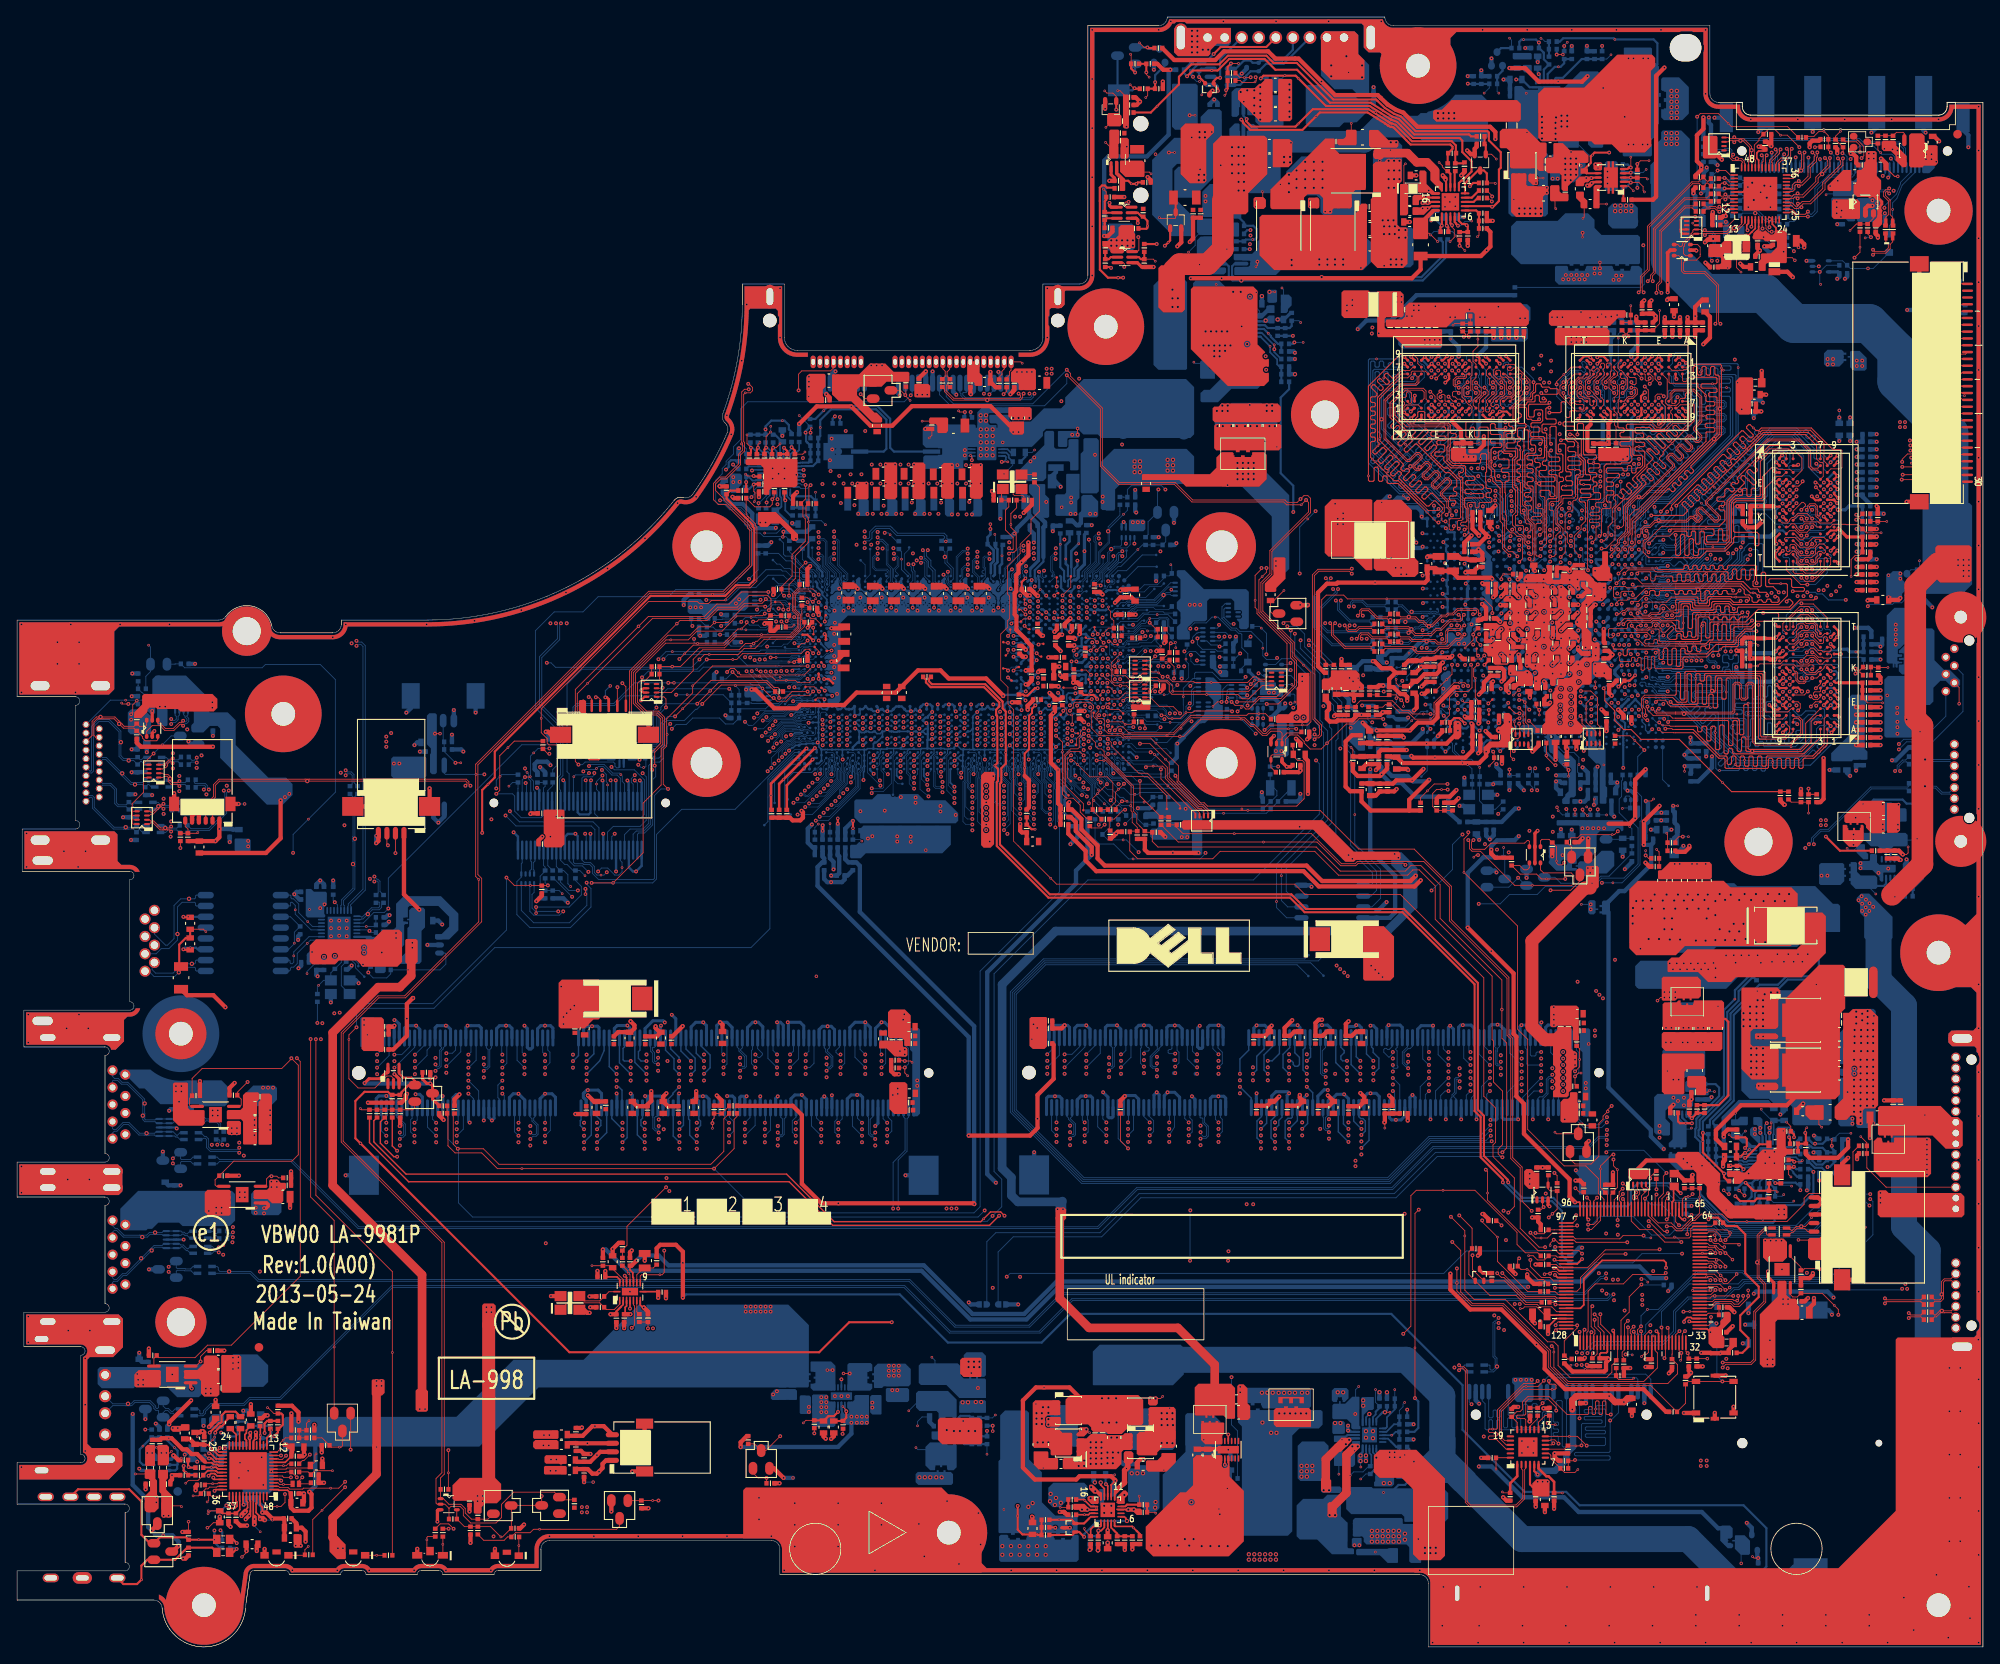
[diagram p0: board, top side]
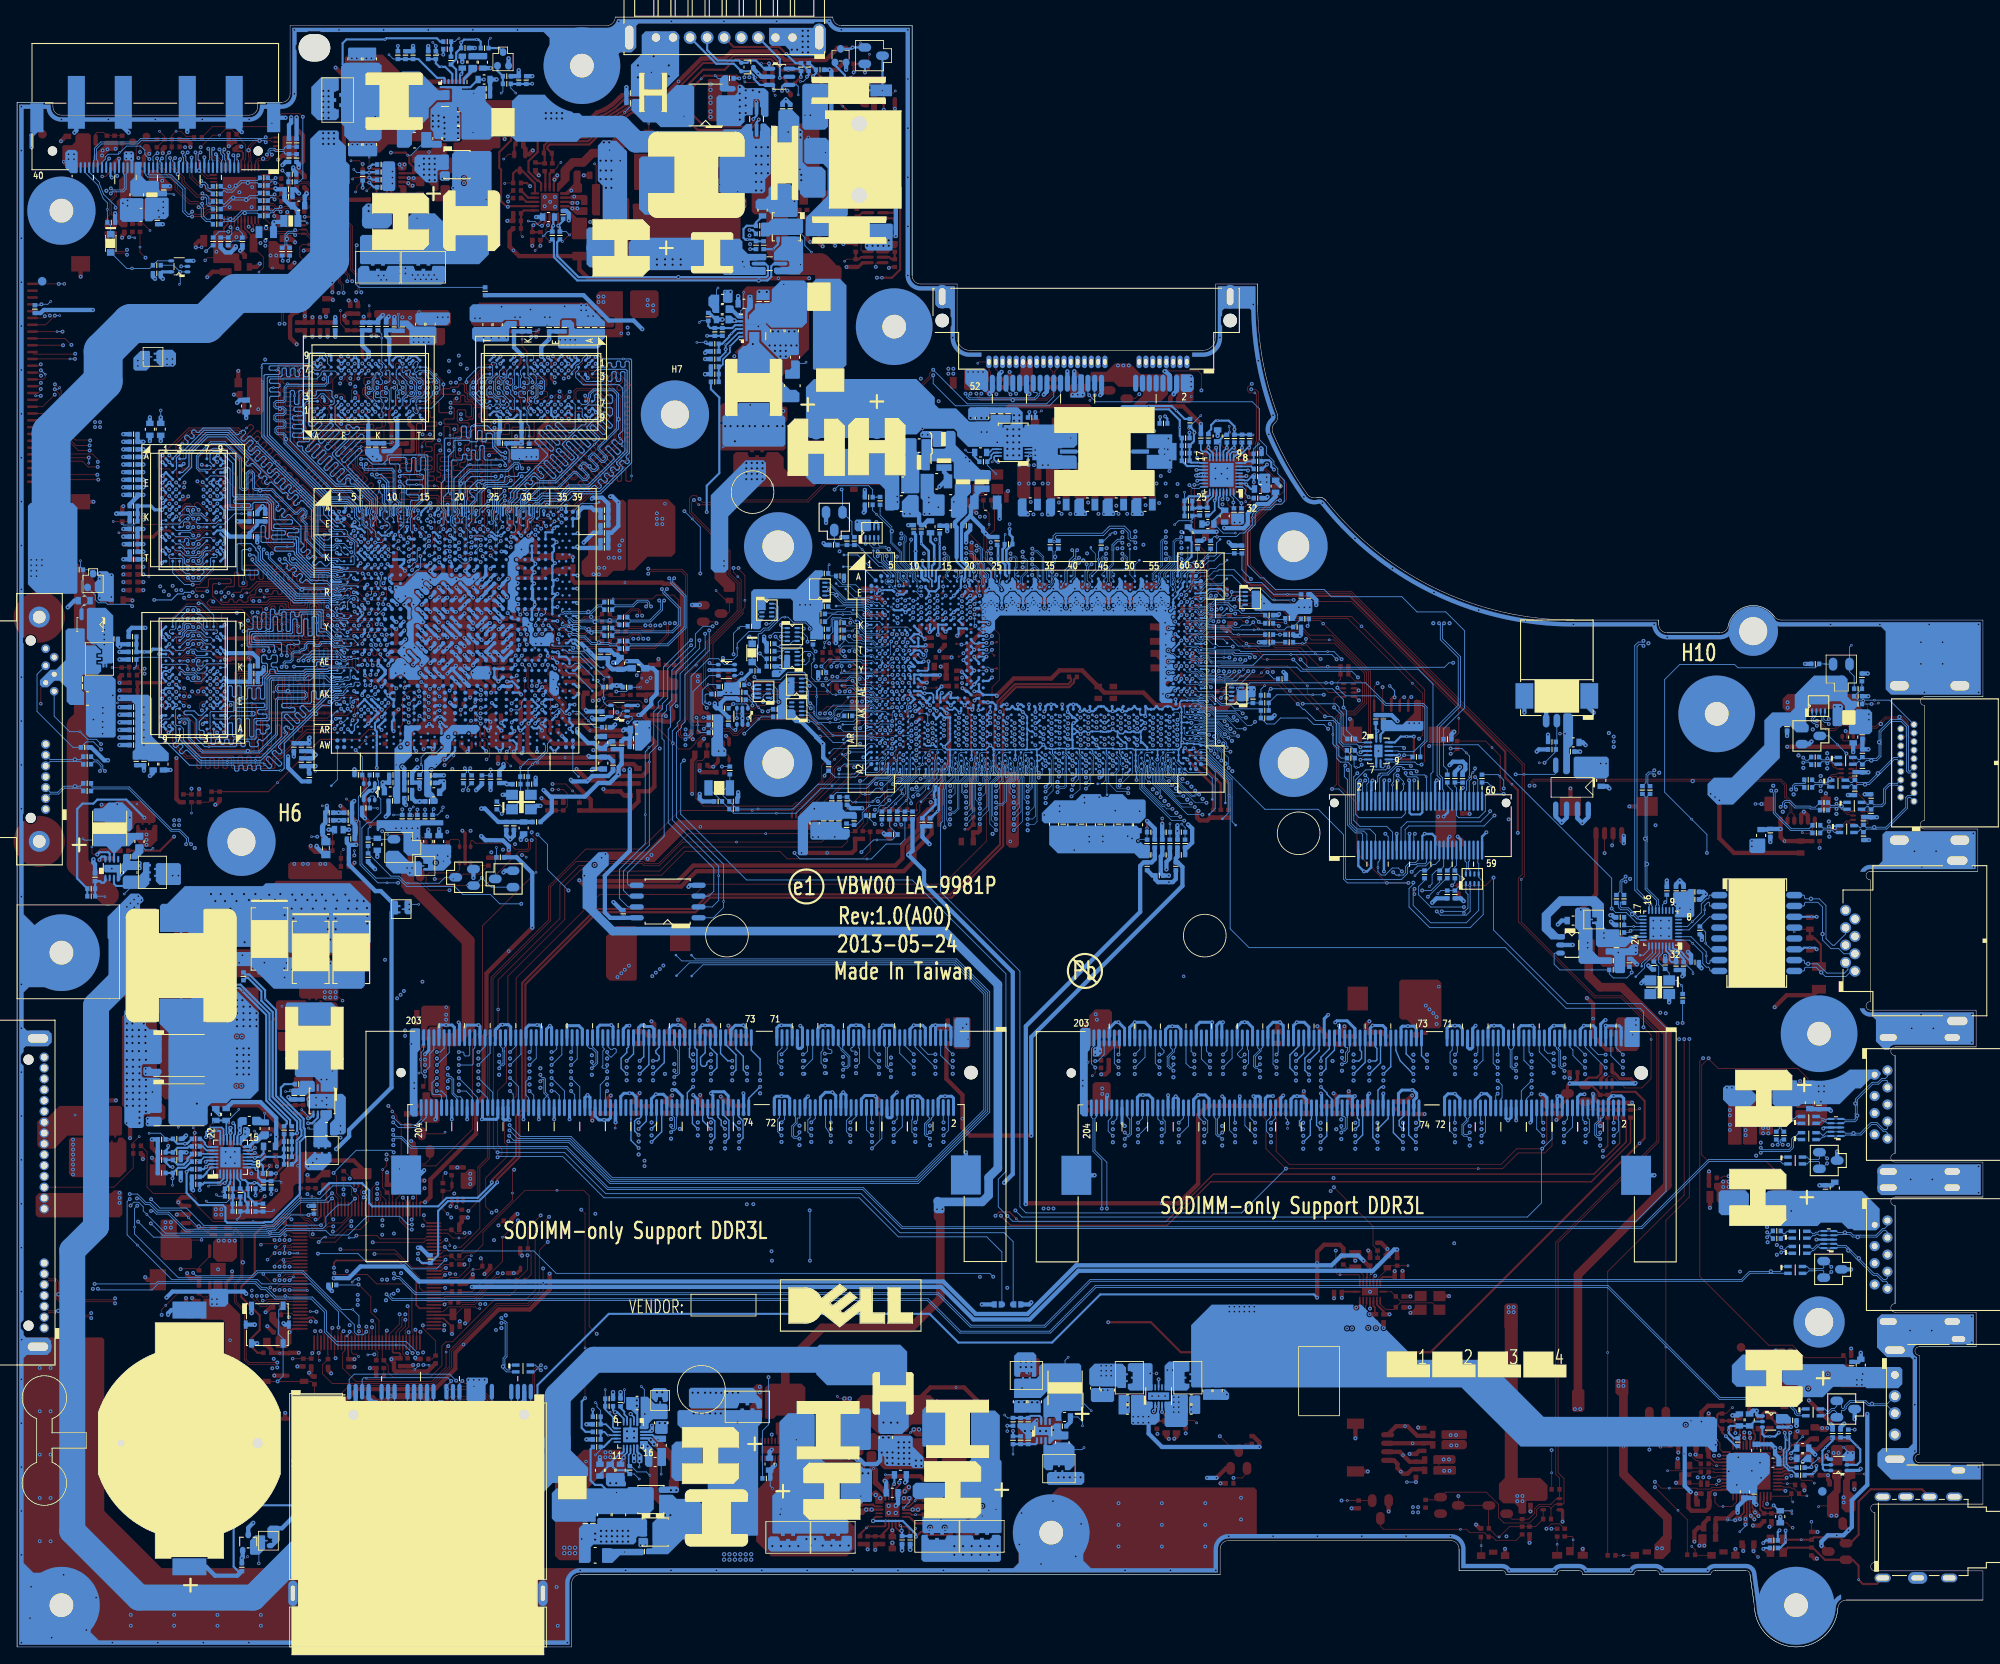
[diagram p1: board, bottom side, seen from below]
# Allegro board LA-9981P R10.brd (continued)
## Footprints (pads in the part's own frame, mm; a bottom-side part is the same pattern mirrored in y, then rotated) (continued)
LED_12-21C-T3D-CM2P1B18X-2C_3P
  rect 0.991x0.787 smd: 1(0,0) 2(-2.8,0)
  rect 0.991x0.61 smd: 3(-1.4,0.4)
LED_HT-210UD5-BP5_3P
  rect 1.194x0.787 smd: 1(0,0) 2(3,0)
  rect 0.889x0.991 smd: 3(1.5,0.5)
LOTES_AAA-BAT-054-K01_2P
  round 0.787 hole 0.787 unplated: (-14.5,-8)
  round 1.194 hole 1.194 unplated: (-14.5,8)
  rect 2.007x3.988 smd: 1(0,0) 2(-30.1,0)
LOTES_ABA-HDM-022-K01_19P
  round 0.813 hole 0.559: 1(0,0) 2(-0.5,-1.55) 3(-1,0) 4(-1.5,-1.55) 5(-2,0) 6(-2.5,-1.55) 7(-3,0) 8(-3.5,-1.55) 9(-4,0) 10(-4.5,-1.55) 11(-5,0) 12(-5.5,-1.55) 13(-6,0) 14(-6.5,-1.55) 15(-7,0) 16(-7.5,-1.55) 17(-8,0) 18(-8.5,-1.55) 19(-9,0)
  oval 1.702x2.794 hole 1.092x2.21: 20(4.55,5.38) 21(4.55,-1.72) 22(-13.55,-1.72) 23(-13.55,5.38)
MAG_MMD-12CE-R36M-M1L_2P
  rect 2.946x4.953 smd: 1(0,0) 2(10.815,0)
MC74VHC1G08DFT2G_SC70-5
  oval 0.381x0.711 smd: 1(0,0) 2(0.65,0) 3(1.3,0) 4(1.3,1.9) 5(0,1.9)
MDU1511RH_POWERDFN56-8-5
  oval 0.61x1.27 smd: 1(0,0) 2(1.27,0) 3(2.54,0) 4(3.81,0)
  custom 1.105x1.105 smd: 5(1.905,3.715)
MDU1516URH_POWERDFN56-8-5
  oval 0.61x1.27 smd: 1(0,0) 2(1.27,0) 3(2.54,0) 4(3.81,0)
  custom 1.105x1.105 smd: 5(1.905,3.715)
MMBT3904_NL_SOT23-3
  oval 1.016x1.524 smd: 1(0,0) 2(0.965,2.083) 3(-0.965,2.083)
MURAT_BLM15BB221SN1D_2P
  rect 0.508x0.762 smd: 1(0,0) 2(0.75,0)
MURAT_DLW21SN670HQ2L_4P
  rect 0.889x0.406 smd: 1(0,0) 2(1.7,0) 3(1.7,0.8) 4(0,0.8)
MURAT_LQM2MPN2R2NG0L_2P
  rect 0.787x1.803 smd: 1(0,0) 2(1.6,0)
PANAS_ETQP3W2R2WFN_2P
  rect 2.159x3.505 smd: 1(0,0) 2(-5.85,0)
PS_HPF10052-06M000R_6P
  oval 0.305x1.499 smd: 1(0,0) 2(1,0) 3(2,0) 4(3,0) 5(4,0) 6(5,0)
  rect 2.489x1.905 smd: 7(7.65,-3.4) 8(-2.65,-3.4)
R0402_0OHM
  rect 0.508x0.559 smd: 1(0,0) 2(0.914,0)
R0603_0OHM
  rect 0.635x0.889 smd: 1(0,0) 2(1.397,0)
R0805_0OHM
  rect 0.813x1.397 smd: 1(0,0) 2(1.702,0)
R_0402
  rect 0.508x0.559 smd: 1(0,0) 2(0.914,0)
R_0603
  rect 0.635x0.889 smd: 1(0,0) 2(1.397,0)
R_0805
  rect 0.813x1.397 smd: 1(0,0) 2(1.702,0)
R_1206
  rect 1.016x1.651 smd: 1(0,0) 2(2.667,0)
R_1206_4P-D
  custom 0.445x0.445 smd: 1(0,0) 4(5.004,0)
  custom 0.114x0.114 smd: 2(1.194,0) 3(3.81,0)
RB751V-40_SOD323-2
  rect 0.787x0.889 smd: 1(0,0) 2(2.14,0)
RHU002N06_SOT323-3
  oval 0.813x0.914 smd: 1(0,0) 2(0.65,1.6) 3(-0.65,1.6)
RP_0804_8P4R
  oval 0.66x0.254 smd: 1(0,0) 2(0,-0.5) 3(0,-1) 4(0,-1.5) 5(1.15,-1.5) 6(1.15,-1) 7(1.15,-0.5) 8(1.15,0)
RT8207MZQW_WQFN20_3X3
  oval 0.203x0.889 smd: 1(0,0) 2(0.4,0) 3(0.8,0) 4(1.2,0) 5(1.6,0) 11(1.6,3.1) 12(1.2,3.1) 13(0.8,3.1) 14(0.4,3.1) 15(0,3.1)
  oval 0.889x0.203 smd: 6(2.35,0.75) 7(2.35,1.15) 8(2.35,1.55) 9(2.35,1.95) 10(2.35,2.35) 16(-0.75,2.35) 17(-0.75,1.95) 18(-0.75,1.55) 19(-0.75,1.15) 20(-0.75,0.75)
  rect 1.702x1.702 smd: 21(0.8,1.55)
RTD2136R-CG_QFN48_6X6
  oval 0.203x0.889 smd: 1(0,0) 2(0.4,0) 3(0.8,0) 4(1.2,0) 5(1.6,0) 6(2,0) 7(2.4,0) 8(2.8,0) 9(3.2,0) 10(3.6,0) 11(4,0) 12(4.4,0) 25(4.4,6.1) 26(4,6.1) 27(3.6,6.1) 28(3.2,6.1) 29(2.8,6.1) 30(2.4,6.1) 31(2,6.1) 32(1.6,6.1) 33(1.2,6.1) 34(0.8,6.1) 35(0.4,6.1) 36(0,6.1)
  oval 0.889x0.203 smd: 13(5.25,0.85) 14(5.25,1.25) 15(5.25,1.65) 16(5.25,2.05) 17(5.25,2.45) 18(5.25,2.85) 19(5.25,3.25) 20(5.25,3.65) 21(5.25,4.05) 22(5.25,4.45) 23(5.25,4.85) 24(5.25,5.25) 37(-0.85,5.25) 38(-0.85,4.85) 39(-0.85,4.45) 40(-0.85,4.05) 41(-0.85,3.65) 42(-0.85,3.25) 43(-0.85,2.85) 44(-0.85,2.45) 45(-0.85,2.05) 46(-0.85,1.65) 47(-0.85,1.25) 48(-0.85,0.85)
  rect 3.962x3.962 smd: 49(2.2,3.05)
RTL8106E-CG_QFN32_4X4
  oval 0.203x0.838 smd: 1(0,0) 2(0.4,0) 3(0.8,0) 4(1.2,0) 5(1.6,0) 6(2,0) 7(2.4,0) 8(2.8,0) 17(2.8,4.15) 18(2.4,4.15) 19(2,4.15) 20(1.6,4.15) 21(1.2,4.15) 22(0.8,4.15) 23(0.4,4.15) 24(0,4.15)
  oval 0.838x0.203 smd: 9(3.475,0.675) 10(3.475,1.075) 11(3.475,1.475) 12(3.475,1.875) 13(3.475,2.275) 14(3.475,2.675) 15(3.475,3.075) 16(3.475,3.475) 25(-0.675,3.475) 26(-0.675,3.075) 27(-0.675,2.675) 28(-0.675,2.275) 29(-0.675,1.875) 30(-0.675,1.475) 31(-0.675,1.075) 32(-0.675,0.675)
  rect 2.692x2.692 smd: 33(1.4,2.075)
RTS5179-GR_QFN24_4X4
  oval 0.254x0.889 smd: 1(0,0) 2(0.5,0) 3(1,0) 4(1.5,0) 5(2,0) 6(2.5,0) 13(2.5,4.1) 14(2,4.1) 15(1.5,4.1) 16(1,4.1) 17(0.5,4.1) 18(0,4.1)
  oval 0.889x0.254 smd: 7(3.3,0.8) 8(3.3,1.3) 9(3.3,1.8) 10(3.3,2.3) 11(3.3,2.8) 12(3.3,3.3) 19(-0.8,3.3) 20(-0.8,2.8) 21(-0.8,2.3) 22(-0.8,1.8) 23(-0.8,1.3) 24(-0.8,0.8)
  rect 2.261x2.261 smd: 25(1.25,2.05)
SAMTE_BSH-030-01-L-D-A_60P
  round 1.016 hole 1.016 unplated: (-2.81,5.53) (17.316,5.53)
  oval 0.279x2.261 smd: 1(0,0) 2(0,5.728) 3(0.5,0) 4(0.5,5.728) 5(1,0) 6(1,5.728) 7(1.5,0) 8(1.5,5.728) 9(2,0) 10(2,5.728) 11(2.5,0) 12(2.5,5.728) 13(3,0) 14(3,5.728) 15(3.5,0) 16(3.5,5.728) 17(4,0) 18(4,5.728) 19(4.5,0) 20(4.5,5.728) 21(5,0) 22(5,5.728) 23(5.5,0) 24(5.5,5.728) 25(6,0) 26(6,5.728) 27(6.5,0) 28(6.5,5.728) 29(7,0) 30(7,5.728) 31(7.5,0) 32(7.5,5.728) 33(8,0) 34(8,5.728) 35(8.5,0) 36(8.5,5.728) 37(9,0) 38(9,5.728) 39(9.5,0) 40(9.5,5.728) 41(10,0) 42(10,5.728) 43(10.5,0) 44(10.5,5.728) 45(11,0) 46(11,5.728) 47(11.5,0) 48(11.5,5.728) 49(12,0) 50(12,5.728) 51(12.5,0) 52(12.5,5.728) 53(13,0) 54(13,5.728) 55(13.5,0) 56(13.5,5.728) 57(14,0) 58(14,5.728) 59(14.5,0) 60(14.5,5.728)
SANTA_130456-311_8P
  round 1.295 hole 0.889: 1(0,0) 2(1.02,1.1) 3(2.04,0) 4(3.06,1.1) 5(4.08,0) 6(5.1,1.1) 7(6.12,0) 8(7.14,1.1)
  oval 1.753x3.15 hole 0.991x2.388: 9(-5.83,-12) 10(12.97,-12)
SANTA_193202-1_22P
  round 1.194 hole 1.194 unplated: (-31.47,-1.84) (-0.28,-1.84)
  round 1.092 hole 0.787: 1(0,0) 2(-1.27,0) 3(-2.54,0) 4(-3.81,0) 5(-5.08,0) 6(-6.35,0) 7(-7.62,0) 8(-13.97,0) 9(-15.24,0) 10(-16.51,0) 11(-17.78,0) 12(-19.05,0) 13(-20.32,0) 14(-21.59,0) 15(-22.86,0) 16(-24.13,0) 17(-25.4,0) 18(-26.67,0) 19(-27.94,0) 20(-29.21,0) 21(-30.48,0) 22(-31.75,0)
  oval 1.803x3.2 hole 0.991x2.388: 23(2.2,-0.73) 24(-33.95,-0.73)
SANTA_202801-1_13P
  round 1.194 hole 1.194 unplated: (-19.78,-1.75) (1.02,-1.75)
  round 1.067 hole 0.711: 1(0,0) 2(-1.27,0) 3(-2.54,0) 4(-3.81,0) 5(-5.08,0) 6(-6.35,0) 7(-7.62,0)
  round 1.016 hole 0.61: 8(-13.83,1) 9(-14.83,0) 10(-15.83,1) 11(-16.83,0) 12(-17.83,1) 13(-18.83,0)
  custom 1.499x1.499 hole 2.311: 14(3.77,-0.75) 15(-22.53,-0.75)
SHORTPADS
  custom 0.19x0.19 smd: 1(-0.483,0) 2(0.483,0)
SI3456BDV-T1-E3_TSOP6
  oval 0.508x1.448 smd: 1(0,0) 2(1,0) 3(2,0) 4(2,2.425) 5(1,2.425) 6(0,2.425)
SI3457CDV-T1-GE3_TSOP6
  oval 0.508x1.422 smd: 1(0,0) 2(0.95,0) 3(1.9,0) 4(1.9,2.44) 5(0.95,2.44) 6(0,2.44)
SINGA_2SJ3080-000111F_6P-T
  oval 1.016x1.905 hole 0.61x1.499: 1(0,0) 2(-9.51,5.49) 3(0,7.8) 4(-9.51,8.39) 5(-9.51,0) 6(-9.51,2.74)
  oval 1.372x2.261 hole 0.61x1.499: 7(0,4.1)
SIR472DP-T1-GE3_POWERPAK8-5
  oval 0.61x1.27 smd: 1(0,0) 2(1.27,0) 3(2.54,0) 4(3.81,0)
  custom 1.105x1.105 smd: 5(1.905,3.36)
SIR818DP-T1_POWERPAK-SO8-5
  oval 0.61x1.27 smd: 1(0,0) 2(1.27,0) 3(2.54,0) 4(3.81,0)
  custom 1.105x1.105 smd: 5(1.905,3.715)
SIS412DN-T1-GE3_POWERPAK8-5
  oval 0.406x0.991 smd: 1(0,0) 2(0.66,0) 3(1.32,0) 4(1.98,0)
  custom 0.559x0.559 smd: 5(0.99,2.247)
SLG3NB274VTR_TQFN16_2X3
  oval 0.203x0.914 smd: 1(0,-0.013) 2(0.4,-0.013) 3(0.8,-0.013) 4(1.2,-0.013) 5(1.6,-0.013) 6(2,-0.013) 7(2.4,-0.013) 9(2.4,2.063) 10(2,2.063) 11(1.6,2.063) 12(1.2,2.063) 13(0.8,2.063) 14(0.4,2.063) 15(0,2.063)
  oval 0.914x0.203 smd: 8(2.738,1.025) 16(-0.338,1.025)
  rect 1.905x0.889 smd: 17(1.2,1.025)
SN74LVC1G06DCKR_SC70-5
  oval 0.381x0.864 smd: 1(0,0) 2(0.65,0) 3(1.3,0) 4(1.3,1.74) 5(0,1.74)
SSM3K7002FU_SC70-3
  oval 0.508x0.991 smd: 1(0,0) 2(0.65,1.9) 3(-0.65,1.9)
STARC_107K40-000001-G2_40P
  round 1.092 hole 1.092 unplated: (-2.3,-1.95) (21.8,-1.95)
  oval 0.254x1.295 smd: 1(0,0) 2(0.5,0) 3(1,0) 4(1.5,0) 5(2,0) 6(2.5,0) 7(3,0) 8(3.5,0) 9(4,0) 10(4.5,0) 11(5,0) 12(5.5,0) 13(6,0) 14(6.5,0) 15(7,0) 16(7.5,0) 17(8,0) 18(8.5,0) 19(9,0) 20(9.5,0) 21(10,0) 22(10.5,0) 23(11,0) 24(11.5,0) 25(12,0) 26(12.5,0) 27(13,0) 28(13.5,0) 29(14,0) 30(14.5,0) 31(15,0) 32(15.5,0) 33(16,0) 34(16.5,0) 35(17,0) 36(17.5,0) 37(18,0) 38(18.5,0) 39(19,0) 40(19.5,0)
  rect 1.549x3.404 smd: 41(-4.125,-5.85) 42(23.625,-5.85)
  rect 2.007x6.198 smd: 43(0.5,-7.65) 44(6,-7.65) 45(13.5,-7.65) 46(19,-7.65)
SUYIN_200028MR009G502ZL_9P
  round 1.499 hole 0.991: 1(0,0) 2(2,0) 3(4,0) 4(6,0) 5(8,0) 6(10,0) 7(12,0) 8(14,0) 9(16,0)
  oval 1.499x3.302 hole 0.991x2.794: 10(19.125,0) 11(-3.125,0)
SW_SMT1-05-A_4P
  rect 0.61x0.991 smd: 1(0,0) 2(0,-4.4) 3(3.7,0) 4(3.7,-4.4)
  rect 0.457x0.991 smd: 5(-0.675,-2.2) 6(4.375,-2.2)
SY8003DFC_DFN8_2X2
  oval 0.254x0.787 smd: 1(0,0) 2(0.5,0) 3(1,0) 4(1.5,0) 5(1.5,2.2) 6(1,2.2) 7(0.5,2.2) 8(0,2.2)
  rect 1.549x0.838 smd: 9(0.75,1.1)
SY8036DBC_DFN10_3X3
  oval 0.254x0.889 smd: 1(0,0) 2(0.5,0) 3(1,0) 4(1.5,0) 5(2,0) 6(2,3.1) 7(1.5,3.1) 8(1,3.1) 9(0.5,3.1) 10(0,3.1)
  rect 2.388x1.575 smd: 11(1,1.55)
SY8206DQNC_QFN10_3X3
  oval 0.254x0.61 smd: 1(0,0) 2(0.45,0) 3(0.9,0) 4(1.35,0) 5(1.8,0) 6(2.25,0)
  rect 1.168x0.254 smd: 7(2.19,-0.675)
  rect 0.914x2.007 smd: 8(2.065,-2)
  custom 0.482x0.482 smd: 9(1.077,-1.775)
  rect 0.813x1.168 smd: 10(0.137,-1.587)
T-SOL_143-2300302602_22P_RV
  round 1.194 hole 1.194 unplated: (0.5,-2.69) (20.5,-2.69)
  oval 0.508x1.854 smd: 1(0,0) 2(0.76,0) 3(1.52,0) 4(2.28,0) 5(3.8,0) 6(4.56,0) 7(5.32,0) 8(6.84,0) 9(7.6,0) 10(8.36,0) 11(9.12,0) 12(9.88,0) 13(11.4,0) 14(12.16,0) 15(12.92,0) 16(14.44,0) 17(15.2,0) 18(16.72,0) 19(19,0) 20(19.76,0) 21(20.52,0) 22(21.28,0)
  oval 1.092x2.997 hole 0.508x1.803: 23(-6.6,-23.63) 24(22.7,-23.63)
TAI-T_HCB2012KF-121T50_2P
  rect 0.991x0.991 smd: 1(0,0) 2(2,0)
TAI-T_VMPI0703AR-1R0M-Z01_2P
  rect 2.362x3.505 smd: 1(0,0) 2(6.05,0)
TAIYO_NRS4018T1R0NDGJ_2P
  rect 1.194x3.708 smd: 1(0,0) 2(2.8,0)
TOKO_FDUE1040J-H-R36M-P3_4P
  custom 0.876x0.876 smd: 1(0,0) 4(13.411,0)
  rect 2.032x0.508 smd: 2(2.489,0) 3(10.922,0)
TOKO_FDVE1040-H-2R2M-P3_2P
  rect 3.81x3.988 smd: 1(0,0) 2(9.2,0)
TPC12
  round 0.305 smd: 1(0,0)
TPS22966DPUR_SON14_2X3
  oval 0.203x0.762 smd: 1(0,0) 2(0.4,0) 3(0.8,0) 4(1.2,0) 5(1.6,0) 6(2,0) 7(2.4,0) 8(2.4,2.05) 9(2,2.05) 10(1.6,2.05) 11(1.2,2.05) 12(0.8,2.05) 13(0.4,2.05) 14(0,2.05)
  rect 2.489x0.889 smd: 15(1.2,1.025)
TPS51212DSCR_SON10_3X3
  oval 0.279x0.838 smd: 1(0,0) 2(0.5,0) 3(1,0) 4(1.5,0) 5(2,0) 6(2,2.95) 7(1.5,2.95) 8(1,2.95) 9(0.5,2.95) 10(0,2.95)
  custom 0.412x0.412 smd: 11(1,1.475)
TPS51225CRUKR_QFN20_3X3
  oval 0.203x0.889 smd: 1(0,0) 2(0.4,0) 3(0.8,0) 4(1.2,0) 5(1.6,0) 11(1.6,3.1) 12(1.2,3.1) 13(0.8,3.1) 14(0.4,3.1) 15(0,3.1)
  oval 0.889x0.203 smd: 6(2.35,0.75) 7(2.35,1.15) 8(2.35,1.55) 9(2.35,1.95) 10(2.35,2.35) 16(-0.75,2.35) 17(-0.75,1.95) 18(-0.75,1.55) 19(-0.75,1.15) 20(-0.75,0.75)
  rect 1.702x1.702 smd: 21(0.8,1.55)
TPS51622RSM_QFN32_4X4
  oval 0.203x0.914 smd: 1(0,0) 2(0.4,0) 3(0.8,0) 4(1.2,0) 5(1.6,0) 6(2,0) 7(2.4,0) 8(2.8,0) 17(2.8,4.077) 18(2.4,4.077) 19(2,4.077) 20(1.6,4.077) 21(1.2,4.077) 22(0.8,4.077) 23(0.4,4.077) 24(0,4.077)
  oval 0.914x0.203 smd: 9(3.438,0.639) 10(3.438,1.039) 11(3.438,1.438) 12(3.438,1.838) 13(3.438,2.239) 14(3.438,2.639) 15(3.438,3.039) 16(3.438,3.438) 25(-0.639,3.438) 26(-0.639,3.039) 27(-0.639,2.639) 28(-0.639,2.239) 29(-0.639,1.838) 30(-0.639,1.438) 31(-0.639,1.039) 32(-0.639,0.639)
  rect 2.794x2.794 smd: 33(1.4,2.039)
TVNST52302AB0_SOT523-3
  oval 0.508x0.559 smd: 1(0,0) 2(-0.5,-1.4) 3(0.5,-1.4)
VISHAY_IHLP-2525CZ-01_2P
  rect 2.54x3.556 smd: 1(-2.857,0) 2(2.857,0)
W25Q64FVSSIG_SO8
  oval 0.635x1.676 smd: 1(0,0) 2(1.27,0) 3(2.54,0) 4(3.81,0) 5(3.81,7.25) 6(2.54,7.25) 7(1.27,7.25) 8(0,7.25)
Y_7V27000011_4P
  rect 1.397x1.194 smd: 1(0,0) 2(2.2,0) 3(2.2,1.7) 4(0,1.7)
Y_FSX3M-25PM20FDO_4P
  rect 1.397x1.194 smd: 1(0,0) 2(2.2,0) 3(2.2,1.6) 4(0,1.6)
Y_Q13FC1350000_2P
  rect 0.991x1.803 smd: 1(0,0) 2(2.5,0)
Y_X3G024000DC1H_4P
  rect 1.397x1.194 smd: 1(0,0) 2(2.2,0) 3(2.2,1.7) 4(0,1.7)

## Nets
0.675V_DDR_VTT_ON: PR202.1 QD2.2 R2347.2 R2351.2 U2303.4
1.35V_B+: PC201.1 PC206.1 PC208.1 PC212.1 PL201.2 PQ200.5 PR208.1
3/5V_B+: PC105.1 PC112.1 PC113.1 PC114.1 PC115.1 PL102.2 PQ101.5 PQ103.5 PU100.12
3V_EN: PD101.2 PR100.1 PU100.6
3VALW_PCH: J513.2 U2304.13 U2304.14
3VS: J511.2 U2301.8 U2301.9
3VS_GATE: C2322.1 R2318.2 U2301.5
5V_EN: PD101.3 PR101.1 PU100.20
5VS: J510.2 U2301.13 U2301.14
5VS_GATE: C2309.1 R2313.2 U2301.3
+0.675VS: CD24.1 CD25.1 CD26.1 CD27.1 CD28.1 CD29.1 CD54.1 CD55.1 CD56.1 CD57.1 CD58.1 CD59.1 JDIMM1.203 JDIMM1.204 JDIMM2.203 JDIMM2.204 PJP203.1 R2314.1
+0.675VSP: PC205.1 PC211.1 PJP203.2 PU200.2 PU200.20
+1.2VSP_B+: PC1100.1 PC1101.1 PC1102.1 PL1100.1 PQ1100.5
+1.05V_PGOOD: PR308.2 PU300.2 UE1.122
+1.05VS: C43.1 C44.1 C50.1 C53.1 C57.1 C60.1 C61.1 C62.1 C66.1 C67.1 C76.1 C87.1 C88.1 CC14.1 CC15.1 CC28.1 CG2.1 JXDP1.43 JXDP1.44 L1.1 L2.1 L3.1 L4.1 L5.1 PC512.1 PJP300.2 PR526.1 PR528.1 PR530.1 PR533.2 R252.1 R253.2 R256.1 R267.1 R286.1 R2315.1 R2346.1 RC58.1 RC60.1 RC130.2 RP44.5 RP44.6 RP44.7 RP44.8 RP45.8 RP48.1 RP48.2 RP48.3 UC1.AC22 UC1.AE8 UC1.AE9 UC1.AE22 UC1.AE23 UC1.AF9 UC1.AF22 UC1.AG8 UC1.AG13 UC1.AG14 UC1.AG16 UC1.AG17 UC1.H11 UC1.H15 UC1.J11 UC1.J17 UC1.K9 UC1.L10 UC1.M9 UC1.N8 UC1.P9 UC1.R21 UC1.T21 UG1.3
+1.5VS: JMINI.6 JMINI.28 JMINI.48 PJP401.2 RA8.1 RC129.1 UC1.J15
+1.05VS_APLLOPI: C69.1 C70.1 L3.2 R267.2 UC1.AA21 UC1.W21
+1.05VS_ASATA3PLL: C63.1 C65.1 L2.2 RC126.2 RC131.2 UC1.B11
+1.05VS_AUSB3PLL: C58.1 C59.1 L1.2 RC91.1 UC1.B18 UC1.B27
+1.05VS_AXCK_DCB: C83.1 C84.1 L4.2 UC1.J18 UC1.K19
+1.05VS_AXCK_LCPLL: C85.1 C86.1 L5.2 RC13.2 UC1.A20
+1.05VSP: PC307.1 PC308.1 PC309.1 PC310.1 PC311.1 PJP300.1 PL301.2 PR305.1
+1.5VSP: PC400.1 PC402.1 PC404.1 PJP401.1 PL400.2 PR403.1
+1.5VSP_ON: PC403.1 PR401.1 PR404.1 PU400.7
+1.8VGS: CG1.1 J9.1 LV12.2 LV13.2 LV14.2 LV16.1 LV17.1 LV18.1 LV19.1 LV20.1 LV21.1 LV22.1 RV93.2 RV118.2 RV119.1 RV124.1 RV237.1 RV239.1 RV241.1 RV243.1 UG1.11
+1.8VS: J9.2 PJP601.2
+1.8VSP: PC600.1 PC602.1 PC604.1 PJP601.1 PL600.2 PR603.1
+1.8VSP_ON: PC603.1 PR601.1 PR604.1 PU600.7
+1.35V: C35.1 C36.1 C37.1 C38.1 C39.1 C40.2 C41.1 C42.1 C43.2 C45.1 C72.1 C74.1 CD4.1 CD5.1 CD6.1 CD7.1 CD8.1 CD9.1 CD10.1 CD11.1 CD12.1 CD13.1 CD14.1 CD15.1 CD16.1 CD17.1 CD18.1 CD19.1 CD20.1 CD23.1 CD35.1 CD36.1 CD37.1 CD38.1 CD39.1 CD40.1 CD41.1 CD42.1 CD43.1 CD44.1 CD45.1 CD46.1 CD47.1 CD48.1 CD49.1 CD50.1 CD51.1 CD62.2 JDIMM1.75 JDIMM1.76 JDIMM1.81 JDIMM1.82 JDIMM1.87 JDIMM1.88 JDIMM1.93 JDIMM1.94 JDIMM1.99 JDIMM1.100 JDIMM1.105 JDIMM1.106 JDIMM1.111 JDIMM1.112 JDIMM1.117 JDIMM1.118 JDIMM1.123 JDIMM1.124 JDIMM2.75 JDIMM2.76 JDIMM2.81 JDIMM2.82 JDIMM2.87 JDIMM2.88 JDIMM2.93 JDIMM2.94 JDIMM2.99 JDIMM2.100 JDIMM2.105 JDIMM2.106 JDIMM2.111 JDIMM2.112 JDIMM2.117 JDIMM2.118 JDIMM2.123 JDIMM2.124 PJP200.2 PJP201.2 QD2.1 RC14.1 RC15.1 RC16.1 RD3.1 U2303.5 UC1.AH26 UC1.AJ31 UC1.AJ33 UC1.AJ37 UC1.AN33 UC1.AP43 UC1.AR48 UC1.AY35 UC1.AY40 UC1.AY44 UC1.AY50
+1.35V_MEM_GFX: CV135.1 CV136.1 CV137.1 CV138.1 CV139.1 CV140.1 CV141.1 CV142.1 CV143.1 CV144.1 CV145.1 CV152.1 CV153.1 CV154.1 CV155.1 CV156.1 CV235.1 CV236.1 CV237.1 CV238.1 CV239.1 CV240.1 CV241.1 CV242.1 CV243.1 CV244.1 CV245.1 CV246.1 CV247.1 CV248.1 CV249.1 CV250.1 CV251.1 CV252.1 CV253.1 CV254.1 CV255.1 CV256.1 CV257.1 CV258.1 CV259.1 CV260.1 CV261.1 CV262.1 CV263.1 CV264.1 CV265.1 CV266.1 CV267.1 CV268.1 CV269.1 CV270.1 CV271.1 CV282.1 CV283.1 CV284.1 CV285.1 CV286.1 CV287.1 CV288.1 CV289.1 CV290.1 CV291.1 CV292.1 CV293.1 CV294.1 CV295.1 CV296.1 CV297.1 CV298.1 CV299.1 CV300.1 CV301.1 CV302.1 CV303.1 CV304.1 CV305.1 CV306.1 CV307.1 CV308.1 CV310.1 CV311.1 CV312.1 CV313.1 CV314.1 CV315.1 CV316.1 CV317.1 CV318.1 JP9.1 RV138.1 RV139.1 RV140.1 RV141.1 RV142.1 RV156.1 RV157.1 RV158.1 RV159.1 RV160.1 RV161.1 RV162.1 RV163.1 RV182.1 RV183.1 RV184.1 RV185.1 RV186.1 RV187.1 RV188.1 RV189.1 UV1.AC7 UV1.AD11 UV1.AF7 UV1.AG10 UV1.AJ7 UV1.AK8 UV1.AL9 UV1.G11 UV1.G14 UV1.G17 UV1.G20 UV1.G23 UV1.G26 UV1.G29 UV1.H10 UV1.J7 UV1.J9 UV1.K8 UV1.K11 UV1.K13 UV1.L7 UV1.L12 UV1.L16 UV1.L21 UV1.L23 UV1.L26 UV1.M11 UV1.N11 UV1.P7 UV1.R11 UV1.U7 UV1.U11 UV1.Y7 UV1.Y11 UV18.A1 UV18.A8 UV18.B2 UV18.C1 UV18.C9 UV18.D2 UV18.D9 UV18.E9 UV18.F1 UV18.G7 UV18.H2 UV18.H9 UV18.K2 UV18.K8 UV18.N1 UV18.N9 UV18.R1 UV18.R9 UV19.A1 UV19.A8 UV19.B2 UV19.C1 UV19.C9 UV19.D2 UV19.D9 UV19.E9 UV19.F1 UV19.G7 UV19.H2 UV19.H9 UV19.K2 UV19.K8 UV19.N1 UV19.N9 UV19.R1 UV19.R9 UV20.A1 UV20.A8 UV20.B2 UV20.C1 UV20.C9 UV20.D2 UV20.D9 UV20.E9 UV20.F1 UV20.G7 UV20.H2 UV20.H9 UV20.K2 UV20.K8 UV20.N1 UV20.N9 UV20.R1 UV20.R9 UV21.A1 UV21.A8 UV21.B2 UV21.C1 UV21.C9 UV21.D2 UV21.D9 UV21.E9 UV21.F1 UV21.G7 UV21.H2 UV21.H9 UV21.K2 UV21.K8 UV21.N1 UV21.N9 UV21.R1 UV21.R9 UV22.A1 UV22.A8 UV22.B2 UV22.C1 UV22.C9 UV22.D2 UV22.D9 UV22.E9 UV22.F1 UV22.G7 UV22.H2 UV22.H9 UV22.K2 UV22.K8 UV22.N1 UV22.N9 UV22.R1 UV22.R9 UV23.A1 UV23.A8 UV23.B2 UV23.C1 UV23.C9 UV23.D2 UV23.D9 UV23.E9 UV23.F1 UV23.G7 UV23.H2 UV23.H9 UV23.K2 UV23.K8 UV23.N1 UV23.N9 UV23.R1 UV23.R9 UV24.A1 UV24.A8 UV24.B2 UV24.C1 UV24.C9 UV24.D2 UV24.D9 UV24.E9 UV24.F1 UV24.G7 UV24.H2 UV24.H9 UV24.K2 UV24.K8 UV24.N1 UV24.N9 UV24.R1 UV24.R9 UV25.A1 UV25.A8 UV25.B2 UV25.C1 UV25.C9 UV25.D2 UV25.D9 UV25.E9 UV25.F1 UV25.G7 UV25.H2 UV25.H9 UV25.K2 UV25.K8 UV25.N1 UV25.N9 UV25.R1 UV25.R9
+1.35VGPUP: PC1108.1 PJP1100.1 PJP1101.1 PL1101.2 PR1107.2
+1.35VP: PC213.1 PJP200.1 PJP201.1 PL200.1 PR207.2 PU200.5 PU200.19
+1.35VS_VGA: JP9.2 PJP1100.2 PJP1101.2
+3V_WLAN: CM40.1 CM43.1 CM46.2 CM47.1 CM48.2 JMINI.2 JMINI.24 JMINI.39 JMINI.41 JMINI.52 RM25.2 RM26.2
+3VALW: C2311.1 C2313.1 C2316.1 C2318.1 CE1.1 CE2.1 CE5.2 CE6.2 CG10.1 CL38.1 CL39.1 JP3.2 JPWR.1 LE1.1 PC313.1 PC1205.1 PJP100.2 PJP102.2 PJP400.1 PJP600.1 PJP1301.2 PR3.2 PR16.2 PR28.1 PU300.7 PU1200.7 RE3.2 RE8.2 RE11.2 RE71.1 RP36.5 RP36.6 RP36.7 RP36.8 RV109.1 U2301.6 U2301.7 U2304.1 U2304.2 U2304.4 UE1.9 UE1.22 UE1.33 UE1.96 UE1.125 UG1.2 UL2.4 UL2.5
+3VALW_PCH: C75.2 C78.1 C81.1 C2310.1 C2312.1 J513.1 QH1.2 QH1.5 R264.1 R2329.1 R2330.1 RC27.1 RC28.1 RC29.1 RC31.1 RC32.1 RC34.1 RC64.2 RC103.2 RC104.2 RC110.2 RC120.1 RC124.1 RC125.1 RC127.1 RP40.5 RP40.6 RP40.7 RP40.8 RP49.7 RP49.8 RP55.5 RP55.6 RP55.7 RP55.8 UC1.AA9 UC1.AC9 UC1.AE20 UC1.AE21 UC1.AH10
+3VALW_PCH_GATE: C2314.1 R416.2 U2304.3
+3VALWP: PC101.1 PC102.1 PJP100.1 PJP102.1 PL100.2 PR109.1
+3VGS: CV101.1 CV102.1 CV187.1 CV188.1 CV189.1 CV190.1 CV326.2 JP8.1 PR826.1 PR828.1 PR835.1 PR837.1 PR839.1 PR1213.1 QV15.2 QV15.5 QV22.1 QV28.2 RP47.1 RP47.2 RP47.3 RP60.1 RP60.3 RP60.4 RV73.1 RV74.1 RV75.1 RV76.1 RV81.1 RV82.1 RV83.1 RV85.1 RV90.1 RV91.1 RV105.1 RV199.1 RV235.1 UV1.AF23 UV1.AF24 UV1.AG23 UV1.AG24 UV13.5
+3VLP: CG4.1 JP12.1 PC109.1 PU100.3 RE49.2 UE1.111 UG1.15
+3VS: C44.2 C68.1 C71.1 C73.1 C82.1 C2323.1 C2324.1 C2327.1 CA57.1 CA58.1 CA59.1 CA60.1 CC11.1 CC13.1 CD30.1 CD31.1 CD60.1 CD61.1 CD62.1 CD63.1 CE15.1 CM45.1 CR1.1 CR2.1 CX1.1 CX7.1 CX9.1 J511.1 JDIMM1.199 JDIMM2.199 JHDD.8 JHDD.9 JLVDS.26 JP8.2 JTP.1 PR308.1 PR516.1 PR524.1 PR808.1 PR842.2 PR1110.1 PU501.20 PU501.21 QC1.2 QC1.5 QD18.2 QD19.2 QM30.2 QV22.3 QX3.2 QX4.2 QX4.5 QX5.1 R2331.1 R2332.1 R2334.1 R2335.1 RA1.1 RA2.1 RA7.1 RA9.1 RC3.1 RC9.2 RC11.2 RC36.1 RC73.1 RC74.1 RC75.1 RC76.1 RC77.1 RC98.2 RC100.1 RC102.1 RC106.1 RC107.2 RC108.1 RC111.1 RC112.1 RC118.1 RC119.1 RC121.1 RC128.1 RC362.1 RD12.2 RD45.1 RD47.1 RE9.1 RE10.1 RE50.1 RL33.1 RM25.1 RM26.1 RM110.1 RP37.6 RP37.7 RP37.8 RP42.1 RP42.2 RP42.3 RP42.4 RP43.1 RP43.2 RP51.7 RP51.8 RP52.5 RP52.6 RP52.7 RP52.8 RP53.5 RP53.6 RP53.7 RP53.8 RP54.5 RP54.6 RP54.7 RP54.8 RS7.1 RX4.1 RX12.1 RX13.1 RX27.1 RX29.1 U2302.8 UA1.1 UA1.9 UA1.36 UC1.K14 UC1.K16 UC1.T9 UC1.U8 UC1.V8 UC1.W9 UC1.Y8 UC3.5 UC4.14 UD1.5 UE2.5 UR1.4 UX1.4 UX1.5
+3VS_CAM: JLVDS.29 RX27.2
+3VS_RT: CX10.1 LX7.2 LX8.2 QX6.2 QX6.5 RX4.2 RX30.1 RX168.1 RX169.1 UX2.5
+5V_HDD: CS5.1 CS6.1 CS7.1 JHDD.14 JHDD.15 JHDD.16 JP13.1
+5V_PVDD: CA53.1 CA54.1 CA55.1 CA56.1 RV54.2 UA1.41 UA1.46
+5V_USB_PWR1: CI1.1 CI2.1 CI40.1 JUSB1.1 UI3.6 UI3.7 UI3.8
+5V_USB_PWR2: CI8.1 CI9.1 CI43.1 JUSB2.1 UI2.6 UI2.7 UI2.8
+5V_USB_PWR3: CI19.1 CI20.1 CI44.1 JUSB3.1 UI4.6 UI4.7 UI4.8
+5V_USB_PWR4: JDB.1 JDB.2 JDB.3 UI5.6 UI5.7 UI5.8
+5VA: CA51.1 CA71.1 RV59.2 UA1.26
+5VALW: C2305.1 C2306.1 CI6.1 CI7.1 CI12.1 CI14.1 CI18.1 CI21.1 CI22.1 CI23.1 CI27.1 CI30.1 CI31.1 LED1.2 LED3.1 LED4.2 PC204.2 PC1105.1 PJP101.2 PJP103.2 PR8.1 PR206.1 PR814.2 PR822.2 PR824.1 PU200.12 PU1100.7 R10.1 R2347.1 RD46.1 RV107.1 U2301.1 U2301.2 U2301.4 UI2.2 UI2.3 UI3.2 UI3.3 UI4.2 UI4.3 UI5.2 UI5.3
+5VALWP: PC107.1 PC108.2 PJP101.1 PJP103.1 PL101.2 PR104.2 PU100.14
+5VS: C2307.1 C2308.1 CE25.1 CS13.1 FX1.2 J510.1 JP7.1 JP13.2 LED2.2 PC503.1 PR519.1 PU502.2 QS2.1 QS2.2 QS2.5 QS2.6 RE60.1 RV54.1 RV59.1 RX16.2 RX17.2 RX28.1 UE3.1 UE3.2
+5VS_ODD: CS10.1 CS11.1 CS12.1 JODD.9 JODD.10 JP7.2 QS2.4
+5VS_TOUCH: CX6.1 JTOUCH.1 RX24.1 RX28.2 RX29.2
+AVCC33: CX31.1 CX33.1 CX35.1 LX8.1 UX4.5
+AVDD: CV75.1 CV76.1 CV77.1 LV12.1 UV1.AD34
+DVCC33: CX34.1 CX36.1 CX40.1 CX41.1 CX45.1 LX7.1 RP56.5 RP56.6 RP56.7 RP56.8 RP57.7 RP57.8 UX4.18 UX4.22
+V18R: CE16.1 UE1.124
+VCC_3IN1: CR7.1 CR8.1 JREAD.4 JREAD.11 UR1.5
+VCC_PWR_SRC: PC502.2 PC515.1 PC516.1 PC517.1 PC518.1 PC519.1 PC521.1 PL501.1 PR508.1 PU502.5
+VCCHDA: C77.1 RC127.2 RC128.2 RC129.2 UC1.AH14
+VCCIO_OUT: R245.2
+VCCIO_OUT_R: R245.1 UC1.A59
+VCCIOA_OUT: RC71.1 RC78.1 UC1.E20
+VCCRTCEXT: C52.1 UC1.AE7
+VDD1DI: CV78.1 CV79.1 CV80.1 LV13.1 UV1.AC33
+VDD_MEM15_REFDA: CV220.1 RV139.2 RV146.1 UV1.L18
+VDD_MEM15_REFDB: CV223.1 RV141.2 RV148.1 UV1.Y12
+VDD_MEM15_REFSA: CV221.1 RV140.2 RV147.1 UV1.L20
+VDD_MEM15_REFSB: CV224.1 RV142.2 RV149.1 UV1.AA12
+VDDC_CT: CV170.1 CV171.1 CV172.1 CV173.1 CV174.1 LV19.2 UV1.AF26 UV1.AF27 UV1.AG26 UV1.AG27
+VDDCI: CV203.1 CV204.1 CV205.1 CV206.1 CV207.1 CV208.1 CV209.1 CV210.1 CV211.1 CV212.1 CV213.1 CV214.1 CV322.1 CV323.1 CV324.1 CV325.1 LV25.1 LV26.1 PJP1200.2 RV215.1 UV1.AA13 UV1.AB13 UV1.AC12 UV1.AC15 UV1.AD13 UV1.AD16 UV1.M15 UV1.M16 UV1.M18 UV1.M23 UV1.N13 UV1.N15 UV1.N17 UV1.N20 UV1.N22 UV1.R12 UV1.R13 UV1.R16 UV1.T12 UV1.T15 UV1.V15 UV1.Y13
+VDDCIP: PC1201.1 PC1206.1 PC1207.1 PC1211.1 PJP1200.1 PL1200.2 PR1208.1
+VDDR4: CV193.1 CV194.1 LV20.2 UV1.AD12 UV1.AF11 UV1.AF12 UV1.AF13 UV1.AF15 UV1.AG11 UV1.AG13 UV1.AG15
GND: C35.2 C36.2 C37.2 C38.2 C39.2 C41.2 C42.2 C45.2 C50.2 C51.2 C52.2 C53.2 C54.2 C55.2 C56.2 C57.2 C58.2 C59.2 C60.2 C61.2 C62.2 C63.2 C64.2 C65.2 C66.2 C67.2 C68.2 C69.2 C70.2 C71.2 C72.2 C73.2 C74.2 C75.1 C76.2 C77.2 C78.2 C79.2 C80.2 C81.2 C82.2 C83.2 C84.2 C85.2 C86.2 C87.2 C88.2 C2305.2 C2306.2 C2307.2 C2308.2 C2309.2 C2310.2 C2311.2 C2312.2 C2313.2 C2314.2 C2316.2 C2318.2 C2322.2 C2323.2 C2324.2 C2326.2 C2327.2 C5212.2 CA21.2 CA22.2 CA25.1 CA29.2 CA30.2 CA31.2 CA32.2 CA53.2 CA54.2 CA55.2 CA56.2 CA57.2 CA58.2 CA59.2 CA60.2 CA64.1 CA69.2 CA74.2 CC1.1 CC2.1 CC3.1 CC4.1 CC5.2 CC6.1 CC7.1 CC11.2 CC13.2 CC14.2 CC15.2 CC16.2 CC17.2 CC26.2 CC27.2 CC28.2 CC29.2 CC30.2 CC31.2 CC33.2 CC34.2 CC35.2 CD1.2 CD2.2 CD3.2 CD4.2 CD5.2 CD6.2 CD7.2 CD8.2 CD9.2 CD10.2 CD11.2 CD12.2 CD13.2 CD14.2 CD15.2 CD16.2 CD17.2 CD18.2 CD19.2 CD20.2 CD21.2 CD22.2 CD23.2 CD24.2 CD25.2 CD26.2 CD27.2 CD28.2 CD29.2 CD30.2 CD31.2 CD32.2 CD33.2 CD34.2 CD35.2 CD36.2 CD37.2 CD38.2 CD39.2 CD40.2 CD41.2 CD42.2 CD43.2 CD44.2 CD45.2 CD46.2 CD47.2 CD48.2 CD49.2 CD50.2 CD51.2 CD52.2 CD53.2 CD54.2 CD55.2 CD56.2 CD57.2 CD58.2 CD59.2 CD60.2 CD61.2 CD63.2 CD64.2 CE1.2 CE2.2 CE5.1 CE6.1 CE8.2 CE11.2 CE12.2 CE15.2 CE16.2 CE18.1 CE19.2 CE20.2 CE22.2 CE23.2 CE24.2 CE25.2 CE26.2 CE27.2 CE28.2 CE29.2 CE30.2 CE31.2 CE32.2 CE33.2 CE34.2 CE35.2 CE36.2 CG1.2 CG2.2 CG3.2 CG4.2 CG5.2 CG6.2 CG7.2 CG8.2 CG9.2 CG10.2 CG11.2 CI1.2 CI2.2 CI6.2 CI7.2 CI8.2 CI9.2 CI12.2 CI13.2 CI14.2 CI15.2 CI16.2 CI17.2 CI18.2 CI19.2 CI20.2 CI21.2 CI22.2 CI23.2 CI24.2 CI25.2 CI26.2 CI27.2 CI30.2 CI31.2 CI32.2 CI40.2 CI43.2 CI44.2 CL15.2 CL19.2 CL20.2 CL22.2 CL26.2 CL33.2 CL34.2 CL35.2 CL36.1 CL37.1 CL38.2 CL39.2 CL41.1 CM40.2 CM43.2 CM46.1 CM47.2 CM48.1 CMOS1.1 CR1.2 CR2.2 CR3.1 CR4.1 CR5.2 CR6.2 CR7.2 CR8.2 CR9.2 CR10.2 CR11.2 CS5.2 CS6.2 CS7.2 CS10.2 CS11.2 CS12.2 CS13.2 CS16.2 CS17.2 CV75.2 CV76.2 CV77.2 CV78.2 CV79.2 CV80.2 CV81.2 CV82.2 CV83.2 CV84.2 CV86.2 CV87.2 CV88.2 CV91.2 CV92.2 CV93.2 CV94.2 CV95.2 CV97.2 CV101.2 CV102.2 CV103.2 CV108.2 CV109.2 CV110.2 CV111.2 CV112.2 CV113.2 CV114.2 CV115.2 CV116.2 CV117.2 CV118.2 CV119.2 CV120.2 CV121.2 CV122.2 CV123.2 CV124.2 CV125.2 CV126.2 CV127.2 CV128.2 CV129.2 CV130.2 CV131.2 CV132.2 CV133.2 CV134.2 CV135.2 CV136.2 CV137.2 CV138.2 CV139.2 CV140.2 CV141.2 CV142.2 CV143.2 CV144.2 CV145.2 CV146.2 CV147.2 CV148.2 CV149.2 CV150.2 CV151.2 CV152.2 CV153.2 CV154.2 CV155.2 CV156.2 CV170.2 CV171.2 CV172.2 CV173.2 CV174.2 CV187.2 CV188.2 CV189.2 CV190.2 CV193.2 CV194.2 CV195.2 CV196.2 CV197.2 CV198.2 CV199.2 CV200.2 CV201.2 CV202.2 CV203.2 CV204.2 CV205.2 CV206.2 CV207.2 CV208.2 CV209.2 CV210.2 CV211.2 CV212.2 CV213.2 CV214.2 CV215.2 CV216.2 CV217.2 CV220.2 CV221.2 CV222.2 CV223.2 CV224.2 CV225.2 CV226.2 CV227.2 CV228.2 CV229.2 CV230.2 CV231.2 CV232.2 CV233.2 CV234.2 CV235.2 CV236.2 CV237.2 CV238.2 CV239.2 CV240.2 CV241.2 CV242.2 CV243.2 CV244.2 CV245.2 CV246.2 CV247.2 CV248.2 CV249.2 CV250.2 CV251.2 CV252.2 CV253.2 CV254.2 CV255.2 CV256.2 CV257.2 CV258.2 CV259.2 CV260.2 CV261.2 CV262.2 CV263.2 CV264.2 CV265.2 CV266.2 CV267.2 CV268.2 CV269.2 CV270.2 CV271.2 CV272.2 CV273.2 CV274.2 CV275.2 CV276.2 CV277.2 CV278.2 CV279.2 CV280.2 CV281.2 CV282.2 CV283.2 CV284.2 CV285.2 CV286.2 CV287.2 CV288.2 CV289.2 CV290.2 CV291.2 CV292.2 CV293.2 CV294.2 CV295.2 CV296.2 CV297.2 CV298.2 CV299.2 CV300.2 CV301.2 CV302.2 CV303.2 CV304.2 CV305.2 CV306.2 CV307.2 CV308.2 CV310.2 CV311.2 CV312.2 CV313.2 CV314.2 CV315.2 CV316.2 CV317.2 CV318.2 CV322.2 CV323.2 CV324.2 CV325.2 CV326.1 CV327.2 CV329.2 CV331.2 CV333.2 CV335.2 CX1.2 CX2.2 CX3.2 CX5.2 CX6.2 CX7.2 CX8.2 CX9.2 CX10.2 CX11.2 CX20.2 CX21.2 CX22.2 CX23.2 CX24.2 CX25.2 CX26.2 CX27.2 CX28.2 CX29.2 CX30.2 CX31.2 CX32.2 CX33.2 CX34.2 CX35.2 CX36.2 CX37.2 CX40.2 CX41.2 CX45.2 CX47.2 CX48.2 DA10.1 DA12.1 DE1.1 DI1.3 DI1.8 DI2.1 DI4.3 DI4.8 DI5.1 DI7.1 H2.1(TP-1) H4.1(TP-1) H5.1(TP-1) H6.1(TP-1) H7.1(TP-1) H8.1(TP-1) H9.1(TP-1) H10.1(TP-1) H11.1(TP-1) H12.1(TP-1) H16.1(TP-1) H17.1(TP-1) H18.1(TP-1) H31.1(TP-1) H32.1(TP-1) H33.1(TP-1) H34.1(TP-1) JDB.6 JDB.7 JDB.8 JDB.9 JDB.10 JDIMM1.2 JDIMM1.3 JDIMM1.8 JDIMM1.9 JDIMM1.11 JDIMM1.13 JDIMM1.14 JDIMM1.19 JDIMM1.20 JDIMM1.25 JDIMM1.26 JDIMM1.28 JDIMM1.31 JDIMM1.32 JDIMM1.37 JDIMM1.38 JDIMM1.43 JDIMM1.44 JDIMM1.46 JDIMM1.48 JDIMM1.49 JDIMM1.54 JDIMM1.55 JDIMM1.60 JDIMM1.61 JDIMM1.63 JDIMM1.65 JDIMM1.66 JDIMM1.71 JDIMM1.72 JDIMM1.127 JDIMM1.128 JDIMM1.133 JDIMM1.134 JDIMM1.136 JDIMM1.138 JDIMM1.139 JDIMM1.144 JDIMM1.145 JDIMM1.150 JDIMM1.151 JDIMM1.153 JDIMM1.155 JDIMM1.156 JDIMM1.161 JDIMM1.162 JDIMM1.167 JDIMM1.168 JDIMM1.170 JDIMM1.172 JDIMM1.173 JDIMM1.178 JDIMM1.179 JDIMM1.184 JDIMM1.185 JDIMM1.187 JDIMM1.189 JDIMM1.190 JDIMM1.195 JDIMM1.196 JDIMM1.205 JDIMM1.206 JDIMM2.2 JDIMM2.3 JDIMM2.8 JDIMM2.9 JDIMM2.11 JDIMM2.13 JDIMM2.14 JDIMM2.19 JDIMM2.20 JDIMM2.25 JDIMM2.26 JDIMM2.28 JDIMM2.31 JDIMM2.32 JDIMM2.37 JDIMM2.38 JDIMM2.43 JDIMM2.44 JDIMM2.46 JDIMM2.48 JDIMM2.49 JDIMM2.54 JDIMM2.55 JDIMM2.60 JDIMM2.61 JDIMM2.63 JDIMM2.65 JDIMM2.66 JDIMM2.71 JDIMM2.72 JDIMM2.127 JDIMM2.128 JDIMM2.133 JDIMM2.134 JDIMM2.136 JDIMM2.138 JDIMM2.139 JDIMM2.144 JDIMM2.145 JDIMM2.150 JDIMM2.151 JDIMM2.153 JDIMM2.155 JDIMM2.156 JDIMM2.161 JDIMM2.162 JDIMM2.167 JDIMM2.168 JDIMM2.170 JDIMM2.172 JDIMM2.173 JDIMM2.178 JDIMM2.179 JDIMM2.184 JDIMM2.185 JDIMM2.187 JDIMM2.189 JDIMM2.190 JDIMM2.195 JDIMM2.196 JDIMM2.205 JDIMM2.206 JFAN.3 JFAN.4 JFAN.5 JHDD.1 JHDD.4 JHDD.7 JHDD.11 JHDD.13 JHDD.17 JHDD.19 JHDD.23 JHDD.24 JHDMI.2 JHDMI.5 JHDMI.8 JHDMI.11 JHDMI.17 JHDMI.20 JHDMI.21 JHDMI.22 JHDMI.23 JKB.31 JKB.32 JLAN.9 JLAN.10 JLVDS.3 JLVDS.6 JLVDS.9 JLVDS.12 JLVDS.15 JLVDS.31 JLVDS.41 JLVDS.42 JLVDS.43 JLVDS.44 JLVDS.45 JLVDS.46 JMINI.4 JMINI.9 JMINI.15 JMINI.18 JMINI.21 JMINI.26 JMINI.27 JMINI.29 JMINI.34 JMINI.35 JMINI.40 JMINI.43 JMINI.50 JMINI.53 JMINI.54 JODD.1 JODD.4 JODD.7 JODD.12 JODD.13 JODD.14 JODD.15 JPWR.4 JPWR.5 JPWR.6 JREAD.2 JREAD.9 JREAD.16 JREAD.17 JREAD.21 JREAD.23 JREAD.24 JRTC.2 JSPK.5 JSPK.6 JTOUCH.4 JTOUCH.5 JTOUCH.7 JTOUCH.8 JTP.4 JTP.7 JTP.8 JUSB1.4 JUSB1.7 JUSB1.10 JUSB1.11 JUSB1.12 JUSB1.13 JUSB2.4 JUSB2.7 JUSB2.10 JUSB2.11 JUSB2.12 JUSB2.13 JUSB3.4 JUSB3.5 JUSB3.6 JUSB3.7 JUSB3.8 JXDP1.1 JXDP1.2 JXDP1.7 JXDP1.8 JXDP1.13 JXDP1.14 JXDP1.19 JXDP1.20 JXDP1.25 JXDP1.26 JXDP1.31 JXDP1.32 JXDP1.37 JXDP1.38 JXDP1.49 JXDP1.50 JXDP1.59 LE2.1 ME1.1 PBATT.1 PBATT.2 PBATT.4 PBATT.10 PBATT.11 PC1.2 PC2.2 PC3.2 PC4.2 PC5.2 PC7.2 PC8.2 PC13.1 PC15.2 PC100.2 PC101.2 PC103.2 PC105.2 PC106.2 PC107.2 PC109.2 PC111.2 PC112.2 PC113.2 PC114.2 PC115.2 PC201.2 PC202.2 PC203.2 PC204.1 PC205.2 PC206.2 PC208.2 PC209.2 PC210.2 PC211.2 PC212.2 PC213.2 PC300.2 PC301.2 PC303.2 PC304.2 PC305.2 PC306.2 PC308.2 PC309.2 PC310.2 PC311.2 PC312.2 PC313.2 PC400.2 PC401.2 PC402.2 PC403.2 PC405.2 PC502.1 PC503.2 PC504.2 PC505.2 PC506.1 PC507.2 PC508.1 PC509.2 PC512.2 PC515.2 PC516.2 PC517.2 PC518.2 PC519.2 PC521.2 PC522.2 PC523.2 PC600.2 PC601.2 PC602.2 PC603.2 PC605.2 PC703.2 PC704.2 PC705.2 PC706.2 PC707.2 PC708.2 PC709.2 PC710.2 PC711.1 PC712.2 PC713.2 PC714.2 PC716.2 PC718.2 PC719.2 PC720.1 PC724.2 PC803.2 PC804.2 PC805.2 PC808.2 PC810.2 PC811.2 PC813.1 PC816.1 PC821.1 PC831.2 PC832.2 PC835.2 PC836.2 PC837.2 PC838.2 PC839.2 PC840.2 PC841.2 PC842.2 PC843.2 PC844.2 PC845.2 PC846.2 PC847.2 PC848.2 PC849.2 PC850.2 PC851.2 PC852.2 PC853.2 PC854.2 PC855.2 PC856.2 PC857.2 PC858.2 PC859.2 PC860.2 PC861.2 PC862.2 PC863.2 PC864.2 PC865.2 PC866.2 PC867.2 PC868.2 PC869.2 PC870.2 PC871.2 PC872.2 PC873.2 PC901.2 PC902.2 PC903.2 PC904.2 PC905.2 PC906.2 PC907.2 PC908.2 PC909.2 PC910.2 PC911.2 PC912.2 PC913.2 PC914.2 PC915.2 PC916.2 PC917.2 PC918.2 PC919.2 PC920.2 PC921.2 PC922.2 PC923.2 PC1100.2 PC1101.2 PC1102.2 PC1104.2 PC1105.2 PC1106.2 PC1108.2 PC1200.2 PC1201.2 PC1202.2 PC1203.2 PC1204.2 PC1205.2 PC1206.2 PC1207.2 PC1209.2 PC1211.2 PC1212.2 PC1213.2 PC1214.2 PC1300.2 PC1301.2 PC1302.2 PC1303.2 PC1304.2 PC1305.2 PC1307.2 PC1308.2 PD1.2 PD2.1 PD3.1 PD101.1 PL4.2 PQ1.1 PQ1.4 PQ2.1 PQ2.4 PQ3.1 PQ3.4 PQ4.3 PQ5.3 PQ102.1 PQ102.2 PQ102.3 PQ104.1 PQ104.2 PQ104.3 PQ201.1 PQ201.2 PQ201.3 PQ705.1 PQ705.2 PQ705.3 PQ706.3 PQ708.3 PQ801.1 PQ801.2 PQ801.3 PQ802.1 PQ802.2 PQ802.3 PQ1101.1 PQ1101.2 PQ1101.3 PQ1201.3 PR2.2 PR9.1 PR10.1 PR26.1 PR29.2 PR32.2 PR33.1 PR105.2 PR106.2 PR107.1 PR108.2 PR114.2 PR203.2 PR204.2 PR301.2 PR306.2 PR307.2 PR402.2 PR404.2 PR503.1 PR505.1 PR506.1 PR509.1 PR510.2 PR512.1 PR513.1 PR534.2 PR602.2 PR604.2 PR711.1 PR712.2 PR722.2 PR724.1 PR804.1 PR805.2 PR811.1 PR815.2 PR819.1 PR833.2 PR834.1 PR836.1 PR838.1 PR840.1 PR1102.1 PR1105.2 PR1108.2 PR1201.2 PR1202.2 PR1204.2 PR1214.2 PR1301.2 PR1304.2 PU100.21 PU200.1 PU200.3 PU200.14 PU200.21 PU300.9 PU400.4 PU400.8 PU400.9 PU501.19 PU501.22 PU501.29 PU501.33 PU502.3 PU502.9 PU600.4 PU600.8 PU600.9 PU701.14 PU701.21 PU800.17 PU800.29 PU1100.11 PU1200.9 PU1300.11 Q8.3 Q2307.3 Q2308.3 QC3.3 QD20.3 QS3.3 QV14.1 QV14.4 QV24.3 QV25.3 QX1.3 QX3.3 R2.2 R16.2 R159.2 R255.1 R2338.2 R2351.1 RA19.2 RA29.2 RA30.2 RA31.2 RA32.2 RA81.1 RC2.2 RC20.2 RC21.2 RC22.2 RC23.2 RC24.2 RC25.2 RC66.2 RC68.2 RC69.2 RC70.2 RC84.1 RC87.1 RC88.2 RC89.2 RC90.2 RC99.2 RC101.2 RC113.2 RC116.2 RC122.2 RC123.2 RC132.2 RC133.1 RC134.2 RC135.2 RC138.2 RC163.2 RD6.1 RD7.1 RD13.2 RD50.2 RD52.2 RE1.1 RE2.1 RE5.1 RE18.2 RE47.1 RE326.2 RL27.1 RL31.1 RL35.1 RM11.1 RP41.5 RP41.6 RP41.7 RP41.8 RP45.6 RP45.7 RP47.4 RP51.5 RP51.6 RR1.2 RV64.1 RV66.2 RV84.2 RV89.1 RV95.2 RV122.2 RV123.2 RV125.2 RV127.2 RV133.1 RV136.2 RV137.2 RV145.1 RV146.2 RV147.2 RV148.2 RV149.2 RV150.2 RV151.2 RV152.2 RV153.2 RV166.2 RV167.2 RV168.2 RV169.2 RV170.2 RV171.2 RV172.2 RV173.2 RV176.2 RV177.2 RV178.2 RV179.2 RV190.2 RV191.2 RV192.2 RV193.2 RV194.2 RV195.2 RV196.2 RV197.2 RV201.2 RV204.2 RV206.1 RV207.2 RV236.2 RV238.2 RV240.2 RV242.2 RV248.1 RX5.1 RX9.2 RX13.2 RX14.2 RX20.2 RX23.2 RX25.2 RX26.2 RX33.2 RX34.2 RX35.2 RX36.2 RX170.2 RX171.2 SW1.1 SW1.2 SW1.5 SW1.6 SW2.1 SW2.2 SW2.5 SW2.6 U2301.11 U2301.15 U2302.4 U2303.3 U2304.11 U2304.15 UA1.4 UA1.49 UC1.A11 UC1.A14 UC1.A18 UC1.A24 UC1.A28 UC1.A32 UC1.A36 UC1.A40 UC1.A44 UC1.A48 UC1.A52 UC1.A56 UC1.AA1 UC1.AA58 UC1.AB7 UC1.AB10 UC1.AB20 UC1.AB22 UC1.AC61 UC1.AD3 UC1.AD21 UC1.AD63 UC1.AE5 UC1.AE10 UC1.AE58 UC1.AF11 UC1.AF12 UC1.AF14 UC1.AF15 UC1.AF17 UC1.AF18 UC1.AG1 UC1.AG11 UC1.AG21 UC1.AG23 UC1.AG60 UC1.AG61 UC1.AG62 UC1.AG63 UC1.AH16 UC1.AH17 UC1.AH19 UC1.AH20 UC1.AH22 UC1.AH24 UC1.AH28 UC1.AH30 UC1.AH32 UC1.AH34 UC1.AH36 UC1.AH38 UC1.AH40 UC1.AH42 UC1.AH44 UC1.AH46 UC1.AH49 UC1.AH51 UC1.AH53 UC1.AH55 UC1.AH57 UC1.AJ13 UC1.AJ14 UC1.AJ23 UC1.AJ25 UC1.AJ27 UC1.AJ29 UC1.AJ35 UC1.AJ39 UC1.AJ41 UC1.AJ43 UC1.AJ45 UC1.AJ47 UC1.AJ50 UC1.AJ52 UC1.AJ54 UC1.AJ56 UC1.AJ58 UC1.AJ60 UC1.AJ63 UC1.AK3 UC1.AK23 UC1.AK52 UC1.AL10 UC1.AL13 UC1.AL17 UC1.AL20 UC1.AL22 UC1.AL23 UC1.AL26 UC1.AL29 UC1.AL31 UC1.AL33 UC1.AL36 UC1.AL39 UC1.AL40 UC1.AL45 UC1.AL46 UC1.AL51 UC1.AL52 UC1.AL54 UC1.AL57 UC1.AL60 UC1.AL61 UC1.AM1 UC1.AM17 UC1.AM23 UC1.AM31 UC1.AM52 UC1.AN7 UC1.AN17 UC1.AN23 UC1.AN31 UC1.AN32 UC1.AN35 UC1.AN36 UC1.AN39 UC1.AN40 UC1.AN42 UC1.AN43 UC1.AN45 UC1.AN46 UC1.AN48 UC1.AN49 UC1.AN51 UC1.AN52 UC1.AN60 UC1.AN63 UC1.AP3 UC1.AP10 UC1.AP17 UC1.AP20 UC1.AP22 UC1.AP23 UC1.AP26 UC1.AP29 UC1.AP31 UC1.AP38 UC1.AP39 UC1.AP48 UC1.AP52 UC1.AP54 UC1.AP57 UC1.AR5 UC1.AR11 UC1.AR15 UC1.AR17 UC1.AR23 UC1.AR31 UC1.AR33 UC1.AR39 UC1.AR43 UC1.AR49 UC1.AR52 UC1.AT13 UC1.AT35 UC1.AT37 UC1.AT40 UC1.AT42 UC1.AT43 UC1.AT46 UC1.AT49 UC1.AT61 UC1.AT62 UC1.AT63 UC1.AU1 UC1.AU16 UC1.AU18 UC1.AU20 UC1.AU22 UC1.AU24 UC1.AU26 UC1.AU28 UC1.AU30 UC1.AU33 UC1.AU51 UC1.AU53 UC1.AU55 UC1.AU57 UC1.AU59 UC1.AV8 UC1.AV14 UC1.AV16 UC1.AV20 UC1.AV24 UC1.AV28 UC1.AV33 UC1.AV34 UC1.AV36 UC1.AV39 UC1.AV41 UC1.AV43 UC1.AV46 UC1.AV49 UC1.AV51 UC1.AV55 UC1.AV59 UC1.AW4 UC1.AW16 UC1.AW24 UC1.AW33 UC1.AW35 UC1.AW37 UC1.AW40 UC1.AW42 UC1.AW44 UC1.AW47 UC1.AW50 UC1.AW51 UC1.AW59 UC1.AW60 UC1.AY4 UC1.AY6 UC1.AY11 UC1.AY16 UC1.AY18 UC1.AY22 UC1.AY24 UC1.AY26 UC1.AY30 UC1.AY33 UC1.AY51 UC1.AY53 UC1.AY57 UC1.AY59 UC1.B4 UC1.B20 UC1.B24 UC1.B26 UC1.B28 UC1.B32 UC1.B36 UC1.B40 UC1.B44 UC1.B48 UC1.B52 UC1.B56 UC1.B60 UC1.C11 UC1.C14 UC1.C18 UC1.C20 UC1.C25 UC1.C27 UC1.C38 UC1.C39 UC1.C57 UC1.D2 UC1.D5 UC1.D8 UC1.D12 UC1.D14 UC1.D18 UC1.D21 UC1.D23 UC1.D25 UC1.D26 UC1.D27 UC1.D29 UC1.D30 UC1.D31 UC1.D33 UC1.D34 UC1.D35 UC1.D37 UC1.D38 UC1.D39 UC1.D41 UC1.D42 UC1.D43 UC1.D45 UC1.D46 UC1.D47 UC1.D49 UC1.D50 UC1.D51 UC1.D53 UC1.D54 UC1.D55 UC1.D57 UC1.D59 UC1.D62 UC1.D63 UC1.E11 UC1.E17 UC1.F20 UC1.F26 UC1.F30 UC1.F34 UC1.F38 UC1.F42 UC1.F46 UC1.F50 UC1.F54 UC1.F58 UC1.F61 UC1.G3 UC1.G5 UC1.G6 UC1.G8 UC1.G18 UC1.G22 UC1.H13 UC1.H17 UC1.H57 UC1.J10 UC1.J22 UC1.J59 UC1.J63 UC1.K1 UC1.K12 UC1.L7 UC1.L13 UC1.L15 UC1.L17 UC1.L18 UC1.L20 UC1.L58 UC1.L61 UC1.M22 UC1.N3 UC1.N10 UC1.N21 UC1.P22 UC1.P59 UC1.P62 UC1.P63 UC1.R8 UC1.R10 UC1.R22 UC1.T1 UC1.T58 UC1.U9 UC1.U20 UC1.U22 UC1.U61 UC1.V3 UC1.V7 UC1.V10 UC1.V23 UC1.V58 UC1.W20 UC1.W22 UC1.Y10 UC1.Y59 UC1.Y63 UC3.3 UC4.7 UC4.15 UD1.3 UE1.11 UE1.24 UE1.35 UE1.94 UE1.113 UE2.3 UE3.5 UE3.6 UE3.7 UE3.8 UG1.4 UG1.7 UG1.13 UG1.17 UI2.1 UI2.9 UI3.1 UI3.9 UI4.1 UI4.9 UI5.1 UI5.9 UL1.33 UL2.2 UR1.25 UV1.A3 UV1.A37 UV1.AA2 UV1.AA6 UV1.AA16 UV1.AA18 UV1.AA21 UV1.AA23 UV1.AA26 UV1.AA28 UV1.AB12 UV1.AB15 UV1.AB17 UV1.AB20 UV1.AB22 UV1.AB24 UV1.AB27 UV1.AB39 UV1.AC2 UV1.AC6 UV1.AC11 UV1.AC13 UV1.AC16 UV1.AC18 UV1.AC21 UV1.AC23 UV1.AC26 UV1.AC28 UV1.AC34 UV1.AD9 UV1.AD15 UV1.AD17 UV1.AD20 UV1.AD22 UV1.AD24 UV1.AD27 UV1.AD35 UV1.AD37 UV1.AE2 UV1.AE6 UV1.AE34 UV1.AE38 UV1.AF10 UV1.AF16 UV1.AF18 UV1.AF21 UV1.AF39 UV1.AG2 UV1.AG6 UV1.AG9 UV1.AG17 UV1.AG20 UV1.AG22 UV1.AH21 UV1.AH39 UV1.AJ2 UV1.AJ6 UV1.AJ10 UV1.AJ11 UV1.AJ28 UV1.AJ33 UV1.AK7 UV1.AK11 UV1.AK31 UV1.AK39 UV1.AL2 UV1.AL6 UV1.AL8 UV1.AL11 UV1.AL14 UV1.AL17 UV1.AL20 UV1.AL23 UV1.AL26 UV1.AL32 UV1.AL34 UV1.AM9 UV1.AM11 UV1.AM31 UV1.AM35 UV1.AN2 UV1.AN6 UV1.AN8 UV1.AN10 UV1.AN11 UV1.AN17 UV1.AN19 UV1.AN27 UV1.AN29 UV1.AN30 UV1.AN34 UV1.AN38 UV1.AP7 UV1.AP9 UV1.AP11 UV1.AP16 UV1.AP17 UV1.AP18 UV1.AP19 UV1.AP27 UV1.AP28 UV1.AP29 UV1.AP30 UV1.AP39 UV1.AR5 UV1.AR18 UV1.AR28 UV1.AR39 UV1.AU37 UV1.AV17 UV1.AV27 UV1.AW14 UV1.AW16 UV1.AW20 UV1.AW22 UV1.AW24 UV1.AW26 UV1.AW30 UV1.AW32 UV1.AW34 UV1.AW35 UV1.B7 UV1.B9 UV1.B11 UV1.B13 UV1.B15 UV1.B17 UV1.B19 UV1.B21 UV1.B23 UV1.B25 UV1.B27 UV1.B29 UV1.B31 UV1.B33 UV1.C1 UV1.C39 UV1.E5 UV1.E35 UV1.E39 UV1.F7 UV1.F9 UV1.F11 UV1.F13 UV1.F15 UV1.F17 UV1.F19 UV1.F21 UV1.F23 UV1.F25 UV1.F27 UV1.F29 UV1.F31 UV1.F33 UV1.F34 UV1.F39 UV1.G2 UV1.G6 UV1.G33 UV1.G34 UV1.H9 UV1.H31 UV1.H34 UV1.H39 UV1.J2 UV1.J6 UV1.J8 UV1.J27 UV1.J31 UV1.J34 UV1.K7 UV1.K14 UV1.K31 UV1.K34 UV1.K39 UV1.L2 UV1.L6 UV1.L11 UV1.L17 UV1.L22 UV1.L24 UV1.L31 UV1.L34 UV1.M17 UV1.M22 UV1.M24 UV1.M34 UV1.M39 UV1.N2 UV1.N6 UV1.N16 UV1.N18 UV1.N21 UV1.N23 UV1.N26 UV1.N31 UV1.N34 UV1.P31 UV1.P34 UV1.P39 UV1.R2 UV1.R6 UV1.R15 UV1.R17 UV1.R20 UV1.R22 UV1.R24 UV1.R27 UV1.R34 UV1.T11 UV1.T13 UV1.T16 UV1.T18 UV1.T21 UV1.T23 UV1.T26 UV1.T31 UV1.T34 UV1.T39 UV1.U2 UV1.U6 UV1.U13 UV1.U15 UV1.U17 UV1.U20 UV1.U22 UV1.U24 UV1.U27 UV1.U31 UV1.U34 UV1.V11 UV1.V13 UV1.V16 UV1.V18 UV1.V21 UV1.V23 UV1.V26 UV1.V34 UV1.V39 UV1.W2 UV1.W6 UV1.W31 UV1.W34 UV1.Y15 UV1.Y17 UV1.Y20 UV1.Y22 UV1.Y24 UV1.Y27 UV1.Y34 UV1.Y39 UV13.3 UV18.A9 UV18.B1 UV18.B3 UV18.B9 UV18.D1 UV18.D8 UV18.E1 UV18.E2 UV18.E8 UV18.F9 UV18.G1 UV18.G8 UV18.G9 UV18.J2 UV18.J8 UV18.M1 UV18.M9 UV18.P1 UV18.P9 UV18.T1 UV18.T9 UV19.A9 UV19.B1 UV19.B3 UV19.B9 UV19.D1 UV19.D8 UV19.E1 UV19.E2 UV19.E8 UV19.F9 UV19.G1 UV19.G8 UV19.G9 UV19.J2 UV19.J8 UV19.M1 UV19.M9 UV19.P1 UV19.P9 UV19.T1 UV19.T9 UV20.A9 UV20.B1 UV20.B3 UV20.B9 UV20.D1 UV20.D8 UV20.E1 UV20.E2 UV20.E8 UV20.F9 UV20.G1 UV20.G8 UV20.G9 UV20.J2 UV20.J8 UV20.M1 UV20.M9 UV20.P1 UV20.P9 UV20.T1 UV20.T9 UV21.A9 UV21.B1 UV21.B3 UV21.B9 UV21.D1 UV21.D8 UV21.E1 UV21.E2 UV21.E8 UV21.F9 UV21.G1 UV21.G8 UV21.G9 UV21.J2 UV21.J8 UV21.M1 UV21.M9 UV21.P1 UV21.P9 UV21.T1 UV21.T9 UV22.A9 UV22.B1 UV22.B3 UV22.B9 UV22.D1 UV22.D8 UV22.E1 UV22.E2 UV22.E8 UV22.F9 UV22.G1 UV22.G8 UV22.G9 UV22.J2 UV22.J8 UV22.M1 UV22.M9 UV22.P1 UV22.P9 UV22.T1 UV22.T9 UV23.A9 UV23.B1 UV23.B3 UV23.B9 UV23.D1 UV23.D8 UV23.E1 UV23.E2 UV23.E8 UV23.F9 UV23.G1 UV23.G8 UV23.G9 UV23.J2 UV23.J8 UV23.M1 UV23.M9 UV23.P1 UV23.P9 UV23.T1 UV23.T9 UV24.A9 UV24.B1 UV24.B3 UV24.B9 UV24.D1 UV24.D8 UV24.E1 UV24.E2 UV24.E8 UV24.F9 UV24.G1 UV24.G8 UV24.G9 UV24.J2 UV24.J8 UV24.M1 UV24.M9 UV24.P1 UV24.P9 UV24.T1 UV24.T9 UV25.A9 UV25.B1 UV25.B3 UV25.B9 UV25.D1 UV25.D8 UV25.E1 UV25.E2 UV25.E8 UV25.F9 UV25.G1 UV25.G8 UV25.G9 UV25.J2 UV25.J8 UV25.M1 UV25.M9 UV25.P1 UV25.P9 UV25.T1 UV25.T9 UX1.2 UX2.3 UX4.6 UX4.16 UX4.49 YG1.2 YG1.4 YL2.2 YL2.4 YV1.2 YV1.4
GNDA: CA1.2 CA2.2 CA23.1 CA33.2 CA38.2 CA39.2 CA40.2 CA51.2 CA61.2 CA62.1 CA63.1 CA71.2 JHP.6 JHP.7 QA5.1 QA5.4 QA6.1 QA6.4 RA29.1 RA30.1 RA31.1 RA32.1 RA83.2 RA84.2 RA153.1 UA1.25 UA1.38
V5A_CPU: PC505.1 PR519.2 PU501.28
V18: CR4.2 UR1.24
VBAT_CPU: PR508.2 PU501.16
VCC: PC710.1 PR705.2 PU701.20
VCCSENSE: PU501.24 R1.2 UC1.E63
VCCSENSE_VGA: PR846.2 RV202.2 UV1.AF28
VCCST_PG_EC: C79.1 CE35.1 DE1.2 R286.2 UC1.B59 UE1.123
VDD_1.35V: PC209.1 PR205.1 PR206.2 PU200.11
VDDCI_SEN: PR1210.2 RV215.2 UV1.AG28
VIN: PC3.1 PC4.1 PC701.1 PL1.2 PQ701.1 PR5.1 PR7.2 PR31.2 PR705.1 PR720.1 PR723.2
VSSSENSE: PU501.23 R2.1 RC163.1 UC1.E62
VSSSENSE_VGA: PR845.2 RV204.1 UV1.AH29
65W#/90W: PQ4.2 UE1.117
62881_COMP: PC806.2 PC814.2 PC818.2 PR817.2 PU800.5
62881_FB: PC814.1 PR813.1 PR818.1 PR821.1 PU800.6
62881_RBIAS: PR815.1 PU800.3
62881_VCCP: PC803.1 PR814.1 PU800.19
62881_VDD: PC811.1 PR822.1 PU800.11
62881_VID0: PR811.2 PU800.20
62881_VID1: PR810.2 PU800.21
62881_VID2: PR812.2 PU800.22
62881_VID3: PR807.2 PU800.23
62881_VID4: PR809.2 PU800.24
62881_VID5: PR806.2 PU800.25
62881_VID6: PR804.2 PU800.26
62881_VIN: PC810.1 PR823.1 PU800.12
62881_VR_ON: PC869.1 PR803.2 PU800.27
62881_VW: PC818.1 PR817.1 PU800.4
+BIF_VDDC: CV97.1 CV195.1 CV196.1 RV103.2 RV234.1 RV245.2 UV1.N27 UV1.T27
+CHGRTC: DC1.3 JP12.2
+CODEC_AVDD2: CA61.1 RA8.2 RA9.2 UA1.40
+CPU_CORE: C40.1 CM45.2 PC901.1 PC902.1 PC903.1 PC904.1 PC905.1 PC906.1 PC907.1 PC908.1 PC909.1 PC910.1 PC911.1 PC912.1 PC913.1 PC914.1 PC915.1 PC916.1 PC917.1 PC918.1 PC919.1 PC920.1 PC921.1 PC922.1 PC923.1 PL502.4 R1.1 UC1.AB57 UC1.AD57 UC1.AG57 UC1.C24 UC1.C28 UC1.C32 UC1.C36 UC1.C40 UC1.C44 UC1.C48 UC1.C52 UC1.C56 UC1.E23 UC1.E25 UC1.E27 UC1.E29 UC1.E31 UC1.E33 UC1.E35 UC1.E37 UC1.E39 UC1.E41 UC1.E43 UC1.E45 UC1.E47 UC1.E49 UC1.E51 UC1.E53 UC1.E55 UC1.E57 UC1.F24 UC1.F28 UC1.F32 UC1.F36 UC1.F40 UC1.F44 UC1.F48 UC1.F52 UC1.F56 UC1.F59 UC1.G23 UC1.G25 UC1.G27 UC1.G29 UC1.G31 UC1.G33 UC1.G35 UC1.G37 UC1.G39 UC1.G41 UC1.G43 UC1.G45 UC1.G47 UC1.G49 UC1.G51 UC1.G53 UC1.G55 UC1.G57 UC1.H23 UC1.J23 UC1.K23 UC1.K57 UC1.L22 UC1.M23 UC1.M57 UC1.P57 UC1.U57 UC1.W57
+DIMM1_VREF_DQ: CD1.1 CD2.1 JDIMM1.1 RD1.2
+DIMM2_VREF_DQ: CD32.1 CD33.1 JDIMM2.1 RD8.2
+DPAB_VDD10: CV114.1 CV115.1 CV116.1 RV120.1 UV1.AN33 UV1.AP31 UV1.AP32 UV1.AP33
+DPAB_VDD18: CV108.1 CV109.1 CV110.1 RV118.1 UV1.AN24 UV1.AP24 UV1.AP25 UV1.AP26 UV1.AU28 UV1.AV29
+DPCD_VDD10: CV117.1 CV118.1 CV119.1 RV121.2 UV1.AP13 UV1.AP14 UV1.AP15 UV1.AT13
+DPCD_VDD18: CV111.1 CV112.1 CV113.1 RV119.2 UV1.AP20 UV1.AP21 UV1.AP22 UV1.AP23 UV1.AU18 UV1.AV19
+DPEF_VDD10: CV123.1 CV124.1 CV125.1 RV126.2 UV1.AK33 UV1.AK34 UV1.AL33 UV1.AM33
+DPEF_VDD18: CV120.1 CV121.1 CV122.1 RV124.2 UV1.AF34 UV1.AG34 UV1.AH34 UV1.AJ34 UV1.AL38 UV1.AM37
+DPLL_PVDD: CV82.1 CV83.1 CV84.1 LV14.1 RV246.2 UV1.AM32
+DPLL_VDDC: CV86.1 CV87.1 CV88.1 LV15.1 UV1.AN31
+EC_VCCA: CE7.1 LE1.2 PR24.2 UE1.67
+FAN_POWER: CE22.1 CE23.1 JFAN.1 UE3.3
+INV_PWR_SRC: CX5.1 JLVDS.39 JLVDS.40 QX2.1 QX2.2 QX2.5 QX2.6
+LAN_IO: CG3.1 CL15.1 CL19.1 JP3.1 RL34.1 RL37.2 RL38.2 UG1.8 UL1.23 UL1.32 UL2.1
+LAN_VDD: CL20.1 CL22.1 CL26.1 CL34.1 CL35.1 UL1.8 UL1.30
+LCDVDD: CX2.1 CX3.1 LX1.1 UX1.1
+LCDVDD_CONN: CX8.1 CX11.1 JLVDS.24 JLVDS.25 LX1.2
+MIC2-VREFO: RA53.2 RA1109.2 UA1.29
+MPV18: CV197.1 CV198.1 CV199.1 LV21.2 UV1.H7 UV1.H8
+PCH_VCCDSW: R265.1 UC1.AG19 UC1.AG20
+PCH_VCCDSW_R: C64.1 R265.2
+PCIE_PVDD: CV132.1 CV133.1 CV134.1 LV18.2 UV1.AB37
+PCIE_VDDR: CV126.1 CV127.1 CV128.1 CV129.1 CV130.1 CV131.1 LV17.2 RV244.2 UV1.AA31 UV1.AA32 UV1.AA33 UV1.AA34 UV1.W30 UV1.Y31
+RTCBATT: JRTC.1 RC10.2 RG1.1
+RTCVCC: C54.1 C55.1 C56.1 CC26.1 DC1.1 R2337.2 RA5.1 RC1.1 RC5.1 RC6.1 RC7.1 RG2.1 UC1.AG10
+SM_VREF_CA: CC8.1 RC17.2 UC1.AP49
+SM_VREF_CA_DIMM: RC14.2 RC17.1 RC20.1 RD4.2 RD10.2
+SM_VREF_DQ0: CC10.1 RC19.2 UC1.AR51
+SM_VREF_DQ0_DIMM1: RC16.2 RC19.1 RC22.1 RD1.1
+SM_VREF_DQ1: CC9.1 RC18.2 UC1.AP51
+SM_VREF_DQ1_DIMM2: RC15.2 RC18.1 RC21.1 RD8.1
+SPV10: CV215.1 CV216.1 CV217.1 LV23.2 UV1.AN9
+SPV18: CV200.1 CV201.1 CV202.1 LV22.2 UV1.AM10
+SW_LX: LX9.2 UX4.17
+SWR_V12: CX32.1 CX37.1 CX47.1 CX48.1 LX9.1 UX4.11 UX4.15 UX4.43
+TSVDD: CV91.1 CV92.1 CV93.1 LV16.2 UV1.AJ32
+VCHGR: PC712.1 PC713.1 PC716.1 PQ702.1 PQ702.2 PQ702.3 PR716.4
+VDISPLAY_VCC: CX21.1 CX22.1 FX1.1 JHDMI.18
+VGA_CORE: CV327.1 LV25.2 LV26.2 PC835.1 PC836.1 PC837.1 PC838.1 PC839.1 PC840.1 PC841.1 PC842.1 PC843.1 PC844.1 PC845.1 PC846.1 PC847.1 PC848.1 PC849.1 PC850.1 PC851.1 PC852.1 PC853.1 PC854.1 PC855.1 PC856.1 PC857.1 PC858.1 PC859.1 PC860.1 PC861.1 PC862.1 PC863.1 PC864.1 PC865.1 PC866.1 PC867.1 PC868.1 PC870.1 PC871.1 PC872.1 PC873.1 PL802.2 PR820.2 PR830.1 RV202.1 RV234.2 UV1.AA15 UV1.AA17 UV1.AA20 UV1.AA22 UV1.AA24 UV1.AA27 UV1.AB16 UV1.AB18 UV1.AB21 UV1.AB23 UV1.AB26 UV1.AB28 UV1.AC17 UV1.AC20 UV1.AC22 UV1.AC24 UV1.AC27 UV1.AD18 UV1.AD21 UV1.AD23 UV1.AD26 UV1.AF17 UV1.AF20 UV1.AF22 UV1.AG16 UV1.AG18 UV1.AG21 UV1.AH22 UV1.AH27 UV1.AH28 UV1.M26 UV1.N24 UV1.R18 UV1.R21 UV1.R23 UV1.R26 UV1.T17 UV1.T20 UV1.T22 UV1.T24 UV1.U16 UV1.U18 UV1.U21 UV1.U23 UV1.U26 UV1.V17 UV1.V20 UV1.V22 UV1.V24 UV1.V27 UV1.Y16 UV1.Y18 UV1.Y21 UV1.Y23 UV1.Y26 UV1.Y28
+VGA_PCIE: CV146.1 CV147.1 CV148.1 CV149.1 CV150.1 CV151.1 LV15.2 LV23.1 PJP1300.1 RV103.1 RV120.2 RV121.1 RV126.1 RV198.2 RV203.2 UV1.G30 UV1.G31 UV1.H29 UV1.H30 UV1.J29 UV1.J30 UV1.L28 UV1.M28 UV1.N28 UV1.R28 UV1.T28 UV1.U28
+VGA_PCIEP: PC1300.1 PC1303.1 PC1305.1 PC1306.1 PC1308.1 PJP1300.2 PL1300.2 PR1302.1
+VREFG_GPU: CV81.1 RV93.1 RV95.1 UV1.AH13
/BATDRV: PR706.2 PU701.11
A_BA0: UV1.J17 UV18.M2 UV19.M2 UV20.M2 UV21.M2
A_BA1: UV1.H17 UV18.N8 UV19.N8 UV20.N8 UV21.N8
A_BA2: UV1.H16 UV18.M3 UV19.M3 UV20.M3 UV21.M3
AC_BATT: QV14.3 RV73.2 RV85.2 UV1.AH17
AC_PRESENT: DH1.2 RC32.2 UC1.AJ8
ACDET: PC711.2 PR711.2 PR723.1 PU701.6
ACDRV: PR703.2 PU701.4
ACIN: CE18.2 DH1.1 PR1.1 PR707.2 PR712.1 PU701.5 RV250.1 UE1.110
ACIN_65W: QV14.2 RV250.2 UE1.108
ACOFF: PQ706.2 UE1.27
AD_BID0: CE8.1 RE3.1 RE5.2 UE1.75
ADP_I: PC720.2 PR23.2 PU701.7 UE1.65
ADPIN: PC1.1 PC2.1 PJPDC.4 PJPDC.5 PL1.1
AUD_HP_OUT_L_CN: CA39.1 DA10.3 JHP.1 LA8.1
AUD_HP_OUT_R_CN: CA33.1 DA10.2 JHP.2 LA9.1
B+: CX4.1 PC714.1 PC718.1 PL102.1 PL201.1 PL302.1 PL501.2 PL701.2 PL800.1 PL1100.2 PL1201.1 PR716.1 QX2.4 RS6.2 RX2.1
B+_1.05V: PC303.1 PC304.1 PC305.1 PC306.1 PL302.2 PU300.8
B+_VDDCI: PC1202.1 PC1203.1 PC1204.1 PC1209.1 PL1201.2 PU1200.8
B-RAMP: PR507.1 PR509.2 PU501.11
B_BA0: UV1.Y8 UV22.M2 UV23.M2 UV24.M2 UV25.M2
B_BA1: UV1.AA9 UV22.N8 UV23.N8 UV24.N8 UV25.N8
B_BA2: UV1.AA8 UV22.M3 UV23.M3 UV24.M3 UV25.M3
BAT_ALERT: PBATT.3 PD1.4 PD2.2
BATT+: PC7.1 PL3.1 PQ702.5 PQ702.6 PQ702.7 PQ702.8
BATT++: PBATT.8 PBATT.9 PC8.1 PL3.2
BATT_CHG_LED#: RD16.1 UE1.90
BATT_LOW_LED#: RD17.1 UE1.93
BATT_PRS: PBATT.5 PC14.1 PR15.1 PR17.2
BATT_TEMP: CE9.2 PC723.2 PR15.2 PR16.1 UE1.63
BBS_BIT: RC119.2 RC123.1 UC1.L8
BEEP#: DA8.2 UE1.23
BKOFF#: RX50.1 UE1.105 UX2.1
BOOT_1.35V: PR200.2 PU200.18
BST: PR709.1 PU701.17
BST_1.05V: PR303.1 PU300.6
BST_1.35V: PC200.1 PR200.1
BST_3V: PR103.2 PU100.9
BST_5V: PR111.1 PU100.17
BST_+1.2VSP: PR1101.1 PU1100.10
BST_CHGA: PC721.1 PD701.1 PR709.2
BST_VDDCI: PR1200.1 PU1200.6
BST_VGA_CORE: PR802.1 PU800.14
BT_LED#: JMINI.46 QD19.3 RD47.2 RD49.1 UD1.2
BT_ON#: RM13.2 RP54.2 UC1.AD5
CAPS_LED: JKB.1 UE1.91
CASA0#: UV1.K20 UV18.K3 UV19.K3
CASA1#: UV1.K17 UV20.K3 UV21.K3
CASB0#: UV1.W10 UV22.K3 UV23.K3
CASB1#: UV1.AA10 UV24.K3 UV25.K3
CE_EN: RX18.1 UE1.17
CE_EN_R: JLVDS.18 RX18.2 RX20.1 RX53.2
CFD_PWRBTN#_XDP: JXDP1.41 RC49.2
CFG0: JXDP1.9 UC1.AC60
CFG1: JXDP1.11 UC1.AC62
CFG2: JXDP1.15 UC1.AC63
CFG3: JXDP1.17 RC56.2 UC1.AA63
CFG3_R: JXDP1.60 RC56.1
CFG4: JXDP1.27 RC138.1 UC1.AA60
CFG5: JXDP1.29 UC1.Y62
CFG6: JXDP1.33 UC1.Y61
CFG7: JXDP1.35 UC1.Y60
CFG8: JXDP1.10 UC1.V62
CFG9: JXDP1.12 UC1.V61
CFG10: JXDP1.16 UC1.V60
CFG11: JXDP1.18 UC1.U60
CFG12: JXDP1.28 UC1.T63
CFG13: JXDP1.30 UC1.T62
CFG14: JXDP1.34 UC1.T61
CFG15: JXDP1.36 UC1.T60
CFG16: JXDP1.6 UC1.AA62
CFG17: JXDP1.4 UC1.AA61
CFG18: JXDP1.24 UC1.U63
CFG19: JXDP1.22 UC1.U62
CFG_RCOMP: RC132.1 UC1.V63
CHG_B+: PC703.1 PC704.1 PC705.1 PC706.1 PC724.1 PL702.2 PQ703.5 PQ704.5
CKEA0: UV1.K21 UV18.K9 UV19.K9
CKEA1: UV1.J20 UV20.K9 UV21.K9
CKEB0: UV1.U10 UV22.K9 UV23.K9
CKEB1: UV1.AA11 UV24.K9 UV25.K9
CLK_BIASREF: RC13.1 UC1.C26
CLK_CPU_ITP: RC139.2 UC1.A35
CLK_CPU_ITP#: RC140.2 UC1.B35
CLK_PCI_LPC: R2336.1 R2354.2 UE1.12
CLK_PCIE_LAN: UC1.B42 UL1.15
CLK_PCIE_LAN#: UC1.C41 UL1.16
CLK_PCIE_WLAN: JMINI.13 UC1.C37
CLK_PCIE_WLAN#: JMINI.11 UC1.B38
CLK_PEG_VGA: UC1.B39 UV1.AB35
CLK_PEG_VGA#: UC1.A39 UV1.AA36
CLK_SMB: PBATT.7 PD1.3 PD3.3 PR18.1
CLK_X1: CG8.1 UG1.1 YG1.1
CLK_X2: CG9.1 UG1.16 YG1.3
CLK_XDP: JXDP1.40 RC139.1
CLK_XDP#: JXDP1.42 RC140.1
CLKA0: RV154.1 UV1.H27 UV18.J7 UV19.J7
CLKA0#: RV155.1 UV1.G27 UV18.K7 UV19.K7
CLKA1: RV164.1 UV1.J14 UV20.J7 UV21.J7
CLKA1#: RV165.1 UV1.H14 UV20.K7 UV21.K7
CLKB0: RV174.1 UV1.L9 UV22.J7 UV23.J7
CLKB0#: RV175.1 UV1.L8 UV22.K7 UV23.K7
CLKB1: RV180.1 UV1.AD8 UV24.J7 UV25.J7
CLKB1#: RV181.1 UV1.AD7 UV24.K7 UV25.K7
CLKOUT_LPC0: R2336.2 UC1.AN15
CLKRUN#: RC36.2 UC1.V5
CMSRC: PR721.1 PU701.3
CODEC_IRQ: RC88.1 UC1.L4
COMP_CPU: PC513.1 PC514.2 PR531.2 PR532.2 PU501.26
CPPE#: RC108.2 UC1.J1
CPU_DETECT#: CE33.1 RE11.1 UC1.D61 UE1.127
CPU_DPB_AUX: RP51.3 UC1.B5
CPU_DPB_AUX#: RP51.1 UC1.C5
CPU_DPB_CTRLCLK: QX4.1 RP52.1 UC1.B9
CPU_DPB_CTRLCLK_R: JHDMI.15 QX4.6 RX16.1
CPU_DPB_CTRLDAT: QX4.4 RP52.2 UC1.C9
CPU_DPB_CTRLDAT_R: JHDMI.16 QX4.3 RX17.1
CPU_DPC_AUX: RP51.4 UC1.A6
CPU_DPC_AUX#: RP51.2 UC1.B6
CPU_DPC_CTRLCLK: RP52.3 UC1.D9
CPU_DPC_CTRLDAT: RP52.4 UC1.D11
CPU_EDP_AUX#_C: CX44.2 RX37.1 UX4.3
CPU_EDP_AUX_C: CX43.2 RX39.1 UX4.4
CPU_EDP_HPD#: QC3.1 RC78.2 RC89.1 RC105.2 UC1.D6
CPU_EDP_N0_C: CX46.2 RX43.1 UX4.8
CPU_EDP_N1_C: CX39.2 RX47.1 UX4.10
CPU_EDP_P0_C: CX42.2 RX41.1 UX4.7
CPU_EDP_P1_C: CX38.2 RX45.1 UX4.9
CPU_PWR_DEBUG#: R253.1 R255.2 RC50.1 UC1.H59
CPU_PWR_DEBUG#_R: JXDP1.45 RC50.2
CPUSB#: RC111.2 UC1.K3
CS1: PR105.1 PU100.1
CS2: PR108.1 PU100.5
CS_1.35V: PR205.2 PU200.13
CSA0#_0: UV1.K24 UV18.L2 UV19.L2
CSA1#_0: UV1.M13 UV20.L2 UV21.L2
CSB0#_0: UV1.P10 UV22.L2 UV23.L2
CSB1#_0: UV1.AD10 UV24.L2 UV25.L2
CSCL: QX6.4 RP57.2 RX6.2 UX4.13
CSDA: QX6.1 RP57.1 RX31.2 UX4.14
CSIN: PR702.3 PR704.2
CSIP: PR702.2 PR717.2
CSN1_CPU: PC510.1 PC511.1 PL502.3 PR515.2 PR517.2 PU501.18
CSP1_CPU: PC510.2 PC511.2 PH501.1 PR517.1 PR518.1 PU501.17
DAT_SMB: PBATT.6 PD1.1 PD3.2 PR20.1
DBC_EN: RX19.1 UE1.25
DBC_EN_R: JLVDS.21 RX19.2 RX23.1
DC_TEST_A3_B3: UC1.A3 UC1.B3
DC_TEST_A4: T168.1(TP-1) UC1.A4
DC_TEST_A60: T169.1(TP-1) UC1.A60
DC_TEST_A61_B61: UC1.A61 UC1.B61
DC_TEST_A62: T170.1(TP-1) UC1.A62
DC_TEST_AV1: T171.1(TP-1) UC1.AV1
DC_TEST_AW1: T172.1(TP-1) UC1.AW1
DC_TEST_AW63: T173.1(TP-1) UC1.AW63
DC_TEST_AY2_AW2: UC1.AW2 UC1.AY2
DC_TEST_AY3_AW3: UC1.AW3 UC1.AY3
DC_TEST_AY60: T166.1(TP-1) UC1.AY60
DC_TEST_AY61_AW61: UC1.AW61 UC1.AY61
DC_TEST_AY62_AW62: UC1.AW62 UC1.AY62
DC_TEST_B62_B63: UC1.B62 UC1.B63
DC_TEST_C1_C2: UC1.C1 UC1.C2
DDI1_LANE_N0: CX18.2 UC1.C54
DDI1_LANE_N1: CX16.2 UC1.B58
DDI1_LANE_N2: CX14.2 UC1.B55
DDI1_LANE_N3: CX12.2 UC1.A57
DDI1_LANE_P0: CX19.2 UC1.C55
DDI1_LANE_P1: CX17.2 UC1.C58
DDI1_LANE_P2: CX15.2 UC1.A55
DDI1_LANE_P3: CX13.2 UC1.B57
DDR3_DRAMRST#: CD3.1 CD34.1 JDIMM1.30 JDIMM2.30 RD5.1
DDR3_DRAMRST#_CPU: CC35.1 RD3.2 RD5.2 UC1.AV15
DDR_A_BS0: JDIMM1.109 UC1.AU35
DDR_A_BS1: JDIMM1.108 UC1.AV35
DDR_A_BS2: JDIMM1.79 UC1.AY41
DDR_A_CAS#: JDIMM1.115 UC1.AU34
DDR_A_D0: JDIMM1.129 UC1.AH63
DDR_A_D1: JDIMM1.131 UC1.AH62
DDR_A_D2: JDIMM1.141 UC1.AK63
DDR_A_D3: JDIMM1.140 UC1.AK62
DDR_A_D4: JDIMM1.132 UC1.AH61
DDR_A_D5: JDIMM1.130 UC1.AH60
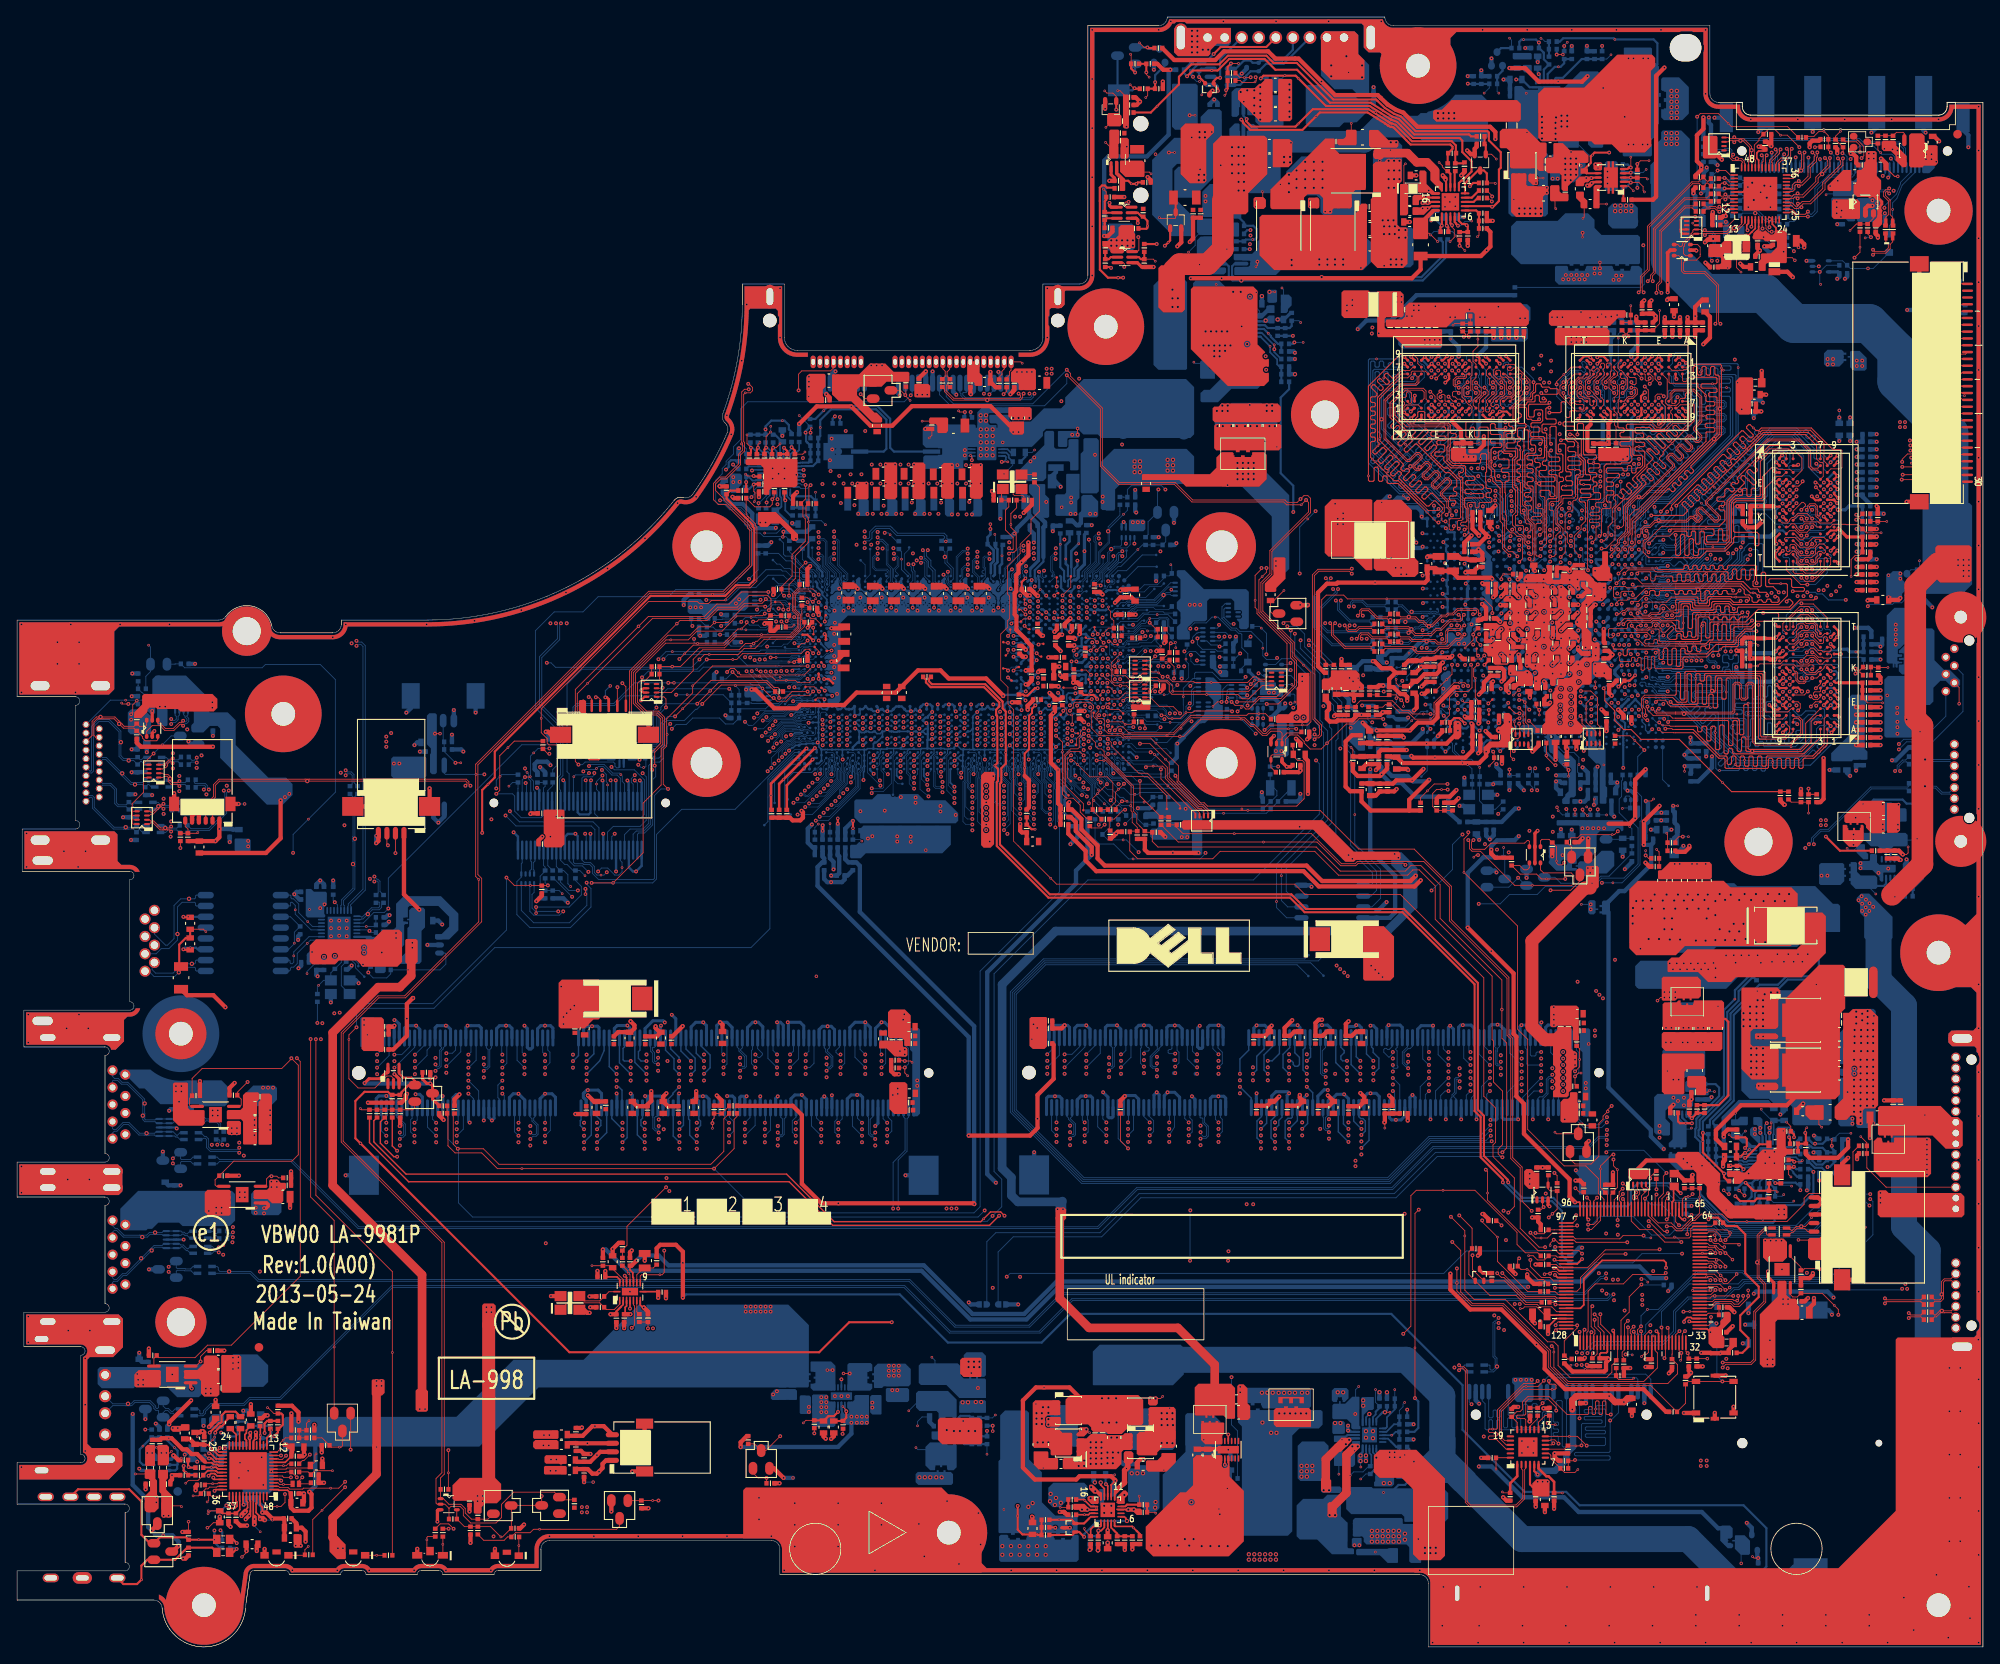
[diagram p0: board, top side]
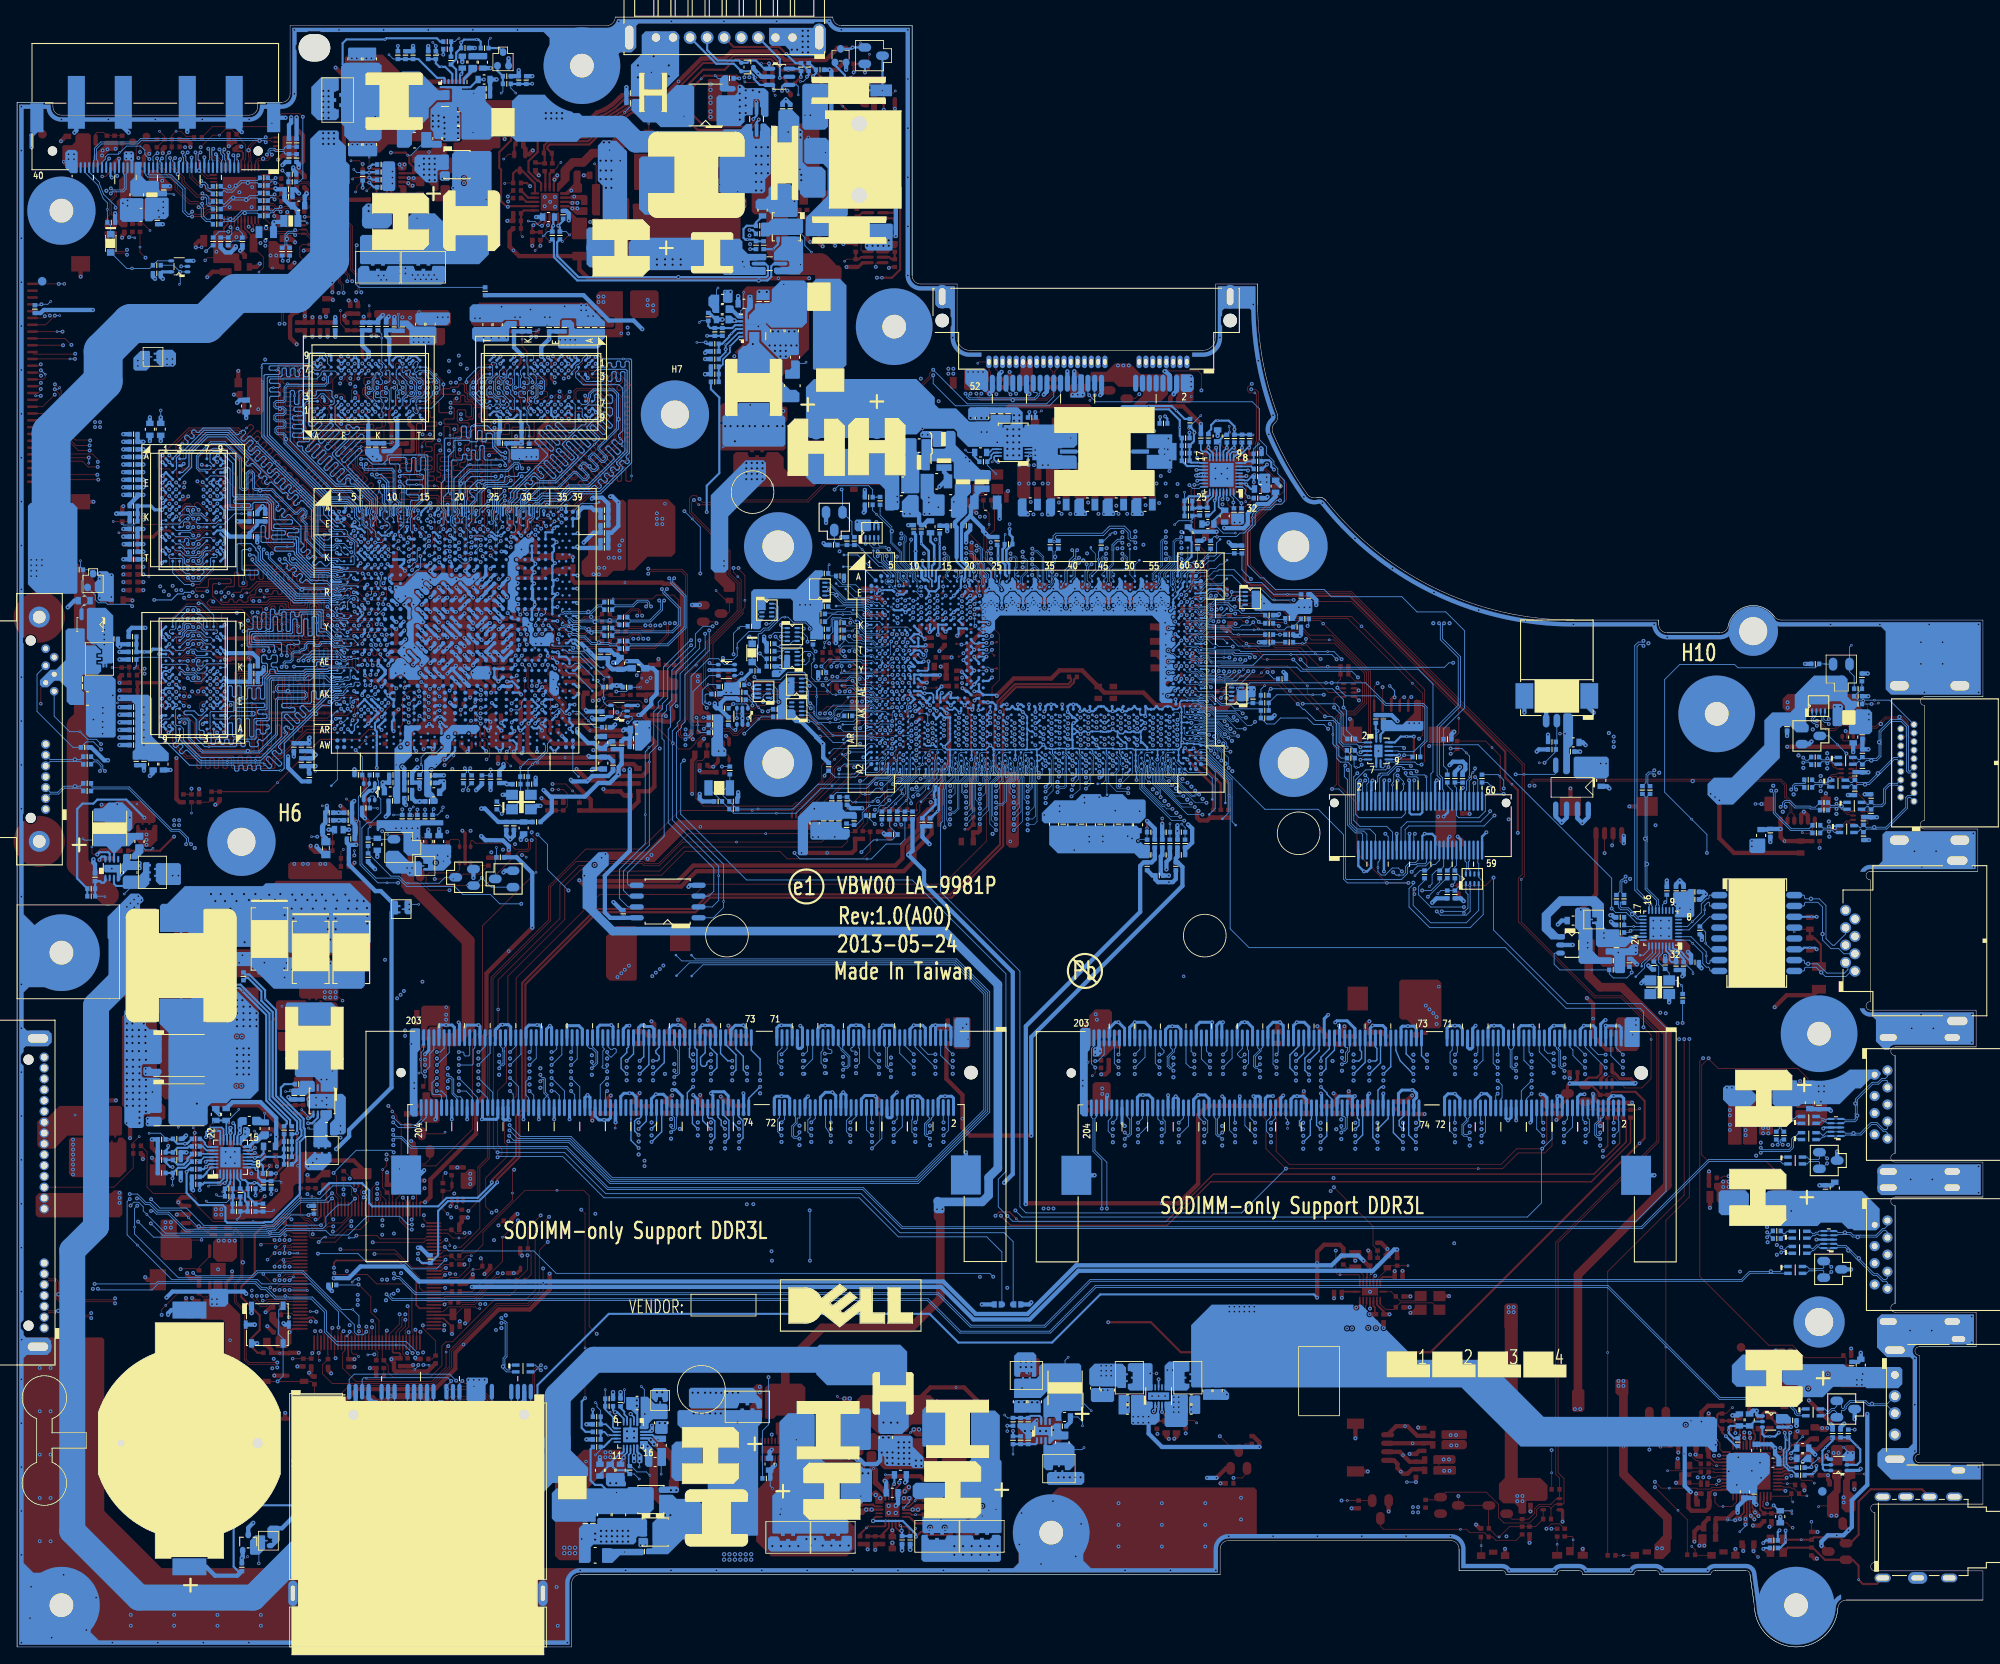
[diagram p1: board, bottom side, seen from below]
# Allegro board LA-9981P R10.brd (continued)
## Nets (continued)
DDR_A_D6: JDIMM1.143 UC1.AK61
DDR_A_D7: JDIMM1.142 UC1.AK60
DDR_A_D8: JDIMM1.7 UC1.AM63
DDR_A_D9: JDIMM1.4 UC1.AM62
DDR_A_D10: JDIMM1.17 UC1.AP63
DDR_A_D11: JDIMM1.18 UC1.AP62
DDR_A_D12: JDIMM1.6 UC1.AM61
DDR_A_D13: JDIMM1.5 UC1.AM60
DDR_A_D14: JDIMM1.15 UC1.AP61
DDR_A_D15: JDIMM1.16 UC1.AP60
DDR_A_D16: JDIMM1.159 UC1.AP58
DDR_A_D17: JDIMM1.157 UC1.AR58
DDR_A_D18: JDIMM1.146 UC1.AM57
DDR_A_D19: JDIMM1.148 UC1.AK57
DDR_A_D20: JDIMM1.149 UC1.AL58
DDR_A_D21: JDIMM1.147 UC1.AK58
DDR_A_D22: JDIMM1.158 UC1.AR57
DDR_A_D23: JDIMM1.160 UC1.AN57
DDR_A_D24: JDIMM1.24 UC1.AP55
DDR_A_D25: JDIMM1.22 UC1.AR55
DDR_A_D26: JDIMM1.36 UC1.AM54
DDR_A_D27: JDIMM1.34 UC1.AK54
DDR_A_D28: JDIMM1.23 UC1.AL55
DDR_A_D29: JDIMM1.21 UC1.AK55
DDR_A_D30: JDIMM1.33 UC1.AR54
DDR_A_D31: JDIMM1.35 UC1.AN54
DDR_A_D32: JDIMM1.166 UC1.AY58
DDR_A_D33: JDIMM1.165 UC1.AW58
DDR_A_D34: JDIMM1.175 UC1.AY56
DDR_A_D35: JDIMM1.174 UC1.AW56
DDR_A_D36: JDIMM1.163 UC1.AV58
DDR_A_D37: JDIMM1.164 UC1.AU58
DDR_A_D38: JDIMM1.177 UC1.AV56
DDR_A_D39: JDIMM1.176 UC1.AU56
DDR_A_D40: JDIMM1.42 UC1.AY54
DDR_A_D41: JDIMM1.41 UC1.AW54
DDR_A_D42: JDIMM1.50 UC1.AY52
DDR_A_D43: JDIMM1.51 UC1.AW52
DDR_A_D44: JDIMM1.39 UC1.AV54
DDR_A_D45: JDIMM1.40 UC1.AU54
DDR_A_D46: JDIMM1.52 UC1.AV52
DDR_A_D47: JDIMM1.53 UC1.AU52
DDR_A_D48: JDIMM1.69 UC1.AK40
DDR_A_D49: JDIMM1.67 UC1.AK42
DDR_A_D50: JDIMM1.59 UC1.AM43
DDR_A_D51: JDIMM1.57 UC1.AM45
DDR_A_D52: JDIMM1.56 UC1.AK45
DDR_A_D53: JDIMM1.58 UC1.AK43
DDR_A_D54: JDIMM1.68 UC1.AM40
DDR_A_D55: JDIMM1.70 UC1.AM42
DDR_A_D56: JDIMM1.192 UC1.AM46
DDR_A_D57: JDIMM1.194 UC1.AK46
DDR_A_D58: JDIMM1.183 UC1.AM49
DDR_A_D59: JDIMM1.182 UC1.AK49
DDR_A_D60: JDIMM1.191 UC1.AM48
DDR_A_D61: JDIMM1.193 UC1.AK48
DDR_A_D62: JDIMM1.181 UC1.AM51
DDR_A_D63: JDIMM1.180 UC1.AK51
DDR_A_DQS0: JDIMM1.137 UC1.AJ62
DDR_A_DQS1: JDIMM1.12 UC1.AN61
DDR_A_DQS2: JDIMM1.154 UC1.AN58
DDR_A_DQS3: JDIMM1.29 UC1.AN55
DDR_A_DQS4: JDIMM1.171 UC1.AW57
DDR_A_DQS5: JDIMM1.47 UC1.AW53
DDR_A_DQS6: JDIMM1.64 UC1.AL42
DDR_A_DQS7: JDIMM1.188 UC1.AL49
DDR_A_DQS#0: JDIMM1.135 UC1.AJ61
DDR_A_DQS#1: JDIMM1.10 UC1.AN62
DDR_A_DQS#2: JDIMM1.152 UC1.AM58
DDR_A_DQS#3: JDIMM1.27 UC1.AM55
DDR_A_DQS#4: JDIMM1.169 UC1.AV57
DDR_A_DQS#5: JDIMM1.45 UC1.AV53
DDR_A_DQS#6: JDIMM1.62 UC1.AL43
DDR_A_DQS#7: JDIMM1.186 UC1.AL48
DDR_A_MA0: JDIMM1.98 UC1.AU36
DDR_A_MA1: JDIMM1.97 UC1.AY37
DDR_A_MA2: JDIMM1.96 UC1.AR38
DDR_A_MA3: JDIMM1.95 UC1.AP36
DDR_A_MA4: JDIMM1.92 UC1.AU39
DDR_A_MA5: JDIMM1.91 UC1.AR36
DDR_A_MA6: JDIMM1.90 UC1.AV40
DDR_A_MA7: JDIMM1.86 UC1.AW39
DDR_A_MA8: JDIMM1.89 UC1.AY39
DDR_A_MA9: JDIMM1.85 UC1.AU40
DDR_A_MA10: JDIMM1.107 UC1.AP35
DDR_A_MA11: JDIMM1.84 UC1.AW41
DDR_A_MA12: JDIMM1.83 UC1.AU41
DDR_A_MA13: JDIMM1.119 UC1.AR35
DDR_A_MA14: JDIMM1.80 UC1.AV42
DDR_A_MA15: JDIMM1.78 UC1.AU42
DDR_A_RAS#: JDIMM1.110 UC1.AY34
DDR_A_WE#: JDIMM1.113 UC1.AW34
DDR_B_BS0: JDIMM2.109 UC1.AL35
DDR_B_BS1: JDIMM2.108 UC1.AM36
DDR_B_BS2: JDIMM2.79 UC1.AU49
DDR_B_CAS#: JDIMM2.115 UC1.AM33
DDR_B_D0: JDIMM2.132 UC1.AY31
DDR_B_D1: JDIMM2.131 UC1.AW31
DDR_B_D2: JDIMM2.140 UC1.AY29
DDR_B_D3: JDIMM2.141 UC1.AW29
DDR_B_D4: JDIMM2.129 UC1.AV31
DDR_B_D5: JDIMM2.130 UC1.AU31
DDR_B_D6: JDIMM2.142 UC1.AV29
DDR_B_D7: JDIMM2.143 UC1.AU29
DDR_B_D8: JDIMM2.5 UC1.AY27
DDR_B_D9: JDIMM2.6 UC1.AW27
DDR_B_D10: JDIMM2.15 UC1.AY25
DDR_B_D11: JDIMM2.17 UC1.AW25
DDR_B_D12: JDIMM2.4 UC1.AV27
DDR_B_D13: JDIMM2.16 UC1.AU27
DDR_B_D14: JDIMM2.7 UC1.AV25
DDR_B_D15: JDIMM2.18 UC1.AU25
DDR_B_D16: JDIMM2.146 UC1.AM29
DDR_B_D17: JDIMM2.148 UC1.AK29
DDR_B_D18: JDIMM2.160 UC1.AL28
DDR_B_D19: JDIMM2.158 UC1.AK28
DDR_B_D20: JDIMM2.149 UC1.AR29
DDR_B_D21: JDIMM2.147 UC1.AN29
DDR_B_D22: JDIMM2.157 UC1.AR28
DDR_B_D23: JDIMM2.159 UC1.AP28
DDR_B_D24: JDIMM2.24 UC1.AN26
DDR_B_D25: JDIMM2.22 UC1.AR26
DDR_B_D26: JDIMM2.33 UC1.AR25
DDR_B_D27: JDIMM2.35 UC1.AP25
DDR_B_D28: JDIMM2.21 UC1.AK26
DDR_B_D29: JDIMM2.23 UC1.AM26
DDR_B_D30: JDIMM2.34 UC1.AK25
DDR_B_D31: JDIMM2.36 UC1.AL25
DDR_B_D32: JDIMM2.166 UC1.AY23
DDR_B_D33: JDIMM2.165 UC1.AW23
DDR_B_D34: JDIMM2.174 UC1.AY21
DDR_B_D35: JDIMM2.175 UC1.AW21
DDR_B_D36: JDIMM2.163 UC1.AV23
DDR_B_D37: JDIMM2.164 UC1.AU23
DDR_B_D38: JDIMM2.176 UC1.AV21
DDR_B_D39: JDIMM2.177 UC1.AU21
DDR_B_D40: JDIMM2.39 UC1.AY19
DDR_B_D41: JDIMM2.41 UC1.AW19
DDR_B_D42: JDIMM2.53 UC1.AY17
DDR_B_D43: JDIMM2.52 UC1.AW17
DDR_B_D44: JDIMM2.42 UC1.AV19
DDR_B_D45: JDIMM2.40 UC1.AU19
DDR_B_D46: JDIMM2.51 UC1.AV17
DDR_B_D47: JDIMM2.50 UC1.AU17
DDR_B_D48: JDIMM2.191 UC1.AR21
DDR_B_D49: JDIMM2.183 UC1.AR22
DDR_B_D50: JDIMM2.194 UC1.AL21
DDR_B_D51: JDIMM2.180 UC1.AM22
DDR_B_D52: JDIMM2.181 UC1.AN22
DDR_B_D53: JDIMM2.193 UC1.AP21
DDR_B_D54: JDIMM2.192 UC1.AK21
DDR_B_D55: JDIMM2.182 UC1.AK22
DDR_B_D56: JDIMM2.57 UC1.AN20
DDR_B_D57: JDIMM2.59 UC1.AR20
DDR_B_D58: JDIMM2.69 UC1.AK18
DDR_B_D59: JDIMM2.67 UC1.AL18
DDR_B_D60: JDIMM2.58 UC1.AK20
DDR_B_D61: JDIMM2.56 UC1.AM20
DDR_B_D62: JDIMM2.70 UC1.AR18
DDR_B_D63: JDIMM2.68 UC1.AP18
DDR_B_DQS0: JDIMM2.137 UC1.AV30
DDR_B_DQS1: JDIMM2.12 UC1.AW26
DDR_B_DQS2: JDIMM2.154 UC1.AM28
DDR_B_DQS3: JDIMM2.29 UC1.AM25
DDR_B_DQS4: JDIMM2.171 UC1.AV22
DDR_B_DQS5: JDIMM2.47 UC1.AW18
DDR_B_DQS6: JDIMM2.188 UC1.AM21
DDR_B_DQS7: JDIMM2.64 UC1.AM18
DDR_B_DQS#0: JDIMM2.135 UC1.AW30
DDR_B_DQS#1: JDIMM2.10 UC1.AV26
DDR_B_DQS#2: JDIMM2.152 UC1.AN28
DDR_B_DQS#3: JDIMM2.27 UC1.AN25
DDR_B_DQS#4: JDIMM2.169 UC1.AW22
DDR_B_DQS#5: JDIMM2.45 UC1.AV18
DDR_B_DQS#6: JDIMM2.186 UC1.AN21
DDR_B_DQS#7: JDIMM2.62 UC1.AN18
DDR_B_MA0: JDIMM2.98 UC1.AP40
DDR_B_MA1: JDIMM2.97 UC1.AR40
DDR_B_MA2: JDIMM2.96 UC1.AP42
DDR_B_MA3: JDIMM2.95 UC1.AR42
DDR_B_MA4: JDIMM2.92 UC1.AR45
DDR_B_MA5: JDIMM2.91 UC1.AP45
DDR_B_MA6: JDIMM2.90 UC1.AW46
DDR_B_MA7: JDIMM2.86 UC1.AY46
DDR_B_MA8: JDIMM2.89 UC1.AY47
DDR_B_MA9: JDIMM2.85 UC1.AU46
DDR_B_MA10: JDIMM2.107 UC1.AK36
DDR_B_MA11: JDIMM2.84 UC1.AV47
DDR_B_MA12: JDIMM2.83 UC1.AU47
DDR_B_MA13: JDIMM2.119 UC1.AK33
DDR_B_MA14: JDIMM2.80 UC1.AR46
DDR_B_MA15: JDIMM2.78 UC1.AP46
DDR_B_RAS#: JDIMM2.110 UC1.AM35
DDR_B_WE#: JDIMM2.113 UC1.AK35
DDR_CKE0_DIMMA: JDIMM1.73 UC1.AU43
DDR_CKE1_DIMMA: JDIMM1.74 UC1.AW43
DDR_CKE2_DIMMB: JDIMM2.73 UC1.AY49
DDR_CKE3_DIMMB: JDIMM2.74 UC1.AU50
DDR_CS0_DIMMA#: JDIMM1.114 UC1.AP33
DDR_CS1_DIMMA#: JDIMM1.121 UC1.AR32
DDR_CS2_DIMMB#: JDIMM2.114 UC1.AM32
DDR_CS3_DIMMB#: JDIMM2.121 UC1.AK32
DDR_PG_CTRL: U2303.2 UC1.AV61
DDR_XDP_SMBCLK_R1: JXDP1.53 RP46.7
DDR_XDP_SMBDAT_R1: JXDP1.51 RP46.8
DDR_XDP_WLAN_TP_SMBCLK: JDIMM1.202 JDIMM2.202 JMINI.30 JTP.5 QC1.1 R2332.2 RP46.2 RX6.1
DDR_XDP_WLAN_TP_SMBDAT: JDIMM1.200 JDIMM2.200 JMINI.32 JTP.6 QC1.4 R2331.2 RP46.1 RX31.1
DEVSLP0: RC11.1 RS8.1 UC1.P2
DGPU_HOLD_RST#: RC77.2 UC1.N4 UV13.1
DGPU_PRSNT#: RC99.1 RC100.2 UC1.R7
DGPU_PWROK: PR808.2 PU800.2 RC73.2 UC1.U6 UE1.18
DH_1.35V: PQ200.4 PU200.17
DH_CHG: PQ703.4 PQ704.4 PU701.18
DISPOFF#: DX1.1 JLVDS.37 RX9.1
DL_1.35V: PQ201.4 PU200.15
DL_CHG: PQ705.4 PU701.15
DPB_HPD: QX5.3 RX14.1 UC1.C8
DPC_HPD: RC84.2 UC1.A8
DPLL_PVSS: RV247.2 RV248.2 UV1.AN32
DQMA#0: UV1.A32 UV18.D3
DQMA#1: UV1.C32 UV19.D3
DQMA#2: UV1.D23 UV19.E7
DQMA#3: UV1.E22 UV18.E7
DQMA#4: UV1.C14 UV21.E7
DQMA#5: UV1.A14 UV20.E7
DQMA#6: UV1.E10 UV20.D3
DQMA#7: UV1.D9 UV21.D3
DQMB#0: UV1.H3 UV22.D3
DQMB#1: UV1.H1 UV23.D3
DQMB#2: UV1.T3 UV22.E7
DQMB#3: UV1.T5 UV23.E7
DQMB#4: UV1.AE4 UV25.E7
DQMB#5: UV1.AF5 UV24.D3
DQMB#6: UV1.AK6 UV24.E7
DQMB#7: UV1.AK5 UV25.D3
DRAM_RST#: RV138.2 RV143.1 UV18.T2 UV19.T2 UV20.T2 UV21.T2 UV22.T2 UV23.T2 UV24.T2 UV25.T2
DRAM_RST#_R: RV144.2 RV145.2 UV1.AH11
DROOP_CPU: PC513.2 PR529.2 PR532.1 PU501.25
DSWODVREN: R2337.1 R2338.1 UC1.AW7
EC_ENVDD: RX8.2 UE1.71
EC_LID_OUT#: UC1.AD6 UE1.101
EC_MUTE#: UA1.47 UE1.83
EC_ON: PR102.1 UE1.112
EC_RSMRST#: RC41.1 RE2.2 UE1.100
EC_RST#: CE11.1 RE8.1 UE1.37
EC_RX: JMINI.51 RM13.1 UE1.31
EC_SCI#: UC1.AM2 UE1.20
EC_SMB_CK1: PR18.2 PR714.1 RP36.4 UE1.77
EC_SMB_CK2: QH1.6 QV15.6 QX6.3 RP36.2 UE1.79
EC_SMB_DA1: PR20.2 PR715.1 RP36.3 UE1.78
EC_SMB_DA2: QH1.3 QV15.3 QX6.6 RP36.1 UE1.80
EC_SMI#: RC107.1 UC1.V1 UE1.15
EC_SPI_CLK_R: T185.1(TP-1) UE1.126
EC_SPI_CS0#: T186.1(TP-1) UE1.128
EC_SPI_MISO_1: T184.1(TP-1) UE1.120
EC_SPI_MOSI_1: T183.1(TP-1) UE1.119
EC_TX: JMINI.49 RM11.2 UE1.30
ECAGND: CE7.2 CE9.1 LE2.2 PH1.2 UE1.69
EDID_CLK: JLVDS.34 RP56.3 UX4.46
EDID_DATA: JLVDS.35 RP56.4 UX4.45
EDP_AUX: RX39.2 RX40.1
EDP_AUX#: RX37.2 RX38.1
EDP_BIA_PWM: RC72.2 RC75.2 RC81.2 RX36.1 RX49.1 UX4.21
EDP_BKLCTL: RC81.1 UC1.B8
EDP_COMP: RC71.2 UC1.D20
EDP_CPU_AUX: CX43.1 RX25.1 UC1.B45
EDP_CPU_AUX#: CX44.1 RX30.2 UC1.A45
EDP_CPU_HPD: QC3.2 RC105.1 RX35.1 RX52.1 UX4.1
EDP_CPU_LANE_N0: CX46.1 UC1.C45
EDP_CPU_LANE_N1: CX39.1 UC1.A47
EDP_CPU_LANE_P0: CX42.1 UC1.B46
EDP_CPU_LANE_P1: CX38.1 UC1.B47
EDP_DISP_UTIL: RC72.1 UC1.A43
EDP_HPD_PANEL: RX52.2 RX53.1
EDP_N0: RX43.2 RX44.1
EDP_N1: RX47.2 RX48.1
EDP_P0: RX41.2 RX42.1
EDP_P1: RX45.2 RX46.1
EN_0.675VSP: PC203.1 PR202.2 PU200.7
EN_1.35V: PC202.1 PR201.2 PU200.8
EN_+1.2VSP: PC1104.1 PR1103.2 PU1100.3
EN_DFAN1: UE1.70 UE3.4
EN_INVPWR: QX1.2 UE1.68
EN_PCIE: PC1307.1 PR1300.2 PR1304.1 PU1300.5
ENVDD_PCH: RC87.2 RX51.1 UC1.C6 UE1.19
ENVDD_R: RX7.1 RX8.1 UX1.3
ERP_LOT6: PC5.1 PQ1.2 PR1.2 PR2.1 UE1.73
F-IMAX: PR504.1 PR505.2 PU501.10
FAN_SPEED1: CE24.1 CE29.1 JFAN.2 RE50.2 UE1.28
FB_1.5VSP: PC404.2 PR402.1 PR403.2 PU400.1
FB_1.8VSP: PC604.2 PR602.1 PR603.2 PU600.1
FB_1.35V: PR204.1 PR207.1 PU200.6
FB_3V: PC102.2 PR107.2 PR109.2 PU100.4
FB_5V: PC108.1 PR104.1 PR106.1 PU100.2
FB_+1.2VSP: PR1107.1 PR1108.1 PU1100.4
FB_PCIE: PC1306.2 PR1301.1 PR1302.2 PU1300.6
GCLK_VRTC: CG5.1 RG1.2 UG1.10
GENLK_CLK: T80.1(TP-1) UV1.AD29
GENLK_VSYNC: T81.1(TP-1) UV1.AC29
GFX_FB-1: PC806.1 PR821.2
GFX_FB-2: PC817.1 PR818.2
GPIO21_BBEN: T78.1(TP-1) UV1.AJ14
GPIO24_TRSTB: RP47.8 UV1.AM23
GPIO25_TDI: RP47.7 UV1.AN23
GPIO26_TCK: RP47.5 UV1.AK23
GPIO27_TMS: RP47.6 UV1.AL24
GPIO28_TDO: T79.1(TP-1) UV1.AM24
GPU_B+: PC804.1 PC805.1 PC808.1 PC831.1 PC832.1 PL800.2 PQ800.5 PQ803.5 PR823.2
GPU_GPIO0: RV75.2 UV1.AH20
GPU_GPIO1: RV76.2 UV1.AH18
GPU_GPIO2: RP60.8 UV1.AN16
GPU_GPIO6: PR1212.1 PR1213.2 PR1214.1 UV1.AG32
GPU_GPIO8: RP60.6 UV1.AJ13
GPU_GPIO9: RP60.5 UV1.AH15
GPU_GPIO11: RV81.2 UV1.AK16
GPU_GPIO12: RV82.2 UV1.AL16
GPU_GPIO13: RV83.2 UV1.AM16
GPU_RST#: RV66.1 UV1.AA30 UV13.4
GPU_THERMAL_D+: UV1.AF29
GPU_THERMAL_D-: UV1.AG29
GPU_VGA_B: T87.1(TP-1) UV1.AF37
GPU_VGA_DDCCLK: T90.1(TP-1) UV1.AK30
GPU_VGA_DDCDAT: T91.1(TP-1) UV1.AK29
GPU_VGA_G: T86.1(TP-1) UV1.AE36
GPU_VGA_HSYNC: T88.1(TP-1) UV1.AC36
GPU_VGA_R: T85.1(TP-1) UV1.AD39
GPU_VGA_VSYNC: T89.1(TP-1) UV1.AC38
GPU_VID1: PR810.1 PR819.2 PR828.2 UV1.AL13
GPU_VID2: PR812.1 PR826.2 PR834.2 UV1.AK14
GPU_VID3: PR807.1 PR835.2 PR836.2 UV1.AM13
GPU_VID4: PR809.1 PR837.2 PR838.2 UV1.AJ17
GPU_VID5: PR806.1 PR839.2 PR840.2 UV1.AJ16
H_CATERR#: RC58.2 UC1.K61
H_CPU_SVIDALRT#: R254.1 UC1.L62
H_CPU_SVIDCLK: C5212.1 R248.2 UC1.N63
H_CPU_SVIDDATA: R256.2 R257.1 UC1.L63
H_CPUPWRGD: CC27.1 RC48.1 RC66.1 UC1.C61
H_PROCHOT#: CE19.1 PQ2.6 PQ3.3 PQ3.6 RC60.2 RC67.1 RE44.2 UE2.4
H_PROCHOT#_R: RC67.2 UC1.K63
H_THERMTRIP#: R2346.2 UC1.D60
H_VCCST_PWRGD_XDP: JXDP1.39 RC48.2
H_VR_READY: PR524.2 PR540.2 PU501.3 R251.1
HDA_SPKR: DA8.3 RC121.2 UC1.V2
HDD_DET#: JHDD.12 RC9.1 UC1.AG6
HDMI_HPLUG: CX20.1 JHDMI.19 RX15.2 RX34.1
HOST_ALERT1_R_N: RC120.2 UC1.AD7
HPOUT-L: RA55.1 UA1.32
HPOUT-R: RA56.1 UA1.33
I2C0_SCL: RP53.4 UC1.F3
I2C0_SDA: RP53.3 UC1.F2
I2C1_SCL_TCH_PAD: RP53.2 UC1.F1
I2C1_SDA_TCH_PAD: RP53.1 UC1.G4
ILMT_1.05V: PR304.2 PR306.1 PU300.3
ILMT_VDDCI: PR1202.1 PR1203.2 PU1200.3
IMON_CPU: PC508.2 PR501.2 PU501.13
IMVP_PWRGD: PC523.1 PR540.1 UE1.85
INT-SPK-L+: LA6.1 UA1.42
INT-SPK-L-: LA5.1 UA1.43
INT-SPK-R+: LA4.1 UA1.45
INT-SPK-R-: LA3.1 UA1.44
INTRUDER#: RC7.2 UC1.AU6
ISOLATEB: RL33.2 RL35.2 UL1.20
ISUM+: PC819.1 PC820.1 PR816.1 PR827.1 PR829.2 PU800.10
ISUM-: PR825.1 PU800.9
ISUM-1: PC819.2 PC820.2 PC821.2 PH800.2 PR825.2 PR827.2 PR830.2
ISUM-2: PH800.1 PR816.2
JACK_PLUG#: JHP.5 RA1.2 RA3.1 RA4.1
JACK_SENSE#: QA5.3 RA4.2 RA51.2
JHDD_P10: JHDD.10 RS7.2 RS8.2
KB_CAPS_PWR: JKB.4 RE60.2
KB_DET#: RC103.1 UC1.AN5
KB_LED_PWM: UE1.21
KB_RST#: RP43.8 UC1.V4 UE1.2
KSI0: JKB.22 UE1.55
KSI1: JKB.24 UE1.56
KSI2: JKB.26 UE1.57
KSI3: JKB.23 UE1.58
KSI4: JKB.27 UE1.59
KSI5: JKB.25 UE1.60
KSI6: JKB.28 UE1.61
KSI7: JKB.29 UE1.62
KSO0: JKB.13 UE1.39
KSO1: JKB.15 UE1.40
KSO2: JKB.14 UE1.41
KSO3: JKB.16 UE1.42
KSO4: JKB.20 UE1.43
KSO5: JKB.21 UE1.44
KSO6: JKB.18 UE1.45
KSO7: JKB.19 UE1.46
KSO8: JKB.17 UE1.47
KSO9: JKB.7 UE1.48
KSO10: JKB.5 UE1.49
KSO11: JKB.6 UE1.50
KSO12: JKB.12 UE1.51
KSO13: JKB.9 UE1.52
KSO14: JKB.8 UE1.53
KSO15: JKB.10 UE1.54
KSO16: JKB.11 UE1.81
LAN_CLKREQ#: RL37.1 RP42.8 UC1.AD1 UL1.12
LAN_X1_R: RG5.1 UG1.6
LCD_CBL_DET#: RC106.2 UC1.J3
LCD_TEST: JLVDS.33 UE1.72
LDO_3V: PC312.1 PR304.1 PU300.5
LDO_3V_VDDCI: PC1213.1 PR1203.1 PU1200.5
LG_3V: PQ102.4 PU100.11
LG_5V: PQ104.4 PU100.15
LG_+1.2VSP: PQ1101.4 PU1100.6
LID_SW#: CE30.1 JPWR.2 RE71.2 UE1.115
LINE1-L: CA67.1 UA1.22
LINE1-R: CA68.1 UA1.21
LINE1-VREFO-L: RA165.1 UA1.31
LINE1-VREFO-R: RA166.1 UA1.30
LINE-IN-L: LA8.2 RA55.2 RA80.2 RA83.1 RA165.2
LINE-IN-R: LA9.2 RA56.2 RA82.2 RA84.1 RA166.2
LPC_LAD0: UC1.AU14 UE1.10
LPC_LAD1: UC1.AW12 UE1.8
LPC_LAD2: UC1.AY12 UE1.7
LPC_LAD3: UC1.AW11 UE1.5
LPC_LFRAME#: UC1.AV12 UE1.4
LVDS_A0+: JLVDS.2 UX4.41
LVDS_A0-: JLVDS.1 UX4.42
LVDS_A1+: JLVDS.5 UX4.39
LVDS_A1-: JLVDS.4 UX4.40
LVDS_A2+: JLVDS.8 UX4.37
LVDS_A2-: JLVDS.7 UX4.38
LVDS_ACLK+: JLVDS.11 UX4.35
LVDS_ACLK-: JLVDS.10 UX4.36
LVDS_B0+: JLVDS.14 RX40.2 UX4.31
LVDS_B0-: JLVDS.13 RX38.2 UX4.32
LVDS_B1+: JLVDS.17 RX44.2 UX4.29
LVDS_B1-: JLVDS.16 RX42.2 UX4.30
LVDS_B2+: JLVDS.20 RX48.2 UX4.27
LVDS_B2-: JLVDS.19 RX46.2 UX4.28
LVDS_BCLK+: JLVDS.23 UX4.25
LVDS_BCLK-: JLVDS.22 UX4.26
LX_1.05V: PC302.2 PL301.1 PR302.1 PU300.10
LX_1.5VSP: PL400.1 PR405.1 PU400.6
LX_1.8VSP: PL600.1 PR605.1 PU600.6
LX_3V: PC104.1 PL100.1 PQ101.1 PQ101.2 PQ101.3 PQ102.5 PR113.1 PU100.8
LX_5V: PC110.2 PL101.1 PQ103.1 PQ103.2 PQ103.3 PQ104.5 PR112.1 PU100.18
LX_CHG: PC715.1 PC721.2 PL701.1 PQ703.1 PQ703.2 PQ703.3 PQ704.1 PQ704.2 PQ704.3 PQ705.5 PU701.19
LX_PCIE: PL1300.1 PR1303.1 PU1300.1 PU1300.2 PU1300.3
LX_VDDCI: PC1210.2 PL1200.1 PR1207.1 PU1200.10
M_CLK_DDR0: JDIMM1.101 UC1.AV37
M_CLK_DDR1: JDIMM1.102 UC1.AY36
M_CLK_DDR2: JDIMM2.101 UC1.AN38
M_CLK_DDR3: JDIMM2.102 UC1.AL38
M_CLK_DDR#0: JDIMM1.103 UC1.AU37
M_CLK_DDR#1: JDIMM1.104 UC1.AW36
M_CLK_DDR#2: JDIMM2.103 UC1.AM38
M_CLK_DDR#3: JDIMM2.104 UC1.AK38
M_ODT: CD64.1 QD2.3 R2348.1 R2349.1 R2350.1 R2352.1
M_ODT0: JDIMM1.116 R2348.2
M_ODT1: JDIMM1.120 R2349.2
M_ODT2: JDIMM2.116 R2350.2
M_ODT3: JDIMM2.120 R2352.2
MAA0: UV1.G24 UV18.N3 UV19.N3 UV20.N3 UV21.N3
MAA1: UV1.J23 UV18.P7 UV19.P7 UV20.P7 UV21.P7
MAA2: UV1.H24 UV18.P3 UV19.P3 UV20.P3 UV21.P3
MAA3: UV1.J24 UV18.N2 UV19.N2 UV20.N2 UV21.N2
MAA4: UV1.H26 UV18.P8 UV19.P8 UV20.P8 UV21.P8
MAA5: UV1.J26 UV18.P2 UV19.P2 UV20.P2 UV21.P2
MAA6: UV1.H21 UV18.R8 UV19.R8 UV20.R8 UV21.R8
MAA7: UV1.G21 UV18.R2 UV19.R2 UV20.R2 UV21.R2
MAA8: UV1.H19 UV18.T8 UV19.T8 UV20.T8 UV21.T8
MAA9: UV1.H20 UV18.R3 UV19.R3 UV20.R3 UV21.R3
MAA10: UV1.L13 UV18.L7 UV19.L7 UV20.L7 UV21.L7
MAA11: UV1.G16 UV18.R7 UV19.R7 UV20.R7 UV21.R7
MAA12: UV1.J16 UV18.N7 UV19.N7 UV20.N7 UV21.N7
MAA13: UV1.H23 UV18.T3 UV19.T3 UV20.T3 UV21.T3
MAA14: UV1.J19 UV18.T7 UV19.T7 UV20.T7 UV21.T7
MAB0: UV1.P8 UV22.N3 UV23.N3 UV24.N3 UV25.N3
MAB1: UV1.T9 UV22.P7 UV23.P7 UV24.P7 UV25.P7
MAB2: UV1.P9 UV22.P3 UV23.P3 UV24.P3 UV25.P3
MAB3: UV1.N7 UV22.N2 UV23.N2 UV24.N2 UV25.N2
MAB4: UV1.N8 UV22.P8 UV23.P8 UV24.P8 UV25.P8
MAB5: UV1.N9 UV22.P2 UV23.P2 UV24.P2 UV25.P2
MAB6: UV1.U9 UV22.R8 UV23.R8 UV24.R8 UV25.R8
MAB7: UV1.U8 UV22.R2 UV23.R2 UV24.R2 UV25.R2
MAB8: UV1.Y9 UV22.T8 UV23.T8 UV24.T8 UV25.T8
MAB9: UV1.W9 UV22.R3 UV23.R3 UV24.R3 UV25.R3
MAB10: UV1.AC8 UV22.L7 UV23.L7 UV24.L7 UV25.L7
MAB11: UV1.AC9 UV22.R7 UV23.R7 UV24.R7 UV25.R7
MAB12: UV1.AA7 UV22.N7 UV23.N7 UV24.N7 UV25.N7
MAB13: UV1.T8 UV22.T3 UV23.T3 UV24.T3 UV25.T3
MAB14: UV1.W8 UV22.T7 UV23.T7 UV24.T7 UV25.T7
MCT0: RL19.1 TL1.14
MCT1: RL20.1 TL1.11
MDA0: UV1.C37 UV18.A7
MDA1: UV1.C35 UV18.C8
MDA2: UV1.A35 UV18.B8
MDA3: UV1.E34 UV18.D7
MDA4: UV1.G32 UV18.A2
MDA5: UV1.D33 UV18.C3
MDA6: UV1.F32 UV18.C2
MDA7: UV1.E32 UV18.A3
MDA8: UV1.D31 UV19.A2
MDA9: UV1.F30 UV19.A3
MDA10: UV1.C30 UV19.C3
MDA11: UV1.A30 UV19.C2
MDA12: UV1.F28 UV19.A7
MDA13: UV1.C28 UV19.C8
MDA14: UV1.A28 UV19.B8
MDA15: UV1.E28 UV19.D7
MDA16: UV1.D27 UV19.G2
MDA17: UV1.F26 UV19.H3
MDA18: UV1.C26 UV19.E3
MDA19: UV1.A26 UV19.F2
MDA20: UV1.F24 UV19.H8
MDA21: UV1.C24 UV19.H7
MDA22: UV1.A24 UV19.F7
MDA23: UV1.E24 UV19.F8
MDA24: UV1.C22 UV18.H8
MDA25: UV1.A22 UV18.H7
MDA26: UV1.F22 UV18.F8
MDA27: UV1.D21 UV18.F7
MDA28: UV1.A20 UV18.H3
MDA29: UV1.F20 UV18.E3
MDA30: UV1.D19 UV18.F2
MDA31: UV1.E18 UV18.G2
MDA32: UV1.C18 UV21.H3
MDA33: UV1.A18 UV21.G2
MDA34: UV1.F18 UV21.H7
MDA35: UV1.D17 UV21.E3
MDA36: UV1.A16 UV21.F2
MDA37: UV1.F16 UV21.F8
MDA38: UV1.D15 UV21.F7
MDA39: UV1.E14 UV21.H8
MDA40: UV1.F14 UV20.H7
MDA41: UV1.D13 UV20.H8
MDA42: UV1.F12 UV20.F7
MDA43: UV1.A12 UV20.F8
MDA44: UV1.D11 UV20.H3
MDA45: UV1.F10 UV20.G2
MDA46: UV1.A10 UV20.F2
MDA47: UV1.C10 UV20.E3
MDA48: UV1.G13 UV20.C8
MDA49: UV1.H13 UV20.D7
MDA50: UV1.J13 UV20.A7
MDA51: UV1.H11 UV20.B8
MDA52: UV1.G10 UV20.C3
MDA53: UV1.G8 UV20.C2
MDA54: UV1.K9 UV20.A2
MDA55: UV1.K10 UV20.A3
MDA56: UV1.G9 UV21.C2
MDA57: UV1.A8 UV21.A3
MDA58: UV1.C8 UV21.C3
MDA59: UV1.E8 UV21.A2
MDA60: UV1.A6 UV21.D7
MDA61: UV1.C6 UV21.A7
MDA62: UV1.E6 UV21.B8
MDA63: UV1.A5 UV21.C8
MDB0: UV1.C5 UV22.D7
MDB1: UV1.C3 UV22.C8
MDB2: UV1.E3 UV22.B8
MDB3: UV1.E1 UV22.A7
MDB4: UV1.F1 UV22.C3
MDB5: UV1.F3 UV22.A3
MDB6: UV1.F5 UV22.C2
MDB7: UV1.G4 UV22.A2
MDB8: UV1.H5 UV23.A3
MDB9: UV1.H6 UV23.A2
MDB10: UV1.J4 UV23.C3
MDB11: UV1.K6 UV23.C2
MDB12: UV1.K5 UV23.A7
MDB13: UV1.L4 UV23.B8
MDB14: UV1.M6 UV23.C8
MDB15: UV1.M1 UV23.D7
MDB16: UV1.M3 UV22.H8
MDB17: UV1.M5 UV22.F8
MDB18: UV1.N4 UV22.H7
MDB19: UV1.P6 UV22.F7
MDB20: UV1.P5 UV22.E3
MDB21: UV1.R4 UV22.F2
MDB22: UV1.T6 UV22.G2
MDB23: UV1.T1 UV22.H3
MDB24: UV1.U4 UV23.G2
MDB25: UV1.V6 UV23.H3
MDB26: UV1.V1 UV23.F2
MDB27: UV1.V3 UV23.E3
MDB28: UV1.Y6 UV23.H8
MDB29: UV1.Y1 UV23.F8
MDB30: UV1.Y3 UV23.F7
MDB31: UV1.Y5 UV23.H7
MDB32: UV1.AA4 UV25.H7
MDB33: UV1.AB6 UV25.H8
MDB34: UV1.AB1 UV25.F8
MDB35: UV1.AB3 UV25.F7
MDB36: UV1.AD6 UV25.F2
MDB37: UV1.AD1 UV25.G2
MDB38: UV1.AD3 UV25.E3
MDB39: UV1.AD5 UV25.H3
MDB40: UV1.AF1 UV24.C2
MDB41: UV1.AF3 UV24.A2
MDB42: UV1.AF6 UV24.A3
MDB43: UV1.AG4 UV24.C3
MDB44: UV1.AH5 UV24.D7
MDB45: UV1.AH6 UV24.A7
MDB46: UV1.AJ4 UV24.B8
MDB47: UV1.AK3 UV24.C8
MDB48: UV1.AF8 UV24.G2
MDB49: UV1.AF9 UV24.H3
MDB50: UV1.AG8 UV24.F2
MDB51: UV1.AG7 UV24.E3
MDB52: UV1.AK9 UV24.F7
MDB53: UV1.AL7 UV24.F8
MDB54: UV1.AM8 UV24.H8
MDB55: UV1.AM7 UV24.H7
MDB56: UV1.AK1 UV25.B8
MDB57: UV1.AL4 UV25.A7
MDB58: UV1.AM6 UV25.C8
MDB59: UV1.AM1 UV25.C3
MDB60: UV1.AN4 UV25.A3
MDB61: UV1.AP3 UV25.A2
MDB62: UV1.AP1 UV25.C2
MDB63: UV1.AP5 UV25.D7
MDI0+: TL1.8 UL1.1
MDI0-: TL1.7 UL1.2
MDI1+: TL1.2 UL1.4
MDI1-: TL1.1 UL1.5
MDO0+: JLAN.1 TL1.9
MDO0-: JLAN.2 TL1.10
MDO1+: JLAN.3 TL1.15
MDO1-: JLAN.6 TL1.16
ME_EN: RC8.1 RE326.1 UE1.99
ME_SUS_PWR_ACK: RC27.2 RC42.1 UE1.34
ME_SUS_PWR_ACK_R: RC35.1 RC42.2 UC1.AV4
MECH#1: T82.1(TP-1) UV1.A39
MECH#2: T83.1(TP-1) UV1.AW1
MECH#3: T84.1(TP-1) UV1.AW39
MEM_SMBCLK: QC1.6 RP40.1 UC1.AP2
MEM_SMBDATA: QC1.3 RP40.2 UC1.AH1
MIC1-L: CA74.1 UA1.19
MIC_CLK: CA22.1 JLVDS.30 LA1.2
MIC_CLK_C: LA1.1 UA1.3
MIC_DATA: JLVDS.32 UA1.2
MIC_IN: LA7.2 QA6.3 RA53.1 UA1.18
MIC_IN_R: CA38.1 DA12.3 JHP.4 LA7.1
MIIC_SCL: RX169.2 RX171.1 UX4.48
MIIC_SDA: RX168.2 RX170.1 UX4.47
MS_BS: JREAD.15 UR1.22
MS_CLK_SD_WP: CR5.1 JREAD.5 JREAD.22 RR3.2
MS_CLK_SD_WP_R: RR3.1 UR1.8
MS_D0: JREAD.12 UR1.16
MS_D1_SD_D3: JREAD.3 JREAD.13 UR1.20
MS_D2_SD_CLK: CR6.1 JREAD.10 JREAD.14 RR2.2
MS_D2_SD_CLK_R: RR2.1 UR1.15
MS_D3: JREAD.7 UR1.12
MS_INS#: CR10.1 JREAD.8 UR1.9
O-USR: PR502.1 PR506.2 PU501.9
OCP_CPU: PR501.1 PR503.2 PU501.12
ODD_DA#: CS17.1 JODD.11 RP54.1 UC1.T3
ODD_DETECT#: JODD.8 RP37.1 UC1.V6
ODD_EN: CS16.1 QS2.3 QS3.1 RS6.1
ODD_EN#: QS3.2 UC1.Y1
ODTA0: UV1.J21 UV18.K1 UV19.K1
ODTA1: UV1.G19 UV20.K1 UV21.K1
ODTB0: UV1.T7 UV22.K1 UV23.K1
ODTB1: UV1.W7 UV24.K1 UV25.K1
ON/OFFBTN#: CE20.1 JPWR.3 RE49.1 SW1.3 SW1.4 SW2.3 SW2.4 UE1.114
PACIN#: QV14.5 QV14.6 RV74.2
PANEL_BKLEN: UC1.A9 UE1.76
PBTN_OUT#: RC49.1 UC1.AL7 UE1.106
PC_BEEP: DA8.1 RA19.1 RA79.2
PCH_AUDIO_EN: RC116.1 UC1.P1
PCH_AZ_BITCLK: R2359.2 UC1.AW8
PCH_AZ_CODEC_BITCLK: CC5.1 R2355.1 R2359.1 UA1.6
PCH_AZ_CODEC_RST#: R2358.1 RA6.1 UA1.11
PCH_AZ_CODEC_SDIN0: RA130.1 UC1.AY10
PCH_AZ_CODEC_SDOUT: R2356.1 UA1.5
PCH_AZ_CODEC_SYNC: R2357.1 UA1.10
PCH_AZ_RST#: R2358.2 UC1.AU8
PCH_AZ_SDOUT: R2356.2 RC3.2 RC8.2 UC1.AU11
PCH_AZ_SYNC: R2357.2 UC1.AV11
PCH_BATLOW#: RC31.2 UC1.AN4
PCH_DPWROK: RC33.1 RE37.1 UC1.AV5
PCH_GPIO9: RC125.2 UC1.AM3
PCH_GPIO12: T182.1(TP-1) UC1.AM7
PCH_GPIO14: T126.1(TP-1) UC1.AH4
PCH_GPIO25: T127.1(TP-1) UC1.AM4
PCH_GPIO35: RP37.2 UC1.U1
PCH_GPIO37: RP37.3 UC1.AC1
PCH_GPIO44: RC104.1 UC1.AK4
PCH_GPIO46: RC124.2 UC1.AG3
PCH_GPIO47: T174.1(TP-1) UC1.AB6
PCH_GPIO48: T124.1(TP-1) UC1.U4
PCH_GPIO49: T125.1(TP-1) UC1.Y3
PCH_GPIO66: RC118.2 RC122.1 UC1.D3
PCH_GPIO83: T177.1(TP-1) UC1.R6
PCH_GPIO84: T176.1(TP-1) UC1.L6
PCH_GPIO85: T175.1(TP-1) UC1.N6
PCH_GPIO89: T178.1(TP-1) UC1.N7
PCH_GPIO90: T179.1(TP-1) UC1.K2
PCH_GPIO93: T180.1(TP-1) UC1.J2
PCH_GPIO94: T181.1(TP-1) UC1.G1
PCH_HOT#: R2330.2 RE7.1 UC1.AU4
PCH_INTVRMEN: RC1.2 RC2.1 UC1.AV7
PCH_JTAG_JTAGX: RC59.1 RC62.2 RC130.1 UC1.AE63
PCH_JTAG_RST#: R2341.2 RC57.2 UC1.AU62
PCH_JTAG_TCK: RC65.2 RC135.1 RP46.4 UC1.AE62
PCH_JTAG_TDI: RC44.1 RP48.8 UC1.AD61
PCH_JTAG_TDO: RC43.1 RC63.2 RP48.7 UC1.AE61
PCH_JTAG_TMS: RC46.1 RP48.6 UC1.AD62
PCH_OPI_COMP: RC101.1 UC1.AW15
PCH_PCIE_RCOMP: RC91.2 UC1.A27
PCH_PLTRST#: CC33.1 UC1.AG7 UC3.1 UC3.2
PCH_PWR_EN: R416.1 RE36.1
PCH_PWROK: CC34.1 CE31.1 RE18.1 RP50.2 RP50.3 UE1.32
PCH_PWROK_R: RP50.7 UC1.AY7
PCH_RSMRST#_R: RC33.2 RC41.2 UC1.AW6
PCH_RTCRST#: CC4.2 CMOS1.2 RC6.2 UC1.AU7
PCH_RTCX1: CC1.2 RC4.1 RG3.2 UC1.AW5 YC1.1
PCH_RTCX1_R: RG3.1 UG1.9
PCH_RTCX2: CC2.2 RC4.2 UC1.AY5 YC1.2
PCH_SMB_ALERT#: R2329.2 UC1.AN2
PCH_SPI_CLK: R2333.2 UC1.AA3
PCH_SPI_CLK_R: C2326.1 R2333.1 U2302.6
PCH_SPI_CS0#: U2302.1 UC1.Y7
PCH_SPI_HOLD1#: RP39.4 U2302.7
PCH_SPI_HOLD#: R2335.2 RP39.5 UC1.AF1
PCH_SPI_MISO: RP39.7 UC1.AA4
PCH_SPI_MISO_1: RP39.2 U2302.2
PCH_SPI_MOSI: RP39.8 UC1.AA2
PCH_SPI_MOSI_1: RP39.1 U2302.5
PCH_SPI_WP1#: RP39.3 U2302.3
PCH_SPI_WP#: R2334.2 RP39.6 UC1.Y6
PCH_X1_R: RG6.1 UG1.5
PCIE_B+: PC1301.1 PJP1301.1 PU1300.8 PU1300.9 PU1300.10
PCIE_CRX_C_GTX_N0: CV44.2 UV1.Y32
PCIE_CRX_C_GTX_N1: CV46.2 UV1.W32
PCIE_CRX_C_GTX_N2: CV48.2 UV1.U32
PCIE_CRX_C_GTX_N3: CV50.2 UV1.U29
PCIE_CRX_C_GTX_P0: CV43.2 UV1.Y33
PCIE_CRX_C_GTX_P1: CV45.2 UV1.W33
PCIE_CRX_C_GTX_P2: CV47.2 UV1.U33
PCIE_CRX_C_GTX_P3: CV49.2 UV1.U30
PCIE_PRX_LANTX_N3: CL31.1 UC1.G11
PCIE_PRX_LANTX_N3_C: CL31.2 UL1.18
PCIE_PRX_LANTX_P3: CL30.1 UC1.F11
PCIE_PRX_LANTX_P3_C: CL30.2 UL1.17
PCIE_PRX_WLANTX_N4: JMINI.23 UC1.F13
PCIE_PRX_WLANTX_P4: JMINI.25 UC1.G13
PCIE_PTX_LANRX_N3: CC32.1 UL1.14
PCIE_PTX_LANRX_N3_C: CC32.2 UC1.C29
PCIE_PTX_LANRX_P3: CC40.1 UL1.13
PCIE_PTX_LANRX_P3_C: CC40.2 UC1.B30
PCIE_PTX_WLANRX_N4: CM49.1 UC1.B29
PCIE_PTX_WLANRX_N4_C: CM49.2 JMINI.31
PCIE_PTX_WLANRX_P4: CM44.1 UC1.A29
PCIE_PTX_WLANRX_P4_C: CM44.2 JMINI.33
PCIE_WAKE#: RC97.2 RL34.2 UE1.29 UL1.21
PCIE_WAKE#_R: RC34.2 RC97.1 UC1.AJ5
PECI_EC: RE43.2 UC1.N62
PECI_KB9012: RE43.1 UE1.118
PEG_CLKREQ#: QV28.1 RP42.6 UC1.U5
PEG_CRX_GTX_N0: CV44.1 UC1.F10
PEG_CRX_GTX_N1: CV46.1 UC1.F8
PEG_CRX_GTX_N2: CV48.1 UC1.H10
PEG_CRX_GTX_N3: CV50.1 UC1.E6
PEG_CRX_GTX_P0: CV43.1 UC1.E10
PEG_CRX_GTX_P1: CV45.1 UC1.E8
PEG_CRX_GTX_P2: CV47.1 UC1.G10
PEG_CRX_GTX_P3: CV49.1 UC1.F6
PEG_CTX_GRX_C_N0: CC18.1 UC1.C23
PEG_CTX_GRX_C_N1: CC20.1 UC1.B23
PEG_CTX_GRX_C_N2: CC22.1 UC1.B21
PEG_CTX_GRX_C_N3: CC24.1 UC1.B22
PEG_CTX_GRX_C_P0: CC19.1 UC1.C22
PEG_CTX_GRX_C_P1: CC21.1 UC1.A23
PEG_CTX_GRX_C_P2: CC23.1 UC1.C21
PEG_CTX_GRX_C_P3: CC25.1 UC1.A21
PEG_CTX_GRX_N0: CC18.2 UV1.Y37
PEG_CTX_GRX_N1: CC20.2 UV1.W36
PEG_CTX_GRX_N2: CC22.2 UV1.V37
PEG_CTX_GRX_N3: CC24.2 UV1.U36
PEG_CTX_GRX_P0: CC19.2 UV1.AA38
PEG_CTX_GRX_P1: CC21.2 UV1.Y35
PEG_CTX_GRX_P2: CC23.2 UV1.W38
PEG_CTX_GRX_P3: CC25.2 UV1.V35
PLT_RST#: CC30.1 CE36.1 JMINI.22 R159.1 RC51.1 UC3.4 UE1.13 UL1.19 UV13.2
PM_APWROK_R: RP50.6 UC1.AB5
PROC_OPI_RCOMP: RC134.1 UC1.AY15
PROJECT_ID: RC112.2 RC113.1 UC1.L5
PS_0: CV335.1 RV201.1 RV243.2 UV1.AM34
PS_1: CV329.1 RV237.2 RV238.1 UV1.AD31
PS_2: CV331.1 RV239.2 RV240.1 UV1.AG31
PS_3: CV333.1 RV241.2 RV242.1 UV1.AD33
PS_ID: PR3.1 PR4.2 UE1.16
PSID: PJPDC.1 PL2.1
PSID-1: PQ5.2 PR6.1 PR9.2
PSID-2: PQ5.1 PQ6.2 PR8.2
PSID-3: PQ6.3 PR4.1
PWM1: PU501.6 PU502.8
PWR_PWM_LED#: RD14.1 UE1.92
PWR_SRC_ON: CX4.2 QX2.3 RX2.2 RX3.1
PXS_PWREN: PR601.2 PR803.1 PR1103.1 PR1206.2 PR1300.1 QV24.2 QV25.2 RP54.4 RV105.2 UC1.P4
PXS_PWREN#: QV25.1 RV109.2
QSA0: UV1.C34 UV18.C7
QSA1: UV1.D29 UV19.C7
QSA2: UV1.D25 UV19.F3
QSA3: UV1.E20 UV18.F3
QSA4: UV1.E16 UV21.F3
QSA5: UV1.E12 UV20.F3
QSA6: UV1.J10 UV20.C7
QSA7: UV1.D7 UV21.C7
QSA#0: UV1.A34 UV18.B7
QSA#1: UV1.E30 UV19.B7
QSA#2: UV1.E26 UV19.G3
QSA#3: UV1.C20 UV18.G3
QSA#4: UV1.C16 UV21.G3
QSA#5: UV1.C12 UV20.G3
QSA#6: UV1.J11 UV20.B7
QSA#7: UV1.F8 UV21.B7
QSB0: UV1.F6 UV22.C7
QSB1: UV1.K3 UV23.C7
QSB2: UV1.P3 UV22.F3
QSB3: UV1.V5 UV23.F3
QSB4: UV1.AB5 UV25.F3
QSB5: UV1.AH1 UV24.C7
QSB6: UV1.AJ9 UV24.F3
QSB7: UV1.AM5 UV25.C7
QSB#0: UV1.G7 UV22.B7
QSB#1: UV1.K1 UV23.B7
QSB#2: UV1.P1 UV22.G3
QSB#3: UV1.W4 UV23.G3
QSB#4: UV1.AC4 UV25.G3
QSB#5: UV1.AH3 UV24.B7
QSB#6: UV1.AJ8 UV24.G3
QSB#7: UV1.AM3 UV25.B7
RASA0#: UV1.K23 UV18.J3 UV19.J3
RASA1#: UV1.K19 UV20.J3 UV21.J3
RASB0#: UV1.T10 UV22.J3 UV23.J3
RASB1#: UV1.Y10 UV24.J3 UV25.J3
REGN: PC709.1 PD701.2 PR707.1 PR713.1 PU701.16
RF_+1.2VSP: PR1105.1 PU1100.5
RING2: LA10.2 RA1109.1 UA1.17
RING2_R: CA40.1 DA12.2 JHP.3 LA10.1
RREF: RR1.1 UR1.1
RSVD_AL1: T136.1(TP-1) UC1.AL1
RSVD_AM11: T137.1(TP-1) UC1.AM11
RSVD_AP7: T139.1(TP-1) UC1.AP7
RSVD_AT2: T128.1(TP-1) UC1.AT2
RSVD_AU10: T141.1(TP-1) UC1.AU10
RSVD_AU15: T142.1(TP-1) UC1.AU15
RSVD_AU44: T132.1(TP-1) UC1.AU44
RSVD_AV44: T134.1(TP-1) UC1.AV44
RSVD_AW14: T144.1(TP-1) UC1.AW14
RSVD_AY14: T145.1(TP-1) UC1.AY14
RSVD_D15: T135.1(TP-1) UC1.D15
RSVD_F22: T138.1(TP-1) UC1.F22
RSVD_H22: T140.1(TP-1) UC1.H22
RSVD_J21: T143.1(TP-1) UC1.J21
RSVD_N23: T129.1(TP-1) UC1.N23
RSVD_R23: T130.1(TP-1) UC1.R23
RSVD_T23: T131.1(TP-1) UC1.T23
RSVD_U10: T133.1(TP-1) UC1.U10
RTC_VOUT: CG6.1 RG2.2 UG1.14
RUNPWROK: CC29.1 UC4.1 UC4.4 UC4.10 UC4.13 UE1.36
SATA_ACT#: RD15.1 UC1.U3
SATA_IREF: RC126.1 UC1.A12
SATA_PRX_DTX_N0: CS109.1 JHDD.5
SATA_PRX_DTX_N0_C: CS109.2 UC1.J5
SATA_PRX_DTX_N1: CS14.1 JODD.5
SATA_PRX_DTX_N1_C: CS14.2 UC1.J8
SATA_PRX_DTX_P0: CS108.1 JHDD.6
SATA_PRX_DTX_P0_C: CS108.2 UC1.H5
SATA_PRX_DTX_P1: CS15.1 JODD.6
SATA_PRX_DTX_P1_C: CS15.2 UC1.H8
SATA_PTX_DRX_N0: CS106.1 JHDD.3
SATA_PTX_DRX_N0_C: CS106.2 UC1.B15
SATA_PTX_DRX_N1: CS9.1 JODD.3
SATA_PTX_DRX_N1_C: CS9.2 UC1.A17
SATA_PTX_DRX_P0: CS105.1 JHDD.2
SATA_PTX_DRX_P0_C: CS105.2 UC1.A15
SATA_PTX_DRX_P1: CS8.1 JODD.2
SATA_PTX_DRX_P1_C: CS8.2 UC1.B17
SATA_RCOMP: RC131.1 UC1.C12
SD_CD#: CR9.1 JREAD.20 UR1.13
SD_CMD: CR11.1 JREAD.6 UR1.18
SD_D0: JREAD.18 UR1.11
SD_D1: JREAD.19 UR1.10
SD_D2: JREAD.1 UR1.21
SERIRQ: RC102.2 UC1.T4 UE1.3
SIO_EXT_SCI#: RC98.1 UC1.N5
SIO_SLP_S0#: UC1.AF3 UE1.89
SIO_SLP_S3#: CE27.1 UC1.AT4 UE1.6
SIO_SLP_S4#: T104.1(TP-1) UC1.AJ6 UE1.84
SIO_SLP_S5#: CE28.1 T103.1(TP-1) UC1.AP5 UE1.14
SKIP#: PR535.1 PU501.7
SKIP#1: PR535.2 PU502.1
SLATE_MODE_R: RC110.1 UC1.AL4
SLEWA_CPU: PR513.2 PR514.1 PU501.15
SM_RCOMP0: RC68.1 UC1.AU60
SM_RCOMP1: RC69.1 UC1.AV60
SM_RCOMP2: RC70.1 UC1.AU61
SML0CLK: RP49.1 UC1.AN1
SML0DATA: RP49.2 UC1.AK1
SML1_SMBCLK: QH1.1 RP40.3 UC1.AU3
SML1_SMBDATA: QH1.4 RP40.4 UC1.AH3
SNB_1.05V: PC301.1 PR302.2
SNB_VDDCI: PC1212.1 PR1207.2
SNUB_PCIE: PC1304.1 PR1303.2
SPK_L1-_CONN: CA30.1 JSPK.3 LA5.2
SPK_L2+_CONN: CA29.1 JSPK.4 LA6.2
SPK_R1-_CONN: CA32.1 JSPK.1 LA3.2
SPK_R2+_CONN: CA31.1 JSPK.2 LA4.2
SRTCRST#: CC3.2 ME1.2 RC5.2 UC1.AV6
SUS_STAT#/LPCPD#: RC29.2 UC1.AG4
SUSACK#: RC28.2 RC35.2 RC37.1 UE1.97
SUSACK#_R: RC37.2 UC1.AK2
SUSCLK: T102.1(TP-1) UC1.AE6
SUSP: Q8.1 Q2307.2 Q2308.2 R10.2
SUSP#: PR300.2 PR401.2 Q8.2 R16.1 R2313.1 R2318.1 UE1.116
SW_1.35V: PC200.2 PC207.1 PL200.2 PQ200.1 PQ200.2 PQ200.3 PQ201.5 PU200.16
SW_+1.2VSP: PC1103.2 PL1101.1 PQ1100.1 PQ1100.2 PQ1100.3 PQ1101.5 PR1104.1 PU1100.8
SW_CPU2: PC520.1 PL502.1 PU502.4
SW_VGA_CORE: PC807.2 PC815.1 PL802.1 PQ800.1 PQ800.2 PQ800.3 PQ801.5 PQ802.5 PQ803.1 PQ803.2 PQ803.3 PR829.1 PU800.16
SYS_PWROK: CC31.1 CE32.1 RC52.1 RP50.1 UE1.86
SYS_PWROK_R: RP50.8 UC1.AG2
SYS_PWROK_XDP: CC16.1 JXDP1.47 RC52.2 RC64.1
SYS_RESET#: RC26.2 UC1.AC3
SYSON: CE26.1 PR201.1 UE1.95
TDI_IREF: RC133.2 UC1.B12
TDI_XDP: JXDP1.56 RC44.2 RC45.1
TDI_XDP_R: RC45.2 RC63.1 UC4.5
TDO_XDP: JXDP1.52 RC43.2 RC62.1 RP44.4 UC4.2
TESTEN: RV133.2 UV1.AD28
THERM_CPU: PC509.1 PH502.2 PR512.2 PU501.14
THM_ALERT#: UV1.AG30
TL_BKOFF#: DX1.2 RX50.2 UX2.4
TL_BKOFF#_R: RX33.1 UX2.2 UX4.44
TL_ENVDD: RX7.2 RX51.2 UX4.20
TL_INVT_PWM: JLVDS.36 RX26.1 RX49.2 UX4.19
TMDS_L_TX0N: CX25.1 JHDMI.9 LX3.2
TMDS_L_TX0P: CX26.1 JHDMI.7 LX3.3
TMDS_L_TX1N: CX27.1 JHDMI.6 LX4.2
TMDS_L_TX1P: CX28.1 JHDMI.4 LX4.3
TMDS_L_TX2N: CX29.1 JHDMI.3 LX5.2
TMDS_L_TX2P: CX30.1 JHDMI.1 LX5.3
TMDS_L_TXCN: CX23.1 JHDMI.12 LX2.2
TMDS_L_TXCP: CX24.1 JHDMI.10 LX2.3
TMDS_TX0N: CX14.1 LX3.1 RP59.4
TMDS_TX0P: CX15.1 LX3.4 RP59.3
TMDS_TX1N: CX16.1 LX4.1 RP58.4
TMDS_TX1P: CX17.1 LX4.4 RP58.3
TMDS_TX2N: CX18.1 LX5.1 RP58.2
TMDS_TX2P: CX19.1 LX5.4 RP58.1
TMDS_TXCN: CX12.1 LX2.1 RP59.2
TMDS_TXCP: CX13.1 LX2.4 RP59.1
TMS_XDP: JXDP1.58 RC46.2 UC4.9
TON_1.35V: PR208.2 PU200.9
TOUCH_PANEL_INTR#: RP43.7 UC1.P3
TOUCH_RST: RX1.1 UE1.38
TOUCH_RST_N_GYRO_INT1: RC76.2 UC1.L1
TOUCH_RST_R: JTOUCH.6 RX1.2 RX24.2
TOUCHPAD_INTR#: RC74.2 UC1.U7
TP_CLK: JTP.2 RE9.2 UE1.87
TP_DATA: JTP.3 RE10.2 UE1.88
TP_DC_TEST_B2: T167.1(TP-1) UC1.B2
TRIP_+1.2VSP: PR1102.2 PU1100.2
TRST#_XDP: JXDP1.54 UC4.12
TS_FDO: RV235.2 RV236.1 UV1.AK32
UG_3V: PQ101.4 PU100.10
UG_5V: PQ103.4 PU100.16
UG_+1.2VSP: PQ1100.4 PU1100.9
UG_VGA_CORE: PQ800.4 PQ803.4 PU800.15
USB3RN1_JUSB2: LI4.1 UC1.G20
USB3RN1_JUSB2_R: DI4.1 DI4.10 JUSB2.5 LI4.2
USB3RN2_JUSB1: LI1.1 UC1.E18
USB3RN2_JUSB1_R: DI1.1 DI1.10 JUSB1.5 LI1.2
USB3RP1_JUSB2: LI4.4 UC1.H20
USB3RP1_JUSB2_R: DI4.2 DI4.9 JUSB2.6 LI4.3
USB3RP2_JUSB1: LI1.4 UC1.F18
USB3RP2_JUSB1_R: DI1.2 DI1.9 JUSB1.6 LI1.3
USB3TN1_JUSB2: CI10.2 UC1.C33
USB3TN1_JUSB2_C: CI10.1 LI6.1
USB3TN1_JUSB2_R: DI4.4 DI4.7 JUSB2.8 LI6.2
USB3TN2_JUSB1: CI3.2 UC1.B33
USB3TN2_JUSB1_C: CI3.1 LI3.1
USB3TN2_JUSB1_R: DI1.4 DI1.7 JUSB1.8 LI3.2
USB3TP1_JUSB2: CI11.2 UC1.B34
USB3TP1_JUSB2_C: CI11.1 LI6.4
USB3TP1_JUSB2_R: DI4.5 DI4.6 JUSB2.9 LI6.3
USB3TP2_JUSB1: CI4.2 UC1.A33
USB3TP2_JUSB1_C: CI4.1 LI3.4
USB3TP2_JUSB1_R: DI1.5 DI1.6 JUSB1.9 LI3.3
USB20_CAM_N7: LX6.1 RX21.1 UC1.AR13
USB20_CAM_N7_R: JLVDS.28 LX6.2 RX21.2
USB20_CAM_P7: LX6.4 RX22.1 UC1.AP13
USB20_CAM_P7_R: JLVDS.27 LX6.3 RX22.2
USB20_CR_N6: LR2.1 UC1.AP11
USB20_CR_N6_R: LR2.2 UR1.2
USB20_CR_P6: LR2.4 UC1.AN11
USB20_CR_P6_R: LR2.3 UR1.3
USB20_JUSB1_N1: LI2.1 UC1.AR7
USB20_JUSB1_N1_R: DI2.2 JUSB1.2 LI2.2
USB20_JUSB1_P1: LI2.4 UC1.AT7
USB20_JUSB1_P1_R: DI2.3 JUSB1.3 LI2.3
USB20_JUSB2_N0: LI5.1 UC1.AN8
USB20_JUSB2_N0_R: DI5.2 JUSB2.2 LI5.2
USB20_JUSB2_P0: LI5.4 UC1.AM8
USB20_JUSB2_P0_R: DI5.3 JUSB2.3 LI5.3
USB20_JUSB3_N2: LI7.1 UC1.AR8
USB20_JUSB3_N2_R: DI7.2 JUSB3.2 LI7.2
USB20_JUSB3_P2: LI7.4 UC1.AP8
USB20_JUSB3_P2_R: DI7.3 JUSB3.3 LI7.3
USB20_MINI1_N4: JMINI.36 UC1.AM15
USB20_MINI1_P4: JMINI.38 UC1.AL15
USB20_TOUCH_N5: JTOUCH.2 UC1.AM13
USB20_TOUCH_P5: JTOUCH.3 UC1.AN13
USB20_USBDB_N3: LI10.1 UC1.AR10
USB20_USBDB_N3_R: JDB.5 LI10.2
USB20_USBDB_P3: LI10.4 UC1.AT10
USB20_USBDB_P3_R: JDB.4 LI10.3
USB_EN#: CI13.1 CI16.1 CI25.1 CI26.1 UE1.26 UI2.4 UI3.4 UI4.4 UI5.4
USB_OC0#: CI15.1 CI17.1 RP55.1 UC1.AL3 UI2.5 UI3.5
USB_OC1#: CI24.1 CI32.1 RP55.2 UC1.AT1 UI4.5 UI5.5
USB_OC2#: RP55.3 UC1.AH2
USB_OC3#: RP55.4 UC1.AV3
USBRBIAS: RC90.1 UC1.AJ10 UC1.AJ11
VCIN0_PH: PH1.1 PR24.1 UE1.109
VCIN1_PH: PC13.2 PR23.1 PR26.2 PR27.2 UE1.102
VCOUT0_PH#: PC100.1 PR100.2 PR101.2 PR102.2 UE1.104
VCOUT1_PH: PR30.1 RE47.2 UE1.103 UE2.2
VGA_CLKREQ#_R: QV28.3 RV199.2 UV1.AN13
VGA_SMB_CK2: QV15.1 RV90.2 RV252.1
VGA_SMB_CK2_R: RV252.2 UV1.AJ23
VGA_SMB_DA2: QV15.4 RV91.2 RV251.1
VGA_SMB_DA2_R: RV251.2 UV1.AH23
VGA_X1_R: RG4.1 UG1.12
VL: PC106.1 PU100.13
VR12.5_VR_ON_R: R250.2 UC1.F60
VR_ENABLE: PC522.1 PR522.1 PU501.8
VR_HOT#: PC506.2 PR533.1 PU501.30 RE44.1
VR_ON: C80.1 CE34.1 DE1.3 PR522.2 R250.1 RE1.2 RE12.2
VR_ON_EC: RE12.1 UE1.121
VR_READY_R: R251.2 UC1.C59
VR_SVID_ALRT#: PR528.2 PU501.32 R252.2 R254.2
VR_SVID_CLK: PR526.2 PU501.31 R248.1
VR_SVID_DAT: PR530.2 PU501.1 R257.2
VREF_CPU: PC507.1 PH502.1 PR502.2 PR504.2 PR507.2 PR514.2 PR531.1 PU501.27
VREFC_A1: CV227.1 RV157.2 RV167.1 UV18.M8
VREFC_A1_B: CV275.1 RV183.2 RV191.1 UV22.M8
VREFC_A2: CV228.1 RV158.2 RV168.1 UV19.M8
VREFC_A2_B: CV276.1 RV184.2 RV192.1 UV23.M8
VREFC_A3: CV230.1 RV160.2 RV170.1 UV20.M8
VREFC_A3_B: CV278.1 RV186.2 RV194.1 UV24.M8
VREFC_A4: CV232.1 RV162.2 RV172.1 UV21.M8
VREFC_A4_B: CV280.1 RV188.2 RV196.1 UV25.M8
VREFD_Q1: CV226.1 RV156.2 RV166.1 UV18.H1
VREFD_Q1_B: CV274.1 RV182.2 RV190.1 UV22.H1
VREFD_Q2: CV229.1 RV159.2 RV169.1 UV19.H1
VREFD_Q2_B: CV277.1 RV185.2 RV193.1 UV23.H1
VREFD_Q3: CV231.1 RV161.2 RV171.1 UV20.H1
VREFD_Q3_B: CV279.1 RV187.2 RV195.1 UV24.H1
VREFD_Q4: CV233.1 RV163.2 RV173.1 UV21.H1
VREFD_Q4_B: CV281.1 RV189.2 RV197.1 UV25.H1
VTTREF_1.35V: PC210.1 PU200.4
WEA0#: UV1.K26 UV18.L3 UV19.L3
WEA1#: UV1.L15 UV20.L3 UV21.L3
WEB0#: UV1.N10 UV22.L3 UV23.L3
WEB1#: UV1.AB11 UV24.L3 UV25.L3
WL_BT_LED: QD20.2 RD50.1 UE1.1
WL_BT_LED#: QD20.1 RD18.1 RD51.2
WL_BT_LED#_EC: QD18.1 QD19.1 RD46.2 RD49.2 RD51.1 RD52.1 UD1.4 UE1.64
WL_BT_LED#_EC2: RD48.2 UE1.74
WL_LED#: JMINI.44 QD18.3 RD45.2 RD48.1 UD1.1
WL_OFF#: QM30.3 RP54.3 UC1.AT5
WLAN_CLKREQ#: JMINI.7 RP42.7 UC1.N1
WLAN_RADIO_DIS#_R: JMINI.20 QM30.1 RM110.2
WOL_EN: RL27.2 RL38.1 UE1.98 UL2.3
XDP_DBRESET#: CC17.1 JXDP1.48 RC26.1 RC362.2
XDP_OBS0_R: JXDP1.21 RC141.1 UC1.J60
XDP_OBS1_R: JXDP1.23 RC141.2 UC1.H60
XDP_PRDY#: JXDP1.5 UC1.J62
XDP_PREQ#: JXDP1.3 RP44.3 UC1.K62
XDP_RST#_R: JXDP1.46 RC51.2
XDP_TCK: RP45.2 UC1.E60
XDP_TCLK: JXDP1.57 RC59.2 RC65.1 RP46.5
XDP_TDI: RP44.2 UC1.F63 UC4.6
XDP_TDO: RP45.1 UC1.F62 UC4.3
XDP_TMS: RP44.1 UC1.E61 UC4.8
XDP_TRST#: R2341.1 RC57.1 RP45.3 UC1.E59 UC4.11
XTAL24_IN: CC6.2 RC12.2 RG6.2 UC1.A25 YC2.3
XTAL24_OUT: CC7.2 RC12.1 UC1.B25 YC2.1
XTALIN: CV95.1 RG7.2 RV97.1 UV1.AV33 YV1.1
XTALIN_R: CG11.1 RG4.2 RG7.1
XTALOUT: CV94.1 RV97.2 UV1.AU34 YV1.3
XTLI: CL36.2 RG8.2 UL1.29 YL2.1
XTLI_R: CG7.1 RG5.2 RG8.1
XTLO: CL37.2 UL1.28 YL2.3
N60378: RV151.1 UV19.L8
N60382: RV152.1 UV20.L8
N60386: RV153.1 UV21.L8
N60390: RV150.1 UV18.L8
N60394: CV234.1 RV164.2 RV165.2
N60402: CV225.1 RV154.2 RV155.2
N65637: RV177.1 UV23.L8
N65641: RV178.1 UV24.L8
N65645: RV179.1 UV25.L8
N65649: RV176.1 UV22.L8
N65653: CV273.1 RV180.2 RV181.2
N65661: CV272.1 RV174.2 RV175.2
N14128350: PR1110.2 PU1100.1
N16988653: PC605.1 PJP600.2 PU600.3
N16988706: PC601.1 PR605.2
N17002462: PC1200.1 PR1201.1 PR1206.1 PU1200.1
N17002482: PR1204.1 PR1209.1 PR1211.1 PU1200.4
N17002518: PR1208.2 PR1209.2 PR1210.1
N17002625: PC1210.1 PR1200.2
N17045846: PC807.1 PR802.2
N17045965: PR842.1 PU800.28
N17045986: PC809.2 PC813.2 PC817.2 PR813.2 PR820.1 PR846.1 PU800.7
N17046050: PR824.2 PU800.13
N17046121: PQ801.4 PQ802.4 PU800.18
N17046167: PC809.1 PC816.2 PR833.1 PR845.1 PU800.8
N17159315: RV84.1 UV1.AB34
N17216117: RV89.2 UV1.AM17
N17407779: CE12.1 R2354.1
N17434554: RE36.2 UE1.107
N17434577: RE7.2 UE1.66
N17438484: CA21.1 R2355.2
N17494823: CA1.1 CA2.1 QA5.2 RA3.2
N17607640: PC300.1 PR300.1 PR301.1 PU300.1
N17607660: PC307.2 PR305.2 PR307.1 PU300.4
N17608587: PC302.1 PR303.2
N17777752: RV244.1 RV245.1 UV1.V28 UV1.W29
N17839157: RV246.1 UV1.AF30
N17841799: RV247.1 UV1.AF31
N18009245: PC708.1 PC717.2 PR704.1 PU701.1
N18009258: PC719.1 PC722.2 PR710.2 PR716.3
N18009264: PL702.1 PR702.4
N18009271: PC707.1 PC717.1 PR717.1 PU701.2
N18009295: PC722.1 PR708.2 PR716.2
N18009369: PR714.2 PU701.9
N18009411: PQ702.4 PR706.1
N18009417: PC715.2 PR722.1
N18009452: PC723.1 PQ708.2 PR724.2
N18009461: PR715.2 PU701.8
N18107051: RV127.1 UV1.AM39
N18262754: RV207.1 UV1.AF33
N18284053: PJPDC.2 PJPDC.3 PL4.1
N18923200: DC1.2 RC10.1
N19505504: T117.1(TP-1) UC1.AD4
N19607621: QX5.2 RX15.1
N19636367: QA6.2 RA6.2 RA7.2
N19792312: QA5.5 QA5.6 RA2.2
N19794620: QA6.5 QA6.6 RA5.2
N21178712: PQ1.3 PR5.2
N21178859: PC1302.1 PU1300.7
N21219517: RV64.2 UV1.AH16
N21220354: RV203.1 UV1.Y29
N21246320: PQ1201.1 PR1211.2
N21246524: PC1214.1 PQ1201.2 PR1212.2
N21747034: PD1.6 PD2.3 PR17.1
N22321388: RE37.2 UE1.82
N22702729: LED2.1 RD15.2
N22702890: LED3.2 RD16.2
N22702897: LED3.3 RD17.2
N22703004: LED1.1 RD14.2
N22795339: LED4.1 RD18.2
N26889205: RV198.1 UV1.Y30
N32320781: PQ701.3 PR702.1
N32936693: PQ706.1 PR720.2
N39186606: RV125.1 UV1.AL21
N39195318: RV123.1 UV1.AW28
N39348342: RV122.1 UV1.AW18
N39890903: CV218.1 UV1.AK10
N39890907: CV219.2 RV137.1
N39890909: CV218.2 RV136.1
N39890911: CV222.1 RV143.2 RV144.1
N39890927: CV219.1 UV1.AL10
N39986171: QV24.1 RV107.2 RV108.1
N39986181: CV103.1 QV22.2 RV108.2
N40812716: CR3.2 UR1.6
N45520480: RV206.2 UV1.M27
N46608735: PQ701.2 PR701.1
N46608740: PC702.2 PQ701.4 PR721.2
N46608753: PC701.2 PC702.1 PR701.2 PR703.1
N46612327: PR708.1 PU701.13
N46612330: PR710.1 PU701.12
N46660696: PC520.2 PR534.1
N46662317: PR510.1 PU501.4
N46663656: PC504.1 PR516.2 PU501.2
N46665785: PC514.1 PR529.1
N46673636: PH501.2 PR515.1
N46674251: PL502.2 PR518.2
N46860163: PQ708.1 PR713.2 PU701.10
N46975913: PC501.1 PR536.2
N46975982: PR536.1 PU502.6
N46976065: PC501.2 PU502.7
N47007806: PC16.1 PQ2.3 PR28.2
N47007810: PC16.2 PQ2.2 PR29.1
N47007850: PQ2.5 PR31.1 PR33.2
N47007898: PC14.2 PQ3.5 PR32.1
N47008006: PQ1.5 PQ1.6 PR7.1 PR10.2
N47008110: PC15.1 PQ3.2 PR30.2
N47008134: PL2.2 PQ6.1 PR6.2
N47008301: PQ4.1 PR27.1
N47305899: PC815.2 PR805.1
N47415217: PC104.2 PR103.1
N47415258: PC103.1 PR113.2
N47415272: PC111.1 PR112.2
N47415370: PC110.1 PR111.2
N47417471: PC405.1 PJP400.2 PU400.3
N47417524: PC401.1 PR405.2
N47420895: PC207.2 PR203.1
N47445410: PR114.1 PU100.19
N47894294: CC8.2 RC23.1
N47894380: CC9.2 RC24.1
N47894401: CC10.2 RC25.1
N47938591: T118.1(TP-1) UC1.AN10
N47938593: T119.1(TP-1) UC1.AM10
N47938689: T120.1(TP-1) UC1.E15
N47938710: T121.1(TP-1) UC1.E13
N47964855: T153.1(TP-1) UC1.L60
N47964866: T154.1(TP-1) UC1.N60
N47964871: T155.1(TP-1) UC1.W23
N47964873: T156.1(TP-1) UC1.Y22
N47964879: T157.1(TP-1) UC1.AV62
N47964884: T158.1(TP-1) UC1.D58
N47965485: T146.1(TP-1) UC1.AV63
N47965487: T147.1(TP-1) UC1.AU63
N47965489: T160.1(TP-1) UC1.P20
N47965491: T162.1(TP-1) UC1.R20
N47965493: T159.1(TP-1) UC1.A5
N47965495: T148.1(TP-1) UC1.C63
N47965502: T161.1(TP-1) UC1.E1
N47965509: T149.1(TP-1) UC1.C62
N47965511: T163.1(TP-1) UC1.D1
N47965522: T150.1(TP-1) UC1.B43
N47965524: T164.1(TP-1) UC1.J20
N47965529: T151.1(TP-1) UC1.A51
N47965534: T152.1(TP-1) UC1.B51
N47965536: T165.1(TP-1) UC1.H18
N48037563: JDIMM1.197 RD6.2
N48037565: JDIMM1.201 RD7.2
N48039107: CD21.1 CD22.1 JDIMM1.126 RD4.1
N48051997: CD52.1 CD53.1 JDIMM2.126 RD10.1
N48052813: JDIMM2.197 RD13.1
N48052822: JDIMM2.201 RD12.1
N48120577: RX5.2 UX4.12
N55155843: QX1.1 RX3.2
N55200533: QX3.1 RP58.5 RP58.6 RP58.7 RP58.8 RP59.5 RP59.6 RP59.7 RP59.8
N55201771: JHDMI.13 RX12.2
N56393123: RL31.2 UL1.31
N56393790: T94.1(TP-1) UL1.27
N56393809: T95.1(TP-1) UL1.25
N56393828: T96.1(TP-1) UL1.26
N56394014: CL33.1 RL19.2 RL20.2
N56394031: CL41.2 TL1.3 TL1.6
N60531222: RP41.1 UC1.C35
N60531228: RP41.2 UC1.C34
N60531230: RP41.3 UC1.AK8
N60531232: RP41.4 UC1.AL8
N60754677: T111.1(TP-1) UC1.H61
N60754679: T112.1(TP-1) UC1.H62
N60754681: T113.1(TP-1) UC1.K59
N60754683: T114.1(TP-1) UC1.H63
N60754685: T115.1(TP-1) UC1.K60
N60754687: T116.1(TP-1) UC1.J61
N60931942: T97.1(TP-1) UC1.AF2
N60931944: T99.1(TP-1) UC1.AF4
N60931946: T98.1(TP-1) UC1.AD2
N61580896: Q2307.1 R2314.2
N61580898: Q2308.1 R2315.2
N63469417: CA65.2 CA69.1 RA79.1 RA81.2
N63469524: CA68.2 RA82.1
N63469526: CA67.2 RA80.1
N63469613: CA65.1 UA1.12
N63469617: RA51.1 UA1.13
N63469687: CA23.2 UA1.28
N63469697: RA153.2 UA1.15
N63469703: CA24.1 UA1.37
N63469709: CA24.2 UA1.35
N63469711: CA25.2 UA1.34
N63469717: CA62.2 UA1.27
N63469723: CA63.2 UA1.39
N63469729: CA64.2 UA1.7
N63469750: RA130.2 UA1.8
N63642793: C51.1 R264.2 UC1.AH11
N63643467: T53.1(TP-1) UC1.J13
N63643476: T55.1(TP-1) UC1.AH13
N63643505: T56.1(TP-1) UC1.AB8
N63643514: T58.1(TP-1) UC1.AD10
N63643523: T59.1(TP-1) UC1.AD8
N63656577: T38.1(TP-1) UC1.AB23
N63657072: T39.1(TP-1) UC1.P60
N63657081: T40.1(TP-1) UC1.P61
N63657090: T41.1(TP-1) UC1.N59
N63657099: T42.1(TP-1) UC1.N61
N63657120: T43.1(TP-1) UC1.T59
N63657126: T44.1(TP-1) UC1.AD60
N63657135: T45.1(TP-1) UC1.AD59
N63657146: T46.1(TP-1) UC1.AA59
N63657155: T47.1(TP-1) UC1.AE60
N63657164: T48.1(TP-1) UC1.AC59
N63657173: T49.1(TP-1) UC1.AG58
N63657182: T50.1(TP-1) UC1.U59
N63657191: T51.1(TP-1) UC1.V59
N64564173: PC1103.1 PR1101.2
N64564191: PC1106.1 PR1104.2
N64734520: T107.1(TP-1) UC1.AJ7
N64734538: T105.1(TP-1) UC1.AL5
N64734540: T106.1(TP-1) UC1.AP4

Pads without a net: FD1 1; FD2 1; FD3 1; FD4 1; JDIMM1 77 122 125 198; JDIMM2 77 122 125 198; JHDD 18 20 21 22; JHDMI 14; JKB 2 3 30; JLAN 4 5 7 8; JLVDS 38; JMINI 1 3 5 8 10 12 14 16 17 19 37 42 45 47; JXDP1 55; LED1 3; LED2 3; LED4 3; PD1 5; PU100 7; PU200 10; PU400 2 5; PU501 5; PU600 2 5; PU800 1; PU1200 2; PU1300 4; RP37 4 5; RP42 5; RP43 3 4 5 6; RP45 4 5; RP46 3 6; RP48 4 5; RP49 3 4 5 6; RP50 4 5; RP56 1 2; RP57 3 4 5 6; RP60 2 7; TL1 4 5 12 13; U2301 10 12; U2303 1; U2304 5 6 7 8 9 10 12; UA1 14 16 20 23 24 48; UC1 A31 A37 A41 A49 A53 AA23 AB21 AC2 AC4 AC20 AC58 AD23 AE59 AF20 AG5 AL2 AL11 AL32 AM5 AN3 AP1 AP15 AP32 AT3 AU2 AU12 AV2 AV10 AV50 AW10 AW49 AY8 AY42 AY43 B14 B31 B37 B41 B49 B50 B53 B54 C3 C4 C15 C17 C30 C31 C42 C43 C46 C47 C49 C50 C51 C53 D17 E2 E3 E4 E5 F4 F5 F15 F17 G2 G15 G17 H6 J4 J6 J58 K4 K10 K18 K21 L2 L3 L11 L59 M20 M21 N2 N58 R5 T2 U2 V21 Y2 Y4 Y5 Y20; UE2 1; UL1 3 6 7 9 10 11 22 24; UR1 7 14 17 19 23; UV1 AA29 AC10 AC30 AC31 AC32 AD30 AD32 AF32 AF35 AG12 AG33 AG36 AG38 AH12 AH24 AH26 AH35 AH37 AJ19 AJ20 AJ21 AJ24 AJ26 AJ27 AJ30 AJ31 AJ36 AJ38 AK13 AK17 AK19 AK20 AK21 AK24 AK26 AK27 AK35 AK37 AL19 AL27 AL29 AL30 AL31 AL36 AM14 AM19 AM20 AM21 AM26 AM27 AM29 AM30 AN7 AN14 AN20 AN21 AN26 AN36 AP6 AP8 AP10 AP12 AP34 AP35 AP37 AR1 AR3 AR6 AR8 AR10 AR12 AR14 AR16 AR20 AR22 AR24 AR26 AR30 AR32 AR34 AR35 AR37 AT7 AT9 AT11 AT15 AT17 AT19 AT21 AT23 AT25 AT27 AT29 AT31 AT33 AU1 AU3 AU5 AU6 AU8 AU10 AU12 AU14 AU16 AU20 AU22 AU24 AU26 AU30 AU32 AU35 AU39 AV7 AV9 AV11 AV13 AV15 AV21 AV23 AV25 AV31 AW3 AW5 AW6 AW8 AW10 AW12 AW37 E37 F35 F37 G36 G38 H32 H33 H35 H37 J32 J33 J36 J38 K16 K27 K29 K30 K32 K33 K35 K37 L10 L27 L29 L30 L32 L33 L36 L38 M12 M20 M21 M35 M37 N12 N29 N30 N32 N33 N36 N38 P29 P30 P32 P33 P35 P37 R36 R38 T29 T30 T32 T33 T35 T37 U12 U38 V12; UV18 J1 J9 L1 L9 M7; UV19 J1 J9 L1 L9 M7; UV20 J1 J9 L1 L9 M7; UV21 J1 J9 L1 L9 M7; UV22 J1 J9 L1 L9 M7; UV23 J1 J9 L1 L9 M7; UV24 J1 J9 L1 L9 M7; UV25 J1 J9 L1 L9 M7; UX4 2 23 24 33 34; YC2 2 4

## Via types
v1: diameter 0.457, hole 0.203, TOP to BOTTOM, 4930 vias
v2: diameter 0.305, hole 0.152, TOP to BOTTOM, 758 vias
v3: diameter 0.508, hole 0.254, TOP to BOTTOM, 797 vias
v4: diameter 0.406, hole 0.203, TOP to BOTTOM, 155 vias

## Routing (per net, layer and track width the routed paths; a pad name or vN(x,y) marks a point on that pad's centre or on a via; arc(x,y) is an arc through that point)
0.675V_DDR_VTT_ON: length 159.7
  TOP w0.254: v1(102.52,38.07) 97.53,38.07 94.01,34.55 64.74,34.55 v4(40.25,59.04) 39.65,59.64 39.65,64.02 40.72,65.09 43.47,65.09 43.83,64.73 R2347.2 R2351.2 44.87,64.73 45.05,64.91 45.05,65.03 45.89,65.87 QD2.2 46.61,66.37 46.23,66.75 45.26,66.75 44.77,67.24 U2303.4
  IN3 w0.254: v1(162.92,27.82) 162.92,33.84 158.41,38.35 102.8,38.35 v1(102.52,38.07)
  BOTTOM w0.254: PR202.1 v1(162.92,27.82)
1.35V_B+: length 6.5
  BOTTOM w0.254: PR208.1 163.18,23.18 163.18,19.53 162.65,19 161.91,19 161.45,18.54 161.45,18.25
  vias: v2(160.15,18.11)
3/5V_B+: length 31
  TOP w0.203: v1(128.71,19.47) 128.23,18.99 PU100.12
  TOP w0.508: 124.55,29.22 123.35,30.43 v2(120.36,30.43) 119.41,30.43 117.88,28.9 117.88,21.03 119.28,19.63 124.13,19.63 124.51,20.01 128.24,20.01 128.71,19.54 v1(128.71,19.47)
  BOTTOM w0.508: PC105.1 128.54,19.31 v1(128.71,19.47)
  vias: v3(127.16,29.16) v3(127.22,26.3) v3(127.92,29.16) v3(127.98,26.3) v3(128.81,29.16) v3(128.86,26.32)
3V_EN: length 11.5
  TOP w0.203: v3(130.08,14.77) 129.95,14.9 129.95,15.09 129.77,15.27 PU100.6
  TOP w0.254: v1(125.06,12.91) 124.49,13.48 PD101.2 123.68,13.13 PR100.1
  BOTTOM w0.254: v1(125.06,12.91) 125.06,13.23 125.35,13.51 125.35,13.52 126.59,14.77 v2(128.59,14.77) v3(130.08,14.77)
3VALW_PCH:
  vias: v2(139.08,24.3)
3VS: length 0.6
  TOP w0.102: v1(95.58,32.46) v4(94.96,32.46)
3VS_GATE: length 5.5
  TOP w0.102: R2318.2 92.45,26.57 v2(92.15,26.27)
  TOP w0.254: v1(96.21,27.55) 95.72,27.06 95.09,27.06 C2322.1 94.44,26.57 R2318.2
  BOTTOM w0.203: U2301.5 v1(96.21,27.55)
5V_EN: length 5.8
  TOP w0.203: PU100.20 125.84,15.27 125.64,15.07
  TOP w0.254: PR101.1 v2(122.13,14.91) 123.61,14.91 PD101.3 125.05,14.48 125.64,15.07
5VS: length 0.7
  TOP w0.102: v1(97.59,32.07) v4(96.85,32.07)
5VS_GATE: length 3.9
  TOP w0.102: v2(96.78,28.18) 97.18,27.77 v1(97.18,27.63)
  TOP w0.254: C2309.1 96.79,26.49 R2313.2 97.18,26.88 v1(97.18,27.63)
  BOTTOM w0.203: v1(97.18,27.63) 97.01,27.8 U2301.3
+0.675VS: length 106.6
  IN2 w1.016: 156.4,54.57 155.22,53.39 155.22,31.89
  IN3 w1.016: 155.71,56.56 155.39,56.25 154.75,56.25 154.75,56.25 119.74,56.25 111.08,64.91 105.5,64.91 ; 183.37,64.29 181.75,64.29 180.39,62.93 180.39,61.58 179.07,60.26 175.01,60.26 171.43,56.68 157.85,56.68
  vias: v1(105.5,66.42) v1(105.5,65.78) v1(156.86,57.01) v1(156.86,56.37) v1(183.86,66.13) v1(183.86,65.49) v3(154.78,29.86) v3(155.41,29.86) v4(184.19,70.7)
+0.675VSP: length 4.8
  IN2 w0.254: v1(156.83,27.31) v3(158.48,27.31)
  BOTTOM w0.102: PC211.1 156.88,30.18 v2(157.24,30.53)
  BOTTOM w0.203: PU200.2 158.11,26.94 v3(158.48,27.31)
+1.2VSP_B+:
  vias: v2(176.96,177.56)
+1.05V_PGOOD: length 153.8
  TOP w0.102: v1(147.35,152.16) v2(147.35,152.68)
  TOP w0.203: UE1.122 183.22,39.71 183.62,40.11 183.62,43.17 185.76,45.31 193,45.31 193.26,45.06 v1(193.26,44.46)
  IN2 w0.508: v1(193.26,44.46) 193.26,47.89 192.73,48.42 192.73,51.48 192.75,51.49 192.75,53.48 193.92,54.65 193.92,55.83 190.78,58.96 190.78,75.35 185,81.13 185,82.55 178.59,88.96 178.59,91.38 172.77,97.2 168.85,97.2 166.36,99.69 166.36,102.89 163.22,106.02 162,106.02 161.57,106.45 161.57,109.34 158.75,112.16 155.77,112.16 154.44,113.5 154.44,118.05 152.45,120.03 152.45,127.48 148.54,131.4 148.54,145.57 147.35,146.76 v1(147.35,152.16)
  BOTTOM w0.203: PR308.2 148.15,151.01 147.35,151.81 v1(147.35,152.16) 147.35,152.6 145.87,154.08 PU300.2
+1.5VS: length 489.5
  TOP w0.508: v1(164.51,89.89) 163.78,89.16 152.57,89.16 150.78,90.96 126.48,90.96 125.24,92.2 125.24,93.32 123.21,95.35 RC129.1 ; v1(26.95,14.23) 26.17,14.23 RA8.1
  IN1 w0.508: 110.71,34.24 98.61,34.24 95.56,31.19 94.99,31.19 78.03,14.23 60.23,14.23 58.96,12.96 v1(55.85,12.96) ; v1(124.12,128.2) 124.41,128.2 125.49,127.13 132.69,127.13 134,128.43 v1(134,128.46)
  IN2 w0.254: 121.79,120.63 122.06,120.9 122.06,123.63 122.71,124.28 122.71,124.92 122.27,125.36 121.63,125.36 121.11,124.84 121.11,120.79 121.26,120.63 v1(121.53,120.63) 121.79,120.63
  IN2 w0.508: 34.93,13.41 34.48,12.96 27.65,12.96 26.95,13.66 v1(26.95,14.23) ; 34.93,13.41 35.37,12.96 v1(55.85,12.96) ; 34.93,13.41 34.93,22.81 33.68,24.05 33.68,31.25 30.32,34.62 30.32,51.13 28.92,52.53 28.92,57.14 27.14,58.91 27.14,63.99 28.03,64.88 28.03,68.65 33.6,74.22 33.6,89.51 31.33,91.77 27.91,91.77 25.84,93.83 25.84,97.64 25.17,98.31 25.17,99.45 27.4,101.67 27.4,113.93 29.75,116.28 63.21,116.28 82.27,135.34 82.51,135.34 83.28,136.1 83.28,137.36 83.85,137.93 84.48,137.93 85.4,138.85 85.4,145.07 86.35,146.02 122.36,146.02 v1(122.39,146.06) 123.03,145.43 123.03,137.74 121.69,136.41 121.69,132.79 123.52,130.96 123.52,128.8 v1(124.12,128.2) 123.52,127.61 123.52,126.87 122.27,125.61 122.27,125.36 ; v1(164.51,89.89) 164.87,90.25 164.87,95.43 160.31,99.99 157.74,99.99 152.69,105.04 151.7,105.04 150.57,106.17 150.57,107.33 151.83,108.58 151.83,109.28 151.48,109.64 151.48,110.46 146.42,115.52 143.67,115.52 141.55,113.4 139.63,113.4 137.05,115.97 135.21,115.97 133.59,117.59 133.59,123.32 134.26,123.98 134.26,128.2 v1(134,128.46)
  IN3 w0.508: v1(115.01,149.5) 115.78,148.73 119.72,148.73 v1(122.39,146.06)
  BOTTOM w0.254: v1(121.53,120.63) 121.82,120.34 UC1.J15
  BOTTOM w0.508: v1(115.01,149.5) 115.3,149.21 JMINI.48 ; JMINI.6 95.3,149.07 95.79,149.55 v1(95.91,149.55) ; JMINI.28 v1(107.3,149.55)
  vias: v3(111.52,33.44) v3(111.52,32.81) v3(112.15,33.44) v3(112.15,32.81) v3(112.79,33.44) v3(112.79,32.81) v4(111.84,32.12)
+1.05VS: length 193.7
  TOP w0.203: UG1.3 71.43,39.98 71.26,39.81 71.26,39.13 CG2.1
  TOP w0.254: RP45.8 73.55,111.4 v1(73.13,110.98)
  TOP w0.508: PR533.2 84,134.69 v1(83.85,134.85) ; v1(124.02,118.16) 123.86,118.32 C50.1 ; PC512.1 v1(86.95,134.82) ; v1(118.22,116.92) 117.76,117.37 C88.1 ; v1(87.6,119.96) 87.66,120.03 RC60.1 88.3,119.14 88.31,119.14 88.73,119.14 RC58.1 ; C53.1 124.55,118.79 v1(124.51,118.75) ; v1(115.57,111.5) 115.57,111.56 113.58,113.55 109.19,113.55 108.23,114.5 105.58,114.5 C43.1 102.97,111.9 98.39,111.9 96.93,110.44 91.79,110.44 91.41,110.06 88.74,110.06 86.54,112.25 v1(86.08,112.25) ; v1(123.44,120.6) 123.41,120.57 123.41,120.57 122.79,119.94 C61.1 ; C60.1 130.6,123.06 C62.1 129.3,123.06 v1(128.68,122.44) ; v1(71.89,39.01) CG2.1 ; C57.1 v1(131.09,121.04)
  IN1 w0.508: v1(71.89,39.01) 71.29,39.01 65.62,44.68 65.62,51.33 63.51,53.44 44.12,53.44 37.18,60.39 v1(37.18,74.29)
  IN2 w0.508: v1(120.97,110.39) 121.8,111.22 124.59,111.22 125.45,112.08 v1(125.87,112.08) ; v1(38.37,96.34) 44.62,96.34 46.94,94.02 61.62,94.02 62.5,94.9 v1(62.5,95.01)
  IN3 w0.508: v1(37.18,74.29) 35.03,74.29 33.95,75.37 33.95,79.59 35.3,80.94 35.3,84.75 36.9,86.36 37.18,86.36 38.37,87.55 v1(38.37,96.34)
  BOTTOM w0.203: UC1.AG14 122.19,111.68 v1(122.01,111.86) ; UC1.AG13 123,111.61 123.22,111.83 124,111.83 v1(124.03,111.81)
  BOTTOM w0.254: UC1.J17 120.94,120.34 v1(120.61,120.67) ; v1(125.87,112.08) 125.69,111.9 UC1.AE8 125.25,111.16 UC1.AF9 125.25,111.1 UC1.AG8 ; v1(124.51,118.75) 124.51,118.93 UC1.L10 125.25,119.67 UC1.K9 ; v1(124.51,118.75) 124.51,118.66 v1(124.02,118.16) ; v1(124.51,118.75) UC1.M9 125.69,118.3 UC1.N8 125.69,118.24 UC1.P9 ; v1(62.5,95.01) 62.7,94.81 JXDP1.43 ; UC1.T21 118.59,116.54 v1(118.22,116.92) 118.59,117.29 UC1.R21 ; v1(123.44,120.6) 123.49,120.6 123.74,120.34 UC1.J11 ; v1(118.22,112.04) UC1.AE22 ; UC1.AE22 UC1.AC22 ; UC1.AE22 117.57,112.04 UC1.AE23 115.7,111.63 v1(115.57,111.5) ; v1(123.44,121.29) 123.57,121.29 UC1.H11 ; UC1.AG16 121.35,110.77 120.98,110.41 120.98,110.41 v1(120.97,110.39) 120.59,110.77 UC1.AG17 ; v1(118.19,110.98) 117.94,111.23 UC1.AF22 ; UC1.AE9 124.5,112.08 124.22,111.81 v1(124.03,111.81) ; v1(121.6,121.31) 121.64,121.31 UC1.H15
  BOTTOM w0.279: JXDP1.44 62.7,97.87 v1(63.21,97.36)
  BOTTOM w0.508: v1(91.28,129.93) 91.52,129.69 R286.1 ; PR533.2 84,134.69 v1(83.85,134.85) ; R256.1 79.92,118.69 v1(80.05,118.57) 80.72,118.57 R252.1
  vias: v1(63.85,97.36) v1(78.9,121.89) v1(79.53,121.89) v1(80.17,121.89) v1(84.26,122.35) v1(84.63,122.84) v1(85.44,112.25) v1(87.09,131.84) v1(87.72,131.84) v1(118.77,139.01) v1(119.21,139.46) v1(119.65,113.65) v1(119.65,113.01) v1(147.54,127.33) v1(147.54,126.74) v3(143.03,138.82) v3(143.03,138.19) v3(143.03,137.55) v3(143.03,136.92) v3(143.67,138.82) v3(143.67,138.19) v3(143.67,137.55) v3(143.67,136.92) v3(144.3,138.82) v3(144.3,138.19) v3(144.3,137.55) v3(144.3,136.92) v3(144.94,138.82) v3(144.94,138.19) v3(144.94,137.55) v3(144.94,136.92) v4(141.87,136.22)
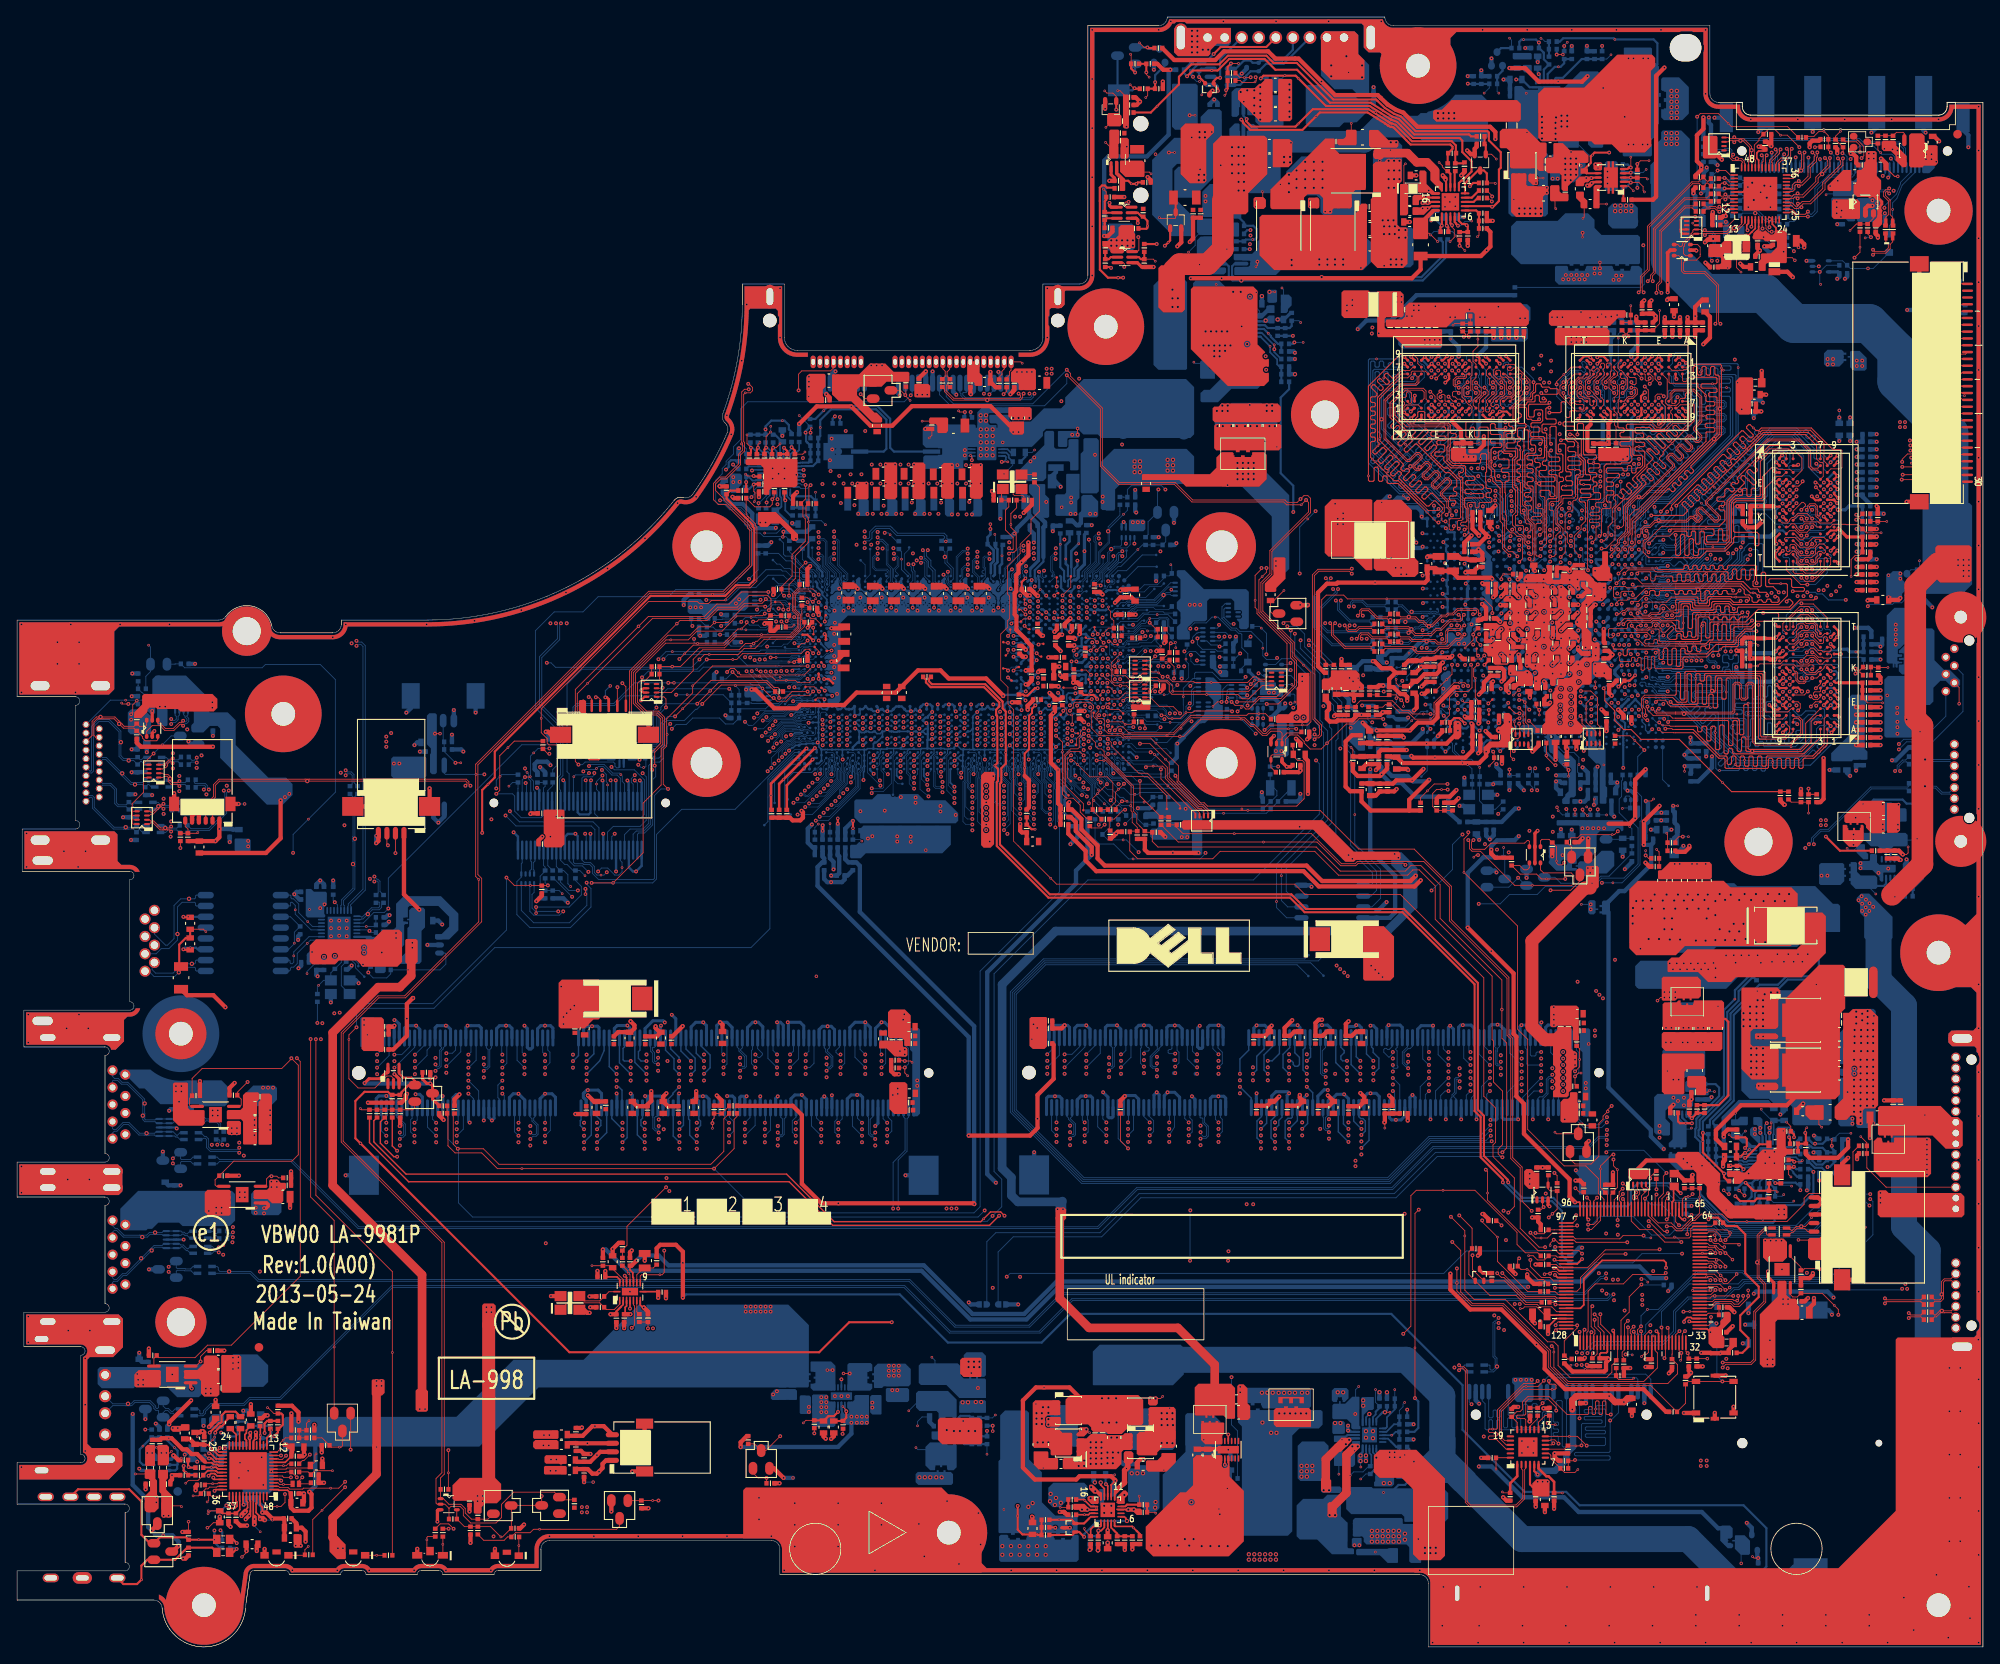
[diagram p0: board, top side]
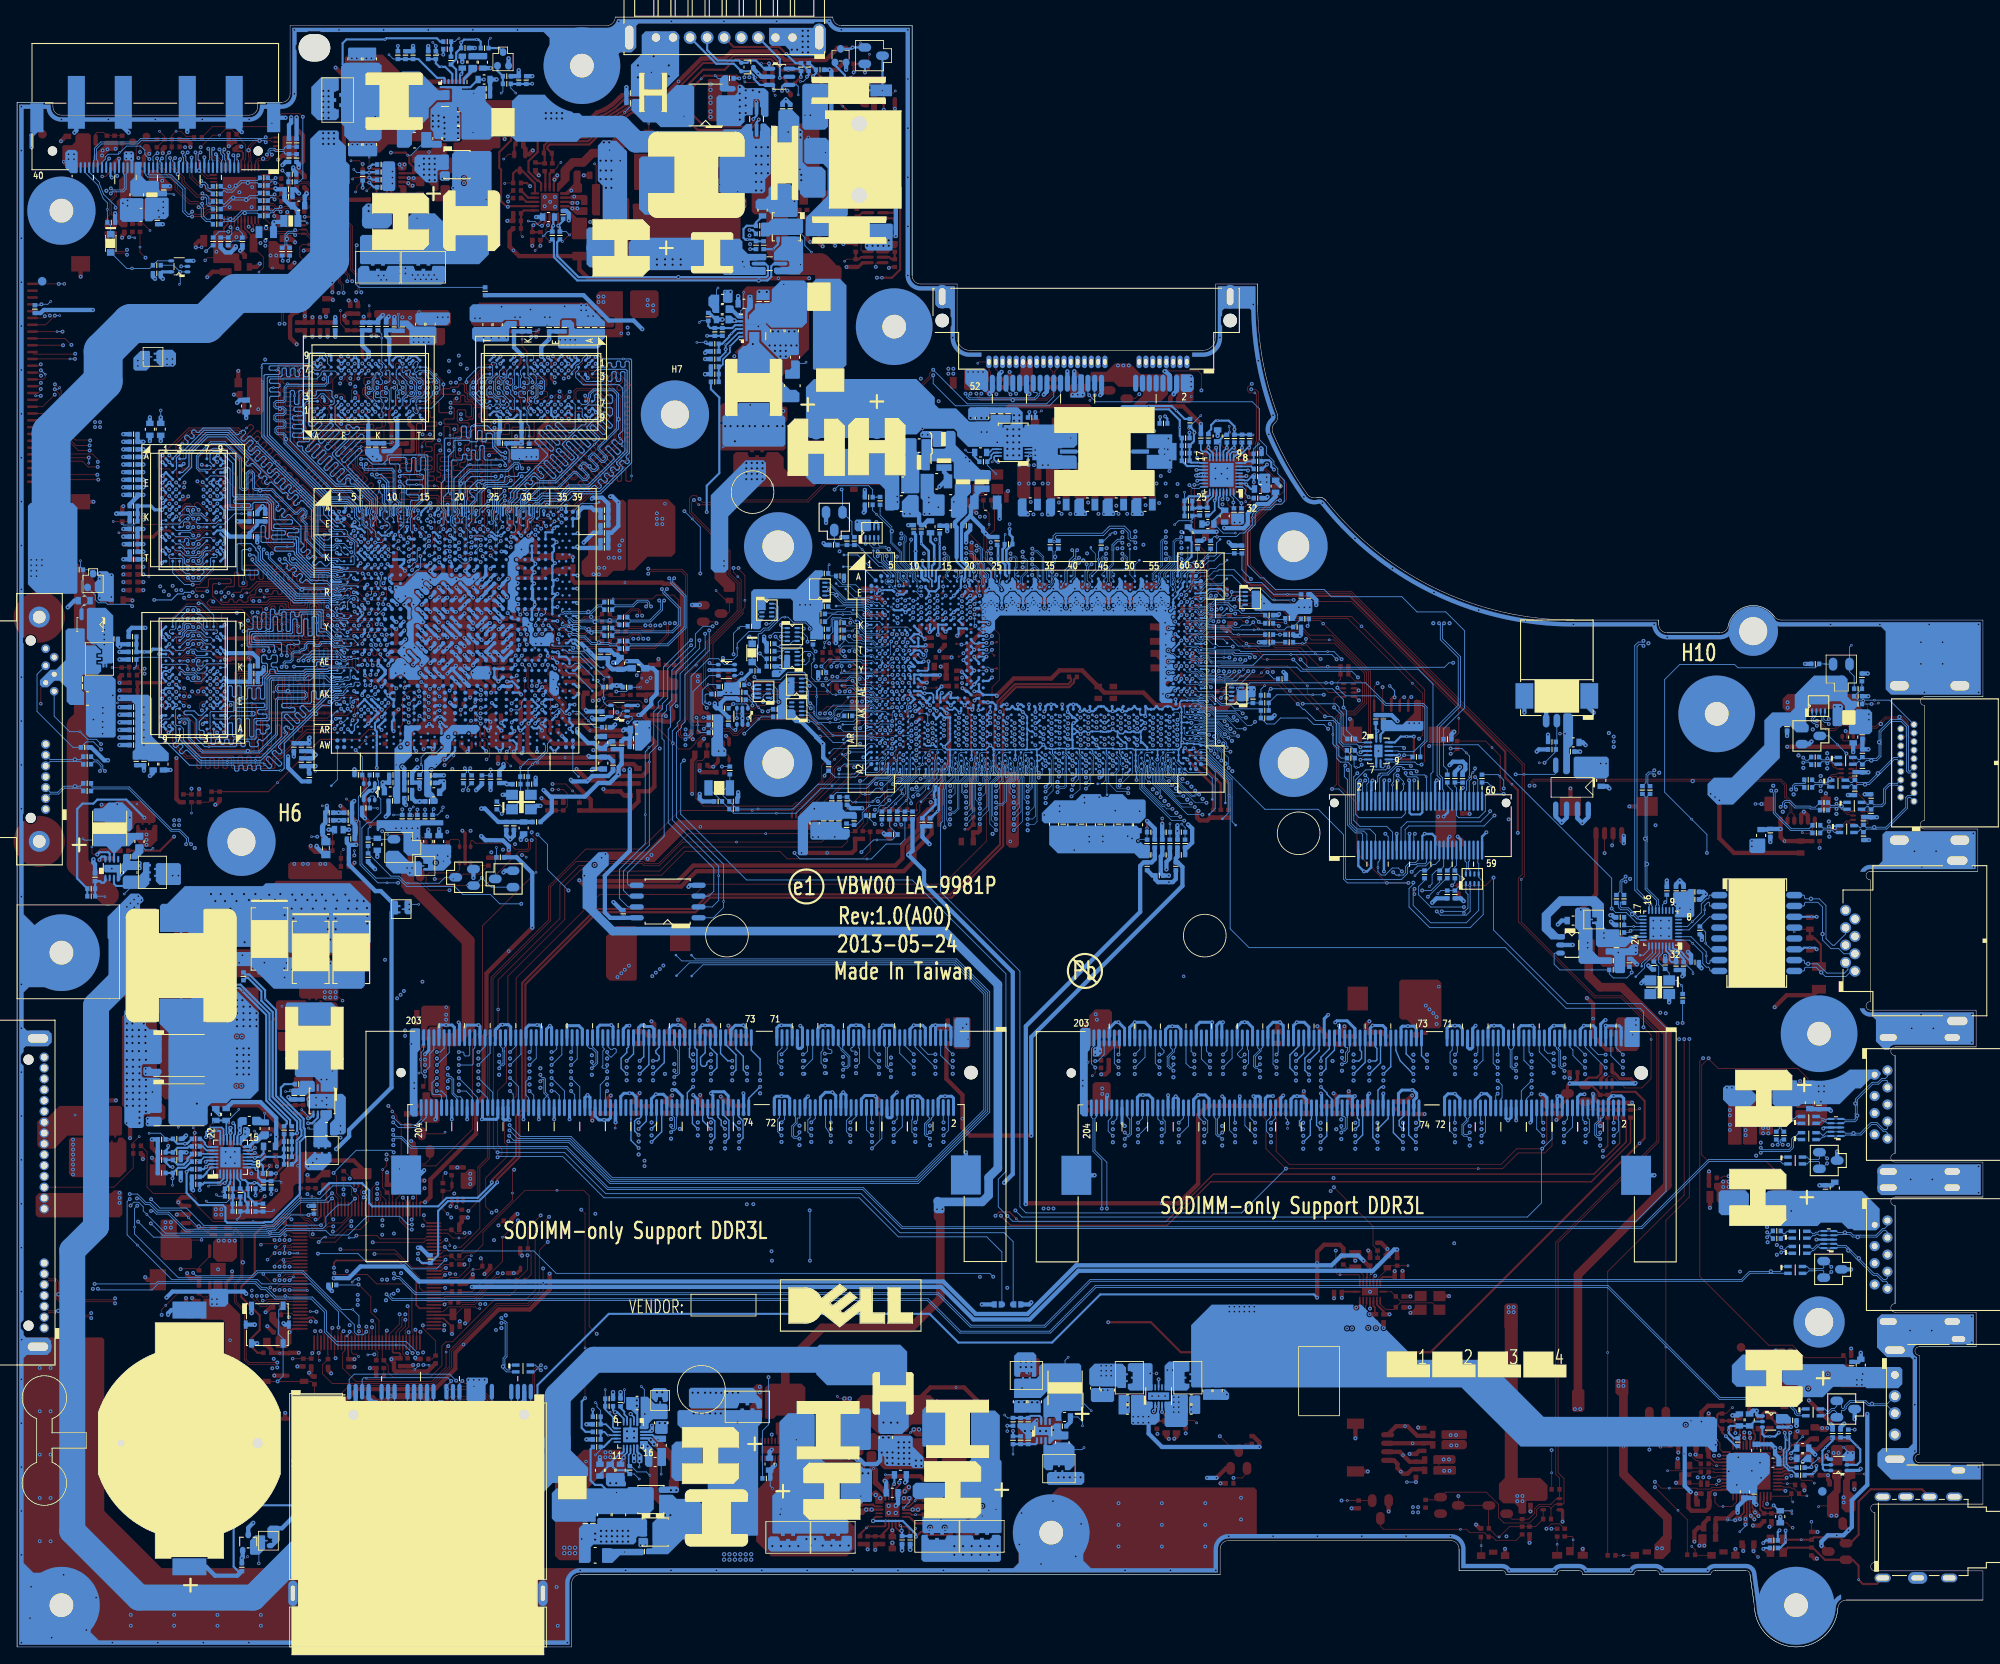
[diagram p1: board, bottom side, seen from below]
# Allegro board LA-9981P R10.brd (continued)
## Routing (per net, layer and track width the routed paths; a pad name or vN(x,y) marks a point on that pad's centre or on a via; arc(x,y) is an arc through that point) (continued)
+1.05VS_APLLOPI: length 31.8
  TOP w0.508: v1(118.52,129.49) 118.53,129.47 118.53,127.97 v4(117.73,127.17) 117.36,126.8 117.36,125.94 117.11,125.68 117.11,123.76 116.92,123.57 116.92,121.05 117.12,120.85 117.12,119.24 118.33,118.03 118.33,117.93 118.9,117.36 C69.1 118.25,114.51 v1(118.22,114.48)
  IN3 w0.508: v1(126.33,139.77) 126.33,138.76 120.04,132.47 120.04,131.33 118.52,129.8 v1(118.52,129.49)
  BOTTOM w0.254: UC1.AA21 118.59,114.11 v1(118.22,114.48) 118.59,114.85 UC1.W21
+1.05VS_ASATA3PLL: length 22.6
  TOP w0.102: v1(124.3,142.12) v4(124.3,142.86)
  IN3 w1.016: 126.01,133.93 126.01,136.35 128.04,138.38 128.04,140.92 127.16,141.81 125.19,141.81
  BOTTOM w0.203: UC1.B11 123.76,125.1 123.88,125.1
  BOTTOM w0.381: 123.88,125.1 124.09,125.1 124.37,125.38 124.37,126.21 125.1,126.93 v1(125.1,128.47) 125.1,130.4 C63.1
  BOTTOM w0.508: RC126.2 123.69,132.03 124.18,131.53 RC131.2 124.68,131.79 124.68,132.79 125.44,133.55 C65.1
  vias: v1(123.66,142.12) v1(125.76,132.85) v1(126.39,132.85)
+1.05VS_AUSB3PLL: length 24.4
  TOP w0.102: v4(114.07,131.65) v1(114.07,131.07)
  IN2 w0.508: v1(120.62,134.25) 120.62,133.36 118.79,131.53 114.53,131.53 v1(114.07,131.07)
  BOTTOM w0.102: 114.12,125.9 114.12,125.22 UC1.B27
  BOTTOM w0.254: 120.29,127.78 120.29,127.25 119.28,126.24 119.28,125.42 119.37,125.32 119.37,124.95 UC1.B18
  BOTTOM w0.305: v1(114.07,131.07) 114.07,130.44 113.74,130.11 RC91.1 114.45,128.59 114.45,127.31 114.12,126.98 114.12,125.9
  BOTTOM w0.508: 120.29,127.78 120.29,131.26 C58.1 120.48,131.86 119.66,132.67
+1.05VS_AXCK_DCB: length 4.3
  BOTTOM w0.254: v1(119.6,120.66) 119.74,120.66 UC1.J18 120.06,120.34 UC1.K19
  BOTTOM w0.508: L4.2 121.76,137.75 121.3,137.3 C84.1 121.67,136.66 v1(122.3,136.03)
  vias: v4(122.43,133.63)
+1.05VS_AXCK_LCPLL: length 16
  BOTTOM w0.254: 118.75,126.42 UC1.A20
  BOTTOM w0.381: 118.75,126.42 119.71,127.38 119.71,131.36 C85.1
  BOTTOM w0.508: L5.2 118.2,134.91 C86.1 118.61,133.78 118.61,132.7 118.71,132.6 ; 118.71,132.6 119.61,131.7 C85.1 ; 118.71,132.6 118.65,132.6 117.18,131.14 117.18,130.85 v4(116.87,130.53) 116.87,130.54 116.46,130.13 RC13.2
+1.05VSP: length 18.1
  IN1 w0.254: v3(146.27,141.36) 148.49,141.36 149.89,142.76 149.89,146.82 150.65,147.58 150.65,153.3 150.23,153.72 v1(149.53,153.72)
  BOTTOM w0.254: PC307.1 PR305.1 v1(149.53,153.72)
  vias: v2(147.65,140.71) v3(140.68,143.14) v3(141.32,143.14) v3(142.33,143.14) v3(142.97,143.14) v3(143.92,143.14) v3(144.55,143.14) v3(145.32,143.14) v3(145.95,143.14) v3(146.78,143.14) v3(147.41,143.14)
+1.5VSP: length 9
  IN1 w0.254: v1(113.68,25.33) 113.68,29.3 v1(112.61,30.36)
  BOTTOM w0.102: v2(107.21,33.96) 107.58,33.6 107.58,32.07
  BOTTOM w0.254: v1(113.68,25.33) PC404.1 PR403.1
+1.5VSP_ON: length 5.1
  BOTTOM w0.102: PR401.1 114.31,26.85 v2(114.66,27.19)
  BOTTOM w0.254: PR401.1 PR404.1 PC403.1 111.59,27.09 110.56,27.09 110.37,26.9 PU400.7
+1.8VGS: length 382.3
  TOP w0.203: UG1.11 72.23,43.29 72.16,43.36 72.16,43.88 71.83,44.21 CG1.1
  TOP w0.508: RV118.2 160.56,102.94 v1(159.92,102.31) 159.73,102.12 157.13,102.12 156.56,102.69 RV124.1 ; CG1.1 72.01,44.7 v1(72.61,45.3) ; 161.56,114.23 160.81,113.48 RV241.1 161.3,112.54 162.12,111.73 LV12.2 162.92,111.39 v1(162.92,110.94) ; 161.56,114.23 LV13.2 ; 161.56,114.23 161.03,114.76 159.92,114.76 159.1,115.58 v1(158.91,115.58) ; v1(192.5,98.62) v4(190.65,96.78) v1(190.65,94.05) ; LV21.1 v1(204.47,149.62) ; LV17.1 153.38,111.01 153.76,110.63 153.76,109.93 153.51,109.68 153.51,108.85 153.86,108.5 154.62,108.5 154.76,108.64 156.48,108.64 156.87,109.03 RV243.1 v1(157.57,109.27) RV239.1 ; v1(168.68,100.47) 167.92,99.7 166.61,99.7 166.38,99.47 RV237.1
  IN1 w0.508: v1(168.68,100.47) 169.19,100.97 171.41,100.97 172.25,101.81 173.3,101.81 173.89,101.21 173.89,100.46 175.24,99.11 182.82,99.11 182.83,99.13 v1(183.22,99.13) 183.86,99.13 184.22,99.49 185.97,99.49 186.63,98.82 189.1,98.82 189.94,97.98 191.92,97.98 192.5,98.56 v1(192.5,98.62)
  IN2 w0.508: v1(192.99,58.38) 192.99,57.65 194.55,56.09 194.55,54.25 194.15,53.85 194.15,43.92 193.48,43.24 v1(193.27,43.24) ; v1(168.68,100.47) 168.68,101.93 162.33,108.28 162.33,109.55 162.92,110.14 v1(162.92,110.94)
  IN3 w0.508: v1(158.91,115.58) 160.57,117.24 160.57,124.9 157.9,127.57 157.9,139.18 159.73,141 159.73,151.78 163.34,155.4 164.87,155.4 166.27,156.79 200.43,156.79 204.47,152.76 v1(204.47,149.62)
  BOTTOM w0.508: LV22.1 191.75,94.28 191.52,94.05 ; v1(190.65,94.05) 191.52,94.05 ; 191.52,94.05 191.52,91.74 188.4,88.62 187.77,88.62 186.46,87.32 ; 167.92,99.7 163.86,99.7 162.25,101.3 160.93,101.3 v1(159.92,102.31) 159.89,102.34 159.89,103.17 159.54,103.52 LV16.1 LV14.2 ; 167.92,99.7 167.73,99.51 167.73,97.92 LV19.1 ; 167.92,99.7 v1(168.68,100.47) ; RV119.1 183.22,99.13 v1(183.22,99.13) 183.72,99.13 LV20.1 RV93.2 ; v1(72.61,45.3) 73.21,45.9 75.19,45.9 76.34,44.74 106.27,44.74 111.98,39.04 118.04,39.04 121.85,42.85 183.3,42.85 185.06,44.6 190.16,44.6 191.52,43.24 193.27,43.24 v1(193.27,43.24) ; v1(157.57,109.27) 157.31,109.27 156.07,110.51 156.07,111.11 155.44,111.75 155.44,114.31 155.88,114.75 LV18.1 156.88,114.75 157.71,115.58 v1(158.91,115.58) ; 186.52,86.15 186.52,65.59 191.48,60.63 191.48,59.87 192.97,58.38 v1(192.99,58.38)
+1.8VS: length 32.9
  IN1 w1.016: 185.45,86.82 187.54,86.82 189.96,89.23 209.01,89.23 211.93,92.15 212.44,92.15 214.31,94.02
  BOTTOM w0.102: v1(184.43,87.07) v2(183.33,87.07)
  vias: v1(184.43,86.48) v1(215.23,95.26) v1(215.23,94.63) v1(215.23,94.04)
+1.8VSP: length 19.9
  BOTTOM w0.254: v1(215.48,97.23) 217.6,99.35 220.99,99.35 221.45,98.88 222.72,98.88 223.36,98.25 223.36,90.1 PR603.1 PC604.1
  vias: v1(217.19,97.24) v1(218.66,98.82) v1(218.67,96.44) v1(218.67,95.86) v2(216.35,98.84)
+1.8VSP_ON: length 6.6
  TOP w0.102: v2(221.63,93.81) 221.63,93.1 221.44,92.91 v1(221.01,92.91)
  TOP w0.508: PR601.1 219.15,93.36 PR604.1 PC603.1 220.55,93.37 v1(221.01,92.91)
  BOTTOM w0.254: PU600.7 219.54,93 219.72,93.18 220.74,93.18 v1(221.01,92.91)
+1.35V: length 141.2
  TOP w0.356: CD23.1 47.51,66.57 48.02,66.06 v1(48.43,66.06) 48.7,65.8 QD2.1 48.7,64.23 RD3.1 ; v1(40.73,66.11) 41.24,66.62 42.52,66.62 43.19,67.3 43.34,67.3 43.47,67.43 U2303.5
  IN2 w0.508: v1(66.89,65.29) 65.69,65.29 64.23,63.83 49.11,63.83 46.83,66.11 v1(40.73,66.11)
  BOTTOM w0.203: v1(109.86,100.85) 109.38,101.33 109.38,102.88 UC1.AY35 ; UC1.AR48 101.36,106.04 v1(101.03,105.72) ; UC1.AY44 103.09,102.89 103.09,102.16 103.32,101.93 v1(103.56,101.93) ; UC1.AY40 106.27,102.92 106.27,102.11 v1(106.69,101.69)
  BOTTOM w0.229: UC1.AY50 99.98,102.79 v1(100.39,102.38)
  BOTTOM w0.254: v1(114.41,110.51) 114.82,110.51 UC1.AH26 ; UC1.AJ37 v1(107.9,110.51) ; v1(103.89,106.37) 104.06,106.37 UC1.AP43 ; UC1.AN33 110.22,107.01 v1(110.1,107.01) ; UC1.AJ33 v1(110.51,110.51) ; UC1.AJ31 v1(111.81,110.51)
  BOTTOM w0.356: JDIMM1.124 81.1,64.23 80.76,64.57 v1(80.38,64.57) 79.64,64.57 79.3,64.23 JDIMM1.118 ; JDIMM1.93 71.8,72.59 v1(71.53,72.86) 70.34,72.86 70,72.52 JDIMM1.87 ; v1(70.27,64.89) 70.3,64.85 JDIMM1.88 ; JDIMM2.81 146.75,72.36 146.23,72.88 145.28,72.88 v1(145.27,72.88) 144.95,72.56 JDIMM2.75 ; JDIMM2.87 148.55,72.56 148.89,72.9 v1(150.08,72.9) 150.35,72.63 JDIMM2.93 ; JDIMM1.76 66.7,64.11 66.45,64.36 66.37,64.44 66.37,64.88 66.45,64.96 66.45,64.97 66.77,65.29 v1(66.89,65.29) 68.1,65.29 68.5,64.89 JDIMM1.82 ; JDIMM1.105 75.4,72.78 v1(75.47,72.85) ; JDIMM2.118 157.85,64.49 158.28,64.91 v1(158.62,64.91) 159.28,64.91 159.65,64.54 JDIMM2.124 ; JDIMM2.94 150.65,64.21 v1(151.16,64.72) ; v1(75.91,73.23) 75.72,73.42 74.51,73.42 73.6,72.5 JDIMM1.99 ; JDIMM2.100 152.45,64.59 153.19,65.33 153.59,65.33 v1(153.62,65.29) ; JDIMM2.99 152.15,72.41 152.64,72.91 v1(152.94,72.91) 153.59,72.91 153.95,72.55 JDIMM2.105 ; JDIMM1.106 75.7,64.29 75.41,64.58 v1(73.61,64.58) 73.9,64.29 JDIMM1.100 ; JDIMM2.117 157.55,72.61 157.26,72.91 v1(156.94,72.91) 156.93,72.91 156.78,72.75 156.15,72.75 156.14,72.74 156.03,72.74 155.75,72.46 JDIMM2.111 ; JDIMM2.123 159.35,72.46 158.97,72.85 v1(158.62,72.85) ; JDIMM2.112 156.05,64.27 v1(155.53,64.8) 154.67,64.8 154.25,64.38 JDIMM2.106 ; JDIMM2.76 145.25,64.28 145.24,64.29 145.24,64.88 v1(145.27,64.91) ; JDIMM1.112 77.5,64.8 v1(77.59,64.89) ; v1(76.74,74.12) 77.2,73.65 JDIMM1.111 ; JDIMM1.81 68.2,72.62 68.04,72.78 v1(67.39,72.78) 66.66,72.78 66.4,72.52 JDIMM1.75 ; JDIMM2.82 147.05,64.61 147.54,65.1 148.9,65.1 v1(149.08,64.91) 148.85,64.68 JDIMM2.88 ; JDIMM1.117 79,72.7 79.54,73.24 v1(80.42,73.24) 80.8,72.86 JDIMM1.123 ; v1(71.92,64.89) 72.1,64.71 JDIMM1.94
  BOTTOM w0.508: v1(48.43,66.06) 40.78,66.06 v1(40.73,66.11) ; RC15.1 94.59,90.04 94.96,89.67 v1(95.41,89.67) 96.67,89.67 96.99,89.99 RC16.1 97.33,90.44 RC14.1
  vias: v1(65.15,69.44) v1(65.15,67.92) v1(66.45,61.46) v1(66.45,59.94) v1(66.45,58.41) v1(66.75,69.44) v1(66.75,67.92) v1(66.75,66.4) v1(67.97,61.46) v1(67.97,59.94) v1(67.97,58.41) v1(70.27,67.94) v1(70.27,66.41) v1(70.95,61.46) v1(70.95,59.94) v1(70.95,58.41) v1(71.92,67.94) v1(71.92,66.41) v1(73.56,61.46) v1(73.56,59.94) v1(73.56,58.41) v1(73.77,69.46) v1(73.77,67.94) v1(73.77,66.41) v1(75.12,69.84) v1(75.12,67.56) v1(75.2,61.84) v1(75.2,59.56) v1(75.78,60.7) v1(76.23,68.7) v1(77.59,67.94) v1(77.59,66.41) v1(77.63,61.46) v1(77.63,59.94) v1(77.63,58.41) v1(78.98,67.94) v1(78.98,66.41) v1(79.66,61.46) v1(79.66,59.94) v1(79.66,58.41) v1(80.51,69.46) v1(80.51,67.94) v1(80.51,66.41) v1(98.83,97.99) v1(101.69,98.05) v1(103.58,99.64) v1(105.31,99.6) v1(105.3,98.98) v1(108.22,98.6) v1(108.22,97.96) v1(110.01,97.55) v1(143.32,66.44) v1(143.32,64.91) v1(144.84,67.96) v1(144.84,66.44) v1(145.78,61.5) v1(145.78,59.98) v1(145.78,58.45) v1(146.58,67.96) v1(146.58,66.44) v1(147.43,61.5) v1(147.43,59.98) v1(147.43,58.45) v1(149.08,69.48) v1(149.08,67.96) v1(149.08,66.44) v1(149.08,61.5) v1(149.08,59.98) v1(149.08,58.45) v1(150.62,61.5) v1(150.62,59.98) v1(151.16,69.48) v1(151.16,67.96) v1(151.16,66.44) v1(152.72,60.74) v1(153.37,68.34) v1(153.37,66.05) v1(153.75,61.88) v1(153.75,59.59) v1(154.48,67.19) v1(155.87,67.96) v1(155.87,66.44) v1(156.04,61.5) v1(156.04,59.98) v1(157.43,67.96) v1(157.43,66.44) v1(157.56,61.5) v1(157.55,59.26) v1(157.55,57.74) v1(158.96,67.96) v1(158.96,66.44) v3(145.89,29.8) v3(146.53,29.8) v3(147.16,29.8) v3(147.86,29.79) v3(148.49,29.79) v3(149.13,29.8) v3(149.77,29.8) v3(150.59,29.8) v3(151.23,29.8) v4(93.68,78.63)
+1.35V_MEM_GFX: length 226
  TOP w0.254: UV20.K2 187.98,150.06 v1(188.38,150.46) ; v1(205.37,110.44) 205.92,109.9 206.43,109.9 UV25.D9 ; UV20.N9 186.01,144.02 v1(186.05,144.02) ; v1(162.57,144.76) 162.88,144.45 UV18.A1 ; UV25.R9 206.55,118.75 v1(206.17,118.37) ; UV18.H2 v1(168.19,145.65) ; UV18.D9 165.39,150.85 v1(164.99,151.25) UV18.C9 ; v1(184.43,144.07) 184.05,144.45 UV20.R9 ; UV25.A8 v1(206.95,107.22) ; v1(213.39,130.18) 213.39,130.14 UV22.N9 ; v1(164.42,143.87) 164.59,144.04 UV18.C1 ; UV25.H2 v1(211.75,112.82) ; UV20.N1 185.58,150.82 v1(185.2,150.45) ; v1(213.35,135.74) 213.37,135.74 213.01,136.1 UV22.E9 ; UV18.N1 172.59,144.48 v1(172.96,144.86) ; UV18.K8 170.17,150.05 v1(169.75,149.64) ; v1(187.69,112.59) 187.69,112.59 CV155.1 189,113.29 189.62,113.91 v1(189.62,113.92) ; UV20.G7 190.32,146.11 190.32,146.64 v3(190.77,147.08) ; v1(212.55,114.42) 212.16,114.82 UV25.K2 ; UV25.B2 212.15,108.38 v1(212.56,107.97) ; UV18.B2 163.75,145.25 v1(163.34,144.85) ; UV18.E9 166.19,150.98 v1(166.57,151.36) ; v1(191.62,151.31) 191.18,150.87 UV20.F1 ; UV18.H9 168.59,150.81 v1(168.99,150.41) ; v1(206.95,132.5) 207.35,132.1 UV22.K2 ; v1(173.74,151.3) 174.18,150.85 UV18.R9 ; UV20.A8 v1(195.58,144.85) ; v1(206.05,111.21) 206.43,110.82 UV25.E9 ; v1(162.59,150.45) 162.99,150.05 UV18.A8 ; v1(206.12,116.74) 206.12,116.79 UV25.N9 ; v1(210.34,134.9) 210.34,134.89 210.78,134.45 211.16,134.45 211.22,134.5 UV22.G7 ; UV18.K2 170.19,145.25 v1(169.79,144.85) ; UV22.H9 212.91,133.7 v1(212.51,133.3) ; v1(205.97,137.87) 206.14,137.7 UV22.C1 ; v1(195.59,150.55) 195.29,150.85 UV20.A1 ; UV22.F1 206.53,135.3 v1(206.1,135.74) ; UV22.C9 212.95,137.7 v1(213.35,137.3) UV22.D9 ; UV22.A1 206.55,139.41 v1(206.86,139.72) ; UV25.F1 212.97,111.62 v1(213.41,111.18) ; UV20.D9 192.86,144.37 192.86,143.65 192.61,143.4 v1(192.42,143.4) ; UV20.H2 v1(189.98,149.66) ; v1(172.11,151.29) 172.15,151.29 UV18.N9 ; UV20.H9 189.58,144.5 v1(189.18,144.9) ; v1(207.75,134.1) UV22.H2 ; UV18.D2 v1(165.79,144.85) ; UV20.R1 184,150.85 v1(184.39,150.46) ; UV25.D2 v1(212.55,110.42) ; v1(206.96,129.33) 206.58,129.7 UV22.N1 ; v1(188.42,145.67) 188,145.25 UV20.K8 ; UV22.A8 v1(212.55,139.7) ; UV22.B2 207.35,138.54 v1(206.95,138.95) ; v1(212.56,118.41) 212.95,118.8 UV25.R1 ; v1(191.59,143.95) 191.98,144.33 UV20.E9 ; UV20.D2 v1(192.38,150.46) ; UV18.G7 167.79,149.12 167.84,149.06 167.84,148.68 167.4,148.24 v1(167.39,148.24) ; UV20.B2 194.42,150.05 v1(194.83,150.46) ; v3(209.18,112.03) 208.74,112.48 208.21,112.48 UV25.G7 ; UV25.N1 212.92,117.22 v1(212.55,117.59) ; v1(213.54,109.05) 213.37,109.22 UV25.C1 ; UV22.D2 v1(206.95,136.5) ; v1(207.77,114.38) 207.35,114.8 UV25.K8 ; v1(207,113.62) 206.6,113.22 UV25.H9 ; v1(213.33,128.55) 212.95,128.17 UV22.R9 ; UV22.K8 212.15,132.12 v1(211.73,132.54) ; v1(193.75,151.44) 193.58,151.27 UV20.C1 ; v1(212.65,107.21) 212.95,107.51 UV25.A1 ; UV22.R1 206.55,128.12 v1(206.95,128.51) ; v1(173.81,144.08) 174.18,144.45 UV18.R1 ; UV20.C9 v1(193.58,143.91) ; v1(166.55,144) 166.99,144.43 UV18.F1 ; UV25.C9 v1(206.01,109.22)
  TOP w0.381: 184.43,143.35 v1(184.43,144.07) ; v1(206.17,118.37) 206.06,118.25 204.85,118.25
  TOP w0.508: CV259.1 v1(193.12,153.62) ; CV310.1 v1(215.6,125.75) ; v1(211.72,104.22) 211.72,99.42 211.35,99.05 RV138.1 ; CV311.1 v1(215.6,126.64) ; RV161.1 192.04,155.6 v1(192.04,156.04) 191.75,156.33 CV141.1 190.48,156.33 CV145.1 ; v1(185.7,109.92) 186.19,109.43 CV144.1 ; RV189.1 v1(218.39,111.27) ; CV246.1 v1(175.72,153.5) ; 184.43,143.35 184.04,142.96 184.04,140.34 184.16,140.21 RV160.1 ; CV305.1 v1(215.53,109.3) ; v1(216.88,122.69) 216.95,122.76 CV139.1 ; v1(204.55,131.97) 203.85,131.27 202.64,131.27 202.25,131.67 RV182.1 ; v1(187.65,109.88) 187.68,109.88 188.28,109.28 CV154.1 ; v1(172.86,131.05) 172.61,131.3 CV138.1 ; CV317.1 v1(215.53,106.63) ; v1(197.63,152.73) 198.4,153.51 198.4,155.96 CV136.1 ; CV308.1 v1(215.6,123.91) ; CV299.1 v1(215.6,124.86) ; CV245.1 v1(176.61,153.62) ; CV307.1 v1(215.53,107.52) ; CV268.1 CV238.1 v1(173.05,153.5) ; v1(171.91,141.94) 171.91,140.92 171.2,140.21 RV156.1 ; CV156.1 185.96,117.83 v1(185.96,119.35) ; CV306.1 v1(215.53,108.41) ; CV235.1 v1(173.94,153.5) ; CV258.1 v1(194.01,153.62) ; v1(215.6,127.52) 216.93,127.52 217.2,127.79 RV183.1 ; CV318.1 v1(215.53,110.19) ; RV188.1 202.18,118.05 202.48,118.34 203.51,118.34 203.6,118.25 204.85,118.25 ; CV289.1 v1(215.53,105.74) ; v1(196.67,153.62) CV256.1 CV244.1 ; CV267.1 v1(174.83,153.5) ; CV270.1 v1(195.78,153.62) ; CV143.1 171.31,129.29 172.17,130.15 v1(172.47,130.15) 172.14,130.48 172.12,130.48 171.5,131.11 171.5,132.14 CV142.1 CV153.1 ; CV271.1 v1(194.89,153.62) ; CV140.1 v1(194.2,155.97)
  BOTTOM w0.229: UV23.H9 206.13,133.28 v1(206.13,132.48) ; UV24.H9 213.37,113.64 213.37,114.19 213.14,114.42 v1(212.55,114.42)
  BOTTOM w0.254: v1(168.99,144.05) 168.59,144.45 UV19.H9 ; UV23.D2 UV22.C9 212.95,137.7 v1(213.35,137.3) ; v1(212.51,133.3) 212.15,133.66 UV23.H2 ; v1(162.57,144.76) 162.57,144.84 UV19.A8 163.34,144.9 v1(163.34,144.85) ; v1(194.83,150.46) 194.83,150.4 UV21.A8 195.59,150.47 v1(195.59,150.55) ; UV23.E9 v1(206.95,136.5) 206.55,136.9 UV23.D9 ; UV22.N1 206.58,129.7 v1(206.96,129.33) ; UV21.B2 v1(194.78,144.85) UV21.A1 ; UV24.B2 v1(206.95,108.02) UV24.A1 ; UV19.E9 v1(165.79,144.85) UV19.D9 ; UV21.H2 189.53,145.25 v1(189.18,144.9) ; UV18.R1 174.18,144.45 v1(173.81,144.08) ; UV1.G17 181.07,129.49 v1(180.86,129.49) ; v1(184.94,126.19) 185.45,126.69 UV1.L12 ; UV22.K2 207.35,132.1 v1(206.95,132.5) ; v1(211.73,132.54) 212.15,132.12 UV22.K8 ; v1(212.56,118.41) 212.95,118.8 UV25.R1 ; v1(189.18,151.26) 189.58,150.86 UV21.H9 ; UV25.R9 206.55,118.75 v1(206.17,118.37) ; v1(212.55,117.59) 212.92,117.22 UV25.N1 ; v1(213.35,135.74) 213.33,135.74 212.95,135.36 UV23.F1 ; v1(166.57,151.36) 166.99,150.95 UV19.F1 ; UV22.N9 212.95,129.75 v1(213.39,130.18) ; v1(212.65,107.21) 212.57,107.21 UV24.A8 212.5,107.97 v1(212.56,107.97) ; UV24.H2 207.35,113.26 v1(207,113.62) ; UV22.R1 206.55,128.12 v1(206.95,128.51) ; UV1.G23 176.14,129.89 v1(176.05,129.8) ; v1(206.95,138.95) 207,138.95 UV23.A8 206.94,139.72 v1(206.86,139.72) ; v1(173.74,151.3) 174.18,150.85 UV18.R9 ; UV24.F1 206.46,111.62 v1(206.05,111.21) ; UV20.K2 187.98,150.06 v1(188.38,150.46) ; UV24.D9 212.95,110.02 v1(212.55,110.42) UV24.E9 ; v1(211.75,112.82) UV24.G7 ; UV20.K8 188,145.25 v1(188.42,145.67) ; UV25.N9 206.55,117.18 v1(206.12,116.74) ; v1(186.05,144.02) 185.62,144.45 UV20.N9 ; v1(212.55,114.42) 212.16,114.82 UV25.K2 ; v1(186.08,130.39) 186.26,130.21 UV1.G11 ; v1(206.01,109.22) UV25.C9 ; UV19.B2 163.79,150.05 v1(163.39,150.45) UV19.A1 ; v1(172.96,144.86) 172.59,144.48 UV18.N1 ; v1(213.54,109.05) 213.37,109.22 UV25.C1 ; UV21.E9 v1(192.38,150.46) 192.78,150.85 UV21.D9 ; v1(205.97,137.87) 206.14,137.7 206.14,137.7 UV22.C1 ; v1(168.99,150.41) 168.63,150.05 UV19.H2 ; UV18.K2 170.19,145.25 v1(169.79,144.85) ; UV20.C1 193.58,151.27 v1(193.75,151.44) ; UV20.N1 185.58,150.82 v1(185.2,150.45) ; UV18.K8 170.17,150.05 v1(169.75,149.64) ; v1(184.39,150.46) 184,150.85 UV20.R1 ; v1(207.75,134.1) UV23.G7 ; UV19.D2 165.39,150.18 164.71,150.85 UV18.C9 v1(164.99,151.25) ; UV18.N9 172.54,150.85 v1(172.11,151.29) ; UV21.F1 191.18,144.36 v1(191.59,143.95) ; UV23.A1 v1(212.55,138.9) 212.55,138.9 UV23.B2 ; UV22.R9 212.95,128.17 v1(213.33,128.55) ; v1(164.42,143.87) 164.59,144.04 164.59,144.04 UV18.C1 ; UV21.D2 v1(192.38,145.65) ; v1(184.43,144.07) 184.05,144.45 UV20.R9 ; UV21.G7 v1(189.98,149.66) ; v1(207.75,110.42) UV24.D2 ; UV25.K8 207.35,114.8 v1(207.77,114.38) ; UV19.G7 v1(168.19,145.65) ; v1(193.58,143.91) UV20.C9
  BOTTOM w0.305: UV1.U7 189.66,121.87 v1(189.97,122.18) ; UV1.R11 186.71,123.94 v1(186.71,124.18) ; UV1.AJ7 189.96,111.8 v1(189.96,111.59) ; UV1.G26 174.41,129.89 174.77,130.25 175.03,130.25 v1(175.04,130.24) ; UV1.H10 187.26,129.09 v1(187.66,128.69) 188.06,128.29 UV1.J9 ; v1(172.47,130.15) 172.12,130.15 UV1.G29 ; v1(178.98,126.24) 178.53,126.69 UV1.L21 ; v1(189.95,116.38) 189.66,116.67 UV1.AC7 ; UV1.J7 189.66,128.29 189.27,127.91 ; UV1.M11 186.72,125.44 v1(186.72,125.19) 186.72,124.94 UV1.N11 ; UV1.L12 185.06,127.09 UV1.K13 UV1.K11 ; v1(186.88,122.21) 186.46,121.79 UV1.U11 ; v1(186.89,115.09) 186.89,115.26 UV1.AD11 ; v1(185.96,119.35) 186.12,119.35 UV1.Y11 ; UV1.AG10 187.26,113.02 v1(187.69,112.59) ; v1(190,118.55) 189.66,118.89 UV1.Y7 ; v1(184.48,130.08) 184.29,129.89 UV1.G14 ; UV1.AK8 UV1.AL9 188.05,110.29 v1(187.65,109.88) ; v1(181.96,127.1) 182.37,126.69 UV1.L16 ; v1(179.63,130.33) 179.19,129.89 UV1.G20 ; v1(174.93,126.4) 174.64,126.69 UV1.L26 ; v1(176.85,126.19) 176.46,126.58 UV1.L23 ; UV1.K8 188.86,127.5 189.27,127.91 ; UV1.L7 189.26,126.89 v1(189.26,126.92) ; v1(189.35,124.56) 189.66,124.25 UV1.P7 ; 189.27,127.91 v1(189.27,127.92) ; v1(189.62,113.92) 189.66,113.96 UV1.AF7
  BOTTOM w0.508: RV185.1 217.2,133.97 216.28,134.89 CV302.1 v1(215.6,135.08) ; v1(215.6,141.3) CV291.1 CV292.1 ; v1(215.6,131.08) CV304.1 CV316.1 ; RV158.1 173.95,142.37 173.81,142.52 v1(173.81,144.08) ; CV259.1 v1(193.12,153.62) ; v1(163.99,129.49) 162.84,130.63 RV139.1 162.02,130.64 RV140.1 ; v1(198.64,104.41) 198.64,103.1 197.03,101.49 RV141.1 ; RV184.1 v1(204.55,131.97) ; v1(215.37,119.49) 216.96,119.49 217.32,119.13 RV186.1 ; v1(186.05,144.02) 185.84,143.81 185.84,140.9 186.53,140.21 RV163.1 ; CV301.1 v1(215.6,127.52) ; CV312.1 v1(215.6,135.97) ; RV142.1 v1(197.96,104.41) ; CV313.1 v1(215.6,128.41) ; CV295.1 v1(213.56,141.39) ; CV290.1 v1(215.61,136.85) ; CV300.1 v1(215.6,139.53) ; CV296.1 v1(214.83,141.39) ; v1(206.12,116.74) 205.9,116.52 202.81,116.52 202.18,115.89 RV187.1 ; CV240.1 CV241.1 189.94,152.61 189.18,151.84 v1(189.18,151.26) ; CV288.1 v1(215.61,137.74) ; CV314.1 v1(215.6,138.64) ; CV137.1 v1(203.55,144.08) ; CV282.1 v1(215.6,140.42) ; CV315.1 v1(215.6,129.3)
  vias: v1(161.67,158.32) v1(161.67,157.69) v1(162.26,158.32) v1(162.26,157.69) v1(164.99,153.26) v1(164.99,152.67) v1(165.57,153.26) v1(165.57,152.67) v1(166.15,153.26) v1(166.15,152.67) v1(166.74,153.26) v1(166.74,152.67) v1(182.16,153.57) v1(182.16,152.99) v1(182.74,153.57) v1(182.74,152.99) v1(183.33,153.57) v1(183.33,152.99) v1(183.91,153.57) v1(183.91,152.99) v1(212.19,151.01) v1(212.19,150.37) v1(212.83,151.01) v1(212.83,150.37) v4(159.59,154.02)
+1.35VGPUP: length 12.9
  TOP w0.102: v1(183.48,165.81) v2(183.48,165.29)
  IN3 w0.254: v1(189.89,171.08) 189.89,166.19 189.51,165.81 v1(183.48,165.81)
  BOTTOM w0.254: PR1107.2 v1(189.89,171.08)
+1.35VP: length 25.3
  TOP w0.102: v3(160.31,27.52) v2(160.9,27.52)
  IN2 w0.203: v3(145.96,26.31) 146.4,26.76 159.1,26.76 159.86,27.52 v3(160.31,27.52)
  IN2 w0.762: 154.71,25.35 148.36,25.35
  BOTTOM w0.203: v1(155.99,25.36) 156.13,25.23 PU200.19 ; PU200.5 159.31,26.77 159.8,27.26
  BOTTOM w0.254: PR207.2 160.55,27.76 v3(160.31,27.52) 160.06,27.52 159.8,27.26
  vias: v1(155.99,25.94) v3(146.97,25.11) v3(147.61,25.11) v3(147.92,27.38) v3(148.56,27.38) v3(149.19,27.38) v3(149.83,27.38) v3(150.46,27.38) v3(151.1,27.38)
+1.35VS_VGA: length 0.7
  TOP w0.102: v1(185.51,161.64) v4(185.51,162.33)
  vias: v1(181.19,160.35) v1(181.51,160.86) v1(181.83,160.35) v1(182.15,160.86) v1(182.46,160.35) v1(182.78,160.86) v1(183.1,160.35) v1(183.42,160.86) v1(183.73,160.35) v1(184.05,160.86) v1(184.88,161.64) v1(184.88,161.03) v1(185.51,161.03) v1(187.1,160.28) v1(187.42,160.79) v1(187.73,160.28) v1(188.05,160.79) v1(215.61,150.82) v1(215.61,150.19) v1(216.25,150.82) v1(216.25,150.19)
+3V_WLAN:
  vias: v1(92.8,148.93) v1(92.8,148.35) v1(92.8,147.76) v1(105.5,146.82) v1(106.09,146.82) v1(106.67,146.82) v1(117.19,149.49) v1(117.77,149.49) v1(118.35,149.49) v1(118.94,149.49) v2(92.79,146.6)
+3VALW: length 575.2
  TOP w0.203: UE1.22 191.59,33.78 CE2.1 ; UG1.2 71.03,40.14 70.78,39.89 ; v1(198.47,36.9) 198.06,37.31 UE1.33 ; UE1.125 180.4,38.51 CE5.2 ; v1(182.59,52.14) 183.1,52.14 183.19,52.06 UE1.96 ; UE1.9 186.39,34.6 186.27,34.49 185.64,34.49 185.49,34.34 CE6.2
  TOP w0.254: CG10.1 70.23,39.34 70.78,39.89
  TOP w0.508: v1(182.59,52.14) 181.96,52.78 181.96,54.82 176.61,60.16 176.61,63.68 175.72,64.56 175.72,71.55 175.39,71.88 175.39,78.97 v4(172.77,81.58) v1(170.02,84.34) ; v1(176.99,43.69) 176.99,43.34 177.77,42.57 RE71.1 ; CE2.1 v1(190.86,33.74) ; JPWR.1 45.34,88.24 v1(47.13,86.45) ; RE11.2 182.3,32.29 186.03,32.29 186.22,32.49 186.22,33.36 186.53,33.67 v1(186.53,33.74) 186.43,33.84 CE6.2 ; v1(127.41,165.43) 127.85,165.43 128.38,165.95 PR28.1 ; CE5.2 v1(179.43,36.7) ; v1(135.16,184.92) 134.33,184.92 133.63,185.62 PR3.2 ; v1(69.55,39) CG10.1 ; 189.92,56.01 190.95,57.03 194.47,57.03
  TOP w1.016: 47.46,29.03 47.46,43.64 36.99,54.11 36.99,72.02 42.32,77.35 44.86,77.35 46.19,78.69 46.19,80.53
  TOP w1.524: 204.75,51 200.89,51 198.78,53.11 198.78,54.62
  IN2 w0.508: v1(171.9,24.67) 172.34,25.12 172.34,27.42 174.27,29.35 v1(174.27,37.16) 174.27,41.11 176.85,43.69 176.91,43.69 ; 176.91,43.69 176.69,43.92 176.69,45.67 182.59,51.58 v1(182.59,52.14) ; 176.91,43.69 v1(176.99,43.69) ; v1(201.32,150.94) 201.32,151.46 197.89,154.89 197.89,155.78 196.75,156.92 176.43,156.92 171.8,161.55 171.8,179.88 v1(175.7,183.78)
  IN2 w1.016: 211.86,89.42 217.52,89.42 219.8,87.13 219.8,60.08 213.1,53.38 210.88,53.38 208.56,51.06
  IN2 w2.032: 204.5,50.37 203.23,49.1 203.23,43.7 204.94,41.99 204.94,41.98 205.13,41.79 205.13,36.21 202.53,33.6 202.53,31.03 201.26,29.76 199.14,29.76 197.45,28.08 197.45,23.19
  IN3 w0.254: v1(175.7,183.78) 174.3,182.38 154.59,182.38 151.86,185.11 135.35,185.11 v1(135.16,184.92)
  IN3 w0.508: v1(69.55,39) 67.77,37.22 59.73,37.22 50.39,27.89 v1(47.82,27.89) ; v1(195.29,57.22) 194.53,57.22 193.51,56.21 190.66,56.21 189.07,54.62 189.07,52.4 188.46,51.79 182.95,51.79 v1(182.59,52.14) ; v1(127.41,165.43) 127.41,163.45 128.98,161.88 128.98,160.29 129.5,159.78 144.11,159.78 144.49,159.4 v1(144.49,158.32) ; v1(174.27,37.16) 174.27,36.99 174.58,36.69 179.42,36.69 v1(179.43,36.7) 179.65,36.49 182.44,36.49 183.15,35.77 184.5,35.77 v1(186.53,33.74) 186.92,33.74 188.18,35 189.6,35 v1(190.86,33.74) 191.61,34.49 193.51,34.49 194.24,33.77 195.98,33.77 196.41,34.2 196.41,34.85 v1(198.47,36.9) ; v1(201.32,150.94) 201.32,150.45 202.85,148.93 211.48,148.93 216.82,143.59 216.82,124.97 216.25,124.4 216.25,105.42 211.99,101.17 211.99,99.58 210.72,98.31 210.72,95.07 211.55,94.24 211.55,92.21 212.17,91.59 v1(212.17,90.43)
  BOTTOM w0.254: v1(175.7,183.78) PC1205.1 177.28,182.87 PU1200.7
  BOTTOM w0.508: PR16.2 v1(135.16,184.92) 134.97,184.73 134.97,177.3 132.43,174.76 127.92,174.76 127.41,174.25 v1(127.41,165.43) ; v1(170.02,84.34) 170.02,90.75 171.85,92.59 RV109.1
  vias: v1(46.32,82.56) v1(46.32,81.98) v1(47.2,27.89) v1(94.25,29.28) v1(94.25,28.7) v1(94.25,28.12) v1(94.25,27.53) v1(94.83,29.28) v1(94.83,28.7) v1(94.83,28.12) v1(94.83,27.53) v1(195.74,56.78) v1(196.24,56.34) v1(197.33,21.85) v1(197.33,21.22) v1(198.02,21.85) v1(198.02,21.22) v1(206.47,51.32) v1(206.47,50.68) v1(207.1,51.32) v1(207.1,50.68) v1(211.48,90.43) v3(105.76,19.89) v3(106.39,19.89) v3(107.03,19.89) v3(107.72,19.89) v3(108.36,19.89) v3(132.93,11.89) v3(133.95,11.89) v3(134.97,11.89) v3(135.98,11.89) v3(136.87,12.65) v3(137.38,11.89) v3(137.89,12.65) v3(138.84,11.82) v3(139.86,11.82) v3(140.87,11.82) v3(141.89,11.82) v4(140.96,15.56) v4(197.48,56.42)
+3VALW_PCH: length 286.2
  TOP w0.254: v1(119.61,112.41) 119.29,112.41 118.42,111.54 118.05,111.54 117.92,111.67 C75.2
  TOP w0.508: v1(123.32,99.05) 123.21,98.93 RC127.1 123.63,98.19 124.74,97.08 124.74,95.85 126.64,93.96 126.64,92.45 127.47,91.62 151.13,91.62 152.95,89.8 163.3,89.8 163.91,90.41 v1(163.91,90.42) ; R264.1 150.97,104.23 151.29,103.91 v1(151.29,100.02) ; C78.1 122.45,113.74 v1(122.24,113.95) ; v1(125.11,109.71) 125.07,109.75 C81.1
  TOP w1.016: 122.2,50.24 122.2,40.84 125.63,37.41 136.05,37.41 140.36,33.09 140.36,29.54
  IN1 w0.381: v1(119.61,112.41) 120.7,112.41 v1(122.24,113.95)
  IN2 w0.508: v1(119.61,112.41) 119.93,112.41 120.35,112 120.35,110.02 120.74,109.62 120.74,104.16 122.27,102.64 123.32,102.64 ; 123.32,102.64 124.26,103.58 124.26,108.86 v1(125.11,109.71) ; 123.32,102.64 v1(123.32,99.05) 123.33,99.03 123.33,96.9 112.42,85.99 65.81,85.99 v1(64.54,87.26)
  BOTTOM w0.254: UC1.AC9 UC1.AA9 125.23,114 124.51,114 ; v1(125.11,109.71) 124.95,109.87 124.85,109.87 UC1.AH10 ; UC1.AE21 119,112.04 UC1.AE20 119.2,112.04 119.57,112.41 v1(119.61,112.41)
  BOTTOM w0.381: RC120.1 146.11,112.87 145.52,113.46 145.29,113.46 144.38,114.37 RC32.1 ; v1(122.24,113.95) 124.46,113.95 124.51,114
  BOTTOM w0.406: QH1.5 QH1.2 v1(149.27,114.53)
  BOTTOM w0.508: R2330.1 135.92,104.29 135.92,105.85 v1(135.98,105.91) 136.74,106.67 136.74,106.75 138.52,108.53 138.78,108.53 ; v1(64.54,87.26) 64.03,87.77 RC64.2
  BOTTOM w1.016: 122.52,52.27 122.43,52.18 117.3,52.18 116.53,52.95 116.53,55.04 115.45,56.13 115.45,77.67 121.71,83.93 160.59,83.93 163.35,86.69 163.35,87.07
  vias: v1(121.95,51.32) v1(122.58,51.32) v1(131.95,110.84) v1(132.54,110.84) v1(146.71,111.9) v1(147.3,111.9) v1(147.54,105.04) v1(148.17,105.04) v1(150.61,113.8) v1(150.61,113.22) v1(156.05,92.85) v1(156.49,92.4) v1(161.45,92.97) v1(161.89,92.53) v4(150.32,96.16)
+3VALW_PCH_GATE: length 4
  TOP w0.203: U2304.3 v1(141.55,21.35)
  BOTTOM w0.102: v2(141.85,18.58) 142.13,18.87 R416.2
  BOTTOM w0.508: v1(141.55,21.35) 142.16,20.74 C2314.1 142.13,20.66 R416.2
+3VALWP: length 12
  TOP w0.508: v1(129.82,11.38) PC102.1 PR109.1
  IN3 w0.254: v3(137.63,16.97) 137.44,16.97 133.51,13.03 131.03,13.03 129.82,11.82 v1(129.82,11.38)
  vias: v2(140.86,16.17)
+3VGS: length 256.6
  TOP w0.381: QV15.5 QV15.2 177.89,95.38 v1(178.21,95.7)
  TOP w0.508: v1(214.6,59.51) 214.6,58.56 213.39,57.35 210.09,57.35 209.64,57.8 PR828.1 ; v1(190.86,102.9) 189.64,101.68 v1(189.64,97.16) 189,96.52 186.53,96.52 ; v1(183.48,94.81) 183.03,94.36 RV199.1 ; v1(184.15,94.78) 184.13,94.76 QV28.2 ; RV91.1 173.25,92.54 172.77,93.02 v1(172.77,93.46) ; v1(179.92,92.71) RV90.1
  IN1 w0.508: v1(163.03,108.96) 163.03,109.98 163.53,110.49 163.53,112.78 165.57,114.82 165.57,116.22 166.72,117.36 167.29,117.36 167.67,117.74 167.67,118.81 166.39,120.09 162.9,120.09 158.46,124.53 156.08,124.53 155.29,125.32 155.29,127.2 156.68,128.6 156.68,133.23 160.09,136.64 160.09,150.91 157.13,153.87 v1(157.13,154.51)
  IN2 w0.508: v1(157.13,154.51) 157.13,155.47 161.56,159.9 168.3,159.9 170.91,162.51 170.91,181.24 169.35,182.8 169.35,183.5 v1(170.02,184.17)
  IN3 w0.508: v1(177,114.24) 177,113.41 178.81,111.61 178.81,110.45 179.29,109.96 179.29,107.83 179.03,107.57 179.03,104.53 179.39,104.18 v1(179.39,102.94) ; v1(190.86,102.9) 190.86,102.1 191.78,101.18 194.77,101.18 196.31,99.64 196.31,95.77 201.39,90.69 208.33,90.69 209.41,89.61 211.61,89.61 216.25,84.97 216.25,77.69 218.17,75.77 218.17,61.54 216.96,60.34 215.42,60.34 v1(214.6,59.51) ; v1(175.03,114.18) 174.66,114.18 174.34,114.49 170.71,114.49 169.83,113.61 169.06,113.61 168.43,112.97 166.78,112.97 166.08,112.27 166.08,111.73 165.44,111.1 164.75,111.1 164.34,110.69 164.34,109.33 163.97,108.96 v1(163.03,108.96)
  BOTTOM w0.381: CV326.2 161.59,108.77 161.27,109.09 UV13.5
  BOTTOM w0.508: v1(163.03,108.96) 162.84,108.77 CV326.2 ; v1(157.13,154.51) 158.14,155.52 161.04,155.52 164.01,158.49 RV105.1 ; v1(214.6,59.51) PR826.1 PR835.1 PR837.1 PR839.1 ; v1(172.77,93.46) 172.77,93.89 173.45,94.57 175.36,94.59 175.53,94.59 v1(176,95.07) ; CV102.1 180.94,93.03 v1(181.13,92.84) ; v1(176.6,100.45) 175.92,101.12 RV235.1 ; RV74.1 189.97,97.49 v1(189.64,97.16) ; PR1213.1 v1(170.02,184.17) ; v1(184.15,94.78) QV22.1 ; v1(190.86,102.9) RV73.1
  vias: v1(183.45,95.99) v1(184.09,95.99) v1(184.72,95.99) v1(185.36,95.99) v1(185.99,95.99) v4(180.48,98.44)
+3VLP: length 262.4
  TOP w0.203: CG4.1 70.32,43.38 70.63,43.07 UG1.15 ; UE1.111 180.72,44.11 180.39,44.44 v1(180.14,44.44) ; PU100.3 127.83,13.69 v1(127.82,13.68)
  TOP w0.508: v1(167.99,43.77) 167.99,41.9 170.32,39.57 173.97,39.57 v4(178.08,35.46) 179.04,34.5 179.04,32.63 181.43,30.23 190.59,30.23 193.26,27.57 RE49.2 ; v1(68.94,44.07) CG4.1 ; PC109.1 v1(127.82,13.68)
  IN1 w0.508: v1(171.32,21.16) 171.32,14.08 167.35,10.11 150.46,10.11 148.43,12.14 143.67,12.14 142.52,13.28 128.21,13.28 v1(127.82,13.68)
  IN2 w0.508: v1(167.99,43.77) 167.99,41.92 169.64,40.27 169.64,22.84 v1(171.32,21.16)
  IN3 w0.508: v1(68.94,44.07) 69.04,44.17 118.1,44.17 118.5,43.77 v1(167.99,43.77) 168.04,43.71 171.19,43.71 172.1,44.63 177.17,44.63 177.59,44.21 179.23,44.21 179.45,44.44 v1(180.14,44.44)
  BOTTOM w0.508: v1(171.32,21.16) 172.81,21.16 176.42,17.55 181.3,17.55 183.02,15.82 197.45,15.82 199.36,13.92 200.31,13.92
+3VS: length 322.3
  TOP w0.203: UA1.1 30.61,18.45 30.69,18.37 31.69,18.37 CA58.1 ; UA1.9 31.43,21.65 CA60.1 ; v1(23.14,18.3) 23.29,18.45 UA1.36
  TOP w0.254: UR1.4 177.32,19.06 177.63,18.76 177.96,18.76
  TOP w0.381: v1(16.09,107.39) 15.84,107.14 QX4.2 ; v1(15.84,109.74) QX4.5
  TOP w0.406: UC3.5 148.25,103.75 v1(148.81,103.2) 149.3,103.2 CC11.1
  TOP w0.508: CA58.1 32.1,17.97 CA57.1 32.1,16.33 32.46,15.97 34.15,15.97 34.51,16.33 34.51,17.92 34.26,18.17 v1(34.26,18.18) ; RS7.1 215.65,57.63 v1(215.65,57.2) ; v1(25.02,14.08) 24.78,14.32 RA9.1 ; PR1110.1 191.74,169.68 192.09,170.04 192.09,184.2 v1(193.07,185.18) ; v1(122.48,118.68) 122.19,118.68 121.9,118.39 C71.1 ; RC128.1 123.5,97.31 124.08,96.72 124.08,95.67 125.95,93.8 v1(125.95,92.87) ; v1(187.04,55.64) RE9.1 RE10.1 ; v1(31.33,23.7) 31.59,23.7 31.84,23.44 CA59.1 32.22,22.87 32.15,22.79 CA60.1 ; v1(30.89,99.26) 30.89,94.82 29.16,93.09 RX29.1 ; v1(32.99,26.43) 32.99,27.51 32.21,28.28 RA1.1
  TOP w1.524: 55.27,19.51 55.27,37.79 ; 184.37,88.97 183.73,88.97 177.54,82.78 177.54,72.73 179.07,71.19 180.5,71.19
  IN1 w0.508: v1(122.48,118.68) 122.75,118.68 123.06,118.37 123.06,116.52 123.39,116.19 124.03,116.19 v1(124.16,116.31) ; v1(25.02,14.08) 25.02,15.03 23.14,16.91 v1(23.14,18.3) 24.35,18.3 25.11,19.06 26.25,19.06 27.08,19.89 29.68,19.89 30.83,18.74 33.7,18.74 33.85,18.59 33.87,18.59 34.23,18.23 34.23,18.21 v1(34.26,18.18)
  IN1 w1.016: 65.24,16.33 56.16,16.33 55.46,17.03
  IN2 w0.508: v1(32.99,26.43) 32.99,27.51 31.42,29.07 24.76,29.07 21.86,26.17 v1(21.86,25.92) 21.66,25.92 20.73,26.86 16.93,26.86 v1(16.26,26.19)
  IN2 w1.524: 109.57,53.1 109.57,68.27 107.79,70.05 105.25,70.05 105.25,70.05
  IN2 w2.032: 212.69,99.83 214.75,99.83 216.9,101.98 216.9,119.56 219.08,121.74
  IN3 w0.508: v1(92.1,139.39) 91.79,139.39 91.34,138.95 91.34,137.62 91.62,137.34 v1(92.23,137.34) ; v1(15.84,109.74) 15.84,107.64 v1(16.09,107.39)
  BOTTOM w0.203: PU501.21 92.11,137.22 v1(92.23,137.34) 92.03,137.54 91.86,137.54 91.79,137.62 PU501.20
  BOTTOM w0.254: v1(124.16,116.31) 124.16,116.38 124.62,116.84 UC1.T9 125.25,116.73 125.61,116.37 UC1.U8 ; UC4.14 70.6,106.98 70.27,107.32 CC13.1 ; v1(122.48,118.68) 122.44,118.73 UC1.K14 UC1.K16 ; UC1.Y8 125.87,114.64 v1(125.87,114.94) UC1.W9 125.25,115 125.66,115.41 UC1.V8
  BOTTOM w0.356: v1(182.59,69.5) 182.15,69.94 JDIMM2.199
  BOTTOM w0.432: QC1.2 v1(145.39,108.89) QC1.5
  BOTTOM w0.508: v1(158.59,102.9) 158.59,93.36 161.51,90.43 161.51,86.12 160.88,85.48 C2327.1 159.35,85.5 U2302.8 ; PR842.2 PR808.1 209.91,53.68 v1(209.77,53.54) ; RA7.1 16.69,25.75 v1(16.26,26.19) ; v1(62.51,103.39) 62.1,103.8 60.95,103.8 60.66,103.51 60.66,102.9 60.99,102.57 RC362.1 ; 34.95,23.89 34.95,18.88 v1(34.26,18.18) ; R2332.1 147.93,109.9 R2331.1 ; R2332.1 148.43,110.06 148.62,110.25 v1(148.62,110.63) ; R2332.1 147.93,110.65 147.37,111.21 146.06,111.21 RC107.2 ; RE50.1 52.05,105.23 v1(52.3,104.99) ; v1(136.49,113.55) 136.5,113.56 RC121.1 ; v1(21.86,25.92) 21.84,25.94 RA2.1 ; v1(114.72,54.43) 113.71,55.44 113.71,79.1 124.11,89.5 124.11,91.03 v1(125.95,92.87) 125.45,93.37 RC3.1 ; RC75.1 v1(131.04,135.66) ; v1(142.84,118.46) 142.84,117.93 142.55,117.63 R2335.1 R2334.1 ; v1(43.65,85.8) 43.46,85.8 43.21,85.55 RL33.1 ; PR308.1 v1(149.77,151.01)
  vias: v1(31.4,99.64) v1(31.91,100.02) v1(53.97,17.7) v1(53.97,17.09) v1(54.58,17.7) v1(54.58,17.09) v1(55.01,39.84) v1(55.01,39.25) v1(55.59,39.84) v1(55.59,39.25) v1(66.07,108.31) v1(66.2,16.39) v1(66.2,15.78) v1(66.66,108.31) v1(66.81,16.39) v1(66.81,15.78) v1(67.24,108.31) v1(83.94,137.16) v1(83.94,136.57) v1(84.67,136.6) v1(85.4,39.9) v1(85.4,39.32) v1(85.98,39.9) v1(85.98,39.32) v1(86.57,39.9) v1(86.57,39.32) v1(87.15,39.9) v1(87.15,39.32) v1(87.74,39.9) v1(87.74,39.32) v1(88.32,39.9) v1(88.32,39.32) v1(100.1,150.25) v1(100.74,150.25) v1(101.37,150.25) v1(103.47,69.85) v1(104.04,70.05) v1(104.04,69.46) v1(108.93,51.41) v1(109.52,51.41) v1(110.1,51.41) v1(120.67,149.87) v1(120.67,149.29) v1(121.25,149.87) v1(121.25,149.29) v1(130.78,131.87) v1(131.36,131.87) v1(131.94,131.87) v1(137.44,122.18) v1(138.01,122.18) v1(138.65,122.18) v1(141,114.31) v1(177.28,55.48) v1(177.28,54.9) v1(177.28,54.28) v1(178.21,19.38) v1(178.79,19.38) v1(179.38,19.38) v1(182.59,68.87) v1(182.59,68.23) v1(184.1,91.32) v1(184.37,90.75) v1(184.69,91.32) v1(201.3,164.87) v1(201.3,164.29) v1(201.87,164.6) v1(211.41,96.94) v1(211.41,96.35) v1(211.99,96.94) v1(211.99,96.35) v1(217.02,175.09) v1(217.02,174.51) v1(217.61,175.09) v1(217.61,174.51) v1(218.39,53.24) v1(218.39,52.65) v1(218.39,52.07) v1(220.68,143.61) v1(220.68,143.03) v1(221.26,143.61) v1(221.26,143.03) v4(135.27,123.96)
+3VS_CAM: length 4.2
  TOP w0.127: v4(220.42,172.42) 220.04,172.42 219.04,173.42 RX27.2
  TOP w0.508: RX27.2 219.04,173.94 218.49,174.49 v1(218.45,174.49)
  BOTTOM w0.254: v1(218.45,174.49) JLVDS.29
+3VS_RT: length 24.2
  TOP w0.432: v1(193.45,158.82) v4(193.45,159.97) 193.45,163.46 193.77,163.78 QX6.5 ; QX6.2 196.75,163.78 v1(196.82,163.71)
  TOP w0.508: v1(208.12,160.6) 207.48,161.24 LX7.2 ; RX30.1 196.71,172.53 197.39,173.2 v1(197.39,173.47) 197.39,173.71 196.88,174.22 196.88,177.24 197.64,178 v1(197.64,179.33)
  BOTTOM w0.381: UX2.5 213.39,161.22 CX10.1
  BOTTOM w0.508: CX10.1 213.57,160.67 v1(213.31,160.41) ; RX4.2 200.35,167 v1(200.27,167.08) 199.25,167.08 LX8.2 ; RX168.1 v1(197.64,179.33) ; RX169.1 197.39,173.86 v1(197.39,173.47)
+5V_HDD:
  vias: v2(223.6,62.36)
+5V_PVDD: length 12.2
  TOP w0.203: v1(26.56,16.68) 26.48,16.76 UA1.41 ; v1(28.75,15.76) 28.75,16.38 28.48,16.64 UA1.46
  TOP w0.508: v1(28.75,15.76) 29.2,15.76 v2(29.9,15.06) CA56.1 31.33,14.98 CA55.1 RV54.2
  BOTTOM w0.508: v1(28.75,15.76) 28.75,16.19 28.73,16.2 28.73,16.46 27.91,17.29 CA53.1 26.84,17.47 CA54.1 26.83,16.94 v1(26.56,16.68)
+5V_USB_PWR1:
  vias: v1(18.62,65.76) v1(18.62,65.12) v1(19.26,65.76) v1(19.26,65.12) v4(18.99,63.93)
+5V_USB_PWR2:
  vias: v1(23.33,51.51) v1(23.33,50.87) v1(23.97,51.51) v1(23.97,50.87) v4(22.47,51.12)
+5V_USB_PWR3:
  vias: v1(14.19,31.32) v1(14.19,30.73) v1(14.77,31.32) v1(14.77,30.73) v4(14.09,32)
+5V_USB_PWR4: length 4.8
  TOP w0.102: v4(208.78,47.72) 208.8,47.7 JDB.3
  IN2 w2.032: 208.25,47.38 209.83,47.38 210.79,48.33
  vias: v1(204.88,47.64) v1(205.51,47.64) v1(206.15,47.64) v1(206.78,47.64) v1(212.37,49.79) v1(212.37,49.16) v1(213.01,49.79) v1(213.01,49.16)
+5VA: length 6.1
  TOP w0.102: 22.33,23.68 v2(22.94,24.29)
  TOP w0.203: UA1.26 23.61,22.45 22.39,23.66 22.39,23.68 CA51.1
  TOP w0.508: CA51.1 21.86,23.76 CA71.1 20.22,24.39 RV59.2
+5VALW: length 353.5
  TOP w0.254: v1(186.59,175.21) 184.88,175.21 184.43,174.76 184.43,174 183.67,173.24 PC1105.1 183.93,172.79 PU1100.7
  TOP w0.508: v1(29.01,11.49) LED1.2 ; PR8.1 135.61,186.07 140.43,186.07 141.44,187.08 146.63,187.08 147.48,186.23 149.77,186.23 150.19,186.23 v4(152.87,183.55) 154.47,181.95 159.47,181.95 159.81,181.62 159.81,181.62 160.63,180.84 161.59,180.23 162.46,179.89 164.12,178.23 172.64,178.23 173.26,177.62 v1(173.26,176.79) ; v1(200.03,59.83) 200.03,60.21 200.49,60.67 PR824.1 ; v1(84.8,23.44) 84.8,23.99 85.53,24.72 R10.1 ; R2347.1 v1(41.13,63.82) ; LED4.2 v1(56.01,11.5) ; v1(59.41,14.35) 58.97,13.9 RD46.1 ; LED3.1 v1(46.9,11.5)
  IN1 w0.508: v1(186.59,175.21) 185.68,176.12 173.93,176.12 v1(173.26,176.79)
  IN2 w0.508: v1(41.13,63.82) 40.63,64.31 29.43,64.31 27.83,62.71 v1(27.83,61.8) ; v1(212.88,40.97) 212.88,43.51 215.61,46.24 215.61,53.39 221.45,59.23 221.45,82.24 224.36,85.14 224.36,96.53 224.9,97.07 224.9,109.13 223.49,110.55 223.49,123.56 223.75,123.82 224.38,124.46 224.38,145.64 215.33,154.69 215.33,162.04 211.05,166.32 207.01,166.32 206.07,167.26 202.51,167.26 201.67,166.42 199.08,166.42 190.29,175.21 v1(186.59,175.21) ; v1(203.55,41.41) 201.01,43.95 201.01,48.91 198.66,51.26 198.66,58.77 199.71,59.83 v1(200.03,59.83)
  IN3 w0.508: v1(200.03,59.83) 200.03,64.04 198.72,65.35 193.56,65.35 192.02,66.89 192.02,79.34 188.43,82.93 v1(188.43,91.2)
  BOTTOM w0.203: PC204.2 159.67,21.74 159.31,22.11 v3(159.31,22.2) 159.31,22.4 158.91,22.8 PU200.12
  BOTTOM w0.508: v1(84.8,23.44) 84.81,23.45 96.22,23.45 97.78,25.01 v1(97.78,26.29) ; PR814.2 205.14,63.89 201.88,63.89 200.03,62.03 v1(200.03,59.83) 200.03,58.77 PR822.2 ; v1(212.88,40.97) 212.18,41.67 207.42,41.67 ; RV107.1 189.26,92.02 v1(188.43,91.2) ; PR206.1 v1(162.09,22.24) ; 206.02,41.67 203.8,41.67 v1(203.55,41.41)
  vias: v1(22.13,30.3) v1(22.13,29.72) v1(22.71,30.3) v1(22.71,29.72) v1(27.83,61.19) v1(27.82,60.59) v1(27.82,60.01) v1(29.81,54.56) v1(29.81,53.92) v1(30.45,54.56) v1(30.45,53.92) v1(97.78,27) v1(98.43,27) v1(98.43,26.29) v1(99.01,27) v1(99.01,26.29) v1(99.6,27) v1(99.6,26.29) v1(160.87,22.83) v1(160.87,22.24) v1(161.45,22.83) v1(161.45,22.24) v1(205.13,33.73) v1(205.13,33.09) v1(205.77,33.73) v1(205.77,33.09) v1(206.98,40.78) v1(206.98,40.19) v1(207.56,40.78) v1(207.56,40.19) v3(115.47,11.82) v3(115.47,10.81) v3(116.49,11.82) v3(116.49,10.81) v3(117.5,11.82) v3(117.5,10.81) v3(118.52,11.82) v3(118.52,10.81) v3(119.54,11.82) v3(119.54,10.81) v3(120.55,11.82) v3(120.55,10.81) v3(144.36,10.87) v3(144.36,10.23) v3(145,10.87) v3(145,10.23) v3(145.63,10.87) v3(145.63,10.23) v3(146.27,10.87) v3(146.27,10.23) v3(146.9,10.87) v3(146.9,10.23) v3(147.54,10.87) v3(147.54,10.23) v3(165,11.63) v3(165,11) v3(165.64,11.63) v3(165.64,11) v3(166.27,11.63) v3(166.27,11) v4(163.72,21.73) v4(205.44,35.96)
+5VALWP: length 26.6
  TOP w0.203: PU100.14 127.43,18.56 127,18.99 v3(127,19.28)
  TOP w0.508: v3(126.67,11.33) 126.71,11.37 PR104.2
  IN2 w0.254: v3(118.52,16.42) 118.53,16.42 120.48,14.48 124.98,14.48 126.65,12.8 126.65,11.36 v3(126.67,11.33)
  IN2 w0.508: v3(127,19.28) 127,18.84 127.09,18.75 127.09,17.18 126.77,16.86 126.77,16.45 125.3,14.97 120.92,14.97 v3(119.03,16.87)
  BOTTOM w0.508: v3(126.67,11.33) PC108.2
  vias: v2(115.66,16.12)
+5VS: length 216
  TOP w0.508: v1(22.95,105.55) 14.51,105.55 14.02,106.03 RX17.2
  TOP w1.016: 37.37,12.46 36.99,12.84 36.99,15.12 42.13,20.27 v2(42.13,23.44) 42.13,29.73
  IN1 w1.016: 36.86,11 33.24,11 ; 41.11,30.94 39.02,30.94 38.76,31.19 24.35,31.19 23.71,31.82 20.41,31.82 19.03,30.44 19.03,26.57
  IN2 w0.508: v1(88.92,131.21) 89.04,131.09 89.04,126.71 91.79,123.96 91.79,103.39 84.8,96.4 54.96,96.4 47.78,103.58 v1(44.8,103.58)
  IN2 w1.016: 27.14,95.9 27.14,97.23 33.68,103.77 43.21,103.77
  IN3 w0.508: v1(111.08,139.71) 110.84,139.71 110.44,140.1 110.44,144.1 109.29,145.26 94.43,145.26 91.66,142.49 91.66,140.41 90.71,139.46 90.71,133 v1(88.92,131.21)
  BOTTOM w0.203: v1(111.08,139.71) 111.15,139.71 111.48,140.03 PU502.2
  BOTTOM w0.508: v1(221.52,156.76) 227.27,156.76 227.63,156.4 RE60.1 ; PC503.1 82.9,134.89 83.79,134 85.06,134 86.16,132.89 86.16,131.65 86.63,131.18 88.88,131.18 v1(88.92,131.21)
  vias: v1(16.73,110.25) v1(17.36,110.25) v1(18.25,25.66) v1(18.84,25.66) v1(22.89,110.75) v1(22.89,110.12) v1(27.08,94.5) v1(27.08,93.86) v1(32.66,11.89) v1(33.24,11.89) v1(37.61,11.57) v1(38.19,11.57) v1(42.13,31.19) v1(42.13,30.6) v1(42.71,31.19) v1(42.71,30.6) v1(44.16,103.58) v1(102.18,32.97) v1(102.18,32.38) v1(102.18,31.8) v1(102.76,32.97) v1(102.76,32.38) v1(102.76,31.8) v1(103.34,32.97) v1(103.34,32.38) v1(103.34,31.8) v1(220.18,119.86) v1(220.18,119.28) v1(220.18,118.69) v1(220.18,118.11) v1(220.18,117.52) v1(223.84,59.48) v1(223.84,58.9) v1(223.84,58.32) v1(223.84,57.73) v1(223.84,57.15) v1(223.84,56.56) v1(223.84,55.98) v1(223.84,55.4)
+5VS_ODD: length 2.7
  TOP w0.102: v4(227.61,110.59) 227.61,112.49 JODD.9
+5VS_TOUCH: length 8.1
  TOP w0.508: JTOUCH.1 v1(23.71,95.91) 23.71,94.94 v4(23.26,94.49) RX29.2 RX24.1
  BOTTOM w0.508: v1(23.71,95.91) CX6.1 25.23,95.91 25.3,95.83 RX28.2
+AVCC33: length 8
  TOP w0.203: UX4.5 200.15,170.98 v1(200.12,171.02)
  BOTTOM w0.102: v2(196.4,166.94) 196.65,167.19 LX8.1
  BOTTOM w0.508: LX8.1 197.49,168.39 CX35.1 198.35,168.98 199.04,169.67 CX33.1 CX31.1 200,170.9 v1(200.12,171.02)
+AVDD: length 8.4
  TOP w0.102: v2(161.62,113.46) 161.62,113 161.99,112.64 LV12.1
  TOP w0.508: v1(167.09,115.41) 167.06,115.41 166.73,115.08 166.73,114.44 166.35,114.06 CV75.1 CV76.1 164.95,114.06 164.11,113.22 CV77.1 163.15,112.64 LV12.1
  BOTTOM w0.203: v1(167.09,115.41) 167.58,115.89 UV1.AD34
+DVCC33: length 11.5
  TOP w0.102: LX7.1 208.05,162.89 v4(208.36,162.58)
  TOP w0.203: 206.15,165.87 206.15,166.38 205.72,166.81 UX4.22 ; 203.8,165.87 204.11,166.18 204.11,166.5 204.12,166.5 UX4.18
  TOP w0.254: 194.97,166.19 194.98,166.19 RP57.7 ; 194.97,166.19 194.97,165.94 195.22,165.69 RP57.8 ; 194.97,166.19 194.97,167.33 195.32,167.68 v1(196.69,167.68)
  TOP w0.508: v1(199.8,174.38) 199.29,174.89 198.97,174.89
  vias: v1(204.69,165.3) v1(207.04,163.59)
+V18R: length 5.9
  TOP w0.102: v2(176.18,39.67) 176.47,39.67 176.67,39.88 178.1,39.88 178.97,39 CE16.1
  TOP w0.203: CE16.1 179.41,38.91 UE1.124
+VCC_3IN1: length 24.4
  TOP w0.254: UR1.5 177.82,20.61 v1(178.21,20.22)
  TOP w0.762: v1(182.27,27.84) 182.27,28.57 CR7.1 182.26,28.92 182.71,29.37 182.81,29.37 182.85,29.41 v4(186.59,29.41) 187.29,28.71 v1(188.32,28.71) 188.76,29.16 CR8.1
  BOTTOM w0.508: JREAD.4 189.2,29.16 188.75,28.71 v1(188.32,28.71) ; v1(182.27,27.84) 182.35,27.92 JREAD.11
  BOTTOM w0.762: v1(178.21,20.22) 178.64,20.65 180.24,20.65 181.58,21.98 181.58,22.68 182.35,23.46 182.35,27.76 v1(182.27,27.84)
+VCC_PWR_SRC: length 30.1
  TOP w0.508: v1(91.66,143.39) 93.72,145.45 v2(97.77,145.45) 100.03,143.19 102.58,143.19 104.87,145.48 114.09,145.48 116.32,143.24 116.93,143.24
  BOTTOM w0.508: v1(91.66,143.39) PR508.1
  vias: v1(116.74,142.44) v1(117.38,142.44)
+VCCHDA: length 15.4
  TOP w0.508: RC129.2 RC128.2 RC127.2 122.29,98.63 122.01,98.91 v2(122.01,102.82) 121.16,103.67 121.16,109.2 v1(121.44,109.48) 121.63,109.68 C77.1
  BOTTOM w0.254: UC1.AH14 122.04,110.09 v1(121.44,109.48)
+VCCIO_OUT: length 4.2
  TOP w0.102: v1(89.82,130.76) 89.82,130.21 v4(89.75,130.15)
  BOTTOM w0.508: R245.2 92.55,130.76 v1(89.82,130.76)
+VCCIO_OUT_R: length 5.2
  BOTTOM w0.254: R245.1 92.75,129.56 92.75,127.84 93.93,126.65 93.93,126.46 94.38,126.01 UC1.A59
+VCCIOA_OUT: length 31.6
  TOP w0.254: RC71.1 117.75,124.86 v4(118.19,125.3)
  TOP w0.508: v1(118.67,123.29) 118.36,123.29 118.05,123.6 118.05,123.61 117.75,123.91 RC71.1
  IN1 w0.508: v1(135.87,129.41) 131.83,129.41 131.22,130.02 129.18,130.02 127.7,128.55 126.33,128.55 125.71,129.17 123.42,129.17 v1(122.75,129.84)
  IN2 w0.508: v1(122.75,129.84) 122.42,130.17 117.72,130.17 117.19,129.64 117.19,127.48 117.63,127.04 117.63,124.28 118.62,123.29 v1(118.67,123.29)
  BOTTOM w0.254: v1(118.67,123.29) 118.76,123.29 UC1.E20
  BOTTOM w0.508: v1(135.87,129.41) 135.66,129.21 RC78.1
+VCCRTCEXT: length 2.8
  TOP w0.254: C52.1 125.01,111.62 v2(125.62,111.62) 126.15,111.62 126.58,111.19 v1(126.58,111.14)
  BOTTOM w0.254: v1(126.58,111.14) 126.58,111.36 UC1.AE7
+VDD1DI: length 6.8
  TOP w0.508: LV13.1 163.08,115.64 CV80.1 164.62,115.64 164.82,115.84 CV78.1 CV79.1 166.32,116.02 v2(167.64,116.02) 168.02,116.02 v1(168.2,116.2)
  BOTTOM w0.254: v1(168.2,116.2) 168.2,116.63 UV1.AC33
+VDD_MEM15_REFDA: length 24.7
  IN3 w0.508: 173.32,126.43 171.24,126.43 169.95,127.71 167.26,127.71 164.98,130 164.37,130 163.92,130.44 163.92,130.93 162.4,132.46 162.4,133.36 v1(160.87,134.88)
  BOTTOM w0.254: v1(180.92,127.18) 180.46,126.72 UV1.L18
  BOTTOM w0.508: CV220.1 RV146.1 RV139.2 160.74,130.63 159.93,131.43 v2(159.93,134.19) 160.63,134.88 v1(160.87,134.88)
+VDD_MEM15_REFDB: length 3.9
  TOP w0.102: v2(195.43,102.66) v1(195.43,103.27)
  BOTTOM w0.381: v1(185.08,120.23) 185.46,119.85 UV1.Y12
  BOTTOM w0.508: CV223.1 196.2,102.46 RV141.2 ; CV223.1 v1(195.43,103.27) ; CV223.1 RV148.1
+VDD_MEM15_REFSA: length 27.5
  TOP w0.102: v1(163.03,134.63) 162.82,134.63 v2(162.46,134.99)
  IN3 w0.508: v1(179.67,127.26) 179.11,127.26 178.65,126.79 176.53,126.79 176.3,126.57 175.61,126.57 175.01,127.16 171.71,127.16 168.56,130.31 166.46,130.31 165.32,131.45 164.3,131.45 163.03,132.72 v1(163.03,134.63)
  BOTTOM w0.254: UV1.L20 179.46,127.05 v1(179.67,127.26)
  BOTTOM w0.508: RV140.2 RV147.1 CV221.1 161.11,134.04 161.81,134.75 162.92,134.75 v1(163.03,134.63)
+VDD_MEM15_REFSB: length 23.6
  TOP w0.102: v2(196.12,106.06) v1(196.12,106.63)
  IN3 w0.508: v1(185.01,119.19) 186.08,118.11 186.08,116.12 186.45,115.76 187.05,115.76 187.48,115.33 187.48,114.03 188.08,113.42 188.71,113.42 188.77,113.36 189.35,113.36 189.38,113.33 189.92,113.33 190.27,112.98 191.23,112.98 192.18,112.02 192.18,111.83 192.56,111.46 193.96,111.46 194.46,110.95 194.46,108.28 v1(196.12,106.63)
  BOTTOM w0.381: v1(185.01,119.19) 185.46,118.73 UV1.AA12
  BOTTOM w0.508: RV142.2 RV149.1 CV224.1 196.18,106.56 v1(196.12,106.63)
+VDDC_CT: length 30.1
  TOP w0.508: CV174.1 CV173.1 173.99,114.78 174.27,114.49 174.27,113.47 v1(173.99,113.2)
  IN3 w0.508: v1(176,98.3) 175.96,98.34 175.96,101.67 176.48,102.19 176.48,105.4 175.05,106.84 174.91,106.84 174.3,107.45 174.3,110.31 173.3,111.31 173.3,112.6 173.89,113.2 v1(173.99,113.2)
  BOTTOM w0.254: UV1.AF27 UV1.AF26 UV1.AG26 174.46,113.67 v1(173.99,113.2)
  BOTTOM w0.279: v1(173.99,113.2) 173.5,113.69 UV1.AG27
  BOTTOM w0.508: LV19.2 CV170.1 CV172.1 CV171.1 174,96.73 175.57,98.3 v1(176,98.3)
+VDDCI: length 27.3
  TOP w0.508: CV208.1 183.51,121.8 v1(183.92,122.21) 184.25,122.53 CV204.1 ; CV322.1 183.89,117.78 183.89,117.24 v1(183.83,117.18) ; v1(181.96,125.12) 181.53,125.55 CV212.1 ; CV206.1 CV211.1 182.6,125.44 v1(182.88,125.16) ; v1(184.88,123.21) 184.88,124.18 CV209.1 ; v1(176.88,125.19) 177.12,125.43 CV324.1
  BOTTOM w0.381: UV1.N13 UV1.R12 185.47,123.69 v1(185.98,124.21) ; UV1.N13 UV1.N15 183.4,124.69 v1(182.9,124.19) 182.46,123.75 UV1.R16 ; UV1.N13 UV1.M15 ; v1(181.96,125.12) 181.53,124.69 UV1.N17 UV1.M18 ; UV1.AD16 UV1.AC15 183.46,116.81 v1(183.83,117.18) 184.34,117.69 UV1.AB13 ; v1(183.92,122.21) 183.92,122.23 183.47,122.69 UV1.T15 ; UV1.AB13 184.98,117.17 185.05,117.17 v1(185.06,117.17) ; UV1.AB13 184.3,117.85 184.3,118.53 UV1.AA13 UV1.Y13 ; UV1.M23 176.46,125.61 v1(176.88,125.19) 177.04,125.19 177.46,124.77 UV1.N22 ; v1(182.85,120.16) 183.38,120.69 UV1.V15 ; UV1.M16 182.46,125.58 v1(182.88,125.16) ; UV1.N20 179.42,124.69 v1(178.91,125.19) ; v1(185.01,116.23) 184.47,115.69 UV1.AD13
  BOTTOM w0.508: v1(185.01,116.23) 185.46,116.68 UV1.AC12
  vias: v1(182.97,115.19) v3(193.89,182.45) v3(193.89,181.81) v3(193.89,181.18) v3(193.89,180.54) v3(193.89,179.91) v3(193.89,179.27) v3(194.53,182.45) v3(194.53,181.81) v3(194.53,181.18) v3(194.53,180.54) v3(194.53,179.91) v3(194.53,179.27) v4(185.72,122.88)
+VDDCIP: length 14.9
  BOTTOM w0.254: PR1208.1 180.81,188.22 181.2,188.61 187.13,188.61 v2(187.26,188.48) 191.8,188.48 192.24,188.03 192.24,185.56 192.05,185.37
+VDDR4: length 18.6
  TOP w0.102: v2(184.86,99.43) 184.81,99.38 v1(184.81,98.72)
  IN1 w0.508: v1(183.54,104.02) 184.3,104.78 184.3,106.3 183.86,106.75 183.86,111.76 184.14,112.04 184.14,113.31 v1(185,114.18)
  IN3 w0.508: v1(184.81,98.72) 184.11,99.42 184.11,103.45 v1(183.54,104.02)
  BOTTOM w0.508: v1(184.81,98.72) 185.01,98.92 LV20.2
  vias: v1(184.94,115.19) v1(186.02,114.18)
GND: length 3284.1
  TOP w0.203: v1(180.24,43.61) 180.24,43.61 180.55,43.31 UE1.113 ; UG1.4 v1(71.83,39.67) ; v1(184.16,50.1) 183.99,50.28 UE1.94 ; UA1.4 30.8,19.65 v1(30.95,19.5) ; UE1.11 187.19,36.82 187.06,36.95 v1(187.06,37.09) ; v1(73.45,39.8) 73.33,39.8 73.03,40.1 UG1.7 ; v1(71.22,43.52) 71.43,43.31 UG1.13 ; UX4.6 202.26,170.58 v1(202.85,171.17) ; UE1.24 192.39,36.77 v1(192.14,37.02) ; UX4.16 203.32,166.58 v1(203.26,166.52) ; UE1.35 196.05,38.11 v1(195.98,38.17) ; U2304.11 v1(141.95,24.9)
  TOP w0.229: UV20.G9 190.38,144.66 190.37,144.66 190.37,145.03 190.38,145.04 UV20.G8 ; UV25.G8 207.14,112.42 207.13,112.43 206.76,112.43 206.76,112.42 UV25.G9 ; UV18.G9 167.79,150.65 167.79,150.64 167.79,150.28 167.79,150.27 UV18.G8 ; UV18.T1 174.6,144.85 v1(173.78,144.85) ; UV22.G9 212.75,134.5 212.74,134.5 212.38,134.5 212.37,134.5 UV22.G8
  TOP w0.254: v1(213.3,134.12) 212.95,134.46 UV22.G9 ; UV18.M1 172.27,143.97 172.84,143.97 v1(172.96,144.1) ; UV25.G9 206.55,112.46 v1(206.21,112.81) ; UV18.E8 v1(165.79,150.45) UV18.D8 ; UV22.M1 206.07,130.02 206.07,129.45 v1(206.2,129.33) ; v1(210.76,108.31) 210.87,108.42 UV25.B3 ; v1(190.78,151.26) 190.38,150.86 UV20.G1 ; v1(206.07,112.03) 206.48,111.62 UV25.F9 ; v1(168.17,151.2) 167.83,150.85 UV18.G9 ; UV18.M9 172.16,150.48 v1(172.16,150.46) ; UV20.T1 183.66,151.34 184.25,151.34 v1(184.39,151.2) 184.73,150.85 UV20.P1 ; v1(194.78,151.26) 194.38,150.86 UV20.B1 ; UV25.M9 206.93,116.79 v1(206.95,116.79) ; v1(213.75,116.41) 213.75,116.42 UV25.M1 ; v1(206.08,119.84) 206.3,119.62 UV25.T9 ; v1(188.42,144.81) 188.78,145.17 UV20.J8 ; v1(212.56,113.62) 212.16,114.02 UV25.J2 ; v1(173.78,144.85) 173.39,144.46 UV18.P1 ; UV22.J8 212.23,132.9 v1(212.6,132.54) ; UV22.D8 212.15,136.9 v1(212.55,136.5) UV22.E8 ; UV25.J8 207.27,114.02 v1(206.91,114.38) ; UV22.B9 v1(213.35,138.9) ; v1(194.49,148.66) 194.38,148.77 UV20.B3 ; v1(184.4,144.85) 184.78,144.47 UV20.P9 ; UV22.J2 207.35,132.9 v1(206.95,133.3) ; v1(168.99,144.85) 169.39,145.25 UV18.J2 ; UV18.E2 v1(165.79,145.65) ; v1(212.56,130.13) 212.58,130.13 UV22.M9 ; UV18.P9 173.39,150.84 v1(173.76,150.46) ; v1(169.75,150.5) 169.39,150.13 UV18.J8 ; v1(186,144.85) 186,144.83 UV20.M9 ; UV22.T1 206.07,127.79 206.07,128.38 v1(206.21,128.51) 206.55,128.86 UV22.P1 ; UV20.E2 v1(192.38,149.66) ; UV22.E1 206.53,136.1 v1(206.1,136.54) 206.46,136.9 UV22.D1 ; UV20.G9 190.33,144.45 v1(189.99,144.11) ; v1(167.39,144.05) 167.79,144.45 UV18.G1 ; UV22.B3 208.64,138.5 v1(208.75,138.61) ; UV20.D1 192.78,150.95 v1(192.42,151.31) 191.98,150.88 UV20.E1 ; UV20.E8 v1(192.38,144.85) UV20.D8 ; v1(189.18,150.46) 188.78,150.06 UV20.J2 ; UV18.B9 v1(163.39,151.25) ; RP45.6 73.42,112.4 v1(73.17,112.15) 73.42,111.9 RP45.7 ; UV20.B9 v1(194.78,144.05) ; UV18.B1 v1(163.39,144.05) ; UV20.T9 183.18,144.2 v1(182.96,143.98) ; UV25.E2 v1(211.75,110.42) ; v1(206.15,134.9) 206.55,134.5 UV22.G1 ; UV25.P9 206.57,118.02 v1(206.95,118.39) ; UV20.M1 185.9,151.34 185.33,151.34 v1(185.2,151.21) ; UV22.E2 v1(207.75,136.5) ; UV25.B1 v1(213.35,108.02) ; UV20.F9 191.18,144.38 v1(190.77,143.97) ; UV25.D1 213.05,110.02 v1(213.41,110.38) 212.98,110.82 UV25.E1 ; UV25.D8 v1(206.95,110.42) UV25.E8 ; v1(206.15,107.22) UV25.A9 ; v1(195.58,144.05) UV20.A9 ; v1(177.61,104.98) 177.12,105.47 RP47.4 ; v1(212.56,128.53) 212.94,128.9 UV22.P9 ; UV18.D1 165.39,144.36 v1(165.75,144) 166.19,144.43 UV18.E1 ; v1(174.51,151.34) 174.51,151.33 UV18.T9 ; UV18.F9 167.12,150.85 v1(167.59,151.33) ; UV25.P1 212.95,118.06 v1(213.3,118.41) 213.44,118.55 213.44,119.14 UV25.T1 ; v1(213.43,127.08) 213.21,127.3 UV22.T9 ; UV22.B1 v1(206.15,138.9) ; UV22.F9 212.95,135.17 v1(213.43,134.7) ; UV25.G1 212.96,112.42 v1(213.35,112.02) ; UV18.B3 163.79,146.68 v1(163.81,146.71) ; UV25.B9 v1(206.15,108.02) ; v1(162.59,151.25) UV18.A9 ; v1(213.35,139.7) UV22.A9
  TOP w0.305: JTP.4 69.35,111.11 69.12,111.34 v1(68.95,111.34)
  TOP w0.381: v1(205.2,44.03) 205.2,43.38 205.87,42.71 UI5.1 ; v1(181.96,126.13) 182.02,126.2 182.02,126.3 182.56,126.84 CV211.2 ; U2303.3 44.77,66.61 v1(44.22,67.16) ; PQ2.4 131.17,167.51 131.35,167.33 v1(131.35,166.95) ; DE1.1 171.4,44.21 171.77,43.84 v1(172.19,43.84) ; v1(128.03,169.31) 128.03,169 128.22,168.81 PQ2.1 ; UE2.3 179.43,51.83 v1(179.61,51.66) ; PQ1.1 128.22,172.62 128.61,172.23 128.61,171.99 128.63,171.98 PC5.2 ; v1(92.65,119.5) 92.8,119.66 92.8,119.77 C80.2 ; UI4.1 20.34,30.44 v1(20.48,30.3) ; PR32.2 131.8,161.8 131.3,162.3 PQ3.4 ; UI2.1 29.26,52.06 29.43,51.89 29.43,51.67 29.2,51.45 v1(28.95,51.45) ; UD1.3 49.37,16.09 49.27,15.99 v1(49.27,14.69)
  TOP w0.406: v1(147.32,106.82) 146.95,106.46 UC3.3 ; PD101.1 v1(123.38,13.98)
  TOP w0.457: PC856.2 180.2,122.8 v1(179.96,123.04)
  TOP w0.508: CG10.2 v1(70.23,37.39) ; CD29.2 v1(103.85,73.54) ; CE16.2 177.61,38.22 v1(177.89,37.95) ; v1(190.7,157.88) 190.45,157.62 CV145.2 ; CV127.2 156.62,111.68 CV126.2 154.67,111.68 CV131.2 ; CV127.2 CV130.2 ; CV127.2 v1(156.68,110.94) ; CA56.2 32.73,14.5 CA55.2 33.37,13.98 33.81,13.54 v1(33.81,12.35) ; QX1.3 214.91,175.5 v1(214.91,175.08) 215.17,175.08 215.55,174.7 215.55,173.99 CX1.2 ; v1(220.75,92.28) 220.63,92.28 220.45,92.45 PC603.2 PR604.2 ; PC13.1 131.22,180.8 v1(131.6,181.18) 131.09,181.68 PR26.1 ; v1(157.43,64.95) 157.89,64.49 CD50.2 157.33,63.4 CD38.2 ; CD3.2 51.27,64.21 v1(51.84,64.78) ; v1(177.26,26.44) 177.32,26.5 CR6.2 ; v1(35.78,22.08) CA64.1 ; v1(218.81,64.08) CS6.2 CS5.2 ; v1(92.65,116.51) 92.63,116.49 RC132.2 ; v1(178.51,38.17) CE5.1 ; v1(172.11,107.38) 172.81,106.68 CV108.2 ; v1(177.61,104.98) 178.32,105.69 RV64.1 ; SW1.6 200.23,31.81 v1(200.24,31.82) ; v1(193.59,32.08) 193.96,32.45 CE29.2 ; v1(155.22,115.83) CV128.2 CV129.2 ; v1(182.75,105.26) CV213.2 ; v1(177.96,123.19) 177.84,123.19 PC865.2 ; v1(169.75,125.99) 169.82,126.06 CV151.2 171.21,126.62 CV149.2 ; CG7.2 73.94,39.32 73.46,39.8 v1(73.45,39.8) ; CV308.2 v1(217.95,123.91) ; v1(217.89,129.3) 217.84,129.25 RV191.2 ; v1(163.03,102.82) 162.91,102.94 CV110.2 ; v1(174.91,121.26) 174.52,120.87 PC853.2 ; v1(177.9,126.16) 177.77,126.29 CV324.2 ; v1(103.92,124.08) 103.63,124.37 PC903.2 ; CV194.2 186.54,115.9 v1(186.98,116.34) 186.53,116.79 CV156.2 ; CA58.2 v1(33.62,17.98) 33.62,17.03 CA57.2 ; CI24.2 v1(15.45,34.99) ; v1(177.96,118.3) 178.21,118.55 PC850.2 ; RC163.2 88.69,124 88.69,123.43 v1(88.61,123.35) ; RC87.1 126.91,123.7 v1(127.22,123.39) ; C87.2 119.8,114.45 v1(119.66,114.31) ; v1(201.27,39.24) 200.69,39.83 CE11.2 ; CV234.2 v1(187.53,156.16) ; PC848.2 182.29,115.66 v1(181.96,115.34) ; v1(207.17,98.75) 207.1,98.75 206.66,99.2 RV145.1 ; v1(175.98,116.35) 176.04,116.28 PC861.2 176.19,115.56 CV190.2 ; v1(118.44,109.89) 118.44,110.36 119.08,111 C67.2 ; PC866.2 175.37,118.54 175.84,118.06 v1(175.96,118.06) ; v1(61.97,107.3) 62.24,107.3 62.59,106.95 JTP.8 ; v1(133.99,112.01) 134.37,112.39 CC34.2 ; CV173.2 CV174.2 172.68,113.86 171.91,113.08 RV204.2 171.91,112.25 v1(171.33,111.67) ; JDB.8 211.09,52.7 211.5,52.29 v1(211.5,52.13) 211.07,51.7 JDB.7 ; CD36.2 150.16,63.46 CD43.2 150.65,64.08 150.33,64.4 v1(150.33,64.72) ; v1(35.97,19.25) CA22.2 CA21.2 ; v1(28.1,11.25) 28.1,11.91 RA32.2 ; CV269.2 v1(185.24,155.91) ; v1(204.42,144.86) CV199.2 203.8,144.92 CV198.2 ; CD6.2 v1(65.43,62.48) ; v1(210.47,43.83) 210.47,43.64 210.07,43.24 CI32.2 CI25.2 ; PC852.2 177.82,116.17 v1(177.96,116.32) ; v1(23.27,28.97) RA31.2 ; CV207.2 180.45,126.48 CV210.2 181.27,126.51 CV212.2 181.63,126.46 v1(181.96,126.13) ; CD64.2 44.9,61.12 v1(44.86,61.08) ; JKB.31 v1(221.45,134.27) ; CV205.2 184.41,120.65 CV203.2 184.42,120.72 CV208.2 184.42,121.73 184.89,122.2 v1(185.01,122.2) ; C52.2 124.49,112.86 124.28,113.08 v1(123.78,113.08) 123.85,113.15 C68.2 ; PC851.2 180,118.4 v1(179.96,118.36) ; v1(117.97,132.97) 118.92,133.92 CC6.1 ; v1(152.93,73.54) 152.55,73.54 152.17,73.16 CD40.2 153.01,71.65 153.51,72.15 CD48.2 ; PC845.2 176.42,118.8 v1(175.96,119.26) ; CE30.2 174.96,44.39 v1(175.62,43.72) ; C75.1 v1(116.62,110.75) ; v1(151.29,122.18) 151.24,122.13 Q2308.3 ; CE12.2 188.32,32.69 CE28.2 v1(189.06,32.7) ; v1(154.36,109.13) 154.5,109.27 RV201.2 CV335.2 ; v1(170.46,130.3) 169.62,129.47 CV143.2 CV150.2 ; v1(32.11,55.75) CI26.2 CI7.2 ; CD10.2 76.83,71.6 v1(78.01,72.78) ; v1(135.98,164.22) 136.44,164.68 PQ706.3 ; v1(190.86,32.83) CE2.2 ; v1(194.89,155.91) CV271.2 CV258.2 CV259.2 v1(193.12,155.91) ; v1(120.23,118.57) 120.09,118.57 C83.2 ; PR2.2 132.86,171.98 v1(132.5,172.34) ; v1(198.73,168.25) 198.73,167.98 198.68,167.93 CX32.2 198.68,166.75 RX5.1 ; CM46.1 116.87,147.39 116.74,147.27 116.74,147.2 v1(116.42,146.89) ; CD32.2 CD33.2 122.42,72.53 v1(122.77,72.88) ; v1(123.9,117.46) 123.86,117.41 C50.2 ; v1(122.15,114.95) C82.2 C78.2 ; CV136.2 197.49,157.93 196.67,157.12 v1(196.67,156.04) CV256.2 ; v1(197.88,162.3) 198.4,161.78 CX47.2 ; PC862.2 179.11,113.04 v1(178.96,113.19) ; CG5.2 v1(73.56,45.29) ; v1(218.09,165.24) 218.09,165.43 217.83,165.68 CX9.2 ; RV206.1 176.25,125.54 v1(175.89,125.17) ; CV237.2 CV236.2 v1(184.35,155.85) ; v1(196.47,170.44) 196.47,170.86 RX25.2 ; CD35.2 153.78,63.46 CD45.2 154.27,64.02 v1(153.62,64.67) ; CM40.2 95.23,146.49 v1(94.83,146.89) ; CV154.2 189.19,108.31 v1(189.25,108.26) ; R16.2 v1(89.36,19.19) ; RD52.2 v1(53.14,12.2) ; RE326.2 178.58,49.55 178.27,49.86 RE47.1 v1(177.56,50.35) ; v1(140.11,182.47) 139.74,182.1 PD2.1 ; v1(113.95,124.08) 113.66,124.37 PC907.2 ; v1(74.32,65.16) 74.32,64.02 73.88,63.57 CD4.2 72.66,63.4 CD17.2 ; v1(67.2,22.63) CA31.2 66.09,22.98 CA30.2 ; v1(179.96,124.28) 180.26,123.98 PC857.2 ; CV306.2 v1(218.39,108.41) ; CA29.2 66.15,25.68 v1(66.2,25.73) ; v1(171.75,50.76) 171.86,50.76 172.44,50.18 CE32.2 ; v1(180.94,121.31) 180.37,120.74 PC859.2 ; PC906.2 111.15,124.37 v1(111.44,124.08) ; RX33.2 v1(205.59,175.97) 205.07,176.49 CX37.2 ; CV97.2 165.34,127.86 v1(165.25,127.77) ; v1(164.61,112.61) 165.15,113.15 CV76.2 CV75.2 ; v1(210.09,175.84) 210.09,176.29 210.4,176.6 211.19,176.6 RX20.2 ; v1(95.41,24.39) 95.72,24.71 C2309.2 ; v1(137.44,164.73) 137.82,165.11 PC4.2 PC3.2 ; C2322.2 94.52,24.67 v1(94.77,24.42) ; v1(211.67,50.7) 211.67,50.7 JDB.6 ; v1(173.66,108.33) 173.69,108.36 CV109.2 ; CC3.1 129,95.58 v1(128.81,95.39) 128.74,95.32 128.74,95.32 128.54,95.11 128.53,95.11 128.22,94.8 RE2.1 ; R159.2 150.22,102.56 v1(150.41,102.75) CC11.2 ; RV171.2 CV231.2 189.78,155.45 v1(189.78,155.97) ; C51.2 150.41,105.97 v1(149.89,106.49) ; RR1.2 174.56,17.16 v1(174.17,17.55) ; CD49.2 156.94,72.15 156.44,71.65 CD39.2 155.73,73.04 v1(156.05,73.35) ; SW1.2 v1(201.17,28.16) ; v1(49.99,61.8) 49.48,62.3 CC35.2 ; CV318.2 v1(218.39,110.19) ; v1(201.52,116.84) 201.56,116.79 RV196.2 CV280.2 RV179.2 ; RC113.2 134.6,117.85 v1(134.45,117.7) ; CG1.2 71.83,46.28 v1(72.04,46.48) ; PC100.2 119,15.23 v1(118.95,15.28) ; v1(141.95,23.12) 141.89,23.19 C2313.2 C2311.2 ; v1(161.68,100.59) 161.4,100.31 CV124.2 CV125.2 159.25,99.83 CV123.2 ; PC902.2 101.12,124.37 v1(101.41,124.08) ; C76.2 122,112.66 v1(122.05,112.61) ; PC910.2 96.87,116.41 95.99,115.53 v1(95.45,115.53) ; v1(175.97,123.08) 175.43,123.62 CV196.2 CV195.2 ; v1(171.29,108.27) 171.36,108.35 CV83.2 CV84.2 ; CC7.1 114.45,135 114.45,135.01 114.45,135.34 v1(114.27,135.52) ; v1(114.08,149.49) CM43.2 114.7,147.7 RM11.1 ; v1(163.22,167.08) PC710.2 ; v1(174.91,118.08) 175.37,117.63 PC854.2 PC844.2 ; Q8.3 88.71,20.94 v1(89.83,19.82) ; CV139.2 220.49,122.76 v1(220.72,122.98) ; PC1302.2 193.75,63.21 v1(194.12,63.57) ; v1(182.96,122.19) 182.96,122.2 PC840.2 ; JSPK.5 v1(73.54,24.46) ; v1(60.16,97.67) 60.23,97.74 CC14.2 ; LE2.1 194.62,55.5 RE5.1 CE8.2 196.31,55.28 v1(196.37,55.34) ; PC864.2 177.27,122.71 v1(176.95,123.03) ; C57.2 128.74,121.04 v1(128.68,120.98) ; CD63.2 v1(53.03,15.89) ; v1(66.9,64.66) 67.61,63.96 CD16.2 68.98,63.96 CD5.2 ; v1(171.25,104.78) 171.49,105.02 CV87.2 CV88.2 ; C71.2 121.69,117.38 v1(122.3,116.77) ; CE15.2 v1(178.79,56.22) CE19.2 ; v1(82.34,136.1) 82.38,136.07 PC523.2 ; R2.2 90.95,134.94 v1(91.41,135.39) ; v1(173.25,133.83) 172.66,133.24 CV138.2 ; CR3.1 v1(180.14,16.2) ; CV311.2 v1(217.95,126.64) ; v1(173,123.07) 173.29,123.36 CV147.2 CV148.2 ; Q2307.3 183.94,59.05 v1(184.21,59.32) ; DA12.1 16.44,14.34 v1(15.76,13.66) ; v1(182.65,54.68) 183.18,54.68 CE26.2 ; CA59.2 33.62,22.62 v1(33.68,22.55) 33.49,22.36 CA60.2 ; CE31.2 v1(197.55,32.89) ; v1(82.01,64.65) 82.58,64.08 CD22.2 CD21.2 ; v1(197.82,164.69) 198.16,165.03 198.81,165.03 CX48.2 ; CV209.2 183.54,124.46 CV204.2 183.97,123.75 183.41,123.19 v1(182.96,123.19) ; RC99.2 133.58,116.8 v1(133.53,116.75) ; CR5.2 180.64,21.83 180.2,22.26 v1(180.2,22.69) CR10.2 ; C88.2 117.86,116.1 v1(118.22,116.1) ; CV140.2 193.52,158.07 v1(193.38,157.93) ; v1(213.33,175.14) 213.33,175.63 RX23.2 ; RV197.2 v1(218.39,112.16) ; CG6.2 v1(69.8,46.66) 70.53,47.38 CG11.2 ; CX41.2 205.65,164.29 205.64,164.29 205.58,164.22 v1(204.78,164.22) ; v1(106.43,124.08) 106.14,124.37 PC904.2 ; v1(122.2,15.83) 122.69,15.83 122.79,15.73 122.8,15.73 123.03,15.5 PR114.2 ; v1(106.5,149.55) 105.69,148.75 CM47.2 ; JSPK.6 v1(72.1,20.58) ; CE35.2 171.44,46.11 v1(171.21,45.88) ; v1(128.02,171.91) PC5.2 ; v1(173.95,116.34) 174.26,116.03 PC863.2 ; CV307.2 v1(218.39,107.52) ; v1(93.95,121) 93.95,121.23 93.77,121.41 RE1.1 ; v1(217.95,133.75) 218.07,133.62 CV272.2 ; CI31.2 210.05,39.72 210.59,40.27 v1(210.59,40.9) ; C79.2 92.62,126.4 v1(92.94,126.72) ; v1(79.59,65.16) 79.59,64.21 CD18.2 ; CD52.2 CD53.2 161.19,64.27 v1(160.81,64.65) ; CD34.2 129.31,64.07 v1(129.82,64.57) ; v1(74.83,72.77) 74.83,72.57 75.31,72.08 CD13.2 74.97,71.59 CD11.2 ; v1(179.67,110.72) 179.51,110.56 RV125.2 178.98,111.14 CV325.2 ; CX45.2 202.34,161.81 v1(201.96,162.19) ; v1(125.05,108.44) 124.65,108.84 C81.2 ; CV222.2 v1(209.07,100.6) ; CI15.2 v1(21.43,66.34) ; CV331.2 160.08,109.59 v1(160.07,109.6) 159.74,109.27 RV240.2 ; v1(217.45,168.97) 216.93,168.97 216.63,168.67 UX1.2 ; v1(98.52,124.08) 98.16,124.43 PC901.2 ; v1(35.7,22.81) RA19.2 ; PC873.2 172.18,118.81 PC872.2 172.68,117.94 v1(172.94,118.2) ; CV79.2 CV78.2 164.59,114.93 v1(164.54,114.87) 163.91,114.24 CV80.2 ; PC841.2 182.42,117.51 v1(181.96,117.05) ; v1(25.96,98.84) JTOUCH.7 ; CC33.2 151.44,106.67 v1(151.2,106.42) ; CX34.2 203.99,163.97 v1(204.24,163.71) 203.72,163.19 CX40.2 ; v1(163.99,172.54) PC709.2 ; v1(180.32,104.02) CV323.2 ; v1(178.9,27.98) 179.52,27.98 CR9.2 ; PC908.2 96.76,119.43 v1(95.45,119.43) ; v1(162.51,106.64) 162.32,106.82 CV114.2 CV115.2 ; CC31.2 61.5,88.07 v1(60.87,87.44) ; v1(123.45,119) 123.64,119.19 C53.2 ; CL33.2 19.92,76.41 23,76.41 v1(24.41,75) ; v1(177.3,111.32) 177.3,111.91 CV187.2 ; v1(209.45,164.09) 209.45,164.48 209.07,164.86 CX36.2 ; v1(195.78,155.91) CV270.2 CV256.2 ; C73.2 v1(120.87,116.03) ; v1(103.34,67.15) 102.82,67.15 102.44,67.52 RD7.1 RD6.1 ; CV299.2 v1(217.95,124.86) ; v3(125.72,11.39) 125.82,11.5 PR105.2 ; v1(18.41,100.09) JTOUCH.8 ; QD20.3 v1(69.65,15.89) ; v1(166.52,106.8) 167.02,107.3 RV248.1 ; R2351.1 45.04,63.82 45.56,64.34 45.56,64.7 v1(45.7,64.84) ; CR1.2 v1(177.98,16.44) ; v1(134.57,94.98) 134.03,95.51 CC4.1 ; CV275.2 217.89,130.14 v1(217.95,130.19) ; v1(173.96,119.32) 173.58,118.93 PC871.2 ; v1(186.27,107.38) 186.27,107.38 CV144.2 ; v1(225.26,176.54) 224.69,177.11 CX5.2 ; C61.2 121.87,119.32 v1(121.58,119.02) ; v1(74.19,108.81) 74,108.62 JTP.7 ; RV136.2 194.47,93.23 195.48,93.23 195.99,93.74 v1(195.99,93.93) ; v1(117.57,96.49) 117.57,95.71 117.77,95.5 C64.2 C66.2 ; JPWR.5 v1(48.34,100.66) ; CS7.2 v1(217.16,59.66) ; CG2.2 v1(71.15,37.37) ; CR2.2 v1(179.06,15.81) ; YG1.4 v1(62.58,41.13) ; CA25.1 20.92,18.82 v1(20.92,18.36) ; v1(134.28,183.54) PR9.1 ; PC855.2 173.9,122.13 v1(173.83,122.2) ; v1(67.1,39.18) 66.79,39.18 66.44,39.53 YG1.2 ; CD42.2 146.28,71.65 CD46.2 146.78,72.59 v1(147.03,72.85) ; JDB.9 213.9,56.66 v1(214.6,57.35) ; v1(108.93,124.08) 108.64,124.37 PC905.2 ; v1(172.19,43.84) CE34.2 ; v1(147.92,64.53) 147.35,63.96 CD44.2 146.54,63.46 CD37.2 ; CV116.2 158.52,107.56 v1(157.71,108.37) ; CA32.2 v1(66.45,19.33) ; CV211.2 CV206.2 ; RE18.2 195.93,32.4 v1(196.18,32.14) 195.75,31.71 CE20.2 ; SW1.1 v1(195.35,27.43) ; RC70.2 RC68.2 RC69.2 90.58,97.23 90.9,96.91 91.79,96.91 92.1,97.23 92.1,97.87 v1(91.94,98.03) ; v1(179.95,115.17) 180.51,115.73 PC847.2 ; v1(71.91,73.35) 71.91,73.34 72.36,72.9 72.36,72.53 71.91,72.08 CD20.2 70.44,72.08 CD8.2 ; RD50.2 v1(73.99,16.25) ; PC846.2 177.44,120.67 v1(177.96,121.19) ; v1(34.84,26.05) RA81.1 ; v1(168.94,99.52) 168.41,98.99 RV238.2 CV329.2 ; v1(182.89,121.27) 182.35,120.74 PC860.2 ; CR11.2 175.4,28.14 v1(175.92,28.14) ; CV244.2 CV256.2 ; v1(170.02,164.29) PR712.2 ; CM48.1 111.73,146.95 v1(111.79,146.89) ; CV141.2 191.35,157.68 v1(191.54,157.87) ; CE1.2 200.37,36.9 v1(201.07,37.6) ; PC842.2 181.62,119.85 v1(180.96,119.19) ; RV190.2 CV274.2 v1(201.63,133.75) ; CE6.1 CE27.2 184.09,32.93 183.99,33.03 v1(183.99,33.06) ; v1(183.73,33.89) 183.61,33.77 CE33.2 ; CD14.2 82.68,72.95 v1(82.39,73.24) ; v1(182.96,117.19) 182.96,116.92 183.41,116.48 CV322.2 ; CV197.2 v1(204.99,146.83) ; v1(215.39,43.35) 215.09,43.05 JDB.10 ; v1(222.95,160.67) JKB.32 ; CR4.1 v1(171.59,22.17) ; CV146.2 173.42,120.6 v1(173.81,120.21) ; PR724.1 171.07,175.9 170.83,175.65 PQ708.3 170.4,175.01 v1(169.95,175.46) ; CG3.2 v1(76.05,40.88) ; PC810.2 200.12,57.03 199.95,56.86 v1(199.95,56.34) ; v1(42.09,94.24) 42.34,94.5 JPWR.4 ; JPWR.6 v1(41.43,98.55) ; CV77.2 164.03,111.52 164.03,110.13 v1(163.73,109.82) ; v1(159.26,102.81) 159.61,103.16 CV121.2 CV122.2 158.15,103.51 CV120.2 ; CA69.2 v1(32.15,27.38) ; PC711.1 PR711.1 v1(172.94,167.21) ; CV155.2 186.95,112.77 CV193.2 186.59,111.82 v1(186.88,111.53) ; RV242.2 CV333.2 159.6,112.73 160.1,112.73 v1(160.11,112.72) ; C60.2 130,124.03 C62.2 129.39,123.98 v1(129.3,123.89) ; CV305.2 v1(218.39,109.3) ; v1(181.96,124.25) 182.35,123.86 PC858.2 ; CA74.2 v1(27.4,28.46) ; CV188.2 175.22,113.48 174.51,112.77 CV189.2 174.51,112.22 v1(174.84,111.89) ; v1(169.26,172.54) 169.64,172.92 PC719.2 ; SW1.5 v1(198.97,27.44) ; v1(174.03,103.56) RV123.2 ; CV281.2 v1(218.39,113.05) 218.39,113.69 218.16,113.92 CV273.2 ; RV89.1 181.64,105.22 v1(181.68,105.26) 181.54,105.4 CV214.2 ; JTOUCH.5 20.51,97.45 v1(20.98,97.93) 21.31,97.6 JTOUCH.4 ; v1(183.88,28.59) CR7.2 ; PC103.2 131.28,21.64 131.65,22.01 v3(132.01,22.01) ; CI6.2 v1(31.99,51.48) ; CE18.1 v1(177.97,44.84) ; v1(169.06,116.23) 169.47,115.83 RV133.1 ; v1(76.1,64.91) 75.72,64.53 CD12.2 76.28,63.4 CD9.2 ; PC109.2 v3(127.82,12.22) ; CI17.2 v1(26,55.26) ; PR108.2 PR107.1 v1(130.71,11.44) ; CG9.2 v1(67.1,41.1) ; CV153.2 CV142.2 170.58,132.14 170.58,131.1 171.32,130.36 v1(171.32,130.29) ; CV310.2 v1(217.95,125.75) ; CD47.2 149.7,72.15 149.2,71.65 CD41.2 148.56,72.59 v1(149.44,73.48) ; CI16.2 v1(24.29,34.75) ; CV289.2 v1(218.39,105.74) ; v1(209.9,40.9) 209.52,40.52 CI30.2 ; CD1.2 CD2.2 44.1,72.72 v1(44.22,72.84) ; v1(180.01,117.08) 180.45,117.52 PC843.2 ; CI13.2 24.9,65.53 v1(25.49,66.13) ; v1(18.93,11.86) 18.25,11.19 DA10.1 ; v1(133.19,161.8) PR32.2 ; RC90.2 122.27,111.08 C77.2 121.63,111.25 v1(121.02,111.86) ; v1(190.85,91.96) 191.3,91.51 RV137.2 ; RV207.2 164.99,111.77 v1(164.62,111.77) ; RV176.2 v1(217.95,131.08) ; CV317.2 v1(218.39,106.63) ; PC1304.2 v1(196.23,64.22) 195.99,63.98 PR1301.2 ; CG4.2 v1(68.02,44.09) ; C69.2 118.9,113.29 118.46,112.85 v1(118.22,112.85) ; CG8.2 v1(67.17,39.83) ; v1(189.26,27.09) CR8.2 ; CD23.2 v1(48.43,66.67) ; v1(61.56,95.01) 61.11,94.56 CC15.2 ; PQ4.3 v1(127.52,180.35) ; PR29.2 v1(129.76,170)
  GND1 w0.203: JUSB3.5 11.91,21.12 ; JUSB3.5 10.32,22.88 ; JUSB3.5 11.91,22.88 ; JUSB3.5 11.91,22 ; JUSB3.5 10.32,21.12 ; JUSB3.5 8.73,21.12 ; JUSB3.5 8.73,22 ; JUSB3.5 8.73,22.88 ; 17.68,36.58 H18.1 ; H18.1 19.2,36.02 ; H18.1 19.2,40.18 ; H18.1 17.12,38.1 ; H18.1 21.28,38.1 ; H18.1 20.72,36.58 ; H18.1 20.72,39.62 ; H18.1 17.68,39.62 ; 158.64,186.87 PBATT.10 ; PBATT.10 159.57,190.53 ; PBATT.10 158.64,190.53 ; PBATT.10 159.57,188.7 ; PBATT.10 157.72,186.87 ; PBATT.10 159.57,186.87 ; PBATT.10 157.72,190.53 ; PBATT.10 157.72,188.7 ; JHDD.24 229.7,70.29 ; JHDD.24 226.2,71.34 ; JHDD.24 227.95,70.29 ; JHDD.24 229.7,72.4 ; JHDD.24 226.2,70.29 ; JHDD.24 227.95,72.4 ; JHDD.24 226.2,72.4 ; JHDD.24 229.7,71.34 ; 87.27,156.76 JMINI.54 ; JMINI.54 87.27,158.32 ; JMINI.54 89.18,158.32 ; JMINI.54 88.23,156.76 ; JMINI.54 89.18,156.76 ; 226.54,122.01 JODD.15 ; JODD.15 229.06,122.01 ; JODD.15 226.08,120.75 ; JODD.15 229.51,120.75 ; JODD.15 226.54,119.49 ; JODD.15 227.8,122.46 ; JODD.15 229.06,119.49 ; JODD.15 227.8,119.03 ; 1.25,93.25 JLAN.10 ; JLAN.10 4.75,93.25 ; JLAN.10 4.75,92.2 ; JLAN.10 3,93.25 ; JLAN.10 1.25,92.2 ; JUSB2.10 12.57,37.27 ; JUSB2.10 9.63,37.27 ; JUSB2.10 11.1,37.27 ; JUSB2.10 11.1,39.03 ; JUSB2.10 9.63,38.15 ; JUSB2.10 12.57,38.15 ; JUSB2.10 12.57,39.03 ; 29.86,110.74 H12.1 ; H12.1 33.03,109.4 ; H12.1 29.86,108.06 ; H12.1 31.2,107.57 ; H12.1 31.2,111.23 ; H12.1 32.54,110.74 ; H12.1 29.37,109.4 ; H12.1 32.54,108.06 ; JUSB3.4 11,25.58 ; JUSB3.4 9.64,25.58 ; JUSB3.4 11,24.22 ; JUSB3.4 11.21,24.9 ; JUSB3.4 9.64,24.22 ; JUSB3.4 10.32,25.79 ; JUSB3.4 10.32,24.01 ; JUSB3.4 9.43,24.9 ; JHDD.1 227.78,37.96 ; JHDD.1 226.66,37.96 ; JHDD.1 226.5,37.39 ; JHDD.1 227.94,37.39 ; JHDD.1 227.78,36.83 ; JHDD.1 226.66,36.83 ; JHDD.1 227.22,36.67 ; JODD.14 227.8,96.16 ; JODD.14 226.54,93.19 ; JODD.14 227.8,92.73 ; JODD.14 226.08,94.45 ; JODD.14 229.51,94.45 ; JODD.14 226.54,95.71 ; JODD.14 229.06,93.19 ; JODD.14 229.06,95.71 ; 226.5,105.29 JODD.7 ; JODD.7 227.6,106.39 ; JODD.7 226.34,105.84 ; JODD.7 226.5,106.39 ; JODD.7 227.6,105.29 ; JODD.7 227.76,105.84 ; JODD.7 227.05,106.55 ; PBATT.11 137.32,186.87 ; PBATT.11 135.47,186.87 ; PBATT.11 137.32,190.53 ; PBATT.11 135.47,190.53 ; PBATT.11 137.32,188.7 ; PBATT.11 136.39,186.87 ; PBATT.11 135.47,188.7 ; PBATT.11 136.39,190.53 ; JHDMI.23 2.7,113.73 ; JHDMI.23 1.12,113.73 ; JHDMI.23 4.28,113.73 ; JHDMI.23 1.12,112.7 ; JHDMI.23 4.28,112.7 ; JHDMI.22 11.38,113.73 ; JHDMI.22 8.22,111.67 ; JHDMI.22 9.8,111.67 ; JHDMI.22 11.38,111.67 ; JHDMI.22 11.38,112.7 ; JHDMI.22 8.22,113.73 ; JHDMI.22 9.8,113.73 ; JHDMI.22 8.22,112.7 ; JUSB1.7 11.19,64.37 ; JUSB1.7 11.97,63.6 ; JUSB1.7 11.19,62.82 ; JUSB1.7 11.79,64.2 ; JUSB1.7 11.79,63 ; JREAD.23 198.8,4.83 ; JREAD.23 198.8,7.76 ; JREAD.23 198.8,6.29 ; JREAD.23 197.35,7.76 ; JREAD.23 198.08,4.83 ; JREAD.23 198.08,7.76 ; JREAD.23 197.35,6.29 ; JREAD.23 197.35,4.83 ; 80.8,101.37 H34.1 ; H34.1 78.51,103.66 ; H34.1 82.47,105.33 ; H34.1 79.13,105.33 ; H34.1 83.09,103.66 ; H34.1 82.47,101.99 ; H34.1 80.8,105.95 ; H34.1 79.13,101.99 ; 202.02,94.4 H6.1 ; H6.1 202.58,95.92 ; H6.1 204.1,92.32 ; H6.1 202.58,92.88 ; H6.1 206.18,94.4 ; H6.1 205.62,95.92 ; H6.1 204.1,96.48 ; H6.1 205.62,92.88 ; H4.1 20.54,70.56 ; H4.1 17.86,73.24 ; H4.1 17.86,70.56 ; H4.1 20.54,73.24 ; H4.1 17.37,71.9 ; H4.1 19.2,70.07 ; H4.1 19.2,73.73 ; H4.1 21.03,71.9 ; JHDD.7 227.94,45.01 ; JHDD.7 226.66,44.45 ; JHDD.7 227.78,44.45 ; JHDD.7 226.5,45.01 ; JHDD.7 227.22,45.74 ; JHDD.7 226.66,45.58 ; JHDD.7 227.78,45.58 ; JHDMI.2 10.21,99.65 ; JHDMI.2 9.17,100.12 ; JHDMI.2 10.09,99.19 ; JHDMI.2 9.05,99.65 ; JHDMI.2 9.63,99.07 ; JHDMI.2 9.17,99.19 ; JHDMI.2 10.09,100.12 ; H32.1 142.87,101.99 ; H32.1 139.53,105.33 ; H32.1 138.91,103.66 ; H32.1 141.2,101.37 ; H32.1 142.87,105.33 ; H32.1 139.53,101.99 ; H32.1 143.49,103.66 ; H32.1 141.2,105.95 ; H17.1 225.2,6.73 ; H17.1 223.86,3.56 ; H17.1 226.54,6.24 ; H17.1 223.86,6.24 ; H17.1 226.54,3.56 ; H17.1 227.03,4.9 ; H17.1 225.2,3.07 ; H17.1 223.37,4.9 ; JODD.1 227.6,97.67 ; JODD.1 226.5,97.67 ; JODD.1 226.34,98.22 ; JODD.1 227.05,97.51 ; JODD.1 227.76,98.22 ; JODD.1 227.6,98.77 ; JODD.1 226.5,98.77 ; 9.17,102.19 JHDMI.8 ; JHDMI.8 9.17,103.12 ; JHDMI.8 10.09,102.19 ; JHDMI.8 9.05,102.65 ; JHDMI.8 10.09,103.12 ; JHDMI.8 10.21,102.65 ; 79.13,130.73 H31.1 ; H31.1 78.51,129.06 ; H31.1 80.8,126.77 ; H31.1 83.09,129.06 ; H31.1 82.47,130.73 ; H31.1 82.47,127.39 ; H31.1 79.13,127.39 ; H31.1 80.8,131.35 ; JHDD.4 227.78,40.64 ; JHDD.4 226.5,41.2 ; JHDD.4 227.94,41.2 ; JHDD.4 226.66,41.77 ; JHDD.4 227.78,41.77 ; JHDD.4 226.66,40.64 ; 1.64,36.1 JUSB3.8 ; JUSB3.8 4.1,36.1 ; JUSB3.8 4.1,36.89 ; JUSB3.8 2.87,36.89 ; JUSB3.8 1.64,36.89 ; 226.66,64.77 JHDD.19 ; JHDD.19 227.94,65.33 ; JHDD.19 226.5,65.33 ; JHDD.19 227.78,65.9 ; JHDD.19 226.66,65.9 ; JHDD.19 227.78,64.77 ; 8.22,95.63 JHDMI.21 ; JHDMI.21 11.38,95.63 ; JHDMI.21 11.38,94.6 ; JHDMI.21 8.22,94.6 ; JHDMI.21 9.8,93.57 ; JHDMI.21 11.38,93.57 ; JHDMI.21 9.8,95.63 ; JHDMI.21 8.22,93.57 ; 144.81,189.41 PBATT.4 ; PBATT.4 144.81,187.99 ; PBATT.4 144.59,188.7 ; PBATT.4 146.45,188.7 ; PBATT.4 145.52,187.77 ; PBATT.4 146.23,189.41 ; PBATT.4 145.52,189.63 ; PBATT.4 146.23,187.99 ; JUSB1.10 12.57,54.87 ; JUSB1.10 12.57,55.75 ; JUSB1.10 9.63,54.87 ; JUSB1.10 9.63,55.75 ; JUSB1.10 11.1,54.87 ; JUSB1.10 12.57,56.63 ; JUSB1.10 11.1,56.63 ; 162.86,186.74 H11.1 ; H11.1 164.2,187.23 ; H11.1 166.03,185.4 ; H11.1 162.86,184.06 ; H11.1 162.37,185.4 ; H11.1 165.54,186.74 ; H11.1 165.54,184.06 ; H11.1 164.2,183.57 ; 113.3,149.75 JMINI.43 113.3,151.58 ; 138.91,129.06 H33.1 ; H33.1 142.87,130.73 ; H33.1 139.53,127.39 ; H33.1 141.2,131.35 ; H33.1 141.2,126.77 ; H33.1 142.87,127.39 ; H33.1 139.53,130.73 ; H33.1 143.49,129.06 ; H10.1 26.92,121.19 ; H10.1 28.44,120.63 ; H10.1 25.39,120.63 ; H10.1 29,119.1 ; H10.1 25.39,117.58 ; H10.1 28.44,117.58 ; H10.1 24.84,119.1 ; H10.1 26.92,117.02 ; JUSB1.13 12.57,72.33 ; JUSB1.13 11.1,70.57 ; JUSB1.13 12.57,71.45 ; JUSB1.13 9.63,71.45 ; JUSB1.13 9.63,72.33 ; JUSB1.13 12.57,70.57 ; JUSB1.13 11.1,72.33 ; 226.5,101.48 JODD.4 ; JODD.4 227.76,102.03 ; JODD.4 227.6,102.58 ; JODD.4 226.34,102.03 ; JODD.4 227.6,101.48 ; JODD.4 226.5,102.58 ; 153.3,142.42 H7.1 ; H7.1 154.82,142.98 ; H7.1 155.38,144.5 ; H7.1 153.3,146.58 ; H7.1 154.82,146.02 ; H7.1 151.78,146.02 ; H7.1 151.22,144.5 ; H7.1 151.78,142.98 ; 1.64,19.91 JUSB3.7 ; JUSB3.7 4.1,19.91 ; JUSB3.7 2.87,19.91 ; JUSB3.7 1.64,20.7 ; JUSB3.7 4.1,20.7 ; H8.1 226.54,82.74 ; H8.1 225.2,83.23 ; H8.1 226.54,80.06 ; H8.1 223.86,80.06 ; H8.1 223.86,82.74 ; H8.1 227.03,81.4 ; H8.1 223.37,81.4 ; H8.1 225.2,79.57 ; JUSB2.13 12.57,53.85 ; JUSB2.13 9.63,53.85 ; JUSB2.13 11.1,52.97 ; JUSB2.13 12.57,52.97 ; JUSB2.13 12.57,54.73 ; JUSB2.13 11.1,54.73 ; JUSB2.13 9.63,54.73 ; 226.5,57.71 JHDD.13 ; JHDD.13 226.66,57.15 ; JHDD.13 227.78,57.15 ; JHDD.13 227.94,57.71 ; JHDD.13 227.78,58.28 ; JHDD.13 226.66,58.28 ; PBATT.2 142.23,189.41 ; PBATT.2 141.52,187.77 ; PBATT.2 140.81,189.41 ; PBATT.2 142.45,188.7 ; PBATT.2 141.52,189.63 ; PBATT.2 142.23,187.99 ; PBATT.2 140.81,187.99 ; PBATT.2 140.59,188.7 ; 98.9,149.75 JMINI.15 ; JMINI.15 99.38,149.75 ; JMINI.15 98.9,151.58 ; JMINI.15 99.38,150.67 ; JMINI.15 99.38,151.58 ; JODD.13 227.59,116.51 ; JODD.13 227.74,117.05 ; JODD.13 226.36,117.05 ; JODD.13 226.51,117.59 ; JODD.13 227.05,116.36 ; JODD.13 227.05,117.74 ; JODD.13 227.59,117.59 ; JMINI.53 122.93,156.76 ; JMINI.53 121.02,156.76 ; JMINI.53 121.98,156.76 ; JMINI.53 122.93,158.32 ; JMINI.53 121.02,158.32 ; 226.2,36.25 JHDD.23 ; JHDD.23 227.95,36.25 ; JHDD.23 227.95,34.14 ; JHDD.23 229.7,36.25 ; JHDD.23 226.2,35.19 ; JHDD.23 229.7,34.14 ; JHDD.23 229.7,35.19 ; JHDD.23 226.2,34.14 ; JHDD.11 227.78,55.74 ; JHDD.11 226.66,54.61 ; JHDD.11 227.78,54.61 ; JHDD.11 226.66,55.74 ; JHDD.11 227.94,55.17 ; JHDD.11 226.5,55.17 ; JUSB1.12 4.97,71.45 ; JUSB1.12 4.97,72.33 ; JUSB1.12 2.23,71.45 ; JUSB1.12 3.6,72.33 ; JUSB1.12 2.23,72.33 ; JREAD.24 169.5,6.29 ; JREAD.24 168.05,4.83 ; JREAD.24 169.5,7.76 ; JREAD.24 168.78,4.83 ; JREAD.24 168.05,7.76 ; JREAD.24 169.5,4.83 ; JREAD.24 168.05,6.29 ; JREAD.24 168.78,7.76 ; JUSB2.4 13.47,42.5 ; JUSB2.4 12.09,41.9 ; JUSB2.4 13.29,41.9 ; JUSB2.4 13.29,43.1 ; JUSB2.4 12.69,41.72 ; JUSB2.4 12.69,43.28 ; JUSB2.4 11.91,42.5 ; JUSB2.4 12.09,43.1 ; 2.23,55.75 JUSB1.11 ; JUSB1.11 4.97,54.87 ; JUSB1.11 4.97,55.75 ; JUSB1.11 3.6,54.87 ; JUSB1.11 2.23,54.87 ; H2.1 111.03,13.4 ; H2.1 107.37,13.4 ; H2.1 110.54,12.06 ; H2.1 109.2,15.23 ; H2.1 110.54,14.74 ; H2.1 107.86,12.06 ; H2.1 109.2,11.57 ; H2.1 107.86,14.74 ; JUSB2.12 4.97,54.73 ; JUSB2.12 2.23,54.73 ; JUSB2.12 4.97,53.85 ; JUSB2.12 3.6,54.73 ; JUSB2.12 2.23,53.85 ; 1.25,73.4 JLAN.9 ; JLAN.9 3,72.35 ; JLAN.9 4.75,73.4 ; JLAN.9 4.75,72.35 ; JLAN.9 1.25,72.35 ; JHDMI.5 8.66,101.15 ; JHDMI.5 7.62,101.62 ; JHDMI.5 7.62,100.69 ; JHDMI.5 7.5,101.15 ; JHDMI.5 8.54,101.62 ; JHDMI.5 8.54,100.69 ; H16.1 128.94,156.14 ; H16.1 128.94,153.46 ; H16.1 125.77,154.8 ; H16.1 126.26,153.46 ; H16.1 127.6,156.63 ; H16.1 126.26,156.14 ; H16.1 127.6,152.97 ; H16.1 129.43,154.8 ; 12.69,59.32 JUSB1.4 ; JUSB1.4 12.09,60.7 ; JUSB1.4 13.47,60.1 ; JUSB1.4 13.29,59.5 ; JUSB1.4 12.09,59.5 ; JUSB1.4 12.69,60.88 ; JUSB1.4 11.91,60.1 ; JUSB1.4 13.29,60.7 ; JUSB2.7 11.79,46.6 ; JUSB2.7 11.19,45.22 ; JUSB2.7 11.19,46.77 ; JUSB2.7 11.79,45.4 ; JUSB2.7 11.97,46 ; 2.7,93.57 JHDMI.20 ; JHDMI.20 1.12,93.57 ; JHDMI.20 1.12,94.6 ; JHDMI.20 4.28,94.6 ; JHDMI.20 4.28,93.57 ; 96.5,149.75 JMINI.9 96.5,151.58 ; 8.73,34.8 JUSB3.6 ; JUSB3.6 10.32,35.68 ; JUSB3.6 8.73,35.68 ; JUSB3.6 11.91,35.68 ; JUSB3.6 10.32,33.92 ; JUSB3.6 11.91,33.92 ; JUSB3.6 8.73,33.92 ; JUSB3.6 11.91,34.8 ; JHDD.17 227.78,63.36 ; JHDD.17 227.78,62.23 ; JHDD.17 226.66,63.36 ; JHDD.17 226.66,62.23 ; JHDD.17 227.94,62.79 ; JHDD.17 226.5,62.79 ; 107.7,151.58 JMINI.29 107.22,151.58 ; 3.6,37.27 JUSB2.11 ; JUSB2.11 4.97,37.27 ; JUSB2.11 4.97,38.15 ; JUSB2.11 2.23,37.27 ; JUSB2.11 2.23,38.15 ; 223.86,167.06 H9.1 ; H9.1 225.2,170.23 ; H9.1 226.54,169.74 ; H9.1 226.54,167.06 ; H9.1 227.03,168.4 ; H9.1 225.2,166.57 ; H9.1 223.86,169.74 ; H9.1 223.37,168.4 ; PBATT.1 140.45,188.7 ; PBATT.1 138.81,189.41 ; PBATT.1 140.23,187.99 ; PBATT.1 139.52,187.77 ; PBATT.1 138.59,188.7 ; PBATT.1 138.81,187.99 ; PBATT.1 139.52,189.63 ; PBATT.1 140.23,189.41 ; 225.51,116.59 JODD.12 ; JODD.12 225.51,115.51 ; JODD.12 226.05,116.74 ; JODD.12 226.59,116.59 ; JODD.12 226.05,115.36 ; JODD.12 225.36,116.05 ; JODD.12 226.74,116.05 ; JHDMI.11 8.66,104.15 ; JHDMI.11 8.54,104.62 ; JHDMI.11 7.62,103.69 ; JHDMI.11 8.54,103.69 ; JHDMI.11 7.62,104.62 ; JHDMI.11 7.5,104.15 ; 107.38,151.58 JMINI.27 106.9,151.58 ; 110.1,149.75 JMINI.35 110.1,151.58 ; 7.62,107.62 JHDMI.17 ; JHDMI.17 7.5,107.15 ; JHDMI.17 8.54,107.62 ; JHDMI.17 8.66,107.15 ; JHDMI.17 7.62,106.69 ; JHDMI.17 8.54,106.69 ; 104.5,149.75 JMINI.21 104.5,151.58
  VCC w0.203: JUSB1.4 13.47,60.1 ; JUSB1.4 13.29,60.7 ; JUSB1.4 13.29,59.5 ; JUSB1.4 12.09,59.5 ; JUSB1.4 11.91,60.1 ; JUSB1.4 12.09,60.7 ; JUSB1.4 12.69,60.88 ; JUSB1.4 12.69,59.32 ; JUSB2.11 4.97,37.27 ; JUSB2.11 3.6,37.27 ; JUSB2.11 2.23,37.27 ; JHDMI.2 10.09,100.12 ; JHDMI.2 9.05,99.65 ; JHDMI.2 9.63,99.07 ; JHDMI.2 9.17,99.19 ; JHDMI.2 9.17,100.12 ; JHDMI.2 10.21,99.65 ; JHDMI.2 10.09,99.19 ; JHDMI.11 8.54,103.69 ; JHDMI.11 8.54,104.62 ; JHDMI.11 8.66,104.15 ; JUSB3.6 11.91,35.68 ; JUSB3.6 10.32,35.68 ; JUSB3.6 11.91,33.92 ; JUSB3.6 10.32,33.92 ; JUSB3.6 11.91,34.8 ; JUSB2.13 12.57,52.97 ; JUSB2.13 9.63,54.73 ; JUSB2.13 11.1,54.73 ; JUSB2.13 12.57,54.73 ; JUSB2.13 12.57,53.85 ; JUSB3.5 11.91,22.88 ; JUSB3.5 10.32,22.88 ; JUSB3.5 11.91,21.12 ; JUSB3.5 10.32,21.12 ; JUSB3.5 11.91,22 ; JUSB2.10 12.57,39.03 ; JUSB2.10 9.63,37.27 ; JUSB2.10 12.57,37.27 ; JUSB2.10 11.1,37.27 ; JUSB2.10 12.57,38.15 ; 9.64,24.22 JUSB3.4 ; JUSB3.4 9.64,25.58 ; JUSB3.4 11.21,24.9 ; JUSB3.4 11,25.58 ; JUSB3.4 10.32,24.01 ; JUSB3.4 11,24.22 ; JUSB3.4 10.32,25.79 ; JUSB3.4 9.43,24.9 ; JUSB1.7 11.79,63 ; JUSB1.7 11.79,64.2 ; JUSB1.7 11.97,63.6 ; JUSB1.13 12.57,71.45 ; JUSB1.13 12.57,70.57 ; JUSB1.13 11.1,72.33 ; JUSB1.13 9.63,72.33 ; JUSB1.13 12.57,72.33 ; JHDMI.8 10.09,103.12 ; JHDMI.8 10.09,102.19 ; JHDMI.8 10.21,102.65 ; JHDMI.8 9.05,102.65 ; JHDMI.8 9.17,103.12 ; JHDMI.8 9.17,102.19 ; 8.22,112.7 JHDMI.22 ; JHDMI.22 9.8,113.73 ; JHDMI.22 8.22,113.73 ; JHDMI.22 9.8,111.67 ; JHDMI.22 11.38,113.73 ; JHDMI.22 11.38,112.7 ; JHDMI.22 11.38,111.67 ; 2.7,93.57 JHDMI.20 ; JHDMI.20 4.28,93.57 ; JHDMI.20 4.28,94.6 ; 8.22,94.6 JHDMI.21 ; JHDMI.21 9.8,95.63 ; JHDMI.21 9.8,93.57 ; JHDMI.21 11.38,93.57 ; JHDMI.21 11.38,95.63 ; JHDMI.21 8.22,93.57 ; JHDMI.21 11.38,94.6 ; JUSB1.12 4.97,72.33 ; JUSB1.12 2.23,72.33 ; JUSB1.12 3.6,72.33 ; JHDMI.5 8.66,101.15 ; JHDMI.5 8.54,100.69 ; JHDMI.5 8.54,101.62 ; 11.1,54.87 JUSB1.10 ; JUSB1.10 9.63,54.87 ; JUSB1.10 12.57,56.63 ; JUSB1.10 12.57,55.75 ; JUSB1.10 12.57,54.87 ; 2.87,19.91 JUSB3.7 ; JUSB3.7 4.1,19.91 ; JUSB3.7 1.64,19.91 ; JUSB2.4 13.29,43.1 ; JUSB2.4 12.69,41.72 ; JUSB2.4 12.09,41.9 ; JUSB2.4 11.91,42.5 ; JUSB2.4 12.09,43.1 ; JUSB2.4 13.47,42.5 ; JUSB2.4 13.29,41.9 ; JUSB2.4 12.69,43.28 ; 2.23,54.87 JUSB1.11 ; JUSB1.11 3.6,54.87 ; JUSB1.11 4.97,54.87 ; JHDMI.17 8.54,107.62 ; JHDMI.17 8.66,107.15 ; JHDMI.17 8.54,106.69 ; JUSB2.7 11.97,46 ; JUSB2.7 11.79,45.4 ; JUSB2.7 11.79,46.6 ; JUSB2.12 3.6,54.73 ; JUSB2.12 2.23,54.73 ; JUSB2.12 4.97,54.73 ; JHDMI.23 4.28,112.7 ; JHDMI.23 4.28,113.73 ; JHDMI.23 2.7,113.73
  GND2 w0.203: JODD.15 229.06,122.01 ; JODD.15 227.8,122.46 ; JODD.15 226.08,120.75 ; JODD.15 226.54,122.01 ; JODD.15 229.06,119.49 ; JODD.15 226.54,119.49 ; JODD.15 227.8,119.03 ; JODD.15 229.51,120.75 ; 226.5,97.67 JODD.1 ; JODD.1 227.05,97.51 ; JODD.1 226.5,98.77 ; JODD.1 227.76,98.22 ; JODD.1 226.34,98.22 ; JODD.1 227.6,97.67 ; JODD.1 227.6,98.77 ; JHDD.19 227.78,65.9 ; JHDD.19 227.78,64.77 ; JHDD.19 226.66,64.77 ; JHDD.19 227.94,65.33 ; JHDD.19 226.5,65.33 ; JHDD.19 226.66,65.9 ; JUSB3.8 4.1,36.1 ; JUSB3.8 1.64,36.1 ; JUSB3.8 2.87,36.89 ; JUSB3.8 4.1,36.89 ; JUSB3.8 1.64,36.89 ; 144.81,187.99 PBATT.4 ; PBATT.4 146.23,189.41 ; PBATT.4 145.52,187.77 ; PBATT.4 146.23,187.99 ; PBATT.4 145.52,189.63 ; PBATT.4 146.45,188.7 ; PBATT.4 144.81,189.41 ; PBATT.4 144.59,188.7 ; 226.2,72.4 JHDD.24 ; JHDD.24 227.95,70.29 ; JHDD.24 229.7,70.29 ; JHDD.24 226.2,71.34 ; JHDD.24 227.95,72.4 ; JHDD.24 226.2,70.29 ; JHDD.24 229.7,72.4 ; JHDD.24 229.7,71.34 ; PBATT.11 137.32,188.7 ; PBATT.11 137.32,186.87 ; PBATT.11 135.47,188.7 ; PBATT.11 135.47,186.87 ; PBATT.11 135.47,190.53 ; PBATT.11 136.39,186.87 ; PBATT.11 137.32,190.53 ; PBATT.11 136.39,190.53 ; 226.5,37.39 JHDD.1 ; JHDD.1 227.94,37.39 ; JHDD.1 226.66,37.96 ; JHDD.1 227.22,36.67 ; JHDD.1 227.78,36.83 ; JHDD.1 227.78,37.96 ; JHDD.1 226.66,36.83 ; H6.1 205.62,92.88 ; H6.1 206.18,94.4 ; H6.1 204.1,96.48 ; H6.1 202.58,95.92 ; H6.1 204.1,92.32 ; H6.1 202.58,92.88 ; H6.1 205.62,95.92 ; H6.1 202.02,94.4 ; JODD.4 227.6,101.48 ; JODD.4 227.76,102.03 ; JODD.4 226.5,102.58 ; JODD.4 226.5,101.48 ; JODD.4 227.6,102.58 ; JODD.4 226.34,102.03 ; 121.98,156.76 JMINI.53 ; JMINI.53 122.93,158.32 ; JMINI.53 122.93,156.76 ; JMINI.53 121.02,158.32 ; JMINI.53 121.02,156.76 ; 11.1,54.87 JUSB1.10 ; JUSB1.10 12.57,54.87 ; JUSB1.10 11.1,56.63 ; JUSB1.10 12.57,56.63 ; JUSB1.10 9.63,54.87 ; JUSB1.10 12.57,55.75 ; JUSB1.10 9.63,55.75 ; JHDD.11 227.94,55.17 ; JHDD.11 227.78,55.74 ; JHDD.11 226.66,55.74 ; JHDD.11 227.78,54.61 ; JHDD.11 226.5,55.17 ; JHDD.11 226.66,54.61 ; 223.86,169.74 H9.1 ; H9.1 226.54,167.06 ; H9.1 223.86,167.06 ; H9.1 225.2,170.23 ; H9.1 225.2,166.57 ; H9.1 223.37,168.4 ; H9.1 227.03,168.4 ; H9.1 226.54,169.74 ; JUSB3.4 10.32,25.79 ; JUSB3.4 9.64,25.58 ; JUSB3.4 11.21,24.9 ; JUSB3.4 11,25.58 ; JUSB3.4 9.64,24.22 ; JUSB3.4 11,24.22 ; JUSB3.4 9.43,24.9 ; JUSB3.4 10.32,24.01 ; JUSB3.6 11.91,34.8 ; JUSB3.6 8.73,35.68 ; JUSB3.6 11.91,35.68 ; JUSB3.6 8.73,33.92 ; JUSB3.6 10.32,33.92 ; JUSB3.6 10.32,35.68 ; JUSB3.6 11.91,33.92 ; JUSB3.6 8.73,34.8 ; 8.22,94.6 JHDMI.21 ; JHDMI.21 8.22,95.63 ; JHDMI.21 11.38,94.6 ; JHDMI.21 9.8,93.57 ; JHDMI.21 9.8,95.63 ; JHDMI.21 8.22,93.57 ; JHDMI.21 11.38,93.57 ; JHDMI.21 11.38,95.63 ; JHDD.17 227.78,63.36 ; JHDD.17 227.94,62.79 ; JHDD.17 226.5,62.79 ; JHDD.17 226.66,63.36 ; JHDD.17 227.78,62.23 ; JHDD.17 226.66,62.23 ; H10.1 28.44,117.58 ; H10.1 25.39,117.58 ; H10.1 25.39,120.63 ; H10.1 29,119.1 ; H10.1 24.84,119.1 ; H10.1 26.92,121.19 ; H10.1 26.92,117.02 ; H10.1 28.44,120.63 ; JODD.12 226.74,116.05 ; JODD.12 225.51,116.59 ; JODD.12 226.59,116.59 ; JODD.12 226.05,116.74 ; JODD.12 226.05,115.36 ; JODD.12 225.51,115.51 ; JODD.12 225.36,116.05 ; PBATT.10 159.57,186.87 ; PBATT.10 157.72,188.7 ; PBATT.10 157.72,186.87 ; PBATT.10 158.64,190.53 ; PBATT.10 159.57,188.7 ; PBATT.10 159.57,190.53 ; PBATT.10 157.72,190.53 ; PBATT.10 158.64,186.87 ; H34.1 83.09,103.66 ; H34.1 80.8,105.95 ; H34.1 80.8,101.37 ; H34.1 79.13,101.99 ; H34.1 79.13,105.33 ; H34.1 78.51,103.66 ; H34.1 82.47,101.99 ; H34.1 82.47,105.33 ; H8.1 225.2,83.23 ; H8.1 223.37,81.4 ; H8.1 225.2,79.57 ; H8.1 226.54,80.06 ; H8.1 223.86,82.74 ; H8.1 226.54,82.74 ; H8.1 223.86,80.06 ; H8.1 227.03,81.4 ; 107.86,14.74 H2.1 ; H2.1 107.86,12.06 ; H2.1 109.2,15.23 ; H2.1 111.03,13.4 ; H2.1 110.54,12.06 ; H2.1 110.54,14.74 ; H2.1 107.37,13.4 ; H2.1 109.2,11.57 ; JMINI.15 98.9,151.58 ; JMINI.15 99.38,150.67 ; JMINI.15 99.38,151.58 ; JMINI.15 98.9,149.75 ; JMINI.15 99.38,149.75 ; JHDD.4 227.78,40.64 ; JHDD.4 226.66,41.77 ; JHDD.4 226.5,41.2 ; JHDD.4 227.94,41.2 ; JHDD.4 226.66,40.64 ; JHDD.4 227.78,41.77 ; JMINI.54 89.18,156.76 ; JMINI.54 88.23,156.76 ; JMINI.54 89.18,158.32 ; JMINI.54 87.27,158.32 ; JMINI.54 87.27,156.76 ; JHDMI.2 10.09,99.19 ; JHDMI.2 9.63,99.07 ; JHDMI.2 9.17,100.12 ; JHDMI.2 9.17,99.19 ; JHDMI.2 10.09,100.12 ; JHDMI.2 10.21,99.65 ; JHDMI.2 9.05,99.65 ; JHDMI.11 8.54,103.69 ; JHDMI.11 8.54,104.62 ; JHDMI.11 8.66,104.15 ; JHDMI.11 7.5,104.15 ; JHDMI.11 7.62,104.62 ; JHDMI.11 7.62,103.69 ; 162.86,186.74 H11.1 ; H11.1 162.37,185.4 ; H11.1 165.54,184.06 ; H11.1 162.86,184.06 ; H11.1 164.2,187.23 ; H11.1 165.54,186.74 ; H11.1 166.03,185.4 ; H11.1 164.2,183.57 ; PBATT.2 142.45,188.7 ; PBATT.2 140.81,187.99 ; PBATT.2 140.81,189.41 ; PBATT.2 140.59,188.7 ; PBATT.2 141.52,189.63 ; PBATT.2 142.23,187.99 ; PBATT.2 142.23,189.41 ; PBATT.2 141.52,187.77 ; JUSB2.4 13.29,41.9 ; JUSB2.4 13.29,43.1 ; JUSB2.4 12.69,41.72 ; JUSB2.4 11.91,42.5 ; JUSB2.4 13.47,42.5 ; JUSB2.4 12.69,43.28 ; JUSB2.4 12.09,43.1 ; JUSB2.4 12.09,41.9 ; 9.17,102.19 JHDMI.8 ; JHDMI.8 10.09,102.19 ; JHDMI.8 10.21,102.65 ; JHDMI.8 9.17,103.12 ; JHDMI.8 10.09,103.12 ; JHDMI.8 9.05,102.65 ; 151.78,142.98 H7.1 ; H7.1 154.82,142.98 ; H7.1 151.22,144.5 ; H7.1 154.82,146.02 ; H7.1 155.38,144.5 ; H7.1 153.3,142.42 ; H7.1 153.3,146.58 ; H7.1 151.78,146.02 ; 19.2,70.07 H4.1 ; H4.1 21.03,71.9 ; H4.1 19.2,73.73 ; H4.1 17.37,71.9 ; H4.1 20.54,73.24 ; H4.1 20.54,70.56 ; H4.1 17.86,70.56 ; H4.1 17.86,73.24 ; JODD.13 227.05,117.74 ; JODD.13 226.51,117.59 ; JODD.13 227.05,116.36 ; JODD.13 227.59,116.51 ; JODD.13 227.59,117.59 ; JODD.13 226.36,117.05 ; JODD.13 227.74,117.05 ; H18.1 19.2,40.18 ; H18.1 19.2,36.02 ; H18.1 20.72,39.62 ; H18.1 17.68,39.62 ; H18.1 20.72,36.58 ; H18.1 21.28,38.1 ; H18.1 17.68,36.58 ; H18.1 17.12,38.1 ; 226.54,95.71 JODD.14 ; JODD.14 229.06,93.19 ; JODD.14 227.8,92.73 ; JODD.14 229.06,95.71 ; JODD.14 227.8,96.16 ; JODD.14 226.08,94.45 ; JODD.14 229.51,94.45 ; JODD.14 226.54,93.19 ; PBATT.1 139.52,189.63 ; PBATT.1 138.81,189.41 ; PBATT.1 138.59,188.7 ; PBATT.1 138.81,187.99 ; PBATT.1 140.23,189.41 ; PBATT.1 140.45,188.7 ; PBATT.1 140.23,187.99 ; PBATT.1 139.52,187.77 ; 2.23,53.85 JUSB2.12 ; JUSB2.12 4.97,53.85 ; JUSB2.12 4.97,54.73 ; JUSB2.12 3.6,54.73 ; JUSB2.12 2.23,54.73 ; H17.1 225.2,6.73 ; H17.1 223.86,6.24 ; H17.1 223.86,3.56 ; H17.1 226.54,3.56 ; H17.1 227.03,4.9 ; H17.1 223.37,4.9 ; H17.1 226.54,6.24 ; H17.1 225.2,3.07 ; JUSB1.13 12.57,71.45 ; JUSB1.13 9.63,71.45 ; JUSB1.13 12.57,72.33 ; JUSB1.13 11.1,72.33 ; JUSB1.13 9.63,72.33 ; JUSB1.13 12.57,70.57 ; JUSB1.13 11.1,70.57 ; JREAD.24 169.5,7.76 ; JREAD.24 168.78,7.76 ; JREAD.24 169.5,6.29 ; JREAD.24 169.5,4.83 ; JREAD.24 168.05,7.76 ; JREAD.24 168.78,4.83 ; JREAD.24 168.05,6.29 ; JREAD.24 168.05,4.83 ; JUSB2.10 12.57,37.27 ; JUSB2.10 12.57,38.15 ; JUSB2.10 11.1,39.03 ; JUSB2.10 9.63,38.15 ; JUSB2.10 12.57,39.03 ; JUSB2.10 11.1,37.27 ; JUSB2.10 9.63,37.27 ; 96.5,151.58 JMINI.9 96.5,149.75 ; 139.53,130.73 H33.1 ; H33.1 138.91,129.06 ; H33.1 143.49,129.06 ; H33.1 141.2,126.77 ; H33.1 142.87,130.73 ; H33.1 139.53,127.39 ; H33.1 142.87,127.39 ; H33.1 141.2,131.35 ; JODD.7 227.6,106.39 ; JODD.7 226.5,105.29 ; JODD.7 226.5,106.39 ; JODD.7 227.05,106.55 ; JODD.7 227.6,105.29 ; JODD.7 226.34,105.84 ; JODD.7 227.76,105.84 ; 1.12,113.73 JHDMI.23 ; JHDMI.23 4.28,112.7 ; JHDMI.23 1.12,112.7 ; JHDMI.23 4.28,113.73 ; JHDMI.23 2.7,113.73 ; 8.22,111.67 JHDMI.22 ; JHDMI.22 8.22,113.73 ; JHDMI.22 11.38,111.67 ; JHDMI.22 11.38,113.73 ; JHDMI.22 9.8,113.73 ; JHDMI.22 9.8,111.67 ; JHDMI.22 8.22,112.7 ; JHDMI.22 11.38,112.7 ; JHDD.7 227.94,45.01 ; JHDD.7 226.66,44.45 ; JHDD.7 226.66,45.58 ; JHDD.7 226.5,45.01 ; JHDD.7 227.78,45.58 ; JHDD.7 227.78,44.45 ; JHDD.7 227.22,45.74 ; 79.13,130.73 H31.1 ; H31.1 80.8,126.77 ; H31.1 83.09,129.06 ; H31.1 82.47,127.39 ; H31.1 78.51,129.06 ; H31.1 80.8,131.35 ; H31.1 79.13,127.39 ; H31.1 82.47,130.73 ; 139.53,105.33 H32.1 ; H32.1 143.49,103.66 ; H32.1 138.91,103.66 ; H32.1 142.87,105.33 ; H32.1 139.53,101.99 ; H32.1 142.87,101.99 ; H32.1 141.2,101.37 ; H32.1 141.2,105.95 ; H16.1 129.43,154.8 ; H16.1 128.94,156.14 ; H16.1 126.26,153.46 ; H16.1 127.6,156.63 ; H16.1 126.26,156.14 ; H16.1 125.77,154.8 ; H16.1 127.6,152.97 ; H16.1 128.94,153.46 ; JHDMI.5 8.54,101.62 ; JHDMI.5 7.62,100.69 ; JHDMI.5 7.5,101.15 ; JHDMI.5 7.62,101.62 ; JHDMI.5 8.54,100.69 ; JHDMI.5 8.66,101.15 ; JUSB1.4 13.47,60.1 ; JUSB1.4 12.09,59.5 ; JUSB1.4 11.91,60.1 ; JUSB1.4 12.69,60.88 ; JUSB1.4 13.29,60.7 ; JUSB1.4 13.29,59.5 ; JUSB1.4 12.69,59.32 ; JUSB1.4 12.09,60.7 ; 11.19,62.82 JUSB1.7 ; JUSB1.7 11.97,63.6 ; JUSB1.7 11.19,64.37 ; JUSB1.7 11.79,64.2 ; JUSB1.7 11.79,63 ; 110.1,151.58 JMINI.35 110.1,149.75 ; 3.6,37.27 JUSB2.11 ; JUSB2.11 2.23,38.15 ; JUSB2.11 4.97,38.15 ; JUSB2.11 2.23,37.27 ; JUSB2.11 4.97,37.27 ; JUSB1.11 4.97,54.87 ; JUSB1.11 2.23,54.87 ; JUSB1.11 2.23,55.75 ; JUSB1.11 4.97,55.75 ; JUSB1.11 3.6,54.87 ; 3,72.35 JLAN.9 ; JLAN.9 1.25,73.4 ; JLAN.9 1.25,72.35 ; JLAN.9 4.75,72.35 ; JLAN.9 4.75,73.4 ; 226.2,34.14 JHDD.23 ; JHDD.23 227.95,36.25 ; JHDD.23 227.95,34.14 ; JHDD.23 226.2,35.19 ; JHDD.23 229.7,35.19 ; JHDD.23 226.2,36.25 ; JHDD.23 229.7,34.14 ; JHDD.23 229.7,36.25 ; JUSB3.7 4.1,19.91 ; JUSB3.7 1.64,19.91 ; JUSB3.7 2.87,19.91 ; JUSB3.7 1.64,20.7 ; JUSB3.7 4.1,20.7 ; H12.1 31.2,111.23 ; H12.1 31.2,107.57 ; H12.1 29.86,108.06 ; H12.1 29.86,110.74 ; H12.1 32.54,108.06 ; H12.1 33.03,109.4 ; H12.1 32.54,110.74 ; H12.1 29.37,109.4 ; 2.23,72.33 JUSB1.12 ; JUSB1.12 4.97,72.33 ; JUSB1.12 4.97,71.45 ; JUSB1.12 2.23,71.45 ; JUSB1.12 3.6,72.33 ; 1.25,93.25 JLAN.10 ; JLAN.10 4.75,93.25 ; JLAN.10 3,93.25 ; JLAN.10 1.25,92.2 ; JLAN.10 4.75,92.2 ; JREAD.23 198.8,6.29 ; JREAD.23 197.35,7.76 ; JREAD.23 198.8,7.76 ; JREAD.23 198.8,4.83 ; JREAD.23 197.35,6.29 ; JREAD.23 198.08,7.76 ; JREAD.23 197.35,4.83 ; JREAD.23 198.08,4.83 ; JHDMI.20 4.28,93.57 ; JHDMI.20 1.12,94.6 ; JHDMI.20 4.28,94.6 ; JHDMI.20 2.7,93.57 ; JHDMI.20 1.12,93.57 ; 7.62,107.62 JHDMI.17 ; JHDMI.17 7.5,107.15 ; JHDMI.17 8.66,107.15 ; JHDMI.17 8.54,106.69 ; JHDMI.17 7.62,106.69 ; JHDMI.17 8.54,107.62 ; 226.66,58.28 JHDD.13 ; JHDD.13 227.78,58.28 ; JHDD.13 226.66,57.15 ; JHDD.13 227.78,57.15 ; JHDD.13 226.5,57.71 ; JHDD.13 227.94,57.71 ; 8.73,22 JUSB3.5 ; JUSB3.5 8.73,21.12 ; JUSB3.5 10.32,21.12 ; JUSB3.5 11.91,21.12 ; JUSB3.5 11.91,22.88 ; JUSB3.5 8.73,22.88 ; JUSB3.5 11.91,22 ; JUSB3.5 10.32,22.88 ; 107.7,151.58 JMINI.29 107.22,151.58 ; JUSB2.7 11.79,46.6 ; JUSB2.7 11.79,45.4 ; JUSB2.7 11.19,45.22 ; JUSB2.7 11.97,46 ; JUSB2.7 11.19,46.77 ; 106.9,151.58 JMINI.27 107.38,151.58 ; 9.63,53.85 JUSB2.13 ; JUSB2.13 11.1,52.97 ; JUSB2.13 12.57,52.97 ; JUSB2.13 11.1,54.73 ; JUSB2.13 12.57,53.85 ; JUSB2.13 12.57,54.73 ; JUSB2.13 9.63,54.73 ; 104.5,149.75 JMINI.21 104.5,151.58 ; 113.3,149.75 JMINI.43 113.3,151.58
  BOTTOM w0.102: v1(25.96,98.84) v4(26.67,98.84) ; v1(209.45,164.09) v4(208.78,164.09) ; v1(66.45,19.33) v4(67.52,19.33) ; v4(213.56,144.98) v1(213.56,144.16)
  BOTTOM w0.127: v4(69.52,112.68) 68.95,112.11 v1(68.95,111.34) ; 109.16,105.27 109.05,105.16 109.05,104.75 108.68,104.38 UC1.AV36 ; 102.73,105.34 102.73,105.03 102.75,105.02 102.75,104.75 102.38,104.38 UC1.AV46 ; 107.47,105.31 107.47,104.75 107.1,104.38 UC1.AV39 ; UC1.AV41 105.53,104.38 105.9,104.75 105.9,105.23 105.94,105.27 ; 101.33,105.27 101.17,105.12 101.17,104.75 100.99,104.57 100.99,104.42 UC1.AV49 ; 104.57,105.27 104.32,105.03 104.32,104.75 103.95,104.38 UC1.AV43
  BOTTOM w0.152: UV1.AN6 190.46,108.47 190.86,108.08 190.86,107.5 UV1.AR5
  BOTTOM w0.178: UC1.AN49 100.78,107.08 101.16,107.08 UC1.AN48 101.43,107.34 101.65,107.34 v1(101.98,107.62) ; UC1.AW37 107.93,103.58 108.27,103.92 v1(108.27,103.93) 108.28,103.93 108.58,104.23 UC1.AV36 ; UC1.AY53 97.94,103.26 97.94,102.63 97.88,102.57 97.88,102.18 v1(97.72,102.03) ; v1(91.1,112.52) 91.23,112.39 UC1.AD63 ; v1(93.84,106.05) 93.98,105.91 93.98,105.53 94.28,105.23 UC1.AU59 ; v1(93.84,106.05) 93.94,106.16 93.94,106.64 93.93,106.66 UC1.AN60 93.93,107.59 93.94,107.6 93.94,107.89 93.93,107.91 UC1.AL60 ; v1(93.84,106.05) 93.71,105.93 UC1.AT61 92.52,105.93 UC1.AT62 92.45,105.86 91.96,105.86 91.93,105.83 91.76,105.83 UC1.AT63 91.24,105.71 90.96,105.43 90.81,105.43 v1(90.48,105.09) ; UC1.AU55 UC1.AV55 96.73,104.09 v1(96.77,104.05) ; UC1.AU55 97.22,105.21 97.24,105.23 97.52,105.23 97.54,105.21 UC1.AU53 98.46,105.21 98.48,105.23 98.76,105.23 98.78,105.21 UC1.AU51 ; UC1.AU55 96.24,105.21 96.23,105.23 95.94,105.23 95.92,105.21 UC1.AU57 95,105.21 94.98,105.23 94.7,105.23 94.68,105.21 UC1.AU59 ; UC1.P63 91.16,117.63 v1(91.11,117.68) ; UC1.AU24 115.44,105.21 115.43,105.23 115.14,105.23 115.12,105.21 UC1.AU26 114.2,105.21 114.18,105.23 113.9,105.23 113.88,105.21 UC1.AU28 ; UC1.AU24 115.96,105.33 v1(116.34,105.72) ; UC1.AU24 UC1.AV24 UC1.AW24 UC1.AY24 115.96,102.4 v1(115.88,102.32) ; UC1.AV41 105.43,104.23 105.13,103.93 v1(105.12,103.93) 105.12,103.92 104.78,103.58 UC1.AW42 ; UC1.AL36 108.38,108.64 v1(108.21,108.47) ; UC1.AU59 UC1.AV59 UC1.AW59 ; UC1.AV34 110.58,103.91 UC1.AW33 ; UC1.AV34 110.19,104.23 v1(109.88,103.93) 109.54,103.58 UC1.AW35 ; UC1.AV34 110.58,104.56 UC1.AV33 ; UC1.AY30 112.18,102.4 v1(112.11,102.33) ; UC1.AU20 118.04,105.21 118.02,105.23 117.74,105.23 117.72,105.21 UC1.AU22 116.86,105.21 116.84,105.23 116.58,105.49 v1(116.34,105.72) ; UC1.AU20 119.01,105.21 119.03,105.23 119.32,105.23 119.33,105.21 UC1.AU18 120.26,105.21 120.28,105.23 120.56,105.23 120.58,105.21 UC1.AU16 UC1.AV16 UC1.AW16 121.06,103.3 UC1.AY16 ; UC1.AU20 UC1.AV20 118.53,104.09 v1(118.56,104.05) ; UC1.AN31 UC1.AM31 UC1.AL31 112.02,109.11 v1(112.53,109.62) ; UC1.AN31 111.69,107.34 UC1.AN32 111.39,107.34 111.03,106.98 v1(111.03,106.94) ; UC1.AN31 UC1.AP31 UC1.AR31 112.02,105.37 UC1.AU30 ; UC1.AR17 UC1.AP17 UC1.AN17 UC1.AM17 UC1.AL17 ; v1(90.95,110.88) 91.03,110.96 UC1.AG63 UC1.AG62 UC1.AG61 UC1.AG60 94.12,110.77 94.12,110.23 ; UC1.AL52 98.69,108.65 98.51,108.65 v1(98.18,108.32) ; UC1.AN63 91.16,107.18 90.93,106.94 v1(90.7,106.94) ; UC1.AM23 116.66,107.99 v1(116.34,108.32) 116.42,108.32 UC1.AL23 116.42,108.97 v1(116.33,108.97) 116.66,109.3 UC1.AK23 116.42,109.62 v1(116.34,109.62) 116.34,110.25 UC1.AH24 ; UC1.AU33 111.64,105.23 111.66,105.21 UC1.AU30 ; UC1.AU33 110.88,105.2 UC1.AV33 ; UC1.AU33 110.66,105.23 v1(110.11,105.78) ; UC1.AJ23 117.33,109.84 v1(117.73,109.84) 117.73,110.35 UC1.AH22 ; v1(116.34,105.72) 116.66,106.04 UC1.AR23 ; 94.12,110.23 93.93,110.04 UC1.AJ60 93.93,109.2 93.94,109.18 93.94,108.9 93.93,108.88 UC1.AL60 ; 94.12,110.23 94.4,109.95 UC1.AJ58 94.9,109.97 95.2,110.27 95.55,110.27 UC1.AH57 95.88,110.27 96.2,109.95 UC1.AJ56 ; UC1.AU30 112.59,105.21 112.6,105.23 112.89,105.23 112.91,105.21 UC1.AU28 ; UC1.AY22 117.31,102.37 v1(117.37,102.31) ; UC1.AJ63 91.28,109.61 90.95,109.27 v1(90.73,109.27) ; v1(93.95,115.01) 94.25,114.71 UC1.Y59 ; UC1.AU28 UC1.AV28 113.39,104.09 v1(113.43,104.05) ; UC1.AY26 114.61,102.31 114.42,102.12 v1(114.42,102.1) ; UC1.AL60 UC1.AL61 92.8,108.39 v1(92.77,108.36) ; UC1.AB7 126.34,113.81 v1(126.52,113.98) ; UC1.AP48 101.36,106.69 101.03,106.37 ; v1(95.45,102.33) 95.52,102.39 UC1.AY57 ; v1(110.11,105.78) 109.84,105.51 UC1.AT35 109.41,105.34 109.34,105.27 108.7,105.27 108.63,105.34 UC1.AT37 107.5,105.34 107.44,105.27 107.07,105.27 107,105.34 UC1.AT40 106.01,105.34 105.94,105.27 105.18,105.27 UC1.AT42 105.04,105.34 104.97,105.27 103.61,105.27 UC1.AT43 UC1.AT46 101.9,105.27 100.85,105.27 100.81,105.31 UC1.AT49 100.35,105.33 99.66,105.33 99.54,105.21 UC1.AU51 ; v1(110.11,105.78) 110.37,106.04 UC1.AR33 ; UC1.AV33 110.83,104.51 UC1.AW33 ; UC1.AV39 107.01,104.23 106.71,103.93 v1(106.69,103.93) 106.69,103.92 106.36,103.58 UC1.AW40 ; v1(93.95,118.01) 94.25,117.71 UC1.P59 ; UC1.AV46 102.28,104.23 101.98,103.93 v1(101.97,103.93) 101.97,103.92 101.63,103.58 UC1.AW47 ; UC1.AV43 103.86,104.23 103.56,103.93 v1(103.54,103.93) 103.54,103.92 103.21,103.58 UC1.AW44 ; UC1.AN45 UC1.AN43 104.57,107.34 v1(104.84,107.07) 105.12,107.34 UC1.AN42 105.43,107.34 v1(105.76,107.02) ; UC1.AN52 UC1.AP52 98.69,106.57 98.68,106.55 98.68,106.18 98.69,106.17 UC1.AR52 ; UC1.Y63 91.03,114.63 v1(90.86,114.47) ; v1(119.67,102.34) 119.74,102.4 UC1.AY18 ; v1(108.21,107.17) 108.38,107.34 UC1.AN36 ; UC1.AU51 UC1.AV51 UC1.AW51 UC1.AY51 99.3,102.65 99.2,102.55 v1(99.2,101.65) ; UC1.AW33 UC1.AY33 110.83,102.68 v1(110.65,102.5) ; UC1.AP23 116.66,106.69 v1(116.34,107.02) 116.66,107.34 UC1.AN23 ; UC1.AJ52 98.8,109.4 UC1.AK52 98.34,109.3 v1(98.17,109.13) ; UC1.AW50 100.13,103.74 100.21,103.74 100.39,103.92 v1(100.39,103.93) 100.41,103.93 100.67,104.2 100.77,104.2 UC1.AV49
  BOTTOM w0.203: UC1.AN49 100.37,107.34 100.27,107.24 99.89,107.24 99.78,107.34 UC1.AN51 99.45,107.34 99.32,107.21 98.94,107.21 98.8,107.34 UC1.AN52 98.69,107.36 98.36,107.69 v1(98.22,107.69) ; UC1.D59 94.38,123.35 94.9,122.82 UC1.F58 ; UC1.AL51 99.45,108.64 v1(99.13,108.32) ; UC1.AN39 106.47,107.67 UC1.AN40 ; v1(127.88,112.02) 127.64,111.79 UC1.AE5 ; v1(128.49,102.43) 128.35,102.57 UC1.AY4 128.3,102.98 UC1.AW4 ; v1(130.79,119.84) UC1.K1 ; UC1.AP39 106.47,107.02 UC1.AN40 ; U2301.11 v1(96.61,31.38) ; v1(91.07,120.75) 91.19,120.63 UC1.J63 ; v1(97.28,108.32) 97.6,108.64 UC1.AL54 ; v1(92.65,116.51) 92.95,116.21 UC1.U61 ; UC1.AG21 118.32,110.01 v1(118.44,109.89) 118.63,110.09 UC1.AH20 ; UC1.T58 94.9,116.94 UC1.P59 ; v1(105.76,107.02) 106.08,107.34 UC1.AN40 ; v1(121.15,102.27) 121.13,102.28 121.13,103.22 UC1.AY16 ; v1(92.65,113.51) 92.95,113.21 UC1.AC61 ; UC1.AY59 94.19,102.46 v1(94.1,102.38) ; UC1.F61 92.95,122.2 v1(92.65,122.5) ; v1(129.27,114.94) 129.27,114.99 128.98,115.28 UC1.V3 ; v1(130.81,116.84) UC1.T1 ; v1(126.99,102.39) 126.9,102.48 UC1.AY6 ; UC1.U22 v1(116.79,116.1) ; v1(121.76,105.53) 121.44,105.21 UC1.AU16 ; v1(121.76,105.53) 121.06,106.24 UC1.AR17 ; v1(121.76,105.53) 122.09,105.86 UC1.AR15 ; UC1.AN48 UC1.AP48 ; UC1.E17 120.94,122.94 v1(120.61,123.27) ; UC1.AY11 123.91,102.3 v1(124.04,102.16) ; UC1.A24 116.25,126.01 116.59,126.35 v1(116.6,126.35) ; UC1.W20 119.1,115.3 v1(119.49,115.7) 119.1,116.09 UC1.U20 ; PU501.29 89.02,134.67 v1(89.12,134.57) ; v1(119.94,109.54) 120.48,110.09 UC1.AH17 120.77,109.87 121.16,109.87 UC1.AH16 ; v1(111.08,140.33) 111.18,140.43 PU502.3 ; UC1.AT43 103.54,105.37 v1(103.89,105.72) 104.21,106.04 UC1.AR43 ; UC1.N3 128.98,118.27 129.28,117.97 v1(129.28,117.94) ; v1(98.18,108.32) 98.37,108.32 UC1.AM52 ; v1(131.22,104.3) 131.13,104.3 130.53,104.9 UC1.AU1 ; v1(129.28,111.97) 128.98,112.27 UC1.AD3 ; v1(101.98,107.62) 102.26,107.34 UC1.AN46 102.67,107.34 102.75,107.27 103.13,107.27 103.2,107.34 UC1.AN45 ; v1(129.28,108.97) 129.28,109.1 128.99,109.39 UC1.AK3 ; v1(97.28,106.37) 97.6,106.69 UC1.AP54 ; UC1.AL46 102.74,108.38 v1(102.94,108.38) 103.14,108.38 UC1.AL45 ; PU501.22 92,136.82 v1(92.09,136.73) ; UC1.A48 UC1.B48 ; UC1.N21 118.59,118.04 118.45,117.91 118.45,117.9 118.19,117.63 117.81,117.63 117.71,117.73 UC1.P22 v1(116.79,117.73) ; UC1.L61 92.95,119.2 v1(92.65,119.5) ; UC1.AV8 125.14,103.93 v1(125.03,103.93) ; 101.03,106.37 100.71,106.04 UC1.AR49 100.37,105.89 UC1.AT49 ; UC1.R8 UC1.R10 ; v1(122.03,103.89) 122.37,104.23 UC1.AV14 ; UC1.D62 91.71,123.53 UC1.D63 91.13,123.59 90.65,124.06 89.32,124.06 v1(88.61,123.35) ; UV1.F25 174.7,130.69 174.31,130.3 174.09,130.3 174.09,130.29 v1(173.69,130.29) ; v1(123.59,115.55) 123.59,114.6 123.72,114.46 UC1.Y10 ; UC1.AW59 93.95,103.58 UC1.AW60 ; v1(92.18,138) 92.18,138.02 92.16,138.02 92.16,138.02 PU501.19 ; UC1.AG1 v1(130.79,110.85) ; UC1.P63 UC1.P62 ; v1(113.11,110.51) UC1.AJ29 ; UC1.AP57 95.7,106.69 v1(95.37,106.37) ; v1(205.07,61.42) 204.84,61.19 204.84,60.15 204.99,60 PU800.17 ; UC1.A56 UC1.B56 ; v1(123.12,105.86) 123.33,105.65 123.84,105.65 UC1.AR11 ; 128.45,123.93 128.8,123.93 128.85,123.88 129.29,123.88 v1(129.3,123.89) 129.63,123.56 UC1.D2 ; UC1.AM1 v1(130.82,107.85) ; UC1.R22 v1(116.79,116.92)
  BOTTOM w0.229: v1(116.54,120) 116.71,120.17 UC1.J22 ; UV20.G1 190.38,150.66 190.38,150.66 190.38,150.3 190.38,150.29 UV21.G8 ; UV22.G1 206.75,134.5 206.75,134.51 207.11,134.51 207.11,134.5 UV23.G8 ; UV1.F9 187.68,130.31 186.91,130.31 v1(186.85,130.38) ; v1(173.78,144.85) 174.6,144.85 UV18.T1 ; UC1.M22 v1(116.79,118.54) ; v1(190.08,129.56) 190.13,129.56 UV1.G6 ; UV18.G1 167.79,144.65 167.78,144.65 167.78,145.01 167.79,145.01 UV19.G8 ; UV24.G8 212.16,112.41 212.76,112.41 212.76,112.42 UV25.G1
  BOTTOM w0.254: UV18.P9 173.39,150.84 v1(173.76,150.46) ; v1(116.79,116.1) 117.16,115.73 UC1.V23 ; v1(164.61,112.61) 164.82,112.61 165.11,112.89 UV1.AH39 ; UC1.B20 118.57,125.06 118.89,125.06 v1(118.91,125.09) 118.91,124.77 118.77,124.63 UC1.C20 ; UV1.B33 v1(168.66,133.17) ; UV1.B21 178.26,133.75 v1(178.4,133.88) ; UV1.N2 193.39,124.89 v1(193.52,125.02) ; v1(169.75,150.5) 169.39,150.13 UV18.J8 ; UV1.U2 192.36,121.69 v1(192.06,121.99) ; v1(126.08,118.69) 126.08,118.96 UC1.L7 ; UV1.F31 170.07,130.69 v1(170.46,130.3) ; v1(104.97,121.85) 104.97,121.86 UC1.F42 UC1.D42 ; UV25.T9 206.3,119.62 v1(206.08,119.84) ; UV1.AW16 181.91,105.49 v1(181.68,105.26) 181.46,105.47 UV1.AV17 ; UV21.D1 192.35,144.03 v1(192.35,143.97) ; v1(107.47,121.85) 107.48,121.86 UC1.F38 UC1.D38 ; v1(183.08,130.24) 183.08,130.25 183.08,130.51 UV1.F15 ; UV1.Y34 167.66,119.34 v1(168.11,119.79) ; v1(220.75,92.28) 220.75,92.4 220.48,92.68 220.12,92.68 220.04,92.6 PU600.8 ; UV20.E2 v1(192.38,149.66) UV21.D8 ; v1(163.5,148.76) 163.53,148.73 163.53,148.86 163.79,149.12 UV19.B3 ; UV20.T1 183.66,151.34 184.25,151.34 v1(184.39,151.2) 184.73,150.85 UV20.P1 ; UV20.P9 184.78,144.47 v1(184.4,144.85) ; v1(164.77,122.39) 164.87,122.49 UV1.T39 ; UV25.P9 206.57,118.02 v1(206.95,118.39) ; UC1.AP22 117.56,106.69 117.23,106.37 v1(117.18,106.37) ; UV1.F23 176.49,130.69 176.88,131.07 v1(176.92,131.07) ; UV1.AP19 180.18,107.89 180.68,108.39 v1(180.82,108.39) 180.86,108.35 UV1.AP18 180.66,107.69 UV1.AR18 ; UC1.D26 UC1.F26 115,121.86 v1(115,121.85) ; v1(190.84,131.9) 191.16,131.57 UV1.E5 191.14,131.37 190.74,131.37 190.48,131.11 190.08,131.11 UV1.F7 ; UV1.B27 173.46,133.62 v1(173.25,133.83) ; UC1.AE58 95.42,111.63 v1(95.53,111.52) ; UV1.H9 v1(188.46,128.69) 188.86,128.29 UV1.J8 ; UC1.A32 UC1.B32 ; v1(172.43,108.4) 172.14,108.69 UV1.AN29 ; UC1.AF14 122.59,112.06 v1(122.05,112.61) ; UC1.AJ27 114.08,109.95 UC1.AH28 113.43,109.95 UC1.AJ29 112.85,109.95 v1(112.53,109.62) ; v1(213.3,134.12) 212.95,134.46 UV22.G9 ; UV1.AW26 174.26,105.47 v1(173.83,105.03) 173.46,105.4 UV1.AV27 ; UV1.A3 191.91,133.25 v1(191.91,133.67) ; UV1.AM11 UV1.AN11 186.46,108.49 UV1.AP11 186.46,107.57 v1(186.27,107.38) ; UC1.D12 123.54,123.35 v1(123.46,123.27) 123.54,123.27 UC1.E11 ; UC1.D12 123.92,124.16 UC1.C11 ; UC1.D12 UC1.D14 122.35,124.18 UC1.C14 122.36,124.38 122.36,125.44 UC1.A14 ; UV1.Y39 164.84,119.29 164.75,119.21 v1(164.73,119.21) ; v1(212.56,113.62) 212.16,114.02 UV25.J2 ; UV1.F29 171.66,130.63 v1(171.32,130.29) ; UV1.AP27 173.26,107.94 v1(173.66,108.33) 173.31,108.69 UV1.AN27 ; UC1.AG11 123.81,110.87 UC1.AF11 124.54,111.6 124.71,111.6 124.72,111.6 UC1.AE10 ; UC1.AG11 123.76,110.77 v1(123.39,110.41) ; UC1.AG11 123.41,111.18 UC1.AF12 ; v1(181.05,133.43) 181.05,133.38 181.46,132.97 UV1.B17 ; UC1.L17 121.19,119.42 v1(121.58,119.02) 121.96,119.4 UC1.L15 ; v1(112.49,121.85) 112.49,121.86 UC1.F30 UC1.D30 ; UV1.U34 UV1.V34 ; UV1.U34 167.13,121.89 v1(167.07,121.95) ; UV1.U34 UV1.T34 167.66,122.89 v1(167.08,123.48) 167.65,123.48 UV1.R34 UV1.P34 167.54,124.41 167.54,124.97 UV1.N34 ; UV21.B3 194.38,146.32 v1(194.6,146.54) ; v1(172.96,144.1) 172.84,143.97 172.27,143.97 UV18.M1 ; RP41.6 144,112.29 v1(144.17,112.47) 143.85,112.79 RP41.5 ; UV1.N31 170.06,125.67 v1(169.75,125.99) 170.06,126.3 UV1.L31 169.65,126.91 v1(169.65,127) 169.65,127.08 UV1.K31 UV1.J31 UV1.H31 ; UC1.AP3 129.28,106.09 129.28,105.98 v1(129.28,105.98) ; UV1.AE6 190.02,115.09 v1(189.95,115.15) ; v1(206.2,129.33) 206.07,129.45 206.07,130.02 UV22.M1 ; UV1.B25 175.06,133.09 v1(175.16,133.19) ; v1(109.21,110.51) 108.79,110.51 UC1.AH36 ; v1(109.21,110.51) UC1.AJ35 ; v1(109.21,110.51) 109.62,110.51 UC1.AH34 109.86,109.84 v1(110.01,109.69) ; v1(179.95,133.93) 179.86,133.84 UV1.B19 ; v1(164.73,120.77) 164.74,120.77 164.87,120.89 UV1.V39 ; UV20.M1 185.9,151.34 185.33,151.34 v1(185.2,151.21) ; UV23.D8 207.75,136.5 v1(207.75,136.5) UV22.E2 ; RP41.7 143.96,111.79 v1(144.17,111.58) 143.88,111.29 RP41.8 ; UV23.D1 212.95,136.9 v1(213.35,136.5) ; v1(104.77,109.71) 105.07,109.71 UC1.AJ41 105.53,109.72 v1(105.82,109.72) 105.82,110.14 UC1.AH40 106.19,110.51 v1(106.6,110.51) ; v1(104.77,109.71) 104.24,109.71 UC1.AJ43 103.68,110.27 UC1.AH44 103.03,110.27 UC1.AJ45 102.47,109.71 v1(101.98,109.71) ; v1(104.77,109.71) 104.65,109.83 UC1.AH42 ; UV24.B3 208.42,108.42 v1(208.64,108.2) ; UV1.B7 189.48,132.7 189.48,133.7 v1(189.47,133.71) ; v1(68.61,101.59) 68.7,101.5 JXDP1.20 ; UC1.AL22 117.55,108.64 117.23,108.32 v1(117.18,108.32) ; UV1.A37 v1(166.06,133.81) ; v1(212.56,128.53) 212.94,128.9 UV22.P9 ; UV20.G1 190.38,150.86 v1(190.78,151.26) UV21.F9 ; UV1.AP28 172.46,107.73 v1(172.11,107.38) 172.4,107.09 UV1.AR28 ; v1(180.32,104.02) 180.11,104.02 179.06,105.07 UV1.AW20 ; v1(190.07,128.67) 190.45,128.29 ; 190.45,128.29 UV1.J6 ; 190.45,128.29 190.44,128.29 189.66,127.51 UV1.K7 ; UC1.B4 128.34,124.92 127.91,124.92 v1(127.87,124.96) ; UC1.AU53 97.95,105.48 98.51,106.04 UC1.AR52 ; UV1.N6 190.72,125.09 v1(190.93,125.3) ; JXDP1.26 67.2,97.8 67.01,97.61 65.94,97.61 65.7,97.85 JXDP1.32 ; UC1.N10 124.77,118.24 124.77,117.35 UC1.R10 124.04,117.32 v1(123.9,117.46) ; v1(119.09,108.32) 119.13,108.32 119.46,108.64 UC1.AL20 ; v1(171.29,108.27) 170.87,108.69 UV1.AN30 ; UV1.AJ11 186.52,111.89 v1(186.88,111.53) ; v1(164.62,132.53) 164.62,132.37 164.7,132.29 UV1.C39 UV1.E39 ; UV1.AP29 171.66,107.7 v1(171.41,107.45) 171.31,107.45 UV1.AP30 ; v1(190.15,127.07) 190.46,126.76 UV1.L6 ; UV19.D8 165.79,145.65 v1(165.79,145.65) UV18.E2 ; v1(206.07,110.44) 206.13,110.44 UV24.D1 ; UC1.AL29 112.9,108.64 112.58,108.32 v1(112.53,108.32) ; v1(192.94,118.59) 192.84,118.49 UV1.AA2 ; v1(100.86,109.71) 100.86,110.16 UC1.AH49 ; v1(100.86,109.71) 100.34,109.71 100.11,109.95 UC1.AJ50 99.78,109.95 UC1.AH51 99.13,109.95 UC1.AJ52 ; v1(100.86,109.71) 100.98,109.71 101.22,109.95 UC1.AJ47 101.63,109.71 v1(101.98,109.71) ; v1(106.6,110.51) 107.02,110.51 UC1.AH38 107.25,109.62 v1(107.25,109.62) 106.74,109.1 UC1.AL39 106.47,108.97 UC1.AL40 106.47,108.32 v1(106.58,108.32) 106.74,108.16 UC1.AN39 UC1.AP39 UC1.AR39 ; v1(106.6,110.51) UC1.AJ39 ; v1(175.41,105.03) 175.41,105.04 UV1.AW24 ; v1(173.78,144.85) 173.39,144.46 UV18.P1 ; UV1.AJ33 168.46,111.87 v1(168.73,111.6) ; UV25.G1 212.96,112.42 v1(213.35,112.02) UV24.F9 ; UC1.AJ56 96.53,109.95 UC1.AH55 97.18,109.95 UC1.AJ54 97.83,109.95 UC1.AH53 98.15,109.15 v1(98.17,109.13) ; v1(93.95,121) 94.25,120.7 UC1.J59 ; UC1.G18 120.25,121.64 120.41,121.48 120.44,121.48 v1(120.61,121.32) 120.68,121.32 UC1.H17 ; UV1.AJ6 190.71,111.89 v1(190.91,112.09) ; v1(165.25,127.77) 165.26,127.77 UV1.K39 ; UV23.A9 v1(206.15,138.9) UV22.B1 ; UV1.AW22 177.46,105.13 v1(177.61,104.98) ; v1(111.04,109.62) 111.04,110.16 UC1.AH32 ; v1(186,144.85) 186.38,144.47 UV20.M9 ; v1(189.18,150.46) 188.78,150.06 UV20.J2 ; v1(192.04,116.57) 192.07,116.57 192.39,116.89 UV1.AC2 ; UV1.AC34 167.6,116.63 v1(167.03,116.63) 166.86,116.46 UV1.AD35 UV1.AD37 165.66,115.69 UV1.AE38 ; UV19.A9 v1(163.39,144.05) UV18.B1 ; UV1.AJ10 187.26,111.92 v1(186.88,111.53) ; v1(182.96,143.98) 183.18,144.2 UV20.T9 ; UC1.H13 122.59,121.32 v1(122.52,121.32) ; v1(95.32,108.46) 95.51,108.64 UC1.AL57 ; UV18.G9 167.83,150.85 v1(168.17,151.2) ; UV25.M9 206.57,116.42 v1(206.95,116.79) ; v1(193.46,112.04) 193.41,112.09 UV1.AJ2 ; UV1.AW14 183.86,105.3 v1(183.62,105.05) ; UV22.J2 207.35,132.9 v1(206.95,133.3) ; 128.45,123.93 128.43,123.91 127.82,123.91 127.73,123.82 127.7,123.82 UC1.D5 ; v1(164.54,114.87) 164.64,114.87 165.02,114.49 UV1.AF39 ; v1(167.08,120.29) UV1.W34 ; v1(213.75,116.41) 212.96,116.41 UV25.M1 ; v1(192.93,128.29) 192.73,128.09 UV1.J2 ; v1(190.94,123.66) 190.63,123.66 UV1.R6 ; v1(167.32,114.72) 167.66,115.06 UV1.AE34 ; v1(165.79,151.25) UV19.D1 ; UV1.AK39 165.1,111.29 v1(164.62,111.77) ; UV1.AL11 UV1.AK11 186.44,111.09 v1(186.88,111.53) ; v1(118.22,116.1) 118.22,115.97 117.67,115.43 UC1.W22 ; UC1.AB22 117.67,113.45 118.09,113.03 118.09,112.98 v1(118.22,112.85) 118.59,112.48 UC1.AD21 ; UV1.AC6 190.84,116.69 v1(190.94,116.6) ; v1(186.09,133.86) 186.28,133.67 186.28,132.7 UV1.B11 ; UC1.D54 UC1.F54 97.45,121.86 v1(97.44,121.85) ; v1(190.89,118.55) 190.72,118.55 UV1.AA6 ; UV24.E1 v1(206.95,110.42) UV25.E8 ; v1(209.95,174.63) JLVDS.12 ; v1(102.46,121.85) 102.46,121.86 UC1.F46 UC1.D46 ; JLVDS.3 205.45,174.32 205.64,174.51 v1(205.64,175.21) ; UC1.F58 94.9,122.01 v1(94.77,121.88) 95.19,121.46 UC1.H57 ; JLVDS.15 211.45,174.1 211.29,174.25 v1(211.29,174.45) ; UV1.K14 184.27,127.49 v1(184.5,127.26) ; UV1.AG2 193.42,113.69 v1(193.47,113.74) ; v1(70.85,105.06) 71.1,104.81 UC4.7 ; v1(187.76,133.42) 187.86,133.32 UV1.B9 ; UV22.T1 206.07,127.79 206.07,128.38 v1(206.21,128.51) 206.55,128.86 UV22.P1 ; v1(192.94,129.8) 192.83,129.69 UV1.G2 ; UC1.AP26 114.81,106.69 114.49,106.37 v1(114.43,106.37) ; UC1.A24 UC1.B24 ; UC1.AF18 UC1.AF17 120.97,111.81 v1(121.02,111.86) 121.2,111.86 UC1.AF15 ; UV1.P39 v1(164.76,124.09) ; UV1.AR5 191.22,107.19 v1(191.63,107.6) ; v1(167.16,110.38) 167.32,110.23 167.6,110.23 UV1.AL34 ; UC1.A11 123.91,126.41 124.27,126.77 v1(124.27,127.36) ; v1(99.95,121.85) 99.96,121.86 UC1.F50 UC1.D50 ; v1(193.37,123.32) 193.35,123.29 UV1.R2 ; UV22.B9 v1(213.35,138.9) ; v1(193.04,108.81) 192.96,108.89 UV1.AN2 ; UV1.AK31 UV1.AL32 169.27,110.29 v1(169.66,109.89) 170.06,109.49 UV1.AM31 ; UV1.AP7 189.61,107.89 v1(189.25,108.26) 188.86,108.64 UV1.AN8 188.86,108.69 UV1.AM9 188.06,109.5 v1(188.48,109.92) 188.86,110.29 UV1.AL8 UV1.AK7 UV1.AL6 ; UV1.AW35 166.96,105.42 v1(167.41,104.97) 167.86,105.42 UV1.AW34 ; UV1.AP17 181.66,107.9 181.99,108.23 v1(182.09,108.23) 182.12,108.23 182.46,107.89 UV1.AP16 ; v1(127.81,105.91) 127.66,105.91 127.38,106.18 UC1.AR5 ; UC1.L58 v1(95.45,119.43) ; UC1.AN7 126.81,107.21 v1(126.97,107.21) ; UV22.T9 213.21,127.3 v1(213.43,127.08) ; v1(101.98,109.71) 102.05,109.78 UC1.AH46 ; v1(184.69,131.33) 184.69,130.87 UV1.F13 ; UV24.A9 v1(213.35,108.02) UV25.B1 ; UV1.AL23 176.83,110.29 v1(177.23,109.89) ; v1(174.51,151.34) 174.51,151.33 UV18.T9 ; UV1.B23 176.66,133.12 176.54,133.24 v1(176.57,133.24) ; UV22.J8 212.23,132.9 v1(212.6,132.54) ; v1(119.94,109.54) 119.75,109.73 UC1.AH19 ; v1(118.71,122.62) 118.77,122.62 UC1.F20 ; v1(212.56,130.13) 212.94,130.5 UV22.M9 ; UV25.P1 212.95,118.06 v1(213.3,118.41) 213.44,118.55 213.44,119.14 UV25.T1 ; UC1.B28 UC1.A28 ; v1(188.42,144.81) 188.78,145.17 UV20.J8 ; UC1.AL17 121.55,108.98 v1(121.74,108.78) 121.74,108.99 UC1.AJ14 122.19,109.3 UC1.AL13 122.7,108.97 123,109.27 UC1.AJ13 ; v1(123.12,105.86) 123.03,105.86 UC1.AT13 ; v1(171.33,111.67) 171.54,111.89 UV1.AJ28 ; UC1.V7 125.95,115.8 v1(125.95,115.9) ; UC1.AN35 109.22,107.02 v1(109.16,107.02) ; v1(193.46,126.75) 193.32,126.61 192.58,126.61 UV1.L2 ; v1(180.88,130.14) 181.44,130.69 UV1.F17 ; UV1.AE2 192.82,115.29 v1(192.93,115.4) ; UC1.A52 UC1.B52 ; UC1.D34 UC1.F34 109.99,121.86 v1(109.98,121.85) ; UV20.E8 v1(192.38,144.85) UV21.E1 ; RP51.6 129.95,131.64 v1(129.7,131.9) 129.45,131.66 RP51.5 ; v1(206.91,114.38) 207.27,114.02 UV25.J8 ; v1(219.29,172.29) 219.45,172.44 JLVDS.31 ; UV1.N34 167.15,125.09 v1(167.1,125.14) ; UV1.N34 UV1.M34 UV1.L34 167.66,126.77 v1(167.35,127.08) 167.66,127.39 UV1.K34 UV1.J34 167.48,128.48 167.48,128.9 UV1.H34 167.61,129.09 v1(167.16,129.54) 167.51,129.89 UV1.G34 ; UC1.V10 125.25,115.86 UC1.U9 ; UV1.AW30 171.06,104.98 v1(171.25,104.78) ; v1(65.43,95.34) 65.7,95.08 JXDP1.31 ; v1(189.99,144.11) 190.33,144.45 UV20.G9 ; v1(127.22,123.39) 126.52,123.39 126.14,123.78 UC1.D8 ; v1(172.16,150.46) 171.79,150.84 UV18.M9 ; v1(192.94,110.56) 192.87,110.49 UV1.AL2 ; v1(207.1,175.02) 206.95,174.86 JLVDS.6 ; v1(128.68,120.98) 128.98,121.28 UC1.G3 ; DI4.3 DI4.8 v1(19.52,47.76) ; UV25.B9 v1(206.15,108.02) ; UV23.E1 v1(212.55,136.5) UV22.E8 ; v1(171.79,133.74) 171.86,133.67 UV1.B29 ; UV1.W6 190.46,120.44 189.93,120.97 v1(189.93,121.21) 190.19,121.47 190.19,121.62 UV1.U6 ; v1(113.11,110.51) 112.69,110.51 UC1.AH30 ; UC1.AA1 130.61,113.84 v1(130.78,113.68) ; v1(18.71,60.79) 18.6,60.91 DI1.8 DI1.3 ; UV23.F9 v1(206.15,134.9) 206.55,134.5 UV22.G1 ; UC1.AA58 v1(95.45,114.23) ; v1(184.66,133.55) UV1.B13 ; v1(114.4,108.29) 114.76,108.64 UC1.AL26 ; v1(192.05,119.77) 192.15,119.77 UV1.W2 ; v1(206.21,112.81) 206.55,112.46 UV25.G9 ; v1(164.71,130.58) 164.8,130.49 UV1.F39 ; UV1.F19 179.78,130.97 v1(179.66,130.97) ; UC1.K12 123.39,119.05 v1(123.45,119) 123.32,119 122.91,119.4 UC1.L13 ; UV1.B31 170.37,132.8 v1(170.37,133.81) ; UC1.V58 v1(95.45,115.53) ; v1(112.54,106.37) 112.59,106.37 UC1.AP29 ; UV19.E1 v1(165.79,150.45) UV18.E8 ; UV1.AB39 165.22,117.64 165,117.64 164.63,117.27 v1(164.63,117.14) ; UV20.B1 194.38,150.86 v1(194.78,151.26) 195.18,150.86 UV21.A9 ; v1(124.42,120.65) 124.73,120.34 UC1.J10 ; UC1.AR39 106.69,106.32 UC1.AT40 ; UC1.AR39 107.14,106.37 v1(107.22,106.45) 107.4,106.45 UC1.AP38 ; UC1.AG23 117.1,110.75 v1(116.61,110.75) 116.26,110.75 116.24,110.74 116.03,110.74 115.71,110.42 UC1.AJ25 ; UV1.G33 UV1.F33 UV1.F34 167.66,130.96 v1(167.45,131.17) 167.23,131.39 UV1.E35 ; v1(190.94,113.71) 190.88,113.71 190.66,113.49 UV1.AG6 ; v1(168.99,144.85) 169.39,145.25 UV18.J2 ; v1(208.45,174.65) JLVDS.9 ; v1(181.96,134.12) 182.95,133.13 182.95,133.07 183.06,132.96 UV1.B15 ; UC1.A40 UC1.B40 ; v1(187.68,107.51) 188.05,107.89 UV1.AP9 UV1.AN10 ; UV1.AM35 166.86,109.52 v1(167.21,109.18) 167.66,108.72 UV1.AN34 ; UC1.AL10 124.97,108.44 v1(125.05,108.44) ; UC1.B36 108.63,124.69 108.63,125.13 UC1.A36 ; UV1.AR39 165.26,107.26 v1(165.65,107.65) 165.26,108.03 UV1.AP39 165.66,108.49 UV1.AN38 ; UC1.AB20 119.1,113.68 119.19,113.77 119.19,113.84 119.66,114.31 v1(119.66,114.31) ; UC1.L20 119.16,119.42 UC1.L18 120.06,118.74 v1(120.23,118.57) ; UV1.F11 186.53,130.69 v1(186.85,130.38) ; UV1.AL14 183.68,110.29 v1(183.22,110.75) ; UC1.A18 119.71,125.52 119.71,125.15 119.79,125.08 119.79,124.38 UC1.C18 119.77,124.18 UC1.D18 120.18,123.7 v1(120.61,123.27) ; UC1.AP20 119.44,106.69 119.29,106.54 119.28,106.54 119.11,106.37 v1(119.09,106.37) ; v1(125.03,106.45) 125.01,106.45 UC1.AP10 ; UV18.G1 167.79,144.45 v1(167.39,144.05) UV19.F9 ; UV25.E2 v1(211.75,110.42) 212.15,110.02 UV24.D8 ; UV1.AN17 181.46,108.73 181.12,109.07 v1(180.85,109.07) 180.64,109.07 180.41,108.84 180.41,108.83 UV1.AN19 ; UV1.F21 178.08,130.69 v1(178.46,131.07) ; UV18.B9 v1(163.39,151.25) ; UV23.B3 211.09,138.5 v1(210.87,138.73) ; v1(169.46,104.97) UV1.AW32 ; UC1.AB10 124.37,113.08 v1(123.78,113.08) ; UV1.H39 164.85,128.89 v1(164.74,129) ; UC1.G5 127.58,121.55 126.82,121.55 UC1.G6 126.61,121.64 v1(126.27,121.3) 125.92,121.64 UC1.G8 ; v1(173.69,130.29) 173.29,130.69 UV1.F27 ; UV20.B9 v1(194.78,144.05) ; v1(111.06,108.32) 110.88,108.32 UC1.AL33 ; UV1.M39 164.8,125.69 v1(164.73,125.62) ; UC1.B60 93.65,124.86 93.65,124.85 93.78,124.72 93.78,124.28 94.38,123.69 UC1.D59
  BOTTOM w0.279: JXDP1.2 73.2,101.38 v1(72.99,101.59) ; JXDP1.7 71.7,91.41 72.18,90.93 v1(72.55,90.93) 73.2,91.58 JXDP1.1 ; JXDP1.25 v1(67.2,95.34) ; JXDP1.49 61.2,94.65 v1(61.56,95.01) ; JXDP1.38 64.2,101.38 64.01,101.57 v1(64.01,101.62) ; v1(65.43,95.34) 65.41,95.32 64.54,95.32 64.2,94.98 JXDP1.37 ; JXDP1.13 v1(70.2,90.93) ; v1(71.53,101.59) 71.67,101.45 71.67,100.45 71.7,100.42 JXDP1.8 ; v1(60.94,100.73) 61.2,100.47 JXDP1.50 ; v1(67.27,101.61) 67.2,101.55 JXDP1.26 ; JXDP1.19 v1(68.7,95.34) ; JXDP1.59 58.7,95.01 v1(58.19,95.51) ; v1(70.16,101.61) 70.2,101.57 JXDP1.14
  BOTTOM w0.305: UV1.L11 186.71,126.69 v1(186.98,126.96) ; UV1.N31 170.06,124.96 v1(169.79,124.68) 170.06,124.41 UV1.P31 ; PU600.4 218.54,90.36 v1(218.15,90.75) ; v1(174.76,110.69) 174.34,110.27 174.28,110.27 UV1.AL26 ; v1(118.19,121.65) 118.04,121.79 UC1.G22 ; UV1.C1 192.86,132.58 v1(193.39,133.11) ; v1(118.71,122.62) 118.61,122.62 118.09,123.14 UC1.D21 ; UV1.AL17 181.36,110.39 v1(180.87,110.39) ; UV1.W31 UV1.U31 169.73,122.02 v1(169.73,122.23) 169.73,122.56 UV1.T31 ; v1(124.14,115.55) 124.22,115.55 124.36,115.41 UC1.V10
  BOTTOM w0.356: v1(89.15,64.56) 88.9,64.31 JDIMM1.150 ; JDIMM2.3 120.95,72.65 121.19,72.88 v1(122.77,72.88) ; v1(127.28,65.03) 127.85,64.47 JDIMM2.26 127.85,62.18 127.98,62.05 128.32,62.05 128.45,62.18 JDIMM2.28 ; JDIMM1.25 49,72.6 49.24,72.85 v1(50.26,72.85) 50.38,72.85 50.8,72.43 JDIMM1.31 ; JDIMM1.179 97.6,72.63 98.21,73.24 v1(99.41,73.24) ; JDIMM2.172 174.05,62.06 174.25,61.86 v1(175.92,61.86) 175.85,61.93 JDIMM2.178 ; JDIMM2.167 172.55,72.7 172.81,72.96 v1(173.51,72.96) 173.73,72.96 173.94,72.75 173.95,72.75 174.23,72.46 174.23,72.46 174.35,72.34 JDIMM2.173 ; JDIMM2.55 136.55,72.47 136.15,72.87 v1(135.69,72.87) 134.99,72.87 134.75,72.63 JDIMM2.49 ; v1(179.45,61.86) JDIMM2.190 ; JDIMM1.11 44.8,73.03 44.33,73.5 v1(44.22,73.5) ; v1(99.41,73.24) 100,72.65 JDIMM1.187 ; v1(99.41,73.24) 99.4,73.23 JDIMM1.185 ; JDIMM2.32 129.65,64.38 129.82,64.55 v1(129.82,64.57) 129.9,64.65 131.03,64.65 131.45,64.23 JDIMM2.38 ; JDIMM1.155 90.4,73.17 v1(90.33,73.24) 91.77,73.24 92.2,72.81 JDIMM1.161 ; JDIMM2.46 133.85,64.75 133.57,65.03 ; JDIMM1.189 100.6,72.53 v1(101.31,73.24) 101.68,73.24 102.4,72.52 JDIMM1.195 ; JDIMM2.2 120.65,64.35 120.87,64.56 v1(121.64,64.56) 122.15,64.56 122.45,64.27 JDIMM2.8 ; JDIMM2.150 v1(167.45,61.86) ; v1(177.65,61.86) JDIMM2.184 ; JDIMM2.196 181.25,61.99 v1(181.38,61.86) ; JDIMM1.32 51.1,64.42 51.46,64.78 v1(51.84,64.78) ; JDIMM1.37 52.6,72.65 v1(52.8,72.84) 53.18,72.84 53.18,72.85 54.13,72.85 54.4,72.58 JDIMM1.43 ; JDIMM2.144 v1(165.65,61.86) ; 125.25,64.59 124.68,64.59 124.25,64.16 JDIMM2.14 ; 125.25,64.59 v1(125.25,64.58) ; 125.25,64.59 125.82,64.59 126.05,64.36 JDIMM2.20 ; JDIMM1.139 85.6,72.63 86.21,73.24 v1(86.53,73.24) 86.88,73.24 87.4,72.72 JDIMM1.145 ; 133.57,65.03 v1(133.57,65.03) ; 133.57,65.03 133.57,65.03 133.25,64.71 JDIMM2.44 ; JDIMM1.170 94.9,64.26 v1(94.6,64.56) 94.3,64.25 JDIMM1.168 ; JDIMM2.179 176.15,72.74 v1(176.32,72.91) 177.7,72.91 177.95,72.66 JDIMM2.185 ; JDIMM2.134 162.65,62.24 162.21,61.8 v1(161.6,61.8) 161.09,61.8 160.85,62.04 JDIMM2.128 ; JDIMM1.151 89.2,73.11 v1(89.07,73.24) 89.47,73.24 89.8,72.91 JDIMM1.153 ; JDIMM2.43 132.95,72.61 132.68,72.88 131.73,72.88 131.73,72.88 ; v1(178.65,73.23) 178.55,73.12 JDIMM2.187 ; JDIMM2.31 129.35,72.44 v1(128.91,72.88) 128.91,72.88 127.79,72.88 127.55,72.64 JDIMM2.25 ; JDIMM2.66 139.85,64.32 140.1,64.56 v1(140.8,64.56) 141.43,64.56 141.65,64.35 JDIMM2.72 ; JDIMM2.161 170.75,72.56 170.4,72.91 v1(169.45,72.91) 169.19,72.91 168.95,72.67 JDIMM2.155 ; v1(122.77,72.88) 122.75,72.86 JDIMM2.9 ; v1(122.77,72.88) 123.12,72.88 123.35,72.65 JDIMM2.11 ; JDIMM2.133 162.35,72.64 162.08,72.91 v1(160.75,72.91) 160.55,72.71 JDIMM2.127 ; JDIMM2.65 139.55,72.67 139.77,72.88 v1(140.81,72.88) 141.06,72.88 141.35,72.59 JDIMM2.71 ; JDIMM1.184 99.1,64.45 98.83,64.72 v1(98.45,64.72) 97.76,64.72 97.3,64.26 JDIMM1.178 ; JDIMM2.136 163.25,64.43 v1(163.54,64.72) 163.85,64.41 JDIMM2.138 ; JDIMM1.134 84.1,64.34 83.85,64.59 v1(83.21,64.59) ; v1(53.05,61.48) 52.9,61.63 JDIMM1.38 ; JDIMM1.65 61,72.48 61.37,72.85 v1(61.88,72.85) 62.51,72.85 62.8,72.56 JDIMM1.71 ; JDIMM1.72 63.1,64.45 62.69,64.86 v1(61.88,64.86) 61.3,64.28 JDIMM1.66 ; JDIMM2.145 v1(165.95,72.85) 164.56,72.85 164.15,72.44 JDIMM2.139 ; JDIMM1.167 94,72.39 94.38,72.77 v1(95,72.77) 95.42,72.77 95.8,72.39 JDIMM1.173 ; v1(82.01,64.65) 82.3,64.36 JDIMM1.128 ; JDIMM1.136 84.7,64.43 84.84,64.57 v1(85.5,64.57) 85.3,64.37 JDIMM1.138 ; v1(138.61,72.83) 138.35,72.57 JDIMM2.61 138.35,70.37 138.54,70.18 138.82,70.18 138.95,70.31 JDIMM2.63 ; JDIMM2.153 168.35,72.44 v1(167.95,72.83) 167.75,72.63 JDIMM2.151 ; 131.73,72.88 131.47,72.88 131.15,72.56 JDIMM2.37 ; 131.73,72.88 v1(132.07,72.88) ; JDIMM1.3 42.4,72.61 42.62,72.82 44.2,72.82 ; JDIMM1.48 55.9,61.98 v1(55.65,61.73) 55.3,62.09 JDIMM1.46 ; JDIMM1.8 43.9,64.22 43.51,64.6 v1(43.27,64.6) 42.4,64.6 42.1,64.31 JDIMM1.2 ; v1(100.58,61.08) 100.9,61.4 JDIMM1.190 ; JDIMM2.48 134.45,64.64 v1(134.84,65.03) 135.67,65.03 136.25,64.45 JDIMM2.54 ; JDIMM2.13 123.95,72.56 124.27,72.88 v1(125.31,72.88) 125.75,72.44 JDIMM2.19 ; JDIMM1.127 82,72.85 v1(82.39,73.24) 83.2,73.24 83.8,72.64 JDIMM1.133 ; JDIMM1.162 92.5,64.19 v1(91.98,64.72) 91.15,64.72 90.7,64.27 JDIMM1.156 ; JDIMM1.14 v1(45.7,64.84) ; JDIMM1.144 v1(87.1,64.56) ; JDIMM1.55 58,72.53 57.69,72.84 v1(57.31,72.84) 56.54,72.84 56.2,72.5 JDIMM1.49 ; 44.2,72.82 JDIMM1.9 ; 44.2,72.82 v1(44.22,72.84) ; JDIMM1.54 57.7,64.41 58.15,64.86 v1(58.77,64.86) 59.5,64.12 JDIMM1.60 ; JDIMM2.189 179.15,72.64 179.43,72.92 v1(180.11,72.92) 180.78,72.92 180.95,72.75 JDIMM2.195 ; v1(102.64,64.71) 102.64,64.53 102.7,64.47 JDIMM1.196 ; v1(59.46,72.85) 59.8,72.51 JDIMM1.61 59.8,70.31 59.99,70.11 60.23,70.11 60.42,70.31 60.42,71.38 JDIMM1.63 ; JDIMM1.19 47.2,72.41 v1(46.76,72.84) 46.76,72.85 45.69,72.85 45.4,72.56 JDIMM1.13 ; JDIMM1.172 v1(95.5,64.69) ; JDIMM2.168 172.85,61.96 v1(172.69,61.8) 173.32,61.8 173.45,61.93 JDIMM2.170 ; JDIMM1.26 49.3,64.36 49.53,64.59 v1(49.88,64.59) 49.9,64.57 JDIMM1.28 ; JDIMM2.60 138.05,64.21 v1(137.7,64.56) ; v1(46.7,64.81) 46.7,64.79 47.2,64.79 47.5,64.49 JDIMM1.20 ; JDIMM2.156 v1(169.25,61.86) ; JDIMM2.162 v1(171.05,61.86) ; JDIMM1.44 v1(54.7,61.73)
  BOTTOM w0.381: v1(166.52,106.8) 166.06,106.34 UV1.AU37 ; v1(173.63,128.44) 173.22,128.44 UV1.J27 ; v1(176.95,123.03) 177.46,123.54 UV1.R22 UV1.N21 ; UV1.AA16 v1(182.96,119.19) UV1.Y15 ; UV1.AA23 176.46,118.56 v1(175.96,118.06) ; UV1.M22 177.46,125.72 v1(177.9,126.16) 177.46,126.59 UV1.L22 ; UV1.V16 182.46,120.85 v1(182.89,121.27) 183.31,121.69 UV1.U15 ; UV1.AF16 182.46,114.57 v1(181.94,114.05) 181.58,113.69 UV1.AG17 ; v1(173.96,119.32) 173.83,119.32 173.46,119.68 UV1.Y27 ; UV1.AG22 177.46,113.76 v1(177.9,114.19) 178.39,114.69 UV1.AF21 ; v1(157.64,110.39) UV13.3 ; v1(181.96,124.25) 182.4,124.69 UV1.N16 ; UV1.V23 176.96,121.19 v1(176.96,121.25) 177.4,121.69 UV1.U22 ; UV1.V18 180.46,120.82 v1(180.94,121.31) 181.33,121.69 UV1.U17 ; v1(181.96,123.06) 181.46,123.56 UV1.R17 ; v1(173.81,120.21) 174.3,120.69 UV1.V26 ; UV1.AF18 180.44,114.69 v1(179.95,115.17) 179.46,115.66 UV1.AD20 ; v1(177.96,118.3) 177.46,117.8 UV1.AB22 ; UV1.AD22 177.46,115.77 177.96,116.27 v1(177.96,116.32) ; v1(179.96,123.04) 180.12,123.04 UV1.T18 ; v1(184.91,118.14) 185.36,117.69 UV1.AB12 ; UV1.R27 173.46,123.67 173,123.21 v1(173,123.07) ; UV1.T31 170.05,122.89 169.98,122.95 169.98,124.03 170.05,124.09 UV1.P31 ; UV1.T21 v1(177.96,123.19) ; UV1.V11 186.46,120.58 186.07,120.18 v1(185.93,120.18) ; UV1.AD9 v1(188.06,115.07) 187.84,115.07 UV1.AF10 187.26,114.09 188.06,113.29 UV1.AG9 ; UV1.Y17 v1(180.96,119.19) ; UV1.V13 UV1.U13 184.5,121.69 v1(185.01,122.2) 184.51,122.69 UV1.T13 ; v1(176.96,119.32) 177.11,119.32 177.46,119.67 UV1.Y22 ; UV1.R15 183.46,123.67 182.98,123.19 v1(182.96,123.19) ; UV1.AB17 181.46,117.55 v1(181.96,117.05) ; PR307.2 149.27,156.42 148.5,155.64 PC312.2 ; v1(185.87,122.21) 186.35,122.69 UV1.T11 ; v1(174.91,121.26) 175.34,121.69 UV1.U24 ; v1(178.94,117.28) 178.85,117.28 178.46,116.89 UV1.AC21 ; UV1.AL20 179.24,110.29 v1(179.67,110.72) ; v1(186.98,116.34) 186.63,116.69 UV1.AC11 ; v1(181.96,115.34) 181.61,115.69 UV1.AD17 ; UV1.T16 182.46,122.69 v1(182.96,122.19) ; UV1.L17 181.46,126.63 v1(181.96,126.13) 181.52,125.69 UV1.M17 ; UV1.AB24 175.3,117.69 v1(174.91,118.08) 174.46,118.53 UV1.AA26 ; UV1.AD24 175.46,115.82 175.98,116.34 v1(175.98,116.35) 176.12,116.35 UV1.AC23 ; UV1.V21 v1(177.96,121.19) ; UV1.N23 176.46,124.74 176.03,125.17 v1(175.89,125.17) 175.46,125.59 UV1.M24 UV1.L24 ; UV1.AC13 UV1.AD15 183.96,115.19 v1(183.99,115.19) ; UV1.T26 174.33,122.69 v1(173.83,122.2) 173.46,121.83 UV1.U27 ; UV1.T23 176.36,122.69 v1(175.97,123.08) 175.46,123.59 UV1.R24 175.45,123.69 174.84,124.3 174.84,124.31 UV1.N26 ; v1(174.98,120.05) 175.1,120.05 UV1.Y24 175.53,119.69 v1(175.96,119.26) ; UV1.AB27 173.45,117.69 v1(172.94,118.2) 172.46,118.68 UV1.AA28 ; UV1.AB15 v1(182.96,117.19) UV1.AC16 ; v1(178.96,121.36) 179.14,121.36 UV1.U20 ; UV1.AB20 179.46,117.62 v1(180.01,117.08) 180.39,116.69 UV1.AC18 ; UV1.AH21 v1(178.96,113.19) UV1.AG20 ; UV1.AC26 174.31,116.69 v1(173.95,116.34) 173.46,115.85 UV1.AD27 UV1.AC28 ; UV1.AA18 180.29,118.69 v1(179.96,118.36) ; UV1.N18 180.05,124.28 v1(179.96,124.28) 179.96,124.19 UV1.R20 ; v1(179.93,120.11) 179.93,120.14 179.48,119.69 UV1.Y20 UV1.AA21
  BOTTOM w0.432: QV14.1 188.48,100.67 v1(188.75,100.4) 189.13,100.4 189.78,99.75 QV14.4
  BOTTOM w0.457: v1(209.72,162.52) UX2.3
  BOTTOM w0.508: CV313.2 CV301.2 v1(217.95,127.52) ; v3(126.32,19.29) 126.18,19.43 PC106.2 ; RV66.2 160.61,112.73 160.13,112.73 v1(160.11,112.72) 159.61,112.72 RV84.2 ; CL38.2 49.37,85.16 v1(49.82,84.71) ; v1(131.16,133.02) 131.16,133.04 131.04,133.16 RC84.1 ; v1(183.99,187.72) PC1200.2 PR1201.2 ; v1(171.35,94.63) 171.35,94.82 171.03,95.14 CV170.2 ; CX20.2 v1(13.44,111.47) ; v1(116.42,146.89) 116.42,146.97 116.1,147.3 JMINI.50 ; CV82.2 162.4,106.75 v1(162.51,106.64) ; v1(133.24,184.92) PQ5.3 ; CX35.2 196.69,170.11 196.47,170.33 v1(196.47,170.44) ; RC89.2 v1(133.8,130.12) ; v1(13.86,99.97) CX27.2 ; v3(127.41,16.55) 127.14,16.82 PC105.2 ; v1(160.5,87.33) 159.57,86.4 C2327.2 ; C5212.2 v1(84.86,117.8) ; v1(174.21,183.78) PC1205.2 174.97,183.78 PC1203.2 PC1209.2 ; CV172.2 172.18,95.11 v1(172.6,94.69) 173.06,95.15 CV171.2 ; v1(110.07,146.82) 109.7,147.2 JMINI.34 ; v1(164.74,129) 164.59,128.85 CV220.2 RV146.2 ; PC1.2 139.79,180.92 v1(140.3,181.43) 140.68,181.05 PC2.2 ; v1(131.36,98.34) 132.72,98.34 R2338.2 ; CI40.2 20.21,63.05 CI2.2 18.01,63.05 v1(17.82,62.86) ; CC29.2 70.27,109.26 CC13.2 69.31,109.26 v1(68.61,108.56) ; v1(210.54,57.99) PR836.1 PR838.1 ; PR306.2 149.6,151.89 v1(149.76,151.74) ; v1(121.39,130.82) C58.2 122.25,131.46 RC133.1 ; RV190.2 202.25,133.13 v1(201.63,133.75) 201.31,133.43 RV192.2 ; CV259.2 v1(193.12,155.91) ; v1(221.45,92.34) 221.45,91.96 221.26,91.77 PR602.2 ; CV290.2 v1(217.96,136.85) ; CV282.2 v1(217.95,140.42) ; CS17.2 221.69,105.47 220.18,103.96 v1(219.74,103.96) ; PR1202.2 v1(182.21,187.7) ; UE3.7 47.53,97.17 v1(46.96,96.59) 46.26,97.29 UE3.8 ; CL36.1 v1(37.24,81.02) ; RV176.2 v1(217.95,131.08) ; JLVDS.44 v1(210.45,177.64) ; CE25.2 44.03,100.91 v1(43.78,100.66) ; CV133.2 CV132.2 160.88,116.86 160.35,116.33 160.04,116.33 CV134.2 159.73,115.79 160.1,115.42 v1(160.53,115.42) ; JLVDS.42 228.07,177.86 228.69,177.24 v1(228.69,175.84) ; v1(214.83,144.16) CV296.2 ; CV137.2 204.3,146.19 v1(204.61,145.88) ; CC1.1 146,99.53 145.89,99.64 v1(145.89,100.21) ; JREAD.21 170.96,28.92 v1(171.35,28.52) ; v1(32.93,82.9) 32.93,83.32 CL41.1 ; CV217.2 v1(192.71,97.81) CV201.2 ; CI43.2 17.73,54.13 CI9.2 v1(19.16,54.13) ; CC28.2 78.79,123.42 78.13,122.76 v1(78.13,122.16) ; CV278.2 v1(218.39,116.67) ; RC122.2 v1(133.49,124.97) ; CV202.2 v1(192.69,96.92) CV216.2 ; v1(84.61,140.54) 84.55,140.48 PC522.2 ; CC2.1 150.08,99.13 150.4,99.45 v1(150.4,100.02) ; v1(186.18,155.94) CV232.2 ; CL34.2 35.97,89.42 v1(35.53,89.86) 35.08,89.42 CL35.2 ; v1(95.69,91.16) 95.69,92.05 95.28,92.47 RC22.2 95.29,92.88 RC25.2 ; v1(164.62,132.53) 164.62,133.1 164.11,133.61 163.09,133.61 162.78,133.3 CV221.2 RV147.2 ; CE36.2 193.91,42.14 v1(193.5,41.73) ; JDIMM1.205 v1(38.51,55.3) ; JRTC.2 212.32,39.5 212.7,39.12 v1(212.7,38.96) ; CC27.2 RC66.2 88,129.13 v1(88.4,129.53) ; SW2.1 202.92,39.15 v1(202.92,39.14) ; v1(89.83,19.82) v4(90.94,19.82) ; CV314.2 v1(217.95,138.64) ; CC16.2 61.19,87.77 v1(60.87,87.44) ; QV24.3 v1(176.91,90.17) ; CV298.2 v1(212.42,102.82) ; JLVDS.41 v1(198.94,179.3) ; CV312.2 v1(217.95,135.97) ; CV300.2 v1(217.95,139.53) ; PC505.2 90.95,131.66 v1(90.83,131.77) ; v1(214.23,160.41) 214.48,160.67 CX10.2 ; CX6.2 v1(24.92,94.37) ; CV288.2 v1(217.96,137.74) ; CX33.2 CX31.2 197.84,170.9 v1(197.35,170.42) ; CV326.1 163.59,109.68 v1(163.73,109.82) ; CV110.2 162.91,102.94 v1(163.03,102.82) ; v1(111.53,40.4) 111.77,40.16 CMOS1.1 ; v1(151.7,89.13) 151.53,89.31 U2302.4 ; CX11.2 v1(212.49,171.28) ; v1(93.15,96.42) 92.68,95.95 92.68,94.31 93.24,93.74 RC24.2 93.5,93.73 RC21.2 ; ME1.1 v1(117.33,40.16) ; JFAN.5 v1(53.74,109.56) ; v1(61.97,107.3) 62.3,106.97 CC30.2 ; UL2.2 48.1,82.31 v1(48.09,82.31) ; RC138.2 81.69,114.02 v1(81.98,114.31) ; RX171.2 198.92,174.11 v1(199.29,173.75) ; RC135.2 83.34,108.91 v1(83.02,109.23) ; DI7.1 v1(15.04,26.71) ; CX29.2 13.14,97.31 CX28.2 v1(12.42,97.28) ; PC708.2 166.04,168.37 165.74,168.07 v1(165.74,167.27) ; RA29.2 v1(26.13,21.6) 26.57,22.05 RA30.2 ; RV172.2 187.15,155.68 v1(186.84,155.99) ; CV277.2 RV193.2 218.75,132.88 v1(218.77,132.86) ; v1(14.32,34.49) CI44.2 14.62,33.42 CI19.2 ; UE3.6 48.8,97.23 v1(49.37,96.66) 50.07,97.36 UE3.5 ; v1(183.88,28.59) JREAD.9 ; v1(214.83,102.12) 214.45,102.51 CV297.2 ; PD3.1 144.11,185.05 v1(143.54,184.48) 143.16,184.1 PD1.2 ; JDIMM2.205 v1(119.2,58) ; PR840.1 v1(211.22,54.7) ; v1(123.46,94.13) 124.28,94.95 RC101.2 RC134.2 ; RV178.2 v1(218.39,115.78) ; v1(199.16,37.95) 199.01,37.79 SW2.6 ; CC5.2 128.68,95.26 v1(128.81,95.39) ; CC17.2 61.89,102.57 v1(61.3,103.16) ; v1(13.35,94.61) CX30.2 ; v1(202.54,37.78) 202.55,37.79 SW2.5 ; PC300.2 PR301.2 v3(149.77,149.23) ; v1(182.21,95.83) CV101.2 ; RV127.2 160.63,107.83 v1(160.3,108.15) ; v1(13.55,27.32) 13.55,19 15.37,17.19 15.37,14.06 v1(15.76,13.66) 16.34,13.09 v4(17.12,13.09) 18.19,13.09 18.93,12.36 v1(18.93,11.86) ; v1(204.07,177.62) 204.95,178.5 JLVDS.43 ; v1(169.57,167.65) PC707.2 ; v1(140.97,114.95) 140.99,114.97 C2326.2 ; v1(169.06,98.62) 169.51,98.62 169.92,98.21 YV1.2 ; CL20.2 RL31.1 35.08,78.78 v1(35.22,78.64) ; DI2.1 v1(17.09,58.07) ; v1(15.21,104.91) CX22.2 ; CV316.2 v1(217.95,130.19) ; v1(223.68,177.56) 223.45,177.78 JLVDS.46 ; CX2.2 v1(213.33,166.81) ; RL35.1 43.21,84.66 v1(43.59,85.04) ; CV112.2 181,101.3 180.82,101.48 v1(180.37,101.48) 180.37,100.71 CV111.2 ; CV306.2 v1(218.39,108.41) ; CE22.2 46.89,106.06 v1(46.57,105.74) ; JDIMM2.206 183.24,55.34 v1(182.69,55.89) ; JMINI.26 v1(106.5,149.55) ; JLVDS.45 217.95,178.18 v1(217.33,177.56) ; v1(196.24,51.71) PC720.1 ; YL2.2 39.7,78.15 v1(40.03,77.82) ; CV118.2 CV119.2 v1(187.54,101.35) 187.54,100.91 187.35,100.71 CV117.2 ; CV215.2 v1(193.89,95.83) ; v3(132.01,22.01) 131.94,21.95 131.59,21.95 131.08,21.44 129.67,21.44 129.25,21.85 129.25,22.6 v3(129.06,22.79) ; C2314.2 142.21,22.87 v1(141.95,23.12) ; PC202.2 v1(163.67,24.33) ; v1(51.19,109.85) JFAN.3 ; PC803.2 207.1,62.88 v1(206.66,62.43) ; v1(13.43,105.24) CX25.2 CX21.2 ; CV95.2 v1(173,101.16) 173.13,101.29 PC849.2 ; v1(103.47,146.77) 103.3,146.94 JMINI.18 ; v1(224.46,121.89) 223.67,122.68 CS16.2 ; v1(210.59,59.95) 210.98,59.57 PR834.1 ; v1(134.45,117.7) 134.41,117.75 RC116.2 RC88.2 RC123.2 ; RX34.2 v1(13.5,114.13) ; CV291.2 v1(217.95,141.3) ; PC210.2 v3(159.67,29.87) ; v1(45.62,109.55) 46.14,110.07 JFAN.4 ; QV25.3 173.19,91.01 v1(173.38,90.82) ; v1(173.48,99.91) YV1.4 ; CV307.2 v1(218.39,107.52) ; v1(215.53,102.76) CV293.2 CV294.2 ; RV148.2 CV223.2 195.83,104.19 v1(195.42,104.6) 195.86,105.04 CV224.2 RV149.2 ; CS13.2 218.58,117.49 v1(218.39,117.3) 218.39,117.33 218.16,117.56 RV194.2 ; CV305.2 v1(218.39,109.3) ; v1(119.17,129.5) 119.17,130.5 118.7,130.97 C85.2 ; RX26.2 203.99,163.97 v1(204.24,163.71) ; v1(15.83,99.88) CX24.2 ; CE23.2 v1(47.21,104.98) ; PC508.1 v1(89.69,142) ; R255.1 82.62,120.98 v1(82.5,121.1) ; v1(180.94,95.89) CV102.2 ; v1(198.28,179.33) 198.28,178.7 198.53,178.45 RX170.2 ; CL37.1 38.75,79.44 v1(39.21,79.89) ; PC1214.2 172.53,184.17 PR1214.2 v1(171.61,184.86) ; CX23.2 14.15,102.58 CX26.2 v1(13.43,102.55) ; v1(20.09,106.16) 20.4,105.85 QX3.3 ; v1(202.26,35.59) SW2.2 ; v1(190.72,28.59) JREAD.2 ; PC313.2 v3(145.89,158.38) ; PR1204.2 v1(176.76,187.47) ; C86.2 115.24,133.89 v1(115.24,132.28) ; JDIMM1.206 v1(104.12,55.3) ; PC7.2 PC8.2 v1(158.98,182.88) ; PR204.2 v3(160.55,29.86) ; CV317.2 v1(218.39,106.63) ; C63.2 v1(125.95,131.53) ; PC1307.2 PR1304.2 198.33,64.2 v1(198.59,64.46) ; v1(183.22,100.59) RV122.2 183.24,101.35 RV95.2 CV81.2 184.1,102.51 v1(183.48,103.13) ; YL2.4 v1(36.77,75.58) ; v1(198.02,173.45) 198.02,173.2 197.69,172.87 RX35.2 ; CV279.2 RV195.2 201.82,114.13 201.5,114.44 v1(201.5,114.89) ; CV292.2 v1(217.95,142.19) ; PC1213.2 v1(178.22,185.82) ; v1(94.83,146.89) 94.83,146.97 94.5,147.3 JMINI.4 ; v1(20.86,115.26) RX14.2 ; CV276.2 v1(202.25,129.51) ; v1(204.78,164.22) 204.78,164.08 205.35,163.51 205.97,163.51 206.53,164.07 RX36.2 ; PR106.2 v3(125.72,11.39) ; CV315.2 v1(217.89,129.3) ; v1(174.91,100.46) RV236.2 ; CA53.2 28.73,18.87 v1(28.86,19) ; v1(213.56,144.16) CV295.2 ; DI5.1 v1(15.46,44.27) ; v1(22.95,106.82) RX13.2 ; CV113.2 v1(180.37,102.19) ; v1(169.62,101.92) CV94.2 ; v1(82.34,136.1) 82.9,136.66 PC503.2 ; v1(151.29,122.18) v4(150.38,122.18) ; CL22.2 33.11,87.64 v1(32.49,88.26) 32.76,88.53 CL26.2 ; v1(218.9,168.1) RX9.2 ; PC203.2 v1(163.67,26.11) ; v1(187.53,156.16) 188.1,155.59 RV153.2 CV240.2 CV231.2 ; CV200.2 v1(191.48,95.83) ; CV302.2 v1(217.95,135.08) ; v1(188.18,92.65) CV103.2 ; JMINI.40 112.1,147.2 v1(111.79,146.89) ; v1(32.99,79.58) 33.29,79.88 CL15.2 ; PQ1201.3 v1(172.8,186.26) ; CV318.2 v1(218.39,110.19) ; CV289.2 v1(218.39,105.74) ; v1(50.97,106.96) CE24.2 ; PC312.2 v3(147.74,155.64) ; v1(42.09,94.24) v4(42.09,95.1) ; QC3.3 v1(135.59,131.8)
  vias: v1(0.51,119.89) v1(0.51,111.91) v1(0.51,56.34) v1(0.51,53.26) v1(0.51,21.09) v1(1.11,95.39) v1(1.11,91.45) v1(1.31,74.15) v1(1.31,70.86) v1(1.31,38.74) v1(1.31,35.71) v1(4.73,117.8) v1(4.73,115.26) v1(5.49,93.29) v1(5.81,72.53) v1(5.93,54.81) v1(6,37.09) v1(6.3,119.89) v1(6.85,111.91) v1(7.16,91.45) v1(7.27,117.8) v1(7.27,115.26) v1(7.26,74.15) v1(8.03,93.29) v1(7.98,33.83) v1(7.98,28.4) v1(7.98,22.97) v1(8.35,72.53) v1(8.47,54.81) v1(8.54,37.09) v1(12.08,119.89) v1(17.17,99.45) v1(17.17,97.67) v1(17.86,119.89) v1(18,95.01) v1(18.06,96.78) v1(18.19,31.95) v1(18.25,104.79) v1(18.25,103.01) v1(19.02,102.12) v1(19.02,100.34) v1(19.94,107.58) v1(21.05,103.07) v1(21.62,104.53) v1(22.19,99.96) v1(22.83,58.88) v1(22.91,62.91) v1(22.91,62.3) v1(23.46,97.93) v1(23.52,62.91) v1(23.52,62.3) v1(24.16,47.13) v1(24.16,45.98) v1(24.58,100.98) v1(24.65,58.84) v1(25.16,60.83) v1(25.16,60.22) v1(25.24,47.45) v1(25.3,49.22) v1(25.3,33.92) v1(25.3,33.28) v1(25.3,32.59) v1(25.77,60.83) v1(25.77,60.22) v1(25.94,33.98) v1(25.94,33.35) v1(25.94,32.71) v1(26.04,59.13) v1(26,19.82) v1(26.09,53.33) v1(26.09,52.72) v1(26.57,57.61) v1(26.7,53.33) v1(26.7,52.72) v1(27.08,20.65) v1(27.97,51.51) v1(27.97,50.9) v1(28.67,22.24) v1(28.83,65.57) v1(28.95,50.84) v1(29.42,65.57) v1(29.66,62.94) v1(29.66,62.33) v1(29.66,61.22) v1(29.66,60.61) v1(30,65.57) v1(32.27,8.98) v1(35.78,73.14) v1(36.8,85.16) v1(36.8,84.28) v1(36.8,83.32) v1(37,118.39) v1(37.53,8.98) v1(37.75,85.16) v1(37.75,84.28) v1(37.75,83.39) v1(37.94,102.5) v1(38.53,119.89) v1(38.64,85.16) v1(38.64,84.28) v1(38.64,83.32) v1(39.21,117.68) v1(40.68,82) v1(40.68,81.42) v1(41.27,8.98) v1(41.35,90.05) v1(42.19,68.68) v1(42.19,67.16) v1(43.27,105.54) v1(43.27,60.7) v1(43.27,59.17) v1(43.84,107.15) v1(44.22,68.68) v1(44.86,58.79) v1(46.53,8.98) v1(46.63,68.68) v1(46.63,67.16) v1(46.57,60.7) v1(46.57,59.17) v1(48,119.89) v1(49.04,69.06) v1(49.04,66.78) v1(49.11,60.7) v1(49.11,59.17) v1(50.31,68.85) v1(50.31,67.32) v1(50.27,8.98) v1(51.53,60.7) v1(51.53,59.17) v1(52.9,68.65) v1(52.9,67.13) v1(52.9,65.6) v1(53.61,120.31) v1(54.7,69.06) v1(54.7,66.78) v1(55.53,8.98) v1(56.87,68.68) v1(56.87,67.16) v1(56.86,65.54) v1(58.77,60.7) v1(58.77,59.17) v1(59.1,121.57) v1(59.46,68.68) v1(59.46,67.16) v1(60.15,61.08) v1(60.15,58.79) v1(61.88,68.68) v1(61.88,67.16) v1(61.88,60.7) v1(61.88,59.17) v1(62.4,12.98) v1(62.51,120.03) v1(64.04,73.86) v1(64.04,73.04) v1(64.33,123.63) v1(64.42,120.03) v1(64.42,74.31) v1(64.86,74.75) v1(65.31,75.19) v1(67.6,12.98) v1(69.2,126.45) v1(71.83,41.65) v1(72.8,12.98) v1(73.59,129.97) v1(74.53,37.35) v1(76.44,53.45) v1(77.41,134.11) v1(78,12.98) v1(79.59,134.85) v1(82.79,68.7) v1(82.79,67.18) v1(83.19,144.42) v1(83.2,12.98) v1(83.44,60.7) v1(83.44,59.17) v1(83.7,142.17) v1(84.74,69.08) v1(84.74,66.79) v1(84.93,150.81) v1(85.3,60.7) v1(85.3,59.17) v1(85.51,157.4) v1(86.53,68.7) v1(86.53,67.18) v1(87.03,115.78) v1(86.96,17.49) v1(86.96,14.95) v1(87.64,60.7) v1(87.64,59.17) v1(88.02,106.24) v1(87.97,102.68) v1(88.19,107.66) v1(88.4,12.98) v1(88.55,138.19) v1(88.55,136.98) v1(88.61,29.6) v1(88.76,103.57) v1(88.96,120.23) v1(88.97,114.37) v1(89.03,105.92) v1(89.07,68.7) v1(89.07,67.18) v1(89.06,29.98) v1(89.25,137.55) v1(89.15,61.08) v1(89.15,58.79) v1(89.26,121.75) v1(89.42,159.3) v1(89.42,153.52) v1(89.94,138.19) v1(89.94,136.98) v1(89.9,8.98) v1(90.59,68.7) v1(90.59,67.18) v1(91.15,16.86) v1(91.15,14.32) v1(91.15,11.78) v1(91.26,60.7) v1(91.26,59.17) v1(91.46,99.44) v1(92.42,68.7) v1(92.42,67.18) v1(92.76,100.87) v1(92.8,28.14) v1(92.8,27.56) v1(93.25,99.35) v1(93.93,130.73) v1(93.93,128.84) v1(94.25,60.7) v1(94.25,59.17) v1(94.53,97.8) v1(94.57,100.64) v1(94.87,69.08) v1(94.87,66.79) v1(95.22,8.98) v1(95.76,130.79) v1(95.76,128.84) v1(95.91,99.18) v1(95.85,29.41) v1(96.25,60.7) v1(96.25,59.17) v1(96.23,16.86) v1(96.23,14.32) v1(96.23,11.78) v1(96.36,124.08) v1(96.51,68.7) v1(96.51,67.18) v1(96.61,29.41) v1(97.29,100.56) v1(97.37,29.41) v1(98.52,136.41) v1(98.58,132.85) v1(99.03,60.7) v1(99.03,59.17) v1(99.34,130.79) v1(99.34,128.84) v1(99.41,68.7) v1(99.41,67.18) v1(99.53,136.41) v1(99.66,132.85) v1(99.72,94.79) v1(100.23,95.06) v1(100.23,28.65) v1(100.23,28.06) v1(100.55,8.98) v1(100.58,58.79) v1(100.86,130.73) v1(100.86,128.82) v1(101.31,68.7) v1(101.31,67.18) v1(101.31,16.86) v1(101.31,14.32) v1(101.31,11.78) v1(101.82,138.63) v1(101.82,136.41) v1(101.95,132.85) v1(101.98,60.7) v1(101.98,59.17) v1(102.57,30.11) v1(102.71,128.83) v1(102.9,138.63) v1(102.9,136.41) v1(103.03,132.85) v1(103.15,95.04) v1(103.15,94.44) v1(103.22,65.48) v1(103.22,64.84) v1(103.15,30.11) v1(103.55,102.61) v1(103.98,74.18) v1(104.74,95.01) v1(104.74,94.4) v1(105.12,138.63) v1(105.12,136.41) v1(105.11,102.6) v1(105.25,132.85) v1(105.44,127.39) v1(105.69,14.43) v1(106.2,136.41) v1(106.33,132.85) v1(106.33,10.62) v1(106.79,100.49) v1(108.49,136.41) v1(108.46,101.42) v1(108.99,17.09) v1(109.57,138.57) v1(109.57,136.41) v1(109.57,132.79) v1(109.86,98.94) v1(110.39,9.73) v1(111.41,127.59) v1(111.43,125.69) v1(111.85,138.57) v1(111.85,136.41) v1(111.92,132.79) v1(111.96,99.67) v1(111.96,98.37) v1(111.96,95.75) v1(112.55,128.41) v1(112.55,126.59) v1(112.68,15.7) v1(112.93,138.57) v1(112.93,136.41) v1(112.93,12.01) v1(113.58,99.02) v1(113.58,96.42) v1(115.67,99.67) v1(115.67,97.72) v1(116.07,95.33) v1(116.28,129.52) v1(116.26,127.54) v1(116.46,124.08) v1(116.51,8.98) v1(117.57,99.99) v1(117.57,98.31) v1(119.17,127.59) v1(119.17,99.02) v1(120.74,159.29) v1(120.74,153.52) v1(120.74,68.72) v1(120.74,67.2) v1(121.05,99.09) v1(121.05,97.03) v1(121.75,128.82) v1(121.82,60.74) v1(121.82,59.21) v1(121.83,8.98) v1(122.77,68.72) v1(122.77,67.2) v1(123.41,61.12) v1(123.41,58.83) v1(123.54,134.77) v1(123.54,134.19) v1(123.47,132.85) v1(124.04,132.85) v1(124.99,100.79) v1(125.12,60.74) v1(125.12,59.21) v1(125.31,68.72) v1(125.31,67.2) v1(126,189.6) v1(126,183.84) v1(126,178.08) v1(126,172.32) v1(126,166.56) v1(126,160.8) v1(126.95,129.35) v1(127.24,134.88) v1(127.22,134.25) v1(127.15,8.98) v1(127.66,60.74) v1(127.66,59.21) v1(127.98,69.1) v1(127.98,66.82) v1(129.1,101.18) v1(129.38,68.72) v1(129.38,67.2) v1(130.06,175.91) v1(130.2,60.74) v1(130.2,59.21) v1(132.07,68.8) v1(132.07,67.28) v1(132.47,8.98) v1(132.74,60.74) v1(132.74,59.21) v1(133.6,69.18) v1(133.6,66.9) v1(133.8,189.6) v1(135.03,60.74) v1(135.03,59.21) v1(135.1,109.46) v1(135.22,190.6) v1(135.73,68.8) v1(135.73,67.28) v1(136.5,94.95) v1(136.79,114.97) v1(137.14,94.95) v1(137.32,60.74) v1(137.32,59.21) v1(137.79,8.98) v1(138.3,68.72) v1(138.3,67.2) v1(138.7,61.12) v1(138.7,58.83) v1(140.81,68.72) v1(140.81,67.2) v1(140.81,60.74) v1(140.81,59.21) v1(141.38,190.6) v1(143.12,8.98) v1(143.35,30.49) v1(143.35,29.86) v1(144.49,164.48) v1(144.55,165.49) v1(146.33,151.33) v1(146.4,149.74) v1(147.55,190.6) v1(148.44,8.98) v1(153.31,120.03) v1(153.72,190.6) v1(153.76,8.98) v1(154.65,79.89) v1(154.78,132.28) v1(154.78,131.65) v1(155.01,119.77) v1(155.06,79.48) v1(155.41,132.92) v1(155.41,132.28) v1(155.41,131.65) v1(155.54,79.07) v1(155.86,157.3) v1(155.86,156.67) v1(155.95,78.65) v1(156.3,107.76) v1(156.42,118.21) v1(156.49,157.94) v1(156.49,157.3) v1(156.76,119.77) v1(158.18,118.21) v1(158.7,79.88) v1(159.08,8.98) v1(159.17,79.4) v1(159.59,78.99) v1(159.88,190.6) v1(160.03,78.54) v1(161.24,68.99) v1(161.24,67.47) v1(161.24,65.94) v1(162.89,156.04) v1(163.03,69.37) v1(163.03,67.09) v1(163.47,156.04) v1(163.7,157.3) v1(163.7,156.72) v1(164.29,157.3) v1(164.29,156.72) v1(164.4,8.98) v1(165.47,68.99) v1(165.47,67.47) v1(165.47,65.94) v1(165.9,0.5) v1(167.03,2.49) v1(167.1,172.54) v1(167.17,7.03) v1(167.41,172.03) v1(167.35,170) v1(167.35,168.86) v1(167.76,68.99) v1(167.76,67.47) v1(167.76,65.94) v1(167.92,169.43) v1(167.96,155.91) v1(168.54,155.91) v1(168.46,32.76) v1(168.56,170) v1(168.56,168.92) v1(169.07,67.85) v1(169.07,65.56) v1(169.53,139.53) v1(170.12,139.53) v1(170.34,68.99) v1(170.34,67.47) v1(170.34,65.94) v1(170.7,139.53) v1(171.24,0.5) v1(171.35,2.49) v1(171.45,155.91) v1(171.49,7.03) v1(171.76,189.6) v1(172.03,155.91) v1(172.63,68.99) v1(172.63,67.47) v1(172.63,65.94) v1(173.13,38.87) v1(173.64,37.39) v1(173.89,69.38) v1(173.9,67.09) v1(174.22,51.14) v1(175.61,31.32) v1(176.15,155.78) v1(176.11,40.21) v1(176.24,31.32) v1(176.34,68.99) v1(176.34,67.47) v1(176.34,65.94) v1(176.37,24.14) v1(176.37,22.74) v1(176.43,2.49) v1(176.57,7.03) v1(176.57,0.5) v1(176.73,155.78) v1(176.88,31.32) v1(176.98,189.6) v1(177.07,23.44) v1(177.25,95.69) v1(177.51,31.32) v1(177.7,22.74) v1(177.77,24.14) v1(178.62,68.99) v1(178.62,67.47) v1(178.62,65.94) v1(179.9,155.91) v1(179.93,67.85) v1(179.93,65.56) v1(179.99,95.57) v1(180.11,74.13) v1(180.11,73.54) v1(180.51,155.91) v1(181.12,155.91) v1(181.2,68.99) v1(181.2,67.47) v1(181.2,65.94) v1(181.51,2.49) v1(181.65,7.03) v1(181.9,0.5) v1(182.21,189.6) v1(185.07,76.91) v1(185.39,43.83) v1(185.77,41.79) v1(186.34,60.63) v1(186.3,58.84) v1(186.4,172.98) v1(186.4,172.29) v1(186.4,171.59) v1(186.59,2.49) v1(186.73,7.03) v1(187.04,43.06) v1(187.16,40.65) v1(187.23,0.5) v1(187.44,189.6) v1(188.22,139.27) v1(188.72,139.58) v1(188.87,186.26) v1(188.87,176.16) v1(189.45,186.26) v1(189.45,176.16) v1(190.52,176.16) v1(190.58,186.26) v1(191.1,176.16) v1(191.16,186.26) v1(191.67,2.49) v1(191.81,7.03) v1(192.5,61.1) v1(192.5,60.4) v1(192.57,0.5) v1(192.67,189.6) v1(193.25,70.88) v1(193.69,80.15) v1(193.83,70.88) v1(194.07,79.45) v1(194.12,64.4) v1(194.28,91.81) v1(194.52,80.15) v1(194.66,64.02) v1(194.86,91.81) v1(194.9,79.45) v1(195.22,70.88) v1(195.34,80.15) v1(195.35,64.4) v1(195.35,63.51) v1(195.72,79.45) v1(195.8,70.88) v1(196.17,80.15) v1(196.31,91.81) v1(196.55,79.45) v1(196.75,3.76) v1(196.75,2.49) v1(196.89,91.81) v1(196.89,7.03) v1(196.99,80.15) v1(196.99,70.88) v1(197.37,79.45) v1(197.58,70.88) v1(197.82,80.15) v1(197.9,189.6) v1(197.9,182.1) v1(197.91,91.81) v1(197.9,0.5) v1(198.2,79.45) v1(198.59,70.88) v1(198.82,80.2) v1(199.06,79.58) v1(199.05,78.5) v1(200.3,81.07) v1(200.32,33.78) v1(200.49,32.68) v1(201.2,81.1) v1(201.83,3.76) v1(201.83,2.49) v1(202.09,81.1) v1(202.9,168.81) v1(202.94,55.51) v1(202.97,81.1) v1(203.2,179.1) v1(203.23,0.5) v1(203.99,81.1) v1(204.35,170.56) v1(204.37,80.21) v1(204.88,58.05) v1(204.88,56.72) v1(205.39,57.41) v1(205.5,171.24) v1(205.49,168.81) v1(205.68,80.34) v1(205.96,58.05) v1(205.96,56.72) v1(206.31,81.23) v1(206.85,44.27) v1(206.91,3.76) v1(206.91,2.49) v1(207.08,80.34) v1(207.58,81.23) v1(208.22,80.34) v1(208.57,0.5) v1(208.7,179.1) v1(208.73,81.23) v1(209.24,80.34) v1(209.58,93.67) v1(209.87,81.23) v1(211.99,3.76) v1(211.99,2.49) v1(213.39,171.91) v1(213.9,0.5) v1(214.2,179.1) v1(216.06,91.9) v1(216.06,91.31) v1(217.07,3.76) v1(217.07,2.49) v1(217.45,169.6) v1(218,169.27) v1(219.23,0.5) v1(219.29,91.26) v1(219.7,179.1) v1(219.93,170.74) v1(220.35,110.12) v1(220.35,109.48) v1(220.37,108.47) v1(220.37,107.83) v1(220.37,107.07) v1(220.44,96.42) v1(220.44,95.83) v1(220.5,98.75) v1(220.72,125.86) v1(220.72,125.25) v1(221.14,5.79) v1(221.52,41.98) v1(222.28,1.98) v1(224.95,8.46) v1(225.2,179.1) v1(226.34,1.09) v1(226.47,32.71) v1(226.47,27.63) v1(226.47,22.55) v1(226.47,17.47) v1(226.47,12.39) v1(227.74,32.71) v1(227.74,27.63) v1(227.74,22.55) v1(227.74,17.47) v1(227.74,12.39) v1(228.76,7.06) v1(228.88,3.38) v1(229.9,180.6) v1(229.9,175.45) v1(229.9,165.16) v1(229.9,160.02) v1(229.9,154.87) v1(229.9,149.72) v1(229.9,144.58) v1(229.9,139.43) v1(229.9,134.29) v1(229.9,129.14) v1(229.9,124) v1(229.9,113.7) v1(229.9,108.56) v1(229.9,103.41) v1(229.9,98.27) v1(229.9,87.98) v1(229.9,77.69) v1(229.9,72.54) v1(229.9,67.4) v1(229.9,62.25) v1(229.9,57.1) v1(229.9,51.96) v1(229.9,46.81) v1(229.9,41.67) v1(229.86,36.03) v1(229.9,31.38) v1(229.9,26.23) v1(229.9,21.09) v1(229.9,15.94) v1(229.9,10.79) v1(229.9,0.5) v3(108.96,25.43) v3(109.8,25.32) v3(110.5,25.32) v3(110.82,28.68) v3(111.45,28.68) v3(111.52,25.32) v3(112.28,25.32) v3(112.36,28.71) v3(112.93,144.41) v3(112.93,143.77) v3(112.94,142.76) v3(112.94,142) v3(112.94,141.23) v3(112.94,140.47) v3(112.94,139.71) v3(113,28.71) v3(113.57,144.41) v3(113.57,143.77) v3(113.64,142.76) v3(113.64,142) v3(113.64,141.23) v3(113.64,140.47) v3(113.64,139.71) v3(114.34,142.76) v3(114.34,142) v3(114.34,141.23) v3(114.34,140.47) v3(114.34,139.71) v3(116.74,144.09) v3(117.38,144.09) v3(118.01,144.09) v3(118.65,144.09) v3(121.14,17.95) v3(121.06,17.09) v3(121.63,16.65) v3(121.76,17.47) v3(122.33,16.9) v3(124.43,21.85) v3(124.43,21.22) v3(125.06,21.85) v3(125.06,21.22) v3(125.82,24) v3(125.82,23.37) v3(125.82,22.73) v3(125.82,22.1) v3(125.82,21.46) v3(126.46,24) v3(126.46,23.37) v3(126.46,22.73) v3(126.46,22.1) v3(126.46,21.46) v3(127.09,24) v3(127.09,23.37) v3(127.09,22.73) v3(127.09,22.1) v3(127.09,21.46) v3(127.41,15.71) v3(127.79,22.81) v3(127.79,22.17) v3(127.79,21.54) v3(128.24,164.92) v3(128.24,164.29) v3(128.25,24.55) v3(128.25,16.55) v3(128.25,15.71) v3(128.43,22.81) v3(128.43,22.17) v3(128.43,21.54) v3(128.87,164.92) v3(128.87,164.29) v3(128.91,24.55) v3(129.51,164.92) v3(129.51,164.29) v3(130.14,164.92) v3(130.14,164.29) v3(130.64,20.36) v3(130.78,164.92) v3(130.78,164.29) v3(130.97,139.01) v3(130.97,138.38) v3(130.97,137.74) v3(131.3,20.36) v3(131.6,139.01) v3(131.6,138.38) v3(131.6,137.74) v3(131.96,20.36) v3(133.43,16.99) v3(133.38,16.33) v3(134.84,139.19) v3(134.84,138.55) v3(134.84,137.92) v3(135.47,139.19) v3(135.47,138.55) v3(135.47,137.92) v3(137.7,189.49) v3(137.7,188.86) v3(137.7,188.22) v3(137.7,187.59) v3(137.7,186.95) v3(138.33,189.49) v3(138.33,188.86) v3(138.33,188.22) v3(138.33,187.59) v3(138.33,186.95) v3(138.97,187.27) v3(139.04,152.59) v3(139.29,154.24) v3(139.6,187.27) v3(139.67,152.59) v3(139.93,154.24) v3(140.31,152.59) v3(140.31,151.96) v3(140.31,151.32) v3(140.56,154.24) v3(140.62,144.92) v3(140.94,152.59) v3(140.94,151.96) v3(140.94,151.32) v3(141.2,154.24) v3(141.25,145.55) v3(141.25,144.92) v3(141.58,152.59) v3(141.58,151.96) v3(141.83,154.24) v3(141.89,145.55) v3(141.89,144.92) v3(142.21,152.59) v3(142.53,158.88) v3(143.42,158.88) v3(146.46,145.55) v3(146.46,144.92) v3(147.09,145.55) v3(147.09,144.92) v3(148.49,174.7) v3(148.49,174.06) v3(149.13,183.21) v3(149.13,182.57) v3(149.13,181.68) v3(149.13,181.05) v3(149.13,180.03) v3(149.13,179.4) v3(149.19,174.7) v3(149.19,174.06) v3(150.53,21.23) v3(150.53,20.6) v3(150.53,19.96) v3(151.17,21.23) v3(151.17,20.6) v3(151.17,19.96) v3(151.8,21.23) v3(151.8,20.6) v3(154.47,26.25) v3(155.1,26.25) v3(157.77,28.92) v3(157.77,28.28) v3(158.09,25.3) v3(158.09,24.53) v3(158.09,22.44) v3(158.09,21.8) v3(158.79,13.61) v3(158.79,12.98) v3(158.79,12.34) v3(158.91,25.3) v3(158.91,24.47) v3(159.42,13.61) v3(159.42,12.98) v3(159.42,12.34) v3(160.05,167.27) v3(160.06,13.61) v3(160.06,12.98) v3(160.06,12.34) v3(160.21,166.56) v3(160.2,165.66) v3(160.18,19.2) v3(160.75,174.25) v3(160.75,173.11) v3(160.75,172.1) v3(160.75,171.08) v3(160.68,167.27) v3(160.69,13.61) v3(160.69,12.98) v3(160.69,12.34) v3(160.85,166.56) v3(160.84,165.66) v3(160.88,19.2) v3(161,176.41) v3(161,162.7) v3(161,162.06) v3(161.32,167.27) v3(161.33,13.61) v3(161.33,12.98) v3(161.33,12.34) v3(161.38,174.25) v3(161.38,173.11) v3(161.38,172.1) v3(161.38,171.08) v3(161.48,166.56) v3(161.47,165.66) v3(161.64,176.41) v3(161.64,162.7) v3(161.64,162.06) v3(162.02,174.25) v3(162.02,173.11) v3(162.02,172.1) v3(161.95,166.13) v3(161.95,165.24) v3(161.96,13.61) v3(161.96,12.98) v3(161.96,12.34) v3(162.27,162.7) v3(162.27,162.06) v3(162.72,166.13) v3(162.72,165.24) v3(162.65,13.28) v3(162.65,12.58) v3(178.72,179.4) v3(178.72,178.76) v3(178.72,178.13) v3(178.72,177.49) v3(178.72,176.86) v3(180.31,178.7) v3(180.31,178.06) v3(180.31,177.43) v3(180.31,176.79) v3(180.37,179.33) v3(181,179.54) v3(181,178.9) v3(181,178.27) v3(181.45,174.51) v3(181.45,173.87) v3(181.45,173.24) v3(181.45,172.6) v3(181.45,171.97) v3(181.68,179.54) v3(181.68,178.9) v3(181.68,178.27) v3(182.08,174.51) v3(182.08,173.87) v3(182.08,173.24) v3(182.08,172.6) v3(182.08,171.97) v3(182.72,174.51) v3(182.72,173.87) v3(182.72,173.24) v3(182.72,172.6) v3(187.29,168.98) v3(187.29,168.35) v3(187.93,168.98) v3(187.93,168.35) v3(188.56,168.98) v3(188.56,168.35) v3(189.2,168.98) v3(189.2,168.35) v3(215.29,69.86) v3(215.29,68.84) v3(215.29,66.5) v3(215.29,65.73) v3(215.29,64.97) v3(215.29,64.21) v3(215.29,63.45) v3(215.29,62.75) v3(215.36,72.34) v3(215.36,71.58) v3(215.36,70.81) v3(215.55,74.5) v3(215.55,73.86) v3(215.55,73.1) v3(216.12,72.34) v3(216.12,71.58) v3(216.12,70.81) v3(216.12,69.86) v3(216.06,68.84) v3(216.06,68.02) v3(216.06,67.26) v3(216.06,66.5) v3(216.06,65.73) v3(216.06,64.97) v3(216.06,64.21) v3(216.06,63.45) v3(216.06,62.75) v3(216.06,62.05) v3(216.06,61.42) v3(216.25,74.24) v3(216.25,73.48) v3(216.82,68.84) v3(216.82,68.02) v3(216.82,67.26) v3(216.82,66.5) v3(216.82,65.73) v3(216.82,64.97) v3(216.82,64.21) v3(216.82,63.45) v3(216.88,74.56) v3(216.88,73.86) v3(216.88,73.1) v3(216.88,72.34) v3(216.88,71.58) v3(216.88,70.81) v3(216.88,69.86) v3(217.53,73.1) v3(217.53,72.34) v3(217.53,71.58) v3(217.53,70.81) v3(217.53,69.86) v3(217.53,68.84) v3(217.53,68.02) v3(217.53,67.26) v3(217.53,66.5) v3(217.53,65.73) v3(217.53,64.97) v3(217.53,64.21) v3(217.53,63.45) v4(29.79,20.59) v4(63.77,77.42) v4(91.33,137.43) v4(106.5,93.43) v4(110.88,26.5) v4(114,94.44) v4(115.52,141.23) v4(143.52,154.83) v4(144.48,145.62) v4(149.3,176.36) v4(154.47,134.03) v4(159.72,174.26) v4(160.22,161.94) v4(164.22,12.65) v4(166.22,157.19) v4(170.22,156.8) v4(173.61,157.14) v4(180.1,75.01) v4(182.13,175.28) v4(183.28,173.66) v4(183.29,156.51) v4(185.89,182.78) v4(188.42,179.4) v4(201.41,80.22) v4(214.53,65.06) v4(217.63,73.99) v4(217.56,61.42) v4(219.18,111.57) v4(219.33,125.65) v4(219.35,123.1) v4(221.45,108.74)
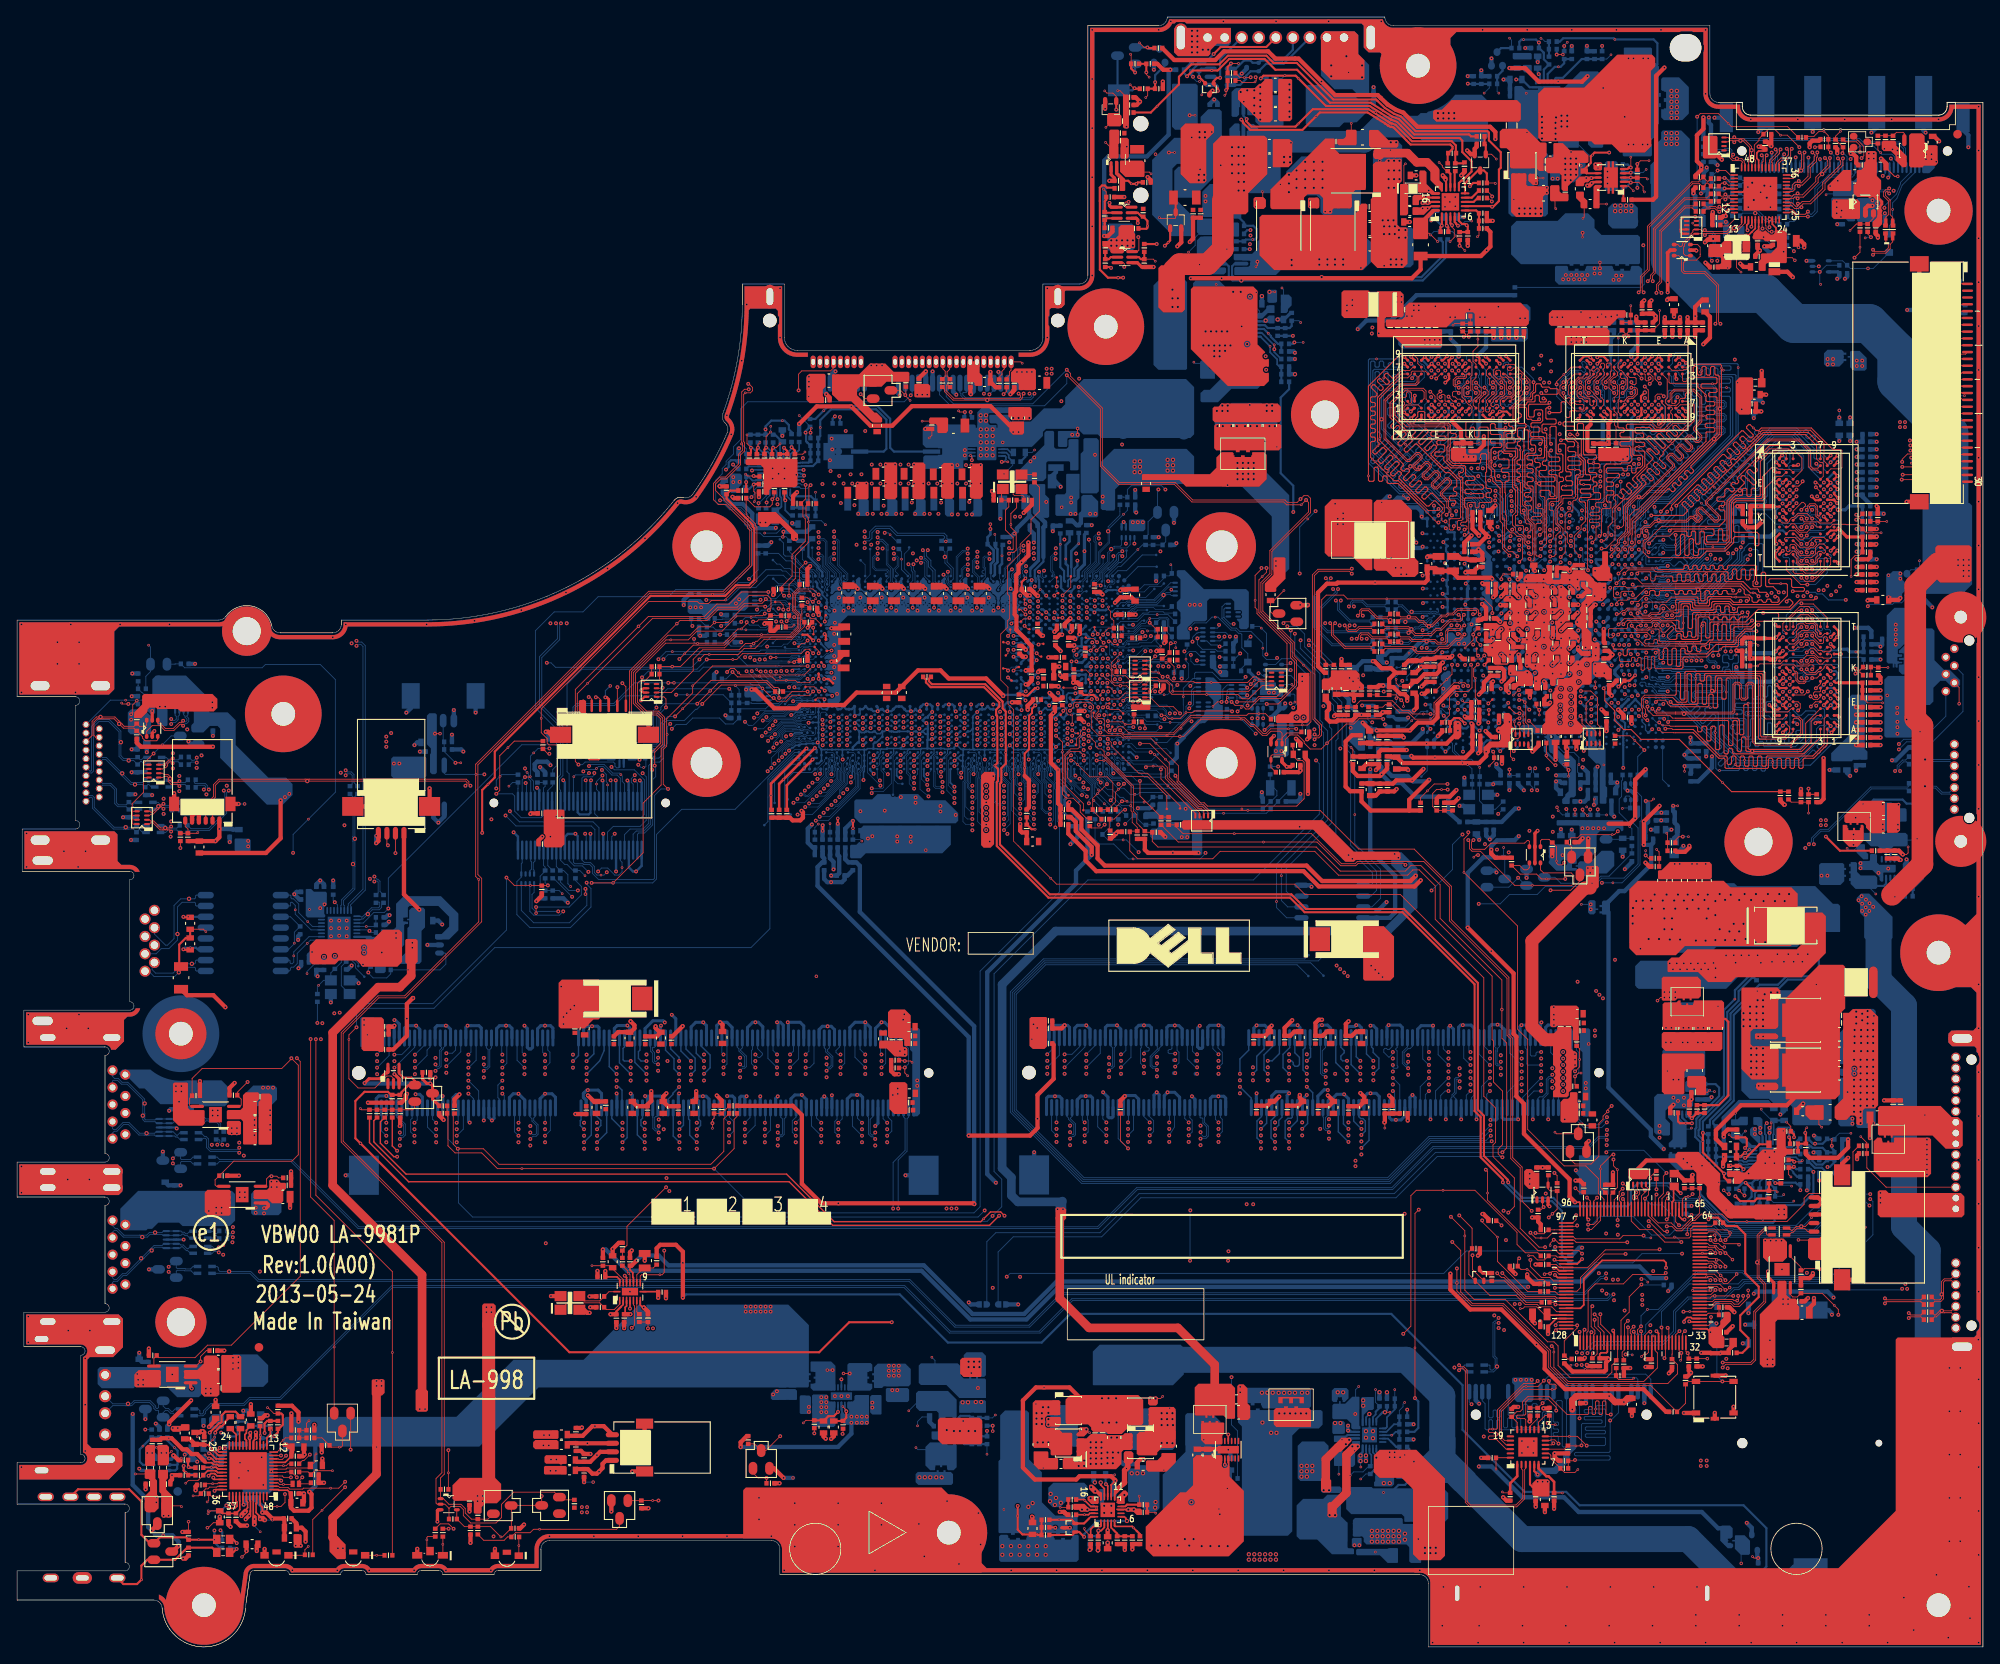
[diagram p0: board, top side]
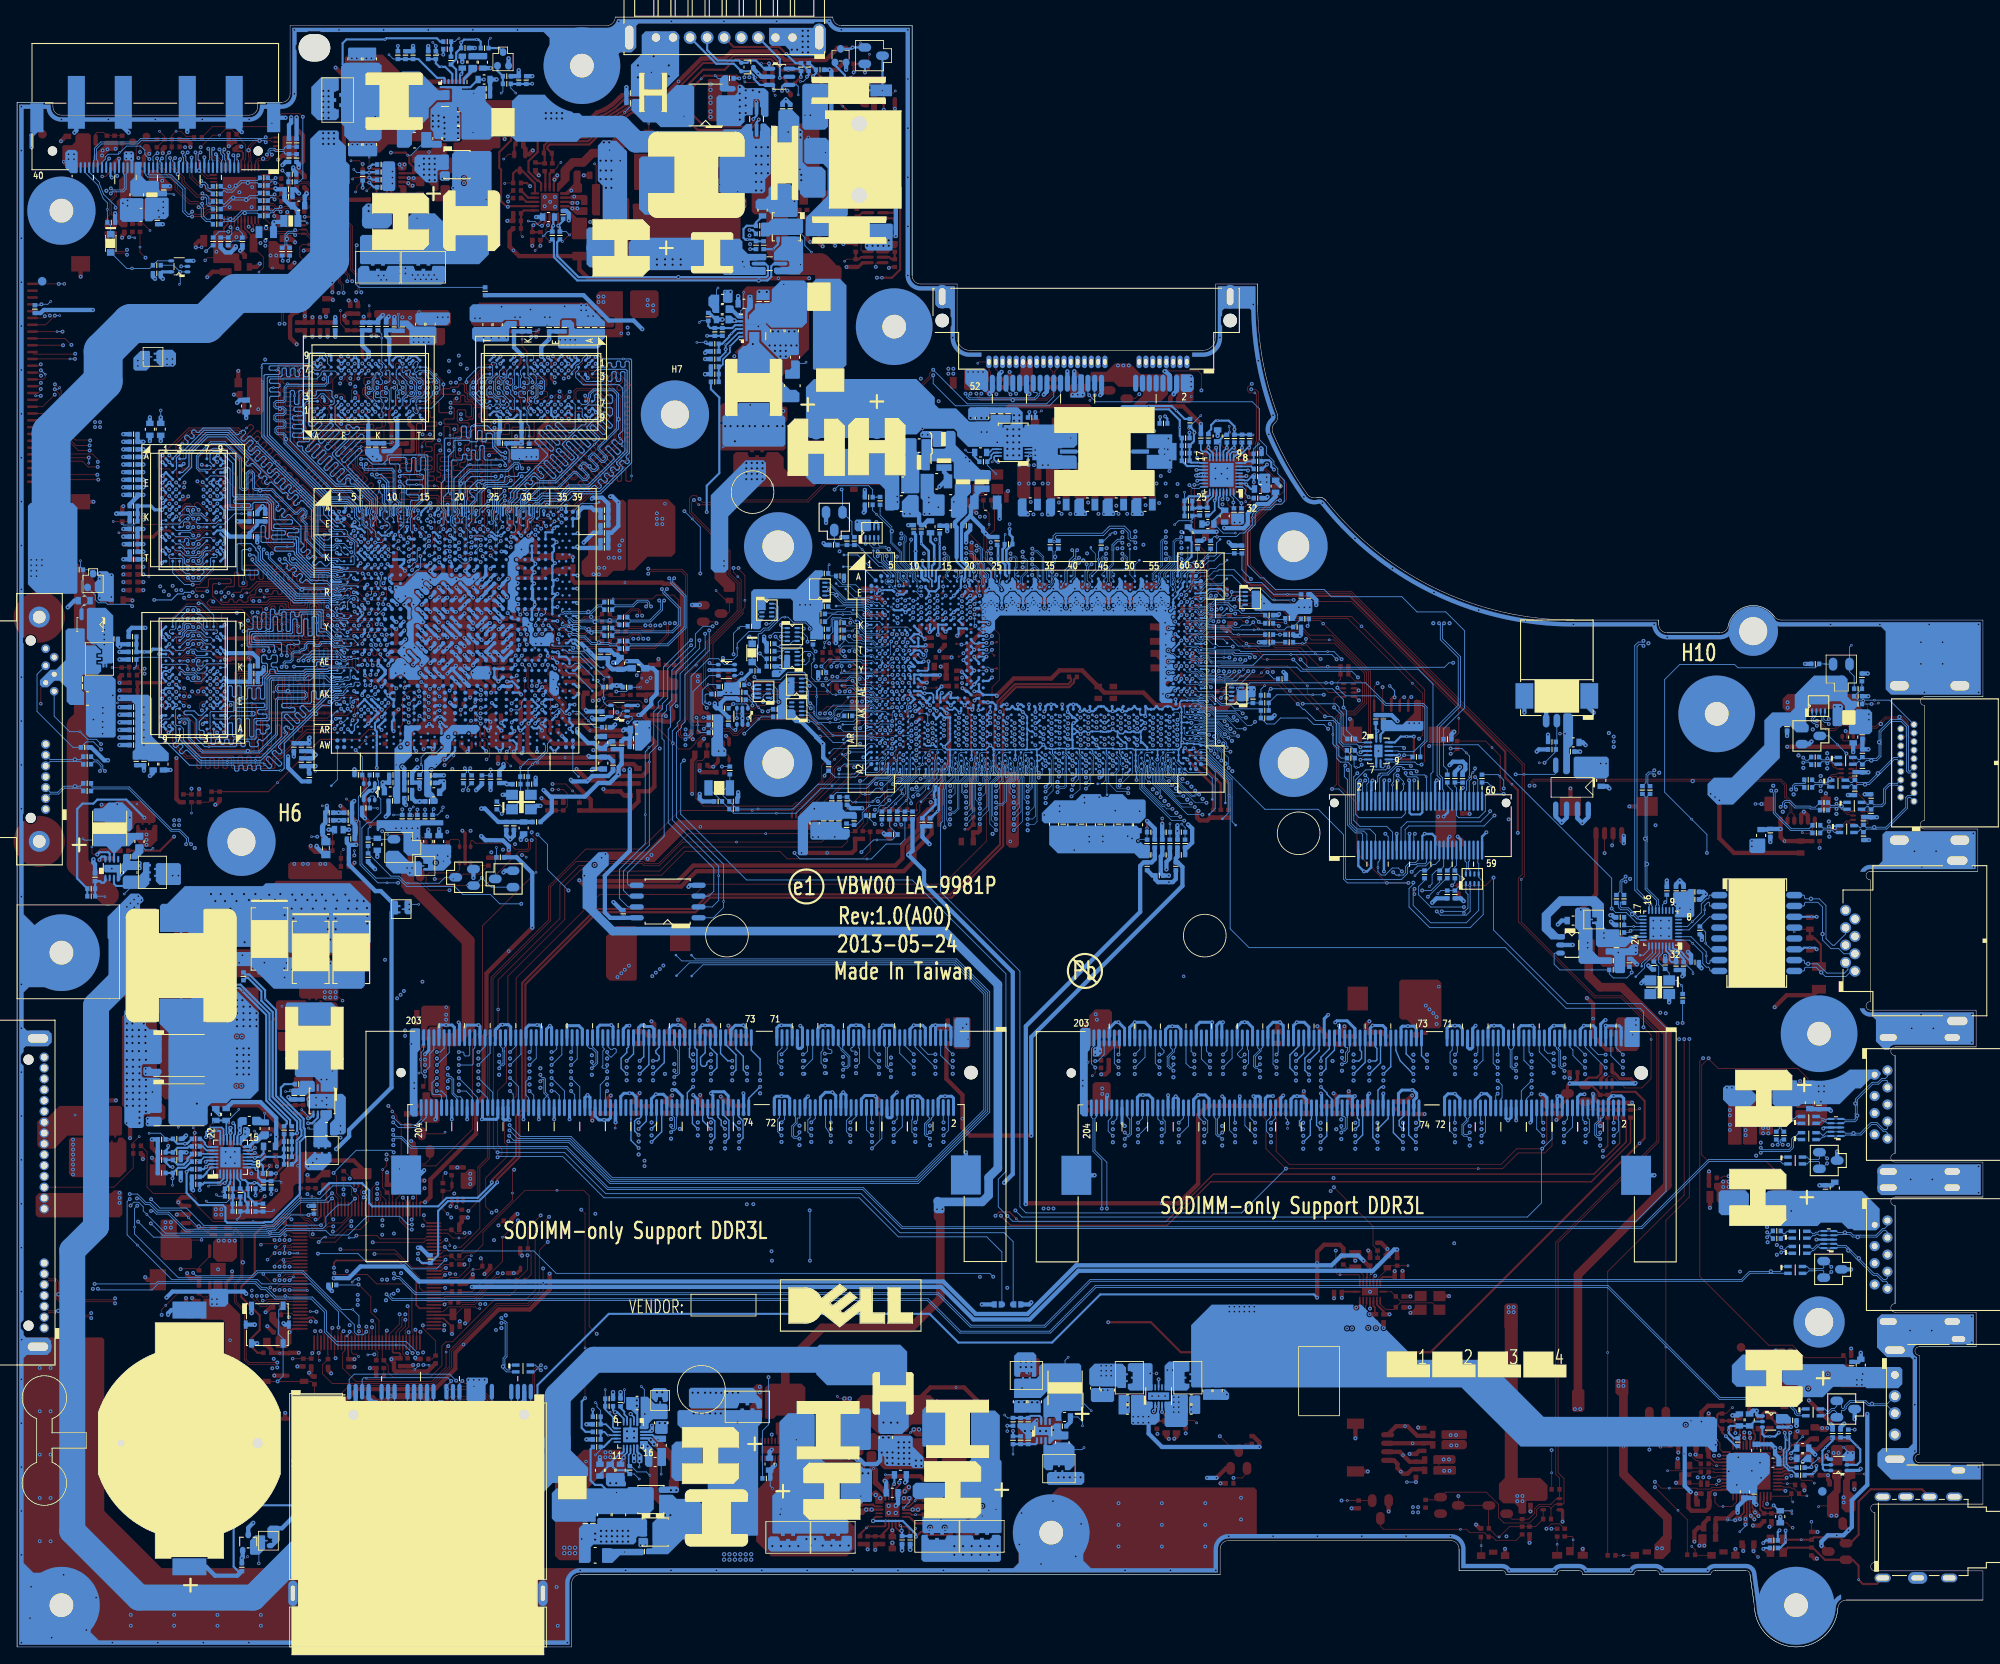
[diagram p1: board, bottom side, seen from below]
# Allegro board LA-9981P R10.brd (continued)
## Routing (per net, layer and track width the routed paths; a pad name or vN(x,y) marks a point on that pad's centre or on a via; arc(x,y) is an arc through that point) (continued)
GNDA: length 62.4
  TOP w0.102: v4(20.09,14.68) CA33.2 ; v1(26.89,11.24) 26.89,11.09 v4(26.36,10.55) ; v4(22.3,13.98) 22.42,13.98 23,14.56 CA61.2
  TOP w0.203: v1(25.3,16.77) 25.28,16.8 UA1.38 ; UA1.25 23.67,22.85 23.52,23 23.52,23.1 v1(23.75,23.33)
  TOP w0.508: v1(26.89,11.24) 26.89,12 RA32.1 ; v1(22.49,25.8) 23.27,26.58 RA31.1 ; CA39.2 19.73,10.36 v1(19.46,10.36) ; RA83.2 v1(18.16,20.14) 18.16,19.63 17.96,19.44 CA40.2 ; CA71.2 21.43,25.16 21.56,25.29 v1(21.73,25.29) 21.79,25.29 21.94,25.15 CA51.2 ; v1(15.07,18.49) CA38.2 ; CA33.2 v1(19.38,13.49) ; v1(29.35,27.15) 29.06,27.15 28.73,26.82 RA153.1 ; RA84.2 18.89,21.92 18.35,22.45 v1(18.32,22.45) ; CA61.2 v1(23.75,15.26)
  GND1 w0.203: JHP.7 8.96,8.09 ; JHP.7 6.34,7.23 ; JHP.7 8.96,7.23 ; JHP.7 6.34,8.09 ; JHP.7 7.65,7.23 ; JHP.6 10.14,18.29 ; JHP.6 10.14,17.6 ; JHP.6 7.88,17.6 ; JHP.6 7.88,18.29 ; JHP.6 9.01,18.29
  VCC w0.203: 7.65,7.23 JHP.7 ; JHP.7 6.34,7.23 ; JHP.7 8.96,7.23 ; JHP.6 9.01,18.29 ; JHP.6 10.14,18.29 ; JHP.6 7.88,18.29
  GND2 w0.203: 7.88,17.6 JHP.6 ; JHP.6 9.01,18.29 ; JHP.6 7.88,18.29 ; JHP.6 10.14,18.29 ; JHP.6 10.14,17.6 ; 6.34,7.23 JHP.7 ; JHP.7 8.96,7.23 ; JHP.7 8.96,8.09 ; JHP.7 7.65,7.23 ; JHP.7 6.34,8.09
  BOTTOM w0.381: v1(18.32,22.45) 18.32,22.24 18.08,22 QA6.4 ; QA5.1 26.38,27.08 26.51,27.2 v1(26.51,27.7) ; v1(22.49,25.8) 22.51,25.78 QA5.4 ; v1(14.32,20.9) 14.52,20.7 QA6.1
  BOTTOM w0.508: CA61.2 v1(23.75,15.26) ; CA23.1 20.73,22.11 v1(21.11,21.73) ; CA2.2 26.95,27.7 v1(26.51,27.7) ; RA29.1 23.9,22.17 24.36,22.63 v1(24.36,23.31) 24.82,23.76 RA30.1 ; v1(19.65,22.55) CA62.1 ; v1(29.35,27.15) 28.71,27.15 CA1.2
V5A_CPU: length 7.8
  BOTTOM w0.102: v2(87.62,130.6) 89.04,130.6 90.1,131.66 PC505.1
  BOTTOM w0.203: PR519.2 89.07,133.49 89.37,133.49 89.58,133.69 89.58,134.76 89.42,134.92 PU501.28
  BOTTOM w0.254: PR519.2 90.14,132.09 PC505.1
V18: length 3
  TOP w0.102: UR1.24 173.35,22.19 CR4.2 v2(173.33,20.85)
VBAT_CPU: length 2.5
  BOTTOM w0.203: PU501.16 90.62,139.81 90.96,140.16 91.47,140.16 91.66,140.35 PR508.2
VCC: length 2.4
  TOP w0.102: PR705.2 165.51,165.75 v2(166.48,164.77)
VCCSENSE: length 17.5
  TOP w0.102: v1(93,136.22) 92.8,136.02 92.8,134.14 R1.2 92.46,133.79 92.46,132.68 92.74,132.4 v2(92.74,131.88) 92.74,129.49 91.21,127.96 91.21,125.3 90.48,124.56 v1(90.48,123.26)
  BOTTOM w0.102: v1(93,136.22) 92.62,135.84 91.84,135.84 91.67,136.02 PU501.24 ; UC1.E63 91.49,123.08 90.65,123.08 v1(90.48,123.26)
VCCSENSE_VGA: length 80.8
  TOP w0.102: v1(202.45,52.93) 202.4,52.93 v4(201.82,53.52)
  TOP w0.254: v1(171.98,115.15) 172.49,115.66 RV202.2
  IN3 w0.102: 178.76,103.92 178.49,104.19 178.49,106.61 177.83,107.26 177.83,111.61 176.09,113.36 176.09,113.7 174.88,114.9 172.23,114.9 v1(171.98,115.15)
  IN3 w0.127: 178.76,103.92 178.92,103.76 178.92,102.17 181.13,99.96 181.13,96.91 181.7,96.34 181.7,93.93 183.68,91.95 183.68,83.16 189.11,77.73 189.11,65.95 197.33,57.72 197.33,55.81 199.52,53.63 201.43,53.63 202.12,52.93 v1(202.45,52.93)
  BOTTOM w0.254: v1(202.45,52.93) 202.45,53.73 PR846.2 ; UV1.AF28 172.44,114.69 v1(171.98,115.15)
VCCST_PG_EC: length 229.5
  TOP w0.089: 86.76,118.68 90.57,118.68 91.45,119.56 91.45,120.91 90.87,121.49 90.87,123.49 91.71,124.33 C79.1 91.71,126.43 v1(92.42,127.14)
  TOP w0.102: UE1.123 180.44,39.31 179.87,39.88 178.42,39.88 178.16,40.14 176.76,40.14 175.7,41.21 172.61,41.21 DE1.2 170.16,43.67 170.16,46.34 CE35.1 170.53,49.1 v1(169.03,50.6) ; 86.76,118.68 84.13,118.68 82.91,117.46 79.25,117.46 v2(78.24,116.45) v1(77.63,115.83)
  IN3 w0.127: v1(169.03,50.6) 168.78,50.85 163.76,50.85 163.38,51.23 139.99,51.23 139.49,51.74 117.19,51.74 116.56,52.37 109.3,52.37 107.64,50.71 73.72,50.71 68.56,55.87 68.56,72.82 63.96,77.42 63.96,85.05 62.75,86.25 62.75,91.83 63.37,92.46 63.37,96.08 64.35,97.05 64.35,97.99 62.94,99.4 62.94,110.06 69.43,116.55 76.91,116.55 v1(77.63,115.83)
  BOTTOM w0.076: 93.79,126.19 94.05,125.94 94.05,125.42 94.38,125.09 UC1.B59
  BOTTOM w0.089: R286.2 92.04,127.52 v1(92.42,127.14) 93.08,127.14 93.67,126.54 93.67,126.31 93.79,126.19
VDD_1.35V: length 8.7
  BOTTOM w0.102: PR205.1 158.07,20.28 v2(157.48,19.69)
  BOTTOM w0.203: PC209.1 160.88,21.55 159.74,22.69 159.48,22.69 159.31,22.87 PU200.11
  BOTTOM w0.254: PR206.2 162.09,20.22 PC209.1 160.18,20.72 159.04,20.72 PR205.1
VDDCI_SEN: length 114.6
  TOP w0.102: RV215.2 178.19,107.59 v1(177.19,108.6) ; v1(180.45,186.7) v4(181.17,186.7)
  IN1 w0.102: 164.34,121.61 166.78,121.61 168.05,120.34 169.76,120.34 170.07,120.04 170.07,116.8 170.79,116.08 170.79,114.93 v1(171.83,113.89)
  IN1 w0.127: 164.34,121.61 162.37,121.61 158.69,125.3 156.3,125.3 155.98,125.61 155.98,126.88 157.42,128.32 157.42,132.98 160.79,136.35 160.79,152.75 v1(158.84,154.7)
  IN3 w0.102: v1(177.19,108.6) 177.19,109.04 176.81,109.42 176.81,112.34 175.68,113.48 174.72,113.48 174.31,113.89 v1(171.83,113.89)
  IN3 w0.254: v1(180.45,186.7) 180.45,186.69 180.45,183.9 174.97,178.42 174.97,174.15 171.82,171 171.82,162.63 171.32,162.13 167.99,162.13 166.02,160.16 160.87,160.16 158.37,157.65 158.37,156.44 158.84,155.97 v1(158.84,154.7)
  BOTTOM w0.102: UV1.AG28 172.04,113.69 v1(171.83,113.89)
  BOTTOM w0.254: PR1210.2 v1(180.45,186.7)
VIN: length 49.6
  TOP w0.508: v1(137.57,160.48) v4(141.17,160.48) 163.46,160.48 164.49,161.5 PR705.1 171.56,163.08 v4(172.23,163.75) 172.67,164.19 172.67,165.9 PR723.2
  IN1 w0.508: v1(139.28,169.49) 139.28,162.19 v1(137.57,160.48)
  vias: v1(139.28,170.13) v4(133.43,175.02)
VSSSENSE: length 18.8
  TOP w0.089: RC163.1 89.58,123.57 v1(89.89,123.26)
  TOP w0.102: RC163.1 89.58,124.29 90.83,125.55 v2(90.83,127.72) 90.83,128.09 92.38,129.64 92.38,132.26 92.1,132.54 92.1,133.82 R2.1 92.42,134.61 v1(92.42,136.25)
  BOTTOM w0.102: v1(89.89,123.26) 90.27,122.87 90.61,122.87 90.62,122.89 91.19,122.89 91.56,122.52 91.81,122.52 92.17,122.88 UC1.E62 ; PU501.23 91.77,136.42 91.94,136.25 v1(92.42,136.25)
VSSSENSE_VGA: length 78
  TOP w0.102: v1(200.63,53.1) 200.46,53.1 v4(200.02,53.54)
  TOP w0.508: v1(172.98,113.2) 172.82,113.04 RV204.1
  IN3 w0.102: v1(172.98,113.2) 173.47,113.69 174.22,113.69 174.64,113.27 175.5,113.27 176.56,112.22 176.56,109.27 176.66,109.16 176.66,108.14 178.28,106.52 178.28,103.95 178.49,103.74
  IN3 w0.127: v1(200.63,53.1) 199.68,53.1 197.07,55.7 197.07,57.61 188.84,65.84 188.84,77.62 183.42,83.05 183.42,91.84 181.44,93.82 181.44,96.23 180.87,96.8 180.87,99.85 178.66,102.06 178.66,103.58 178.49,103.74
  BOTTOM w0.254: v1(172.98,113.2) 172.36,113.2 171.66,112.5 UV1.AH29 ; PR845.2 v1(200.63,53.1)
65W#/90W: length 174.1
  TOP w0.102: v2(127.47,182.44) 127.72,182.19 128.44,182.19 128.82,181.8 PQ4.2 ; v1(188.51,46.08) 185.99,46.08 183.23,43.31 183.23,42.11 182.82,41.71 UE1.117
  TOP w0.254: v1(128.82,180.24) PQ4.2
  IN2 w0.254: v1(128.82,180.24) 128.82,168.65 131.94,165.53 131.94,146.32 139.09,139.17 139.09,137.97 148.36,128.7 148.36,121.24 150.41,119.2 150.41,118.77 149.84,118.19 149.84,117.45 152.4,114.89 152.4,112.65 154.48,110.57 154.48,109.98 153.86,109.36 153.86,108.95 154.48,108.33 154.48,107.68 158.77,103.4 159.72,103.4 161.31,101.8 161.87,101.8 162.67,100.99 162.67,100.14 182.6,80.21 183.05,80.21 187.6,75.66 187.6,66.3 188.75,65.15 188.75,49.54 188.23,49.02 188.23,46.36 v1(188.51,46.08)
62881_COMP: length 7.9
  BOTTOM w0.102: v2(208.23,52.28) 208.06,52.11 205.85,52.11 205.12,52.83
  BOTTOM w0.203: PC818.2 204.99,53.86 PU800.5
  BOTTOM w0.254: PC814.2 PC806.2 205.12,51.98 PR817.2 PC818.2
62881_FB: length 6.9
  BOTTOM w0.102: v2(204.61,50.14) 204.23,50.52 PC814.1
  BOTTOM w0.203: PU800.6 204.59,54.9 204.52,54.83 204.52,54.81 204.24,54.53 PR821.1 203.67,53.17 203.67,53.16
  BOTTOM w0.254: PC814.1 PR818.1 PR813.1 203.67,52.26 203.67,53.16
62881_RBIAS: length 3.9
  TOP w0.254: PR815.1 206.1,54.35 v1(206.06,54.39)
  BOTTOM w0.102: v2(207.98,54.03) 207.87,54.13 206.54,54.13 206.36,54.31 206.36,54.35 206.31,54.39 v1(206.06,54.39)
  BOTTOM w0.203: v1(206.06,54.39) 205.79,54.67 PU800.3
62881_VCCP: length 5.7
  BOTTOM w0.102: PR814.1 205.64,61.73 204.42,62.95 v2(204.42,63.05)
  BOTTOM w0.203: PR814.1 205.87,61.71 205.87,60.11 205.85,60.09 205.85,60.08 205.79,60.03 PU800.19
  BOTTOM w0.254: PC803.1 PR814.1
62881_VDD: length 6.5
  TOP w0.254: v1(202.53,57.34) 202.62,57.34 204.22,58.94 PC811.1
  BOTTOM w0.203: v1(202.53,57.34) 202.53,57.35 202.53,57.35 202.59,57.41 PU800.11
  BOTTOM w0.254: v1(202.53,57.34) 202.42,57.34 202.31,57.45 v2(201.93,57.45) 201.51,57.87 PR822.1
62881_VID0: length 6.4
  TOP w0.102: PR811.2 207.88,61.04 v2(207.38,61.54)
  TOP w0.254: PR811.2 208.26,60.08 v1(208.26,59.76)
  BOTTOM w0.203: v1(208.26,59.76) 208.25,59.78 208.25,60.38 207.72,60.91 206.4,60.91 206.2,60.7 206.2,59.98 206.19,59.96 PU800.20
62881_VID1: length 3.6
  TOP w0.254: PR810.2 207.79,59.65 v1(207.67,59.76)
  BOTTOM w0.203: PU800.21 206.59,60.44 206.65,60.51
  BOTTOM w0.254: v1(207.67,59.76) 207.67,60.22 207.39,60.51 v2(207.01,60.51) 206.65,60.51
62881_VID2: length 2.2
  BOTTOM w0.203: PU800.22 208.05,58.61 208.37,58.93 208.37,59.13 208.82,59.57 PR812.2
62881_VID3: length 1.9
  BOTTOM w0.203: PU800.23 208.18,58.21 208.65,58.68 PR807.2
62881_VID4: length 1.7
  BOTTOM w0.203: PU800.24 208.98,57.81 PR809.2
62881_VID5: length 1.9
  BOTTOM w0.203: PR806.2 208.49,57.41 PU800.25
62881_VID6: length 2.8
  TOP w0.102: v2(209.23,57.03) 209.09,56.88 v1(208.28,56.88)
  TOP w0.254: v1(208.28,56.88) 208.07,57.1 PR804.2
  BOTTOM w0.203: v1(208.28,56.88) 208.28,56.91 208.18,57.01 PU800.26
62881_VIN: length 4.1
  TOP w0.102: v2(203.04,58.35) 202.61,57.92 v1(202.52,57.92)
  TOP w0.254: PR823.1 PC810.1 201.99,57.48 202.43,57.92 v1(202.52,57.92)
  BOTTOM w0.203: v1(202.52,57.92) 202.52,57.94 202.64,57.81 PU800.12
62881_VR_ON: length 3.8
  TOP w0.102: v2(207.9,55.1) 207.62,55.38 PC869.1
  TOP w0.254: v1(208.24,56.3) 208.15,56.21 PC869.1
  BOTTOM w0.203: PU800.27 207.9,56.61 208.22,56.3 v1(208.24,56.3)
  BOTTOM w0.254: v1(208.24,56.3) 208.52,56.02 PR803.2
62881_VW: length 4
  BOTTOM w0.102: PR817.1 206.85,52.84 v2(207.05,53.04)
  BOTTOM w0.203: 205.45,54.49 205.39,54.56 PU800.4
  BOTTOM w0.254: PR817.1 PC818.1 205.45,54.32 205.45,54.49
+BIF_VDDC: length 37.6
  TOP w0.508: v1(173.9,124.16) 174.25,124.52 CV195.1 CV196.1 174.42,123.63 v1(173.94,123.15) ; v1(172.88,125.24) 172.75,125.36 168.88,125.36 168.3,125.93 RV103.2 CV97.1 166.25,126.5 RV234.1 165.26,125.88 165.32,125.82 165.32,125.1 165,124.79 v2(159.16,124.79) 154.78,124.79 154.65,124.66 153.51,124.66 152.47,123.62 152.47,114.98 153.22,114.23 RV245.2
  BOTTOM w0.381: v1(173.94,123.15) 173.48,122.69 UV1.T27 ; v1(172.88,125.24) 172.88,125.23 172.92,125.23 UV1.N27 173.46,124.6 v1(173.9,124.16)
+CHGRTC: length 1.3
  BOTTOM w0.102: 202.06,11.06 202.06,9.81 v4(202.07,9.8)
+CODEC_AVDD2: length 5.8
  TOP w0.102: v2(22.38,15.63) 22.71,15.96 CA61.1
  TOP w0.203: UA1.40 26.08,17.14 26.11,17.11 26.11,16.11 RA8.2 RA9.2 24.06,15.66 CA61.1
+CPU_CORE: length 52
  BOTTOM w0.089: 117.16,119.43 UC1.K23 ; UC1.K23 116.87,119.76 116.73,119.62 ; UC1.K23 117.26,119.76 UC1.L22 117.26,118.95 UC1.M23 ; 109.55,121.84 109.55,121.98 UC1.G35 109.62,122.3 109.62,122.41 ; 112.16,122.34 UC1.G31 112.09,121.95 112.09,121.84 ; 107.9,121.84 107.9,121.97 UC1.G37 107.84,122.31 107.84,122.41 ; 105.36,122.41 105.36,122.28 UC1.G41 105.36,121.94 105.36,121.84 ; UC1.J23 117.16,120.58 116.92,120.82 ; UC1.J23 117.03,120.44 116.79,120.44 ; UC1.J23 117.3,120.71 117.3,120.89 ; 112.85,122.41 112.85,122.31 UC1.G29 112.92,121.97 112.92,121.84 ; 97.04,122.41 97.04,122.27 UC1.G55 97.04,121.95 97.04,121.84 ; 114.63,122.47 114.63,122.31 UC1.G27 114.57,121.98 114.57,121.84 ; 107.14,122.33 UC1.G39 107.08,121.95 107.08,121.84 ; 115.39,122.47 115.39,122.28 UC1.G25 115.39,121.94 115.39,121.84 ; 100.34,122.47 100.34,122.28 UC1.G49 100.34,121.94 100.34,121.84 ; 99.58,122.41 99.58,122.3 UC1.G51 99.52,121.98 99.52,121.84 ; 104.54,121.84 104.54,121.98 UC1.G43 104.6,122.3 104.6,122.41 ; 97.87,121.84 97.87,121.97 UC1.G53 97.8,122.32 97.8,122.41 ; 102.88,122.41 102.88,122.25 UC1.G45 102.88,121.97 102.88,121.84 ; UC1.M23 116.82,118.95 116.79,118.98 ; UC1.M23 117.16,119.29 ; 110.38,121.84 110.38,121.94 UC1.G33 110.38,122.28 110.38,122.41 ; 95.33,122.41 95.33,122.29 UC1.G57 ; 117.3,121.08 117.3,121.25 UC1.H23 117.3,121.52 117.3,121.71
  BOTTOM w0.203: UC1.G23 117.24,121.82 ; UC1.G23 116.65,121.82 ; UC1.G23 116.65,122.4 ; UC1.F48 101.5,122.73 ; UC1.F48 100.92,122.73 ; UC1.F48 101.5,122.14 ; UC1.F48 100.92,122.14 ; 115.86,122.4 UC1.G25 115.86,121.82 ; 98.31,121.82 UC1.G53 98.31,122.4 ; 108.44,122.73 UC1.F36 ; UC1.F36 109.03,122.14 ; UC1.F36 109.03,122.73 ; UC1.F36 108.44,122.14 ; UC1.F40 106.52,122.14 ; UC1.F40 105.93,122.73 ; UC1.F40 106.52,122.73 ; UC1.F40 105.93,122.14 ; 95.8,122.4 UC1.G57 95.8,121.82 ; 106.62,122.4 UC1.G39 106.62,121.82 ; 99.1,121.82 UC1.G51 99.1,122.4 ; 109.13,121.82 UC1.G35 109.13,122.4 ; 111.64,121.82 UC1.G31 111.64,122.4 ; 114.14,121.82 UC1.G27 114.14,122.4 ; 116.87,121.09 UC1.H23 116.87,121.68 ; 100.81,121.82 UC1.G49 100.81,122.4 ; 110.95,122.73 UC1.F32 ; UC1.F32 111.53,122.14 ; UC1.F32 110.95,122.14 ; UC1.F32 111.53,122.73 ; UC1.F44 104.01,122.14 ; UC1.F44 103.42,122.73 ; UC1.F44 103.42,122.14 ; UC1.F44 104.01,122.73 ; UC1.F24 116.55,122.73 ; UC1.F24 115.96,122.14 ; UC1.F24 116.55,122.14 ; UC1.F24 115.96,122.73 ; 110.84,122.4 UC1.G33 110.84,121.82 ; 113.35,122.4 UC1.G29 113.35,121.82 ; 113.45,122.14 UC1.F28 ; UC1.F28 114.04,122.73 ; UC1.F28 113.45,122.73 ; UC1.F28 114.04,122.14 ; UC1.F52 99,122.14 ; UC1.F52 98.41,122.14 ; UC1.F52 99,122.73 ; UC1.F52 98.41,122.73 ; 105.83,122.4 UC1.G41 105.83,121.82 ; 96.49,122.14 UC1.F56 ; UC1.F56 95.9,122.73 ; UC1.F56 95.9,122.14 ; UC1.F56 96.49,122.73 ; 103.32,121.82 UC1.G45 103.32,122.4 ; 96.59,122.4 UC1.G55 96.59,121.82 ; 104.11,121.82 UC1.G43 104.11,122.4 ; 101.61,121.82 UC1.G47 101.61,122.4 ; 108.34,121.82 UC1.G37 108.34,122.4
  BOTTOM w0.254: UC1.U57 v1(95.77,116.18) ; UC1.W57 v1(95.77,114.88) ; UC1.P57 v1(95.77,117.48) ; v1(96.1,111.74) 95.56,112.28 UC1.AD57 ; UC1.M57 v1(95.77,118.78) ; v1(93.95,122.5) 94.25,122.2 UC1.F59 ; UC1.K57 v1(95.85,120.08) ; UC1.AB57 v1(95.77,113.58)
  vias: v1(94.39,136.35) v1(94.45,134.95) v1(95.28,139.14) v1(95.34,137.87) v1(95.47,141.68) v1(95.53,140.41) v1(95.72,134.95) v1(95.79,136.41) v1(95.81,121.5) v1(96.33,123.04) v1(96.36,137.3) v1(96.55,134.12) v1(96.87,136.41) v1(96.87,121.49) v1(97.12,142.57) v1(97.69,137.49) v1(97.88,136.41) v1(98.01,121.5) v1(98.14,133.87) v1(98.39,129.23) v1(98.84,123.04) v1(98.96,137.49) v1(99.41,142.57) v1(99.39,121.5) v1(100.1,129.23) v1(100.17,138.63) v1(100.17,136.41) v1(100.3,132.85) v1(100.52,121.5) v1(101.18,138.63) v1(101.18,136.41) v1(101.31,132.85) v1(101.34,123.04) v1(101.44,128.79) v1(101.57,133.81) v1(101.9,121.5) v1(103.03,121.5) v1(103.53,138.63) v1(103.53,136.41) v1(103.66,132.85) v1(103.85,123.04) v1(104.41,121.5) v1(104.49,138.63) v1(104.49,136.41) v1(104.87,134.19) v1(104.99,128.22) v1(105.53,121.5) v1(106.36,123.04) v1(106.84,136.41) v1(106.91,121.5) v1(106.96,132.85) v1(107.85,136.41) v1(107.98,132.85) v1(108.04,121.5) v1(108.3,134.19) v1(108.87,123.04) v1(109.42,121.5) v1(110.2,138.57) v1(110.2,136.41) v1(110.26,132.79) v1(110.55,121.5) v1(111.22,138.57) v1(111.22,136.41) v1(111.28,132.79) v1(111.37,123.04) v1(111.6,134.25) v1(111.93,121.5) v1(113.06,121.5) v1(113.88,123.04) v1(114.44,121.5) v1(115.56,121.5) v4(108.85,129.62)
+DIMM1_VREF_DQ:
  vias: v1(40.67,73.52) v1(40.67,72.92) v2(41.06,71.77)
+DIMM2_VREF_DQ:
  vias: v1(119.13,73.01) v1(119.56,72.58) v2(118.94,71.25)
+DPAB_VDD10: length 14.2
  TOP w0.508: 168.49,106.87 167.53,105.91 v2(165.19,105.91) CV114.1 CV115.1 158.6,105.91 CV116.1 157.45,105.99 RV120.1
  BOTTOM w0.254: UV1.AP33 168.49,107.89 v1(168.87,108.27) 168.46,108.68 UV1.AN33 ; v1(168.87,107.45) 168.87,107.5 UV1.AP32 169.45,107.7 169.87,107.7 UV1.AP31
+DPAB_VDD18: length 17.3
  TOP w0.508: v1(172.18,104.97) 172.18,104.46 171.35,103.64 v2(169.41,103.64) 162.4,103.64 CV110.1 161.13,104.33 161.05,104.42 RV118.1
  BOTTOM w0.254: UV1.AN24 175.13,108.69 v1(174.91,108.46) ; UV1.AP26 174.06,107.87 v1(173.64,107.45) ; UV1.AU28 172.26,106.29 UV1.AV29 171.86,105.28 v1(172.18,104.97) ; UV1.AP25 174.86,107.74 v1(175.16,107.45) 175.6,107.89 UV1.AP24
+DPCD_VDD10:
  vias: v2(185.97,103.41)
+DPCD_VDD18:
  vias: v2(181.27,103.48)
+DPEF_VDD10: length 19.1
  TOP w0.508: RV126.2 158.19,101.24 158.21,101.22 CV123.1 CV125.1 CV124.1 161.26,101.22 161.64,101.61 v2(163.5,101.61) v1(164.83,102.94)
  IN1 w0.508: v1(168.86,109.88) 168,109.02 168,106.76 164.83,103.59 v1(164.83,102.94)
  BOTTOM w0.254: UV1.AK33 UV1.AK34 ; v1(168.87,110.68) 168.48,110.29 UV1.AL33
  BOTTOM w0.305: v1(168.87,110.68) 168.47,111.09 UV1.AK33 ; UV1.AM33 168.47,109.49 v1(168.86,109.88)
+DPEF_VDD18: length 19.1
  TOP w0.102: RV124.2 156.56,105.26 v2(156.34,105.47)
  TOP w0.508: v1(162.86,105.16) 159.86,105.16 159.61,104.91 CV121.1 CV122.1 158.3,104.43 158.26,104.4 CV120.1 156.58,104.4 RV124.2
  IN1 w0.508: v1(162.86,105.16) 164.14,106.43 164.14,107.89 164.87,108.63 164.87,110.3 v1(165.06,110.49)
  IN3 w0.508: v1(167.16,112.34) 167.16,111.7 165.95,110.49 v1(165.06,110.49)
  BOTTOM w0.254: v1(165.06,110.49) UV1.AL38 165.66,110.09 UV1.AM37
+DPLL_PVDD: length 15.7
  TOP w0.102: v2(169.41,110.95) 169.61,110.75 RV246.2
  TOP w0.508: RV246.2 CV84.1 CV83.1 169.8,108.97 v1(169.67,109.09)
  IN3 w0.508: v1(169.67,109.09) 168.28,109.09 167.57,108.37 165.29,108.37 164.75,107.83 v1(164.75,107.64)
  BOTTOM w0.254: UV1.AM32 169.28,109.49 v1(169.67,109.09)
  BOTTOM w0.508: LV14.1 160.86,106.19 CV82.1 162.14,105.35 162.78,105.99 163.48,105.99 164.75,107.26 v1(164.75,107.64)
+DPLL_VDDC: length 14.5
  TOP w0.508: v1(163.41,104.47) 163.61,104.27 v2(166.17,104.27) 169.72,104.27 170.57,105.12 CV87.1 CV88.1 170.57,108.16 v1(170.46,108.27)
  BOTTOM w0.254: UV1.AN31 170.06,108.67 v1(170.46,108.27)
  BOTTOM w0.508: LV15.1 161.05,104.33 CV86.1 163.28,104.33 v1(163.41,104.47)
+EC_VCCA: length 39.1
  TOP w0.203: v1(195.42,50.11) 195.17,50.11 194.79,50.49 UE1.67
  TOP w0.508: LE1.2 201.12,35.37 200.61,34.86 CE7.1 199.67,34.49 v2(199.62,34.44) 198.52,34.44 198.47,34.49 v1(197.39,34.49)
  IN2 w0.508: v1(195.42,50.11) 195.84,50.11 197.39,48.56 v1(197.39,34.49)
  IN3 w0.508: v1(183.42,46.81) 187.1,46.81 188.34,48.05 189.6,48.05 190.04,47.62 193.93,47.62 195.42,49.11 v1(195.42,50.11)
  BOTTOM w0.508: v1(183.42,46.81) 183.1,46.81 182.22,45.93 PR24.2
+FAN_POWER: length 0.6
  TOP w0.102: v1(48.97,107.08) v4(49.57,107.08)
+INV_PWR_SRC:
  vias: v1(223.73,175.02) v1(223.73,174.43) v1(224.37,175.02) v1(224.37,174.43) v4(224.93,174.13)
+LAN_IO: length 89.7
  TOP w0.203: UG1.8 75.09,41.65 CG3.1
  TOP w0.508: v1(75.14,40.93) CG3.1
  IN1 w0.508: v1(37.81,74.37) 37.81,60.68 44.42,54.07 63.77,54.07 66.26,51.59 66.26,44.95 70.28,40.93 v1(75.14,40.93)
  IN2 w0.508: v1(37.05,89.86) 34.57,87.39 v1(34.57,81.48)
  IN3 w0.508: v1(40.54,80.02) 40.54,78.26 40.9,77.9 40.9,75.25 40.02,74.37 v1(37.81,74.37)
  BOTTOM w0.203: CL15.1 35.08,81.15 35.08,81.24 35.61,81.77 36.12,81.77 36.35,82 UL1.32
  BOTTOM w0.508: RL38.2 41.19,80.67 v1(40.54,80.02) ; v1(34.57,81.48) 34.2,81.11 CL15.1 ; RL37.2 v1(37.05,89.86)
  vias: v1(44.42,83.7) v1(44.42,83.12) v4(42.75,81.42)
+LAN_VDD: length 7.5
  IN2 w0.762: 35.78,81.8 35.72,81.86 35.72,85.99
  BOTTOM w0.203: CL20.1 36.49,80.29 36.73,80.53 36.73,81.23 37.15,81.64 UL1.30
  BOTTOM w0.508: CL20.1 v1(35.97,80.91)
  vias: v1(35.53,86.62) v1(36.03,87.07) v2(34.28,86.47)
+LCDVDD:
  vias: v1(213.26,169.43) v1(213.26,168.79) v1(213.26,168.1) v1(213.83,168.41) v4(213.75,167.66)
+LCDVDD_CONN: length 1.2
  BOTTOM w0.102: CX11.1 212.12,170.37 v2(212.01,170.26)
+MIC2-VREFO: length 9.7
  TOP w0.203: 22,21.73 22.13,21.6 22.82,21.6 23.03,21.39 23.48,21.39 23.62,21.25 UA1.29
  TOP w0.508: 22,21.73 21.11,22.62 20.45,22.62 19.9,23.16 19.41,23.16 18.1,24.47 v2(17.78,24.47) 16.92,24.47 RA1109.2 RA53.2
+MPV18: length 22.1
  IN1 w0.508: v1(202.13,145.11) 202.13,140.22 191.97,130.06 191.97,128.35
  BOTTOM w0.254: UV1.H8 188.86,129.09 v1(189.26,128.69) 189.66,129.08 UV1.H7
  vias: v2(201.65,148.23)
+PCH_VCCDSW: length 14.2
  TOP w0.241: v1(119.34,110.4) 118.95,110.01 118.95,109.51 118.61,109.17 118.61,105.26 118.08,104.73 v2(118.08,103.08) 118.08,102.14
  TOP w0.508: 118.08,102.14 118.59,101.64 118.59,98.45 R265.1
  BOTTOM w0.254: UC1.AG19 119.72,110.77 v1(119.34,110.4) 118.97,110.77 UC1.AG20
+PCH_VCCDSW_R: length 2.1
  TOP w0.254: v2(119.32,95.88) 118.9,95.88 118.36,96.42 C64.1 R265.2
+PCIE_PVDD: length 9.9
  BOTTOM w0.254: 164.25,117.63 164.45,117.63 164.94,118.11 165.46,118.11 165.89,117.69 UV1.AB37
  BOTTOM w0.508: LV18.2 159.03,114.75 159.16,114.62 CV134.1 160.63,114.62 161.17,115.16 161.17,115.9 CV132.1 CV133.1 162.56,115.94 v2(163.14,116.52) 164.25,117.63
+PCIE_VDDR:
  vias: v1(156.16,113.62) v1(156.58,113.21) v1(168.97,117.62) v1(169.61,117.64) v1(170.46,119.89) v2(157.18,113.59)
+RTCBATT: length 166.8
  TOP w0.508: RG1.1 74.96,46.73 75.38,47.15 77.22,47.15 78.03,46.34 v4(78.03,45.03) v1(78.03,40.96)
  BOTTOM w0.254: RC10.2 204.49,8.89 205.02,9.42 205.02,13.93 202.34,16.61 183.13,16.61 181.56,18.18 176.68,18.18 169.41,25.46 169.41,30.69 161.05,39.05 123.45,39.05 120.09,35.69 109.09,35.69 103.44,41.34 78.41,41.34 v1(78.03,40.96)
  BOTTOM w0.508: RC10.2 204.59,8.35 207.19,8.35 208.24,9.4 JRTC.1
+RTCVCC: length 349.1
  TOP w0.508: RC5.1 RC6.1 132.17,93.48 132.55,93.1 v4(135.46,93.1) v1(138.46,93.1) ; RG2.1 v1(68.66,46.59) ; v1(17.82,26.11) 17.82,26.33 v1(20.4,28.91)
  IN1 w0.381: v1(124.23,110.37) 124.23,108.53 124.48,108.29 124.48,103.71 124.8,103.38 124.82,103.38 126.33,101.87 129.2,101.87 129.51,102.18 132.55,102.18 133.43,101.31 133.77,101.31 136.81,98.27 v1(136.96,98.27)
  IN1 w0.508: v1(68.66,46.59) 70.7,44.55 75.63,44.55 76.91,43.27 76.91,32.87 75.24,31.19 51.11,31.19 49.9,29.98 23.9,29.98 22.95,30.94 21.87,30.94 21.09,30.15 21.09,29.6 v1(20.4,28.91) ; v1(177.09,42.21) 176.84,42.21 176.38,42.67 176.38,44.37 176.66,44.65 176.66,48.04 175.73,48.97 175.73,57.86 173.37,60.22 173.37,63.47 171.99,64.86 171.99,71.25 169.43,73.81 159.86,73.81 156.76,76.91 154.59,76.91 138.46,93.04 v1(138.46,93.1)
  IN2 w0.508: v1(177.09,42.21) 177.13,42.17 177.13,36.33 185.32,28.14 185.32,21.98 188.05,19.25 196.13,19.25 200.83,14.55 v1(202.72,14.55)
  BOTTOM w0.254: UC1.AG10 124.63,110.77 v1(124.23,110.37)
  BOTTOM w0.508: RA5.1 17.62,25.91 v1(17.82,26.11) ; DC1.1 203.31,13.97 v1(202.72,14.55) ; v1(68.66,46.59) 69,46.59 71.49,44.11 106.01,44.11 111.72,38.4 118.3,38.4 122.11,42.21 v1(177.09,42.21)
+SM_VREF_CA: length 16.1
  TOP w0.254: v1(97.97,96.85) v4(97.97,95.99)
  IN2 w0.508: v1(97.97,96.85) 98.52,96.85 101.77,100.1 101.77,101.79 100.99,102.56 100.99,104.8 100.08,105.71 v1(100.08,106.39)
  BOTTOM w0.254: UC1.AP49 100.22,106.39 v1(100.08,106.39)
  BOTTOM w0.508: v1(97.97,96.85) 97.05,95.93 CC8.1 97.07,95.52 RC17.2
+SM_VREF_CA_DIMM: length 148.9
  TOP w0.508: v1(112.18,51.93) 112.09,52.02 v4(96.24,52.02) 94.26,52.02 91.98,54.3 91.98,62.37 90.9,63.45 RD4.2 ; RD10.2 v1(162.98,61.72)
  IN1 w0.508: v1(162.98,61.72) 162.63,61.36 v1(162.63,50.79)
  IN3 w0.508: v1(112.18,51.93) 116.37,51.93 117.73,50.57 139.78,50.57 139.99,50.79 v1(162.63,50.79)
  BOTTOM w0.254: 97.07,93.66 RC17.1
  BOTTOM w0.508: v1(112.18,51.93) 112.17,51.94 112.17,72.78 98.77,86.18 98.77,91.58 98.36,91.99 RC14.2 97.44,91.99 97.05,92.37 RC20.1 97.07,92.88 97.07,93.66
+SM_VREF_DQ0: length 14
  TOP w0.254: v1(96.19,96.51) v4(96.19,97.15)
  IN2 w0.508: v1(99.13,105.72) 99.13,102.54 99.78,101.89 99.78,101.4 99.22,100.84 99.22,99.53 v1(96.19,96.51)
  BOTTOM w0.254: v1(99.13,105.72) 99.19,105.72 UC1.AR51
  BOTTOM w0.508: RC19.2 96.18,95.52 CC10.1 v1(96.19,96.51)
+SM_VREF_DQ0_DIMM1: length 68.8
  TOP w0.508: v1(46.42,76.08) 46.38,76.08 45.69,75.39 v4(45.69,73.68) 45.69,71.64 44.1,70.05 RD1.1
  IN2 w0.508: v1(95.41,90.43) 93.44,92.4 61.81,92.4 46.42,77.01 v1(46.42,76.08)
  BOTTOM w0.508: v1(95.41,90.43) 95.42,90.44 RC16.2 96.36,90.72 96.36,92.7 RC22.1 96.18,92.88 RC19.1
+SM_VREF_DQ1: length 15
  TOP w0.254: v1(94.41,96.34) v4(94.41,95.67)
  IN2 w0.508: v1(99.13,106.37) 98.93,106.37 98.31,105.74 98.31,102.27 98.31,102.27 98.31,100.76 94.41,96.86 v1(94.41,96.34)
  BOTTOM w0.254: v1(99.13,106.37) 99.45,106.69 UC1.AP51
  BOTTOM w0.508: RC18.2 94.4,95.52 CC9.1 v1(94.41,96.34)
+SM_VREF_DQ1_DIMM2: length 60.8
  TOP w0.508: RD8.1 121.48,70.59 121.48,66.6 119.6,64.72 v4(119.6,61.93) 119.6,60.84 118.71,59.95 v1(111.53,59.95)
  BOTTOM w0.508: RC18.1 94.4,93.28 94.41,93.27 RC21.1 94.41,92.64 94.59,92.47 RC15.2 94.35,91.99 93.82,91.45 93.82,89.23 111.53,71.51 v1(111.53,59.95)
+SPV10: length 19.2
  TOP w0.102: v2(194.63,98.62) v1(194.09,98.62)
  IN1 w0.508: v1(194.09,98.62) 194.09,99.57 192.62,101.03 190.97,101.03 188.93,103.07 v1(188.24,103.07)
  BOTTOM w0.254: UV1.AN9 188.09,108.69 188.46,108.32 188.46,107.54 188.24,107.33 188.24,106.85 188.24,106.05 v1(188.24,103.07)
  BOTTOM w0.508: v1(194.09,98.62) 194.09,98 CV217.1 CV216.1 194.28,96.63 194.59,96.31 CV215.1 194.59,95.22 194.21,94.83 LV23.2
+SPV18: length 17.5
  TOP w0.102: v2(191.8,99.42) 191.57,99.19 v1(190.89,99.19)
  IN3 w0.508: v1(190.89,99.19) 190.89,101.17 190.08,101.98 190.08,106.18 187.66,108.6 v1(187.66,109.05)
  BOTTOM w0.254: UV1.AM10 187.26,109.44 v1(187.66,109.05)
  BOTTOM w0.508: LV22.2 190.83,95.18 190.78,95.23 CV200.1 190.78,96.36 191.14,96.72 CV202.1 CV201.1 191.14,98.94 v1(190.89,99.19)
+SW_LX: length 7.3
  TOP w0.102: LX9.2 201.53,162.94 201.53,161.72 v2(202.05,161.2)
  TOP w0.203: UX4.17 203.71,167.34 203.71,166.31 203.29,165.88 202.68,165.27
  TOP w0.889: LX9.2 202.68,165.27
+SWR_V12: length 7.6
  TOP w0.203: CX37.1 204.7,175.4 204.12,175.4 203.9,175.18 203.9,174.54 204.12,174.32 UX4.43 ; v1(200.26,167.77) 200.26,168.27 200.56,168.58 UX4.11 ; UX4.15 202.92,166.91 202.72,166.71 202.72,166.19 v1(202.81,166.1)
  TOP w0.508: v1(204.12,175.91) 204.39,175.91 204.44,175.85 204.61,175.85 204.88,175.59 CX37.1 ; CX32.1 199.81,167.6 199.98,167.77 v1(200.26,167.77)
  vias: v1(200.02,163.14) v1(200.69,163.14) v2(200.47,161.68)
+TSVDD: length 17.1
  TOP w0.508: v1(159.36,107.46) v2(163.25,107.46) 164.16,108.37 165.87,108.37 166.47,108.98 166.47,110.53 168.48,112.54 v1(168.86,112.54)
  BOTTOM w0.254: v1(168.86,112.54) 169.26,112.14 UV1.AJ32
  BOTTOM w0.508: CV93.1 158.52,106.57 CV91.1 159.25,107.57 v1(159.36,107.46) ; CV93.1 CV92.1 ; CV93.1 159.23,106.49 LV16.2
+VCHGR:
  vias: v3(143.41,182.32) v3(144.17,182.51) v3(145,182.51) v3(145,181.62) v3(145,180.73) v3(145,179.84) v3(145.7,182.89) v3(145.7,182.13) v3(145.7,181.37) v3(145.7,180.6) v3(145.7,179.84) v3(145.7,179.08) v4(143.78,181.18)
+VDISPLAY_VCC: length 1.9
  TOP w0.102: v4(14.04,110.95) 13.56,110.46 13.56,109.55 v1(13.36,109.36)
  vias: v1(13.36,108.72)
+VGA_CORE: length 133.5
  TOP w0.254: v1(201.39,52.84) 201.96,52.27 203.61,52.27 203.91,52.58 PR820.2
  TOP w0.508: v1(176.96,118.1) 177.34,118.48 PC845.1 ; v1(175.94,120.11) 175.43,120.61 PC853.1 ; v1(178.91,124.23) 179.34,123.8 PC857.1 ; v1(180.96,120.13) 181.44,120.6 PC860.1 ; v1(180.96,124.25) 181.44,123.78 PC858.1 ; PC855.1 175.43,122.57 v1(174.97,123.03) ; v1(175.96,121.25) 176.36,121.65 PC864.1 ; v1(177.96,122.19) 177.97,122.2 PC856.1 ; v1(177.96,117.33) 177.88,117.24 PC844.1 ; v1(180.94,123.08) 181.44,122.59 PC840.1 ; PC841.1 181.5,117.71 v1(180.96,118.25) ; PC859.1 179.28,120.44 v1(178.96,120.12)
  IN1 w0.254: v1(201.39,52.84) 201.39,60.08 200.18,61.29 200.18,80.15 198.91,81.42 196.56,81.42 196.05,81.93 196.05,85.9 196.71,86.56 v3(197.07,86.56)
  BOTTOM w0.254: UV1.R26 174.46,123.54 v1(174.97,123.03) 175.31,122.69 UV1.T24 ; PR830.1 198.4,61.24 198.4,61.8 200.82,64.21 200.82,74.26 204.2,77.65 206.38,77.65 207.36,78.62 210.43,78.62 211.17,79.36 PL802.2
  BOTTOM w0.381: v1(183.11,114.19) 182.59,113.67 182.48,113.67 UV1.AG16 ; UV1.AB26 UV1.AC24 175.44,116.69 175.1,116.35 v1(174.97,116.35) 174.97,116.29 174.46,115.78 UV1.AD26 ; UV1.AC17 181.4,116.69 v1(180.96,117.13) 180.46,117.63 UV1.AB18 ; UV1.AB23 176.55,117.69 v1(176.96,118.1) 177.46,118.6 UV1.AA22 ; UV1.V20 178.96,120.19 v1(178.96,120.12) 178.53,119.69 UV1.Y21 ; v1(177.95,115.04) 177.6,114.69 UV1.AF22 ; UV1.Y16 UV1.AA17 181.4,118.69 v1(180.96,118.25) ; UV1.V27 v1(173.96,121.19) UV1.U26 ; v1(176.04,124.23) 175.89,124.23 175.46,124.65 UV1.N24 175.39,124.69 v1(174.91,125.17) 174.91,125.28 174.5,125.69 UV1.M26 ; v1(178.96,118.35) 179.08,118.35 179.42,118.69 UV1.AA20 UV1.Y18 ; UV1.AA27 173.46,118.76 v1(172.94,119.27) 172.53,119.69 UV1.Y28 ; 178.97,116.28 178.46,115.77 UV1.AD21 ; 178.97,116.28 v1(178.97,116.32) ; 178.97,116.28 179.38,116.69 UV1.AC20 ; UV1.T22 177.46,122.69 v1(177.96,122.19) UV1.U21 ; v1(176.95,115.09) 176.95,115.2 176.46,115.69 UV1.AD23 ; UV1.U16 182.29,121.69 v1(181.96,121.36) ; UV1.V24 175.94,120.22 v1(175.94,120.11) 176.04,120.11 UV1.Y23 ; UV1.AB28 172.46,117.6 v1(172.88,117.18) 173.37,116.69 UV1.AC27 ; UV1.U23 176.4,121.69 v1(175.96,121.25) ; UV1.R23 176.46,123.76 v1(176.94,124.23) ; UV1.U18 180.13,121.36 v1(179.96,121.36) ; v1(179.96,114.13) 179.46,114.63 UV1.AF20 ; UV1.V22 177.46,120.57 v1(176.94,120.05) ; v1(178.02,113.24) 178.46,113.68 UV1.AG21 UV1.AF20 ; UV1.AC22 177.32,116.69 v1(176.98,116.35) ; UV1.AA24 175.46,118.83 v1(174.96,119.33) 174.82,119.33 UV1.Y26 ; v1(180.94,115.34) 180.59,115.69 UV1.AD18 ; v1(178.98,115.05) 178.98,114.99 179.27,114.69 UV1.AF20 ; UV1.AA15 v1(182.96,118.19) UV1.AB16 182.46,117.8 v1(181.95,118.3) ; v1(180.96,124.25) 180.96,124.19 UV1.R18 ; v1(180.94,123.08) 181.34,122.69 UV1.T17 ; UV1.AF17 181.46,114.59 v1(180.94,114.07) 180.57,113.69 UV1.AG18 ; v1(180.96,120.13) 181.46,120.63 UV1.V17 ; UV1.R21 178.46,123.72 178.91,124.17 v1(178.91,124.23) ; v1(177.96,117.33) 178.32,117.69 UV1.AB21 ; v1(173.9,112.35) 173.56,112.69 UV1.AH27 173.35,112.69 173.27,112.6 172.55,112.6 UV1.AH28 ; UV1.T20 179.33,122.69 v1(178.96,123.06)
  BOTTOM w0.508: v1(178.02,113.24) 177.47,112.69 UV1.AH22 ; PC849.1 173.88,102.71 173.38,103.2 v1(173.38,103.52)
  vias: v1(159.48,129.73) v1(159.79,129.16) v1(159.79,128.53) v1(159.79,127.7) v1(160.43,127.7) v1(161.06,127.7) v1(161.57,126.53) v1(162.21,126.53) v1(162.21,125.76) v1(162.84,125.76) v3(189.35,85.71) v3(189.35,84.82) v3(189.39,86.64) v3(189.77,87.45) v3(190.53,87.51) v3(190.59,86.56) v3(191.23,83.01) v3(191.48,87.51) v3(191.61,86.56) v3(191.93,88.21) v3(192.43,83.01) v3(192.88,87.51) v3(193.01,86.56) v3(193.07,85.42) v3(193.07,84.15) v3(193.32,88.21) v3(193.7,82.94) v3(193.96,85.42) v3(193.96,84.15) v3(194.21,87.51) v3(194.34,86.56) v3(194.66,88.21) v3(194.91,82.94) v3(195.35,87.51) v3(195.74,86.56) v3(195.8,88.21) v3(196.37,87.58) v3(196.75,82.81) v3(197.01,88.21) v3(197.77,87.58) v3(197.89,82.81) v3(198.02,85.42) v3(198.15,88.21) v3(198.21,86.56) v3(199.04,87.45) v3(199.04,85.8) v3(199.04,82.88) v3(199.55,88.28) v3(199.55,84.15) v3(200.18,87.59) v3(200.18,82.88) v3(200.69,83.89) v3(200.84,88.19) v3(201.2,84.78) v3(201.32,82.88) v3(201.83,87.58) v3(201.83,83.89) v3(202.34,84.78) v3(202.47,88.28) v3(202.59,83.01) v3(203.23,87.58) v3(203.74,82.62) v3(203.8,88.28) v3(204.69,87.45) v3(204.88,82.62) v3(205.2,88.28) v3(205.39,86.56) v3(205.64,84.66) v3(205.64,83.51) v3(206.02,87.45) v3(206.21,86.12) v3(206.21,85.23) v3(206.4,84.15) v3(206.53,88.28) v3(207.1,86.12) v3(207.1,85.23) v3(207.17,87.45) v3(207.17,83.51) v3(207.67,88.28) v3(207.93,85.67) v3(207.93,84.4) v4(190.26,81.87)
+VGA_PCIE: length 87.6
  TOP w0.102: v4(192.26,75.78) 192.62,76.15 v1(193.07,76.15)
  TOP w0.508: v1(171.71,122.29) 172.16,121.83 CV146.1 171.81,120.6 171.66,120.45 171.32,120.45 RV198.2 ; 163.16,98.07 RV203.2 ; 163.16,98.07 163.16,99.33 v1(165.49,101.67) ; 163.16,98.07 158.63,98.07 157.57,99.13 RV126.1 156.25,100.33 155.71,100.87 155.71,106.16 156.44,106.89 RV120.2 ; CV147.1 CV148.1 171.84,124.61 v1(171.73,124.72) ; RV103.1 168.94,127.86 169.21,127.59 169.95,127.59 170.09,127.46 CV151.1 171.66,127.46 CV149.1 171.73,128.23 v1(171.29,128.68) 171.01,128.4 CV150.1
  IN1 w0.508: v1(195.29,93.93) 194.72,93.93 192.1,96.55 187.99,96.55 v1(187.19,97.36) v1(179.99,97.36) ; v1(157.76,113.93) 157.76,113.35 161.7,109.41 161.7,105.18 165.21,101.67 v1(165.49,101.67)
  IN3 w0.508: v1(157.76,113.93) 158.21,114.37 161.45,114.37 162.59,115.51 162.59,122.12
  BOTTOM w0.508: v1(195.29,93.93) 195.29,93.8 194.41,92.92 LV23.1 ; LV15.2 160.55,102.68 161.12,102.12 162.97,102.12 163.6,101.48 165.31,101.48 v1(165.49,101.67) ; v1(187.19,97.36) 186.86,97.68 RV121.1
  vias: v1(193.07,76.78) v1(193.7,76.78) v1(193.7,76.15) v1(194.34,76.78) v1(194.34,76.15)
+VGA_PCIEP: length 13.6
  TOP w0.254: 199.9,73.63 200.22,73.63 200.56,73.29 200.56,64.67 199.42,63.52 PC1306.1 PR1302.1
  vias: v1(193.26,72.59) v1(193.89,72.59) v1(195.29,72.59) v1(195.93,72.59) v1(197.01,72.59) v1(197.64,72.59) v1(198.66,72.59) v2(199.35,75.11)
+VREFG_GPU: length 13.7
  TOP w0.102: v2(184.97,113.15) v1(184.97,112.46)
  IN1 w0.508: v1(184.97,112.46) 185.39,112.04 185.39,110.88 185.08,110.57 185.08,109.12 185.23,108.97 v1(185.23,103.2)
  BOTTOM w0.254: UV1.AH13 184.74,112.69 v1(184.97,112.46)
  BOTTOM w0.508: RV93.1 RV95.1 CV81.1 185.01,102.99 v1(185.23,103.2)
/BATDRV: length 33.9
  TOP w0.254: v1(145.76,183.91) 146.08,184.22 149.85,184.22 v2(150.22,183.86) 153.4,180.68 158.51,180.68 159.86,179.82 161.02,179.09 161.1,179.04 161.12,179.05 161.16,179.03 161.76,178.8 162.19,178.36 163.64,176.92 169.07,176.92 169.38,176.6 169.38,175.27 170.46,174.19 170.46,172.98 169.42,171.94 169.29,171.94 168.99,171.64 PU701.11
  BOTTOM w0.254: PR706.2 v1(145.76,183.91)
A_BA0: length 59.3
  TOP w0.102: v1(186.19,148.29) 186.19,148.45 186.75,149.02 186.75,149.48 186.83,149.56 186.83,150.4 186.7,150.53 186.39,150.53 186.26,150.4 186.26,150.18 UV20.M2 ; UV18.M2 171.91,145.13 171.91,144.92 171.78,144.8 171.44,144.8 171.31,144.92 171.31,145.79 171.41,145.89 171.41,146.29 171.98,146.86 v1(171.98,147.02)
  IN1 w0.102: v1(171.98,147.02) 172.14,147.02 176.3,142.86 176.32,142.86 ; v1(186.19,148.29) 186.57,147.91 186.57,147.01 185.06,145.51 185.06,143.79
  IN1 w0.14: 176.32,142.86 176.86,142.32 179.91,142.32 180.04,142.19 v1(180.8,142.19) 180.8,142.55 180.92,142.68 183.76,142.68 183.89,142.8 183.89,143.55 184.02,143.67 184.94,143.67 185.06,143.79
  IN3 w0.102: v1(182.07,127.97) 182.07,127.74 181.67,127.34 181.45,127.34 181.28,127.51 181.28,127.69 181.61,128.02 181.61,130.5 181.19,130.92 181.19,131.15 180.6,131.74 180.6,133.52 181.61,134.53
  IN3 w0.157: v1(180.8,142.19) 180.8,142.34 180.92,142.47 181.25,142.47 181.38,142.34 181.38,141.62 181.5,141.49 182.42,141.49 182.55,141.36 182.55,141.01 182.39,140.85 182.2,140.85 182.07,140.72 182.07,140.34 182.2,140.22 182.42,140.22 182.55,140.09 182.55,139.71 182.42,139.59 182.2,139.59 182.07,139.46 182.07,139.08 182.2,138.96 182.42,138.96 182.55,138.83 182.55,138.45 182.42,138.33 182.2,138.33 182.07,138.2 182.07,137.83 182.2,137.7 182.42,137.7 182.55,137.57 182.55,137.2 182.42,137.07 182.2,137.07 182.07,136.94 182.07,136.57 182.2,136.44 182.39,136.44 182.55,136.28 182.55,135.93 182.39,135.77 182.26,135.77 182.13,135.65 182.13,135.27 182.26,135.14 182.51,135.14 182.64,135.02 182.64,134.66 182.51,134.53 181.61,134.53
  BOTTOM w0.102: v1(186.19,148.29) 185.81,147.91 185.81,147.5 186.06,147.25 186.06,145.58 UV21.M2 ; v1(182.07,127.97) 181.69,127.97 181.46,128.19 UV1.J17 ; v1(171.98,147.02) 172.36,147.4 172.36,147.81 172.11,148.06 172.11,149.73 UV19.M2
A_BA1: length 56.9
  TOP w0.102: UV18.N8 172.21,149.68 172.21,149.1 172.59,148.72 172.59,148.04 v1(172.97,147.65) ; v1(185.2,147.65) 185.58,147.27 185.58,146.58 185.95,146.21 185.95,145.63 UV20.N8
  IN1 w0.102: v1(172.97,147.65) 173.37,147.25 173.37,146.48 173.98,145.87 174.58,145.87 176.99,143.46 ; 181.18,143.46 181.26,143.46 181.37,143.56 181.37,143.92 181.49,144.03 181.65,144.03 181.77,143.92 181.77,143.46 181.89,143.34 182.06,143.34 182.18,143.46 182.18,143.91 182.3,144.03 182.47,144.03 182.59,143.91 182.59,143.46 182.71,143.34 183.34,143.34 183.46,143.46 183.46,144.75 185.58,146.86 185.58,147.27 v1(185.2,147.65)
  IN1 w0.14: 176.99,143.46 v1(180.8,143.46) 181.18,143.46
  IN3 w0.102: v1(180.92,128.73) 181.11,128.73 181.26,128.88 181.26,130.36 180.99,130.64 180.99,131.07 180.4,131.66 180.4,133.6 181.22,134.42 181.22,134.76 181.71,135.26 181.71,135.39
  IN3 w0.157: 181.71,135.39 181.71,140.61 181.59,140.73 180.49,140.73 180.36,140.86 180.36,142.7 180.49,142.83 181.56,142.83 181.69,142.96 181.69,145.88 181.56,146 181.05,146 180.92,145.88 180.92,143.59 v1(180.8,143.46)
  BOTTOM w0.102: v1(172.97,147.65) 172.87,147.65 172.55,147.33 172.55,146.88 172.11,146.44 172.11,145.11 172.16,145.06 172.4,145.06 UV19.N8 ; v1(185.2,147.65) 185.62,148.07 185.62,148.43 185.95,148.77 185.95,149.68 UV21.N8 ; UV1.H17 181.28,129.09 v1(180.92,128.73)
A_BA2: length 53.6
  TOP w0.102: UV20.M3 186.38,149.11 185.76,148.48 185.76,148.09 v1(186.19,147.65) ; UV18.M3 171.79,146.2 172.41,146.82 172.41,147.22 v1(171.98,147.65)
  IN1 w0.102: v1(186.19,147.65) 186,147.65 185.88,147.78 185.88,147.94 185.81,148.01 185.81,148.64 185.68,148.77 184.89,148.77 184.69,148.97 184.55,148.97 184.25,148.67 184.09,148.67 183.97,148.79 183.97,148.96 184.26,149.25 184.26,149.4 182.81,150.85 181.18,150.85 ; 176.99,150.85 174.85,150.85 174.64,150.64 174.57,150.64 171.97,148.04 171.97,147.66 v1(171.98,147.65)
  IN1 w0.14: 176.99,150.85 179.74,150.85 v1(179.78,150.81) 179.86,150.73 180.67,150.73 180.8,150.85 181.18,150.85
  IN3 w0.102: v1(182.11,129.69) 182.53,130.1 182.53,132.05 182.96,132.48 182.96,133.49 183.4,133.93 183.4,135.39
  IN3 w0.157: v1(179.78,150.81) 179.44,150.81 179.32,150.68 179.32,150.11 179.44,149.99 180.15,149.99 180.29,150.13 180.29,150.51 180.42,150.63 180.94,150.63 181.07,150.51 181.07,150.12 181.18,150 181.57,150 182.64,148.94 182.64,147.02 183.37,146.29 183.37,135.42 183.4,135.39
  BOTTOM w0.102: v1(186.19,147.65) 186.51,147.65 186.57,147.59 186.57,146.19 186.43,146.05 UV21.M3 ; v1(171.98,147.65) 171.66,147.65 171.6,147.72 171.6,149.06 UV19.M3 ; UV1.H16 182.66,129.14 v1(182.11,129.69)
AC_BATT: length 24.1
  TOP w0.102: v1(190.72,105.16) v2(189.6,106.27) 189.05,106.83 RV85.2
  IN3 w0.102: v1(182.01,112.33) 182.4,112.72 183.83,112.72 184.67,113.57 186.09,113.57 186.34,113.32 186.34,112.62 188.05,110.9 188.05,109.42 188.65,108.82 188.65,108.24 190.72,106.18 v1(190.72,105.16)
  BOTTOM w0.102: v1(182.01,112.33) 181.64,112.69 UV1.AH17 ; v1(190.72,105.16) 189.94,104.38 RV73.2 189.78,102.08 QV14.3
AC_PRESENT: length 34.5
  IN3 w0.084: v1(125.18,110.39) 125.18,110.95 124.62,111.52 124.62,117.42 125.5,118.31 129.12,118.31 129.12,118.31 129.43,118.31 129.43,118.31 130.46,118.31 131.66,119.52 135.41,119.52 135.6,119.33 136.17,119.33 136.24,119.39 v1(137.51,119.39)
  BOTTOM w0.089: v1(137.51,119.39) 137.51,119.58 137.92,120 ; v1(125.18,110.39) 125.18,110.17 125.65,109.7 UC1.AJ8
  BOTTOM w0.102: RC32.2 143.46,114.69 DH1.2 144.25,116.45 143.54,117.16 143.54,118.72 143.41,118.84 143.16,118.84 142.78,119.23 142.27,119.23 140.75,120.74 v2(140.42,120.74) 140.04,120.74 139.37,120.07 137.99,120.07 137.92,120
ACDET: length 4.6
  TOP w0.102: v2(171.16,165.35) 171.34,165.53 PR723.1
  TOP w0.254: PU701.6 171.01,168.43 PC711.2 PR711.2 PR723.1
ACDRV: length 29.4
  TOP w0.254: v1(168.88,166.63) 168.66,166.85 168.66,166.9 168.49,167.07 PU701.4
  IN3 w0.254: v1(144.48,163.89) 166.32,163.89 168.88,166.44 v1(168.88,166.63)
  BOTTOM w0.102: v2(170.49,167.19) 170.45,167.15 169.71,167.15 169.19,166.63 v1(168.88,166.63)
  BOTTOM w0.254: v1(144.48,163.89) PR703.2
ACIN: length 255.9
  TOP w0.102: v1(192.5,46.62) 192.43,46.55 186.14,46.55 184.1,44.51 UE1.110 180.72,44.51 180.39,44.84 CE18.2
  TOP w0.254: v1(129.63,160.54) v4(129.05,160.54) 127.85,160.54 126.9,161.49 126.9,169.54 126.9,169.54 126.9,171.1 127.15,171.35 127.49,171.35 127.74,171.1 128.55,171.1 PR1.1 ; PR707.2 PR712.1 170.02,166.57 v1(169.89,166.7) 169.75,166.83 169.36,166.83 168.99,167.21 PU701.5
  IN1 w0.127: 169.37,87.55 154.46,102.46 154.46,104.28 153.39,105.36 153.39,108.15 149.71,111.83 149.15,111.83 147.64,113.34 147.64,113.9 144.57,116.97 v1(144.57,118.46) ; 169.37,87.55 169.79,87.13 v1(171.31,87.13) ; 169.37,87.55 173.75,87.55 178.78,82.51 182.8,82.51 189.55,75.76 189.55,65.73 190.62,64.65 190.62,57.62 192.12,56.12 192.12,55.1 192.81,54.4 192.81,50.6 192.67,50.45 192.67,46.78 v1(192.5,46.62)
  IN2 w0.254: v1(129.63,160.54) 130.45,159.73 130.45,146.07 137.7,138.82 137.7,137.72 144.57,130.85 v1(144.57,118.46)
  IN3 w0.254: v1(169.89,166.7) 164.75,161.55 157.7,161.55 157.19,161.05 132.49,161.05 131.98,160.54 v1(129.63,160.54)
  BOTTOM w0.102: v1(144.57,118.46) 144.25,118.14 DH1.1 ; v1(171.31,87.13) 173.82,87.13 174.91,88.21 178.15,88.21 179.1,89.16 184.74,89.16 185.72,90.14 188.33,90.14 189.98,91.8 189.98,96.02 189.35,96.65 188.93,96.65 187.77,97.81 187.77,99.42 188.05,99.7 188.05,101.54 188.16,101.65 RV250.1
ACIN_65W: length 82.2
  TOP w0.102: v1(180.18,45.4) 180.27,45.31 UE1.108
  IN1 w0.127: v1(187.28,80.57) 187.28,80.54 190.91,76.91 190.91,66.16 191.98,65.1 191.98,58.06 194.56,55.47 194.56,54.28 195.41,53.43 195.41,52.4 194.97,51.97 194.97,49.92 195.24,49.66 195.24,48.11 195.52,47.83 195.52,46.49 v1(195.14,46.11)
  IN3 w0.127: v1(185.74,89.59) 185.58,89.42 185.58,83.35 187.28,81.65 v1(187.28,80.57)
  BOTTOM w0.102: RV250.2 189.13,102.19 QV14.2 189.13,100.97 190.4,99.7 190.4,96.97 190.21,96.78 190.21,91.7 188.1,89.59 v2(187.03,89.59) v1(185.74,89.59) ; v1(195.14,46.11) 190.44,46.11 189.36,45.03 184.88,45.03 184.18,44.33 181.24,44.33 v1(180.18,45.4)
ACOFF: length 162.6
  TOP w0.102: UE1.27 193.59,37.28 v1(193.45,37.41)
  TOP w0.254: PQ706.2 135.14,164.91 v2(134.91,164.67) v1(134.52,164.29)
  IN2 w0.254: v1(193.45,37.41) 193.45,37.73 192.81,38.36 191.35,38.36 189.67,40.05 189.67,47.95 190.74,49.03 190.74,51.72 191.27,52.26 191.27,53.75 189.89,55.13 189.89,74.98 183.92,80.95 183.92,82.3 177.63,88.6 177.63,90.61 176.47,91.77 175.35,91.77 173.93,93.19 173.93,94.31 172.19,96.05 168.38,96.05 163.82,100.61 163.82,102.71 163.13,103.4 161.44,103.4 155.63,109.21 155.63,111.05 153.55,113.13 153.55,117.68 149.61,121.62 149.61,129.07 140.24,138.44 140.24,139.65 133.09,146.8 133.09,161.01 133.67,161.6 133.67,163.43 v1(134.52,164.29)
AD_BID0: length 12.5
  TOP w0.102: UE1.75 191.59,50.47 192.34,49.72 193.87,49.72 194.55,49.03 195.02,49.03 196.22,50.23 196.55,50.23 197.2,50.87 v2(197.2,52.75) RE3.1 CE8.1 RE5.2
ADP_I: length 250.8
  TOP w0.102: UE1.65 195.59,50.53 195.8,50.32 195.91,50.32 v1(196.24,50.65)
  TOP w0.254: PR23.2 132.87,179.91 v2(133.62,180.65) 136.17,183.21 136.17,184.1 137.63,185.56 140.89,185.56 141.91,186.57 146.41,186.57 147.27,185.72 149.98,185.72 154.26,181.44 159.27,181.44 159.43,181.28 160.32,180.43 161.36,179.77 162.18,179.45 163.91,177.73 172.33,177.73 172.49,177.56 172.49,176.65 173.89,175.25 173.89,173.43 173.67,173.21 173.67,169.53 173,168.86 v1(172.88,168.86) 172.8,168.93 PU701.7
  IN2 w0.127: v1(214.7,51.12) 214.73,51.12 214.28,51.57 214.28,53.21 220.75,59.69 220.75,82.53 223.66,85.43 223.66,96.82 224.21,97.36 224.21,108.84 222.53,110.52 222.53,123.96 222.53,123.96 222.53,124.11 223.31,124.88 223.31,145.67 209.11,159.87 199.06,159.87 193.75,165.17 190.47,165.17 188.56,163.27 181.03,163.27 179.5,161.75 173.76,161.75 172.49,163.02 172.49,168.48 v1(172.88,168.86)
  BOTTOM w0.102: v1(214.7,51.12) 214.45,51.12 214.07,50.75 212.7,50.75 210.69,48.74 201.08,48.74 201.02,48.8 200.15,48.8 198.31,50.65 v1(196.24,50.65) 196.09,50.8 PC720.2
ADPIN:
  vias: v3(138.5,172.6) v3(138.5,171.97) v3(138.59,177.62) v3(138.59,176.99) v3(139.13,172.6) v3(139.13,171.97) v3(139.22,177.62) v3(139.22,176.99) v4(137.67,176.99) v4(138.65,173.24) v4(140.02,177.62)
AUD_HP_OUT_L_CN: length 14.9
  TOP w0.254: LA8.1 22.86,11.64 CA39.1 19.94,11.64 18.52,10.22 DA10.3 15.27,10.22 14.57,9.52 v2(14.57,7.88) 14.06,7.38 12.46,7.38 JHP.1
AUD_HP_OUT_R_CN: length 23.1
  TOP w0.254: JHP.2 7.15,18.49 13.14,18.49 14.57,17.06 14.57,13.16 15.81,11.91 16.04,12.14 DA10.2 16.74,12.85 19.82,12.85 CA33.1 v2(21.29,12.57) 23.36,12.57 LA9.1
B+: length 374
  TOP w2.54: 219.74,88.19 223.31,91.76 223.31,108.02 222.47,108.86 222.47,124.41 225.14,127.07 ; 135.54,161.43 136.24,162.13 139.54,162.13 141.32,163.9 141.32,169.62
  IN1 w2.54: 225.14,125.55 222.53,122.95 222.53,112.01 223.46,111.08 223.46,91.05 221.14,88.72 218.28,88.72
  IN3 w2.54: 163.99,179.08 160.24,179.08 157.64,176.48 153.19,176.48 152.49,177.18 146.21,177.18 145.57,176.54
  BOTTOM w2.54: 164.81,178.26 159.67,178.26 157.89,176.48 147.16,176.48
  BOTTOM w3.048: 167.03,23.51 167.03,29.44 162.8,33.67 133.25,33.67 ; 169.13,19.89 176.37,12.65 195.86,12.65 202.72,5.79 216.12,5.79 223.93,13.6 223.93,46.49 221.15,49.27 221.15,75.18 218.17,78.16 218.17,83.95
  BOTTOM w4.572: 193.77,172.1 193.77,162.63 197.7,158.7 204.75,158.7 208.28,155.17 217.04,155.17 220.31,151.9 220.31,148.41 226.41,142.31 226.41,133.81
  vias: v1(215.82,87.56) v1(216.18,88.02) v1(216.24,87.14) v1(216.24,86.29) v1(216.69,87.62) v1(216.66,86.71) v1(216.66,85.87) v1(217.11,87.2) v1(217.08,86.29) v1(217.53,86.78) v1(218.85,175.65) v1(219.8,175.59) v1(220.37,175.46) v1(220.44,174.86) v1(227.49,127.46) v1(227.49,126.82) v1(228.12,127.46) v1(228.12,126.82) v1(228.12,126.19) v1(228.12,125.55) v1(228.76,127.46) v1(228.76,126.82) v1(228.76,126.19) v1(228.76,125.55) v3(135.41,159.14) v3(135.41,158.13) v3(135.41,157.11) v3(136.05,158.13) v3(136.05,157.11) v3(142.4,175.84) v3(142.4,174.83) v3(142.4,173.81) v3(142.4,172.79) v3(143.16,175.84) v3(143.16,174.83) v3(143.16,173.81) v3(143.16,172.79) v3(143.16,171.78) v3(143.16,170.76) v3(143.79,175.84) v3(143.79,174.83) v3(143.79,173.81) v3(143.79,172.79) v3(143.79,171.78) v3(143.79,170.76) v3(166.53,179.84) v3(166.53,179.21) v3(167.16,179.84) v3(167.16,179.21) v3(167.8,179.84) v3(167.8,179.21) v3(168.43,179.84) v3(168.43,179.21) v3(193.26,177.49) v3(193.26,176.86) v3(193.26,176.22) v3(193.89,177.49) v3(193.89,176.86) v3(193.89,176.22) v3(194.53,177.49) v3(194.53,176.86) v3(194.53,176.22) v4(141.07,173.72)
B+_1.05V:
  vias: v2(140.54,159.76)
B+_VDDCI:
  vias: v2(176.88,182.17)
B-RAMP: length 5.1
  TOP w0.102: v2(88.3,142.45) 87.79,141.93 v1(87.79,140.6)
  TOP w0.254: PR509.2 87.6,140.41 v1(87.79,140.6)
  BOTTOM w0.203: PU501.11 88.62,139.95 87.96,140.6 v1(87.79,140.6)
  BOTTOM w0.254: PR507.1 87.72,140.66 v1(87.79,140.6)
B_BA0: length 58.8
  TOP w0.102: v1(210.39,116.61) 210.55,116.61 211.11,116.04 211.58,116.04 211.68,115.94 212.53,115.94 212.66,116.07 212.66,116.29 212.53,116.42 UV25.M2 ; 194.39,117.35 190.78,117.35 190.07,118.06 189.66,118.06 v1(189.2,118.52) ; UV22.M2 207.73,130.88 208.39,130.88 208.96,130.31 v1(209.12,130.31)
  TOP w0.127: v1(204.64,121.24) 206.32,121.24 206.45,121.11 206.45,120.39 206.32,120.26 203.84,120.26 203.19,119.61 201.34,119.61 201.22,119.48 v2(201.22,119.08) 201.22,117.93 201.09,117.8 198.48,117.8 198.35,117.67 198.35,117.13 198.23,117 198.01,117 197.88,117.13 197.88,117.23 197.75,117.35 197.46,117.35 197.34,117.23 197.34,116.82 197.21,116.69 196.96,116.69 196.83,116.82 196.83,117.23 196.7,117.35 196.42,117.35 196.29,117.23 196.29,116.82 196.16,116.69 195.91,116.69 195.78,116.82 195.78,117.23 195.66,117.35 194.39,117.35
  IN1 w0.102: v1(210.39,116.61) 210.01,116.23 209.11,116.23 207.61,117.73 205.74,117.73 204.96,118.51 ; 204.96,125.97 209.12,130.13 v1(209.12,130.31)
  IN1 w0.14: 204.96,118.51 204.64,118.83 v1(204.64,121.24) 204.64,125.65 204.96,125.97
  BOTTOM w0.102: UV23.M2 211.83,130.18 210.27,130.18 210.02,129.93 209.5,129.93 v1(209.12,130.31) ; UV1.Y8 189.2,118.95 v1(189.2,118.52) ; v1(210.39,116.61) 210.01,116.99 209.5,116.99 209.25,116.74 207.68,116.74 UV24.M2
B_BA1: length 56.4
  TOP w0.102: UV22.N8 211.78,130.08 210.51,130.08 v1(209.75,129.32) ; v1(209.75,117.6) 209.37,117.22 208.68,117.22 208.31,116.84 207.73,116.84 UV25.N8
  IN1 w0.102: 205.63,125.3 205.63,125.82 208.72,128.92 209.35,128.92 v1(209.75,129.32) ; 205.63,121.62 205.63,119.75 206.49,118.89 207.15,118.89 208.82,117.22 209.37,117.22 v1(209.75,117.6)
  IN1 w0.14: 205.63,125.3 205.63,123.59 v1(205.62,123.59) 205.62,121.63 205.63,121.62
  IN3 w0.102: 194.39,119.5 192.89,118 188.29,118 v1(187.78,117.49)
  IN3 w0.157: 194.39,119.5 194.62,119.74 200.35,119.74 200.5,119.89 200.5,121.09 200.65,121.24 200.98,121.24 201.13,121.09 201.13,119.89 201.28,119.74 201.61,119.74 201.76,119.89 201.76,121.58 201.92,121.74 203.31,121.74 203.47,121.58 203.47,121.3 203.62,121.14 203.89,121.14 204.04,121.3 204.04,121.52 204.19,121.67 205.46,121.67 205.61,121.83 205.61,122.1 205.46,122.25 204.87,122.25 204.71,122.41 204.71,122.67 204.87,122.83 205.46,122.83 205.61,122.98 205.61,123.58 v1(205.62,123.59)
  BOTTOM w0.102: UV24.N8 211.78,116.84 210.87,116.84 210.53,117.18 210.17,117.18 v1(209.75,117.6) ; v1(187.78,117.49) 187.78,117.81 UV1.AA9 ; v1(209.75,129.32) 209.33,129.74 208.98,129.74 208.64,130.08 207.73,130.08 UV23.N8
B_BA2: length 53.8
  TOP w0.102: UV22.M3 208.3,130.5 208.92,129.88 209.32,129.88 v1(209.75,130.31) ; UV25.M3 211.21,116.42 210.58,117.04 210.19,117.04 v1(209.75,116.61)
  IN1 w0.102: 213.19,125.3 213.19,126.06 212.74,126.51 212.74,126.94 212.74,127.72 210.13,130.32 209.76,130.32 v1(209.75,130.31) ; 213.19,121.62 213.19,120.23 210.77,117.81 210.77,117.76 210.77,117.3 210.52,117.05 210.2,117.05 209.76,116.61 v1(209.75,116.61)
  IN1 w0.14: 213.19,125.3 v1(213.19,123.78) 213.19,121.62
  IN3 w0.102: v1(188.34,117.48) 188.84,116.98 190.11,116.98 190.42,117.29 193.71,117.29 194.39,117.97
  IN3 w0.157: 194.39,117.97 195.07,118.66 205.27,118.66 205.82,119.21 206.64,119.21 208.55,121.11 211.09,121.11 213.19,123.22 v1(213.19,123.78)
  BOTTOM w0.102: UV1.AA8 188.86,118 v1(188.34,117.48) ; v1(209.75,130.31) 210.13,130.69 211.16,130.69 UV23.M3 ; UV24.M3 208.34,116.23 209.37,116.23 v1(209.75,116.61)
BAT_ALERT: length 11.6
  TOP w0.254: v1(141,183.97) 140.62,183.97 140.24,183.59 PD2.2 140.24,183.2 140.74,182.7 v1(140.74,182.45)
  BOTTOM w0.102: v2(138.85,181.98) 138.85,182.97 139.02,183.15 PD1.4
  BOTTOM w0.254: v1(140.74,182.45) 140.74,182.95 140.55,183.15 PD1.4 ; v1(141,183.97) 141,186.18 PBATT.3
BATT+: length 1.6
  BOTTOM w0.102: PC7.1 158.07,181.05 v2(159.2,179.93)
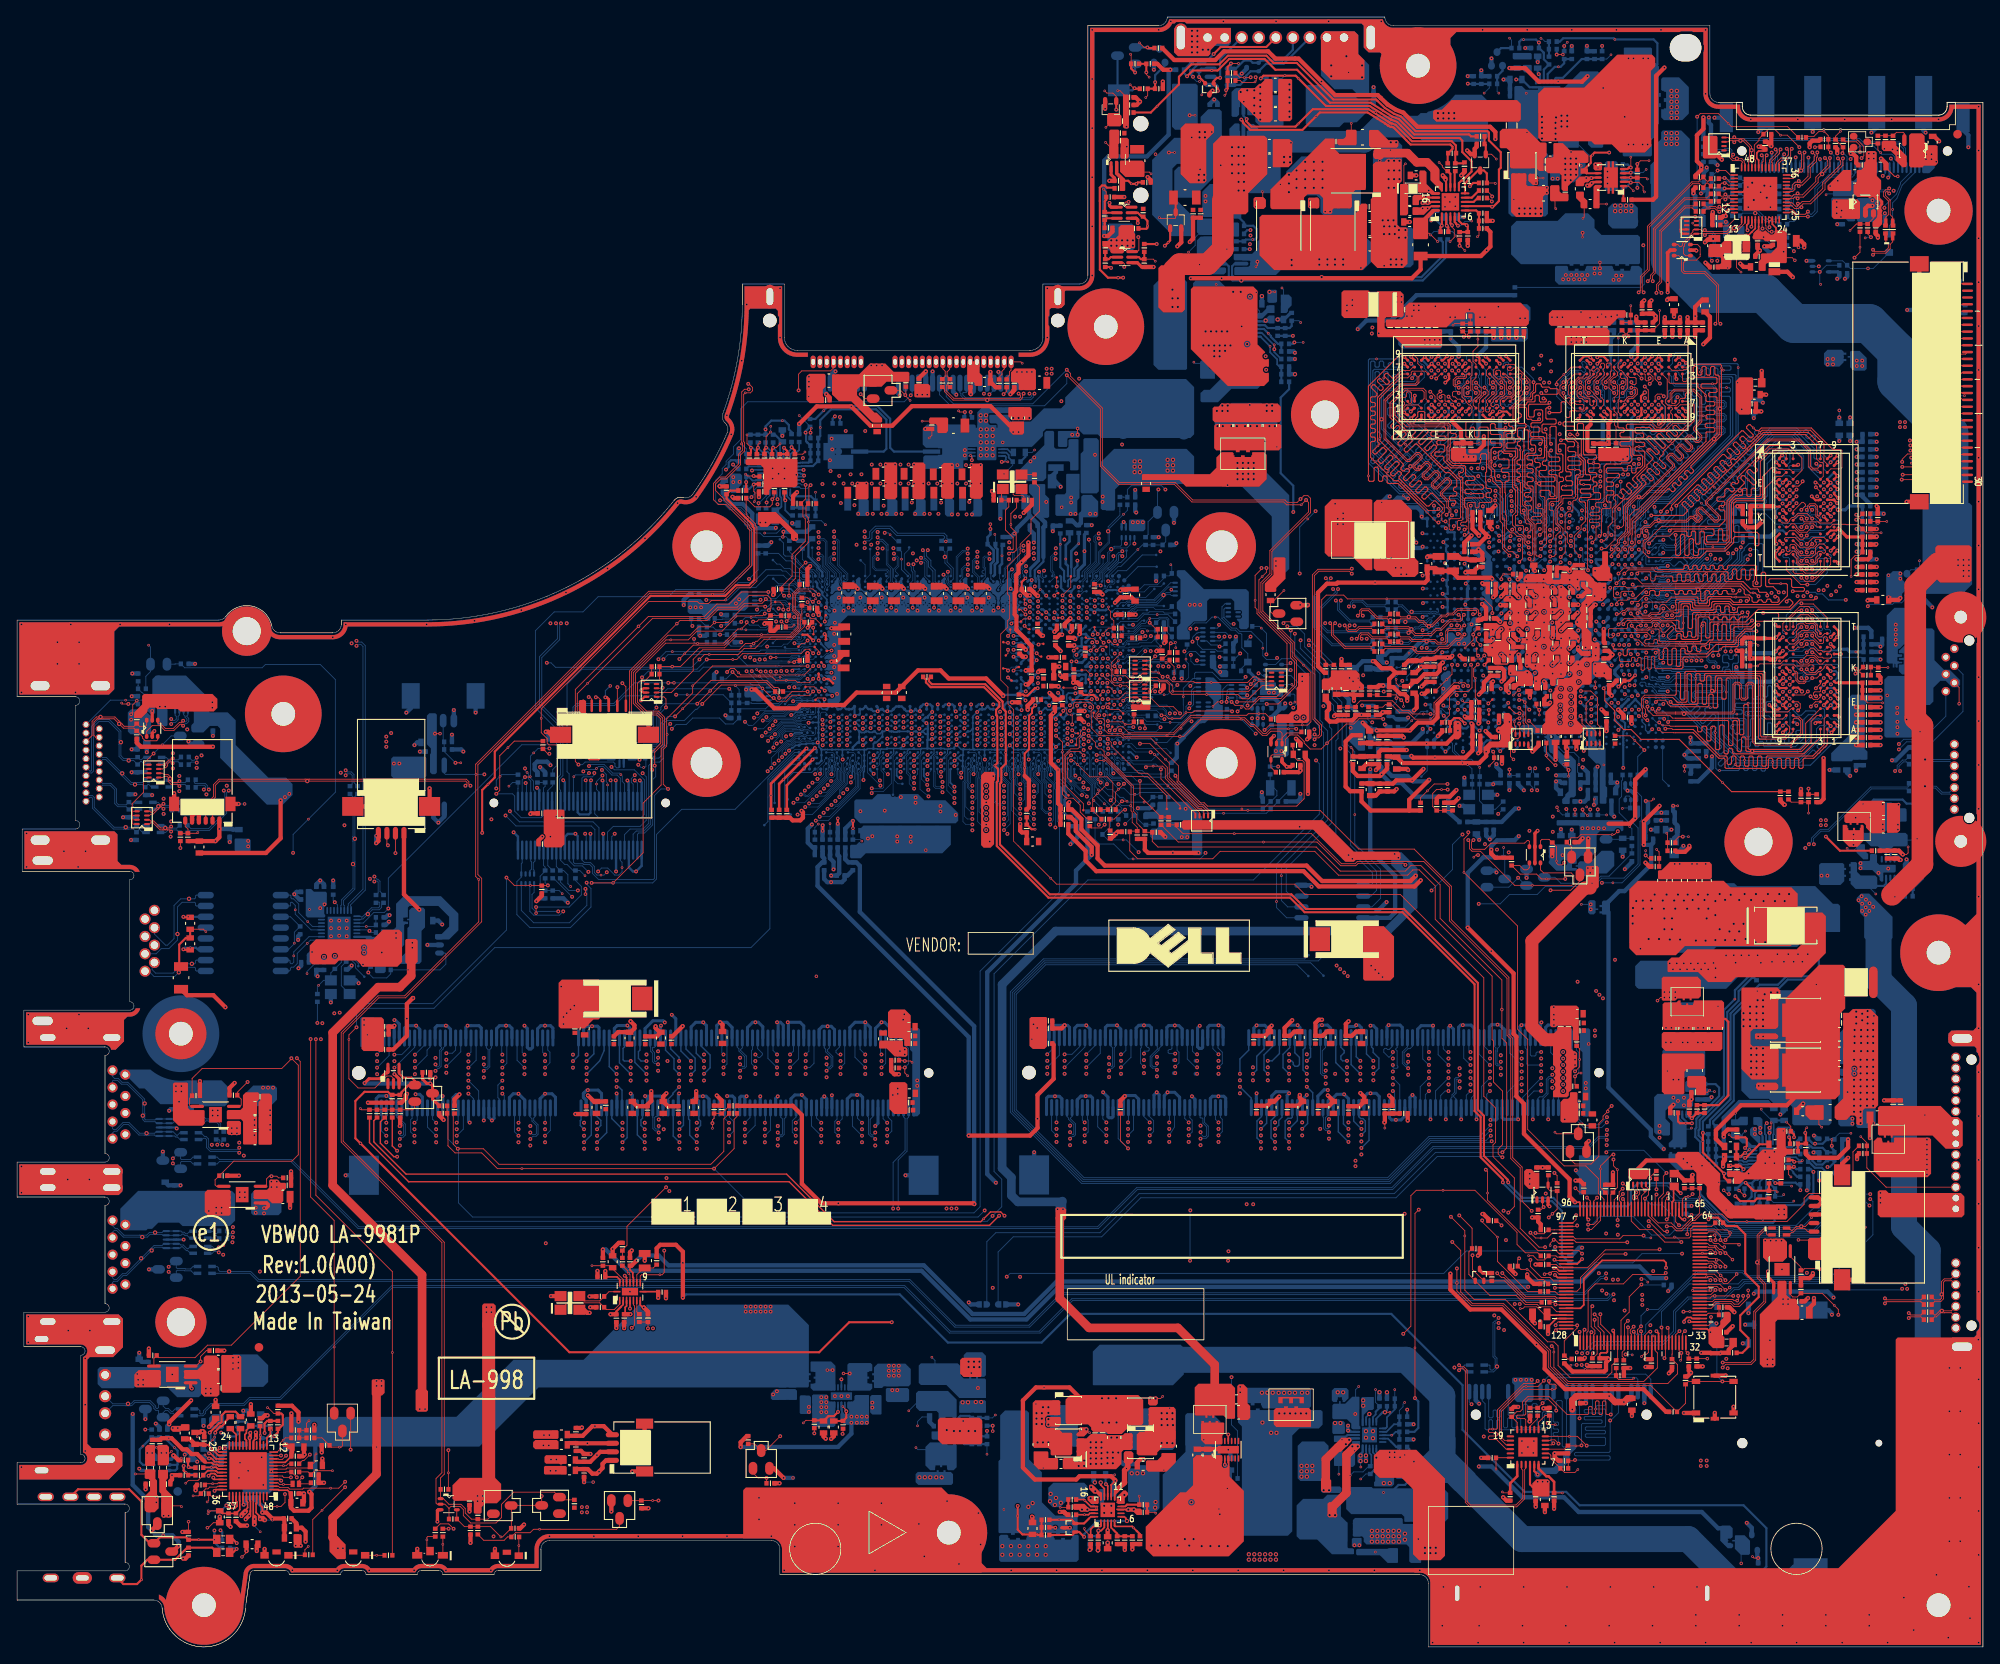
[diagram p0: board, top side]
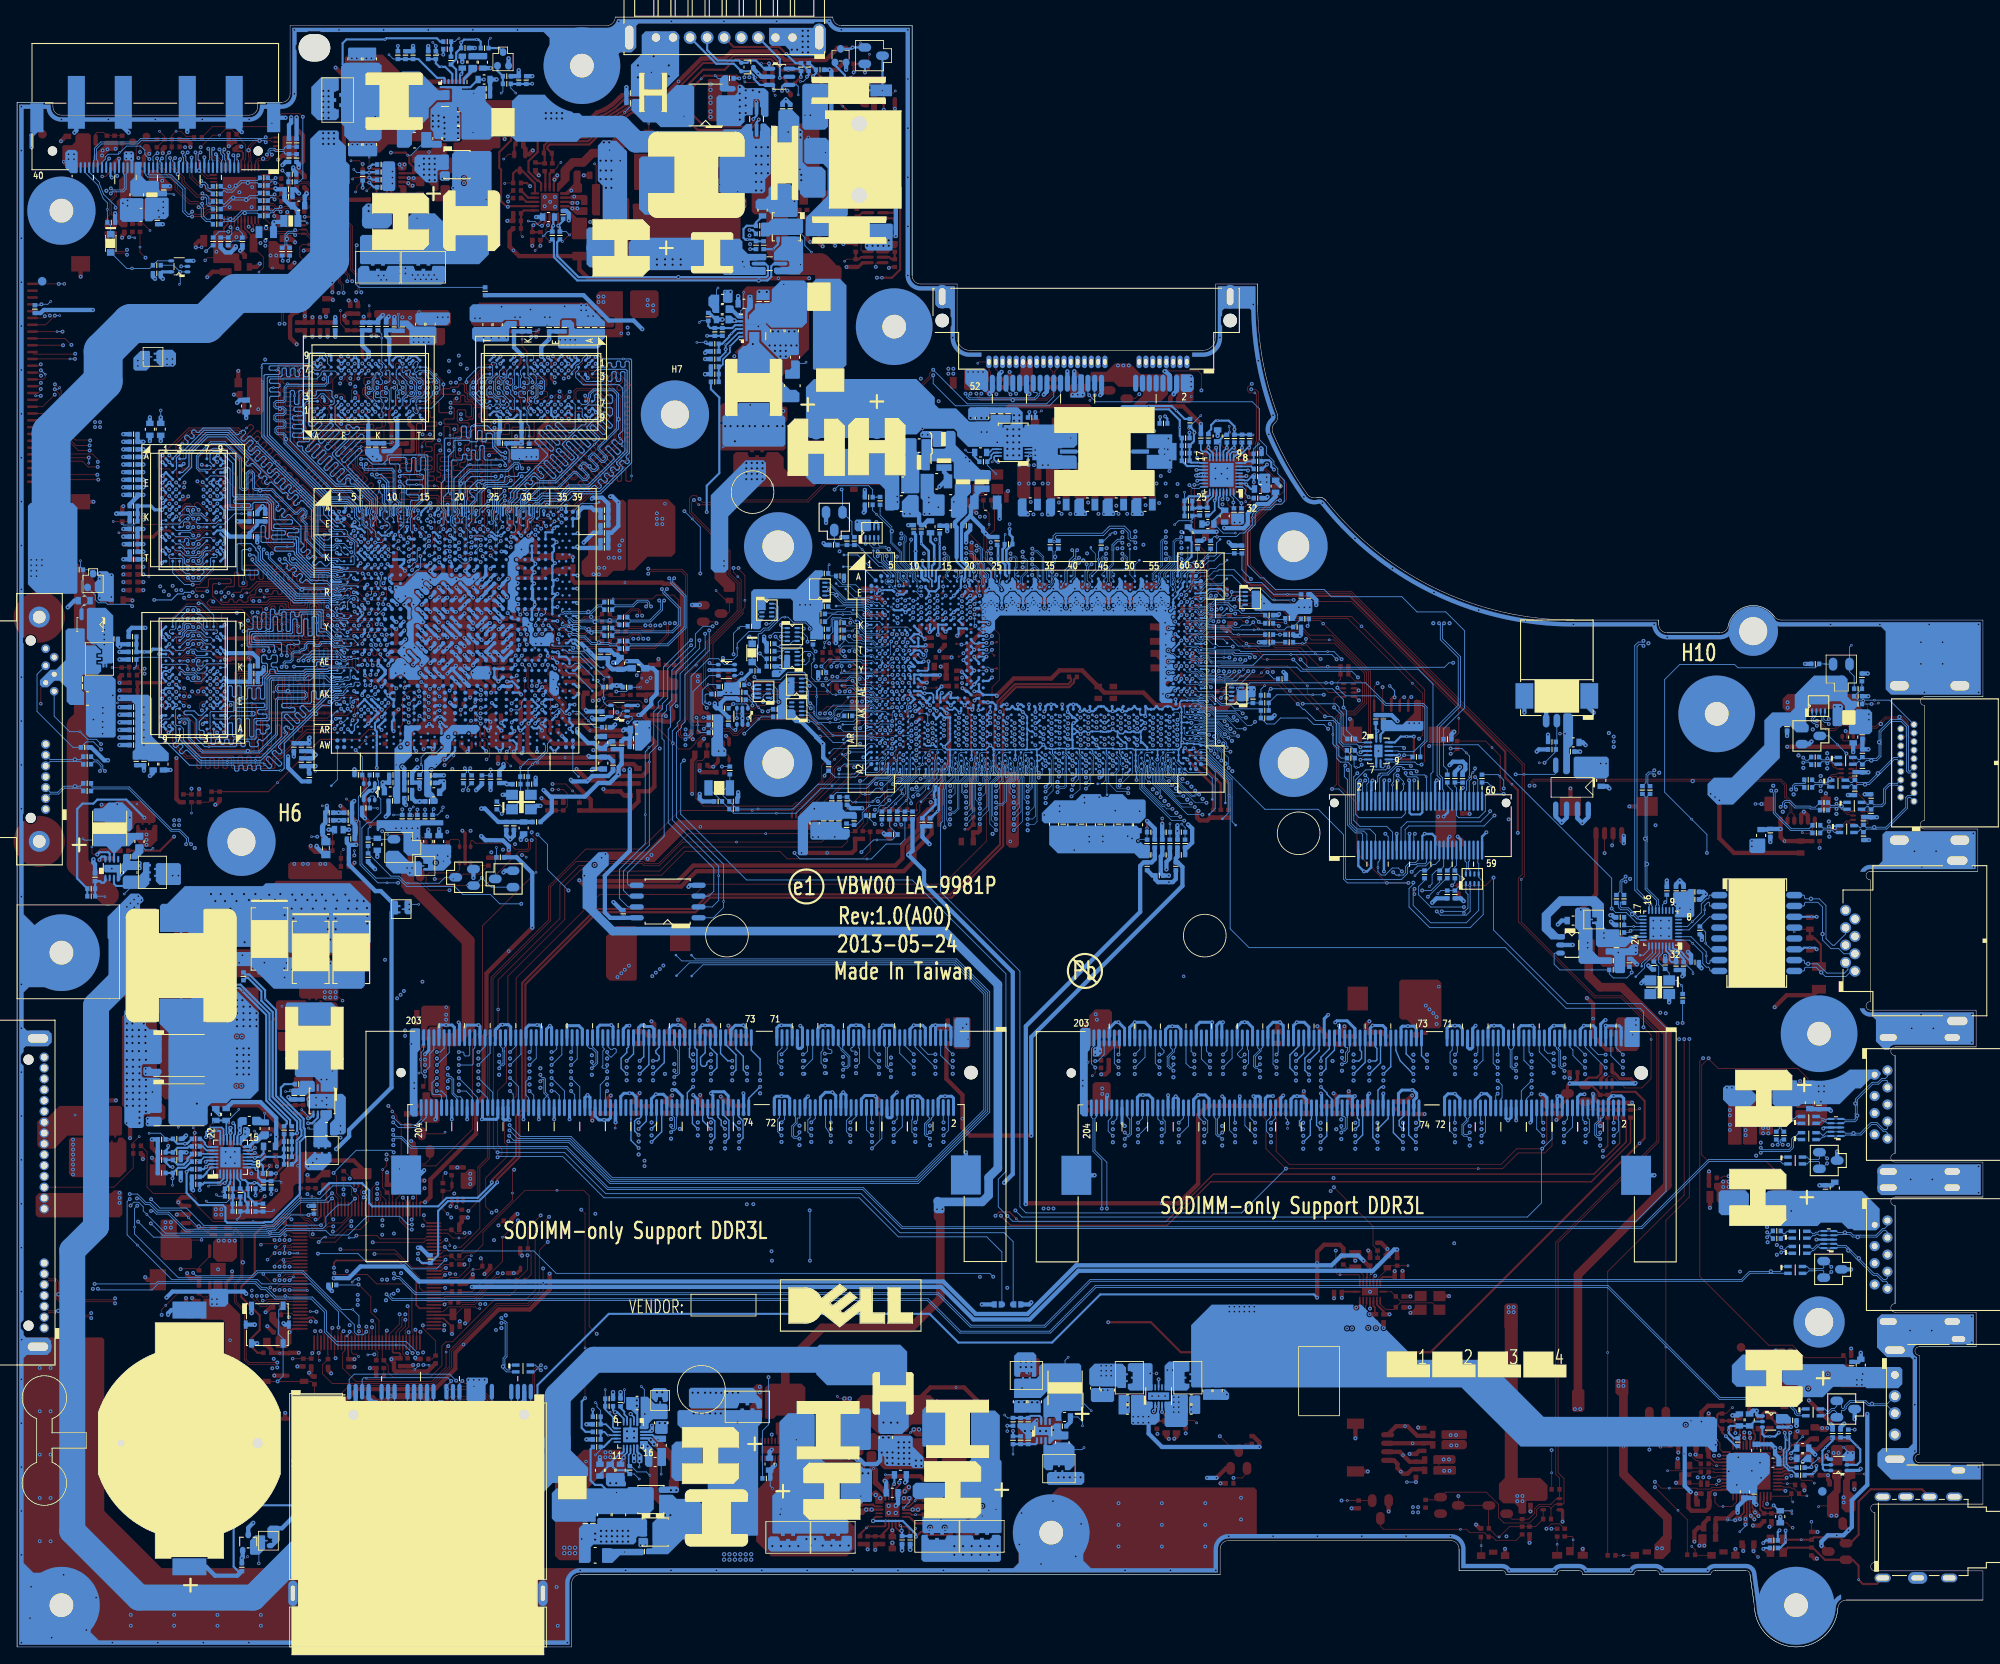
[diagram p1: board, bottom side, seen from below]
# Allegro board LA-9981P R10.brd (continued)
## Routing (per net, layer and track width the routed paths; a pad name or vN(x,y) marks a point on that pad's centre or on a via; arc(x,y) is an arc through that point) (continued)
BATT++:
  vias: v2(156.06,184.61) v3(154.02,185.43) v3(154.02,184.16) v3(155.79,186.51) v3(157.64,185.43) v3(157.64,184.03)
BATT_CHG_LED#: length 172
  TOP w0.102: v1(184.14,48.94) 184.51,48.94 185.59,50.01 UE1.90 ; RD16.1 v1(50.57,13.86)
  IN1 w0.127: v1(50.57,13.86) 50.57,13.92 51.02,14.36 58.19,14.36 58.87,15.04 77.09,15.04 106.26,44.21 132.94,44.21 136.62,40.52 160.41,40.52 167.12,33.82 182.62,33.82 v1(183.37,33.06)
  IN2 w0.127: v1(183.37,33.06) 181.89,34.54 181.89,46.69 v1(184.14,48.94)
  BOTTOM w0.102: v2(183.79,32.53) 183.37,32.95 v1(183.37,33.06)
BATT_LOW_LED#: length 174.5
  TOP w0.102: v1(183.99,52.68) 184.39,52.29 UE1.93 ; v1(51.16,13.86) 50.59,14.43 49.58,14.43 RD17.1
  IN1 w0.127: v1(182.78,33.06) 182.34,33.5 167.08,33.5 160.31,40.27 136.51,40.27 132.83,43.95 106.36,43.95 77.2,14.79 58.97,14.79 58.04,13.86 v1(51.16,13.86)
  IN2 w0.127: v1(183.99,52.68) 183.99,51.19 181.64,48.84 181.64,34.21 v1(182.78,33.06)
  BOTTOM w0.102: v2(182.11,33.02) 182.14,33.06 v1(182.78,33.06)
BATT_PRS: length 36.2
  TOP w0.254: PBATT.5 146.41,187.59 141.06,187.59 v1(140.24,186.76) ; PC14.1 v1(133.57,164.49)
  IN1 w0.254: v1(137.82,184.1) 137.82,181.05 133.57,176.79 v1(133.57,164.49)
  BOTTOM w0.102: v1(137.82,184.1) 137.82,183.97 138.24,183.55 v2(138.59,183.55)
  BOTTOM w0.254: v1(137.82,184.1) 137.63,184.29 PR15.1 137.63,184.8 138.52,185.68 PR17.2 139.17,185.7 v1(140.24,186.76)
BATT_TEMP: length 213.4
  TOP w0.102: CE9.2 198.6,49.31 UE1.63 196.44,49.31 196.16,49.02 196.16,48.15 195.96,47.95 193.2,47.95 191.23,49.92 v1(191.23,49.93)
  TOP w0.254: v1(137.13,184.16) 137.8,184.84 v2(140.02,184.84) 140.71,184.84 142.07,186.19 146.21,186.19 147.48,184.92 150.02,184.92 153.88,181.06 158.62,181.06 160.08,180.13 160.08,180.13 161.19,179.43 161.97,179.13 163.75,177.34 170.17,177.34 170.4,177.11 PC723.2
  IN2 w0.254: v1(191.23,49.93) 191.23,49.92 191.66,50.35 191.66,53.91 190.27,55.29 190.27,75.14 184.31,81.11 184.31,82.46 178.01,88.76 178.01,90.77 172.34,96.43 168.54,96.43 164.2,100.77 164.2,102.87 163.29,103.78 161.59,103.78 156.01,109.37 156.01,111.21 153.93,113.29 153.93,117.84 151.95,119.82 151.95,127.27 140.62,138.6 140.62,139.8 133.63,146.79 133.63,161.02 134.05,161.44 134.05,163.05 135.47,164.48 135.47,182.51 v1(137.13,184.16)
  BOTTOM w0.254: PR15.2 137.53,185.7 PR16.1 136.76,184.53 v1(137.13,184.16)
BBS_BIT: length 14.2
  BOTTOM w0.076: RC123.1 133.11,119.71 131.73,119.71 130.82,118.8 129.46,118.8 129.31,118.95 129.31,119.14 128.87,119.58 126.05,119.58 UC1.L8
  BOTTOM w0.089: RC123.1 133.94,120.53 134.71,120.53 134.81,120.44 134.81,118.97 RC119.2 135.33,118.15 135.8,117.68 v2(135.8,117.15)
BEEP#: length 178.5
  TOP w0.102: UE1.23 191.99,34.75 192.24,34.49 192.24,32.71 190.65,31.12 181.79,31.12 180.11,32.8 v2(180.11,34.57) 180.11,35.02 v1(179.86,35.27) ; v1(39.09,23.13) DA8.2
  IN1 w0.127: v1(39.09,23.13) 39.14,23.18 47.28,23.18 51.94,27.84 85.96,27.84 104.61,46.49 139.09,46.49 143.98,41.6 160.93,41.6 167.26,35.27 v1(179.86,35.27)
BKOFF#: length 164.1
  TOP w0.102: v1(183.42,46.11) 183.02,46.51 UE1.105
  IN3 w0.127: v1(183.42,46.11) 187.21,46.11 188.12,47.02 192.39,47.02 192.4,47.04 193.97,47.04 194.86,47.93 197.44,47.93 198.88,49.37 209.92,49.37 210.59,48.69 215.64,48.69 219.06,52.11 219.06,61.57 219.7,62.21 219.7,75.41 217.19,77.91 217.19,84.93 218.57,86.31 218.57,87.54 216.74,89.37 215.25,89.37 213.22,91.4 213.22,101.49 216.94,105.21 216.94,121.12 217.45,121.63 217.45,153.49 211.28,159.66 v1(211.28,161.22)
  BOTTOM w0.102: UX2.1 v1(211.28,161.22) ; v1(211.28,161.22) 211.28,159.86 v2(211.38,159.76) ; v1(211.28,161.22) 212.06,162 RX50.1
BST:
  vias: v1(165.1,170.05)
BST_1.05V: length 3.1
  BOTTOM w0.102: PU300.6 145.59,156.65 145.3,156.94 145.3,158.75 v2(145.24,158.82)
BST_1.35V: length 1.4
  BOTTOM w0.102: PC200.1 v2(154.91,20.26)
BST_3V: length 3.2
  TOP w0.102: PR103.2 v2(131.52,17.69)
  TOP w0.203: PU100.9 129.87,16.47 129.93,16.53
  TOP w0.254: 129.93,16.53 130.08,16.68 PR103.2
BST_5V: length 2.5
  TOP w0.203: PU100.17 125.84,16.47 v2(125.14,17.16) 125.03,17.28 PR111.1
BST_+1.2VSP: length 1.2
  TOP w0.102: PR1101.1 v2(186.29,169.17)
BST_CHGA: length 3
  TOP w0.102: PD701.1 162.53,173.71 v2(162.71,173.89)
BST_VGA_CORE: length 0.9
  BOTTOM w0.102: v2(202.57,60.49) 202.2,60.12 202.2,59.79
BT_LED#: length 220.1
  TOP w0.102: 50.62,16.25 50.13,16.74 UD1.2 49.24,16.74 49.1,16.88 49.1,19.74 49.79,20.43 49.79,47.4 37.99,59.21 37.99,72.03 42.3,76.34 45.43,76.34 54.11,85.01 v2(54.11,89.98) 53.75,90.34 53.75,103.49 74.03,123.77 82.77,123.77 85.87,126.87 85.87,130.94 85.63,131.18 85.63,131.4 83.08,133.94 82.19,133.94 81.63,134.5 81.63,136.43 82.36,137.17 83.03,137.17 84.55,138.69 84.55,139.84 85.02,140.31 85.02,141.15 84.93,141.23 84.93,147.14 85.25,147.46 v1(85.75,147.46) ; 50.62,16.25 50.85,16.47 51.93,16.47 52.3,16.1 52.3,15.39 53.15,14.54 56.14,14.54 56.79,15.19 56.79,16.73 58.2,18.15 62.98,18.15 QD19.3 63.88,17.24 RD47.2 ; 50.62,16.25 RD49.1
  IN3 w0.127: v1(113.96,146.86) 113.44,146.34 93.18,146.34 91.68,147.84 86.13,147.84 v1(85.75,147.46)
  BOTTOM w0.102: JMINI.46 114.5,147.4 v1(113.96,146.86)
BT_ON#: length 56.9
  TOP w0.089: v1(134.27,113.74) v2(133.81,114.2) 133.7,114.31 133,114.31 132.68,114.63 RP54.2
  TOP w0.102: RM13.2 115.98,147.24 v1(115.62,146.89)
  IN1 w0.084: v1(134.27,113.74) 133.35,112.82 127.99,112.82 v1(127.78,113.03)
  IN2 w0.089: 122.97,133.14 122.97,132.73 124.11,131.58 124.11,128.86 124.93,128.04 124.93,114.25 125.7,113.49 127.33,113.49 v1(127.78,113.03)
  IN2 w0.127: 122.97,133.14 122.97,135.01 125.12,137.17 125.12,144.22 121.97,147.37 116.11,147.37 v1(115.62,146.89)
  BOTTOM w0.089: UC1.AD5 127.64,112.89 v1(127.78,113.03)
CAPS_LED: length 161.8
  TOP w0.102: v1(184.13,49.52) 184.77,49.52 185.19,49.93 UE1.91 ; v1(225.52,159.82) JKB.1
  IN2 w0.127: v1(216.22,49.87) 216.78,49.87 223.17,56.25 223.17,71.19 229.07,77.09 229.07,86.06 226.07,89.05 226.07,95.82 229.07,98.81 229.07,107.4 225.2,111.26 225.2,120.59 226.69,122.08 226.69,152.19 225.52,153.36 v1(225.52,159.82)
  BOTTOM w0.102: v4(224.86,159.82) v1(225.52,159.82) ; v1(184.13,49.52) 184.57,49.52 185.55,50.49 189.39,50.49 191.58,48.3 193.69,48.3 194.21,48.81 198.83,48.81 199.53,48.11 200.69,48.11 200.76,48.04 214.4,48.04 v1(216.22,49.87)
CASA0#: length 41.6
  TOP w0.102: v1(170,147.65) 169.68,147.65 169.56,147.53 169.56,146.75 169.69,146.62 170.38,146.62 170.45,146.56 170.45,146.12 170.38,146.05 UV18.K3 ; v1(177.26,127.58) 177.26,127.46 177.38,127.33 177.68,127.33 177.8,127.46 177.8,131.68 177.16,132.32 177.16,133.24 177.22,133.3 177.36,133.3 177.48,133.43 177.48,133.68 177.36,133.81 176.86,133.81
  TOP w0.127: 176.86,133.81 176.71,133.97 176.71,134.22 176.84,134.35 177.34,134.35 177.47,134.47 177.47,134.73 177.34,134.85 v2(177.05,134.85) 176.79,134.85 176.67,134.98 176.67,135.23 176.79,135.36 177.3,135.36 177.43,135.49 177.43,135.74 177.3,135.87 176.84,135.87 176.71,136 176.71,139.69 176.99,139.96 177.85,139.96 177.98,140.09 177.98,140.8 177.85,140.92 177.53,140.92 177.4,141.05 177.4,141.52 177.53,141.65 178.63,141.65 178.76,141.52 178.76,141.18 178.63,141.05 v1(178.51,141.05)
  IN1 w0.102: v1(170,147.65) 170.4,147.25 170.4,146.91 171.78,145.52 171.78,144.25 173.18,142.86
  IN1 w0.14: 173.18,142.86 174.2,141.83 177.73,141.83 v1(178.51,141.05)
  BOTTOM w0.102: v1(177.26,127.58) 177.26,127.47 177.65,127.07 178.27,127.07 178.69,127.49 UV1.K20 ; UV19.K3 169.84,149.25 169.55,148.96 169.55,148.19 170,147.75 v1(170,147.65)
CASA1#: length 40.7
  TOP w0.102: UV20.K3 187.91,149.18 187.91,148.86 188.04,148.73 188.42,148.73 188.55,148.61 188.55,148.04 v1(188.17,147.65) ; 182.64,135.39 182.64,134.89 182.45,134.7 181.27,134.7 181.17,134.6 181.17,134.09 180.56,133.47 180.56,131.77 181.18,131.14 181.18,130.46 181.45,130.19 181.45,128.32 v1(180.91,127.79)
  TOP w0.127: v1(180.94,141.48) 181.04,141.58 181.51,141.58 181.63,141.45 181.63,141.44 181.76,141.31 182.4,141.31 182.53,141.19 182.53,140.85 182.4,140.72 181.89,140.72 181.76,140.59 181.76,140.28 181.89,140.15 182.56,140.15 182.68,140.02 182.68,139.69 182.56,139.57 181.89,139.57 181.76,139.44 181.76,139.19 181.89,139.06 183.16,139.06 183.29,138.93 183.29,138.68 183.16,138.55 181.89,138.55 181.76,138.42 181.76,138.17 181.89,138.04 v2(182.58,138.04) 183.08,138.04 183.21,137.92 183.21,137.56 183.08,137.43 182.77,137.43 182.64,137.3 182.64,135.39
  IN1 w0.102: v1(188.17,147.65) 187.76,147.25 187.76,146.78 186.64,145.65 186.64,143.27 186.23,142.86
  IN1 w0.14: v1(180.94,141.48) 181.03,141.4 184.77,141.4 186.23,142.86
  BOTTOM w0.102: v1(188.17,147.65) 188.17,147.56 188.61,147.11 188.61,146.35 188.32,146.05 UV21.K3 ; UV1.K17 181.21,127.49 v1(180.91,127.79)
CASB0#: length 42.6
  TOP w0.102: v1(209.75,132.29) 209.37,132.67 208.76,132.67 208.19,132.1 UV22.K3 ; v1(187.48,121.11) 187.75,121.11 188.15,121.51 188.4,121.51 188.69,121.8 190.26,121.8 190.45,121.99 190.45,122.38 190.57,122.5 193.31,122.5 193.9,123.1 194.39,123.1
  TOP w0.127: 194.39,123.1 196.89,123.1 197.02,122.97 197.02,122.45 197.15,122.32 197.97,122.32 198.1,122.45 198.1,123.02 198.22,123.15 200.88,123.15 200.94,123.09 v2(201.44,123.09) 202.9,123.09 203.03,122.96 203.03,122.76 202.9,122.64 v1(202.71,122.64)
  IN1 w0.102: 204.96,129.11 206.83,130.99 207.03,130.99 207.14,130.88 207.14,130.36 207.24,130.26 207.44,130.26 207.54,130.36 207.54,130.88 207.64,130.99 208.26,130.99 209.17,131.89 209.35,131.89 v1(209.75,132.29)
  IN1 w0.14: 204.96,129.11 204.58,128.74 204.58,127.05 202.86,125.32 202.86,123.18 203.21,122.83 203.21,121.87 203.09,121.75 201.72,121.75 201.59,121.87 201.59,122.08 201.72,122.21 202.58,122.21 202.71,122.34 v1(202.71,122.64)
  BOTTOM w0.102: UV23.K3 211.35,132.45 211.06,132.74 210.27,132.74 209.83,132.29 v1(209.75,132.29) ; v1(187.48,121.11) 187.48,120.71 UV1.W10
CASB1#: length 42.7
  TOP w0.102: UV25.K3 211.32,114.82 210.75,114.25 210.13,114.25 v1(209.75,114.63) ; v1(187.66,118.7) 187.89,118.93 191.05,118.93 191.4,118.58 191.4,118.25 191.28,118.13 190.89,118.13 190.77,118 190.77,117.74 190.89,117.61 191.74,117.61 191.84,117.71 191.84,118.03 191.95,118.13 192.15,118.13 192.25,118.03 192.25,117.71 192.35,117.61 194.39,117.61
  TOP w0.127: 194.39,117.61 197.92,117.61 198.37,118.06 198.67,118.06 198.8,118.19 198.8,119.79 198.93,119.91 199.18,119.91 199.31,119.79 v2(199.31,119.21) 199.31,118.19 199.43,118.06 199.69,118.06 199.81,118.19 199.81,119.79 199.94,119.91 200.2,119.91 200.32,119.79 200.32,118.19 200.45,118.06 200.7,118.06 200.83,118.19 200.83,119.79 200.96,119.91 202.9,119.91 v1(203.34,120.35)
  IN1 w0.102: v1(209.75,114.63) 209.35,115.03 208.88,115.03 207.75,116.16 205.37,116.16 204.96,116.57
  IN1 w0.14: v1(203.34,120.35) 203.34,118.19 204.96,116.57
  BOTTOM w0.102: UV24.K3 208.15,114.48 208.45,114.18 209.23,114.18 209.68,114.63 v1(209.75,114.63) ; UV1.AA10 187.26,118.3 v1(187.66,118.7)
CE_EN: length 177.8
  TOP w0.102: v1(210.71,175.84) 210.75,175.88 RX18.1 ; v1(189.47,36.97) 189.59,36.85 UE1.17
  IN2 w0.127: v1(210.71,175.84) 213.9,175.84 214.41,175.33 214.41,166.37 216.03,164.75 216.03,154.98 225.08,145.93 225.08,121.91 224.18,121.01 224.18,110.84 225.6,109.42 225.6,96.78 225.06,96.24 225.06,88.63 228.05,85.64 228.05,77.51 222.15,71.62 222.15,58.94 216.77,53.56 216.77,52.2 v1(216.31,51.74)
  BOTTOM w0.102: v1(216.31,51.74) 216.63,51.42 v2(216.63,49.22) 216.63,48.42 211.5,43.29 202.78,43.29 202.2,43.88 196.98,43.88 190.88,37.78 190.88,36.93 190.54,36.6 189.84,36.6 v1(189.47,36.97)
CE_EN_R: length 7.2
  TOP w0.102: v1(212.58,175.21) 212.27,175.51 RX18.2 RX20.1 212.27,177.2 v2(211.76,177.71) 211.19,177.71 210.59,177.11 209.78,177.11 RX53.2
  BOTTOM w0.102: JLVDS.18 212.95,174.83 v1(212.58,175.21)
CFD_PWRBTN#_XDP: length 5.2
  BOTTOM w0.102: JXDP1.41 63.2,91.5 RC49.2 64.06,91.03 64.55,90.54 64.55,89.49 v2(64.88,89.16)
CFG0: length 38.1
  IN3 w0.127: v1(76.55,108.23) 77.37,108.23 78.52,109.38 81.15,109.38 82.3,110.54 89.16,110.54 90.48,111.86 v1(90.48,112.52)
  BOTTOM w0.076: UC1.AC60 93.31,112.81 92.83,112.81 92.79,112.84 92,112.84 91.84,112.68 91.46,112.68 91.22,112.91 90.87,112.91 v1(90.48,112.52)
  BOTTOM w0.102: v1(76.55,108.23) 76.19,107.87 v2(76.19,106.99) 76.19,105.89 75.72,105.42 75.72,104.17 75.3,103.74 74.43,103.74 74.03,103.35 74.03,96.57 73.36,95.9 71.85,95.9 71.2,95.25 JXDP1.9
CFG1: length 48.4
  IN3 w0.127: v1(68.1,90.93) 68.17,91 68.17,96.85 71.11,99.78 71.11,102.14 71.86,102.9 71.86,106.87 73.15,108.16 73.15,108.96 75.41,111.22 77.78,111.22 79.12,112.56 82.7,112.56 84.41,114.27 85.37,114.27 v1(85.5,114.4)
  BOTTOM w0.076: 88.91,113.03 90.41,113.03 90.46,113.08 91.29,113.08 91.53,112.84 91.77,112.84 92.06,113.14 UC1.AC62
  BOTTOM w0.102: JXDP1.11 70.7,92.21 70.9,92 v2(70.9,91.38) 70.9,90.89 70.51,90.5 70.06,90.5 69.23,91.32 68.5,91.32 v1(68.1,90.93) ; 88.91,113.03 86.9,113.03 85.53,114.4 v1(85.5,114.4)
CFG2: length 38.3
  IN3 w0.127: v1(86.11,114.41) 85.66,113.97 84.48,113.97 82.82,112.3 79.23,112.3 77.88,110.95 75.75,110.95 75.37,110.56 75.37,109.89 74.71,109.23 74.01,109.23 73.41,108.63 73.41,108.05 72.13,106.76 72.13,102.79 71.97,102.63 71.97,100.28 70.05,98.35 v1(70.05,95.34)
  BOTTOM w0.076: UC1.AC63 91.54,113.25 90.05,113.25 90.04,113.24 89.11,113.24 89.1,113.25 88.93,113.25 88.91,113.26
  BOTTOM w0.102: v1(70.05,95.34) 69.7,95 JXDP1.15 ; 88.91,113.26 87.56,113.26 v2(86.99,113.83) 86.71,113.83 86.12,114.41 v1(86.11,114.41)
CFG3: length 61.6
  IN1 w0.127: v1(73.32,102.44) 72.94,102.82 72.21,102.82 71.32,103.71 66.83,103.71 65.37,102.25 63.9,102.25 63.43,101.78 60.78,101.78 59.85,100.85 56.35,100.85 v1(56.16,100.66)
  IN3 w0.127: v1(73.32,102.44) 73.49,102.62 73.49,103.6 74.11,104.22 74.11,107.19 77.09,110.17 78.21,110.17 79.39,111.35 83.9,111.35 85.44,112.89 86.94,112.89 88.32,114.27 v1(88.32,114.37)
  BOTTOM w0.076: 89.04,113.99 89.62,113.99 89.87,113.74 91.37,113.74 91.39,113.76 91.52,113.76 UC1.AA63
  BOTTOM w0.102: v1(88.32,114.37) 88.72,113.97 88.91,113.97 88.91,113.97 88.94,113.99 89.02,113.99 89.04,113.99 ; JXDP1.17 69.2,95.54 69.88,96.21 73.03,96.21 73.74,96.92 73.74,97.53 73.75,97.54 73.75,102.01 v1(73.32,102.44) ; RC56.2 56.8,102.27 v2(56.61,102.08) 56.16,101.64 v1(56.16,100.66)
CFG3_R: length 3.5
  BOTTOM w0.102: v2(57.65,100.93) 58.07,101.36 RC56.1 58.71,100.66 58.7,100.65 JXDP1.60
CFG4: length 44
  TOP w0.089: 88.91,113.33 v2(90.15,113.33) 91.22,113.33 91.5,113.06 92.85,113.06 v1(93.3,113.51)
  TOP w0.102: 88.91,113.33 88.51,113.73 84.45,113.73 83.87,114.31 v1(83.85,114.31)
  IN3 w0.127: v1(66.57,95.34) 66.57,95.99 70.58,100 70.58,102.35 71.34,103.11 71.34,107.09 71.49,107.24 71.49,108.17 73.24,109.92 73.39,109.92 75.26,111.78 76.41,111.78 77.45,112.83 82.36,112.83 v1(83.85,114.31)
  BOTTOM w0.089: v1(93.3,113.51) 93.6,113.81 UC1.AA60
  BOTTOM w0.102: v1(83.85,114.31) 83.85,114.25 83.1,113.5 RC138.1 ; JXDP1.27 66.7,95.22 v1(66.57,95.34)
CFG5: length 44.9
  IN3 w0.127: v1(90.21,114.43) 86.57,110.79 82.18,110.79 81.04,109.65 78.41,109.65 77.43,108.66 76.38,108.66 74.64,106.92 74.64,104.03 74.01,103.41 74.01,101.58 70.96,98.53 70.96,94.41 69.76,93.21 69.76,91.48 v1(69.12,90.84)
  BOTTOM w0.076: UC1.Y62 92.06,114.63 91.77,114.34 91.46,114.34 91.19,114.07 90.5,114.07 90.21,114.37 v1(90.21,114.43)
  BOTTOM w0.102: JXDP1.29 66.2,92.27 66.51,91.96 67.21,91.96 67.66,91.51 67.66,90.8 67.95,90.5 v2(68.44,90.5) 68.78,90.5 v1(69.12,90.84)
CFG6: length 52.6
  TOP w0.089: v1(92.65,115.01) 88.91,115.01
  TOP w0.102: v1(76.29,100.59) 75.73,101.15 75.73,105.23 76.13,105.63 76.13,108.82 79.18,111.86 v2(79.18,112.69) 81.5,115.01 88.91,115.01
  BOTTOM w0.076: UC1.Y61 92.95,114.71 v1(92.65,115.01)
  BOTTOM w0.102: JXDP1.33 65.2,92.01 65.38,91.83 66.32,91.83 66.42,91.73 67.12,91.73 67.43,91.42 67.43,90.7 68.14,89.99 74.58,89.99 74.72,90.13 74.72,99.85 75.47,100.59 v1(76.29,100.59)
CFG7: length 47.7
  IN3 w0.127: v1(89.56,114.43) 89.56,114.37 86.26,111.07 79.48,111.07 78.32,109.91 77.21,109.91 74.37,107.07 74.37,104.13 73.75,103.5 73.75,101.69 70.64,98.58 70.64,94.46 68.55,92.36 68.55,90.75 68.23,90.43 67.21,90.43 66.96,90.69 v1(66.96,90.88)
  BOTTOM w0.076: UC1.Y60 93.31,114.3 92.83,114.3 92.79,114.34 92,114.34 91.84,114.18 91.53,114.18 91.26,113.91 90.02,113.91 89.56,114.37 v1(89.56,114.43)
  BOTTOM w0.102: v1(66.96,90.88) 66.95,90.88 66.25,91.58 65.31,91.58 64.7,92.18 JXDP1.35
CFG8: length 40.4
  IN3 w0.127: v1(73.24,113.68) 73.04,113.68 68.19,108.82 68.19,106.9 67.41,106.13 67.41,103.67 v1(67.03,103.29)
  BOTTOM w0.076: 89.1,114.88 89.6,114.88 89.65,114.93 91.84,114.93 UC1.V62
  BOTTOM w0.102: JXDP1.10 71.2,101.21 70.93,101.48 70.93,102.11 v2(70.76,102.28) 70.58,102.46 69.81,102.46 68.81,103.46 67.2,103.46 v1(67.03,103.29) ; 89.1,114.88 80.42,114.88 79.94,114.4 73.97,114.4 v1(73.24,113.68)
CFG9: length 43.9
  IN3 w0.127: v1(66.37,102.65) 66.61,102.89 66.61,103.62 67.15,104.17 67.15,106.24 67.92,107.01 67.92,109.02 74.29,115.39 75.34,115.39 75.75,115.8 v1(75.75,115.8)
  BOTTOM w0.076: 89.3,115.11 89.31,115.09 91.77,115.09 91.94,115.26 91.94,115.44 92.18,115.68 92.7,115.68 UC1.V61
  BOTTOM w0.102: JXDP1.12 70.7,101.86 70.33,102.23 69.71,102.23 68.71,103.23 68.14,103.23 v2(67.9,102.99) 67.79,102.88 66.59,102.88 v1(66.37,102.65) ; v1(75.75,115.8) 76.29,116.34 84.31,116.34 85.55,115.11 89.3,115.11
CFG10: length 35.9
  TOP w0.089: v1(93.3,115.01) 92.25,113.96 88.91,113.96
  TOP w0.102: 88.91,113.96 84.82,113.96 v2(84.57,114.22) 84.06,114.72 83.62,114.72 v1(83.21,114.31)
  IN3 w0.127: v1(83.21,114.31) 81.99,113.09 77.34,113.09 76.3,112.04 75.16,112.04 73.29,110.17 73.13,110.17 70.16,107.2 70.16,103.08 69.57,102.48 v1(69.57,101.61)
  BOTTOM w0.076: v1(93.3,115.01) 93.6,115.31 UC1.V60
  BOTTOM w0.102: v1(69.57,101.61) 69.7,101.48 JXDP1.16
CFG11: length 38.1
  IN3 w0.127: v1(86.44,115.71) 86.09,115.36 84.95,115.36 84.87,115.29 81.92,115.29 81.19,114.55 76.19,114.55 73.35,111.71 72.18,111.71 70.18,109.7 70.18,108.68 69.38,107.88 69.38,103.86 68.55,103.03 v1(68.55,102.82)
  BOTTOM w0.076: UC1.U60 93.31,115.8 92.83,115.8 92.79,115.84 92,115.84 91.84,115.68 91.46,115.68 91.25,115.89 90.93,115.89 90.4,115.36 89.3,115.36
  BOTTOM w0.102: JXDP1.18 v2(69.2,101.07) 69.2,101.3 69.05,101.45 69.05,102.31 68.55,102.82 v1(68.55,102.82) ; v1(86.44,115.71) 86.79,115.36 89.3,115.36
CFG12: length 38.2
  IN3 w0.127: v1(66.64,101.61) 66.64,101.78 65.94,102.48 65.94,103.01 66.23,103.29 66.23,103.61 66.89,104.28 66.89,106.34 67.66,107.12 67.66,109.13 74.35,115.81 v1(75.17,115.81)
  BOTTOM w0.076: UC1.T63 90.09,116.88
  BOTTOM w0.089: 90.09,116.88 88.91,116.88
  BOTTOM w0.102: v1(66.64,101.61) 66.7,101.55 JXDP1.28 ; v1(75.17,115.81) 76.06,116.7 v2(76.8,116.7) 86.98,116.7 87.17,116.88 88.91,116.88
CFG13: length 38.1
  IN3 w0.127: v1(85.92,116.01) 85.53,115.62 84.84,115.62 84.76,115.55 81.81,115.55 81.08,114.81 75.34,114.81 73.41,112.88 72.99,112.88 69.75,109.65 69.75,108.62 69.11,107.99 69.11,103.99 67.65,102.53 v1(67.65,102.47)
  BOTTOM w0.076: 89.22,116.42 91.84,116.42 91.85,116.44 91.85,116.44 UC1.T62
  BOTTOM w0.089: 89.22,116.43 88.91,116.43
  BOTTOM w0.102: JXDP1.30 66.2,101.86 66.36,102.02 67.42,102.02 67.65,102.25 v1(67.65,102.47) ; 88.91,116.43 87.96,116.43 87.76,116.22 86.13,116.22 v1(85.92,116.01)
CFG14: length 40
  IN3 w0.127: v1(85.32,116.05) 84.89,116.05 84.65,115.81 81.71,115.81 80.97,115.07 75.24,115.07 73.31,113.14 72.88,113.14 69.49,109.76 69.49,108.73 68.85,108.09 68.85,104.35 67.03,102.53 v1(67.03,102.47)
  BOTTOM w0.076: 90.07,116.65 90.69,116.65 90.75,116.59 91.77,116.59 91.94,116.76 91.94,116.94 92.18,117.17 92.7,117.17 UC1.T61
  BOTTOM w0.089: 90.07,116.65 88.91,116.65
  BOTTOM w0.102: 65.25,102.04 65.46,102.25 66.81,102.25 v1(67.03,102.47) ; 65.25,102.04 v2(65.25,102.04) ; 65.25,102.04 65.2,101.99 JXDP1.34 ; v1(85.32,116.05) 85.74,116.46 87.62,116.46 87.81,116.65 88.91,116.65
CFG15: length 45.1
  TOP w0.089: 88.91,116.46 91.87,116.46 92.39,116.98 92.83,116.98 v1(93.3,116.51)
  TOP w0.102: v1(80.83,115.78) v2(83.88,115.78) 83.89,115.78 84.16,115.78 84.16,115.78 84.35,115.78 85.03,116.46 88.91,116.46
  BOTTOM w0.076: v1(93.3,116.51) 93.6,116.81 UC1.T60
  BOTTOM w0.102: v1(80.83,115.78) 79.68,114.63 66.2,114.63 64.46,112.89 64.46,102.62 64.7,102.37 JXDP1.36
CFG16: length 32.4
  TOP w0.102: v2(86.68,114.59) 86.9,114.37 v1(87.15,114.37)
  IN3 w0.127: v1(72.4,102.22) 72.4,102.52 72.39,102.53 72.39,106.29 75.63,109.53 75.63,110.47 75.85,110.69 77.99,110.69 79.21,111.91 83.7,111.91 85.2,113.41 86.25,113.41 87.15,114.31 v1(87.15,114.37)
  BOTTOM w0.076: 88.91,113.5 89.11,113.5 89.19,113.41 89.27,113.41 89.28,113.4 89.95,113.4 89.96,113.41 91.51,113.41 91.53,113.43 91.84,113.43 92.24,113.83 92.24,113.83 UC1.AA62
  BOTTOM w0.102: v1(72.4,102.22) 71.99,101.81 71.99,101.38 72.2,101.17 JXDP1.6 ; v1(87.15,114.37) 87.15,114.31 87.96,113.5 88.02,113.5 88.03,113.5 88.91,113.5
CFG17: length 31.7
  IN3 w0.127: v1(72.4,101.6) 72.82,102.02 72.82,102.66 73.23,103.07 73.23,103.7 73.69,104.16 73.69,107.16 76.96,110.43 78.1,110.43 79.28,111.61 83.77,111.61 85.31,113.15 86.56,113.15 87.74,114.32 v1(87.74,114.37)
  BOTTOM w0.076: 88.91,113.73 88.95,113.69 v2(89.42,113.69) 89.62,113.69 89.74,113.58 91.44,113.58 91.46,113.59 91.77,113.59 92.01,113.83 92.01,114.01 92.18,114.18 92.7,114.18 UC1.AA61
  BOTTOM w0.102: JXDP1.4 72.7,101.29 v1(72.4,101.6) ; v1(87.74,114.37) 87.74,114.37 87.74,114.36 88.36,113.73 88.91,113.73
CFG18: length 46.8
  TOP w0.089: v2(88.95,116.01) 88.91,116.01
  TOP w0.102: 88.91,116.01 v1(88.32,116.01)
  IN3 w0.127: v1(88.32,116.01) 88.32,115.85 87.56,115.09 86.76,115.09 86.51,114.84 85.16,114.84 85.09,114.76 83.03,114.76 81.78,113.51 75.89,113.51 74.73,112.35 74.73,111.98 73.18,110.42 73.03,110.42 69.9,107.3 69.9,103.41 v1(69.66,103.18)
  BOTTOM w0.076: UC1.U63 91.56,116.22 90.79,116.22 90.59,116.01 88.91,116.01
  BOTTOM w0.102: v1(69.66,103.18) 70,102.84 72.34,102.84 73.52,101.67 73.52,97.63 73.12,97.23 68.16,97.23 67.7,97.69 JXDP1.24 ; 88.91,116.01 v1(88.32,116.01)
CFG19: length 36.5
  IN3 w0.127: v1(87.65,115.78) 87.2,115.34 86.66,115.34 86.42,115.1 85.05,115.1 84.98,115.02 82.03,115.02 81.3,114.29 76.31,114.29 73.47,111.45 72.29,111.45 70.44,109.6 70.44,108.57 69.64,107.77 69.64,103.75 68.97,103.08 68.97,102.54 68.61,102.18 v1(68.61,102.18)
  BOTTOM w0.076: 89.62,115.59 90.4,115.59 90.86,116.05 91.32,116.05 91.53,115.84 91.77,115.84 92.06,116.13 UC1.U62
  BOTTOM w0.102: v1(87.65,115.78) 87.84,115.59 89.62,115.59 ; v1(68.61,102.18) 67.91,101.47 v2(67.91,101.17) 67.91,100.54 68.2,100.25 JXDP1.22
CFG_RCOMP: length 2
  TOP w0.089: v2(90.45,115.47) v1(91.07,115.47) 91.27,115.66 RC132.1
  BOTTOM w0.089: v1(91.07,115.47) 91.16,115.38 UC1.V63
CHG_B+:
  vias: v3(149.38,162.63) v3(149.38,162) v3(152.62,162.7) v3(152.62,162.06) v3(153.57,162.7) v3(153.57,162.06) v3(154.46,162.7) v3(154.46,162.06) v3(155.41,162.7) v3(155.41,162.06) v4(157.49,161.69)
CKEA0: length 42.7
  TOP w0.102: v1(170,147.02) 170.38,147.4 170.38,148.99 170.51,149.12 170.51,150.53 UV18.K9 ; 177.69,135.39 177.69,133.14 177.88,132.95 178.52,132.95 178.64,132.83 178.64,132.66 178.52,132.54 177.63,132.54 177.51,132.42 177.51,132.25 177.63,132.13 178.52,132.13 178.64,132.02 178.64,131.85 178.52,131.73 178.11,131.73 178.01,131.63 178.01,128.03 178.13,127.9 v1(178.53,127.9)
  TOP w0.127: 177.69,135.39 177.69,136 177.56,136.13 177.1,136.13 176.97,136.26 176.97,136.51 177.1,136.64 177.56,136.64 177.69,136.76 177.69,137.02 177.56,137.14 177.1,137.14 176.97,137.27 176.97,137.53 177.1,137.65 177.56,137.65 177.69,137.78 177.69,138.03 177.56,138.16 177.1,138.16 176.97,138.29 176.97,138.54 177.1,138.67 v2(177.31,138.67) 177.49,138.67 177.62,138.8 177.62,139.05 177.49,139.18 177.1,139.18 176.97,139.3 176.97,139.58 177.1,139.71 178.51,139.71 178.64,139.83 178.64,140.26 v1(178.51,140.38)
  IN1 w0.102: v1(170,147.02) 171.34,145.68 171.34,144.21 172.69,142.86
  IN1 w0.14: v1(178.51,140.38) 178.5,140.38 177.4,141.49 174.06,141.49 172.69,142.86
  BOTTOM w0.102: v1(178.53,127.9) 178.12,127.49 UV1.K21 ; v1(170,147.02) 170,147.17 170.12,147.29 170.45,147.29 170.58,147.17 170.58,145.99 170.35,145.76 170.35,145.6 170.58,145.36 170.58,145.19 170.41,145.02 170.41,144.58 170.29,144.45 UV19.K9
CKEA1: length 42
  TOP w0.102: UV20.K9 187.66,144.78 187.66,146.19 187.79,146.32 187.79,147.91 v1(188.17,148.29) ; v1(178.59,128.74) 179.25,129.4 179.25,134.43 179.46,134.64
  TOP w0.127: v1(179.78,140.29) 179.66,140.29 179.53,140.16 179.53,139.63 179.66,139.51 180.67,139.51 180.8,139.38 180.8,139.1 180.67,138.97 179.66,138.97 179.53,138.84 179.53,138.59 179.66,138.46 180.73,138.46 180.86,138.34 180.86,138.08 180.73,137.96 v2(179.97,137.96) 179.66,137.96 179.53,137.83 179.53,137.57 179.66,137.45 180.35,137.45 180.48,137.32 180.48,134.76 180.35,134.64 179.46,134.64
  IN1 w0.102: v1(188.17,148.29) 188.17,148.28 188.55,147.9 188.55,146.71 187.72,145.88 187.72,143.38 187.2,142.86
  IN1 w0.14: v1(179.78,140.29) 180.21,140.71 185.05,140.71 187.2,142.86
  BOTTOM w0.102: UV1.J20 179.05,128.29 v1(178.59,128.74) ; v1(188.17,148.29) 188.17,148.14 188.04,148.01 187.71,148.01 187.59,148.14 187.59,148.47 187.78,148.67 187.78,148.92 187.59,149.12 187.59,149.37 187.78,149.57 187.78,149.79 187.59,149.99 187.59,150.32 187.71,150.45 187.85,150.45 187.98,150.58 UV21.K9
CKEB0: length 43.3
  TOP w0.102: v1(188.31,121.12) 188.78,121.59 190.09,121.59 190.31,121.37 190.31,121.19 190.54,120.96 191.17,120.96 191.45,121.24 192.33,121.24 192.55,121.46 192.55,122.01 192.77,122.23 193.08,122.23 193.75,121.56 194.37,121.56 194.39,121.58 ; UV22.K9 212.63,131.78 211.22,131.78 211.09,131.91 209.5,131.91 v1(209.12,132.29)
  TOP w0.127: v1(202.01,122.64) 201.85,122.48 201.19,122.48 200.78,122.89 198.48,122.89 198.35,122.76 198.35,122.19 198.23,122.06 196.76,122.06 196.63,122.19 196.63,122.71 196.51,122.84 194.52,122.84 194.39,122.7 194.39,122.25 194.45,122.19 194.45,121.64 194.39,121.58
  IN1 w0.102: 204.96,129.6 206.7,131.34 208.16,131.34 v1(209.12,132.29)
  IN1 w0.14: 204.96,129.6 204.24,128.88 204.24,127.19 202.51,125.47 202.51,123.33 202.39,123.21 200.93,123.21 200.8,123.08 200.8,122.76 200.93,122.64 v1(202.01,122.64)
  BOTTOM w0.102: UV23.K9 206.76,132.1 207.16,131.71 209.27,131.71 209.39,131.84 209.39,132.17 209.27,132.29 v1(209.12,132.29) ; v1(188.31,121.12) 188.03,121.12 187.47,121.69 UV1.U10
CKEB1: length 45.9
  TOP w0.102: UV25.K9 206.88,115.14 208.29,115.14 208.42,115.01 209.97,115.01 210.1,115.14 210.45,115.14 210.58,115.02 210.58,114.76 210.45,114.63 v1(210.39,114.63) ; v1(187.08,118.69) 187.08,118.44 186.96,118.32 186.64,118.32 186.51,118.44 186.51,119.27 186.64,119.4 188.62,119.4 188.75,119.52 188.75,119.93 188.97,120.15 190.48,120.15 190.48,120.15 191.5,120.15 191.72,120.36 192.42,120.36 192.61,120.17 193.93,120.17 194.01,120.1
  TOP w0.127: 194.01,120.1 194.39,119.71 194.39,119.21 194.51,119.08 195.16,119.08 195.29,118.96 195.29,118.52 195.42,118.39 195.66,118.39 195.78,118.52 195.78,118.95 195.91,119.08 196.1,119.08 196.23,118.95 196.23,118.52 196.36,118.39 196.62,118.39 196.75,118.52 196.75,120.9 196.88,121.02 v2(199.53,121.02) 201.92,121.02 v1(202.2,121.3)
  IN1 w0.102: 204.96,115.6 205.48,115.08 207.98,115.08 208.81,114.25 210,114.25 210.38,114.63 v1(210.39,114.63)
  IN1 w0.14: v1(202.2,121.3) 202.49,121.01 202.49,118.07 204.96,115.6
  BOTTOM w0.102: v1(210.39,114.63) 210.39,115.03 210.57,115.21 213.32,115.21 213.44,115.1 213.44,114.93 213.32,114.82 UV24.K9 ; UV1.AA11 v1(187.08,118.69)
CLK_BIASREF: length 5.7
  BOTTOM w0.089: UC1.C26 115,124.18 115.11,124.29 115.12,124.29 115.3,124.46 115.3,124.47 115.33,124.51 115.33,124.68 115.27,124.74 115.27,125.13 115.16,125.24 115.16,125.89 115.18,125.9
  BOTTOM w0.305: RC13.1 115.43,129.12 v2(115.43,127.94) 115.43,127 115.18,126.74 115.18,125.9
CLK_CPU_ITP: length 3.7
  BOTTOM w0.089: RC139.2 108.74,128.39 v3(108.74,127.8) 108.74,127.1 109.47,126.37 109.47,125.61 UC1.A35
CLK_CPU_ITP#: length 4.4
  BOTTOM w0.089: UC1.B35 109.72,125.21 109.72,126.48 108.99,127.2 108.99,128.46 RC140.2
CLK_PCI_LPC: length 110.1
  TOP w0.089: R2336.1 125.94,96.02 127.07,96.02 v1(127.46,96.42)
  TOP w0.102: UE1.12 187.59,33.78 R2354.2 187.42,33.54 186.91,33.03 186.91,32.21 186.31,31.61 182,31.61 180.61,32.99 180.61,35.29 180.13,35.77 179.38,35.77 174.43,40.73 170.78,40.73 169.68,41.83 v2(169.68,48.19) 169.68,48.8 v1(168.05,50.43)
  IN1 w0.084: v1(127.46,96.42) 127.83,96.79 129.26,96.79 129.45,96.6 129.45,96.21 130.19,95.48 130.6,95.48 130.78,95.3
  IN1 w0.127: 130.78,95.3 151.97,74.1 153.71,74.1 157.51,70.31 167.91,70.31 168.42,69.8 168.42,51.37 168.05,51 v1(168.05,50.43)
CLK_PCIE_LAN: length 112.3
  IN1 w0.127: v1(39.78,117.38) 39.98,117.57 41.53,117.57 42.63,118.68 59.87,118.68 60.32,119.14 66.36,119.14 79.48,132.26 91.23,132.26 91.71,132.74 95.6,132.74 97.5,130.84 97.5,128.47 99.32,126.65 103.46,126.65 104.27,127.46 104.51,127.46 104.64,127.33 104.64,127.12 v1(104.47,126.95)
  BOTTOM w0.089: UC1.B42 104.99,124.56 104.99,124.3 104.93,124.23 104.86,124.23 104.58,124.51 104.58,124.62 104.98,125.03 104.98,126.02 104.8,126.19 104.8,126.61 v1(104.47,126.95)
  BOTTOM w0.102: UL1.15 38.75,86.82 38.81,86.88 38.81,87.12 40.54,88.84 40.54,117.3 40.29,117.55 39.95,117.55 v1(39.78,117.38)
CLK_PCIE_LAN#: length 112.4
  IN1 w0.127: v1(39.78,117.96) 39.84,117.9 41.39,117.9 42.5,119.01 59.73,119.01 60.19,119.47 66.22,119.47 79.34,132.59 91.09,132.59 91.57,133.07 95.74,133.07 97.83,130.97 97.83,128.61 99.45,126.99 103.33,126.99 104.14,127.79 104.65,127.79 104.99,127.45 104.99,127 v1(105.05,126.95)
  BOTTOM w0.089: UC1.C41 105.27,124.53 105.27,124.71 105.24,124.74 105.24,126.12 105.06,126.3 105.06,126.94 v1(105.05,126.95)
  BOTTOM w0.102: v1(39.78,117.96) 39.93,117.82 40.4,117.82 40.81,117.41 40.81,88.73 39.08,87.01 39.08,86.88 39.15,86.82 UL1.16
CLK_PCIE_WLAN: length 55.5
  IN3 w0.114: JMINI.13 98.1,149.64 97.81,149.35 97.81,148.63 98.36,148.08 113.77,148.08 114.68,147.17 114.68,146.36 116.22,144.82 119.13,144.82 119.88,144.07 119.88,139.15 113.98,133.24 113.98,131.73 111.46,129.21 106.79,129.21 106.51,128.93 106.51,128.84 106.74,128.61 v1(106.74,128.6)
  BOTTOM w0.102: v1(106.74,128.6) 106.58,128.44 106.58,127.98 106.59,127.97 106.59,127.89 107.1,127.39 107.1,126.75 107.6,126.25 107.6,124.92 107.85,124.66 107.85,124.45 UC1.C37
CLK_PCIE_WLAN#: length 55
  IN3 w0.114: v1(106.16,128.6) 106.25,128.7 106.25,129.03 106.68,129.46 111.35,129.46 113.73,131.84 113.73,133.35 119.63,139.25 119.63,143.97 119.03,144.57 116.11,144.57 114.43,146.25 114.43,147.06 113.67,147.82 98.25,147.82 97.56,148.52 97.56,149.52 97.3,149.78 JMINI.11
  BOTTOM w0.102: v1(106.16,128.6) 106.32,128.44 106.32,127.87 106.32,127.86 106.32,127.64 106.47,127.64 106.83,127.28 106.83,126.64 107.33,126.14 107.33,124.73 UC1.B38
CLK_PEG_VGA: length 74
  IN1 w0.127: v1(167.03,118.18) 166.99,118.14 161.49,118.14 156.46,123.17 153.97,123.17 144.36,132.78 138.94,132.78 136.98,130.82 129.17,130.82 127.93,132.05 118.54,132.05 118.1,131.61 115.74,131.61 114.28,130.15 110.64,130.15 109.34,128.84 108.18,128.84 106.5,127.16 105.99,127.16 v1(105.94,127.12)
  BOTTOM w0.089: UC1.B39 106.91,124.98 106.39,125.51 106.39,127.1 106.29,127.2 106.02,127.2 v1(105.94,127.12)
  BOTTOM w0.102: UV1.AB35 166.86,118.01 v1(167.03,118.18)
CLK_PEG_VGA#: length 73.9
  IN1 w0.127: v1(105.94,127.7) 106.15,127.49 106.37,127.49 108.04,129.17 109.2,129.17 110.51,130.48 114.14,130.48 115.6,131.94 117.96,131.94 118.41,132.38 128.07,132.38 129.3,131.15 136.85,131.15 138.8,133.11 144.5,133.11 154.11,123.5 156.6,123.5 161.63,118.47 166.63,118.47 v1(166.9,118.75)
  BOTTOM w0.089: UC1.A39 106.7,125.56 106.65,125.61 106.65,127.2 106.39,127.46 106.19,127.46 v1(105.94,127.7)
  BOTTOM w0.102: v1(166.9,118.75) 166.65,118.49 UV1.AA36
CLK_SMB: length 14.7
  TOP w0.102: v1(141.7,182.54) 141.7,182.07 v2(141.54,181.92)
  TOP w0.254: PR18.1 141.88,182.72 v1(141.7,182.54)
  BOTTOM w0.254: v1(141.7,182.54) 141.7,182.89 141.95,183.15 PD1.3 143.35,183.15 144.05,183.84 144.05,184.22 144.56,184.74 PD3.3 146.39,185.62 148.44,185.62 151.52,188.7 PBATT.7
CLK_X1: length 8.3
  TOP w0.102: UG1.1 70.63,40.2 70.01,39.57 69.07,39.57 CG8.1 68.29,40.35 64.51,40.35 YG1.1
CLK_X2: length 5.1
  TOP w0.102: UG1.16 69.37,41.65 CG9.1 68.29,40.57 66.46,40.57 YG1.3
CLK_XDP: length 78.6
  IN1 w0.127: v1(63.74,120.03) 63.59,120.18 63.59,120.44 63.82,120.66 66.51,120.66 78.96,133.11 90.89,133.11 91.47,133.68 95.85,133.68 98.38,131.15 98.38,130.01 98.68,129.7 99.13,129.7 v1(99.34,129.49)
  BOTTOM w0.102: v1(99.34,129.49) 99.52,129.68 99.89,129.68 100.19,129.98 100.19,130.64 100.7,131.14 102.26,131.14 103.09,130.31 108.55,130.31 108.71,130.16 108.71,130.04 RC139.1 ; JXDP1.40 63.7,100.43 63.58,100.55 63.58,101.78 63.97,102.16 63.97,107.94 61.5,110.41 61.5,116 63.59,118.1 63.59,119.87 v1(63.74,120.03)
CLK_XDP#: length 79.6
  IN1 w0.127: v1(99.34,130.14) 99.23,130.03 98.82,130.03 98.71,130.14 98.71,131.29 95.99,134.01 91.33,134.01 90.76,133.44 78.82,133.44 66.37,120.99 63.68,120.99 63.26,120.57 63.26,120.13 v1(63.16,120.03)
  BOTTOM w0.102: RC140.1 109.25,129.69 108.98,129.96 108.98,130.27 108.66,130.58 103.2,130.58 102.53,131.25 102.37,131.4 100.59,131.4 99.93,130.75 99.93,130.09 99.78,129.94 99.53,129.94 v1(99.34,130.14) ; JXDP1.42 63.2,100.43 63.32,100.55 63.32,101.89 63.7,102.27 63.7,107.83 61.23,110.3 61.23,116.11 63.33,118.21 63.33,119.86 v1(63.16,120.03)
CLKA0: length 49.8
  TOP w0.102: v1(168.97,147.65) 168.86,147.76 168.51,147.76 168.32,147.95 168.32,148.57 168.68,148.93 169.63,148.93 169.69,148.98 169.69,149.12 169.55,149.25 UV18.J7
  TOP w0.109: v1(169.56,153.61) 169.75,153.8 169.75,153.93 RV154.1
  IN1 w0.14: v1(169.56,153.61) 169.72,153.45 169.72,151.74 170.57,150.89 170.57,149.75 169.95,149.12 168.61,149.12 168.23,148.74 168.23,148.07 168.45,147.84 168.78,147.84 v1(168.97,147.65)
  IN3 w0.102: v1(168.97,147.65) 169.18,147.86 169.3,147.86 169.4,147.76 169.4,146.56 169.66,146.3
  IN3 w0.14: 169.66,146.3 169.77,146.19 170,146.19 170.19,146.01 170.19,144.88 170.46,144.61 171.31,144.61 171.59,144.88 171.59,146.24 171.71,146.37 174.73,146.37 174.85,146.24 174.85,145.64 174.73,145.51 172.56,145.51 172.29,145.24 172.29,143.31 172.57,143.02 172.95,143.02 174.32,141.64 174.32,139.17 174.83,138.66 174.83,136.21 174.26,135.64 174.26,133.54 171.8,131.08 171.8,129.45 172.07,129.17 172.3,129.17 172.54,128.94 v1(172.54,128.94)
  BOTTOM w0.102: UV1.H27 172.91,128.94 172.55,128.94 172.55,128.94 v1(172.54,128.94) ; UV19.J7 169.39,145.88 169.49,145.77 169.65,145.77 169.76,145.88 169.76,146.32 169.63,146.45 169.48,146.45 169.35,146.57 169.35,147.82 169.28,147.9 169.07,147.9 168.97,147.79 v1(168.97,147.65)
CLKA0#: length 49.1
  TOP w0.102: UV18.K7 169.96,149.25 169.89,149.18 169.89,148.9 169.71,148.72 168.76,148.72 168.52,148.48 168.52,148.04 168.59,147.96 168.74,147.96 168.97,148.2 v1(168.97,148.29)
  TOP w0.109: RV155.1 169.96,153.88 169.96,153.8 v1(170.15,153.61)
  IN1 w0.14: v1(168.97,148.29) 168.79,148.11 168.56,148.11 168.49,148.18 168.49,148.63 168.72,148.86 170.06,148.86 170.84,149.64 170.84,151 169.98,151.85 169.98,153.45 v1(170.15,153.61)
  IN3 w0.102: v1(168.97,148.29) 169.18,148.08 169.39,148.08 169.62,147.85 169.62,146.73 169.89,146.45
  IN3 w0.14: 169.89,146.45 169.91,146.44 170.11,146.44 170.44,146.11 170.44,144.99 170.57,144.86 171.21,144.86 171.33,144.99 171.33,146.34 171.61,146.62 174.83,146.62 175.11,146.34 175.11,145.54 174.83,145.26 172.67,145.26 172.54,145.13 172.54,143.41 172.68,143.27 173.05,143.27 174.57,141.75 174.57,139.27 175.08,138.76 175.08,136.11 174.51,135.54 174.51,133.43 172.05,130.97 172.05,129.55 172.18,129.42 172.42,129.42 v1(172.52,129.52)
  BOTTOM w0.102: v1(168.97,148.29) 169.16,148.1 169.36,148.1 169.58,147.88 169.58,146.7 169.63,146.65 169.72,146.65 169.84,146.52 169.84,146.52 169.97,146.39 170.07,146.39 170.15,146.47 170.28,146.47 170.38,146.38 170.38,146.25 UV19.K7 ; UV1.G27 172.69,129.52 v1(172.52,129.52)
CLKA1: length 49
  TOP w0.102: UV20.J7 188.78,146.26 188.91,146.38 189.39,146.38 189.89,146.88 189.89,147.48 189.72,147.65 v1(189.2,147.65)
  TOP w0.109: RV164.1 188.47,154 188.47,153.86 v1(188.28,153.68)
  IN1 w0.14: v1(189.2,147.65) 189.38,147.47 189.55,147.47 189.68,147.6 189.68,148.5 189.32,148.86 188.35,148.86 187.59,149.62 187.59,151.08 188.45,151.94 188.45,153.51 v1(188.28,153.68)
  IN3 w0.14: v1(184.5,127.9) 184.38,128.02 183.99,128.02 183.72,128.29 183.72,130.32 184.16,130.76 184.82,130.76 185.31,131.25 185.31,133.68 184.42,134.57 184.42,141.14 184.71,141.43 186.43,141.43 186.56,141.56 186.56,142 186.43,142.13 184.71,142.13 184.42,142.42 184.42,143.35 184.69,143.62 187.15,143.62 187.27,143.75 187.27,145.18 187.15,145.3 185.57,145.3 185.29,145.58 185.29,146.34 185.57,146.62 188.48,146.62 188.61,146.74 188.61,147.06 v1(189.2,147.65)
  BOTTOM w0.102: UV21.J7 188.63,149.25 188.56,149.18 188.56,148.86 188.79,148.63 188.79,147.51 188.89,147.41 189.1,147.41 189.2,147.51 v1(189.2,147.65) ; v1(184.5,127.9) 184.11,128.29 UV1.J14
CLKA1#: length 49.8
  TOP w0.102: v1(189.2,147.02) 189.2,147.12 189.53,147.45 189.64,147.45 189.69,147.4 189.69,146.97 189.3,146.59 188.82,146.59 188.48,146.25 188.48,146.18 188.35,146.05 UV20.K7
  TOP w0.109: v1(188.87,153.68) 188.68,153.86 188.68,154 RV165.1
  IN1 w0.14: v1(189.2,147.02) 189.39,147.21 189.66,147.21 189.94,147.5 189.94,148.61 189.43,149.12 188.46,149.12 187.85,149.73 187.85,150.97 188.71,151.83 188.71,153.51 v1(188.87,153.68)
  IN3 w0.14: v1(189.2,147.02) 189.13,147.09 188.99,147.09 188.86,146.96 188.86,146.64 188.59,146.37 185.67,146.37 185.55,146.24 185.55,145.69 185.67,145.56 187.25,145.56 187.53,145.28 187.53,143.64 187.25,143.37 184.8,143.37 184.67,143.24 184.67,142.52 184.81,142.38 186.53,142.38 186.81,142.11 186.81,141.45 186.53,141.17 184.81,141.17 184.67,141.03 184.67,134.68 185.56,133.79 185.56,131.14 184.93,130.51 184.27,130.51 183.97,130.21 183.97,128.4 184.1,128.27 184.35,128.27 184.48,128.4 v1(184.48,128.72)
  BOTTOM w0.102: v1(184.48,128.72) 184.23,128.72 UV1.H14 ; UV21.K7 188.16,149.43 188.29,149.43 188.35,149.37 188.35,148.78 188.59,148.54 188.59,147.43 188.81,147.21 189.01,147.21 v1(189.2,147.02)
CLKB0: length 49.2
  TOP w0.102: UV22.J7 211.35,132.74 211.22,132.6 211.08,132.6 211.03,132.66 211.03,133.74 210.73,134.04 210.12,134.04 209.86,133.78 209.86,133.43 v1(209.75,133.32)
  TOP w0.109: RV174.1 215.9,132.35 215.74,132.35 v1(215.55,132.16)
  IN1 w0.102: 214.55,132.3 214.53,132.3 214.51,132.32 213.91,132.32 213.34,131.75 211.5,131.75 210.36,132.89 210.19,132.89 v1(209.75,133.32)
  IN1 w0.14: v1(215.55,132.16) 215.42,132.3 214.55,132.3
  IN3 w0.102: 208.04,132.22 208.04,132.53 208.4,132.89 209.86,132.89 209.96,132.99 209.96,133.11 v1(209.75,133.32) ; v1(187.7,126.91) 187.87,126.91 188.04,127.08 188.04,127.3 188.23,127.49 188.8,127.49 188.83,127.52 189.51,127.52 189.66,127.67 193.4,127.67 194.22,126.84 194.34,126.84 194.36,126.86 194.39,126.86
  IN3 w0.14: 208.04,132.22 208.04,128.13 206.77,126.86 197.29,126.86 197.15,127 197.15,129.85 196.87,130.13 196.22,130.13 195.94,129.85 195.94,127 195.8,126.86 194.39,126.86
  BOTTOM w0.102: UV23.J7 208.15,132.7 208.29,132.56 208.39,132.56 208.78,132.94 209.83,132.94 209.97,133.08 209.97,133.25 209.89,133.32 v1(209.75,133.32) ; v1(187.7,126.91) 188.06,126.55 UV1.L9
CLKB0#: length 48.3
  TOP w0.102: UV22.K7 211.06,132.4 211,132.4 210.82,132.58 210.82,133.66 210.64,133.83 210.2,133.83 210.06,133.7 210.06,133.55 210.3,133.32 v1(210.39,133.32)
  TOP w0.109: v1(215.55,132.75) 215.74,132.56 215.98,132.56 RV175.1
  IN1 w0.102: v1(210.39,133.32) 210.39,133.18 211.6,131.97 213.25,131.97 213.82,132.54 214.5,132.54 214.52,132.56 214.55,132.56
  IN1 w0.14: v1(215.55,132.75) 215.36,132.56 214.55,132.56
  IN3 w0.102: v1(188.45,126.88) 188.25,127.08 188.25,127.21 188.32,127.27 188.89,127.27 188.92,127.31 189.6,127.31 189.74,127.46 193.31,127.46 194.14,126.63 194.34,126.63 194.36,126.61 194.39,126.61 ; v1(210.39,133.32) 210.18,133.11 210.18,132.9 209.95,132.67 208.49,132.67 208.29,132.48 208.29,132.12
  IN3 w0.14: 194.39,126.61 195.91,126.61 196.19,126.9 196.19,129.75 196.32,129.87 196.77,129.87 196.89,129.75 196.89,126.9 197.18,126.61 206.87,126.61 208.29,128.03 208.29,132.12
  BOTTOM w0.102: UV1.L8 188.84,126.49 v1(188.45,126.88) ; v1(210.39,133.32) 210.2,133.13 210.2,132.99 209.92,132.71 208.87,132.71 208.49,132.33 208.38,132.33 208.15,132.11 UV23.K7
CLKB1: length 51.5
  TOP w0.102: v1(209.75,113.6) 209.65,113.49 209.65,113.14 209.46,112.95 208.84,112.95 208.48,113.31 208.48,114.13 208.44,114.18 208.31,114.18 UV25.J7
  TOP w0.109: v1(215.46,114.7) 215.64,114.52 215.97,114.52 RV180.1
  IN1 w0.102: 212.33,115.22 212.31,115.22 212.29,115.21 211.53,115.21 210.96,114.63 210.96,113.43 210.38,112.84 209.65,112.84 209.55,112.95 209.55,113.39 v1(209.75,113.6)
  IN1 w0.14: 212.33,115.22 213.04,115.22 213.68,114.58 215.33,114.58 v1(215.46,114.7)
  IN3 w0.102: 194.39,115.91 194.37,115.89 193.54,115.89 193.31,115.66 193.31,114.84 193.19,114.71 192.61,114.71 192.48,114.84 192.48,115.59 192.27,115.8 189.2,115.8 188.92,115.51 188.92,115.32 188.71,115.12 v1(188.71,115.1) ; v1(209.75,113.6) 209.54,113.81 209.54,113.9 209.54,114.02 209.32,114.25 208.62,114.25 208.42,114.44 208.42,114.96 208.19,115.18 206.9,115.18 206.79,115.29 206.79,115.9 206.92,116.03 209.08,116.03 209.33,116.28 209.33,116.92 209.08,117.17 208.36,117.17 207.91,117.62 206.1,117.62 206.08,117.64 206.07,117.64
  IN3 w0.14: 194.39,115.91 196.12,117.64 204.27,117.64 204.55,117.36 204.55,115.9 204.67,115.78 205.18,115.78 205.31,115.9 205.31,117.36 205.58,117.64 206.07,117.64
  BOTTOM w0.102: UV1.AD8 188.86,115.25 v1(188.71,115.1) ; UV24.J7 211.35,114.22 211.21,114.36 211.11,114.36 210.73,113.98 209.68,113.98 209.54,113.84 209.54,113.68 209.61,113.6 v1(209.75,113.6)
CLKB1#: length 51.4
  TOP w0.102: v1(209.12,113.6) 209.21,113.6 209.44,113.37 209.44,113.22 209.37,113.15 208.93,113.15 208.69,113.39 208.69,114.22 208.51,114.39 208.34,114.39 208.15,114.58 UV25.K7
  TOP w0.109: v1(215.46,114.12) 215.64,114.31 215.97,114.31 RV181.1
  IN1 w0.102: v1(209.12,113.6) 209.32,113.39 209.32,112.85 209.56,112.62 210.47,112.62 211.18,113.34 211.18,114.54 211.62,114.98 212.29,114.98 212.31,114.96 212.33,114.96
  IN1 w0.14: v1(215.46,114.12) 215.26,114.32 213.57,114.32 212.93,114.96 212.33,114.96
  IN3 w0.102: v1(189.33,115.12) 189.13,115.32 189.13,115.42 189.29,115.58 192.18,115.58 192.27,115.5 192.27,114.75 192.52,114.49 193.28,114.49 193.53,114.75 193.53,115.57 193.63,115.67 194.48,115.67 194.54,115.72 194.54,115.72 194.56,115.72 194.57,115.73 ; v1(209.12,113.6) 209.33,113.81 209.33,113.93 209.23,114.03 208.53,114.03 208.2,114.35 208.2,114.87 208.1,114.97 206.81,114.97 206.58,115.2 206.58,115.99 206.83,116.25 208.99,116.25 209.12,116.37 209.12,116.83 208.99,116.96 208.27,116.96 207.82,117.4 206.1,117.4 206.08,117.38 206.07,117.38
  IN3 w0.14: 194.57,115.73 196.23,117.38 204.17,117.38 204.29,117.26 204.29,115.8 204.57,115.52 205.29,115.52 205.56,115.8 205.56,117.26 205.69,117.38 206.07,117.38
  BOTTOM w0.102: UV24.K7 211.35,114.81 211.13,114.59 211.02,114.59 210.64,114.21 209.58,114.21 209.31,113.94 209.31,113.79 v1(209.12,113.6) ; UV1.AD7 189.66,115.65 189.33,115.32 v1(189.33,115.12)
CLKOUT_LPC0: length 12.5
  TOP w0.102: v1(121.76,106.83) 122.52,106.08 v2(122.52,104.96) 122.52,99.97 122.98,99.52 123.79,99.52 124.6,98.7 124.6,97.89 125.34,97.15 R2336.2
  BOTTOM w0.076: v1(121.76,106.83) 122.09,107.16 UC1.AN15
CLKRUN#: length 2.7
  TOP w0.089: v2(129.07,115.64) 128.62,115.19 v1(128.62,114.99) 128.86,114.75 RC36.2
  BOTTOM w0.089: v1(128.62,114.99) 128.29,114.99 127.87,115.41 UC1.V5
CMSRC: length 29.5
  TOP w0.102: v1(168.18,166.7) 168.18,166.46 168.44,166.2 168.44,165.27 v2(167.95,164.77)
  TOP w0.254: PU701.3 167.99,166.89 v1(168.18,166.7)
  IN3 w0.254: v1(168.18,166.7) 168.18,166.47 166.3,164.6 146.27,164.6 144.75,166.13 v1(144.55,166.13)
  BOTTOM w0.254: v1(144.55,166.13) 144.19,166.13 143.81,165.75 PR721.1
CODEC_IRQ: length 5.8
  BOTTOM w0.076: RC88.1 133.42,119.12 v2(132.49,119.12) 132.22,119.39 131.68,119.39 130.92,118.63 129.18,118.63 129.06,118.76 128.62,118.76 UC1.L4
COMP_CPU: length 4.8
  BOTTOM w0.203: PU501.26 90.22,135.05 90.24,135.03 90.24,134.91 90.9,134.25 PR531.2
  BOTTOM w0.254: PR531.2 PC514.2 92.17,133.58 92.26,133.49 PR532.2 PC513.1
CPPE#: length 5.9
  BOTTOM w0.089: UC1.J1 131.33,120.59 131.96,121.22 132.57,121.22 132.72,121.37 134.32,121.37 134.47,121.22 135.63,121.22 RC108.2
CPU_DETECT#: length 241.1
  TOP w0.102: UE1.127 v1(182.85,37.71) 182.85,37.39 181.33,35.88 181.33,34.17 RE11.1 181.74,33.77 CE33.1
  IN1 w0.127: v1(174.5,47.7) 174.49,47.69 174.49,40.33 176.22,38.59 181.87,38.59 182.75,37.71 v1(182.85,37.71)
  IN3 w0.127: v1(174.5,47.7) 174.3,47.9 141.42,47.9 140.96,47.45 115.56,47.45 114.67,48.33 69.33,48.33 60.9,56.77 60.9,72.4 58.77,74.53 58.77,92.27 54.34,96.7 54.34,105.7 63.27,114.63 63.27,115.77 68.27,120.76 74.72,120.76 76.71,122.76 v1(80.78,122.76)
  BOTTOM w0.076: UC1.D61 92.73,123.98 92.73,124.22 92.44,124.51 91.85,124.51 91.79,124.58 91.49,124.58 90.86,125.2 90.24,125.2 89.92,125.53
  BOTTOM w0.102: 89.92,125.53 89.79,125.66 88.02,125.66 86.59,124.23 84.75,124.23 83.28,122.76 v2(83.03,122.76) v1(80.78,122.76)
CPU_DPB_AUX: length 7.3
  IN3 w0.127: v1(129.95,129.36) 130.33,128.98 130.33,128.64 130.02,128.33 129.68,128.33 v1(129.53,128.48)
  BOTTOM w0.076: UC1.B5 127.23,125.01 127.23,125.93 127.79,126.49 127.84,126.49 127.86,126.5 127.87,126.5
  BOTTOM w0.089: RP51.3 v1(129.95,129.36)
  BOTTOM w0.102: v1(129.53,128.48) 129.36,128.31 129.1,128.31 128.87,128.08 128.87,127.46 127.91,126.5 127.87,126.5
CPU_DPB_AUX#: length 8
  IN3 w0.127: v1(130.95,129.36) 130.58,128.99 130.58,128.53 130.13,128.08 129.72,128.08 v1(129.53,127.89)
  BOTTOM w0.076: UC1.C5 127.43,124.44 127.43,125.04 127.39,125.08 127.39,125.82 127.86,126.28 127.87,126.28
  BOTTOM w0.102: RP51.1 v1(130.95,129.36) ; 127.87,126.28 128,126.28 129.09,127.37 129.09,127.99 129.19,128.09 129.34,128.09 v1(129.53,127.89)
CPU_DPB_CTRLCLK: length 141.5
  TOP w0.102: QX4.1 15.19,107.37 15.84,108.02 16.74,108.02 17.3,107.46 18.39,107.46 19.12,108.19 19.28,108.19 v1(19.46,108)
  IN1 w0.127: v1(126.77,130.55) 126.97,130.36 127.41,130.36 127.57,130.52 127.57,130.74 127.27,131.04 126.41,131.04 126.09,130.73 125.11,130.73 124.62,131.21 120.06,131.21 119.65,130.8 116.13,130.8 114.61,129.28 111.1,129.28 109.64,127.82 108.09,127.82 106.11,125.84 97.53,125.84 96.66,126.71 96.66,130.57 95.27,131.96 92.04,131.96 90.06,129.98 86.64,129.98 82.25,125.59 74.68,125.59 67.4,118.31 60.68,118.31 60.26,117.89 43.06,117.89 40.22,115.05 30.05,115.05 23.15,108.15 19.61,108.15 v1(19.46,108)
  BOTTOM w0.076: v1(126.77,130.55) 126.6,130.38 126.39,130.38 126.2,130.19 126.2,129.61 126.35,129.46 126.35,127.26 125.66,126.56 125.49,126.39 125.48,126.39 125.12,126.03 125.12,125.35 124.68,124.92 UC1.B9
  BOTTOM w0.102: v1(19.46,108) 19.71,108.25 19.87,108.25 20.12,108.51 20.12,108.88 19.9,109.09 19.9,109.17 20.02,109.28 RP52.1
CPU_DPB_CTRLCLK_R: length 10.6
  TOP w0.102: JHDMI.15 8.79,106.86 8.79,108.53 9.3,109.04 v3(9.78,109.04) 11.46,109.04 11.91,108.59 11.94,108.59 12.33,108.2 12.33,108.17 12.56,107.94 13.7,107.94 RX16.1 14.35,107.94 15.01,107.94 15.19,108.12 QX4.6
CPU_DPB_CTRLDAT: length 140.3
  TOP w0.102: v1(19.46,108.59) 19.28,108.41 19.03,108.41 18.3,107.68 17.39,107.68 16.83,108.24 16.59,108.24 16.49,108.34 QX4.4
  IN1 w0.127: v1(126.77,129.97) 126.9,130.09 127.52,130.09 127.84,130.41 127.84,130.86 127.38,131.32 126.29,131.32 125.98,131 125.22,131 124.74,131.49 119.94,131.49 119.53,131.07 116.02,131.07 114.5,129.55 110.99,129.55 109.53,128.09 107.98,128.09 106,126.11 97.64,126.11 96.93,126.82 96.93,130.68 95.38,132.23 91.92,132.23 89.95,130.25 86.53,130.25 82.14,125.86 74.57,125.86 67.29,118.58 60.56,118.58 60.14,118.16 42.95,118.16 40.11,115.33 29.94,115.33 23.03,108.42 19.63,108.42 v1(19.46,108.59)
  BOTTOM w0.076: UC1.C9 124.93,124.89 125.28,125.25 125.28,125.92 125.56,126.2 125.56,126.2 125.79,126.43 126.54,127.18 126.54,129.54 126.39,129.69 126.39,130.11 126.46,130.17 126.58,130.17 v1(126.77,129.97)
  BOTTOM w0.102: v1(19.46,108.59) 19.58,108.47 19.78,108.47 19.9,108.6 19.9,108.79 19.69,109 19.69,109.13 19.52,109.3 RP52.2
CPU_DPB_CTRLDAT_R: length 11.5
  TOP w0.102: JHDMI.16 9.24,106.65 9.01,106.88 9.01,108.44 9.39,108.82 9.5,108.82 9.51,108.81 10.05,108.81 10.06,108.82 11.37,108.82 v3(11.97,108.23) 12.47,107.73 13.7,107.73 RX17.1 14.67,106.75 14.71,106.75 14.71,106.56 15.02,106.25 16.36,106.25 16.49,106.37 QX4.3
CPU_DPC_AUX: length 7.3
  BOTTOM w0.076: 128.62,129.04 128.55,129.04 v3(128.24,128.73) 127.79,128.28 127.79,127.25 126.67,126.12 126.67,126.09 126.54,125.96 126.38,125.96 126.2,125.78 126.2,125.31 126.29,125.21 126.43,125.21 126.53,125.31 UC1.A6
  BOTTOM w0.089: RP51.4 129.45,129.21 129.3,129.06 128.63,129.06 128.62,129.04
CPU_DPC_AUX#: length 7.9
  BOTTOM w0.076: UC1.B6 126.25,125.01 126.5,125.01 126.79,125.3 126.86,125.37 126.86,126.05 127.98,127.17 127.98,128.2 128.37,128.59 128.62,128.84
  BOTTOM w0.089: 128.62,128.84 128.63,128.85 129.38,128.85 130.08,128.85 130.45,129.23 RP51.2
CPU_DPC_CTRLCLK: length 120.6
  IN1 w0.084: 88.91,116.48 88.93,116.48 88.95,116.5 89.01,116.5 89.03,116.53 91.87,116.53 92.31,116.97 94.09,116.97 95.11,117.99 95.84,117.99 96.49,118.63 96.49,122.03 96.76,122.3 115.74,122.3 117.16,123.72 123.91,123.72 123.95,123.68 124.01,123.68 v1(124.42,123.27)
  IN1 w0.127: v1(43.27,106.15) 43.45,106.32 46.27,106.32 51.39,111.44 64.75,111.44 65.14,111.83 70.76,111.83 73.43,114.5 81.25,114.5 83.23,116.48 88.91,116.48
  IN3 w0.127: v1(43.27,106.15) 43.11,106.31 27.59,106.31 24.89,109.01 19.16,109.01 18.55,108.41 18.25,108.41 v1(18.06,108.21)
  BOTTOM w0.089: UC1.D9 125.05,123.78 124.54,123.27 v1(124.42,123.27)
  BOTTOM w0.102: RP52.3 19.02,109.26 18.88,109.11 18.88,108.71 18.56,108.4 18.25,108.4 v1(18.06,108.21)
CPU_DPC_CTRLDAT: length 120.1
  IN1 w0.084: v1(124.43,124.28) 124.05,123.91 124.01,123.95 117.07,123.95 115.65,122.53 96.66,122.53 96.26,122.13 96.26,118.72 95.75,118.21 95.01,118.21 94,117.2 92.22,117.2 91.77,116.75 88.91,116.75
  IN1 w0.127: v1(43.27,106.73) 43.41,106.59 46.16,106.59 51.28,111.71 64.64,111.71 65.03,112.1 70.65,112.1 73.32,114.77 81.14,114.77 83.12,116.75 88.91,116.75
  IN3 w0.127: v1(18.06,108.8) 18.2,108.66 18.44,108.66 19.05,109.27 24.99,109.27 27.69,106.56 43.1,106.56 v1(43.27,106.73)
  BOTTOM w0.089: v1(124.43,124.28) 124.59,124.28 124.82,124.05 124.82,123.84 124.76,123.78 UC1.D11
  BOTTOM w0.102: RP52.4 18.52,109.26 18.66,109.11 18.66,108.8 18.47,108.61 18.25,108.61 v1(18.06,108.8)
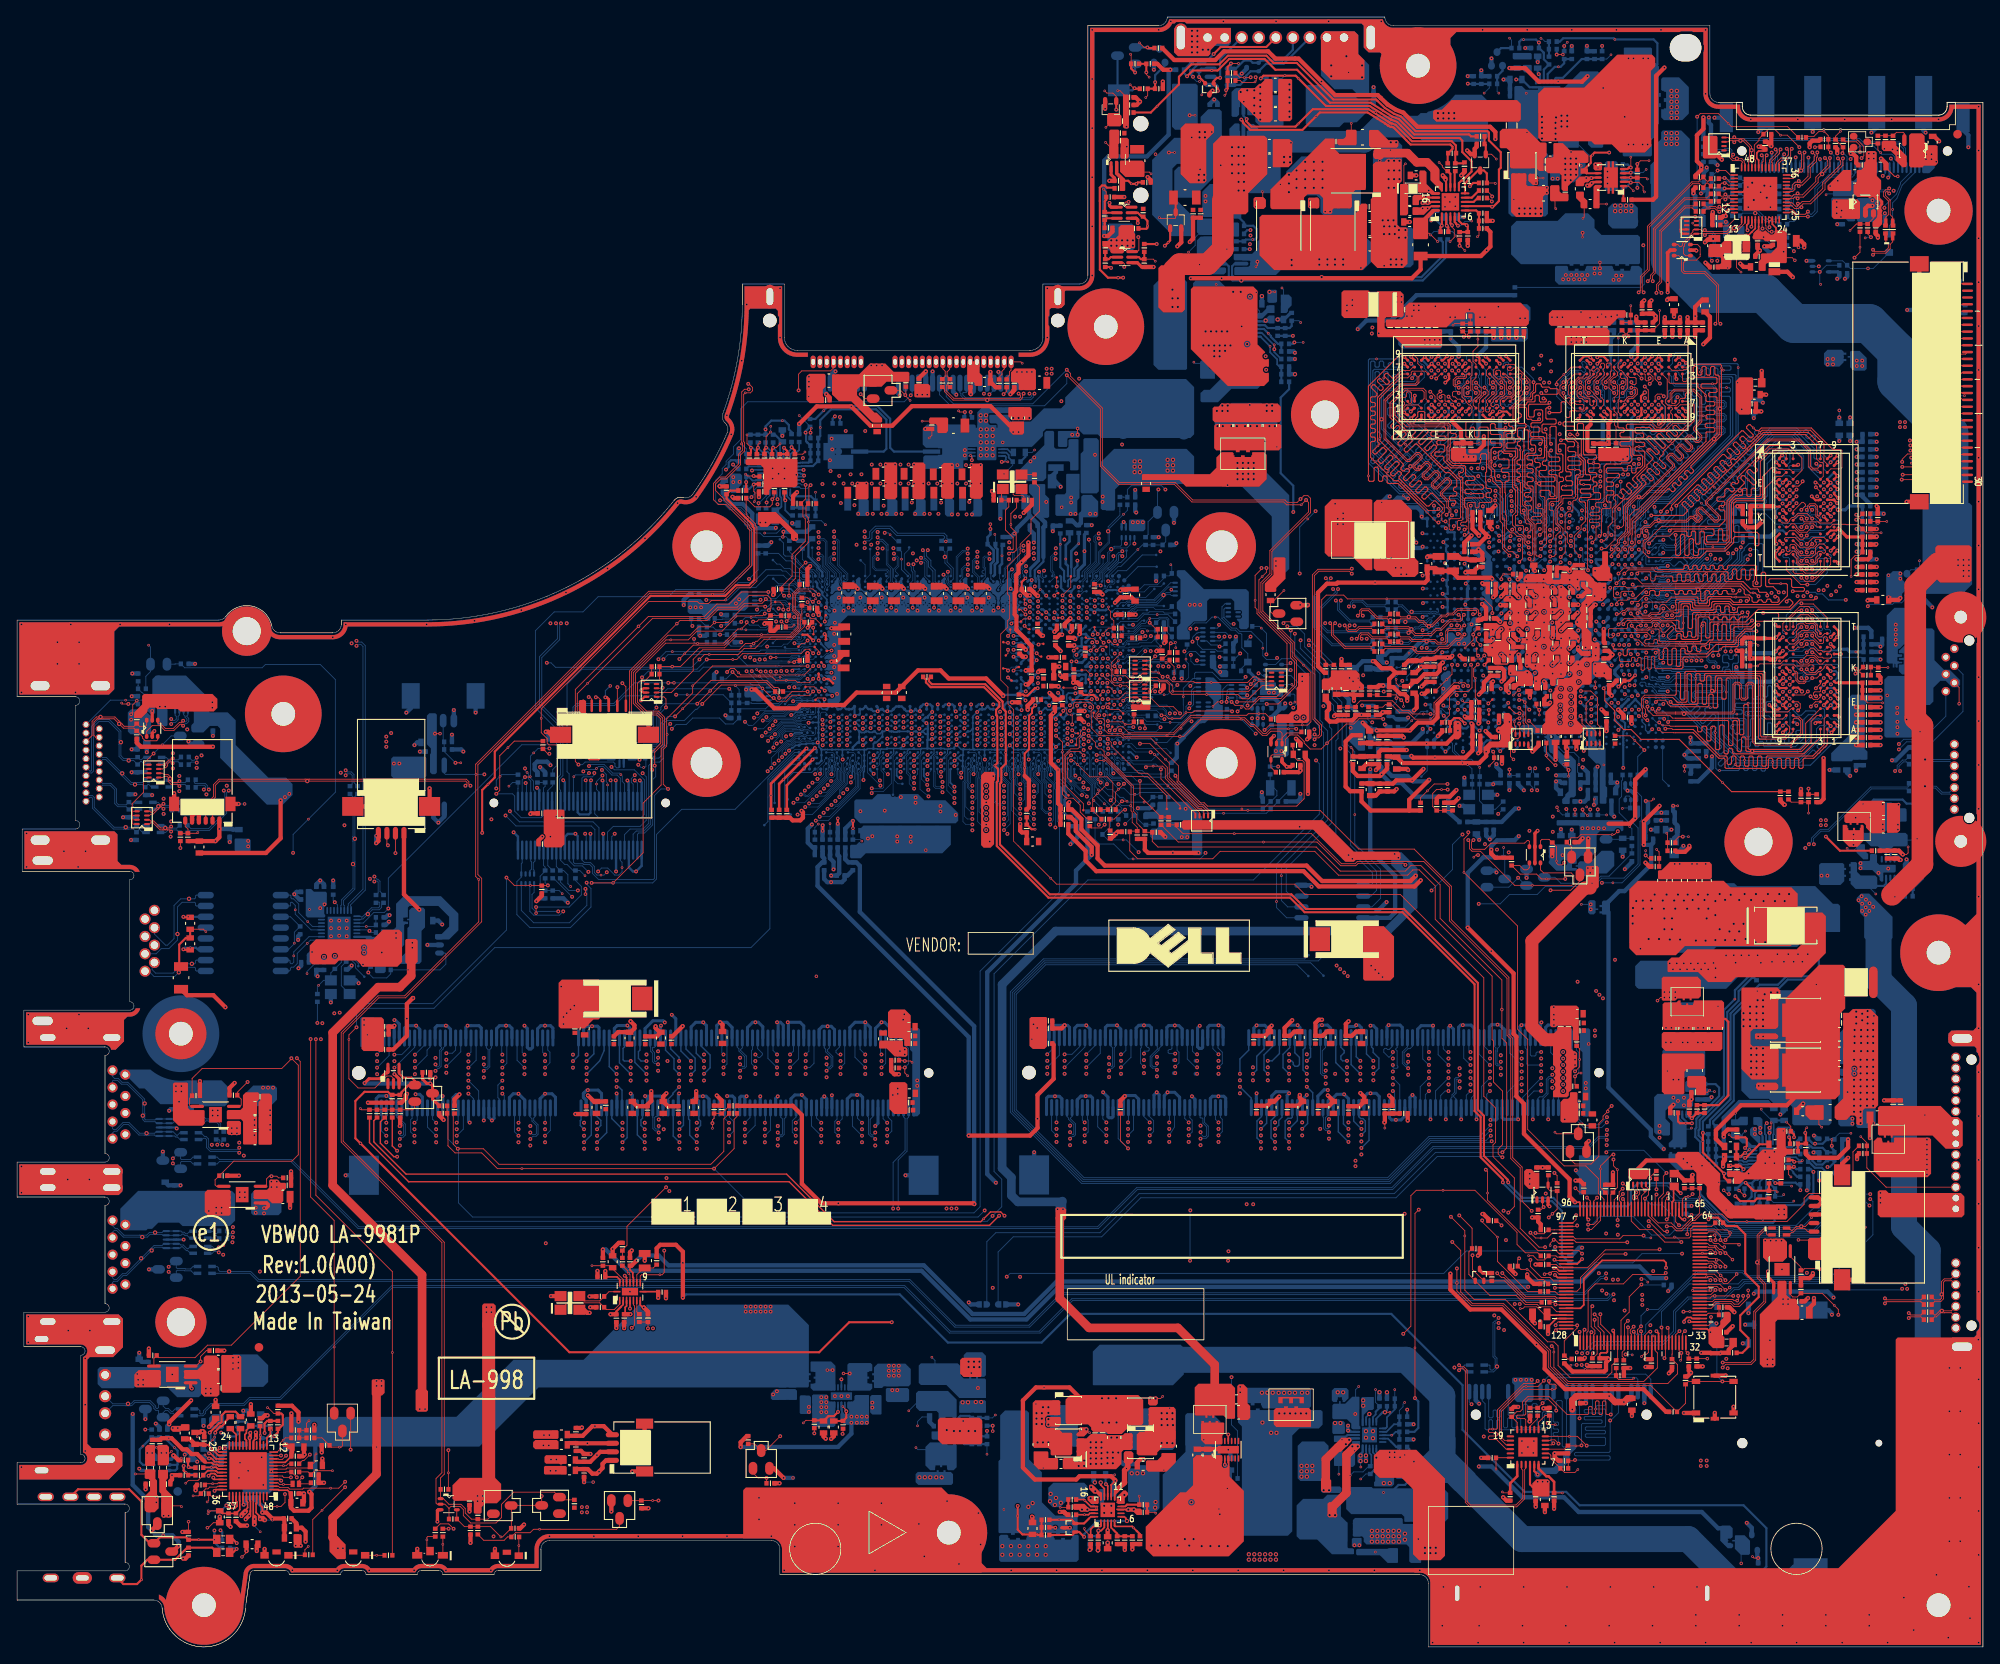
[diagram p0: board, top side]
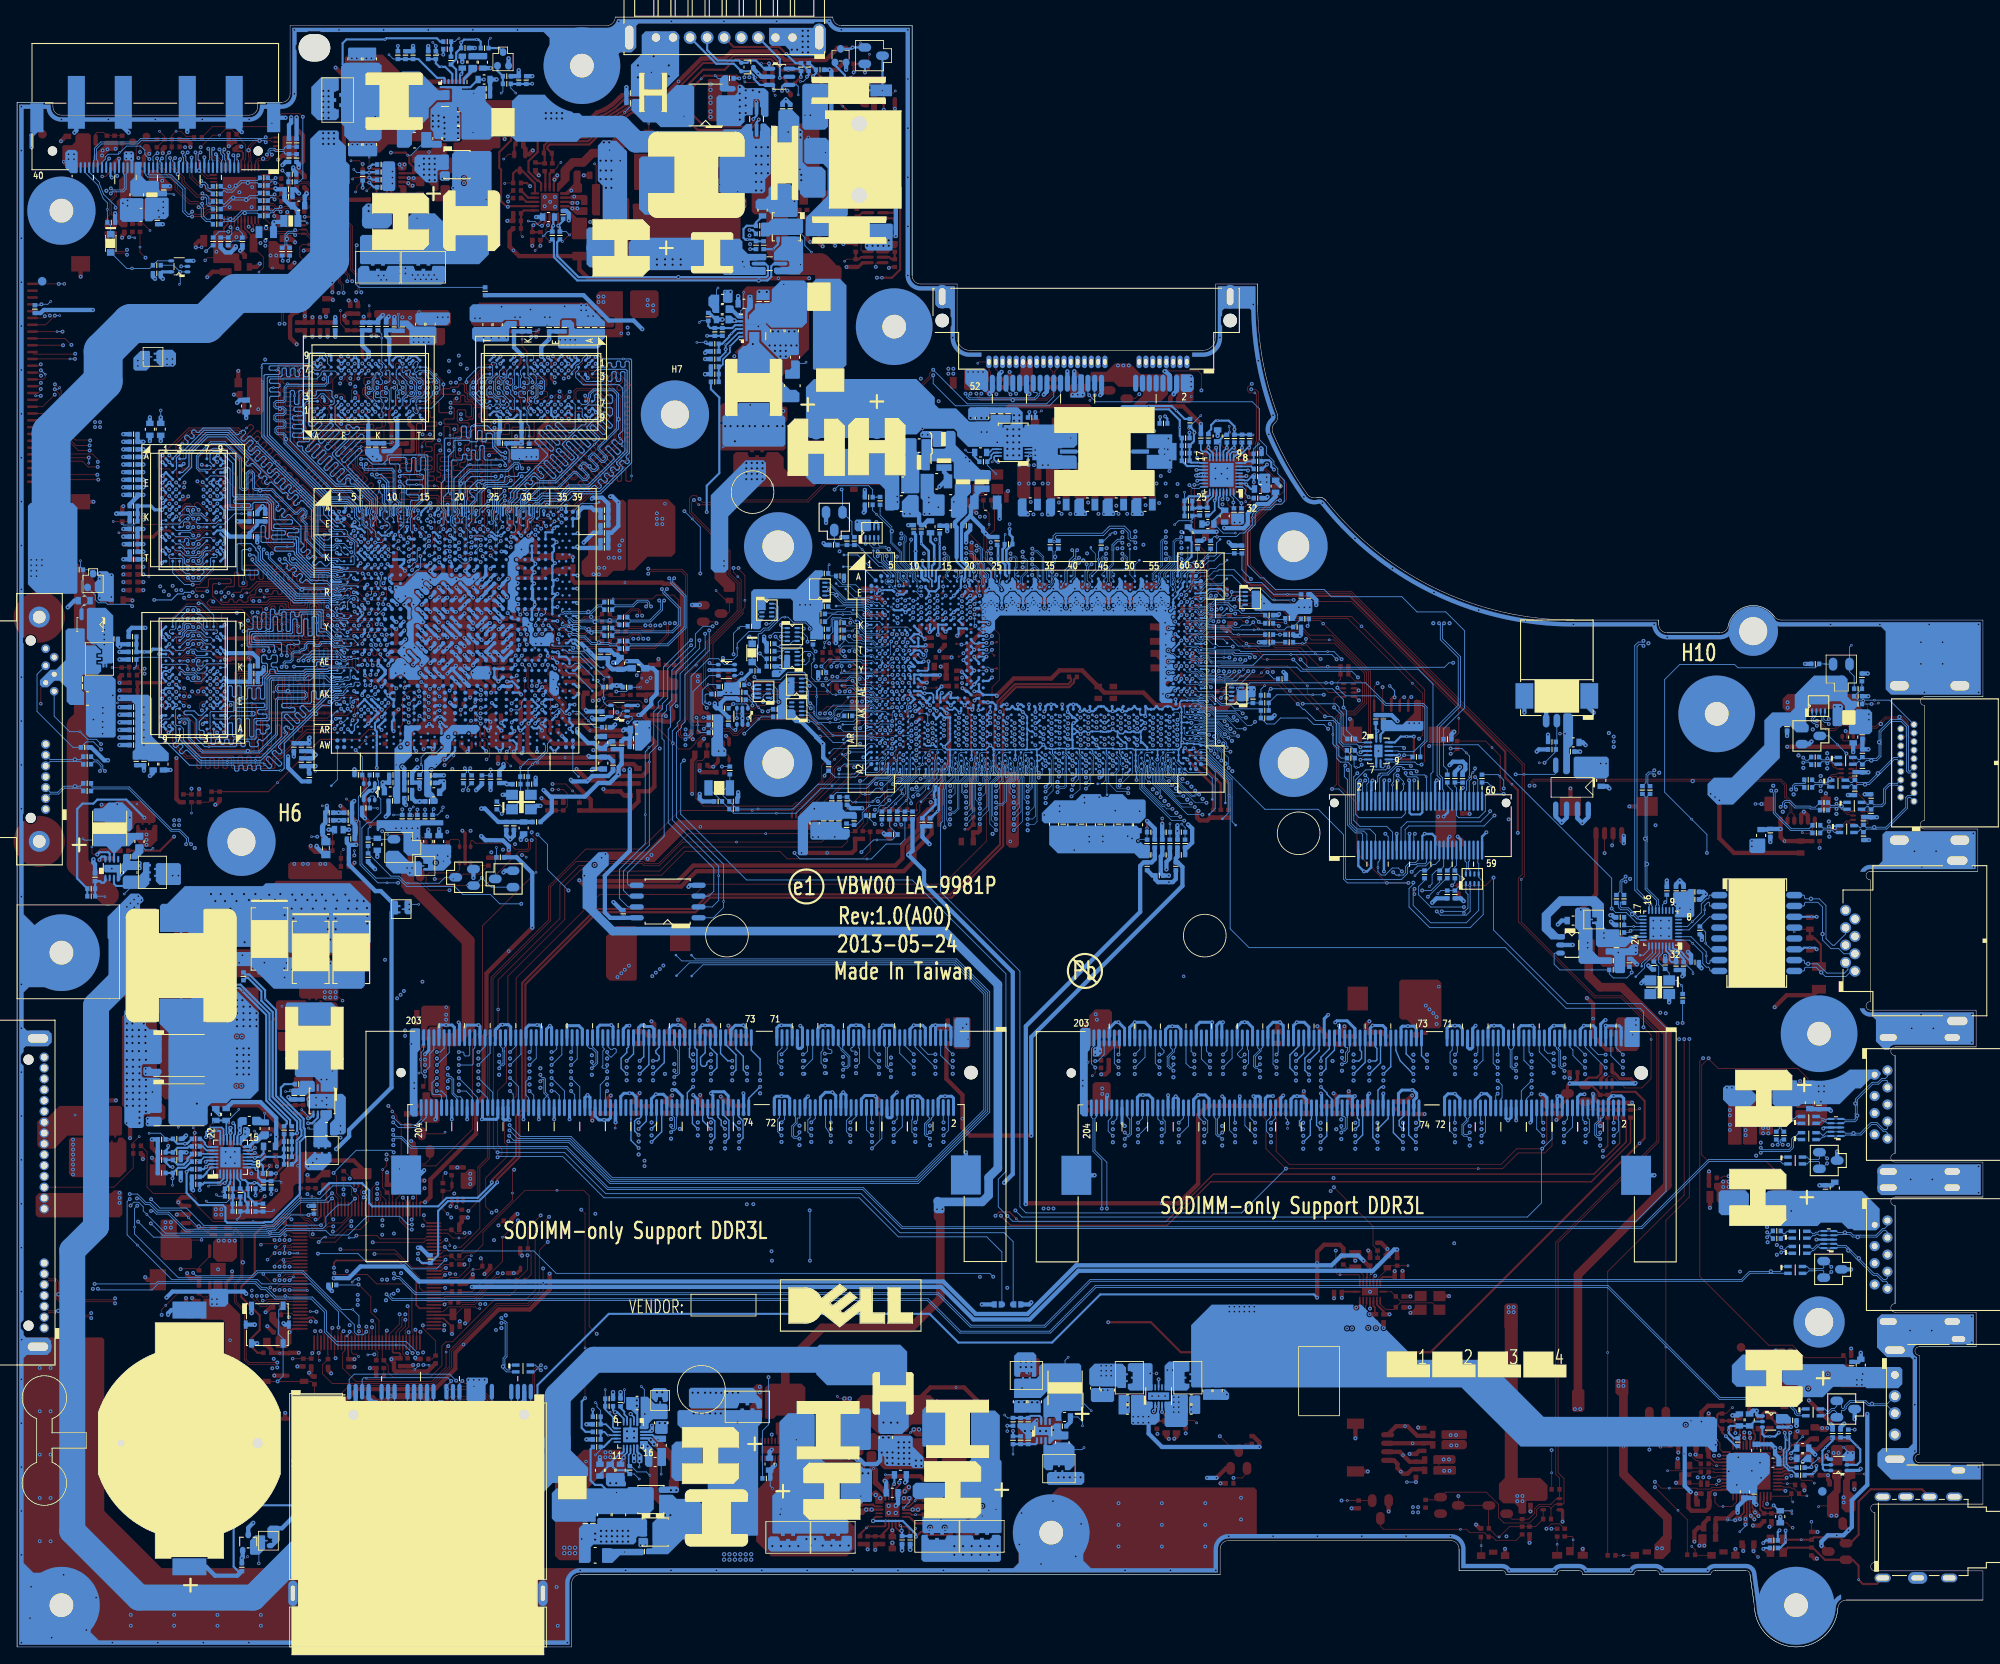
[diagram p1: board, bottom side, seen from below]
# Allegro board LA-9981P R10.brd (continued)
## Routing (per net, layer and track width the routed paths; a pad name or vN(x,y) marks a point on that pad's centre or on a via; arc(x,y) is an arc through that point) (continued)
CPU_EDP_AUX#_C: length 3.2
  TOP w0.102: UX4.3 200.75,171.78 200.3,172.24 v1(200.1,172.24) 199.51,172.24 CX44.2
  BOTTOM w0.102: RX37.1 200.78,172.01 200.33,172.01 v1(200.1,172.24)
CPU_EDP_AUX_C: length 3.2
  TOP w0.102: CX43.2 199.8,171.64 v1(200.13,171.64) 200.32,171.64 200.58,171.38 UX4.4
  BOTTOM w0.102: RX39.1 200.59,171.79 200.28,171.79 v1(200.13,171.64)
CPU_EDP_HPD#: length 13.1
  BOTTOM w0.076: 129.35,126.66 129.02,126.66 128.05,125.7 128.05,125.37 128.22,125.2 128.54,125.2 128.67,125.08 128.67,124.76 128.53,124.62 128.08,124.62 127.8,124.34 127.8,124.24 127.63,124.07 127.38,124.07 127.08,123.78 UC1.D6
  BOTTOM w0.102: QC3.1 134.62,129.58 RC78.2 RC89.1 RC105.2 131.89,129.21 v2(131.36,128.67) 129.35,126.66
CPU_EDP_N0_C: length 3.2
  TOP w0.102: CX46.2 199.83,169.89 200.05,169.89 v1(200.22,169.72) 200.38,169.89 200.71,169.89 200.82,169.78 UX4.8
  BOTTOM w0.102: v1(200.22,169.72) 200.47,169.97 200.63,169.97 RX43.1
CPU_EDP_N1_C: length 6.1
  TOP w0.102: CX39.2 197.95,168.6 198.4,168.6 198.48,168.68 198.96,168.68 199.16,168.48 199.3,168.48 v1(199.51,168.27) 199.76,168.53 199.98,168.53 200.49,169.03 200.7,169.03 200.76,168.98 UX4.10
  BOTTOM w0.102: v1(199.51,168.27) 199.67,168.44 200.09,168.44 200.37,168.16 200.66,168.16 RX47.1
CPU_EDP_P0_C: length 3.1
  TOP w0.102: CX42.2 199.71,170.1 200.02,170.1 200.21,170.3 v1(200.22,170.31) 200.42,170.1 200.7,170.1 200.78,170.18 UX4.7
  BOTTOM w0.102: v1(200.22,170.31) 200.33,170.19 200.74,170.19 RX41.1
CPU_EDP_P1_C: length 6.1
  TOP w0.102: UX4.9 200.81,169.38 200.68,169.25 200.4,169.25 199.89,168.74 199.62,168.74 v1(199.51,168.86) 199.34,168.69 199.25,168.69 199.05,168.9 198.39,168.9 198.31,168.82 198.03,168.82 CX38.2
  BOTTOM w0.102: RX45.1 200.7,168.37 200.46,168.37 200.18,168.65 199.71,168.65 v1(199.51,168.86)
CPU_PWR_DEBUG#: length 71.9
  TOP w0.102: v1(88.12,121.56) 88.36,121.8 88.36,122.86 87.91,123.3 85.8,123.3 84.41,121.91 82.11,121.91 80.8,120.6 74.48,120.6 v2(66.87,112.99) 65.66,111.78 65.66,106.91 v1(66.09,106.48)
  IN3 w0.127: v1(66.09,106.48) 66.09,106.16 64.51,104.58 64.51,102.84 65.22,102.12 65.22,100.45 65.9,99.77 65.9,96.41 65.01,95.52 65.01,91.35 64.68,91.02 64.68,88.32 v1(65.05,87.95)
  BOTTOM w0.076: 88.91,122.19 90.01,122.19 90.18,122.02 90.53,122.02 90.88,121.67 91.84,121.67 92,121.84 92.78,121.84 92.9,121.71 93.96,121.71 UC1.H59
  BOTTOM w0.102: RC50.1 62.88,90.12 v1(65.05,87.95) ; R253.1 81.91,120.46 82.63,120.46 82.69,120.52 83.66,120.52 R255.2 84.32,121.18 86.87,121.18 87.25,121.56 v1(88.12,121.56)
  BOTTOM w0.109: 88.91,122.19 88.57,122.19 88.17,121.79 88.17,121.61 v1(88.12,121.56)
CPU_PWR_DEBUG#_R: length 2.6
  BOTTOM w0.102: RC50.2 62.2,91.61 JXDP1.45
CPUSB#: length 7.6
  BOTTOM w0.089: RC111.2 134.89,121.04 v2(133.62,121.04) 132.09,121.04 131.26,120.22 129.32,120.22 UC1.K3
CS1: length 3.7
  TOP w0.102: v2(125.09,13.89) 125.09,13.71 PR105.1
  TOP w0.203: PU100.1 127.03,14.21 126.93,14.11 126.14,14.11 125.82,13.79 PR105.1
CS2: length 3.9
  TOP w0.203: 131.22,13.6 v2(130.86,13.96) 130.68,14.14 128.71,14.14 128.63,14.21 PU100.5
  TOP w0.254: PR108.1 131.6,13.22 131.22,13.6
CS_1.35V: length 5
  BOTTOM w0.102: v2(156.24,20.11) 156.66,20.53 157.75,20.53 158.41,21.19 PR205.2
  BOTTOM w0.203: PU200.13 158.51,22.72 158.72,22.51 158.72,21.32 PR205.2
CSA0#_0: length 41.3
  TOP w0.102: UV18.L2 170.66,145.58 170.66,146.19 170.92,146.45 170.96,146.45 171.37,146.86 171.37,147.27 v1(170.99,147.65) ; 174.07,135.39 174.07,132.36 v2(174.19,132.24) 174.34,132.09 174.34,128.9 174.83,128.41 175.29,128.41 v1(175.83,127.87)
  TOP w0.127: 174.07,135.39 174.07,136.47 173.81,136.73 173.4,136.73 173.27,136.86 173.27,137.06 173.18,137.16 173.18,137.96 172.76,138.37 172.76,138.74 172.86,138.85 172.86,139.12 172.76,139.23 172.76,140.41 172.99,140.64 173.88,140.64 174,140.76 174,141.02 173.88,141.15 172.8,141.15 172.67,141.27 172.67,141.53 172.8,141.65 173.88,141.65 174,141.78 174,142.03 173.88,142.16 172.8,142.16 172.67,142.29 172.67,143.31 172.8,143.44 173.11,143.44 173.24,143.31 173.24,142.96 173.37,142.83 174.32,142.83 v1(174.45,142.96)
  IN1 w0.102: 173.66,142.86 172.54,143.98 172.54,145.37 171.37,146.54 171.37,147.27 v1(170.99,147.65)
  IN1 w0.14: 173.66,142.86 174.35,142.17 175.53,142.17 175.65,142.3 175.65,143.08 175.53,143.21 174.57,143.21 174.45,143.08 v1(174.45,142.96)
  BOTTOM w0.102: v1(175.83,127.87) 175.46,127.5 UV1.K24 ; v1(170.99,147.65) 171.33,147.65 171.39,147.72 171.39,148.73 171.27,148.85 171.27,149.06 171.39,149.18 171.39,149.65 UV19.L2
CSA1#_0: length 42
  TOP w0.102: UV20.L2 187.18,149.84 187.56,149.46 187.56,149.12 187.3,148.86 187.17,148.86 186.8,148.49 186.8,148.45 186.8,148.45 186.8,148.04 v1(187.18,147.65) ; v1(183.13,127.9) 182.51,128.51 182.51,130.26 183.31,131.05 183.31,131.49 183.81,132 183.81,133.68
  TOP w0.127: 183.81,133.68 183.81,134.13 183.68,134.26 183.23,134.26 183.1,134.39 183.1,134.64 183.23,134.77 184.33,134.77 184.46,134.89 184.46,135.15 184.33,135.28 183.34,135.28 183.21,135.4 183.21,135.66 183.34,135.78 184.29,135.78 184.41,135.91 184.41,136.16 184.29,136.29 v2(183.59,136.29) 183.28,136.29 183.16,136.42 183.16,136.67 183.28,136.8 184.29,136.8 184.41,136.93 184.41,137.3 184.29,137.43 183.94,137.43 183.81,137.56 183.81,139.15 183.33,139.63 183.33,141.58 183.22,141.69 182.76,141.69 182.28,142.17 v1(182,142.17)
  IN1 w0.102: 185.5,142.86 186.43,143.8 186.43,145.74 187.56,146.86 187.56,147.27 v1(187.18,147.65)
  IN1 w0.14: 185.5,142.86 184.38,141.74 182.43,141.74 v1(182,142.17)
  BOTTOM w0.102: UV21.L2 187.18,145.24 187.05,145.11 186.9,145.11 186.77,145.24 186.77,147.25 v1(187.18,147.65) ; v1(183.13,127.9) 183.11,127.88 183.11,126.54 183.37,126.28 183.48,126.28 184.07,125.69 UV1.M13
CSB0#_0: length 43
  TOP w0.102: 194.39,126.32 192.35,126.32 v2(192.16,126.51) 188.62,126.51 188.61,126.5 188.34,126.5 v1(187.69,125.85) ; v1(209.75,131.3) 209.37,130.92 208.96,130.92 208.96,130.92 208.92,130.92 208.55,131.3 208.55,131.42 208.28,131.68 207.94,131.68 207.56,131.3 UV22.L2
  TOP w0.127: v1(203.87,124.73) 203.87,126.7 203.75,126.83 200.58,126.83 200.45,126.7 200.45,126.45 200.33,126.32 200.07,126.32 199.95,126.45 199.95,126.7 199.82,126.83 199.57,126.83 199.44,126.7 199.44,126.45 199.31,126.32 199.06,126.32 198.93,126.45 198.93,126.7 198.8,126.83 198.55,126.83 198.42,126.7 198.42,126.45 198.3,126.32 198.04,126.32 197.91,126.45 197.91,126.7 197.79,126.83 197.53,126.83 197.41,126.7 197.41,126.45 197.28,126.32 197.03,126.32 196.9,126.45 196.9,126.7 196.77,126.83 196.52,126.83 196.39,126.7 196.39,126.45 196.26,126.32 196.01,126.32 195.88,126.45 195.88,126.7 195.76,126.83 195.5,126.83 195.37,126.7 195.37,126.45 195.25,126.32 194.39,126.32
  IN1 w0.102: 204.96,128.63 206.08,129.75 207.47,129.75 208.64,130.92 209.37,130.92 v1(209.75,131.3)
  IN1 w0.14: v1(203.87,124.73) 203.87,124.16 203.75,124.03 203.33,124.03 203.2,124.16 203.2,125.18 204.93,126.91 204.93,128.6 204.96,128.63
  BOTTOM w0.102: UV23.L2 212.15,131.3 211.75,130.9 210.16,130.9 v1(209.75,131.3) ; v1(187.69,125.85) 187.71,125.87 187.71,125.14 187.86,124.99 187.86,124.47 187.48,124.09 UV1.P10
CSB1#_0: length 42.7
  TOP w0.102: 194.39,114.7 192.04,114.7 191.94,114.8 191.94,116.06 191.84,116.16 191.63,116.16 191.53,116.06 191.53,114.75 191.41,114.63 191.24,114.63 191.12,114.75 191.12,116.06 191.02,116.16 190.82,116.16 190.72,116.06 190.72,114.62 190.61,114.51 190.45,114.51 190.33,114.62 190.33,115.91 190.23,116.01 190.04,116.01 189.94,115.91 189.94,115.64 189.84,115.54 189.71,115.54 189.61,115.64 189.61,115.93 189.51,116.03 189.31,116.03 189.21,115.93 189.21,115.64 189.1,115.54 187.93,115.54 187.83,115.64 v1(187.83,116.41) ; UV25.L2 211.94,115.62 211.56,115.24 211.22,115.24 210.96,115.5 210.96,115.63 210.59,116 210.55,116 210.55,116 210.13,116 v1(209.75,115.62)
  TOP w0.127: 194.39,114.7 195.09,114.7 195.24,114.85 195.24,115.92 195.39,116.07 198.03,116.07 198.68,116.73 199.4,116.73 v2(199.66,116.98) 199.96,117.28 201.58,117.28 201.73,117.44 201.73,118.23 202.59,119.09 v1(203.85,119.09)
  IN1 w0.102: 204.96,117.3 205.9,116.36 207.84,116.36 208.96,115.24 209.37,115.24 v1(209.75,115.62)
  IN1 w0.14: 204.96,117.3 203.85,118.41 v1(203.85,119.09)
  BOTTOM w0.102: UV1.AD10 187.83,116.26 v1(187.83,116.41) ; v1(209.75,115.62) 209.35,116.03 207.76,116.03 UV24.L2
CSCL: length 13.3
  TOP w0.102: UX4.13 202.12,166.87 201.62,166.37 v3(201.22,166.37) 200.78,166.37 200.37,165.96 197.97,165.96 v1(197.81,166.12) 197.63,165.94 197.55,165.94 197.3,166.19 RP57.2 196.5,166.19 196.41,166.1 196.41,165.92 196.18,165.69 196.18,165.57 195.19,164.58 195.19,164.35 195.03,164.19 194.88,164.19 194.64,164.43 QX6.4
  BOTTOM w0.102: RX6.2 199.32,164.06 199.01,164.37 199.01,165.62 198.64,165.99 197.94,165.99 v1(197.81,166.12)
CSDA: length 13.6
  TOP w0.102: QX6.1 195.55,163.13 195.31,163.37 195.31,164.14 195.42,164.25 195.42,164.49 196.41,165.47 196.41,165.59 196.51,165.69 RP57.1 197.3,165.69 197.32,165.72 197.63,165.72 v1(197.81,165.54) 198,165.73 200.47,165.73 200.87,166.14 201.71,166.14 202.52,166.95 UX4.14
  BOTTOM w0.102: RX31.2 198.78,164.38 v3(198.78,165.09) 198.78,165.52 198.54,165.76 198.03,165.76 v1(197.81,165.54)
CSIN: length 30.2
  BOTTOM w0.254: 152.89,160.6 v3(152.9,160.61) ; 152.89,160.6 142.61,160.6 142.4,160.81 142.4,161.87 142.71,162.19 PR702.3 ; 152.89,160.6 164.59,160.6 167.1,163.11 167.1,164.72 PR704.2
CSIP: length 31.4
  BOTTOM w0.254: 143.49,160.22 164.75,160.22 167.48,162.95 167.48,164.84 PR717.2 ; 143.49,160.22 v3(143.49,160.21) ; 143.49,160.22 142.45,160.22 142.01,160.66 142.01,161.87 141.7,162.19 PR702.2
CSN1_CPU: length 23.2
  BOTTOM w0.203: PU501.18 91.92,138.42 91.95,138.46 92.4,138.46
  BOTTOM w0.254: PL502.3 101.57,140.16 101.88,140.47 101.88,143.9 100.68,145.11 95.41,145.11 94.13,143.83 v2(94.13,142.98) 94.13,141.98 PR515.2 PR517.2 PC511.1 PC510.1 93.28,138.46 92.4,138.46
CSP1_CPU: length 13.6
  IN1 w0.254: v1(92.41,142.38) 92.51,142.48 92.51,142.98 93.69,144.16 95.72,144.16 v1(95.85,144.28)
  BOTTOM w0.102: PR518.1 92.93,143.12 v2(91.67,144.38)
  BOTTOM w0.203: 92.06,138.86 91.81,138.86 91.76,138.82 PU501.17
  BOTTOM w0.254: PR518.1 92.41,142.55 v1(92.41,142.38) 92.47,142.31 92.47,141.36 92.62,141.21 92.62,141.21 PR517.1 PC511.2 PC510.2 92.77,138.86 92.06,138.86 ; v1(95.85,144.28) 95.58,144.02 PH501.1
DAT_SMB: length 12.7
  TOP w0.102: v1(142.27,185.66) v2(143.15,185.66)
  TOP w0.254: PR20.1 141.88,185.25 142.27,185.65 v1(142.27,185.66)
  BOTTOM w0.254: v1(142.27,185.66) 142.27,185.65 142.24,185.61 PD1.1 142.84,185.05 143.79,186 144.55,186 144.81,185.74 PD3.2 145.77,186 148.28,186 149.52,187.24 PBATT.6
DBC_EN: length 173.9
  TOP w0.102: v1(192.73,37.46) 192.79,37.4 UE1.25 ; RX19.1 214.28,176.48 215.57,176.48 215.99,176.05 v1(215.99,175.27)
  IN2 w0.127: v1(215.99,175.27) 215.99,174.98 215.36,174.34 215.36,167.58 216.54,166.4 216.54,155.2 225.59,146.14 225.59,121.7 224.69,120.8 224.69,111.05 226.11,109.63 226.11,96.57 225.56,96.03 225.56,88.84 228.56,85.85 228.56,77.3 222.66,71.4 222.66,58.49 217.61,53.44 217.61,52.92 217.2,52.51 v1(217.19,52.51)
  BOTTOM w0.102: v1(192.73,37.46) 192.73,39.3 195.99,42.56 201.71,42.56 202.21,43.06 212.25,43.06 v2(216.31,47.12) 217.5,48.32 217.5,52.22 217.21,52.51 v1(217.19,52.51)
DBC_EN_R: length 5.2
  TOP w0.102: v2(213.71,177.71) 213.12,177.13 RX23.1 213.12,176.72 RX19.2 214.01,175.22 v1(213.94,175.14)
  BOTTOM w0.102: v1(213.94,175.14) 214,175.14 214.13,175.01 214.19,175.01 214.48,174.73 214.48,174.33 214.45,174.31 JLVDS.21
DC_TEST_A3_B3: length 0.7
  BOTTOM w0.089: UC1.A3 129.14,125.03 UC1.B3
DC_TEST_A4: length 6.1
  BOTTOM w0.102: T168.1 131.87,128.03 130.02,126.19 129.01,126.19 UC1.A4
DC_TEST_A60: length 6.8
  BOTTOM w0.102: T169.1 89.82,129.44 89.82,128.12 90.04,127.9 90.71,127.9
  BOTTOM w0.109: UC1.A60 93.55,125.77 93.18,126.15 92.46,126.15 90.71,127.9
DC_TEST_A61_B61: length 0.7
  BOTTOM w0.076: UC1.A61 92.89,124.97 UC1.B61
DC_TEST_A62: length 4.4
  BOTTOM w0.089: UC1.A62 91.84,125.97 91.05,125.97 90.58,126.44 89.92,126.44 89.4,126.96 89.06,126.96
  BOTTOM w0.102: T170.1 89.06,126.96
DC_TEST_AV1: length 3.9
  BOTTOM w0.076: UC1.AV1 130.34,104.24 130.69,103.9 132.93,103.9 T171.1
DC_TEST_AW1: length 4.3
  BOTTOM w0.089: T172.1 132.27,102.35 131.85,102.77 131.02,102.77 UC1.AW1
DC_TEST_AW63: length 7.4
  BOTTOM w0.102: T173.1 89.97,98.31 89.97,102.6 90.87,103.5 UC1.AW63
DC_TEST_AY2_AW2: length 0.7
  BOTTOM w0.076: UC1.AY2 129.62,103.05 UC1.AW2
DC_TEST_AY3_AW3: length 0.7
  BOTTOM w0.076: UC1.AY3 129.01,103.54 UC1.AW3
DC_TEST_AY60: length 6.1
  BOTTOM w0.102: T166.1 90.33,101.86 90.99,102.53 93.12,102.53 UC1.AY60
DC_TEST_AY61_AW61: length 0.7
  BOTTOM w0.076: UC1.AY61 92.87,103.5 UC1.AW61
DC_TEST_AY62_AW62: length 0.7
  BOTTOM w0.076: UC1.AW62 92.22,103.5 UC1.AY62
DC_TEST_B62_B63: length 0.7
  BOTTOM w0.254: UC1.B62 91.78,124.84 UC1.B63
DC_TEST_C1_C2: length 0.7
  BOTTOM w0.076: UC1.C1 130.16,124.3 UC1.C2
DDI1_LANE_N0: length 96.9
  IN1 w0.127: v1(24.23,100.4) 24.38,100.25 24.38,99.86 24.67,99.57 27.84,99.57 40.2,111.94 41.52,111.94 44.28,114.7 62.88,114.7 63.3,115.12 68.91,115.12 74.83,121.04 80.32,121.04 81.7,122.41 83.61,122.41 85.25,124.05 85.6,124.05 87.57,126.02 93.57,126.02 95.26,127.71 95.58,127.71 v1(95.76,127.54)
  BOTTOM w0.076: v1(95.76,127.54) 95.59,127.71 95.41,127.71 95.34,127.64 95.34,127.18 95.47,127.04 96.23,126.29 96.59,125.92 96.59,125.49 96.65,125.37 96.65,125.15 96.63,125.07 96.62,125.05 96.59,125 96.59,124.86 96.62,124.76 96.83,124.55 97.01,124.55 97.18,124.38 UC1.C54
  BOTTOM w0.102: v1(24.23,100.4) 24.35,100.28 24.35,97.85 22.44,95.94 20.38,95.94 CX18.2
DDI1_LANE_N1: length 94.2
  IN1 w0.127: v1(23.71,98.5) 23.47,98.74 23.47,100.6 27.7,104.83 31.13,104.83 39.01,112.72 41.19,112.72 44.01,115.53 61.34,115.53 61.71,115.9 68.55,115.9 75.86,123.21 83.18,123.21 86.78,126.81 91.49,126.81 92.54,127.85 93.73,127.85 93.93,127.65 v1(93.93,127.54)
  BOTTOM w0.076: UC1.B58 94.88,124.64 94.88,124.73 95,124.85 95,124.97 94.97,125 94.87,125 94.83,125.04 94.83,125.19 94.87,125.23 94.96,125.23 95,125.27 95,126.03 94.36,126.66 94.36,127.79 94.28,127.87 94.16,127.87 94.11,127.82
  BOTTOM w0.089: v1(93.93,127.54) 93.93,127.64 94.11,127.82
  BOTTOM w0.102: CX16.2 19.64,98.46 20.13,98.46 20.26,98.59 21.96,98.59 22.61,99.24 23.23,99.24 23.49,98.98 23.49,98.72 v1(23.71,98.5)
DDI1_LANE_N2: length 96.9
  IN1 w0.127: v1(21.06,104.27) 21.23,104.1 22.84,104.1 24.22,105.48 24.22,108.5 30.26,114.55 40.43,114.55 43.26,117.38 60.56,117.38 60.94,117.76 67.67,117.76 74.97,125.05 82.44,125.05 86.36,128.98 91.03,128.98 91.67,129.63 92.07,129.63 92.58,130.15 92.58,130.7 93.3,131.42 94.4,131.42 94.88,130.95 94.88,130.19 95.1,129.97 95.58,129.97 v1(95.76,130.14)
  BOTTOM w0.076: UC1.B55 97.15,124.91 97.37,125.13 97.37,125.83 96.34,126.85 96.34,129.54 96.34,129.7 96.16,129.89 96.01,129.89 v1(95.76,130.14)
  BOTTOM w0.102: v1(21.06,104.27) 20.75,103.96 20.5,103.96 CX14.2
DDI1_LANE_N3: length 95.4
  IN1 w0.127: v1(22.48,100.53) 22.27,100.74 22.27,101.07 25.55,104.36 25.55,108.35 30.7,113.5 40.87,113.5 43.69,116.32 60.99,116.32 61.35,116.68 68.18,116.68 75.5,124 82.87,124 86.62,127.75 91.29,127.75 92.15,128.61 92.92,128.61 93.29,128.99 93.29,129.53 93.42,129.66 93.78,129.66 v1(93.96,129.49)
  BOTTOM w0.076: UC1.A57 95.5,125.56 95.62,125.44 95.72,125.44 95.81,125.53 95.81,125.81 94.73,126.89 94.73,129.53 94.48,129.78 94.05,129.78 93.96,129.69 v1(93.96,129.49)
  BOTTOM w0.102: v1(22.48,100.53) 22.29,100.72 22.29,101 22.05,101.24 20.87,101.24 20.79,101.32 20.79,101.53 CX12.2
DDI1_LANE_P0: length 96.7
  IN1 w0.127: v1(95.76,128.19) 95.55,127.99 95.15,127.99 93.46,126.29 87.46,126.29 85.49,124.32 85.13,124.32 83.49,122.69 81.58,122.69 80.21,121.31 74.72,121.31 68.8,115.39 63.19,115.39 62.76,114.97 44.16,114.97 41.4,112.21 40.09,112.21 27.72,99.85 24.78,99.85 24.65,99.97 24.65,100.25 v1(24.81,100.4)
  BOTTOM w0.076: v1(95.76,128.19) 95.47,127.9 95.33,127.9 95.15,127.72 95.15,127.1 95.24,127 95.34,126.91 96.43,125.82 96.43,125.45 96.49,125.29 96.49,125.18 96.44,125.06 96.43,125.03 96.43,124.84 96.47,124.69 96.57,124.54 UC1.C55
  BOTTOM w0.102: CX19.2 20.25,95.72 22.53,95.72 24.57,97.76 24.57,100.16 v1(24.81,100.4)
DDI1_LANE_P1: length 94.5
  IN1 w0.127: v1(23.12,98.5) 23.19,98.57 23.19,100.71 27.58,105.1 31.02,105.1 38.9,112.99 41.08,112.99 43.89,115.8 61.23,115.8 61.6,116.17 68.43,116.17 75.74,123.48 83.07,123.48 86.67,127.08 91.38,127.08 92.42,128.12 93.86,128.12 v1(93.93,128.19)
  BOTTOM w0.076: 94.06,128.06 94.36,128.06 94.55,127.87 94.55,126.74 95.19,126.11 95.19,124.77 95.24,124.72 95.24,124.47 94.94,124.17 UC1.C58
  BOTTOM w0.089: 94.06,128.06 v1(93.93,128.19)
  BOTTOM w0.102: v1(23.12,98.5) 23.27,98.65 23.27,98.89 23.14,99.02 22.7,99.02 22.05,98.37 20.35,98.37 20.22,98.25 19.22,98.25 CX17.2
DDI1_LANE_P2: length 96.4
  IN1 w0.127: v1(95.76,129.49) 95.55,129.7 94.98,129.7 94.6,130.08 94.6,130.84 94.29,131.15 93.41,131.15 92.85,130.59 92.85,130.03 92.18,129.36 91.79,129.36 91.14,128.71 86.48,128.71 82.55,124.78 75.08,124.78 67.78,117.49 61.05,117.49 60.67,117.1 43.38,117.1 40.55,114.27 30.37,114.27 24.49,108.39 24.49,105.37 22.95,103.83 21.21,103.83 v1(21.06,103.69)
  BOTTOM w0.076: v1(95.76,129.49) 95.96,129.7 96.08,129.7 96.15,129.62 96.15,126.78 97.18,125.75 97.18,125.2 97.1,125.13 97.08,125.13 96.88,125.32 UC1.A55
  BOTTOM w0.102: v1(21.06,103.69) 21,103.74 20.41,103.74 CX15.2
DDI1_LANE_P3: length 95.6
  IN1 w0.127: v1(21.89,100.53) 21.99,100.63 21.99,101.18 25.28,104.47 25.28,108.46 30.58,113.77 40.76,113.77 43.58,116.59 60.88,116.59 61.24,116.95 68.07,116.95 75.39,124.27 82.75,124.27 86.5,128.02 91.18,128.02 92.04,128.88 92.8,128.88 93.02,129.1 93.02,129.64 93.31,129.93 93.75,129.93 v1(93.96,130.13)
  BOTTOM w0.076: v1(93.96,130.13) 94.12,129.97 94.56,129.97 94.92,129.61 94.92,126.97 96,125.89 96,125.46 95.5,124.96 UC1.B57
  BOTTOM w0.102: v1(21.89,100.53) 22.08,100.72 22.08,100.91 21.96,101.03 21.17,101.03 CX13.2
DDR3_DRAMRST#: length 146.1
  TOP w0.102: RD5.1 83.46,62.55 82.83,61.92 82.83,58.11 81.31,56.59 56.47,56.59 54.65,58.41 v1(51.65,58.41) 51.12,58.95 51.12,62.39 CD3.1 ; CD34.1 129.31,59.34 v1(130.2,58.45)
  IN1 w0.127: v1(130.2,58.45) 130.2,57.52 124.84,52.16 114.38,52.16 v1(113.4,51.18)
  BOTTOM w0.102: v1(113.4,51.18) 112.63,50.41 53.39,50.41 51.74,52.06 51.74,58.41 v1(51.65,58.41) 50.5,59.57 JDIMM1.30 ; v1(130.2,58.45) 129.05,59.61 JDIMM2.30
DDR3_DRAMRST#_CPU: length 135.2
  TOP w0.102: RD5.2 84.37,62.19 84.04,61.86 84.04,58.43 v1(81.69,56.08) v2(59.16,56.08) 56.3,56.08 54.46,57.92 51.34,57.92 50.5,58.76 50.5,62.18 50.4,62.28 CC35.1 RD3.2
  BOTTOM w0.076: 121.96,96.77 121.9,96.83 121.9,100.54 121.77,100.67 121.77,101.25 121.55,101.47 121.55,102.62 121.37,102.81 121.37,103.05 121.44,103.13 121.44,103.39 121.36,103.46 121.36,103.98 UC1.AV15
  BOTTOM w0.102: 121.96,96.77 122.16,96.57 122.16,88.53 112.87,79.23 112.87,51.61 112.15,50.89 86.88,50.89 v1(81.69,56.08)
DDR_A_BS0: length 76.9
  IN1 w0.084: 108.03,95.7 108.04,95.7 108.87,96.53 109.12,96.53
  IN1 w0.089: v1(109.86,99.54) 109.48,99.16 109.48,97.99 109.38,97.89 109.38,96.79 109.12,96.53
  IN1 w0.183: 108.03,95.7 107.42,95.09 107.42,81.36 100.72,74.66 100.23,74.66 100.09,74.51 100.09,72.92 99.96,72.79 98.59,72.79 98.47,72.92 98.47,74.53 98.34,74.66 97.86,74.66 97.73,74.53 97.73,71.1 97.61,70.98 97.13,70.98 97,71.1 97,73.69 96.88,73.82 96.4,73.82 96.27,73.69 96.27,71.1 96.14,70.98 95.67,70.98 95.54,71.1 95.54,72.19 95.41,72.32 94.94,72.32 94.81,72.19 94.81,71.07 94.72,70.98 80.15,70.98 79.2,70.02 78.39,70.02 77.59,69.22 v1(77.59,68.7)
  BOTTOM w0.076: v1(109.86,99.54) 108.97,100.42 108.97,104.41 109.24,104.67 109.24,104.74 UC1.AU35
  BOTTOM w0.165: v1(77.59,68.7) 77.59,69.13 76.6,70.12 JDIMM1.109
DDR_A_BS1: length 76.3
  IN1 w0.084: v1(109.87,100.29) 110.26,100.29 110.41,100.13 110.41,97 108.75,95.34
  IN1 w0.183: v1(77.59,65.65) 78.51,66.58 78.51,68.87 78.79,69.15 79.56,69.15 80.4,69.99 93.27,69.99 93.45,69.81 93.45,66.91 93.58,66.78 94.06,66.78 94.18,66.91 94.18,69.97 94.31,70.1 96.88,70.1 97,69.97 97,68.73 97.13,68.6 98.83,68.6 98.96,68.73 98.96,69.93 102.28,73.25 102.28,74.7 108.34,80.77 108.34,95.07 108.61,95.34 108.75,95.34
  BOTTOM w0.076: v1(109.87,100.29) 109.14,101.02 109.14,103.94 UC1.AV35
  BOTTOM w0.165: v1(77.59,65.65) 76.86,64.93 76.86,64.78 76.3,64.22 JDIMM1.108
DDR_A_BS2: length 73
  IN1 w0.084: 98.84,93.66 98.84,94.44 100.3,95.9 101.29,95.9 101.89,96.5 101.89,96.5 104.64,99.25 104.64,101.44 v1(105.13,101.93)
  IN1 w0.183: v1(66.75,68.68) 66.7,68.65 66.4,68.65 66.28,68.78 66.28,69.96 66.4,70.08 67.25,70.08 67.37,70.21 67.37,70.69 67.25,70.82 66.4,70.82 66.28,70.94 66.28,71.42 66.4,71.55 67.65,71.55 67.78,71.67 67.78,72.15 67.65,72.28 66.4,72.28 66.28,72.41 66.28,73.14 66.4,73.26 67.57,73.26 67.78,73.48 67.78,74.4 71.12,77.74 71.12,77.99 70.58,78.53 70.58,78.71 70.92,79.05 71.1,79.05 71.64,78.51 71.9,78.51 72.15,78.77 72.15,79.03 71.61,79.57 71.61,79.75 71.95,80.09 72.13,80.09 72.67,79.55 72.93,79.55 73.56,80.17 89.86,80.17 98.84,89.15 98.84,93.66
  BOTTOM w0.076: v1(105.13,101.93) 105.53,102.33 105.53,102.41 105.53,102.76 105.53,102.76 UC1.AY41
  BOTTOM w0.165: v1(66.75,68.68) 67.6,69.53 JDIMM1.79
DDR_A_CAS#: length 75.4
  IN1 w0.084: v1(109.86,104.58) 110.26,104.18 110.26,101.8 111.19,100.87 111.19,95.8 110.65,95.25 110.65,94.57
  IN1 w0.183: v1(78.98,67.11) 79.35,66.73 79.35,66.67 79.42,66.6 79.42,65.92 79.15,65.64 79.15,64.47 80.13,63.48 98.93,63.48 102.24,66.79 102.24,69.87 104.98,72.61 104.98,74.21 110.65,79.89 110.65,94.57
  BOTTOM w0.076: v1(109.86,104.58) 110,104.58 UC1.AU34
  BOTTOM w0.165: v1(78.98,67.11) 79.47,67.6 79.47,69.04 78.4,70.1 JDIMM1.115
DDR_A_D0: length 73.5
  IN3 w0.127: v1(85.31,108.47) 84.86,108.02 79.09,108.02 76.52,105.45 76.52,101.42 74.45,99.35 74.45,93.85 73.72,93.11 73.72,79.15 78.43,74.44 78.43,73.82 78.56,73.69 79.18,73.69 79.31,73.56 79.31,73.27 79.18,73.15 78.56,73.15 78.43,73.02 78.43,72.73 78.56,72.61 79.73,72.61 79.86,72.48 79.86,72.19 79.73,72.07 78.06,72.07 77.93,71.94 77.93,71.65 78.06,71.52 80.82,71.52 80.94,71.4 80.94,71.11 80.82,70.98 78.06,70.98 77.93,70.86 77.93,70.57 78.06,70.44 81.9,70.44 82.02,70.32 82.02,69.59 82.15,69.46 v1(82.79,69.46)
  BOTTOM w0.076: 86.08,108.05 86.24,108.05 87.64,109.46 89.87,109.46 90.57,110.15 91.26,110.15 91.39,110.28 UC1.AH63
  BOTTOM w0.102: v1(82.79,69.46) 82.6,69.65 JDIMM1.129 ; 86.08,108.05 85.72,108.05 v1(85.31,108.47)
DDR_A_D1: length 73.8
  IN3 w0.127: v1(86.37,108.95) 86.35,108.98 84.19,108.98 83.59,108.38 78.94,108.38 76.16,105.6 76.16,101.57 74.09,99.5 74.09,94 73.35,93.26 73.35,79 77.57,74.79 77.57,70.21 77.7,70.08 79.66,70.08 79.91,69.82 79.91,65.73 80.17,65.48 81.25,65.48 81.38,65.61 81.38,66.68 81.51,66.81 82.24,66.81 82.37,66.94 82.37,67.22 82.24,67.35 81.51,67.35 81.38,67.48 81.38,67.81 81.51,67.94 v1(82.79,67.94)
  BOTTOM w0.076: v1(86.37,108.95) 86.9,108.95 87.6,109.65 89.83,109.65 90.5,110.32 91.19,110.32 91.45,110.58 91.72,110.58 91.9,110.48 92.1,110.48 UC1.AH62
  BOTTOM w0.102: JDIMM1.131 83.2,68.34 v1(82.79,67.94)
DDR_A_D2: length 71.9
  IN3 w0.084: v1(88.58,108.06) 89.2,107.44 89.2,106.86 87.34,104.99 87.34,104.93 87.12,104.72
  IN3 w0.127: v1(86.53,67.94) 86.22,67.94 86.11,68.05 86.11,69.95 83.17,72.88 83.17,73.57 77.05,79.69 77.05,95.03 77.99,95.97 77.99,96.21 77.44,96.77 77.44,96.95 77.69,97.2 77.87,97.2 78.89,96.17 79.07,96.17 79.27,96.38 79.27,96.56 78.25,97.58 78.25,97.76 78.45,97.96 78.63,97.96 80.18,96.41 80.36,96.41 80.56,96.62 80.56,96.8 79.4,97.96 79.02,98.34 79.02,98.52 80.04,99.55 81.95,99.55 84.91,102.51 84.91,102.7 84.51,103.09 84.51,103.27 84.72,103.47 84.9,103.47 85.29,103.08 85.48,103.08 85.68,103.27 85.68,103.46 84.93,104.2 84.93,104.38 85.14,104.59 85.32,104.59 86.06,103.84 86.25,103.84 86.44,104.04 86.44,104.23 85.7,104.97 85.7,105.14 85.91,105.35 86.08,105.35 86.82,104.61 87.01,104.61 87.12,104.72
  BOTTOM w0.076: UC1.AK63 91.52,108.8 91.25,108.8 91.01,108.56 89.56,108.56 89.07,108.06 v1(88.58,108.06)
  BOTTOM w0.102: JDIMM1.141 86.2,70.05 86.08,69.93 86.08,68.39 v1(86.53,67.94)
DDR_A_D3: length 72.6
  IN3 w0.127: v1(87.74,107.22) 87.74,106.64 87.53,106.44 87.53,106.27 86.97,105.71 85.75,105.71 85.29,105.26 85.1,105.26 84.64,105.72 84.46,105.72 84.26,105.52 84.26,105.34 84.72,104.87 84.72,104.68 84.15,104.12 84.15,102.26 81.8,99.91 79.89,99.91 76.69,96.71 76.69,79.54 82.81,73.42 82.81,72.73 85.74,69.8 85.74,66.75 85.88,66.62 86.64,66.62 86.77,66.49 86.77,66.2 86.64,66.08 85.16,66.08 85.04,65.95 85.04,65.66 85.16,65.54 86.64,65.54 86.77,65.41 86.77,65.12 86.64,64.99 85.16,64.99 85.04,64.87 85.04,64.02 85.16,63.89 86.31,63.89 86.43,63.76 86.43,61.59 86.31,61.46 v1(85.3,61.46)
  BOTTOM w0.076: v1(87.74,107.22) 88.28,107.22 88.71,107.65 88.89,107.65 89.63,108.39 91.08,108.39 91.32,108.64 91.77,108.64 92.06,108.93 UC1.AK62
  BOTTOM w0.102: v1(85.3,61.46) 85.9,62.06 JDIMM1.140
DDR_A_D4: length 74.4
  IN3 w0.127: v1(83.44,59.94) 83.44,60.1 78.36,65.18 78.36,68.81 77.21,69.96 77.21,74.64 72.99,78.85 72.99,93.41 73.73,94.15 73.73,99.66 75.79,101.72 75.79,105.75 78.79,108.74 83.44,108.74 84.05,109.35 86.64,109.35 v1(86.76,109.46)
  BOTTOM w0.076: UC1.AH61 92.57,110.67 91.9,110.67 91.76,110.74 91.38,110.74 91.13,110.49 90.44,110.49 89.76,109.81 87.11,109.81 v1(86.76,109.46)
  BOTTOM w0.102: JDIMM1.132 83.5,62.08 83.98,61.61 83.98,60.47 v1(83.44,59.94)
DDR_A_D5: length 74.8
  IN3 w0.127: v1(83.44,61.46) 83.45,61.46 83.45,63.1 83.58,63.24 83.9,63.24 84.03,63.36 84.03,63.65 83.9,63.78 83.58,63.78 83.45,63.91 83.45,64.18 83.58,64.32 84.02,64.32 84.15,64.45 84.15,64.72 84.02,64.86 83.58,64.86 83.45,64.99 83.45,65.26 83.58,65.4 84.02,65.4 84.15,65.53 84.15,65.81 84.02,65.94 83.58,65.94 83.45,66.07 83.45,66.35 83.58,66.48 84.02,66.48 84.15,66.62 84.15,66.89 84.02,67.02 83.58,67.02 83.4,67.2 83.4,69.49 79.95,72.94 79.95,73.43 74.08,79.31 74.08,92.96 74.82,93.7 74.82,99.06 75.54,99.79 76.35,99.79 76.88,100.32 76.88,105.3 79.24,107.65 v1(86.5,107.65)
  BOTTOM w0.076: UC1.AH60 93.6,109.52 93.4,109.32 93.15,109.32 93.14,109.33 92.76,109.33 92.75,109.32 92.56,109.32 92.54,109.32 92.4,109.39 92.2,109.39 92.04,109.32 91.91,109.32 91.8,109.36 91.75,109.39 91.46,109.39 91.21,109.14 91.12,109.14 90.89,108.91 88.72,108.91 87.47,107.65 87.12,107.65
  BOTTOM w0.102: v1(83.44,61.46) 82.9,62 JDIMM1.130 ; 87.12,107.65 v1(86.5,107.65)
DDR_A_D6: length 73.2
  IN3 w0.084: 87.12,104.2 87.71,104.79 87.71,105.12 89.93,107.34 89.93,108.82 89.8,108.95 89,108.95 88.88,108.82 v1(88.88,108.54)
  IN3 w0.127: v1(86.53,69.46) 86.53,70.04 83.54,73.03 83.54,73.72 77.42,79.84 77.42,94.87 78.35,95.81 80.27,95.81 81.17,96.71 81.17,96.9 80.11,97.95 80.11,98.13 80.32,98.33 80.5,98.33 81.55,97.28 81.74,97.28 81.93,97.47 81.93,97.66 80.79,98.8 80.79,98.98 81,99.19 81.18,99.19 82.32,98.05 82.51,98.05 82.7,98.24 82.7,98.43 82.12,99.01 82.12,99.2 82.31,99.39 82.5,99.39 83.09,98.81 83.27,98.81 83.47,99.01 83.47,99.19 82.88,99.78 82.88,99.97 83.08,100.16 83.27,100.16 83.85,99.57 84.03,99.57 84.24,99.78 84.24,99.95 83.65,100.54 83.65,100.73 83.84,100.92 84.03,100.92 84.62,100.34 84.8,100.34 85,100.54 85,100.72 84.42,101.31 84.42,101.5 84.61,101.69 84.8,101.69 85.38,101.11 85.57,101.11 85.84,101.38 85.84,101.63 85.36,102.11 85.36,102.44 87.12,104.2
  BOTTOM w0.076: v1(88.88,108.54) 89.06,108.72 90.94,108.72 91.19,108.97 91.27,108.97 91.53,109.22 91.71,109.22 91.82,109.17 91.87,109.15 92.08,109.15 92.13,109.17 92.22,109.22 92.23,109.22 92.37,109.22 92.42,109.2 92.47,109.17 92.61,109.04 UC1.AK61
  BOTTOM w0.102: JDIMM1.143 86.8,70.15 87.35,69.6 87.35,69.42 87.05,69.12 86.87,69.12 v1(86.53,69.46)
DDR_A_D7: length 74.2
  IN3 w0.084: 86.58,106.08 v1(87.3,106.8)
  IN3 w0.127: 86.58,106.08 83.95,106.08 83.79,105.92 83.79,102.41 81.65,100.28 79.74,100.28 76.33,96.86 76.33,79.2 81.82,73.71 81.82,73.21 85.38,69.65 85.38,66.84 84.67,66.13 84.67,63.64 84.8,63.51 85.97,63.51 86.07,63.41 86.07,63.1 85.94,62.97 84.83,62.97 84.74,62.87 84.74,62.56 84.86,62.43 85.97,62.43 86.07,62.33 86.07,62.02 85.94,61.89 85.01,61.89 84.88,61.76 84.88,60.06 85.01,59.94 v1(85.3,59.94)
  BOTTOM w0.076: v1(87.3,106.8) 88.1,106.8 88.72,107.42 88.91,107.42 89.71,108.23 91.15,108.23 91.39,108.47 91.84,108.47 92,108.64 92.42,108.64 92.55,108.77 92.81,108.77 92.83,108.75 93.07,108.75 93.36,109.04 UC1.AK60
  BOTTOM w0.102: v1(85.3,59.94) 86.5,61.13 JDIMM1.142
DDR_A_D8: length 89
  IN1 w0.084: 87.57,105.46 87.72,105.61 88.51,105.61 88.64,105.48 v1(88.64,105.46)
  IN1 w0.127: 87.57,105.46 83.86,105.46 82.47,106.84 79.48,106.84 75.96,103.32 75.96,102.33 76.09,102.21 76.41,102.21 76.53,102.08 76.53,101.76 76.41,101.64 75.67,101.64 74.22,100.19 61.95,100.19 61.4,99.63 61.04,99.63 46.77,85.36 46.59,85.36 46.13,85.83 45.95,85.83 45.77,85.65 45.77,85.47 46.23,85.01 46.23,84.83 46.05,84.65 45.87,84.65 45.41,85.11 45.23,85.11 45.05,84.93 45.05,84.75 45.51,84.29 45.51,84.11 45.33,83.93 45.15,83.93 44.69,84.39 44.51,84.39 42.7,82.58 42.7,78.18 42.57,78.06 42.01,78.06 41.89,77.93 41.89,77.67 42.01,77.55 42.34,77.55 42.47,77.42 42.47,77.17 42.34,77.04 42,77.04 41.88,76.91 41.88,76.66 42,76.53 42.34,76.53 42.47,76.4 42.47,76.15 42.34,76.02 41.94,76.02 41.81,75.9 41.81,75.64 41.94,75.52 42.34,75.52 42.47,75.39 42.47,75.13 42.34,75.01 41.9,75.01 41.78,74.88 41.78,68.34 v1(42.19,67.92)
  BOTTOM w0.076: UC1.AM63 91.47,107.85 91.34,107.72 90,107.72 89.37,107.08 89.37,106.77 88.64,106.05 v1(88.64,105.46)
  BOTTOM w0.102: v1(42.19,67.92) 43.6,69.33 JDIMM1.7
DDR_A_D9: length 90
  IN1 w0.084: 86.96,106.43 87.68,106.43 87.87,106.62 v1(88.43,106.62)
  IN1 w0.127: 86.96,106.43 84.14,106.43 83.05,107.52 79.19,107.52 75.28,103.6 75.28,103.07 73.1,100.9 61.69,100.9 61.11,100.32 60.75,100.32 48.17,87.73 46.88,87.73 42.02,82.87 42.02,79.03 41.09,78.1 41.09,67.94 41.34,67.69 41.34,67.22 41.34,64.78 42.68,63.45 42.68,60.53 v1(43.27,59.94)
  BOTTOM w0.076: UC1.AM62 92.06,107.85 91.77,108.14 91.53,108.14 91.27,107.89 89.93,107.89 89.2,107.15 89.2,106.84 88.98,106.62 v1(88.43,106.62)
  BOTTOM w0.102: JDIMM1.4 42.7,60.51 v1(43.27,59.94)
DDR_A_D10: length 88.2
  IN1 w0.084: 87.12,103.07 87.99,103.94 89.25,103.94 v1(89.26,103.94)
  IN1 w0.127: v1(44.22,67.92) 44.22,67.69 44.09,67.56 43.89,67.56 43.77,67.69 43.77,69.76 43.89,69.88 44.21,69.88 44.34,70.01 44.34,70.26 44.21,70.39 43.89,70.39 43.77,70.52 43.77,70.77 43.89,70.9 44.21,70.9 44.34,71.03 44.34,71.28 44.21,71.41 43.89,71.41 43.77,71.53 43.77,71.79 43.89,71.92 44.21,71.92 44.34,72.04 44.34,72.32 44.24,72.42 43.89,72.42 43.77,72.55 43.77,73.8 43.89,73.92 44.21,73.92 44.33,74.05 44.33,76.95 45.85,78.47 45.85,80.45 47.33,81.92 47.33,82.62 47.78,83.08 47.78,83.26 47.65,83.39 47.65,83.61 47.84,83.79 48.02,83.79 48.52,83.29 48.7,83.29 48.88,83.47 48.88,83.65 48.38,84.15 48.38,84.33 52.05,88 52.53,88 62.7,98.18 74.58,98.18 74.7,98.06 74.7,97.81 74.83,97.68 75.08,97.68 75.21,97.81 75.21,98.01 75.34,98.13 75.59,98.13 75.72,98.01 75.72,97.81 75.85,97.68 76.1,97.68 76.23,97.81 76.23,98.01 76.35,98.13 76.61,98.13 76.73,98.01 76.73,97.81 76.86,97.68 77.12,97.68 77.24,97.81 77.24,98.37 77.37,98.5 77.62,98.5 77.75,98.37 77.75,97.81 77.88,97.68 78.13,97.68 78.26,97.81 78.26,98.31 78.39,98.44 78.64,98.44 78.77,98.31 78.77,97.81 78.89,97.68 79.15,97.68 79.27,97.81 79.27,98.31 79.4,98.44 79.66,98.44 79.78,98.31 79.78,97.81 79.91,97.68 80.16,97.68 80.29,97.81 80.29,98.37 80.42,98.5 80.67,98.5 80.8,98.37 80.8,97.81 80.93,97.68 81.73,97.68 87.12,103.07
  BOTTOM w0.076: UC1.AP63 91.26,106.5 90.73,105.97 90.37,105.97 89.26,104.87 v1(89.26,103.94)
  BOTTOM w0.102: JDIMM1.17 46.6,70.3 v1(44.22,67.92)
DDR_A_D11: length 89.4
  IN1 w0.084: v1(89.66,104.33) 90.01,103.98 90.01,103.41 88.6,102 87.12,102
  IN1 w0.127: v1(46.57,61.46) 46.57,62.06 46.45,62.19 46.19,62.19 46.07,62.06 46.07,61.16 45.94,61.03 45.69,61.03 45.56,61.16 45.56,62.06 45.43,62.19 44.99,62.19 44.86,62.32 44.86,62.57 44.99,62.7 46.52,62.7 46.65,62.83 46.65,63.08 46.52,63.21 44.99,63.21 44.86,63.33 44.86,63.59 44.99,63.71 46.13,63.71 46.26,63.84 46.26,64.1 46.13,64.22 45.15,64.22 45.03,64.35 45.03,75.01 45.02,75.02 45.02,76.66 46.54,78.18 46.54,80.16 54.31,87.94 56.59,90.22 56.59,90.97 61.05,95.43 61.84,95.43 62.59,96.17 63.32,96.17 64.61,97.46 73.35,97.46 73.84,96.98 82.04,96.98 87.06,102 87.12,102
  BOTTOM w0.076: v1(89.66,104.33) 89.66,105.03 90.44,105.81 90.8,105.81 91.2,106.21 91.77,106.21 92.06,106.5 UC1.AP62
  BOTTOM w0.102: JDIMM1.18 46.9,61.79 v1(46.57,61.46)
DDR_A_D12: length 90.2
  IN1 w0.084: v1(88.83,107.02) 88.99,107.02 89.18,106.82 89.18,106.6 88.45,105.87 86.96,105.87
  IN1 w0.127: v1(43.27,61.46) 43.27,63.79 42.85,64.21 42.85,64.93 42.73,65.05 42.27,65.05 42.14,65.18 42.14,65.43 42.27,65.56 43.02,65.56 43.15,65.69 43.15,65.94 43.02,66.07 41.81,66.07 41.68,66.2 41.68,67.83 41.43,68.08 41.43,77.96 42.36,78.88 42.36,82.72 47.02,87.39 48.31,87.39 60.89,99.97 61.25,99.97 61.82,100.54 73.47,100.54 75.62,102.69 75.62,103.46 79.34,107.18 82.62,107.18 83.93,105.87 86.96,105.87
  BOTTOM w0.076: v1(88.83,107.02) 88.83,107.02 89.87,108.05 91.2,108.05 91.46,108.31 91.84,108.31 92,108.14 92.42,108.14 92.82,107.75 UC1.AM61
  BOTTOM w0.102: v1(43.27,61.46) 43.3,61.49 JDIMM1.6
DDR_A_D13: length 91.3
  IN1 w0.084: v1(88.2,104.97) 87.53,104.97
  IN1 w0.127: 87.53,104.97 86.86,104.97 84.33,102.43 81.98,100.09 77.43,100.09 76.5,101.01 75.58,101.01 74.4,99.83 62.21,99.83 61.66,99.29 61.18,99.29 60.8,98.9 60.8,98.72 60.86,98.66 60.86,98.48 60.68,98.3 60.5,98.3 60.44,98.36 60.26,98.36 59.42,97.53 59.42,97.35 59.48,97.29 59.48,97.11 59.3,96.93 59.12,96.93 59.06,96.99 58.88,96.99 58.7,96.81 58.7,96.63 58.76,96.57 58.76,96.39 58.58,96.21 58.4,96.21 58.34,96.27 58.16,96.27 57.4,95.5 57.4,95.32 57.46,95.26 57.46,95.08 57.28,94.9 57.1,94.9 57.04,94.96 56.86,94.96 56.68,94.78 56.68,94.6 56.74,94.54 56.74,94.36 56.56,94.18 56.38,94.18 56.32,94.25 56.14,94.25 55.96,94.07 55.96,93.89 56.02,93.82 56.02,93.64 55.84,93.47 55.66,93.47 55.6,93.53 55.42,93.53 55.24,93.35 55.24,93.17 55.3,93.11 55.3,92.93 55.12,92.75 54.94,92.75 54.88,92.81 54.7,92.81 54.52,92.63 54.52,92.45 54.58,92.39 54.58,92.21 54.4,92.03 54.22,92.03 54.16,92.09 53.98,92.09 53.8,91.91 53.8,91.73 53.86,91.67 53.86,91.49 53.68,91.31 53.5,91.31 53.44,91.37 53.26,91.37 53.08,91.19 53.08,91.01 53.14,90.95 53.14,90.77 52.96,90.59 52.78,90.59 52.72,90.65 52.54,90.65 52.36,90.47 52.36,90.29 52.43,90.23 52.43,90.05 52.25,89.87 52.07,89.87 52,89.93 51.82,89.93 44.59,82.7 43.31,82.7 43.19,82.57 43.19,82.32 43.31,82.19 44.75,82.19 44.88,82.07 44.88,81.81 44.75,81.68 43.21,81.68 43.08,81.56 43.08,81.3 43.21,81.18 44.2,81.18 44.33,81.05 44.33,80.8 44.2,80.67 43.21,80.67 43.08,80.54 43.08,80.29 43.21,80.16 44.2,80.16 44.33,80.03 44.33,79.78 44.2,79.65 43.17,79.65 43.04,79.53 43.04,79.27 43.17,79.14 43.87,79.14 44,79.02 44,78.76 43.87,78.64 43.22,78.64 43.04,78.46 43.04,77.81 42.81,77.58 42.81,74.99 42.25,74.43 42.25,69.5 v1(42.19,69.44)
  BOTTOM w0.076: UC1.AM60 93.6,107.09 93.4,106.88 92.56,106.88 92.54,106.89 92.45,106.93 92.4,106.96 92.2,106.96 92.04,106.88 91.91,106.88 91.75,106.96 91.25,106.96 90.59,106.3 90.23,106.3 88.89,104.97 v1(88.2,104.97)
  BOTTOM w0.102: v1(42.19,69.44) 43,70.26 JDIMM1.5
DDR_A_D14: length 89.5
  IN1 w0.084: 87.12,102.57 87.62,103.07 v1(88.4,103.07)
  IN1 w0.127: 87.12,102.57 81.89,97.34 73.97,97.34 73.48,97.82 62.83,97.82 62.47,97.46 62.47,97.28 62.88,96.88 62.88,96.7 62.7,96.52 62.52,96.52 62.11,96.92 61.93,96.92 61.75,96.74 61.75,96.56 62,96.32 62,96.14 61.82,95.96 61.64,95.96 61.39,96.2 61.21,96.2 55.97,90.96 55.97,90.76 56.24,90.5 56.24,90.35 56.01,90.12 55.83,90.12 55.57,90.38 55.39,90.38 55.21,90.2 55.21,90.02 55.47,89.76 55.47,89.58 55.29,89.4 55.11,89.4 54.85,89.66 54.67,89.66 54.49,89.48 54.49,89.3 54.75,89.04 54.75,88.86 54.57,88.68 54.39,88.68 54.13,88.94 53.95,88.94 53.77,88.76 53.77,88.58 54.03,88.32 54.03,88.14 53.85,87.96 53.67,87.96 53.41,88.22 53.23,88.22 53.05,88.04 53.05,87.86 53.31,87.6 53.31,87.42 53.13,87.24 52.95,87.24 52.53,87.66 52.35,87.66 52.17,87.48 52.17,87.3 52.59,86.88 52.59,86.7 52.41,86.52 52.23,86.52 51.73,87.02 51.55,87.02 51.37,86.84 51.37,86.66 51.87,86.16 51.87,85.98 51.69,85.8 51.51,85.8 51.01,86.3 50.83,86.3 50.65,86.12 50.65,85.94 51.15,85.44 51.15,85.26 50.94,85.05 50.81,85.05 50.29,85.58 50.11,85.58 49.94,85.41 49.94,85.19 50.42,84.71 50.42,84.53 50,84.11 49.82,84.11 49.32,84.62 49.14,84.62 48.95,84.42 48.95,84.24 49.45,83.74 49.45,83.56 48.77,82.88 48.07,82.88 47.67,82.48 47.67,81.78 46.2,80.31 46.2,78.32 44.68,76.8 44.68,74.88 44.68,74.87 44.68,69.35 44.56,69.23 44.35,69.23 44.22,69.35 v1(44.22,69.44)
  BOTTOM w0.076: UC1.AP61 92.71,106.5 92.47,106.74 92.37,106.79 92.23,106.79 92.21,106.78 92.13,106.74 92.08,106.72 91.87,106.72 91.71,106.79 91.31,106.79 90.66,106.14 90.3,106.14 88.4,104.24 v1(88.4,103.07)
  BOTTOM w0.102: JDIMM1.15 46,70.37 45.08,69.44 v1(44.22,69.44)
DDR_A_D15: length 89.9
  IN1 w0.084: v1(90.05,104.73) 90.29,104.5 90.29,103.45 88.5,101.66 87.22,101.66 87.12,101.57
  IN1 w0.127: v1(46.57,59.94) 46.99,60.36 46.99,63.84 46.19,64.64 46.19,65.17 46.07,65.3 45.49,65.3 45.37,65.43 45.37,65.68 45.49,65.81 46.51,65.81 46.64,65.94 46.64,66.19 46.51,66.32 45.49,66.32 45.37,66.44 45.37,66.7 45.49,66.83 46.08,66.83 46.21,66.95 46.21,67.21 46.08,67.33 45.49,67.33 45.37,67.46 45.37,67.71 45.49,67.84 45.81,67.84 45.94,67.97 45.94,68.22 45.81,68.35 45.49,68.35 45.37,68.48 45.37,75.75 45.36,75.76 45.36,76.52 46.88,78.04 46.88,80.01 56.94,90.07 56.94,90.83 60.65,94.54 61.68,94.54 61.98,94.83 61.98,95.08 62.74,95.83 63.46,95.83 64.74,97.11 73.23,97.11 73.71,96.63 82.18,96.63 87.12,101.57
  BOTTOM w0.076: v1(90.05,104.73) 90.05,105.19 90.5,105.64 90.87,105.64 91.27,106.04 91.84,106.04 92,106.21 92.42,106.21 92.43,106.22 92.82,106.22 92.83,106.21 93.07,106.21 93.14,106.28 93.38,106.28 UC1.AP60
  BOTTOM w0.102: JDIMM1.16 46.3,61.99 46.13,61.82 46.13,60.38 v1(46.57,59.94)
DDR_A_D16: length 63.5
  IN3 w0.084: 89.04,99.65 89.04,99.81 90.15,100.93 90.31,100.93 92.86,103.49 92.86,104.28 93.17,104.58 94.14,104.58 94.81,105.26 94.81,106.28 94.72,106.37 v1(94.42,106.37)
  IN3 w0.127: v1(90.59,67.94) 90.87,67.94 91.02,68.08 91.02,70.7 88.49,73.22 88.49,73.91 82.92,79.47 82.92,80.27 82.78,80.41 82.13,80.41 82,80.53 82,80.82 82.13,80.95 82.8,80.95 82.93,81.07 82.93,81.36 82.8,81.49 82.13,81.49 82,81.62 82,81.9 82.13,82.03 82.83,82.03 82.93,82.12 82.93,82.48 82.83,82.57 82.13,82.57 82.01,82.7 82.01,82.98 82.13,83.11 82.83,83.11 82.93,83.21 82.93,83.56 82.83,83.65 82.14,83.65 82.01,83.78 82.01,84.07 82.14,84.19 82.83,84.19 82.93,84.29 82.93,84.64 82.83,84.73 82.14,84.73 82.01,84.86 82.01,85.15 82.14,85.28 82.83,85.28 82.93,85.37 82.93,85.72 82.83,85.82 82.14,85.82 82.01,85.94 82.01,86.23 82.14,86.36 82.83,86.36 82.93,86.45 82.93,86.8 82.83,86.9 82.13,86.9 82.01,87.03 82.01,87.31 82.13,87.44 82.78,87.44 82.92,87.57 82.92,93.33 89.04,99.45 89.04,99.65
  BOTTOM w0.076: v1(94.42,106.37) 94.74,106.69 UC1.AP58
  BOTTOM w0.102: JDIMM1.159 91.6,68.94 v1(90.59,67.94)
DDR_A_D17: length 63.1
  IN3 w0.084: 88.67,99.65 88.67,99.72 89.02,100.07 89.02,100.16 88.67,100.52 88.67,100.69 88.84,100.86 89.02,100.86 89.26,100.62 89.44,100.62 89.59,100.78 89.59,100.96 88.99,101.56 88.99,101.74 90.24,102.98 90.42,102.98 91.08,102.32 91.26,102.32 91.43,102.49 91.43,102.67 90.75,103.34 90.75,103.52 90.92,103.69 91.1,103.69 91.8,102.99 91.98,102.99 92.15,103.15 92.15,103.33 91.46,104.02 91.46,104.2 91.63,104.36 91.81,104.36 92.35,103.83 92.52,103.83 92.69,104 92.69,104.18 92.42,104.45 92.42,104.66 92.71,104.95 93.09,104.95 93.25,104.79 93.58,104.79 94.06,105.26 94.44,105.26 94.57,105.39 94.57,105.59 94.44,105.72 v1(94.42,105.72)
  IN3 w0.127: v1(90.59,69.46) 90.59,70.57 88.12,73.04 88.12,73.75 82.56,79.32 82.56,79.89 82.45,80.01 81.87,80.01 81.65,80.23 81.65,87.68 81.78,87.8 82.43,87.8 82.56,87.93 82.56,88.22 82.43,88.34 81.78,88.34 81.65,88.47 81.65,88.76 81.78,88.88 82.43,88.88 82.56,89.01 82.56,89.3 82.43,89.43 81.78,89.43 81.65,89.55 81.65,89.84 81.78,89.97 82.43,89.97 82.56,90.09 82.56,90.38 82.43,90.51 81.78,90.51 81.65,90.63 81.65,90.92 81.78,91.05 82.43,91.05 82.56,91.18 82.56,91.46 82.43,91.59 81.78,91.59 81.65,91.72 81.65,92.12 81.78,92.24 82.43,92.24 82.56,92.37 82.56,93.48 88.67,99.6 88.67,99.65
  BOTTOM w0.076: UC1.AR58 94.74,106.04 v1(94.42,105.72)
  BOTTOM w0.102: v1(90.59,69.46) 91,69.87 JDIMM1.157
DDR_A_D18: length 65.4
  IN3 w0.084: v1(95.31,107.8) 94.94,108.16 94.94,108.73 94.58,109.09 94.25,109.09 93.66,108.5 93.66,108.48 91.3,106.12 90.56,106.12 87.12,102.69
  IN3 w0.127: v1(87.64,61.46) 88.07,61.88 88.07,66.1 88.2,66.24 88.74,66.24 88.87,66.37 88.87,66.65 88.74,66.78 88.2,66.78 88.07,66.91 88.07,69.93 84.54,73.45 84.54,74.13 78.42,80.25 78.42,94.46 78.77,94.8 80.69,94.8 82.98,97.1 86.94,101.06 86.94,102.5 87.12,102.69
  BOTTOM w0.076: v1(95.31,107.8) 95.51,107.99 UC1.AM57
  BOTTOM w0.102: JDIMM1.146 87.7,61.52 v1(87.64,61.46)
DDR_A_D19: length 67.4
  IN3 w0.084: 87.12,103.2 90.22,106.3 91.23,106.3 93.49,108.55 93.49,108.57 94.18,109.26 95.12,109.26 v1(95.31,109.07)
  IN3 w0.127: v1(87.64,59.94) 87.07,60.51 87.07,61.99 87.52,62.44 87.52,69.96 84.18,73.3 84.18,73.98 78.06,80.1 78.06,94.61 78.62,95.17 80.54,95.17 83.12,97.75 86.58,101.21 86.58,102.65 87.12,103.2
  BOTTOM w0.076: UC1.AK57 95.53,109.3 v1(95.31,109.07)
  BOTTOM w0.102: v1(87.64,59.94) 88.3,60.59 JDIMM1.148
DDR_A_D20: length 65.6
  IN3 w0.084: v1(94.41,108.15) 94.19,108.15 94.05,108 94.05,107.56 93.92,107.43 93.21,107.43 91.73,105.95 91.73,105.58 87.55,101.4 87.55,100.64
  IN3 w0.127: 87.55,100.64 80.14,93.23 80.14,89.64 80.01,89.51 79.72,89.51 79.59,89.38 79.59,89.1 79.72,88.97 80.01,88.97 80.14,88.84 80.14,88.5 80,88.36 79.28,88.36 79.15,88.23 79.15,87.96 79.28,87.82 80.01,87.82 80.14,87.69 80.14,87.41 80.01,87.28 79.28,87.28 79.15,87.14 79.15,86.87 79.28,86.74 80,86.74 80.14,86.6 80.14,86.33 80,86.2 79.28,86.2 79.15,86.06 79.15,85.79 79.28,85.66 80,85.66 80.14,85.52 80.14,85.25 80,85.12 79.28,85.12 79.15,84.98 79.15,84.71 79.28,84.57 80,84.57 80.14,84.44 80.14,84.17 80,84.03 79.28,84.03 79.15,83.9 79.15,83.63 79.28,83.49 80,83.49 80.14,83.36 80.14,83.09 80,82.95 79.28,82.95 79.15,82.82 79.15,82.55 79.28,82.41 80,82.41 80.14,82.28 80.14,82 80,81.87 79.28,81.87 79.15,81.73 79.15,81.46 79.28,81.33 80.01,81.33 80.14,81.2 80.14,80.91 80.01,80.79 79.34,80.79 79.21,80.66 79.21,80.48 79.45,80.25 80,80.25 80.14,80.11 80.14,79.57 86.11,73.6 86.11,72.92 89.07,69.95 v1(89.07,69.46)
  BOTTOM w0.089: UC1.AL58 94.87,108.6 v1(94.41,108.15)
  BOTTOM w0.102: JDIMM1.149 88.6,69.93 v1(89.07,69.46)
DDR_A_D21: length 66.7
  IN3 w0.084: 87.34,100.94 87.34,101.43 91.55,105.65 91.55,106.03 94.23,108.7 v1(94.39,108.7)
  IN3 w0.127: v1(89.07,67.94) 89.07,67.71 88.94,67.58 88.56,67.58 88.43,67.71 88.43,70.08 85.74,72.77 85.74,73.45 78.79,80.41 78.79,88.66 78.91,88.78 79.1,88.78 79.23,88.92 79.23,89.19 79.1,89.32 78.91,89.32 78.79,89.45 78.79,89.74 78.91,89.87 79.65,89.87 79.77,89.99 79.77,90.28 79.65,90.41 78.91,90.41 78.79,90.53 78.79,90.82 78.91,90.95 79.65,90.95 79.77,91.07 79.77,91.36 79.65,91.49 78.91,91.49 78.79,91.62 78.79,91.91 78.91,92.04 79.65,92.04 79.77,92.17 79.77,92.68 79.64,92.82 78.92,92.82 78.79,92.95 78.79,93.22 78.92,93.36 79.64,93.36 79.77,93.49 79.77,93.77 79.64,93.9 78.92,93.9 78.79,94.03 78.79,94.31 78.92,94.44 80.84,94.44 83.13,96.74 87.34,100.94
  BOTTOM w0.076: UC1.AK58 94.87,109.47 94.74,109.6 94.31,109.6 94.18,109.47 94.18,108.91 94.39,108.7 v1(94.39,108.7)
  BOTTOM w0.102: v1(89.07,67.94) 88,69.01 JDIMM1.147
DDR_A_D22: length 63.8
  IN3 w0.084: 89.91,99.65 91.23,100.97 95.37,105.11 v1(95.37,105.72)
  IN3 w0.127: v1(91.26,59.94) 92.99,59.94 93.61,60.55 93.61,63.53 92.58,64.57 92.58,65.43 92.45,65.56 92.29,65.56 92.17,65.69 92.17,65.97 92.29,66.1 92.45,66.1 92.58,66.23 92.58,66.52 92.45,66.64 91.91,66.64 91.78,66.78 91.78,70.96 89.85,72.88 89.85,73.57 83.65,79.78 83.65,90.52 83.78,90.65 84.13,90.65 84.26,90.78 84.26,91.07 84.13,91.19 83.78,91.19 83.65,91.33 83.65,91.6 83.78,91.74 84.14,91.74 84.26,91.86 84.26,92.15 84.14,92.28 83.78,92.28 83.65,92.41 83.65,92.75 83.77,92.87 84.1,92.87 84.23,93 84.23,93.62 89.76,99.15 89.76,99.5 89.91,99.65
  BOTTOM w0.076: UC1.AR57 95.7,106.04 v1(95.37,105.72)
  BOTTOM w0.102: JDIMM1.158 91.3,62.14 90.86,61.69 90.86,60.34 v1(91.26,59.94)
DDR_A_D23: length 65.5
  IN3 w0.084: v1(95.37,107.02) 94.99,106.63 94.99,105.14 93.44,103.6 93.42,103.6 90.46,100.65 89.97,100.15 89.9,100.15 89.4,99.66
  IN3 w0.127: 89.4,99.66 89.4,99.3 83.28,93.18 83.28,79.62 89.49,73.42 89.49,72.73 91.42,70.81 91.42,64.1 91.55,63.96 92.67,63.96 92.79,63.83 92.79,63.55 92.67,63.42 91.22,63.42 91.1,63.29 91.1,63.01 91.22,62.88 93.12,62.88 93.24,62.75 93.24,61.03 93.12,60.91 92.79,60.91 92.66,61.03 92.66,62.05 92.54,62.18 91.39,62.18 91.26,62.05 v1(91.26,61.46)
  BOTTOM w0.076: UC1.AN57 95.7,107.34 v1(95.37,107.02)
  BOTTOM w0.102: JDIMM1.160 91.9,62.1 v1(91.26,61.46)
DDR_A_D24: length 83.7
  IN1 w0.084: v1(96.32,106.37) 95.93,105.98 95.93,105.49 95.08,104.64 92.51,104.64 88.51,100.63 88.1,100.63 87.12,99.66
  IN1 w0.127: v1(49.11,61.46) 49.13,61.47 49.13,64.27 49,64.4 47.34,64.4 47.21,64.53 47.21,64.78 47.34,64.91 47.91,64.91 48.03,65.03 48.03,65.29 47.91,65.41 47.52,65.41 47.39,65.54 47.39,76.35 48.2,77.16 48.2,78.3 49.7,79.8 49.7,80.96 61.11,92.37 61.87,92.37 65.26,95.76 70.22,95.76 70.7,95.28 82.74,95.28 87.12,99.66
  BOTTOM w0.076: UC1.AP55 96.65,106.69 v1(96.32,106.37)
  BOTTOM w0.102: JDIMM1.24 48.7,61.87 v1(49.11,61.46)
DDR_A_D25: length 83.6
  IN1 w0.084: v1(96.32,105.72) 96.32,105.64 95.13,104.44 92.58,104.44 88.43,100.29 88.26,100.29 88.25,100.28 88.24,100.28 87.62,99.65
  IN1 w0.127: 87.62,99.65 82.89,94.92 65.4,94.92 62.5,92.03 61.25,92.03 50.04,80.82 50.04,79.66 48.55,78.16 48.55,77.02 47.73,76.21 47.73,66.15 49.53,64.35 49.53,60.36 v1(49.11,59.94)
  BOTTOM w0.076: v1(96.32,105.72) 96.65,106.04 UC1.AR55
  BOTTOM w0.102: JDIMM1.22 48.1,60.95 v1(49.11,59.94)
DDR_A_D26: length 86.7
  IN1 w0.084: 90.17,98.98 93.17,101.97 93.17,102.49 93.53,102.85 94.22,102.85 94.77,103.4 96.64,103.4 97.84,104.6 97.84,107.14 97.3,107.67 v1(97.28,107.67)
  IN1 w0.127: 90.17,98.98 83.89,92.69 66.29,92.69 61.8,88.21 60.55,88.21 60.06,87.72 60.06,86.47 52.25,78.65 52.25,74.31 51.07,73.14 51.07,65.44 50.94,65.31 50.42,65.31 50.3,65.18 50.3,64.93 50.42,64.8 50.94,64.8 51.07,64.67 51.07,64.42 50.94,64.29 50.42,64.29 50.3,64.17 50.3,63.91 50.42,63.78 50.94,63.78 51.07,63.66 51.07,60.39 v1(51.53,59.94)
  BOTTOM w0.076: v1(97.28,107.67) 97.6,107.99 UC1.AM54
  BOTTOM w0.102: JDIMM1.36 52.3,60.71 v1(51.53,59.94)
DDR_A_D27: length 87.4
  IN1 w0.084: 90.17,98.45 91.04,98.45 91.82,99.23 91.82,99.38 93.85,101.4 93.96,101.4 94.88,102.32 94.88,102.65 95.46,103.22 96.71,103.22 98.01,104.52 98.01,107.21 97.76,107.46 97.76,108.44 v1(97.23,108.97)
  IN1 w0.127: 90.17,98.45 90.15,98.45 84.03,92.34 66.42,92.34 61.95,87.86 60.69,87.86 60.41,87.58 60.41,86.33 52.59,78.51 52.59,74.17 51.41,72.99 51.41,66.17 51.54,66.04 52.29,66.04 52.42,65.92 52.42,65.66 52.29,65.53 51.54,65.53 51.41,65.41 51.41,64.29 51.54,64.17 52.35,64.17 52.48,64.04 52.48,63.79 52.35,63.66 51.54,63.66 51.41,63.53 51.41,63.28 51.54,63.15 52.35,63.15 52.48,63.02 52.48,62.77 52.35,62.64 51.54,62.64 51.41,62.52 51.41,61.57 v1(51.53,61.46)
  BOTTOM w0.076: UC1.AK54 97.55,109.3 v1(97.23,108.97)
  BOTTOM w0.102: JDIMM1.34 51.7,61.59 51.57,61.46 v1(51.53,61.46)
DDR_A_D28: length 86.6
  IN1 w0.084: 87.12,100.16 87.91,100.95 88.32,100.95 92.18,104.81 95.01,104.81 95.76,105.56 95.76,108.13 95.95,108.32 v1(96.32,108.32)
  IN1 w0.127: 87.12,100.16 82.59,95.64 70.83,95.64 70.35,96.12 65.13,96.12 61.72,92.71 60.96,92.71 49.05,80.8 49.05,80.47 49.35,80.16 49.35,79.98 49.19,79.82 49.01,79.82 48.8,80.03 48.62,80.03 48.44,79.85 48.44,79.67 48.63,79.48 48.63,79.22 47.86,78.45 47.86,77.31 47.05,76.49 47.05,75.42 46.92,75.29 46.47,75.29 46.35,75.17 46.35,74.91 46.47,74.79 46.92,74.79 47.05,74.66 47.05,74.4 46.92,74.28 46.47,74.28 46.35,74.15 46.35,73.9 46.47,73.77 46.92,73.77 47.05,73.64 47.05,73.39 46.92,73.26 46.47,73.26 46.35,73.13 46.35,72.55 46.47,72.42 46.92,72.42 47.05,72.3 47.05,72.04 46.92,71.92 46.47,71.92 46.35,71.79 46.35,71.53 46.47,71.41 46.92,71.41 47.05,71.28 47.05,71.03 46.92,70.9 46.47,70.9 46.35,70.77 46.35,70.52 46.47,70.39 46.92,70.39 47.05,70.26 47.05,67.69 46.92,67.56 46.75,67.56 46.63,67.69 v1(46.63,67.92)
  BOTTOM w0.076: v1(96.32,108.32) 96.65,108.64 UC1.AL55
  BOTTOM w0.102: JDIMM1.23 48.4,70.34 48.05,69.99 48.05,69.34 v1(46.63,67.92)
DDR_A_D29: length 86.8
  IN1 w0.084: 87.12,100.67 87.75,101.29 88.42,101.29 92.11,104.98 94.59,104.98 94.91,105.3 94.91,109.39 95.03,109.52 96.74,109.52 96.87,109.39 96.87,109.1 96.74,108.97 v1(96.27,108.97)
  IN1 w0.127: v1(46.63,69.44) 46.63,69.21 46.5,69.08 46.13,69.08 46,69.21 46,75.83 46,75.83 46,76.26 47.52,77.78 47.52,79.75 57.88,90.11 57.88,90.29 57.69,90.49 57.69,90.68 57.86,90.85 58.03,90.85 58.26,90.62 58.39,90.62 58.62,90.85 58.62,90.98 58.39,91.21 58.39,91.39 58.57,91.56 58.75,91.56 58.98,91.34 59.1,91.34 59.34,91.57 59.34,91.7 59.08,91.96 59.08,92.07 59.33,92.32 59.43,92.32 59.67,92.08 59.85,92.08 60.03,92.26 60.03,92.44 59.79,92.68 59.79,92.79 60.05,93.04 60.15,93.04 60.39,92.8 60.57,92.8 60.75,92.98 60.75,93.16 60.51,93.4 60.51,93.51 60.77,93.76 60.87,93.76 61.46,93.17 61.69,93.17 61.88,93.35 61.88,93.53 61.79,93.61 61.79,93.79 61.97,93.97 62.15,93.97 62.23,93.89 62.41,93.89 65,96.47 70.93,96.47 71.06,96.35 71.06,96.15 71.18,96.02 71.44,96.02 71.57,96.15 71.57,96.35 71.69,96.47 71.95,96.47 72.07,96.35 72.07,96.15 72.2,96.02 72.45,96.02 72.58,96.15 72.58,96.35 72.71,96.47 72.96,96.47 73.09,96.35 73.09,96.15 73.25,95.99 82.45,95.99 87.12,100.67
  BOTTOM w0.076: v1(96.27,108.97) 96.6,109.3 UC1.AK55
  BOTTOM w0.102: v1(46.63,69.44) 47.8,70.62 JDIMM1.21
DDR_A_D30: length 84.7
  IN1 w0.084: 89.95,99.77 91.72,101.55 91.72,102.12 92.42,102.82 92.42,103.07 92.6,103.25 93.94,103.25 94.47,103.77 95.54,103.77 97.28,105.51 v1(97.28,105.72)
  IN1 w0.127: 89.95,99.77 83.58,93.4 66.03,93.4 62.94,90.32 61.69,90.32 54.07,82.69 54.07,82.52 54.51,82.08 54.51,81.89 54.28,81.65 54.1,81.65 53.65,82.1 53.47,82.1 53.29,81.92 53.29,81.74 53.74,81.29 53.74,81.11 53.56,80.93 53.38,80.93 52.93,81.38 52.75,81.38 52.58,81.2 52.58,81.02 53.02,80.57 53.02,80.39 52.84,80.21 52.66,80.21 52.22,80.66 52.04,80.66 51.86,80.48 51.86,80.3 52.3,79.86 52.3,79.68 51.56,78.93 51.56,75.64 51.43,75.51 49.38,75.51 49.25,75.39 49.25,75.13 49.38,75.01 51.43,75.01 51.56,74.88 51.56,74.61 51.43,74.49 49.38,74.49 49.25,74.36 49.25,74.09 49.38,73.96 50.37,73.96 50.49,73.84 50.49,73.53 50.37,73.4 49.38,73.4 49.25,73.28 49.25,72.98 49.38,72.86 49.61,72.86 50.31,72.16 v1(50.31,69.61)
  BOTTOM w0.076: UC1.AR54 97.6,106.04 v1(97.28,105.72)
  BOTTOM w0.102: JDIMM1.33 51.4,69.99 51.02,69.61 v1(50.31,69.61)
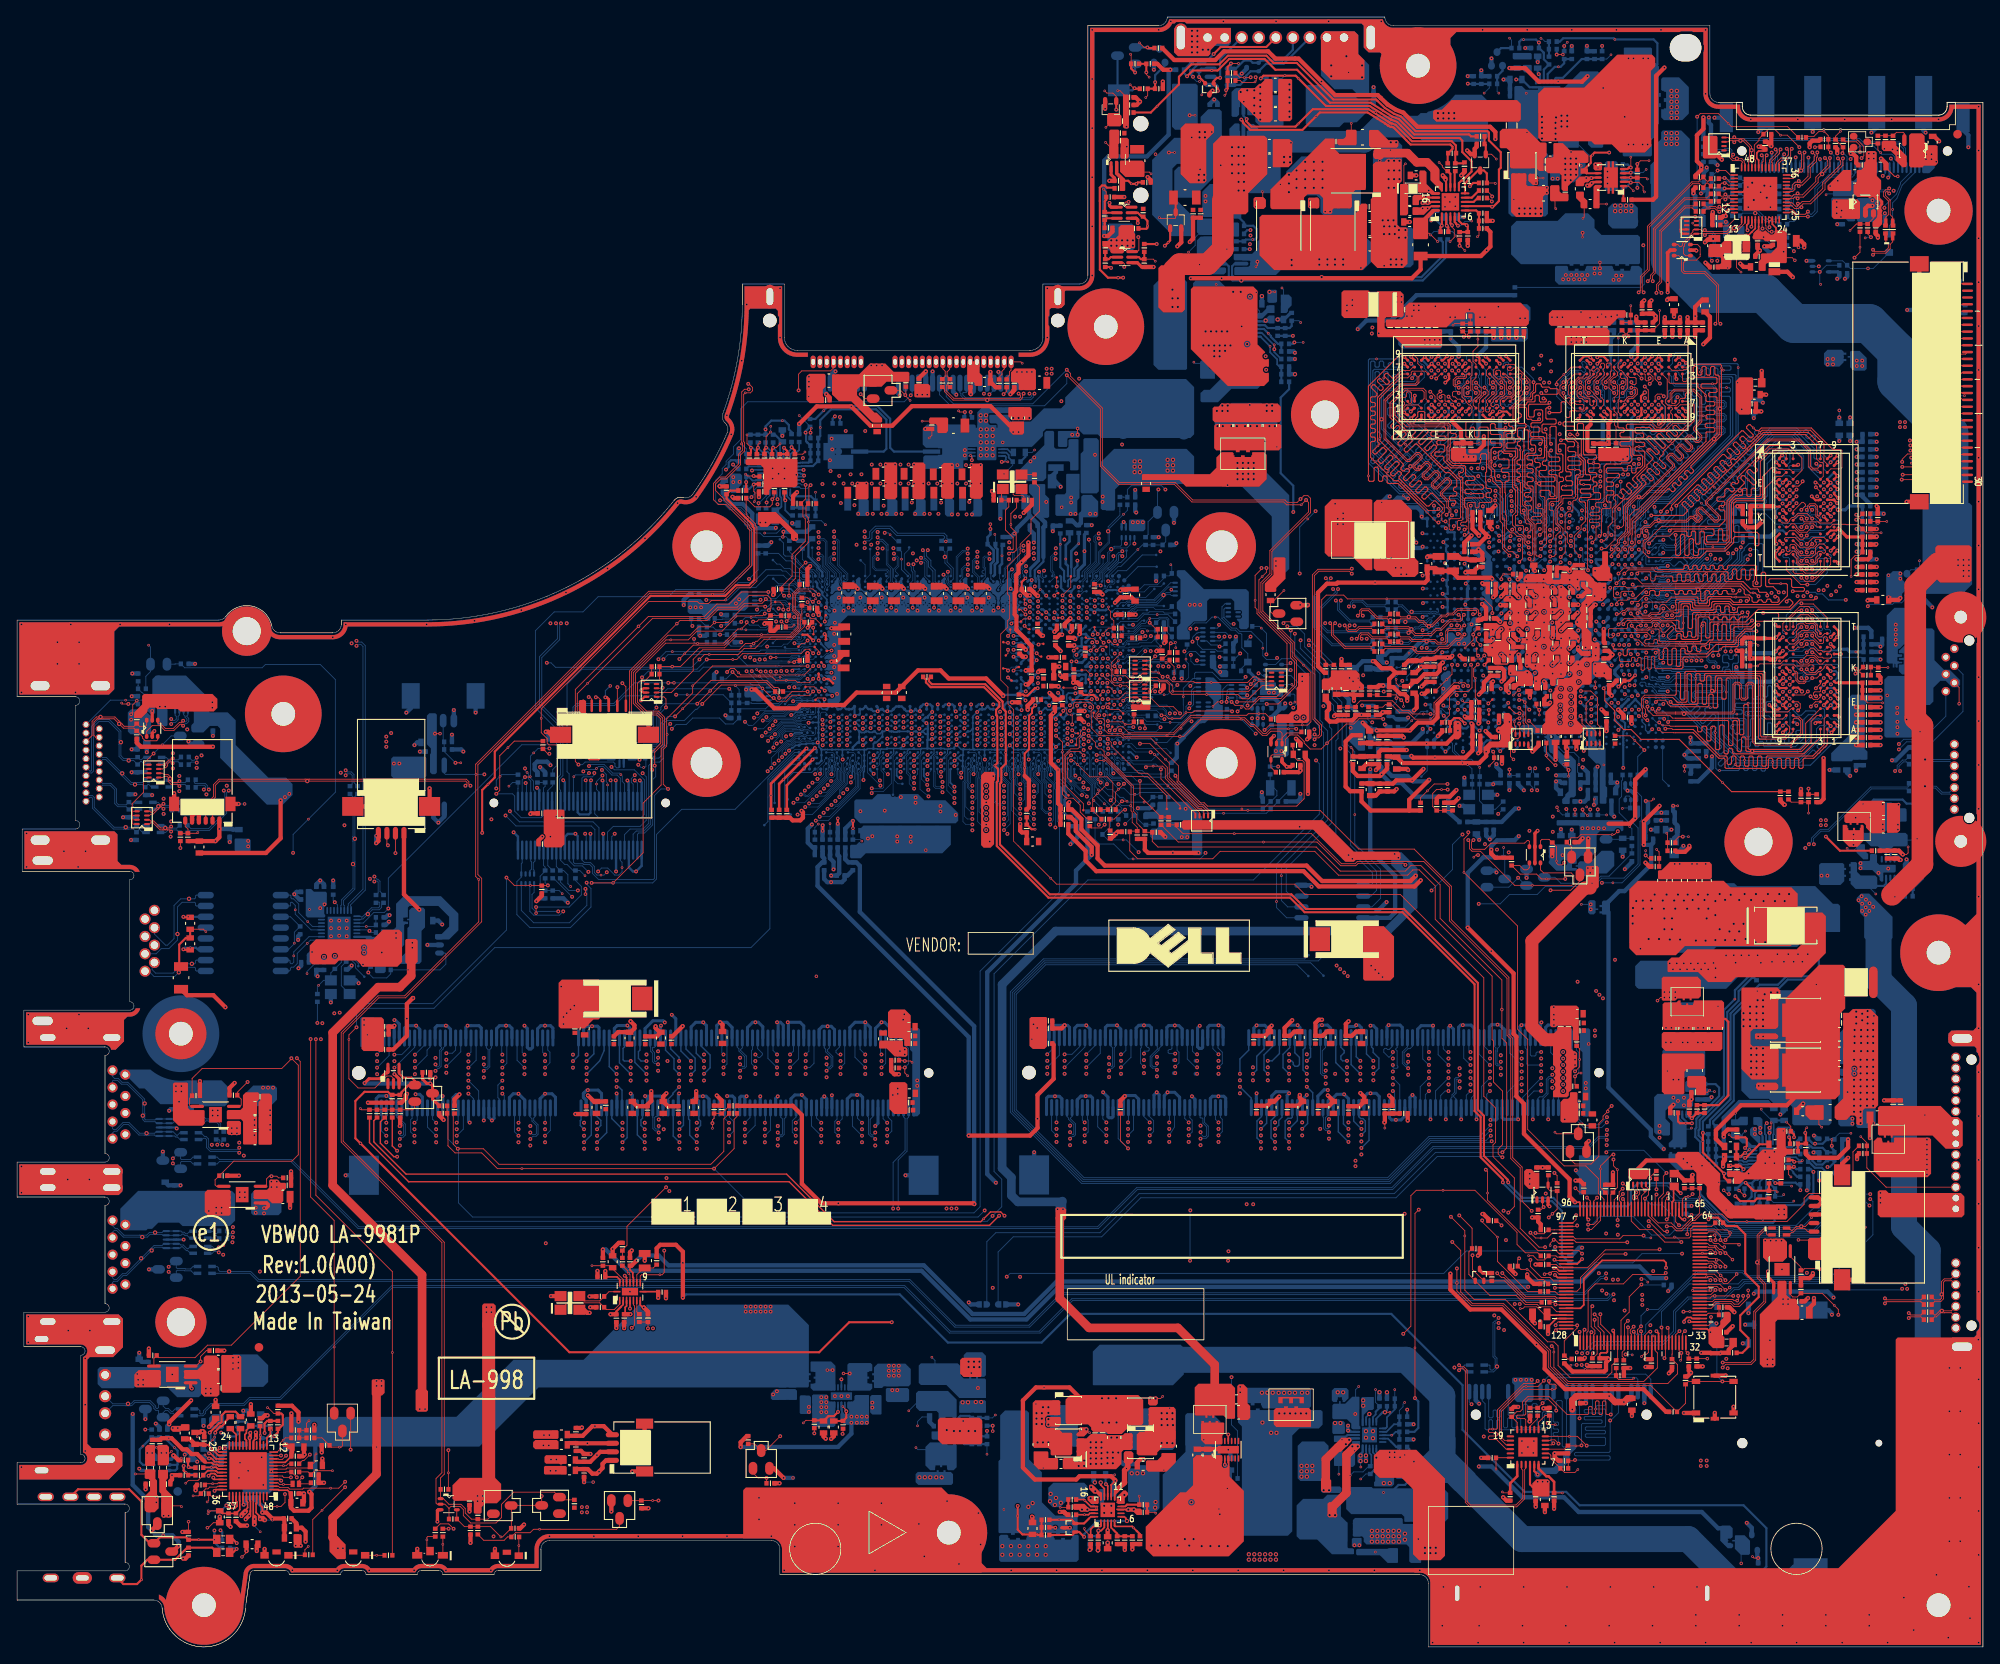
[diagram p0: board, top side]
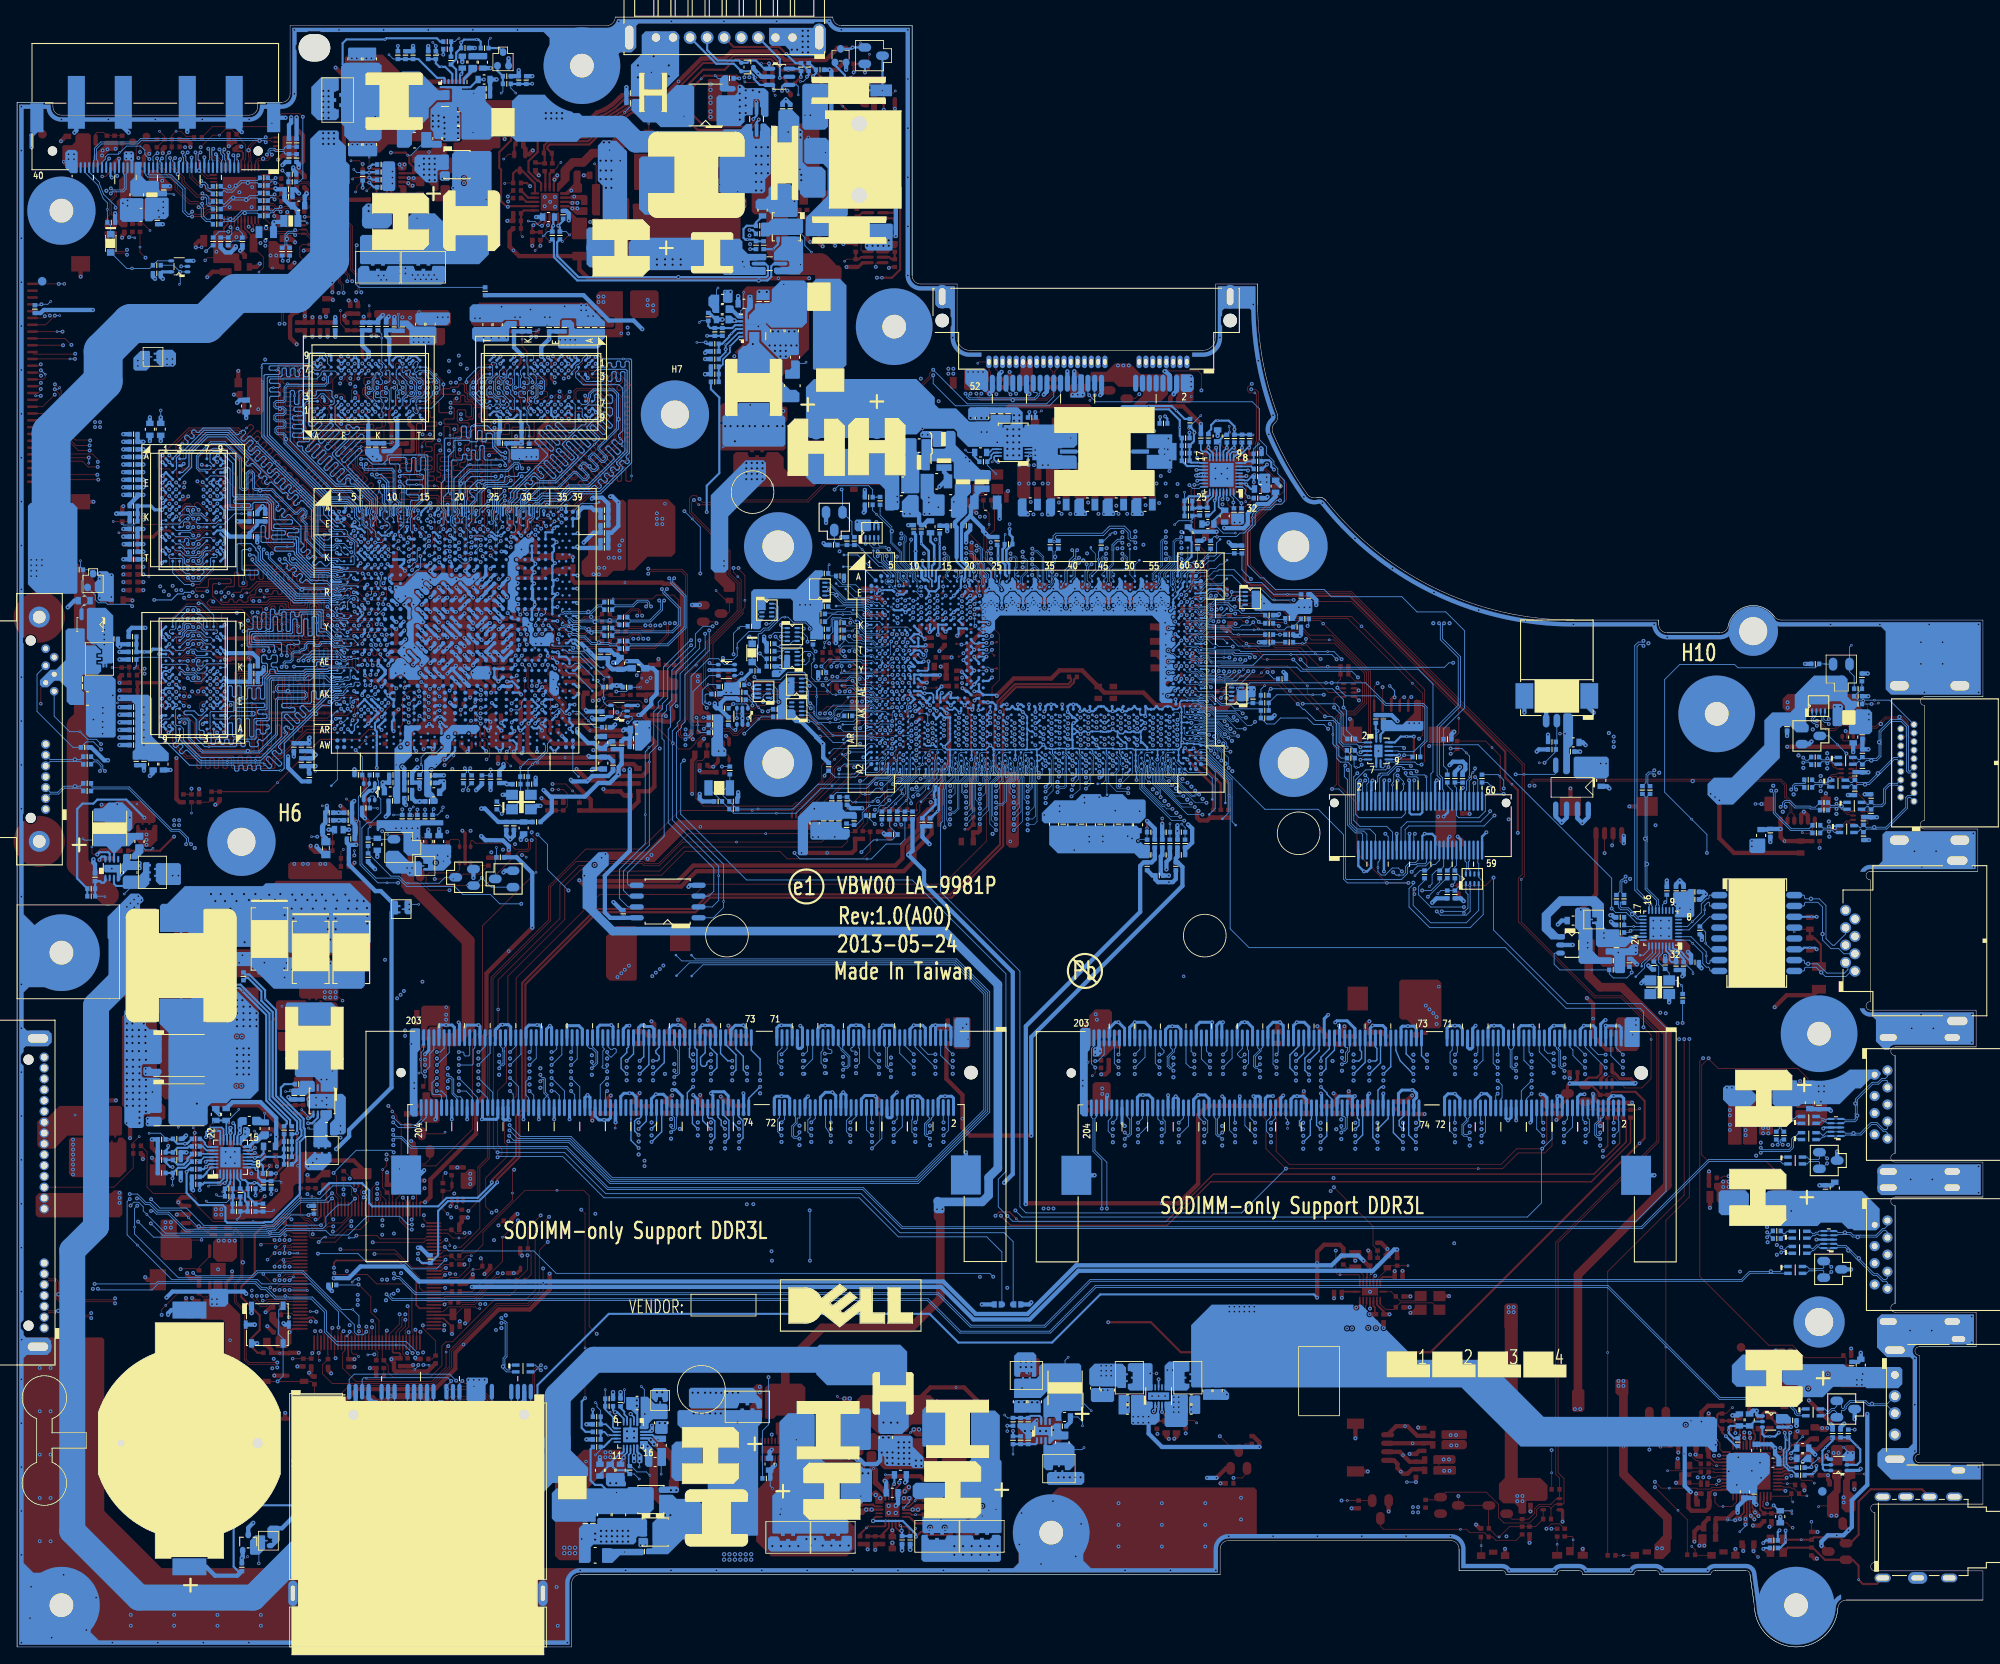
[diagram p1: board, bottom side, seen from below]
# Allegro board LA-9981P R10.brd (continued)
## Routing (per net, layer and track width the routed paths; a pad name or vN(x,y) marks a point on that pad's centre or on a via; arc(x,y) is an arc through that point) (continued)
DDR_A_MA8: length 75.2
  IN1 w0.084: 104.06,95.63 103.18,95.63 102.6,95.06 102.6,93.66
  IN1 w0.089: 104.06,95.63 106.77,98.35 106.77,98.96 107.2,99.38 107.2,101.83 v1(106.7,102.33)
  IN1 w0.183: v1(71.92,67.18) 71.92,67.26 71.45,67.73 71.45,70.25 71.91,70.71 71.91,70.95 71.43,71.43 71.43,71.98 71.55,72.1 71.79,72.1 72.46,71.44 72.64,71.44 72.98,71.78 72.98,71.96 72.15,72.78 72.15,72.96 72.49,73.3 72.67,73.3 72.99,72.98 73.17,72.98 73.5,73.32 73.5,73.5 72.86,74.14 72.86,74.32 73.2,74.66 73.38,74.66 74.02,74.02 74.2,74.02 74.54,74.36 74.54,74.53 73.9,75.17 73.9,75.35 74.23,75.69 74.41,75.69 74.85,75.26 75.08,75.26 75.21,75.39 75.21,76.37 75.34,76.5 75.91,76.5 76.04,76.37 76.04,75.63 76.17,75.5 76.7,75.5 76.83,75.63 76.83,76.35 76.96,76.47 92.27,76.47 102.6,86.81 102.6,93.66
  BOTTOM w0.076: UC1.AY39 107.1,102.73 v1(106.7,102.33)
  BOTTOM w0.165: JDIMM1.89 70.6,68.49 v1(71.92,67.18)
DDR_A_MA9: length 77.3
  IN1 w0.084: 102.14,93.66 102.14,94.84 103.11,95.81 103.35,95.81
  IN1 w0.089: 103.35,95.81 103.98,95.81 106.6,98.43 106.6,99.5 v1(106.82,99.73)
  IN1 w0.183: v1(70.27,67.18) 70.71,66.73 70.71,63.35 70.84,63.22 71.34,63.22 71.47,63.35 71.47,67.06 70.99,67.53 70.99,73.07 74.86,76.94 92.11,76.94 102.14,86.96 102.14,93.66
  BOTTOM w0.076: v1(106.82,99.73) 105.82,100.55 105.82,104.41 106.09,104.67 106.09,104.74 UC1.AU40
  BOTTOM w0.165: JDIMM1.85 69.4,68.04 v1(70.27,67.18)
DDR_A_MA10: length 76.4
  IN1 w0.084: 108.18,95.34 108.47,95.63
  IN1 w0.089: 108.47,95.63 109.56,96.71 109.56,97.76 109.72,97.92 110.13,97.92 110.24,98.03 110.24,99.72 110.05,99.91 109.61,99.91 109.48,100.04 109.48,101.43 109.25,101.66 109.25,102.81 108.93,103.13 108.93,105.41 108.78,105.56 108.78,106.06 109.09,106.37 v1(109.16,106.37)
  IN1 w0.183: v1(77.59,67.18) 78.05,67.64 78.05,69.03 78.61,69.58 79.38,69.58 80.33,70.54 97.31,70.54 97.44,70.41 97.44,69.16 97.57,69.04 98.04,69.04 98.17,69.16 98.17,72.23 98.3,72.36 98.83,72.36 98.96,72.23 98.96,71.31 99.09,71.18 99.6,71.18 99.72,71.31 99.72,72.23 99.85,72.36 100.4,72.36 100.52,72.48 100.52,73.85 107.88,81.2 107.88,95.04 108.18,95.34
  BOTTOM w0.076: UC1.AP35 109.48,106.69 v1(109.16,106.37)
  BOTTOM w0.165: v1(77.59,67.18) 76.99,67.77 76.99,68.97 76,69.96 JDIMM1.107
DDR_A_MA11: length 75.9
  IN1 w0.084: v1(105.12,103.28) 105.42,103.28 105.88,102.82 105.88,98.77 103.98,96.87 103.17,96.87 100.28,93.97 100.28,93.66
  IN1 w0.183: v1(67.97,59.17) 68.92,60.12 68.92,63.38 68.3,64 68.3,69.21 69.14,70.05 69.14,73.83 74.1,78.79 90.44,78.79 100.28,88.62 100.28,93.66
  BOTTOM w0.076: v1(105.12,103.28) 105.13,103.28 105.43,103.58 UC1.AW41
  BOTTOM w0.165: v1(67.97,59.17) 69.1,60.3 JDIMM1.84
DDR_A_MA12: length 74.6
  IN1 w0.084: v1(105.13,104.58) 104.32,104.58 104.21,104.47 104.21,99.21 101.13,96.13 100.02,96.13 98.38,94.49 98.38,93.66
  IN1 w0.183: 98.38,93.66 98.38,89.34 89.67,80.64 71.88,80.64 69.87,78.62 69.87,78.37 70.41,77.82 70.41,77.64 67.34,74.58 67.34,73.92 67.12,73.7 66.16,73.7 65.84,73.38 65.84,68.41 65.97,68.28 66.18,68.28 66.3,68.15 66.3,67.7 66.18,67.57 65.71,67.57 65.58,67.45 65.58,66.82 65.9,66.49 66.08,66.49 v1(66.75,67.16)
  BOTTOM w0.076: v1(105.13,104.58) 105.28,104.58 UC1.AU41
  BOTTOM w0.165: JDIMM1.83 68.8,69.92 68.29,68.72 v1(66.75,67.16)
DDR_A_MA13: length 75.1
  IN1 w0.084: v1(109.16,105.72) 109.16,103.16 109.44,102.88 109.44,101.85 110.65,100.65 110.65,96.66 109.89,95.9
  IN1 w0.183: v1(80.51,68.7) 82.2,68.7 82.32,68.57 82.32,66.62 82.6,66.35 90.8,66.35 91.14,66.69 91.14,69.43 91.27,69.55 91.74,69.55 91.87,69.43 91.87,66.54 92.06,66.35 99.22,66.35 100.17,67.3 100.17,70.53 102.71,73.07 102.71,74.52 108.8,80.61 108.8,94.82 109.89,95.9
  BOTTOM w0.089: v1(109.16,105.72) 109.48,106.04 UC1.AR35
  BOTTOM w0.165: v1(80.51,68.7) 79.6,69.61 JDIMM1.119
DDR_A_MA14: length 74.7
  IN1 w0.084: v1(105.13,101.28) 105.71,100.71 105.71,98.85 103.94,97.08 103.13,97.08 99.81,93.76 99.81,93.66
  IN1 w0.183: v1(67.97,60.7) 68.35,60.7 68.48,60.83 68.48,61.78 68.35,61.91 67.97,61.91 67.84,62.03 67.84,62.53 67.97,62.65 68.3,62.65 68.48,62.84 68.48,63.2 68.3,63.39 67.97,63.39 67.84,63.51 67.84,69.4 68.68,70.25 68.68,74.02 73.9,79.25 90.25,79.25 99.81,88.82 99.81,93.66
  BOTTOM w0.076: v1(105.13,101.28) 104.73,101.69 104.73,102.27 104.41,102.58 104.41,103.94 UC1.AV42
  BOTTOM w0.165: v1(67.97,60.7) 68.41,61.14 68.41,61.74 67.9,62.25 JDIMM1.80
DDR_A_MA15: length 76.9
  IN1 w0.084: v1(105.13,100.63) 104.85,100.35 104.85,99.15 99.89,94.18 99.53,94.18 99.35,94 99.35,93.66
  IN1 w0.183: v1(66.45,59.17) 67.29,59.17 67.38,59.26 67.38,69.6 68.22,70.44 68.22,74.22 73.71,79.71 90.06,79.71 99.35,89.01 99.35,93.66
  BOTTOM w0.076: v1(105.13,100.63) 104.56,101.2 104.56,102.13 104.25,102.44 104.25,104.41 104.51,104.67 104.51,104.74 UC1.AU42
  BOTTOM w0.165: JDIMM1.78 67.3,60.02 v1(66.45,59.17)
DDR_A_RAS#: length 75.3
  IN1 w0.084: 111.11,94.57 111.11,95.4 111.37,95.66 111.37,101.59 111.01,101.94
  IN1 w0.089: 111.01,101.94 v1(110.66,101.94)
  IN1 w0.183: 111.11,94.57 111.11,79.73 105.41,74.03 105.41,72.43 102.68,69.69 102.68,66.61 98.67,62.6 78.13,62.6 76.94,61.4 76.94,59.87 v1(77.63,59.17)
  BOTTOM w0.076: UC1.AY34 110.25,102.34 v1(110.66,101.94)
  BOTTOM w0.165: JDIMM1.110 76.9,59.9 v1(77.63,59.17)
DDR_A_WE#: length 75.1
  IN1 w0.084: v1(109.86,103.28) 109.79,103.21 109.79,102 111.02,100.77 111.02,95.94 110.19,95.11 110.19,94.57
  IN1 w0.183: v1(78.98,68.7) 79.59,68.08 79.59,67.13 79.86,66.86 79.86,66.37 80.93,65.31 80.93,64.15 81.13,63.94 83.76,63.94 83.94,64.12 83.94,64.72 84.12,64.91 84.49,64.91 84.67,64.72 84.67,64.12 84.86,63.94 87.49,63.94 87.67,64.12 87.67,64.72 87.85,64.91 88.22,64.91 88.4,64.72 88.4,64.12 88.58,63.94 98.77,63.94 101.8,66.97 101.8,70.06 104.54,72.79 104.54,74.39 110.19,80.04 110.19,94.57
  BOTTOM w0.089: UC1.AW34 110.25,103.38 110.15,103.28 v1(109.86,103.28)
  BOTTOM w0.165: v1(78.98,68.7) 77.8,69.88 JDIMM1.113
DDR_B_BS0: length 95.8
  IN3 w0.084: v1(109.16,108.32) 108.87,108.32 108.78,108.23 108.78,105.04 109.09,104.72 109.09,99.68 108.61,99.2 108.61,97.5 108.22,97.1 108.22,96.4
  IN3 w0.208: v1(155.87,68.72) 155.87,72.88 155.3,73.44 155.04,73.44 154.22,74.26 154.22,74.57 154.4,74.75 154.4,75.04 153.52,75.92 153.06,75.92 152.86,76.12 152.86,76.58 152.65,76.78 152.25,76.78 152.05,76.58 152.05,76.24 151.84,76.03 151.44,76.03 151.29,76.18 151.29,76.66 151.16,76.78 133.95,76.78 133.74,76.98 133.74,78.59 133.54,78.8 133.08,78.8 132.88,78.59 132.88,76.98 132.68,76.78 132.22,76.78 132.01,76.98 132.01,78.59 131.81,78.8 131.35,78.8 131.15,78.59 131.15,76.98 130.95,76.78 130.49,76.78 130.29,76.98 130.29,78.59 130.08,78.8 129.63,78.8 129.42,78.59 129.42,76.98 129.22,76.78 128.76,76.78 128.56,76.98 128.56,78.59 128.36,78.8 119.52,78.8 108.22,90.11 108.22,96.4
  BOTTOM w0.076: v1(109.16,108.32) 109.48,108.64 UC1.AL35
  BOTTOM w0.165: JDIMM2.109 155.15,70.31 155.54,69.92 155.54,69.67 155.15,69.28 155.15,68.92 155.35,68.72 v1(155.87,68.72)
DDR_B_BS1: length 97.9
  IN3 w0.084: v1(108.21,107.82) 107.83,107.45 107.83,99.52 107.28,98.97 107.28,96.59 107.28,96.59 107.28,94.57
  IN3 w0.208: 107.28,94.57 107.28,89.72 119.14,77.87 123.96,77.87 124.17,77.65 124.17,76.08 124.41,75.85 150.31,75.85 152.06,74.1 153.05,74.1 153.4,73.75 153.4,72.91 154.94,71.37 154.94,65.95 154.72,65.73 154.29,65.73 154.08,65.53 154.08,64.91 154.29,64.71 154.96,64.71 155.16,64.5 155.16,64.04 154.96,63.84 154.57,63.84 154.44,63.71 154.44,63.11 154.57,62.98 156.48,62.98 156.68,62.77 156.68,62.32 156.48,62.11 155.65,62.11 155.45,61.91 155.45,59.42 155.65,59.21 v1(156.04,59.21)
  BOTTOM w0.076: UC1.AM36 108.38,107.99 v1(108.21,107.82)
  BOTTOM w0.165: v1(156.04,59.21) 154.85,60.4 JDIMM2.108
DDR_B_BS2: length 92.6
  IN3 w0.084: 98.95,93.66 98.95,95.23 100.72,97 100.72,101.79 100.94,102.01 100.94,104.03 v1(100.41,104.56)
  IN3 w0.208: v1(144.84,67.2) 145.38,66.66 145.38,65.67 144.81,65.1 144.81,63.64 144.55,63.37 119.23,63.37 110.26,72.34 110.26,72.67 111.37,73.77 111.37,74.06 110.95,74.48 110.66,74.48 109.54,73.36 109.25,73.36 108.93,73.68 108.93,73.97 110.05,75.09 110.05,75.38 109.73,75.7 109.44,75.7 108.7,74.96 108.41,74.96 108.09,75.28 108.09,75.57 108.82,76.3 108.82,76.61 98.95,86.48 98.95,93.66
  BOTTOM w0.076: v1(100.41,104.56) 100.53,104.56 UC1.AU49
  BOTTOM w0.165: v1(144.84,67.2) 145.28,67.64 145.28,69.25 146.15,70.11 JDIMM2.79
DDR_B_CAS#: length 96.2
  IN3 w0.084: 109.63,96.34 109.63,98.43 109.76,98.56 110.39,98.56 110.52,98.69 110.52,101.29 110.39,101.42 110.01,101.42 109.88,101.55 109.88,101.86 110.25,102.23 110.25,103.73 110.48,103.96 110.48,107.15 110.01,107.62 v1(110.01,107.71)
  IN3 w0.208: v1(157.43,68.72) 158.01,68.15 158.27,68.15 158.49,68.36 158.49,68.92 158.62,69.05 158.62,72.2 158.15,72.66 158.15,73.28 153.24,78.19 142.26,78.19 142.06,78.39 142.06,80 141.86,80.21 141.4,80.21 141.2,80 141.2,78.39 140.99,78.19 140.54,78.19 140.33,78.39 140.33,80 140.13,80.21 139.67,80.21 139.47,80 139.47,78.39 139.27,78.19 138.81,78.19 138.61,78.39 138.61,80 138.4,80.21 137.95,80.21 137.74,80 137.74,78.39 137.54,78.19 137.08,78.19 136.88,78.39 136.88,80 136.68,80.21 120.11,80.21 109.63,90.69 109.63,96.34
  BOTTOM w0.076: UC1.AM33 110.37,107.99 110.08,107.71 v1(110.01,107.71)
  BOTTOM w0.165: v1(157.43,68.72) 156.95,69.2 JDIMM2.115
DDR_B_D0: length 80.9
  IN3 w0.084: 112.95,94.57 112.95,95.11 112.69,95.37 112.69,97.6 112.56,97.72 v1(111.96,97.72)
  IN3 w0.127: v1(161.24,66.71) 161.89,66.71 162.03,66.84 162.03,69.48 162.45,69.9 162.45,73.77 154.7,81.52 151.53,81.52 150.42,82.62 149.6,82.62 148.69,83.53 121.86,83.53 116.81,88.59 116.44,88.59 112.95,92.07 112.95,94.57
  BOTTOM w0.076: UC1.AY31 111.38,102.81 111.38,101.48 111.19,101.3 111.19,98.49 v1(111.96,97.72)
  BOTTOM w0.102: JDIMM2.132 162.05,65.9 v1(161.24,66.71)
DDR_B_D1: length 82
  IN3 w0.084: 112.59,94.57 112.59,95.07 112.52,95.14 112.52,97.25 112.39,97.37 112.08,97.37 111.96,97.25 v1(111.96,97.07)
  IN3 w0.127: v1(161.24,68.23) 161.56,68.23 161.66,68.34 161.66,69.63 162.09,70.05 162.09,72.15 161.96,72.28 161.73,72.28 161.61,72.4 161.61,72.66 161.73,72.79 161.96,72.79 162.09,72.92 162.09,73.23 161.96,73.35 161.73,73.35 161.61,73.48 161.61,74.11 154.56,81.16 151.38,81.16 150.27,82.26 149.45,82.26 148.54,83.17 121.71,83.17 116.66,88.22 116.28,88.22 112.59,91.92 112.59,94.57
  BOTTOM w0.076: UC1.AW31 111.5,103.38 111.3,103.18 111.21,103 111.21,101.55 111.02,101.37 111.02,97.42 111.37,97.07 v1(111.96,97.07)
  BOTTOM w0.102: v1(161.24,68.23) 161.24,67.98 161.37,67.85 161.73,67.85 161.83,67.96 161.83,68.08 161.74,68.17 161.74,69.88 161.57,70.05 161.57,70.11 161.75,70.29 JDIMM2.131
DDR_B_D2: length 81.4
  IN3 w0.084: v1(113.58,97.07) 114,96.66 114,95.37 115.19,94.17 115.19,93.94
  IN3 w0.127: v1(165.47,66.71) 164.39,66.71 164.26,66.83 164.26,67.34 164.69,67.77 164.69,75 155.93,83.76 152.45,83.76 151.35,84.86 150.53,84.86 149.62,85.77 122.79,85.77 117.74,90.83 117.4,90.83 115.19,93.03 115.19,93.94
  BOTTOM w0.076: UC1.AY29 112.85,101.92 112.74,101.81 112.74,97.92 v1(113.58,97.07)
  BOTTOM w0.102: JDIMM2.140 164.45,65.68 v1(165.47,66.71)
DDR_B_D3: length 82.1
  IN3 w0.084: 115.55,93.94 115.55,94.05 114.33,95.28 114.33,96.88 114.21,97 114.08,97 113.95,97.13 113.95,97.26 114.04,97.36 114.22,97.36 114.33,97.46 114.33,97.9 114.21,98.02 113.88,98.02 v1(113.58,97.72)
  IN3 w0.127: 115.55,93.94 115.55,93.18 117.55,91.19 117.89,91.19 122.94,86.14 149.77,86.14 150.68,85.22 151.5,85.22 152.6,84.12 156.08,84.12 165.05,75.15 165.05,74.21 165.19,74.08 165.31,74.08 165.43,73.95 165.43,73.69 165.31,73.56 165.19,73.56 165.05,73.43 165.05,71.85 165.19,71.72 165.31,71.72 165.43,71.59 165.43,71.33 165.31,71.2 165.19,71.2 165.05,71.07 165.05,70.82 165.19,70.69 165.31,70.69 165.43,70.56 165.43,70.3 165.31,70.17 165.19,70.17 165.05,70.04 165.05,68.36 165.18,68.23 v1(165.47,68.23)
  BOTTOM w0.076: v1(113.58,97.72) 112.91,98.4 112.91,101.72 113.02,101.83 113.02,102.68 113.15,102.81 113.15,103.05 112.85,103.35 UC1.AW29
  BOTTOM w0.102: v1(165.47,68.23) 165.45,68.23 164.75,68.93 JDIMM2.141
DDR_B_D4: length 83.1
  IN3 w0.084: 112.23,95.33 112.35,95.45 112.35,96.6 112.23,96.72 112.07,96.72 111.96,96.6 v1(111.96,96.42)
  IN3 w0.127: v1(161.24,69.75) 161.24,70.1 161.32,70.18 161.6,70.18 161.72,70.31 161.72,70.62 161.6,70.75 161.34,70.75 161.22,70.88 161.22,71.2 161.34,71.33 161.6,71.33 161.72,71.45 161.72,71.72 161.6,71.84 161.37,71.84 161.24,71.97 161.24,73.96 154.41,80.79 151.22,80.79 151.07,80.95 150.88,80.95 150.72,80.79 150.54,80.79 150.33,81 150.33,81.17 150.49,81.33 150.49,81.52 150.12,81.9 149.92,81.9 149.76,81.74 149.47,81.74 148.39,82.81 121.19,82.81 121.06,82.93 121.06,83.31 120.8,83.58 120.42,83.58 120.23,83.76 120.23,84.14 120.03,84.34 119.66,84.34 119.47,84.52 119.47,84.9 119.33,85.04 118.96,85.04 118.77,85.22 118.77,85.6 118.64,85.74 118.26,85.74 118.14,85.86 118.14,86.23 118,86.37 117.62,86.37 117.44,86.55 117.44,86.93 117.24,87.13 116.86,87.13 116.68,87.32 116.68,87.69 116.51,87.86 116.13,87.86 112.23,91.77 112.23,95.33
  BOTTOM w0.076: v1(111.96,96.42) 111.2,96.42 110.86,96.76 110.86,101.43 111.04,101.62 111.04,103.04 111.07,103.08 111.12,103.19 111.12,103.85 UC1.AV31
  BOTTOM w0.102: JDIMM2.129 161.15,70.39 160.81,70.05 160.62,70.05 160.49,70.18 160.3,70.18 160.18,70.05 160.18,69.73 160.74,69.17 160.84,69.17 161.24,69.57 v1(161.24,69.75)
DDR_B_D5: length 83.4
  IN3 w0.084: 113.32,94.21 113.32,95.02 112.86,95.47 112.86,98.12 v1(111.96,99.02)
  IN3 w0.127: v1(161.24,65.18) 162.09,65.18 162.39,65.48 162.39,69.33 162.81,69.75 162.81,73.91 154.84,81.88 151.68,81.88 150.57,82.99 149.75,82.99 148.84,83.9 122.02,83.9 116.96,88.95 116.59,88.95 113.32,92.22 113.32,94.21
  BOTTOM w0.076: UC1.AU31 112.27,104.88 112.47,104.68 112.47,104.44 112.45,104.42 112.45,104.04 112.47,104.03 112.47,103.84 112.46,103.83 112.42,103.74 112.42,103.74 112.4,103.69 112.4,103.48 112.47,103.32 112.47,103.19 112.42,103.09 112.4,103.03 112.4,102.6 112.5,102.49 112.5,102.09 112.38,101.97 112.38,99.45 v1(111.96,99.02)
  BOTTOM w0.102: JDIMM2.130 161.45,64.97 v1(161.24,65.18)
DDR_B_D6: length 82.9
  IN3 w0.084: v1(113.58,95.77) 113.58,95.54 114.84,94.28 114.84,93.94
  IN3 w0.127: 114.84,93.94 114.84,92.88 117.25,90.47 117.59,90.47 122.64,85.42 149.47,85.42 150.38,84.51 151.2,84.51 152.31,83.4 155.49,83.4 155.5,83.39 155.78,83.39 164.33,74.85 164.33,74.57 164.33,74.56 164.33,67.99 163.9,67.55 163.9,65.31 164.02,65.18 v1(165.47,65.18)
  BOTTOM w0.076: v1(113.58,95.77) 112.56,96.79 112.56,101.87 112.66,101.97 112.66,102.56 112.56,102.67 112.56,103 112.61,103.1 112.64,103.16 112.64,103.36 112.61,103.41 112.57,103.5 112.56,103.52 112.56,103.65 112.59,103.7 112.61,103.75 112.66,103.81 112.66,104.15 UC1.AV29
  BOTTOM w0.102: v1(165.47,65.18) 165.05,64.76 JDIMM2.142
DDR_B_D7: length 83.2
  IN3 w0.084: v1(113.58,98.37) 113.95,98.37 114.07,98.5 114.07,100.46 114.2,100.59 114.38,100.59 114.5,100.46 114.5,95.35 115.61,94.24 115.76,94.24 115.92,94.09 115.92,93.94
  IN3 w0.127: 115.92,93.94 115.92,93.33 117.7,91.55 118.04,91.55 123.09,86.5 149.92,86.5 150.83,85.59 151.65,85.59 152.76,84.48 156.23,84.48 165.42,75.3 165.42,74.62 165.54,74.5 165.67,74.5 165.8,74.37 165.8,73.35 165.67,73.23 165.54,73.23 165.42,73.1 165.42,72.12 165.54,71.99 165.67,71.99 165.8,71.87 165.8,69.88 165.67,69.75 v1(165.47,69.75)
  BOTTOM w0.076: UC1.AU29 112.75,104.65 113.04,104.35 113.04,104.11 113.02,104.09 113.02,103.83 113.15,103.7 113.15,103.29 113.31,103.12 113.31,102.74 113.18,102.62 113.18,101.74 113.07,101.63 113.07,98.88 v1(113.58,98.37)
  BOTTOM w0.102: JDIMM2.143 165.35,69.86 165.47,69.73 v1(165.47,69.75)
DDR_B_D8: length 55.4
  IN1 w0.084: v1(113.58,99.67) 113.19,99.28 113.19,95.61 113.43,95.37 113.43,94.1
  IN1 w0.127: v1(120.74,69.48) 120.31,69.06 120.13,69.06 119.74,69.45 119.74,69.63 120.88,70.78 120.88,70.96 120.7,71.15 120.52,71.15 119.37,70 119.19,70 119,70.19 119,70.37 119.88,71.24 119.88,71.42 119.69,71.61 119.51,71.61 118.63,70.74 118.45,70.74 118.26,70.93 118.26,71.11 118.91,71.75 118.91,71.93 118.72,72.12 118.54,72.12 117.89,71.47 117.71,71.47 117.53,71.66 117.53,71.84 118.16,72.48 118.16,72.66 117.97,72.85 117.79,72.85 117.16,72.21 116.98,72.21 116.79,72.4 116.79,72.58 117.98,73.77 117.98,73.95 117.79,74.14 117.61,74.14 116.42,72.95 116.24,72.95 116.05,73.14 116.05,73.31 116.56,73.82 116.56,74 116.37,74.19 116.19,74.19 115.94,73.94 115.75,73.94 113.43,76.26 113.43,94.1
  BOTTOM w0.076: v1(113.58,99.67) 114.14,100.23 114.14,101.35 113.69,101.8 113.69,102.42 113.81,102.54 113.81,102.81 UC1.AY27
  BOTTOM w0.102: v1(120.74,69.48) 121.55,70.3 JDIMM2.5
DDR_B_D9: length 56.3
  IN1 w0.084: v1(113.58,100.32) 112.99,99.73 112.99,95.18 113.07,95.1 113.07,94.46
  IN1 w0.127: 113.07,94.46 113.07,75.63 120.25,68.46 120.25,66.9 120.37,66.77 121.2,66.77 121.33,66.65 121.33,66.39 121.2,66.27 120.37,66.27 120.25,66.14 120.25,65.89 120.37,65.76 121.63,65.76 121.76,65.63 121.76,65.38 121.63,65.25 120.37,65.25 120.25,65.12 120.25,64.87 120.37,64.74 121.1,64.74 121.23,64.62 121.23,64.36 121.1,64.23 120.37,64.23 120.25,64.11 120.25,63.85 120.37,63.73 120.94,63.73 121.06,63.6 121.06,63.35 120.94,63.22 120.37,63.22 120.25,63.09 120.25,62.84 120.37,62.71 121.25,62.71 121.82,62.14 v1(121.82,61.5)
  BOTTOM w0.076: UC1.AW27 113.93,103.35 113.64,103.05 113.64,102.61 113.53,102.49 113.53,101.73 113.98,101.28 113.98,100.72 v1(113.58,100.32)
  BOTTOM w0.102: v1(121.82,61.5) 121.85,61.53 JDIMM2.6
DDR_B_D10: length 55.8
  IN1 w0.084: v1(115.67,97.07) 115.34,97.07 115.22,97.2 115.22,97.68 115.09,97.81 114.75,97.81 114.62,97.68 114.62,94.46 114.75,94.34 115.2,94.34 115.33,94.21 115.33,93.94
  IN1 w0.127: 115.33,93.94 115.33,79.35 118.38,76.29 118.61,76.29 119.36,77.04 119.52,77.04 119.73,76.83 119.73,76.67 118.9,75.84 118.9,75.66 119.09,75.48 119.27,75.48 120.1,76.3 120.26,76.3 120.46,76.1 120.46,75.94 119.64,75.11 119.64,74.93 119.82,74.74 120,74.74 120.83,75.57 120.99,75.57 121.2,75.36 121.2,75.2 120.37,74.37 120.37,74.19 120.56,74 120.74,74 121.57,74.83 121.73,74.83 121.94,74.62 121.94,74.46 121.11,73.63 121.11,73.45 121.3,73.27 121.48,73.27 122.31,74.09 122.47,74.09 122.67,73.89 122.67,73.73 121.84,72.89 121.84,72.73 122.77,71.8 v1(122.77,69.48)
  BOTTOM w0.076: UC1.AY25 115.16,102.81 115.16,102.03 115.58,101.6 115.6,101.6 116.06,101.14 116.06,97.47 v1(115.67,97.07)
  BOTTOM w0.102: JDIMM2.15 124.55,70.4 123.63,69.48 v1(122.77,69.48)
DDR_B_D11: length 56.4
  IN1 w0.084: v1(115.67,96.42) 115.67,96.6 115.54,96.72 114.96,96.72 114.84,96.6 114.84,96.23 114.92,96.15 115.2,96.15 115.28,96.06 115.28,95.89 115.2,95.81 114.92,95.81 114.84,95.73 114.84,95.56 114.92,95.47 115.2,95.47 115.28,95.39 115.28,95.22 115.2,95.14 114.92,95.14 114.84,95.06 114.84,94.69 114.96,94.56 115.55,94.56 115.68,94.44 115.68,93.94
  IN1 w0.127: 115.68,93.94 115.68,81.43 116.06,81.05 116.06,80.84 115.68,80.47 115.68,79.51 116.04,79.15 116.33,79.15 117.03,79.85 117.19,79.85 117.4,79.65 117.4,79.49 116.69,78.78 116.69,78.6 116.88,78.41 117.06,78.41 117.77,79.12 117.93,79.12 118.14,78.91 118.14,78.75 117.41,78.02 117.41,77.84 117.6,77.65 117.78,77.65 118.51,78.38 118.67,78.38 118.87,78.17 118.87,78.01 118.15,77.29 118.15,77.11 118.34,76.92 118.52,76.92 119.24,77.64 119.45,77.64 123.39,73.7 123.39,68.58 v1(122.77,67.96)
  BOTTOM w0.076: UC1.AW25 115.5,103.36 115.5,103.16 115.53,103.1 115.53,103.1 115.58,103 115.58,102.81 115.32,102.55 115.32,102.09 115.65,101.77 115.67,101.77 116.23,101.21 116.23,96.98 v1(115.67,96.42)
  BOTTOM w0.102: JDIMM2.17 125.15,70.34 v1(122.77,67.96)
DDR_B_D12: length 56.6
  IN1 w0.084: 112.72,94.57 112.72,95.87 112.67,95.92 112.67,100.06 v1(113.58,100.97)
  IN1 w0.127: v1(121.82,59.98) 121.53,60.26 120.74,60.26 120.62,60.39 120.62,60.64 120.74,60.77 121.12,60.77 121.25,60.9 121.25,61.15 121.12,61.28 120.02,61.28 119.89,61.41 119.89,61.66 120.02,61.79 121.12,61.79 121.25,61.91 121.25,62.17 121.12,62.3 120.02,62.3 119.89,62.42 119.89,68.31 112.72,75.48 112.72,94.57
  BOTTOM w0.076: UC1.AV27 114.04,104.1 113.64,103.7 113.64,103.3 113.48,103.13 113.48,102.67 113.35,102.55 113.35,101.64 113.58,101.4 v1(113.58,100.97)
  BOTTOM w0.102: JDIMM2.4 121.25,60.55 v1(121.82,59.98)
DDR_B_D13: length 57.2
  IN1 w0.084: 116.45,93.94 116.54,94.03 116.54,95.39 116.04,95.89 116.04,99.95 v1(115.67,100.32)
  IN1 w0.127: v1(125.12,61.5) 125.12,63.07 125,63.2 123.88,63.2 123.76,63.33 123.76,63.83 123.88,63.96 124.74,63.96 124.87,64.09 124.87,64.37 124.74,64.49 123.88,64.49 123.76,64.62 123.76,64.9 123.88,65.03 124.93,65.03 125.06,65.15 125.06,65.43 124.93,65.56 123.88,65.56 123.76,65.69 123.76,65.97 123.88,66.09 124.62,66.09 124.74,66.22 124.74,66.5 124.62,66.63 123.88,66.63 123.76,66.75 123.76,67.55 124.1,67.89 124.1,74 116.45,81.65 116.45,93.94
  BOTTOM w0.076: v1(115.67,100.32) 115.24,100.75 115.24,101.08 114.83,101.49 114.83,103.03 114.9,103.19 114.9,103.32 114.83,103.48 114.83,103.69 114.85,103.74 114.85,103.74 114.89,103.83 114.9,103.84 114.9,104.68 114.7,104.88 UC1.AU27
  BOTTOM w0.102: v1(125.12,61.5) 124.85,61.77 JDIMM2.16
DDR_B_D14: length 56.7
  IN1 w0.084: v1(115.67,100.97) 113.98,99.29 113.98,95.61 113.79,95.42 113.79,93.94
  IN1 w0.127: 113.79,93.94 113.79,78.62 114,78.41 114,78.23 113.79,78.02 113.79,77.72 114,77.51 114.18,77.51 114.4,77.73 114.58,77.73 114.76,77.54 114.76,77.36 113.9,76.5 113.9,76.32 114.09,76.13 114.27,76.13 115.15,77.01 115.33,77.01 115.51,76.82 115.51,76.64 114.62,75.74 114.62,75.56 114.8,75.37 114.98,75.37 115.9,76.29 116.08,76.29 116.27,76.1 116.27,75.92 115.35,75 115.35,74.82 115.54,74.63 115.72,74.63 116.66,75.57 116.84,75.57 117,75.41 117,75.23 116.54,74.77 116.54,74.59 116.74,74.4 116.92,74.4 117.38,74.85 117.56,74.85 118.6,73.81 118.6,73.61 118.43,73.44 118.43,72.91 119.38,71.96 119.66,71.96 119.96,72.26 120.15,72.26 121.23,71.18 121.23,68.08 121.1,67.96 v1(120.74,67.96)
  BOTTOM w0.076: v1(115.67,100.97) 114.99,101.65 114.99,103 115.04,103.1 115.07,103.16 115.07,103.36 115.04,103.41 115,103.5 114.99,103.52 114.99,103.65 115.04,103.75 115.28,104 UC1.AV25
  BOTTOM w0.102: v1(120.74,67.96) 122.15,69.37 JDIMM2.7
DDR_B_D15: length 58.2
  IN1 w0.084: 116.1,93.94 116.1,94.44 115.61,94.93 115.61,95.71 v1(115.67,95.77)
  IN1 w0.127: 116.1,93.94 116.1,81.5 116.54,81.06 116.54,80.84 116.07,80.37 116.07,80.19 116.26,80 116.44,80 116.91,80.47 117.13,80.47 123.74,73.85 123.74,68.04 123.4,67.7 123.4,62.98 123.53,62.86 124.58,62.86 124.71,62.73 124.71,62.35 124.58,62.22 123.92,62.22 123.79,62.09 123.79,61.81 123.92,61.69 124.58,61.69 124.71,61.56 124.71,61.16 124.58,61.03 124.23,61.03 124.11,60.91 124.11,60.53 124.23,60.4 124.7,60.4 v1(125.12,59.98)
  BOTTOM w0.076: UC1.AU25 115.67,104.5 115.67,103.19 115.72,103.09 115.74,103.03 115.74,102.74 115.6,102.6 115.49,102.49 115.49,102.16 115.72,101.93 115.73,101.93 116.39,101.27 116.39,96.5 v1(115.67,95.77)
  BOTTOM w0.102: JDIMM2.18 125.45,61.85 125.53,61.77 125.53,60.38 v1(125.12,59.98)
DDR_B_D16: length 89.4
  IN3 w0.084: v1(112.54,107.67) 111.99,107.12 111.99,105.44 112.15,105.29 112.15,103.31 114.89,100.57 114.89,95.49 115.53,94.84 115.78,94.59 116.33,94.59 116.92,94 116.92,93.94
  IN3 w0.127: v1(167.76,66.71) 167.46,66.71 167.34,66.58 167.34,66.18 167.21,66.05 166.93,66.05 166.8,66.18 166.8,75.44 156.75,85.49 153.17,85.49 152.07,86.59 151.25,86.59 150.34,87.5 123.51,87.5 118.46,92.56 118.11,92.56 117.55,93.12 116.92,93.75 116.92,93.94
  BOTTOM w0.076: UC1.AM29 112.86,107.99 v1(112.54,107.67)
  BOTTOM w0.102: v1(167.76,66.71) 166.25,65.2 JDIMM2.146
DDR_B_D17: length 90.9
  IN3 w0.084: v1(112.54,108.97) 111.82,108.25 111.82,105.35 111.97,105.2 111.97,103.24 114.7,100.52 114.7,95.4 115.41,94.69 115.68,94.42 116.12,94.42 116.3,94.24
  IN3 w0.127: 116.3,94.24 116.56,93.98 116.56,93.6 117.96,92.19 118.31,92.19 123.36,87.14 150.19,87.14 151.1,86.23 151.92,86.23 153.02,85.13 156.6,85.13 166.44,75.29 166.44,64.72 166.57,64.59 167.63,64.59 167.76,64.72 v1(167.76,65.18)
  BOTTOM w0.076: UC1.AK29 112.86,109.3 v1(112.54,108.97)
  BOTTOM w0.102: v1(167.76,65.18) 167.37,65.18 166.85,64.66 JDIMM2.148
DDR_B_D18: length 89.6
  IN3 w0.084: v1(113.48,108.32) 113.95,107.85 113.95,107.23 114.04,107.14 114.04,105.34 116.79,102.6 116.79,96.2 117.91,95.08 118.09,95.08 118.43,94.75 119.79,94.75 120.55,93.98 121.29,93.98 121.66,93.61
  IN3 w0.127: 121.66,93.61 124.29,90.98 125.93,90.98 126.45,90.47 154.57,90.47 155.48,89.56 157.17,89.56 170.78,75.95 170.78,67.14 v1(170.34,66.71)
  BOTTOM w0.076: v1(113.48,108.32) 113.8,108.64 UC1.AL28
  BOTTOM w0.102: v1(170.34,66.71) 170.78,66.26 170.78,64.72 170.45,64.39 JDIMM2.160
DDR_B_D19: length 90.3
  IN3 w0.084: 122.29,93.61 121.75,94.16 120.63,94.16 119.86,94.92 118.5,94.92 118.17,95.25 117.98,95.25 116.96,96.27 116.96,102.81 114.82,104.95 114.82,108.45 v1(114.31,108.96)
  IN3 w0.127: v1(170.34,65.18) 170.87,65.71 170.87,66.72 171.14,66.99 171.14,76.1 157.32,89.92 155.63,89.92 154.72,90.83 126.6,90.83 126.08,91.35 124.56,91.35 122.29,93.61
  BOTTOM w0.076: UC1.AK28 113.98,109.3 v1(114.31,108.96)
  BOTTOM w0.102: JDIMM2.158 169.85,64.69 v1(170.34,65.18)
DDR_B_D20: length 87.1
  IN3 w0.084: v1(112.54,105.72) 112.54,103.41 115.27,100.68 115.27,95.61 115.8,95.07 115.94,94.94 116.69,94.94 117.52,94.1 117.67,94.1 117.83,93.94
  IN3 w0.127: 117.83,93.94 118.49,93.28 118.75,93.28 123.81,88.22 150.64,88.22 151.55,87.31 154.99,87.31 155.11,87.19 155.11,86.34 155.24,86.22 155.5,86.22 155.63,86.34 155.63,87.12 155.75,87.25 156.01,87.25 156.14,87.12 156.14,86.34 156.28,86.21 157.05,86.21 167.52,75.74 167.52,72.46 167.65,72.33 168.19,72.33 168.32,72.21 168.32,71.94 168.19,71.82 167.65,71.82 167.52,71.69 167.52,71.43 167.65,71.3 168.27,71.3 168.4,71.17 168.4,70.91 168.27,70.79 167.65,70.79 167.52,70.66 167.52,70.4 167.65,70.27 168.27,70.27 168.4,70.14 168.4,69.61 168.27,69.48 168.03,69.48 167.76,69.75 v1(167.76,69.75)
  BOTTOM w0.089: v1(112.54,105.72) 112.79,105.72 112.92,105.85 UC1.AR29
  BOTTOM w0.102: JDIMM2.149 167.15,70.13 167.52,69.75 v1(167.76,69.75)
DDR_B_D21: length 88.8
  IN3 w0.084: 117,94.25 116.5,94.76 115.87,94.76 115.08,95.55 115.08,100.63 112.35,103.35 112.35,105.33 112.17,105.51 112.17,106.94 112.24,107.02 v1(112.54,107.02)
  IN3 w0.127: v1(167.76,68.23) 167.29,68.23 167.17,68.36 167.17,75.59 156.9,85.85 154.87,85.85 154.75,85.98 154.75,86.83 154.62,86.96 154.36,86.96 154.23,86.83 154.23,85.98 154.1,85.85 153.84,85.85 153.72,85.98 153.72,86.82 153.58,86.96 153.33,86.96 153.2,86.82 153.2,86.49 153.07,86.36 152.81,86.36 152.68,86.49 152.68,86.82 152.55,86.96 151.4,86.96 150.49,87.87 123.66,87.87 118.61,92.92 118.34,92.92 117,94.25
  BOTTOM w0.076: UC1.AN29 112.86,107.34 v1(112.54,107.02)
  BOTTOM w0.102: JDIMM2.147 166.55,69.44 v1(167.76,68.23)
DDR_B_D22: length 87.3
  IN3 w0.084: 120.64,93.61 120.44,93.61 119.65,94.4 118.28,94.4 117.95,94.73 117.77,94.73 116.39,96.11 116.39,102.34 113.48,105.26 v1(113.48,105.72)
  IN3 w0.127: 120.64,93.61 121.69,92.56 124.51,89.74 151.99,89.74 152.13,89.61 152.13,88.95 152.25,88.83 156.86,88.83 169.04,76.66 169.04,74.5 169.17,74.38 169.79,74.38 169.92,74.25 169.92,73.99 169.79,73.86 169.32,73.86 169.19,73.73 169.19,73.47 169.32,73.35 169.79,73.35 169.92,73.22 169.92,68.87 169.65,68.6 169.65,68.21 169.77,68.08 170.19,68.08 v1(170.34,68.23)
  BOTTOM w0.089: UC1.AR28 113.66,106.04 113.48,105.86 v1(113.48,105.72)
  BOTTOM w0.102: v1(170.34,68.23) 169.55,69.02 JDIMM2.157
DDR_B_D23: length 88
  IN3 w0.084: v1(113.48,106.37) 113.76,106.37 113.87,106.26 113.87,105.2 116.56,102.51 116.56,96.18 117.84,94.91 118.02,94.91 118.35,94.57 119.72,94.57 120.48,93.81 120.95,93.81 121.15,93.61
  IN3 w0.127: 121.15,93.61 124.14,90.62 125.21,90.62 125.34,90.49 125.34,90.23 125.47,90.11 152.36,90.11 152.49,89.98 152.49,89.32 152.61,89.19 152.87,89.19 153,89.32 153,89.98 153.13,90.11 153.39,90.11 153.52,89.98 153.52,89.32 153.64,89.19 153.9,89.19 154.03,89.32 154.03,89.98 154.16,90.11 154.42,90.11 154.55,89.98 154.55,89.32 154.67,89.19 157.01,89.19 169.4,76.81 169.4,75.9 169.53,75.77 170.29,75.77 170.41,75.64 170.41,75.38 170.29,75.26 169.53,75.26 169.4,75.13 169.4,74.86 169.52,74.74 170.21,74.74 170.34,74.61 v1(170.34,69.75)
  BOTTOM w0.076: v1(113.48,106.37) 113.48,106.52 113.65,106.69 UC1.AP28
  BOTTOM w0.102: v1(170.34,69.75) 170.15,69.94 JDIMM2.159
DDR_B_D24: length 56.6
  IN1 w0.084: v1(114.43,107.02) 114.15,107.02 114.04,106.92 114.04,103.88 115.34,102.58 115.34,102.06 115.66,101.74 115.92,101.74 116.56,101.1 116.56,96.1 117.8,94.86 117.8,93.94
  IN1 w0.127: v1(127.66,61.5) 126.29,61.5 126.17,61.63 126.17,62.03 126.29,62.16 127.03,62.16 127.16,62.28 127.16,62.56 127.03,62.69 126.29,62.69 126.17,62.82 126.17,73.83 118.5,81.5 118.5,83.78 117.8,84.48 117.8,93.94
  BOTTOM w0.076: v1(114.43,107.02) 114.76,107.34 UC1.AN26
  BOTTOM w0.102: JDIMM2.24 127.25,61.91 v1(127.66,61.5)
DDR_B_D25: length 56.2
  IN1 w0.084: v1(114.43,105.72) 114.27,105.55 114.27,104.02 115.47,102.82 115.92,102.82 116.26,102.48 116.26,101.64 116.73,101.17 116.73,96.19 118.15,94.76 118.15,93.94
  IN1 w0.127: v1(127.66,59.98) 128.16,60.47 128.16,63.46 126.52,65.1 126.52,73.98 118.85,81.65 118.85,83.91 118.15,84.61 118.15,93.94
  BOTTOM w0.089: UC1.AR26 114.76,106.04 v1(114.43,105.72)
  BOTTOM w0.102: JDIMM2.22 126.65,60.99 v1(127.66,59.98)
DDR_B_D26: length 55.1
  IN1 w0.084: v1(115.38,105.72) 115.38,105.66 117,104.04 117,103.92 116.69,103.61 116.69,103.44 116.81,103.32 116.98,103.32 117.28,103.62 117.4,103.62 117.62,103.39 117.62,103.28 117.36,103.01 117.36,102.9 117.94,102.31 117.94,96.04 119.68,94.3 119.68,93.61
  IN1 w0.127: v1(129.38,69.48) 129.38,69.25 129.25,69.12 128.68,69.12 128.55,69.25 128.55,69.48 128.43,69.61 128.17,69.61 128.04,69.73 128.04,70.04 128.17,70.17 129.37,70.17 129.51,70.31 129.51,70.58 129.39,70.7 128.17,70.7 128.04,70.82 128.04,71.1 128.17,71.23 129.37,71.23 129.51,71.37 129.51,71.65 129.39,71.76 128.17,71.76 128.04,71.89 128.04,72.17 128.17,72.3 129.37,72.3 129.51,72.44 129.51,73.17 129.38,73.3 128.23,73.3 128.1,73.43 128.1,74.58 120.38,82.31 120.38,90.27 119.68,90.97 119.68,93.61
  BOTTOM w0.076: UC1.AR25 115.71,106.04 v1(115.38,105.72)
  BOTTOM w0.102: JDIMM2.33 129.95,69.93 129.51,69.48 v1(129.38,69.48)
DDR_B_D27: length 55.8
  IN1 w0.084: 120.04,93.61 120.04,94.23 118.12,96.15 118.12,102.39 117.68,102.82 117.68,103.09 117.82,103.23 117.82,103.46 115.77,105.51 115.77,106.24 115.64,106.37 v1(115.38,106.37)
  IN1 w0.127: 120.04,93.61 120.04,91.1 120.74,90.4 120.74,83.39 120.95,83.18 120.95,83.09 120.72,82.86 120.72,82.68 121,82.4 121.18,82.4 121.46,82.68 121.64,82.68 121.84,82.48 121.84,82.3 121.45,81.92 121.45,81.77 121.68,81.54 121.83,81.54 122.21,81.92 122.39,81.92 122.59,81.73 122.59,81.55 122.21,81.16 122.21,81.01 122.44,80.79 122.58,80.79 122.99,81.19 123.17,81.19 123.37,81 123.37,80.82 122.96,80.41 122.96,80.23 123.16,80.03 123.34,80.03 123.68,80.37 123.86,80.37 124.06,80.18 124.06,80 123.72,79.65 123.72,79.47 128.67,74.52 128.67,74.34 128.45,74.11 128.45,73.94 128.64,73.74 128.82,73.74 129.05,73.96 129.23,73.96 129.86,73.33 129.86,67.89 129.73,67.77 129.51,67.77 129.38,67.89 v1(129.38,67.96)
  BOTTOM w0.076: v1(115.38,106.37) 115.71,106.69 UC1.AP25
  BOTTOM w0.102: JDIMM2.35 130.55,69.13 v1(129.38,67.96)
DDR_B_D28: length 58.1
  IN1 w0.084: 117.09,93.94 117.09,94.82 116.83,95.07 116.83,95.34 116.21,95.96 116.21,100.96 115.78,101.39 115.52,101.39 114.99,101.92 114.99,102.34 114.86,102.47 113.04,102.47 112.91,102.6 112.91,108.86 113.04,108.99 113.85,108.99 113.93,109.07 113.93,109.39 113.85,109.48 113.02,109.48 112.9,109.6 112.9,110.01 113.02,110.13 115.21,110.13 115.33,110.01 115.33,109.79 115.21,109.66 v1(115.2,109.66)
  IN1 w0.127: 117.09,93.94 117.09,81.91 124.73,74.26 124.73,74.06 124.86,73.93 125.04,73.93 125.16,73.8 125.16,73.53 125.04,73.4 124.87,73.4 124.74,73.27 124.74,72.59 124.87,72.46 125.34,72.46 125.47,72.34 125.47,72.06 125.34,71.93 124.87,71.93 124.74,71.8 124.74,71.56 124.87,71.44 125.34,71.44 125.47,71.31 125.47,71.03 125.34,70.9 124.87,70.9 124.74,70.77 124.74,69.35 124.87,69.23 125.18,69.23 125.31,69.35 v1(125.31,69.48)
  BOTTOM w0.076: v1(115.2,109.66) 114.84,109.3 UC1.AK26
  BOTTOM w0.102: JDIMM2.21 126.35,70.52 v1(125.31,69.48)
DDR_B_D29: length 58
  IN1 w0.084: 117.44,93.94 117.44,94.97 116.38,96.03 116.38,101.03 115.85,101.56 115.59,101.56 115.16,102 115.16,102.52 115.03,102.64 114.58,102.64 114.46,102.77 114.46,103.01 114.33,103.13 113.76,103.13 113.63,103.01 113.63,102.77 113.55,102.69 113.25,102.69 113.12,102.82 113.12,103.47 113.25,103.6 113.79,103.6 113.87,103.68 113.87,104.67 113.79,104.75 113.21,104.75 113.08,104.88 113.08,105.12 113.21,105.24 113.79,105.24 113.87,105.33 113.87,107.82 114,107.95 114.27,107.95 114.39,107.82 v1(114.39,107.63)
  IN1 w0.127: 117.44,93.94 117.44,83.99 117.57,83.86 117.93,83.86 118.06,83.73 118.06,83.47 117.93,83.34 117.63,83.34 117.5,83.21 117.5,82.98 117.63,82.86 117.92,82.86 118.05,82.73 118.05,82.46 117.92,82.34 117.71,82.34 117.58,82.21 117.58,81.92 117.76,81.74 118.03,81.74 118.15,81.61 118.15,81.36 125.81,73.7 125.81,70.72 125.65,70.56 125.25,70.56 125.12,70.43 125.12,70.05 125.25,69.92 125.6,69.92 125.75,69.77 125.75,67.78 125.6,67.64 125.43,67.64 125.31,67.76 v1(125.31,67.96)
  BOTTOM w0.076: v1(114.39,107.63) 114.76,107.99 UC1.AM26
  BOTTOM w0.102: v1(125.31,67.96) 126.95,69.6 JDIMM2.23
DDR_B_D30: length 58.2
  IN1 w0.084: 120.75,93.61 120.75,94.08 118.47,96.37 118.47,103.37 118.02,103.82 118.02,104.36 116.73,105.64 116.73,107.37 115.94,108.16 115.94,108.36 v1(115.33,108.97)
  IN1 w0.127: v1(130.2,61.5) 131.41,61.5 131.54,61.63 131.54,61.88 131.41,62.01 130.74,62.01 130.62,62.13 130.62,73.58 124.76,79.44 124.76,80.58 121.45,83.89 121.45,90.66 120.75,91.36 120.75,93.61
  BOTTOM w0.076: v1(115.33,108.97) 115.66,109.3 UC1.AK25
  BOTTOM w0.102: JDIMM2.34 130.25,61.54 v1(130.2,61.5)
DDR_B_D31: length 58.9
  IN1 w0.084: v1(115.42,108.32) 115.94,107.79 115.94,105.59 118.29,103.24 118.29,96.27 120.39,94.16 120.39,93.61
  IN1 w0.127: 120.39,93.61 120.39,91.23 121.09,90.53 121.09,83.76 124.4,80.45 124.4,79.29 130.24,73.45 130.24,63.94 129.79,63.49 129.79,60.39 v1(130.2,59.98)
  BOTTOM w0.076: UC1.AL25 115.74,108.64 v1(115.42,108.32)
  BOTTOM w0.102: JDIMM2.36 130.85,60.62 v1(130.2,59.98)
DDR_B_D32: length 85.6
  IN3 w0.084: 126.16,94.64 125.95,94.85 120.91,94.85 120.08,95.67 118.82,95.67 118.33,96.17 118.33,99.05 117.95,99.43 v1(117.57,99.43)
  IN3 w0.127: 126.16,94.64 128.23,92.56 131.96,92.56 132.09,92.69 132.09,92.86 132.22,92.98 137.67,92.98 137.79,92.86 137.79,92.69 137.92,92.56 155.44,92.56 156.35,91.65 158.32,91.65 173.29,76.68 173.29,73.42 173.16,73.29 173,73.29 172.87,73.16 172.87,72.65 173,72.53 173.13,72.53 173.25,72.4 173.25,65.81 v1(172.63,65.18)
  BOTTOM w0.076: v1(117.57,99.43) 116.89,100.12 116.89,101.71 116.65,101.95 116.65,102.66 116.64,102.68 UC1.AY23
  BOTTOM w0.102: JDIMM2.166 172.25,64.81 v1(172.63,65.18)
DDR_B_D33: length 86.5
  IN3 w0.084: 125.84,94.45 125.61,94.68 120.84,94.68 120.08,95.44 118.71,95.44 118.16,95.99 118.16,97.36 117.82,97.7 v1(117.57,97.7)
  IN3 w0.127: v1(172.63,69.75) 172.51,69.87 172.51,70.49 172.64,70.62 172.76,70.62 172.89,70.75 172.89,71.01 172.76,71.14 172.64,71.14 172.51,71.27 172.51,71.52 172.64,71.65 172.76,71.65 172.89,71.78 172.89,72.04 172.76,72.17 172.64,72.17 172.51,72.3 172.51,73.65 172.64,73.78 172.79,73.78 172.93,73.91 172.93,74.16 172.79,74.3 172.64,74.3 172.51,74.43 172.51,74.68 172.64,74.81 172.79,74.81 172.93,74.95 172.93,75.19 172.79,75.33 172.64,75.33 172.51,75.46 172.51,76.95 158.17,91.29 156.2,91.29 155.29,92.2 137.36,92.2 137.22,92.34 137.22,92.49 137.09,92.62 136.84,92.62 136.71,92.49 136.71,92.34 136.57,92.2 136.33,92.2 136.19,92.34 136.19,92.49 136.06,92.62 135.81,92.62 135.68,92.49 135.68,92.34 135.54,92.2 135.29,92.2 135.16,92.34 135.16,92.49 135.03,92.62 134.78,92.62 134.64,92.49 134.64,92.34 134.51,92.2 134.26,92.2 134.13,92.34 134.13,92.49 133.99,92.62 133.75,92.62 133.61,92.49 133.61,92.34 133.48,92.2 133.23,92.2 133.1,92.34 133.1,92.49 132.96,92.62 132.72,92.62 132.58,92.49 132.58,92.34 132.45,92.2 128.08,92.2 127.57,92.71 127.38,92.71 127.11,92.44 126.93,92.44 126.74,92.63 126.74,92.8 127.02,93.08 127.02,93.27 126.84,93.44 126.65,93.44 126.4,93.19 126.22,93.19 126.04,93.38 126.04,93.56 126.29,93.81 126.29,94 125.84,94.45
  BOTTOM w0.076: UC1.AW23 116.64,103.38 116.44,103.18 116.34,103 116.34,102.73 116.48,102.6 116.48,101.88 116.72,101.64 116.72,98.55 v1(117.57,97.7)
  BOTTOM w0.102: v1(172.63,69.75) 171.95,70.43 JDIMM2.165
DDR_B_D34: length 86.2
  IN3 w0.084: v1(119.17,97.07) 119.67,97.07 121.2,95.54 127.32,95.54 127.85,95.01 129.82,95.01 130.22,95.4 130.88,95.4
  IN3 w0.127: 130.88,95.4 139.39,95.4 140.26,94.52 157.13,94.52 158.12,93.53 159.1,93.53 175.17,77.46 175.17,70.48 175.55,70.1 175.55,67.49 v1(176.34,66.71)
  BOTTOM w0.076: UC1.AY21 118.11,102.81 118.11,101.62 118.4,101.33 118.4,97.84 v1(119.17,97.07)
  BOTTOM w0.102: v1(176.34,66.71) 174.65,65.02 JDIMM2.174
DDR_B_D35: length 86.7
  IN3 w0.084: v1(119.17,97.72) 120.38,97.72 120.49,97.61 120.49,96.5 121.27,95.71 122.08,95.71 122.12,95.76 126.96,95.76 127,95.81 130.41,95.81 130.46,95.76 131.24,95.76
  IN3 w0.127: v1(176.34,68.23) 176.04,68.23 175.91,68.36 175.91,70.25 175.53,70.63 175.53,73.57 175.66,73.7 175.77,73.7 175.89,73.83 175.89,74.09 175.77,74.22 175.66,74.22 175.53,74.35 175.53,74.6 175.66,74.73 175.77,74.73 175.89,74.86 175.89,75.12 175.77,75.25 175.66,75.25 175.53,75.38 175.53,75.63 175.66,75.76 175.77,75.76 175.89,75.89 175.89,76.15 175.77,76.28 175.66,76.28 175.53,76.41 175.53,77.68 158.32,94.89 140.41,94.89 139.54,95.76 131.24,95.76
  BOTTOM w0.076: UC1.AW21 117.99,103.35 118.28,103.05 118.28,101.69 118.57,101.39 118.57,98.32 v1(119.17,97.72)
  BOTTOM w0.102: v1(176.34,68.23) 174.95,69.62 JDIMM2.175
DDR_B_D36: length 87.5
  IN3 w0.084: v1(117.57,97.07) 117.98,96.66 117.98,95.92 118.64,95.27 120.01,95.27 120.77,94.5 124.22,94.5 124.3,94.42
  IN3 w0.127: 124.3,94.42 124.43,94.29 124.43,92.9 124.56,92.77 124.82,92.77 124.95,92.9 124.95,93.99 125.07,94.12 125.33,94.12 125.46,93.99 125.46,92.48 125.59,92.35 126.5,92.35 127.02,91.84 155.14,91.84 156.05,90.93 158.02,90.93 172.15,76.8 172.15,68.34 172.25,68.23 v1(172.63,68.23)
  BOTTOM w0.076: UC1.AV23 116.25,103.85 116.25,103.19 116.2,103.08 116.18,103.04 116.18,102.66 116.32,102.53 116.32,101.81 116.56,101.57 116.56,98.09 v1(117.57,97.07)
  BOTTOM w0.102: v1(172.63,68.23) 171.35,69.5 JDIMM2.163
DDR_B_D37: length 88.4
  IN3 w0.084: 122.88,93.94 122.48,94.33 120.7,94.33 119.93,95.09 118.57,95.09 118.21,95.45 118.03,95.45 117.14,96.34 117.14,98.44 v1(117.57,98.87)
  IN3 w0.127: v1(172.63,66.71) 172.63,66.56 172.37,66.31 171.91,66.31 171.78,66.43 171.78,76.65 157.87,90.56 155.9,90.56 154.99,91.47 126.87,91.47 126.35,91.99 124.82,91.99 123.96,92.85 123.96,93.37 123.79,93.55 123.27,93.55 122.88,93.94
  BOTTOM w0.076: UC1.AU23 117.4,104.88 117.6,104.68 117.6,104.44 117.59,104.42 117.59,104.04 117.6,104.03 117.6,103.84 117.6,103.83 117.55,103.74 117.55,103.74 117.53,103.69 117.53,103.48 117.6,103.32 117.6,103.19 117.55,103.09 117.53,103.03 117.53,102.74 117.76,102.51 117.76,101.5 118.07,101.2 118.07,99.37 v1(117.57,98.87)
  BOTTOM w0.102: v1(172.63,66.71) 171.65,65.73 JDIMM2.164
DDR_B_D38: length 87.4
  IN3 w0.084: v1(119.17,96.42) 120.07,96.42 121.13,95.37 127.1,95.37 127.97,94.5 129.99,94.5
  IN3 w0.127: 129.99,94.5 139.78,94.5 140.11,94.17 156.98,94.17 157.98,93.17 158.95,93.17 174.81,77.31 174.81,70.34 175.19,69.95 175.19,66.32 v1(176.34,65.18)
  BOTTOM w0.076: v1(119.17,96.42) 118.72,96.87 118.72,96.89 118.24,97.37 118.24,100.9 118.23,100.91 118.23,101.26 117.94,101.56 117.94,102.57 117.69,102.81 117.69,103 117.74,103.1 117.77,103.16 117.77,103.36 117.74,103.41 117.7,103.5 117.69,103.52 117.69,103.65 117.72,103.7 117.74,103.75 117.88,103.89 UC1.AV21
  BOTTOM w0.102: JDIMM2.176 175.25,64.36 176.07,65.18 v1(176.34,65.18)
DDR_B_D39: length 87.9
  IN3 w0.084: 131.57,96.13 130.95,96.13 130.1,96.98 121.88,96.98 121.69,97.17 121.69,98.29 121.31,98.67 119.47,98.67 v1(119.17,98.37)
  IN3 w0.127: 131.57,96.13 140.23,96.13 140.37,95.99 140.37,95.44 140.5,95.32 140.76,95.32 140.88,95.44 140.88,95.99 141.02,96.13 141.27,96.13 141.4,95.99 141.4,95.38 141.53,95.25 141.79,95.25 141.92,95.38 141.92,95.99 142.05,96.13 142.3,96.13 142.43,95.99 142.43,95.38 142.56,95.25 142.82,95.25 142.95,95.38 142.95,95.77 143.07,95.9 143.34,95.9 143.46,95.77 143.46,95.38 143.59,95.25 158.47,95.25 176.26,77.47 176.26,73.45 175.89,73.08 175.89,70.94 176.34,70.5 v1(176.34,69.75)
  BOTTOM w0.076: UC1.AU21 117.88,104.65 118.17,104.35 118.17,104.11 118.15,104.09 118.15,103.83 118.28,103.7 118.28,103.29 118.44,103.12 118.44,101.76 118.74,101.46 118.74,98.81 v1(119.17,98.37)
  BOTTOM w0.102: JDIMM2.177 175.55,70.41 176.21,69.75 v1(176.34,69.75)
DDR_B_D40: length 53.7
  IN1 w0.084: 121.41,93.61 121.41,94.02 119.54,95.88 119.54,99.58 119.45,99.67 v1(119.17,99.67)
  IN1 w0.127: 121.41,93.61 121.41,91.6 122.08,90.93 122.08,84.15 125.39,80.84 125.39,80.36 125.59,80.16 125.77,80.16 125.98,80.38 126.18,80.38 126.34,80.21 126.34,80.01 125.8,79.47 125.8,79.29 126,79.09 126.18,79.09 126.72,79.63 126.9,79.63 127.1,79.43 127.1,79.25 126.56,78.72 126.56,78.54 126.76,78.34 126.94,78.34 127.47,78.88 127.65,78.88 127.85,78.68 127.85,78.5 127.31,77.96 127.31,77.78 127.51,77.58 127.69,77.58 128.23,78.12 128.41,78.12 128.6,77.92 128.6,77.74 128.07,77.21 128.07,77.03 128.26,76.83 128.44,76.83 128.98,77.37 129.16,77.37 129.36,77.17 129.36,76.99 128.82,76.45 128.82,76.27 131.3,73.8 131.3,67.8 131.42,67.68 131.94,67.68 132.07,67.8 v1(132.07,68.04)
  BOTTOM w0.076: UC1.AY19 118.94,102.81 118.94,101.96 119.73,101.17 119.73,100.23 v1(119.17,99.67)
  BOTTOM w0.102: v1(132.07,68.04) 131.66,68.45 131.66,70.16 131.75,70.24 JDIMM2.39
DDR_B_D41: length 54.5
  IN1 w0.084: v1(119.17,100.32) 119.17,100.5 119.3,100.62 119.78,100.62 119.91,100.5 119.91,99.87 119.72,99.68 119.72,95.95 120.92,94.75 121.03,94.75 121.18,94.9 121.3,94.9 121.52,94.67 121.52,94.55 121.38,94.41 121.38,94.29 121.76,93.91 121.76,93.61
  IN1 w0.127: 121.76,93.61 121.76,91.75 122.44,91.07 122.44,84.28 122.74,83.98 123.09,83.98 123.28,83.79 123.28,83.44 123.49,83.23 123.84,83.23 124.03,83.04 124.03,82.69 124.24,82.47 124.6,82.47 124.79,82.29 124.79,81.93 125,81.72 125.33,81.72 125.54,81.51 125.54,81.18 125.77,80.94 126.11,80.94 129.91,77.15 129.91,76.97 129.35,76.41 129.35,76.23 129.55,76.03 129.73,76.03 130.3,76.6 130.47,76.6 130.67,76.4 130.67,76.22 130.11,75.65 130.11,75.47 130.3,75.28 130.48,75.28 131.05,75.84 131.23,75.84 131.43,75.65 131.43,75.47 130.86,74.9 130.86,74.72 131.06,74.52 131.24,74.52 131.8,75.08 131.97,75.08 132.12,74.94 132.12,74.48 131.99,74.36 131.79,74.36 131.66,74.23 131.66,73.92 131.79,73.8 132.02,73.8 132.15,73.67 132.15,73.42 132.02,73.3 131.77,73.3 131.64,73.17 131.64,72.55 131.77,72.43 132.03,72.43 132.16,72.3 132.16,72.05 132.03,71.92 131.78,71.92 131.65,71.79 131.65,71.54 131.78,71.41 132.03,71.41 132.16,71.28 132.16,71.03 132.03,70.9 131.78,70.9 131.65,70.78 131.65,69.33 131.77,69.2 131.95,69.2 132.07,69.33 v1(132.07,69.56)
  BOTTOM w0.076: v1(119.17,100.32) 119.17,100.3 119.3,100.17 119.44,100.17 119.57,100.3 119.57,101.1 118.77,101.89 118.77,103.05 119.07,103.35 UC1.AW19
  BOTTOM w0.102: JDIMM2.41 132.35,70.43 132.48,70.31 132.56,70.31 132.68,70.19 132.68,69.99 132.55,69.86 132.12,69.86 132,69.73 132,69.64 v1(132.07,69.56)
DDR_B_D42: length 53.2
  IN1 w0.084: 125.06,93.61 125.06,94.24 121.62,97.69 121.62,100.67 121.32,100.96 v1(121.04,100.96)
  IN1 w0.127: 125.06,93.61 125.06,93.12 125.74,92.44 125.74,91.22 125.89,91.07 126.56,91.07 126.99,90.64 126.99,84.74 136.49,75.24 136.49,68.01 136.69,67.8 136.69,65.17 136.57,65.05 136.28,65.05 136.15,65.17 136.15,66.03 136.03,66.16 135.74,66.16 135.61,66.28 135.61,66.56 135.74,66.69 136.03,66.69 136.15,66.82 136.15,67.62 v1(135.73,68.04)
  BOTTOM w0.076: v1(121.04,100.96) 121.04,101.13 120.4,101.76 120.4,102.6 120.42,102.61 UC1.AY17
  BOTTOM w0.102: v1(135.73,68.04) 136.17,68.48 136.17,69.73 135.95,69.96 JDIMM2.53
DDR_B_D43: length 54.4
  IN1 w0.084: v1(121.09,96.42) 121.12,96.46 121.9,96.46 124.35,94.01 124.35,93.61
  IN1 w0.127: 124.35,93.61 124.35,92.82 125.03,92.15 125.03,89.41 125.72,88.72 125.72,87.49 126.28,86.93 126.28,84.45 134.74,75.99 134.74,74.25 135.27,73.72 135.27,65.42 135.53,65.15 135.53,63.95 135.58,63.9 135.58,60.52 v1(135.03,59.98)
  BOTTOM w0.076: v1(121.09,96.42) 121.11,96.42 121.44,96.97 121.44,101.11 120.58,101.97 120.58,102.68 120.71,102.81 120.71,103 120.68,103.07 UC1.AW17
  BOTTOM w0.102: JDIMM2.52 135.65,60.96 135.04,59.98 v1(135.03,59.98)
DDR_B_D44: length 55.1
  IN1 w0.084: 122.12,93.61 122.12,94.33 121.34,95.11 120.81,95.11 119.89,96.03 119.89,99.6 120.08,99.8 120.08,100.68 119.79,100.97 v1(119.17,100.97)
  IN1 w0.127: 122.12,93.61 122.12,91.9 122.79,91.22 122.79,84.77 132.5,75.06 132.5,66.85 132.19,66.53 132.19,60.53 v1(132.74,59.98)
  BOTTOM w0.076: UC1.AV19 119.17,104.1 118.77,103.7 118.77,103.3 118.61,103.13 118.61,101.82 119.17,101.26 v1(119.17,100.97)
  BOTTOM w0.102: v1(132.74,59.98) 133.2,60.43 133.2,61.71 132.65,62.26 JDIMM2.42
DDR_B_D45: length 55.6
  IN1 w0.084: v1(121.05,99.72) 120.25,99.72 120.1,99.58 120.1,96.06 120.84,95.32 121.68,95.32 122.47,94.53 122.47,93.61
  IN1 w0.127: v1(132.74,61.5) 133.12,61.5 133.25,61.63 133.25,62.18 133.12,62.31 132.79,62.31 132.67,62.42 132.67,62.76 132.79,62.88 133.12,62.88 133.25,63.01 133.25,63.28 133.12,63.41 132.79,63.41 132.67,63.53 132.67,63.87 132.79,63.98 133.03,63.98 133.16,64.11 133.16,64.41 132.85,64.72 132.85,75.22 123.15,84.91 123.15,91.37 122.47,92.04 122.47,93.61
  BOTTOM w0.076: UC1.AU19 119.83,104.88 120.03,104.68 120.03,103.84 120.03,103.83 119.98,103.74 119.98,103.74 119.96,103.69 119.96,103.48 120.03,103.32 120.03,103.19 119.96,103.03 119.96,102.7 120.07,102.59 120.07,101.63 120.47,101.23 120.47,100.06 120.81,99.72 v1(121.05,99.72)
  BOTTOM w0.102: JDIMM2.40 132.05,62.21 132.74,61.52 v1(132.74,61.5)
DDR_B_D46: length 54.3
  IN1 w0.084: 124.7,93.61 124.7,94.22 122.78,96.14 122.66,96.14 122.62,96.1 122.5,96.1 122.28,96.33 122.28,96.45 122.3,96.48 122.3,96.66 122.14,96.83 121.96,96.83 121.83,96.7 121.65,96.7 121.48,96.86 121.48,97.04 121.62,97.18 121.62,97.3 121.43,97.5 121.43,100.4 121.3,100.53 121.16,100.53 121.03,100.4 v1(121.03,100.35)
  IN1 w0.127: 124.7,93.61 124.7,92.97 125.38,92.29 125.38,90.71 125.51,90.58 126.51,90.58 126.63,90.45 126.63,90.2 126.51,90.07 125.5,90.07 125.37,89.94 125.37,89.69 125.5,89.56 126.51,89.56 126.63,89.44 126.63,89.18 126.51,89.06 126.2,89.06 126.08,88.93 126.08,88.67 126.2,88.55 126.51,88.55 126.63,88.42 126.63,88.17 126.51,88.04 126.2,88.04 126.08,87.91 126.08,87.66 126.2,87.53 126.51,87.53 126.63,87.4 126.63,84.59 135.08,76.15 135.08,75.49 135.21,75.36 135.73,75.36 135.86,75.24 135.86,74.98 135.73,74.85 135.21,74.85 135.08,74.73 135.08,74.47 135.21,74.35 136.01,74.35 136.13,74.22 136.13,73.97 136.01,73.84 135.79,73.84 135.66,73.71 135.66,73.46 135.79,73.33 136.01,73.33 136.13,73.2 136.13,72.53 136.01,72.4 135.74,72.4 135.61,72.27 135.61,71.99 135.74,71.86 136.02,71.86 136.15,71.74 136.15,71.46 136.02,71.33 135.74,71.33 135.61,71.2 135.61,70.93 135.74,70.8 136.02,70.8 136.15,70.67 136.15,69.68 136.03,69.56 v1(135.73,69.56)
  BOTTOM w0.076: v1(121.03,100.35) 120.63,100.75 120.63,101.3 120.24,101.7 120.24,102.65 120.13,102.77 120.13,103 120.17,103.1 120.2,103.16 120.2,103.36 120.17,103.41 120.17,103.41 120.13,103.5 120.13,103.52 120.13,103.65 120.18,103.75 120.42,104 UC1.AV17
  BOTTOM w0.102: v1(135.73,69.56) 135.03,69.56 134.9,69.69 134.9,69.92 135.03,70.05 135.22,70.05 135.35,70.18 JDIMM2.51
DDR_B_D47: length 55.3
  IN1 w0.084: 123.99,93.61 123.99,94.12 122.03,96.09 v1(121.69,96.09)
  IN1 w0.127: v1(135.03,61.5) 135.19,61.66 135.19,64.48 135.06,64.61 134.14,64.61 134.01,64.74 134.01,65.32 134.14,65.44 134.78,65.44 134.9,65.57 134.9,65.61 134.9,65.61 134.9,65.82 134.77,65.95 134.2,65.95 134.08,66.08 134.08,66.33 134.2,66.46 134.77,66.46 134.9,66.59 134.9,66.84 134.77,66.97 134.51,66.97 134.38,67.09 134.38,67.35 134.51,67.48 134.77,67.48 134.9,67.6 134.9,73.6 134.39,74.11 134.39,75.83 125.92,84.3 125.92,86.8 125.38,87.35 125.38,88.58 124.67,89.28 124.67,92 123.99,92.68 123.99,93.61
  BOTTOM w0.076: v1(121.69,96.09) 121.69,100.52 121.61,100.61 121.61,101.18 120.78,102.01 120.78,102.65 120.87,102.74 120.87,103.03 120.8,103.19 120.8,103.75 120.71,103.84 120.71,104.59 UC1.AU17
  BOTTOM w0.102: JDIMM2.50 135.05,61.52 v1(135.03,61.5)
DDR_B_D48: length 92.9
  IN3 w0.084: 131.57,99.57 130.4,99.57 130.33,99.64 127.34,99.64 126.08,98.38 125.16,98.38 124.22,99.31 124.22,100.21 119.43,105 118.71,105 118.13,105.57 v1(118.13,105.72)
  IN3 w0.127: v1(181.2,68.23) 180.26,68.23 180.13,68.36 180.13,69.46 180.27,69.59 180.65,69.59 180.78,69.72 180.78,69.98 180.65,70.11 180.27,70.11 180.13,70.25 180.13,72.39 180.26,72.52 180.71,72.52 180.84,72.65 180.84,74.46 180.71,74.59 180.26,74.59 180.13,74.72 180.13,78.92 160.56,98.49 145.33,98.49 144.44,99.38 137.89,99.38 137.7,99.57 131.57,99.57
  BOTTOM w0.076: UC1.AR21 118.46,106.04 v1(118.13,105.72)
  BOTTOM w0.102: JDIMM2.191 179.75,69.68 v1(181.2,68.23)
DDR_B_D49: length 93.7
  IN3 w0.084: v1(117.18,105.72) 117.18,104.22 118.33,103.07 118.45,103.07 118.87,103.49 118.99,103.49 119.2,103.28 119.2,103.16 118.78,102.74 118.78,102.63 119.55,101.85 121.69,101.85 122.43,101.11 122.43,98.77 123.45,97.75 131.35,97.75 131.45,97.85 131.57,97.85
  IN3 w0.127: v1(178.62,69.75) 178.61,69.76 178.61,71.62 178.49,71.75 178.19,71.75 178.06,71.88 178.06,72.14 178.19,72.26 178.49,72.26 178.61,72.39 178.61,72.65 178.49,72.78 178.19,72.78 178.06,72.91 178.06,73.49 178.19,73.62 178.49,73.62 178.61,73.75 178.61,74.01 178.49,74.13 178.19,74.13 178.06,74.26 178.06,74.52 178.19,74.65 178.49,74.65 178.61,74.78 178.61,75.04 178.49,75.17 178.19,75.17 178.06,75.29 178.06,75.55 178.19,75.68 178.49,75.68 178.61,75.81 178.61,76.07 178.49,76.2 178.19,76.2 178.06,76.32 178.06,76.58 178.19,76.71 178.49,76.71 178.61,76.84 178.61,77.1 178.49,77.23 178.19,77.23 178.06,77.35 178.06,77.62 178.19,77.74 178.34,77.74 178.47,77.87 178.47,78.13 178.34,78.26 178.19,78.26 178.06,78.39 178.06,78.54 159.63,96.98 144.7,96.98 143.82,97.85 131.57,97.85
  BOTTOM w0.076: v1(117.18,105.72) 117.51,106.04 UC1.AR22
  BOTTOM w0.102: JDIMM2.183 177.35,69.42 177.48,69.29 177.89,69.29 178.02,69.42 178.02,69.63 178.15,69.75 v1(178.62,69.75)
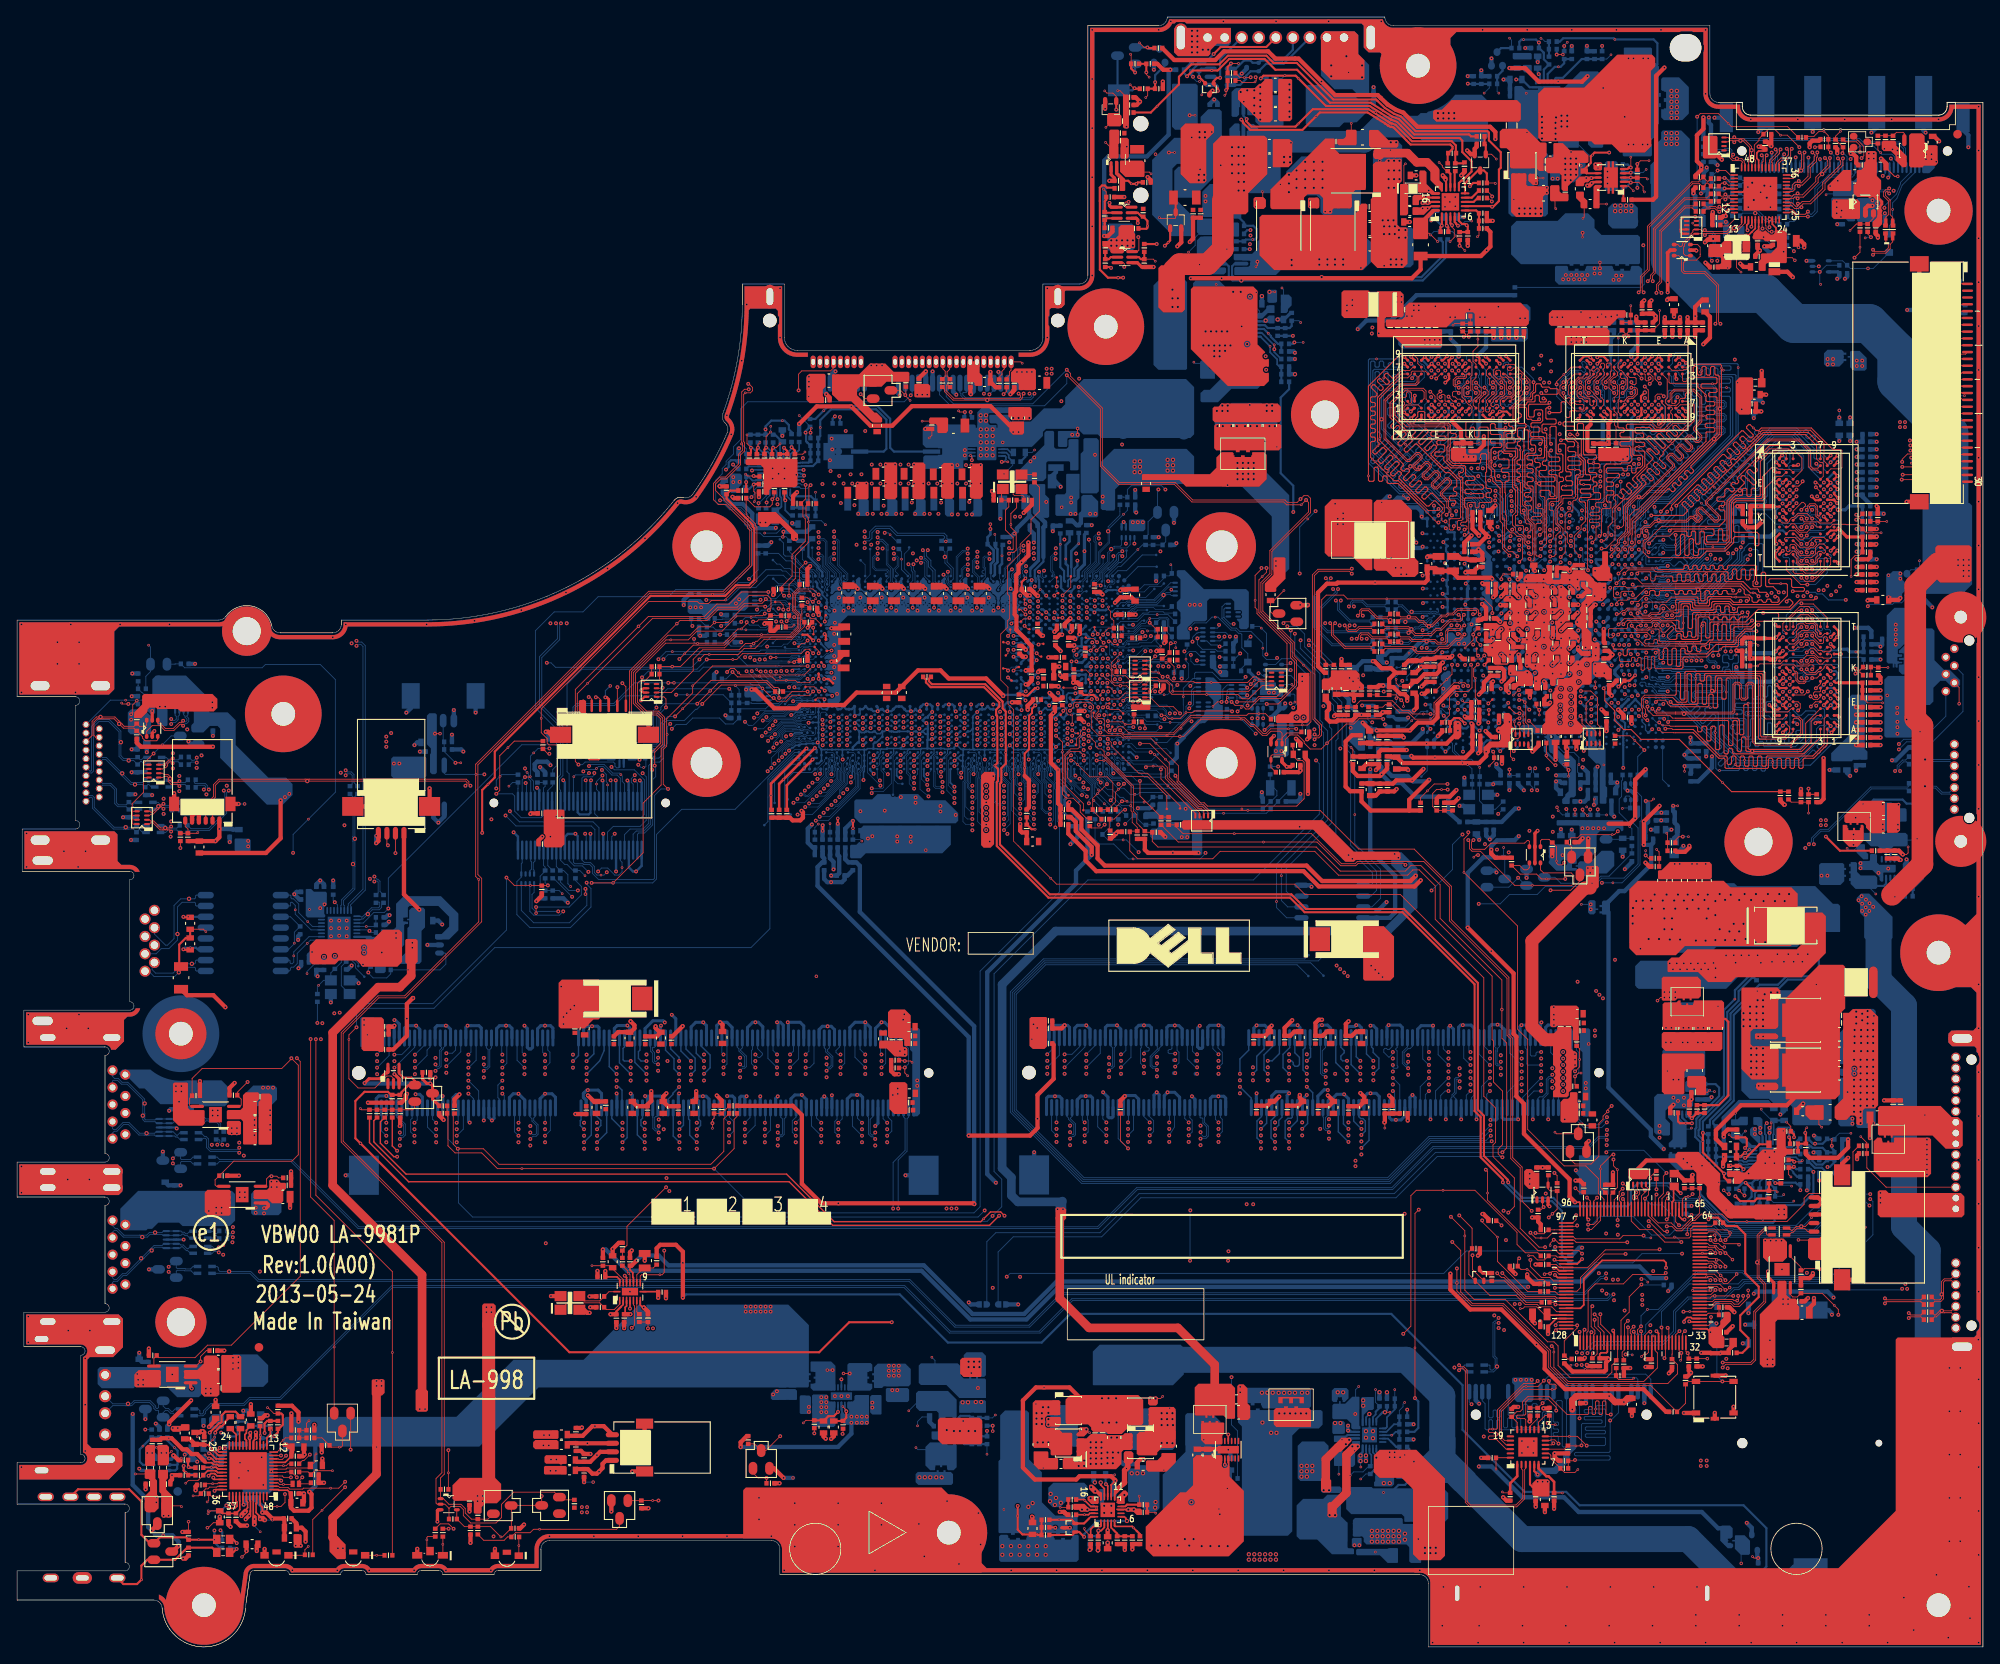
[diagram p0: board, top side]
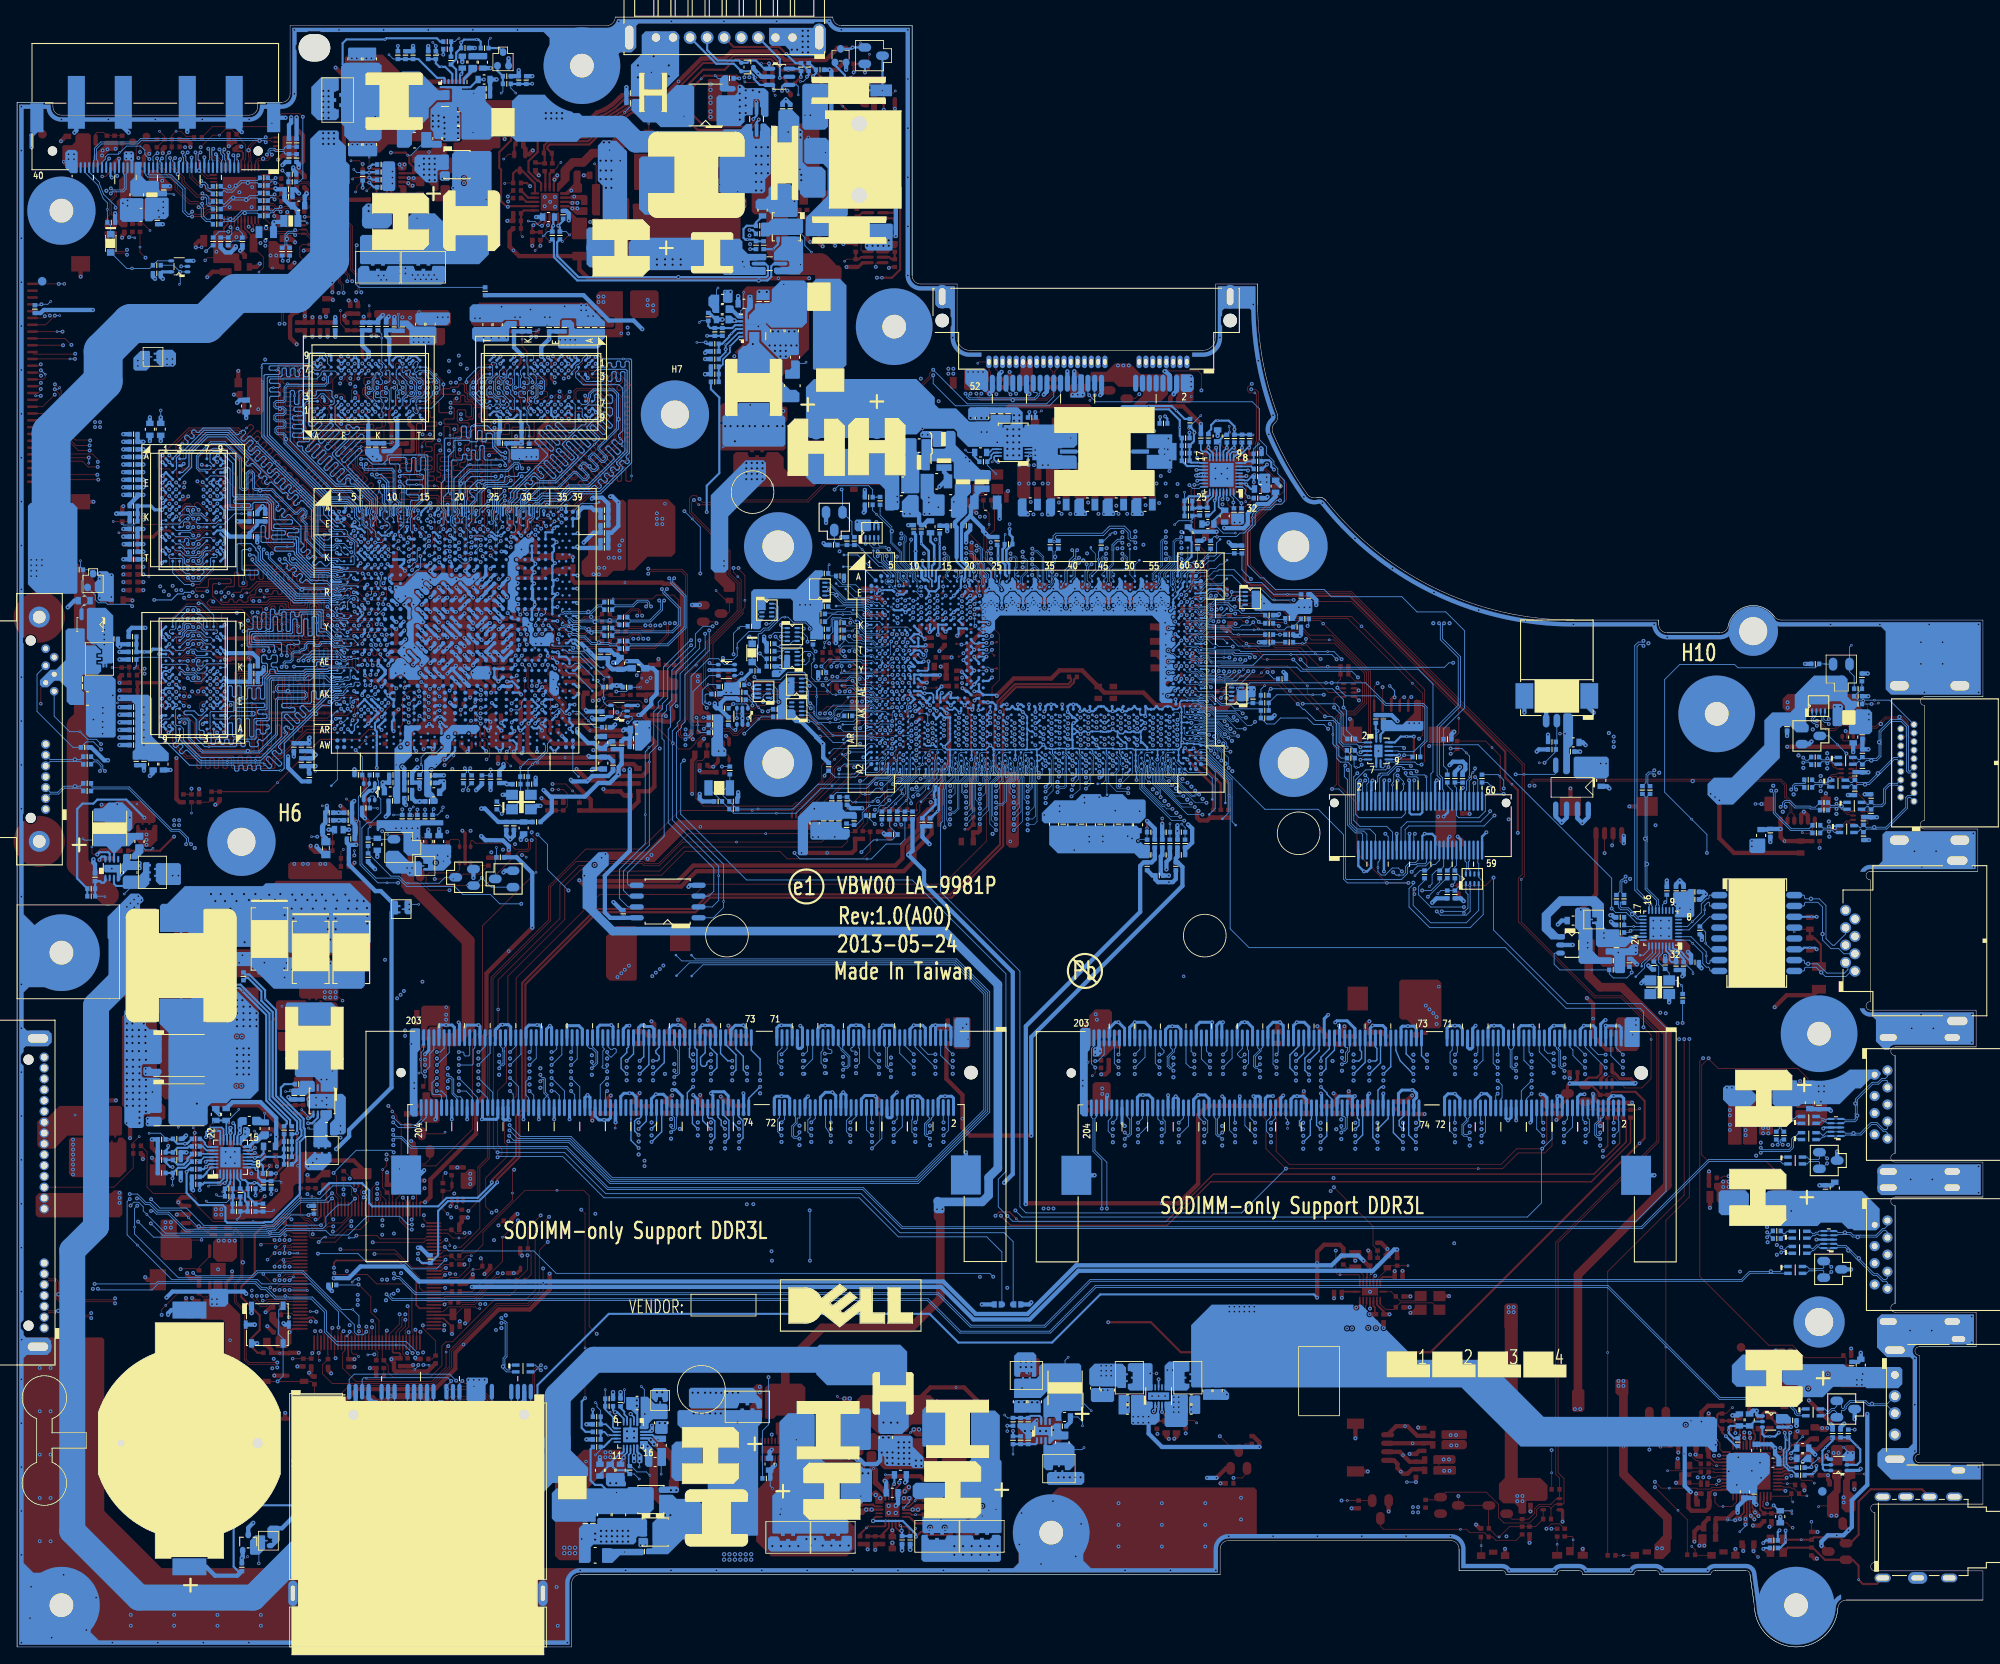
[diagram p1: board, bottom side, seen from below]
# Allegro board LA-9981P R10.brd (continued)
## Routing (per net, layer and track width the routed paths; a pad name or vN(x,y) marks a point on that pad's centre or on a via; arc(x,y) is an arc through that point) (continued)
DDR_B_D50: length 95.8
  IN3 w0.084: 131.57,100.3 126.56,100.3 124.31,102.55 123.9,102.55 123.28,101.93 122.99,101.93 119.58,105.35 118.85,105.35 118.69,105.5 118.69,108.42 118.58,108.53 118.35,108.53 v1(118.13,108.32)
  IN3 w0.127: 131.57,100.3 137.98,100.3 138.19,100.09 144.76,100.09 145.63,99.22 160.86,99.22 180.86,79.22 180.86,78.56 180.99,78.43 181.5,78.43 181.62,78.31 181.62,66.81 181.52,66.71 v1(181.2,66.71)
  BOTTOM w0.076: UC1.AL21 118.46,108.64 v1(118.13,108.32)
  BOTTOM w0.102: JDIMM2.194 180.65,64.61 180.81,64.78 181.63,64.78 181.77,64.91 181.77,66.14 v1(181.2,66.71)
DDR_B_D51: length 96.1
  IN3 w0.084: 131.57,97.13 130.43,97.13 130.24,97.32 123.39,97.32 122.08,98.63 122.08,100.97 121.54,101.51 119.41,101.51 115.95,104.97 115.95,107.16 116.46,107.67 v1(117.18,107.67)
  IN3 w0.127: v1(178.62,66.71) 178.15,66.71 178.02,66.58 178.02,66.27 177.88,66.13 177.48,66.13 177.34,66.27 177.34,78.24 159.33,96.26 144.4,96.26 143.52,97.13 131.57,97.13
  BOTTOM w0.076: v1(117.18,107.67) 117.51,107.99 UC1.AM22
  BOTTOM w0.102: v1(178.62,66.71) 177.07,65.15 177.07,65.05 176.45,64.43 JDIMM2.180
DDR_B_D52: length 95.3
  IN3 w0.084: 131.57,97.49 123.46,97.49 122.25,98.7 122.25,101.04 121.61,101.68 119.48,101.68 116.79,104.37 116.79,106.94 116.87,107.02 v1(117.18,107.02)
  IN3 w0.127: v1(178.62,68.23) 178.26,67.87 177.83,67.87 177.71,68 177.71,68.59 177.84,68.72 178.07,68.72 178.2,68.85 178.2,69.11 178.07,69.24 177.84,69.24 177.71,69.37 177.71,69.72 177.83,69.84 178.13,69.84 178.26,69.97 178.26,70.23 178.13,70.36 177.83,70.36 177.71,70.49 177.71,70.75 177.83,70.87 178.13,70.87 178.26,71 178.26,71.26 178.13,71.39 177.83,71.39 177.71,71.52 177.71,78.39 159.48,96.62 144.55,96.62 143.67,97.49 131.57,97.49
  BOTTOM w0.076: v1(117.18,107.02) 117.51,107.34 UC1.AN22
  BOTTOM w0.102: v1(178.62,68.23) 177.07,68.23 176.95,68.36 176.95,70.05 176.75,70.24 JDIMM2.181
DDR_B_D53: length 94
  IN3 w0.084: 131.57,99.94 127.27,99.94 125.89,98.55 125.23,98.55 124.4,99.38 124.4,100.28 119.51,105.17 118.78,105.17 118.51,105.44 118.51,106 v1(118.13,106.37)
  IN3 w0.127: v1(181.2,69.75) 181.2,70.48 181.07,70.61 180.62,70.61 180.5,70.74 180.5,71 180.62,71.12 181.07,71.12 181.2,71.25 181.2,71.51 181.07,71.64 180.62,71.64 180.5,71.77 180.5,72.03 180.62,72.16 181.13,72.16 181.26,72.28 181.26,74.83 181.13,74.95 180.62,74.95 180.5,75.08 180.5,75.34 180.62,75.47 181.13,75.47 181.26,75.6 181.26,75.86 181.13,75.98 180.62,75.98 180.5,76.11 180.5,76.37 180.62,76.5 181.13,76.5 181.26,76.63 181.26,76.89 181.13,77.02 180.62,77.02 180.5,77.14 180.5,77.4 180.62,77.53 180.94,77.53 181.07,77.66 181.07,77.92 180.94,78.05 180.62,78.05 180.5,78.17 180.5,79.07 160.71,98.86 145.48,98.86 144.6,99.73 138.04,99.73 137.84,99.94 131.57,99.94
  BOTTOM w0.076: UC1.AP21 118.46,106.69 v1(118.13,106.37)
  BOTTOM w0.102: v1(181.2,69.75) 180.79,69.75 180.35,70.2 JDIMM2.193
DDR_B_D54: length 96.6
  IN3 w0.084: v1(118.11,108.97) 118.11,109.29 118.23,109.42 119.41,109.42 119.53,109.29 119.53,105.63 122.45,102.72 124.39,102.72 126.45,100.66 131.57,100.66
  IN3 w0.127: v1(181.2,65.18) 181.79,65.18 181.99,65.38 181.99,78.61 161.01,99.58 145.78,99.58 144.92,100.44 138.34,100.44 138.12,100.66 131.57,100.66
  BOTTOM w0.076: v1(118.11,108.97) 118.43,109.3 UC1.AK21
  BOTTOM w0.102: v1(181.2,65.18) 180.64,65.18 180.05,64.59 JDIMM2.192
DDR_B_D55: length 96.8
  IN3 w0.084: v1(117.18,108.97) 116.91,108.97 116.79,108.85 116.79,108.24 115.78,107.23 115.78,104.9 118.92,101.75 119.34,101.34 121.47,101.34 121.91,100.9 121.91,98.55 123.31,97.15 130.17,97.15 130.55,96.77 131.57,96.77
  IN3 w0.127: 131.57,96.77 143.37,96.77 144.25,95.89 159.18,95.89 176.98,78.09 176.98,65.16 177.11,65.03 178.47,65.03 v1(178.62,65.18)
  BOTTOM w0.076: UC1.AK22 117.51,109.3 v1(117.18,108.97)
  BOTTOM w0.102: JDIMM2.182 177.05,64.45 177.79,65.18 v1(178.62,65.18)
DDR_B_D56: length 64.2
  IN1 w0.084: v1(119.09,107.02) 118.68,106.61 118.68,104.75 120.41,103.01 120.41,101.95 120.68,101.68 121.33,101.68 122.14,100.88 122.14,98.32 125.99,94.46 126.58,94.46 127.08,93.96 127.08,93.94
  IN1 w0.127: 127.08,93.94 127.11,93.92 127.11,92.39 128.36,91.13 128.36,85.27 131.07,82.56 131.25,82.56 131.65,82.96 131.83,82.96 132.03,82.77 132.03,82.59 131.63,82.19 131.63,82.01 131.83,81.81 132,81.81 132.41,82.21 132.59,82.21 132.78,82.01 132.78,81.83 132.38,81.43 132.38,81.25 132.58,81.05 132.76,81.05 133.16,81.46 133.34,81.46 133.54,81.26 133.54,81.08 133.14,80.68 133.14,80.5 133.33,80.3 133.51,80.3 133.92,80.7 134.09,80.7 134.29,80.5 134.29,80.32 133.89,79.92 133.89,79.74 134.09,79.55 134.27,79.55 134.67,79.95 134.85,79.95 135.05,79.75 135.05,79.57 134.65,79.17 134.65,78.99 134.84,78.79 135.02,78.79 135.42,79.19 135.6,79.19 135.8,78.99 135.8,78.81 135.4,78.41 135.4,78.23 135.6,78.04 135.78,78.04 136.18,78.44 136.36,78.44 136.56,78.24 136.56,78.06 136.15,77.66 136.15,77.48 136.35,77.28 136.53,77.28 136.93,77.68 137.11,77.68 137.31,77.49 137.31,77.31 136.91,76.9 136.91,76.73 137.11,76.53 137.29,76.53 137.47,76.71 137.64,76.71 137.84,76.51 137.84,76.33 137.66,76.15 137.66,75.97 137.84,75.8 137.84,68.57 138.3,68.1 v1(138.3,67.96)
  BOTTOM w0.076: UC1.AN20 119.41,107.34 v1(119.09,107.02)
  BOTTOM w0.102: v1(138.3,67.96) 138.12,67.96 137.15,68.93 JDIMM2.57
DDR_B_D57: length 62.8
  IN1 w0.084: v1(119.09,105.72) 119.09,104.58 120.59,103.08 120.59,102.18 120.92,101.85 121.41,101.85 122.31,100.95 122.31,98.63 126.26,94.68 126.91,94.68 127.45,94.13 127.45,93.94
  IN1 w0.127: 127.45,93.94 127.45,92.53 128.71,91.28 128.71,89.89 128.83,89.76 130.01,89.76 130.14,89.63 130.14,89.35 130.01,89.23 128.83,89.23 128.71,89.1 128.71,88.82 128.83,88.69 130.14,88.69 130.27,88.57 130.27,88.29 130.14,88.16 128.83,88.16 128.71,88.03 128.71,87.75 128.83,87.63 130.14,87.63 130.27,87.5 130.27,87.22 130.14,87.09 128.83,87.09 128.71,86.97 128.71,86.69 128.83,86.56 130.08,86.56 130.2,86.43 130.2,86.15 130.08,86.03 128.83,86.03 128.71,85.9 128.71,85.41 129.31,84.81 129.51,84.61 129.69,84.61 130.09,85.01 130.27,85.01 130.47,84.81 130.47,84.63 130.07,84.23 130.07,84.05 130.27,83.85 130.44,83.85 130.85,84.26 131.03,84.26 131.22,84.06 131.22,83.88 130.82,83.48 130.82,83.3 131.02,83.1 131.2,83.1 131.6,83.5 131.78,83.5 138.19,77.09 138.19,72.31 138.32,72.18 138.33,72.18 138.46,72.05 138.46,71.77 138.33,71.65 138.31,71.65 138.18,71.52 138.18,71.24 138.31,71.11 138.33,71.11 138.46,70.99 138.46,70.64 138.4,70.58 138.32,70.58 138.19,70.45 138.19,69.59 v1(138.3,69.48)
  BOTTOM w0.076: v1(119.09,105.72) 119.41,106.04 UC1.AR20
  BOTTOM w0.102: JDIMM2.59 137.75,69.85 138.12,69.48 v1(138.3,69.48)
DDR_B_D58: length 65.3
  IN1 w0.084: 129.95,94.47 129.4,95.02 128.63,95.02 127.85,95.8 126.82,95.8 124.43,98.19 124.43,100.75 120.76,104.42 120.76,108.18 v1(120,108.93)
  IN1 w0.127: 129.95,94.47 130.04,94.38 130.04,93.6 132.82,90.82 132.82,86.15 141.31,77.66 141.31,77.1 141.45,76.95 142.86,76.95 143.28,76.53 143.28,72.41 143.16,72.28 141.74,72.28 141.61,72.16 141.61,71.89 141.74,71.76 143.16,71.76 143.28,71.64 143.28,71.37 143.16,71.24 141.75,71.24 141.62,71.11 141.62,70.85 141.75,70.72 142.9,70.72 143.03,70.59 143.03,70.33 142.9,70.2 141.77,70.2 141.63,70.06 141.63,67.77 141.5,67.64 140.94,67.64 140.81,67.77 v1(140.81,67.96)
  BOTTOM w0.076: UC1.AK18 120.36,109.3 v1(120,108.93)
  BOTTOM w0.102: v1(140.81,67.96) 141.25,68.4 141.25,69.73 140.75,70.24 JDIMM2.69
DDR_B_D59: length 65
  IN1 w0.084: 129.68,94.2 129.68,94.36 129.24,94.8 128.6,94.8 127.78,95.62 126.74,95.62 124.11,98.26 124.11,100.82 120.58,104.35 120.58,107.75 v1(120.01,108.32)
  IN1 w0.127: 129.68,94.2 129.68,93.46 132.48,90.66 132.48,86 140.79,77.69 140.79,76.74 140.91,76.61 142.59,76.61 142.71,76.48 142.71,76.2 142.59,76.08 140.91,76.08 140.79,75.95 140.79,75.67 140.91,75.54 142.59,75.54 142.71,75.41 142.71,75.14 142.59,75.01 140.91,75.01 140.79,74.88 140.79,74.6 140.91,74.47 142.59,74.47 142.71,74.35 142.71,74.07 142.59,73.94 141.19,73.94 141.07,73.81 141.07,73.34 141.19,73.21 142.4,73.21 142.52,73.09 142.52,72.77 142.4,72.64 141.35,72.64 141.22,72.51 141.22,71.91 141.09,71.78 140.81,71.78 140.69,71.65 140.69,71.37 140.81,71.25 141.09,71.25 141.22,71.12 141.22,69.9 v1(140.81,69.48)
  BOTTOM w0.076: UC1.AL18 120.34,108.64 v1(120.01,108.32)
  BOTTOM w0.102: JDIMM2.67 140.15,70.14 v1(140.81,69.48)
DDR_B_D60: length 65.6
  IN1 w0.084: 125.68,93.94 125.52,94.11 125.52,94.13 121.79,97.86 121.79,100.74 121.19,101.34 120.54,101.34 120.07,101.8 120.07,102.82 119.69,103.19 118.89,103.19 118.19,103.9 118.19,105.14 117.68,105.65 117.68,109.07 117.95,109.34 118.9,109.34 119.09,109.16 v1(119.09,108.97)
  IN1 w0.127: 125.68,93.94 126.42,93.2 126.42,92.1 127.62,90.9 127.62,85 137.13,75.5 137.13,68.27 137.33,68.07 137.33,64.76 137.28,64.71 137.28,64.59 137.15,64.46 136.81,64.46 136.68,64.33 136.68,59.74 136.81,59.61 137.19,59.61 137.32,59.74 v1(137.32,59.98)
  BOTTOM w0.076: UC1.AK20 119.41,109.3 v1(119.09,108.97)
  BOTTOM w0.102: v1(137.32,59.98) 137.72,60.38 137.72,61.77 137.45,62.04 JDIMM2.58
DDR_B_D61: length 64.6
  IN1 w0.084: 126.17,93.94 121.96,98.15 121.96,100.81 121.26,101.51 120.61,101.51 120.24,101.87 120.24,102.94 119.58,103.6 119.46,103.6 119.23,103.37 119.05,103.37 118.88,103.53 118.88,103.71 119.12,103.95 119.12,104.06 118.51,104.67 118.51,107.54 118.63,107.67 v1(119.09,107.67)
  IN1 w0.127: 126.17,93.94 126.76,93.34 126.76,92.25 127.98,91.03 127.98,85.15 137.48,75.65 137.48,68.42 137.72,68.18 137.72,66.88 137.87,66.72 138.33,66.72 138.46,66.6 138.46,66.31 138.33,66.19 137.8,66.19 137.67,66.06 137.67,65.79 137.8,65.67 138.33,65.67 138.46,65.54 138.46,65.27 138.33,65.15 138.2,65.15 138.08,65.02 138.08,64.75 138.2,64.63 138.33,64.63 138.46,64.5 138.46,64.02 138.33,63.89 137.15,63.89 137.02,63.76 137.02,63.5 137.15,63.37 138.27,63.37 138.4,63.24 138.4,62.97 138.27,62.85 137.15,62.85 137.02,62.72 137.02,61.63 137.15,61.5 v1(137.32,61.5)
  BOTTOM w0.076: v1(119.09,107.67) 119.41,107.99 UC1.AM20
  BOTTOM w0.102: JDIMM2.56 136.85,61.97 v1(137.32,61.5)
DDR_B_D62: length 61.3
  IN1 w0.084: 128.97,93.94 128.97,94.24 128.76,94.46 128.46,94.46 127.63,95.28 126.6,95.28 123.73,98.15 123.73,100.71 120.04,104.4 v1(120.04,105.72)
  IN1 w0.127: v1(140.81,59.98) 140.43,59.98 140.43,59.97 139.67,59.97 139.54,60.1 139.54,60.38 139.67,60.51 139.9,60.51 140.03,60.63 140.03,60.91 139.9,61.04 139.54,61.04 139.41,61.17 139.41,61.45 139.54,61.57 139.86,61.57 139.99,61.7 139.99,77.52 131.79,85.72 131.79,90.34 128.97,93.16 128.97,93.94
  BOTTOM w0.076: v1(120.04,105.72) 120.36,106.04 UC1.AR18
  BOTTOM w0.102: v1(140.81,59.98) 141.25,60.42 141.25,61.86 141.05,62.06 JDIMM2.70
DDR_B_D63: length 62.7
  IN1 w0.084: v1(120.04,106.37) 120.41,106 120.41,104.27 123.9,100.79 123.9,98.22 126.67,95.45 127.71,95.45 128.53,94.63 128.93,94.63 129.33,94.23 129.33,93.94
  IN1 w0.127: v1(140.81,61.5) 140.74,61.56 140.74,61.86 140.87,61.99 141.1,61.99 141.23,62.11 141.23,62.42 141.1,62.55 140.46,62.55 140.33,62.67 140.33,62.95 140.46,63.08 141.1,63.08 141.23,63.21 141.23,63.56 141.17,63.61 140.46,63.61 140.33,63.74 140.33,64.02 140.46,64.15 141.1,64.15 141.23,64.27 141.23,65.33 141.08,65.48 140.56,65.48 140.43,65.61 140.43,66.04 140.55,66.15 141.21,66.15 141.32,66.26 141.32,66.52 141.19,66.65 140.6,66.65 140.39,66.86 140.39,70.06 140.55,70.22 140.72,70.22 140.85,70.35 140.85,70.61 140.72,70.74 140.46,70.74 140.34,70.86 140.34,77.65 132.13,85.86 132.13,90.5 129.33,93.31 129.33,93.94
  BOTTOM w0.076: UC1.AP18 120.36,106.69 v1(120.04,106.37)
  BOTTOM w0.102: JDIMM2.68 140.45,61.86 v1(140.81,61.5)
DDR_B_DQS0: length 81.9
  IN3 w0.084: v1(111.96,100.32) 112.11,100.48 112.22,100.48 113.04,99.67 113.04,95.55 113.96,94.63 113.96,94.37
  IN3 w0.127: v1(163.03,68.61) 163.03,68.46 163.16,68.34 163.35,68.34 163.46,68.44 163.46,74.17 155.1,82.52 151.94,82.52 150.84,83.63 150.02,83.63 149.11,84.54 122.28,84.54 117.23,89.59 116.88,89.59 113.96,92.52 113.96,94.37
  BOTTOM w0.076: UC1.AV30 112.18,104.4 112.1,104.32 111.95,104.32 111.86,104.23 111.79,104.16 111.79,104.15 111.72,104.01 111.72,103.81 111.75,103.75 111.79,103.65 111.79,103.52 111.72,103.36 111.72,103.16 111.75,103.1 111.75,103.1 111.79,103 111.79,102.81 111.55,102.57 111.55,101.43 111.37,101.24 111.37,100.76 111.66,100.47 111.81,100.47 v1(111.96,100.32)
  BOTTOM w0.102: v1(163.03,68.61) 163.03,68.37 162.89,68.23 162.82,68.23 162.55,68.5 162.55,69.67 163.03,70.15 163.26,70.15 163.55,70.44 JDIMM2.137
DDR_B_DQS1: length 56.2
  IN1 w0.084: v1(115.67,99.02) 115.52,98.88 115.28,98.88 114.23,97.82 114.23,94.32 114.36,94.18 114.36,94.02 114.42,93.96
  IN1 w0.127: v1(123.41,59.59) 123.3,59.7 122.9,59.7 122.51,60.09 122.51,62.72 122.29,62.94 121.97,62.94 121.7,63.22 121.7,63.81 121.97,64.08 122.33,64.08 122.46,64.21 122.46,66.39 121.86,66.99 121.86,71.45 114.44,78.87 114.44,93.94 114.42,93.96
  BOTTOM w0.076: UC1.AW26 114.43,103.91 114.39,103.87 114.39,103.48 114.37,103.43 114.33,103.34 114.32,103.32 114.32,103.19 114.34,103.14 114.39,103.03 114.39,102.63 114.1,102.34 114.02,102.26 114.02,101.93 114.64,101.32 114.64,99.18 114.95,98.86 115.51,98.86 v1(115.67,99.02)
  BOTTOM w0.102: v1(123.41,59.59) 123.67,59.86 123.86,59.86 124.05,60.05 124.05,61.33 123.45,61.93 123.45,62.01 123.65,62.2 JDIMM2.12
DDR_B_DQS2: length 89
  IN3 w0.084: 119.32,93.61 118.87,94.06 118.14,94.06 117.81,94.39 117.62,94.39 117.22,94.79 116.04,95.97 116.04,101.13 115.18,101.99 115.18,102.87 112.93,105.13 112.93,107.31 113.09,107.47 113.28,107.47 v1(113.48,107.67)
  IN3 w0.127: 119.32,93.61 124.07,88.86 150.9,88.86 151.81,87.95 156.21,87.95 168.16,76 168.16,73.26 169.03,72.39 169.03,69.28 168.39,68.64 168.39,66.83 168.65,66.57 168.82,66.57 v1(169.07,66.33)
  BOTTOM w0.076: v1(113.48,107.67) 113.8,107.99 UC1.AM28
  BOTTOM w0.102: v1(169.07,66.33) 168.83,66.57 168.72,66.57 168.66,66.5 168.66,64.94 168.38,64.65 168.38,64.52 168.65,64.24 JDIMM2.154
DDR_B_DQS3: length 57.1
  IN1 w0.084: v1(115.37,107.73) 115.21,107.57 115,107.57 114.81,107.37 114.81,105.41 115.07,105.14 115.07,105.02 114.52,104.47 114.52,104.11 114.92,103.71 115.22,103.71 115.89,104.38 116.07,104.38 116.24,104.21 116.24,104.03 115.77,103.56 115.77,103.21 116.16,102.82 116.49,102.82 116.56,102.89 116.69,102.89 116.79,102.79 116.79,102.59 116.43,102.23 116.43,101.72 116.91,101.23 116.91,96.32 118.8,94.44 118.8,93.94
  IN1 w0.127: 118.8,93.94 118.8,90.36 119.07,90.08 119.32,90.08 119.47,89.93 119.47,89.52 119.4,89.45 119.06,89.45 118.79,89.17 118.79,88.58 119.06,88.31 119.37,88.31 119.49,88.18 119.49,87.8 119.37,87.68 119.06,87.68 118.79,87.4 118.79,86.81 119.06,86.54 119.37,86.54 119.49,86.41 119.49,86.03 119.37,85.9 119.06,85.9 118.79,85.63 118.79,85.04 119.06,84.76 119.37,84.76 119.49,84.64 119.49,81.95 127.16,74.28 127.16,68.02 127.42,67.75 127.81,67.75 v1(127.98,67.58)
  BOTTOM w0.076: v1(115.37,107.73) 115.63,107.99 UC1.AM25
  BOTTOM w0.102: v1(127.98,67.58) 128.26,67.86 128.39,67.86 128.59,68.05 128.59,70.25 128.75,70.42 JDIMM2.29
DDR_B_DQS4: length 86.7
  IN3 w0.084: 127.77,93.94 127.64,94.07 127.64,94.1 127.61,94.14 126.72,95.02 120.98,95.02 120.13,95.88 118.94,95.88 118.59,96.23 118.59,100.21 117.99,100.81 117.68,100.81 117.57,100.7 v1(117.57,100.58)
  IN3 w0.127: v1(173.9,68.61) 173.9,68.44 174.03,68.3 174.22,68.3 174.32,68.39 174.32,69.59 173.93,69.97 173.93,76.95 158.59,92.3 157.61,92.3 156.62,93.29 139.73,93.29 139.39,93.63 128.08,93.63 127.77,93.94
  BOTTOM w0.076: v1(117.57,100.58) 117.05,101.1 117.05,101.84 116.81,102.08 116.81,102.7 116.93,102.81 116.93,103 116.88,103.1 116.88,103.1 116.85,103.16 116.85,103.36 116.93,103.52 116.93,103.65 116.88,103.75 116.85,103.81 116.85,104.01 116.92,104.15 116.92,104.16 116.99,104.23 117.08,104.32 117.23,104.32 117.31,104.4 UC1.AV22
  BOTTOM w0.102: v1(173.9,68.61) 173.9,68.47 173.76,68.34 173.53,68.34 173.45,68.42 173.45,69.79 173.52,69.86 173.52,70.19 173.75,70.42 JDIMM2.171
DDR_B_DQS5: length 54.4
  IN1 w0.084: v1(121.05,98.3) 121.05,98.13 120.91,97.99 120.53,97.99 120.31,97.77 120.31,96.14 120.95,95.5 122.01,95.5 122.8,94.7 122.8,93.92 123.11,93.62 123.11,93.61
  IN1 w0.127: 123.11,93.61 123.11,92.31 123.78,91.63 123.78,88.61 124.06,88.34 124.36,88.34 124.49,88.21 124.49,87.83 124.36,87.7 124.06,87.7 123.78,87.43 123.78,86.82 124.04,86.56 124.91,86.56 125.04,86.44 125.04,86.06 124.91,85.93 124.19,85.93 123.92,85.65 123.92,85.06 124.19,84.79 124.89,84.79 125.04,84.64 125.04,83.93 133.51,75.46 133.51,73.63 133.78,73.36 133.89,73.36 134.01,73.23 134.01,72.85 133.89,72.72 133.76,72.72 133.48,72.45 133.48,71.86 133.76,71.59 133.89,71.59 134.01,71.46 134.01,71.08 133.89,70.95 133.76,70.95 133.48,70.68 133.48,70.09 133.76,69.81 133.89,69.81 134.01,69.69 134.01,68.24 133.9,68.12 133.72,68.12 133.6,68.25 v1(133.6,68.42)
  BOTTOM w0.076: UC1.AW18 119.69,103.96 119.6,103.96 119.52,103.88 119.52,103.48 119.5,103.43 119.46,103.34 119.45,103.32 119.45,103.19 119.48,103.14 119.5,103.08 119.5,103.08 119.52,103.03 119.52,102.72 119.28,102.48 119.28,102.16 120.18,101.26 120.18,98.33 120.62,97.89 120.78,97.89 121.05,98.17 v1(121.05,98.3)
  BOTTOM w0.102: JDIMM2.47 134.15,70.5 133.83,70.18 133.83,69.99 133,69.16 133,68.21 133.15,68.06 133.52,68.06 133.63,68.17 133.63,68.38 v1(133.6,68.42)
DDR_B_DQS6: length 94.7
  IN3 w0.084: v1(118.13,107.67) 117.95,107.48 117.82,107.48 117.58,107.25 117.58,105.5 118.43,104.65 119.29,104.65 122.72,101.22 122.72,98.85 123.54,98.03 129.16,98.03 129.86,98.73 131.47,98.73 131.51,98.69 131.57,98.69
  IN3 w0.127: 131.57,98.69 137.34,98.69 137.54,98.49 144.08,98.49 144.96,97.61 159.89,97.61 179.25,78.25 179.25,66.77 179.54,66.48 179.78,66.48 v1(179.93,66.33)
  BOTTOM w0.076: v1(118.13,107.67) 118.42,107.67 118.52,107.77 UC1.AM21
  BOTTOM w0.102: v1(179.93,66.33) 179.93,66.55 179.82,66.66 179.6,66.66 179.42,66.49 179.42,64.85 178.85,64.28 JDIMM2.188
DDR_B_DQS7: length 63.4
  IN1 w0.084: 128.09,93.94 128.09,93.95 128.11,93.97 128.11,94.12 127.34,94.88 126.39,94.88 122.65,98.63 122.65,101.04 121.57,102.11 121.57,102.38 119.48,104.47 119.48,107.27 119.69,107.49 119.85,107.49 v1(120.04,107.67)
  IN1 w0.127: v1(138.7,59.59) 138.53,59.76 138.33,59.76 137.95,60.14 137.95,61.73 138.33,62.11 138.83,62.11 139.1,62.38 139.1,77.16 130.9,85.35 130.9,89.97 128.09,92.79 128.09,93.94
  BOTTOM w0.076: v1(120.04,107.67) 120.1,107.67 UC1.AM18
  BOTTOM w0.102: JDIMM2.64 139.25,62.19 139.18,62.12 139.18,61.5 139.61,61.07 139.61,59.9 139.35,59.64 138.74,59.64 v1(138.7,59.59)
DDR_B_DQS#0: length 82.1
  IN3 w0.084: 114.2,94.37 114.2,94.63 113.21,95.62 113.21,99.74 112.3,100.65 112.17,100.65 111.96,100.87 v1(111.96,100.97)
  IN3 w0.127: v1(163.03,67.85) 163.28,68.1 163.45,68.1 163.7,68.34 163.7,74.27 155.2,82.77 152.04,82.77 150.94,83.87 150.12,83.87 149.21,84.78 122.38,84.78 117.33,89.83 116.98,89.83 114.2,92.62 114.2,94.37
  BOTTOM w0.076: v1(111.96,100.97) 111.96,100.81 111.8,100.66 111.71,100.66 111.53,100.83 111.53,101.17 111.72,101.36 111.72,102.5 111.96,102.74 111.96,103.03 111.94,103.08 111.94,103.08 111.89,103.19 111.89,103.32 111.89,103.34 111.94,103.43 111.96,103.48 111.96,103.69 111.89,103.84 111.89,103.97 111.94,104.08 112.02,104.16 112.11,104.16 112.18,104.09 UC1.AW30
  BOTTOM w0.102: v1(163.03,67.85) 162.85,68.03 162.74,68.03 162.35,68.42 162.35,69.76 162.95,70.36 JDIMM2.135
DDR_B_DQS#1: length 56.5
  IN1 w0.084: v1(115.67,98.37) 115.67,98.56 115.56,98.67 115.36,98.67 114.43,97.74 114.43,94.41 114.57,94.27 114.57,94.16 114.59,94.14
  IN1 w0.127: 114.59,94.14 114.69,94.04 114.69,78.97 122.11,71.55 122.11,67.09 122.71,66.5 122.71,64.1 122.43,63.83 122.08,63.83 121.95,63.7 121.95,63.32 122.08,63.19 122.39,63.19 122.76,62.82 122.76,60.2 123.01,59.95 123.19,59.95 123.41,60.17 v1(123.41,60.36)
  BOTTOM w0.076: UC1.AV26 114.38,104.33 114.38,104.16 114.23,104 114.23,103.52 114.15,103.36 114.15,103.16 114.23,103 114.23,102.7 113.98,102.46 113.86,102.33 113.86,101.87 114.47,101.25 114.47,99.11 114.89,98.7 115.46,98.7 115.67,98.5 v1(115.67,98.37)
  BOTTOM w0.102: JDIMM2.10 123.05,62.19 123.26,61.99 123.26,61.85 123.85,61.25 123.85,60.14 123.78,60.06 123.71,60.06 v1(123.41,60.36)
DDR_B_DQS#2: length 89.1
  IN3 w0.084: v1(113.48,107.02) 113.48,107.18 113.36,107.3 113.16,107.3 113.1,107.24 113.1,105.2 115.36,102.94 115.36,102.06 116.21,101.2 116.21,96.04 117.69,94.56 117.88,94.56 118.21,94.23 118.98,94.23 119.41,93.8 119.47,93.8
  IN3 w0.127: 119.47,93.8 124.17,89.1 151,89.1 151.91,88.19 156.31,88.19 168.4,76.1 168.4,73.36 169.27,72.49 169.27,69.18 168.63,68.54 168.63,66.93 168.75,66.81 168.97,66.81 169.07,66.91 v1(169.07,67.09)
  BOTTOM w0.076: v1(113.48,107.02) 113.81,107.02 113.87,107.08 UC1.AN28
  BOTTOM w0.102: JDIMM2.152 168.05,64.34 168.18,64.46 168.18,64.74 168.46,65.02 168.46,66.59 168.64,66.76 168.9,66.76 169.07,66.93 v1(169.07,67.09)
DDR_B_DQS#3: length 57.2
  IN1 w0.084: 119.05,93.61 119.05,93.95 119.03,93.97 119.03,94.03 119,94.06 119,94.52 117.12,96.4 117.12,101.32 116.64,101.8 116.64,102.14 117,102.5 117,102.88 116.78,103.1 116.47,103.1 116.4,103.03 116.25,103.03 115.98,103.29 115.98,103.47 116.45,103.94 116.45,104.29 116.16,104.58 115.81,104.58 115.14,103.91 115.01,103.91 114.73,104.2 114.73,104.38 115.28,104.93 115.28,105.23 114.99,105.52 114.99,107.26 115.09,107.36 115.56,107.36 115.61,107.31 115.61,107.11 115.45,106.95 v1(115.37,106.95)
  IN1 w0.127: v1(127.98,68.34) 127.98,68.09 127.89,68.01 127.52,68.01 127.41,68.12 127.41,74.38 119.74,82.05 119.74,84.75 119.47,85.02 119.17,85.02 119.04,85.14 119.04,85.52 119.17,85.65 119.47,85.65 119.74,85.92 119.74,86.51 119.47,86.79 119.17,86.79 119.04,86.92 119.04,87.3 119.17,87.42 119.47,87.42 119.74,87.7 119.74,88.29 119.47,88.56 119.17,88.56 119.04,88.69 119.04,89.07 119.17,89.2 119.5,89.2 119.72,89.42 119.72,90.03 119.42,90.33 119.17,90.33 119.05,90.46 119.05,93.61
  BOTTOM w0.076: v1(115.37,106.95) 115.61,106.95 115.77,107.12 UC1.AN25
  BOTTOM w0.102: v1(127.98,68.34) 128.26,68.06 128.31,68.06 128.39,68.14 128.39,70.25 128.15,70.49 JDIMM2.27
DDR_B_DQS#4: length 86.8
  IN3 w0.084: 127.94,94.11 127.88,94.11 126.79,95.19 121.05,95.19 120.2,96.05 119.02,96.05 118.76,96.3 118.76,100.28 118.06,100.98 117.76,100.98 v1(117.57,101.16)
  IN3 w0.127: v1(173.9,67.85) 173.9,67.91 174.04,68.06 174.32,68.06 174.56,68.29 174.56,69.69 174.18,70.07 174.18,77.05 158.69,92.54 157.71,92.54 156.72,93.53 139.83,93.53 139.49,93.87 128.18,93.87 127.94,94.11
  BOTTOM w0.076: UC1.AW22 117.31,104.09 117.24,104.16 117.15,104.16 117.07,104.08 117.02,103.97 117.02,103.84 117.09,103.69 117.09,103.48 117.07,103.43 117.03,103.34 117.02,103.32 117.02,103.19 117.05,103.14 117.09,103.03 117.09,102.74 116.98,102.63 116.98,102.15 117.22,101.91 117.22,101.23 117.28,101.16 v1(117.57,101.16)
  BOTTOM w0.102: v1(173.9,67.85) 173.9,68.01 173.76,68.14 173.44,68.14 173.25,68.33 173.25,69.87 173.32,69.94 173.32,70.24 173.15,70.41 JDIMM2.169
DDR_B_DQS#5: length 54.8
  IN1 w0.084: v1(121.05,97.65) 120.92,97.78 120.61,97.78 120.51,97.68 120.51,96.23 121.03,95.71 122.09,95.71 123.01,94.79 123.01,94.01 123.18,93.84 123.2,93.84 123.34,93.71 123.34,93.65 123.36,93.62 123.36,93.61
  IN1 w0.127: v1(133.6,67.66) 133.6,67.66 133.81,67.87 134,67.87 134.27,68.13 134.27,69.79 133.99,70.07 133.86,70.07 133.73,70.19 133.73,70.57 133.86,70.7 133.99,70.7 134.27,70.97 134.27,71.56 133.99,71.84 133.86,71.84 133.73,71.97 133.73,72.35 133.86,72.47 133.99,72.47 134.27,72.75 134.27,73.34 133.99,73.61 133.88,73.61 133.76,73.74 133.76,75.57 125.29,84.04 125.29,84.75 124.99,85.04 124.3,85.04 124.17,85.17 124.17,85.55 124.3,85.68 125.01,85.68 125.29,85.95 125.29,86.54 125.01,86.82 124.15,86.82 124.04,86.93 124.04,87.32 124.16,87.45 124.47,87.45 124.74,87.72 124.74,88.31 124.47,88.59 124.16,88.59 124.04,88.71 124.04,91.74 123.36,92.41 123.36,93.61
  BOTTOM w0.076: v1(121.05,97.65) 120.97,97.73 120.55,97.73 120.02,98.26 120.02,101.19 119.12,102.09 119.12,102.56 119.36,102.8 119.36,103 119.28,103.16 119.28,103.36 119.35,103.5 119.36,103.52 119.36,104 119.52,104.16 119.52,104.33 UC1.AV18
  BOTTOM w0.102: v1(133.6,67.66) 133.39,67.86 133.07,67.86 132.8,68.13 132.8,69.24 133.63,70.08 133.63,70.43 133.55,70.51 JDIMM2.45
DDR_B_DQS#6: length 94.9
  IN3 w0.084: 131.55,98.93 131.53,98.9 129.79,98.9 129.09,98.2 123.61,98.2 122.89,98.92 122.89,101.29 119.36,104.83 118.5,104.83 117.76,105.57 117.76,107.18 117.89,107.31 118.02,107.31 118.13,107.2 v1(118.13,107.02)
  IN3 w0.127: 131.55,98.93 137.44,98.93 137.64,98.73 144.18,98.73 145.06,97.85 159.99,97.85 179.49,78.35 179.49,66.87 179.64,66.72 179.77,66.72 179.93,66.88 v1(179.93,67.09)
  BOTTOM w0.076: v1(118.13,107.02) 118.46,107.34 UC1.AN21
  BOTTOM w0.102: JDIMM2.186 178.25,64.31 178.43,64.5 178.79,64.5 179.22,64.93 179.22,66.57 179.51,66.86 179.7,66.86 v1(179.93,67.09)
DDR_B_DQS#7: length 63.6
  IN1 w0.084: 128.34,93.94 128.34,94.18 127.42,95.09 126.48,95.09 122.86,98.71 122.86,101.12 121.78,102.2 121.78,102.41 119.67,104.52 119.67,107.22 119.73,107.28 119.97,107.28 120.04,107.2 v1(120.04,107.02)
  IN1 w0.127: 128.34,93.94 128.34,92.9 131.16,90.08 131.16,85.46 139.35,77.26 139.35,62.28 138.93,61.86 138.44,61.86 138.2,61.63 138.2,60.25 138.44,60.02 138.6,60.02 138.7,60.11 v1(138.7,60.36)
  BOTTOM w0.089: v1(120.04,107.02) 120.49,107.02 120.55,107.08 120.55,107.26 120.47,107.34 UC1.AN18
  BOTTOM w0.102: JDIMM2.62 138.65,62.1 138.73,62.02 138.88,62.02 138.98,61.92 138.98,61.42 139.41,60.98 139.41,59.98 139.27,59.84 139.03,59.84 138.7,60.17 v1(138.7,60.36)
DDR_B_MA0: length 80.9
  IN3 w0.084: v1(105.76,106.37) 106.1,106.02 106.1,105.37 105.88,105.15 105.88,99.04 105.18,98.34 105.18,94.21 104.78,93.8 104.78,93.66
  IN3 w0.208: v1(151.16,65.67) 151.62,66.14 151.62,69.68 150.96,70.34 150.96,70.89 148.5,73.35 120.1,73.35 104.78,88.67 104.78,93.66
  BOTTOM w0.076: UC1.AP40 106.08,106.69 v1(105.76,106.37)
  BOTTOM w0.165: v1(151.16,65.67) 151.85,64.98 JDIMM2.98
DDR_B_MA1: length 81.2
  IN3 w0.084: 104.31,93.66 104.31,94.01 104.01,94.31 104.01,95.47 104.89,96.35 104.89,99.82 105.53,100.46 105.53,105.52 v1(105.73,105.72)
  IN3 w0.208: v1(151.16,68.72) 150.69,68.72 150.49,68.92 150.49,70.69 148.31,72.88 147.72,72.88 147.22,72.38 146.84,72.38 146.38,72.85 145.89,72.85 145.43,72.38 145.12,72.38 144.62,72.88 141.46,72.88 140.88,72.3 140.13,72.3 139.91,72.51 139.91,72.66 139.7,72.88 139.26,72.88 139.05,72.66 139.05,72.5 138.84,72.3 137.65,72.3 137.44,72.5 137.44,72.66 137.23,72.88 136.79,72.88 136.58,72.66 136.58,72.51 136.36,72.3 135.5,72.3 134.92,72.88 132.72,72.88 132.14,72.3 128.84,72.3 128.26,72.88 125.96,72.88 125.38,72.3 120.5,72.3 104.31,88.49 104.31,93.66
  BOTTOM w0.076: UC1.AR40 106.06,106.04 v1(105.73,105.72)
  BOTTOM w0.165: JDIMM2.97 151.55,70.22 151.6,70.17 151.6,69.16 v1(151.16,68.72)
DDR_B_MA2: length 85.9
  IN3 w0.084: 103.37,93.66 103.37,93.95 103.66,94.24 103.66,95.98 104.28,96.6 104.28,105.86 v1(104.84,106.42)
  IN3 w0.208: 103.37,93.66 103.37,88.1 118.08,73.39 118.08,72.74 119.46,71.36 147.86,71.36 149.55,69.67 149.55,61.8 v1(150.62,60.74)
  BOTTOM w0.076: v1(104.84,106.42) 105.12,106.69 UC1.AP42
  BOTTOM w0.165: JDIMM2.96 151.25,61.37 v1(150.62,60.74)
DDR_B_MA3: length 82.7
  IN3 w0.084: 103.84,93.66 103.84,95.81 104.65,96.62 104.65,105.58 v1(104.84,105.77)
  IN3 w0.208: v1(151.16,67.2) 150.22,67.2 150.02,67.4 150.02,70.5 148.61,71.91 144.33,71.91 143.84,72.41 141.65,72.41 141.07,71.83 135.3,71.83 134.72,72.41 132.92,72.41 132.34,71.83 128.64,71.83 128.06,72.41 126.15,72.41 125.58,71.83 119.65,71.83 118.55,72.93 118.55,73.58 103.84,88.29 103.84,93.66
  BOTTOM w0.076: v1(104.84,105.77) 105.12,106.04 UC1.AR42
  BOTTOM w0.165: v1(151.16,67.2) 150.72,67.64 150.72,70.02 150.95,70.25 JDIMM2.95
DDR_B_MA4: length 90.1
  IN3 w0.084: v1(102.94,105.79) 102.51,105.37 102.51,103.18 102.09,102.75 101.95,102.75 101.68,102.49 101.68,102.17 102.28,101.58 102.28,96.17 101.96,95.85 101.96,93.66
  IN3 w0.208: 101.96,93.66 101.96,87.51 116.67,72.8 116.67,72.15 118.87,69.95 125.5,69.95 125.88,69.57 128.17,69.57 128.81,68.93 128.81,67.07 129.16,66.71 132.61,66.71 132.89,66.43 134.86,66.43 135.14,66.71 138.68,66.71 140.15,68.19 140.15,69.49 140.62,69.95 146.69,69.95 147.68,68.96 147.68,66.11 148.43,65.36 148.43,61.39 v1(149.08,60.74)
  BOTTOM w0.076: v1(102.94,105.79) 103.18,106.04 UC1.AR45
  BOTTOM w0.165: JDIMM2.92 150.05,61.71 v1(149.08,60.74)
DDR_B_MA5: length 86.8
  IN3 w0.084: v1(102.94,106.45) 103.4,106.45 103.47,106.37 103.47,105.36 103.95,104.88 103.95,99.2 103.87,99.12 103.19,99.12 103.13,99.05 103.13,95.62 102.71,95.2 102.71,94.18 102.9,93.99 102.9,93.66
  IN3 w0.208: v1(149.08,68.72) 149.01,68.65 148.75,68.65 148.62,68.78 148.62,69.94 147.67,70.89 137.02,70.89 136.64,70.51 135.96,70.51 135.59,70.89 135.12,70.89 134.74,70.51 134.26,70.51 133.87,70.89 133.39,70.89 133.01,70.51 132.53,70.51 132.15,70.89 131.27,70.89 131.15,70.76 131.15,68.8 131.02,68.67 130.43,68.67 130.3,68.8 130.3,70.76 130.17,70.89 129.24,70.89 128.86,70.51 128.38,70.51 128,70.89 127.52,70.89 127.14,70.51 126.65,70.51 126.27,70.89 119.26,70.89 117.61,72.54 117.61,73.19 102.9,87.9 102.9,93.66
  BOTTOM w0.076: UC1.AP45 103.18,106.69 v1(102.94,106.45)
  BOTTOM w0.165: v1(149.08,68.72) 149.37,68.72 149.57,68.52 149.57,68.29 149.77,68.08 150.09,68.08 150.29,68.29 150.29,69.13 149.75,69.67 JDIMM2.91
DDR_B_MA6: length 93
  IN3 w0.084: v1(101.97,103.28) 101.51,102.82 101.51,102.1 102.06,101.55 102.06,96.53 101.49,95.96 101.49,93.66
  IN3 w0.208: v1(149.08,59.21) 147.96,60.34 147.96,62.52 147.21,63.27 147.21,68.76 146.49,69.48 141.63,69.48 141.32,69.16 141.32,67.05 141,66.73 139.71,66.73 139.22,66.24 135.33,66.24 135.06,65.96 132.69,65.96 132.41,66.24 124.74,66.24 124.53,66.46 124.53,67.07 124.4,67.19 123.58,67.19 123.45,67.07 123.45,66.46 123.23,66.24 121.04,66.24 120.27,67.01 120.27,69.27 120.07,69.48 118.68,69.48 116.2,71.96 116.2,72.61 101.49,87.32 101.49,93.66
  BOTTOM w0.076: UC1.AW46 102.28,103.58 101.98,103.28 v1(101.97,103.28)
  BOTTOM w0.165: v1(149.08,59.21) 148.62,59.68 148.62,61.66 148.95,61.99 149.32,61.99 149.45,62.12 JDIMM2.90
DDR_B_MA7: length 91.2
  IN3 w0.084: 98.01,93.66 98.01,95.33 100.16,97.48 v1(100.16,100.11)
  IN3 w0.208: v1(147.43,60.74) 147.17,60.74 146.97,60.94 146.97,62.23 146.76,62.43 144.57,62.43 144.37,62.23 144.37,60.72 144.24,60.59 143.63,60.59 143.51,60.72 143.51,62.23 143.3,62.43 142.85,62.43 142.64,62.23 142.64,60.72 142.52,60.59 141.91,60.59 141.78,60.72 141.78,62.23 141.58,62.43 118.84,62.43 107.15,74.13 107.15,76.95 98.01,86.09 98.01,93.66
  BOTTOM w0.076: UC1.AY46 102.45,102.86 102.45,101.23 101.5,100.28 100.33,100.28 v1(100.16,100.11)
  BOTTOM w0.165: v1(147.43,60.74) 147.87,61.18 147.87,61.73 148.25,62.11 JDIMM2.86
DDR_B_MA8: length 89.9
  IN3 w0.084: v1(102.05,102.33) 102.47,101.91 102.47,95.71 102.19,95.43 102.19,93.9 102.43,93.66
  IN3 w0.208: 102.43,93.66 102.43,87.71 117.14,73 117.14,72.35 119.07,70.42 125.7,70.42 126.08,70.04 129.71,70.04 129.84,69.91 129.84,68.34 129.97,68.21 131.48,68.21 131.61,68.34 131.61,69.83 131.81,70.04 133.93,70.04 134.06,69.91 134.06,68.4 134.19,68.27 134.93,68.27 135.05,68.4 135.05,69.92 135.18,70.05 136.07,70.05 136.19,69.92 136.19,68.4 136.32,68.27 136.9,68.27 137.03,68.4 137.03,70.24 137.15,70.37 138.63,70.37 138.76,70.24 138.76,69.16 138.89,69.04 139.49,69.04 139.62,69.16 139.62,70.29 139.74,70.42 146.88,70.42 148.15,69.15 148.15,67.47 148.42,67.2 v1(149.08,67.2)
  BOTTOM w0.076: UC1.AY47 101.55,102.75 101.97,102.33 v1(102.05,102.33)
  BOTTOM w0.165: JDIMM2.89 149.15,70.26 148.37,69.49 148.37,67.91 v1(149.08,67.2)
DDR_B_MA9: length 92.4
  IN3 w0.084: v1(101.98,104.58) 101.34,103.94 101.34,102.03 101.74,101.63 101.74,100.01 101.23,99.51 101.23,96.04 101.02,95.83 101.02,93.66
  IN3 w0.208: v1(146.58,68.72) 146.27,68.72 146.15,68.59 146.15,68.11 146.02,67.98 145.41,67.98 145.28,68.11 145.28,68.88 145.15,69.01 143.64,69.01 143.51,68.88 143.51,68.05 143.39,67.92 142.78,67.92 142.65,68.05 142.65,68.88 142.52,69.01 141.91,69.01 141.79,68.88 141.79,66.85 141.2,66.26 140.01,66.26 139.51,65.77 135.53,65.77 135.25,65.49 132.5,65.49 132.22,65.77 120.84,65.77 119.8,66.81 119.8,68.8 119.6,69.01 118.18,69.01 117.39,68.22 117.1,68.22 116.78,68.54 116.78,68.83 117.57,69.62 117.57,69.92 117.26,70.23 116.96,70.23 116.17,69.44 115.88,69.44 115.56,69.76 115.56,70.05 116.35,70.84 116.35,71.15 116.04,71.45 115.73,71.45 114.94,70.66 114.66,70.66 114.33,70.99 114.33,71.27 115.41,72.35 115.41,72.73 101.02,87.12 101.02,93.66
  BOTTOM w0.076: v1(101.98,104.58) 102.13,104.58 UC1.AU46
  BOTTOM w0.165: JDIMM2.85 147.95,69.57 147.1,68.72 v1(146.58,68.72)
DDR_B_MA10: length 96.7
  IN3 w0.084: v1(108.18,109.12) 108.49,109.12 108.59,109.02 108.59,104.96 108.85,104.69 108.85,99.88 107.53,98.56 107.53,97.1 107.75,96.89 107.75,96.47
  IN3 w0.208: v1(155.87,67.2) 155.52,67.2 155.4,67.32 155.4,71.57 155.17,71.8 155.17,72.1 155.4,72.32 155.4,72.69 155.11,72.97 154.82,72.97 154.57,72.72 154.25,72.72 153.95,73.02 153.95,73.35 154.08,73.48 154.08,73.74 153.44,74.37 153.44,74.56 153.66,74.78 153.66,75.11 153.32,75.45 152.99,75.45 152.32,74.78 152.04,74.78 150.51,76.31 128.29,76.31 128.09,76.52 128.09,78.12 127.89,78.33 127.43,78.33 127.23,78.12 127.23,76.52 127.02,76.31 126.57,76.31 126.36,76.52 126.36,78.12 126.16,78.33 125.7,78.33 125.5,78.12 125.5,76.52 125.3,76.31 124.84,76.31 124.64,76.52 124.64,78.12 124.43,78.33 119.33,78.33 107.75,89.91 107.75,96.47
  BOTTOM w0.076: v1(108.18,109.12) 108.35,109.3 UC1.AK36
  BOTTOM w0.165: JDIMM2.107 154.55,68.51 v1(155.87,67.2)
DDR_B_MA11: length 93.1
  IN3 w0.084: 97.54,93.66 97.54,95.22 99.79,97.47 99.79,100.29 v1(100.17,100.67)
  IN3 w0.208: v1(147.43,59.21) 146.7,59.21 146.5,59.42 146.5,61.76 146.29,61.96 145.04,61.96 144.84,61.76 144.84,60.16 144.64,59.95 141.51,59.95 141.31,60.16 141.31,61.76 141.11,61.96 118.65,61.96 106.68,73.93 106.68,76.76 97.54,85.9 97.54,93.66
  BOTTOM w0.076: UC1.AV47 101.26,103.94 101.26,102.74 101.58,102.43 101.58,100.8 101.4,100.62 100.22,100.62 v1(100.17,100.67)
  BOTTOM w0.165: v1(147.43,59.21) 146.97,59.68 146.97,61.73 147.65,62.41 JDIMM2.84
DDR_B_MA12: length 88.6
  IN3 w0.084: 98.48,93.66 98.48,95.15 100.54,97.21 100.54,101.86 100.77,102.08 100.77,102.85 v1(100.39,103.23)
  IN3 w0.208: 98.48,93.66 98.48,86.28 107.62,77.15 107.62,74.32 119.04,62.9 145.72,62.9 146.02,63.19 146.02,66.63 v1(146.58,67.2)
  BOTTOM w0.076: UC1.AU47 101.5,104.6 101.1,104.19 101.1,103.46 100.89,103.26 100.42,103.26 v1(100.39,103.23)
  BOTTOM w0.165: JDIMM2.83 147.35,70.62 146.14,69.42 146.14,67.64 v1(146.58,67.2)
DDR_B_MA13: length 96.5
  IN3 w0.084: 110.11,96.04 110.22,96.15 110.71,96.15 110.84,96.28 110.84,96.48 110.71,96.61 110.26,96.61 110.14,96.74 110.14,96.98 110.26,97.1 110.71,97.1 110.84,97.23 110.84,101.42 111.09,101.67 111.09,102.64 110.65,103.07 110.65,107.22 110.48,107.4 110.48,108.94 110.39,109.03 v1(110.09,109.03)
  IN3 w0.208: 110.11,96.04 110.1,96.02 110.1,90.88 120.3,80.68 142.33,80.68 142.53,80.47 142.53,78.86 142.73,78.66 143.19,78.66 143.39,78.86 143.39,80.47 143.6,80.68 144.05,80.68 144.26,80.47 144.26,78.86 144.46,78.66 144.92,78.66 145.12,78.86 145.12,80.47 145.32,80.68 145.78,80.68 145.98,80.47 145.98,78.86 146.19,78.66 146.65,78.66 146.85,78.86 146.85,80.47 147.05,80.68 147.51,80.68 147.71,80.47 147.71,78.86 147.92,78.66 153.49,78.66 159.09,73.06 159.09,68.85 v1(158.96,68.72)
  BOTTOM w0.076: v1(110.09,109.03) 110.35,109.3 UC1.AK33
  BOTTOM w0.165: v1(158.96,68.72) 158.15,69.53 JDIMM2.119
DDR_B_MA14: length 93.1
  IN3 w0.084: 97.07,93.66 97.07,95 99.58,97.5 99.58,100.8 100.15,101.36 100.15,102.1 99.85,102.4 99.85,104.52 100.46,105.13 101.42,105.13 101.98,105.7 v1(101.98,105.85)
  IN3 w0.208: v1(145.78,60.74) 145.31,60.27 145.31,59.96 144.77,59.42 144.77,58.68 144.64,58.56 140.37,58.56 140.24,58.68 140.24,60.01 140.04,60.21 139.37,60.21 139.16,60.01 139.16,58.19 138.96,57.99 121.96,57.99 106.21,73.74 106.21,76.56 97.07,85.7 97.07,93.66
  BOTTOM w0.076: UC1.AR46 102.28,105.85 v1(101.98,105.85)
  BOTTOM w0.165: v1(145.78,60.74) 146.45,61.41 JDIMM2.80
DDR_B_MA15: length 93.7
  IN3 w0.084: v1(101.98,106.5) 101.86,106.63 101.63,106.63 101.5,106.5 101.5,105.53 101.3,105.33 100.4,105.33 99.67,104.6 99.67,102.33 99.97,102.03 99.97,101.43 99.41,100.87 99.41,97.67 96.6,94.86 96.6,93.66
  IN3 w0.208: 96.6,93.66 96.6,85.51 105.74,76.37 105.74,73.54 121.87,57.41 145.1,57.41 145.23,57.54 145.23,59.23 145.36,59.36 145.65,59.36 145.78,59.23 v1(145.78,59.21)
  BOTTOM w0.076: UC1.AP46 102.28,106.5 v1(101.98,106.5)
  BOTTOM w0.165: JDIMM2.78 145.85,62.2 145.32,61.67 145.32,59.68 v1(145.78,59.21)
DDR_B_RAS#: length 97.3
  IN3 w0.084: 108.69,96.34 108.69,96.8 108.87,96.98 108.87,99.13 109.28,99.55 109.28,105.2 109.54,105.46 109.54,107.26 v1(109.16,107.64)
  IN3 w0.208: 108.69,96.34 108.69,90.3 119.72,79.27 134.01,79.27 134.21,79.06 134.21,77.45 134.42,77.25 152.85,77.25 155.09,75.01 155.09,74.7 154.91,74.52 154.91,74.24 155.23,73.91 155.52,73.91 155.7,74.09 156.01,74.09 156.56,73.54 156.56,73.16 156.33,72.94 156.33,65.48 156.46,65.35 156.81,65.35 156.94,65.23 156.94,64.53 156.81,64.4 155.86,64.4 155.73,64.27 155.73,63.71 155.86,63.58 158.36,63.58 158.56,63.38 158.56,62.83 158.36,62.63 157.36,62.63 157.15,62.42 157.15,61.95 156.84,61.63 156.84,60.6 156.63,60.39 156.24,60.39 156.04,60.6 v1(156.04,60.74)
  BOTTOM w0.089: v1(109.16,107.64) 109.51,107.99 UC1.AM35
  BOTTOM w0.165: JDIMM2.110 155.45,61.32 v1(156.04,60.74)
DDR_B_WE#: length 95.8
  IN3 w0.084: v1(109.13,108.97) 109.5,108.97 109.64,108.83 109.64,107.44 109.73,107.35 109.73,105.35 109.48,105.1 109.48,103.12 110.01,102.6 110.01,102.37 109.48,101.85 109.48,99.45 109.16,99.12 109.16,96.18
  IN3 w0.208: v1(157.43,67.2) 157.24,67.01 157,67.01 156.8,67.2 156.8,69.11 157.01,69.31 157.94,69.31 158.15,69.52 158.15,69.97 157.94,70.18 157.01,70.18 156.8,70.38 156.8,70.84 157.01,71.04 157.94,71.04 158.15,71.24 158.15,71.7 157.94,71.9 157.52,71.9 157.32,72.11 157.32,72.42 157.68,72.78 157.68,73.08 153.04,77.72 136.61,77.72 136.41,77.92 136.41,79.53 136.21,79.74 135.75,79.74 135.55,79.53 135.55,77.92 135.34,77.72 134.88,77.72 134.68,77.92 134.68,79.53 134.48,79.74 119.91,79.74 109.16,90.49 109.16,96.18
  BOTTOM w0.076: v1(109.13,108.97) 109.46,109.3 UC1.AK35
  BOTTOM w0.165: JDIMM2.113 156.35,68.28 v1(157.43,67.2)
DDR_CKE0_DIMMA: length 74.6
  IN1 w0.084: 97.69,93.66 97.69,94.04 99.95,96.3 100.9,96.3 103.98,99.38 103.98,104.16 v1(103.56,104.58)
  IN1 w0.183: 97.69,93.66 97.69,89.62 95.62,87.56 95.37,87.56 94.59,88.34 94.33,88.34 94.07,88.08 94.07,87.82 94.89,87.01 94.89,86.83 94.55,86.49 94.37,86.49 93.55,87.31 93.3,87.31 87.31,81.33 71.6,81.33 68.76,78.49 68.76,78.24 69.3,77.69 69.3,77.51 68.97,77.18 68.79,77.18 68.25,77.72 67.99,77.72 67.73,77.46 67.73,77.2 68.27,76.66 68.27,76.48 67.93,76.14 67.75,76.14 67.21,76.68 66.95,76.68 66.62,76.35 66.62,76.16 67.16,75.63 67.16,75.37 66.18,74.39 65.87,74.39 65.15,73.67 65.15,71.8 64.56,71.21 64.56,69.27 v1(65.15,68.68)
  BOTTOM w0.076: v1(103.56,104.58) 103.7,104.58 UC1.AU43
  BOTTOM w0.165: JDIMM1.73 65.8,69.33 v1(65.15,68.68)
DDR_CKE1_DIMMA: length 74.3
  IN1 w0.084: v1(103.54,103.28) 103.15,102.89 103.15,99.76 102.91,99.51 102.91,98.62 100.82,96.53 99.86,96.53 98.64,95.31 98.44,95.31 97.22,94.09 97.22,93.66
  IN1 w0.183: 97.22,93.66 97.22,89.81 96.38,88.97 94.21,88.97 87.02,81.79 71.4,81.79 65.84,76.22 65.84,75.01 64.61,73.78 64.61,72.2 64.1,71.69 64.1,67.79 64.89,67 64.89,63.99 66,62.88 66,61.15 v1(66.45,60.7)
  BOTTOM w0.076: UC1.AW43 103.86,103.58 103.56,103.28 v1(103.54,103.28)
  BOTTOM w0.165: v1(66.45,60.7) 66.01,61.14 66.01,61.71 66.1,61.8 JDIMM1.74
DDR_CKE2_DIMMB: length 83.2
  IN3 w0.084: v1(101.12,101.59) 101.57,101.15 101.57,100.09 101.06,99.58 101.06,96.47 100.8,96.21 100.8,94.37 100.3,93.86 100.3,93.66
  IN3 w0.208: 100.3,93.66 100.3,86.82 114.45,72.67 114.45,72.41 113.38,71.34 113.38,70.92 118.48,65.81 118.66,65.81 119.13,66.28 119.31,66.28 119.74,65.85 119.74,65.66 119.29,65.2 119.27,65.2 119.27,65.02 119.72,64.57 119.96,64.57 120.44,65.05 126.57,65.05 127.05,64.57 127.5,64.57 127.98,65.05 128.41,65.05 128.89,64.57 129.16,64.57 129.65,65.05 130.15,65.05 130.63,64.57 131.07,64.57 131.55,65.05 131.92,65.05 132.4,64.57 135.35,64.57 135.83,65.05 139.93,65.05 140.43,65.54 141.19,65.54 141.32,65.41 141.32,64.69 141.44,64.57 142.38,64.57 142.51,64.69 142.51,67.07 142.64,67.2 v1(143.32,67.2)
  BOTTOM w0.076: UC1.AY49 100.8,101.91 v1(101.12,101.59)
  BOTTOM w0.165: v1(143.32,67.2) 143.32,68.94 144.35,69.97 JDIMM2.73
DDR_CKE3_DIMMB: length 85.3
  IN3 w0.084: v1(101.18,100.99) 100.89,100.69 100.89,96.81 99.28,95.2 99.28,94.06 99.67,93.66
  IN3 w0.208: v1(143.32,65.67) 143.57,65.92 143.92,65.92 144.09,65.76 144.09,64.22 143.96,64.1 119.53,64.1 112.5,71.13 112.5,71.43 113.67,72.6 113.67,72.78 113.24,73.22 113.06,73.22 111.89,72.05 111.58,72.05 111.28,72.35 111.28,72.66 112.45,73.83 112.45,74.01 99.67,86.78 99.67,93.66
  BOTTOM w0.076: v1(101.18,100.99) 99.69,102.49 99.69,104.69 UC1.AU50
  BOTTOM w0.165: JDIMM2.74 144.65,64.34 v1(143.32,65.67)
DDR_CS0_DIMMA#: length 76.1
  IN1 w0.084: 111.8,94.57 111.8,95.38 111.79,95.39 ; 110.88,106.43 v1(110.1,106.43)
  IN1 w0.089: 111.79,95.39 111.58,95.6 111.58,105.73 110.88,106.43
  IN1 w0.183: v1(77.63,60.7) 78.84,61.91 98.95,61.91 104.74,67.69 104.74,70.78 106.1,72.14 106.1,73.75 111.8,79.44 111.8,94.57
  BOTTOM w0.089: v1(110.1,106.43) 110.11,106.43 110.37,106.69 UC1.AP33
  BOTTOM w0.165: v1(77.63,60.7) 78.1,61.17 JDIMM1.114
DDR_CS1_DIMMA#: length 77.1
  IN1 w0.084: 109.5,94.57 109.5,95.19 110.83,96.52 110.83,100.72 109.61,101.93 109.61,102.12
  IN1 w0.089: 109.61,102.12 109.61,102.95 109.33,103.24 109.33,104.85 109.74,105.25 110.6,105.25 v1(111.06,105.72)
  IN1 w0.183: v1(80.51,67.19) 81.51,67.19 81.63,67.07 81.63,66.34 82.31,65.66 90.24,65.66 90.42,65.47 90.42,64.76 90.55,64.63 91.03,64.63 91.15,64.76 91.15,65.47 91.34,65.66 93.16,65.66 93.35,65.47 93.35,64.76 93.47,64.63 93.95,64.63 94.08,64.76 94.08,65.47 94.26,65.66 96.27,65.66 96.46,65.47 96.46,64.84 96.64,64.65 97.01,64.65 97.19,64.84 97.19,65.47 97.37,65.66 99.51,65.66 100.86,67.01 100.86,70.24 103.4,72.78 103.4,74.24 109.5,80.33 109.5,94.57
  BOTTOM w0.076: UC1.AR32 111.39,106.04 v1(111.06,105.72)
  BOTTOM w0.165: v1(80.51,67.19) 81.22,67.91 81.22,69.41 80.2,70.43 JDIMM1.121
DDR_CS2_DIMMB#: length 90.5
  IN3 w0.084: 111.29,96.04 111.29,101.03 111.63,101.38 111.63,107.11 111.04,107.7 v1(111.03,107.7)
  IN3 w0.208: v1(157.56,60.74) 160.28,63.46 160.28,73.56 153.98,79.86 150.02,79.86 148,81.87 120.8,81.87 111.29,91.38 111.29,96.04
  BOTTOM w0.089: v1(111.03,107.7) 111.32,107.99 UC1.AM32
  BOTTOM w0.165: v1(157.56,60.74) 156.65,61.65 JDIMM2.114
DDR_CS3_DIMMB#: length 90.3
  IN3 w0.084: 110.4,95.19 110.4,95.65 110.52,95.77 110.77,95.77 111.03,96.02 111.03,101.04 111.44,101.46 111.44,102.75 110.84,103.36 110.84,104.79 111.44,105.39 111.44,107.05 111.17,107.33 110.8,107.33 110.65,107.47 110.65,109.05 110.77,109.16 110.85,109.16 v1(111.04,108.97)
  IN3 w0.208: 110.4,95.19 110.82,94.77 110.82,91.18 120.6,81.4 147.81,81.4 148.44,80.77 148.44,79.7 148.75,79.39 153.79,79.39 159.81,73.36 159.81,68.55 159.42,68.16 159.42,67.82 159.81,67.43 159.81,67.01 159.68,66.88 159.27,66.88 v1(158.96,67.2)
  BOTTOM w0.076: UC1.AK32 111.36,109.3 v1(111.04,108.97)
  BOTTOM w0.165: JDIMM2.121 158.75,70.33 158.94,70.15 158.94,69.7 159.6,69.03 159.6,67.85 v1(158.96,67.2)
DDR_PG_CTRL: length 91.1
  TOP w0.102: v1(39.78,72.65) 38.89,71.77 v2(38.89,71.23) 38.89,66.62 39.97,65.54 41.94,65.54 43.34,66.94 43.84,66.94 44.12,66.67 U2303.2
  BOTTOM w0.076: UC1.AV61 92.5,104.51 92.44,104.57 92.16,104.57 92.15,104.56 91.12,104.56
  BOTTOM w0.089: 88.55,101.99 88.23,101.67 88.23,99.65
  BOTTOM w0.102: 91.12,104.56 88.55,101.99 ; v1(39.78,72.65) 39.78,74.5 40.16,74.88 48.86,74.88 55.97,81.99 86.01,81.99 88.23,84.21 88.23,99.65
DDR_XDP_SMBCLK_R1: length 2.9
  BOTTOM w0.102: JXDP1.53 60.2,92.15 60.29,92.06 60.29,91.2 60.1,91 RP46.7
DDR_XDP_SMBDAT_R1: length 2.9
  BOTTOM w0.102: JXDP1.51 60.7,92.15 60.49,91.94 60.49,91.17 60.6,91.07 RP46.8
DDR_XDP_WLAN_TP_SMBCLK: length 442.5
  TOP w0.102: v1(123.03,149.11) 126.97,145.17 126.97,138.44 129.1,136.31 135.63,136.31 137.69,134.25 148.44,134.25 148.77,133.92 v2(150.51,133.92) v1(151.07,134.48) 151.36,134.19 151.36,133.07 146.83,128.55 146.83,125.86 145.77,124.8 145.77,121.36 149.45,117.68 149.45,116.12 149.95,115.62 149.95,112.71 147.8,110.56 v1(146.46,110.56) ; v1(70.36,112.53) 70.35,112.52 JTP.5
  IN2 w0.127: v1(144.87,51.9) 144.62,52.16 144.62,62.41 144.05,62.98 144.05,73.25 145.25,74.45 145.25,105.63 146.65,107.03 146.65,110.37 v1(146.46,110.56)
  IN3 w0.127: v1(70.36,112.53) 67.4,112.53 63.44,108.57 63.44,99.62 64.87,98.19 64.87,96.83 63.9,95.86 63.9,92.24 63.31,91.65 63.31,87.04 64.01,86.33 v1(64.01,86.24) 64.59,85.67 64.59,77.91 69.34,73.15 69.34,56.19 73.71,51.83 102.94,51.83 103.27,51.5 v1(103.27,51.4) 103.94,51.4 105.58,53.04 116.61,53.04 117.32,52.33 144.45,52.33 v1(144.87,51.9) 145.04,51.74 163,51.74 163.21,51.94 171.18,51.94 171.43,52.2 176.37,52.2 176.83,52.65 177.34,52.65 179.09,54.4 180.7,54.4 181.77,55.47 183.38,55.47 184.58,56.66 187.24,56.66 187.79,57.21 187.79,60.05 186.76,61.08 186.14,61.08 185.87,61.36 185.87,61.65 v1(186.33,62.12) ; v1(151.07,134.48) 151.69,134.48 158.63,141.41 158.63,152.17 160.39,153.94 160.39,158.02 161.61,159.24 188.8,159.24 190.92,161.36 198.66,161.36 199.14,161.85 199.14,162.39 v1(199.27,162.52)
  BOTTOM w0.102: RX6.1 199.33,162.58 v1(199.27,162.52) ; v1(64.01,86.24) 63.57,85.8 60.54,85.8 60.1,86.25 RP46.2 ; v1(186.33,62.12) 185.44,61.22 183.67,61.22 183.05,61.85 JDIMM2.202 ; v1(103.27,51.4) 103.27,57.08 104.3,58.12 104.3,61.93 104.5,62.13 JDIMM1.202 ; R2332.2 146.97,110.06 v1(146.46,110.56) 144.87,110.56 144.74,110.43 QC1.1 ; JMINI.30 108.1,146.83 109.4,145.53 120.42,145.53 123.03,148.13 v1(123.03,149.11)
DDR_XDP_WLAN_TP_SMBDAT: length 446.6
  TOP w0.102: JTP.6 71.35,112.59 v1(70.94,113) ; v1(123.03,149.74) 123.47,149.3 123.47,148.99 127.19,145.27 127.19,138.54 129.19,136.54 135.73,136.54 137.79,134.48 148.59,134.48 148.87,134.2 150.03,134.2 v1(150.42,134.59) 150.82,134.99 151.29,134.99 151.59,134.68 151.59,132.98 147.06,128.45 147.06,125.77 146,124.71 146,121.45 149.68,117.77 149.68,116.21 v2(150.79,115.11) 151.64,114.25 151.64,108.48 151.25,108.09 146.78,108.09 v1(146.21,107.52)
  IN2 w0.127: v1(144.11,51.91) 144.36,52.16 144.36,62.3 143.79,62.88 143.79,73.35 145,74.56 145,105.74 146.21,106.94 v1(146.21,107.52)
  IN3 w0.127: v1(70.94,113) 66.62,113 63.19,109.57 63.19,99.51 64.61,98.09 64.61,96.94 63.64,95.97 63.64,92.35 63.05,91.76 63.05,86.62 v1(63.43,86.24) 63.43,86.15 64.32,85.25 64.32,77.8 69.08,73.04 69.08,56.09 73.77,51.4 v1(102.67,51.4) 102.67,51.35 103.06,50.96 103.93,50.96 105.59,52.63 116.66,52.63 117.3,51.99 139.59,51.99 140.1,51.48 143.69,51.48 v1(144.11,51.91) 144.54,51.48 163.11,51.48 163.31,51.69 171.29,51.69 171.54,51.94 176.48,51.94 176.94,52.4 177.45,52.4 179.19,54.14 180.81,54.14 181.87,55.21 183.49,55.21 184.68,56.4 187.35,56.4 188.05,57.1 188.05,60.36 186.91,61.51 v1(186.32,61.51) ; v1(150.42,134.59) 150.8,134.97 151.83,134.97 158.37,141.52 158.37,152.28 160.14,154.04 160.14,158.13 161.51,159.5 188.7,159.5 190.82,161.62 198.55,161.62 198.89,161.95 198.89,162.25 198.63,162.51 v1(198.63,162.52)
  BOTTOM w0.102: RP46.1 60.6,88.47 60.35,88.22 60.35,86.63 60.74,86.24 v1(63.43,86.24) ; v1(102.67,51.4) 102.67,56.82 104.07,58.22 104.07,61.97 103.9,62.15 JDIMM1.200 ; v1(198.63,162.52) 198.45,162.7 RX31.1 ; JDIMM2.200 182.45,62.08 183.62,60.91 185.72,60.91 v1(186.32,61.51) ; R2331.2 146.47,107.52 v1(146.21,107.52) 146.04,107.68 QC1.4 ; JMINI.32 108.9,146.6 109.74,145.76 119.04,145.76 v1(123.03,149.74)
DEVSLP0: length 143.4
  TOP w0.089: RC11.1 132.02,118.31 v1(132.23,118.53)
  TOP w0.102: RS8.1 215.17,58.05 215.17,53.91 214.43,53.17 210,53.17 209.44,52.61 209.44,51.89 207.42,49.87 v2(202.73,49.87) 200.69,49.87 199.81,50.75 197.39,50.75 196.64,50 196.31,50 195.11,48.79 194.47,48.79 193.95,49.31 v1(193.35,49.31)
  IN1 w0.084: v1(132.23,118.53) 132.78,119.07 135.33,119.07 136.85,120.59 137.53,120.59
  IN1 w0.127: 137.53,120.59 143.27,120.59 145.52,118.34 145.52,116.56 147.89,114.18 147.89,113.45 149.25,112.09 149.81,112.09 153.64,108.26 153.64,105.46 154.71,104.39 154.71,102.56 169.48,87.8 173.85,87.8 178.89,82.77 182.91,82.77 189.81,75.87 189.81,65.83 190.88,64.76 190.88,57.72 192.37,56.23 192.37,55.2 193.07,54.51 193.07,50.49 192.92,50.35 192.92,49.74 v1(193.35,49.31)
  BOTTOM w0.076: UC1.P2 130.08,118.05 131.11,118.05 131.59,118.53 v1(132.23,118.53)
DGPU_HOLD_RST#: length 40.5
  TOP w0.089: RC77.2 128.68,118.43 v1(128.68,117.93)
  IN1 w0.084: 137.3,120.84 136.29,120.84 135.04,119.59 131.9,119.59 131.07,118.76 129.44,118.76 128.68,117.99 128.68,117.93 v1(128.68,117.93)
  IN1 w0.127: 137.3,120.84 143.49,120.84 148.69,115.64 148.69,113.72 149.57,112.85 150.13,112.85 152.67,110.31 v1(153.1,110.31)
  IN3 w0.127: v1(158.82,108.41) 158.38,108.85 156.75,108.85 155.29,110.31 v1(153.1,110.31)
  BOTTOM w0.089: UC1.N4 128.33,118.28 128.61,118 v1(128.68,117.93)
  BOTTOM w0.102: UV13.1 158.38,109.09 158.31,109.02 158.31,108.75 158.65,108.41 v1(158.82,108.41)
DGPU_PRSNT#: length 13.4
  TOP w0.089: v2(135.76,117.78) 135.66,117.68 v1(135.22,117.68) 135.08,117.54 RC100.2 134.37,115.89 RC99.1
  IN3 w0.084: v1(135.22,117.68) 134.74,118.16 130.56,118.16 129.95,117.55 128.11,117.55 127.92,117.36 126.44,117.36 v1(126.02,117.78)
  BOTTOM w0.089: v1(126.02,117.78) 126.34,117.45 UC1.R7
DGPU_PWROK: length 169.5
  TOP w0.102: v1(190.33,37.59) 189.92,37.19 189.92,36.78 189.99,36.71 UE1.18
  IN1 w0.127: v1(136.81,116.72) 138.47,116.72 140.66,118.91 143.27,118.91 143.59,118.59 143.59,117.59 147.39,113.79 147.39,113.24 149.04,111.58 149.6,111.58 153.14,108.05 153.14,105.25 154.21,104.18 154.21,102.35 165.32,91.24 165.32,88.56 167.53,86.35 174.23,86.35 178.57,82 182.59,82 189.04,75.55 189.04,65.52 190.12,64.44 190.12,57.4 190.99,56.53 190.99,54.74 191.72,54.01 191.72,50.74 192.16,50.3 192.16,47.65 191.83,47.32 191.83,44.6 192.17,44.27 192.17,39.43 v1(190.33,37.59) ; v1(209.77,43.86) 208.99,44.64 v1(208.99,53.55)
  IN3 w0.084: v1(136.81,116.72) 136.58,116.95 134.17,116.95 133.62,117.5 132,117.5 130.52,116.03 128.48,116.03 128.07,116.43 127.55,116.43 127.47,116.36 127.09,116.36 126.63,115.9 v1(126.52,115.9)
  BOTTOM w0.089: v1(126.52,115.9) 126.99,116.37 UC1.U6 ; RC73.2 137.13,117.04 v1(136.81,116.72)
  BOTTOM w0.102: v1(209.77,43.86) 209.43,43.52 202.88,43.52 202.29,44.1 196.88,44.1 192.35,39.57 v2(191.08,39.57) 190.33,38.82 v1(190.33,37.59)
  BOTTOM w0.203: 206.66,54.44 206.19,54.91 PU800.2
  BOTTOM w0.254: 206.66,54.44 208.44,54.44 208.64,54.24 PR808.2 v1(208.99,53.55)
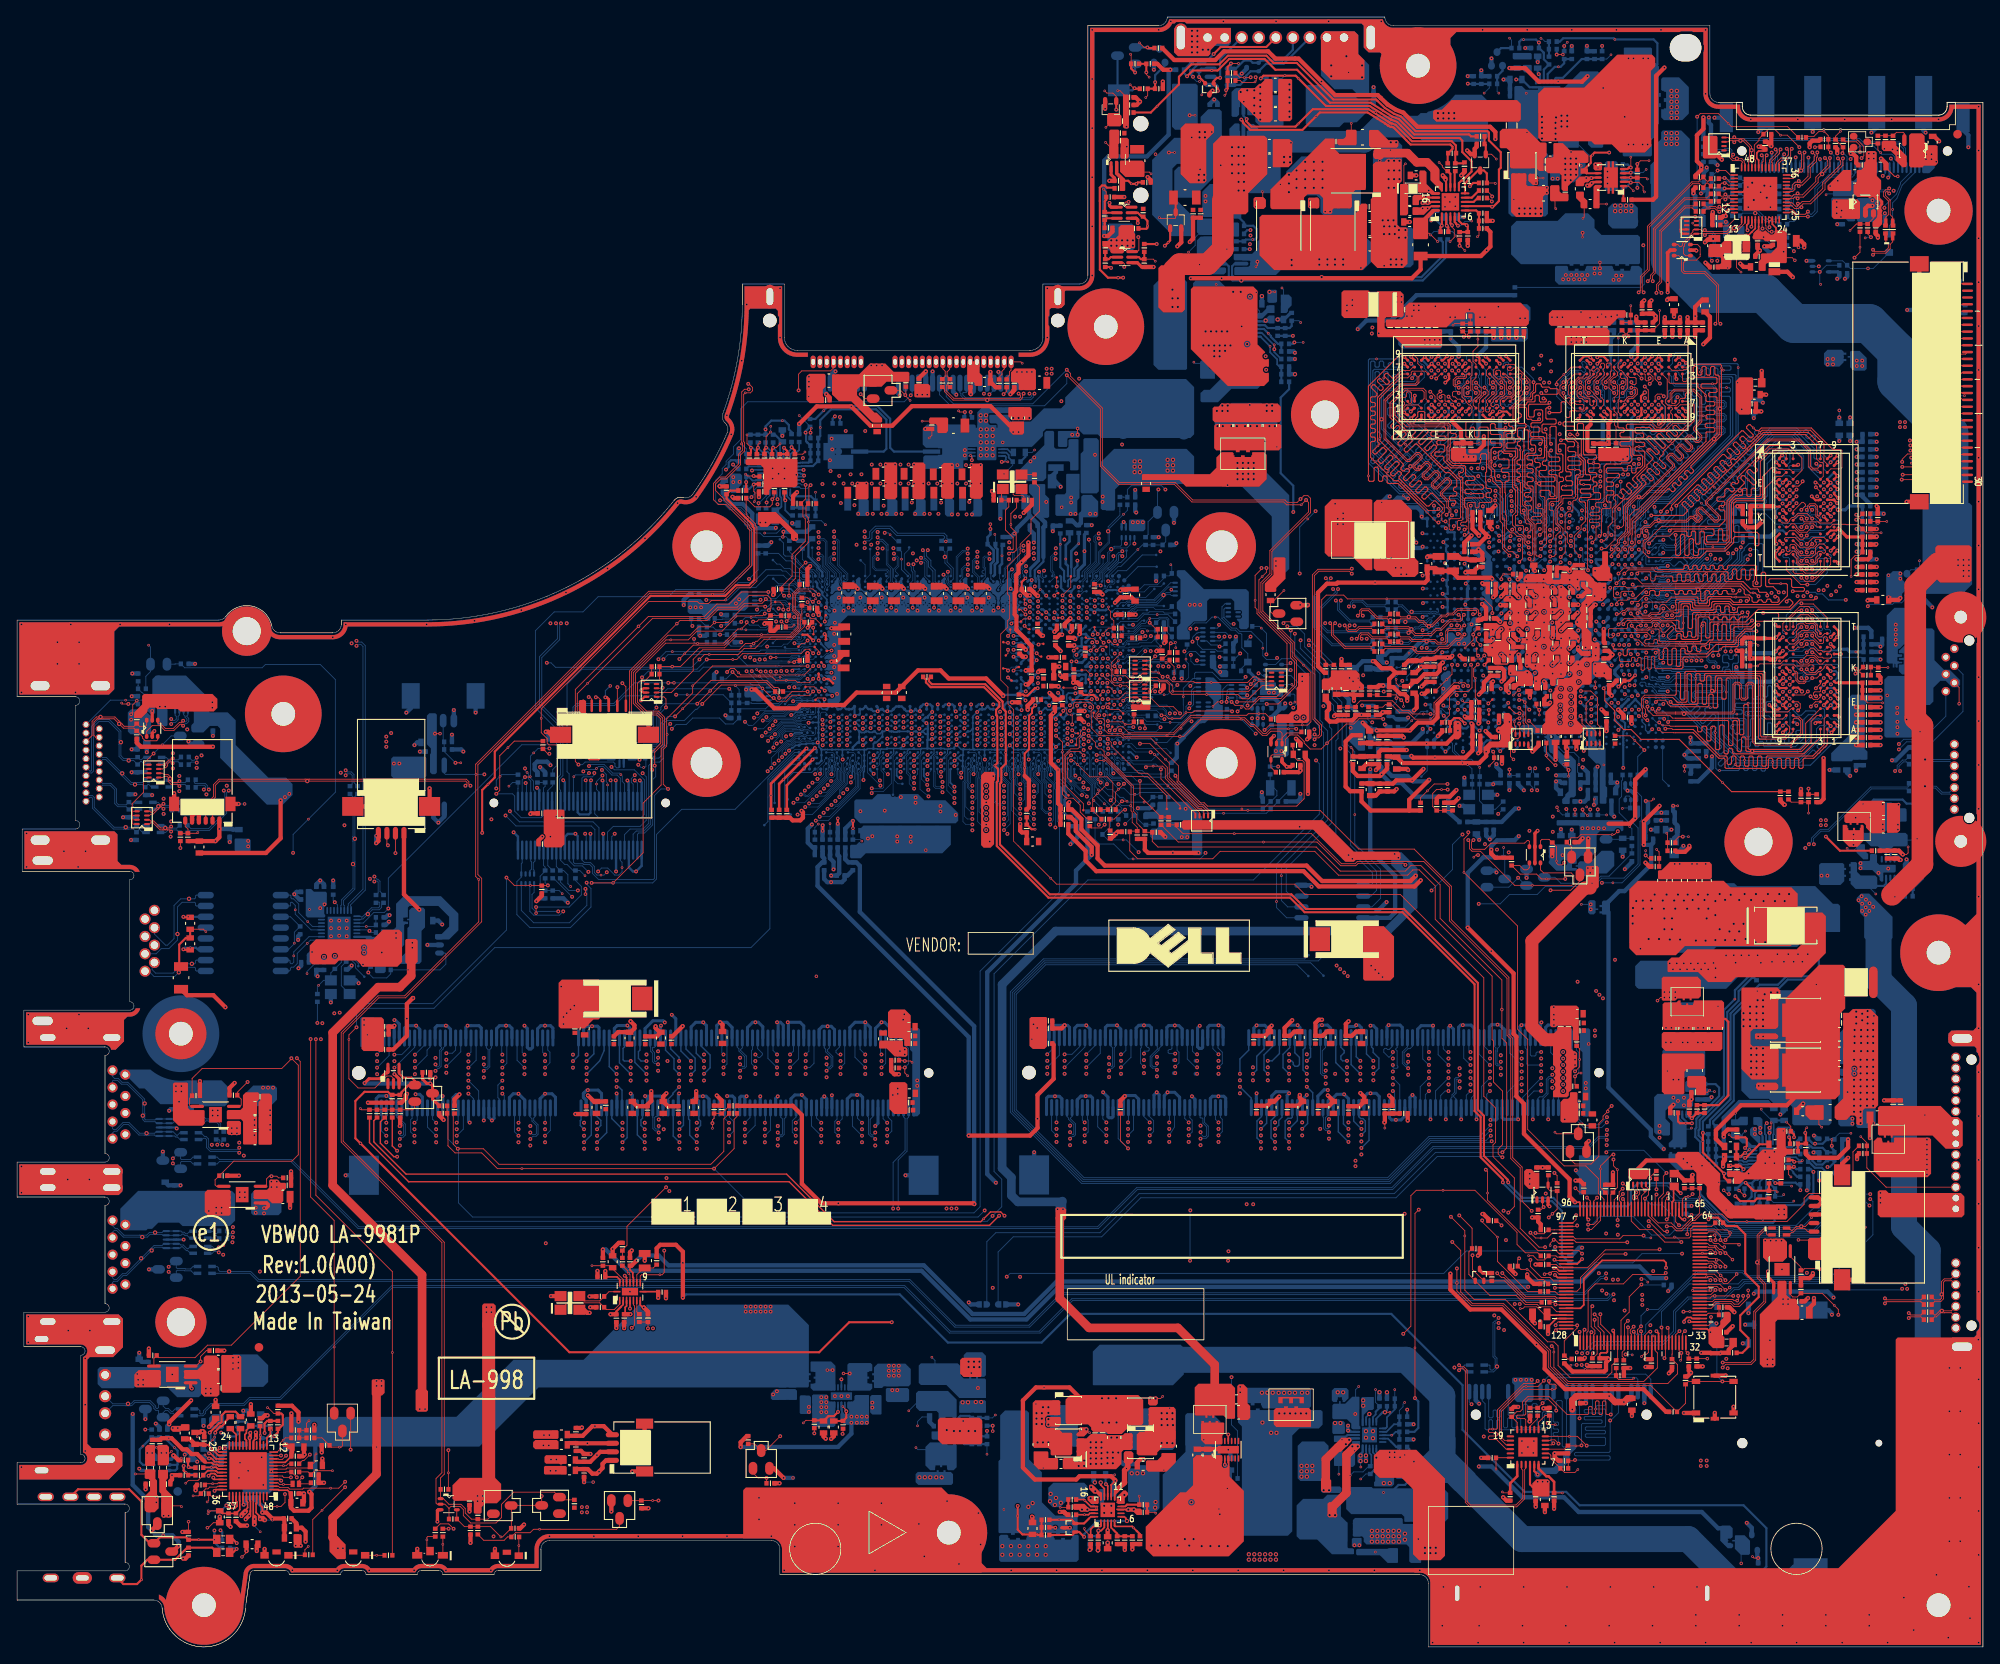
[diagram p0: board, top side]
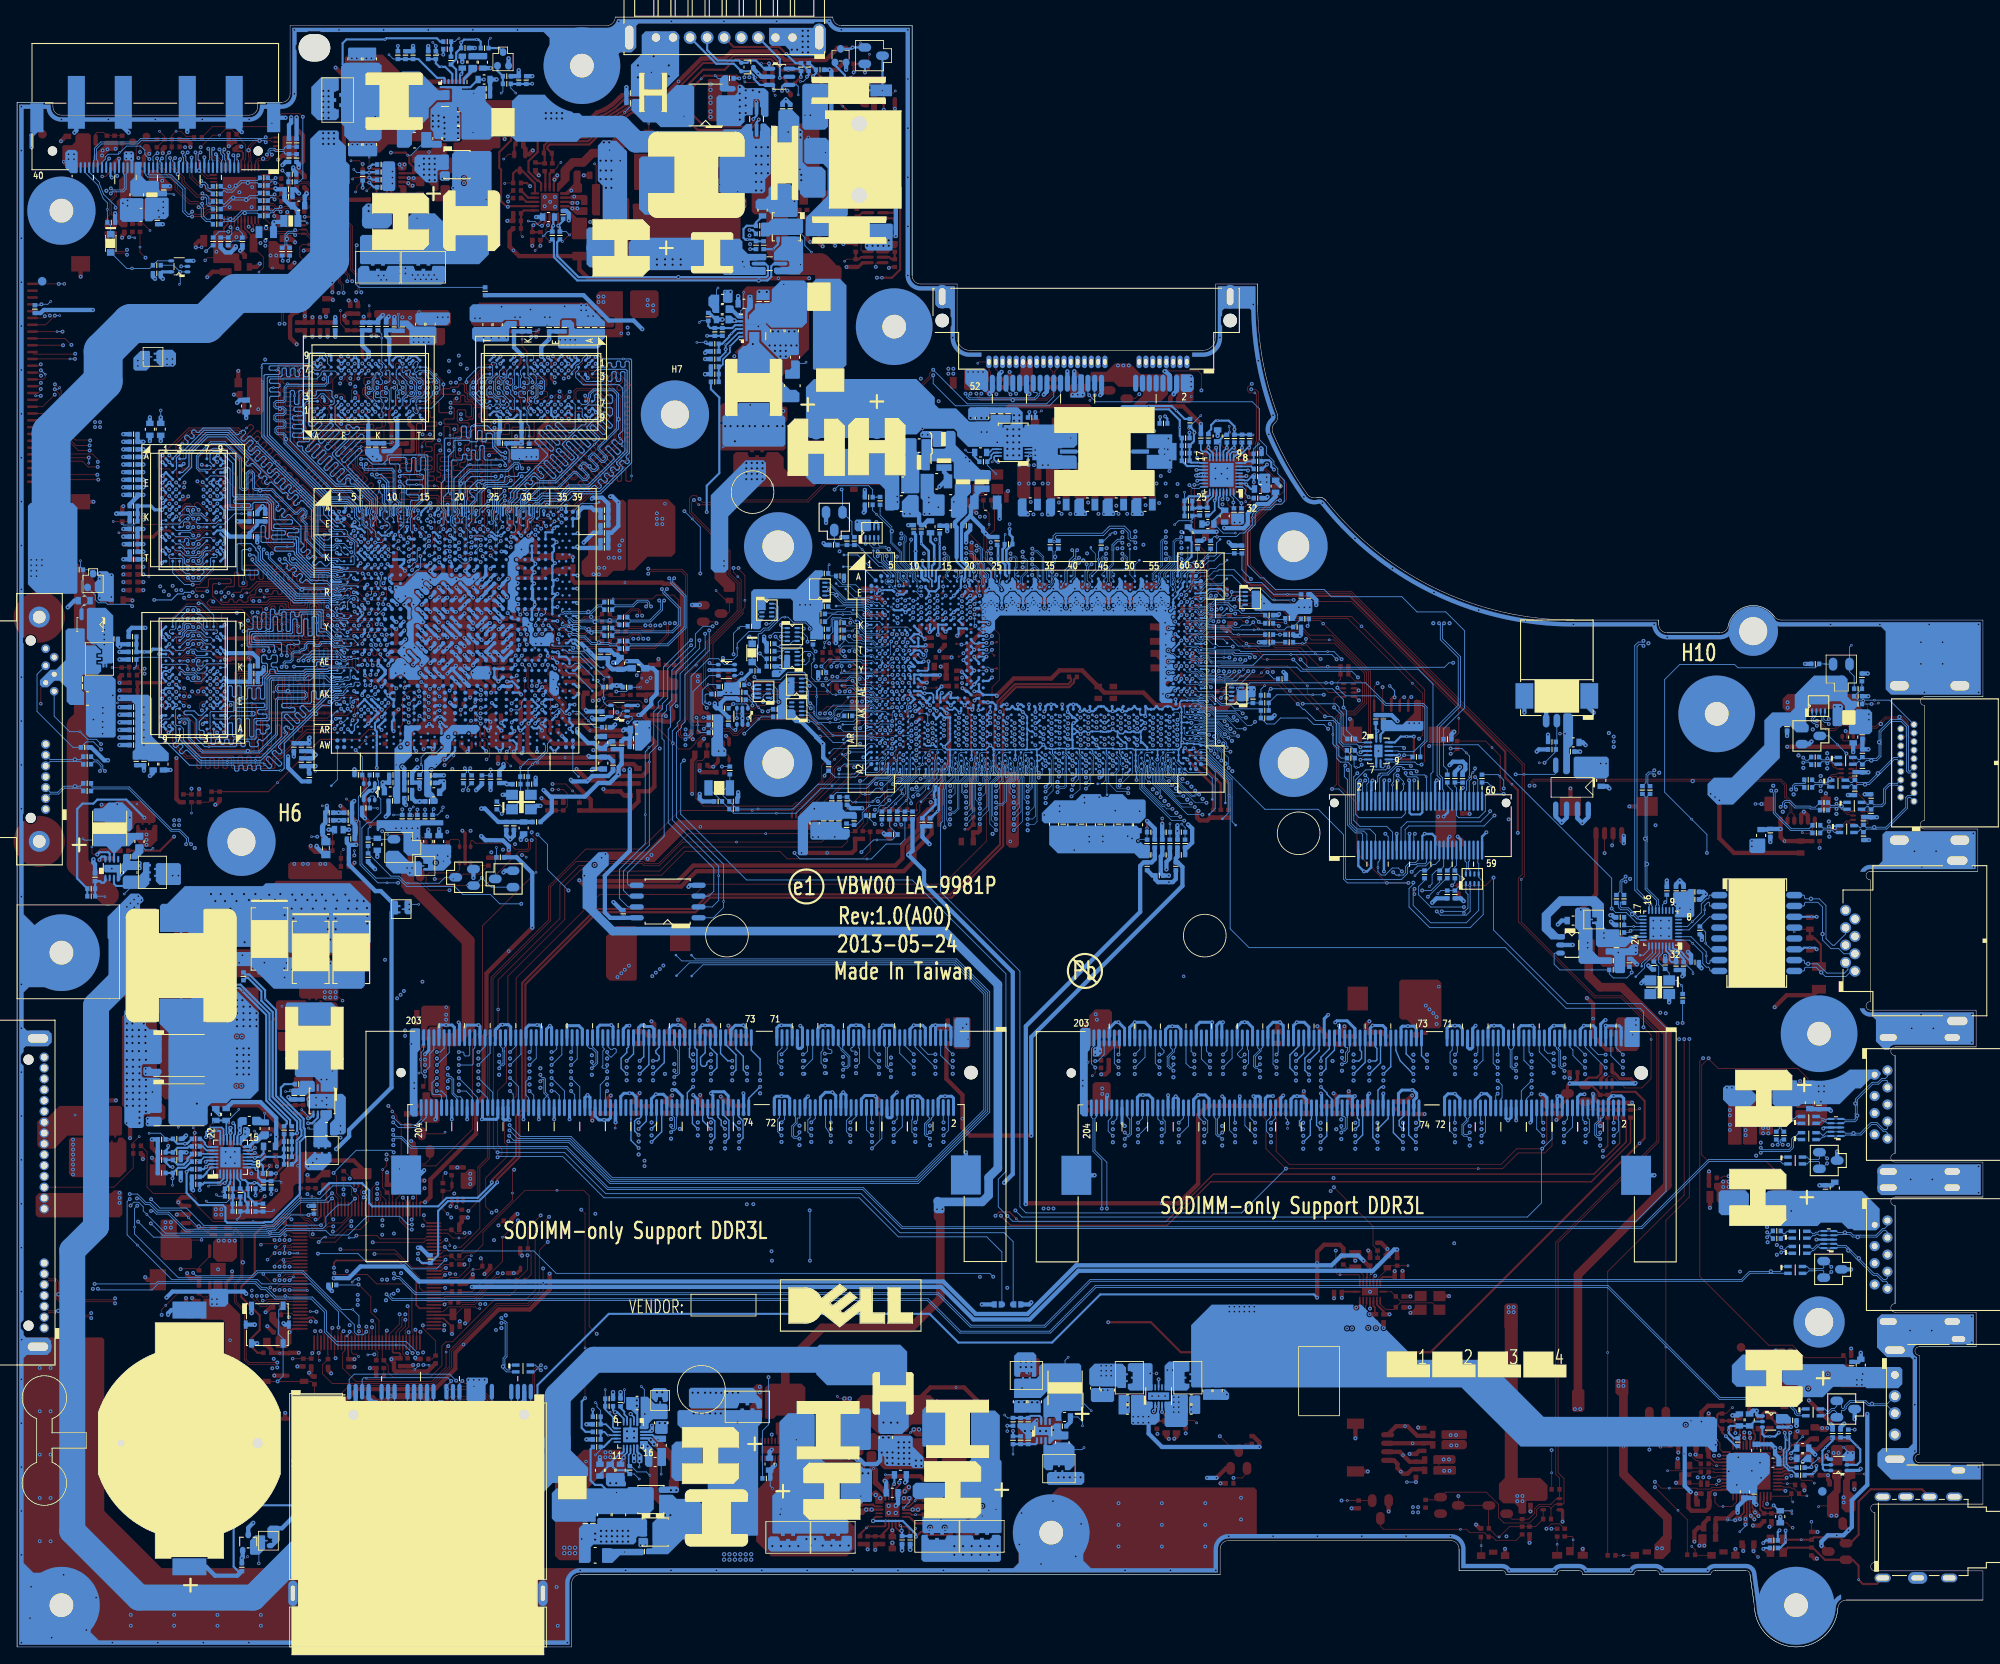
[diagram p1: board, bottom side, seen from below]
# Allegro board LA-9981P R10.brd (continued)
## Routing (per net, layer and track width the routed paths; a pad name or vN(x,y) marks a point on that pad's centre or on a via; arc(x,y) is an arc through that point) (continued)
DH_1.35V: length 4.7
  TOP w1.016: 153.38,19.31 153.38,21.99 154.78,23.39
  vias: v2(155.28,24.3) v3(153.13,18.37) v3(153.77,18.37) v3(155.74,23.77) v3(156.12,24.28)
DH_CHG: length 15.7
  TOP w0.102: v2(145.95,170.62) 145.99,170.58 145.99,169.95
  IN1 w1.016: 152.56,169.24 152.94,169.62 163.8,169.62 ; 146.84,169.24 150.46,169.24
  vias: v1(145.22,169.5) v1(145.22,168.87) v1(151.54,169.56) v1(151.54,168.92) v1(164.74,169.3) v1(165.32,169.3)
DISPOFF#: length 8.9
  BOTTOM w0.102: DX1.1 219.42,166.62 RX9.1 v2(219.82,168.54) 219.82,169.32 220.31,169.82 220.94,171.39 222.45,172.9 JLVDS.37
DL_1.35V: length 8
  IN3 w1.016: 157.52,20.03 157.52,13.35 157.06,12.9
  BOTTOM w0.102: v2(157.49,21.1) 157.45,21.14 v3(157.45,21.8)
  vias: v1(156.73,11.92) v1(157.32,11.92) v3(157.45,22.44)
DL_CHG: length 5.4
  TOP w1.016: 166.14,173.18 165.26,174.06 164.05,174.06 162.97,175.14 161.57,175.14
  vias: v2(160.96,175.49)
DPB_HPD: length 202.3
  IN2 w0.089: v1(127.28,127.84) 130.08,125.04 130.08,119.19 131.6,117.67 131.6,116.79 133.19,115.19 133.19,114.79 132.73,114.33 130.41,114.33 129.87,113.79 129.87,111.47 129.74,111.34 129.74,102.52 130.11,102.15 130.11,100.68 129.83,100.4 128.24,100.4 124.68,96.85 123.91,96.85 120.67,93.61
  IN2 w0.127: 120.67,93.61 112.6,85.55 58.15,85.55 47.67,75.07 43.65,75.07 42.57,76.15 42.57,87.2 38.26,91.51 33.94,91.51 v1(32.35,93.1)
  BOTTOM w0.076: UC1.C8 125.87,124.49 125.87,125.04 126.03,125.2 126.03,125.92 126.27,126.16 126.43,126.16 127.28,127.01 v1(127.28,127.84)
  BOTTOM w0.102: QX5.3 18.51,115.22 18.55,115.26 RX14.1 19.65,114.81 28.72,114.81 29.11,115.2 35.53,115.2 37.3,113.42 37.3,100.21 v2(34.15,97.06) 32.35,95.26 v1(32.35,93.1)
DPC_HPD: length 10.2
  BOTTOM w0.076: 128.06,131.2 128.06,130.55 128.04,130.53 128.04,129.44 126.91,128.31 126.91,127.04 125.74,125.86 UC1.A8
  BOTTOM w0.102: RC84.2 130.13,133.26 v2(129.68,132.81) 128.06,131.2
DPLL_PVSS: length 3.8
  TOP w0.254: RV248.2 167.94,108.39 RV247.2 168.44,108.91 169.05,108.91 v2(169.25,108.71) v1(169.68,108.28)
  BOTTOM w0.254: v1(169.68,108.28) 169.27,108.69 UV1.AN32
DQMA#0: length 35.3
  TOP w0.102: 162.27,147.24 162.61,147.57 164.81,147.57 165.13,147.26 165.13,146.31 UV18.D3
  TOP w0.127: 162.27,147.24 160.91,145.88 160.91,144.17 161.35,143.74 161.35,143.56 161.02,143.23 161.02,143.05 161.2,142.87 161.38,142.87 161.71,143.2 161.88,143.2 162.06,143.02 162.06,142.84 161.13,141.91 161.13,141.73 161.31,141.55 161.49,141.55 162.42,142.48 162.6,142.48 162.78,142.3 162.78,142.12 161.85,141.19 161.85,141.01 162.03,140.83 162.21,140.83 163.14,141.76 163.32,141.76 163.5,141.58 163.5,141.4 162.57,140.47 162.57,140.29 162.75,140.11 162.93,140.11 163.86,141.04 164.04,141.04 166.41,138.67 166.73,138.35 167.4,137.68 167.89,137.68 168.73,136.84 168.73,136.1 168.61,135.98 168.48,135.98 168.35,135.85 168.35,135.6 168.48,135.47 168.61,135.47 168.73,135.34 168.73,135.09 168.61,134.96 v2(168.29,134.96) 168,134.96 167.87,134.83 167.87,134.58 168,134.45 168.48,134.45 168.61,134.33 168.61,134.07 168.48,133.94 v1(168.29,133.94)
  BOTTOM w0.102: v1(168.29,133.94) 168.47,133.76 169.23,133.76 169.46,133.53 UV1.A32
DQMA#1: length 35
  BOTTOM w0.102: 161.62,151.01 161.81,151.01 162.43,151.64 163.54,151.64 164.16,151.02 164.16,150.82 164.6,150.38 164.73,150.38 164.92,150.19 164.92,149.94 165.39,149.48 UV19.D3 ; 165.81,134.4 166.15,134.4 167,133.56 168.99,133.56 169.16,133.39 169.16,132.6 UV1.C32
  BOTTOM w0.127: 165.81,134.4 165.01,135.21 162,135.21 158.38,138.83 158.38,150.89 158.51,151.01 v2(159.33,151.01) 161.62,151.01
DQMA#2: length 36.5
  IN1 w0.102: v1(165.72,146.55) 166.09,146.55 166.17,146.47 166.17,143.81 165.61,143.25
  IN1 w0.14: 165.61,143.25 165.61,143.08 165.74,142.95 166.48,142.95 166.61,142.83 166.61,142.52 166.48,142.39 165.74,142.39 165.61,142.27 165.61,141.96 165.74,141.84 166.48,141.84 166.61,141.71 166.61,141.4 166.48,141.28 165.74,141.28 165.61,141.15 165.61,140.38 165.48,140.25 164.33,140.25 164.21,140.13 164.21,138.04 165.38,136.86 168.32,136.86 168.45,136.99 168.45,137.62 168.59,137.76 168.87,137.76 169.01,137.62 169.01,136.99 169.14,136.86 169.44,136.86 169.57,136.99 169.57,137.62 169.71,137.76 169.99,137.76 170.13,137.62 170.13,136.99 170.25,136.86 170.56,136.86 170.68,136.99 170.68,137.62 170.82,137.76 172.24,137.76 173.14,136.86 173.87,136.86 174.46,136.28 174.71,136.28 175.14,136.7 175.33,136.7 175.53,136.5 175.53,136.3 175.39,136.16 175.39,135.97 175.72,135.64 175.72,134.91 v1(175.16,134.35)
  BOTTOM w0.102: UV1.D23 176.66,132.23 176.17,132.73 176.17,133.35 v1(175.16,134.35) ; UV19.E7 166.19,146.09 v1(165.72,146.55)
DQMA#3: length 37.5
  TOP w0.102: v1(165.76,148.86) 166.16,149.25 UV18.E7
  IN3 w0.102: v1(165.76,148.86) 165.18,148.86 163.28,146.97 163.28,146.29 163.38,146.19 163.55,146.19 163.65,146.09 163.65,145.89 163.55,145.78 163.38,145.78 163.28,145.68 163.28,145.37 163.41,145.24 163.7,145.24 163.83,145.11 163.83,143.25
  IN3 w0.157: v1(171.25,137.27) 171.25,137.53 171.15,137.63 170.4,137.63 170.21,137.83 164.77,137.83 163.92,138.67 163.92,139.53 163.8,139.65 162.94,139.65 162.81,139.78 162.81,140.16 162.94,140.28 163.8,140.28 163.92,140.41 163.92,140.92 163.8,141.05 162.85,141.05 162.73,141.18 162.73,141.74 162.85,141.87 163.8,141.87 163.92,141.99 163.92,142.37 163.8,142.5 162.85,142.5 162.73,142.62 162.73,143 162.85,143.13 163.7,143.13 163.83,143.25
  BOTTOM w0.102: 175.94,135.39 176.01,135.31 176.01,133.9 176.16,133.75 176.74,133.75 176.95,133.53 176.95,132.88 177.11,132.72 177.11,131.97 177.46,131.62 UV1.E22
  BOTTOM w0.127: v1(171.25,137.27) 172.5,136.02 175.31,136.02 175.94,135.39
DQMA#4: length 35.4
  IN1 w0.102: 186.94,135.39 186.32,134.76 184.85,134.76 183.41,133.32 v1(183.41,133.26) ; 194.84,142.86 195.2,143.22 195.2,148.15 195.07,148.28 193.7,148.28 193.22,148.76 v1(192.44,148.76)
  IN1 w0.14: 186.94,135.39 186.98,135.42 186.98,137.9 187.88,138.8 188.06,138.8 188.36,138.51 188.36,138.33 187.66,137.62 187.66,137.44 188.04,137.06 188.12,137.06 188.34,136.84 188.82,136.84 189.36,137.38 189.36,137.58 189.04,137.89 189.04,138.07 189.26,138.29 189.44,138.29 189.75,137.97 189.95,137.97 190.51,138.53 190.51,139.47 190.2,139.78 189.94,139.78 189.61,139.45 189.43,139.45 189.07,139.81 189.07,139.99 190.41,141.33 193.31,141.33 194.84,142.86
  BOTTOM w0.102: UV21.E7 191.98,149.22 v1(192.44,148.76)
  BOTTOM w0.109: v1(183.41,133.26) 183.41,132.8 183.86,132.35 UV1.C14
DQMA#5: length 36.1
  TOP w0.102: v1(192.99,146.64) 192.74,146.89 192.23,146.89 191.98,146.64 UV20.E7
  IN3 w0.157: v1(192.99,146.64) 192.99,145.23 193.12,145.1 193.72,145.1 193.85,144.98 193.85,144.6 193.72,144.47 193.15,144.47 192.99,144.32 192.99,142.93 193.12,142.8 195.34,142.8 195.47,142.67 195.47,142.28 195.34,142.16 193.82,142.16 193.69,142.03 193.69,141.62 193.82,141.5 194.45,141.5 194.64,141.31 194.64,139.68 193.74,138.79 190.76,138.79 190.25,139.29 v1(190.09,139.29)
  BOTTOM w0.102: UV1.A14 183.86,133.35 182.26,134.95 182.26,135.39
  BOTTOM w0.127: 182.26,135.39 182.26,139.64 182.39,139.76 v2(183.21,139.76) 186.89,139.76 187.02,139.64 187.02,139.21 187.55,138.68 188.77,138.68 189.38,139.29 v1(190.09,139.29)
DQMA#6: length 35.6
  TOP w0.102: 188.28,133.73 188.28,131.5 188.05,131.27 v1(187.66,131.27) ; UV20.D3 193.4,148.64 193.4,146.41 193.18,146.19 193.18,145.88 193.48,145.58 193.91,145.58 193.92,145.57 194.24,145.57 194.25,145.58 194.49,145.58 194.81,145.9 194.81,146.19 195,146.37
  TOP w0.127: 195,146.37 195.01,146.39 195.4,146.39 195.53,146.52 195.53,146.91 195.66,147.04 196.04,147.04 196.16,146.91 196.16,145.88 196.29,145.75 196.42,145.75 196.55,145.62 196.55,143.75 192.92,140.12 192.92,139.85 192.49,139.42 192.49,139.25 193.22,138.52 193.22,138.34 193.04,138.16 192.86,138.16 192.13,138.89 191.95,138.89 191.77,138.71 191.77,138.53 192.5,137.8 192.5,137.62 192.32,137.44 192.14,137.44 191.42,138.17 191.24,138.17 191.06,137.99 191.06,137.81 191.78,137.09 191.78,136.91 191.6,136.73 191.42,136.73 190.7,137.45 190.52,137.45 190.34,137.27 190.34,137.09 v2(190.57,136.85) 190.89,136.53 190.89,136.34 188.28,133.73
  BOTTOM w0.102: UV1.E10 187.44,131.49 v1(187.66,131.27)
DQMA#7: length 34.8
  BOTTOM w0.102: 188.66,135.39 188.15,134.88 188.15,132.88 188.26,132.78 188.26,132.6 188.15,132.5 188.15,132.29 187.86,132 UV1.D9 ; UV21.D3 192.78,145.83 193.12,145.5 193.12,143.4 192.58,142.86
  BOTTOM w0.127: 192.58,142.86 191.86,142.14 191.61,142.14 191.4,142.35 191.4,142.53 191.84,142.97 191.84,143.15 191.66,143.33 191.48,143.33 191.04,142.89 190.86,142.89 190.65,143.1 190.47,143.1 190.29,142.92 190.29,142.74 193.06,139.97 193.06,139.79 192.88,139.61 192.7,139.61 190.12,142.19 189.94,142.19 189.76,142.01 189.76,141.83 v2(191.29,140.31) 192.34,139.25 192.34,139.07 192.16,138.89 191.98,138.89 190.35,140.52 190.17,140.52 190,140.34 190,140.16 191.62,138.53 191.62,138.35 188.66,135.39
DQMB#0: length 35.7
  TOP w0.102: v1(191.21,128.35) 190.78,128.78 190.78,129.42 192.75,131.39 194.18,131.39 ; 207.91,140.67 209.18,139.39 209.18,137.93 UV22.D3
  TOP w0.127: 194.18,131.39 199.5,131.39 200.14,132.03 200.14,133.18 200.02,133.3 199.59,133.3 199.47,133.43 199.47,133.69 199.59,133.81 200.02,133.81 200.14,133.94 200.14,134.19 200.02,134.32 199.35,134.32 199.22,134.45 199.22,134.7 199.35,134.83 200.02,134.83 200.14,134.96 200.14,135.63 200.35,135.83 200.53,135.83 200.91,135.44 201.09,135.44 201.27,135.62 201.27,135.8 200.89,136.19 200.89,136.37 201.07,136.55 201.25,136.55 201.41,136.38 201.59,136.38 201.77,136.56 201.77,136.74 201.6,136.91 201.6,137.09 v2(203.09,138.57) 205.38,140.86 207.71,140.86 207.91,140.67
  BOTTOM w0.102: UV1.H3 191.88,128.89 191.34,128.35 191.22,128.35 v1(191.21,128.35)
DQMB#1: length 34.7
  BOTTOM w0.102: UV1.H1 193.15,128.6 194.39,128.6
  BOTTOM w0.127: UV23.D3 209.94,138.32 209.94,139.98 208.05,141.88 205.88,141.88 203.31,139.3 203.31,139.12 203.59,138.83 203.59,138.66 203.41,138.48 203.23,138.48 202.95,138.76 202.77,138.76 201.84,137.83 201.84,137.65 202.08,137.41 202.08,137.23 201.9,137.05 201.72,137.05 201.48,137.29 201.3,137.29 201.12,137.11 201.12,136.93 201.38,136.66 201.38,136.48 201.21,136.3 201.03,136.3 200.76,136.57 200.58,136.57 199.27,135.26 199.09,135.26 199,135.35 198.82,135.35 198.64,135.17 198.64,134.99 198.73,134.9 198.73,134.72 198.55,134.54 198.37,134.54 197.81,135.1 197.63,135.1 197.45,134.92 197.45,134.74 198.01,134.18 198.01,134 197.85,133.84 197.67,133.84 v2(197.41,134.1) 197.11,134.4 196.93,134.4 195.9,133.37 195.9,130.06 194.44,128.6 194.39,128.6
DQMB#2: length 37.6
  TOP w0.102: v1(210.77,136.53) 210.93,136.53 UV22.E7
  IN3 w0.102: 204.96,138.26 207.39,138.26 207.63,138.02 209.49,138.02 210.77,136.74 v1(210.77,136.53)
  IN3 w0.157: v1(202.83,127.52) 202.7,127.52 202.54,127.68 202.54,128.12 202.41,128.25 202.04,128.25 201.91,128.12 201.91,127.68 201.75,127.52 200.38,127.52 199.99,127.91 199.99,134.08 204.17,138.26 204.96,138.26
  BOTTOM w0.102: 194.39,122.43 193.93,122.43 193.68,122.19 192.61,122.19 192.31,122.49 UV1.T3
  BOTTOM w0.127: v1(202.83,127.52) 202.83,127.31 197.95,122.43 194.39,122.43
DQMB#3: length 40.4
  IN1 w0.102: v1(208.65,136.57) 208.2,136.12 205.94,136.12 204.96,135.14 ; v1(190.92,122.04) 192.44,120.52 194.39,120.52
  IN1 w0.14: 194.39,120.52 198.83,120.52 198.96,120.65 198.96,123.52 198.83,123.65 196.36,123.65 196.24,123.77 196.24,128.37 199.96,132.09 200.16,132.09 200.93,131.31 201.13,131.31 201.34,131.52 201.34,131.72 200.62,132.44 200.62,132.61 200.84,132.83 201.01,132.83 201.73,132.11 201.93,132.11 202.13,132.31 202.13,132.51 201.7,132.94 201.7,133.12 201.91,133.34 202.09,133.34 202.52,132.9 202.72,132.9 204.96,135.14
  BOTTOM w0.102: UV23.E7 208.19,136.1 v1(208.65,136.57) ; v1(190.92,122.04) 190.92,122.15 UV1.T5
DQMB#4: length 36.6
  TOP w0.102: UV25.E7 208.74,110.82 208.99,110.57 208.99,110.06 v1(208.74,109.81)
  IN3 w0.102: 205.1,110.11 205.4,109.81 v1(208.74,109.81)
  IN3 w0.157: v1(197.94,114.95) 197.85,115.04 197.85,115.84 197.98,115.97 198.41,115.97 198.92,115.46 199.58,115.46 200.15,114.89 200.37,114.89 200.45,114.96 200.62,114.96 200.89,114.7 200.89,114.52 200.55,114.18 200.55,114 200.82,113.73 201,113.73 201.99,114.72 202.17,114.72 202.43,114.46 202.43,114.28 201.44,113.29 201.44,113.11 201.71,112.84 201.89,112.84 202.88,113.83 203.06,113.83 203.33,113.57 203.33,113.39 202.33,112.39 202.33,112.21 202.6,111.95 202.78,111.95 203.77,112.94 203.95,112.94 204.22,112.68 204.22,112.5 203.22,111.5 203.22,111.32 203.49,111.06 203.67,111.06 204.68,112.07 204.86,112.07 205.13,111.8 205.13,111.62 204.17,110.66 204.17,110.38 204.45,110.1 204.64,110.1 204.77,110.22 204.99,110.22 205.1,110.11
  BOTTOM w0.102: UV1.AE4 191.94,115.01 192.31,115.01 192.34,114.99 192.59,114.99 192.61,115.01 194.39,115.01
  BOTTOM w0.127: v1(197.94,114.95) 195.44,114.95 195.31,115.07 195.31,115.38 195.19,115.51 194.93,115.51 194.8,115.38 194.8,115.07 194.68,114.95 194.45,114.95 194.39,115.01
DQMB#5: length 36.7
  BOTTOM w0.102: 194.39,113.6 194.3,113.6 193.82,113.12 193.11,113.12 193.03,113.2 192.7,113.2 192.67,113.17 192.21,113.17 192.04,113.34 191.48,113.34 191.36,113.47 191.36,114.4 UV1.AF5
  BOTTOM w0.127: 194.39,113.6 195.8,113.6 196.04,113.36 200.49,113.36 200.59,113.26 200.59,107.24 201.58,106.25 201.76,106.25 201.89,106.38 202.07,106.38 202.25,106.2 202.25,106.02 202.12,105.9 202.12,105.72 202.28,105.55 203.02,105.55 203.14,105.68 203.14,106.05 203.27,106.18 203.53,106.18 203.65,106.05 203.65,105.68 203.78,105.55 204.03,105.55 204.16,105.68 204.16,106.05 204.29,106.18 204.54,106.18 204.67,106.05 204.67,105.68 204.8,105.55 v2(207.91,105.55) 208.41,105.55 209.41,106.55 209.41,108.77 209.94,109.3 210.71,109.3 210.83,109.43 210.83,109.62 210.71,109.75 209.63,109.75 209.12,109.24 208.75,109.24 208.15,109.84 UV24.D3
DQMB#6: length 35.8
  IN1 w0.102: 205.75,107.6 208.88,107.6 210.86,109.58 v1(210.86,110.36) ; 193.43,111.4 191.53,111.4 190.99,110.86 v1(190.99,110.8)
  IN1 w0.14: 205.75,107.6 205.59,107.76 205.01,107.76 204.87,107.62 204.87,107.32 204.73,107.18 204.45,107.18 204.31,107.32 204.31,107.62 204.18,107.76 203.9,107.76 203.76,107.62 203.76,107.32 203.62,107.18 203.34,107.18 203.2,107.32 203.2,107.62 203.06,107.76 202.78,107.76 202.64,107.62 202.64,107.32 202.5,107.18 202.22,107.18 202.08,107.32 202.08,107.62 201.94,107.76 197.05,107.76 196.93,107.89 196.93,111.27 196.8,111.4 196.44,111.4 196.31,111.27 196.31,109.74 196.18,109.62 195.88,109.62 195.75,109.74 195.75,111.27 195.62,111.4 195.32,111.4 195.19,111.27 195.19,109.74 195.07,109.62 194.76,109.62 194.63,109.74 194.63,111.27 194.51,111.4 193.43,111.4
  BOTTOM w0.102: UV1.AK6 190.88,111.09 190.99,110.99 v1(190.99,110.8) ; v1(210.86,110.36) 211.32,110.82 UV24.E7
DQMB#7: length 36
  TOP w0.102: UV25.D3 209.63,108.29 209.63,106.26 ; v1(191.08,110.25) 191.08,110.25 191.08,109.87 191.76,109.2 193.73,109.2 194.03,108.9 194.39,108.9
  TOP w0.127: 209.63,106.26 209.63,105.86 209,105.23 203,105.23 202.88,105.36 v2(202.88,109.43) 202.88,110.39 202.75,110.52 202.5,110.52 202.37,110.39 202.37,107.08 202.24,106.95 201.99,106.95 201.86,107.08 201.86,108.67 201.63,108.9 194.39,108.9
  BOTTOM w0.102: UV1.AK5 191.37,111.18 191.37,110.64 191.08,110.35 v1(191.08,110.25)
DRAM_RST#: length 141.9
  TOP w0.102: UV20.T2 182.14,150.05 v2(181.29,149.2) 180.44,148.35 v1(180.44,148.04) ; UV25.T2 212.15,120.66 210.52,122.29 209.19,122.29 v1(209.12,122.36) ; UV22.T2 207.35,127.3 207.35,126.27 209.06,124.56 v1(209.82,124.56) ; UV18.T2 176.16,146.43 177.24,146.43 177.41,146.59 177.41,147.01 177.73,147.33 v1(177.73,148.29)
  TOP w0.127: v1(209.96,100.63) RV143.1 RV138.2
  IN1 w0.102: 209.42,122.56 209.23,122.36 v1(209.12,122.36) ; v1(180.44,148.04) 180.37,147.97 180.3,147.97 180.24,147.91 ; v1(177.73,148.29) 177.81,148.29 177.93,148.18 ; 209.82,124.36 v1(209.82,124.56)
  IN1 w0.14: 180.24,147.91 179.91,147.91 v1(179.57,148.24) 179.13,147.81 178.29,147.81 177.93,148.18 ; 209.42,122.56 209.82,122.95 v1(209.82,123.65) 209.82,124.36
  IN3 w0.157: v1(179.57,148.24) 179.57,148.82 178.96,149.43 178.96,150.58 178.7,150.83 178.38,150.83 178.13,151.08 178.13,152.04 180.35,154.26 198.91,154.26 200.54,152.62 200.54,149.19 201.7,148.03 211.73,148.03 216.36,143.4 216.36,130.76 214.58,128.99 214.58,123.02 v1(214.33,122.76) 214.33,105.62 209.96,101.25 v1(209.96,100.63)
  BOTTOM w0.102: v1(177.73,148.29) 177.73,148.67 176.35,150.05 UV19.T2 ; v1(209.82,124.56) 210.77,124.56 212.15,125.94 UV23.T2 ; v1(209.12,122.36) 208.74,122.36 207.35,120.98 UV24.T2 ; v1(180.44,148.04) 180.44,146.64 181.82,145.25 UV21.T2
  BOTTOM w0.127: v1(214.33,122.76) 212.29,122.76 211.6,123.46 210.96,123.46 210.77,123.65 v1(209.82,123.65)
DRAM_RST#_R: length 28.8
  TOP w0.127: v1(185.95,112.4) 186.08,112.28 186.08,110.94 187.24,109.79 187.24,108.62 188.29,107.56 189.16,107.56 190.31,106.41 194.81,106.41 v2(199.88,101.34) 200.94,100.28 RV145.2 RV144.2
  BOTTOM w0.102: UV1.AH11 186.24,112.69 v1(185.95,112.4)
DROOP_CPU: length 6.4
  BOTTOM w0.102: v2(93.58,135.39) PC513.2
  BOTTOM w0.203: 90.96,134.88 90.77,134.88 90.62,135.04 PU501.25
  BOTTOM w0.254: 90.96,134.88 91.09,134.88 91.11,134.91 93.04,134.91 PC513.2 PR532.1 PR529.2
DSWODVREN: length 11.1
  BOTTOM w0.076: 128.36,100.51 127.81,100.51 127.37,100.95 127.37,101.51 127.12,101.76 126.81,101.76 126.81,101.76 126.71,101.76 126.45,102.03 126.45,103.29 UC1.AW7
  BOTTOM w0.102: 128.36,100.51 129.26,99.61 129.63,99.61 130.18,99.05 v2(132.08,99.05) 132.52,99.05 R2338.1 R2337.1
EC_ENVDD: length 149.5
  TOP w0.102: UE1.71 193.19,52.36 193.41,52.59 v1(193.48,52.59) ; v1(215.34,162.89) 215.99,163.54 v2(215.99,164.13) RX8.2
  IN2 w0.127: v1(215.34,162.89) 215.78,162.46 215.78,154.88 224.83,145.83 224.83,123.6 223.93,122.71 223.93,110.74 225.35,109.32 225.35,96.89 224.8,96.34 224.8,84.96 221.9,82.05 221.9,59.04 216.35,53.5 v1(216.35,52.6)
  BOTTOM w0.102: v1(216.35,52.6) 216.1,52.6 215.37,51.86 214.87,51.86 213.98,50.97 212.6,50.97 210.59,48.97 201.17,48.97 201.11,49.03 200.25,49.03 197.13,52.14 193.93,52.14 v1(193.48,52.59)
EC_LID_OUT#: length 123.8
  TOP w0.102: UE1.101 182.38,48.11 182.64,47.85 187.85,47.85 188.23,48.23 v1(190.63,48.23)
  IN1 w0.084: 137.92,107.8 137.76,107.64 135.69,107.64 135.12,108.21 133.76,108.21 132.78,109.19 129.74,109.19 129.59,109.35 128.1,109.35 127.69,108.94 127.69,108.94 127.53,108.79 125.19,108.79 124.57,109.4 124.57,109.48 124.56,109.48 124.56,110.18 124.61,110.22 124.61,110.99 125.27,111.66 125.27,112.34 125.6,112.67 126.86,112.67 v1(127.22,113.03)
  IN1 w0.127: 137.92,107.8 138.72,108.6 144.07,108.6 144.47,108.19 146.67,108.19 147.9,106.96 147.9,106.45 152.68,101.66 152.68,101.51 160.21,93.98 160.21,91.51 166.91,84.81 171.57,84.81 172.21,84.16 174.26,84.16 177.94,80.48 179.76,80.48 187.15,73.09 187.15,64.86 188.31,63.7 188.31,55.05 187.76,54.5 187.76,52.38 190.26,49.87 190.26,48.59 v1(190.63,48.23)
  BOTTOM w0.089: UC1.AD6 126.99,112.8 v1(127.22,113.03)
  BOTTOM w0.102: v2(191.48,47.97) 190.89,47.97 v1(190.63,48.23)
EC_MUTE#: length 189.3
  TOP w0.102: UE1.83 188.39,52.34 v1(188.2,52.53) ; UA1.47 28.88,17.01 29.41,16.48 v2(30.47,16.48) 30.94,16.48 31.4,16.94 v1(31.4,17.92)
  IN1 w0.127: v1(190.47,41.29) 191.07,41.89 191.07,48.55 190.52,49.1 190.52,50.21 v1(188.2,52.53)
  IN3 w0.127: v1(31.4,17.92) 32.41,16.9 40.03,16.9 59.76,36.62 90.62,36.62 93.7,39.71 171.22,39.71 171.83,40.32 174.33,40.32 174.94,39.71 182.35,39.71 183.63,40.99 185.4,40.99 186.18,40.22 187.37,40.22 188.43,41.29 v1(190.47,41.29)
EC_ON: length 97.6
  TOP w0.102: UE1.112 180.72,43.71 180.4,44.03 179.92,44.03 v1(179.67,43.77) 179.09,43.77 v4(179.02,43.7)
  TOP w0.254: v1(121.68,13.98) 121.65,14.02 PR102.1
  IN1 w0.127: v1(121.68,13.98) 121.68,15.45 116.79,20.34 116.79,42.63 v1(117.55,43.39)
  IN3 w0.127: v1(117.55,43.39) 117.68,43.27 179.16,43.27 v1(179.67,43.77)
EC_RSMRST#: length 87.8
  TOP w0.089: v1(129.86,98.16) 129.68,98.16 128.57,97.05 RC41.1 128,95.82 RE2.2
  TOP w0.102: v1(177.37,48.57) 177.37,48.55 177.97,47.95 v2(178.61,47.95) 179.35,47.95 179.91,48.51 UE1.100
  IN1 w0.084: 130.5,97.49 130.5,97.52 v1(129.86,98.16)
  IN1 w0.127: v1(177.37,48.57) 176.76,49.18 176.76,58.15 174.44,60.48 174.44,63.39 173.42,64.41 173.42,71.36 169.38,75.4 159.75,75.4 157.37,77.79 155.35,77.79 139.27,93.86 135.92,93.86 135.56,94.22 134.73,94.22 134.14,94.81 134.14,95.4 133.46,96.09 133.23,96.09 132.02,97.29 130.69,97.29 130.5,97.49
EC_RST#: length 3.3
  TOP w0.102: UE1.37 197.98,38.91 198.2,39.13 199.28,39.13 RE8.1 CE11.1
EC_RX: length 169.3
  TOP w0.102: v2(117.81,150.51) 117.65,150.67 JMINI.51 116.5,149.71 116.3,149.52 116.3,149.11 115.98,148.79 RM13.1 ; UE1.31 195.19,36.74 v1(195.48,37.03)
  IN2 w0.089: 137.92,127.05 137.76,127.21
  IN2 w0.127: v1(195.48,37.03) 194.91,36.46 189.23,36.46 187.97,37.71 187.97,40.99 188.29,41.31 188.29,44.56 186.91,45.94 186.91,54.43 187.8,55.32 187.8,61.91 186.38,63.33 186.38,65.57 187.03,66.21 187.03,74.16 184.07,77.11 184.07,78.35 182.91,79.51 182.49,79.51 162.1,99.9 162.1,100.76 161.63,101.23 158.21,101.23 153.42,106.02 153.42,108.58 153.29,108.71 153.29,109.59 153.77,110.08 153.77,110.47 151.83,112.42 151.83,114.65 148.74,117.74 144.68,117.74 144.02,118.4 144.02,120.96 137.92,127.05 ; 137.76,127.21 137.38,127.6 137.38,138.69 126.66,149.41 124.06,149.41 123.31,148.66 116.87,148.66 116.5,149.03 JMINI.51
EC_SCI#: length 125.4
  TOP w0.102: v1(191.42,36.97) 191.23,36.97 190.79,36.53 UE1.20
  IN1 w0.127: v1(191.42,36.97) 191.96,37.51 191.96,37.93 194.36,40.33 194.36,50.2 194.57,50.4 194.57,53.91 194.31,54.17 194.31,55.37 191.65,58.03 191.65,65.07 190.66,66.06 190.66,76.15 183.27,83.53 179.2,83.53 174.17,88.56 169.79,88.56 155.48,102.88 155.48,104.94 v1(155.08,105.33)
  IN3 w0.084: 137.82,107.19 130.28,107.19 129.46,108.01 v1(127.86,108.01)
  IN3 w0.127: v1(155.08,105.33) 155.08,105.45 152.38,108.14 149.74,108.14 149.33,107.73 147.41,107.73 146.31,106.63 144.79,106.63 143.71,107.71 138.98,107.71 138.47,107.19 137.82,107.19
  BOTTOM w0.089: UC1.AM2 129.49,107.85 129.12,108.21 128.06,108.21 v1(127.86,108.01)
  BOTTOM w0.102: v2(191.75,36.47) 191.42,36.79 v1(191.42,36.97)
EC_SMB_CK1: length 241.5
  TOP w0.102: v1(145.16,184.05) 145.23,183.99 145.23,183.63 v2(145.09,183.5) 145.01,183.42 143.59,183.42 143.36,183.65 PR18.2 ; UE1.77 190.79,52.56 v1(190.79,52.57) 190.79,52.59 191.2,52.99 191.2,53.72 190.9,54.02 RP36.4 ; v1(172.88,170.06) 172.88,170.13 PR714.1
  IN1 w0.127: v1(172.88,170.06) 173.06,169.89 173.44,169.89 173.63,170.07 173.63,172.79 169.89,176.53 164.91,176.53 162.1,179.33 156.67,179.33 151.15,184.85 145.58,184.85 145.16,184.43 v1(145.16,184.05)
  IN2 w0.127: v1(172.88,170.06) 172.81,170.06 172.24,169.49 172.24,162.89 173.64,161.49 179.61,161.49 181.13,163.02 188.67,163.02 190.57,164.92 193.64,164.92 198.95,159.61 209.01,159.61 223.05,145.57 223.05,124.98 222.28,124.21 222.28,124.06 222.28,110.41 223.95,108.74 223.95,97.47 223.41,96.92 223.41,85.54 220.5,82.63 220.5,59.79 213.8,53.09 213.8,50.58 v1(214.72,49.66)
  BOTTOM w0.102: v1(190.79,52.57) 191.53,51.83 192.79,51.83 194.21,50.4 194.21,49.41 194.58,49.04 198.92,49.04 199.62,48.34 200.78,48.34 200.86,48.27 213.33,48.27 214.72,49.67 v1(214.72,49.66)
EC_SMB_CK2: length 226
  TOP w0.102: RP36.2 189.9,53.74 190.17,53.47 190.17,53.12 v1(189.77,52.72) 189.99,52.5 UE1.79 ; QX6.3 196.97,164.43 197.26,164.13 197.26,163.28 197.26,163.04 196.82,162.6 195.61,162.6 195.29,162.27 195.29,161.42 195.46,161.25 197.85,161.25 199.42,159.68 199.42,155.36 v1(199.63,155.14) ; v1(156.43,126.42) 156.36,126.35 152.46,126.35 151.81,125.7 151.81,114.7 151.87,114.64 151.87,108.79 152.64,108.01 152.64,106.98 152.48,106.82 152.25,106.82 v1(152.07,107) ; QV15.6 178.54,91.12 178.91,90.75 182.15,90.75 182.46,90.43 182.46,89.55 182.21,89.29 v2(177.59,89.29) 175.51,89.29 171.51,93.29 170.53,93.29 170.23,93.58 170.23,94.45 v1(170.08,94.6)
  IN1 w0.127: v1(189.77,52.72) 189.6,52.88 189.36,52.88 189.04,53.19 189.04,56.68 188.81,56.91 188.81,63.94 187.66,65.1 187.66,74.86 186.17,76.35 185.94,76.35 185.86,76.27 v1(185.86,76.05) ; v1(199.63,155.14) 199.52,155.25 199.52,155.67 199.16,156.03 197.77,156.03 197.09,155.36 166,155.36 165.34,154.7 162.55,154.7 161.7,153.85 161.7,151.06 161.06,150.42 161.06,136.07 157.75,132.75 157.75,127.18 156.81,126.24 156.61,126.24 v1(156.43,126.42)
  IN3 w0.127: v1(185.86,76.05) 185.86,76.31 186.21,76.65 186.21,77.4 174.12,89.49 174.12,94.12 172.79,95.45 170.63,95.45 170.26,95.08 170.26,94.78 v1(170.08,94.6) 170.27,94.42 170.27,94.23 170.16,94.12 169.71,94.12 164.03,99.8 164.03,100.62 159.91,104.74 155.08,104.74 153.05,106.77 152.3,106.77 v1(152.07,107)
  BOTTOM w0.102: v1(152.07,107) 151.89,106.82 151.73,106.82 151.41,107.14 151.41,113.78 149.32,115.87 148.19,115.87 147.5,115.18 QH1.6
EC_SMB_DA1: length 238.6
  TOP w0.102: v1(144.58,184.04) 144.54,184 v2(143.83,184) 143.33,184 PR20.2 ; RP36.3 190.4,53.94 v1(190.79,53.55) 190.79,53.3 190.39,52.89 UE1.78 ; PR715.1 172.45,169.87 v1(172.84,169.48)
  IN1 w0.127: v1(144.58,184.04) 144.58,184.21 145.47,185.1 151.26,185.1 156.77,179.59 162.21,179.59 165.01,176.78 169.99,176.78 173.88,172.89 173.88,169.96 173.55,169.63 173,169.63 v1(172.84,169.48)
  IN2 w0.127: v1(214.7,52.5) 214.7,53.27 221.01,59.58 221.01,82.42 223.91,85.33 223.91,96.71 224.46,97.26 224.46,108.95 222.79,110.62 222.79,123.85 223.69,124.75 223.69,145.65 209.22,160.12 199.16,160.12 193.85,165.43 190.36,165.43 188.46,163.52 180.92,163.52 179.4,162 173.89,162 172.75,163.14 172.75,166.32 173.38,166.95 173.38,169.11 173.02,169.48 v1(172.84,169.48)
  BOTTOM w0.102: v1(214.7,52.5) 213.65,51.46 210.55,51.46 208.52,49.43 201.36,49.43 201.3,49.49 200.44,49.49 197.32,52.6 194.86,52.6 193.4,54.06 191.3,54.06 v1(190.79,53.55)
EC_SMB_DA2: length 206.1
  TOP w0.102: QX6.6 194.75,163.13 195.06,162.81 195.06,161.32 195.36,161.02 197.76,161.02 199.19,159.59 199.19,155.28 v1(199.05,155.14) ; QV15.3 177.24,94.45 177.14,94.55 177,94.55 176.69,94.24 172.73,94.24 172.01,93.52 170.62,93.52 170.46,93.68 170.46,94.37 v1(170.69,94.6) ; v1(156.43,125.84) 156.14,126.12 152.56,126.12 152.04,125.61 152.04,114.8 152.1,114.74 152.1,108.88 152.87,108.11 152.87,106.89 152.57,106.59 152.25,106.59 v1(152.07,106.41) ; RP36.1 189.4,53.67 v1(189.77,53.3) 189.36,52.89 189.36,52.53 189.59,52.3 UE1.80
  IN1 w0.127: v1(156.43,125.84) 156.58,125.98 156.91,125.98 158,127.07 158,132.65 161.32,135.96 161.32,150.32 161.95,150.95 161.95,153.74 162.65,154.44 165.45,154.44 166.11,155.1 197.2,155.1 197.87,155.78 199.06,155.78 199.27,155.57 199.27,155.36 v1(199.05,155.14) ; v1(185.45,76.46) 185.7,76.46 185.84,76.6 186.28,76.6 187.91,74.97 187.91,65.2 189.07,64.05 189.07,57.01 189.3,56.79 189.3,53.3 189.46,53.13 189.6,53.13 v1(189.77,53.3)
  IN3 w0.127: v1(185.45,76.46) 185.66,76.46 185.95,76.76 185.95,77.3 173.87,89.38 173.87,94.02 172.69,95.2 170.73,95.2 170.51,94.98 170.51,94.82 170.69,94.63 v1(170.69,94.6) 170.52,94.43 170.52,94.12 170.26,93.86 169.61,93.86 163.78,99.69 163.78,100.51 159.81,104.48 154.97,104.48 152.95,106.51 152.17,106.51 v1(152.07,106.41)
  BOTTOM w0.102: v1(152.07,106.41) 151.89,106.59 151.64,106.59 151.18,107.04 151.18,112 149.3,113.88 QH1.3
EC_SMI#: length 122.6
  TOP w0.102: UE1.15 188.79,37.46 v1(188.8,37.48)
  IN1 w0.127: v1(188.8,37.48) 188.8,37.48 189.11,37.78 189.11,37.79 191.32,40.01 191.32,48.65 190.77,49.2 190.77,50.89 190.22,51.43 190.22,56.22 189.32,57.12 189.32,64.16 188.26,65.22 188.26,75.11 182.13,81.24 178.25,81.24 174.57,84.92 172.53,84.92 171.88,85.57 167.23,85.57 161.03,91.77 161.03,94.24 153.44,101.82 153.44,103.86 152.55,104.76 151.74,104.76 150.42,106.08 150.42,108 150.16,108.27 149.74,108.27 147.02,110.98 144.81,110.98 v1(144.21,110.38)
  IN2 w0.089: v1(134.97,114.95) 135.41,115.39 136.92,115.39 137.92,114.39
  IN2 w0.127: v1(144.21,110.38) 141.74,112.85 139.46,112.85 137.92,114.39
  BOTTOM w0.089: v1(134.97,114.95) 134.97,115.11 v2(134.66,115.42) 134.52,115.56 131.58,115.56 131.36,115.34 UC1.V1
  BOTTOM w0.102: RC107.1 144.57,111.06 144.21,110.69 v1(144.21,110.38)
EC_SPI_CLK_R: length 144
  TOP w0.102: v1(180.32,37.72) 180.32,37.83 180.59,38.11 UE1.126
  IN1 w0.127: v1(180.32,37.72) 179.98,37.37 177.08,37.37 173.04,41.42 173.04,56.58 172.05,57.57 172.05,59.93 v1(172.69,60.56)
  BOTTOM w0.102: v1(172.69,60.56) 171.75,59.62 165.56,59.62 160.73,54.79 124.97,54.79 116.87,62.89 116.87,76.62 120.46,80.21 151.6,80.21 T185.1
EC_SPI_CS0#: length 142.6
  TOP w0.102: UE1.128 180.52,37.31 v1(180.34,37.13)
  IN1 w0.127: v1(180.34,37.13) 180.33,37.12 176.98,37.12 172.79,41.31 172.79,56.48 171.68,57.58 171.68,60.2 v1(172.67,61.19)
  BOTTOM w0.102: T186.1 150.02,79.98 120.56,79.98 117.1,76.52 117.1,62.98 125.07,55.01 160.63,55.01 165.47,59.85 171.39,59.85 172.67,61.14 v1(172.67,61.19)
EC_SPI_MISO_1: length 140.2
  TOP w0.102: UE1.120 180.52,40.51 180.15,40.88 176.71,40.88 174.26,43.33 173.96,43.33 v1(173.47,43.81)
  IN1 w0.127: v1(172.72,59.93) 172.39,59.6 172.39,57.59 173.29,56.69 173.29,43.99 v1(173.47,43.81)
  BOTTOM w0.102: T184.1 152.5,80.44 120.37,80.44 116.64,76.71 116.64,62.79 124.88,54.56 160.82,54.56 165.66,59.4 172.19,59.4 v1(172.72,59.93)
EC_SPI_MOSI_1: length 137.6
  TOP w0.102: UE1.119 180.45,40.91 180.25,41.11 176.81,41.11 174.08,43.84 v1(174.07,43.84)
  IN1 w0.127: v1(172.82,59.29) 172.65,59.12 172.65,57.69 173.56,56.78 173.56,44.35 v1(174.07,43.84)
  BOTTOM w0.102: T183.1 150.92,80.67 120.27,80.67 116.41,76.81 116.41,62.7 124.78,54.33 160.92,54.33 165.75,59.17 172.7,59.17 v1(172.82,59.29)
EC_TX: length 168.4
  TOP w0.102: v2(194.96,33.61) 195.05,33.7 v1(195.05,34.47) 194.79,34.73 UE1.30 ; RM11.2 115.09,148.85 115.42,149.18 115.42,149.56 115.7,149.84 JMINI.49
  IN2 w0.089: 137.92,126.7 137.4,127.21
  IN2 w0.127: 137.4,127.21 137.13,127.49 137.13,138.59 126.55,149.16 124.16,149.16 123.41,148.41 116.76,148.41 116.25,148.93 116.25,149.6 115.7,150.15 JMINI.49 ; 137.92,126.7 143.77,120.85 143.77,118.29 144.58,117.49 148.64,117.49 151.58,114.54 151.58,112.31 152.68,111.21 152.68,110.14 153.04,109.78 153.04,108.6 153.16,108.48 153.16,105.91 158.13,100.95 160.7,100.95 182.52,79.13 182.78,79.13 183.81,78.1 183.81,77.01 186.77,74.05 186.77,66.32 186.12,65.67 186.12,63.23 187.54,61.81 187.54,55.42 186.66,54.54 186.66,45.84 188.04,44.45 188.04,41.42 187.72,41.1 187.72,37.61 190.14,35.19 194.33,35.19 v1(195.05,34.47)
ECAGND: length 169.7
  TOP w0.203: LE2.2 194.15,53.93 194.15,52.34 193.99,52.18 UE1.69
  TOP w0.254: LE2.2 194.21,53.91 194.78,53.34 194.86,53.34 v1(194.99,53.21) ; v1(174.77,54.48) 174.7,54.54 174.7,54.78 171.91,57.57 171.91,62.28 171.2,62.99 171.2,77.86 162.54,86.52 151.06,86.52 149.35,88.24 121.03,88.24 115.19,94.08 115.19,101.22 115.36,101.38 115.36,103.04 115.87,103.55 v2(115.87,104.86) 115.87,109.67 115.5,110.04 115.5,110.84 113.47,112.88 107.22,112.88 106.86,113.23 106.86,113.5 PH1.2 ; v1(198.24,50.14) 198.43,50.33 199.34,50.33 CE9.1 200.32,49.35 201.57,49.35 202.54,48.37 202.54,43.83 204.12,42.25 204.12,41.03 201.96,38.87 201.96,37.16 202.91,36.21 202.91,35.19 202.21,34.49 CE7.2
  IN3 w0.254: v1(198.24,50.14) 198.24,50.53 196.24,52.53 195.67,52.53 v1(194.99,53.21)
  BOTTOM w0.254: v1(194.99,53.21) 194.98,53.21 193.81,54.38 189.97,54.38 189.13,53.54 189.13,52.02 188.78,51.66 181.04,51.66 180.05,52.65 176.42,52.65 174.7,54.37 174.7,54.42 v1(174.77,54.48)
EDID_CLK: length 28.6
  TOP w0.102: UX4.46 202.92,174.05 202.99,174.13 202.99,174.79 203.05,174.85 203.05,175.83 202.28,176.6 v3(201.98,176.6) 201.42,176.6 201.25,176.43 v1(201.26,176.43) 201.07,176.61 200.67,176.61 200.54,176.47 RP56.3
  BOTTOM w0.102: v1(201.26,176.43) 201.46,176.63 215.84,176.63 216.25,176.22 220.5,176.22 221.09,175.64 221.09,174.38 220.95,174.25 JLVDS.34
EDID_DATA: length 29.3
  TOP w0.102: RP56.4 200.54,176.97 200.67,176.84 201.08,176.84 v1(201.26,177.01) 201.25,177.01 201.42,176.83 202.37,176.83 203.28,175.92 v3(203.28,175.49) 203.28,174.75 203.22,174.69 203.22,174.13 203.32,174.03 UX4.45
  BOTTOM w0.102: JLVDS.35 221.45,174.25 221.31,174.38 221.31,175.73 220.6,176.45 216.34,176.45 215.93,176.86 201.41,176.86 v1(201.26,177.01)
EDP_AUX: length 5.4
  BOTTOM w0.102: RX39.2 202.24,171.67 v3(203.36,171.67) 204.06,171.67 205.16,170.57 205.88,170.57 206.03,170.72 206.18,170.72 RX40.1
EDP_AUX#: length 5.4
  BOTTOM w0.102: RX37.2 202.24,171.94 204.17,171.94 v3(204.78,171.33) 205.27,170.84 205.77,170.84 205.92,170.99 206.26,170.99 RX38.1
EDP_BIA_PWM: length 143.2
  TOP w0.102: UX4.21 205.32,166.52 v1(205.38,166.46)
  IN1 w0.127: v1(134.59,135.7) 133.24,137.05 129.33,137.05 128.33,138.05 119.45,138.05 118.19,136.79 114.75,136.79 112.78,134.82 109.61,134.82 109.21,134.42 109.21,134.21 108.68,133.68 105.25,133.68 102.99,131.42 102.49,131.42 v1(101.69,130.63)
  IN3 w0.127: v1(134.59,135.7) 135.15,135.14 148.16,135.14 149.25,134.05 151.68,134.05 158.92,141.29 158.92,152.11 160.65,153.83 160.65,155.34 164.23,158.92 188.92,158.92 190.94,160.94 203.25,160.94 205.43,163.12 205.43,165.51 205.22,165.72 205.22,166.3 v1(205.38,166.46)
  BOTTOM w0.102: RC81.2 129.63,134.83 129.66,134.81 RC75.2 130.13,135.7 130.58,136.15 134.13,136.15 v1(134.59,135.7) ; v1(205.38,166.46) 205.24,166.31 205.24,165.66 RX49.1 RX36.1 ; RC72.2 103.08,129.64 v2(102.32,130.4) 102.09,130.63 v1(101.69,130.63)
EDP_BKLCTL: length 10.6
  BOTTOM w0.076: 127.87,131.34 v3(127.87,130.81) 127.87,129.51 126.75,128.38 126.75,127.11 125.45,125.8 125.45,124.98 UC1.B8
  BOTTOM w0.089: 129.25,133.14 129.25,132.71 127.87,131.34
  BOTTOM w0.102: RC81.1 129.25,133.14
EDP_COMP: length 2.9
  TOP w0.089: v2(119.91,123.99) 119.65,123.73 v1(119.65,123.24)
  TOP w0.508: RC71.2 118.77,124.03 119.04,123.76 119.04,123.76 119.57,123.24 v1(119.65,123.24)
  BOTTOM w0.254: UC1.D20 119.27,123.61 v1(119.65,123.24)
EDP_CPU_AUX: length 137.6
  TOP w0.102: CX43.1 198.15,171.64 198.01,171.64 197.83,171.46 197.83,171.31 RX25.1 197.17,171.56 196.37,171.56 191.29,166.48 191.29,161.43 190.47,160.6 190.47,159 v1(190.64,158.82)
  IN1 w0.127: v1(102.76,127.57) 102.77,127.57 102.77,127.57 102.92,127.72 103.48,127.72 105.58,129.82 108.8,129.82 110.14,131.16 113.52,131.16 116.65,134.28 119.68,134.28 120.73,135.33 127.39,135.33 129.3,133.42 131.96,133.42 132.2,133.18 136.81,133.18 138.03,134.41 148.66,134.41 149.52,135.27 153.36,135.27 158.34,140.25 158.34,149.25 154.93,152.66 154.93,154.66 157.19,156.92 162.59,156.92 163.46,157.79 190,157.79 190.47,158.25 190.47,158.65 v1(190.64,158.82)
  BOTTOM w0.076: v1(102.76,127.57) 102.91,127.71 103.07,127.71 103.15,127.63 103.15,126.79 102.73,126.37 102.73,125.44 103.03,125.15 UC1.B45
EDP_CPU_AUX#: length 137.5
  TOP w0.102: v1(190.05,158.82) 190.25,159.02 190.25,160.69 191.08,161.52 191.08,166.57 196.28,171.78 197.06,171.78 RX30.2 197.63,172.3 198.07,171.85 198.21,171.85 CX44.1
  IN1 w0.127: v1(102.77,128.19) 102.96,128 103.37,128 105.47,130.09 108.68,130.09 110.02,131.43 113.41,131.43 116.54,134.55 119.57,134.55 120.62,135.6 127.51,135.6 129.41,133.7 132.07,133.7 132.31,133.45 136.69,133.45 137.92,134.68 148.55,134.68 149.41,135.54 153.24,135.54 158.07,140.36 158.07,149.14 154.66,152.55 154.66,154.77 157.08,157.19 162.48,157.19 163.35,158.06 189.89,158.06 190.19,158.37 190.19,158.68 v1(190.05,158.82)
  BOTTOM w0.076: v1(102.77,128.19) 102.77,128.05 102.92,127.9 103.15,127.9 103.34,127.71 103.34,126.71 102.92,126.29 102.92,126.12 103.27,125.78 103.27,125.65 103.18,125.56 UC1.A45
EDP_CPU_HPD: length 102.1
  TOP w0.102: UX4.1 200.78,172.58 200.24,173.11 v1(199.3,173.11)
  IN3 w0.127: v1(199.3,173.11) 199.3,172.49 198.72,171.91 196.69,171.91 195.35,170.57 195.35,166.61 188.5,159.75 161.36,159.75 159.86,158.25 159.86,154.22 158.11,152.46 158.11,143.34 150.32,135.56 135.5,135.56 134.9,136.15 134.2,136.15 v1(133.76,135.71)
  BOTTOM w0.102: v1(133.76,135.71) 133.66,135.61 QC3.2 132.55,131.93 132.55,130.41 RC105.1 ; v1(199.3,173.11) 198.86,172.67 RX35.1 RX52.1
EDP_CPU_LANE_N0: length 141.3
  TOP w0.102: v1(191.7,160.13) 191.67,160.16 191.67,160.75 191.99,161.07 191.99,166.19 195.48,169.68 198.33,169.68 CX46.1
  IN1 w0.084: 101.49,129.92 101.03,129.92
  IN1 w0.127: 101.49,129.92 101.71,129.92 102.1,130.32 103.13,130.32 104.67,131.85 107.62,131.85 109.57,133.81 113.2,133.81 115.68,136.28 118.4,136.28 119.66,137.54 128.12,137.54 129.12,136.54 132.31,136.54 133.57,135.28 136.1,135.28 137.09,136.27 147.76,136.27 148.69,137.21 152.35,137.21 156.42,141.27 156.42,147.34 153,150.76 153,156.84 155.98,159.81 188.02,159.81 189.1,160.89 191.26,160.89 191.6,160.55 191.6,160.23 v1(191.7,160.13) ; 101.03,129.92 v1(100.86,130.09)
  BOTTOM w0.076: UC1.C45 102.76,124.53 102.76,124.77 102.57,124.95 102.57,126.47 102.06,126.98 102.06,128.59
  BOTTOM w0.102: v1(100.86,130.09) 101.09,129.87 101.44,129.87 102.07,129.23 102.07,128.61 102.06,128.59
EDP_CPU_LANE_N1: length 139.3
  TOP w0.102: v1(192.72,158.76) 192.35,159.13 192.35,159.64 192.75,160.04 192.75,165.96 195.52,168.73 196.32,168.73 CX39.1
  IN1 w0.127: v1(192.72,158.76) 192.58,158.9 192.58,159.29 192.27,159.6 189.08,159.6 188.51,159.03 156.41,159.03 153.88,156.5 153.88,152.17 157.24,148.81 157.24,140.93 152.68,136.37 149.12,136.37 148.22,135.47 137.48,135.47 136.31,134.31 132.93,134.31 132.73,134.51 129.82,134.51 127.58,136.74 120.41,136.74 119.09,135.42 115.96,135.42 112.78,132.24 109.43,132.24 108.08,130.88 104.88,130.88 103.53,129.54 102.44,129.54 101.93,129.03 101.93,128.58 101.37,128.02 101.03,128.02 v1(100.86,128.19)
  BOTTOM w0.076: v1(100.86,128.19) 100.68,128.01 100.52,128.01 100.23,127.72 100.23,126.57 100.61,126.19 101.89,126.19 102,126.07 102,125.96 101.93,125.89 101.8,125.89 101.74,125.83 101.74,125.72 UC1.A47
EDP_CPU_LANE_P0: length 141.2
  TOP w0.102: v1(191.12,160.13) 191.46,160.47 191.46,160.84 191.77,161.16 191.77,166.28 195.39,169.9 198.04,169.9 CX42.1
  IN1 w0.127: v1(100.86,129.46) 101.06,129.65 101.82,129.65 102.21,130.05 103.24,130.05 104.78,131.58 107.73,131.58 109.68,133.53 113.31,133.53 115.79,136.01 118.51,136.01 119.78,137.27 128,137.27 129.01,136.27 132.2,136.27 133.46,135.01 136.21,135.01 137.2,136 147.87,136 148.81,136.94 152.47,136.94 156.69,141.16 156.69,147.45 153.27,150.87 153.27,156.73 156.09,159.54 188.14,159.54 189.21,160.61 191.15,160.61 191.33,160.43 191.33,160.34 v1(191.12,160.13)
  BOTTOM w0.076: UC1.B46 102.34,124.46 102.19,124.46 102.12,124.52 102.12,124.72 102.38,124.98 102.38,126.39 101.87,126.9 101.87,128.5 101.86,128.51 101.86,128.68
  BOTTOM w0.102: 101.86,128.68 101.86,129.14 101.35,129.65 101.06,129.65 v1(100.86,129.46)
EDP_CPU_LANE_P1: length 139.4
  TOP w0.102: CX38.1 196.5,168.96 195.44,168.96 192.54,166.05 192.54,160.13 192.14,159.73 v1(192.14,158.76)
  IN1 w0.127: v1(192.14,158.76) 192.31,158.93 192.31,159.18 192.16,159.33 189.2,159.33 188.62,158.76 156.52,158.76 154.15,156.39 154.15,152.28 157.51,148.92 157.51,140.82 152.79,136.1 149.24,136.1 148.33,135.2 137.59,135.2 136.43,134.03 132.82,134.03 132.62,134.24 129.71,134.24 127.47,136.47 120.53,136.47 119.2,135.15 116.08,135.15 112.89,131.96 109.55,131.96 108.19,130.61 104.99,130.61 103.64,129.26 102.55,129.26 102.2,128.92 102.2,128.47 101.48,127.75 101.06,127.75 v1(100.86,127.55)
  BOTTOM w0.076: v1(100.86,127.55) 100.86,127.75 100.8,127.82 100.6,127.82 100.42,127.65 100.42,126.64 100.69,126.38 101.97,126.38 102.19,126.15 102.19,125.44 101.9,125.15 UC1.B47
EDP_DISP_UTIL: length 3.6
  BOTTOM w0.102: RC72.1 103.66,128.41 v2(103.66,127.54) 103.66,126.31 UC1.A43
EDP_HPD_PANEL: length 21.3
  TOP w0.102: v1(196.9,179.41) 197.27,179.78 199.41,179.78 v2(200.54,178.65) 200.93,178.26 207.5,178.26 208.74,177.01 RX53.1
  BOTTOM w0.102: RX52.2 197.32,171.78 196.9,172.2 v1(196.9,179.41)
EDP_N0: length 5.3
  BOTTOM w0.102: RX44.1 206.23,168.9 205.98,168.9 205.21,169.66 v3(203.55,169.66) 203.26,169.66 203.02,169.89 202.24,169.89 RX43.2
EDP_N1: length 5.3
  BOTTOM w0.102: RX47.2 202.24,168.11 v3(203.71,168.11) 203.98,168.11 204.95,167.14 206.2,167.14 RX48.1
EDP_P0: length 5.3
  BOTTOM w0.102: RX42.1 206.21,169.16 206.09,169.16 205.32,169.92 v3(205.07,169.92) 203.37,169.92 203.13,170.16 202.24,170.16 RX41.2
EDP_P1: length 5.2
  BOTTOM w0.102: RX45.2 202.24,168.38 204.09,168.38 205.06,167.41 v3(205.41,167.41) 206.24,167.41 RX46.1
EN_0.675VSP: length 5.1
  BOTTOM w0.102: PR202.2 162,27.73 162.43,28.16 162.43,28.48 v2(162.62,28.67)
  BOTTOM w0.203: PU200.7 160.49,25.23 161.38,26.11 PC203.1
  BOTTOM w0.254: PC203.1 PR202.2
EN_1.35V: length 3
  BOTTOM w0.203: PU200.8 v2(161.1,24.83) 161.18,24.83 161.57,25.22 PR201.2
  BOTTOM w0.254: PC202.1 PR201.2
EN_+1.2VSP: length 3.9
  TOP w0.102: PR1103.2 190.91,172.27 v2(191.07,172.11)
  TOP w0.254: PU1100.3 v1(189.13,172.29) 189.14,172.27 PR1103.2
  BOTTOM w0.254: v1(189.13,172.29) 189.03,172.18 188.93,172.18 188.78,172.03 PC1104.1
EN_DFAN1: length 192.9
  TOP w0.102: UE1.70 193.59,50.37 v1(193.34,50.13)
  IN3 w0.127: v1(54.77,102.31) 54.77,98.63 56.1,97.29 56.1,95.68 59.3,92.49 59.3,74.74 61.44,72.6 61.44,57.1 69.51,49.03 114.7,49.03 115.77,47.95 140.75,47.95 141.21,48.41 175.85,48.41 176.46,49.03 181.76,49.03 183.26,50.53 188.01,50.53 189.63,48.91 192.15,48.91 193.34,50.11 v1(193.34,50.13)
  BOTTOM w0.102: v1(54.77,102.31) v2(53.79,102.31) 50.19,102.31 50.07,102.44 UE3.4
EN_INVPWR: length 166.5
  TOP w0.102: v1(216.18,174.57) 216.44,174.83 216.44,175.93 QX1.2 ; UE1.68 194.39,49.85 v1(194.78,49.45)
  IN2 w0.127: v1(217.1,51.75) 217.86,52.52 217.86,53.34 222.91,58.39 222.91,71.3 228.81,77.2 228.81,85.95 225.82,88.95 225.82,95.92 228.81,98.91 228.81,107.29 224.95,111.16 224.95,120.7 225.85,121.6 225.85,146.25 216.79,155.3 216.79,166.51 215.61,167.69 215.61,174 v1(216.18,174.57)
  BOTTOM w0.102: v1(194.78,49.45) 198.84,49.45 199.72,48.57 200.92,48.57 200.98,48.51 213,48.51 v2(215.19,50.7) 215.61,51.13 215.61,51.61 216.14,52.14 216.71,52.14 v1(217.1,51.75)
EN_PCIE: length 1
  BOTTOM w0.102: PR1304.1 v2(198.93,65.11)
ENVDD_PCH: length 236
  TOP w0.089: v1(127.01,124.45) 126.85,124.61 RC87.2
  TOP w0.102: v1(190.33,37.01) 190.39,36.95 UE1.19
  IN1 w0.127: v1(165.78,88.69) 167.87,86.6 174.33,86.6 178.68,82.26 182.7,82.26 189.3,75.66 189.3,65.62 190.37,64.55 190.37,57.51 191.86,56.02 191.86,54.99 192.56,54.29 192.56,50.7 192.41,50.56 192.41,47.54 192.08,47.21 192.08,44.71 192.42,44.37 192.42,39.33 190.85,37.75 190.85,37.4 190.46,37.01 v1(190.33,37.01) ; v1(169.4,95.26) 164.18,100.49 164.18,101.05 161.15,104.07 161.15,109.33 157.2,113.28 157.2,115.03 152.61,119.63 152.61,123.57 v1(150.32,125.86) 143.91,132.27 139.59,132.27 136.24,128.92 129.18,128.92 128.49,128.23 v1(128.49,127.9)
  IN3 w0.127: v1(208.25,163.65) 208.19,163.65 205.23,160.68 191.04,160.68 189.03,158.66 164.33,158.66 160.9,155.23 160.9,153.59 159.28,151.97 159.28,141.19 152.19,134.09 v1(152.19,133.17)
  BOTTOM w0.089: v1(128.49,127.9) 128.49,127.43 127.03,125.97 127.03,125.3 126.91,125.18 126.5,124.77 UC1.C6 126.92,124.36 v1(127.01,124.45)
  BOTTOM w0.102: RX51.1 207.56,164.34 v1(208.25,163.65) ; v1(152.19,133.17) v2(151.27,132.26) 150.32,131.31 v1(150.32,125.86) ; v1(165.78,88.69) 168.24,91.16 168.24,94.1 v1(169.4,95.26)
ENVDD_R: length 3.9
  TOP w0.102: UX1.3 217.58,167.53 RX7.1 RX8.1 215.58,166.84 v2(214.82,166.08)
ERP_LOT6: length 164.7
  TOP w0.102: v1(193.31,55.57) 192.94,55.2 192.94,53.16 192.39,52.6 UE1.73
  TOP w0.254: PC5.1 130.23,171.91 v2(130.59,171.54) v1(131.18,171.54) 131.35,171.71 PR2.1
  IN2 w0.089: 137.92,126.34 137.05,127.21
  IN2 w0.127: 137.05,127.21 136.87,127.39 136.87,138.48 126.65,148.7 v1(124.48,148.7) ; v1(186.26,58) 185.75,58.51 185.75,65.66 186.52,66.43 186.52,73.94 183.31,77.15 183.31,78.17 182.66,78.82 182.46,78.82 160.59,100.69 158.03,100.69 152.91,105.81 152.91,108.37 152.78,108.5 152.78,109.68 152.43,110.03 152.43,111.1 151.32,112.2 151.32,114.44 148.53,117.23 144.47,117.23 143.51,118.19 143.51,120.75 137.92,126.34
  IN3 w0.127: v1(124.48,148.7) 124.48,156.04 126.9,158.47 126.9,169.71 128.74,171.54 v1(131.18,171.54)
  BOTTOM w0.102: v1(186.26,58) 186.49,58.23 190.66,58.23 v1(193.31,55.57)
F-IMAX: length 4.3
  TOP w0.102: v1(86.83,140.6) 86.83,141.01 v2(87.06,141.23)
  TOP w0.254: v1(86.83,140.6) 86.71,140.47 PR505.2
  BOTTOM w0.203: PU501.10 88.22,139.88 87.95,140.14 87.29,140.14 v1(86.83,140.6)
  BOTTOM w0.254: PR504.1 v1(86.83,140.6)
FAN_SPEED1: length 210.2
  TOP w0.102: v1(51.38,103.66) v2(52,103.66) ; v1(168.2,47.48) 169.19,46.49 169.19,41.63 170.58,40.24 174.23,40.24 179.29,35.19 179.32,35.16 179.7,34.78 179.7,32.9 181.7,30.9 193.47,30.9 194.59,32.01 194.59,33.11 CE29.1 193.96,34.34 193.99,34.36 UE1.28
  IN3 w0.127: v1(51.38,103.66) 51.38,99.29 58.51,92.16 58.51,74.42 60.64,72.29 60.64,56.66 69.47,47.83 114.82,47.83 115.45,47.19 141.07,47.19 141.36,47.48 v1(168.2,47.48)
  BOTTOM w0.102: JFAN.2 49.94,106.23 CE24.1 RE50.2 50.05,104.99 v1(51.38,103.66)
FB_1.5VSP: length 4.3
  BOTTOM w0.102: PC404.2 v2(113.68,22.6)
  BOTTOM w0.254: PC404.2 PR403.2 PR402.1 111.02,23.78 110.87,23.93 PU400.1
FB_1.8VSP: length 4.7
  BOTTOM w0.102: PC604.2 220.15,88.02 v2(220.08,87.95)
  BOTTOM w0.254: PC604.2 PR603.2 221.25,89.77 PR602.1 220.68,89.79 220.5,89.61 220.25,89.61 220.04,89.81 PU600.1
FB_1.35V: length 5.3
  BOTTOM w0.102: PR204.1 v2(161.47,30.17)
  BOTTOM w0.203: PU200.6 160.39,25.63 160.55,25.79 160.55,26.93 161.47,27.85 PR207.1
  BOTTOM w0.254: PR207.1 PR204.1
FB_3V: length 3.6
  TOP w0.203: 128.54,13.68 128.23,13.99 PU100.4
  TOP w0.254: PR107.2 PC102.2 PR109.2 128.93,13.28 128.54,13.68
FB_5V: length 4.3
  TOP w0.203: PU100.2 127.43,14.01 127.05,13.63 v3(126.74,13.63)
  TOP w0.254: PR104.1 126.71,13.6 v3(126.74,13.63)
  BOTTOM w0.102: v3(126.74,13.63) 126.74,14.1 v2(126.87,14.24)
  BOTTOM w0.254: v3(126.74,13.63) 126.74,13.62 126.67,13.55 PC108.1 PR106.1
FB_+1.2VSP: length 3.9
  TOP w0.254: PU1100.4 189.13,172.79 v1(189.13,172.87)
  BOTTOM w0.102: v2(190.93,173.23) 190.57,172.87 PR1107.1
  BOTTOM w0.254: PR1107.1 v1(189.13,172.87) 189.08,172.92 PR1108.1
FB_PCIE: length 4.7
  TOP w0.254: PC1306.2 PR1302.2 196.88,62.57 v1(196.29,61.99) 195.99,62.29 PR1301.1
  BOTTOM w0.102: v1(196.29,61.99) 196.29,62.25 v2(197.04,63)
  BOTTOM w0.254: v1(196.29,61.99) 196.07,61.99 195.66,62.4 PU1300.6
GCLK_VRTC: length 3.8
  TOP w0.102: RG1.2 74.57,44.44 CG5.1 73.43,44.44 72.63,43.64 UG1.10
GENLK_CLK: length 1.6
  TOP w0.102: T80.1 171.07,116.4 v1(171.24,116.23)
  BOTTOM w0.102: UV1.AD29 171.66,115.81 v1(171.24,116.23)
GENLK_VSYNC: length 1.7
  TOP w0.102: T81.1 171.03,117.96 v1(171.51,117.48)
  BOTTOM w0.102: UV1.AC29 171.66,116.89 171.66,117.33 v1(171.51,117.48)
GFX_FB-1: length 0.9
  BOTTOM w0.254: PC806.1 204.23,52.82 PR821.2
GFX_FB-2: length 2.2
  BOTTOM w0.102: v2(200.3,51.22) 200.48,51.05 PC817.1
  BOTTOM w0.254: PR818.2 202.44,51.05 PC817.1
GPIO21_BBEN: length 1.4
  TOP w0.102: v1(183.24,111.45) 183.36,111.33 T78.1
  BOTTOM w0.102: UV1.AJ14 183.42,111.45 v1(183.24,111.45)
GPIO24_TRSTB: length 3.2
  TOP w0.102: RP47.8 175.62,107.96 175.48,108.1 v2(175.48,108.47) 175.48,108.57 175.79,108.88 v1(176.08,108.88)
  BOTTOM w0.102: v1(176.08,108.88) 176.66,109.46 UV1.AM23
GPIO25_TDI: length 5.9
  TOP w0.102: v4(175.38,104.06) 175.02,104.42 175.02,105.27 175.21,105.46 175.21,106.31 175.39,106.49 175.9,106.49 176.12,106.71 RP47.7 176.12,108.18 v1(176.04,108.26)
  BOTTOM w0.102: v1(176.04,108.26) 176.47,108.69 UV1.AN23
GPIO26_TCK: length 5.4
  TOP w0.102: v1(176.04,111.03) 176.46,111.03 v4(176.71,110.78) 176.81,110.68 176.81,108.39 177.12,108.09 RP47.5
  BOTTOM w0.102: UV1.AK23 176.1,111.09 v1(176.04,111.03)
GPIO27_TMS: length 4
  TOP w0.102: RP47.6 176.62,108.23 176.51,108.34 v2(176.51,109.24) 176.51,109.64 v1(176.05,110.1)
  BOTTOM w0.102: v1(176.05,110.1) 175.65,110.1 UV1.AL24
GPIO28_TDO: length 2.1
  TOP w0.102: v1(176.08,109.46) 175.58,109.46 T79.1
  BOTTOM w0.102: v1(176.08,109.46) 176.05,109.49 UV1.AM24
GPU_B+: length 13.5
  TOP w0.508: PR823.2 199.99,58.68 199.1,59.57 199.1,60.58 202.03,63.51 207.42,63.51 208.56,64.65
  vias: v2(210.87,77.67)
GPU_GPIO0: length 17.5
  IN3 w0.102: v1(179.7,112.14) 179.74,112.14 180.11,111.76 180.11,110.27 179.93,110.09 179.93,105.02 180.46,104.5
  IN3 w0.127: v1(181.57,98.24) 181.57,100.61 180.81,101.37 180.81,104.14 180.46,104.5
  BOTTOM w0.102: UV1.AH20 179.46,112.37 v1(179.7,112.14) ; v2(180.62,98.05) 181.12,97.55 RV75.2 181.7,98.11 v1(181.57,98.24)
GPU_GPIO1: length 17.3
  TOP w0.102: v1(182.59,98.19) v2(182.59,97.6)
  IN3 w0.102: v1(180.96,112.36) 180.43,111.83 180.43,110.06 180.18,109.8 180.18,105.48 181.19,104.47 181.19,103.69
  IN3 w0.127: 181.19,103.69 181.19,101.67 182.15,100.72 182.15,98.63 v1(182.59,98.19)
  BOTTOM w0.102: v1(180.96,112.36) 180.63,112.69 UV1.AH18 ; v1(182.59,98.19) RV76.2
GPU_GPIO2: length 3.2
  TOP w0.102: v1(183.24,109.17) 183.41,108.99 v2(183.41,108.67) 183.41,108.28 184,107.69 RP60.8
  BOTTOM w0.102: UV1.AN16 182.76,108.69 v1(183.24,109.17)
GPU_GPIO6: length 97.8
  IN1 w0.102: 164.11,121.3 166.61,121.3 167.67,120.24 167.67,119.39 168.59,118.46 168.59,117.45 169.44,116.6 169.44,116.08 169.26,115.89 169.26,112.9 v1(169.49,112.67)
  IN1 w0.127: v1(158.78,154) 160.54,152.24 160.54,136.46 157.17,133.09 157.17,128.45 155.73,127.02 155.73,125.51 156.26,124.98 158.64,124.98 162.33,121.3 164.11,121.3
  IN2 w0.127: v1(170.03,183.29) 171.35,181.97 171.35,162.25 168.56,159.46 161.75,159.46 158.4,156.11 158.4,154.38 v1(158.78,154)
  BOTTOM w0.102: PR1212.1 172.55,182.79 v2(171.95,182.19) ; UV1.AG32 169.26,112.9 v1(169.49,112.67)
  BOTTOM w0.254: PR1212.1 172.53,183.26 PR1214.1 PR1213.2 170.06,183.26 v1(170.03,183.29)
GPU_GPIO8: length 5.8
  TOP w0.102: RP60.6 185,107.35 183.89,108.46 v2(183.89,109.98) 183.89,110.64 v1(184.57,111.32)
  BOTTOM w0.102: v1(184.57,111.32) 185.06,111.81 UV1.AJ13
GPU_GPIO9: length 7.3
  TOP w0.102: RP60.5 185.5,107.91 185.23,108.18 v2(185.23,110.45) 185.23,111.29 184.44,112.08 v1(183.29,112.08)
  BOTTOM w0.102: v1(183.29,112.08) 183.29,112.52 UV1.AH15
GPU_GPIO11: length 15.9
  TOP w0.102: v1(183.48,98.19) 183.48,98.03 v2(184.05,97.46)
  IN3 w0.102: 182.59,103.69 182.59,104.46 182.14,104.91 182.14,106.31 181.49,106.97 181.49,110.04 182.14,110.69 v1(182.15,110.69)
  IN3 w0.127: 182.59,103.69 182.59,99.08 v1(183.48,98.19)
  BOTTOM w0.102: UV1.AK16 182.55,111.09 v1(182.15,110.69) ; v1(183.48,98.19) RV81.2
GPU_GPIO12: length 15
  IN3 w0.102: v1(182.14,109.86) 181.69,109.4 181.69,107.05 183.16,105.58 183.16,104.59 182.91,104.33 182.91,103.69
  IN3 w0.127: 182.91,103.69 182.91,101.53 183.67,100.77 183.67,98.89 v1(184.37,98.19)
  BOTTOM w0.102: RV82.2 v1(184.37,98.19) 184.27,98.19 v2(183.96,98.49) ; v1(182.14,109.86) 182.58,110.29 UV1.AL16
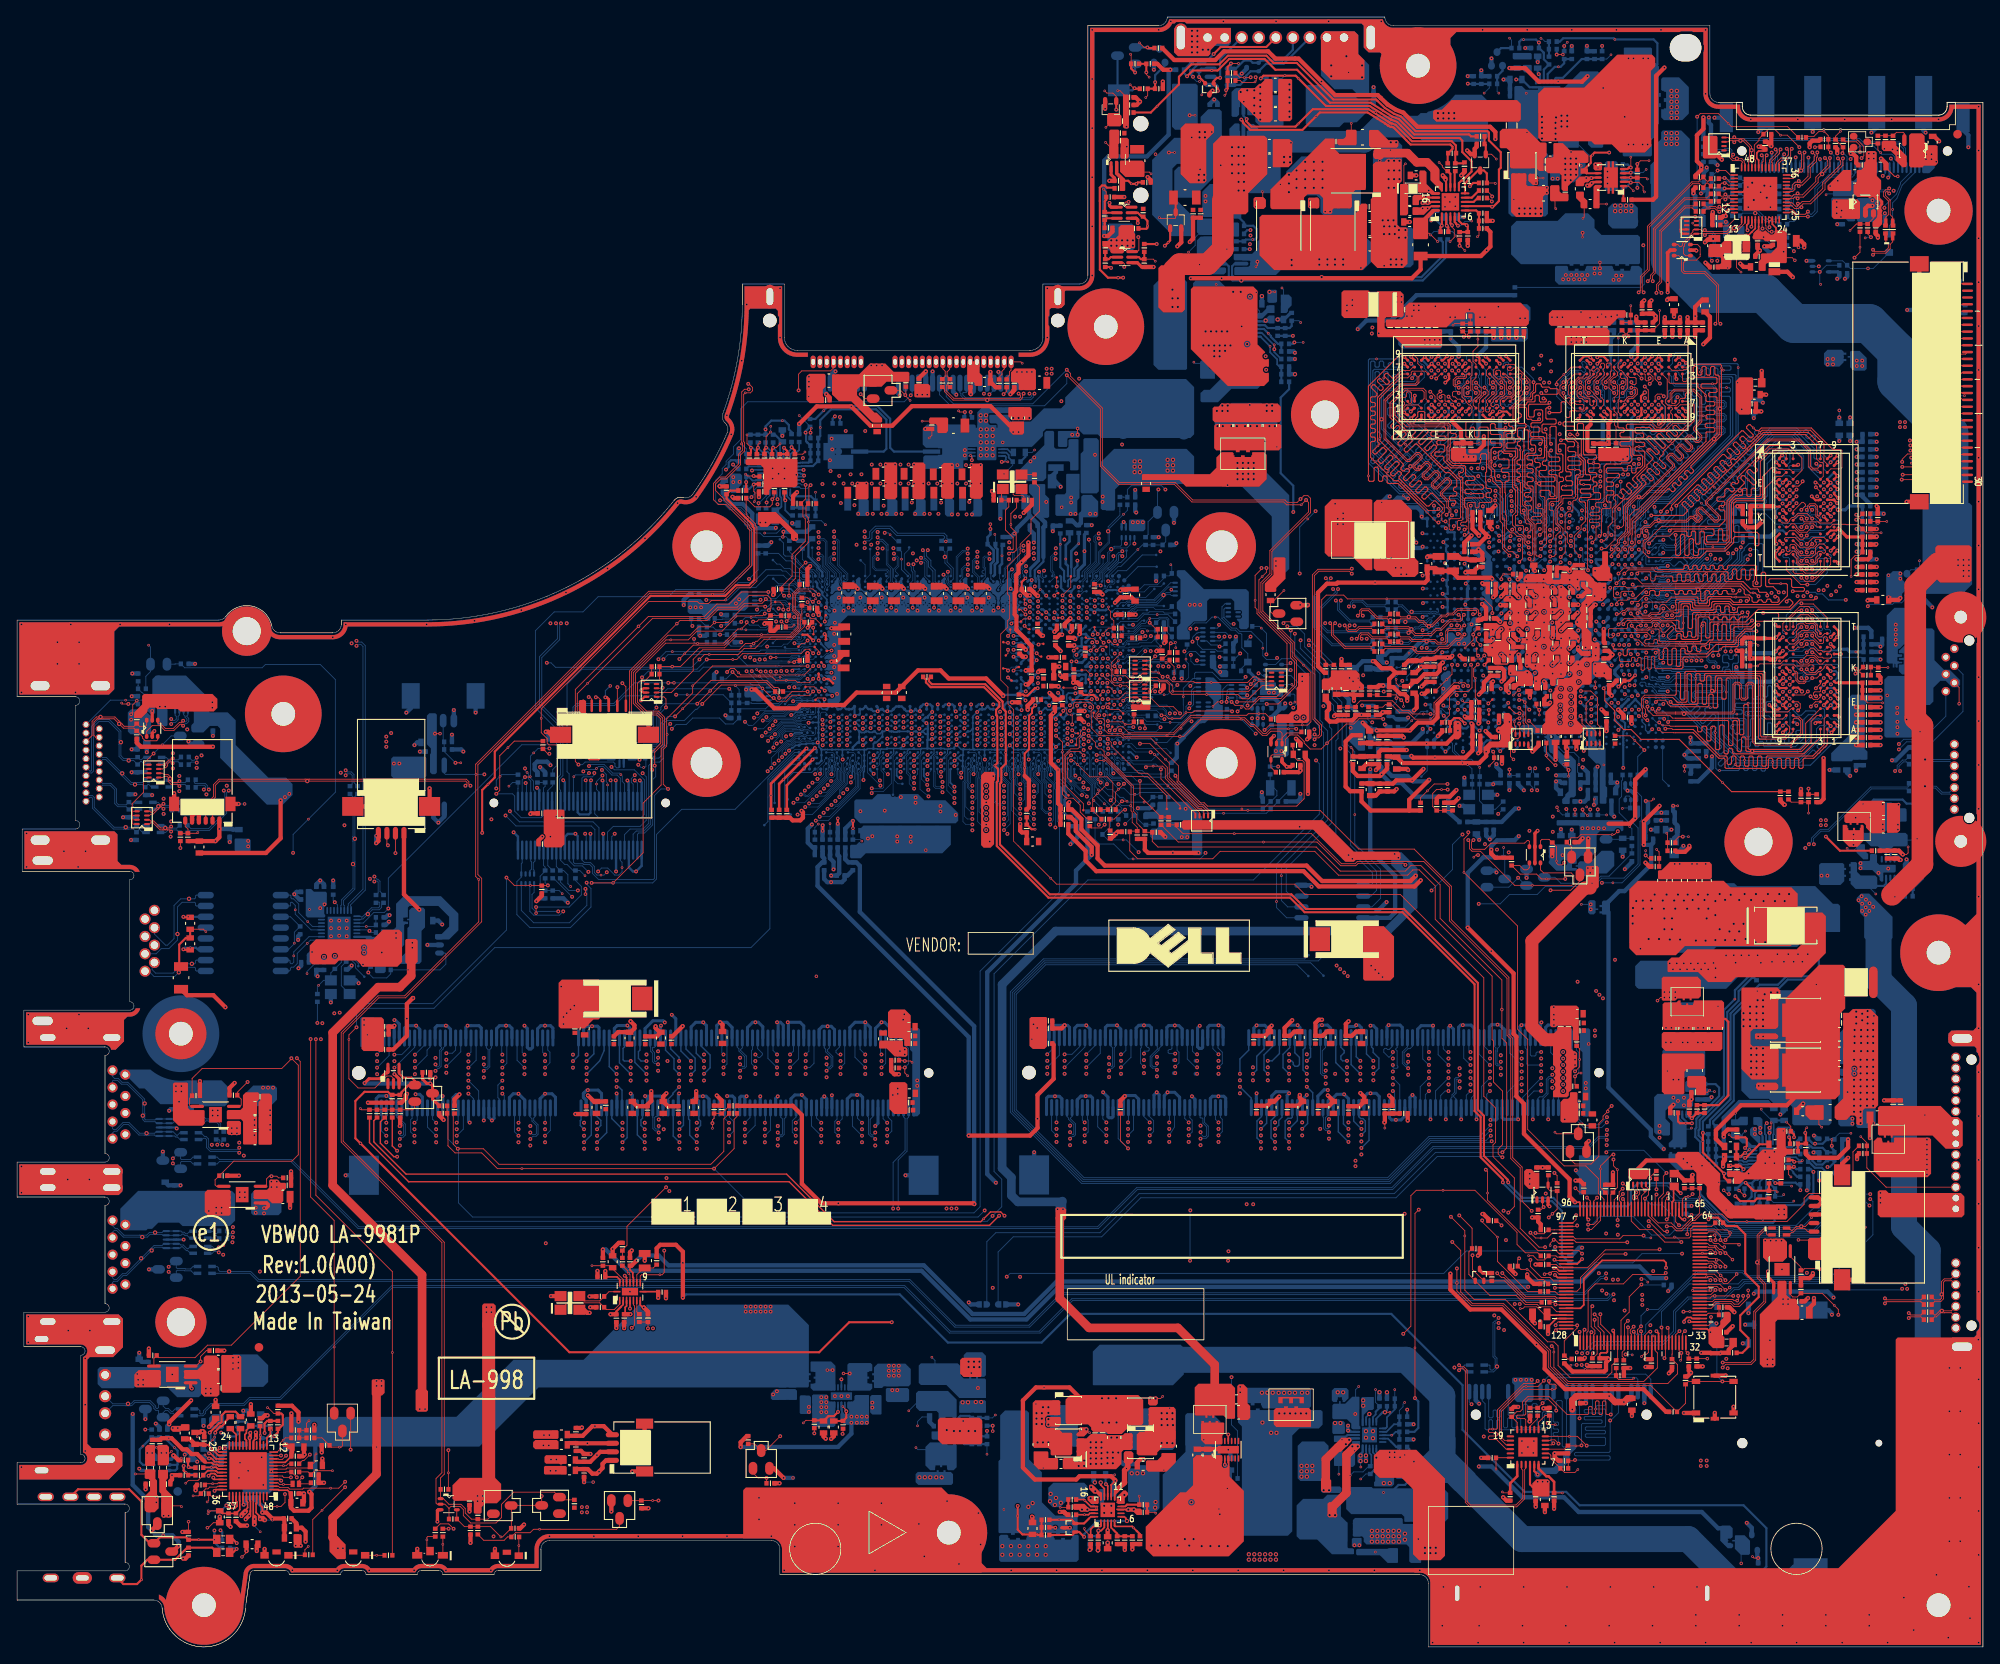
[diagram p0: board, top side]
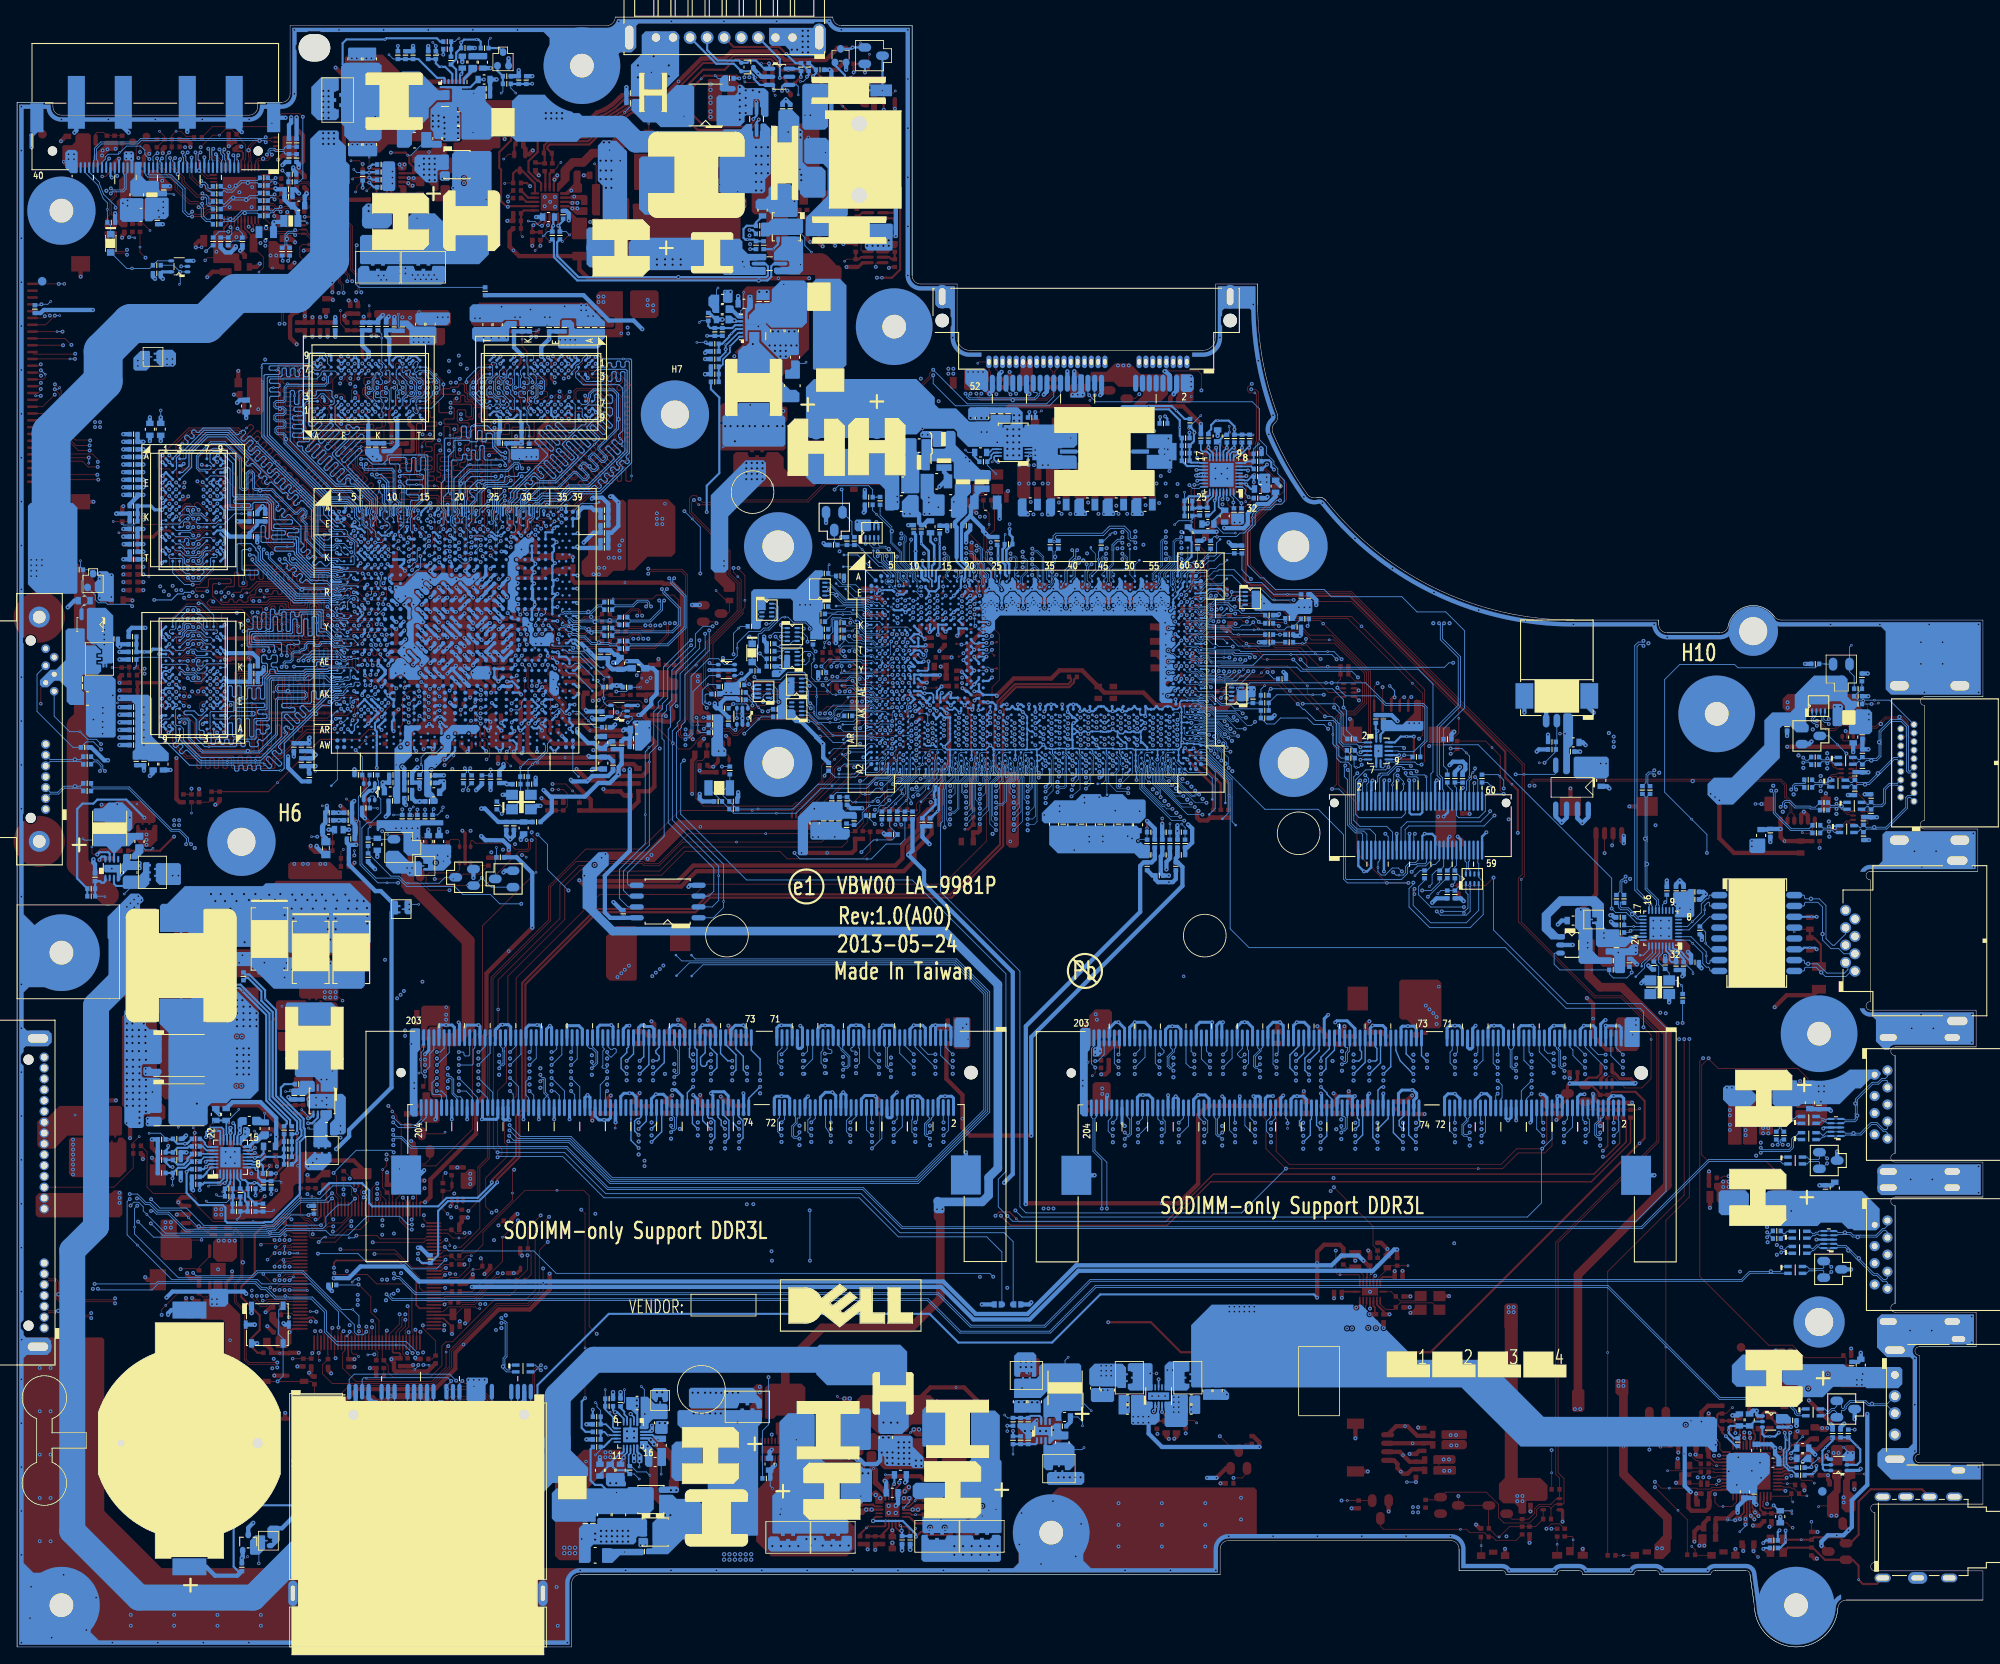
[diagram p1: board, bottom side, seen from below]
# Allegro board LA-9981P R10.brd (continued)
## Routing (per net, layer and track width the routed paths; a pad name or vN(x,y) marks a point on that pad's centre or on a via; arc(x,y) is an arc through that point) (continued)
GPU_GPIO13: length 14.5
  IN3 w0.102: v1(182.15,109.03) 182.48,108.7 182.48,106.75 184.56,104.67 184.56,103.69
  IN3 w0.127: 184.56,103.69 184.56,99.6 185.26,98.91 v1(185.26,98.2)
  BOTTOM w0.102: v1(185.26,98.2) RV83.2 v2(186.3,97.55) ; UV1.AM16 182.61,109.49 v1(182.15,109.03)
GPU_RST#: length 14.7
  IN3 w0.102: 164.11,115.27 165.68,115.27 166.63,116.22 167.26,116.22 168.08,117.03 170.16,117.03 v1(170.66,117.53)
  IN3 w0.127: 164.11,115.27 163.94,115.27 162.35,113.67 v1(162.35,113.27)
  BOTTOM w0.102: UV13.4 161.27,110.39 161.65,110.77 v4(161.65,111.24) 161.65,112.48 RV66.1 162.35,113.17 v1(162.35,113.27) ; UV1.AA30 170.86,117.74 v1(170.66,117.53)
GPU_VGA_B: length 4.1
  BOTTOM w0.102: T87.1 164.99,114.11 165.68,114.11 UV1.AF37
GPU_VGA_DDCCLK: length 3
  TOP w0.102: T90.1 v1(172.49,109.87)
  BOTTOM w0.102: UV1.AK30 170.95,111.09 171.31,110.73 171.31,110.16 171.61,109.87 v1(172.49,109.87)
GPU_VGA_DDCDAT: length 1.4
  TOP w0.102: v1(172.43,110.63) 172.44,110.63 T91.1
  BOTTOM w0.102: v1(172.43,110.63) 171.97,111.09 UV1.AK29
GPU_VGA_G: length 4.9
  BOTTOM w0.102: UV1.AE36 166.24,115.29 165.86,114.91 165.41,114.91 165,115.33 164.46,115.33 162.88,113.75 T86.1
GPU_VGA_HSYNC: length 6.7
  BOTTOM w0.102: T88.1 161.58,113.73 164.37,116.52 165.75,116.52 166.12,116.89 UV1.AC36
GPU_VGA_R: length 2.7
  BOTTOM w0.102: T85.1 164.41,116.09 UV1.AD39
GPU_VGA_VSYNC: length 4.8
  BOTTOM w0.102: T89.1 162.06,114.83 163.98,116.75 165.37,116.75 165.51,116.89 UV1.AC38
GPU_VID1: length 83.5
  TOP w0.102: v2(209.75,60.88) 209.58,60.7 v1(209.58,60.27)
  TOP w0.254: PR819.2 PR810.1 209.63,59 PR828.2 209.64,60.21 v1(209.58,60.27)
  IN3 w0.102: v1(184.49,109.92) 185.43,108.98 185.43,107.07 185.83,106.68 185.83,104.4 186.46,103.76 186.46,103.69
  IN3 w0.127: 186.46,103.69 186.46,100.46 186.97,99.95 187.86,99.95 188.28,99.53 188.28,94.33 187.35,93.4 187.35,83.02 191.33,79.05 191.33,65.25 198.78,57.79 198.78,55.8 199.75,54.84 208.31,54.84 211.23,57.76 211.23,59.26 211.04,59.45 210.4,59.45 v1(209.58,60.27)
  BOTTOM w0.102: v1(184.49,109.92) 184.86,110.29 UV1.AL13
GPU_VID2: length 83.2
  IN3 w0.102: v1(184.47,110.57) 185.64,109.4 185.64,107.15 186.08,106.71 186.08,104.46 186.72,103.83 186.72,103.69
  IN3 w0.127: v1(210.72,59) 210.13,58.41 210.13,57.02 208.2,55.09 199.85,55.09 199.04,55.91 199.04,57.9 191.58,65.36 191.58,79.15 187.6,83.13 187.6,93.29 188.53,94.22 188.53,99.69 188.01,100.21 187.1,100.21 186.72,100.59 186.72,103.69
  BOTTOM w0.102: UV1.AK14 183.95,111.09 v1(184.47,110.57) ; PR826.2 213,59.65 213.58,60.23 v2(214.92,60.23)
  BOTTOM w0.254: PR812.1 210.26,59.22 210.27,59.22 210.42,59.07 210.42,59.07 210.48,59 v1(210.72,59) 211.61,59 212.13,59.52 PR834.2 212.2,59.51 PR826.2
GPU_VID3: length 82.7
  TOP w0.102: v1(212.69,58.75) v2(212.69,59.5)
  IN3 w0.102: v1(184.49,109.16) 185.13,108.53 185.13,106.62 185.57,106.18 185.57,104.3 186.18,103.69
  IN3 w0.127: v1(212.69,58.75) 212.58,58.75 207.69,53.86 202.28,53.86 201.74,54.39 199.83,54.39 198.53,55.7 198.53,57.69 191.07,65.15 191.07,78.94 187.09,82.92 187.09,93.5 188.02,94.44 188.02,98.29 186.18,100.14 186.18,103.69
  BOTTOM w0.102: v1(184.49,109.16) 184.82,109.49 UV1.AM13
  BOTTOM w0.254: v1(212.69,58.75) 212.69,58.5 213,58.19 PR835.2 PR836.2 211.6,58.52 210.42,58.52 210.26,58.68 PR807.1
GPU_VID4: length 88
  IN3 w0.102: v1(180.87,111.45) 181.33,111.9 182.26,111.9 182.87,112.52 183.48,112.52 183.77,112.23 183.77,106.54 185.1,105.21 185.1,104.6
  IN3 w0.127: v1(212.18,56.27) 210.46,56.27 207.79,53.6 202.17,53.6 201.64,54.14 199.73,54.14 198.28,55.59 198.28,57.58 190.82,65.04 190.82,78.84 186.84,82.81 186.84,96.21 185.95,97.1 185.95,99.64 185.68,99.92 185.68,103.49 185.1,104.06 185.1,104.6
  BOTTOM w0.102: v1(180.87,111.45) 181.32,111.89 UV1.AJ17
  BOTTOM w0.254: PR809.1 210.26,57.44 210.27,57.44 210.42,57.29 210.42,57 210.86,56.56 211.6,56.56 PR838.2 PR837.2 213,56.83 212.44,56.27 v1(212.18,56.27)
GPU_VID5: length 84.3
  IN3 w0.127: v1(182.14,111.45) 182.64,110.95 182.64,108.92 183.4,108.16 183.4,106.26 184.81,104.85 184.81,99.71 185.7,98.82 185.7,96.99 186.59,96.11 186.59,82.71 190.56,78.73 190.56,64.94 198.02,57.48 198.02,55.49 199.62,53.88 201.53,53.88 202.07,53.35 207.9,53.35 209.74,55.19 211.93,55.19 v1(212.18,54.94)
  BOTTOM w0.102: v1(212.18,54.94) v2(212.18,54.12) ; UV1.AJ16 182.59,111.89 v1(182.14,111.45)
  BOTTOM w0.254: v1(212.18,54.94) 212.13,54.99 PR840.2 ; PR839.2 PR840.2 ; PR840.2 211.52,56.18 210.7,56.18 209.98,56.91 PR806.1
H_CATERR#: length 6
  TOP w0.089: v2(91.06,119.82) 90.82,119.58 RC58.2 90.08,119.74 v1(89.58,120.24)
  BOTTOM w0.076: UC1.K61 92.7,120.17 92.18,120.17 91.94,119.93 91.94,119.76 91.77,119.59 91.42,119.59 91.16,119.84 90.73,119.84 90.69,119.88 89.96,119.88 89.73,120.11 89.71,120.11 v1(89.58,120.24)
H_CPU_SVIDALRT#: length 8.8
  BOTTOM w0.076: v2(87.25,118.69) 87.85,118.69 88.5,119.34 90.96,119.34 91.46,118.84 91.77,118.84 92.06,119.13 UC1.L62
  BOTTOM w0.089: 86.76,118.69 v2(87.25,118.69)
  BOTTOM w0.102: R254.1 86.76,118.69
H_CPU_SVIDCLK: length 10.6
  BOTTOM w0.089: UC1.N63 91.54,118.49 88.41,118.49 87.27,117.35 86.76,117.35
  BOTTOM w0.102: R248.2 C5212.1 83.66,117.35 v2(86,117.35) 86.76,117.35
H_CPU_SVIDDATA: length 12.5
  BOTTOM w0.076: UC1.L63 91.41,119.13 91.03,119.51 88.1,119.51
  BOTTOM w0.089: 88.1,119.51 87.84,119.25 86.76,119.25
  BOTTOM w0.102: R257.1 79.92,120.5 R256.2 81.56,119.58 81.89,119.25 v2(85.42,119.25) 86.76,119.25
H_CPUPWRGD: length 80.1
  TOP w0.102: v1(60.83,86.75) v4(60.83,86.03)
  IN3 w0.127: v1(85.78,125.22) 84.56,125.22 79.84,120.5 69.52,120.5 56.73,107.72 56.73,95.71 59.56,92.88 59.56,88.02 v1(60.83,86.75)
  BOTTOM w0.076: 91.09,126.96 92.09,125.96 93.05,125.96 93.22,125.79 93.22,125.42 93.29,125.35 93.29,124.76 93.27,124.75 UC1.C61
  BOTTOM w0.102: RC48.1 65.44,89.86 66.13,89.17 66.13,88.18 64.71,86.75 60.83,86.75 v1(60.83,86.75) ; 91.09,126.96 90.71,127.33 90.13,127.33 89.25,128.22 RC66.1 CC27.1 86.85,126.28 v1(85.78,125.22)
H_PROCHOT#: length 313.7
  TOP w0.089: 87.93,120.57 87.79,120.43 86.91,120.43 86.76,120.28 ; RC67.1 88.37,120.93
  TOP w0.102: v1(129.76,161.81) 129.76,162.19 129.65,162.3 PQ3.3 ; 86.76,120.28 86.69,120.22 v1(86.26,120.22) ; v1(131.41,165.3) 131.47,165.24 131.47,163.78 131.3,163.6 PQ3.6 ; 88.37,120.93 88.32,120.93 RC60.2 87.93,120.57 ; v1(130.27,169.43) 129.95,169.43 129.82,169.3 129.82,168.92 129.93,168.81 PQ2.6 ; v1(179.52,50.35) v4(179.95,50.78) 180.5,51.33 RE44.2 180.48,53.48 179.67,53.48 179.43,53.72 UE2.4 179.43,55.26 CE19.1
  IN1 w0.114: v1(129.76,161.81) 131.41,163.46 v1(131.41,165.3) 131.41,166 130.27,167.14 v1(130.27,169.43)
  IN1 w0.127: v1(89.12,133.97) 90.58,133.97 91.13,134.53 96.32,134.53 96.49,134.69 108.76,134.69 109.4,135.33 112.53,135.33 114.52,137.32 117.87,137.32 119.19,138.64 128.24,138.64 130.33,140.73 130.33,160.51 129.76,161.08 v1(129.76,161.81)
  IN3 w0.127: v1(89.12,133.97) 89.12,132.54 87.72,131.14 87.72,129.3 89.37,127.65 89.37,122.83 88.93,122.39 87.5,122.39 87.38,122.27 86.38,122.27 86.02,121.91 86.02,120.48 86.26,120.24 v1(86.26,120.22) 86.26,119.95 83.31,116.99 78.94,116.99 78.2,117.73 68.94,117.73 60.79,109.58 60.79,101.5 61.45,100.83 61.45,97.69 60.07,96.31 60.07,88.97 61.35,87.69 61.35,74 64.4,70.95 64.4,55.07 69.93,49.54 114.9,49.54 115.98,48.46 140.54,48.46 141,48.92 175.62,48.92 176.24,49.54 178.71,49.54 v1(179.52,50.35)
H_PROCHOT#_R: length 2.4
  TOP w0.089: RC67.2 90.48,120.55 v1(90.2,120.27)
  BOTTOM w0.076: v1(90.2,120.27) 90.53,120.27 90.79,120.01 91.52,120.01 UC1.K63
H_THERMTRIP#: length 16.2
  BOTTOM w0.076: 89.69,126.15 90.11,126.15 90.69,125.56 91.62,125.56 92.01,125.17 92.44,125.17 92.63,124.97 92.63,124.77 92.97,124.43 92.97,124.22 93.43,123.76 UC1.D60
  BOTTOM w0.102: R2346.2 v2(81.51,123.42) 83.15,123.42 84.52,124.79 86.25,124.79 87.77,126.31 89.54,126.31 89.69,126.15
H_VCCST_PWRGD_XDP: length 4.8
  BOTTOM w0.102: v2(66.56,90.42) 65.95,91.03 RC48.2 65.17,91.03 64.47,91.74 64.2,91.74 63.7,92.23 JXDP1.39
H_VR_READY: length 18.8
  TOP w0.254: PR540.2 v1(85.45,136.57)
  IN3 w0.127: v1(85.45,136.57) 85.45,135.91 84.93,135.39 83.34,135.39 v1(82.39,134.44)
  BOTTOM w0.102: v1(82.39,134.44) 82.74,134.44 83.61,133.56 84.88,133.56 85.63,132.81 v2(85.63,132.43) 85.63,131.57 86.59,130.6 87.08,130.6 87.49,130.19 90.09,130.19 90.52,129.77 R251.1
  BOTTOM w0.203: PU501.3 86.62,136.82 86.56,136.76 86.18,136.76 85.71,137.23 PR524.2
  BOTTOM w0.254: PR524.2 v1(85.45,136.57)
HDA_SPKR: length 181.9
  TOP w0.102: DA8.3 v2(37.16,35.17) 37.16,50 34.41,52.76 v1(34.41,71.28)
  IN2 w0.089: 121.75,93.61 124.22,96.09 125.57,96.09 126.9,97.42 129.93,97.42 130.51,98 130.51,98.49 131.03,99.01 131.03,102.88 130.27,103.64 130.27,110.95 131.79,112.47 132.36,112.47 132.85,112.96 132.85,113.49 133.8,114.44 135.6,114.44 v1(136.14,114.97)
  IN2 w0.127: v1(34.41,71.28) 34.87,70.81 45.39,70.81 59.36,84.78 112.92,84.78 121.75,93.61
  BOTTOM w0.076: v1(136.14,114.97) 135.34,115.77 131.41,115.77 131.27,115.64 130.16,115.64 129.86,115.34 UC1.V2
  BOTTOM w0.089: v1(136.14,114.97) 135.59,114.43 RC121.2
HDD_DET#: length 187.9
  TOP w0.089: RC9.1 135.08,115.47 135.6,114.95 v2(135.6,114.16) 135.6,113.55 135.6,113.55 v1(135.6,113.55)
  IN2 w0.127: v1(141.93,45.29) 142.46,45.82 142.46,73.23 140.43,75.26 140.43,97.42 136.74,101.1 136.74,110.12 135.47,111.39 135.47,113.43 v1(135.6,113.55)
  IN3 w0.084: v1(135.6,113.55) 135.38,113.33 133.27,113.33 132.54,114.06 130.52,114.06 129.19,112.72 128.62,112.72 128.25,112.36 128.25,111.79 128.04,111.58 127.66,111.58 v1(127.22,111.14)
  IN3 w0.127: v1(141.93,45.29) 171.3,45.29 172,45.98 178.4,45.98 179.41,44.98 180.81,44.98 181.57,44.22 184.29,44.22 185.05,44.98 188.81,44.98 189.27,45.43 193.17,45.43 197.11,41.49 197.11,38.32 197.96,37.48 199.55,37.48 200.79,38.72 211.72,38.72 212.4,39.41 215.99,39.41 226.41,49.83 226.41,55.64 JHDD.12
  BOTTOM w0.089: v1(127.22,111.14) 126.99,110.91 UC1.AG6
HDMI_HPLUG: length 10.5
  BOTTOM w0.102: RX34.1 14.19,112.74 14.18,112.72 RX15.2 14.6,111.92 14.63,111.92 CX20.1 14.63,111.01 v2(12.73,111.01) 10.94,111.01 JHDMI.19
HOST_ALERT1_R_N: length 22.8
  TOP w0.102: v2(145.03,113.34) 144.59,112.89 v1(144.59,112.88)
  IN1 w0.084: v1(126.65,112.09) 127.03,112.47 129.57,112.47 130,112.04 130,112.02 130,110.87 130.74,110.12 134.51,110.12 134.74,110.35 136.23,110.35 137.15,111.26 137.68,111.26
  IN1 w0.127: v1(144.59,112.88) 144.53,112.94 143.65,112.94 141.98,111.26 137.68,111.26
  BOTTOM w0.089: UC1.AD7 126.34,112.4 v1(126.65,112.09)
  BOTTOM w0.102: v1(144.59,112.88) 144.67,112.8 RC120.2
HPOUT-L: length 15.8
  TOP w0.203: UA1.32 23.45,20.05 23.24,20.26 23.21,20.26 23.13,20.33 22.71,20.33 v1(22.44,20.07)
  IN1 w0.254: v1(22.44,20.07) 22.44,20.08 22.19,20.33 20.65,20.33 19.52,19.21 19.52,15.89 21.77,13.65 v1(23.13,13.65)
  BOTTOM w0.254: v1(23.13,13.65) v2(23.13,12.57) 23.13,12.25 23.78,11.61 RA55.1
HPOUT-R: length 13.8
  TOP w0.203: v1(23,19.85) 23.02,19.85 23.02,19.72 23.09,19.65 UA1.33
  IN1 w0.254: v1(23.84,13.68) 23.33,14.18 21.95,14.18 20.03,16.11 20.03,19 20.86,19.82 21.97,19.82 22.23,19.56 22.66,19.56 22.68,19.58 22.73,19.58 v1(23,19.85)
  BOTTOM w0.254: RA56.1 24.04,13.47 v1(23.84,13.68)
I2C0_SCL: length 7.9
  BOTTOM w0.089: RP53.4 135.2,124.78 133.25,122.82 130.6,122.82 130.4,122.63 130.07,122.63 129.88,122.44 129.37,122.44 UC1.F3
I2C0_SDA: length 7
  BOTTOM w0.076: 132.41,122.65 130.73,122.65 130.54,122.46 130.14,122.46 129.77,122.09 UC1.F2
  BOTTOM w0.089: RP53.3 134.95,124.28 133.32,122.65 132.41,122.65
I2C1_SCL_TCH_PAD: length 6.1
  BOTTOM w0.089: RP53.2 135.27,123.78 135.13,123.63 134.67,123.63 v3(134.37,123.33) 133.51,122.47 130.98,122.47 130.74,122.22 130.38,122.22 UC1.F1
I2C1_SDA_TCH_PAD: length 8.3
  BOTTOM w0.089: UC1.G4 128.7,121.75 130.38,121.75 130.64,122.01 130.83,122.01 131.07,122.25 133.6,122.25 134.52,123.18 134.76,123.42 135.13,123.42 135.27,123.28 RP53.1
ILMT_1.05V: length 4.2
  BOTTOM w0.254: PU300.3 146.13,154.53 v2(146.64,154.02) 146.95,153.7 146.95,153.6 147.77,152.78 PR304.2 PR306.1
ILMT_VDDCI: length 4.7
  BOTTOM w0.254: PR1202.1 PR1203.2 181.32,185.68 180.9,185.27 v2(180.65,185.27) 180.23,185.27 179.39,184.43 PU1200.3
IMON_CPU: length 4.5
  BOTTOM w0.102: PR501.2 88.33,142.42 v2(88.33,143.11)
  BOTTOM w0.203: PU501.13 89.42,141.02 PC508.2
  BOTTOM w0.254: PC508.2 89.67,141.3 88.83,142.14 PR501.2
IMVP_PWRGD: length 237.3
  TOP w0.102: UE1.85 v1(187.59,50.05)
  TOP w0.254: PR540.1 83.58,135.58 PC523.1 83.15,134.63 86.21,131.57 86.21,131.35 86.4,131.16 86.4,125.1 85.78,124.48 84.24,124.48 82.99,123.24 74.25,123.24 55.99,104.98 55.99,101.94 v2(55.2,101.15) 54.51,100.47 v1(54.51,95.45)
  IN3 w0.127: v1(54.51,95.45) 58.26,91.7 58.26,58.05 68.9,47.4 114.88,47.4 115.35,46.94 141.36,46.94 141.49,47.07 168.5,47.07 168.72,47.28 177.72,47.28 178.91,48.47 184.89,48.47 186.46,50.05 v1(187.59,50.05)
INT-SPK-L+: length 38.4
  TOP w0.203: 26.89,16.2 27.02,16.33 27.02,16.96 26.88,17.09 UA1.42
  IN1 w0.762: 27.52,16.97 28.35,17.79 30.25,17.79 31.02,17.03 40.54,17.03 42.38,18.87 48.73,18.87 54.51,24.65 60.54,24.65
  vias: v1(26.31,15.35) v1(26.72,15.77) v1(61.75,24.84) v1(62.39,24.84)
INT-SPK-L-: length 36.8
  TOP w0.203: 27.31,15.92 27.35,15.97 27.35,17.09 27.28,17.16 UA1.43
  IN1 w0.762: 29.18,16.65 29.78,16.65 30.54,15.89 41.02,15.89 42.86,17.73 49.21,17.73 54.99,23.51 60.67,23.51
  vias: v1(26.79,14.96) v1(27.21,15.38) v1(61.69,23.63) v1(62.32,23.63)
INT-SPK-R+: length 37
  TOP w0.203: UA1.45 28.08,16.88 28.01,16.81 28.01,15.75 28.32,15.44
  TOP w0.508: 63.75,21.63 LA4.1
  IN1 w0.762: 60.29,21.85 54.95,21.85 49.68,16.58 43.33,16.58 41.34,14.59 30.09,14.59
  IN1 w1.016: 30,14.68 30.09,14.59
  BOTTOM w0.102: v1(29.05,14.87) v2(29.93,14.87)
  vias: v1(28.48,15) v1(62.58,21.98) v1(63.21,21.98)
INT-SPK-R-: length 39.1
  TOP w0.203: UA1.44 27.68,15.15 v1(27.83,15)
  TOP w0.508: 63.75,21 LA3.1
  IN1 w0.762: 28.48,13.6 28.63,13.45 41.81,13.45 43.8,15.44 50.15,15.44 55.42,20.71 60.23,20.71
  BOTTOM w0.102: v2(28.5,13.5) 27.83,14.17 v1(27.83,14.36)
  vias: v1(62.51,20.65) v1(63.15,20.65)
INTRUDER#: length 11.7
  BOTTOM w0.076: 127.19,102.72 127.19,104.05 127.23,104.09 127.23,104.59 UC1.AU6
  BOTTOM w0.089: 127.19,102.72 127.47,102.45 127.47,102.22 127.47,102.07 128.13,101.41 128.31,101.41 129.04,100.68 129.72,100.68 130.44,99.97 v2(131.01,99.97) 131.36,99.97 131.57,100.18
  BOTTOM w0.102: 131.57,100.18 134.38,100.18 RC7.2
ISOLATEB: length 3.2
  BOTTOM w0.102: RL33.2 RL35.2 41.87,84.47 v2(40.93,84.47) UL1.20
ISUM+: length 8.2
  BOTTOM w0.203: PU800.10 202.85,57.01 202.72,56.88 202.34,56.88 202.27,56.96 202.26,56.96 202.19,57.03 201.76,57.03
  BOTTOM w0.254: PR829.2 199.1,59.27 PC819.1 PC820.1 PR827.1 ; PR827.1 199.13,57.47 v2(200.02,57.47) 201.32,57.47 201.76,57.03 ; PR827.1 PR816.1
ISUM-: length 4.2
  BOTTOM w0.102: v2(200.84,56.46) 200.84,56.21 201.54,55.51 PR825.1
  BOTTOM w0.203: 202.02,56.65 202.12,56.55 202.86,56.55 202.92,56.61 PU800.9
  BOTTOM w0.254: 202.02,56.65 201.84,56.65 201.59,56.4 PR825.1
ISUM-1: length 32.2
  TOP w0.254: v1(197.58,60.27) v2(197.58,59.28) 197.58,57.99 v1(200.05,55.51) 200.05,55.07 200.5,54.62 PC821.2
  BOTTOM w0.254: PR825.2 v1(200.05,55.51) ; PR827.2 PC820.2 PC819.2 198.21,59.27 PR830.2 197.72,60.13 v1(197.58,60.27) 197.58,61.61 200.43,64.46 200.43,74.43 201.77,75.77 201.77,76.89 203.34,78.46 203.57,78.46 PH800.2
ISUM-2: length 26.1
  BOTTOM w0.254: PR816.2 198.09,56.59 197.64,57.03 197.64,59.38 197.07,59.95 197.07,60.59 197.2,60.72 197.2,61.76 200.05,64.62 200.05,74.69 v2(201.33,75.96) 201.33,76.99 203.18,78.84 203.62,78.84 PH800.1
JACK_PLUG#: length 28.9
  TOP w0.102: v2(29.35,28.06) 29.41,28.06 30.1,27.37 RA1.2
  TOP w0.254: v1(30.13,24.71) 30.57,25.16 RA4.1 30.69,25.59 31.14,26.05 31.14,27.19 30.97,27.37 RA1.2
  IN1 w0.254: JHP.5 15.69,21.54 19.14,21.54 19.46,21.85 20.56,21.85 20.91,22.21 21.39,22.21 22.06,21.54 23.28,21.54 25.11,23.37 28.78,23.37 v1(30.13,24.71)
  BOTTOM w0.254: RA3.1 28.97,23.56 v1(30.13,24.71)
JACK_SENSE#: length 14
  TOP w0.254: v1(29.01,25.08) 29.01,26.2 29.32,26.5 RA51.2 RA4.2
  IN3 w0.254: v1(29.01,25.08) 29.24,25.31 29.24,26.37 28.49,27.13 25.49,27.13 23.92,25.55 v1(23.92,25.13)
  BOTTOM w0.254: v1(23.92,25.13) 24.37,24.68 v2(24.98,24.68) 25.58,24.68 25.85,24.95 QA5.3
JHDD_P10: length 15.3
  TOP w0.102: v2(216.08,59.83) 216.79,59.12 RS8.2 RS7.2 216.79,56.17 219.06,53.9 JHDD.10
KB_CAPS_PWR: length 3.1
  TOP w0.102: JKB.4 v1(227.55,157.42)
  BOTTOM w0.102: RE60.2 227.66,157.31 v1(227.55,157.42) 226.8,157.42 v2(226.45,157.76)
KB_DET#: length 31.3
  IN3 w0.084: v1(126.97,107.77) 127.41,108.21 127.41,108.66 128.95,110.2 128.95,110.63 129.23,110.9 129.51,110.9 131.35,112.74 134.58,112.74 135.49,111.83 137.82,111.83
  IN3 w0.127: 137.82,111.83 142.79,111.83 143.81,110.81 145.17,110.81 145.86,110.12 v1(149.57,110.12)
  BOTTOM w0.089: UC1.AN5 127.25,107.48 v1(126.97,107.77)
  BOTTOM w0.102: v1(149.57,110.12) 150.09,110.64 150.09,112.16 v2(149.41,112.85) 148.44,112.85 RC103.1
KB_LED_PWM: length 2.2
  TOP w0.102: v2(190.38,34.05) 190.66,34.33 190.99,34.33 191.19,34.53 UE1.21
KB_RST#: length 148.9
  TOP w0.102: v1(183.71,37.2) 183.59,37.07 UE1.2
  IN1 w0.127: v1(147.67,115.96) 148.43,115.2 148.43,113.63 149.46,112.6 150.02,112.6 154.15,108.47 154.15,105.67 155.22,104.6 155.22,102.78 169.69,88.31 174.06,88.31 179.1,83.27 183.12,83.27 190.31,76.08 190.31,66.04 191.39,64.96 191.39,57.93 192.88,56.44 192.88,55.41 194.05,54.24 194.05,54.07 194.31,53.81 194.31,50.51 194.11,50.31 194.11,40.44 191.42,37.75 v1(191.42,37.73)
  IN3 w0.084: 137.82,113.6 136.87,114.55 132.05,114.55 131.2,115.39 128.35,115.39 v1(127.85,115.89)
  IN3 w0.127: 137.82,113.6 138.09,113.33 141.16,113.33 142.97,115.14 143.94,115.14 144.23,115.42 146.87,115.42 147.41,115.96 v1(147.67,115.96) ; v1(191.42,37.73) 190.97,37.29 190.97,37 190.3,36.33 184.22,36.33 183.71,36.84 v1(183.71,37.2)
  BOTTOM w0.089: v1(127.85,115.89) 128.33,115.41 UC1.V4
  BOTTOM w0.102: v1(147.67,115.96) 147.48,115.77 146.45,115.77 146,116.22 v2(146,117.1) 146,117.69 144.61,119.07 143.28,119.07 142.9,119.45 142.36,119.45 141.22,120.59 141.22,120.62 141.21,120.63 141.21,121.96 141.57,122.32 RP43.8
KSI0: length 132.1
  TOP w0.102: v1(198.47,46.18) 198.4,46.11 UE1.55 ; JKB.22 225.07,143.02 223.56,141.51 221.89,141.51 v1(221.83,141.46)
  IN3 w0.127: v1(221.83,141.46) 221.31,140.93 221.31,139.13 221.63,138.81 221.63,137.02 220.53,135.91 220.53,131.2 219.77,130.44 219.77,121.73 219.65,121.61 219.65,104.82 214.79,99.96 214.79,91.99 215.88,90.89 217.38,90.89 220.1,88.17 220.1,85.61 218.76,84.27 218.76,78.56 221.23,76.1 221.23,61.57 220.59,60.93 220.59,51.41 216.3,47.13 199.4,47.13 198.47,46.19 v1(198.47,46.18)
  BOTTOM w0.102: v1(198.47,46.18) v2(197.5,46.18)
KSI1: length 130.3
  TOP w0.102: v1(199.05,46.18) 198.64,46.58 198.24,46.58 198.16,46.51 UE1.56 ; JKB.24 224.37,141.42 223.23,140.28 v1(221.9,140.28)
  IN3 w0.127: v1(221.9,140.28) 221.77,140.28 221.57,140.08 221.57,139.27 221.89,138.96 221.89,136.17 220.78,135.06 220.78,131.1 220.03,130.35 220.03,121.4 220.62,120.82 220.62,116.77 219.91,116.06 219.91,104.73 215.95,100.77 215.95,96.9 215.96,96.89 215.96,94.39 215.97,94.38 215.97,92.81 217.2,91.58 217.98,91.58 220.35,89.21 220.35,85.5 219.03,84.18 219.03,78.67 221.48,76.22 221.48,61.47 220.84,60.83 220.84,51.3 216.4,46.86 199.72,46.86 199.05,46.19 v1(199.05,46.18)
  BOTTOM w0.102: v1(199.05,46.18) v2(199.05,46.99)
KSI2: length 130.3
  TOP w0.102: JKB.26 227.47,139.82 227.07,139.43 222.02,139.43 v1(222,139.45) ; UE1.57 198.16,46.91 198.26,46.81 199,46.81 v1(199.63,46.18)
  IN3 w0.127: v1(199.63,46.18) 199.63,46.19 200.04,46.6 216.51,46.6 221.09,51.18 221.09,60.72 221.73,61.36 221.73,76.33 219.29,78.78 219.29,84.08 220.61,85.4 220.61,89.31 218.09,91.83 217.31,91.83 216.22,92.91 216.22,94.49 216.21,94.5 216.21,99.74 221.58,105.1 221.58,109.16 220.9,109.84 220.9,110.24 220.17,110.96 220.17,115.95 220.88,116.66 220.88,120.92 220.29,121.51 220.29,130.25 221.03,130.99 221.03,134.94 222.17,136.08 222.17,139.27 v1(222,139.45)
  BOTTOM w0.102: v2(222,138.79) v1(222,139.45)
KSI3: length 134.9
  TOP w0.102: v4(201.04,45.41) 200.28,46.18 v1(200.22,46.18) 199.81,46.59 199.55,46.59 199.09,47.04 198.4,47.04 198.13,47.31 UE1.58 ; v1(221.9,140.88) 223.5,140.88 224.85,142.22 JKB.23
  IN3 w0.127: v1(200.22,46.18) 216.46,46.18 221.35,51.06 221.35,60.62 221.99,61.27 221.99,76.44 219.59,78.85 219.59,84.02 220.86,85.29 220.86,90.35 219.13,92.09 217.41,92.09 216.48,93.01 216.48,93.22 216.48,93.22 216.48,94.24 216.48,94.25 216.48,99.24 217.78,100.54 219.82,100.54 221.84,102.56 221.84,109.27 221.16,109.95 221.16,110.35 220.44,111.07 220.44,115.43 221.16,116.15 221.16,129.87 222.64,131.35 222.64,140.44 222.21,140.88 v1(221.9,140.88)
KSI4: length 129
  TOP w0.102: v4(200.09,46.89) 200.05,46.92 199.79,46.92 199.42,47.29 198.88,47.29 v1(198.47,47.71) UE1.59 ; JKB.27 222.73,139.02 222.07,138.36 v1(220.95,138.36)
  IN3 w0.127: v1(198.47,47.71) 198.47,47.77 199.54,48.84 209.66,48.84 210.33,48.17 215.87,48.17 219.57,51.88 219.57,61.36 220.21,62 220.21,75.64 217.72,78.13 217.72,84.34 217.72,84.35 217.72,84.74 219.08,86.09 219.08,87.75 216.96,89.88 215.46,89.88 213.74,91.6 213.74,100.35 217.58,104.19 217.58,121.02 218.72,122.16 218.72,130.84 219.51,131.62 219.51,136.92 v1(220.95,138.36)
KSI5: length 129.5
  TOP w0.102: v1(199.05,47.71) 199.05,48.21 v4(198.97,48.28) 198.48,48.28 198.3,48.11 UE1.60 ; v1(220.93,138.94) 220.93,139.25 221.56,139.87 226.17,139.87 226.91,140.62 JKB.25
  IN3 w0.127: v1(220.93,138.94) 220.96,138.94 221.37,138.53 221.37,138.18 221.12,137.94 220.89,137.94 219.76,136.81 219.76,131.52 218.99,130.74 218.99,122.06 218.87,121.94 218.87,105.12 214,100.25 214,91.69 215.57,90.13 217.06,90.13 219.34,87.86 219.34,85.99 217.98,84.63 217.98,78.24 220.46,75.75 220.46,61.89 219.82,61.25 219.82,51.76 215.98,47.91 210.23,47.91 209.57,48.58 199.86,48.58 199.05,47.77 v1(199.05,47.71)
KSI6: length 129.8
  TOP w0.102: v4(201.82,47.17) 201.7,47.28 200.06,47.28 v1(199.63,47.71) 199.63,48.2 199.17,48.66 198.23,48.66 198.07,48.51 UE1.61 ; v1(221,137.44) 226.2,137.44 226.98,138.22 JKB.28
  IN3 w0.127: v1(199.63,47.71) 199.63,47.79 200.17,48.32 209.45,48.32 210.12,47.65 216.09,47.65 220.08,51.64 220.08,61.15 220.72,61.78 220.72,75.87 218.24,78.35 218.24,84.47 219.59,85.82 219.59,87.96 217.17,90.38 215.67,90.38 214.27,91.78 214.27,92.43 214.26,92.44 214.26,100.16 219.13,105.02 219.13,121.83 219.25,121.95 219.25,130.64 220.02,131.41 220.02,136.69 220.77,137.44 v1(221,137.44)
KSI7: length 127.9
  TOP w0.102: JKB.29 227.1,137.42 226.55,136.87 v1(220.88,136.87) ; UE1.62 200.41,48.91 v4(200.76,48.55) 200.76,48.25 v1(200.22,47.71)
  IN3 w0.127: v1(200.22,47.71) 200.58,48.06 209.35,48.06 210.02,47.39 216.19,47.39 220.33,51.53 220.33,61.04 220.97,61.68 220.97,75.99 218.5,78.45 218.5,83.45 218.51,83.46 218.51,84.38 219.84,85.71 219.84,88.07 217.27,90.64 215.78,90.64 214.52,91.89 214.52,100.06 219.39,104.92 219.39,121.72 219.51,121.84 219.51,130.54 220.27,131.31 220.27,136.26 v1(220.88,136.87)
KSO0: length 137.9
  TOP w0.102: UE1.39 198.57,39.71 199.14,40.28 200.84,40.28 201.2,39.93 201.87,39.93 202.89,40.94 v1(202.89,41.16) v4(202.89,41.81) ; v1(227.62,150.38) 227.78,150.22 JKB.13
  IN3 w0.127: v1(202.89,41.16) 203.08,40.97 205.67,40.97 206.5,41.79 216.16,41.79 224.84,50.48 224.84,77.66 222.47,80.04 222.47,82.85 224.72,85.1 224.72,110.47 224.04,111.14 224.04,122.07 224.62,122.65 224.62,128.89 226.41,130.67 226.41,149.07 227.62,150.29 v1(227.62,150.38)
KSO1: length 139.7
  TOP w0.102: UE1.40 198.64,40.11 199.05,40.51 200.94,40.51 201.26,40.19 201.74,40.19 202.3,40.75 v1(202.3,41.16) ; JKB.15 227.33,148.62 227.1,148.85 227.1,149.17 v1(227.61,149.68)
  IN3 w0.127: v1(227.61,149.68) 227.61,149.67 226.67,148.72 226.67,130.57 224.89,128.78 224.89,121.65 224.3,121.06 224.3,111.25 224.98,110.57 224.98,93.34 227.93,90.39 227.93,78.48 225.11,75.65 225.11,50.37 216.27,41.53 206.61,41.53 205.79,40.71 202.73,40.71 202.3,41.14 v1(202.3,41.16)
  BOTTOM w0.102: v1(227.61,149.68) 227.55,149.68 v2(227.09,149.22)
KSO2: length 137.6
  TOP w0.102: v1(201.72,41.16) 201.72,40.73 v4(201.6,40.61) 201.23,40.61 201.1,40.74 198.95,40.74 198.72,40.51 UE1.41 ; JKB.14 227.96,149.42 v1(227.59,149.05)
  IN3 w0.127: v1(201.72,41.16) 201.72,41.14 202.41,40.45 203.43,40.45 204.14,39.74 211.21,39.74 211.91,40.44 212.1,40.44 212.12,40.45 215.56,40.45 225.37,50.26 225.37,75.54 228.2,78.37 228.2,90.5 225.24,93.45 225.24,110.68 224.56,111.36 224.56,120.95 225.15,121.54 225.15,128.68 226.93,130.46 226.93,148.39 v1(227.59,149.05)
KSO3: length 136.7
  TOP w0.102: JKB.16 227.89,147.82 227.61,148.1 v1(227.61,148.21) ; UE1.42 198.43,40.91 198.68,41.16 v4(198.97,41.16) v1(201.13,41.16)
  IN3 w0.127: v1(227.61,148.21) 227.19,147.79 227.19,130.35 225.41,128.57 225.41,121.43 224.82,120.85 224.82,111.47 225.5,110.79 225.5,93.56 228.46,90.6 228.46,78.26 225.63,75.43 225.63,50.15 215.67,40.19 212.5,40.19 212.49,40.18 212.02,40.18 211.32,39.48 204.04,39.48 203.34,40.18 203.3,40.18 203.28,40.19 202.09,40.19 201.13,41.14 v1(201.13,41.16)
KSO4: length 137.5
  TOP w0.102: v1(199.05,41.86) 198.5,41.31 UE1.43 ; v1(225.98,147.46) 225.96,147.46 225.45,146.94 225.45,145.25 226.08,144.62 JKB.20
  IN3 w0.127: v1(199.05,41.86) 199.05,41.87 199.46,42.28 200.69,42.28 200.76,42.35 215.99,42.35 224.32,50.69 224.32,77.45 221.94,79.83 221.94,83.07 224.19,85.32 224.19,110.25 223.52,110.93 223.52,122.28 224.1,122.87 224.1,129.11 225.32,130.33 225.43,130.44 225.43,146.88 225.98,147.43 v1(225.98,147.46)
  BOTTOM w0.102: v2(225.4,147.66) 225.61,147.46 v1(225.98,147.46)
KSO5: length 140.4
  TOP w0.102: v1(198.47,41.86) 198.32,41.71 UE1.44 ; v1(225.96,148.04) 225.22,147.3 225.22,145.15 226.55,143.82 JKB.21
  IN3 w0.127: v1(225.96,148.04) 225.86,147.94 225.86,147.94 225.17,147.24 225.17,130.55 224.95,130.33 224.95,130.33 223.84,129.22 223.84,122.98 223.25,122.39 223.25,110.82 223.93,110.14 223.93,85.43 221.68,83.17 221.68,79.72 224.07,77.33 224.07,60.46 223.38,59.78 223.38,50.12 215.88,42.61 200.53,42.61 200.5,42.58 199.17,42.58 198.47,41.87 v1(198.47,41.86)
  BOTTOM w0.102: v1(198.47,41.86) 196.43,41.86 v2(196.37,41.8)
KSO6: length 136.7
  TOP w0.102: v1(199.63,41.86) 199.21,42.28 198.28,42.28 198.1,42.11 UE1.45 ; JKB.18 228.03,146.22 227.61,146.63 v1(227.61,146.7)
  IN3 w0.127: v1(199.63,41.86) 199.63,41.84 201.55,39.93 202.72,39.93 202.73,39.92 203.24,39.92 203.93,39.23 211.42,39.23 212.12,39.93 215.77,39.93 225.89,50.05 225.89,75.32 228.72,78.15 228.72,90.71 225.76,93.67 225.76,110.9 225.09,111.58 225.09,120.74 225.67,121.32 225.67,128.46 227.61,130.4 v1(227.61,146.7)
  BOTTOM w0.102: v2(228.24,146.7) v1(227.61,146.7)
KSO7: length 134.4
  TOP w0.102: UE1.46 199.57,42.51 v1(200.22,41.86) 200.42,41.86 v4(200.71,42.15) ; JKB.19 227.39,145.42 v1(225.98,146.83)
  IN3 w0.127: v1(225.98,146.83) 225.94,146.79 225.94,130.58 225.58,130.22 224.36,129 224.36,122.76 223.78,122.18 223.78,111.04 224.46,110.36 224.46,85.21 222.2,82.96 222.2,79.93 224.58,77.56 224.58,50.58 216.09,42.09 201.37,42.09 201.13,41.86 v1(200.22,41.86)
KSO8: length 140.1
  TOP w0.102: v1(198.47,43) 198.37,42.91 UE1.47 ; v1(227.62,147.49) 227.62,147.32 227.92,147.02 JKB.17
  IN3 w0.127: v1(227.62,147.49) 228.18,146.93 228.18,130.6 225.93,128.35 225.93,121.21 225.35,120.63 225.35,111.69 226.03,111.01 226.03,93.78 228.98,90.82 228.98,74.59 226.18,71.79 226.18,60.27 226.15,60.24 226.15,49.94 215.88,39.67 212.31,39.67 211.61,38.97 203.83,38.97 203.13,39.67 200.06,39.67 198.04,41.68 198.04,42.58 v1(198.47,43)
  BOTTOM w0.102: v1(198.47,43) 198.41,43 v2(198.01,43.4)
KSO9: length 142.2
  TOP w0.102: JKB.7 227.05,155.02 v1(225.97,156.09) ; v1(199.05,43) 198.61,43.44 198.28,43.44 198.14,43.31 UE1.48
  IN3 w0.127: v1(225.97,156.09) 225.97,149.75 224.15,147.93 224.15,130.64 223.05,129.54 223.05,123.3 222.47,122.72 222.47,110.49 223.15,109.82 223.15,85.75 220.9,83.5 220.9,79.39 223.3,76.98 223.3,60.78 222.62,60.09 222.62,50.46 216.61,44.45 213.01,44.45 211.95,43.4 200.84,43.4 200.54,43.7 199.73,43.7 199.05,43.01 v1(199.05,43)
  BOTTOM w0.102: v2(225.4,156.09) v1(225.97,156.09)
KSO10: length 144
  TOP w0.102: v4(201.54,43.72) 201.54,43.67 200.46,42.59 200.04,42.59 v1(199.63,43) 198.93,43.71 UE1.49 ; JKB.5 227.08,156.62 v1(226.56,156.09)
  IN3 w0.127: v1(199.63,43) 199.63,43.01 200.04,43.42 200.45,43.42 200.73,43.14 212.06,43.14 213.12,44.19 216.71,44.19 222.87,50.36 222.87,59.99 223.56,60.67 223.56,77.1 221.16,79.5 221.16,83.39 223.41,85.64 223.41,109.92 222.73,110.6 222.73,122.61 223.32,123.19 223.32,129.43 224.41,130.53 224.41,147.82 226.73,150.14 226.73,155.92 v1(226.56,156.09)
KSO11: length 141
  TOP w0.102: JKB.6 227.35,155.82 v1(227.14,156.03) ; UE1.50 199.11,44.11 v4(199.66,43.56) v1(200.22,43)
  IN3 w0.127: v1(227.14,156.03) 227.14,150.17 224.67,147.71 224.67,130.42 223.58,129.33 223.58,123.09 222.99,122.5 222.99,110.71 223.67,110.03 223.67,85.53 221.42,83.28 221.42,79.61 223.81,77.21 223.81,60.57 223.13,59.88 223.13,50.23 215.77,42.87 200.63,42.87 200.5,43 v1(200.22,43)
KSO12: length 142.5
  TOP w0.102: UE1.51 198.39,44.51 v1(198.47,44.59) ; v1(223.61,151.02) JKB.12
  IN3 w0.127: v1(223.61,151.02) 223.61,149.45 222.91,148.74 222.91,131.25 221.42,129.76 221.42,116.04 220.7,115.32 220.7,111.18 221.42,110.46 221.42,110.06 222.1,109.38 222.1,102.45 219.93,100.28 217.89,100.28 216.74,99.13 216.74,93.12 217.52,92.34 219.23,92.34 221.11,90.46 221.11,85.19 219.85,83.92 219.85,78.96 222.26,76.55 222.26,61.17 221.6,60.51 221.6,50.93 216.43,45.75 199.62,45.75 198.47,44.6 v1(198.47,44.59)
  BOTTOM w0.102: v2(224.2,151.02) v1(223.61,151.02)
KSO13: length 138.8
  TOP w0.102: JKB.9 224.79,153.42 v1(224.03,152.66) ; UE1.52 198.13,44.91 198.21,44.99 198.64,44.99 v1(199.05,44.59)
  IN3 w0.127: v1(199.05,44.59) 199.05,44.6 199.8,45.35 216.39,45.35 221.86,50.81 221.86,60.41 222.52,61.07 222.52,76.66 221.07,78.1 220.11,79.07 220.11,83.82 222.36,86.08 222.36,109.49 221.68,110.17 221.68,110.56 220.96,111.29 220.96,115.21 221.68,115.94 221.68,129.66 223.32,131.29 223.32,148.63 224.03,149.34 v1(224.03,152.66)
  BOTTOM w0.102: v2(199.1,45.19) 199.1,44.64 v1(199.05,44.59)
KSO14: length 139.8
  TOP w0.102: JKB.8 v1(225.07,154.22) ; v1(199.63,44.59) 199.23,44.99 199.02,44.99 198.8,45.22 198.17,45.22 198.09,45.31 UE1.53
  IN3 w0.127: v1(199.63,44.59) 199.63,44.6 200.07,45.03 216.45,45.03 222.11,50.7 222.11,60.3 222.78,60.97 222.78,76.77 221.71,77.84 220.37,79.17 220.37,83.72 222.62,85.97 222.62,109.6 221.95,110.28 221.95,110.67 221.22,111.4 221.22,115.1 221.95,115.83 221.95,129.55 223.58,131.18 223.58,148.32 224.56,149.3 224.56,153.71 v1(225.07,154.22)
  BOTTOM w0.102: v2(225.72,154.22) v1(225.07,154.22)
KSO15: length 137.4
  TOP w0.102: UE1.54 198.11,45.71 198.27,45.55 199.03,45.55 v4(199.2,45.38) 199.55,45.38 200.22,44.71 v1(200.22,44.59) ; v1(225.01,152.62) JKB.10
  IN3 w0.127: v1(225.01,152.62) 225.01,149.3 223.89,148.18 223.89,131.12 223.49,130.72 223.49,130.35 222.79,129.65 222.79,123.41 222.21,122.83 222.21,110.38 222.89,109.71 222.89,85.86 220.63,83.61 220.63,79.28 223.04,76.88 223.04,60.87 222.36,60.2 222.36,50.58 216.5,44.71 200.35,44.71 v1(200.22,44.59)
KSO16: length 149.9
  TOP w0.102: UE1.81 189.19,49.93 190.19,48.93 191.65,48.93 193.11,47.47 v1(195.05,47.47) ; v1(223.59,151.62) 223.64,151.57 228.35,151.57 JKB.11
  IN3 w0.127: v1(223.59,151.62) 222.64,150.68 222.64,143.12 221.05,141.53 221.05,139.66 219.26,137.87 219.26,131.73 218.46,130.93 218.46,122.27 217.2,121.01 217.2,105.1 213.48,101.38 213.48,91.5 215.36,89.62 216.85,89.62 218.83,87.64 218.83,86.2 217.46,84.83 217.46,78.02 219.96,75.52 219.96,62.1 219.32,61.46 219.32,51.99 215.76,48.44 210.43,48.44 209.76,49.1 198.97,49.1 197.34,47.47 v1(195.05,47.47)
  BOTTOM w0.102: v1(195.05,47.47) 194.47,48.05 v2(194.24,48.05)
LAN_CLKREQ#: length 162.2
  TOP w0.102: RP42.8 145.94,112.74 144.38,111.17 143.59,111.17 143.09,111.67 v2(139.42,111.67) 139.4,111.69 135.36,111.69 135.03,112.02 135.03,112.83 134.71,113.16 133.88,113.16 133.74,113.29 v1(132.48,113.29)
  IN2 w0.089: 121.39,93.61 124.12,96.34 125.38,96.34 126.65,97.61 129.87,97.61 130.33,98.07 130.33,98.56 130.65,98.88 130.65,102.63 130.09,103.18 130.09,111.09 132.3,113.29 v1(132.48,113.29)
  IN2 w0.127: v1(35.61,71.26) 44.58,71.26 58.36,85.04 112.82,85.04 121.39,93.61
  IN3 w0.127: v1(37.24,87.32) 33.42,83.5 33.42,73.51 35.61,71.31 v1(35.61,71.26)
  BOTTOM w0.089: v1(132.48,113.29) 131.65,112.47 130.4,112.47 UC1.AD1
  BOTTOM w0.102: UL1.12 37.55,87.01 v1(37.24,87.32) 37.05,87.5 RL37.1
LAN_X1_R: length 1.7
  TOP w0.102: RG5.1 72.63,39.3 UG1.6
LCD_CBL_DET#: length 7.3
  BOTTOM w0.076: UC1.J3 129.47,121.05 130.4,121.05 130.57,121.22 130.57,121.39 130.76,121.58 130.95,121.58 131.26,121.89 133.16,121.89 133.42,121.64 134.98,121.64 RC106.2
LCD_TEST: length 170.1
  TOP w0.102: v1(193.48,53.2) 193.4,53.2 192.79,52.58 UE1.72
  IN2 w0.127: v1(214.89,174.45) 214.67,174.22 214.67,166.47 216.28,164.85 216.28,155.09 225.34,146.04 225.34,121.81 224.44,120.91 224.44,110.95 225.86,109.53 225.86,96.68 225.31,96.13 225.31,88.74 228.3,85.74 228.3,77.41 222.41,71.51 222.41,58.81 217.19,53.6 v1(217.19,53.1)
  BOTTOM w0.102: v1(193.48,53.2) 194.31,52.37 197.23,52.37 200.34,49.26 201.21,49.26 201.27,49.2 209.18,49.2 v2(210.31,50.33) 211.18,51.2 213.88,51.2 214.77,52.09 215.27,52.09 216.28,53.1 v1(217.19,53.1) ; JLVDS.33 220.45,174.05 220.06,174.45 220.06,174.7 219.74,175.02 218.53,175.02 217.58,175.97 215.93,175.97 215.42,175.46 215.42,174.98 v1(214.89,174.45)
LDO_3V: length 6.3
  IN3 w0.254: v1(149.7,152.96) 149.53,152.78 149.07,152.78 v3(146.34,155.51)
  BOTTOM w0.102: v1(149.7,152.96) v2(150.73,152.96)
  BOTTOM w0.254: v1(149.7,152.96) 149.53,152.78 PR304.1
LDO_3V_VDDCI: length 8.4
  IN3 w0.254: v1(178.34,184.41) 179.04,185.11 179.04,187.08 179.66,187.7 v1(181.32,187.7)
  BOTTOM w0.102: v1(181.32,187.7) 181.32,187.78 v2(181.69,188.14)
  BOTTOM w0.254: PR1203.1 v1(181.32,187.7) ; PU1200.5 178.49,184.26 v1(178.34,184.41) 178.22,184.53 PC1213.1
LG_3V: length 2.8
  TOP w0.635: 129.65,19.12 129.8,19.27 129.8,20.7 v2(130.03,20.93) 130.18,21.08 130.18,21.68
LG_5V: length 7.1
  IN3 w0.762: 125.06,24.36 123.41,22.71 123.41,20.84 124.87,19.38 125.19,19.38
  BOTTOM w0.102: v3(125.31,25.5) 125.31,25.5 v2(125.7,25.12)
  vias: v3(124.68,25.5) v3(125.89,18.73) v3(126.37,18.25)
LG_+1.2VSP: length 7.5
  IN3 w0.762: 180.31,172.98 180.31,174.44 181.13,175.27 184.43,175.27 185.13,174.57
  BOTTOM w0.102: v1(185.58,173.81) 185.58,173.68 v2(185.28,173.39)
  vias: v1(179.98,172.16) v1(180.56,172.16) v1(184.99,173.81)
LID_SW#: length 185.2
  TOP w0.102: v1(176.05,45.57) 175.87,45.39 CE30.1 176.26,44.27 v2(176.97,44.27) 177.06,44.27 178.25,43.08 178.92,43.08 RE71.2 179.49,42.51 UE1.115 ; JPWR.2 v1(44.34,93.07)
  IN3 w0.127: v1(176.05,45.57) 171.97,45.57 171.28,44.87 63.38,44.87 56.09,52.16 56.09,92 55.02,93.07 v1(44.34,93.07)
LINE1-L: length 2.3
  TOP w0.203: UA1.22 25.68,24.91 CA67.1
LINE1-R: length 2
  TOP w0.203: UA1.21 26.08,25.49 CA68.1
LINE1-VREFO-L: length 5
  TOP w0.102: v2(19.76,19.2) 20.09,19.53 21.21,19.53 RA165.1
  TOP w0.203: RA165.1 22.34,20.66 23.27,20.66 23.34,20.59 23.38,20.59 23.51,20.45 UA1.31
LINE1-VREFO-R: length 2.4
  TOP w0.203: UA1.30 23.58,20.85 23.51,20.92 23.48,20.92 23.34,21.06 v2(22.76,21.06) 21.85,21.06 RA166.1
LINE-IN-L: length 21.5
  TOP w0.254: v1(19.52,21.22) 19.52,20.66 RA83.1 RA165.2 ; v1(25.73,11.49) 25.34,11.1 LA8.2
  IN1 w0.254: v1(25.73,11.49) 22.11,11.49 18.38,15.22 18.38,19.68 19.52,20.82 v1(19.52,21.22)
  BOTTOM w0.254: v1(19.52,21.22) 19.52,20.74 v2(19.8,20.46) 20,20.27 20.78,20.27 RA165.2 ; RA55.2 25.62,11.61 v1(25.73,11.49)
LINE-IN-R: length 20.4
  TOP w0.254: v1(25.75,12.18) 25.3,12.62 LA9.2 ; RA84.1 20.04,21.15 v1(20.1,21.09) 20.17,21.03 RA166.2
  IN1 w0.254: v1(25.75,12.18) 22.14,12.18 18.76,15.56 18.76,19.52 20.1,20.87 v1(20.1,21.09)
  BOTTOM w0.102: v2(19.24,22.14) 19.8,21.58 19.91,21.58 20.1,21.39 v1(20.1,21.09)
  BOTTOM w0.254: RA166.2 20.17,21.03 v1(20.1,21.09) ; v1(25.75,12.18) 25.43,12.49 RA56.2
LPC_LAD0: length 111.9
  TOP w0.102: UE1.10 186.79,36.65 185.6,37.83 185.6,38.97 v1(185.56,39.01)
  IN1 w0.084: v1(124.81,99.88) 125.01,100.09 125.52,100.09 125.9,99.71 129.96,99.71 130.91,98.75 131.45,98.75
  IN1 w0.127: 131.45,98.75 132.39,98.75 135.71,95.44 139.06,95.44 147.75,86.75 149.77,86.75 160.15,76.37 170.78,76.37 175.03,72.12 175.03,64.72 176.76,62.99 176.76,61.57 179.59,58.74 179.59,54.38 180.37,53.6 180.37,48.79 181.08,48.08 181.08,41.29 184.45,37.92 185.04,37.92 185.56,38.44 v1(185.56,39.01)
  BOTTOM w0.076: UC1.AU14 122.74,104.59 122.74,104.11 122.7,104.07 122.7,102.74 122.95,102.49 122.95,102.34 122.95,102.33 122.95,101.8 123.93,100.82 123.93,100.47 124.52,99.88 v1(124.81,99.88)
LPC_LAD1: length 107.3
  TOP w0.102: UE1.8 185.99,36.91 185.3,37.6 185.3,38.59 v1(184.89,39)
  IN1 w0.084: v1(124.98,101.36) 125.27,101.36 126.53,100.1 130.05,100.1 130.72,99.44 131.57,99.44
  IN1 w0.127: 131.57,99.44 133.14,99.44 136.4,96.18 139.25,96.18 148.02,87.41 150.04,87.41 160.43,77.03 171.06,77.03 177.08,71.01 177.08,64.43 178.24,63.27 178.24,61.3 180.34,59.2 180.34,57.63 181.03,56.94 181.03,49.07 181.74,48.35 181.74,42.07 184.82,39 v1(184.89,39)
  BOTTOM w0.076: v1(124.98,101.36) 124.91,101.3 124.15,101.3 123.45,102 123.45,103.29 UC1.AW12
LPC_LAD2: length 106.4
  TOP w0.102: v1(184.89,38.36) 184.89,37.58 185.59,36.88 UE1.7
  IN1 w0.084: v1(125.51,100.59) 126.21,99.9 130.02,99.9 130.82,99.1 131.57,99.1
  IN1 w0.127: 131.57,99.1 133.02,99.1 136.26,95.85 139.12,95.85 147.89,87.08 149.91,87.08 160.29,76.7 170.92,76.7 175.37,72.25 175.37,65.23 177.12,63.47 177.12,61.68 179.92,58.88 179.92,57.16 180.7,56.39 180.7,48.93 181.41,48.22 181.41,41.84 v1(184.89,38.36)
  BOTTOM w0.076: v1(125.51,100.59) 125.34,100.42 124.79,100.42 123.28,101.93 123.28,102.81 UC1.AY12
LPC_LAD3: length 107
  TOP w0.102: v1(184.62,39.95) 184.48,39.81 184.48,37.55 184.92,37.12 184.92,36.74 184.79,36.6 UE1.5
  IN1 w0.084: 131.27,99.8 130.6,99.8 130.12,100.28 126.6,100.28 125.09,101.79 v1(124.52,101.79)
  IN1 w0.127: v1(184.62,39.95) 184.62,39.96 182.07,42.51 182.07,48.49 181.39,49.17 181.39,57.48 181.19,57.68 181.19,58.81 178.83,61.18 178.83,63.15 177.41,64.57 177.41,71.14 171.19,77.36 160.56,77.36 150.18,87.74 148.16,87.74 139.39,96.51 136.54,96.51 133.24,99.8 131.27,99.8
  BOTTOM w0.076: UC1.AW11 123.61,103.29 123.61,102.07 123.89,101.79 v1(124.52,101.79)
LPC_LFRAME#: length 107.4
  TOP w0.102: v1(184.51,36.9) 184.39,36.78 UE1.4
  IN1 w0.084: v1(125.38,99.71) 126.2,98.88 128.49,98.88 129.14,99.53 129.72,99.53 130.49,98.76 130.49,98.41 131.12,97.77 131.41,97.77 131.48,97.84 131.48,97.9 131.56,97.98 131.57,97.98
  IN1 w0.127: 131.57,97.98 132.7,97.98 136.18,94.5 139.54,94.5 147.61,86.42 149.63,86.42 160.02,76.04 169.64,76.04 174.7,70.98 174.7,64.58 176.35,62.94 176.35,60.61 177.94,59.02 177.94,56.87 178.25,56.57 178.25,55 180.04,53.2 180.04,48.66 180.75,47.94 180.75,41 184.51,37.24 v1(184.51,36.9)
  BOTTOM w0.076: v1(125.38,99.71) 125.38,99.88 125.01,100.25 124.73,100.25 123.12,101.86 123.12,102.56 122.86,102.81 122.86,103.98 UC1.AV12
LVDS_A0+: length 3.1
  TOP w0.102: v1(205.06,174.89) 204.91,174.74 204.91,174.06 204.92,174.05 UX4.41
  BOTTOM w0.102: JLVDS.2 204.95,174.25 204.9,174.3 204.9,174.73 v1(205.06,174.89)
LVDS_A0-: length 3.2
  TOP w0.102: v1(204.47,174.89) 204.64,174.73 204.64,174.19 204.52,174.07 UX4.42
  BOTTOM w0.102: v1(204.47,174.89) 204.63,174.73 204.63,174.43 204.45,174.25 JLVDS.1
LVDS_A1+: length 4.9
  TOP w0.102: UX4.39 205.72,173.99 205.65,174.05 205.65,174.2 206.54,175.09 206.54,175.44 v1(206.68,175.58)
  BOTTOM w0.102: JLVDS.5 206.45,174.25 206.33,174.36 206.33,174.89 206.52,175.08 206.52,175.42 v1(206.68,175.58)
LVDS_A1-: length 4.9
  TOP w0.102: UX4.40 205.32,174.01 205.39,174.08 205.39,174.31 206.28,175.2 206.28,175.4 v1(206.1,175.58)
  BOTTOM w0.102: JLVDS.4 205.95,174.25 206.07,174.36 206.07,175 206.26,175.19 206.26,175.42 v1(206.1,175.58)
LVDS_A2+: length 5.5
  TOP w0.102: v1(207.99,175.65) 207.86,175.53 207.86,174.83 207.36,174.32 206.84,174.32 206.47,173.94 206.47,173.87 206.52,173.82 UX4.37
  BOTTOM w0.102: JLVDS.8 207.95,174.25 207.83,174.36 207.83,175.5 v1(207.99,175.65)
LVDS_A2-: length 5.5
  TOP w0.102: v1(207.41,175.65) 207.6,175.46 207.6,174.94 207.25,174.58 206.73,174.58 206.2,174.05 206.2,173.94 206.12,173.86 UX4.38
  BOTTOM w0.102: v1(207.41,175.65) 207.57,175.5 207.57,174.36 207.45,174.25 JLVDS.7
LVDS_ACLK+: length 6.2
  TOP w0.102: UX4.35 208.18,172.18 v3(209.09,173.1) 209.4,173.41 209.4,175.14 v1(209.49,175.23)
  BOTTOM w0.102: JLVDS.11 209.45,174.07 209.45,175.19 v1(209.49,175.23)
LVDS_ACLK-: length 6.1
  TOP w0.102: v1(208.91,175.23) 209.13,175 209.13,173.52 208.06,172.45 207.93,172.45 207.8,172.58 UX4.36
  BOTTOM w0.102: v1(208.91,175.23) 208.92,175.23 209.18,174.96 209.18,174.38 209.11,174.31 209.08,174.31 209.08,174.31 209.05,174.31 208.95,174.21 JLVDS.10
LVDS_B0+: length 11.1
  TOP w0.102: v1(210.99,175.23) 210.98,175.21 210.98,174.7 210.89,174.61 210.89,174.17 210.16,173.45 210.16,172.32 209.24,171.4 208.92,171.4 v1(208.82,171.3) 208.64,171.47 208.5,171.47 208.37,171.35 208.37,170.9 208.12,170.65 207.85,170.65 207.78,170.58 UX4.31
  BOTTOM w0.102: RX40.2 207.79,170.71 207.96,170.71 208.3,171.05 208.3,171.29 208.48,171.47 208.64,171.47 v1(208.82,171.3) ; v1(210.99,175.23) 210.99,174.72 210.89,174.61 210.89,174.14 210.95,174.07 JLVDS.14
LVDS_B0-: length 10.9
  TOP w0.102: UX4.32 207.81,170.98 207.88,170.91 208.01,170.91 208.11,171.01 208.11,171.46 208.39,171.74 208.68,171.74 v1(208.82,171.88) 208.82,171.85 209.01,171.66 209.13,171.66 209.9,172.43 209.9,173.56 210.62,174.28 210.62,174.72 210.71,174.81 210.71,174.94 210.42,175.23 v1(210.41,175.23)
  BOTTOM w0.102: RX38.2 207.72,170.98 207.85,170.98 208.03,171.16 208.03,171.4 208.37,171.74 208.68,171.74 v1(208.82,171.88) ; JLVDS.13 210.45,174.08 210.62,174.25 210.62,174.72 210.73,174.83 210.73,174.92 210.42,175.23 v1(210.41,175.23)
LVDS_B1+: length 11.5
  TOP w0.102: UX4.29 207.8,169.78 207.86,169.85 208.18,169.85 208.33,170 208.52,170 v1(208.68,169.84) 208.82,169.99 209.36,169.99 211.08,171.7 211.08,172.2 v3(211.56,172.68) 212.15,173.27 212.47,173.6 212.47,174.56 v1(212.47,174.57)
  BOTTOM w0.102: v1(208.68,169.84) 208.53,169.99 208.33,169.99 208.18,169.83 208.18,169.12 207.98,168.92 207.78,168.92 RX44.2 ; v1(212.47,174.57) 212.44,174.54 212.44,174.08 212.45,174.06 JLVDS.17
LVDS_B1-: length 11.4
  TOP w0.102: UX4.30 207.83,170.18 207.89,170.11 208.07,170.11 208.22,170.27 208.52,170.27 v1(208.68,170.43) 208.85,170.25 209.25,170.25 210.81,171.81 210.81,172.31 211.37,172.87 212.21,173.71 212.21,174.25 v1(211.88,174.57)
  BOTTOM w0.102: v1(211.88,174.57) 211.89,174.57 212.17,174.29 212.17,174.24 211.95,174.02 JLVDS.16 ; RX42.2 207.74,169.19 207.87,169.19 207.92,169.23 207.92,169.95 208.22,170.25 208.5,170.25 v1(208.68,170.43)
LVDS_B2+: length 14.5
  TOP w0.102: v1(213.99,174.53) 213.99,173.72 211.89,171.62 211.89,170.88 210.21,169.2 209.32,169.2 209.13,169.01 v1(209.13,168.81) 208.9,168.81 208.75,168.65 208.33,168.65 207.92,169.06 207.84,169.06 207.76,168.98 UX4.27
  BOTTOM w0.102: v1(213.99,174.53) 213.92,174.46 213.92,174.09 213.95,174.07 JLVDS.20 ; v1(209.13,168.81) 208.97,168.81 208.82,168.65 208.82,167.68 208.26,167.12 207.76,167.12 RX48.2
LVDS_B2-: length 14.2
  TOP w0.102: v1(213.41,174.53) 213.73,174.21 213.73,173.83 211.62,171.73 211.62,170.99 210.1,169.47 209.21,169.47 208.96,169.22 v1(208.71,169.22) 208.71,169 208.64,168.92 208.44,168.92 208.03,169.33 207.84,169.33 207.78,169.38 UX4.28
  BOTTOM w0.102: JLVDS.19 213.45,174 213.58,174.13 213.59,174.13 213.66,174.19 213.66,174.29 213.59,174.36 213.59,174.45 213.51,174.53 v1(213.41,174.53) ; v1(208.71,169.22) 208.71,168.93 208.55,168.76 208.55,167.79 208.15,167.39 207.76,167.39 RX46.2
LVDS_BCLK+: length 12.7
  TOP w0.102: v1(209.88,167.71) 208.52,167.71 207.98,168.25 207.83,168.25 207.76,168.18 UX4.25
  BOTTOM w0.102: JLVDS.23 215.45,172.81 215.31,172.67 215.31,172.56 215.09,172.34 212.42,172.34 210.98,170.89 210.98,168.27 210.41,167.71 v1(209.88,167.71)
LVDS_BCLK-: length 12.6
  TOP w0.102: UX4.26 207.77,168.58 207.84,168.51 208.09,168.51 208.63,167.97 209.57,167.97 209.73,168.13 209.83,168.13 209.88,168.18 v1(209.88,168.29)
  BOTTOM w0.102: JLVDS.22 214.95,172.86 215.04,172.77 215.04,172.67 214.98,172.6 212.31,172.6 210.71,171 210.71,168.38 210.3,167.97 210.2,167.97 210.04,168.13 209.96,168.13 209.88,168.21 v1(209.88,168.29)
LX_1.05V: length 7.8
  TOP w0.102: v3(146.78,158.88) v2(147.41,158.88)
  IN1 w0.508: v3(144.17,152.76) 145.7,154.29 145.7,155.78 146.78,156.86 v3(146.78,158.88)
LX_1.5VSP: length 3.6
  BOTTOM w0.102: v2(104.51,27.69) 105.79,28.97 PL400.1
LX_1.8VSP: length 3.2
  BOTTOM w0.102: v2(222.68,94.76) 222.52,94.6 PL600.1
LX_3V: length 7.4
  IN1 w0.762: 131.47,16.65 131.51,16.65 134.39,19.53 134.39,22.84
  vias: v2(135.08,27.99) v3(130.24,16.11) v3(130.88,16.11) v3(134.14,27.41) v3(134.14,26.71) v3(134.14,26.01) v3(134.14,23.92) v3(134.78,27.41) v3(134.78,26.71) v3(134.84,26.01) v3(134.78,23.92) v3(135.41,27.41) v3(135.41,26.71) v3(135.41,23.89) v3(135.47,26.01)
LX_5V: length 8
  IN1 w0.762: 123.6,16.74 119.92,20.42 119.92,23.19
  vias: v2(119.41,28.49) v3(119.47,27.41) v3(119.47,26.77) v3(119.47,26.14) v3(119.6,23.98) v3(120.11,27.41) v3(120.11,26.77) v3(120.11,26.14) v3(120.23,28.11) v3(120.23,23.98) v3(120.87,28.11) v3(120.87,27.44) v3(120.87,23.98) v3(124.81,16.11) v3(125.44,16.11)
LX_CHG: length 8.8
  IN1 w1.016: 163.8,168.35 154.97,168.35
  vias: v1(153.31,168.29) v1(153.89,168.29) v1(164.74,168.67) v1(165.32,168.67) v2(148.06,171.48) v3(149.06,172.6) v3(149.06,171.59) v3(149.06,170.57) v3(149.95,173.11) v3(149.95,172.1) v3(149.95,171.08) v3(150.97,174.13) v3(150.97,173.11) v3(150.97,172.1) v3(150.97,171.08) v3(151.98,174.13) v3(151.98,173.11) v3(151.98,172.1) v3(151.98,171.08) v3(153,174.13) v3(153,173.11) v3(153,172.1) v3(153,171.08)
LX_PCIE:
  vias: v1(194.11,66.52) v1(194.75,66.52) v2(193.42,67.52)
LX_VDDCI: length 11
  TOP w0.508: v1(184.05,184.16) 183.42,183.53 v2(180.62,183.53) 178.34,183.53 176.74,185.12 v1(174.91,185.12)
  BOTTOM w0.508: PC1210.2 v1(174.91,185.12)
M_CLK_DDR0: length 77.1
  IN1 w0.084: v1(108.46,100.85) 108.46,100.74 108.83,100.37 108.83,100.3 108.92,100.21 108.92,99.87 108.47,99.42 108.47,99.21 108.9,98.78 108.9,98.31 108.79,98.21 108.79,97.43 108.62,97.25 108.31,97.25 108.14,97.42 107.83,97.42 107.61,97.2 107.61,97.06 107.83,96.84 107.83,96.52 107.48,96.17 107.15,96.17 106.95,96.36 106.77,96.36 106.37,95.96 106.37,95.82 106.23,95.68
  IN1 w0.127: v1(75.12,68.32) 75.26,68.45 75.52,68.45 75.81,68.74 75.81,68.87 75.97,69.04 75.97,69.82 77.74,71.59 78.55,71.59 79.5,72.55 92.75,72.55 97.59,77.39 97.77,77.39 98.93,76.23 99.34,76.23 99.77,76.66 99.77,77.06 98.61,78.22 98.61,78.4 98.88,78.67 99.06,78.67 100.58,77.15 100.98,77.15 101.41,77.58 101.41,77.98 99.89,79.5 99.89,79.68 100.16,79.95 100.34,79.95 101.86,78.43 102.26,78.43 105.85,82.02 105.85,95.3 106.23,95.68
  BOTTOM w0.076: UC1.AV37 107.85,104.36 107.79,104.43 107.66,104.43 107.56,104.33 107.56,102.63 107.59,102.6 107.59,100.99 107.72,100.85 v1(108.46,100.85)
  BOTTOM w0.102: v1(75.12,68.32) 75.04,68.4 74.7,68.4 74.49,68.62 74.49,69.61 74.26,69.83 74.26,70.31 74.2,70.37 JDIMM1.101
M_CLK_DDR1: length 76.1
  IN1 w0.084: v1(108.28,102.61) 108.41,102.74 108.75,102.74 108.82,102.67 108.82,101.53 109.13,101.22 109.13,98.26 108.99,98.12 108.99,97.36 106.84,95.2
  IN1 w0.127: 106.84,95.2 106.48,94.84 106.48,81.75 100.33,75.59 96.85,75.59 93.17,71.91 79.77,71.91 78.81,70.95 78.01,70.95 76.66,69.6 76.66,66.1 76.39,65.83 75.16,65.83 74.88,65.54 74.88,64.11 75.16,63.83 76.29,63.83 76.42,63.7 76.42,62.88 76.29,62.75 74.65,62.75 74.31,62.41 74.31,60.79 74.67,60.43 75.09,60.43 v1(75.2,60.32)
  BOTTOM w0.076: v1(108.28,102.61) 108.57,102.61 108.68,102.72 UC1.AY36
  BOTTOM w0.102: v1(75.2,60.32) 75.01,60.51 74.79,60.51 74.51,60.78 74.51,62.1 74.5,62.11 JDIMM1.102
M_CLK_DDR2: length 93.2
  IN3 w0.084: 106.6,95.75 106.52,95.83 106.52,96.18 106.88,96.54 106.88,96.97 106.24,97.6 106.24,98.06 106.84,98.66 106.84,98.98 107.46,99.59 107.46,104.9 106.81,105.54 106.81,107 106.89,107.07 107.2,107.07 v1(107.25,107.02)
  IN3 w0.127: 106.6,95.75 106.6,89.44 118.86,77.18 119.54,77.18 119.83,76.9 119.83,76.21 119.95,76.09 120.36,76.09 120.48,76.21 120.48,76.9 120.76,77.18 121.38,77.18 121.66,76.9 121.66,75.29 121.78,75.17 122.19,75.17 122.31,75.29 122.31,76.9 122.6,77.18 123.21,77.18 123.49,76.9 123.49,75.34 123.67,75.17 150.03,75.17 151.65,73.55 151.65,72.85 152.07,72.42 152.92,72.42 153.2,72.14 153.2,71.7 152.99,71.49 152.99,71.28 153.15,71.12 153.98,71.12 154.25,70.85 154.25,70.13 153.98,69.85 153.6,69.85 153.48,69.73 153.48,69.23 153.6,69.11 153.98,69.11 154.25,68.83 154.25,67.9 154.05,67.7 154.05,67.21 153.84,67 153.56,67 v1(153.37,66.82)
  BOTTOM w0.076: v1(107.25,107.02) 107.32,107.02 UC1.AN38
  BOTTOM w0.102: JDIMM2.101 152.75,67.25 153,67 153.19,67 v1(153.37,66.82)
M_CLK_DDR3: length 91.8
  IN3 w0.084: 105.71,93.76 105.64,93.83 105.64,98.31 106.23,98.89 106.23,104.93 106.45,105.15 106.45,107.79 106.15,108.09 106.15,108.48 106.4,108.73 106.71,108.73 106.95,108.49 106.99,108.49 v1(107.2,108.28)
  IN3 w0.127: 105.71,93.76 105.71,89.07 105.72,89.07 105.72,89.05 120.49,74.27 148.89,74.27 149.66,74.27 150.75,73.18 150.75,72.42 151.9,71.28 151.9,70.72 152.56,70.07 152.56,64.03 154.59,62 154.59,60.78 154.32,60.52 153.91,60.52 v1(153.75,60.36)
  BOTTOM w0.076: UC1.AL38 107.56,108.64 v1(107.2,108.28)
  BOTTOM w0.102: v1(153.75,60.36) 153.57,60.54 153.37,60.54 153.13,60.78 153.13,62.07 153.05,62.15 JDIMM2.102
M_CLK_DDR#0: length 77.5
  IN1 w0.084: 106.17,96 106.69,96.53 107.03,96.53 107.22,96.34 107.41,96.34 107.66,96.59 107.66,96.76 107.43,96.99 107.43,97.27 107.75,97.59 108.22,97.59 108.38,97.43 108.55,97.43 108.62,97.5 108.62,98.28 108.72,98.38 108.72,98.71 108.3,99.13 108.3,99.49 108.75,99.94 108.75,100.14 108.68,100.21 v1(108.46,100.21)
  IN1 w0.127: 106.17,96 105.58,95.41 105.58,82.13 102.15,78.71 101.97,78.71 100.46,80.22 100.05,80.22 99.62,79.79 99.62,79.39 101.14,77.87 101.14,77.69 100.87,77.42 100.69,77.42 99.17,78.94 98.77,78.94 98.34,78.51 98.34,78.1 99.49,76.95 99.49,76.77 99.23,76.5 99.05,76.5 97.89,77.66 97.48,77.66 92.64,72.82 79.39,72.82 78.43,71.86 77.63,71.86 75.7,69.93 75.7,69.15 75.54,68.99 75.54,68.86 75.41,68.72 75.23,68.72 75.12,68.83 v1(75.12,69.08)
  BOTTOM w0.076: UC1.AU37 107.89,104.79 107.89,104.66 107.83,104.59 107.58,104.59 107.4,104.41 107.4,100.91 107.64,100.66 108.13,100.66 108.46,100.33 v1(108.46,100.21)
  BOTTOM w0.102: v1(75.12,69.08) 75.12,68.89 74.85,68.62 74.79,68.62 74.7,68.71 74.7,69.7 74.48,69.92 74.48,70.24 74.54,70.31 74.7,70.31 74.8,70.4 JDIMM1.103
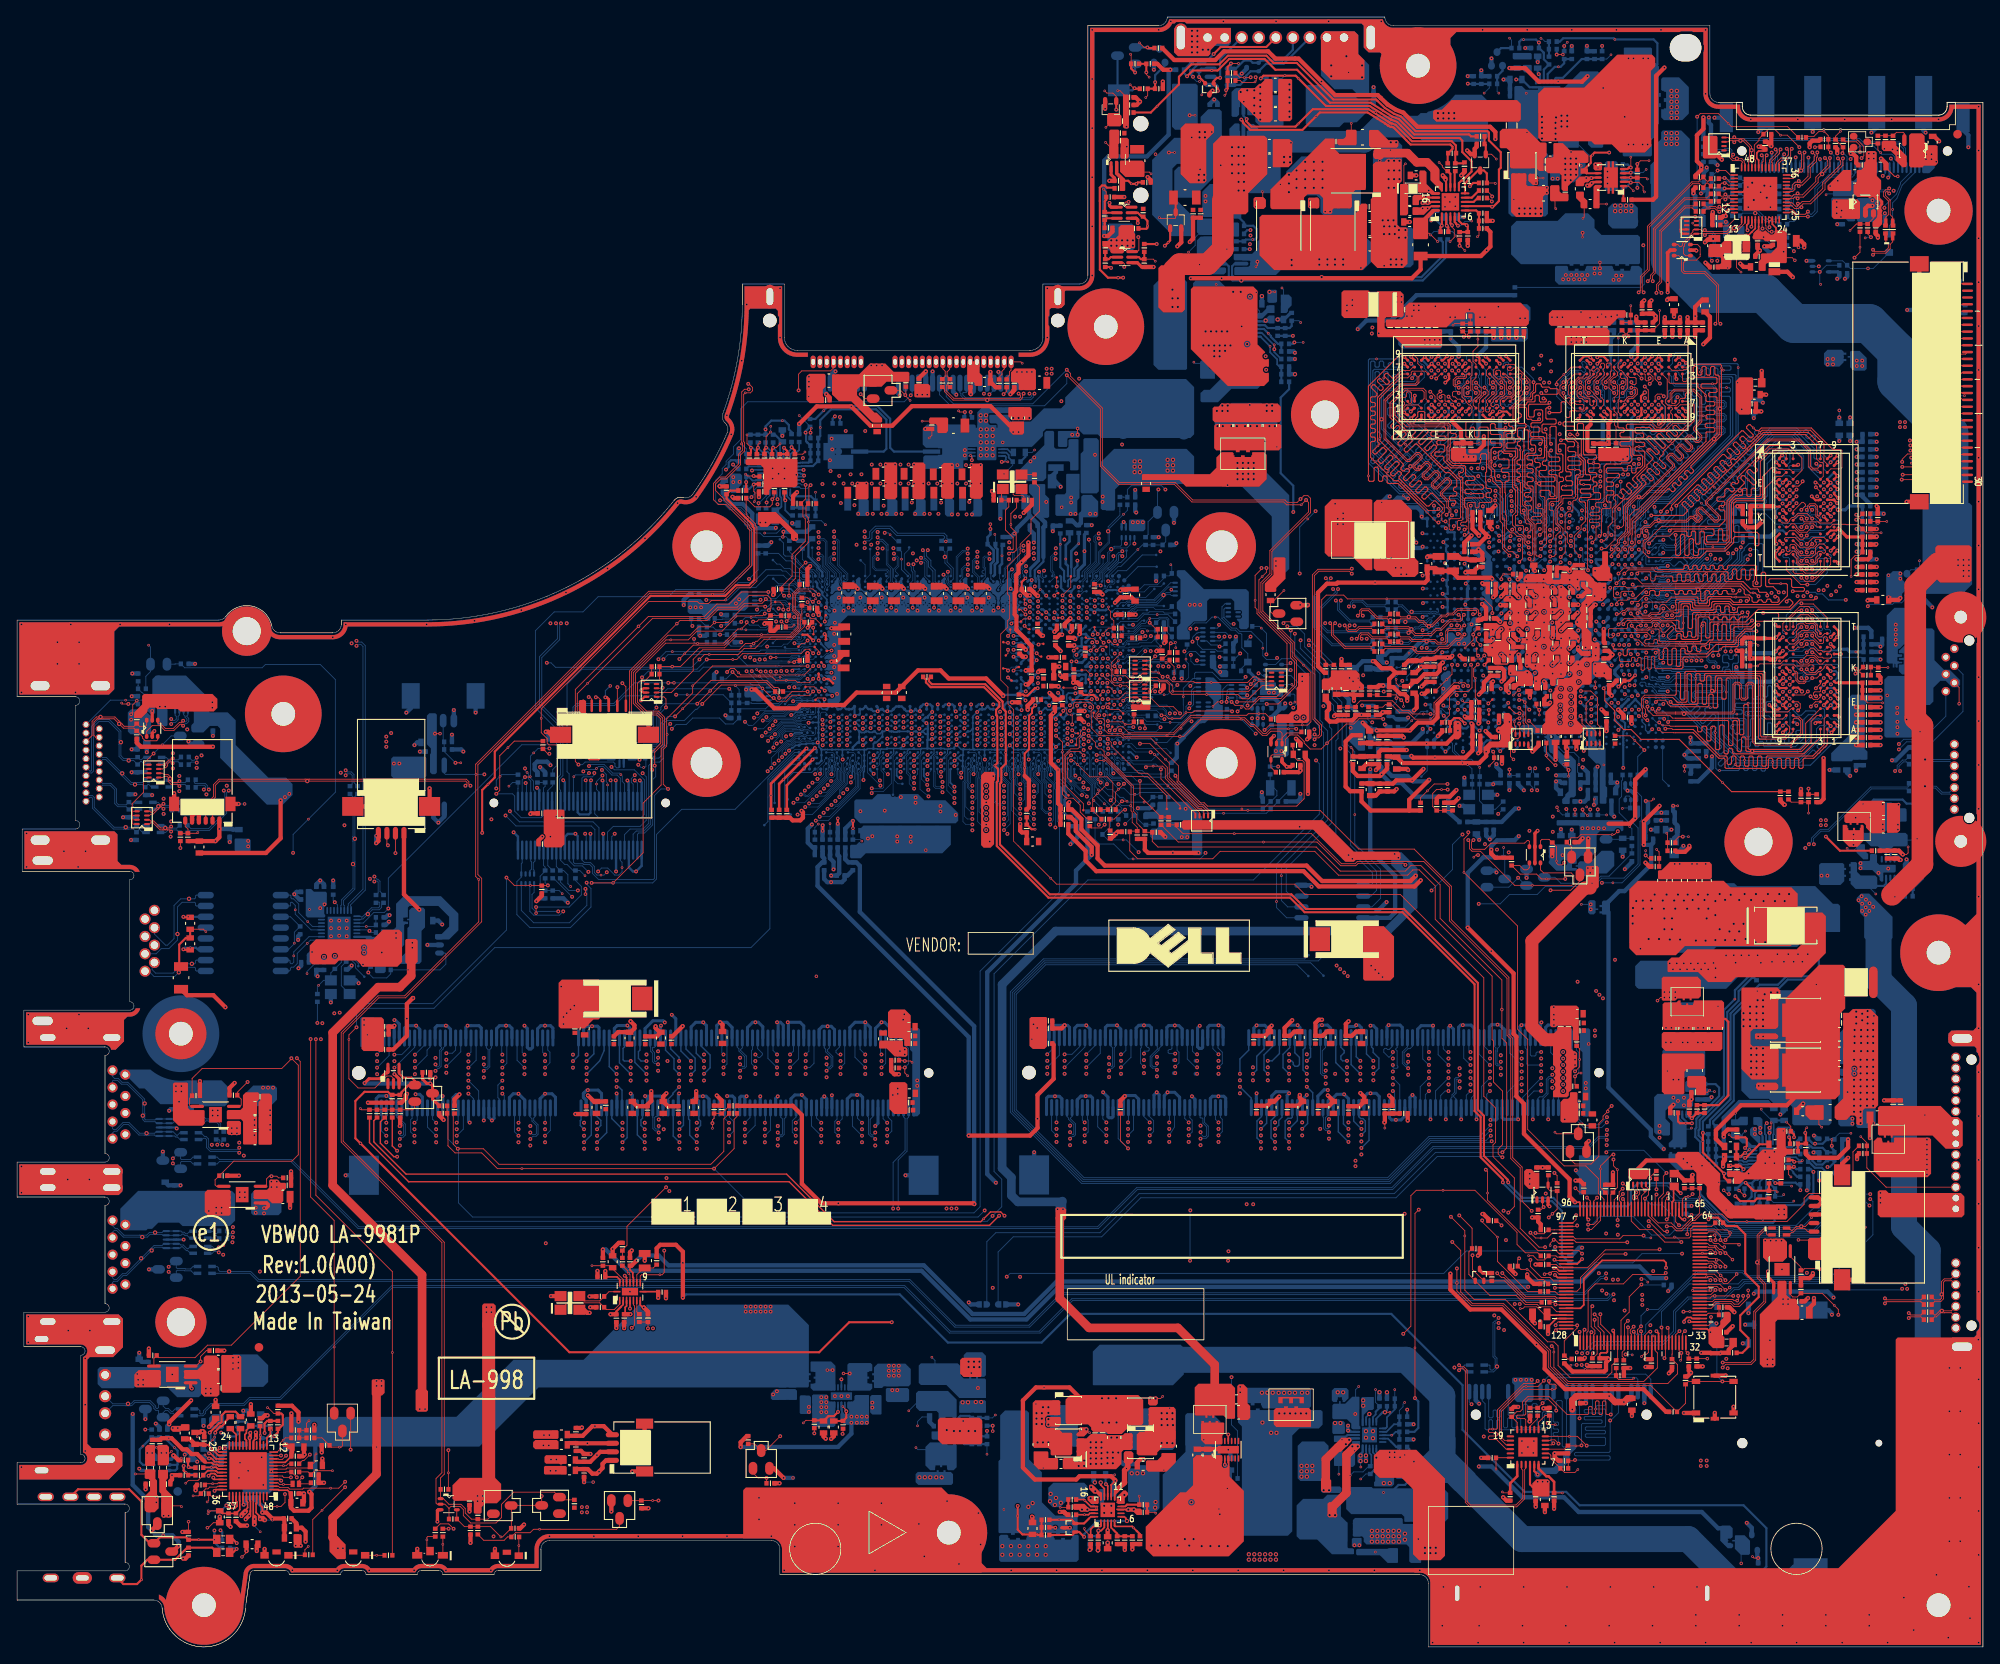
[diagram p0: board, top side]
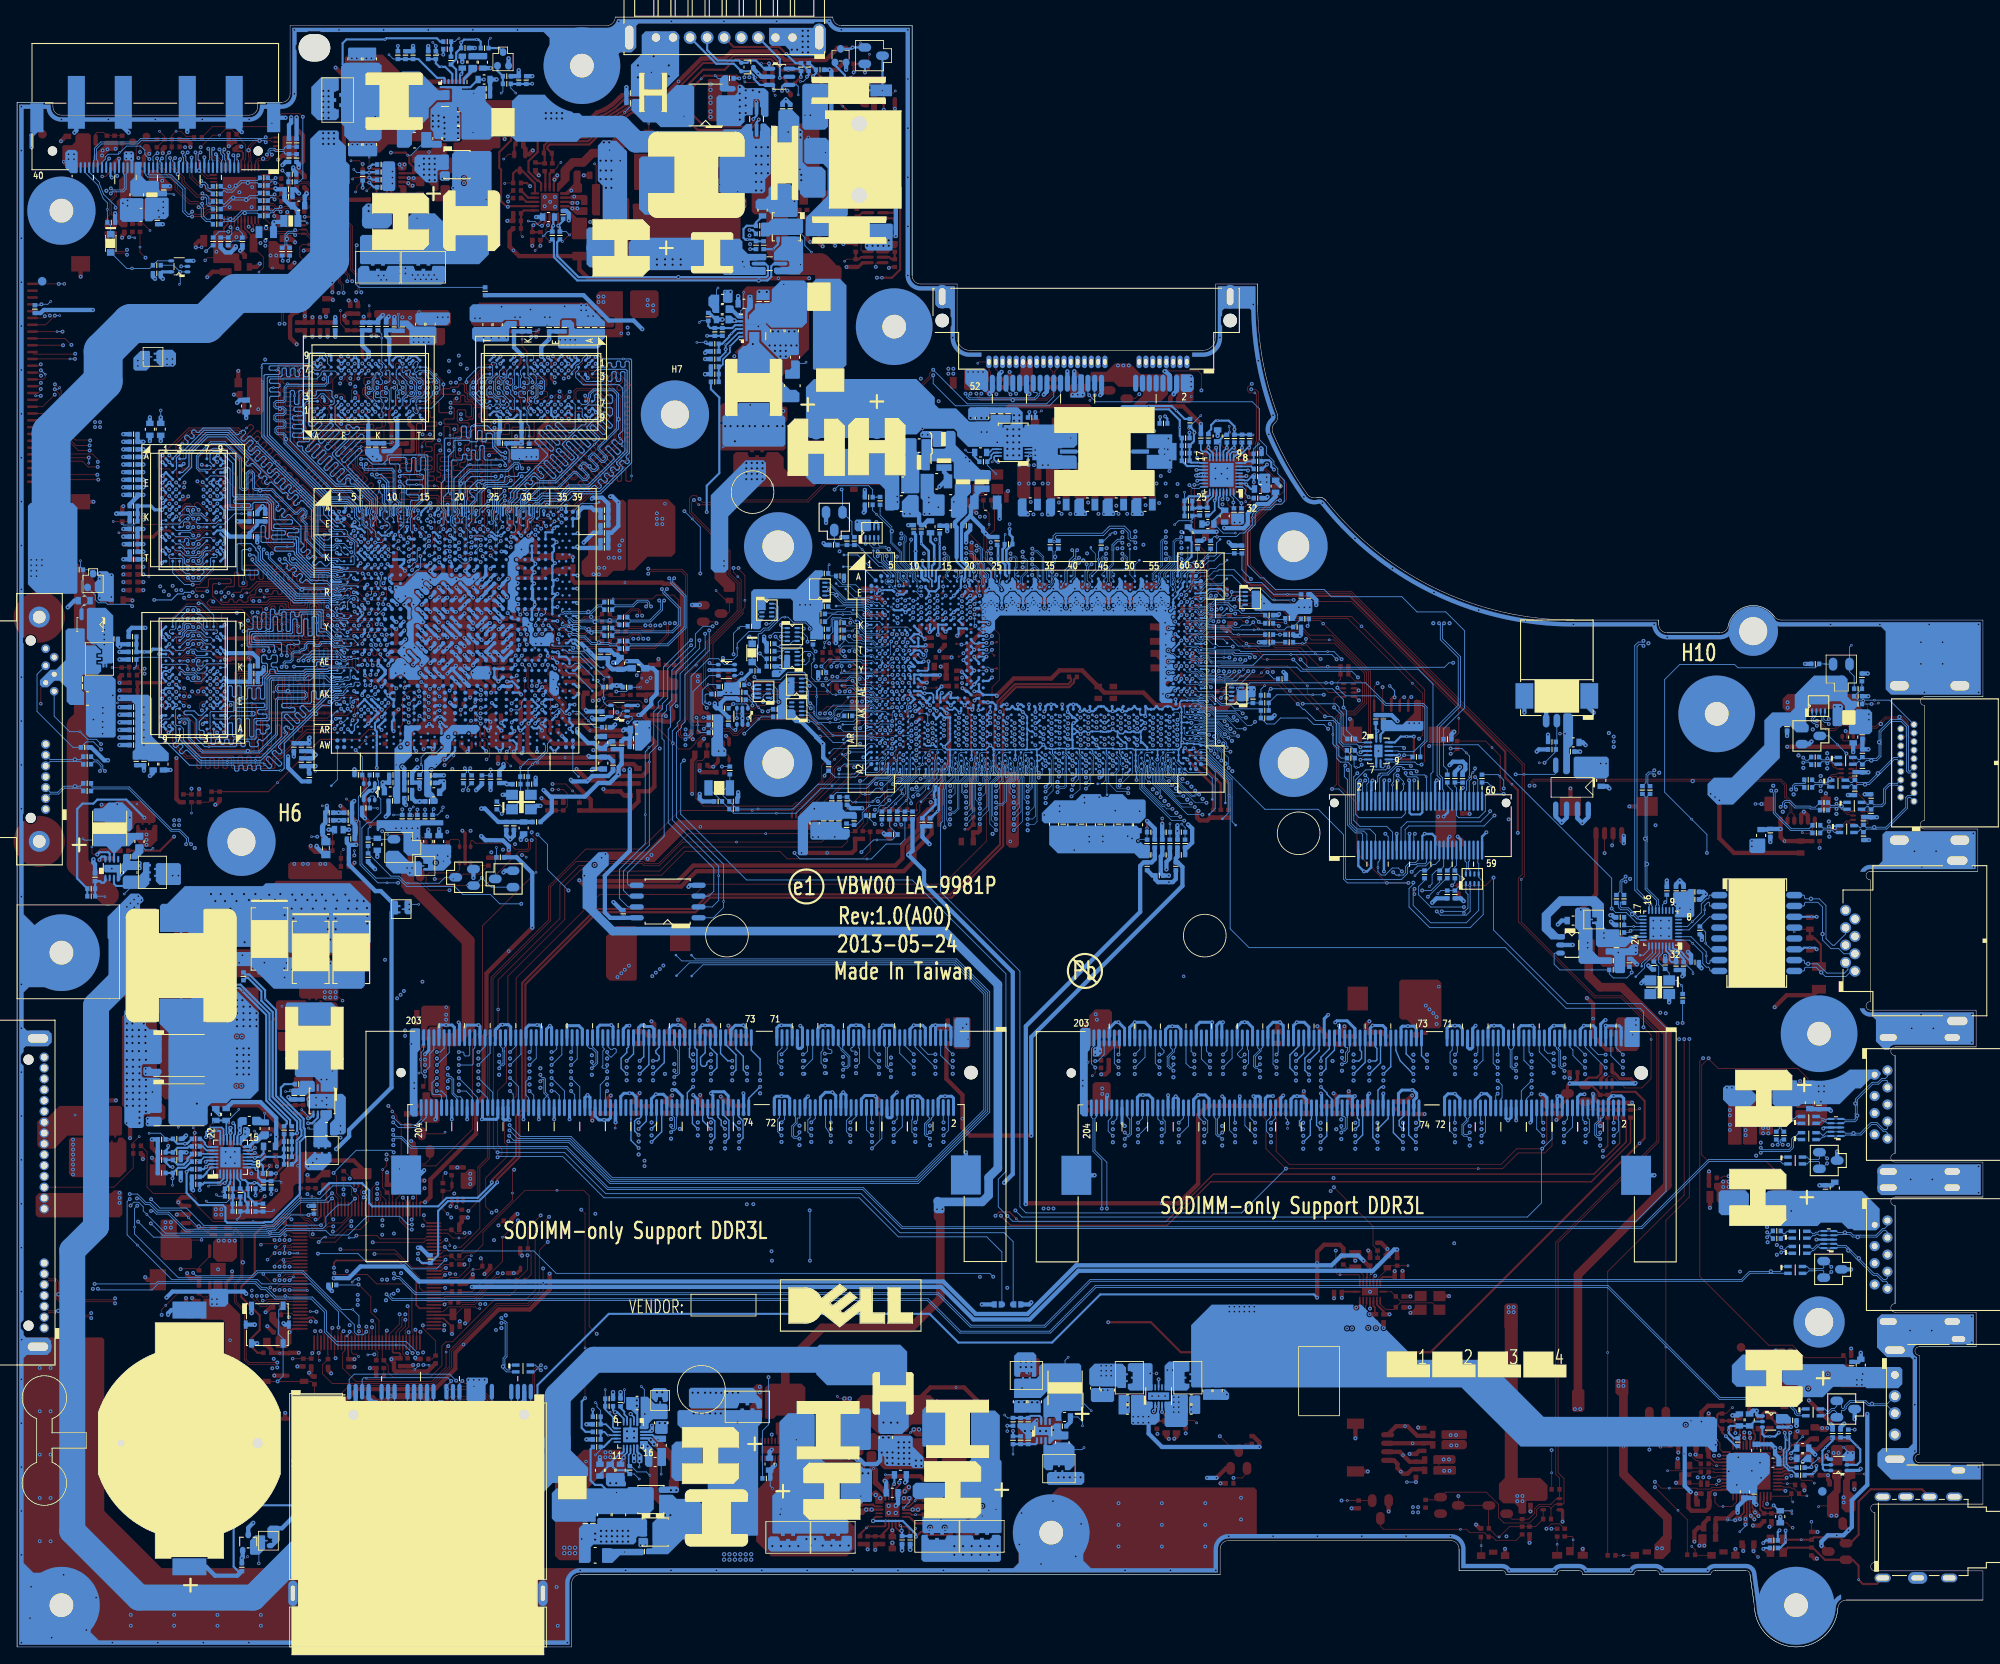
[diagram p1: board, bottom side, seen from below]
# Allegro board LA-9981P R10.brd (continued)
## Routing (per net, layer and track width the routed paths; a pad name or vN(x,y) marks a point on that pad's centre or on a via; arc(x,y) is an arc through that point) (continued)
M_CLK_DDR#1: length 76.3
  IN1 w0.084: v1(108.28,103.26) 108.63,102.91 108.83,102.91 108.99,102.74 108.99,101.6 109.31,101.29 109.31,98.19 109.17,98.05 109.17,97.28 107.03,95.14 107.03,95
  IN1 w0.127: 107.03,95 106.75,94.73 106.75,81.63 100.44,75.32 96.96,75.32 93.28,71.64 79.88,71.64 78.92,70.68 78.12,70.68 76.93,69.49 76.93,65.99 76.5,65.56 75.28,65.56 75.15,65.43 75.15,64.23 75.28,64.1 76.41,64.1 76.69,63.81 76.69,62.77 76.41,62.48 74.76,62.48 74.58,62.3 74.58,60.91 74.78,60.7 75.03,60.7 75.2,60.87 v1(75.2,61.08)
  BOTTOM w0.076: v1(108.28,103.26) 108.61,103.58 UC1.AW36
  BOTTOM w0.102: JDIMM1.104 75.1,62.32 74.96,62.18 74.83,62.18 74.73,62.08 74.73,60.87 74.88,60.72 75.15,60.72 75.28,60.84 75.28,61 v1(75.2,61.08)
M_CLK_DDR#2: length 93.5
  IN3 w0.084: v1(107.25,107.67) 107.25,107.55 106.95,107.24 106.82,107.24 106.64,107.07 106.64,105.47 107.28,104.83 107.28,99.66 106.67,99.05 106.67,98.73 106.07,98.13 106.07,97.53 106.71,96.89 106.71,96.61 106.35,96.25 106.35,95.77
  IN3 w0.127: v1(153.37,67.58) 153.37,67.39 153.5,67.26 153.74,67.26 153.8,67.32 153.8,67.8 154,68.01 154,68.73 153.87,68.85 153.5,68.85 153.23,69.12 153.23,69.83 153.5,70.1 153.87,70.1 154,70.23 154,70.74 153.87,70.87 153.04,70.87 152.73,71.18 152.73,71.59 152.95,71.8 152.95,72.04 152.82,72.16 151.97,72.16 151.39,72.74 151.39,73.45 149.92,74.91 123.56,74.91 123.24,75.24 123.24,76.8 123.1,76.93 122.7,76.93 122.57,76.8 122.57,75.18 122.3,74.91 121.67,74.91 121.41,75.18 121.41,76.8 121.27,76.93 120.87,76.93 120.73,76.8 120.73,76.11 120.46,75.84 119.84,75.84 119.57,76.11 119.57,76.8 119.44,76.93 118.75,76.93 106.35,89.33 106.35,95.77
  BOTTOM w0.076: v1(107.25,107.67) 107.5,107.67 107.64,107.82 UC1.AM38
  BOTTOM w0.102: JDIMM2.103 153.35,70.27 152.97,69.89 152.97,67.34 153.09,67.22 153.22,67.22 153.37,67.37 v1(153.37,67.58)
M_CLK_DDR#3: length 92
  IN3 w0.084: 105.46,93.66 105.46,94.05 105.47,94.06 105.47,98.38 106.06,98.97 106.06,105.01 106.27,105.23 106.27,107.72 105.98,108.02 105.98,108.55 106.33,108.91 106.78,108.91 107.03,108.66 107.15,108.66 107.25,108.76 v1(107.25,108.97)
  IN3 w0.127: 105.46,93.66 105.46,88.96 105.46,88.96 105.46,88.94 120.38,74.02 148.78,74.02 149.56,74.02 150.5,73.08 150.5,72.32 151.64,71.17 151.64,70.62 152.3,69.96 152.3,63.93 154.33,61.9 154.33,60.89 154.22,60.77 153.89,60.77 153.75,60.91 v1(153.75,61.12)
  BOTTOM w0.076: UC1.AK38 107.67,109.24 107.4,108.97 v1(107.25,108.97)
  BOTTOM w0.102: v1(153.75,61.12) 153.75,60.88 153.63,60.76 153.46,60.76 153.34,60.87 153.34,62.05 153.65,62.35 JDIMM2.104
M_ODT: length 7.2
  TOP w0.102: v2(40.23,63.12) 40.37,62.98 R2352.1 R2350.1 R2348.1 R2349.1 CD64.1 46.35,62.98 46.61,63.24 QD2.3
M_ODT0: length 46.9
  TOP w0.165: R2348.2 42.57,61.56 42.57,59.07 44.16,57.48 v1(44.54,57.48)
  IN1 w0.183: v1(79.66,59.17) 79.66,59.14 77.02,56.5 45.52,56.5 v1(44.54,57.48)
  BOTTOM w0.165: v1(79.66,59.17) 78.83,60 78.83,61.76 78.7,61.89 JDIMM1.116
M_ODT1: length 44.6
  TOP w0.165: v1(44.54,58.18) 43.97,58.75 R2349.2
  IN1 w0.183: v1(44.54,58.18) 45.76,56.96 76.83,56.96 79.21,59.35 79.21,60.25 v1(79.66,60.7)
  BOTTOM w0.165: JDIMM1.120 79.9,61.86 80.1,61.66 80.1,61.14 v1(79.66,60.7)
M_ODT2: length 134.1
  TOP w0.165: v1(115.73,50.56) 115.28,51 114.09,51 v2(113.29,50.2) 112.95,49.86 95.77,49.86 90.18,55.44 45.59,55.44 41.81,59.22 41.81,61.69 R2350.2
  IN1 w0.183: v1(157.55,60.03) 154.33,56.81 154.33,55.13 154.33,55.12 154.33,52.51 151.8,49.98 119.41,49.98 119.4,49.97 116.31,49.97 v1(115.73,50.56)
  BOTTOM w0.165: v1(157.55,60.03) 158.02,60.49 158.02,61.67 157.74,61.95 157.48,61.95 157.25,62.18 JDIMM2.116
M_ODT3: length 135.4
  TOP w0.165: R2352.2 41.3,59.13 45.89,54.54 90.49,54.54 95.6,49.44 113.97,49.44 v1(115.09,50.56)
  IN1 w0.183: v1(157.55,58.5) 157.06,58.02 156.16,58.02 154.77,56.63 154.77,52.33 151.98,49.54 116.11,49.54 v1(115.09,50.56)
  BOTTOM w0.165: JDIMM2.120 158.45,61.9 158.45,59.4 v1(157.55,58.5)
MAA0: length 53.4
  TOP w0.102: v1(172.97,148.29) 173.15,148.11 173.15,148.08 173.35,147.87 173.35,146.86 172.59,146.1 UV18.N3 ; v1(185.2,147.02) 185.02,147.2 185.02,147.23 184.82,147.43 184.82,148.45 185.58,149.21 UV20.N3 ; v1(177.22,130.17) 177.21,130.17 177.09,130.3 177.09,130.7 177.21,130.83 177.29,130.83 177.36,130.89 177.36,131.55 177.23,131.68 176.94,131.68 176.81,131.8 176.81,132.09 176.71,132.2 176.71,132.73 176.58,132.86 176.32,132.86 176.19,132.99 176.19,135.39
  TOP w0.127: 176.19,135.39 176.19,136.5 176.07,136.63 175.92,136.63 175.79,136.75 175.79,137.01 175.92,137.13 176.07,137.13 176.19,137.26 176.19,137.51 176.07,137.64 175.92,137.64 175.79,137.77 175.79,138.02 175.92,138.15 176.07,138.15 176.19,138.28 176.19,138.53 176.07,138.66 175.92,138.66 175.79,138.78 175.79,139.04 175.92,139.17 176.07,139.17 176.19,139.29 176.19,140.7 176.07,140.82 175.97,140.82 175.84,140.95 175.84,141.2 175.97,141.33 176.07,141.33 176.19,141.46 176.19,141.71 176.07,141.84 175.97,141.84 175.84,141.96 175.84,142.8 175.97,142.93 176.73,142.93 176.86,143.06 v2(176.86,143.21) 176.86,143.31 176.73,143.44 175.97,143.44 175.84,143.56 175.84,144 175.97,144.13 176.16,144.13 176.29,144.25 176.29,144.51 176.16,144.64 176.03,144.64 175.91,144.76 175.91,145.22 176.03,145.35 176.78,145.35 176.91,145.22 176.91,144.07 177.04,143.95 177.43,143.95 177.59,143.79 178.22,143.79 v1(178.38,143.95)
  IN1 w0.102: v1(185.2,147.02) 185.2,146.78 182.69,144.28 181.18,144.28 ; 176.99,143.95 176.89,143.95 174.76,146.07 174.06,146.07 173.58,146.56 173.58,148.23 173.45,148.35 173.03,148.35 v1(172.97,148.29)
  IN1 w0.14: 181.18,144.28 180.42,144.28 180.09,143.95 v1(178.38,143.95) 176.99,143.95
  BOTTOM w0.102: v1(185.2,147.02) 185.2,147.16 185.33,147.29 185.37,147.29 185.49,147.41 185.6,147.41 185.75,147.27 185.75,147.15 185.62,147.02 185.62,146.89 185.69,146.83 185.81,146.83 185.85,146.79 185.85,146.49 185.81,146.45 185.61,146.45 185.5,146.33 185.5,146.14 UV21.N3 ; v1(177.22,130.17) 177.12,130.27 175.84,130.27 UV1.G24 ; v1(172.97,148.29) 172.97,148.08 172.92,148.04 172.77,148.04 172.64,147.91 172.55,147.91 172.31,148.14 172.31,148.63 172.42,148.73 172.67,148.73 172.8,148.86 172.8,149.13 172.67,149.25 UV19.N3
MAA1: length 54.1
  TOP w0.102: v1(174.95,148.29) 174.95,148.44 174.51,148.88 173.99,148.88 173.86,149.01 173.86,149.56 173.74,149.69 173.43,149.69 173.3,149.56 173.3,149.34 UV18.P7 ; v1(183.22,147.02) 183.22,146.81 183.45,146.58 183.6,146.58 183.76,146.43 184.23,146.43 184.35,146.3 184.35,145.68 184.48,145.56 184.65,145.56 184.78,145.68 UV20.P7
  IN1 w0.102: v1(174.95,148.29) 174.95,148.35 175.08,148.48 175.28,148.48 175.41,148.61 175.41,148.8 175.28,148.92 174.87,148.92 174.75,149.05 174.75,149.24 174.87,149.37 175.71,149.37 175.81,149.27 175.81,149.04 175.93,148.92 176.1,148.92 176.22,149.04 176.22,149.25 176.34,149.37 176.51,149.37 176.63,149.25 176.63,149.18 176.75,149.05 177.93,149.05 ; v1(183.22,147.02) 182.61,147.63 182.61,148.67 182.53,148.75 181.99,148.75 181.88,148.86 181.88,149.08 181.63,149.33 180.37,149.33 180.24,149.2 180.24,149.18
  IN1 w0.14: 177.93,149.05 178.14,149.05 v1(178.51,148.68) 178.91,148.68 179.28,149.05 180.11,149.05 180.24,149.18
  IN3 w0.102: v1(176.05,129.17) 176.54,129.66 176.54,131.33 176.67,131.46 177.49,131.46 177.62,131.58 177.62,132.04
  IN3 w0.157: v1(178.51,148.68) 178.51,148.01 178.38,147.88 177.7,147.88 177.57,147.75 177.57,147.25 177.7,147.12 178.08,147.12 178.21,146.99 178.21,146.62 178.08,146.49 177.7,146.49 177.57,146.36 177.57,145.95 177.7,145.82 179.03,145.82 179.16,145.7 179.16,143.4 179.03,143.27 177.75,143.27 177.12,142.65 177.12,138.09 177.25,137.97 177.58,137.97 177.71,137.84 177.71,136.84 177.83,136.72 178.11,136.72 178.23,136.59 178.23,134.67 178.11,134.55 177.74,134.55 177.62,134.42 177.62,132.04
  BOTTOM w0.102: v1(183.22,147.02) 183.6,147.4 183.6,148.28 183.99,148.67 184.29,148.67 184.78,149.16 UV21.P7 ; v1(176.05,129.17) 176.66,128.56 UV1.J23 ; v1(174.95,148.29) 174.82,148.42 174.62,148.42 174.56,148.35 174.56,147.02 174.17,146.64 173.46,146.64 173.18,146.36 173.18,146.26 UV19.P7
MAA2: length 55.3
  TOP w0.102: UV18.P3 173.39,146.07 173.95,146.64 174.12,146.64 174.34,146.86 174.34,147.91 v1(173.96,148.29) ; UV20.P3 184.78,149.24 184.21,148.67 184.05,148.67 183.83,148.45 183.83,147.4 v1(184.21,147.02)
  IN1 w0.102: 181.18,150.38 182.96,150.38 183.72,149.62 183.72,147.51 v1(184.21,147.02) ; v1(173.96,148.29) 174.01,148.29 174.14,148.42 174.14,148.67 174.01,148.8 173.43,148.8 173.31,148.92 173.31,149.08 173.43,149.2 173.83,149.2 173.96,149.33 173.96,149.74 174.61,150.38 175.35,150.38 175.45,150.49 175.45,150.53 175.57,150.65 175.74,150.65 175.86,150.53 175.86,150.5 175.98,150.38 176.14,150.38 176.26,150.5 176.26,150.53 176.38,150.65 176.55,150.65 176.67,150.53 176.67,150.49 176.77,150.38 176.99,150.38
  IN1 w0.14: 176.99,150.38 v1(178.42,150.38) 181.18,150.38
  IN3 w0.102: 176.37,135.39 176.37,133.86 175.77,133.26 175.77,132.55 174.57,131.35 174.57,130.08 v1(174.97,129.68)
  IN3 w0.157: v1(178.42,150.38) 178.42,149.78 177.81,149.18 176.99,149.18 176.48,148.67 176.48,146.74 176.35,146.61 175.85,146.61 175.73,146.48 175.73,146.02 175.89,145.86 176.13,145.86 176.29,145.7 176.29,145.39 176.13,145.23 175.89,145.23 175.73,145.07 175.73,144.76 175.89,144.6 176.13,144.6 176.29,144.44 176.29,144.13 176.13,143.97 175.89,143.97 175.73,143.81 175.73,143.48 175.89,143.33 176.28,143.33 176.4,143.2 176.4,142.82 176.28,142.7 175.89,142.7 175.73,142.54 175.73,141.24 175.85,141.11 176.24,141.11 176.37,140.99 176.37,135.39
  BOTTOM w0.102: UV19.P3 173.28,149.25 173.2,149.18 173.2,148.88 173.3,148.79 173.4,148.79 173.58,148.97 173.72,148.97 173.82,148.87 173.82,148.74 173.55,148.47 173.55,148.06 173.64,147.97 173.75,147.97 173.96,148.18 v1(173.96,148.29) ; v1(174.97,129.68) 175.46,129.19 UV1.H24 ; UV21.P3 184.83,146 184.95,146 185.05,146.1 185.05,146.34 184.9,146.49 184.73,146.49 184.67,146.55 184.67,146.72 184.63,146.77 184.51,146.77 184.38,146.64 183.99,146.64 183.8,146.82 183.8,147.02 183.93,147.15 184.08,147.15 v1(184.21,147.02)
MAA3: length 60.4
  TOP w0.102: UV20.N2 185.58,150.39 185.71,150.51 185.93,150.51 186.06,150.39 186.06,149.98 185.88,149.8 185.88,149.6 186.06,149.42 186.06,149.15 v1(185.2,148.29) ; v1(172.97,147.02) 172.97,146.89 172.21,146.14 172.21,145.89 172.35,145.75 172.35,145.56 172.11,145.32 172.11,144.92 172.24,144.8 172.46,144.8 172.59,144.92 UV18.N2
  IN1 w0.102: v1(172.97,147.02) 172.97,146.59 174.32,145.24 174.46,145.24 174.61,145.39 174.78,145.39 174.9,145.27 174.9,145.1 174.71,144.91 174.71,144.74 174.83,144.62 175,144.62 175.19,144.81 175.35,144.81 175.47,144.69 175.47,144.52 175.28,144.33 175.28,144.17 175.4,144.05 175.57,144.05 175.76,144.24 175.93,144.24 176.05,144.12 176.05,143.95 175.86,143.76 175.86,143.59 176.08,143.37 176.23,143.37 176.39,143.53 176.58,143.53 176.99,143.11 ; v1(185.2,148.29) 185.2,148.27 185.62,147.84 185.62,147.59 185.62,147.52 185.81,147.33 185.81,146.8 183.67,144.66 183.67,143.35 183.34,143.02 181.18,143.02
  IN1 w0.14: 176.99,143.11 177.08,143.02 177.46,143.02 177.6,142.88 177.6,142.79 177.73,142.66 178.03,142.66 178.16,142.79 178.16,142.88 178.3,143.02 178.89,143.02 v1(179.15,142.76) 180.39,142.76 180.65,143.02 181.18,143.02
  IN3 w0.102: 177.48,130.97 176.75,130.23 176.75,129.29 v1(176.05,128.6)
  IN3 w0.157: 177.48,130.97 177.88,131.37 177.88,134.16 178,134.29 178.47,134.29 178.6,134.41 178.6,136.31 178.72,136.44 179.3,136.44 179.43,136.56 179.43,136.94 179.3,137.07 178.19,137.07 178.07,137.19 178.07,137.57 178.19,137.7 179.3,137.7 179.43,137.82 179.43,138.2 179.3,138.33 177.61,138.33 177.49,138.45 177.49,139.78 177.61,139.91 177.89,139.91 178.01,140.03 178.01,140.9 177.86,141.06 177.61,141.06 177.49,141.18 177.49,142.5 177.61,142.63 178.19,142.63 178.32,142.5 178.32,142.06 178.45,141.93 179.02,141.93 179.15,142.06 v1(179.15,142.76)
  BOTTOM w0.102: v1(176.05,128.6) 175.74,128.29 UV1.J24 ; v1(185.2,148.29) 184.82,147.91 184.82,146.86 185.26,146.42 185.26,145.58 UV21.N2 ; v1(172.97,147.02) 173.35,147.4 173.35,148.45 173,148.8 173,149.64 172.59,150.05 UV19.N2
MAA4: length 57.8
  TOP w0.102: UV18.P8 173.06,149.73 173.06,149.12 173.51,148.67 174.12,148.67 174.54,148.24 174.54,147.52 174.95,147.12 v1(174.95,147.02) ; v1(183.22,148.29) 183.22,148.19 183.62,147.79 183.62,147.06 184.05,146.64 184.65,146.64 185.1,146.19 185.1,145.58 UV20.P8
  IN1 w0.102: v1(183.22,148.29) 183.42,148.49 183.42,149.64 183.08,149.98 181.18,149.98 ; 176.99,149.98 176.93,149.98 176.82,149.87 176.48,149.87 176.35,150 176.35,150.05 176.23,150.18 175.98,150.18 175.88,150.08 175.88,149.95 175.76,149.83 175.59,149.83 175.47,149.95 175.47,150.08 175.37,150.18 175.17,150.18 175.07,150.08 175.07,149.95 174.94,149.83 174.47,149.83 174.34,149.7 174.34,148.02 174.57,147.79 174.57,147.33 174.88,147.02 v1(174.95,147.02)
  IN1 w0.14: 176.99,149.98 177.58,149.98 v1(177.69,149.88) 177.71,149.9 179.49,149.9 179.57,149.98 181.18,149.98
  IN3 w0.102: 176.01,135.39 176.01,133.83 175.57,133.38 175.57,132.71 174.19,131.33 174.19,130.17 v1(173.7,129.68)
  IN3 w0.157: 176.01,135.39 176.01,140.53 175.88,140.66 175.52,140.66 175.37,140.82 175.37,144.63 175.36,144.64 175.36,150 175.49,150.13 176.04,150.13 176.16,150 176.16,149.43 176.29,149.31 176.73,149.31 176.86,149.43 176.86,149.75 176.99,149.88 v1(177.69,149.88)
  BOTTOM w0.102: UV19.P8 173.1,145.25 172.75,145.6 172.75,145.76 172.93,145.94 173.04,145.94 173.18,145.81 173.18,145.72 173.28,145.62 173.56,145.62 173.76,145.83 173.76,146.23 173.96,146.43 174.26,146.43 174.84,147.02 v1(174.95,147.02) ; UV1.H26 174.26,129.12 v1(173.7,129.68) ; v1(183.22,148.29) 183.32,148.29 183.91,148.87 184.2,148.87 184.4,149.08 184.4,149.31 184.27,149.44 184.27,149.61 184.4,149.73 184.57,149.73 184.67,149.62 184.87,149.62 185.06,149.43 185.18,149.43 185.26,149.52 185.26,149.98 185.18,150.07 184.79,150.07 UV21.P8
MAA5: length 58.5
  TOP w0.102: v1(184.21,148.29) 184.8,148.88 184.93,148.88 185.15,149.1 185.15,149.35 185.43,149.62 185.43,149.75 185.3,149.88 185.12,149.88 184.82,149.58 184.67,149.58 184.56,149.68 184.56,149.83 UV20.P2 ; UV18.P2 173.53,145.25 173.62,145.34 173.62,145.56 173.5,145.68 173.3,145.68 173.05,145.43 172.87,145.43 172.74,145.56 172.74,145.74 173.01,146.02 173.01,146.21 173.23,146.43 173.37,146.43 v1(173.96,147.02)
  IN1 w0.102: v1(184.21,148.29) 184.79,147.71 184.79,146.78 182.63,144.62 181.18,144.62 ; v1(173.96,147.02) 173.8,146.86 173.8,146.63 174.15,146.28 175.12,146.28 175.68,145.72 175.68,145.44 176.59,144.53 176.88,144.53 176.99,144.42
  IN1 w0.14: 181.18,144.62 180.28,144.62 179.95,144.29 178.89,144.29 178.65,144.53 v1(178.38,144.53) 178.12,144.53 177.88,144.29 177.12,144.29 176.99,144.42
  IN3 w0.157: v1(178.38,144.53) 178.67,144.53 178.8,144.66 178.8,145.18 178.67,145.3 176.99,145.3 176.86,145.18 176.86,144.41 176.99,144.28 177.75,144.28 177.88,144.15 177.88,143.78 177.75,143.65 176.89,143.65 176.76,143.53 176.76,137.65 176.92,137.49 177.22,137.49 177.35,137.36 177.35,136.99 177.22,136.86 176.86,136.86 176.73,136.73 176.73,136.36 176.86,136.23 177.75,136.23 177.87,136.1 177.87,135.73 177.75,135.6 176.92,135.6 176.76,135.44 176.76,135.13 176.92,134.97 177.24,134.97 177.36,134.84 177.36,134.47 177.24,134.34 176.73,134.34 176.6,134.21 176.6,133.75 176.73,133.62 177.23,133.62 177.36,133.49 177.36,131.84 177.23,131.72 176.57,131.72 176.35,131.49 175.83,131.49 175.64,131.3 175.64,129.65 v1(174.91,128.92)
  BOTTOM w0.102: v1(173.96,147.02) 174.35,147.41 174.35,148.63 173.86,149.12 173.86,149.58 UV19.P2 ; v1(184.21,148.29) 183.8,147.88 183.8,147.32 183.6,147.11 183.6,146.74 183.96,146.38 184.11,146.38 184.3,146.19 184.3,145.73 UV21.P2 ; UV1.J26 174.28,128.29 v1(174.91,128.92)
MAA6: length 60.8
  TOP w0.102: UV20.R8 183.64,144.91 182.74,144.91 180.82,146.83 180.82,147.84 181.24,148.26 v1(181.24,148.29) ; UV18.R8 174.51,150.38 175.45,150.38 177.31,148.52 177.31,147.43 176.93,147.05 v1(176.93,147.02) ; v1(177.13,129.52) 176.93,129.52 176.84,129.62 176.84,130.22 176.54,130.51 176.54,131.4 176.44,131.5 175.68,131.5 175.61,131.57 175.61,132.6 175.67,132.67 175.78,132.67 175.87,132.76 175.87,135.39
  TOP w0.127: v1(178.89,146.38) 179.1,146.38 179.22,146.26 179.22,146.09 179.1,145.96 178.54,145.96 178.42,146.09 178.42,146.63 178.29,146.76 178.04,146.76 177.91,146.63 177.91,146.09 177.8,145.98 177.05,145.98 176.92,145.86 176.92,145.75 176.8,145.62 175.98,145.62 175.58,145.22 175.58,142.4 175.46,142.27 174.65,142.27 174.52,142.14 174.52,141.89 174.65,141.76 175.46,141.76 175.58,141.64 175.58,141.3 175.46,141.18 174.65,141.18 174.52,141.05 174.52,140.67 174.65,140.54 175.74,140.54 175.87,140.42 175.87,139.54 175.53,139.21 175.53,136.22 v2(175.69,136.07) 175.87,135.88 175.87,135.39
  IN1 w0.102: v1(176.93,147.02) 176.98,147.02 177.11,146.89 177.11,146.57 177.05,146.51 176.57,146.51 176.51,146.45 176.51,146.07 176.6,145.97 176.99,145.97 ; 180.24,146.38 181.43,146.38 181.82,146.78 181.82,147.71 v1(181.24,148.29)
  IN1 w0.14: 180.24,146.38 v1(178.89,146.38) 178.58,146.38 178.51,146.32 178.51,146.12 178.38,145.99 178.1,145.99 177.98,146.12 177.98,146.24 177.85,146.37 177.54,146.37 177.42,146.24 177.42,146.1 177.29,145.97 176.99,145.97
  BOTTOM w0.102: UV19.R8 174.12,145.19 173.94,145.19 173.73,145.4 173.73,145.51 173.95,145.73 174.34,145.73 174.38,145.69 174.38,145.56 174.51,145.43 174.7,145.43 174.76,145.5 174.76,145.62 174.83,145.69 175.03,145.69 175.26,145.46 175.62,145.46 175.85,145.68 175.85,145.83 175.73,145.94 175.73,146.11 175.85,146.23 176.02,146.23 176.13,146.11 176.28,146.11 176.93,146.77 v1(176.93,147.02) ; v1(181.24,148.29) 181.24,148.55 182.36,149.68 183.32,149.68 183.55,149.46 183.72,149.46 183.85,149.58 183.85,149.72 183.5,150.07 183.5,150.35 183.39,150.46 183.39,150.61 183.5,150.72 183.66,150.72 183.98,150.4 UV21.R8 ; v1(177.13,129.52) 177.59,129.52 177.86,129.25 UV1.H21
MAA7: length 59.3
  TOP w0.102: v1(175.94,148.29) 175.33,147.68 175.33,146.86 175.11,146.64 175.09,146.64 175.08,146.63 174.48,146.63 174.27,146.43 174.1,146.43 173.86,146.19 173.86,145.58 UV18.R2 ; UV20.R2 184.35,149.68 184.35,149.1 184.13,148.88 183.89,148.88 183.69,148.68 183.08,148.68 183.08,148.67 183.06,148.67 182.81,148.42 182.81,147.6 v1(182.23,147.02) ; v1(178.46,130.39) 178.84,130.77 178.84,133.37 178.72,133.5 178.14,133.5 178.01,133.62 178.01,135.39
  TOP w0.127: 178.01,135.39 v2(178.01,136.54) 178.01,138.19 178.14,138.32 178.38,138.32 178.51,138.45 178.51,138.75 178.38,138.88 178,138.88 177.88,139 177.88,139.27 178,139.4 178.89,139.4 179.01,139.53 179.01,141.78 178.89,141.91 177.49,141.91 177.4,142 177.4,142.31 177.53,142.44 178.34,142.44 178.47,142.57 178.47,142.89 178.34,143.02 177.5,143.02 177.43,143.09 177.43,143.4 177.56,143.53 178.56,143.53 178.8,143.77 178.8,144.92 178.68,145.05 177.94,145.05 177.81,144.92 177.81,144.33 177.69,144.21 177.27,144.21 177.14,144.33 177.14,145.58 177.27,145.7 179.46,145.7 179.59,145.83 v1(179.59,145.89)
  IN1 w0.102: v1(182.23,147.02) 182.39,147.02 182.58,146.83 182.58,146.57 182.45,146.45 182,146.45 181.88,146.32 181.88,146.13 182,146 182.32,146 182.45,145.88 182.45,145.69 182.32,145.56 181.88,145.56 ; v1(175.94,148.29) 176.52,147.7 176.52,146.78 176.3,146.55 176.3,145.96 176.61,145.65 176.99,145.65
  IN1 w0.14: 181.88,145.56 181.33,145.56 181.21,145.69 181.21,145.93 181.08,146.06 180.77,146.06 180.65,145.93 180.65,145.79 180.51,145.65 180.1,145.65 179.86,145.89 v1(179.59,145.89) 179.2,145.89 178.96,145.65 176.99,145.65
  BOTTOM w0.102: UV19.R2 174.18,150.06 174.18,150.43 174.31,150.56 174.45,150.56 174.53,150.64 174.7,150.64 174.82,150.52 174.82,150.38 174.66,150.22 174.66,149.05 174.84,148.87 175.74,148.87 175.94,148.67 v1(175.94,148.29) ; UV1.G21 177.97,129.89 v1(178.46,130.39) ; UV21.R2 183.98,144.91 183.67,144.61 183.53,144.61 183.4,144.73 183.4,144.92 183.55,145.08 183.55,145.5 183.66,145.6 183.66,145.88 183.55,145.98 183.55,146.21 183.33,146.44 182.52,146.44 182.23,146.73 v1(182.23,147.02)
MAA8: length 55
  TOP w0.102: v1(181.24,147.02) 181.24,146.7 181.55,146.38 181.7,146.38 181.78,146.47 181.95,146.47 182.07,146.35 182.07,146.18 181.98,146.09 181.98,145.95 182.13,145.81 182.27,145.81 182.36,145.89 182.53,145.89 182.74,145.69 183.5,145.69 183.63,145.56 183.63,145.24 183.5,145.11 183.31,145.11 183.18,145.24 UV20.T8 ; UV18.T8 174.78,150.05 174.68,149.95 174.68,149.79 174.78,149.69 175.15,149.69 175.4,149.94 175.6,149.94 175.8,149.74 175.8,149.6 175.71,149.52 175.71,149.37 175.86,149.23 176,149.23 176.09,149.31 176.23,149.31 176.37,149.17 176.37,149.02 176.29,148.94 176.29,148.8 176.43,148.65 176.58,148.65 176.66,148.74 176.8,148.74 176.93,148.61 v1(176.93,148.29)
  IN1 w0.102: v1(181.24,147.02) 181.24,147.16 181.11,147.29 180.61,147.29 180.49,147.17 180.24,147.17 ; v1(176.93,148.29) 177.19,148.29 177.57,147.91 177.71,147.91 177.93,147.69
  IN1 w0.14: 180.24,147.17 179.95,147.17 179.85,147.27 179.85,147.49 179.73,147.6 179.52,147.6 v1(179.21,147.29) 179.04,147.46 178.15,147.46 177.93,147.69
  IN3 w0.157: v1(179.68,129.05) 179.13,129.05 179,129.17 179,134.59 179.13,134.72 180.03,134.72 180.16,134.84 180.16,135.28 180.03,135.4 179.08,135.4 178.96,135.53 178.96,135.91 179.08,136.03 179.66,136.03 179.79,136.16 179.79,137.29 179.92,137.41 180.86,137.41 180.99,137.54 180.99,137.92 180.86,138.04 179.92,138.04 179.79,138.17 179.79,138.64 179.92,138.76 180.82,138.76 180.95,138.89 180.95,139.37 180.82,139.49 179.43,139.49 179.08,139.15 179.08,138.89 178.96,138.76 177.97,138.76 177.85,138.89 177.85,139.34 177.97,139.46 178.45,139.46 178.97,139.99 178.97,141.37 179.64,142.04 179.64,144.16 180.03,144.54 180.03,146.34 179.9,146.47 179.4,146.47 179.27,146.59 179.27,147.23 v1(179.21,147.29)
  BOTTOM w0.102: v1(181.24,147.02) 180.85,147.4 180.85,148.46 182.45,150.05 UV21.T8 ; UV1.H19 179.73,129.09 v1(179.68,129.05) ; UV19.T8 175.7,145.25 177.31,146.86 177.31,147.91 v1(176.93,148.29)
MAA9: length 51.8
  TOP w0.102: v1(178.59,129.49) 179.05,129.95 179.05,134.76 178.92,134.89 178.63,134.89 178.5,135.02 178.5,135.39 ; UV20.R3 183.86,149.25 183.48,148.88 183,148.88 182.99,148.87 182.97,148.87 182.61,148.51 182.61,148.04 v1(182.23,147.65) ; UV18.R3 174.31,146.05 174.68,146.43 175.17,146.43 175.17,146.43 175.19,146.43 175.56,146.8 175.56,147.27 v1(175.94,147.65)
  TOP w0.127: v1(179.59,145.3) 179.3,145.3 179.17,145.18 179.17,144.1 179.3,143.97 180.25,143.97 180.38,143.84 180.38,143.5 180.25,143.37 178.85,143.37 178.73,143.25 178.73,142.47 178.85,142.35 179.15,142.35 179.27,142.22 179.27,139.17 179.15,139.04 178.9,139.04 178.77,138.91 178.77,138.66 178.9,138.53 179.15,138.53 179.27,138.4 179.27,138.07 179.15,137.94 178.52,137.94 178.39,137.81 178.39,137.32 178.52,137.19 180.09,137.19 180.22,137.06 180.22,136.75 180.09,136.62 178.52,136.62 178.39,136.5 178.39,136.24 178.52,136.12 180.09,136.12 180.22,135.99 180.22,134.99 180.09,134.87 179.78,134.87 179.65,134.99 v2(179.65,135.21) 179.65,135.48 179.53,135.61 178.59,135.61 178.5,135.52 178.5,135.39
  IN1 w0.102: 181.18,145.3 182.36,145.3 182.98,145.93 182.98,146.72 182.66,147.04 182.66,147.29 182.29,147.65 v1(182.23,147.65) ; 176.99,145.3 176.67,145.3 176.1,145.88 176.1,146.64 176.32,146.86 176.32,147.27 v1(175.94,147.65)
  IN1 w0.14: 176.99,145.3 v1(179.59,145.3) 181.18,145.3
  BOTTOM w0.102: v1(175.94,147.65) 175.47,148.12 175.47,148.42 175.22,148.67 174.75,148.67 174.19,149.24 UV19.R3 ; UV1.H20 178.99,129.09 v1(178.59,129.49) ; UV21.R3 183.98,146.07 183.41,146.64 182.95,146.64 182.7,146.89 182.7,147.18 v1(182.23,147.65)
MAA10: length 60
  TOP w0.102: v1(170.96,147.02) 170.96,147.04 170.61,147.4 170.61,148.45 170.99,148.83 UV18.L7 ; UV20.L7 187.18,146.48 187.56,146.86 187.56,147.91 v1(187.18,148.29)
  IN1 w0.102: 176.99,151.4 175.11,151.4 174.55,150.84 173.6,150.84 171.81,149.05 171.26,149.05 170.61,148.4 170.61,147.37 170.96,147.02 v1(170.96,147.02) ; 181.18,151.4 182.89,151.4 184.67,149.62 185.39,149.62 186.73,148.29 v1(187.18,148.29)
  IN1 w0.14: 181.18,151.4 v1(178.63,151.4) 176.99,151.4
  IN3 w0.102: 183.76,135.49 183.76,133.85 183.79,133.82 183.79,131.98 183.29,131.48 183.29,130.84 183.46,130.67 183.46,130.06 183.15,129.75 183.15,128.87 v1(183.29,128.73)
  IN3 w0.157: 183.76,135.49 183.74,135.51 183.74,148.35 180.68,151.4 v1(178.63,151.4)
  BOTTOM w0.102: v1(170.96,147.02) 170.99,147.04 170.99,147.11 171.11,147.24 171.47,147.24 171.6,147.11 171.6,146.64 171.47,146.51 170.96,146.51 170.83,146.38 170.83,146.18 170.96,146.05 UV19.L7 ; UV21.L7 187.18,149.56 187.05,149.69 186.83,149.69 186.7,149.56 186.7,148.42 186.83,148.29 v1(187.18,148.29) ; v1(183.29,128.73) 183.51,128.51 183.51,127.34 183.72,127.13 183.85,127.13 184.29,126.69 UV1.L13
MAA11: length 53.5
  TOP w0.102: v1(183.22,147.65) 182.84,147.27 182.84,146.65 183.11,146.38 183.42,146.38 183.74,146.05 UV20.R7 ; UV18.R7 174.43,149.25 174.82,148.86 175.12,148.86 175.33,148.66 175.33,148.04 v1(174.95,147.65)
  IN1 w0.102: v1(174.95,147.65) 174.95,147.75 174.54,148.16 174.54,149.33 174.83,149.62 176.99,149.62 ; 181.18,149.55 181.43,149.55 181.5,149.62 181.5,149.71 181.56,149.78 181.94,149.78 182.07,149.65 182.07,149.15 182.19,149.02 182.39,149.02 182.51,149.15 182.51,149.65 182.64,149.78 182.99,149.78 183.12,149.65 183.12,148.86 182.99,148.73 182.87,148.73 182.81,148.67 182.81,147.71 182.94,147.59 183.15,147.59 v1(183.22,147.65)
  IN1 w0.14: 176.99,149.62 177.01,149.62 177.23,149.39 178.32,149.39 178.49,149.56 179.78,149.56 v1(179.78,149.55) 181.18,149.55
  IN3 w0.102: 181.47,132.86 181.47,130.93 v1(182.11,130.29)
  IN3 w0.157: 181.47,132.86 181.72,133.11 182.19,133.11 182.91,133.83 182.91,141.51 182.44,141.99 182.44,144.26 182.57,144.39 182.98,144.39 183.11,144.52 183.11,144.95 182.98,145.08 182.07,145.08 181.95,145.21 181.95,145.58 182.07,145.71 182.84,145.71 182.97,145.84 182.97,146.32 182.84,146.45 181.81,146.45 181.69,146.57 181.69,149.52 181.56,149.65 180.8,149.65 180.67,149.52 180.67,148.73 180.54,148.61 180.1,148.61 179.97,148.73 179.97,149.36 v1(179.78,149.55)
  BOTTOM w0.102: v1(183.22,147.65) 182.82,148.05 182.82,148.43 183.16,148.77 183.46,148.77 183.59,148.9 183.59,149.13 183.72,149.25 UV21.R7 ; UV1.G16 182.51,129.89 v1(182.11,130.29) ; UV19.R7 174.67,146.54 175.09,146.54 175.34,146.79 175.34,147.46 175.15,147.65 v1(174.95,147.65)
MAA12: length 51.9
  TOP w0.102: UV20.N7 185.58,146.1 184.82,146.86 184.82,146.95 184.21,147.56 v1(184.21,147.65) ; v1(182.11,129.09) 181.69,129.52 181.69,130.57 181.43,130.83 181.43,132.8 181.8,133.16 182.21,133.16 182.34,133.29 182.34,134.32 182.46,134.45 182.64,134.45 182.9,134.71 182.9,135.39 ; UV18.N7 172.59,149.21 173.35,148.45 173.35,148.36 173.96,147.75 v1(173.96,147.65)
  TOP w0.127: v1(179.59,144.72) 180.84,144.72 180.96,144.85 180.96,145.87 181.09,146 181.34,146 181.47,145.87 181.47,144.28 181.6,144.15 181.88,144.15 182,144.28 182,144.83 182.13,144.96 182.39,144.96 182.51,144.83 182.51,143.77 182.39,143.64 181.32,143.64 181.19,143.51 181.19,143.26 181.32,143.13 182.39,143.13 182.51,143.01 182.51,142.75 182.39,142.63 181.62,142.63 181.5,142.5 181.5,142.08 181.83,141.75 182.33,141.75 182.94,141.14 v2(182.94,140.73) 182.94,139.65 183.55,139.04 183.55,137.3 183.42,137.17 183.03,137.17 182.9,137.04 182.9,135.39
  IN1 w0.102: 176.99,144.96 176.73,144.96 175.16,146.52 174.91,146.52 174.46,146.97 174.46,147.15 v1(173.96,147.65) ; 181.18,144.96 181.57,144.96 181.71,145.1 182.44,145.1 183.91,146.57 184.3,146.57 184.59,146.86 184.59,147.53 184.46,147.65 v1(184.21,147.65)
  IN1 w0.14: 181.18,144.96 180.14,144.96 179.9,144.72 v1(179.59,144.72) 178.95,144.72 178.71,144.96 176.99,144.96
  BOTTOM w0.102: v1(173.96,147.65) 173.46,147.16 173.46,146.93 UV19.N7 ; UV1.J16 182.66,128.54 v1(182.11,129.09) ; v1(184.21,147.65) 184.7,148.15 184.7,148.38 UV21.N7
MAA13: length 50.8
  TOP w0.102: v1(181.24,147.65) 181.71,148.13 181.71,148.44 182.52,149.25 UV20.T3 ; v1(176.93,147.65) 176.46,147.18 176.46,146.89 176.2,146.64 175.75,146.64 175.34,146.23 175.16,146.23 UV18.T3 ; v1(177.17,128.92) 176.64,129.45 176.64,130.13 176.34,130.43 176.05,130.43 175.61,130.87 175.61,131.21 175.27,131.55 175.27,132.67 175.61,133.01 175.61,135.39
  TOP w0.127: 175.61,135.39 175.61,135.6 175.27,135.94 175.27,139.31 175.61,139.65 175.61,140.14 175.55,140.2 174.39,140.2 174.26,140.33 v2(174.26,141.3) 174.26,142.4 174.39,142.53 175.2,142.53 175.32,142.66 175.32,142.99 175.2,143.11 174.96,143.11 174.83,143.24 174.83,143.49 174.96,143.62 175.2,143.62 175.32,143.75 175.32,145.29 176.25,146.21 177.5,146.21 177.62,146.34 177.62,146.92 177.75,147.05 177.84,147.05 177.97,147.17 177.97,147.97 178.1,148.1 178.51,148.1 178.64,147.97 178.64,147.84 178.77,147.71 179.54,147.71 179.72,147.53 180.48,147.53 180.6,147.4 180.6,147 180.48,146.87 178.77,146.87 178.64,147 v1(178.64,147.02)
  IN1 w0.102: v1(176.93,147.65) 176.93,147.72 177.16,147.95 177.24,147.95 177.31,147.89 177.31,147.78 177.38,147.71 177.6,147.71 177.75,147.55 177.75,147.4 177.64,147.29 177.39,147.29 177.31,147.22 177.31,146.7 177.42,146.59 177.79,146.59 177.93,146.73 ; 180.24,146.83 180.8,146.83 180.99,146.64 181.39,146.64 181.62,146.86 181.62,147.27 v1(181.24,147.65)
  IN1 w0.14: 177.93,146.73 178,146.73 178.07,146.79 178.07,147.04 178.15,147.12 178.54,147.12 v1(178.64,147.02) 178.83,146.83 179.67,146.83 179.67,146.83 180.24,146.83
  BOTTOM w0.102: v1(177.17,128.92) 176.99,129.09 UV1.H23 ; UV21.T3 182.44,146.05 181.71,146.79 181.71,147.18 v1(181.24,147.65) ; v1(176.93,147.65) 176.46,148.12 176.46,148.44 175.64,149.25 UV19.T3
MAA14: length 53.3
  TOP w0.102: v1(182.23,148.29) 181.85,147.91 181.85,146.86 182.65,146.05 UV20.T7 ; v1(175.94,147.02) 176.32,147.4 176.32,148.45 175.51,149.25 UV18.T7
  IN1 w0.102: v1(175.94,147.02) 175.56,147.4 175.56,148.45 175.78,148.67 177.92,148.67 177.93,148.66 ; v1(182.23,148.29) 182.23,148.14 182.1,148.01 181.8,148.01 181.67,148.14 181.67,149 181.54,149.13 181.08,149.13 180.95,149 180.95,148.54 180.82,148.42 180.43,148.42 180.24,148.61
  IN1 w0.14: 180.24,148.61 180.18,148.67 179.38,148.67 v1(178.96,148.25) 178.34,148.25 177.93,148.66
  IN3 w0.102: v1(179.67,128.46) 180.1,128.88 180.1,130.57 180.05,130.62 180.05,131.26 179.54,131.76 179.54,132.1
  IN3 w0.157: v1(178.96,148.25) 178.87,148.16 178.87,147.85 178.99,147.72 179.52,147.72 179.64,147.6 179.64,146.96 179.77,146.83 180.42,146.83 180.54,146.7 180.54,144.26 180.42,144.13 180.13,144.13 180,144.01 180,141.69 179.88,141.56 179.67,141.56 179.35,141.24 179.35,139.98 179.47,139.85 181.22,139.85 181.35,139.73 181.35,137.15 181.19,137 180.28,137 180.15,136.87 180.15,136.49 180.28,136.37 181.22,136.37 181.35,136.24 181.35,135.84 181.22,135.72 180.54,135.72 180.42,135.59 180.42,135.14 180.54,135.02 180.86,135.02 180.99,134.89 180.99,134.52 180.86,134.39 179.83,134.39 179.54,134.1 179.54,132.1
  BOTTOM w0.102: UV1.J19 180.26,128.55 180.14,128.68 179.89,128.68 v1(179.67,128.46) ; UV19.T7 175.21,145.83 175.46,145.83 175.53,145.9 175.53,146.26 175.79,146.52 176.15,146.52 176.54,146.92 176.54,147.04 176.31,147.27 176.19,147.27 175.94,147.02 v1(175.94,147.02) ; UV21.T7 182.96,149.48 182.45,149.48 182.32,149.35 182.32,148.8 182.26,148.73 181.7,148.73 181.6,148.63 181.6,148.4 181.71,148.29 v1(182.23,148.29)
MAB0: length 54.5
  TOP w0.102: 194.39,124.38 189.89,124.38 189.69,124.18 188.64,124.18 188.49,124.33 187.19,124.33 187.09,124.23 187.09,123.2 187.27,123.02 187.85,123.02 187.97,123.14 187.97,123.65 188.1,123.77 189.28,123.77 189.38,123.67 v1(189.38,123.34) ; UV25.N3 211.31,117.22 210.55,117.98 209.5,117.98 v1(209.12,117.6) ; UV22.N3 208.2,129.7 208.96,128.94 209.97,128.94 210.18,129.14 210.21,129.14 v1(210.39,129.32)
  TOP w0.127: v1(206.05,123.14) 206.35,123.14 206.48,123.02 v2(206.48,122.76) 206.48,122.6 206.35,122.48 205.69,122.48 205.56,122.6 205.56,122.73 205.43,122.86 205.18,122.86 205.05,122.73 205.05,122.6 204.92,122.48 204.67,122.48 204.54,122.6 204.54,122.64 204.42,122.77 204.16,122.77 204.03,122.64 204.03,122.6 203.91,122.48 203.5,122.48 203.34,122.64 203.34,123.02 203.01,123.35 202.58,123.35 202.42,123.51 202.42,123.94 201.97,124.38 194.39,124.38
  IN1 w0.102: 206.05,121.62 206.05,120.44 206.29,120.19 206.44,120.19 206.56,120.31 206.7,120.31 206.84,120.17 206.84,120.02 206.72,119.9 206.72,119.76 206.87,119.62 207.01,119.62 207.1,119.71 207.24,119.71 207.39,119.56 207.39,119.42 207.3,119.33 207.3,119.19 207.44,119.04 207.59,119.04 207.66,119.11 207.8,119.11 207.95,118.97 207.95,118.83 207.87,118.75 207.87,118.61 208.88,117.6 v1(209.12,117.6) ; v1(210.39,129.32) 210.39,129.3 209.8,128.71 208.96,128.71 206.05,125.8 206.05,125.3
  IN1 w0.14: 206.05,125.3 v1(206.05,123.14) 206.05,121.62
  BOTTOM w0.102: v1(209.12,117.6) 209.12,117.63 208.99,117.76 208.74,117.76 208.61,117.63 208.61,117.43 208.86,117.17 208.86,117.05 208.76,116.95 208.23,116.95 208.15,117.02 UV24.N3 ; UV23.N3 211.21,129.56 210.87,129.56 210.77,129.66 210.77,129.87 210.67,129.98 210.43,129.98 210.33,129.87 210.33,129.39 v1(210.39,129.32) ; v1(189.38,123.34) 188.99,123.34 188.86,123.47 UV1.P8
MAB1: length 52.3
  TOP w0.102: UV22.P7 211.55,128.9 211.94,128.51 211.94,128.35 211.83,128.24 211.67,128.24 211.49,128.43 211.11,128.43 210.98,128.3 210.98,127.91 210.83,127.75 210.83,127.33 210.66,127.16 210.57,127.16 v1(210.39,127.34) ; v1(209.12,119.58) 209.07,119.58 208.53,119.04 208.53,118.39 UV25.P7
  IN1 w0.102: 211.32,122.56 211.32,120.74 210.77,120.19 209.73,120.19 v1(209.12,119.58) ; 211.32,125.3 211.32,126.6 210.57,127.34 v1(210.39,127.34)
  IN1 w0.14: 211.32,122.56 211.32,123.74 v1(211.15,123.91) 211.32,124.07 211.32,125.3
  IN3 w0.102: 194.07,124.95 193.68,124.56 192.29,124.56 192,124.85 189.6,124.85 189.51,124.94 189.14,124.94 187.71,123.52 v1(187.54,123.52)
  IN3 w0.157: 194.07,124.95 194.35,125.23 198.23,125.23 198.38,125.08 198.38,123.94 198.54,123.79 198.86,123.79 199.01,123.94 199.01,125.08 199.17,125.23 199.49,125.23 199.64,125.08 199.64,123.95 199.8,123.79 200.12,123.79 200.27,123.95 200.27,124.41 200.43,124.56 202.98,124.56 203.65,125.23 208.49,125.23 209.63,124.1 210.96,124.1 v1(211.15,123.91)
  BOTTOM w0.102: v1(187.54,123.52) 188.06,123 UV1.T9 ; v1(210.39,127.34) 209.99,127.73 209.12,127.73 208.74,128.12 208.74,128.41 208.24,128.9 UV23.P7 ; UV24.P7 211.26,118.02 210.77,118.51 210.77,118.81 210.39,119.19 209.51,119.19 v1(209.12,119.58)
MAB2: length 52
  TOP w0.102: UV25.P3 211.25,118.02 210.77,118.5 210.77,118.75 210.55,118.97 209.5,118.97 v1(209.12,118.59) ; v1(210.39,128.33) 210.01,127.95 208.96,127.95 208.74,128.17 208.74,128.34 208.17,128.9 UV22.P3
  IN1 w0.102: 212.61,121.62 212.61,120.22 211.47,119.08 209.61,119.08 v1(209.12,118.59) ; v1(210.39,128.33) 211.42,128.33 212.48,127.27 212.48,126.19 212.61,126.06 212.61,125.3
  IN1 w0.14: 212.61,121.62 v1(212.61,123.33) 212.61,125.3
  IN3 w0.102: v1(188.3,124.75) 188.8,125.25 188.8,126.11 189.01,126.32 193.42,126.32 193.78,125.95 194.39,125.95
  IN3 w0.157: 194.39,125.95 207.29,125.95 208.1,126.76 212.3,126.76 212.61,126.45 v1(212.61,123.33)
  BOTTOM w0.102: UV23.P3 211.08,128.9 210.51,128.33 v1(210.39,128.33) ; v1(188.3,124.75) 188.3,124.33 UV1.P9 ; v1(209.12,118.59) 209,118.59 208.43,118.02 UV24.P3
MAB3: length 59.9
  TOP w0.102: v1(209.12,129.32) 208.36,130.08 207.26,130.08 207.15,129.97 207.15,129.81 207.26,129.7 UV22.N2 ; UV25.N2 212.49,117.22 212.61,117.09 212.61,116.87 212.49,116.74 211.91,116.74 211.84,116.67 211.66,116.67 211.48,116.84 211.14,116.84 v1(210.39,117.6) ; v1(189.9,125.86) 189.9,125.94 190.02,126.06 191.34,126.06 191.47,125.94 191.47,125.11 191.59,124.98 191.85,124.98 191.97,125.11 191.97,125.42 192.1,125.55 193.75,125.55
  TOP w0.127: v1(205.12,123.27) 205.12,123.52 204.99,123.65 204.23,123.65 204.1,123.78 204.1,123.93 203.98,124.06 203.15,124.06 202.31,124.9 200.27,124.9 200.15,125.03 200.15,125.68 200.02,125.81 199.77,125.81 199.64,125.68 199.64,125.03 199.51,124.9 199.26,124.9 199.13,125.03 199.13,125.68 199,125.81 198.75,125.81 198.62,125.68 v2(198.62,125.3) 198.62,125.03 198.5,124.9 198.24,124.9 198.12,125.03 198.12,125.68 197.99,125.81 197.73,125.81 197.61,125.68 197.61,125.03 197.48,124.9 197.23,124.9 197.1,125.03 197.1,125.68 196.97,125.81 196.72,125.81 196.59,125.68 196.59,125.03 196.46,124.9 196.21,124.9 196.08,125.03 196.08,125.68 195.96,125.81 195.7,125.81 195.58,125.68 195.58,125.03 195.45,124.9 195.19,124.9 195.07,125.03 195.07,125.68 194.94,125.81 194.69,125.81 194.56,125.68 194.56,125.03 194.43,124.9 194.18,124.9 194.05,125.03 194.05,125.42 193.92,125.55 193.75,125.55
  IN1 w0.102: v1(210.39,117.6) 210.37,117.6 209.76,116.99 208.67,116.99 207.72,117.94 206.07,117.94 205.12,118.89 205.12,121.62 ; 205.12,125.3 205.12,125.75 208.69,129.32 v1(209.12,129.32)
  IN1 w0.14: 205.12,125.3 v1(205.12,123.27) 205.12,121.62
  BOTTOM w0.102: v1(209.12,129.32) 209.63,128.81 210.71,128.81 211.21,129.32 211.77,129.32 212.15,129.7 UV23.N2 ; UV1.N7 189.66,125.62 v1(189.9,125.86) ; UV24.N2 207.73,117.6 208.29,117.6 208.8,118.11 209.88,118.11 v1(210.39,117.6)
MAB4: length 56
  TOP w0.102: v1(210.39,119.58) 210.29,119.58 209.89,119.17 209.16,119.17 208.74,118.75 208.74,118.05 208.29,117.6 207.77,117.6 UV25.P8 ; v1(209.12,127.34) 209.21,127.34 209.62,127.75 210.34,127.75 210.77,128.17 210.77,128.88 211.22,129.32 211.73,129.32 UV22.P8
  IN1 w0.102: v1(210.39,119.58) 210.4,119.59 211.02,119.59 212.17,120.73 212.17,121.62 ; v1(209.12,127.34) 209.73,127.95 211.28,127.95 212.17,127.06 212.17,125.3
  IN1 w0.14: 212.17,121.62 v1(212.17,124.41) 212.17,125.3
  IN3 w0.102: 194.39,125.59 191.77,125.59 191.59,125.76 190.59,125.76 190.31,125.48 189.58,125.48 v1(189.24,125.82)
  IN3 w0.157: v1(212.17,124.41) 212.17,125.62 211.98,125.81 211.68,125.81 211.53,125.66 211.53,124.63 211.38,124.48 211.05,124.48 210.9,124.63 210.9,125.66 210.74,125.81 208.08,125.81 207.86,125.59 202.71,125.59 202.55,125.43 202.55,125.08 202.39,124.92 202.08,124.92 201.92,125.08 201.92,125.43 201.76,125.59 201.45,125.59 201.29,125.43 201.29,125.08 201.13,124.92 200.82,124.92 200.66,125.08 200.66,125.43 200.5,125.59 194.39,125.59
  BOTTOM w0.102: v1(210.39,119.58) 210.39,119.47 210.97,118.89 210.97,118.6 211.18,118.39 211.78,118.39 UV24.P8 ; v1(189.24,125.82) 188.86,125.45 UV1.N8 ; v1(209.12,127.34) 209.12,127.45 208.53,128.03 208.53,128.33 208.33,128.53 207.73,128.53 207.35,128.9 UV23.P8
MAB5: length 58.8
  TOP w0.102: 194.39,126.06 192.04,126.06 191.82,126.28 188.81,126.28 v1(188.37,125.84) ; UV25.P2 212.15,118.32 212.03,118.44 211.85,118.44 211.72,118.32 211.72,117.77 211.6,117.64 211.2,117.64 210.39,118.45 v1(210.39,118.59) ; v1(209.12,128.33) 209.03,128.33 208.53,128.83 208.53,129.06 208.31,129.28 207.91,129.28 207.79,129.15 207.79,128.54 207.66,128.41 207.48,128.41 207.35,128.54 UV22.P2
  TOP w0.127: 194.39,126.06 200.41,126.06 200.53,125.94 200.53,125.29 200.66,125.16 200.91,125.16 201.04,125.29 v2(201.04,125.81) 201.04,126.25 201.17,126.38 201.42,126.38 201.55,126.25 201.55,125.29 201.68,125.16 201.93,125.16 202.06,125.29 202.06,126.25 202.18,126.38 202.45,126.38 202.58,126.25 202.58,125.24 202.71,125.11 202.96,125.11 203.09,125.24 203.09,126.25 203.21,126.38 203.49,126.38 203.61,126.25 203.61,125.07 203.45,124.91 203.45,124.44 203.58,124.31 204.29,124.31 204.42,124.44 204.42,125.87 204.55,126 204.8,126 204.93,125.87 204.93,124.44 205.05,124.31 205.81,124.31 v1(206.47,123.65)
  IN1 w0.102: v1(209.12,128.33) 206.47,125.68 206.47,125.3 ; v1(210.39,118.59) 209.8,118.01 208.88,118.01 208.48,118.4 208.48,118.95 206.47,120.96 206.47,121.62
  IN1 w0.14: 206.47,121.62 v1(206.47,123.65) 206.47,125.3
  BOTTOM w0.102: v1(188.37,125.84) 188.06,125.53 UV1.N9 ; UV24.P2 207.73,118.39 208.26,118.39 208.85,118.98 210,118.98 v1(210.39,118.59) ; UV23.P2 212.15,128.9 211.78,128.53 211.25,128.53 210.66,127.94 209.51,127.94 v1(209.12,128.33)
MAB6: length 59.7
  TOP w0.102: v1(210.39,121.56) 209.97,121.98 208.93,121.98 206.96,120.01 206.96,119.21 UV25.R8 ; UV22.R8 212.55,127.71 212.55,126.91 210.58,124.94 209.56,124.94 209.15,125.36 v1(209.12,125.36)
  IN1 w0.102: v1(210.39,121.56) 209.78,120.95 208.67,120.95 208.33,121.3 208.33,122.56 ; 208.9,124.36 208.45,124.36 208.32,124.49 208.32,124.8 208.45,124.93 209.27,124.93 209.39,125.05 209.39,125.23 209.27,125.36 v1(209.12,125.36)
  IN1 w0.14: 208.9,124.36 209.03,124.24 209.03,123.97 208.9,123.84 208.74,123.84 208.68,123.78 v1(208.68,123.21) 208.67,123.21 208.33,122.86 208.33,122.56
  IN3 w0.102: 194.39,123.07 194.21,123.07 193.24,124.04 190.12,124.04 189.86,123.77 189.23,123.77 188.94,123.49 188.94,123.2 v1(188.06,122.32)
  IN3 w0.157: v1(208.68,123.21) 208.68,123.84 208.02,124.5 205.22,124.5 204.54,123.82 204.12,123.82 203.37,123.07 201.38,123.07 201.22,122.91 201.22,122.71 201.06,122.55 200.75,122.55 200.59,122.71 200.59,122.91 200.43,123.07 200.12,123.07 199.96,122.91 199.96,122.71 199.8,122.55 199.49,122.55 199.33,122.71 199.33,122.91 199.17,123.07 198.86,123.07 198.7,122.91 198.7,122.71 198.54,122.55 198.23,122.55 198.07,122.71 198.07,122.91 197.91,123.07 197.6,123.07 197.44,122.91 197.44,122.71 197.28,122.55 196.97,122.55 196.81,122.71 196.81,122.91 196.65,123.07 196.34,123.07 196.18,122.91 196.18,121.39 196.03,121.24 195.7,121.24 195.55,121.39 195.55,122.91 195.39,123.07 194.39,123.07
  BOTTOM w0.102: UV24.R8 212.41,118.82 212.55,118.95 212.55,119.14 212.42,119.27 211.98,119.27 211.78,119.47 211.78,120.16 211.51,120.43 211.37,120.43 211.23,120.29 211.08,120.29 210.94,120.43 210.94,120.58 211.08,120.72 211.08,120.86 210.39,121.56 v1(210.39,121.56) ; v1(209.12,125.36) 208.5,125.98 208.5,126.13 208.61,126.24 208.61,126.38 208.47,126.53 208.32,126.53 208.21,126.41 208.07,126.41 207.73,126.75 207.73,127.52 207.72,127.53 207.72,127.61 207.62,127.72 207.06,127.72 206.96,127.82 206.96,128 207.06,128.1 UV23.R8 ; UV1.U9 v1(188.06,122.32)
MAB7: length 59
  TOP w0.102: UV22.R2 207.7,128.1 208.07,128.48 208.31,128.48 208.53,128.26 208.53,128.02 208.73,127.81 208.73,127.21 208.74,127.2 208.74,127.18 208.99,126.93 209.8,126.93 v1(210.39,126.35) ; UV25.R2 211.84,118.82 211.47,118.44 211.2,118.44 210.98,118.66 210.98,118.91 210.78,119.11 210.78,119.71 210.77,119.72 210.77,119.74 210.52,119.99 209.7,119.99 v1(209.12,120.57) ; 194.39,121.24 194.21,121.24 194.09,121.36 192.86,121.36 192.54,121.04 191.54,121.04 191.26,120.76 189.54,120.76 v1(189.13,121.17)
  TOP w0.127: 194.39,121.24 194.63,121.24 194.76,121.37 194.76,122.43 194.9,122.58 196.25,122.58 196.38,122.45 196.38,121.93 196.5,121.8 198.49,121.8 198.61,121.93 198.61,122.45 198.74,122.58 200.72,122.58 201.08,122.22 206.46,122.22 207.48,123.24 207.48,124.54 207.35,124.67 v2(206.71,124.67) 205.44,124.67 205.31,124.79 205.31,125.11 205.44,125.24 207.85,125.24 207.98,125.11 207.98,124.35 208.1,124.22 209.36,124.22 209.48,124.1 209.48,123.91 209.36,123.78 v1(208.12,123.78)
  IN1 w0.102: 208.12,124.36 208.12,125.07 208.79,125.74 210.13,125.74 210.39,126 v1(210.39,126.35) ; v1(209.12,120.57) 208.26,120.57 207.98,120.86 207.98,121.62
  IN1 w0.14: 208.12,124.36 v1(208.12,123.78) 207.98,123.64 207.98,121.62
  BOTTOM w0.102: v1(210.39,126.35) 210.85,126.35 210.97,126.48 210.97,127.5 211.1,127.63 212.48,127.63 212.61,127.75 212.61,127.98 212.48,128.1 UV23.R2 ; v1(209.12,120.57) 208.66,120.57 208.53,120.45 208.53,119.47 208.31,119.24 207.02,119.24 206.9,119.12 206.9,118.95 207.02,118.82 UV24.R2 ; v1(189.13,121.17) 188.86,121.44 UV1.U8
MAB8: length 53.9
  TOP w0.102: UV22.T8 212.15,127.61 212.05,127.72 211.89,127.72 211.79,127.61 211.79,126.44 210.71,125.36 v1(210.39,125.36) ; UV25.T8 207.35,119.33 207.48,119.21 207.66,119.21 207.79,119.33 207.79,120.55 208.77,121.54 v1(209.12,121.54)
  IN1 w0.102: 210.11,122.56 209.12,121.57 v1(209.12,121.54) ; 210.39,124.36 v1(210.39,125.36)
  IN1 w0.14: 210.11,122.56 210.24,122.69 v1(210.24,123.21) 210.24,124.22 210.39,124.36
  IN3 w0.102: v1(188.48,118.52) 188.72,118.76 188.72,119.86 189.15,120.29 193.94,120.29 194.13,120.1 194.39,120.1
  IN3 w0.157: v1(210.24,123.21) 210.24,123.19 209.83,122.77 208.41,122.77 207.5,123.69 207.5,123.83 207.23,124.1 205.33,124.1 204.67,123.44 204.67,123.14 203.72,122.19 200.14,122.19 199.98,122.03 199.98,121.68 199.86,121.56 199.48,121.56 199.35,121.68 199.35,122.03 199.19,122.19 198.88,122.19 198.72,122.03 198.72,120.25 198.57,120.1 198.18,120.1 198.03,120.25 198.03,122.04 197.87,122.19 197.52,122.19 197.4,122.06 197.4,120.25 197.24,120.1 194.39,120.1
  BOTTOM w0.102: UV23.T8 207.35,126.54 208.95,124.94 209.97,124.94 v1(210.39,125.36) ; v1(209.12,121.54) 209.12,121.54 209.12,121.56 209.54,121.98 210.6,121.98 212.15,120.43 UV24.T8 ; UV1.Y9 188.48,118.87 v1(188.48,118.52)
MAB9: length 53.7
  TOP w0.102: UV22.R3 208.15,127.98 208.53,127.61 208.53,127.12 208.53,127.12 208.53,127.1 208.9,126.73 209.37,126.73 v1(209.75,126.35) ; 194.39,120.37 192.7,120.37 192.51,120.56 191.63,120.56 191.43,120.35 188.7,120.35 v1(188.26,119.91) ; v1(209.75,120.57) 210.13,120.19 210.61,120.19 210.97,119.82 210.97,119.81 210.98,119.8 210.98,119.31 211.35,118.94 UV25.R3
  TOP w0.127: 194.39,120.37 194.64,120.37 194.77,120.24 194.77,119.47 194.89,119.34 195.15,119.34 195.28,119.47 v2(195.28,120.06) 195.28,121.93 195.4,122.06 195.73,122.06 195.86,121.93 195.86,119.52 195.98,119.4 196.24,119.4 196.37,119.52 196.37,121.16 196.49,121.28 199.01,121.28 199.13,121.41 199.13,121.93 199.26,122.06 199.51,122.06 199.64,121.93 199.64,121.41 199.77,121.28 200.02,121.28 200.15,121.41 200.15,121.91 200.28,122.04 200.53,122.04 200.66,121.91 200.66,121.41 200.78,121.28 201.5,121.28 201.63,121.41 201.63,121.79 201.75,121.92 207.71,121.92 208.11,122.32 208.11,122.5 207.78,122.83 207.6,122.83 207.4,122.64 v1(207.4,122.57)
  IN1 w0.102: 208.03,125.3 208.68,125.94 209.35,125.94 v1(209.75,126.35) ; v1(209.75,120.57) 209.21,120.03 208.29,120.03 207.28,121.05 207.28,121.24
  IN1 w0.14: 208.03,125.3 207.59,124.86 207.59,122.76 v1(207.4,122.57) 207.28,122.44 207.28,122.14 207.42,122 207.48,122 207.63,121.84 207.63,121.59 207.48,121.44 207.42,121.44 207.28,121.3 207.28,121.24
  BOTTOM w0.102: UV1.W9 188.06,120.11 v1(188.26,119.91) ; v1(209.75,120.57) 209.28,120.1 208.99,120.1 208.74,119.85 208.74,119.31 208.24,118.82 UV24.R3 ; v1(209.75,126.35) 210.22,126.82 210.52,126.82 210.77,127.07 210.77,127.61 211.27,128.1 UV23.R3
MAB10: length 56.5
  TOP w0.102: v1(210.39,115.62) 210.29,115.62 209.91,115.24 208.96,115.24 208.58,115.62 UV25.L7 ; UV22.L7 211.35,131.3 210.93,131.3 210.55,131.68 209.5,131.68 v1(209.12,131.3)
  IN1 w0.102: 213.63,121.62 213.63,120.03 211.21,117.62 211.21,116.41 210.42,115.62 v1(210.39,115.62) ; 213.63,125.3 213.63,126.34 212.94,127.03 212.94,128.69 211.15,130.48 211.15,131.27 210.74,131.68 209.5,131.68 v1(209.12,131.3)
  IN1 w0.14: 213.63,125.3 v1(213.63,124.35) 213.63,121.62
  IN3 w0.102: v1(189.13,116.41) 189.5,116.77 190.2,116.77 190.51,117.09 194.36,117.09
  IN3 w0.157: v1(213.63,124.35) 213.63,123.14 210.55,120.06 208.07,120.06 206.83,118.83 206.01,118.83 205.48,118.29 195.57,118.29 194.36,117.09
  BOTTOM w0.102: UV23.L7 209.12,131.3 v1(209.12,131.3) ; UV24.L7 v1(210.39,115.62) ; v1(189.13,116.41) 189.11,116.41 188.86,116.65 UV1.AC8
MAB11: length 51.6
  TOP w0.102: v1(209.75,119.58) 209.37,119.96 208.75,119.96 208.55,119.76 208.55,119.45 208.15,119.06 UV25.R7 ; UV22.R7 211.35,127.86 211.03,127.54 211.03,127.23 210.76,126.96 210.13,126.96 v1(209.75,127.34)
  IN1 w0.102: 211.66,125.3 211.66,127.14 211.06,127.75 210.16,127.75 v1(209.75,127.34) ; 211.66,121.62 211.66,120.69 210.96,119.99 210.16,119.99 v1(209.75,119.58)
  IN1 w0.14: 211.66,121.62 211.66,123.83 v1(211.73,123.91) 211.66,123.98 211.66,125.3
  IN3 w0.102: v1(188.93,117.49) 189.18,117.24 190.09,117.24 190.34,117.49 193.4,117.49 193.85,117.94
  IN3 w0.157: 193.85,117.94 194.92,119.02 203.09,119.02 203.53,119.46 203.53,119.9 204.05,120.42 204.52,120.42 204.67,120.27 204.67,119.17 204.83,119.02 205.15,119.02 205.3,119.17 205.3,120.27 205.46,120.42 207.16,120.42 208.69,121.95 209.57,121.95 209.58,121.97 211.25,121.97 211.73,122.46 v1(211.73,123.91)
  BOTTOM w0.102: v1(188.93,117.49) 188.32,116.89 UV1.AC9 ; UV24.R7 210.77,119.4 210.77,119.82 210.62,119.97 210.15,119.97 v1(209.75,119.58) ; v1(209.75,127.34) 209.36,126.95 208.89,126.95 208.64,127.2 208.64,127.62 UV23.R7
MAB12: length 52.1
  TOP w0.102: UV22.N7 211.35,129.75 211.23,129.87 210.83,129.87 210.71,129.75 210.71,129.62 210.87,129.46 210.87,129.27 210.55,128.94 210.26,128.94 210.03,128.71 209.75,128.71 209.63,128.58 209.63,128.46 v1(209.75,128.33) ; UV25.N7 208.2,117.22 209.12,118.14 209.3,118.14 v1(209.75,118.59)
  IN1 w0.102: 207.06,125.3 207.06,125.91 208.99,127.84 209.26,127.84 v1(209.75,128.33) ; 206.82,121.62 206.82,121.12 208.74,119.21 208.74,118.43 208.96,118.21 209.37,118.21 v1(209.75,118.59)
  IN1 w0.14: 206.82,121.62 206.82,122.58 207.06,122.83 v1(207.06,123.65) 207.06,125.3
  IN3 w0.102: v1(189.93,117.62) 190.04,117.73 193.13,117.73 193.82,118.42
  IN3 w0.157: v1(207.06,123.65) 207.05,123.65 206.9,123.5 206.9,123.2 207.05,123.05 207.63,123.05 207.85,122.82 207.85,122.29 207.7,122.14 207.3,122.14 207.15,121.99 207.15,120.94 207,120.78 206.73,120.78 206.58,120.94 206.58,122.56 206.43,122.72 206.12,122.72 205.97,122.56 205.97,120.94 205.82,120.78 202.28,120.78 202.12,120.63 202.12,120.25 202.28,120.1 202.94,120.1 203.09,119.94 203.09,119.53 202.94,119.38 194.77,119.38 193.82,118.42
  BOTTOM w0.102: UV24.N7 210.48,118.1 210.25,118.1 v1(209.75,118.59) ; v1(189.93,117.62) 189.93,117.82 UV1.AA7 ; UV23.N7 209.03,128.83 209.26,128.83 v1(209.75,128.33)
MAB13: length 50
  TOP w0.102: UV25.T3 211.35,120.25 210.51,121.09 210.23,121.09 v1(209.75,121.56) ; UV22.T3 208.15,126.06 208.39,125.83 209.28,125.83 v1(209.75,125.36)
  IN1 w0.102: 208.72,122.56 208.61,122.44 208.61,121.47 208.93,121.16 209.35,121.16 v1(209.75,121.56) ; 209.37,124.36 209.37,124.65 209.75,125.03 v1(209.75,125.36)
  IN1 w0.14: 208.72,122.56 v1(209.37,123.21) 209.37,124.36
  IN3 w0.102: v1(188.43,123.39) 188.56,123.39 189.14,123.98 189.59,123.98 189.98,124.36 193.37,124.36 194.3,123.43
  IN3 w0.157: v1(209.37,123.21) 209.37,123.71 208.23,124.86 205.07,124.86 204.4,124.18 203.63,124.18 203.48,124.03 203.48,123.69 203.33,123.54 203.05,123.54 202.9,123.69 202.9,124.03 202.74,124.18 202.47,124.18 202.31,124.03 202.31,123.58 202.16,123.43 198.02,123.43 197.86,123.59 197.86,124.7 197.71,124.86 197.39,124.86 197.24,124.7 197.24,123.59 197.08,123.43 196.76,123.43 196.61,123.59 196.61,124.7 196.45,124.86 196.13,124.86 195.98,124.7 195.98,123.59 195.82,123.43 195.5,123.43 195.35,123.59 195.35,124.7 195.19,124.86 194.87,124.86 194.72,124.7 194.72,123.59 194.56,123.43 194.3,123.43
  BOTTOM w0.102: UV23.T3 211.35,126.57 210.62,125.83 210.22,125.83 v1(209.75,125.36) ; UV1.T8 188.86,122.96 v1(188.43,123.39) ; UV24.T3 208.15,120.36 208.89,121.09 209.28,121.09 v1(209.75,121.56)
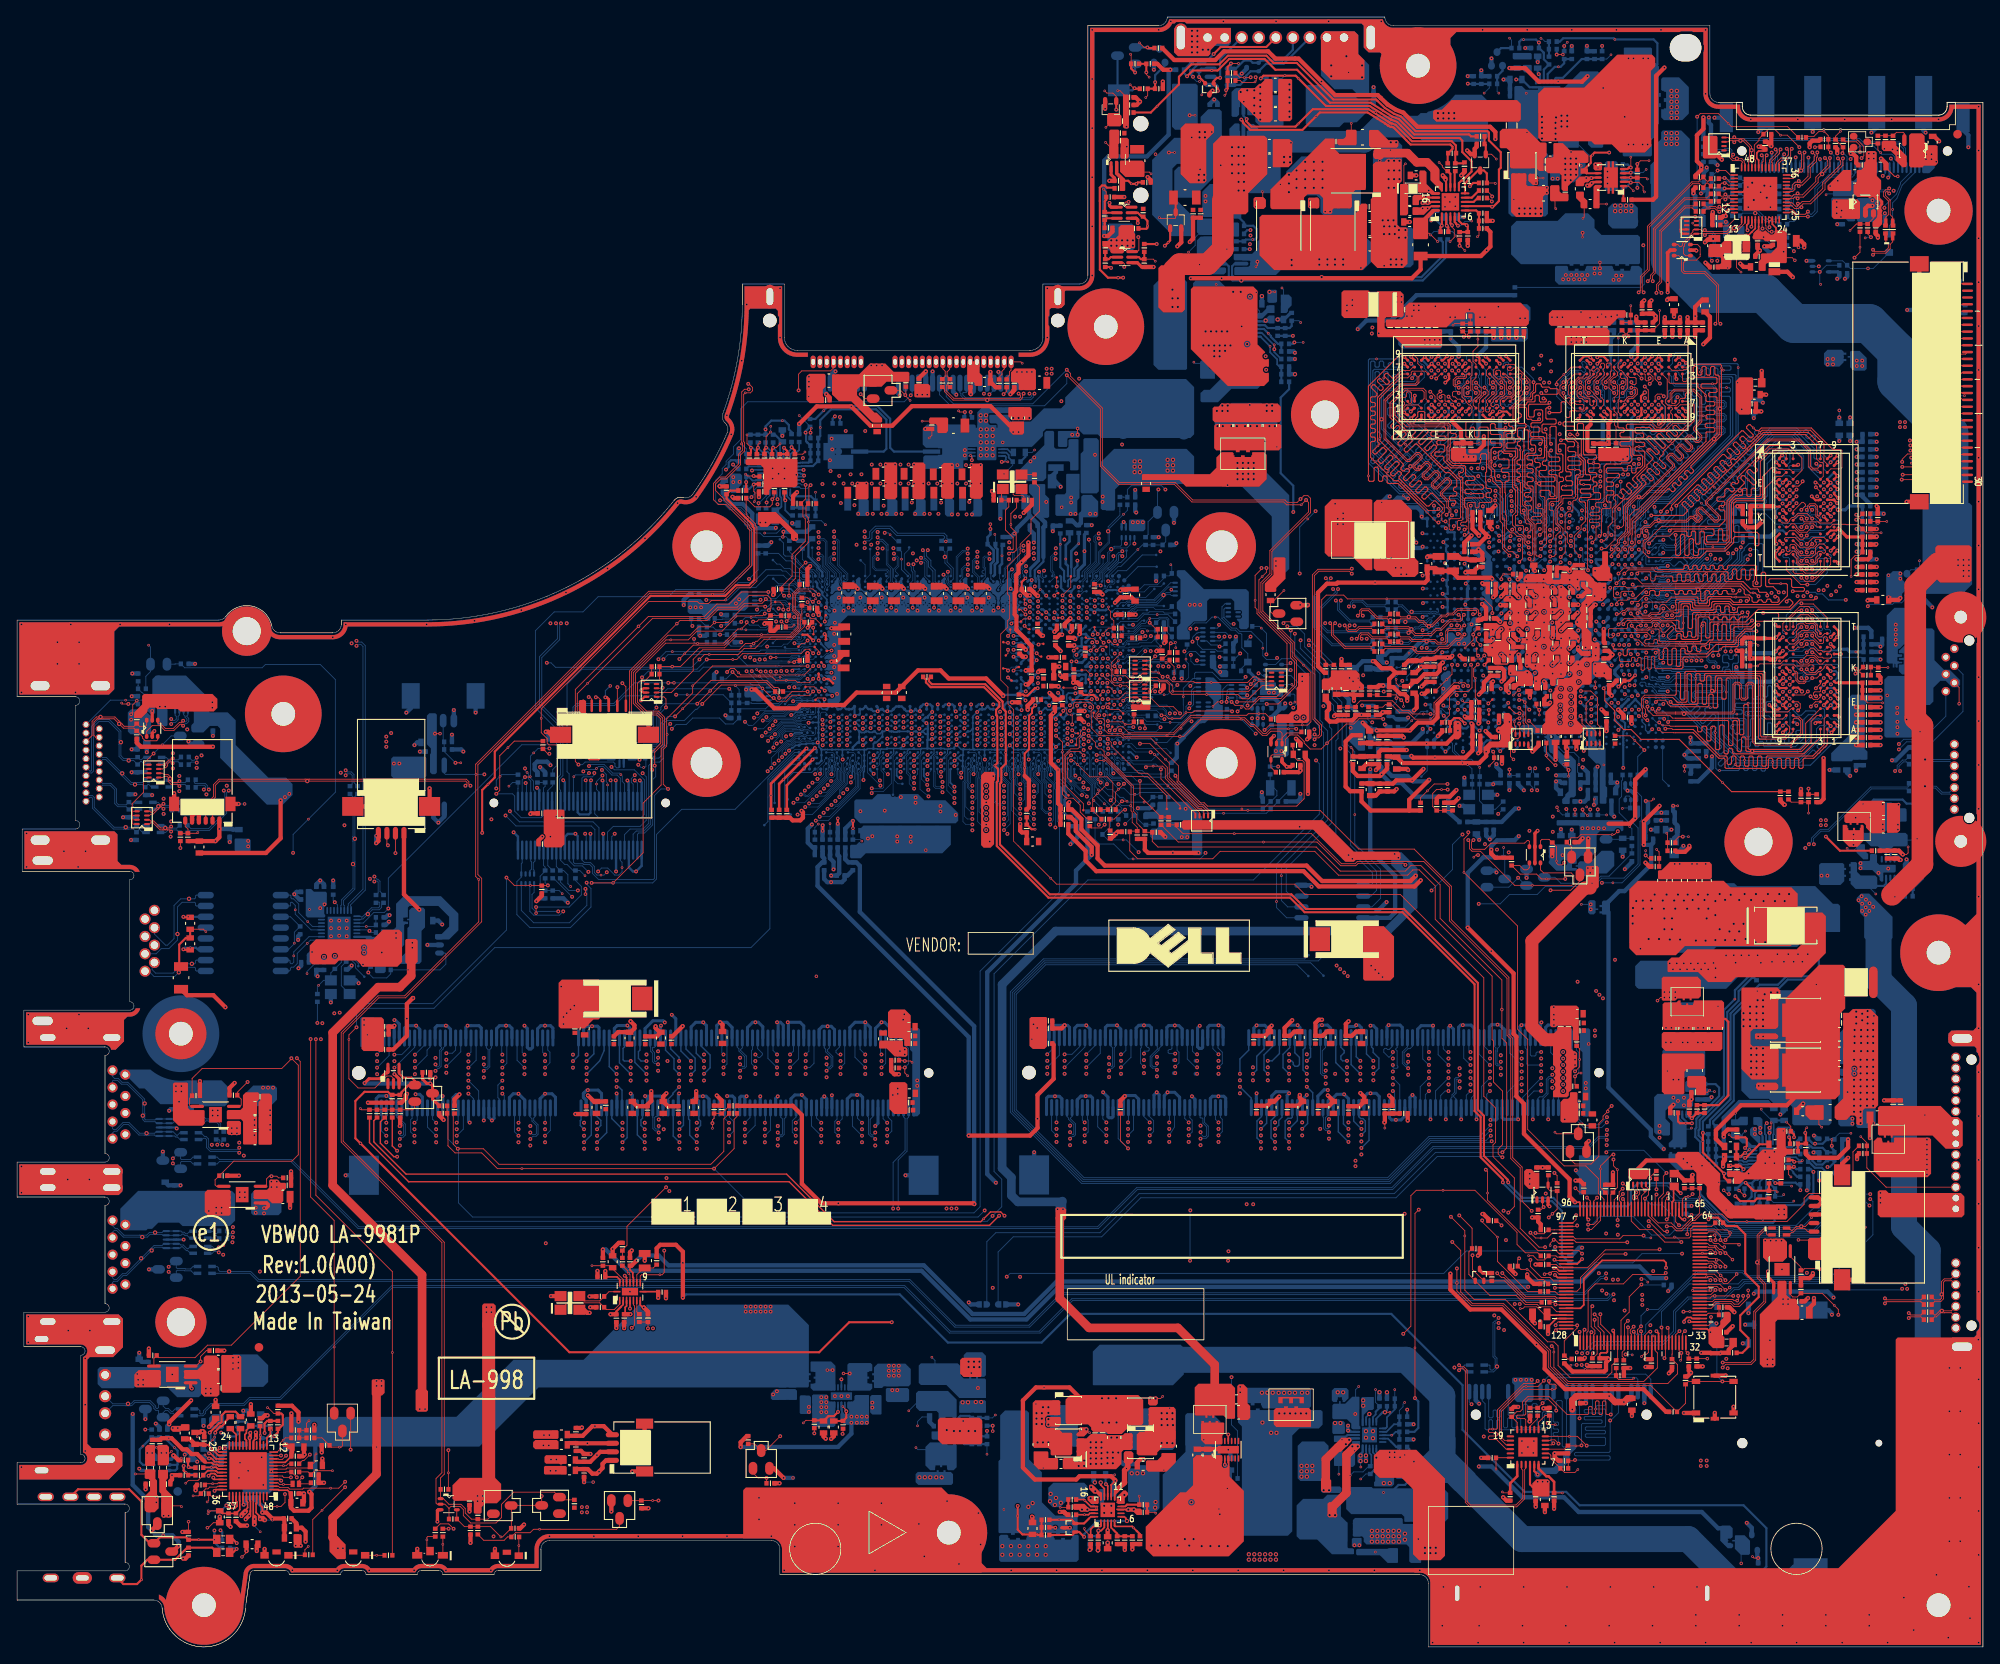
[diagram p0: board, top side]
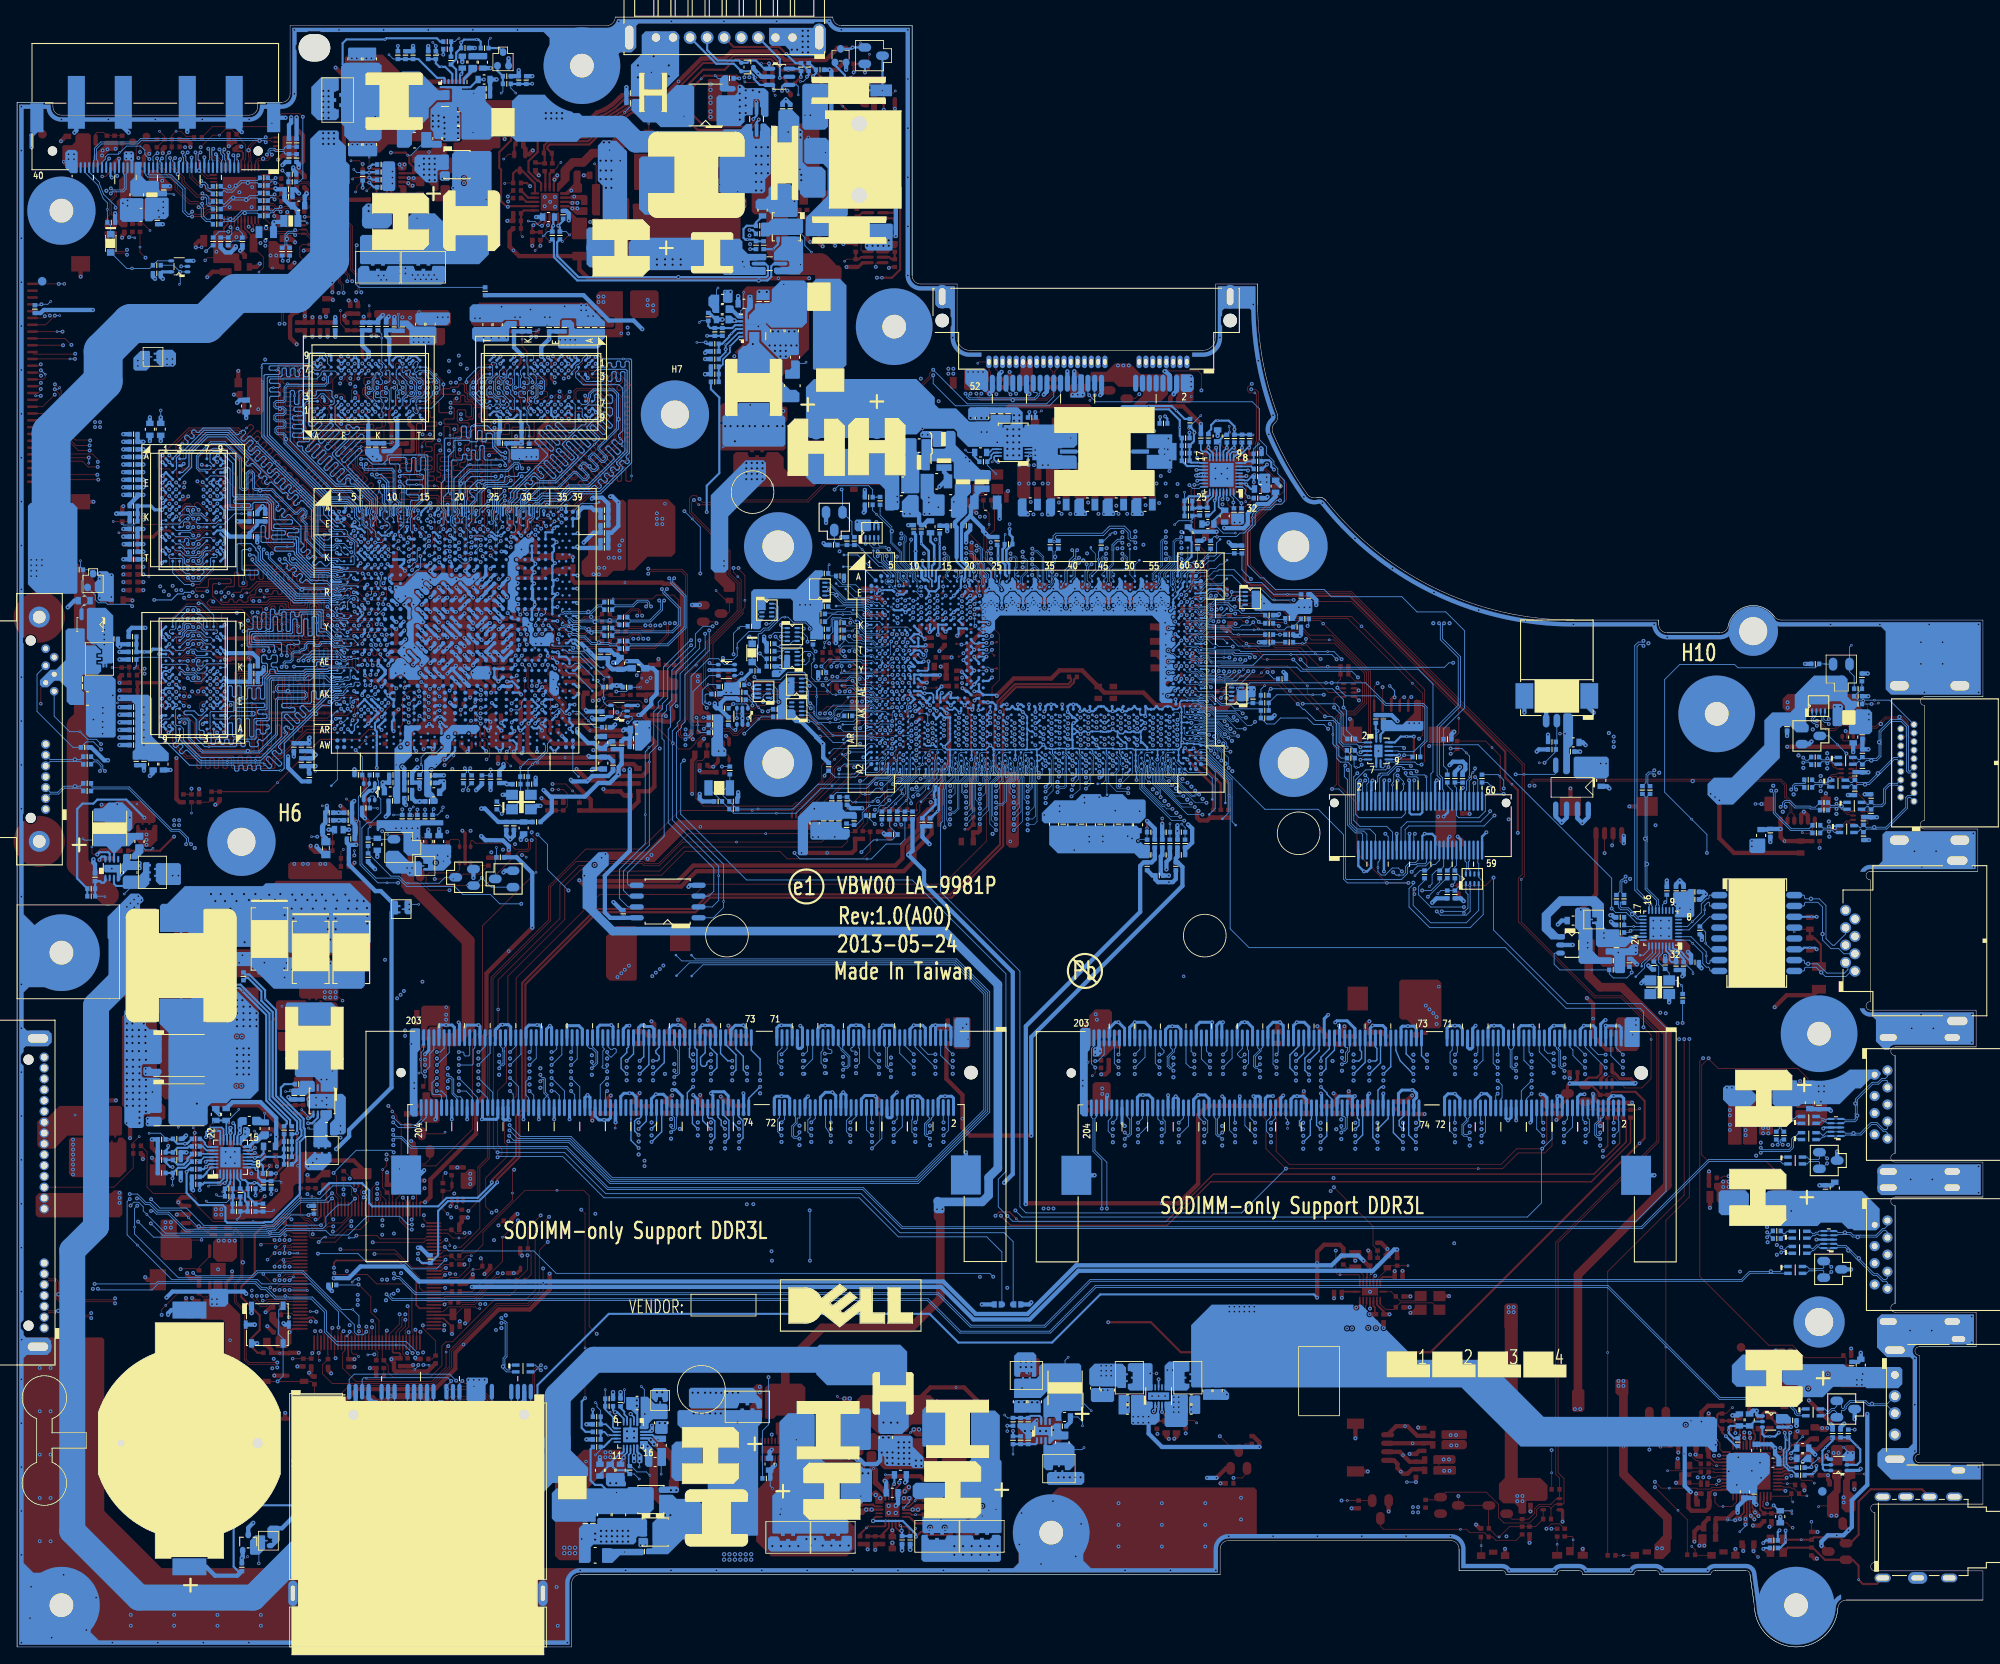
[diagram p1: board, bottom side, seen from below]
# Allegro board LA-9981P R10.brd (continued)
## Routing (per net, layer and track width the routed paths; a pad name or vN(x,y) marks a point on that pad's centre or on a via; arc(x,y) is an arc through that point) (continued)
MAB14: length 51.7
  TOP w0.102: v1(189.24,119.74) 189.84,119.14 191.1,119.14 191.32,119.35 192.33,119.35 192.45,119.23 192.45,118 192.58,117.87 194.39,117.87 ; UV25.T7 208.15,120.15 209.03,121.03 209.93,121.03 v1(210.39,120.57) ; v1(209.12,126.35) 209.57,125.9 210.83,125.9 211.35,126.41 UV22.T7
  TOP w0.127: v1(210.83,123.02) 210.83,123.01 210.58,122.76 208.93,122.76 207.82,121.66 204.06,121.66 202.57,120.17 198.54,120.17 198.41,120.04 198.41,118.43 198.29,118.31 198.03,118.31 197.9,118.43 197.9,120.04 197.78,120.17 197.52,120.17 197.4,120.04 v2(197.4,119.65) 197.4,118 197.27,117.87 194.39,117.87
  IN1 w0.102: 210.97,124.36 210.97,126.3 210.55,126.73 209.5,126.73 v1(209.12,126.35) ; v1(210.39,120.57) 210.8,120.57 210.9,120.67 210.9,120.82 210.8,120.92 210.68,120.92 210.58,121.02 210.58,121.2 210.68,121.3 210.87,121.3 210.97,121.4 210.97,121.9 210.87,122 210.49,122 210.39,122.1 210.39,122.28 210.49,122.38 210.8,122.38 210.97,122.56
  IN1 w0.14: 210.97,124.36 210.97,124.36 210.71,124.1 210.71,123.14 v1(210.83,123.02) 210.97,122.88 210.97,122.56
  BOTTOM w0.102: UV24.T7 211.59,119.39 211.59,119.26 211.47,119.14 211.32,119.14 210.97,119.49 210.97,119.99 v1(210.39,120.57) ; v1(209.12,126.35) 208.17,127.3 UV23.T7 ; v1(189.24,119.74) 189.24,120.12 UV1.W8
MCT0: length 3.4
  TOP w0.254: RL19.1 19.55,85.55 v1(19.49,85.61)
  BOTTOM w0.254: TL1.14 v2(20.07,85.61) v1(19.49,85.61)
MCT1: length 3.6
  TOP w0.254: RL20.1 19.55,81.74 v1(19.49,81.8)
  BOTTOM w0.254: TL1.11 21.17,81.8 20.98,81.98 v2(20.3,81.98) 19.67,81.98 v1(19.49,81.8)
MDA0: length 34.3
  TOP w0.102: 165.88,134.19 166.06,134.37 166.24,134.37 167.07,133.54 167.07,133.36 166.59,132.88 v1(166.59,132.66)
  TOP w0.127: 165.88,134.19 165.47,133.78 165.21,133.78 161.96,137.02 161.96,137.2 162.24,137.48 162.24,137.66 162.06,137.84 161.88,137.84 161.35,137.31 161.17,137.31 160.99,137.49 160.99,137.67 161.96,138.64 161.96,138.82 161.78,139 161.6,139 160.66,138.06 160.48,138.06 160.3,138.24 160.3,138.42 161.24,139.36 161.24,139.54 161.06,139.72 160.88,139.72 159.94,138.78 159.76,138.78 159.52,139.02 159.52,139.2 160.46,140.14 160.46,140.32 160.17,140.61 159.99,140.61 159.26,139.88 159.08,139.88 158.9,140.06 158.9,140.24 v2(159.49,140.83) 159.63,140.97 159.63,141.15 159.44,141.34 159.44,146.49 162.21,149.25 UV18.A7
  BOTTOM w0.102: v1(166.59,132.66) 166.22,132.29 UV1.C37
MDA1: length 34.8
  TOP w0.102: UV18.C8 164.16,150.48 164.16,151.03 163.56,151.64 162.19,151.64 161.62,151.07 ; 164.11,134.14 166.42,131.84 v1(166.59,131.84)
  TOP w0.127: 161.62,151.07 158.38,147.83 v2(158.38,137.3) 158.38,136.8 158.51,136.67 158.92,136.67 159.05,136.8 159.05,138.19 159.17,138.32 159.43,138.32 159.55,138.19 159.55,136.8 159.68,136.67 159.93,136.67 160.06,136.8 160.06,137.18 160.19,137.3 160.44,137.3 160.57,137.18 160.57,136.54 160.7,136.41 161.84,136.41 164.11,134.14
  BOTTOM w0.127: v1(166.59,131.84) 166.97,132.22 166.97,132.3 UV1.C35
MDA2: length 34.6
  TOP w0.102: 161.85,149.26 162.26,149.67 163.23,149.67 163.62,150.05 UV18.B8 ; v1(166.59,133.42) 166.41,133.24 165.38,133.24 164.11,134.51
  TOP w0.127: 161.85,149.26 161.36,148.77 161.18,148.77 160.62,149.33 160.44,149.33 160.26,149.15 160.26,148.97 160.82,148.41 160.82,148.23 160.64,148.05 160.46,148.05 159.8,148.7 159.62,148.7 159.44,148.52 159.44,148.34 160.1,147.69 160.1,147.51 159.92,147.33 159.74,147.33 159.08,147.99 158.9,147.99 158.72,147.81 158.72,147.63 159.38,146.97 159.38,146.79 159.17,146.57 158.77,146.57 158.64,146.45 158.64,146.04 158.77,145.91 159.06,145.91 159.18,145.79 159.18,145.53 159.06,145.41 158.77,145.41 158.64,145.28 158.64,145.03 158.77,144.9 159.06,144.9 159.18,144.77 159.18,144.52 159.06,144.39 158.77,144.39 158.64,144.26 158.64,144.01 158.77,143.88 159.06,143.88 159.18,143.76 159.18,143.5 159.06,143.37 158.77,143.37 158.64,143.25 158.64,142.99 158.77,142.87 159.06,142.87 159.18,142.74 159.18,142.49 159.06,142.36 158.77,142.36 158.64,142.23 158.64,141.98 158.77,141.85 159.06,141.85 159.18,141.72 159.18,141.47 159.06,141.34 158.77,141.34 158.64,141.22 158.64,139.47 v2(159.15,138.96) 161.37,136.74 161.88,136.74 164.11,134.51
  BOTTOM w0.102: v1(166.59,133.42) 166.92,133.09 UV1.A35
MDA3: length 35.6
  TOP w0.102: 166.92,134.22 167.27,133.87 167.27,133.08 167.15,132.96 167.1,132.96 166.97,132.83 166.97,132.1 167.1,131.97 v1(167.41,131.97) ; UV18.D7 165.06,149.58 163.53,149.58 163.4,149.46 163.4,149.21 162.99,148.8 162.12,148.8 161.62,148.3
  TOP w0.127: 166.92,134.22 166.92,134.22 165.87,135.28 165.69,135.28 165.01,134.6 164.83,134.6 164.65,134.78 164.65,134.96 165.08,135.39 165.34,135.64 165.34,135.82 165.16,136 164.98,136 164.29,135.32 164.12,135.32 163.94,135.5 163.94,135.68 164.61,136.35 164.61,136.53 164.43,136.71 164.25,136.71 163.58,136.04 163.4,136.04 163.22,136.22 163.22,136.4 163.92,137.1 163.92,137.28 163.74,137.46 163.56,137.46 162.86,136.75 162.68,136.75 162.5,136.94 162.5,137.11 163.18,137.8 163.18,137.98 163,138.16 162.82,138.16 162.55,137.89 162.37,137.89 162.19,138.07 162.19,138.25 162.46,138.51 162.46,138.69 v2(161.62,139.53) 159.7,141.44 159.7,146.38 161.62,148.3
  BOTTOM w0.127: UV1.E34 167.41,131.94 v1(167.41,131.97)
MDA4: length 36.4
  TOP w0.102: v1(169.66,130.4) 169.89,130.4 170.14,130.64 170.14,133.49 169.95,133.67 169.95,134.07 170.08,134.19 170.83,134.19 170.89,134.13 170.89,133.68 171.02,133.56 171.21,133.56 171.34,133.68 171.34,134.07 171.46,134.19 171.99,134.19 ; UV18.A2 162.87,145.14 162.4,145.14 162.19,144.93 162.19,144.6 163.31,143.49 163.72,143.49
  TOP w0.127: 171.99,134.19 172.71,134.19 172.84,134.32 172.84,134.64 172.71,134.76 172.29,134.76 172.16,134.89 172.16,135.2 172.29,135.32 172.67,135.32 172.8,135.45 172.8,135.7 172.67,135.83 172.29,135.83 172.16,135.96 172.16,136.58 172.12,136.63 172.12,137.68 172.23,137.79 172.23,139.78 172.1,139.91 171.65,139.91 171.53,139.78 v2(171.53,139.34) 171.53,138.89 171.4,138.76 168.27,138.76 167.84,139.19 167.84,140.56 167.97,140.68 167.97,141.65 168.1,141.78 168.54,141.78 168.67,141.9 168.67,142.16 168.54,142.29 168.1,142.29 167.97,142.41 167.97,143.27 167.76,143.49 165.11,143.49 164.99,143.62 164.99,144.73 164.86,144.86 164.29,144.86 164.16,144.73 164.16,144.29 163.91,144.03 163.91,143.68 163.72,143.49
  BOTTOM w0.102: v1(169.66,130.4) 169.26,130 UV1.G32
MDA5: length 35.6
  TOP w0.102: 169.18,135.39 169.18,132.41 169.05,132.29 167.97,132.29 167.84,132.16 167.84,131.08 167.97,130.95 168.26,130.95 168.39,131.08 v1(168.39,131.41) ; UV18.C3 164.91,146.38 164.91,147.12 164.68,147.35 162.75,147.35 161.56,146.16
  TOP w0.127: 161.56,146.16 161.17,145.77 161.17,144.28 163.02,142.43 163.2,142.43 163.5,142.73 163.68,142.73 163.86,142.55 163.86,142.37 163.56,142.07 163.56,141.89 163.74,141.71 163.92,141.71 164.99,142.78 165.17,142.78 165.35,142.6 165.35,142.43 164.28,141.35 164.28,141.17 164.46,140.99 164.64,140.99 165.45,141.8 165.63,141.8 165.81,141.62 165.81,141.45 165,140.63 165,140.45 165.18,140.27 165.36,140.27 166.01,140.93 166.19,140.93 166.37,140.75 166.37,140.57 165.72,139.91 165.72,139.73 165.9,139.55 167.19,138.26 v2(167.46,138.26) 167.68,138.26 169.18,136.76 169.18,135.39
  BOTTOM w0.102: v1(168.39,131.41) 168.66,131.68 UV1.D33
MDA6: length 36
  TOP w0.102: v1(169.64,131.01) 169.81,131.01 169.93,131.14 169.93,131.33 169.81,131.46 169.32,131.46 169.19,131.59 169.19,131.75 169.32,131.88 169.51,131.88 ; UV18.C2 164.22,145.62 162.83,145.62 162.57,145.37 162.34,145.37 161.81,144.84 161.81,144.62 163.16,143.27 167.65,143.27 167.71,143.21 167.71,142.86
  TOP w0.127: 167.71,142.86 167.71,140.79 167.58,140.67 167.58,139.09 168.17,138.51 169.64,138.51 169.77,138.38 169.77,137.39 169.9,137.27 170.72,137.27 170.85,137.14 170.85,136.89 170.72,136.76 169.9,136.76 169.77,136.63 169.77,136.38 169.9,136.25 171.73,136.25 171.86,136.12 171.86,135.87 171.73,135.74 169.82,135.74 169.7,135.62 169.7,135.36 169.82,135.23 v2(170.38,135.23) 171.77,135.23 171.9,135.11 171.9,134.85 171.77,134.73 169.78,134.73 169.65,134.6 169.65,133.67 169.92,133.4 169.92,132.01 169.79,131.88 169.51,131.88
  BOTTOM w0.102: UV1.F32 169.32,130.69 v1(169.64,131.01)
MDA7: length 35.7
  TOP w0.102: UV18.A3 162.99,145.95 163.11,145.83 163.35,145.83 163.43,145.91 163.43,147.02 163.31,147.15 162.95,147.15 162.83,147.02 162.83,146.64 162.7,146.51 162.2,146.51 162.07,146.38 162.07,146.13 162.2,146 162.49,146 162.62,145.88 162.62,145.7 162.49,145.57 161.76,145.57 ; 162.86,143.06 167.15,143.06 ; 169.44,135.39 169.44,132.21 169.31,132.08 168.92,132.08 168.8,131.96 168.8,131.29 v1(168.97,131.12)
  TOP w0.127: 161.76,145.57 161.49,145.3 161.49,144.42 162.86,143.06 ; 167.15,143.06 167.27,143.06 167.4,142.93 167.4,142.61 167.27,142.48 165.83,142.48 165.7,142.35 165.7,142.1 165.83,141.97 167.33,141.97 167.45,141.85 167.45,141.59 167.33,141.47 166.52,141.47 166.4,141.34 166.4,141.08 166.52,140.96 167.2,140.96 167.33,140.83 167.33,140.25 167.2,140.12 v2(166.64,140.12) 166.29,140.12 166.16,139.99 166.16,139.74 166.29,139.61 167.08,139.61 167.21,139.49 167.21,139.1 168.06,138.25 169.38,138.25 169.51,138.12 169.51,137.81 169.38,137.68 169.11,137.68 168.99,137.56 168.99,137.32 169.11,137.19 169.31,137.19 169.44,137.06 169.44,135.39
  BOTTOM w0.102: UV1.E32 169.35,131.49 v1(168.97,131.12)
MDA8: length 35.4
  BOTTOM w0.102: 168.93,134 169.51,134 169.77,133.74 169.77,132.96 169.75,132.95 169.75,132.4 UV1.D31 ; 161.81,150.05 162.99,150.05 UV19.A2
  BOTTOM w0.127: 161.81,150.05 161.28,150.05 161.22,150.12 161.22,150.45 161.09,150.58 160.84,150.58 160.71,150.45 160.71,150.18 160.58,150.05 160.29,150.05 160.16,150.18 160.16,150.63 160.04,150.76 159.78,150.76 159.65,150.63 159.65,150.18 159.53,150.05 159.27,150.05 159.15,150.18 159.15,150.63 159.02,150.76 158.77,150.76 158.64,150.63 158.64,140 159.01,139.63 159.01,139.45 158.83,139.27 ; 158.83,139.27 v2(158.83,139.27) ; 158.83,139.27 158.66,139.1 158.66,138.92 158.84,138.74 159.02,138.74 159.37,139.09 159.55,139.09 159.76,138.88 159.76,138.7 159.4,138.33 159.4,138.18 162.11,135.47 165.45,135.47 166.59,134.33 168.6,134.33 168.93,134
MDA9: length 36.1
  BOTTOM w0.102: 161.62,149.8 162.45,149.8 UV19.A3 ; UV1.F30 170.86,130.99 170.59,131.27 170.59,132.04 170.34,132.29 170.18,132.29 169.95,132.52 169.95,132.86 169.97,132.88 169.97,133.91 169.67,134.21 169.26,134.21 168.83,134.64 166.65,134.64 165.9,135.39
  BOTTOM w0.127: 165.9,135.39 165.56,135.73 163.28,135.73 162.83,136.18 162.65,136.18 162.29,135.83 162.11,135.83 161.93,136.01 161.93,136.19 162.29,136.54 162.29,136.72 162.11,136.9 161.93,136.9 161.57,136.55 161.4,136.55 161.22,136.73 161.22,136.91 161.57,137.26 161.57,137.44 161.39,137.62 161.21,137.62 160.86,137.27 160.68,137.27 160.5,137.45 160.5,137.63 v2(160.67,137.8) 160.85,137.98 160.85,138.16 160.67,138.34 160.49,138.34 160.14,137.99 159.96,137.99 159.78,138.17 159.78,138.34 160.13,138.7 160.13,138.88 158.9,140.11 158.9,149.62 159.07,149.8 161.62,149.8
MDA10: length 35.4
  BOTTOM w0.102: UV1.C30 170.75,132.6 170.75,134.07 ; UV19.C3 164.59,149.24 163.73,148.38 162.95,148.38
  BOTTOM w0.127: 170.75,134.07 170.41,134.42 169.41,134.42 168.88,134.95 166.7,134.95 165.67,135.99 163.39,135.99 159.16,140.22 159.16,149.41 159.28,149.54 159.54,149.54 159.66,149.41 159.66,148.5 159.79,148.38 160.05,148.38 160.17,148.5 v2(160.17,148.8) 160.17,149.41 160.3,149.54 160.55,149.54 160.68,149.41 160.68,148.5 160.81,148.38 161.06,148.38 161.19,148.5 161.19,149.05 161.32,149.18 161.57,149.18 161.7,149.05 161.7,148.5 161.82,148.38 162.95,148.38
MDA11: length 35.2
  BOTTOM w0.102: 162.15,148 164.07,148 164.92,148.85 164.92,149.43 164.59,149.77 UV19.C2
  BOTTOM w0.127: 162.15,148 159.85,148 159.42,147.56 159.42,142.6 159.91,142.11 159.91,141.87 v2(159.72,141.69) 159.42,141.39 159.42,141.21 159.6,141.03 159.77,141.03 160.29,141.54 160.47,141.54 160.66,141.35 160.66,141.17 159.71,140.21 159.71,140.04 159.9,139.84 160.08,139.84 161.04,140.8 161.22,140.8 161.4,140.62 161.4,140.44 160.45,139.5 160.45,139.29 163.5,136.24 165.77,136.24 166.75,135.27 168.93,135.27 169.55,134.65 170.5,134.65 170.98,134.17 170.98,133.17 UV1.A30
MDA12: length 36.8
  BOTTOM w0.102: UV1.F28 172.11,130.69 171.97,130.83 171.97,131.4 172.18,131.61 172.18,133.89 171.64,134.43
  BOTTOM w0.127: 171.64,134.43 171.4,134.67 171.4,135.02 171.22,135.19 170.88,135.19 169.59,136.48 167.25,136.48 v2(162.72,141.01) 162.13,141.6 162.13,141.8 163.22,142.89 163.22,143.07 163.03,143.27 162.85,143.27 161.74,142.16 161.56,142.16 161.37,142.36 161.37,142.54 161.69,142.86 162.3,143.47 162.3,143.67 162.12,143.85 161.94,143.85 161.62,143.53 161,142.91 160.82,142.91 160.64,143.09 160.64,143.27 161.81,144.43 161.81,144.61 161.62,144.79 161.45,144.79 160.98,144.33 160.81,144.33 160.62,144.51 160.62,145.17 160.75,145.3 161.56,145.3 161.69,145.43 161.69,145.68 161.56,145.81 160.75,145.81 160.62,145.94 160.62,146.66 160.75,146.79 161.24,146.79 161.37,146.66 161.37,146.44 161.49,146.32 162,146.32 162.13,146.44 162.13,146.77 162.26,146.89 162.57,146.89 162.7,146.77 162.7,146.18 162.83,146.05 UV19.A7
MDA13: length 35.9
  BOTTOM w0.102: UV1.C28 172.66,132.66 172.97,132.96 172.97,133.22 172.66,133.53 172.66,134.23 172.18,134.71 ; UV19.C8 164.29,145.25 164.16,145.13 164.16,144.28 163.72,143.83 163.72,143.4 163.84,143.27 164.27,143.27
  BOTTOM w0.127: 172.18,134.71 172.18,135.36 169.88,137.66 169.7,137.66 169.05,137 168.87,137 168.69,137.18 168.69,137.36 v2(169.04,137.71) 169.34,138.02 169.34,138.19 169.16,138.37 168.99,138.37 167.63,137.02 167.45,137.02 167.27,137.2 167.27,137.37 168.63,138.73 168.63,138.91 168.45,139.09 168.27,139.09 166.91,137.73 166.73,137.73 166.55,137.91 166.55,138.09 167.91,139.45 167.91,139.63 167.73,139.81 167.55,139.81 166.21,138.48 166.03,138.48 165.85,138.66 165.85,138.84 167.19,140.17 167.19,140.35 167.01,140.53 166.83,140.53 165.47,139.17 165.29,139.17 165.11,139.35 165.11,139.53 166.47,140.89 166.47,141.07 164.27,143.27
MDA14: length 35.6
  BOTTOM w0.102: 162.79,145.62 163.42,145.62 UV19.B8
  BOTTOM w0.127: UV1.A28 172.44,133.31 172.44,134.12 171.8,134.77 171.8,135.38 171.41,135.76 171.23,135.76 171.05,135.57 170.87,135.57 170.69,135.75 170.69,135.93 170.88,136.12 170.88,136.3 170.7,136.48 170.52,136.48 170.33,136.29 170.15,136.29 169.97,136.47 169.97,136.65 170.16,136.84 170.16,137.02 169.94,137.24 169.65,137.24 169.15,136.74 167.36,136.74 164.65,139.44 164.65,139.62 v2(165.63,140.6) 166.01,140.98 166.01,141.16 165.83,141.34 165.65,141.34 164.29,139.98 164.11,139.98 163.93,140.16 163.93,140.34 165.29,141.7 165.29,141.88 165.11,142.06 164.93,142.06 163.57,140.7 163.4,140.7 163.22,140.88 163.22,141.06 164.57,142.42 164.57,142.6 164.4,142.78 164.22,142.78 162.86,141.42 162.68,141.42 162.5,141.6 162.5,141.78 163.61,142.89 163.61,143.07 162.58,144.1 162.26,144.1 162.13,144.22 162.13,145.5 162.26,145.62 162.79,145.62
MDA15: length 36.1
  BOTTOM w0.102: 164.99,142.92 164.99,145.65 UV19.D7 ; UV1.E28 172.97,131.8 172.97,132.65 173.17,132.85 173.17,133.3 172.86,133.61 172.86,134.33 172.56,134.63 172.56,134.69
  BOTTOM w0.127: 164.99,142.92 165.54,142.37 165.72,142.37 166.21,142.86 166.95,143.6 167.13,143.6 167.31,143.42 167.31,143.24 166.93,142.86 166.08,142.01 166.08,141.83 166.26,141.65 166.44,141.65 167.65,142.86 168.02,143.23 168.2,143.23 168.38,143.05 168.38,142.87 166.8,141.29 166.8,141.11 166.98,140.93 167.16,140.93 168.87,142.64 169.05,142.64 169.23,142.46 169.23,142.28 167.52,140.57 167.52,140.39 167.69,140.21 167.87,140.21 169.33,141.67 169.51,141.67 169.69,141.49 169.69,141.31 v2(169.19,140.81) 168.23,139.85 168.23,139.67 172.56,135.35 172.56,134.69
MDA16: length 36
  IN1 w0.102: 162.22,142.86 162.22,143.76 162.19,143.78 162.19,148.13 164.92,150.85 166.96,150.85 v1(167.35,150.46)
  IN1 w0.14: 162.22,142.86 162.22,137.17 164.63,134.75 168.53,134.75 171.18,132.1 172.67,132.1 172.85,132.27 172.85,134.04 v1(173.23,134.42)
  BOTTOM w0.102: v1(173.23,134.42) 173.75,133.89 173.75,132.83 173.77,132.82 173.77,132.56 173.76,132.56 173.76,132.19 UV1.D27 ; v1(167.35,150.46) 167.76,150.05 UV19.G2
MDA17: length 36.5
  IN1 w0.102: 161.87,142.86 161.87,148.23 164.03,150.38 164.03,150.96 164.82,151.74 166.73,151.74 167.08,151.39 167.08,151.28 167.82,150.54 167.82,150.34 168.11,150.05 168.55,150.05 v1(168.95,149.65)
  IN1 w0.14: 161.87,142.86 161.87,137.02 164.49,134.41 168.38,134.41 171.01,131.78 173.06,131.78 v1(173.51,131.33)
  BOTTOM w0.102: UV19.H3 168.59,149.29 v1(168.95,149.65) ; UV1.F26 174.06,130.78 v1(173.51,131.33)
MDA18: length 36.2
  IN1 w0.102: 162.56,142.86 162.56,144.05 162.96,144.44 162.96,145.23 162.85,145.33 162.64,145.33 162.54,145.43 162.54,145.63 162.64,145.73 163.28,145.73 163.38,145.84 163.38,146.04 163.28,146.14 162.64,146.14 162.54,146.24 162.54,146.45 162.64,146.55 163.28,146.55 163.38,146.65 163.38,146.85 163.28,146.95 162.64,146.95 162.54,147.06 162.54,147.26 162.64,147.36 162.85,147.36 162.96,147.46 162.96,147.58 165.04,149.66 v1(165.76,149.66)
  IN1 w0.14: v1(173.24,134.98) 172.62,134.98 172.49,134.85 172.49,134.27 172.37,134.14 171.5,134.14 171.37,134.01 171.37,133.01 171.25,132.88 170.94,132.88 170.82,133.01 170.82,134.08 170.69,134.21 169.64,134.21 168.73,135.12 164.75,135.12 162.56,137.31 162.56,142.86
  BOTTOM w0.102: v1(165.76,149.66) 166.17,149.25 UV19.E3 ; UV1.C26 174.26,132.59 173.96,132.9 173.96,134.26 v1(173.24,134.98)
MDA19: length 35.7
  IN1 w0.102: 162.9,142.86 162.9,143.02 163.79,143.91 163.79,146.21 163.89,146.31 164.38,146.31 164.48,146.41 164.48,147.14 164.38,147.24 163.94,147.24 163.82,147.37 163.82,147.58 163.94,147.71 164.34,147.71 164.49,147.85 164.49,148 164.21,148.27 164.21,148.42 164.35,148.56 164.5,148.56 164.77,148.28 164.92,148.28 165.06,148.43 165.06,148.57 164.79,148.85 164.79,148.99 165.04,149.24 166.14,149.24 v1(166.56,149.66)
  IN1 w0.14: v1(173.27,135.56) 172.27,135.56 172.13,135.42 172.13,134.71 172,134.59 171.7,134.59 171.57,134.71 171.57,135.42 171.43,135.56 171.15,135.56 171.01,135.42 171.01,134.78 170.89,134.65 170.58,134.65 170.45,134.78 170.45,135.42 170.31,135.56 170.03,135.56 169.89,135.42 169.89,134.99 169.77,134.87 169.46,134.87 169.34,134.99 169.34,135.42 169.2,135.56 164.79,135.56 162.9,137.45 162.9,142.86
  BOTTOM w0.102: v1(166.56,149.66) 166.96,150.05 UV19.F2
  BOTTOM w0.127: v1(173.27,135.56) 174.19,134.64 174.19,133.16 UV1.A26
MDA20: length 36.7
  IN1 w0.14: v1(168.23,144.82) 168.23,142.98 168.35,142.86 168.53,142.86 168.66,142.73 168.66,139.74 168.78,139.61 169.04,139.61 169.16,139.74 169.16,143.22 169.29,143.35 169.57,143.35 169.7,143.22 169.7,140.08 169.82,139.95 170.17,139.95 170.29,140.08 170.29,141.46 170.42,141.58 170.71,141.58 170.84,141.46 170.84,139.99 171.51,139.32 172.14,139.32 172.26,139.45 172.26,139.72 172.14,139.84 171.59,139.84 171.46,139.97 171.46,140.29 171.59,140.42 172.63,140.42 172.75,140.29 172.75,139.1 172.88,138.97 173.5,138.97 173.62,139.1 173.62,139.26 173.75,139.38 174.09,139.38 174.21,139.26 174.21,138.56 174.34,138.44 175.05,138.44 176.75,136.74 176.75,133.98 176.17,133.41 176.17,132.81 175.57,132.2 175.57,131.62 v1(176.12,131.07)
  BOTTOM w0.102: v1(168.23,144.82) 168.59,145.18 UV19.H8 ; v1(176.12,131.07) 175.74,130.69 UV1.F24
MDA21: length 36.1
  IN1 w0.102: 169.41,144.63 169.41,145.22 v1(168.96,145.66)
  IN1 w0.14: v1(176.18,131.9) 178.03,131.9 178.16,132.03 178.16,132.35 178.03,132.48 177.22,132.48 177.09,132.6 177.09,133.04 177.22,133.17 177.79,133.17 177.91,133.3 177.91,133.6 177.79,133.73 177.22,133.73 177.09,133.86 177.09,134.16 177.22,134.29 178.31,134.29 178.44,134.41 178.44,134.72 178.31,134.85 177.22,134.85 177.09,134.97 177.09,135.28 177.22,135.41 178.33,135.41 178.46,135.53 178.46,135.84 178.33,135.96 177.22,135.96 177.09,136.09 177.09,136.4 177.22,136.52 178.25,136.52 178.37,136.65 178.37,136.95 178.25,137.08 176.89,137.08 176.77,137.21 176.77,137.41 177.35,137.99 177.35,138.19 177.15,138.39 176.95,138.39 176.37,137.8 176.17,137.8 175.97,138 175.97,138.2 176.56,138.78 176.56,138.98 176.36,139.18 176.16,139.18 175.58,138.59 175.38,138.59 173.11,140.86 171.55,140.86 171.4,141.01 171.4,142.42 171.27,142.55 170.83,142.55 170.7,142.42 170.7,142.05 170.57,141.93 170.17,141.93 170.04,142.05 170.04,144 169.41,144.63
  BOTTOM w0.102: UV19.H7 168.59,146.04 v1(168.96,145.66) ; v1(176.18,131.9) 175.86,132.22 UV1.C24
MDA22: length 35.8
  IN1 w0.102: v1(166.64,145.66) 166.83,145.66 166.95,145.53 166.95,142.86
  IN1 w0.14: v1(175.17,133.78) 175.86,133.78 176.06,133.98 176.06,136.46 174.77,137.75 172.89,137.75 172.64,138 172.63,138 172.03,138.61 170.15,138.61 170.03,138.48 170.03,138.24 169.89,138.1 169.61,138.1 169.47,138.24 169.47,138.48 169.34,138.61 169.03,138.61 168.91,138.48 168.91,138.24 168.77,138.1 168.49,138.1 168.35,138.24 168.35,138.48 168.22,138.61 167.92,138.61 167.79,138.48 167.79,137.33 167.66,137.21 166.6,137.21 166.47,137.35 166.47,137.82 166.33,137.96 166.05,137.96 165.91,137.82 165.91,137.35 165.77,137.21 165.53,137.21 164.55,138.18 164.55,139.78 164.68,139.91 165.05,139.91 165.19,139.77 165.19,138.64 165.31,138.51 165.62,138.51 165.75,138.64 165.75,139.77 165.89,139.91 166.83,139.91 166.95,140.04 166.95,140.3 166.83,140.43 166.08,140.43 165.95,140.56 165.95,140.81 166.08,140.93 166.83,140.93 166.95,141.06 166.95,142.86
  BOTTOM w0.102: v1(175.17,133.78) 175.86,133.09 UV1.A24 ; UV19.F7 166.99,146.01 v1(166.64,145.66)
MDA23: length 36.5
  IN1 w0.102: v1(167.34,144.83) 167.72,144.83 167.84,144.7 167.84,143.7 167.3,143.16 167.3,142.86
  IN1 w0.14: v1(175.23,131) 175.23,132.42 175.72,132.91 175.72,133.29 176.4,133.98 176.4,136.6 174.91,138.09 173.03,138.09 172.17,138.95 168.44,138.95 168.31,139.08 168.31,142.18 168.19,142.31 167.92,142.31 167.79,142.18 167.79,139.32 167.63,139.16 166.76,139.16 166.65,139.05 166.65,138.82 166.78,138.69 167.25,138.69 167.37,138.56 167.37,137.68 167.25,137.55 166.94,137.55 166.81,137.68 166.81,138.18 166.68,138.31 166.22,138.31 166.09,138.43 166.09,139.44 166.22,139.57 167.17,139.57 167.3,139.69 167.3,142.86
  BOTTOM w0.102: v1(175.23,131) 175.72,131.49 UV1.E24 ; v1(167.34,144.83) 166.99,145.18 UV19.F8
MDA24: length 37.1
  TOP w0.102: UV18.H8 168.59,150.11 v1(168.25,150.45)
  IN3 w0.102: v1(168.25,150.45) 167.84,150.85 165.65,150.85 164.99,150.19 164.99,149.73 164.65,149.39 164.65,149.37 161.64,146.36 161.62,146.36
  IN3 w0.157: 161.62,146.36 161.53,146.27 161.53,139.53 164.32,136.74 169.76,136.74 170.59,135.91 171.67,135.91 v1(172.54,136.77)
  BOTTOM w0.102: UV1.C22 177.46,132.66 177.16,132.96 177.16,133.65 177.1,133.7 177.1,133.84 176.51,134.43 176.51,135.18 176.31,135.39
  BOTTOM w0.127: v1(172.54,136.77) 173.03,136.28 175.41,136.28 176.31,135.39
MDA25: length 36.7
  TOP w0.102: UV18.H7 168.59,149.26 v1(168.19,149.66)
  IN3 w0.102: 164.29,142.86 164.29,143.21 164.03,143.46 164.03,146.32 164.19,146.48 164.19,147.5 164.95,148.25 166.9,148.25 167.02,148.12 167.02,148.02 167.21,147.84 167.21,147.09 167.34,146.96 167.7,146.96 167.83,147.09 167.83,149 167.96,149.13 168.46,149.13 168.58,149.25 168.58,149.53 168.46,149.66 v1(168.19,149.66)
  IN3 w0.157: 164.29,142.86 164.29,138.82 164.92,138.19 v1(170.45,138.19)
  BOTTOM w0.127: v1(170.45,138.19) 170.45,137.94 170.7,137.69 171.53,137.69 171.66,137.56 171.66,137.37 171.78,137.24 v2(172.73,137.24) 173.11,137.24 173.24,137.11 173.24,136.67 173.37,136.54 175.52,136.54 175.71,136.35 175.97,136.35 176.16,136.54 176.35,136.54 176.59,136.29 176.59,136.11 176.43,135.95 176.43,135.77 176.61,135.59 176.79,135.59 176.95,135.75 177.13,135.75 177.36,135.52 177.36,135.34 176.73,134.71 176.73,134.52 177.46,133.79 UV1.A22
MDA26: length 38.1
  TOP w0.102: v1(166.56,150.46) 166.97,150.05 UV18.F8
  IN3 w0.102: 161.9,142.86 161.9,146.25 164.99,149.34 164.99,149.43 165.63,150.07 166.17,150.07 v1(166.56,150.46)
  IN3 w0.157: 161.9,142.86 161.9,139.68 164.47,137.1 169.91,137.1 170.66,136.35 171.46,136.35 172.1,136.99 172.1,137.18 172.5,137.58 172.87,137.58 172.97,137.48 172.97,137.02 173.07,136.92 173.52,136.92 173.62,137.02 v1(173.62,137.29)
  BOTTOM w0.102: 177.62,135.39 177.62,134.51 177.71,134.42 177.71,133.48 177.77,133.42 177.77,132.96 177.77,132.96 177.77,132.91 177.75,132.9 177.75,132.48 177.77,132.47 177.77,131.2 UV1.F22
  BOTTOM w0.127: v1(173.62,137.29) 173.62,137.23 174.05,136.8 v2(175.94,136.8) 176.45,136.8 177.62,135.63 177.62,135.39
MDA27: length 37.2
  TOP w0.102: UV18.F7 166.86,149.25 v1(166.32,148.72)
  IN3 w0.102: v1(166.32,148.72) 166.32,149.13 166.19,149.26 165.19,149.26 162.96,147.02 162.96,145.95 162.85,145.85 162.48,145.85 162.38,145.75 162.38,145.54 162.48,145.44 162.85,145.44 162.96,145.34 162.96,144.29
  IN3 w0.157: 162.96,144.29 162.96,143.84 162.83,143.72 162.51,143.72 162.26,143.46 162.26,139.83 164.62,137.47 170.06,137.47 170.79,136.73 171.33,136.73 171.68,137.09 171.68,137.4 171.94,137.66 172.07,137.66 172.35,137.94 173.61,137.94 v1(174.32,137.23)
  BOTTOM w0.102: 177.88,135.39 177.88,134.92 177.97,134.83 177.97,132.88 177.97,132.88 177.97,132.83 177.96,132.82 177.96,132.56 178.26,132.26 UV1.D21
  BOTTOM w0.127: v1(174.32,137.23) 177.2,137.23 177.88,136.55 177.88,135.39
MDA28: length 36.9
  TOP w0.102: v1(167.77,146.59) 168.3,146.05 UV18.H3
  IN3 w0.102: 169.41,144.63 169.41,146.26 169.28,146.38 168.67,146.38 168.54,146.51 168.54,148.8 168.42,148.92 168.16,148.92 168.03,148.8 168.03,146.71 167.91,146.59 v1(167.77,146.59)
  IN3 w0.157: v1(173.79,138.52) 173.62,138.69 173.62,141.41 172.67,142.36 172.24,142.36 172.15,142.45 171.91,142.45 171.78,142.57 171.78,144.1 171.65,144.23 171.19,144.23 171.03,144.07 171.03,142.07 170.9,141.94 170.45,141.94 170.32,142.07 170.32,142.83 170.19,142.96 169.81,142.96 169.69,142.83 169.69,142.07 169.56,141.94 169.14,141.94 169.01,142.07 169.01,143.46 169.14,143.59 170.19,143.59 170.32,143.72 170.32,144.32 170.19,144.44 169.59,144.44 169.41,144.63
  BOTTOM w0.127: v1(173.79,138.52) 173.85,138.57 v2(177.57,138.57) 179.2,136.94 179.2,133.82 179.21,133.81 179.21,133.24 UV1.A20
MDA29: length 39.3
  TOP w0.102: v1(165.62,147.17) 165.66,147.17 166.19,146.64 166.19,146.05 UV18.E3
  IN3 w0.102: v1(165.62,147.17) 165.62,147.27 165.49,147.4 165.18,147.4 165.05,147.27 165.05,145.37 165.33,145.09 165.33,143.88 165.6,143.61 165.6,142.86
  IN3 w0.157: v1(173.18,138.55) 172.56,138.55 172,139.1 172,139.94 171.8,140.14 168.83,140.14 168.71,140.27 168.71,140.63 168.58,140.75 167.62,140.75 166.95,141.43 165.73,141.43 165.6,141.56 165.6,142.86
  BOTTOM w0.102: UV1.F20 179.06,131.01 179.56,131.51 179.56,132.01 179.6,132.05 179.6,132.53 179.42,132.71 179.42,133.91
  BOTTOM w0.127: 179.42,133.91 179.42,134.51 179.46,134.54 179.46,139.06 179.35,139.16 178.32,139.16 178.19,139.29 178.19,139.74 178.09,139.84 177.78,139.84 177.68,139.74 177.68,139.29 177.55,139.16 177.3,139.16 177.17,139.29 177.17,140.22 177.07,140.32 176.77,140.32 176.67,140.22 176.67,139.29 176.54,139.16 176.28,139.16 176.16,139.29 v2(176.16,140.35) 176.16,140.76 176.06,140.86 175.75,140.86 175.65,140.76 175.65,139.29 175.52,139.16 173.54,139.16 173.18,138.81 v1(173.18,138.55)
MDA30: length 38.7
  TOP w0.102: UV18.F2 166.96,145.25 v1(166.56,144.86)
  IN3 w0.102: v1(166.56,144.86) 166.5,144.92 166.28,144.92 166.17,144.81 166.17,143.53 166.3,143.4 167.05,143.4 167.18,143.27 167.18,142.96
  IN3 w0.157: v1(173.18,139.4) 173.18,139.25 173.05,139.12 172.49,139.12 172.36,139.25 172.36,140.37 172.24,140.5 171.71,140.5 171.59,140.63 171.59,140.96 171.43,141.11 171.11,141.11 170.96,140.96 170.96,140.66 170.8,140.5 170.48,140.5 170.33,140.66 170.33,140.96 170.17,141.11 169.85,141.11 169.7,140.96 169.7,140.66 169.54,140.5 169.22,140.5 169.07,140.66 169.07,140.96 168.91,141.11 167.77,141.11 167.18,141.71 167.18,141.81 167.02,141.96 166.09,141.96 165.96,142.09 165.96,142.47 166.09,142.59 167.02,142.59 167.18,142.75 167.18,142.96
  BOTTOM w0.102: 180.38,133.96 180.38,133.53 180.15,133.3 180.15,132.88 180.19,132.84 180.19,132.54 180.15,132.5 180.15,132.17 179.87,131.89 UV1.D19
  BOTTOM w0.127: 180.38,133.96 180.42,134 180.42,134.81 179.85,135.39 179.85,139.63 179.21,140.27 v2(179.21,140.73) 179.21,141.37 179.11,141.47 177.41,141.47 177.24,141.3 176.53,141.3 176.43,141.41 176.43,142.54 176.33,142.64 176.02,142.64 175.92,142.54 175.92,141.41 175.82,141.3 175.51,141.3 175.41,141.41 175.41,142.19 175.28,142.32 174.89,142.32 174.66,142.09 174.66,140.65 173.66,139.65 173.43,139.65 v1(173.18,139.4)
MDA31: length 39
  TOP w0.102: UV18.G2 167.77,145.25 v1(167.36,145.66)
  IN3 w0.102: 167.78,144.69 167.78,145.6 167.72,145.66 v1(167.36,145.66)
  IN3 w0.157: 167.78,144.69 167.8,144.67 167.8,144.3 167.92,144.18 168.45,144.18 168.58,144.05 168.58,143.67 168.45,143.55 167.62,143.55 167.49,143.42 167.49,143.04 167.62,142.92 168.53,142.92 168.65,142.79 168.65,142.41 168.53,142.29 167.92,142.29 167.8,142.16 167.8,141.6 167.92,141.47 173.05,141.47 173.18,141.35 v1(173.18,140.04)
  BOTTOM w0.102: 180.66,133.71 180.66,133.52 180.36,133.22 180.36,132.96 180.4,132.92 180.4,132.46 180.36,132.42 180.36,131.64 180.51,131.49 UV1.E18
  BOTTOM w0.127: v1(173.18,140.04) 173.68,140.04 174.4,140.76 174.4,142.32 175.27,143.18 177.11,143.18 177.24,143.06 v2(177.24,142.57) 177.24,141.88 177.36,141.75 177.62,141.75 177.74,141.88 177.74,143.02 177.87,143.15 178.19,143.15 178.32,143.02 178.32,141.86 178.45,141.73 180.16,141.73 180.29,141.6 180.29,136.86 180.66,136.49 180.66,133.71
MDA32: length 35.6
  IN1 w0.102: v1(180.98,131.9) 180.98,132.16 181.13,132.31 181.5,132.31 181.56,132.24 181.56,131.46 181.3,131.2 180.84,131.2 180.59,131.45 179.16,131.45 179.04,131.58 179.04,135.39 ; v1(189.22,145.66) 190.15,146.59 190.15,146.77 189.91,147 189.73,147 188.8,146.07 188.8,144.54 188.67,144.41 188.33,144.41 188.23,144.31 188.23,144.1 188.35,143.97 189.27,143.97 189.4,143.84 189.4,143.65 189.27,143.53 188.42,143.53 188.35,143.45 188.35,142.86
  IN1 w0.14: 179.04,135.39 179.04,136.99 178.59,137.43 178,137.43 177.88,137.55 177.88,138.14 177.56,138.46 177.56,139.34 177.79,139.56 182.32,139.56 185.34,139.56 188.35,142.57 188.35,142.86
  BOTTOM w0.102: UV1.C18 180.66,132.22 v1(180.98,131.9) ; v1(189.22,145.66) 189.58,146.02 UV21.H3
MDA33: length 35.3
  IN1 w0.102: v1(180.98,132.66) 180.72,132.66 180.6,132.54 180.6,131.86 180.47,131.73 180.26,131.73 180.13,131.86 180.13,133.43 180.01,133.55 179.85,133.55 179.73,133.43 179.73,131.86 179.6,131.73 179.37,131.73 179.24,131.86 179.24,134.13 179.38,134.27 179.38,135.39 ; 189.13,142.86 189.13,143.15 189.25,143.27 189.5,143.27 189.6,143.37 189.6,143.63 189.72,143.74 189.89,143.74 190.01,143.63 190.01,143.37 190.11,143.27 190.31,143.27 190.41,143.37 190.41,143.48 190.53,143.6 190.7,143.6 190.82,143.48 190.82,143.37 190.92,143.27 191.08,143.27 191.21,143.4 191.21,144.72 191.08,144.85 v1(190.82,144.85)
  IN1 w0.14: 179.38,135.39 179.38,138.54 179.25,138.66 178.95,138.66 178.81,138.52 178.81,137.9 178.68,137.77 178.38,137.77 178.25,137.9 178.25,138.52 178.11,138.66 178.03,138.66 177.9,138.79 177.9,139.09 178.03,139.22 185.49,139.22 189.13,142.86
  BOTTOM w0.102: v1(180.98,132.66) 180.66,132.98 UV1.A18 ; UV21.G2 190.41,145.25 v1(190.82,144.85)
MDA34: length 36.3
  IN1 w0.102: v1(189.2,149.65) 189.6,150.04 192.96,150.04 193.21,149.79 195.87,149.79 196.3,149.36 196.3,143.36 195.81,142.86 ; 188.33,135.39 187.58,134.64 187.02,134.64 186.62,134.24 185.93,134.24 183.51,131.81 182.86,131.81 182.39,131.33 182.39,131.2 182.01,130.82 180.68,130.82 v1(180.43,131.07)
  IN1 w0.14: 195.81,142.86 193.74,140.79 193.74,140.21 190.1,136.57 189.52,136.57 188.33,135.39
  BOTTOM w0.102: UV21.H7 189.58,149.27 v1(189.2,149.65) ; v1(180.43,131.07) 180.81,130.69 UV1.F18
MDA35: length 36
  IN1 w0.102: 192.96,142.86 193.18,143.08 193.43,143.08 193.56,143.21 193.56,143.43 193.43,143.56 193.31,143.56 193.18,143.68 193.18,144.89 193.31,145.01 193.57,145.01 193.69,145.13 193.69,145.3 193.57,145.42 192.88,145.42 192.76,145.54 192.76,145.71 192.88,145.83 193.57,145.83 193.69,145.94 193.69,146.11 193.57,146.23 192.62,146.23 v1(192.4,146.45) ; v1(181.96,132.67) 182.32,132.67 182.45,132.8 182.45,134.83 182.13,135.14 182.13,135.39
  IN1 w0.14: 192.96,142.86 192.74,142.64 189.87,142.64 185.77,138.54 180.29,138.54 180.16,138.41 180.16,138.1 180.29,137.97 182.12,137.97 182.25,137.84 182.25,137.54 182.12,137.41 180.19,137.41 180.06,137.28 180.06,136.98 180.19,136.85 182.25,136.85 182.37,136.72 182.37,135.83 182.13,135.59 182.13,135.39
  BOTTOM w0.102: v1(192.4,146.45) 192.01,146.05 UV21.E3 ; UV1.D17 181.46,132.17 v1(181.96,132.67)
MDA36: length 35.2
  IN1 w0.102: v1(181.89,133.55) 181.39,133.05 180.61,133.05 180.48,133.18 180.48,134.12 ; v1(191.6,144.85) 192,145.24 192.55,145.24 192.86,144.92 192.86,143.21 192.62,142.96 189.71,142.96 189.61,142.86
  IN1 w0.14: 180.48,134.12 180.42,134.18 180.27,134.18 180.14,134.31 180.14,134.61 180.27,134.74 180.8,134.74 180.92,134.61 180.92,134.26 181.05,134.13 181.43,134.13 181.56,134.26 181.56,135.17 181.43,135.3 179.85,135.3 179.72,135.42 179.72,135.73 179.85,135.86 181.9,135.86 182.03,135.98 182.03,136.38 181.9,136.51 179.88,136.51 179.72,136.67 179.72,138.62 179.98,138.88 185.63,138.88 189.61,142.86
  BOTTOM w0.102: v1(191.6,144.85) 191.2,145.25 UV21.F2 ; UV1.A16 182.26,133.17 v1(181.89,133.55)
MDA37: length 36.4
  IN1 w0.102: v1(190.83,150.48) 191.26,150.91 192.83,150.91 192.86,150.87 194.94,150.87 195.08,151.02 195.93,151.02 196.54,150.41 ; 188.36,134.35 187.18,134.35 184.74,131.91 184.03,131.91 183.32,131.2 v1(182.91,131.2)
  IN1 w0.14: 196.54,150.41 196.65,150.31 196.65,143.24 196.48,143.08 196.48,142.89 196.6,142.77 196.6,142.59 196.34,142.33 196.16,142.33 196.06,142.43 195.86,142.43 195.66,142.23 195.66,142.03 195.76,141.94 195.76,141.74 195.56,141.55 195.36,141.55 195.27,141.64 195.07,141.64 194.87,141.44 194.87,141.24 194.97,141.15 194.97,140.95 194.77,140.76 194.57,140.76 194.48,140.85 194.28,140.85 194.08,140.65 194.08,140.45 194.18,140.36 194.18,140.16 190.03,136.01 189.83,136.01 189.74,136.11 189.54,136.11 189.34,135.91 189.34,135.71 189.43,135.62 189.43,135.42 189.24,135.22 189.04,135.22 188.95,135.31 188.75,135.31 188.55,135.12 188.55,134.92 188.64,134.83 188.64,134.63 188.36,134.35
  BOTTOM w0.102: v1(182.91,131.2) 182.91,131.06 182.54,130.69 UV1.F16 ; v1(190.83,150.48) 191.18,150.13 UV21.F8
MDA38: length 35.9
  IN1 w0.102: v1(183.36,132.31) 184.28,133.23 184.28,133.71 185.08,134.51 186.58,134.51 187.02,134.95 187.42,134.95 187.85,135.39 ; v1(191.53,149.65) 191.95,149.23 195.73,149.23 195.96,149 195.96,143.5 195.32,142.86
  IN1 w0.14: 195.32,142.86 193,140.53 192.84,140.53 192.38,140.99 192.2,140.99 191.99,140.78 191.99,140.6 192.72,139.86 192.72,139.68 192.51,139.47 192.33,139.47 191.2,140.6 191.02,140.6 190.8,140.38 190.8,140.2 191.93,139.07 191.93,138.89 191.72,138.68 191.54,138.68 191.25,138.97 191.07,138.97 190.85,138.75 190.85,138.57 191.14,138.28 191.14,138.1 190.93,137.89 190.75,137.89 190.65,137.99 190.45,137.99 190.25,137.79 190.25,137.59 190.35,137.49 190.35,137.31 190.14,137.1 189.96,137.1 189.86,137.2 189.66,137.2 187.85,135.39
  BOTTOM w0.102: v1(183.36,132.31) 183.06,132.01 UV1.D15 ; v1(191.53,149.65) 191.18,149.3 UV21.F7
MDA39: length 35.6
  IN1 w0.102: v1(189.94,150.49) 189.94,150.97 190.8,151.83 195.61,151.83 196.54,150.9 ; 189.88,135.39 188.37,133.87 187.15,133.87 184.98,131.71 184.37,131.71 v1(183.69,131.03)
  IN1 w0.14: 189.88,135.39 196.99,142.49 196.99,150.45 196.54,150.9
  BOTTOM w0.102: v1(183.69,131.03) 183.86,131.2 UV1.E14 ; v1(189.94,150.49) 189.58,150.13 UV21.H8
MDA40: length 37.9
  TOP w0.102: v1(189.98,145.65) 189.58,146.05 UV20.H7
  IN3 w0.102: v1(189.98,145.65) 190.06,145.65 190.18,145.78 190.18,146.82 190.06,146.94 189.75,146.94 189.62,146.82 189.62,146.26 189.5,146.13 188.92,146.13 188.8,146 188.8,144.65 188.29,144.14 188.29,142.86
  IN3 w0.157: 188.29,142.86 188.29,142.52 188.13,142.36 187.97,142.36 187.85,142.23 187.85,141.86 187.97,141.73 188.13,141.73 188.29,141.57 188.29,141.06 188.04,140.81 187.1,140.81 186.77,140.48 185.45,140.48 185.33,140.35 185.33,138.1 v1(185.56,137.86)
  BOTTOM w0.102: UV1.F14 184.28,130.9 184.28,132.36 184.15,132.48 184.15,132.9 184.17,132.91 184.17,133.22 184.07,133.32 184.07,133.43 182.94,134.56 182.94,135.1 182.89,135.14 182.64,135.14 182.52,135.27 182.52,135.39
  BOTTOM w0.127: 182.52,135.39 182.52,139.38 182.64,139.5 182.96,139.5 183.08,139.38 183.08,137.99 183.21,137.86 183.53,137.86 183.66,137.99 183.66,139.34 183.79,139.46 184.04,139.46 184.17,139.34 184.17,137.99 184.3,137.86 184.67,137.86 184.8,137.99 v2(184.8,138.95) 184.8,139.34 184.93,139.46 186.63,139.46 186.76,139.34 186.76,138.83 186.63,138.7 185.69,138.7 185.56,138.57 v1(185.56,137.86)
MDA41: length 36.3
  TOP w0.102: v1(189.92,144.86) 189.58,145.2 UV20.H8
  IN3 w0.102: 188.79,144.32 188.99,144.52 189.79,144.52 189.92,144.64 v1(189.92,144.86)
  IN3 w0.157: 188.79,144.32 188.79,143.95 188.95,143.79 189.74,143.79 189.87,143.66 189.87,143.29 189.74,143.16 188.89,143.16 188.76,143.03 188.76,142.66 188.89,142.53 190.47,142.53 190.6,142.4 190.6,142.03 190.47,141.9 188.95,141.9 188.79,141.74 188.79,141.3 188.92,141.18 190.34,141.18 190.47,141.05 190.47,140.58 190.34,140.45 187.25,140.45 186.92,140.12 186.26,140.12 185.99,139.85 185.99,137.68 v1(185.56,137.25)
  BOTTOM w0.102: 184.27,134.32 184.27,133.4 184.37,133.3 184.37,132.83 184.36,132.82 184.36,132.56 184.66,132.26 UV1.D13
  BOTTOM w0.127: v1(185.56,137.25) 185.56,137.34 185.43,137.46 v2(183.15,137.46) 182.9,137.46 182.78,137.34 182.78,136.97 182.9,136.85 184.66,136.85 184.79,136.72 184.79,136.39 184.66,136.26 182.96,136.26 182.83,136.13 182.83,135.88 182.96,135.75 184.66,135.75 184.79,135.62 184.79,135.21 184.66,135.08 183.42,135.08 183.29,134.95 183.29,134.57 183.42,134.45 184.14,134.45 184.27,134.32
MDA42: length 36.3
  TOP w0.102: UV20.F7 191.18,147.37 v1(190.77,147.78)
  IN3 w0.102: 190.96,142.86 190.96,143.46 190.83,143.59 190.51,143.59 190.39,143.72 190.39,146.89 190.36,146.91 190.36,147.37 v1(190.77,147.78)
  IN3 w0.157: 190.96,142.86 190.96,142.12 191.08,142 192.12,142 192.25,141.87 192.25,141.49 192.12,141.37 190.96,141.37 190.83,141.24 190.83,140.87 190.96,140.75 192.01,140.75 192.14,140.62 192.14,140.2 192.03,140.09 187.59,140.09 187.47,139.96 187.47,139.69 187.34,139.57 186.48,139.57 186.36,139.44 186.36,138.78 186.48,138.66 187.56,138.66 187.69,138.53 187.69,138.15 187.56,138.03 186.85,138.03 186.69,137.87 186.69,134.65 186.56,134.52 186.12,134.52 185.99,134.65 185.99,136.48 185.81,136.66 v1(185.56,136.66)
  BOTTOM w0.102: 185.04,135.39 185.04,133.77 185.07,133.74 185.07,131.46 185.16,131.37 185.16,131.36 185.66,130.86 UV1.F12
  BOTTOM w0.127: v1(185.56,136.66) 185.55,136.66 185.04,136.15 185.04,135.39
MDA43: length 34.3
  TOP w0.102: v1(191.6,145.65) 191.57,145.65 UV20.F8
  IN3 w0.102: v1(191.6,145.65) 191.21,145.26 191.21,143.34 191.34,143.21 192.03,143.21
  IN3 w0.157: v1(185.56,136.07) 185.56,134.39 185.69,134.26 188.8,134.26 188.93,134.39 188.93,134.89 188.8,135.02 187.18,135.02 187.05,135.14 187.05,137.01 189.77,139.73 190.65,139.73 190.78,139.6 190.78,139.27 190.91,139.15 193.59,139.15 193.72,139.27 193.72,139.72 193.59,139.84 192.8,139.84 192.67,139.97 192.67,140.34 192.8,140.47 194.15,140.47 194.28,140.6 194.28,140.97 194.15,141.1 192.74,141.1 192.61,141.23 192.61,141.6 192.74,141.73 193.2,141.73 193.33,141.86 193.33,142.23 193.2,142.36 192.31,142.36 192.16,142.52 192.16,143.08 192.03,143.21
  BOTTOM w0.102: 185.3,135.39 185.3,133.25 UV1.A12
  BOTTOM w0.127: v1(185.56,136.07) 185.3,135.82 185.3,135.39
MDA44: length 35.6
  TOP w0.102: UV20.H3 189.86,149.26 v1(190.4,148.72)
  IN3 w0.102: 196.54,149.14 190.82,149.14 v1(190.4,148.72)
  IN3 w0.157: v1(188.23,137.47) 188.23,137.44 188.67,137 194.32,137 197.98,140.66 197.98,145.67 197.83,145.83 197.72,145.83 197.56,145.98 197.56,146.3 197.72,146.46 197.83,146.46 197.98,146.61 197.98,146.93 197.83,147.09 197.18,147.09 196.91,147.36 196.91,148.94 196.71,149.14 196.54,149.14
  BOTTOM w0.102: 186.83,135.39 186.83,134.96 186.58,134.72 186.58,133.33 186.55,133.3 186.55,132.88 186.57,132.87 186.57,132.56 186.26,132.26 UV1.D11
  BOTTOM w0.127: 186.83,135.39 186.83,136.59 187.71,137.47 v1(188.23,137.47)
MDA45: length 35.7
  TOP w0.102: UV20.G2 190.4,150.05 v1(190.8,149.65)
  IN3 w0.102: 196.54,149.82 196.33,150.04 191.19,150.04 v1(190.8,149.65)
  IN3 w0.157: 196.54,149.82 197.28,149.08 197.28,148.13 197.96,147.45 198.22,147.45 198.34,147.32 198.34,140.51 194.47,136.63 v1(187.94,136.63)
  BOTTOM w0.102: 187.9,135.39 187.6,135.09 187.6,134.15 187.37,133.91 187.37,133.19 187.53,133.03 187.53,132.29 187.15,131.91 186.96,131.91 186.7,131.65 186.7,131.25 UV1.F10
  BOTTOM w0.127: 187.9,135.39 v2(187.94,135.43) v1(187.94,136.63)
MDA46: length 34.3
  TOP w0.102: v1(191.6,150.45) 191.21,150.05 UV20.F2
  IN3 w0.102: 196.45,150.77 196.29,150.93 195.34,150.93 195.28,150.87 192.03,150.87
  IN3 w0.114: 192.03,150.87 v1(191.6,150.45)
  IN3 w0.157: 196.45,150.77 196.45,150.42 197.36,149.51 197.49,149.38 197.89,149.38 198.02,149.26 198.02,148.88 197.89,148.75 197.8,148.75 197.64,148.6 197.64,148.28 197.8,148.12 198.55,148.12 198.7,147.97 198.7,140.36 194.5,136.15 v1(187.52,136.15)
  BOTTOM w0.102: 187.34,135.39 187.34,134.18 187.16,134 187.16,133.19 UV1.A10
  BOTTOM w0.127: v1(187.52,136.15) 187.52,136.15 187.34,135.97 187.34,135.39
MDA47: length 35.3
  TOP w0.102: UV20.E3 191.98,148.67 192.51,148.14 v1(192.54,148.14)
  IN3 w0.102: 196.54,147.82 196.23,148.14 v1(192.54,148.14)
  IN3 w0.157: 196.54,147.82 196.55,147.82 196.55,146.58 196.67,146.45 197.03,146.45 197.16,146.32 197.16,145.95 197.03,145.82 196.67,145.82 196.55,145.69 196.55,145.32 196.67,145.19 197.47,145.19 197.62,145.03 197.62,144.72 197.47,144.56 196.74,144.56 196.61,144.43 196.61,144.06 196.74,143.93 197.47,143.93 197.62,143.77 197.62,143.46 197.47,143.3 197.04,143.3 196.88,143.14 196.88,142.83 197.04,142.67 197.47,142.67 197.62,142.51 197.62,142.2 197.47,142.04 197.01,142.04 196.88,141.91 196.88,141.54 197.01,141.41 197.49,141.41 197.61,141.28 197.61,140.8 197.49,140.67 197.05,140.67 196.95,140.57 196.95,140.14 194.29,137.47 v1(188.81,137.47)
  BOTTOM w0.102: UV1.C10 186.77,132.58 186.77,132.95 186.76,132.96 186.76,133.22 186.79,133.24 186.79,134.21 187.09,134.51 187.09,135.39
  BOTTOM w0.127: v1(188.81,137.47) 188.81,137.46 188.4,137.05 187.66,137.05 187.09,136.48 187.09,135.39
MDA48: length 36.5
  TOP w0.102: 189.75,143.36 191.41,143.36 191.91,142.86 ; 193.09,142.86 194,143.77 194,144.49 193.82,144.68 193.82,144.92 194,145.11 194,145.24 193.88,145.37 193.69,145.37 UV20.C8 ; v1(185.45,130.25) 185.57,130.25 185.7,130.38 185.7,133.35 185.82,133.47 186.67,133.47 186.8,133.6 186.8,134.19
  TOP w0.127: 191.91,142.86 192.01,142.76 192.99,142.76 193.09,142.86 ; 186.8,134.19 186.73,134.26 v2(186.51,134.26) 186.39,134.26 186.26,134.38 186.26,134.93 186.39,135.06 187.01,135.06 187.14,135.19 187.14,135.44 187.01,135.57 186.39,135.57 186.26,135.7 186.26,135.95 186.39,136.08 186.98,136.08 187.11,136.2 187.11,136.46 186.98,136.59 186.39,136.59 186.26,136.71 186.26,136.97 186.39,137.09 187.68,137.09 187.81,137.22 187.81,137.47 187.68,137.6 186.39,137.6 186.26,137.73 186.26,138.13 186.39,138.26 188.09,138.26 188.22,138.13 188.22,138 188.34,137.88 188.6,137.88 188.72,138 188.72,138.39 188.85,138.51 189.1,138.51 189.23,138.39 189.23,137.77 189.36,137.64 189.61,137.64 189.74,137.77 189.74,138.13 189.87,138.26 190.23,138.26 190.5,138.54 190.5,139.59 190.38,139.71 189.5,139.71 189.38,139.84 189.38,142.64 189.25,142.76 188.74,142.76 188.61,142.89 188.61,143.24 188.74,143.36 189.75,143.36
  BOTTOM w0.102: UV1.G13 185.42,130.25 185.44,130.25 185.45,130.25 v1(185.45,130.25)
MDA49: length 36.7
  TOP w0.102: 189.56,143.72 190.07,143.72 190.22,143.57 191.62,143.57 192.17,143.01 192.63,143.01 193.18,143.56 193.18,145.43 192.78,145.83 UV20.D7 ; v1(184.62,129.49) 185.05,129.92 185.05,131.22 185.07,131.24 185.07,131.32 185.17,131.42 185.37,131.42 185.49,131.54 185.49,131.71 185.37,131.82 184.42,131.82 184.29,131.95 184.29,132.1 184.42,132.23 185.37,132.23 185.49,132.35 185.49,132.52 185.37,132.64 184.47,132.64 184.35,132.76 184.35,132.92 184.47,133.04 185.37,133.04 185.49,133.17 185.49,133.54 185.39,133.64 185.1,133.64 184.98,133.77 184.98,134.04 185.1,134.17 185.88,134.17 186,134.3 186,135.39
  TOP w0.127: 186,135.39 186,138.45 186.26,138.7 v2(187.27,138.7) 187.91,138.7 188.04,138.83 188.99,138.83 189.24,139.08 189.24,139.61 189.12,139.73 189.12,140.67 188.99,140.8 188,140.8 187.87,140.92 187.87,141.22 188,141.34 188.99,141.34 189.12,141.47 189.12,141.72 188.99,141.85 188,141.85 187.87,141.98 187.87,142.29 188,142.42 188.24,142.42 188.36,142.55 188.36,142.8 188.24,142.93 187.74,142.93 187.62,143.06 187.62,143.72 187.74,143.84 188.54,143.84 188.67,143.72 189.56,143.72
  BOTTOM w0.102: v1(184.62,129.49) 185.02,129.09 UV1.H13
MDA50: length 37
  TOP w0.102: 187.27,133.24 187.27,129.86 186.2,128.79 v1(185.7,128.79) ; UV20.A7 195.68,146.05 196.16,145.57 196.16,143.73 195.29,142.86
  TOP w0.127: 187.27,133.24 187.27,133.49 188.38,134.59 188.78,134.59 190.42,136.23 190.42,136.41 189.85,136.97 189.85,137.15 191.02,138.32 191.02,138.59 191.72,139.29 191.72,139.47 191.02,140.17 191.02,140.35 191.2,140.53 191.38,140.53 192.08,139.83 192.26,139.83 192.44,140.01 192.44,140.19 v2(191.98,140.65) 191.02,141.6 191.02,141.78 191.2,141.96 191.38,141.96 192.8,140.55 192.98,140.55 193.16,140.73 193.16,140.91 192.18,141.89 192.18,142.07 192.36,142.25 192.54,142.25 193.52,141.27 193.7,141.27 193.88,141.45 193.88,141.63 193.32,142.18 193.32,142.36 193.5,142.54 193.68,142.54 194.24,141.98 194.42,141.98 194.6,142.16 194.6,142.34 194.08,142.86 194.08,143.04 194.26,143.22 194.44,143.22 194.96,142.7 195.13,142.7 195.29,142.86
  BOTTOM w0.102: UV1.J13 185.2,128.29 v1(185.7,128.79)
MDA51: length 36.8
  TOP w0.102: v1(185.69,129.68) 186,129.68 186.46,130.14 186.46,131.33 186.96,131.82 186.96,133.48 187.38,133.9 187.38,134.34 187.09,134.63 ; UV20.B8 194.55,145.25 194.93,145.64 195.81,145.64 195.96,145.49 195.96,143.9 195.5,143.43 194.03,143.43 193.46,142.86
  TOP w0.127: 187.09,134.63 187.09,134.81 187.35,135.08 187.53,135.08 187.94,134.66 188.12,134.66 188.3,134.84 188.3,135.02 187.92,135.4 187.92,135.58 188.1,135.76 188.28,135.76 188.85,135.2 189.03,135.2 189.21,135.38 189.21,135.55 188.64,136.12 188.64,136.3 188.82,136.48 189,136.48 189.56,135.92 189.74,135.92 189.92,136.1 189.92,136.28 189.36,136.84 189.36,137.02 190.76,138.43 190.76,140.1 190.64,140.23 189.76,140.23 189.63,140.35 189.63,140.61 189.76,140.73 v2(190.07,140.73) 190.64,140.73 190.76,140.86 190.76,141.11 190.64,141.24 189.76,141.24 189.63,141.37 189.63,141.62 189.76,141.75 190.51,141.75 190.64,141.88 190.64,142.19 190.51,142.32 189.76,142.32 189.63,142.45 189.63,142.85 189.76,142.98 191.35,142.98 191.53,142.8 191.53,142.57 191.6,142.51 193.1,142.51 193.46,142.86
  BOTTOM w0.102: UV1.H11 186.26,129.1 v1(185.69,129.68)
MDA52: length 36.1
  TOP w0.102: 191.99,135.39 189.93,133.33 189.65,133.33 188.94,132.62 188.94,130.63 188.43,130.12 v1(188.43,129.49) ; 196.54,148.16 193.73,148.16 193.6,148.29 193.6,149.23 UV20.C3
  TOP w0.127: 196.54,148.16 196.93,148.16 196.99,148.1 196.99,147.73 197.95,146.77 197.95,146.14 198.07,146.01 198.84,146.01 198.97,145.89 198.97,145.63 198.84,145.51 v2(198.39,145.51) 198.07,145.51 197.95,145.38 197.95,145.12 198.07,145 198.84,145 198.97,144.87 198.97,144.62 198.84,144.49 198.07,144.49 197.95,144.36 197.95,144.11 198.07,143.98 198.84,143.98 198.97,143.85 198.97,143.6 198.84,143.47 197.97,143.47 197.85,143.35 197.85,143.09 197.97,142.97 198.84,142.97 198.97,142.84 198.97,142.57 198.84,142.45 198.01,142.45 197.95,142.39 197.95,141.36 191.99,135.4 191.99,135.39
  BOTTOM w0.102: v1(188.43,129.49) 187.67,129.49 UV1.G10
MDA53: length 35.7
  TOP w0.102: 192.72,135.39 189.35,132.01 189.35,130.46 189.26,130.37 v1(189.26,129.49) ; UV20.C2 193.95,149.69 195.27,149.69 195.37,149.8 195.72,149.8
  TOP w0.127: 195.72,149.8 195.85,149.67 195.85,149.5 195.97,149.37 196.32,149.37 196.44,149.5 196.44,150 196.57,150.13 196.83,150.13 196.95,150 196.95,149.25 197.08,149.12 197.33,149.12 197.46,149.25 v2(197.46,149.62) 197.46,150 197.59,150.13 197.84,150.13 197.97,150 197.97,149.25 198.1,149.12 198.35,149.12 198.48,149.25 198.48,150 198.6,150.13 198.86,150.13 198.98,150 198.98,149.25 199.11,149.12 199.36,149.12 199.49,148.99 199.49,142.16 192.72,135.39
  BOTTOM w0.102: v1(189.26,129.49) 189.26,129.49 189.26,129.5 188.87,129.89 UV1.G8
MDA54: length 36.9
  TOP w0.102: 196.54,150.39 196.2,150.39 195.86,150.05 UV20.A2 ; 193.09,135.39 189.64,131.94 189.64,129.29 189.42,129.07 189.11,129.07 188.88,128.84 188.88,128.31 v1(188.46,127.89)
  TOP w0.127: 193.09,135.39 193.47,135.77 193.65,135.77 193.96,135.46 194.13,135.46 194.32,135.64 194.32,135.82 194.01,136.13 194.01,136.31 194.19,136.49 194.37,136.49 194.67,136.18 194.85,136.18 195.03,136.36 195.03,136.54 194.73,136.85 194.73,137.03 194.91,137.21 195.09,137.21 195.39,136.9 195.57,136.9 195.75,137.08 195.75,137.26 195.45,137.57 195.45,137.75 195.63,137.93 195.81,137.93 196.11,137.62 196.29,137.62 196.47,137.8 196.47,137.98 196.17,138.29 196.17,138.46 199.75,142.05 v2(199.75,149.94) 199.75,150.26 199.62,150.39 196.54,150.39
  BOTTOM w0.102: UV1.K9 v1(188.46,127.89)
MDA55: length 36.7
  TOP w0.102: v1(187.66,127.9) 187.66,128.14 188.08,128.56 188.08,128.85 188.34,129.11 188.65,129.11 188.81,129.27 188.81,130.21 189.14,130.54 189.14,132.18 192.35,135.39 ; UV20.A3 195.18,148.49 195.31,148.37 195.59,148.37 195.72,148.49 195.72,148.73 195.85,148.86 196.54,148.86
  TOP w0.127: 192.35,135.39 199.23,142.26 199.23,146.45 199.1,146.58 198.39,146.58 198.26,146.7 198.26,146.96 198.39,147.09 199.1,147.09 199.23,147.21 199.23,147.47 199.1,147.59 197.49,147.59 197.36,147.72 197.36,147.97 197.49,148.1 v2(198.7,148.1) 199.1,148.1 199.23,148.23 199.23,148.73 199.1,148.86 196.54,148.86
  BOTTOM w0.102: UV1.K10 187.26,127.5 v1(187.66,127.9)
MDA56: length 35.5
  BOTTOM w0.102: UV1.G9 188.37,130.2 188.37,130.76 188.97,131.36 188.97,131.62 188.94,131.64 188.94,132.14 189.07,132.27 189.07,132.71 189.2,132.84 189.2,133.35 189.08,133.47 189.08,134.27 190.19,135.39 ; UV21.C2 193.75,145.43 193.75,145.56 193.62,145.69 193.37,145.69 193.24,145.81 193.24,146.32 193.34,146.42
  BOTTOM w0.127: 193.34,146.42 193.5,146.57 193.5,147.21 193.62,147.34 195.21,147.34 195.34,147.21 195.34,146.83 195.47,146.7 195.72,146.7 195.85,146.83 195.85,147.18 195.97,147.31 196.23,147.31 196.35,147.18 196.35,146.77 196.48,146.64 196.74,146.64 196.86,146.77 196.86,147.2 196.99,147.33 197.24,147.33 197.37,147.2 197.37,145.81 197.5,145.69 197.75,145.69 197.88,145.81 v2(197.88,146.7) 197.88,147.2 198.01,147.33 198.26,147.33 198.39,147.2 198.39,141.38 193.09,136.09 190.89,136.09 190.19,135.39
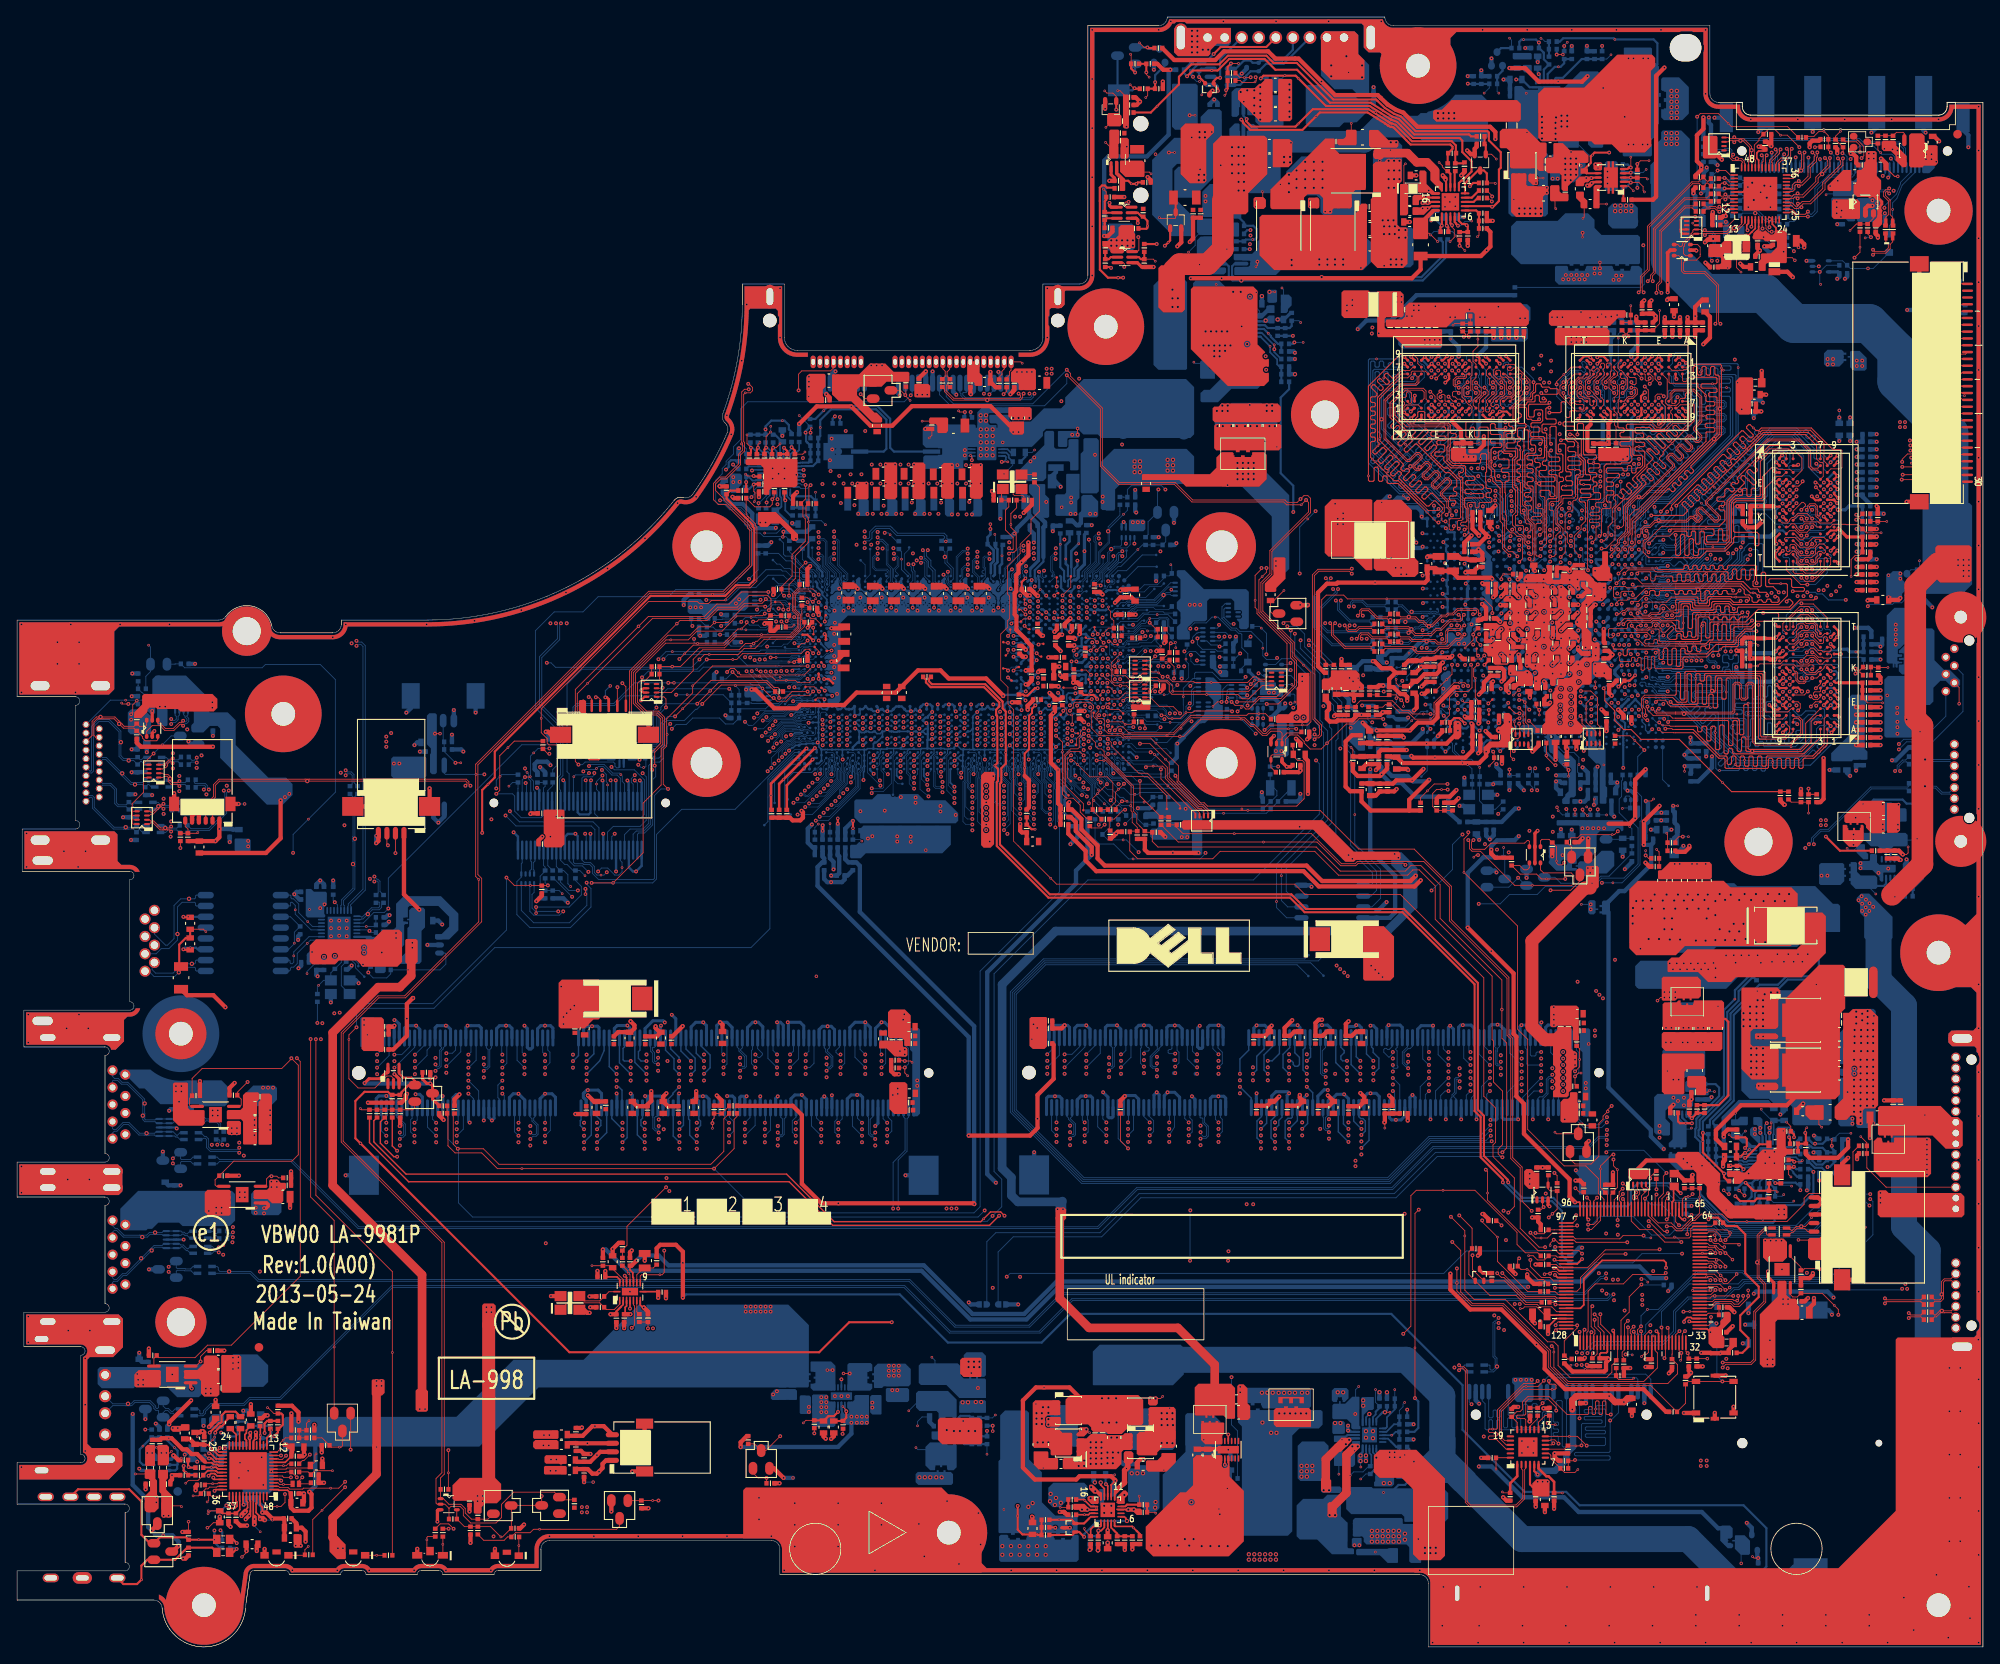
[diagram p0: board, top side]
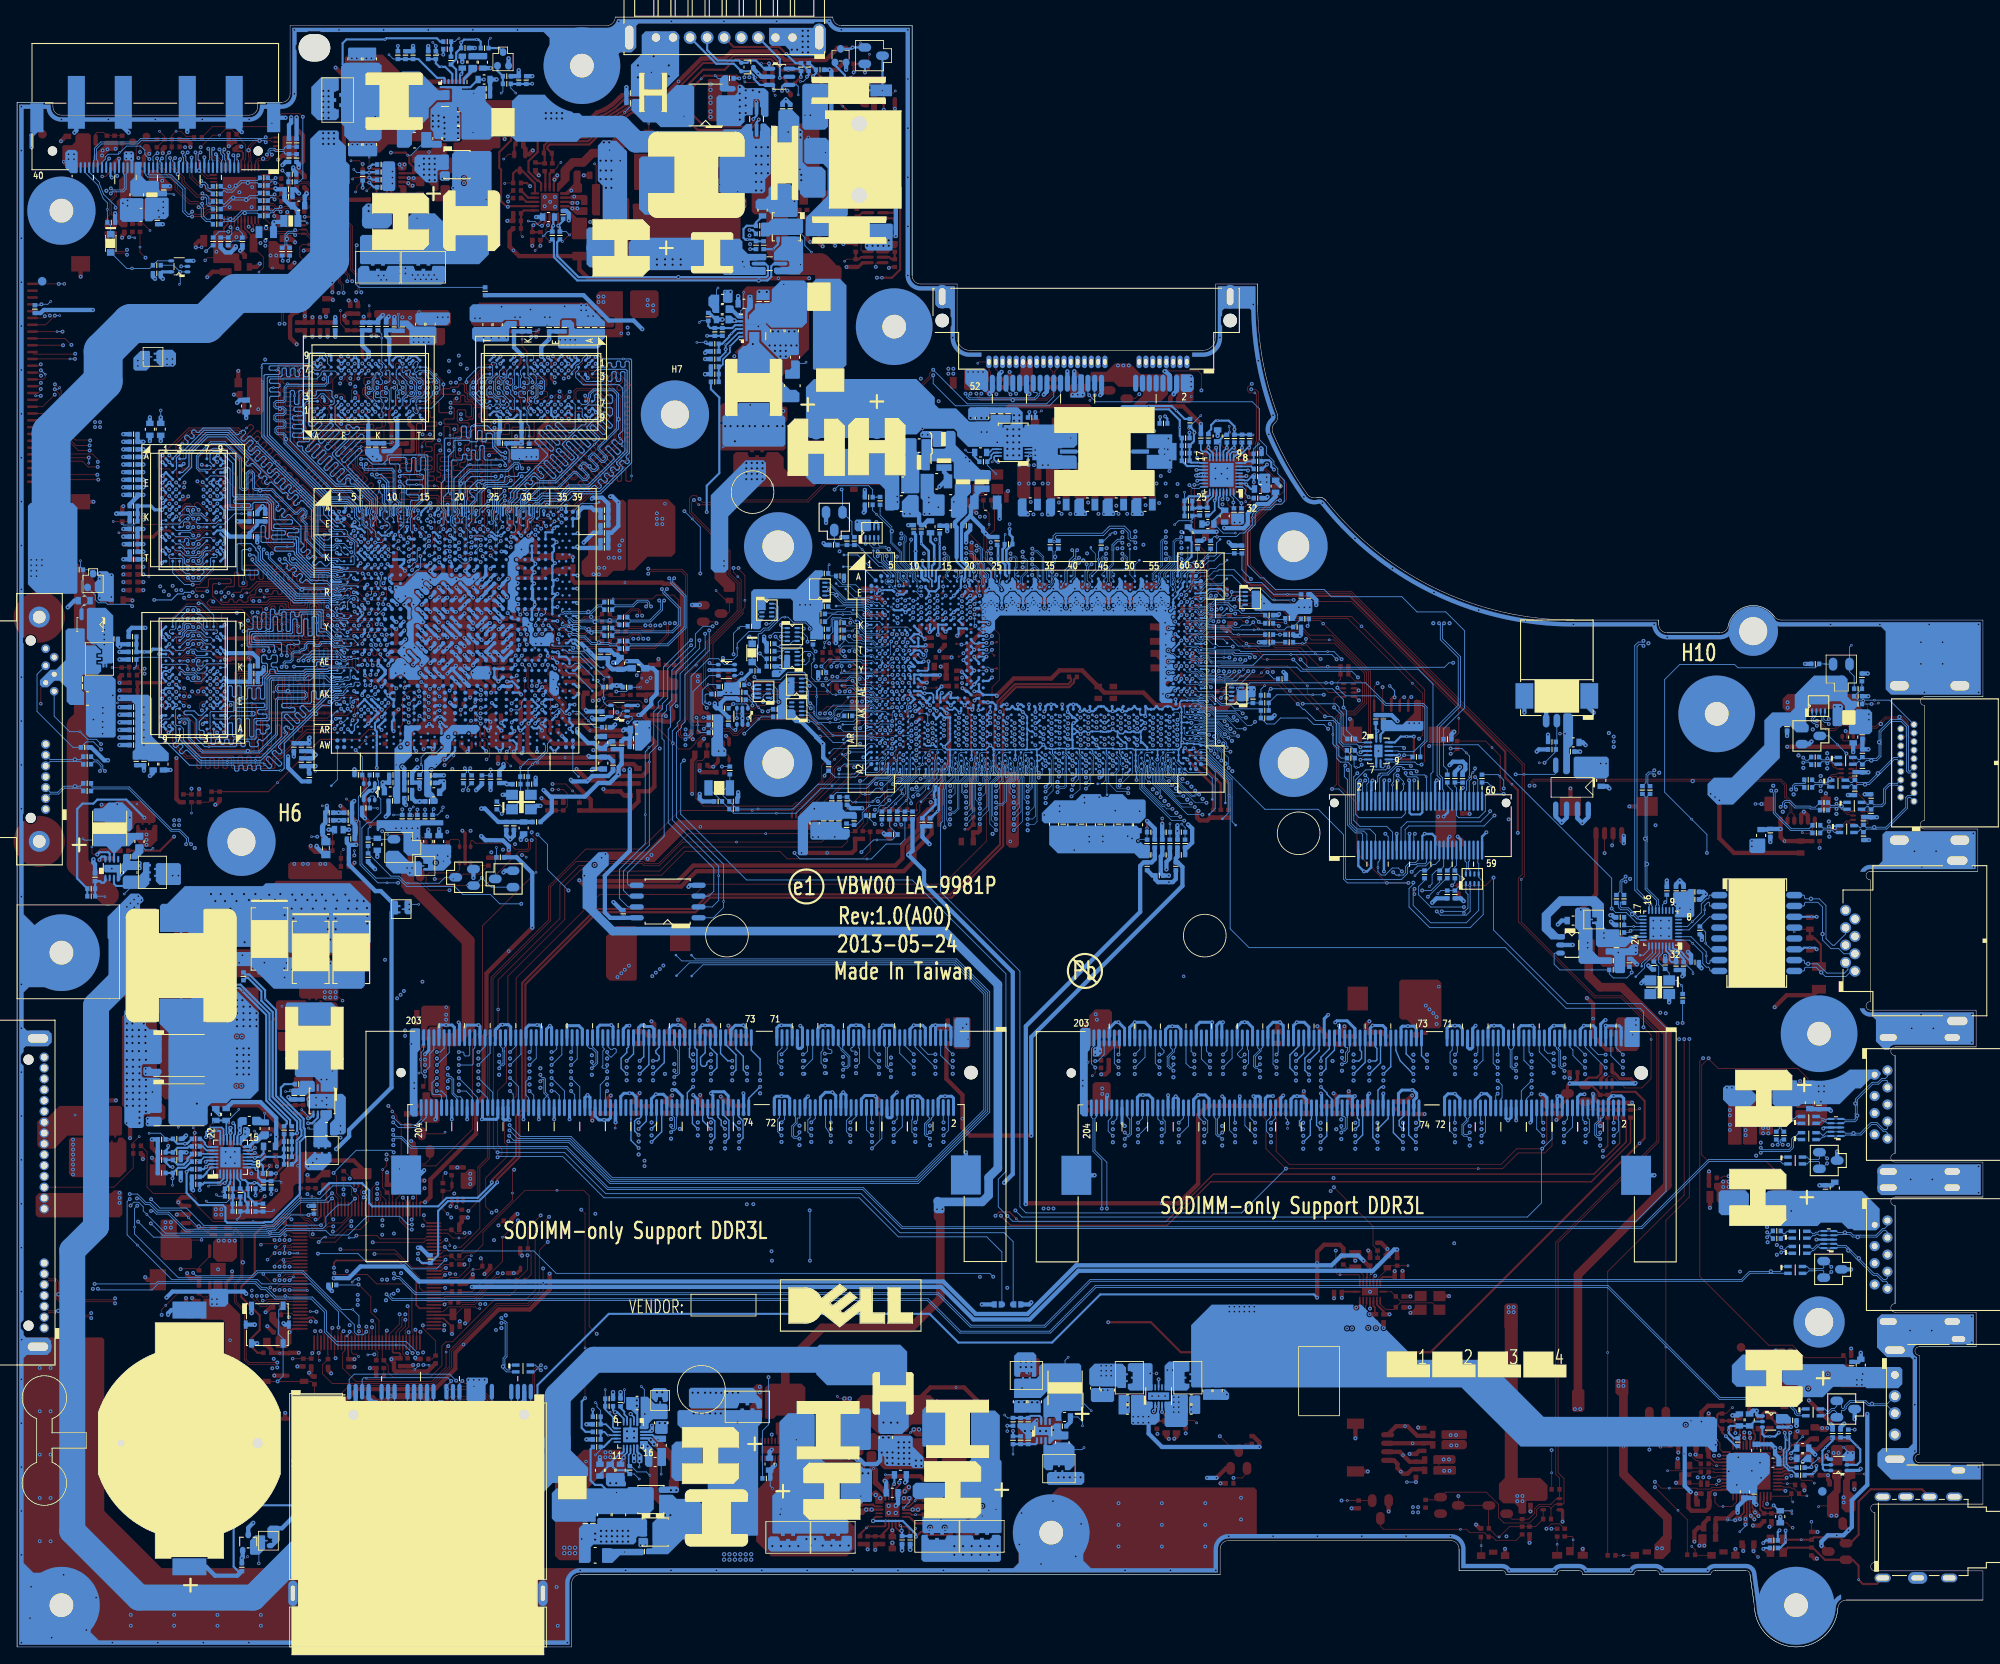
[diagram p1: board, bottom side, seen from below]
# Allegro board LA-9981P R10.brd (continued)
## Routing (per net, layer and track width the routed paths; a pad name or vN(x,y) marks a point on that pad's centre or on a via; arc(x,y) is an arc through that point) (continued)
MDA57: length 34.3
  BOTTOM w0.102: 189.46,135.39 188.67,134.6 188.67,133.1 UV1.A8
  BOTTOM w0.127: 189.46,135.39 191.52,137.45 191.7,137.45 192.54,136.61 192.72,136.61 192.9,136.79 192.9,136.97 192.06,137.81 192.06,137.99 192.24,138.17 192.42,138.17 193.34,137.25 193.52,137.25 193.7,137.43 193.7,137.6 192.77,138.53 192.77,138.7 192.95,138.88 193.13,138.88 194.05,137.96 194.23,137.96 194.41,138.14 194.41,138.32 193.49,139.24 193.49,139.42 193.67,139.6 193.85,139.6 194.77,138.68 194.95,138.68 195.13,138.86 195.13,139.04 194.21,139.96 194.21,140.14 194.39,140.32 194.57,140.32 195.49,139.4 195.67,139.4 195.85,139.58 195.85,139.76 194.93,140.68 194.93,140.86 195.11,141.04 195.29,141.04 196.21,140.12 196.39,140.12 196.57,140.3 196.57,140.48 v2(196.24,140.81) 195.65,141.4 195.65,141.58 196.67,142.6 196.67,145.82 196.43,146.05 UV21.A3
MDA58: length 34.5
  BOTTOM w0.102: 196.54,146.39 195.34,146.39 194.79,146.93 194.44,146.93 193.58,146.07 UV21.C3 ; 189.82,135.39 188.87,134.44 188.87,133.39 188.99,133.27 188.99,132.92 188.66,132.59 UV1.C8
  BOTTOM w0.127: 189.82,135.39 190.78,136.35 191.23,136.35 191.36,136.47 191.36,136.91 191.49,137.04 191.74,137.04 191.87,136.91 191.87,136.47 191.99,136.35 192.98,136.35 196.93,140.29 196.93,140.67 197.05,140.8 197.43,140.8 197.56,140.92 197.56,141.18 197.43,141.31 196.25,141.31 196.12,141.43 196.12,141.69 196.25,141.81 198,141.81 198.13,141.94 198.13,142.19 198,142.32 197.05,142.32 196.93,142.45 196.93,142.7 197.05,142.83 198,142.83 198.13,142.96 198.13,143.21 198,143.34 197.05,143.34 196.93,143.46 196.93,143.72 197.05,143.85 198,143.85 198.13,143.97 198.13,144.23 198,144.35 v2(197.63,144.35) 197.05,144.35 196.93,144.48 196.93,144.73 197.05,144.86 197.82,144.86 197.94,144.99 197.94,145.24 197.82,145.37 197.05,145.37 196.93,145.5 196.93,146.26 196.8,146.39 196.54,146.39
MDA59: length 35
  BOTTOM w0.102: 189.09,135.39 188.36,134.65 188.36,132.96 188.46,132.86 188.46,132.52 188.36,132.42 188.36,132.1 188.62,131.84 188.62,131.53 UV1.E8
  BOTTOM w0.127: 189.09,135.39 193.44,139.74 193.44,139.98 191.85,141.57 191.85,141.75 192.07,141.98 192.25,141.98 193.88,140.35 194.06,140.35 194.3,140.6 194.3,140.78 v2(193.99,141.1) 192.67,142.41 192.67,142.59 192.85,142.77 193.03,142.77 194.66,141.14 194.84,141.14 195.02,141.32 195.02,141.5 193.37,143.15 193.37,143.33 193.55,143.51 193.73,143.51 195.38,141.86 195.56,141.86 195.75,142.05 195.75,142.23 194.69,143.3 194.69,143.48 194.88,143.67 195.06,143.67 195.59,143.15 196.1,143.15 196.23,143.27 196.23,145.13 196.1,145.25 UV21.A2
MDA60: length 34
  BOTTOM w0.102: UV21.D7 193.12,149.6 194.54,149.6 194.77,149.37 194.77,149.18 195.28,148.67 196.54,148.67
  BOTTOM w0.127: UV1.A6 190.39,133.21 190.39,133.72 191.49,134.83 193.54,134.83 200.8,142.09 200.8,146.51 200.67,146.63 199.72,146.63 199.6,146.76 199.6,147.02 199.72,147.14 200.67,147.14 200.8,147.27 200.8,147.52 200.67,147.65 v2(200.36,147.65) 199.72,147.65 199.6,147.78 199.6,148.03 199.72,148.16 200.69,148.16 200.82,148.29 200.82,148.54 200.69,148.67 196.54,148.67
MDA61: length 33.8
  BOTTOM w0.102: 190.61,133.39 190.61,132.64 UV1.C6
  BOTTOM w0.127: UV21.A7 195.48,149.25 195.76,149.53 196.1,149.53 196.23,149.41 196.23,149.06 196.36,148.93 196.67,148.93 196.8,149.06 196.8,149.81 196.93,149.94 197.18,149.94 197.31,149.81 v2(197.31,149.5) 197.31,149.06 197.43,148.93 197.69,148.93 197.82,149.06 197.82,149.81 197.94,149.94 198.2,149.94 198.32,149.81 198.32,149.06 198.45,148.93 198.7,148.93 198.83,149.06 198.83,149.81 198.96,149.94 199.21,149.94 199.34,149.81 199.34,149.06 199.47,148.93 200.95,148.93 201.07,148.8 201.07,141.99 193.65,134.57 191.65,134.57 190.61,133.54 190.61,133.39
MDA62: length 34.3
  BOTTOM w0.102: 195.63,149.98 195.63,149.81 195.51,149.69 194.96,149.69 194.59,150.05 UV21.B8 ; 191.16,133.77 190.86,133.46 190.86,132.45 190.26,131.86 UV1.E6
  BOTTOM w0.127: 195.63,149.98 195.86,150.2 200.74,150.2 200.86,150.08 200.86,149.82 200.74,149.7 v2(199.97,149.7) 199.73,149.7 199.6,149.57 199.6,149.32 199.73,149.19 201.33,149.19 201.46,149.06 201.46,142.01 193.73,134.29 191.68,134.29 191.16,133.77
MDA63: length 33.3
  BOTTOM w0.102: 193.49,134.06 191.76,134.06 191.16,133.46 UV1.A5 ; UV21.C8 194.01,150.48 194.01,151.08 194.2,151.27
  BOTTOM w0.127: 193.49,134.06 193.87,134.06 201.71,141.9 v2(201.71,150) 201.71,150.34 201.59,150.46 196.29,150.46 196.16,150.59 196.16,151.59 196.04,151.72 194.39,151.72 194.26,151.59 194.26,151.34 194.2,151.27
MDB0: length 34.7
  TOP w0.102: 210.9,140.67 210.9,139.3 211.3,138.89 211.56,138.89 211.68,138.76 211.68,137.23 UV22.D7
  TOP w0.127: v1(191.53,132.67) 195.28,132.67 195.76,133.14 195.76,133.32 195.14,133.94 195.14,134.12 195.32,134.3 195.5,134.3 196.12,133.68 196.3,133.68 196.48,133.86 196.48,134.04 195.86,134.66 195.86,134.83 196.04,135.01 196.22,135.01 196.83,134.4 197.01,134.4 197.19,134.58 197.19,134.76 196.58,135.37 196.58,135.55 196.76,135.73 196.94,135.73 v2(197.2,135.48) 197.55,135.12 197.73,135.12 204.75,142.14 209.61,142.14 210.9,140.86 210.9,140.67
  BOTTOM w0.102: v1(191.53,132.67) 191.53,132.66 UV1.C5
MDB1: length 34.4
  TOP w0.102: UV22.C8 212.58,138.13 213.74,138.13 213.87,138.25 213.87,140.28 213.74,140.41 212.79,140.41 212.54,140.67
  TOP w0.127: v1(192.65,133.11) 202.12,142.58 202.3,142.58 203.11,141.77 203.29,141.77 203.47,141.95 203.47,142.13 202.7,142.9 202.7,143.08 202.93,143.31 203.11,143.31 v2(203.5,142.92) 203.81,142.61 204.13,142.61 204.43,142.92 210.28,142.92 211.65,141.55 212.54,140.67
  BOTTOM w0.102: UV1.C3 192.61,132.84 192.61,133.08 v1(192.65,133.11)
MDB2: length 34.8
  TOP w0.102: 211.77,140.67 211.77,139.06 212.15,138.67 UV22.B8
  TOP w0.127: 211.77,140.67 211.77,141.07 210.18,142.66 204.54,142.66 203.2,141.32 202.94,141.32 202.32,141.94 202.14,141.94 201.92,141.73 201.92,141.55 v2(202.25,141.23) 202.59,140.89 202.59,140.71 202.41,140.53 202.23,140.53 201.5,141.25 201.32,141.25 201.14,141.07 201.14,140.89 201.87,140.17 201.87,139.99 201.69,139.81 201.51,139.81 200.78,140.53 200.6,140.53 200.42,140.36 200.42,140.18 200.88,139.72 200.88,139.54 200.7,139.36 200.52,139.36 200.06,139.82 199.88,139.82 193.9,133.83 v1(193.9,133.42)
  BOTTOM w0.127: UV1.E3 192.45,131.78 192.94,131.78 193.9,132.73 v1(193.9,133.42)
MDB3: length 34.6
  TOP w0.127: v1(194.47,133.81) 196.9,136.24 197.08,136.24 197.69,135.63 197.87,135.63 198.05,135.81 198.05,135.99 197.44,136.6 197.44,136.78 197.62,136.96 197.8,136.96 198.41,136.35 198.59,136.35 198.77,136.53 198.77,136.71 198.16,137.32 198.16,137.5 198.34,137.68 198.52,137.68 199.13,137.07 199.31,137.07 199.49,137.24 199.49,137.42 198.88,138.04 198.88,138.22 199.06,138.4 199.24,138.4 199.85,137.78 200.03,137.78 200.21,137.96 200.21,138.14 199.6,138.76 199.6,138.94 199.78,139.12 199.96,139.12 v2(200.2,138.87) 200.57,138.5 200.75,138.5 200.93,138.68 200.93,138.86 200.84,138.95 200.84,139.13 201.02,139.31 201.2,139.31 201.29,139.22 201.47,139.22 204.65,142.4 209.93,142.4 211.35,140.97 UV22.A7
  BOTTOM w0.127: v1(194.47,133.81) 194.47,132.81 193.05,131.39 UV1.E1
MDB4: length 34.8
  TOP w0.102: UV22.C3 207.79,138.07 206.45,138.07 206.26,138.26 205.63,138.26 204.96,137.59
  TOP w0.127: 204.96,137.59 204.57,137.2 204.57,134.77 204.44,134.64 201.39,134.64 200.92,134.17 200.92,129.58 200.09,128.75 197.18,128.75 197.05,128.62 197.05,128.1 196.93,127.97 196.6,127.97 196.47,128.1 196.47,129.81 196.34,129.94 196.09,129.94 195.96,129.81 195.96,128.1 195.84,127.97 195.58,127.97 195.45,128.1 195.45,130.32 195.33,130.45 195.07,130.45 194.95,130.32 194.95,128.1 194.82,127.97 194.51,127.97 194.39,128.1 v2(194.39,129.24) v1(194.39,130.38)
  BOTTOM w0.102: v1(194.39,130.38) 194.28,130.49 UV1.F1
MDB5: length 35.5
  TOP w0.102: UV22.A3 208.15,139.98 207.66,140.48 205.36,140.48 204.96,140.07
  TOP w0.127: v1(193.69,130.89) 193.88,131.08 198.75,131.08 198.88,130.95 198.88,130.45 198.75,130.32 198.13,130.32 198,130.19 198,129.68 198.13,129.55 199.26,129.55 199.39,129.68 199.39,130.95 199.51,131.08 199.77,131.08 199.9,130.95 199.9,129.79 200.02,129.67 200.28,129.67 200.4,129.79 200.4,134.39 202.42,136.41 202.42,136.59 202.04,136.97 202.04,137.15 202.22,137.33 202.4,137.33 v2(202.89,136.83) 203.46,136.27 203.64,136.27 203.82,136.45 203.82,136.63 202.75,137.69 202.75,137.87 202.93,138.05 203.11,138.05 203.51,137.65 203.69,137.65 203.95,137.91 203.95,138.09 203.56,138.48 203.56,138.68 204.96,140.07
  BOTTOM w0.102: UV1.F3 192.39,130.81 193.61,130.81 v1(193.69,130.89)
MDB6: length 35.6
  TOP w0.102: v1(190.96,130.89) 191.17,130.68 191.17,130.1 190.95,129.87 190.77,129.87 190.58,129.68 190.58,128.37 191.23,127.72 194.39,127.72 ; UV22.C2 207.3,137.7 206.83,137.24 206.26,137.24 204.96,135.94
  TOP w0.127: 194.39,127.72 v2(196.23,127.72) 197.24,127.72 198.02,128.49 200.2,128.49 201.18,129.47 201.18,130.05 201.31,130.18 203.51,130.18 203.63,130.05 203.63,129.24 203.76,129.11 204.01,129.11 204.14,129.24 204.14,130.47 203.92,130.69 201.31,130.69 201.18,130.82 201.18,134.07 201.5,134.38 204.55,134.38 204.86,134.7 204.86,135.85 204.96,135.94
  BOTTOM w0.102: v1(190.96,130.89) 191.26,130.59 UV1.F5
MDB7: length 35.5
  TOP w0.102: 204.96,139.65 205.4,140.1 207.03,140.1 207.35,139.77 UV22.A2 ; v1(191.28,129.37) 192.16,130.26 193.69,130.26 194.25,130.82 194.39,130.82
  TOP w0.127: 194.39,130.82 195.59,130.82 195.71,130.69 195.71,130.32 195.84,130.2 196.09,130.2 196.22,130.32 196.22,130.69 196.35,130.82 196.6,130.82 196.73,130.69 196.73,129.43 196.86,129.3 197.11,129.3 197.24,129.43 197.24,130.69 197.36,130.82 197.62,130.82 197.75,130.69 197.75,129.43 197.88,129.29 200.27,129.29 200.66,129.69 200.66,134.28 201.4,135.02 v2(201.75,135.02) 202.13,135.02 202.23,135.11 202.23,135.72 202.35,135.84 202.61,135.84 202.73,135.72 202.73,135.03 202.86,134.9 203.12,134.9 203.24,135.03 203.24,135.72 203.37,135.84 203.62,135.84 203.75,135.72 203.75,135.03 203.88,134.9 204.18,134.9 204.31,135.03 204.31,139 204.96,139.65
  BOTTOM w0.102: v1(191.28,129.37) 191.59,129.69 UV1.G4
MDB8: length 35.3
  BOTTOM w0.102: UV1.H5 191.59,128.89 192.09,129.39 192.59,129.39 192.6,129.4 193.07,129.4 193.3,129.18 194.28,129.18 194.39,129.28
  BOTTOM w0.127: UV23.A3 210.73,139.3 210.6,139.43 210.6,140.06 208.26,142.39 205.67,142.39 203.04,139.77 202.86,139.77 202.3,140.32 202.12,140.32 201.94,140.14 201.94,139.96 202.5,139.41 202.5,139.23 202.32,139.05 202.14,139.05 201.59,139.61 201.41,139.61 201.23,139.43 201.23,139.25 201.78,138.69 201.78,138.51 201.6,138.33 201.42,138.33 200.87,138.89 200.69,138.89 200.51,138.71 200.51,138.53 201.06,137.97 201.06,137.79 200.88,137.61 200.71,137.61 v2(200.41,137.91) 200.15,138.17 199.97,138.17 195.39,133.59 195.39,130.29 194.39,129.28
MDB9: length 35.5
  BOTTOM w0.102: 194.39,131.7 194.21,131.53 193.69,131.53 193.18,131.02 191.91,131.02 191.66,130.76 191.66,130.45 191.16,129.96 191.03,129.96 191.03,129.95 191.02,129.95 190.46,129.39 UV1.H6
  BOTTOM w0.127: 194.39,131.7 194.89,132.2 194.89,133.82 203.02,141.96 203.2,141.96 203.76,141.4 203.94,141.4 204.14,141.6 204.14,141.78 203.62,142.3 203.62,142.48 203.8,142.65 203.98,142.65 v2(204.24,142.4) 204.5,142.14 204.68,142.14 205.45,142.91 208.59,142.91 209.1,142.39 209.28,142.39 209.58,142.69 209.76,142.69 209.94,142.51 209.94,142.33 209.64,142.04 209.64,141.86 209.82,141.68 210,141.68 210.4,142.07 210.58,142.07 210.76,141.89 210.76,141.71 210.36,141.32 210.36,141.14 210.54,140.96 210.72,140.96 210.92,141.16 211.1,141.16 211.28,140.98 211.28,140.8 211.08,140.6 211.08,140.42 212.15,139.35 UV23.A2
MDB10: length 35.7
  BOTTOM w0.102: 194.39,128.93 193.25,128.93 192.99,129.2 192.69,129.2 192.42,128.93 192.42,128.54 191.97,128.09 UV1.J4
  BOTTOM w0.127: 194.39,128.93 194.4,128.93 195.65,130.18 195.65,133.48 197.72,135.55 197.9,135.55 198.19,135.27 198.37,135.27 198.55,135.45 198.55,135.63 198.26,135.91 198.26,136.09 198.44,136.27 198.62,136.27 v2(198.91,135.98) 199.18,135.72 199.36,135.72 199.54,135.9 199.54,136.08 198.98,136.63 198.98,136.81 199.16,136.99 199.34,136.99 199.9,136.43 200.08,136.43 200.26,136.61 200.26,136.79 199.7,137.35 199.7,137.53 199.88,137.71 200.06,137.71 200.61,137.15 200.79,137.15 205.78,142.13 208.16,142.13 210.26,140.03 210.26,138.45 211.01,137.7 UV23.C3
MDB11: length 36.2
  BOTTOM w0.102: UV1.K6 190.46,127.73 190.83,128.1 190.83,129.47 191.11,129.75 191.11,129.75 191.12,129.75 191.24,129.75 191.68,130.19 193.56,130.19 193.95,129.79 194.39,129.79
  BOTTOM w0.127: UV23.C2 211.72,138.13 211.72,139.41 208.48,142.65 205.56,142.65 203.85,140.94 203.67,140.94 203.11,141.5 202.93,141.5 202.75,141.32 202.75,141.14 203.31,140.58 203.31,140.4 203.13,140.22 202.95,140.22 v2(202.73,140.44) 202.39,140.78 202.21,140.78 195.14,133.7 195.14,130.44 194.49,129.79 194.39,129.79
MDB12: length 35.5
  BOTTOM w0.102: UV1.K5 191.26,127.8 191.16,127.91 191,127.91 190.89,127.8 190.89,126.99 191,126.89 192.99,126.89 193.23,127.13 193.69,127.13 194.09,126.73 194.28,126.73 194.39,126.84 ; UV23.A7 208.15,139.83 207.44,140.54 206.26,140.54 204.96,139.24
  BOTTOM w0.127: 194.39,126.84 194.8,127.25 194.98,127.25 195.38,126.84 195.56,126.84 195.74,127.02 195.74,127.2 195.34,127.61 195.34,127.79 195.52,127.97 195.7,127.97 196.1,127.56 196.28,127.56 196.46,127.74 196.46,127.92 196.06,128.33 196.06,128.51 196.24,128.69 196.42,128.69 196.77,128.33 196.95,128.33 197.13,128.51 197.13,128.69 196.77,129.05 196.77,129.23 197.13,129.58 197.13,131.41 198.48,132.77 198.66,132.77 199.01,132.42 199.19,132.42 199.37,132.6 199.37,132.78 199.02,133.13 199.02,133.31 199.2,133.48 199.38,133.48 199.7,133.17 199.88,133.17 200.06,133.35 200.06,133.53 v2(199.88,133.71) 199.74,133.84 199.74,134.02 200.81,135.09 204.67,135.09 204.8,135.22 204.8,139.08 204.96,139.24
MDB13: length 35.6
  BOTTOM w0.102: UV1.L4 191.84,126.31 192.21,126.31 192.34,126.19 192.62,126.19 192.65,126.21 192.81,126.21 192.88,126.28 193.53,126.28 193.72,126.47 194.39,126.47
  BOTTOM w0.127: 194.39,126.47 195.56,126.47 197.39,128.3 197.39,130.02 197.52,130.15 198.57,130.15 198.7,130.27 198.7,130.51 198.57,130.64 197.52,130.64 197.39,130.76 197.39,131.01 197.52,131.14 v2(197.94,131.14) 200.19,131.14 200.32,131.27 200.32,131.53 200.19,131.65 198.25,131.65 198.12,131.78 198.12,132.03 198.25,132.16 200.19,132.16 200.32,132.29 200.32,134.14 201.01,134.83 204.99,134.83 205.12,134.96 205.12,138.76 206.5,140.15 207.42,140.15 207.79,139.78 207.79,138.93 UV23.B8
MDB14: length 36.1
  BOTTOM w0.102: 205.69,138.25 206.13,138.25 206.25,138.13 206.93,138.13 UV23.C8 ; 194.39,126.21 193.75,126.21 193.61,126.08 192.96,126.08 192.89,126.01 192.73,126.01 192.71,125.98 192.25,125.98 192.16,126.08 190.65,126.08 UV1.M6
  BOTTOM w0.127: 194.39,126.21 195.67,126.21 197.65,128.2 197.65,129.76 197.78,129.89 200.45,129.89 200.58,130.02 200.58,130.24 200.45,130.37 v2(200.04,130.37) 199.09,130.37 198.96,130.5 198.96,130.75 199.09,130.88 200.45,130.88 200.58,131.01 200.58,134.03 201.12,134.57 204.86,134.57 204.99,134.45 204.99,134.18 204.88,134.07 203.15,134.07 203.03,133.94 203.03,133.71 203.15,133.59 205.31,133.59 205.44,133.71 205.44,138.13 205.56,138.25 205.69,138.25
MDB15: length 35.7
  BOTTOM w0.102: UV23.D7 207.75,137.3 206.13,137.3 ; UV1.M1 193.05,125.87 193.84,125.87 193.92,125.96
  BOTTOM w0.127: 193.92,125.96 195.78,125.96 197.91,128.09 197.91,128.36 198.03,128.49 200.08,128.49 200.21,128.61 200.21,128.87 200.08,128.99 v2(198.75,128.99) 198.03,128.99 197.91,129.12 197.91,129.38 198.03,129.5 201.68,129.5 201.8,129.63 201.8,131.37 201.68,131.5 201.44,131.5 201.31,131.37 201.31,130.06 201.18,129.94 200.97,129.94 200.84,130.06 200.84,133.93 201.1,134.19 202.64,134.19 202.77,134.07 202.77,133.46 202.9,133.33 205.57,133.33 205.7,133.46 205.7,136.87 206.13,137.3
MDB16: length 36.8
  TOP w0.102: UV22.H8 212.21,133.7 v1(212.55,134.04)
  IN3 w0.102: v1(212.55,134.04) 212.55,134.15 212.95,134.56 212.95,137.18 209.47,140.67
  IN3 w0.157: 209.47,140.67 209.29,140.84 204.71,140.84 197.94,134.07 197.94,127.72 v1(198.07,127.59)
  BOTTOM w0.102: UV1.M3 192.27,125.48 192.59,125.48 192.69,125.39 193,125.39 193.27,125.65 194.06,125.65 194.11,125.7 194.39,125.7
  BOTTOM w0.127: v1(198.07,127.59) 197.77,127.59 195.88,125.7 194.39,125.7
MDB17: length 37
  TOP w0.102: v1(212.56,135.73) 212.15,135.32 UV22.F8
  IN3 w0.102: 210.33,138.6 212.17,136.76 212.17,136.12 v1(212.56,135.73)
  IN3 w0.157: v1(198.48,128.07) 198.3,128.24 198.3,129.36 198.46,129.52 198.78,129.52 198.91,129.64 198.91,130.02 198.78,130.15 198.46,130.15 198.3,130.31 198.3,130.62 198.46,130.78 198.78,130.78 198.91,130.9 198.91,131.28 198.78,131.41 198.46,131.41 198.3,131.57 198.3,133.92 204.86,140.48 209.06,140.48 210.33,139.21 210.33,138.6
  BOTTOM w0.102: UV1.M5 191.26,125.63 191.67,125.23 192.53,125.23 192.59,125.17 193.09,125.17 193.35,125.44 194.39,125.44
  BOTTOM w0.127: 194.39,125.44 195.99,125.44 197.65,127.1 198.18,127.1 198.49,127.42 198.49,128.05 v1(198.48,128.07)
MDB18: length 37.3
  TOP w0.102: UV22.H7 211.36,133.7 v1(211.76,134.1)
  IN3 w0.102: 204.96,140.06 204.99,140.1 208.93,140.1 210.01,139.02 210.01,138.59 211.35,137.24 211.35,135.28 211.36,135.27 211.36,134.51 211.76,134.11 v1(211.76,134.1)
  IN3 w0.157: v1(199.02,127.59) 199.27,127.84 199.27,131.8 199.11,131.96 198.79,131.96 198.66,132.08 198.66,132.46 198.79,132.59 199.11,132.59 199.27,132.74 199.27,133.06 199.11,133.22 198.79,133.22 198.66,133.34 198.66,133.72 198.79,133.85 199.11,133.85 199.27,134 199.27,134.38 204.96,140.06
  BOTTOM w0.102: UV1.N4 191.66,124.72 191.77,124.62 192.27,124.62 192.34,124.54 192.55,124.54 192.62,124.6 193.67,124.6 194.12,125.06 194.39,125.06
  BOTTOM w0.127: v1(199.02,127.59) 199.02,127.58 198.28,126.84 197.76,126.84 195.98,125.06 v2(195.81,125.06) 194.39,125.06
MDB19: length 37.9
  TOP w0.102: UV22.F7 211.35,135.43 v1(210.82,135.97)
  IN3 w0.102: v1(210.82,135.97) 211.02,135.97 211.15,136.1 211.15,137.12 209.69,138.58 209.69,138.95 209.31,139.33 206.58,139.33 206.2,139.72 205.12,139.72 204.96,139.55
  IN3 w0.157: v1(199.63,127.52) 199.63,134.23 204.96,139.55
  BOTTOM w0.102: 194.39,124.68 194.03,124.68 193.75,124.4 192.73,124.4 192.61,124.27 192.32,124.27 192.18,124.41 190.59,124.41 UV1.P6
  BOTTOM w0.127: v1(199.63,127.52) 199.63,127.31 199.32,126.99 199.14,126.99 199.06,127.07 198.88,127.07 198.7,126.89 198.7,126.71 198.78,126.64 198.78,126.46 198.55,126.22 198.43,126.22 198.07,126.58 197.87,126.58 197.67,126.38 197.67,126.2 v2(198.01,125.86) 198.01,125.68 197.83,125.51 197.65,125.51 197.31,125.84 197.13,125.84 196.95,125.66 196.95,125.48 197.29,125.15 197.29,124.97 197.11,124.79 196.93,124.79 196.59,125.13 196.41,125.13 195.96,124.68 194.39,124.68
MDB20: length 37.5
  TOP w0.102: UV22.E3 208.81,136.1 209.27,136.57 v1(209.27,136.67)
  IN3 w0.102: 204.96,135.94 205.18,136.17 205.18,136.67 205.47,136.96 208.98,136.96 v1(209.27,136.67)
  IN3 w0.157: v1(201.51,128.67) 201.51,128.91 201.31,129.11 201.31,130.95 201.52,131.17 203.99,131.17 204.11,131.3 204.11,131.67 203.99,131.8 201.43,131.8 201.31,131.93 201.31,133.19 201.43,133.31 201.81,133.31 201.94,133.19 201.94,132.56 202.06,132.43 204.18,132.43 204.61,132.86 204.61,135.59 204.96,135.94 204.96,135.94
  BOTTOM w0.102: UV1.P5 191.63,124.09 191.94,123.79 192.45,123.79 192.65,123.58 193.07,123.58 193.19,123.7 193.69,123.7 193.92,123.47 194.39,123.47
  BOTTOM w0.127: 194.39,123.47 197.5,123.47 201.62,127.59 201.62,128.54 201.51,128.66 v1(201.51,128.67)
MDB21: length 37.2
  TOP w0.102: UV22.F2 207.35,135.33 v1(206.96,135.73)
  IN3 w0.102: v1(206.96,135.73) 206.96,135.45 206.83,135.32 206.6,135.32 206.48,135.45 206.48,135.99 206.35,136.12 205.77,136.12
  IN3 w0.157: v1(202.03,128.94) 202.28,128.68 202.55,128.68 202.67,128.81 202.67,129.42 202.8,129.55 205.12,129.55 205.25,129.67 205.25,130.05 205.12,130.18 201.79,130.18 201.67,130.3 201.67,130.68 201.79,130.81 204.83,130.81 204.96,130.93 204.96,131.8 205.11,131.95 205.6,131.95 205.73,132.08 205.73,132.46 205.6,132.58 205.11,132.58 204.96,132.74 204.96,133.18 205.11,133.34 205.88,133.34 206.01,133.47 206.01,133.84 205.88,133.97 205.11,133.97 204.96,134.13 204.96,134.64 205.08,134.76 205.52,134.76 205.64,134.89 205.64,135.99 205.77,136.12
  BOTTOM w0.102: 194.39,123.21 193.84,123.21 193.53,122.9 193.18,122.9 193.07,123 192.65,123 192.6,123 192.59,122.99 192.34,122.99 192.03,123.29 UV1.R4
  BOTTOM w0.127: v1(202.03,128.94) 202.03,128.63 201.88,128.49 201.88,127.48 197.61,123.21 194.39,123.21
MDB22: length 40.6
  TOP w0.102: v1(207.76,134.93) 207.35,134.52 UV22.G2
  IN3 w0.102: 206.54,131.99 206.54,134.34 206.71,134.51 207.65,134.51 207.76,134.62 v1(207.76,134.93)
  IN3 w0.157: v1(203.13,128.67) 203.13,129.06 203.26,129.19 205.29,129.19 205.66,129.56 205.66,131.56 205.82,131.72 206.26,131.72 206.54,131.99
  BOTTOM w0.102: 194.39,122.95 194.21,122.95 193.87,122.95 193.62,122.69 193.09,122.69 192.99,122.8 192.74,122.8 192.72,122.78 192.26,122.78 192.05,122.99 191.54,122.99 191.26,123.26 190.72,123.26 190.46,123.01 UV1.T6
  BOTTOM w0.127: 194.39,122.95 197.71,122.95 202.01,127.24 202.14,127.38 202.14,128.32 202.42,128.6 202.42,128.8 202.99,129.37 204.48,129.37 204.61,129.24 204.61,125.81 204.48,125.68 v2(203.15,125.68) 202.26,125.68 202.13,125.81 202.13,126.11 202.26,126.24 203.91,126.24 204.04,126.36 204.04,128.54 203.91,128.67 v1(203.13,128.67)
MDB23: length 37
  TOP w0.102: v1(208.55,134.1) 208.15,133.71 UV22.H3
  IN3 w0.157: v1(203.13,128.03) 203.13,127.83 203.26,127.71 203.74,127.71 203.87,127.83 203.87,128.67 204.03,128.83 204.34,128.83 204.5,128.67 204.5,127.65 204.63,127.52 205,127.52 205.13,127.65 205.13,128.67 205.29,128.83 205.6,128.83 205.76,128.67 205.76,127.83 205.89,127.71 206.95,127.71 207.66,128.41 207.66,129.73 207.5,129.89 206.2,129.89 206.07,130.02 206.07,130.39 206.2,130.52 207.5,130.52 207.66,130.68 207.66,130.99 207.5,131.15 206.93,131.15 206.77,131.31 206.77,131.62 206.93,131.78 207.5,131.78 207.66,131.94 207.66,132.65 208.55,133.54 208.76,133.54 208.95,133.73 210.26,133.73 210.39,133.86 210.39,134.37 210.26,134.49 208.91,134.49 208.55,134.13 v1(208.55,134.1)
  BOTTOM w0.102: 194.39,122.69 193.9,122.69 193.7,122.49 UV1.T1
  BOTTOM w0.127: v1(203.13,128.03) 202.64,128.03 202.4,127.79 202.4,127.24 197.85,122.69 194.39,122.69
MDB24: length 40.5
  IN1 w0.102: v1(190.94,122.88) 191.4,123.34 191.4,124.09 191.57,124.27 191.72,124.27 192.48,123.5 192.65,123.5 192.77,123.62 192.77,123.79 192,124.55 192,124.7 192.15,124.84 192.29,124.84 192.9,124.23 193.06,124.23 193.18,124.35 193.18,124.52 192.58,125.13 192.58,125.27 194.26,126.95 194.26,129.2 194.39,129.33 ; v1(212.56,134.94) 212.95,135.33 212.95,137.28 210.9,139.33 204.96,139.33
  IN1 w0.14: 194.39,129.33 204.39,139.33 204.96,139.33
  BOTTOM w0.102: UV23.G2 212.15,134.53 v1(212.56,134.94) ; v1(190.94,122.88) 190.95,122.88 190.96,122.89 191.34,122.89 191.66,122.57 UV1.U4
MDB25: length 41
  IN1 w0.102: v1(211.75,133.34) 212.15,133.74 212.15,134.18 212.44,134.47 212.64,134.47 213.73,135.56 213.73,137.46 212.94,138.26 212.48,138.26 210.64,140.1 204.96,140.1 ; v1(190.84,121.39) 190.54,121.69 190.54,124.06 192.23,125.75 192.23,126.67 193.9,128.35 193.9,129.33 194.39,129.82
  IN1 w0.14: 194.39,129.82 204.67,140.1 204.96,140.1
  BOTTOM w0.102: UV1.V6 190.54,121.09 v1(190.84,121.39) ; UV23.H3 211.39,133.7 v1(211.75,133.34)
MDB26: length 39.9
  IN1 w0.102: 204.96,138.25 206.14,138.25 206.58,137.81 206.78,137.81 206.88,137.91 206.88,138.09 206.99,138.19 207.19,138.19 207.29,138.09 207.29,137.91 207.39,137.81 210.64,137.81 211.34,137.11 211.34,136.15 v1(211.76,135.73)
  IN1 w0.14: 204.96,138.25 204.74,138.03 204.74,137.81 205.06,137.49 205.06,137.31 204.86,137.11 204.68,137.11 204,137.78 203.81,137.78 203.62,137.6 203.62,137.4 204.34,136.68 204.34,136.49 204.14,136.29 203.94,136.29 203.23,137 203.03,137 202.85,136.82 202.85,136.63 203.57,135.9 203.57,135.72 203.36,135.51 203.18,135.51 202.45,136.23 202.26,136.23 202.06,136.03 202.06,135.84 202.52,135.37 202.52,135.19 202.31,134.97 202.13,134.97 201.66,135.44 201.47,135.44 194.93,128.9 194.93,123.43 194.03,122.54 v1(194.03,121.97)
  BOTTOM w0.102: UV1.V1 192.86,120.99 193.42,121.55 193.62,121.55 194.03,121.97 v1(194.03,121.97) ; UV23.F2 212.15,135.33 v1(211.76,135.73)
MDB27: length 40.2
  IN1 w0.102: v1(211.76,136.53) 211.76,137.96 211.66,138.07 210.54,138.07 210.44,138.17 210.44,138.41 210.34,138.51 210.13,138.51 210.03,138.41 210.03,138.17 209.93,138.07 209.73,138.07 209.62,138.17 209.62,138.41 209.52,138.51 209.32,138.51 209.22,138.41 209.22,138.17 209.12,138.07 208.23,138.07 208.1,138.19 208.1,138.83 207.98,138.95 207.66,138.95 207.53,138.83 207.53,138.58 207.4,138.46 205.52,138.46 205.38,138.6 204.96,138.6 ; 194.39,123.46 193.72,122.79 191.59,122.79 191.47,122.67 191.47,122.5 191.59,122.38 192.81,122.38 192.94,122.25 v1(192.94,121.75)
  IN1 w0.14: 204.96,138.6 204.14,138.6 194.58,129.04 194.58,126.32 194.44,126.18 194.08,126.18 193.94,126.04 193.94,125.76 194.08,125.62 194.44,125.62 194.58,125.48 194.58,125.2 194.44,125.06 194.08,125.06 193.94,124.92 193.94,124.65 194.08,124.51 194.44,124.51 194.58,124.37 194.58,123.66 194.39,123.46
  BOTTOM w0.102: v1(192.94,121.75) 192.94,121.36 192.75,121.17 192.35,121.17 UV1.V3 ; UV23.E3 211.35,136.12 v1(211.76,136.53)
MDB28: length 40.8
  IN1 w0.102: 194.39,119.32 192.04,119.32 191.97,119.38 191.29,119.38 v1(190.91,119.76)
  IN1 w0.14: 194.39,119.32 194.51,119.32 194.64,119.19 194.64,118.13 194.77,118 195.06,118 195.2,118.14 195.2,118.7 195.33,118.83 195.63,118.83 195.76,118.7 195.76,118.14 195.9,118 199.86,118 199.99,118.13 199.99,124.88 200.54,125.43 200.54,125.67 200.35,125.86 200.15,125.86 199.99,125.69 199.81,125.69 199.59,125.91 199.59,126.09 199.76,126.25 199.76,126.45 199.47,126.74 197.46,126.74 197.27,126.93 197.27,127.94 198.33,129 200.49,129 203.11,131.62 203.31,131.62 204.05,130.87 204.23,130.87 204.45,131.09 204.45,131.27 203.7,132.01 203.7,132.21 205.55,134.06 v1(206.92,134.06)
  BOTTOM w0.102: v1(206.92,134.06) 207.28,133.7 UV23.H8 ; v1(190.91,119.76) 190.46,119.32 UV1.Y6
MDB29: length 39.9
  IN1 w0.14: v1(206.93,134.95) 206.42,134.45 205.45,134.45 201.04,130.03 200.8,130.03 199.93,130.91 199.75,130.91 199.53,130.69 199.53,130.51 200.3,129.74 200.3,129.56 200.09,129.34 199.91,129.34 199.3,129.95 198.79,129.95 196.92,128.08 196.92,126.79 197.78,125.93 197.98,125.93 198.45,126.39 198.63,126.39 198.84,126.18 198.84,126 198.38,125.53 198.38,125.34 198.57,125.14 198.77,125.14 199.24,125.6 199.42,125.6 199.63,125.39 199.63,125.21 199.17,124.74 199.17,124.55 199.64,124.07 199.64,118.51 199.52,118.38 197.55,118.38 197.42,118.51 197.42,119.14 197.3,119.27 196.93,119.27 196.8,119.14 196.8,118.51 196.67,118.38 196.36,118.38 196.23,118.51 196.23,119.53 196.1,119.66 193.58,119.66 v1(193.45,119.79)
  BOTTOM w0.102: v1(206.93,134.95) 207.28,135.3 UV23.F8 ; UV1.Y1 192.95,119.29 v1(193.45,119.79)
MDB30: length 40.5
  IN1 w0.102: v1(192.88,119.77) 193.29,120.18 194.39,120.18 ; v1(207.76,135.65) 207.44,135.34 205.85,135.34 205.82,135.3
  IN1 w0.14: 194.39,120.18 198.43,120.18 198.58,120.03 198.58,119.65 198.45,119.52 198.01,119.52 197.88,119.4 197.88,118.89 198.01,118.76 199.17,118.76 199.3,118.89 199.3,123.93 199.09,124.13 198.9,124.13 198.75,123.99 198.56,123.99 198.36,124.19 198.36,124.38 198.5,124.53 198.5,124.73 198.3,124.92 198.11,124.92 197.26,124.07 197.08,124.07 196.86,124.29 196.86,124.47 197.71,125.32 197.71,125.52 197.51,125.71 197.32,125.71 196.98,125.37 196.8,125.37 196.58,125.59 196.58,125.77 196.92,126.11 196.92,126.31 196.58,126.65 196.58,128.22 199.84,131.48 200.03,131.48 200.74,130.77 201.07,130.77 205.6,135.3 205.82,135.3
  BOTTOM w0.102: UV1.Y3 192.4,119.29 v1(192.88,119.77) ; UV23.F7 208.11,135.3 v1(207.76,135.65)
MDB31: length 40.3
  IN1 w0.102: 205.82,132.88 207.31,132.88 v1(207.76,133.33)
  IN1 w0.14: 205.82,132.88 205.52,132.88 205.37,132.73 205.37,131.53 204.09,130.24 203.89,130.24 203.32,130.82 203.14,130.82 202.92,130.6 202.92,130.42 203.5,129.85 203.5,129.65 203.3,129.45 203.1,129.45 202.36,130.19 202.17,130.19 200.63,128.66 198.47,128.66 197.61,127.8 197.61,127.27 197.8,127.08 199.61,127.08 200.88,125.81 200.88,125.29 200.33,124.74 200.33,117.75 200.2,117.62 194.38,117.62 194.24,117.76 194.24,118.11 194.1,118.25 193.82,118.25 193.68,118.11 193.68,117.76 193.54,117.62 191.8,117.62 191.67,117.75 v1(191.67,118.97)
  BOTTOM w0.102: UV1.Y5 191.35,119.29 v1(191.67,118.97) ; UV23.H7 208.13,133.7 v1(207.76,133.33)
MDB32: length 39.3
  TOP w0.102: v1(207.75,112.82) 208.15,113.22 UV25.H7
  IN3 w0.102: 204.96,114.51 206.25,114.51 206.75,114 207.16,114 207.38,113.78 207.38,113.19 v1(207.75,112.82)
  IN3 w0.157: 204.96,114.51 204.43,114.51 203.22,115.71 203.22,115.94 203.57,116.28 203.57,116.46 203.3,116.73 203.12,116.73 202.78,116.38 202.55,116.38 202.21,116.73 202.02,116.73 201.7,116.4 201.19,116.4 v1(200.86,116.73)
  BOTTOM w0.102: 194.39,119.77 193.97,119.77 193.19,118.99 192.47,118.99 191.98,118.49 UV1.AA4
  BOTTOM w0.127: v1(200.86,116.73) 200.86,117.13 200.99,117.26 203.3,117.26 203.43,117.39 203.43,119.19 203.3,119.32 202.87,119.32 202.74,119.45 202.74,120.73 202.62,120.86 202.36,120.86 202.24,120.73 202.24,119.45 202.11,119.32 201.86,119.32 201.73,119.45 v2(201.73,120.29) 201.73,121.18 201.6,121.31 201.35,121.31 201.22,121.18 201.22,119.45 201.09,119.32 200.84,119.32 200.71,119.45 200.71,121.56 200.59,121.68 200.33,121.68 200.2,121.56 200.2,121.24 200.08,121.11 199.82,121.11 199.7,121.24 199.7,121.49 199.57,121.62 194.64,121.62 194.51,121.49 194.51,119.9 194.39,119.77
MDB33: length 40.1
  TOP w0.102: v1(206.96,112.88) 207.3,113.22 UV25.H8
  IN3 w0.102: 204.96,114.01 206.32,114.01 206.51,113.82 206.51,113.33 v1(206.96,112.88)
  IN3 w0.157: v1(200.23,116.73) 200.91,116.04 202.38,116.04 204.42,114.01 204.96,114.01
  BOTTOM w0.102: 194.39,119.39 194.28,119.39 193.09,118.2 192.61,118.2 192.59,118.17 191,118.17 190.46,117.63 UV1.AB6
  BOTTOM w0.127: 194.39,119.39 194.65,119.39 194.77,119.52 194.77,121.23 194.9,121.36 197.21,121.36 197.34,121.23 197.34,120.93 197.47,120.8 197.72,120.8 197.85,120.93 197.85,121.23 197.97,121.36 198.23,121.36 198.35,121.23 198.35,119.19 198.48,119.06 198.74,119.06 198.86,119.19 198.86,121.23 198.99,121.36 199.24,121.36 199.37,121.23 v2(199.37,119.9) 199.37,119.19 199.5,119.06 199.75,119.06 199.88,119.19 199.88,120.73 200.01,120.85 200.26,120.85 200.39,120.73 200.39,119.19 200.51,119.06 203,119.06 203.17,118.89 203.17,117.64 203.04,117.52 200.36,117.52 200.23,117.39 v1(200.23,116.73)
MDB34: length 38.6
  TOP w0.102: UV25.F8 207.75,111.22 v1(207.75,111.19)
  IN3 w0.102: v1(207.75,111.19) 207.35,111.59 205.82,111.59 204.96,112.44
  IN3 w0.157: 204.96,112.44 202.08,115.32 200.23,115.32 199.73,115.82 199.17,115.82 v1(198.77,116.22)
  BOTTOM w0.102: 194.39,118.54 194.01,118.54 193.15,117.69 UV1.AB1
  BOTTOM w0.127: 194.39,118.54 195.17,118.54 195.3,118.67 195.3,120.72 195.42,120.84 195.68,120.84 195.8,120.72 195.8,118.67 195.93,118.54 196.19,118.54 196.31,118.67 196.31,120.41 196.44,120.54 196.69,120.54 196.82,120.41 196.82,118.67 196.95,118.54 202.52,118.54 202.65,118.42 202.65,118.16 202.52,118.04 197.41,118.04 197.28,117.91 197.28,117.65 197.41,117.53 v2(197.94,117.53) 198.64,117.53 198.77,117.4 v1(198.77,116.22)
MDB35: length 38.6
  TOP w0.102: v1(209.88,112.03) 209.47,111.62 UV25.F7
  IN3 w0.102: 204.96,112.95 205.5,112.41 208.99,112.41 209.01,112.44 209.47,112.44 v1(209.88,112.03)
  IN3 w0.157: v1(199.4,116.29) 199.77,116.29 200.38,115.68 202.23,115.68 204.96,112.95
  BOTTOM w0.102: 194.39,119.01 194.18,119.01 193.17,118 192.69,118 192.67,117.97 192.34,117.97 UV1.AB3
  BOTTOM w0.127: v1(199.4,116.29) 199.4,117.65 199.53,117.78 202.78,117.78 202.91,117.9 202.91,118.63 202.74,118.8 198.22,118.8 198.1,118.93 198.1,120.41 197.97,120.54 197.71,120.54 197.59,120.41 v2(197.59,119.78) 197.59,118.95 197.46,118.83 197.21,118.83 197.08,118.95 197.08,120.97 196.95,121.1 195.16,121.1 195.03,120.97 195.03,119.14 194.9,119.01 194.39,119.01
MDB36: length 35.9
  TOP w0.102: v1(212.55,111.19) 212.15,111.59 UV25.F2
  IN3 w0.102: 212.13,108.32 212.97,109.15 212.97,110.77
  IN3 w0.114: 212.97,110.77 v1(212.55,111.19)
  IN3 w0.157: v1(195.66,115.65) 195.66,110.88 199.97,106.57 200.19,106.57 200.78,107.16 200.96,107.16 201.23,106.9 201.23,106.72 200.78,106.27 200.78,106.09 201.06,105.8 201.24,105.8 201.62,106.19 201.94,106.19 202.45,105.68 209.5,105.68 212.13,108.32
  BOTTOM w0.102: UV1.AD6 191.03,115.89 191.14,115.79 191.63,115.79 191.83,115.58 192.34,115.58 192.54,115.78 193.42,115.78 193.43,115.77 194.39,115.77
  BOTTOM w0.127: 194.39,115.77 195.54,115.77 v1(195.66,115.65)
MDB37: length 34.8
  TOP w0.102: v1(211.75,111.99) 212.15,112.4 UV25.G2
  IN3 w0.102: 211.12,107.87 212.17,108.92 212.17,111.57 v1(211.75,111.99)
  IN3 w0.157: v1(196.25,115.65) 196.25,110.8 198.18,108.86 198.41,108.86 198.98,109.44 199.2,109.44 199.42,109.21 199.42,108.99 198.85,108.42 198.85,108.2 199.08,107.97 199.3,107.97 199.87,108.54 200.09,108.54 200.32,108.32 200.32,108.1 199.98,107.76 199.98,107.58 200.24,107.32 200.42,107.32 200.76,107.65 200.98,107.65 202.45,106.19 208.8,106.19 210.33,107.71 210.96,107.71 211.12,107.87
  BOTTOM w0.102: UV1.AD1 193.32,116.09 193.33,116.09 194.39,116.09
  BOTTOM w0.127: v1(196.25,115.65) 195.81,116.09 194.39,116.09
MDB38: length 35.8
  TOP w0.102: v1(210.24,110.25) 210.24,110.29 210.77,110.82 UV25.E3
  IN3 w0.102: v1(210.24,110.25) 210.24,108.9 208.94,107.6 204.96,107.6
  IN3 w0.157: 204.96,107.6 204.45,107.6 203.98,107.12 202.54,107.12 200.19,109.47 200.19,110.04 201,110.84 201,111.28 200.22,112.05 200,112.05 198.79,110.85 198.62,110.85 198.35,111.12 198.35,111.3 199.55,112.5 199.55,112.72 199.33,112.95 199.11,112.95 197.93,111.77 197.76,111.77 197.49,112.04 197.49,112.22 198.66,113.39 198.66,113.6 197.42,114.84 v1(197.42,115.65)
  BOTTOM w0.102: UV1.AD3 192.14,116.09 192.84,116.79 194.39,116.79
  BOTTOM w0.127: 194.39,116.79 195.85,116.79 196.3,116.33 196.75,116.33 197.42,115.66 v1(197.42,115.65)
MDB39: length 36.2
  TOP w0.102: UV25.H3 211.35,112.93 v1(210.82,112.4)
  IN3 w0.102: v1(210.82,112.4) 211.28,111.94 211.28,109.49 208.55,106.76 204.96,106.76
  IN3 w0.157: 204.96,106.76 202.39,106.76 199.49,109.66 199.49,109.84 200.58,110.93 200.58,111.11 200.31,111.38 200.13,111.38 198.52,109.77 198.3,109.77 197.95,110.12 197.95,110.34 198.17,110.57 198.17,110.79 196.83,112.12 v1(196.83,115.66)
  BOTTOM w0.102: 194.39,116.4 192.74,116.4 192.5,116.16 192.5,116.03 192.26,115.79 191.91,115.79 191.61,116.09 UV1.AD5
  BOTTOM w0.127: v1(196.83,115.66) 196.83,115.66 196.42,116.07 196.2,116.07 195.86,116.41 194.39,116.41 194.39,116.4
MDB40: length 35.6
  BOTTOM w0.102: 204.96,109.17 205.31,109.17 205.69,108.79 207.23,108.79 207.35,108.92 UV24.C2
  BOTTOM w0.127: 204.96,109.17 202.64,109.17 202.51,109.3 202.51,109.55 202.64,109.68 204.59,109.68 204.72,109.81 204.72,110.02 204.59,110.15 201.49,110.15 201.37,110.27 201.37,110.53 201.49,110.65 v2(202.9,110.65) 204.59,110.65 204.72,110.78 204.72,111.01 204.59,111.14 203.51,111.14 203.39,111.26 203.39,112.32 203.26,112.44 203.01,112.44 202.88,112.32 202.88,111.26 202.75,111.14 202.51,111.14 202.39,111.26 202.39,112.32 202.26,112.44 202.01,112.44 201.88,112.32 201.88,111.26 201.75,111.14 201.49,111.14 201.37,111.26 201.37,113.58 200.8,114.15 200.8,114.5 200.67,114.63 200.29,114.63 200.17,114.5 200.17,114.27 200.04,114.14 196.76,114.14 196.52,114.38 193.94,114.38 193.83,114.49 UV1.AF1
MDB41: length 36.1
  BOTTOM w0.102: UV1.AF3 192.43,114.13 193.69,114.13 193.7,114.12 194.39,114.12
  BOTTOM w0.127: 194.39,114.12 196.42,114.12 196.65,113.88 200.7,113.88 201.11,113.47 201.11,110.01 201.23,109.89 202.07,109.89 202.2,109.76 202.2,109.51 202.07,109.38 v2(201.56,109.38) 201.23,109.38 201.11,109.25 201.11,108.98 201.23,108.86 202.51,108.86 202.64,108.73 202.64,106.82 202.77,106.7 203.02,106.7 203.15,106.82 203.15,108.73 203.27,108.86 203.53,108.86 203.65,108.73 203.65,106.82 203.78,106.7 204.04,106.7 204.16,106.82 204.16,108.73 204.29,108.86 204.52,108.86 204.64,108.73 204.64,106.82 204.77,106.7 205.03,106.7 205.15,106.82 205.15,108.28 205.22,108.35 205.53,108.35 205.66,108.22 205.66,106.82 205.79,106.7 207.23,106.7 207.35,106.82 UV24.A2
MDB42: length 36.7
  BOTTOM w0.102: UV1.AF6 190.98,114.81 192.23,114.81 192.25,114.78 192.72,114.78 192.74,114.8 193.91,114.8 194.07,114.63 ; 205.11,109.68 207.66,109.68 207.79,109.55 207.79,107.75 207.91,107.62 UV24.A3
  BOTTOM w0.127: 205.11,109.68 204.98,109.81 204.98,110.71 205.11,110.84 205.53,110.84 205.65,110.96 205.65,112.58 205.53,112.7 205.3,112.7 205.17,112.58 205.17,111.52 205.04,111.4 204.79,111.4 204.66,111.52 204.66,112.58 204.53,112.7 204.28,112.7 204.15,112.58 204.15,111.52 204.03,111.4 203.77,111.4 203.65,111.52 203.65,112.58 203.52,112.7 201.75,112.7 201.63,112.83 201.63,113.69 201.05,114.26 201.05,115.21 201.18,115.33 201.61,115.33 201.73,115.46 201.73,116.18 201.61,116.31 v2(201.44,116.31) 201.25,116.31 201.13,116.18 201.13,115.9 201,115.78 200.74,115.78 200.62,115.9 200.62,116.18 200.49,116.31 200.02,116.31 199.89,116.18 199.89,115.53 200.02,115.4 200.48,115.4 200.61,115.27 200.61,115.02 200.48,114.89 200.02,114.89 199.89,114.76 199.89,114.52 199.77,114.4 196.87,114.4 196.63,114.63 194.07,114.63
MDB43: length 36.3
  BOTTOM w0.102: UV1.AG4 191.99,113.69 192.3,113.39 192.59,113.39 192.6,113.4 192.6,113.4 192.6,113.41 193.1,113.41 193.19,113.33 193.6,113.33 194.13,113.86 194.39,113.86
  BOTTOM w0.127: UV24.C3 208.31,109.22 209.06,108.47 209.06,107.59 208.93,107.46 208.61,107.46 208.48,107.33 208.48,107.08 208.61,106.95 208.86,106.95 208.99,106.82 208.99,106.56 208.86,106.44 208.23,106.44 208.1,106.56 208.1,107.01 207.98,107.14 207.79,107.14 207.66,107.01 207.66,105.94 207.53,105.81 207.28,105.81 207.15,105.94 207.15,106.31 207.02,106.44 206.71,106.44 206.58,106.31 206.58,105.94 206.45,105.81 206.2,105.81 206.07,105.94 206.07,106.31 205.94,106.44 205.69,106.44 205.56,106.31 205.56,105.94 205.44,105.81 205.18,105.81 205.05,105.94 205.05,106.31 204.93,106.44 202.51,106.44 202.38,106.56 202.38,107.48 202.25,107.61 202.02,107.61 201.9,107.48 201.9,107.19 201.77,107.07 v2(201.56,107.07) 201.37,107.07 201.24,107.19 201.24,107.48 201.12,107.61 200.98,107.61 200.85,107.73 200.85,107.99 200.98,108.11 202.25,108.11 202.38,108.24 202.38,108.47 202.25,108.6 200.98,108.6 200.85,108.72 200.85,113.37 200.59,113.62 196.55,113.62 196.31,113.86 194.39,113.86
MDB44: length 36.2
  BOTTOM w0.102: UV24.D7 211.69,110.02 211.82,109.89 211.82,108.16 211.69,108.03 211.28,108.03 210.9,107.65 210.9,106.33 210.82,106.26 ; 194.39,112.1 194.02,112.1 193.69,112.44 193.18,112.44 193.12,112.37 192.61,112.37 192.42,112.56 191.92,112.56 191.65,112.84 191.32,112.84 UV1.AH5
  BOTTOM w0.127: 210.82,106.26 208.85,104.28 201.84,104.28 199.38,106.74 199.38,109.49 199.25,109.62 197.94,109.62 197.82,109.74 197.82,110 197.94,110.12 v2(198.45,110.12) 199.25,110.12 199.38,110.25 199.38,110.51 199.25,110.63 196.03,110.63 195.9,110.76 195.9,111.97 195.77,112.1 195.48,112.1 195.36,111.97 195.36,111.27 195.23,111.15 194.97,111.15 194.85,111.27 194.85,111.97 194.72,112.1 194.39,112.1
MDB45: length 36.4
  BOTTOM w0.102: 194.39,111.37 194.18,111.57 193.32,111.57 193.09,111.8 192.64,111.8 192.61,111.78 192.27,111.78 192.11,111.93 192.11,112.07 191.6,112.59 191.02,112.59 190.89,112.71 190.89,112.98 190.77,113.11 190.32,113.11 190.2,112.98 190.2,112.82 190.32,112.69 UV1.AH6 ; UV24.A7 211.35,106.42 211.19,106.26
  BOTTOM w0.127: 194.39,111.37 196.03,109.72 196.21,109.72 196.86,110.37 197.04,110.37 197.22,110.19 197.22,110.01 196.57,109.37 196.57,109.19 196.75,109.01 196.93,109.01 197.47,109.54 197.65,109.54 197.83,109.37 197.83,109.19 197.29,108.65 197.29,108.47 197.47,108.29 197.65,108.29 198.72,109.36 198.9,109.36 199.08,109.18 199.08,109 198.01,107.93 198.01,107.75 198.19,107.57 198.37,107.57 v2(198.58,107.78) 198.76,107.96 198.94,107.96 199.12,107.78 199.12,107.6 198.73,107.21 198.73,107.03 201.85,103.9 208.84,103.9 211.19,106.26
MDB46: length 36.1
  BOTTOM w0.102: 211.79,106.48 211.79,107.84 212.15,108.21 UV24.B8 ; UV1.AJ4 191.67,112.09 192.19,111.57 192.7,111.57 192.72,111.6 193.01,111.6 193.27,111.33 194.06,111.33 194.39,111
  BOTTOM w0.127: 194.39,111 199.76,105.63 199.76,105.45 199.37,105.07 199.37,104.89 199.55,104.71 199.73,104.71 200.12,105.09 200.3,105.09 200.48,104.91 200.48,104.73 199.39,103.65 199.39,103.47 199.57,103.29 199.75,103.29 200.84,104.37 201.01,104.37 201.19,104.19 201.19,104.01 200.56,103.38 200.56,103.2 200.74,103.02 200.92,103.02 v2(201.36,103.46) 201.54,103.64 208.95,103.64 210.44,105.14 210.62,105.14 211,104.75 211.18,104.75 211.36,104.93 211.36,105.11 210.98,105.5 210.98,105.68 211.16,105.85 211.34,105.85 211.72,105.47 211.9,105.47 212.08,105.65 212.08,105.83 211.7,106.21 211.7,106.39 211.79,106.48
MDB47: length 35.2
  BOTTOM w0.102: 194.39,110.39 193.66,110.39 193.41,110.64 193.41,110.73 193.22,110.92 193.11,110.92 193.08,110.95 192.7,110.95 192.36,111.29 UV1.AK3 ; 213.06,106.26 213.74,106.93 213.74,108.24 213.18,108.79 212.58,108.79 UV24.C8
  BOTTOM w0.127: 194.39,110.39 194.63,110.39 199.09,105.93 199.09,103.01 199.34,102.76 v2(199.53,102.76) 201.74,102.76 201.86,102.89 201.86,103.26 201.99,103.38 202.24,103.38 202.37,103.26 202.37,102.89 202.5,102.76 202.75,102.76 202.88,102.89 202.88,103.26 203.01,103.38 203.26,103.38 203.39,103.26 203.39,102.89 203.51,102.76 203.77,102.76 203.9,102.89 203.9,103.26 204.02,103.38 204.28,103.38 204.4,103.26 204.4,102.82 204.53,102.7 204.78,102.7 204.91,102.82 204.91,103.26 205.04,103.38 210.19,103.38 213.06,106.26
MDB48: length 37.6
  IN1 w0.102: v1(188.99,113.97) 189.46,114.44 190.26,114.44 190.58,114.76 194.39,114.76 ; v1(206.95,111.98) 206.52,112.41 204.96,112.41
  IN1 w0.14: 204.96,112.41 204.89,112.34 204.89,110.98 204.76,110.85 204.48,110.85 204.36,110.98 204.36,114.75 204.23,114.88 203.91,114.88 203.78,114.75 203.78,110.98 203.66,110.85 203.34,110.85 203.21,110.98 203.21,115.31 203.09,115.43 202.71,115.43 202.58,115.31 202.58,114.19 202.45,114.06 199.19,114.06 199.05,114.2 199.05,114.32 198.91,114.46 198.63,114.46 198.49,114.32 198.49,114.2 198.35,114.06 198.08,114.06 197.94,114.2 197.94,114.32 197.8,114.46 197.52,114.46 197.38,114.32 197.38,114.2 197.24,114.06 196.96,114.06 196.82,114.2 196.82,115.02 196.69,115.14 196.39,115.14 196.26,115.02 196.26,114.2 196.12,114.06 195.78,114.06 195.08,114.76 194.39,114.76
  BOTTOM w0.102: v1(206.95,111.98) 207.35,112.39 UV24.G2 ; v1(188.99,113.97) 188.86,114.1 UV1.AF8
MDB49: length 37.9
  IN1 w0.102: 205.82,114.09 206.29,114.09 206.38,114 207.34,114 v1(207.76,113.58) ; v1(188.32,114.01) 189.01,114.7 190.08,114.7 190.61,115.23
  IN1 w0.14: 205.82,114.09 205.63,113.9 205.63,112.88 205.5,112.75 204.83,112.75 204.7,112.88 204.7,114.89 203.81,115.78 202.32,115.78 202.2,115.65 202.2,114.53 202.07,114.4 201.2,114.4 201.07,114.53 201.07,116.17 200.95,116.3 200.61,116.3 200.48,116.17 200.48,114.53 200.36,114.4 199.97,114.4 199.85,114.53 199.85,115.19 199.72,115.32 198.2,115.32 198.07,115.45 198.07,116.98 197.94,117.11 197.63,117.11 197.5,116.98 197.5,116.29 197.37,116.16 197.05,116.16 196.93,116.29 196.93,116.98 196.8,117.11 196.48,117.11 196.36,116.98 196.36,116.29 196.23,116.16 195.28,116.16 195.16,116.03 195.16,115.24 195.02,115.1 194.74,115.1 194.6,115.24 194.6,116.03 194.47,116.16 194.16,116.16 194.04,116.03 194.04,115.24 193.9,115.1 193.62,115.1 193.48,115.24 193.48,115.67 193.31,115.84 191.22,115.84 190.61,115.23
  BOTTOM w0.102: UV24.H3 208.12,113.22 v1(207.76,113.58) ; v1(188.32,114.01) 188.06,114.27 UV1.AF9
MDB50: length 37.5
  IN1 w0.102: 194.39,114.25 194.09,114.25 193.9,114.44 190.7,114.44 v1(189,112.75) ; 204.96,110.57 205.31,110.92 205.31,111.46 205.44,111.59 207.21,111.59 207.34,111.46 207.34,111.32 207.21,111.19 v1(206.95,111.19)
  IN1 w0.14: 204.96,110.57 204.9,110.51 203.59,110.51 203.47,110.38 203.47,110.06 203.59,109.94 204.52,109.94 204.65,109.81 204.65,109.54 204.52,109.41 203,109.41 202.87,109.54 202.87,113.54 202.73,113.68 202.45,113.68 202.31,113.54 202.31,109.54 202.19,109.41 201.88,109.41 201.75,109.54 201.75,113.54 201.61,113.68 195.53,113.68 194.96,114.25 194.39,114.25
  BOTTOM w0.102: v1(189,112.75) 188.86,112.89 UV1.AG8 ; v1(206.95,111.19) 207.35,111.6 UV24.F2
MDB51: length 37.2
  IN1 w0.102: 194.39,113.43 193.69,114.12 190.82,114.12 189.56,112.86 v1(189.56,112.75) ; 204.96,109.36 205.58,109.98 208.14,109.98 v1(208.55,110.39)
  IN1 w0.14: 204.96,109.36 204.67,109.07 201.4,109.07 201.27,109.19 201.27,113.21 201.14,113.34 200.84,113.34 200.71,113.21 200.71,109.19 200.59,109.07 200.28,109.07 200.15,109.19 200.15,111.87 200.02,112 198.58,112 198.45,112.13 198.45,112.54 198.58,112.67 200.04,112.67 200.17,112.79 200.17,113.21 200.04,113.34 194.48,113.34 194.39,113.43
  BOTTOM w0.102: v1(208.55,110.39) 208.15,110.79 UV24.E3 ; v1(189.56,112.75) 189.66,112.85 UV1.AG7
MDB52: length 36.7
  IN1 w0.102: v1(211.75,111.27) 211.33,110.85 211.33,109.55 208.61,106.84 204.96,106.84 ; v1(189.27,111.47) 189.27,111.37 191.4,109.24 193.31,109.24
  IN1 w0.14: 193.31,109.24 194.13,109.24 194.27,109.1 194.27,107.56 194.41,107.42 194.69,107.42 194.83,107.56 194.83,109.1 194.97,109.24 195.25,109.24 195.39,109.1 195.39,107.56 195.53,107.42 195.81,107.42 195.94,107.56 195.94,109.1 196.08,109.24 196.36,109.24 196.5,109.1 196.5,107.56 196.64,107.42 201.37,107.42 201.49,107.29 201.49,106.96 201.62,106.84 204.96,106.84
  BOTTOM w0.102: v1(189.27,111.47) 188.74,111.47 188.36,111.09 UV1.AK9 ; UV24.F7 211.4,111.62 v1(211.75,111.27)
MDB53: length 36.1
  IN1 w0.102: 211.72,106.26 212.17,106.7 212.17,109.1 213.01,109.94 213.01,111.54 v1(212.58,111.97) ; v1(190.07,109.89) 189.69,109.51 189.69,107.71 191.25,106.15 191.34,106.15
  IN1 w0.14: 191.34,106.15 191.5,106.15 191.64,106.29 191.64,106.62 191.78,106.76 192.06,106.76 192.2,106.62 192.2,106.29 192.34,106.15 192.62,106.15 192.76,106.29 192.76,106.62 192.9,106.76 193.18,106.76 193.32,106.62 193.32,106.29 193.46,106.15 193.74,106.15 193.88,106.29 193.88,106.61 194,106.73 194.32,106.73 194.45,106.61 194.45,106.28 194.58,106.15 194.85,106.15 194.99,106.29 194.99,106.61 195.12,106.73 195.42,106.73 195.55,106.61 195.55,106.29 195.69,106.15 211.62,106.15 211.72,106.26
  BOTTOM w0.102: v1(190.07,109.89) 189.67,110.29 UV1.AL7 ; UV24.F8 212.5,111.97 v1(212.58,111.97)
MDB54: length 35.8
  IN1 w0.102: 212.24,106.26 213.93,107.95 213.93,112 213.07,112.86 v1(212.59,112.86) ; 194.39,105.81 191.15,105.81 188.8,108.16 188.8,109.43 v1(189.27,109.89)
  IN1 w0.14: 194.39,105.81 211.79,105.81 212.24,106.26
  BOTTOM w0.102: UV1.AM8 v1(189.27,109.89) ; v1(212.59,112.86) 212.23,113.22 UV24.H8
MDB55: length 35.7
  IN1 w0.102: v1(211.75,113.59) 212.01,113.59 212.14,113.47 212.14,109.84 211.89,109.59 211.89,106.8 211.58,106.49 204.96,106.49 ; 194.39,107.08 190.77,107.08 190.08,107.76 v1(190.08,109.14)
  IN1 w0.14: 204.96,106.49 201.29,106.49 201.15,106.63 201.15,106.94 201.01,107.08 200.73,107.08 200.59,106.94 200.59,106.63 200.45,106.49 200.17,106.49 200.03,106.63 200.03,106.94 199.9,107.08 199.62,107.08 199.48,106.94 199.48,106.63 199.34,106.49 199.06,106.49 198.92,106.63 198.92,106.94 198.78,107.08 198.5,107.08 198.36,106.94 198.36,106.63 198.22,106.49 197.94,106.49 197.8,106.63 197.8,106.94 197.66,107.08 197.38,107.08 197.24,106.94 197.24,106.63 197.1,106.49 196.82,106.49 196.68,106.63 196.68,106.94 196.54,107.08 194.39,107.08
  BOTTOM w0.102: v1(211.75,113.59) 211.37,113.22 UV24.H7 ; UV1.AM7 189.73,109.49 v1(190.08,109.14)
MDB56: length 35.1
  TOP w0.102: UV25.B8 207.35,108.25 207.74,107.86 207.74,107.28 207.15,106.7 204.97,106.7 204.96,106.7
  TOP w0.127: 204.96,106.7 204.47,106.7 204.35,106.83 204.35,113.74 204.22,113.86 199.16,113.86 199.03,113.74 199.03,112.09 198.91,111.97 198.65,111.97 198.52,112.09 v2(198.52,112.67) 198.52,113.74 198.4,113.86 198.14,113.86 198.02,113.74 198.02,110.64 197.89,110.51 197.64,110.51 197.51,110.64 197.51,112.85 197.38,112.98 197.13,112.98 197,112.85 197,110.64 196.87,110.51 194.08,110.51 v1(193.79,110.8)
  BOTTOM w0.102: UV1.AK1 193.02,111.29 193.19,111.12 193.46,111.12 v1(193.79,110.8)
MDB57: length 35.6
  TOP w0.102: 194.39,110.24 193.81,110.24 193.41,110.64 193.41,110.8 193.2,111.01 192.28,111.01 v1(192.07,110.8) ; UV25.A7 208.15,107.32 207.28,106.44 204.96,106.44
  TOP w0.127: 194.39,110.24 198.15,110.24 198.28,110.36 198.28,111.58 198.4,111.71 198.66,111.71 198.78,111.58 198.78,110.23 198.91,110.1 199.16,110.1 199.29,110.23 199.29,113.48 199.42,113.6 199.67,113.6 199.8,113.48 199.8,111.25 199.93,111.12 200.18,111.12 200.31,111.25 v2(200.31,111.97) 200.31,113.48 200.43,113.6 203.96,113.6 204.09,113.48 204.09,106.57 204.21,106.44 204.96,106.44
  BOTTOM w0.102: UV1.AL4 191.76,110.49 v1(192.07,110.8)
MDB58: length 35.9
  TOP w0.102: 194.39,110.95 194.01,111.33 190.77,111.33 190.59,111.16 190.59,110.2 190.86,109.92 v1(190.86,109.22) ; 204.96,108.79 206.93,108.79 UV25.C8
  TOP w0.127: 204.96,108.79 204.61,109.15 204.61,113.99 204.48,114.12 197.88,114.12 197.76,113.99 197.76,113.36 197.63,113.24 197.38,113.24 197.25,113.36 197.25,113.99 197.12,114.12 196.87,114.12 196.74,113.99 v2(196.74,113.55) 196.74,110.9 196.61,110.77 196.36,110.77 196.23,110.9 196.23,113.99 196.11,114.12 195.85,114.12 195.73,113.99 195.73,110.9 195.6,110.77 194.57,110.77 194.39,110.95
  BOTTOM w0.102: v1(190.86,109.22) 190.59,109.49 UV1.AM6
MDB59: length 35
  TOP w0.102: v1(193.49,108.45) 193.68,108.64 194.39,108.64 ; UV25.C3 210.96,109.22 210.26,108.52 210.26,106.26
  TOP w0.127: 194.39,108.64 200.46,108.64 200.59,108.51 200.59,105.81 200.71,105.68 200.97,105.68 201.09,105.81 v2(201.09,108.03) 201.09,108.51 201.22,108.64 201.48,108.64 201.6,108.51 201.6,105.1 201.73,104.97 201.98,104.97 202.11,105.1 202.11,106.56 202.24,106.69 202.49,106.69 202.62,106.56 202.62,105.1 202.75,104.97 209.13,104.97 210.26,106.11 210.26,106.26
  BOTTOM w0.102: UV1.AM1 192.99,109.69 193.49,109.19 v1(193.49,108.45)
MDB60: length 35.6
  TOP w0.102: 194.39,107.95 193.76,107.95 193.64,108.07 192.79,108.07 v1(192.46,108.4) ; 210.96,106.26 211.35,106.65 UV25.A3
  TOP w0.127: 194.39,107.95 196.83,107.95 196.95,107.82 196.95,107.42 197.08,107.3 197.34,107.3 197.46,107.42 197.46,107.82 197.59,107.95 197.89,107.95 198.02,107.82 198.02,106.36 198.15,106.23 198.4,106.23 198.53,106.36 198.53,107.82 198.66,107.95 198.91,107.95 199.04,107.82 v2(199.04,107.2) 199.04,105.34 199.16,105.21 199.42,105.21 199.55,105.34 199.55,107.97 199.67,108.09 199.93,108.09 200.05,107.97 200.05,104.84 200.18,104.72 200.43,104.72 200.56,104.84 200.56,105.24 200.69,105.36 200.94,105.36 201.07,105.24 201.07,104.84 201.2,104.72 209.42,104.72 210.96,106.26
  BOTTOM w0.102: v1(192.46,108.4) 192.44,108.42 192.14,108.42 UV1.AN4
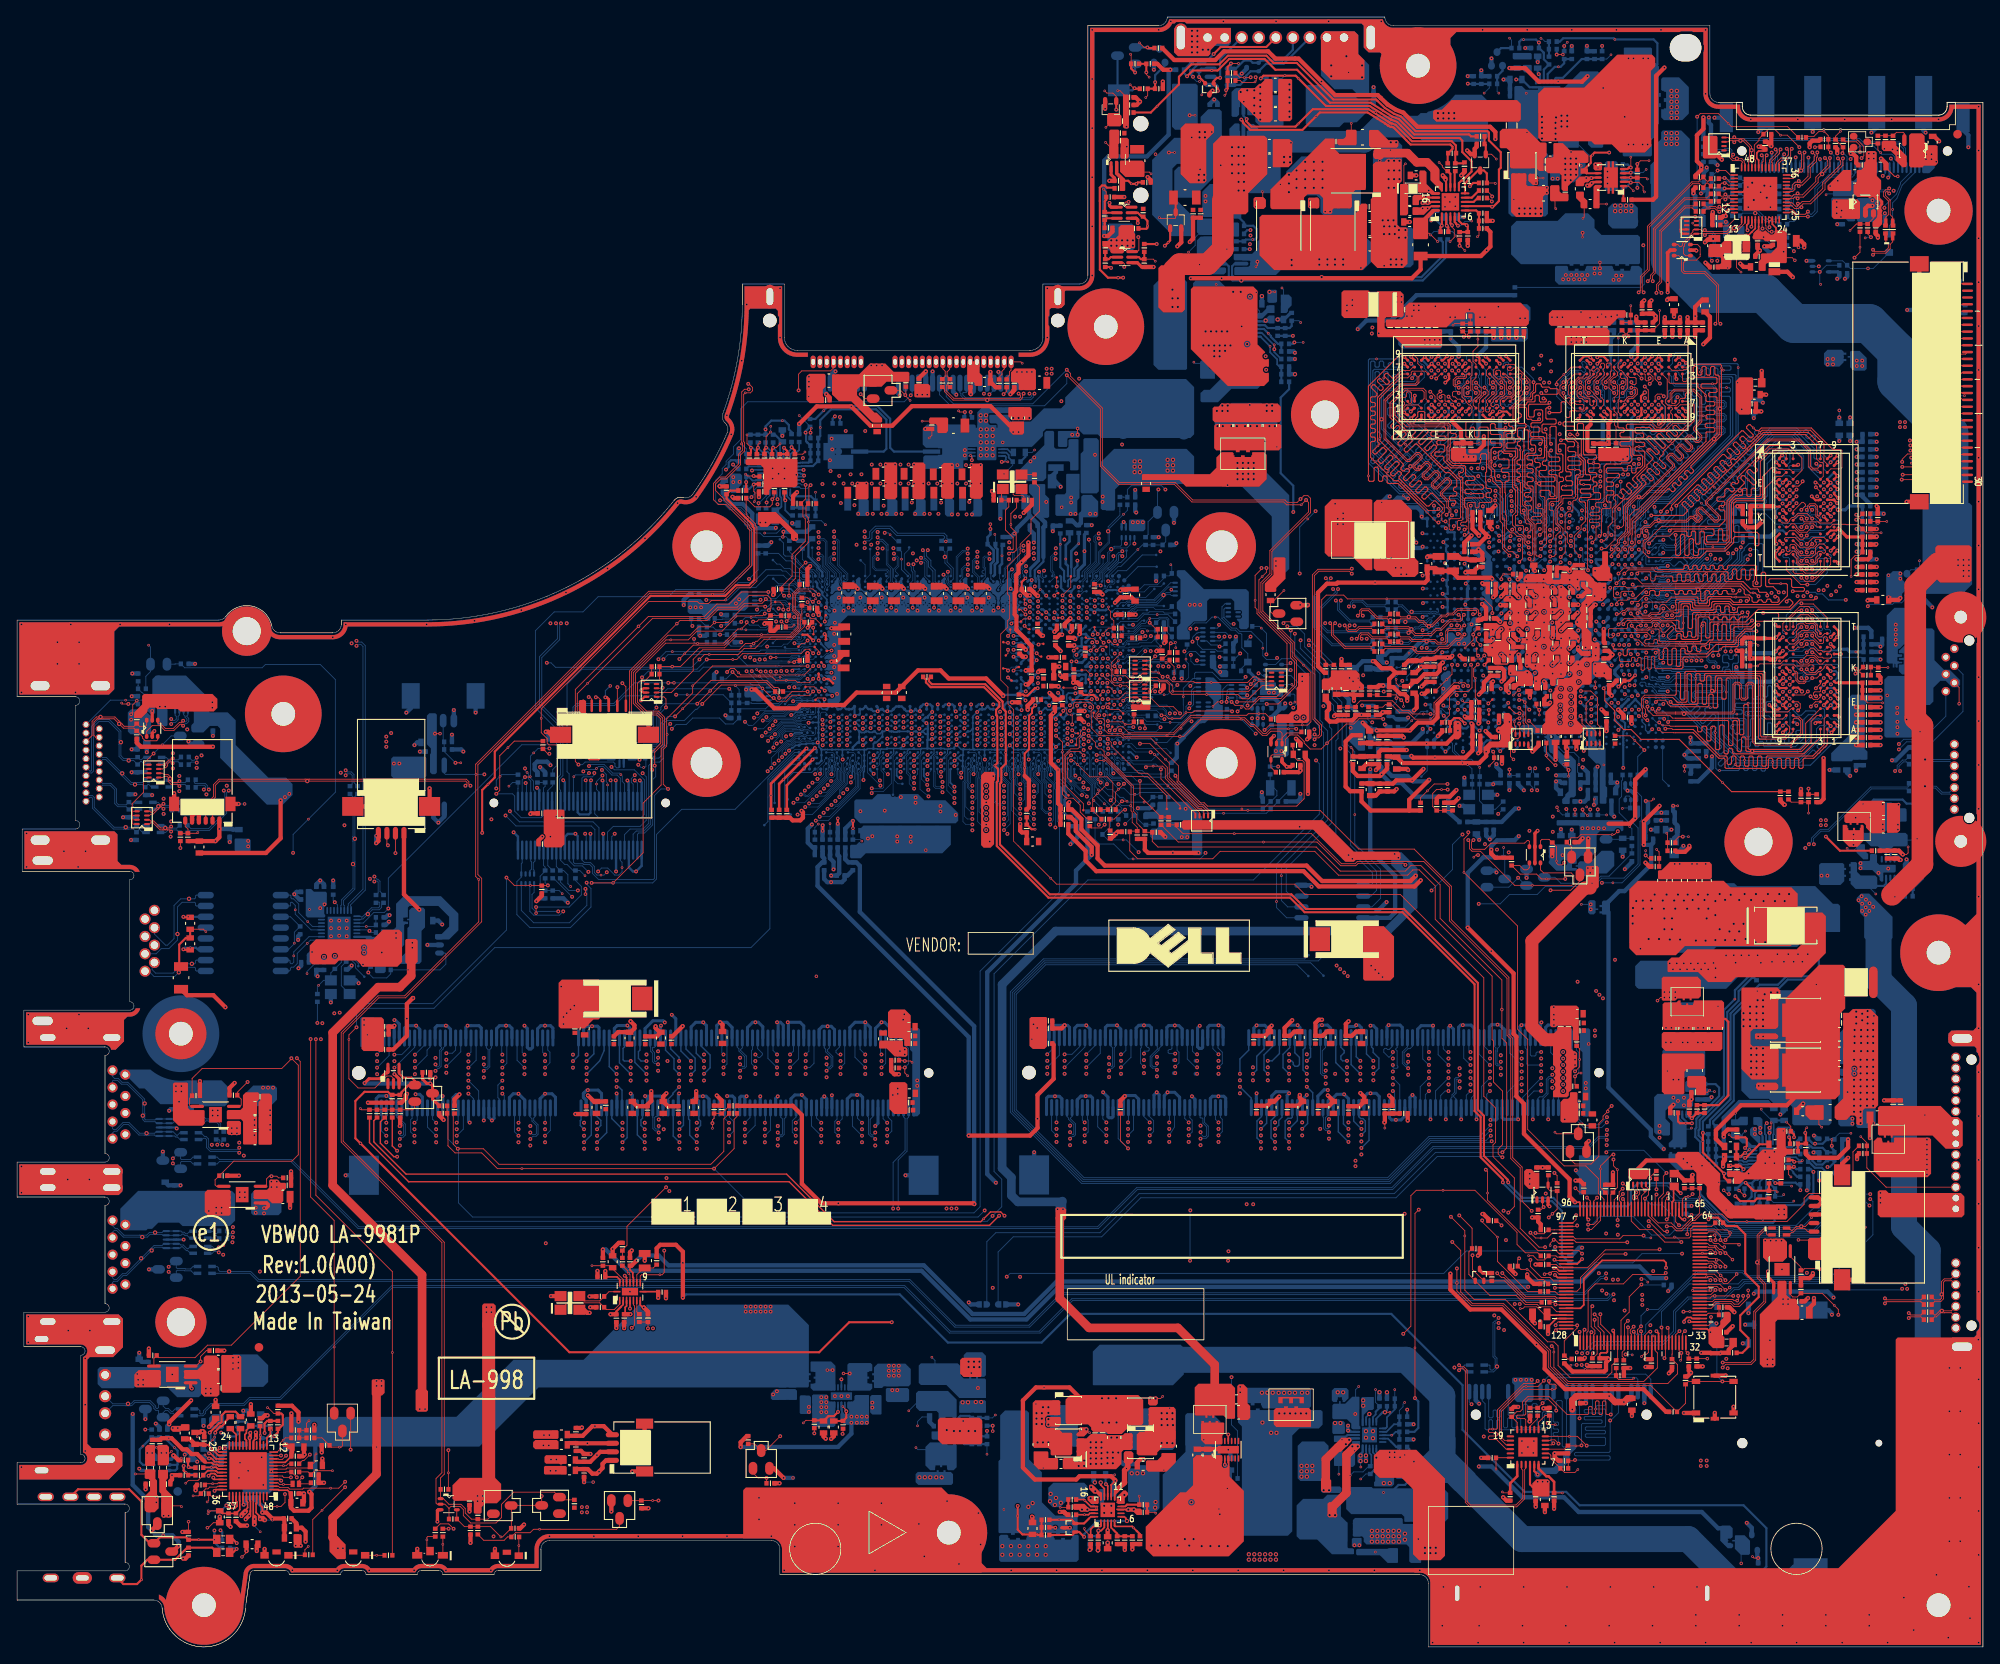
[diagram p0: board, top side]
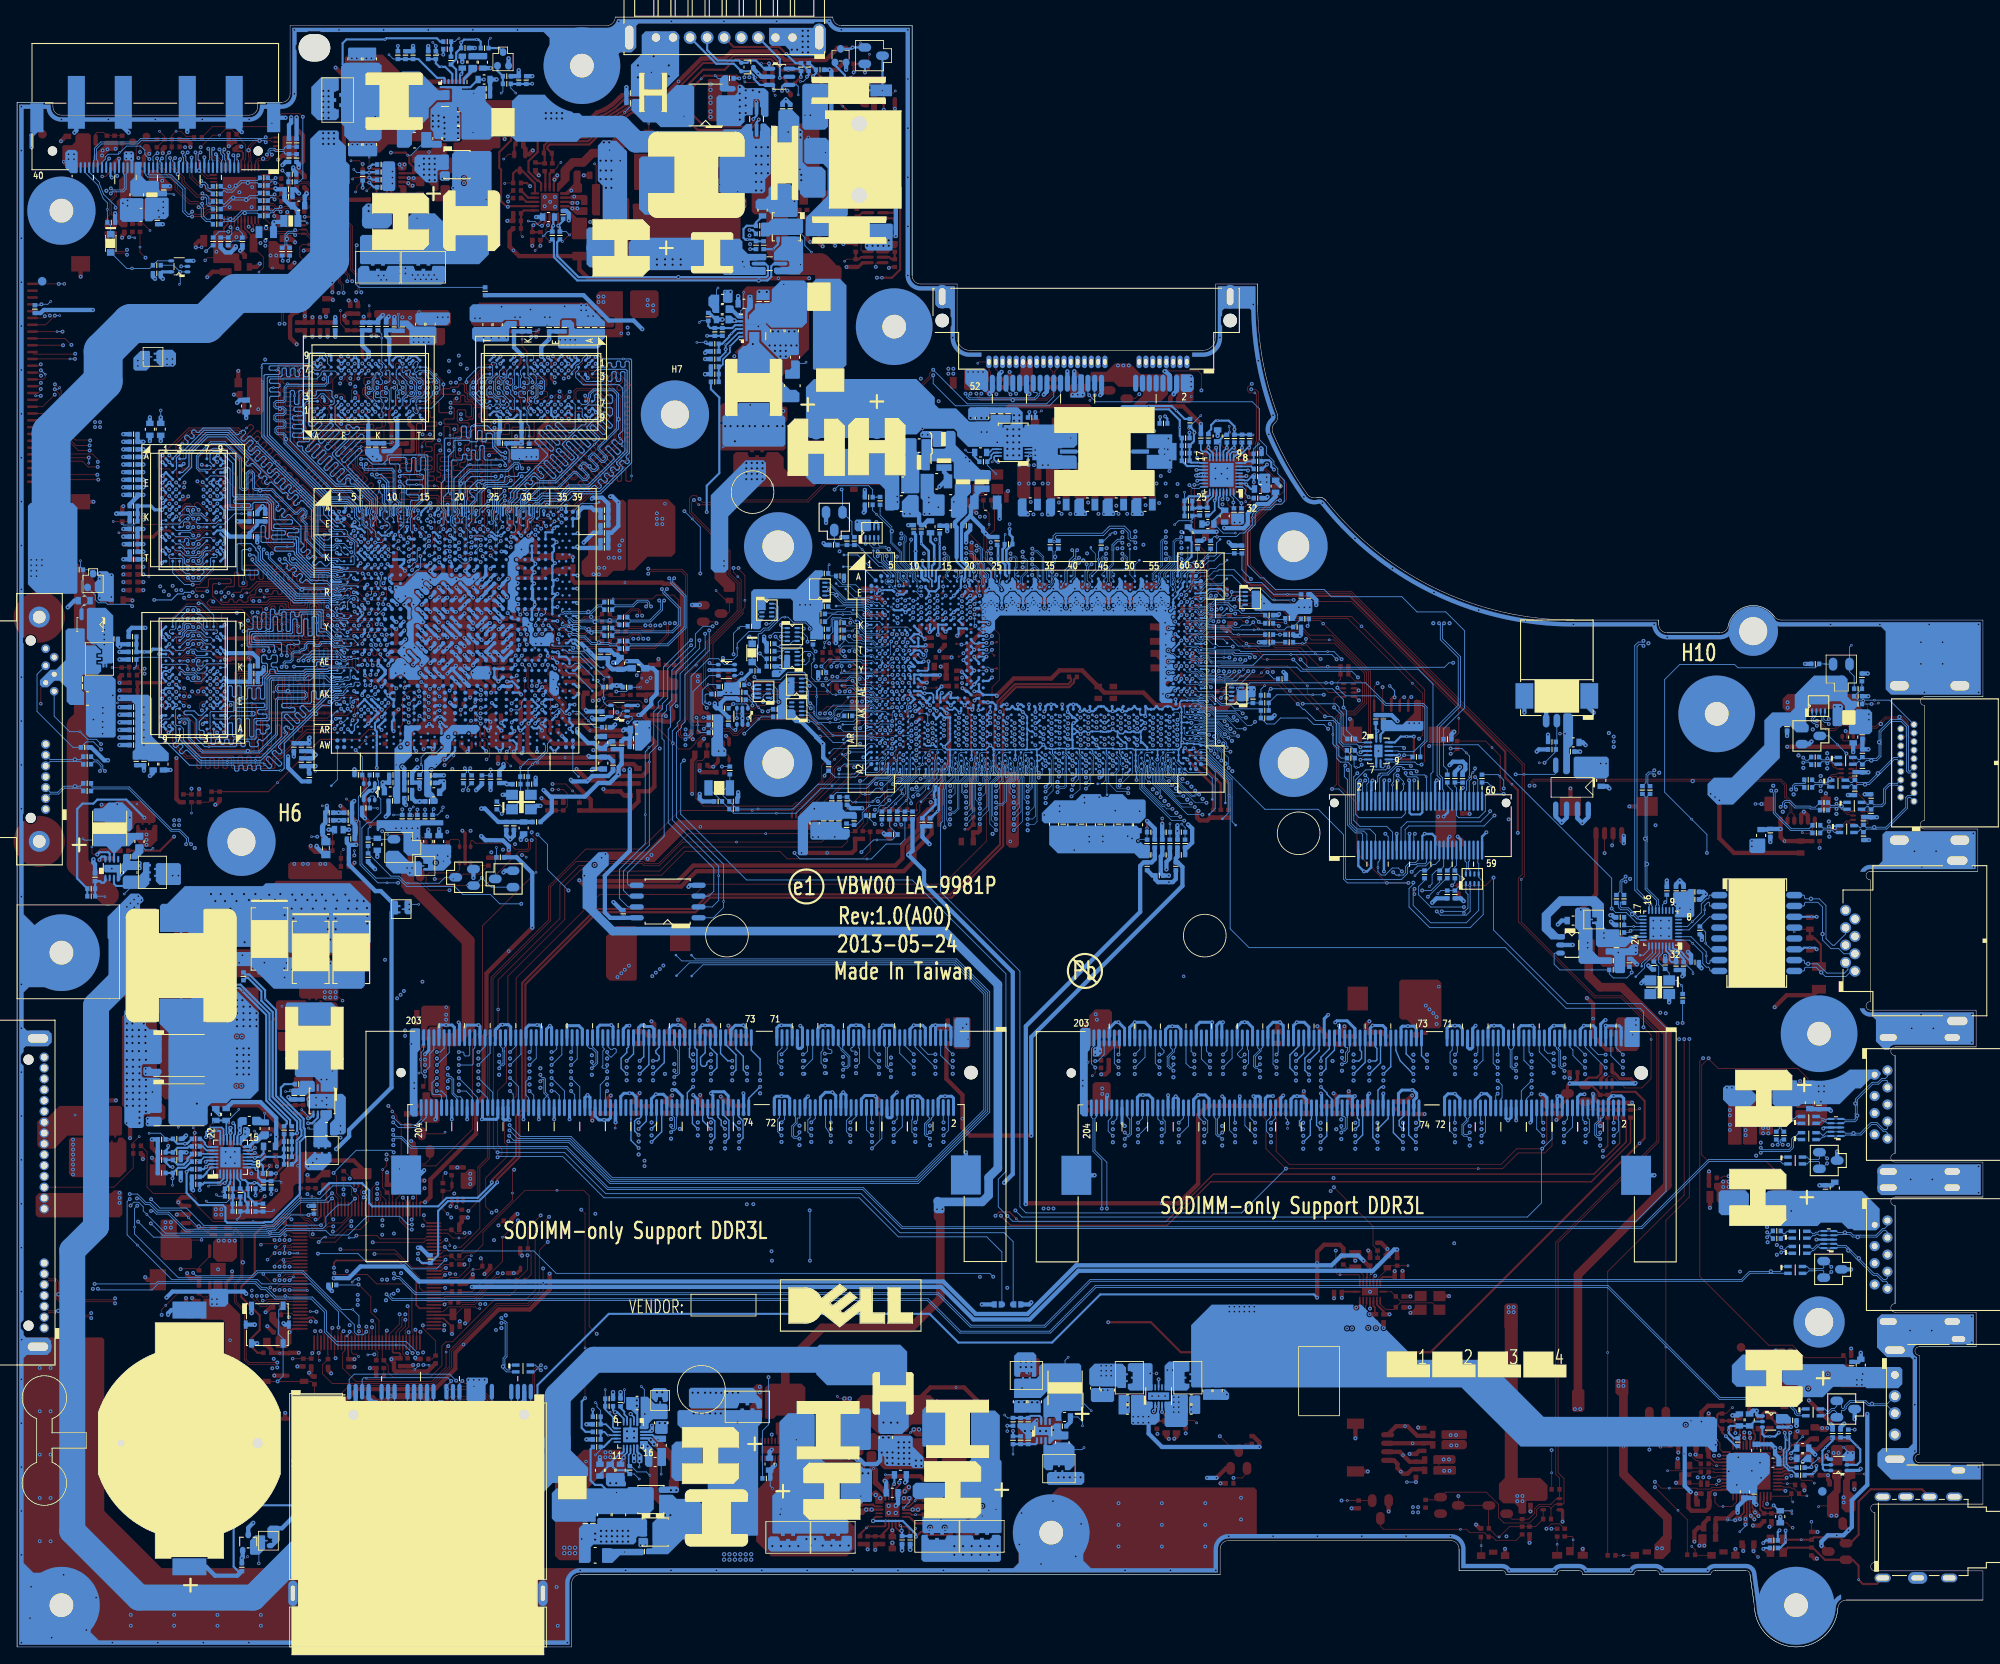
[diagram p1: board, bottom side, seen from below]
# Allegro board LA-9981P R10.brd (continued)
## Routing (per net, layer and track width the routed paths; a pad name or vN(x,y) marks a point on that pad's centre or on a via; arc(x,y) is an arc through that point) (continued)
MDB61: length 34.7
  TOP w0.102: 194.39,107.19 194.16,107.19 194.15,107.2 192.82,107.2 v1(192.41,107.61) ; UV25.A2 212.15,106.26
  TOP w0.127: 212.15,106.26 212.15,105.79 210.56,104.2 209.45,104.2 209.32,104.07 209.32,103.14 209.19,103.01 208.94,103.01 208.81,103.14 208.81,104.07 208.69,104.2 208.43,104.2 208.31,104.07 208.31,103.14 208.18,103.01 207.92,103.01 207.8,103.14 207.8,104.07 207.67,104.2 207.42,104.2 207.29,104.07 207.29,103.14 207.16,103.01 206.91,103.01 206.78,103.14 206.78,104.07 206.65,104.2 206.4,104.2 206.27,104.07 206.27,103.14 206.15,103.01 205.89,103.01 205.77,103.14 v2(205.77,103.71) 205.77,104.07 205.64,104.2 205.38,104.2 205.26,104.07 205.26,103.14 205.13,103.01 200.29,103.01 200.17,103.14 200.17,104.07 200.04,104.2 199.45,104.2 196.46,107.19 194.39,107.19
  BOTTOM w0.102: UV1.AP3 192.06,107.95 192.4,107.61 v1(192.41,107.61)
MDB62: length 34.6
  TOP w0.102: 211.79,106.26 211.79,108.85 UV25.C2 ; 194.39,107.57 194.03,107.57 193.94,107.66 v1(193.18,107.66)
  TOP w0.127: 194.39,107.57 196.44,107.57 199.55,104.46 200.3,104.46 200.43,104.33 200.43,103.59 200.55,103.46 200.81,103.46 200.93,103.59 200.93,104.33 201.06,104.46 201.32,104.46 201.44,104.33 201.44,103.39 201.57,103.27 201.82,103.27 201.95,103.39 201.95,104.33 202.08,104.46 202.33,104.46 202.46,104.33 v2(202.46,103.97) 202.46,103.39 202.59,103.27 202.84,103.27 202.97,103.39 202.97,104.33 203.09,104.46 203.35,104.46 203.47,104.33 203.47,103.39 203.6,103.27 203.86,103.27 203.98,103.39 203.98,104.33 204.11,104.46 204.36,104.46 204.49,104.33 204.49,103.39 204.62,103.27 204.87,103.27 205,103.39 205,104.33 205.13,104.46 210.45,104.46 211.79,105.79 211.79,106.26
  BOTTOM w0.102: UV1.AP1 192.86,107.98 v1(193.18,107.66)
MDB63: length 35.1
  TOP w0.102: 204.96,109.62 207.53,109.62 207.93,110.02 UV25.D7 ; v1(191.07,108.66) 190.88,108.66 190.48,109.06 190.48,110.02 190.37,110.13 190.37,111.23 190.74,111.59 194.32,111.59
  TOP w0.127: 194.32,111.59 194.45,111.72 v2(194.45,112.92) 194.45,114.13 194.58,114.25 194.83,114.25 194.96,114.13 194.96,111.16 195.09,111.03 195.34,111.03 195.47,111.16 195.47,114.25 195.59,114.38 204.74,114.38 204.86,114.25 204.86,109.72 204.96,109.62
  BOTTOM w0.102: v1(191.07,108.66) 191.26,108.47 UV1.AP5
MDI0+: length 7.1
  BOTTOM w0.102: 34.01,82.5 v2(34.01,82.49) ; 34.01,82.5 32.83,81.32 32.83,80.12 32.42,79.7 32.16,79.7 32.03,79.58 32.03,79.39 31.91,79.26 TL1.8 ; 34.01,82.5 34.38,82.87 35.09,82.87 35.1,82.87 UL1.1
MDI0-: length 7.1
  BOTTOM w0.102: TL1.7 31.89,80.53 31.99,80.43 31.99,80.21 32.1,80.11 32.25,80.11 32.43,80.29 v2(32.43,81.03) 32.43,81.49 34.21,83.28 UL1.2
MDI1+: length 7.1
  BOTTOM w0.102: TL1.2 32.01,86.88 32.06,86.93 32.06,87.25 32.12,87.31 32.23,87.31 32.6,86.94 v2(32.6,86.43) 32.6,85.92 34.46,84.07 35.18,84.07 35.19,84.07 UL1.4
MDI1-: length 7
  BOTTOM w0.102: UL1.5 34.63,84.47 v2(34.06,85.04) 33.01,86.09 33.01,87.11 32.4,87.72 32.21,87.72 32.1,87.83 32.1,88.06 32.01,88.15 TL1.1
MDO0+: length 8.1
  BOTTOM w0.102: JLAN.1 15.43,79.23 16.07,78.6 18.46,78.6 v3(18.95,79.09) 19.55,79.69 20.8,79.69 20.91,79.59 20.91,79.36 21.01,79.26 TL1.9
MDO0-: length 8.2
  BOTTOM w0.102: TL1.10 21.01,80.53 20.91,80.43 20.91,80.2 20.8,80.1 v3(20.49,80.1) 19.38,80.1 18.66,79.38 18.29,79 16.23,79 15.83,79.41 15.83,79.98 JLAN.2
MDO1+: length 12.2
  BOTTOM w0.102: TL1.15 21.01,86.88 20.91,86.98 20.91,87.21 20.8,87.31 19.35,87.31 18.8,86.76 v3(18.8,83.59) 18.8,82.88 17.8,81.87 16.89,81.87 16.29,81.27 JLAN.3
MDO1-: length 12.1
  BOTTOM w0.102: TL1.16 21.01,88.15 20.91,88.05 20.91,87.82 20.8,87.72 v3(20.16,87.72) 19.18,87.72 18.39,86.93 18.39,83.05 17.63,82.28 17.4,82.28 16.1,83.58 JLAN.6
ME_EN: length 89.1
  TOP w0.102: v1(177.96,48.54) 178.04,48.45 178.96,48.45 179.42,48.91 RE326.1 180.16,48.91 180.16,48.91 UE1.99
  IN1 w0.127: v1(177.96,48.54) 177.56,48.14 177.19,48.14 176.37,48.97 176.37,58.04 173.98,60.42 173.98,63.49 173.17,64.3 173.17,71.26 169.27,75.15 159.65,75.15 157.27,77.53 155.24,77.53 139.67,93.1 v1(139.28,93.1)
  BOTTOM w0.089: 126.8,94.22 126.34,94.68 RC8.1
  BOTTOM w0.102: v1(139.28,93.1) 139.28,93.04 138.64,92.39 v2(130.8,92.39) 130.28,92.39 128.53,94.14 126.88,94.14 126.8,94.22
ME_SUS_PWR_ACK: length 111.5
  TOP w0.102: RC42.1 RC27.2 135.91,96.1 136.65,95.36 v2(142.66,95.36) 151.7,95.36 155.22,91.83 156.81,91.83 157.08,92.1 164.86,92.1 167.87,89.09 167.87,85.14 174.62,78.39 174.62,71.72 175.06,71.28 175.06,57.27 176.17,56.16 176.17,49.08 178.38,46.87 v1(179.09,46.87) ; v1(198.53,38.68) 198.53,37.98 198.25,37.71 UE1.34
  IN3 w0.127: v1(198.53,38.68) 198.26,38.68 197.37,39.57 197.37,41.77 193.31,45.84 190.57,45.84 189.9,46.5 188.34,46.5 187.08,45.24 184.95,45.24 184.19,44.47 182.05,44.47 180.05,46.47 179.49,46.47 v1(179.09,46.87)
ME_SUS_PWR_ACK_R: length 11.2
  TOP w0.089: v1(131.6,101.54) 131.6,101.44
  TOP w0.102: 131.6,101.44 131.6,99.78 v2(133.02,98.36) RC35.1 RC42.2
  BOTTOM w0.076: v1(131.6,101.54) 131.23,101.54 130.55,102.22 129.25,102.22 128.68,102.79 128.68,103.4 128.63,103.46 128.63,103.93 UC1.AV4
MECH#1: length 3.5
  BOTTOM w0.102: T82.1 162.35,134.05 164.3,134.05 UV1.A39
MECH#2: length 4.8
  BOTTOM w0.102: T83.1 192.86,101.68 UV1.AW1
MECH#3: length 3.7
  BOTTOM w0.102: T84.1 165.26,102.72 UV1.AW39
MEM_SMBCLK: length 22.5
  IN3 w0.127: v1(144.74,108.89) 144.71,108.92 144.17,108.92 144.14,108.89 139.43,108.89 138.06,110.25 137.58,110.25 v1(137.38,110.05) 137.38,108.8 v1(137.64,108.53)
  BOTTOM w0.076: 132.64,106.44 130.61,106.44 130.4,106.64 130.16,106.64 129.86,106.35 UC1.AP2
  BOTTOM w0.089: 132.64,106.44 132.93,106.44 133.32,106.06 134.77,106.06 v2(136.42,107.7) 137.25,108.53 v1(137.64,108.53)
  BOTTOM w0.102: QC1.6 v1(144.74,108.89) ; v1(137.38,110.05) 137.44,110.05 137.89,110.5 137.89,111.96 137.96,112.04 RP40.1
MEM_SMBDATA: length 22.5
  IN3 w0.127: v1(146.04,108.89) 145.62,109.31 144.24,109.31 144.04,109.12 139.53,109.12 138.16,110.48 137.6,110.48 v1(137.44,110.63)
  BOTTOM w0.076: UC1.AH1 130.4,109.97 134.29,109.97 134.55,109.71 134.55,109.23 134.97,108.81
  BOTTOM w0.089: v1(137.44,110.63) 137.36,110.63 137,110.27 v2(137,109.57) 137,109.31 136.49,108.81 134.97,108.81
  BOTTOM w0.102: v1(137.44,110.63) 137.63,110.83 137.63,112.15 138.02,112.54 RP40.2 ; QC1.3 v1(146.04,108.89)
MIC1-L: length 2.7
  TOP w0.203: CA74.1 27.38,25.92 26.88,25.41 26.88,25.08 26.7,24.9 26.7,24.39 26.88,24.21 UA1.19
MIC_CLK: length 354.2
  TOP w0.102: v1(33.43,19.89) 33.04,19.5 LA1.2 34.31,19.12 CA22.1
  IN1 w0.127: v1(220.93,41.99) 220.48,42.45 220.48,79.81 213.52,86.77 213.52,91.07 216.24,93.8 216.24,97.63 219.12,100.51 219.5,100.51 221.26,102.27 221.26,110.08 219.81,111.53 219.81,116.49 217.5,118.79 217.5,123.01 217.11,123.4 217.11,144.91 217.44,145.24 217.44,161.23 221.34,165.13 221.34,171.89 220.49,172.74 218.92,172.74 v1(218.66,172.48) ; v1(184.05,34.45) 183.25,35.25 180.61,35.25 180.11,34.76 167.41,34.76 160.85,41.31 136.91,41.31 133.25,44.97 105.5,44.97 87.35,26.82 52.36,26.82 46.57,21.03 34.57,21.03 v1(33.43,19.89)
  BOTTOM w0.102: v1(184.05,34.45) 184.99,35.39 v2(185.97,35.39) 192.86,35.39 194.39,36.91 194.39,39.26 195.92,40.8 200.17,40.8 201.27,41.89 201.8,41.89 202.5,42.59 213.85,42.59 214.58,41.87 220.8,41.87 v1(220.93,41.99) ; v1(218.66,172.48) 218.95,172.77 JLVDS.30
MIC_CLK_C: length 2.3
  TOP w0.102: LA1.1 32.22,19.05 v2(31.22,19.05) 30.77,19.05 30.58,19.25 UA1.3
MIC_DATA: length 355.9
  TOP w0.102: UA1.2 30.62,18.85 30.79,18.68 31.78,18.68 31.95,18.51 33.48,18.51 33.59,18.62 v2(36.75,18.62) 37.7,18.62 v1(38.45,19.37)
  IN1 w0.127: v1(38.45,19.37) 39.68,20.6 46.5,20.6 52.46,26.57 87.54,26.57 105.69,44.71 133.15,44.71 136.8,41.06 160.75,41.06 167.31,34.5 180.22,34.5 180.67,34.95 182.98,34.95 183.42,34.51 v1(183.42,34.43) ; v1(221.31,42.56) 220.91,42.97 220.91,79.74 213.77,86.88 213.77,90.8 216.58,93.61 216.58,97.61 219.23,100.26 219.61,100.26 221.52,102.17 221.52,110.18 220.06,111.64 220.06,116.59 217.75,118.9 217.75,123.11 217.36,123.51 217.36,144.81 217.69,145.14 217.69,161.12 221.63,165.06 221.63,172.04 219.61,174.06 v1(219.61,174.51)
  BOTTOM w0.102: v1(221.31,42.56) 214.21,42.56 213.95,42.82 202.4,42.82 201.7,42.12 201.14,42.12 200.04,41.03 195.79,41.03 194.13,39.37 194.13,37.02 192.93,35.82 184.81,35.82 v1(183.42,34.43) ; JLVDS.32 219.95,174.11 219.61,174.45 v1(219.61,174.51)
MIC_IN: length 12.1
  IN1 w1.016: 15.59,23.76 22.93,23.76 23.37,24.2 24.3,24.2 24.61,24.51 26.05,24.51 26.38,24.84
  BOTTOM w0.102: v2(16.33,23.41) 15.84,22.92 v1(15.84,22.74)
  vias: v1(15.26,22.74) v1(27.33,25.09) v1(27.28,24.5)
MIC_IN_R: length 14.9
  TOP w0.102: LA7.1 v2(13.87,20.28)
  IN3 w1.016: 15.46,17.22 15.01,17.22 13.49,18.74 12.67,18.74 12.67,18.74 4.5,18.74 JHP.4
  vias: v1(16.32,17.54) v1(16.32,16.95)
MIIC_SCL: length 6.8
  TOP w0.102: UX4.48 202.12,173.93 202.19,174 202.19,174.13 202.05,174.27 201.06,174.27 200.71,174.61 200.71,174.77 v1(200.52,174.97)
  BOTTOM w0.102: v1(200.52,174.97) 200.75,175.19 200.75,175.4 200.66,175.49 200.28,175.49 200.14,175.35 199.16,175.35 199.06,175.25 199.06,175.13 198.96,175.03 RX171.1 RX169.2
MIIC_SDA: length 7.1
  TOP w0.102: v1(201.12,174.97) 200.94,174.79 200.94,174.7 201.15,174.5 v3(201.57,174.5) 202.15,174.5 202.42,174.22 202.42,174 202.52,173.9 UX4.47
  BOTTOM w0.102: v1(201.12,174.97) 200.98,175.11 200.98,175.49 200.76,175.72 200.18,175.72 200.04,175.58 199.16,175.58 199.06,175.68 199.06,175.79 198.96,175.89 RX170.1 RX168.2
MS_BS: length 16.8
  TOP w0.102: UR1.22 174.52,23.19 173.5,24.22 173.5,24.23 173.4,24.33 172.55,24.33 172.43,24.45 172.43,24.61 172.55,24.73 173.4,24.73 173.5,24.83 173.5,25.04 173.4,25.14 172.55,25.14 172.43,25.26 172.43,25.43 172.55,25.55 v2(172.94,25.55) 173.4,25.55 173.5,25.65 173.5,27.8 176.59,30.9 177.92,30.9 v1(178.21,31.19)
  BOTTOM w0.102: JREAD.15 178.56,30.84 v1(178.21,31.19)
MS_CLK_SD_WP: length 41.4
  TOP w0.102: RR3.2 CR5.1 182.5,21.83 v1(182.59,21.92)
  IN1 w0.127: v1(170.46,28.46) 171.07,29.07 184.19,29.07 v1(186.71,26.55)
  BOTTOM w0.102: JREAD.5 187.68,27.44 186.79,26.55 v1(186.71,26.55) 186.71,22.94 186.58,22.81 182.65,22.81 182.53,22.69 182.53,22.52 182.65,22.4 186.58,22.4 186.71,22.28 186.71,22.05 186.58,21.92 v1(182.59,21.92) ; v1(170.46,28.46) 170.19,28.73 JREAD.22
MS_CLK_SD_WP_R: length 5.1
  TOP w0.102: v2(182.92,20.8) 182.58,20.46 181.36,20.46 RR3.1 179.76,22.06 179.76,22.46 179.53,22.69 UR1.8
MS_D0: length 23.6
  TOP w0.102: UR1.16 176.82,26.64 176.69,26.77 175.87,26.77 175.75,26.89 175.75,27.06 175.87,27.18 176.69,27.18 176.82,27.31 176.82,28.74 177.13,29.06 v2(178.49,29.06) 179.43,29.06 180.39,28.1 v1(180.39,27.72)
  BOTTOM w0.102: JREAD.12 181.6,23.58 181.47,23.45 181.22,23.45 181.09,23.58 181.09,28.78 180.97,28.9 180.52,28.9 180.39,28.78 v1(180.39,27.72)
MS_D1_SD_D3: length 27
  TOP w0.102: v1(179.52,31.19) 179.52,30.94 179.65,30.81 180.24,30.81 180.37,30.68 180.37,30.33 180.24,30.2 v2(179.91,30.2) 176.54,30.2 173.96,27.61 173.96,24.59 174.35,24.19 UR1.20
  BOTTOM w0.102: JREAD.3 189.96,31.38 189.77,31.57 179.91,31.57 v1(179.52,31.19) 179.52,31.15 180.08,30.59 JREAD.13
MS_D2_SD_CLK: length 24.1
  TOP w0.102: v1(178.79,28.59) 178.23,28.03 RR2.2 CR6.1
  IN1 w0.127: v1(178.79,28.59) 178.9,28.59 180.2,27.28 180.2,25.21 180.32,25.09 180.68,25.09 180.81,25.22 180.81,28.2 180.93,28.33 181.22,28.33 181.35,28.2 181.35,25.22 181.47,25.09 181.73,25.09 181.85,25.22 181.85,28.2 181.98,28.33 182.99,28.33 183.12,28.2 v1(183.12,26.81)
  BOTTOM w0.102: v1(178.79,28.59) 179.32,29.11 JREAD.14 ; v1(183.12,26.81) JREAD.10
MS_D2_SD_CLK_R: length 2
  TOP w0.102: UR1.15 177.32,25.88 178.21,26.77 RR2.1
MS_D3: length 24.6
  TOP w0.102: UR1.12 v2(181.93,24.69) 182.87,24.69 v1(183.96,23.6)
  BOTTOM w0.102: v1(183.96,23.6) 186.03,23.6 186.16,23.73 186.16,24.48 186.05,24.58 183.9,24.58 183.8,24.68 183.8,24.89 183.9,24.99 186.05,24.99 186.16,25.09 186.16,25.29 186.05,25.4 183.9,25.4 183.8,25.5 183.8,25.7 183.9,25.8 186.05,25.8 186.16,25.9 186.16,27.8 186.05,27.9 185.17,27.9 185.07,28 185.07,28.2 185.17,28.3 186.05,28.3 186.16,28.41 JREAD.7
MS_INS#: length 19.8
  TOP w0.102: v1(183.35,23.63) 183.29,23.57 v2(182.7,23.57) 181.8,23.57 CR10.1 181.35,23.19 UR1.9
  BOTTOM w0.102: v1(183.35,23.63) 183.35,26.09 183.48,26.22 185.65,26.22 185.77,26.34 185.77,26.5 185.65,26.62 183.77,26.62 183.67,26.72 183.67,26.93 183.77,27.03 185.65,27.03 185.77,27.15 185.77,27.32 185.65,27.44 183.77,27.44 183.67,27.54 183.67,27.74 183.77,27.84 184.53,27.84 184.64,27.94 JREAD.8
O-USR: length 5.5
  TOP w0.102: v2(85.55,142.11) 85.55,141.1 86.01,140.64 v1(86.01,140.6)
  TOP w0.254: PR506.2 86.01,140.04 v1(86.01,140.6)
  BOTTOM w0.203: v1(86.01,140.6) 86.19,140.6 86.97,139.81 87.46,139.81 PU501.9
  BOTTOM w0.254: v1(86.01,140.6) 85.94,140.66 PR502.1
OCP_CPU: length 3.7
  TOP w0.102: v2(89.42,141.07) 88.95,140.6 v1(88.61,140.6)
  TOP w0.254: PR503.2 88.48,140.47 v1(88.61,140.6)
  BOTTOM w0.203: v1(88.61,140.6) 89.02,140.19 PU501.12
  BOTTOM w0.254: v1(88.61,140.6) PR501.1
ODD_DA#: length 142.5
  TOP w0.089: RP54.1 131.87,114.13 131.73,113.99 131.73,113.55 v1(131.66,113.49) 131.47,113.29 130.49,113.29 129.91,113.87 128.6,113.87 128.42,114.05 128.42,114.58 128.24,114.77 128.24,115.39 v1(129.31,116.47)
  IN1 w0.127: v1(220.55,105.23) 220.34,105.23 218.64,103.53 218.64,101.85 215.3,98.52 214.17,98.52 213.01,97.36 210.53,97.36 210.24,97.65 201.2,97.65 196.51,92.96 192.91,92.96 191.38,94.49 190.04,94.49 189.3,93.74 173.71,93.74 v1(173.45,93.48)
  IN3 w0.084: 137.82,106.84 126.81,106.84 126.5,107.15 126.5,108.47 126.36,108.61 126.36,109.39 126.65,109.68 127.92,109.68 128.2,109.96 128.2,110.67 128.88,111.34 129.42,111.34 131.56,113.49 v1(131.66,113.49)
  IN3 w0.127: v1(173.45,93.48) 172.34,92.38 170.02,92.38 163.01,99.38 163.01,100.16 161.88,101.29 154.14,101.29 149.07,106.37 144.68,106.37 143.59,107.45 139.1,107.45 138.48,106.84 137.82,106.84
  BOTTOM w0.089: v1(129.31,116.47) 128.98,116.81 UC1.T3
  BOTTOM w0.102: v1(220.55,105.23) 221.44,106.12 222.28,106.12 CS17.1 223.84,105.47 228.06,109.68 228.06,114.04 JODD.11
ODD_DETECT#: length 128.8
  IN1 w0.127: v1(220.55,105.87) 220.48,105.87 218.39,103.77 218.39,101.96 215.2,98.77 214.06,98.77 212.9,97.61 210.64,97.61 210.34,97.9 201.09,97.9 196.41,93.22 193.01,93.22 191.49,94.74 189.94,94.74 189.2,94 175.52,94 175.39,94.13 v1(172.04,94.13)
  IN2 w0.089: 137.92,116.61 137.63,116.32 v1(137.57,116.32)
  IN2 w0.127: 137.92,116.61 138.1,116.79 141.57,116.79 142.4,115.96 146.6,115.96 151.92,110.64 151.92,109.82 152.28,109.46 152.28,108.4 151.62,107.74 151.62,106.19 v1(152.07,105.74)
  IN3 w0.084: v1(137.57,116.32) 137.42,116.17 136.66,116.17 136.26,116.57 134.24,116.57 133.54,117.27 132.22,117.27 130.77,115.81 128.45,115.81 128,116.26 127.62,116.26 v1(127.26,115.9)
  IN3 w0.127: v1(152.07,105.74) 155.99,101.82 162.1,101.82 163.53,100.39 163.53,99.58 169.52,93.59 170.38,93.59 170.92,94.13 v1(172.04,94.13)
  BOTTOM w0.076: v1(137.57,116.32) 137.57,115.58 137.92,115.23
  BOTTOM w0.089: UC1.V6 126.99,115.63 v1(127.26,115.9)
  BOTTOM w0.102: v1(220.55,105.87) 221.1,106.42 222.13,106.42 v2(223.03,107.31) 224.24,107.31 226.05,109.13 JODD.8 ; 137.92,115.23 137.99,115.16 RP37.1
ODD_EN: length 8.8
  BOTTOM w0.102: RS6.1 222.67,125.13 222.87,124.93 222.87,123.72 CS16.1 222.24,122.27 222.48,122.27 222.85,121.91 QS2.3 ; RS6.1 221.96,126.3 QS3.1 ; RS6.1 222.96,126.59 v2(222.96,127.35)
ODD_EN#: length 136.2
  TOP w0.102: v1(171.22,92.85) 170.98,92.85 v2(170.73,92.59)
  IN1 w0.084: v1(134.33,114.96) 134.76,115.39 137.32,115.39 137.92,116
  IN1 w0.127: v1(216.91,122.03) 216.91,101.98 212.8,97.86 210.74,97.86 210.35,98.26 201.09,98.26 196.3,93.47 193.12,93.47 191.56,95.03 189.87,95.03 189.2,94.36 177.52,94.36 176.24,95.64 172.96,95.64 171.22,93.91 v1(171.22,92.85) ; 137.92,116 138.08,116.15 138.33,116.15 139.98,117.8 143.02,117.8 147.13,113.69 147.13,113.13 148.94,111.33 149.5,111.33 152.05,108.77 v1(152.05,107.58)
  IN3 w0.127: v1(152.05,107.58) 151.65,107.18 151.65,105.32 155.42,101.55 161.99,101.55 163.27,100.27 163.27,99.48 169.9,92.85 v1(171.22,92.85)
  BOTTOM w0.089: UC1.Y1 130.46,114.77 131.79,114.77 132.4,115.38 133.9,115.38 v1(134.33,114.96)
  BOTTOM w0.102: v1(216.91,122.03) 217.13,122.25 219.8,122.25 219.98,122.43 220.87,122.43 221.24,122.79 221.24,123.33 QS3.2
ODTA0: length 43.7
  TOP w0.102: v1(177.19,128.23) 177.19,128.09 177.32,127.96 177.47,127.96 177.6,128.09 177.6,130.91 177.56,130.95 177.56,131.63 176.95,132.24 176.95,133.42 176.45,133.92 176.45,135.39 ; v1(170,148.29) 169.35,147.64 169.35,146.55 169.85,146.05 169.85,145.93 170.16,145.62 170.28,145.62 170.51,145.39 170.51,144.78 UV18.K1
  TOP w0.127: 176.45,135.39 176.45,140.13 176.61,140.29 v2(176.61,140.8) 176.61,142.64 176.67,142.7 176.99,142.7 177.11,142.57 177.11,140.51 177.24,140.38 v1(177.56,140.38)
  IN1 w0.102: 172.21,142.86 171.13,143.93 171.13,145.34 169.35,147.13 169.35,148.56 169.43,148.64 169.84,148.64 170,148.49 v1(170,148.29)
  IN1 w0.14: v1(177.56,140.38) 177.56,140.84 177.26,141.15 173.92,141.15 172.21,142.86
  BOTTOM w0.102: UV1.J21 177.8,128.23 v1(177.19,128.23) ; v1(170,148.29) 170,148.61 170.52,149.13 170.52,150.2 170.64,150.32 170.64,151.34 170.51,151.46 170,151.46 169.88,151.34 169.88,150.98 170,150.85 UV19.K1
ODTA1: length 41.8
  TOP w0.102: v1(188.17,147.02) 188.75,147.6 188.75,148.82 188.3,149.27 188.3,149.39 188.01,149.68 187.89,149.68 187.66,149.92 187.66,150.51 187.98,150.84 UV20.K1 ; v1(179.67,129.64) 180.05,130.02 180.05,133.19 179.96,133.27 179.69,133.27 179.57,133.39 179.57,134.09 179.79,134.31 180.6,134.31 180.74,134.45 180.74,135.39
  TOP w0.127: 180.74,135.39 180.74,136.51 180.87,136.64 181.12,136.64 181.24,136.77 181.24,137.02 181.12,137.15 180.87,137.15 180.74,137.28 180.74,137.61 180.87,137.73 181.04,137.73 181.17,137.86 181.17,139.74 181.04,139.87 180.51,139.87 180.38,140 180.38,143.03 180.29,143.12 179.81,143.12 179.65,142.96 v2(179.65,142.07) 179.65,141.18 v1(179.78,141.06)
  IN1 w0.102: v1(188.17,147.02) 188.17,146.64 187.4,145.87 187.4,143.55 186.71,142.86
  IN1 w0.14: 186.71,142.86 184.91,141.06 v1(179.78,141.06)
  BOTTOM w0.102: UV21.K1 187.98,144.23 187.85,144.1 187.63,144.1 187.5,144.23 187.5,144.73 187.66,144.89 187.66,145.11 187.5,145.27 187.5,145.39 187.4,145.5 187.4,145.75 187.65,146 187.65,146.22 187.9,146.48 188.31,146.48 188.41,146.58 188.41,146.96 188.35,147.02 v1(188.17,147.02) ; UV1.G19 179.92,129.89 v1(179.67,129.64)
ODTB0: length 43.7
  TOP w0.102: 191.33,123.39 191.22,123.27 190.71,123.27 189.99,122.56 189.38,122.56 v1(189.26,122.44) ; UV22.K1 206.88,131.78 207.49,131.78 207.72,132.02 207.72,132.13 208.03,132.44 208.23,132.44 208.67,132.88 209.8,132.88 v1(210.39,132.29)
  TOP w0.127: 191.33,123.39 191.33,123.74 191.46,123.86 191.85,123.86 191.98,123.74 191.98,123.4 192.11,123.27 192.36,123.27 192.49,123.4 192.49,123.74 192.61,123.86 194.14,123.86 194.27,123.74 194.27,123.53 194.4,123.41 194.65,123.41 194.78,123.53 194.78,123.74 194.91,123.86 195.16,123.86 195.29,123.74 195.29,123.53 195.41,123.41 195.67,123.41 195.8,123.53 195.8,123.74 195.92,123.86 196.18,123.86 196.3,123.74 196.3,123.53 196.43,123.41 196.68,123.41 196.81,123.53 196.81,123.74 196.94,123.86 197.19,123.86 197.32,123.74 197.32,122.76 197.45,122.64 197.7,122.64 197.83,122.76 v2(197.83,123.46) 197.83,123.74 197.95,123.86 198.21,123.86 198.34,123.74 198.34,123.53 198.46,123.41 198.72,123.41 198.84,123.53 198.84,123.74 198.97,123.86 199.22,123.86 199.35,123.74 199.35,123.53 199.48,123.41 199.73,123.41 199.86,123.53 199.86,123.74 199.99,123.86 200.29,123.86 200.42,123.74 200.42,123.57 200.55,123.45 201.46,123.45 v1(201.88,123.86)
  IN1 w0.102: 204.96,130.08 206.51,131.64 207.93,131.64 208.96,132.67 210.01,132.67 v1(210.39,132.29)
  IN1 w0.14: v1(201.88,123.86) 201.88,125.32 203.9,127.33 203.9,129.02 204.96,130.08
  BOTTOM w0.102: UV23.K1 213.37,132.1 213.5,131.98 213.5,131.78 213.37,131.65 211.35,131.65 210.7,132.29 v1(210.39,132.29) ; v1(189.26,122.44) 189.66,122.84 UV1.T7
ODTB1: length 44.4
  TOP w0.102: v1(209.12,114.63) 209.7,114.04 210.83,114.04 211.17,114.38 211.37,114.38 211.78,114.79 211.78,114.91 212.02,115.14 212.63,115.14 UV25.K1 ; 194.13,118.13 193.7,118.13 193.43,118.39 193.43,118.66 194.13,119.35 194.13,119.49 193.97,119.65 193.85,119.65 193.18,118.97 192.84,118.97 192.68,119.14 192.68,119.4 192.43,119.64 192.43,119.93 192.21,120.15 191.84,120.15 191.65,119.97 191.65,119.66 191.55,119.56 191.24,119.56 191.02,119.34 189.94,119.34 189.81,119.47 189.81,119.64 189.94,119.77 v1(190.32,119.77)
  TOP w0.127: v1(202.83,121.3) 202.92,121.21 202.92,120.89 202.8,120.77 v2(202.32,120.77) 202.03,120.77 201.91,120.64 201.91,120.56 201.78,120.43 201.52,120.43 201.4,120.56 201.4,120.64 201.27,120.77 201.02,120.77 200.89,120.64 200.89,120.56 200.76,120.43 200.51,120.43 200.38,120.56 200.38,120.64 200.25,120.77 200,120.77 199.87,120.64 199.87,120.56 199.75,120.43 199.49,120.43 199.37,120.56 199.37,120.64 199.24,120.77 198.98,120.77 198.86,120.64 198.86,120.56 198.73,120.43 198.48,120.43 198.35,120.56 198.35,120.64 198.22,120.77 197.14,120.77 197.01,120.64 197.01,118.26 196.88,118.13 195.16,118.13 195.03,118.26 195.03,118.7 194.91,118.83 194.65,118.83 194.52,118.7 194.52,118.26 194.4,118.13 194.13,118.13
  IN1 w0.102: v1(209.12,114.63) 208.74,114.63 207.97,115.4 205.65,115.4 204.96,116.08
  IN1 w0.14: 204.96,116.08 202.83,118.21 v1(202.83,121.3)
  BOTTOM w0.102: v1(209.12,114.63) 208.8,114.63 208.16,115.27 205.98,115.27 205.88,115.17 205.88,114.92 205.98,114.82 UV24.K1 ; UV1.W7 189.66,120.43 v1(190.32,119.77)
ON/OFFBTN#: length 238.7
  TOP w0.102: UE1.114 180.08,42.91 179.67,43.32 178.65,43.32 177.36,44.61 v1(177.36,45.38) ; JPWR.3 43.34,94.11 v1(43.46,93.99) ; v1(168.75,44.38) v4(168.75,42.68) 168.75,41.75 170.48,40.02 174.13,40.02 179.47,34.68 179.47,32.8 181.61,30.67 191.44,30.67 RE49.1 195.55,28.57 CE20.1 195.88,31.13 SW1.3 v1(199.86,31.13) SW1.4
  IN3 w0.127: v1(177.36,45.38) 176.6,45.38 176.33,45.11 171.95,45.11 171.22,44.38 v1(168.75,44.38) 168.51,44.61 54.74,44.61 47.72,51.64 47.72,78.56 45.56,80.72 45.56,89.74 43.46,91.83 v1(43.46,93.99)
  BOTTOM w0.102: SW2.3 199.74,39.48 199.74,36.65 199.22,36.13 SW2.4 199.22,31.78 v1(199.86,31.13)
PACIN#: length 3.3
  BOTTOM w0.102: v2(188.14,98.31) 188.19,98.37 RV74.2 189.13,98.44 QV14.5 189.13,99.58 188.94,99.77 188.57,99.77 188.48,99.68 QV14.6
PANEL_BKLEN: length 136.6
  TOP w0.102: v1(193.39,48.71) 193.03,48.71 191.19,50.55 UE1.76
  IN2 w0.127: v1(125.62,129.84) 125.62,129.98 127.93,132.29 136.1,132.29 136.62,131.77 136.62,127.28 143.26,120.64 143.26,118.08 144.37,116.98 148.43,116.98 151.07,114.33 151.07,112.1 152.17,110.99 152.17,109.93 152.53,109.57 152.53,108.39 152.66,108.27 152.66,105.7 157.92,100.44 160.49,100.44 182.32,78.61 182.32,77.78 186.26,73.84 186.26,66.53 185.5,65.76 185.5,54.36 186.24,53.62 v1(186.24,48.47)
  IN3 w0.127: v1(193.39,48.71) 193.39,48.72 193.32,48.65 189.52,48.65 189.33,48.84 186.6,48.84 v1(186.24,48.47)
  BOTTOM w0.076: UC1.A9 124.83,126.02 125.82,127.02 125.82,129.38 125.62,129.59 v1(125.62,129.84)
PBTN_OUT#: length 255.9
  TOP w0.102: UE1.106 180.73,46.11 180.37,46.47 178.26,46.47 172.34,52.38 v2(172.34,53.22) 172.34,55.75 v1(172.14,55.95)
  IN1 w0.084: 137.75,107.99 135.59,107.99 135.19,108.39 133.83,108.39 132.85,109.37 129.82,109.37 129.63,109.56 127.7,109.56 127.62,109.64 127.22,109.64 v1(126.82,109.24)
  IN1 w0.127: v1(182.89,78) 180.16,80.73 178.04,80.73 174.36,84.41 172.32,84.41 171.67,85.06 167.02,85.06 160.46,91.62 160.46,94.08 152.94,101.61 152.94,101.76 148.15,106.55 148.15,107.07 146.77,108.44 144.58,108.44 144.17,108.86 138.62,108.86 137.75,107.99
  IN3 w0.127: v1(65.73,88.7) 66,88.43 66,78.49 70.77,73.72 70.77,72.47 73.14,70.1 73.14,57.34 73.6,56.88 118.11,56.88 119.48,55.52 171.7,55.52 v1(172.14,55.95) 172.95,56.77 174.35,56.77 176.47,58.89 179.14,58.89 185.07,64.82 185.07,65.99 184,67.06 184,69.87 182.89,70.98 v1(182.89,78)
  BOTTOM w0.089: UC1.AL7 126.54,108.96 v1(126.82,109.24)
  BOTTOM w0.102: RC49.1 63.67,89.69 64.66,88.7 v1(65.73,88.7)
PC_BEEP: length 5.6
  TOP w0.102: RA79.2 35.73,24.52 RA19.1 36.83,23.42 v2(37.78,23.42) 37.99,23.42 38.13,23.57 DA8.1
PCH_AUDIO_EN: length 4.7
  BOTTOM w0.076: UC1.P1 131.4,117.59 131.54,117.73 132.92,117.73 RC116.1
  BOTTOM w0.089: RC116.1 133.49,117.88 v2(134.04,117.34)
PCH_AZ_BITCLK: length 7
  BOTTOM w0.076: 125.2,102.25 125.11,102.34 125.11,103.29 UC1.AW8
  BOTTOM w0.089: R2359.2 128.16,98.13 v2(127.43,98.86) 126.24,100.05 126.24,101.2 125.2,102.25
PCH_AZ_CODEC_BITCLK: length 233.8
  TOP w0.102: v1(32.78,19.89) R2355.1 31.52,20.52 31.45,20.45 UA1.6
  IN1 w0.127: v1(32.78,19.89) 32.78,20 34.38,21.6 36.81,21.6 36.93,21.73 36.93,22.49 37.06,22.62 37.31,22.62 37.44,22.49 37.44,21.73 37.57,21.6 37.82,21.6 37.95,21.73 37.95,22.49 38.08,22.62 38.33,22.62 38.46,22.49 38.46,21.73 38.58,21.6 38.84,21.6 38.97,21.73 38.97,22.49 39.09,22.62 39.35,22.62 39.47,22.49 39.47,21.73 39.6,21.6 39.85,21.6 39.98,21.73 39.98,22.49 40.11,22.62 40.36,22.62 40.49,22.49 40.49,21.73 40.62,21.6 40.87,21.6 41,21.73 41,22.49 41.12,22.62 41.38,22.62 41.51,22.49 41.51,21.73 41.63,21.6 41.89,21.6 42.01,21.73 42.01,22.49 42.14,22.62 42.39,22.62 42.52,22.49 42.52,21.73 42.65,21.6 42.9,21.6 43.03,21.73 43.03,22.49 43.16,22.62 43.41,22.62 43.54,22.49 43.54,21.73 43.66,21.6 43.92,21.6 44.05,21.73 44.05,22.49 44.17,22.62 44.43,22.62 44.55,22.49 44.55,21.73 44.68,21.6 44.93,21.6 45.06,21.73 45.06,22.49 45.19,22.62 45.44,22.62 45.57,22.49 45.57,21.73 45.7,21.6 46.42,21.6 52.15,27.33 87.1,27.33 89.7,29.93 89.7,30.11 89.42,30.39 89.42,30.57 89.6,30.75 89.78,30.75 90.06,30.47 90.24,30.47 90.42,30.65 90.42,30.83 90.14,31.11 90.14,31.29 90.32,31.47 90.5,31.47 90.78,31.19 90.96,31.19 91.14,31.37 91.14,31.55 90.86,31.83 90.86,32.01 91.04,32.19 91.22,32.19 91.5,31.91 91.68,31.91 91.86,32.09 91.86,32.27 91.58,32.55 91.58,32.73 91.76,32.91 91.93,32.91 92.22,32.63 92.4,32.63 92.58,32.81 92.58,32.99 92.29,33.27 92.29,33.45 92.47,33.63 92.65,33.63 92.94,33.35 93.12,33.35 93.3,33.53 93.3,33.7 93.01,33.99 93.01,34.17 93.19,34.35 93.37,34.35 93.66,34.06 93.84,34.06 94.02,34.24 94.02,34.42 93.73,34.71 93.73,34.89 93.91,35.07 94.09,35.07 94.38,34.78 94.55,34.78 94.73,34.96 94.73,35.14 94.45,35.43 94.45,35.61 94.63,35.79 94.81,35.79 95.09,35.5 95.27,35.5 95.45,35.68 95.45,35.86 95.17,36.15 95.17,36.32 95.35,36.5 95.53,36.5 95.81,36.22 95.99,36.22 96.17,36.4 96.17,36.58 95.89,36.86 95.89,37.04 96.07,37.22 96.25,37.22 96.53,36.94 96.71,36.94 96.89,37.12 96.89,37.3 96.61,37.58 96.61,37.76 96.79,37.94 96.97,37.94 97.25,37.66 97.43,37.66 97.61,37.84 97.61,38.02 97.33,38.3 97.33,38.48 97.51,38.66 97.69,38.66 97.97,38.38 98.15,38.38 98.33,38.56 98.33,38.74 98.04,39.02 98.04,39.2 98.22,39.38 98.4,39.38 98.69,39.1 98.87,39.1 99.08,39.31 99.08,39.49 98.79,39.77 98.79,39.95 98.97,40.13 99.15,40.13 99.44,39.85 99.62,39.85 99.8,40.03 99.8,40.2 99.51,40.49 99.51,40.67 99.69,40.85 99.87,40.85 100.16,40.56 100.34,40.56 100.52,40.74 100.52,40.92 100.23,41.21 100.23,41.39 100.41,41.57 100.59,41.57 100.88,41.28 101.05,41.28 101.23,41.46 101.23,41.64 100.95,41.93 100.95,42.11 101.13,42.29 101.31,42.29 101.59,42 101.77,42 101.95,42.18 101.95,42.36 101.67,42.65 101.67,42.82 101.85,43 102.03,43 102.31,42.72 102.49,42.72 102.67,42.9 102.67,43.08 102.39,43.36 102.39,43.54 102.57,43.72 102.75,43.72 103.03,43.44 103.21,43.44 103.39,43.62 103.39,43.8 103.11,44.08 103.11,44.26 103.29,44.44 103.47,44.44 103.75,44.16 103.93,44.16 104.11,44.34 104.11,44.52 103.83,44.8 103.83,44.98 104.01,45.16 104.19,45.16 104.47,44.88 104.65,44.88 105.25,45.48 137.28,45.48 v1(137.47,45.29) ; v1(137.51,51.19) 137.51,56.36 137.63,56.49 138.03,56.49 138.15,56.36 138.15,53.12 138.28,53 138.7,53 138.83,53.12 138.83,56.36 138.95,56.49 139.35,56.49 139.47,56.36 139.47,53.63 139.6,53.5 140.06,53.5 140.19,53.63 140.19,56.36 140.31,56.49 142.65,56.49 142.78,56.61 142.78,69.04 144.11,70.37 144.11,80.53 v1(131.45,93.19)
  BOTTOM w0.089: R2359.1 128.16,96.21 CC5.1 127.85,94.62 v2(129.63,94.62) 130.02,94.62 130.06,94.58
  BOTTOM w0.102: v1(131.45,93.19) 131.45,93.19 130.06,94.58 ; v1(137.51,51.19) 137.47,51.16 v1(137.47,45.29)
PCH_AZ_CODEC_RST#: length 252.5
  TOP w0.102: v1(30.93,22.45) UA1.11
  IN1 w0.084: 130.42,94.94 129.05,96.31 v1(129.05,96.42)
  IN1 w0.127: 130.42,94.94 144.62,80.74 144.62,70.05 143.98,69.42 143.98,64.08 144.11,63.95 144.76,63.95 144.88,63.83 144.88,63.57 144.76,63.45 143.54,63.45 143.41,63.32 143.41,63.06 143.54,62.94 145,62.94 145.13,62.81 145.13,62.56 145,62.43 143.54,62.43 143.41,62.3 143.41,62.05 143.54,61.92 145.02,61.92 145.15,61.79 145.15,61.54 145.02,61.41 143.54,61.41 143.41,61.29 143.41,61.03 143.54,60.91 145.15,60.91 145.28,60.78 145.28,60.52 145.15,60.4 143.54,60.4 143.41,60.27 143.41,60.02 143.54,59.89 145.09,59.89 145.22,59.76 145.22,59.51 145.09,59.38 143.54,59.38 143.41,59.25 143.41,59 143.54,58.87 145.15,58.87 145.28,58.75 145.28,58.49 145.15,58.37 143.54,58.37 143.41,58.24 143.41,57.98 143.54,57.86 145.08,57.86 145.2,57.73 145.2,57.48 145.08,57.35 143.54,57.35 143.41,57.22 143.41,56.97 143.54,56.84 145.15,56.84 145.28,56.71 145.28,56.46 145.15,56.33 144.07,56.33 143.98,56.25 143.98,53.91 143.86,53.78 143.11,53.78 142.98,53.91 142.98,55.83 142.85,55.95 142.31,55.95 142.18,55.83 142.18,50.81 142.05,50.68 141.54,50.68 141.42,50.81 141.42,55.85 141.29,55.98 140.85,55.98 140.72,55.85 140.72,50.81 140.59,50.68 139.98,50.68 139.86,50.81 139.86,52.77 139.73,52.89 139.41,52.89 139.28,52.77 139.28,50.81 139.16,50.68 138.8,50.68 138.67,50.81 138.67,52.35 138.55,52.47 138.18,52.47 138.05,52.35 138.05,50.81 137.93,50.68 117.31,50.68 116.55,51.45 114.65,51.45 111.85,48.65 103.72,48.65 84.94,29.87 51.1,29.87 46.83,25.6 33.98,25.6 30.93,22.55 v1(30.93,22.45) 30.48,22.45 30.25,22.68 30.25,23.76 31.72,25.22 31.72,28.14 30.7,29.16 24.29,29.16 22.19,27.06 21.69,27.06 19.47,24.84 15.68,24.84 v1(15.03,25.49)
  BOTTOM w0.089: R2358.1 v1(129.05,96.42)
  BOTTOM w0.102: RA6.1 v1(15.03,25.49)
PCH_AZ_CODEC_SDIN0: length 233.3
  TOP w0.102: v1(34.32,22.55) 33.62,21.85 33.44,21.85 RA130.1
  IN1 w0.084: 131.57,96.78 130.65,96.78 130.1,97.33 127.21,97.33 v1(125.62,98.92)
  IN1 w0.127: 131.57,96.78 131.81,96.78 133.01,95.58 133.25,95.58 133.63,95.19 133.63,94.6 152.12,76.11 156.4,76.11 160.43,72.08 169.33,72.08 171.29,70.12 171.29,62.58 171.69,62.18 171.69,61.8 171.12,61.22 171.12,49.44 168.75,47.06 104.42,47.06 85.7,28.34 51.73,28.34 47.27,23.89 35.65,23.89 v1(34.32,22.55)
  BOTTOM w0.089: v1(125.62,98.92) 125.62,99.28 125.89,99.55 125.89,101.06 124.65,102.29 UC1.AY10
PCH_AZ_CODEC_SDOUT: length 230.5
  TOP w0.102: v1(32.1,19.89) 31.24,19.89 31.08,20.05 UA1.5
  IN1 w0.084: 130.97,96.28 130.71,96.28 130.03,96.96 127.33,96.96 v1(126.77,96.4)
  IN1 w0.127: v1(32.1,19.89) 32.1,22.11 34.51,24.52 47.19,24.52 51.52,28.85 85.45,28.85 104.17,47.57 167.52,47.57 170.4,50.45 170.4,63.48 170.78,63.87 170.78,69.91 169.14,71.55 159.17,71.55 155.36,75.36 152.15,75.36 132.29,95.22 132.29,95.59 131.6,96.28 130.97,96.28
  BOTTOM w0.089: R2356.1 127.24,96.87 v1(126.77,96.4)
PCH_AZ_CODEC_SYNC: length 223.2
  TOP w0.102: UA1.10 30.64,22.05 30.7,21.98 31.08,21.98 v1(31.52,22.43)
  IN1 w0.084: v1(129.87,96.49) 130.43,95.93 131.22,95.93 131.32,95.84
  IN1 w0.127: 131.32,95.84 131.78,95.38 131.78,95.01 152.11,74.69 154,74.69 157.75,70.94 167.99,70.94 169.57,69.36 169.57,63.35 169.89,63.04 169.89,50.66 167.37,48.14 103.98,48.14 85.2,29.36 51.31,29.36 47.04,25.09 34.19,25.09 v1(31.52,22.43)
  BOTTOM w0.089: v1(129.87,96.49) 130.87,97.48 R2357.1
PCH_AZ_RST#: length 8.6
  BOTTOM w0.076: UC1.AU8 125.73,104.59 125.73,104.11 125.7,104.07 125.7,102.55 125.68,102.54
  BOTTOM w0.089: 125.68,102.54 125.68,102.02 126.42,101.28 126.42,100.81 v2(126.75,100.49) 126.75,100.07 128.43,98.38 128.62,98.38 R2358.2
PCH_AZ_SDOUT: length 10.2
  BOTTOM w0.076: 124.95,102.25 124.95,103.13 124.82,103.26 124.55,103.26 124.3,103.52 124.3,104.34 123.94,104.7 UC1.AU11
  BOTTOM w0.089: RC3.2 RC8.2 R2356.2 127.24,98.2 v2(126.2,99.24) 126.07,99.38 126.07,101.13 124.95,102.25
PCH_AZ_SYNC: length 11.5
  TOP w0.089: v1(128.17,99.27) 128.43,99.53 128.43,101.36 127.76,102.02 125.73,102.02 v2(124.29,103.46) 123.82,103.93 v1(123.53,103.93)
  BOTTOM w0.076: v1(123.53,103.93) 123.83,104.23 UC1.AV11
  BOTTOM w0.089: R2357.2 129.94,97.48 129.48,97.94 129.48,98.35 129.19,98.64 128.81,98.64 v1(128.17,99.27)
PCH_BATLOW#: length 20.5
  TOP w0.089: v1(128.66,107.48) 129.09,107.9 129.57,107.9 130.28,107.19 135.52,107.19 137.57,109.24 137.92,109.24
  TOP w0.102: RC31.2 146.32,109.42 v2(145.54,109.42) 144.3,109.42 144.12,109.24 137.92,109.24
  BOTTOM w0.089: UC1.AN4 128.33,107.14 v1(128.66,107.48)
PCH_DPWROK: length 9.5
  TOP w0.089: v1(129.73,101.2) v2(129.09,100.56) 128.74,100.21 128.74,99.08 RE37.1 RC33.1
  BOTTOM w0.076: v1(129.73,101.2) 129.35,101.58 128.2,101.58 127.64,102.14 127.64,102.52 127.36,102.8 127.36,103.98 UC1.AV5
PCH_GPIO9: length 23.9
  TOP w0.089: v1(129.28,107.48) 129.74,107.01 135.59,107.01 137.53,108.94 137.92,108.94
  TOP w0.102: v1(149.92,107.64) v2(149,107.64) 146.91,107.64 146.37,107.11 146.04,107.11 144.99,108.15 144.68,108.15 143.89,108.94 137.92,108.94
  BOTTOM w0.076: v1(129.28,107.48) 128.98,107.78 UC1.AM3
  BOTTOM w0.102: v1(149.92,107.64) 149.46,108.1 RC125.2
PCH_GPIO12: length 2.1
  TOP w0.089: T182.1 126.18,109.07 126.84,108.41 v1(126.97,108.41)
  BOTTOM w0.089: UC1.AM7 126.7,108.13 v1(126.97,108.41)
PCH_GPIO14: length 2.6
  TOP w0.089: T126.1 129.16,109.92 128.08,109.92 v1(127.83,110.17)
  BOTTOM w0.076: v1(127.83,110.17) 127.95,110.06 UC1.AH4
PCH_GPIO25: length 1.1
  TOP w0.089: v1(128.04,107.45) 128.36,107.77 T127.1
  BOTTOM w0.089: UC1.AM4 128.33,107.74 v1(128.04,107.45)
PCH_GPIO35: length 9.7
  IN3 w0.127: v1(132.23,116.75) 132.23,116.66 133.44,115.45 138.08,115.45 v1(138.29,115.66)
  BOTTOM w0.076: UC1.U1 131.66,116.09 132.23,116.67 v1(132.23,116.75)
  BOTTOM w0.102: RP37.2 v1(138.29,115.66)
PCH_GPIO37: length 13
  BOTTOM w0.076: 137.32,115.07 137.32,113.68 136.81,113.17 135.45,113.17 135.25,113.37 133.26,113.37 132.77,113.85 131.51,113.85 130.75,113.1 UC1.AC1
  BOTTOM w0.089: 137.32,115.07 137.32,115.26 137,115.58 v2(137,115.83) 137,116.33 137.39,116.72 137.92,116.72
  BOTTOM w0.102: 137.92,116.72 138.12,116.72 138.68,116.16 RP37.3
PCH_GPIO44: length 15.8
  TOP w0.089: v1(134.13,109.23) 134.59,109.23 134.97,108.85 v2(135.37,108.85) 136.3,108.85 137,109.55 137.8,109.55 137.92,109.68
  TOP w0.102: 137.92,109.68 137.99,109.74 142.35,109.74 v1(142.4,109.69)
  BOTTOM w0.076: v1(134.13,109.23) 133.55,109.81 130.09,109.81 129.92,109.64 129.14,109.64 129.1,109.68 128.62,109.68 UC1.AK4
  BOTTOM w0.102: v1(142.4,109.69) 142.15,109.94 RC104.1
PCH_GPIO46: length 27.3
  IN3 w0.084: 137.82,111.27 135.72,111.27 134.42,112.57 131.42,112.57 v1(129.32,110.47)
  IN3 w0.127: 137.82,111.27 138.95,111.27 139.84,110.38 143.15,110.38 143.83,109.7 149.39,109.7 149.4,109.7 149.75,109.7 149.75,109.7 150.06,109.7 v1(150.78,108.98)
  BOTTOM w0.076: v1(129.32,110.47) 128.98,110.82 UC1.AG3
  BOTTOM w0.102: RC124.2 150.35,107.21 150.62,107.49 v2(150.62,108.12) 150.62,108.82 v1(150.78,108.98)
PCH_GPIO47: length 1.2
  TOP w0.089: v1(126.62,113.07) 126.62,113.31 T174.1
  BOTTOM w0.089: v1(126.62,113.07) 126.99,113.45 UC1.AB6
PCH_GPIO48: length 3.2
  TOP w0.089: T124.1 128.54,117.52 128.17,117.9 v1(127.95,117.9)
  BOTTOM w0.076: v1(127.95,117.9) 128.02,117.82 128.02,116.39 128.33,116.08 UC1.U4
PCH_GPIO49: length 4.6
  BOTTOM w0.076: 133.33,114.33 133.3,114.3 129.23,114.3 UC1.Y3
  BOTTOM w0.089: T125.1 133.33,114.33
PCH_GPIO66: length 9.1
  BOTTOM w0.076: UC1.D3 129.31,123.19 129.75,123.19 129.93,123.38 129.93,123.83 130.14,124.03 131.6,124.03
  BOTTOM w0.089: v2(135.22,126.89) 135.33,126.77 RC118.2 135.04,125.58 RC122.1 134.41,125.31 133.63,124.53 132.1,124.53 131.6,124.03
PCH_GPIO83: length 2.1
  TOP w0.089: v1(126.51,116.82) 127.02,117.33 127.57,117.33 T177.1
  BOTTOM w0.089: UC1.R6 126.99,117.31 v1(126.51,116.82)
PCH_GPIO84: length 1.6
  TOP w0.089: v1(126.65,118.76) 126.65,118.88 126.28,119.25 T176.1
  BOTTOM w0.089: v1(126.65,118.76) 126.99,119.1 UC1.L6
PCH_GPIO85: length 1.5
  TOP w0.089: v1(127.35,117.74) 126.94,118.15 T175.1
  BOTTOM w0.089: UC1.N6 126.99,118.1 v1(127.35,117.74)
PCH_GPIO89: length 2.1
  TOP w0.089: v1(126.58,117.8) 126.14,118.25 125.36,118.25 T178.1
  BOTTOM w0.089: UC1.N7 126.34,118.05 v1(126.58,117.8)
PCH_GPIO90: length 3
  BOTTOM w0.089: UC1.K2 130.01,119.45 130.94,119.45 131.82,120.33 T179.1
PCH_GPIO93: length 3.3
  BOTTOM w0.076: UC1.J2 129.92,120.88 130.47,120.88 130.73,121.15 130.73,121.32 130.83,121.41 131.16,121.41
  BOTTOM w0.089: T180.1 131.33,121.58 131.16,121.41
PCH_GPIO94: length 4.4
  BOTTOM w0.089: T181.1 134.39,122.06 131.19,122.06 130.88,121.75 130.69,121.75 UC1.G1
PCH_HOT#: length 108.6
  TOP w0.089: 135.96,101.45 135.95,101.45 135.95,101.89 135.76,102.09 v1(135.76,102.15)
  TOP w0.102: v1(177.51,51.13) 176.4,52.24 176.4,56.25 175.29,57.36 175.29,71.37 174.84,71.82 174.84,78.51 168.1,85.26 168.1,89.19 163.74,93.55 157.25,93.55 152.72,98.08 v2(144.25,98.08) 139.71,98.08 139.69,98.1 139.27,98.52 139.05,98.74 138.62,98.74 135.96,101.4 135.96,101.45 ; RE7.1 191.41,55.09 v1(191.41,54.92)
  IN3 w0.127: v1(191.41,54.92) 191.41,51.81 190.65,51.05 177.59,51.05 v1(177.51,51.13)
  BOTTOM w0.076: UC1.AU4 128.3,104.72 128.66,104.35 128.66,104.13 128.84,103.96 129.06,103.96 129.29,103.73 129.29,103.12 129.34,103.07 129.34,102.73 129.54,102.53 131.57,102.53
  BOTTOM w0.089: 135.02,102.47 R2330.2 135.54,102.49 135.55,102.49 135.73,102.31 135.73,102.18 v1(135.76,102.15)
  BOTTOM w0.102: 131.57,102.53 132.12,101.98 134.52,101.98 135.02,102.47
PCH_INTVRMEN: length 12.6
  BOTTOM w0.076: UC1.AV7 125.86,103.98 125.86,102.34
  BOTTOM w0.089: 125.86,102.34 125.86,102.09 126.6,101.35 126.6,101.13 127.96,99.77 128.33,99.77 129.46,98.64 v2(130.51,98.64) 131.35,97.8 131.35,97.08 131.57,96.85
  BOTTOM w0.102: RC2.1 133.04,96.39 RC1.2 132.03,96.39 131.57,96.85
PCH_JTAG_JTAGX: length 9.7
  BOTTOM w0.076: 90.27,111.64 UC1.AE63
  BOTTOM w0.102: 90.27,111.64 89.25,110.61 86.13,110.61 86.07,110.68 RC130.1 84.64,110.68 RC59.1 RC62.2 84.62,112.27 v2(84.19,112.7)
PCH_JTAG_RST#: length 68.2
  TOP w0.102: v1(67.34,89.58) v4(69.85,89.58) 73.37,93.1 73.37,98.94 75.49,101.06 75.49,105.31 75.89,105.71 75.89,109 75.17,109.73 73.77,109.73 72.71,110.79 72.71,112.99 72.95,113.23 73.55,113.23 R2341.2 RC57.2
  BOTTOM w0.076: 90.64,104.7 91.16,105.22 91.79,105.22 92.11,104.9 UC1.AU62
  BOTTOM w0.089: 87.92,101.98 87.12,101.18
  BOTTOM w0.102: 87.12,101.18 84.15,98.21 77.9,98.21 74.95,95.26 74.95,90.03 74.49,89.58 v1(67.34,89.58) ; 90.64,104.7 87.92,101.98
PCH_JTAG_TCK: length 58.6
  TOP w0.102: v1(66.62,88.89) v4(66.62,88.27)
  IN3 w0.127: v1(66.62,88.89) 66.79,88.71 70.25,88.71 71.53,89.99 71.53,98.37 75.15,101.99 75.15,106.06 v1(76.74,107.64)
  BOTTOM w0.076: 90.39,111.45 91.35,111.45 91.46,111.34 91.71,111.34 91.82,111.39 91.87,111.42 92.08,111.42 UC1.AE62
  BOTTOM w0.102: v1(66.62,88.89) 66.78,88.73 66.78,86.95 64.74,84.91 60.54,84.91 59.1,86.36 RP46.4 ; v1(76.74,107.64) 77.24,108.15 78.42,108.15 79.18,108.91 82.32,108.91 83.02,108.21 83.93,108.21 RC135.1 RC65.2 84.81,109.99 87.71,109.99 88.15,110.42 89.36,110.42 90.39,111.45
PCH_JTAG_TDI: length 26.9
  TOP w0.089: 88.45,111.3 88.64,111.3 v1(88.67,111.26) 89.06,110.88 90.14,110.88 90.83,111.58 92.87,111.58 93.3,112.01 v1(93.3,112.03)
  TOP w0.102: v1(80.31,110.56) 82.53,112.79 86.96,112.79 v4(87.36,112.38) 88.45,111.3
  BOTTOM w0.089: v1(88.67,111.26) 88.4,110.99 RP48.8 ; v1(93.3,112.03) 92.95,112.38 UC1.AD61
  BOTTOM w0.102: v1(80.31,110.56) 79.68,109.94 79.52,109.94 78.22,108.63 76.15,108.63 75.75,108.23 75.75,105.77 75.49,105.52 75.49,104.49 75.21,104.21 RC44.1
PCH_JTAG_TDO: length 25.9
  TOP w0.089: 88.91,111.96 89.31,111.57 v1(89.31,111.26)
  TOP w0.102: 88.91,111.96 RC63.2 87.77,113.1 82.24,113.1 v4(81.23,112.09) v1(79.72,110.59) ; v1(92.65,112.01) 90.82,112.01 90.07,111.26 v1(89.31,111.26)
  BOTTOM w0.089: UC1.AE61 92.95,111.71 v1(92.65,112.01) ; 88.91,111.66 v1(89.31,111.26)
  BOTTOM w0.102: RC43.1 74.98,106.95 74.98,109.43 75.45,109.9 75.45,110.18 75.86,110.59 v1(79.72,110.59) ; RP48.7 88.27,111.49 88.48,111.71 88.87,111.71 88.91,111.66
PCH_JTAG_TMS: length 36.8
  TOP w0.102: v1(76.32,113.04) v4(76.99,113.04)
  BOTTOM w0.089: 88.91,111.99 91.9,111.99 UC1.AD62
  BOTTOM w0.102: 88.74,111.99 88.74,112.54 88.48,112.79 86.13,112.79 85.88,113.04 v1(76.32,113.04) 72.36,113.04 69.94,110.63 65.59,110.63 65.15,110.19 65.15,106.21 65.94,105.42 RC46.1 ; 88.74,111.99 RP48.6 ; 88.74,111.99 88.91,111.99
PCH_OPI_COMP: length 7.7
  BOTTOM w0.076: UC1.AW15 121.95,103.29 121.95,101.66 122.71,100.9
  BOTTOM w0.305: 122.71,100.9 122.77,100.85 122.77,100.41 122.93,100.25 v2(122.93,99.51) 122.77,99.34 122.77,98.76 124.28,97.24 RC101.1
PCH_PCIE_RCOMP: length 5.2
  BOTTOM w0.089: RC91.2 114.66,130.38 v2(114.59,130.45)
  BOTTOM w0.305: UC1.A27 114.59,125.72 114.59,126.88 114.9,127.18 114.9,128.7 114.66,128.94 RC91.2
PCH_PLTRST#: length 32
  TOP w0.089: 137.92,107.93 136.74,106.75 v4(136.28,106.75) 129.75,106.75 129.42,107.08 127.89,107.08 127.47,107.5 127.47,108.63 127.23,108.87 126.67,108.87 126.45,109.08 126.45,109.4 126.71,109.66 v1(126.71,110.18)
  TOP w0.102: 148.25,106.58 148.25,107.13 148.02,107.36 146.95,107.36 146.47,106.88 145.94,106.88 144.9,107.92 144.59,107.92 143.79,108.72 138.71,108.72 137.92,107.93 ; 148.25,106.58 148.25,106.44 ; 148.25,106.58 148.84,107.16 150.4,107.16 CC33.1 ; 148.25,106.44 147.74,106.44 147.6,106.3 UC3.2 ; 148.25,106.44 UC3.1
  BOTTOM w0.076: v1(126.71,110.18) 126.71,110.28 UC1.AG7
PCH_PWR_EN: length 70.5
  TOP w0.102: v1(162.46,36.71) 163.35,37.6 163.35,52.91 163.99,53.54 v2(167.12,53.54) 170.86,53.54 175.8,48.6 175.8,47.19 176.77,46.21 178.22,46.21 RE36.1
  IN1 w0.127: v1(142.33,31.63) 147.41,36.71 v1(162.46,36.71)
  BOTTOM w0.102: R416.1 143.04,25.33 142.33,26.05 v1(142.33,31.63)
PCH_PWROK: length 137.5
  TOP w0.089: v1(132.81,112.02) 132.81,111.96 132.68,111.84 RP50.2 ; v1(132.81,112.02) 132.81,112.21 132.68,112.34 RP50.3 ; v1(132.81,112.02) 133.45,112.67 CC34.1
  TOP w0.102: 197.11,33.81 v4(198.1,33.81) ; 197.11,33.81 RE18.1 195.93,34.32 v1(195.8,34.45) 195.59,34.66 UE1.32 ; 197.11,33.81 CE31.1
  IN1 w0.084: v1(132.81,112.02) 130.58,112.02 130.33,111.77 130.33,110.78 130.81,110.29 134.44,110.29 134.66,110.52 136.06,110.52 137.06,111.52 137.72,111.52
  IN1 w0.127: v1(191.75,44.07) 191.75,44.09 191.58,44.26 191.58,47.43 191.91,47.76 191.91,50.2 191.47,50.64 191.47,53.9 190.73,54.64 190.73,56.43 189.83,57.33 189.83,64.37 188.79,65.41 188.79,75.45 182.49,81.75 178.46,81.75 174.12,86.09 167.43,86.09 165.01,88.5 165.01,91.19 153.95,102.25 153.95,104.07 152.76,105.27 151.95,105.27 151.63,105.59 151.63,108.75 150.88,109.5 148.87,109.5 146.94,111.43 146.4,111.43 145.9,111.92 145.9,112.2 144.8,113.3 144.37,113.3 144.26,113.19 143.48,113.19 141.8,111.52 137.72,111.52
  IN3 w0.127: v1(195.8,34.45) 195.8,35.32 196.85,36.37 196.85,41.38 195.48,42.75 192.65,42.75 191.75,43.65 v1(191.75,44.07)
PCH_PWROK_R: length 17.6
  TOP w0.089: RP50.7 129.87,111.84 129.17,111.14 v1(127.85,111.14) ; v2(126.68,101.71) 127,101.39 v1(127,101.35)
  IN3 w0.084: v1(127,101.35) 126.15,102.2 126.15,108.33 126.01,108.47 126.01,109.72 126.15,109.87 126.15,110.65 126.27,110.76 127.48,110.76 v1(127.85,111.14)
  BOTTOM w0.089: v1(127,101.35) 127,101.35 126.89,101.35 126.15,102.08 UC1.AY7
PCH_RSMRST#_R: length 8.6
  TOP w0.089: RC41.2 126.06,98.08 RC33.2 126.06,99.49 v2(126.62,100.04) v1(127.74,101.17)
  BOTTOM w0.076: UC1.AW6 126.84,103.52 126.61,103.29 126.61,102.1 126.78,101.93 126.87,101.93 126.88,101.93 127.35,101.93 127.74,101.53 v1(127.74,101.17)
PCH_RTCRST#: length 157.5
  TOP w0.089: 131.57,96.25 131.23,96.6 131.23,97.6 130.84,97.99 130.84,100.94 127.2,104.58 v1(126.53,104.58)
  TOP w0.102: 131.57,96.25 RC6.2 132.31,95.51 CC4.2 133.05,94.45 133.71,93.79 152.26,93.79 155.08,90.97 162.7,90.97 163.34,91.6 164.53,91.6 166.78,89.36 166.78,85.43 174.02,78.19 v4(174.02,74.74) 174.02,71.37 174.58,70.81 174.58,58.49 v1(174.08,58)
  BOTTOM w0.076: UC1.AU7 126.23,104.88 v1(126.53,104.58)
  BOTTOM w0.102: CMOS1.2 113.66,47.52 114.71,48.57 126.92,48.57 131.5,53.15 161.41,53.15 166.24,57.99 174.08,57.99 v1(174.08,58)
PCH_RTCX1: length 26.4
  BOTTOM w0.076: UC1.AW5 128.02,103.21 128.02,102.36
  BOTTOM w0.102: RG3.2 146.86,102.3 YC1.1 147.3,100.72 147.65,100.37 147.65,99.82 146.97,99.13 CC1.2 146.03,98.25 RC4.1 v2(143.55,98.25) 139.43,98.25 136.51,101.16 130.61,101.16 129.79,101.98 128.4,101.98 128.02,102.36
PCH_RTCX1_R: length 192.5
  TOP w0.102: UG1.9 73.03,43.49 73.18,43.64 v2(75.34,43.64) 75.59,43.64 75.85,43.89 v1(75.85,46.47)
  IN1 w0.127: v1(75.85,46.47) 75.26,47.05 75.26,54.13 v1(76.11,54.98)
  IN3 w0.127: v1(147.79,103.22) 148.86,102.16 150.35,102.16 151.91,100.59 160.9,100.59 184.42,77.08 184.42,71.44 186.64,69.21 186.64,65.33 179.57,58.25 176.73,58.25 174.55,56.07 173.84,56.07 172.63,54.85 118.96,54.85 117.57,56.25 82.67,56.25 81.4,54.98 v1(76.11,54.98)
  BOTTOM w0.102: RG3.1 v1(147.79,103.22)
PCH_RTCX2: length 25.4
  BOTTOM w0.102: UC1.AY5 127.83,102.79 127.83,102.28 128.32,101.79 129.71,101.79 130.82,100.67 136.17,100.67 139.09,97.75 v2(141.4,97.75) 146.42,97.75 RC4.2 147.78,99.11 CC2.2 149.36,100.71 YC1.2
PCH_SMB_ALERT#: length 21
  IN3 w0.084: v1(134.01,107.83) 134.39,107.45 135.47,107.45 135.54,107.52 137.92,107.52
  IN3 w0.127: 137.92,107.52 138.4,107.52 138.84,107.96 144.29,107.96 145.17,107.08 v1(145.17,107.08)
  BOTTOM w0.076: v1(134.01,107.83) 133.51,107.33 130.97,107.33 130.85,107.45 130.58,107.45 130.47,107.56 130.08,107.56 UC1.AN2
  BOTTOM w0.102: v1(145.17,107.08) 145.17,107.08 v2(143.46,108.79) 143.19,109.06 R2329.2
PCH_SPI_CLK: length 14
  IN1 w0.084: v1(129.28,113.47) 130.04,113.47 131,114.43 137.73,114.43 137.92,114.62
  IN1 w0.127: v1(140.94,116.06) 139.36,116.06 137.92,114.62
  BOTTOM w0.076: v1(129.28,113.47) 128.98,113.77 UC1.AA3
  BOTTOM w0.102: v1(140.94,116.06) 141.28,116.06 141.48,115.86 R2333.2
PCH_SPI_CLK_R: length 44.3
  IN3 w0.127: v1(143.35,116.49) 143.66,116.49 144.06,116.89 144.99,116.89 145.12,117.02 150.98,117.02 v1(151.4,117.45)
  BOTTOM w0.102: v1(151.4,117.45) 154.14,114.71 154.14,111.21 154.78,110.58 154.78,109.97 155.3,109.45 155.3,105.75 156.3,104.75 v2(156.3,103.77) 156.3,94 159.33,90.97 159.33,88.69 158.67,88.04 U2302.6 ; v1(143.35,116.49) 142.71,115.85 142.55,115.85 ; R2333.1 142.55,115.85 ; 142.55,115.85 C2326.1
PCH_SPI_CS0#: length 68
  IN3 w0.084: v1(126.52,114.94) 126.07,115.39 125.63,115.39 125.5,115.52 125.5,116.03 125.76,116.28 126.77,116.28 127.02,116.53 127.39,116.53 128.17,117.3 130.15,117.3 130.78,117.93 133.68,117.93 134.31,117.29 136.17,117.29 137.54,118.67 137.72,118.67
  IN3 w0.127: 137.72,118.67 139.7,118.67 140.01,118.97 142.94,118.97 143.35,119.38 147.42,119.38 147.72,119.09 149.18,119.09 v1(149.28,119.18)
  BOTTOM w0.076: UC1.Y7 126.34,114.76 v1(126.52,114.94)
  BOTTOM w0.102: v1(149.28,119.18) 149.28,116.84 152.12,114 152.12,108.47 152.54,108.04 152.54,107.78 153.11,107.2 153.11,97.28 147.6,91.77 v2(147.6,87.41) 147.6,86.69 148.79,85.5 U2302.1
PCH_SPI_HOLD1#: length 48.9
  IN3 w0.127: v1(141.51,118.46) 141.51,118.31 142.3,117.52 143.23,117.52 143.63,117.92 144.56,117.92 144.7,118.06 149.74,118.06 150.26,118.58 150.86,118.58 v1(151.4,118.04)
  BOTTOM w0.102: v1(141.51,118.46) 141.01,117.96 RP39.4 ; v1(151.4,118.04) 151.5,118.04 154.63,114.91 154.63,111.41 155.26,110.78 155.26,110.17 155.78,109.65 155.78,105.95 156.78,104.95 v2(156.78,97.59) 156.78,94.2 159.81,91.17 159.81,87.78 158.79,86.77 U2302.7
PCH_SPI_HOLD#: length 18.3
  IN1 w0.127: v1(140.94,117.3) 141.57,116.66 141.57,115.83 141.18,115.44 139.46,115.44 138.09,114.07 136.44,114.07 136.05,113.68 136.05,112.85 v1(135.98,112.79)
  BOTTOM w0.076: UC1.AF1 130.32,111.64 v2(134.43,111.64) 134.84,111.64 v1(135.98,112.79)
  BOTTOM w0.102: RP39.5 139.44,117.96 139.92,117.48 140.68,117.48 140.86,117.3 v1(140.94,117.3) 141.3,117.3 R2335.2
PCH_SPI_MISO: length 14.1
  IN1 w0.084: v1(127.82,113.98) 130.26,113.98 131.66,115.38 133.94,115.38 136.43,117.87 v1(137.76,117.87)
  BOTTOM w0.089: UC1.AA4 127.92,113.88 v1(127.82,113.98) ; 137.92,118.54 137.76,118.37 v1(137.76,117.87)
  BOTTOM w0.102: 137.92,118.54 138.27,118.88 138.38,118.88 138.46,118.96 RP39.7
PCH_SPI_MISO_1: length 48.4
  IN3 w0.127: v1(142.14,118.46) 142.56,118.03 143.02,118.03 143.86,118.88 147.12,118.88 147.43,118.57 149.53,118.57 v1(149.76,118.8)
  BOTTOM w0.102: v1(149.76,118.8) 149.76,117.04 152.7,114.11 152.7,108.67 153.03,108.34 153.03,107.98 153.6,107.41 153.6,96.95 148.17,91.53 v2(148.17,90.43) 148.17,87.51 148.92,86.77 U2302.2 ; v1(142.14,118.46) 141.64,118.96 RP39.2
PCH_SPI_MOSI: length 13.8
  IN1 w0.084: 137.92,117.36 136.2,117.36 133.85,115.01 v1(133.75,115.01)
  IN1 w0.127: 137.92,117.36 138.16,117.36 138.84,118.04 138.84,118.76 v1(138.2,119.39)
  BOTTOM w0.076: UC1.AA2 129.86,113.84 130.16,114.14 133.65,114.14 133.75,114.23 v1(133.75,115.01)
  BOTTOM w0.102: RP39.8 138.27,119.46 v1(138.2,119.39)
PCH_SPI_MOSI_1: length 45.8
  IN3 w0.127: v1(140.87,119.84) 141.18,119.53 142.76,119.53 143.13,119.89 147.64,119.89 147.93,119.6 148.81,119.6 v1(148.87,119.67)
  BOTTOM w0.102: RP39.1 140.69,119.46 140.87,119.64 v1(140.87,119.84) ; v1(148.87,119.67) 150,119.67 150.9,118.76 150.9,117.26 153.66,114.51 153.66,111.01 154.29,110.38 154.29,109.77 154.82,109.25 154.82,106.51 154.56,106.26 154.56,95.05 158.84,90.77 158.84,89.48 158.67,89.31 U2302.5
PCH_SPI_WP1#: length 46.7
  IN3 w0.127: v1(140.87,118.46) 140.87,118.12 141.99,117 143.44,117 143.85,117.41 144.78,117.41 144.91,117.54 149.94,117.54 v1(150.43,118.03)
  BOTTOM w0.102: v1(150.43,118.03) 150.4,118 150.4,117.09 153.18,114.31 153.18,110.81 153.81,110.18 153.81,107.87 154.08,107.61 154.08,96.63 148.75,91.29 148.75,88.59 149.3,88.04 U2302.3 ; RP39.3 v1(140.87,118.46)
PCH_SPI_WP#: length 18.6
  IN1 w0.084: 137.92,118.25 136.51,118.25 133.97,115.71 131.41,115.71 130.14,114.44 127.67,114.44 v1(127.17,114.94)
  IN1 w0.127: 137.92,118.25 v1(138.33,118.25)
  BOTTOM w0.076: UC1.Y6 126.99,114.76 v1(127.17,114.94)
  BOTTOM w0.102: R2334.2 140.67,116.75 140.45,116.97 138.91,116.97 138.33,117.55 v1(138.33,118.25) 138.46,118.25 138.67,118.46 RP39.6
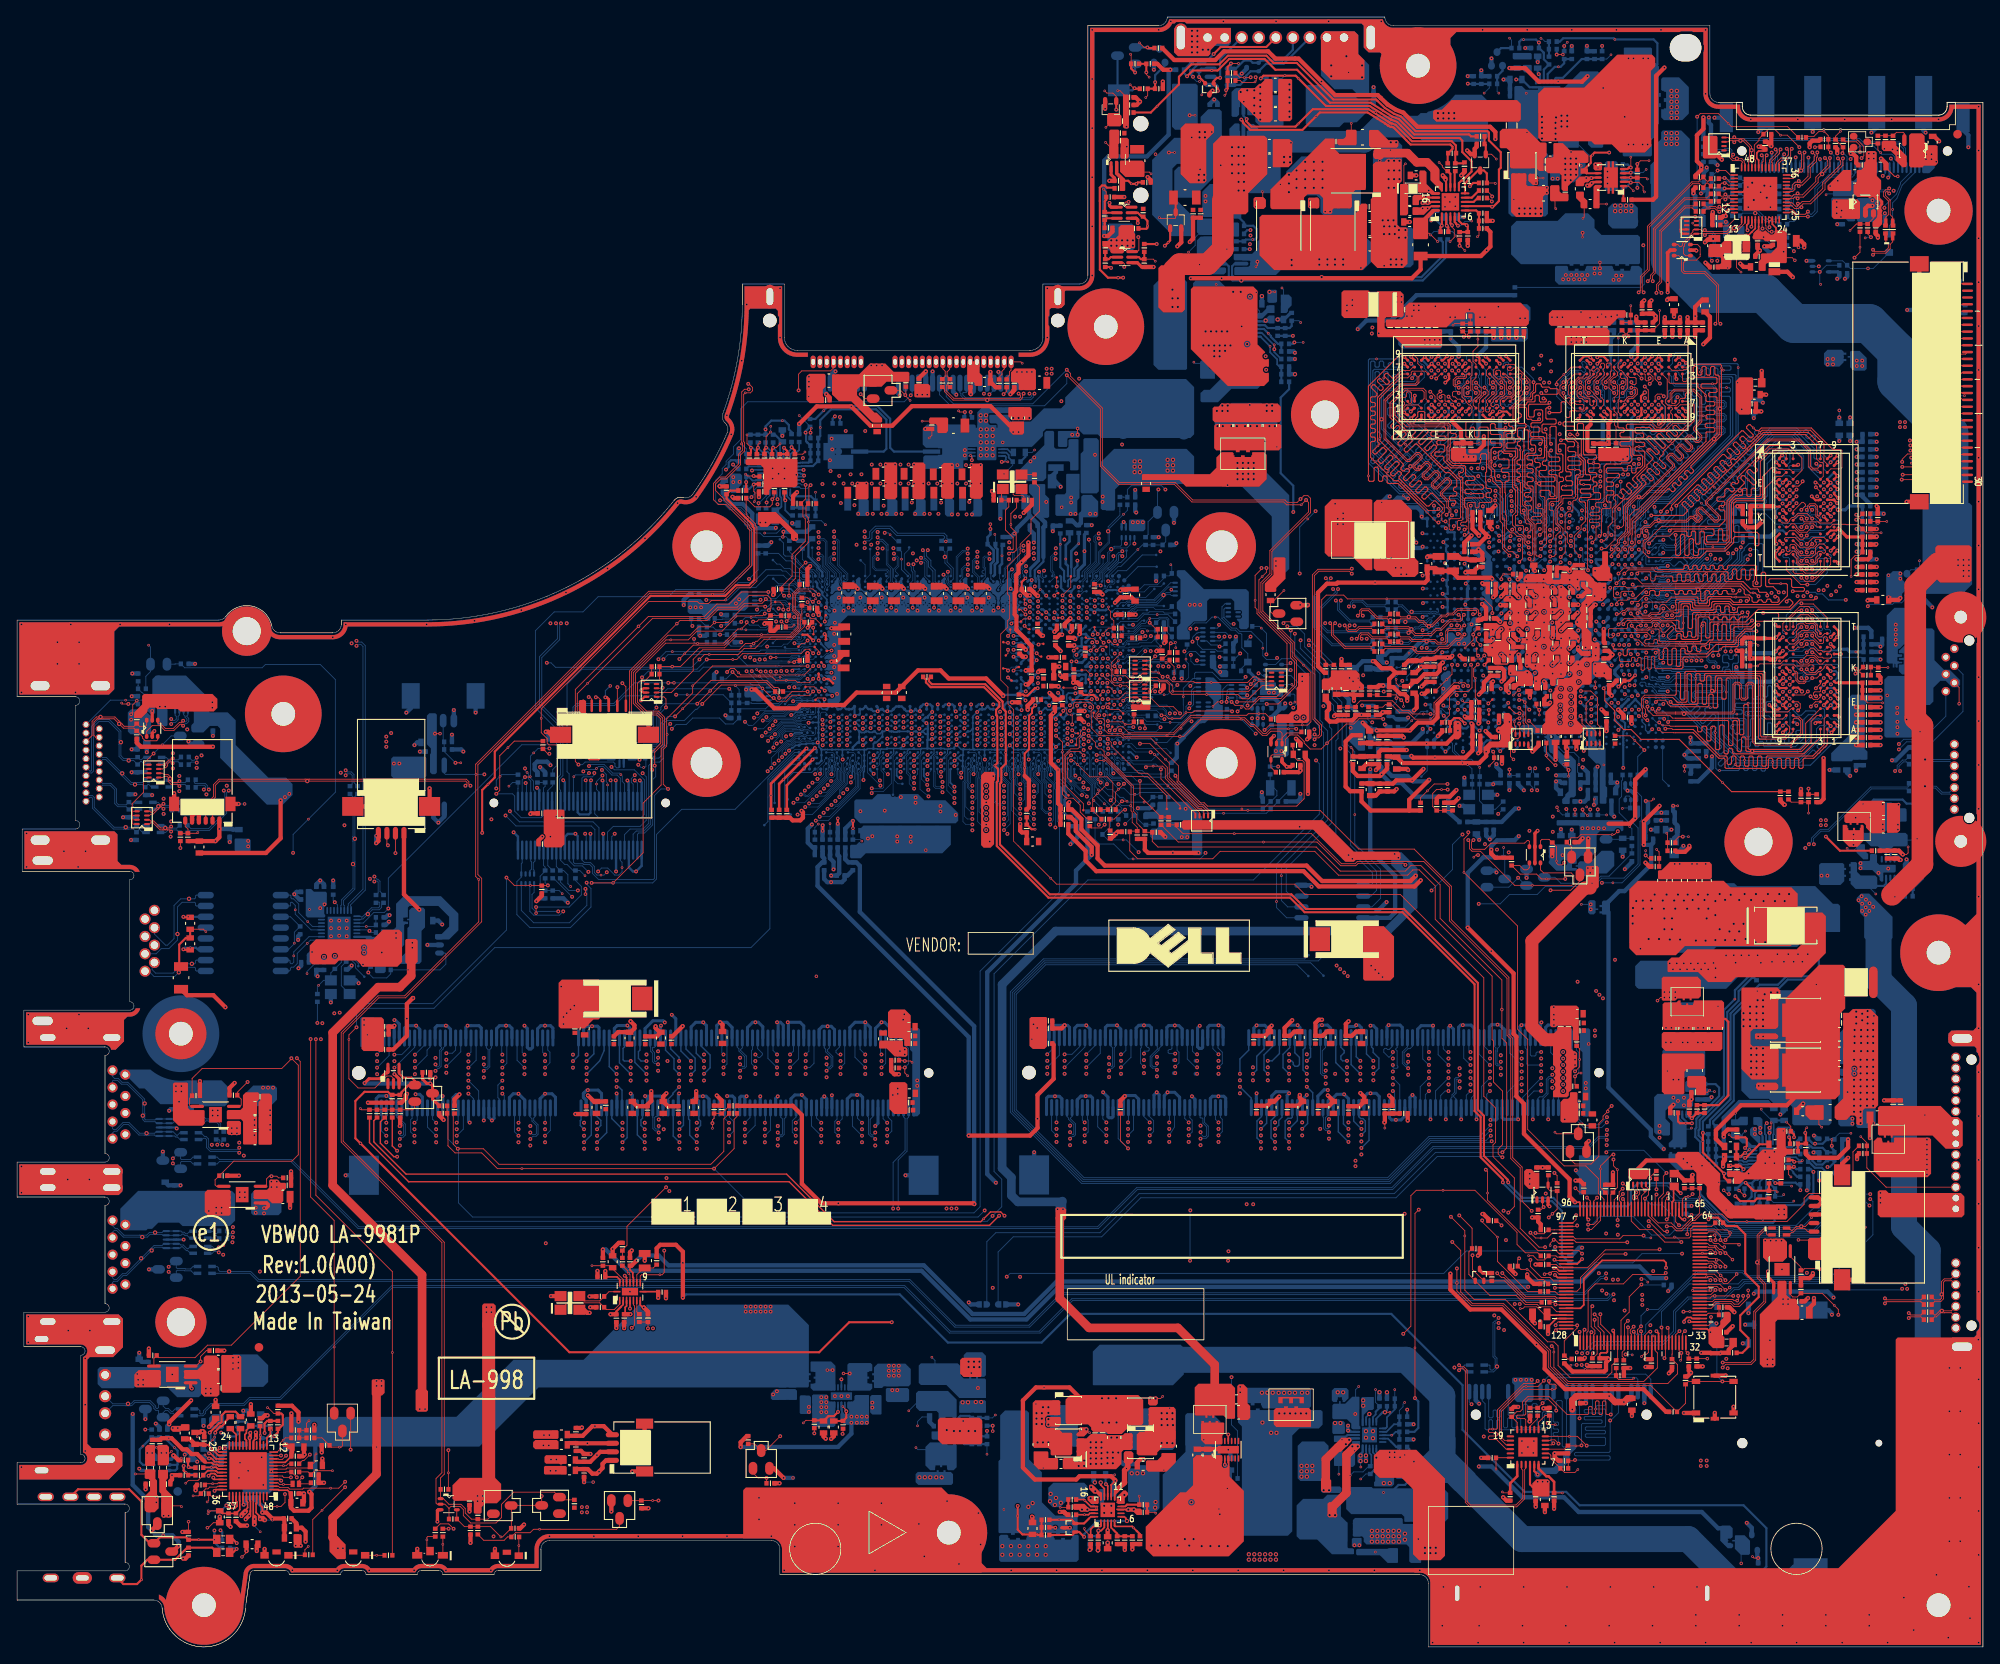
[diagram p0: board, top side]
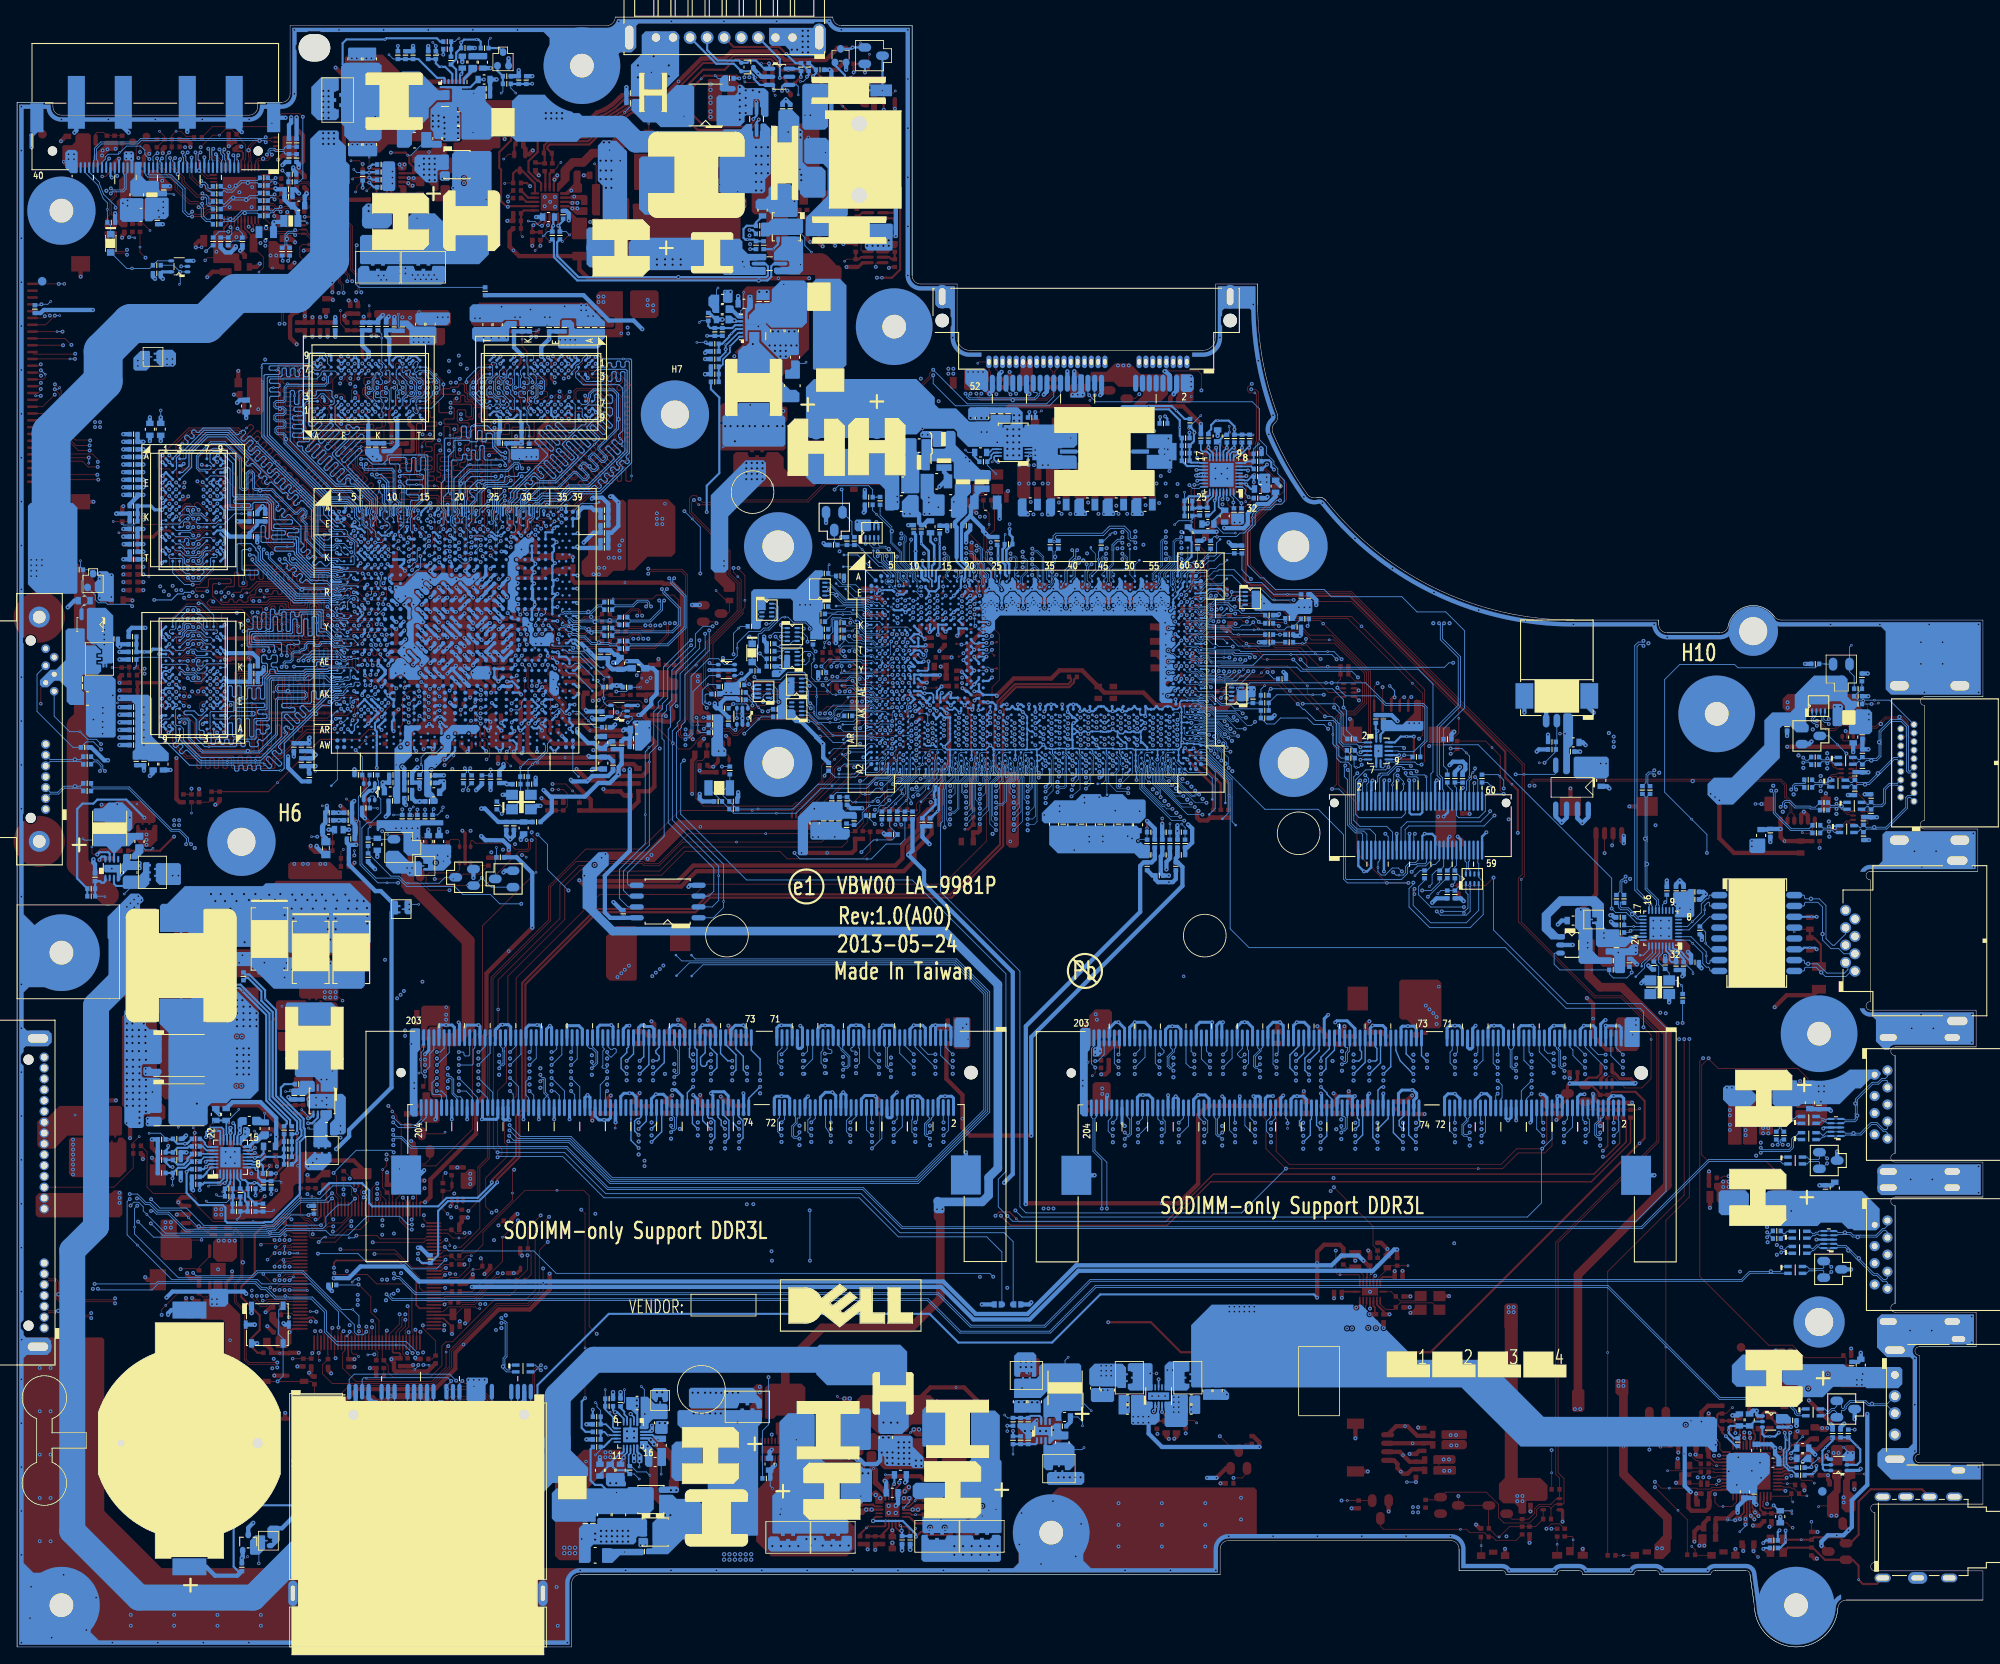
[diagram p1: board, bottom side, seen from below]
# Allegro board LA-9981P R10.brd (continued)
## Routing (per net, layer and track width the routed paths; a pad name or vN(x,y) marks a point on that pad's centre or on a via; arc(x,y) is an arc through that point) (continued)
PCH_X1_R: length 256.1
  TOP w0.089: 118.83,131.11 118.83,130.56 117.57,129.3 117.57,128.2 116.08,126.72 116.08,123.46 116.34,123.2 116.34,120.58 116.08,120.33 116.08,119.56 115.29,118.76 115.29,113.37 116.13,112.52 116.13,110.56 116.79,109.9 116.79,94.47 117.33,93.94
  TOP w0.102: v1(174.77,50.93) 175.48,51.64 175.48,54.99 172.98,57.49 172.98,58.86 173.28,59.17 173.28,63.19 171.9,64.58 171.9,78.45 162.13,88.21 150.96,88.21 149.74,89.43 121.83,89.43 v2(121.14,90.13) 117.33,93.94 ; UG1.5 72.23,40.11 72.36,39.99 72.36,37.73 v1(72.04,37.41) ; RG6.1 119.82,135.98 119.82,133.16 118.83,132.17 118.83,131.11
  IN1 w0.127: v1(174.77,50.93) 174.77,48.63 175.15,48.25 175.15,40.59 v1(175.53,40.21)
  IN3 w0.127: v1(72.04,37.41) 72.76,38.14 91.23,38.14 94.14,41.04 174.69,41.04 v1(175.53,40.21)
PCIE_B+: length 1.3
  BOTTOM w0.102: PC1301.1 196.12,60.72 v2(196.24,60.84)
PCIE_CRX_C_GTX_N0: length 11.9
  TOP w0.102: 169.13,118.02 168.7,118.02 167.74,117.07 166.75,117.07 166.19,116.51 164.02,116.51 163.47,117.05 160.33,117.05 CV44.2
  TOP w0.109: v1(169.64,118.72) 169.57,118.72 169.44,118.59 169.44,118.34 169.13,118.02
  BOTTOM w0.102: UV1.Y32 169.26,118.99 169.54,118.72 v1(169.64,118.72)
PCIE_CRX_C_GTX_N1: length 10.8
  TOP w0.102: CV46.2 162.15,118.18 163.15,118.18 163.43,117.9 v3(165.2,117.9) 166.12,117.9 166.44,117.58 167.41,117.58 167.65,117.82 167.65,119.01 167.81,119.17 169.1,119.17 169.36,119.43 169.36,119.65 169.49,119.78 v1(169.62,119.78)
  BOTTOM w0.102: v1(169.62,119.78) 169.62,120.14 UV1.W32
PCIE_CRX_C_GTX_N2: length 12
  TOP w0.102: CV48.2 160.32,119.39 163.02,119.39 163.82,118.6 165.77,118.6 166.38,119.21 166.92,119.21 167.99,120.27 169.19,120.27 169.39,120.48 169.39,120.85 v1(169.56,121.02)
  BOTTOM w0.102: v1(169.56,121.02) 169.26,121.32 UV1.U32
PCIE_CRX_C_GTX_N3: length 12.1
  TOP w0.102: v1(171.42,121.03) 171.29,121.17 171.29,121.54 171.1,121.73 168.77,121.73 168.25,121.21 167.68,121.21 167.46,120.98 166.92,120.98 165.8,119.86 165.29,119.86 164.83,120.31 164.4,120.31 163.94,120.77 v3(163.11,120.77) 162.17,120.77 CV50.2
  BOTTOM w0.102: UV1.U29 171.66,121.33 171.42,121.08 v1(171.42,121.03)
PCIE_CRX_C_GTX_P0: length 11.8
  TOP w0.102: CV43.2 160.32,117.28 163.57,117.28 v3(163.79,117.06) 164.13,116.72 166.1,116.72 166.65,117.27 167.65,117.27 168.61,118.23 169.03,118.23 169.04,118.23
  TOP w0.109: v1(168.86,118.77) 168.97,118.88 169.11,118.88 169.23,118.75 169.23,118.43 169.04,118.23
  BOTTOM w0.102: UV1.Y33 168.46,119.17 v1(168.86,118.77)
PCIE_CRX_C_GTX_P1: length 10.7
  TOP w0.102: CV45.2 162.17,118.42 163.23,118.42 163.53,118.13 166.2,118.13 166.53,117.8 167.32,117.8 167.44,117.91 167.44,119.1 167.72,119.38 169.03,119.38 169.16,119.51 169.16,119.76 169.03,119.89 168.88,119.89 v1(168.76,119.78)
  BOTTOM w0.102: v1(168.76,119.78) 168.76,120.19 UV1.W33
PCIE_CRX_C_GTX_P2: length 12
  TOP w0.102: v1(168.95,121.02) 169.18,120.79 169.18,120.57 169.1,120.48 167.9,120.48 166.84,119.42 166.29,119.42 165.69,118.83 163.91,118.83 v3(163.41,119.32) 163.12,119.62 160.33,119.62 CV47.2
  BOTTOM w0.102: v1(168.95,121.02) 168.63,121.02 168.46,121.19 UV1.U33
PCIE_CRX_C_GTX_P3: length 12.2
  TOP w0.102: v1(170.64,121.09) 170.89,121.09 171.08,121.28 171.08,121.46 171.02,121.52 168.85,121.52 168.33,121 167.76,121 167.54,120.78 167.01,120.78 165.87,119.65 v3(165.47,119.65) 165.2,119.65 164.74,120.1 164.29,120.1 163.84,120.55 162.16,120.55 CV49.2
  BOTTOM w0.102: v1(170.64,121.09) 170.83,121.09 171.03,121.29 171.03,121.52 UV1.U30
PCIE_PRX_LANTX_N3: length 105.3
  IN1 w0.084: v1(123.44,121.93) 123.44,122.17 123.57,122.3 123.71,122.3 123.82,122.19 123.82,120.38 123.49,120.05 120.75,120.05 118.81,118.11 118.81,115.97 117.35,114.51 117.35,112.93 116.86,112.44 113.79,112.44 113.6,112.25 97.24,112.25 95.71,110.72 94.42,110.72 94.23,110.91 92.49,110.91 91.85,111.56 90.01,111.56 89.37,112.19 88.91,112.19
  IN1 w0.127: 88.91,112.19 87.89,112.19 87.42,111.72 78.53,111.72 77.89,111.08 74.7,111.08 72.87,109.25 65.77,109.25 64.51,107.99 57.78,107.99 47.75,97.96 47.75,95.34 42.5,90.08 42.12,90.08 v1(41.88,90.33)
  BOTTOM w0.089: v1(123.44,121.93) 123.58,121.93 UC1.G11
  BOTTOM w0.102: CL31.1 42.54,88.58 42.54,89.77 42.29,90.02 42.19,90.02 v1(41.88,90.33)
PCIE_PRX_LANTX_N3_C: length 4.1
  BOTTOM w0.102: CL31.2 42.73,87.02 42.73,86.71 42.45,86.43 41.63,86.43 41.11,85.92 v3(41.11,85.92) 41.03,85.84 41.03,85.84 40.55,85.35 40.35,85.35 40.27,85.28 UL1.18
PCIE_PRX_LANTX_P3: length 105.3
  IN1 w0.084: 88.91,111.92 88.93,111.92 88.95,111.94 89.01,111.94 89.03,111.96 89.28,111.96 89.91,111.33 91.75,111.33 92.4,110.68 94.14,110.68 94.33,110.49 95.81,110.49 97.34,112.02 113.69,112.02 113.88,112.22 116.96,112.22 117.58,112.83 117.58,114.42 119.04,115.88 119.04,118.02 120.84,119.82 123.59,119.82 124.05,120.28 124.05,122.28 123.81,122.53 123.52,122.53 v1(123.41,122.63)
  IN1 w0.127: 88.91,111.92 88,111.92 87.53,111.45 78.64,111.45 78,110.81 74.81,110.81 72.98,108.98 65.88,108.98 64.62,107.72 57.89,107.72 48.02,97.85 48.02,95.22 42.61,89.81 41.95,89.81 v1(41.88,89.74)
  BOTTOM w0.089: v1(123.41,122.63) 123.75,122.29 UC1.F11
  BOTTOM w0.102: CL30.1 42.32,88.42 42.32,89.68 42.2,89.8 41.93,89.8 v1(41.88,89.74)
PCIE_PRX_LANTX_P3_C: length 4.2
  BOTTOM w0.102: UL1.17 40.26,85.68 40.35,85.58 40.45,85.58 40.79,85.92 40.79,85.92 41.11,86.24 41.11,86.24 41.53,86.66 42.35,86.66 42.5,86.81 42.5,87.27 42.45,87.32 42.14,87.32 CL30.2
PCIE_PRX_WLANTX_N4: length 55.6
  IN3 w0.084: 118.12,130.82 118.11,130.81 118.11,130.8 118.12,130.79 118.06,130.73 118.06,130.7 117.37,130.01 117.37,124.81 116.98,124.43 116.98,122.91 117.36,122.54 117.36,121.02 118.39,119.98 122.69,119.98 123.07,120.36 123.07,122.23 122.86,122.44 122.77,122.53 122.66,122.53 v1(122.52,122.67)
  IN3 w0.127: 118.12,130.82 118.49,131.2 118.49,134.29 122.08,137.87 122.08,144.98 119.28,147.78 115.18,147.78 114.33,148.62 106.02,148.62 105.44,149.19 105.44,149.73 105.3,149.87 JMINI.23
  BOTTOM w0.076: v1(122.52,122.67) 122.89,122.29 UC1.F13
PCIE_PRX_WLANTX_P4: length 55.5
  IN3 w0.084: v1(122.52,121.92) 122.41,121.92 122.27,122.06 122.27,122.23 122.33,122.29 122.71,122.29 122.89,122.11 122.89,120.48 122.6,120.19 118.48,120.19 117.57,121.11 117.57,122.63 117.2,123 117.2,124.34 117.58,124.72 117.58,129.92 118.3,130.64
  IN3 w0.127: JMINI.25 106.1,149.78 106,149.68 105.76,149.68 105.69,149.62 105.69,149.3 106.12,148.87 114.44,148.87 115.28,148.03 119.38,148.03 122.33,145.08 122.33,137.77 118.75,134.19 118.75,131.09 118.3,130.64
  BOTTOM w0.089: UC1.G13 122.79,121.64 v1(122.52,121.92)
PCIE_PTX_LANRX_N3: length 14.4
  BOTTOM w0.102: UL1.14 38.35,86.93 38.26,87.02 38.26,87.53 39.59,88.86 39.59,91.51 39.6,91.52 39.6,92.05 39.59,92.07 v3(39.59,94.76) 39.59,99.69 CC32.1
PCIE_PTX_LANRX_N3_C: length 95.9
  IN1 w0.084: v1(112.55,127.17) 112.55,127.25 112.77,127.48 112.94,127.48 113.11,127.31 113.11,125.19 111.58,123.65 95.64,123.65 94.13,122.14 94.13,121.56 94.39,121.3 94.39,120.88 93.67,120.16 92.21,120.16 90.79,118.73 87.05,118.73 87.03,118.76 86.76,118.76
  IN1 w0.127: 86.76,118.76 84.42,118.76 83.4,117.74 74.59,117.74 69.88,113.03 64.63,113.03 64.22,112.62 47.58,112.62 39.76,104.81 39.76,102.93 39.41,102.58 38.71,102.58 v1(38.51,102.78)
  BOTTOM w0.076: UC1.C29 113.06,124.44 112.76,124.73 112.76,125.48 112.16,126.09 112.16,127.28 112.3,127.42 112.36,127.42 112.55,127.24 v1(112.55,127.17)
  BOTTOM w0.102: v1(38.51,102.78) 38.7,102.59 39.18,102.59 39.49,102.28 39.49,101.34 CC32.2
PCIE_PTX_LANRX_P3: length 14.4
  BOTTOM w0.102: UL1.13 37.95,86.93 38.04,87.02 38.04,87.62 39.37,88.95 v3(39.37,91.79) 39.37,94.44 39.35,94.47 39.35,95.01 39.37,95.04 39.37,99.65 CC40.1
PCIE_PTX_LANRX_P3_C: length 95.9
  IN1 w0.084: 86.76,118.48 86.77,118.48 86.79,118.51 90.88,118.51 92.31,119.93 93.77,119.93 94.62,120.78 94.62,121.39 94.36,121.65 94.36,122.05 95.74,123.42 111.67,123.42 113.34,125.09 113.34,127.4 113.04,127.71 112.66,127.71 v1(112.55,127.82)
  IN1 w0.127: v1(38.51,102.2) 38.62,102.31 39.53,102.31 40.03,102.82 40.03,104.69 47.69,112.35 64.34,112.35 64.74,112.76 69.99,112.76 74.7,117.47 83.52,117.47 84.53,118.48 86.76,118.48
  BOTTOM w0.076: UC1.B30 112.57,124.67 112.57,125.4 111.96,126.01 111.96,127.36 112.22,127.61 112.34,127.61 v1(112.55,127.82)
  BOTTOM w0.102: CC40.2 39.27,101.18 39.27,102.19 39.09,102.37 38.68,102.37 v1(38.51,102.2)
PCIE_PTX_WLANRX_N4: length 38.8
  TOP w0.102: v1(117.97,146.95) 117.82,146.8 117.82,146.45 117.56,146.19 v3(113.71,146.19) 109.69,146.19 108.69,147.19 108.69,147.48 CM49.1
  IN3 w0.127: v1(117.97,146.95) 117.83,146.81 117.83,146.03 118.18,145.68 119.42,145.68 120.74,144.36 120.74,138.87 114.8,132.93 114.8,128.1 114.38,127.68 114.18,127.68 114.05,127.56 v1(113.97,127.56)
  BOTTOM w0.076: v1(113.97,127.56) 113.81,127.71 113.47,127.71 113.4,127.63 113.4,126.63 113.51,126.51 113.51,125.45 113.06,125 UC1.B29
PCIE_PTX_WLANRX_N4_C: length 2.3
  TOP w0.102: JMINI.31 108.5,149.86 108.78,149.58 108.78,148.98 CM49.2
PCIE_PTX_WLANRX_P4: length 38.8
  TOP w0.102: CM44.1 109.09,147.97 108.99,147.97 108.9,147.87 108.9,147.28 109.78,146.4 113.43,146.4 113.44,146.42 113.97,146.42 113.99,146.4 117.47,146.4 117.61,146.54 117.61,146.73 v1(117.38,146.95)
  IN3 w0.127: v1(117.38,146.95) 117.58,146.76 117.58,145.92 118.08,145.43 119.32,145.43 120.49,144.26 120.49,138.98 114.54,133.03 114.54,128.21 114.27,127.93 114.1,127.93 113.97,128.06 v1(113.97,128.21)
  BOTTOM w0.076: UC1.A29 113.06,125.56 113.27,125.56 113.35,125.63 113.35,125.81 113.27,125.89 113.17,125.89 113.1,125.97 113.1,126.12 113.17,126.19 113.27,126.19 113.35,126.27 113.35,126.44 113.21,126.59 113.21,127.71 113.39,127.9 113.82,127.9 113.97,128.05 v1(113.97,128.21)
PCIE_PTX_WLANRX_P4_C: length 2.3
  TOP w0.102: JMINI.33 109.3,149.81 109,149.5 109,148.98 CM44.2
PCIE_WAKE#: length 304.1
  TOP w0.089: v1(132.18,107.71) 132.18,108.09 RC97.2
  TOP w0.102: v1(194.84,37.03) 194.39,36.58 UE1.29
  IN1 w0.084: v1(132.18,107.71) 132.49,107.4 137.89,107.4
  IN1 w0.127: 137.89,107.4 137.93,107.4 138.88,108.34 143.87,108.34 144.5,107.71 145.34,107.71 147.19,105.86 148.12,105.86 152.43,101.55 152.43,101.4 159.96,93.87 159.96,91.41 166.81,84.55 168.96,84.55 169.85,83.67 174.39,83.67 177.83,80.23 179.65,80.23 186.83,73.04 186.83,64.81 188.05,63.59 188.05,55.15 187.51,54.61 187.51,52.27 190.01,49.77 190.01,43.51 v1(190.38,43.14)
  IN3 w0.127: v1(41.3,83.96) 47.25,78.02 47.25,51.73 54.5,44.47 54.51,44.47 56.01,42.97 183.4,42.97 185.09,44.66 188.82,44.66 190.35,43.14 v1(190.38,43.14) 191.72,43.14 192.37,42.49 195.37,42.49 196.59,41.27 196.59,37.92 196.4,37.73 195.53,37.73 v1(194.84,37.03)
  BOTTOM w0.102: v1(190.38,43.14) 190.76,43.14 v2(191.12,42.78) ; RL34.2 41.49,83.77 v1(41.3,83.96) 41.19,84.07 UL1.21
PCIE_WAKE#_R: length 5.4
  TOP w0.089: RC34.2 130.9,108.99 130.89,108.98 RC97.1 130.6,108.18 v2(129.86,108.18) 129.57,108.47 127.94,108.47 v1(127.84,108.57)
  BOTTOM w0.076: v1(127.84,108.57) 127.84,109.5 UC1.AJ5
PECI_EC: length 214.1
  TOP w0.102: v1(171.71,50.01) 171.71,49.85 v2(173.51,48.05) 173.51,45.2 177.03,41.68 RE43.2
  IN3 w0.127: v1(171.71,50.01) 140.31,50.01 140.1,49.79 117.26,49.79 115.93,51.13 114.13,51.13 113.12,50.13 70.18,50.13 65.88,54.43 65.88,70.31 61.94,74.24 61.94,87.93 60.65,89.22 60.65,96.06 62.04,97.46 62.04,103.01 61.38,103.68 61.38,109.34 69.18,117.14 77.95,117.14 78.69,116.4 84.41,116.4 85.3,117.3 v1(87.91,117.3)
  BOTTOM w0.076: UC1.N62 92.3,118.21 92.01,117.92 91.46,117.92 91.43,117.95 91.28,118.1 90.81,118.1 90.29,117.58 89.87,117.58 89.59,117.3 v1(87.91,117.3)
PECI_KB9012: length 2.3
  TOP w0.102: RE43.1 180.24,41.68 180.61,41.31 UE1.118
PEG_CLKREQ#: length 96.8
  TOP w0.089: 137.92,113.17 135.45,113.17 v1(134.84,113.78)
  TOP w0.102: 137.92,113.17 138.01,113.08 v2(139.95,113.08) 144.22,113.08 144.87,113.73 145.25,113.73 145.52,113.46 146.23,113.46 146.5,113.73 RP42.6 ; QV28.1 183.16,89.8 182.08,88.72 v1(179.72,88.72)
  IN3 w0.084: 137.82,113.07 137.67,113.07 136.49,114.25 135.31,114.25 v1(134.84,113.78) 134.24,114.37 125.44,114.37 125.12,114.69 125.12,116.03 125.55,116.45 126.69,116.45 127.15,116.91 v1(127.24,116.91)
  IN3 w0.127: v1(179.72,88.72) 176.11,88.72 174.37,90.46 174.37,94.23 172.66,95.94 168.6,95.94 164.68,99.86 164.68,101.8 163.16,103.33 162.2,103.33 159.26,106.26 155,106.26 151.63,109.64 151.63,115.24 151.03,115.84 148.37,115.84 147.69,115.16 144.33,115.16 144.05,114.88 143.07,114.88 141.26,113.07 137.82,113.07
  BOTTOM w0.089: UC1.U5 127.64,116.51 v1(127.24,116.91)
PEG_CRX_GTX_N0: length 40.5
  TOP w0.102: CV44.1 158.74,117.05 155.6,117.05 154.04,118.61 154.04,119.89 v1(153.89,120.03)
  IN3 w0.084: v1(125.37,121.91) 125.37,122.04 125.91,122.59 125.91,123 126.73,123.82 128.32,123.82 128.83,124.32 130.71,124.32 131.4,123.63 134.79,123.63 136.9,121.53 137.64,121.53 137.66,121.5 137.73,121.5 137.75,121.48 137.92,121.48
  IN3 w0.127: v1(153.89,120.03) 154.05,120.2 154.05,120.38 153.97,120.47 152.02,120.47 150.49,121.99 139.67,121.99 139.15,121.48 137.92,121.48
  BOTTOM w0.089: v1(125.37,121.91) 124.99,122.29 UC1.F10
PEG_CRX_GTX_N1: length 40.6
  TOP w0.102: CV46.1 160.59,118.21 158.76,118.21 158.29,118.68 157.58,118.68 157.43,118.52 157.43,118.37 v1(157.59,118.21)
  IN3 w0.084: v1(126.31,121.99) 126.42,122.1 126.53,122.1 126.64,121.99 126.64,121.82 126.98,121.47 134.13,121.47 135.69,119.92 137.55,119.92 137.58,119.9 137.64,119.9 137.66,119.87 137.67,119.87
  IN3 w0.127: 137.67,119.87 140.15,119.87 140.68,120.4 148.21,120.4 148.27,120.46 149.85,120.46 152.3,118.01 153.01,118.01 153.14,117.88 153.14,117.5 153.42,117.22 154.04,117.22 154.32,117.5 154.32,117.88 154.45,118.01 155.42,118.01 155.53,117.9 155.53,117.61 155.78,117.36 157.08,117.36 157.38,117.66 157.38,118 v1(157.59,118.21)
  BOTTOM w0.089: v1(126.31,121.99) 126.01,122.29 UC1.F8
PEG_CRX_GTX_N2: length 41.1
  TOP w0.102: CV48.1 158.74,119.4 157.32,119.4 156.98,119.06 155.99,119.06 155.78,119.27 155.78,119.59 v1(155.59,119.77)
  IN3 w0.084: v1(124.42,121.31) 124.43,121.31 124.77,121.65 124.77,121.79 124.98,122 124.98,122.9 125.33,123.25 125.33,123.49 126.69,124.85 127.15,124.85 127.64,124.36 128.23,124.36 128.64,124.77 131.34,124.77 131.78,124.33 134.9,124.33 136.45,122.77 137.92,122.77
  IN3 w0.127: v1(155.59,119.77) 155.78,119.96 155.78,120.21 154.74,121.24 153.01,121.24 151.49,122.77 137.92,122.77
  BOTTOM w0.089: v1(124.42,121.31) 124.74,120.99 UC1.H10
PEG_CRX_GTX_N3: length 39.7
  TOP w0.102: CV50.1 160.59,120.77 159.42,120.77 158.48,121.71 157.56,121.71 157.37,121.52 157.37,121.14 v1(157.14,120.91)
  IN3 w0.084: v1(127.22,122.69) 127.44,122.47 127.7,122.47 128.31,123.07 133.99,123.07 136.16,120.91 137.82,120.91 137.85,120.94 137.92,120.94
  IN3 w0.127: 137.92,120.94 139.77,120.94 140.32,121.49 150.26,121.49 152.54,119.2 157.17,119.2 157.3,119.34 157.3,120.75 v1(157.14,120.91)
  BOTTOM w0.089: UC1.E6 126.97,122.94 v1(127.22,122.69)
PEG_CRX_GTX_P0: length 40.3
  TOP w0.102: CV43.1 158.74,117.27 155.69,117.27 154.25,118.7 154.25,119.81 v1(154.48,120.03)
  IN3 w0.084: v1(125.37,122.67) 125.47,122.57 125.59,122.57 125.7,122.67 125.7,123.08 126.64,124.03 128.24,124.03 128.74,124.53 130.79,124.53 131.49,123.84 134.88,123.84 136.98,121.74 137.92,121.74
  IN3 w0.127: v1(154.48,120.03) 154.31,120.2 154.31,120.49 154.07,120.72 152.12,120.72 150.6,122.25 139.56,122.25 139.05,121.74 137.92,121.74
  BOTTOM w0.089: v1(125.37,122.67) 125.04,122.67 124.82,122.89 UC1.E10
PEG_CRX_GTX_P1: length 40.7
  TOP w0.102: CV45.1 160.59,118.42 158.85,118.42 158.38,118.89 157.49,118.89 157.21,118.61 157.21,118.42 v1(157.01,118.21)
  IN3 w0.084: 137.67,120.13 135.78,120.13 134.22,121.69 127.07,121.69 126.85,121.9 126.85,122.08 126.61,122.31 126.52,122.31 126.31,122.52 v1(126.31,122.69)
  IN3 w0.127: 137.67,120.13 140.04,120.13 140.57,120.65 148.11,120.65 148.16,120.71 149.95,120.71 152.4,118.26 153.12,118.26 153.39,117.98 153.39,117.61 153.53,117.48 153.93,117.48 154.07,117.61 154.07,117.98 154.34,118.26 155.53,118.26 155.78,118 155.78,117.71 155.89,117.61 156.97,117.61 157.13,117.77 157.13,118.08 v1(157.01,118.21)
  BOTTOM w0.089: UC1.E8 126.06,122.94 v1(126.31,122.69)
PEG_CRX_GTX_P2: length 40.9
  TOP w0.102: CV47.1 158.74,119.62 157.23,119.62 156.89,119.27 156.08,119.27 155.99,119.36 155.99,119.59 v1(156.18,119.77)
  IN3 w0.084: 137.92,123.02 137.91,123.02 137.89,123 137.83,123 137.8,122.98 136.54,122.98 134.98,124.54 131.87,124.54 131.43,124.98 128.55,124.98 128.14,124.57 127.73,124.57 127.24,125.06 126.6,125.06 125.12,123.58 125.12,123.34 124.77,122.99 124.77,122.09 124.61,121.93 124.49,121.93 124.49,121.93 v1(124.42,121.93)
  IN3 w0.127: 137.92,123.02 151.59,123.02 153.11,121.5 154.85,121.5 156.03,120.32 156.03,119.92 v1(156.18,119.77)
  BOTTOM w0.089: UC1.G10 124.71,121.64 v1(124.42,121.93)
PEG_CRX_GTX_P3: length 39.7
  TOP w0.102: v1(157.72,120.91) 157.58,121.05 157.58,121.43 157.65,121.5 158.39,121.5 159.33,120.56 160.59,120.56 CV49.1
  IN3 w0.084: v1(127.22,122.06) 127.42,122.26 127.79,122.26 128.39,122.86 133.91,122.86 136.07,120.7 137.82,120.7 137.84,120.68 137.92,120.68
  IN3 w0.127: 137.92,120.68 139.88,120.68 140.43,121.23 150.15,121.23 152.44,118.95 157.27,118.95 157.56,119.23 157.56,120.75 v1(157.72,120.91)
  BOTTOM w0.089: UC1.F6 126.98,122.29 v1(127.22,122.06)
PEG_CTX_GRX_C_N0: length 61.3
  IN3 w0.084: v1(119.17,128.86) 119.39,128.64 119.93,128.64 121.82,126.76 124.41,126.76 125.11,127.46 130.64,127.46 130.67,127.49
  IN3 w0.127: v1(153.97,125.31) 153.8,125.48 153.8,126.03 147.2,132.64 137.07,132.64 131.93,127.49 130.67,127.49
  BOTTOM w0.076: v1(119.17,128.86) 118.72,128.42 118.42,128.42 118.09,128.09 118.09,127.36 117.68,126.95 117.68,126.59 117.44,126.35 117.44,125.5 117.17,125.23 117.17,124.82 116.98,124.63 116.98,124.51 117.12,124.36 UC1.C23
  BOTTOM w0.102: CC18.1 158.54,117.6 154.18,117.6 152.2,119.58 152.2,123.13 153.77,124.7 153.77,125.11 v1(153.97,125.31)
PEG_CTX_GRX_C_N1: length 58.7
  IN3 w0.084: v1(117.95,129.12) 118.09,128.98 118.46,128.98 118.65,128.79 118.65,127.39 119.03,127.01 120.62,127.01 121.44,126.19 124.85,126.19 125.3,126.63 135.57,126.63 136.81,125.39 137.8,125.39 137.83,125.41 137.89,125.41 137.91,125.44 137.92,125.44
  IN3 w0.127: v1(154.82,124.04) 154.71,124.14 154.71,124.47 154.45,124.74 153.23,124.74 152.53,125.44 137.92,125.44
  BOTTOM w0.089: v1(117.95,129.12) 117.81,128.98 117.48,128.98 117.24,128.73 117.24,127.24 116.98,126.99 116.98,126.2 116.54,125.76 116.54,125.41 116.75,125.2 116.79,125.2 116.84,125.18 116.89,125.06 UC1.B23
  BOTTOM w0.102: CC20.1 160.32,119.13 153.64,119.13 152.9,119.87 152.9,121.77 154.71,123.58 154.71,123.93 v1(154.82,124.04)
PEG_CTX_GRX_C_N2: length 47.2
  IN3 w0.084: v1(117.57,123.26) 117.57,123.28 117.99,123.69 119.63,123.69 120.9,124.96 125.45,124.96 125.83,125.34 134.95,125.34 136.75,123.54 137.92,123.54
  IN3 w0.127: 137.92,123.54 151.81,123.54 153.33,122.02 154.77,122.02 154.94,122.2 154.94,122.49 v1(155.15,122.69)
  BOTTOM w0.089: v1(117.57,123.26) 118.01,123.7 UC1.B21
  BOTTOM w0.102: v1(155.15,122.69) 154.96,122.51 154.96,121.68 156.24,120.4 158.54,120.4 CC22.1
PEG_CTX_GRX_C_N3: length 47.6
  IN3 w0.084: 137.92,124.33 136.88,124.33 135.3,125.91 125.68,125.91 125.24,125.47 119.51,125.47 118.69,126.29 118.45,126.29 v1(118.25,126.09)
  IN3 w0.127: 137.92,124.33 152.2,124.33 153.28,123.25 155.59,123.25 156.23,122.61 156.23,122.13 v1(156.09,121.99)
  BOTTOM w0.089: UC1.B22 117.83,124.92 118.33,125.42 118.33,126.01 v1(118.25,126.09)
  BOTTOM w0.102: CC24.1 160.32,122.17 158.26,122.17 157.71,122.73 156.51,122.73 156.26,122.47 156.26,122.16 v1(156.09,121.99)
PEG_CTX_GRX_C_P0: length 61.2
  IN3 w0.084: v1(119.17,128.23) 119.18,128.23 119.39,128.43 119.85,128.43 121.73,126.55 124.5,126.55 125.19,127.25 130.74,127.25 130.75,127.24
  IN3 w0.127: v1(153.39,125.31) 153.55,125.47 153.55,125.93 147.09,132.38 137.18,132.38 132.03,127.24 130.75,127.24
  BOTTOM w0.076: v1(119.17,128.23) 118.5,128.23 118.28,128.01 118.28,127.28 117.87,126.87 117.87,126.52 117.63,126.27 117.63,125.42 117.36,125.15 117.36,124.61 117.6,124.38 UC1.C22
  BOTTOM w0.102: CC19.1 158.54,117.39 154.09,117.39 151.99,119.49 151.99,123.22 153.56,124.79 153.56,125.14 v1(153.39,125.31)
PEG_CTX_GRX_C_P1: length 58.3
  IN3 w0.084: 137.92,125.18 136.72,125.18 135.48,126.42 125.39,126.42 124.94,125.97 121.35,125.97 120.53,126.8 118.94,126.8 118.44,127.3 118.44,128.7 118.37,128.77 118.1,128.77 117.95,128.62 v1(117.95,128.53)
  IN3 w0.127: v1(154.23,124.04) 154.46,124.26 154.46,124.37 154.34,124.48 153.12,124.48 152.43,125.18 137.92,125.18
  BOTTOM w0.089: v1(117.95,128.53) 117.95,128.59 117.76,128.78 117.57,128.78 117.44,128.65 117.44,127.16 117.19,126.9 117.19,126.11 116.74,125.67 116.74,125.49 116.83,125.4 116.92,125.37 117.03,125.42 UC1.A23
  BOTTOM w0.102: v1(154.23,124.04) 154.5,123.77 154.5,123.67 152.69,121.86 152.69,119.78 153.55,118.91 160.32,118.91 CC21.1
PEG_CTX_GRX_C_P2: length 47.2
  IN3 w0.084: v1(119.28,124.34) 118.62,124.34 118.39,124.11 118.39,123.95 118.44,123.91 119.54,123.91 120.81,125.17 125.36,125.17 125.74,125.55 135.04,125.55 136.84,123.75 137.78,123.75 137.8,123.77 137.87,123.77 137.89,123.79 137.92,123.79
  IN3 w0.127: v1(154.56,122.69) 154.69,122.56 154.69,122.3 154.66,122.27 153.43,122.27 151.91,123.79 137.92,123.79
  BOTTOM w0.089: v1(119.28,124.34) 118.71,123.78 UC1.C21
  BOTTOM w0.102: v1(154.56,122.69) 154.75,122.51 154.75,121.59 156.15,120.18 158.54,120.18 CC23.1
PEG_CTX_GRX_C_P3: length 47.6
  IN3 w0.084: 137.92,124.58 137.91,124.58 137.89,124.56 137.83,124.56 137.8,124.54 136.97,124.54 135.39,126.12 125.6,126.12 125.15,125.68 119.6,125.68 118.77,126.51 118.47,126.51 v1(118.25,126.73)
  IN3 w0.127: 137.92,124.58 152.3,124.58 153.38,123.51 155.7,123.51 156.48,122.72 156.48,122.19 v1(156.68,121.99)
  BOTTOM w0.089: v1(118.25,126.73) 118.25,126.64 117.82,126.21 117.82,125.87 118.01,125.68 UC1.A21
  BOTTOM w0.102: v1(156.68,121.99) 156.48,122.19 156.48,122.38 156.6,122.51 157.62,122.51 158.17,121.96 160.32,121.96 CC25.1
PEG_CTX_GRX_N0: length 7.1
  BOTTOM w0.102: UV1.Y37 165.82,119.05 165.45,119.05 165.39,118.99 165.36,118.99 165.18,118.81 164.77,118.81 164.5,118.54 163.81,118.54 163.03,117.77 v3(162.23,117.77) 160.99,117.77 160.83,117.6 160.13,117.6 CC18.2
PEG_CTX_GRX_N1: length 6
  BOTTOM w0.102: UV1.W36 166.62,119.93 166.62,119.8 166.54,119.72 166.38,119.72 166.27,119.82 165.83,119.82 165.79,119.79 165.79,119.79 165.75,119.74 165.58,119.74 165.45,119.87 165.36,119.87 165.36,119.87 164.55,119.87 164.27,119.59 163.82,119.59 163.37,119.14 162.82,119.14 162.8,119.13 161.91,119.13 CC20.2
PEG_CTX_GRX_N2: length 6.7
  BOTTOM w0.102: UV1.V37 165.82,120.65 165.82,120.65 165.47,120.65 165.14,120.32 164.64,120.32 164.56,120.4 162.99,120.4 162.98,120.41 162.43,120.41 162.41,120.4 v3(160.94,120.4) 160.13,120.4 CC22.2
PEG_CTX_GRX_N3: length 6
  BOTTOM w0.102: UV1.U36 166.59,121.57 166.59,121.37 166.53,121.31 166.38,121.31 166.27,121.42 165.85,121.42 165.78,121.35 165.6,121.35 165.56,121.39 165.54,121.39 165.5,121.42 164.51,121.42 164.45,121.37 v3(163.44,121.37) 163.17,121.37 162.36,122.17 161.91,122.17 CC24.2
PEG_CTX_GRX_P0: length 7.1
  BOTTOM w0.102: CC19.2 160.13,117.39 160.92,117.39 161.07,117.54 162.53,117.54 162.54,117.55 163.12,117.55 163.89,118.32 164.59,118.32 164.86,118.59 165.27,118.59 165.45,118.77 165.48,118.77 165.54,118.83 165.76,118.83 165.82,118.77 165.82,118.64 165.67,118.49 UV1.AA38
PEG_CTX_GRX_P1: length 6
  BOTTOM w0.102: UV1.Y35 166.86,119.36 166.72,119.5 166.29,119.5 166.18,119.61 165.92,119.61 165.88,119.57 165.88,119.57 165.84,119.53 165.49,119.53 165.36,119.66 165.27,119.66 164.64,119.66 164.36,119.37 163.91,119.37 163.44,118.91 v3(163.08,118.91) 161.91,118.91 CC21.2
PEG_CTX_GRX_P2: length 6.7
  BOTTOM w0.102: CC23.2 160.13,120.18 160.66,120.18 160.67,120.17 161.2,120.17 161.22,120.18 v3(162.7,120.18) 164.47,120.18 164.55,120.1 165.23,120.1 165.29,120.16 165.56,120.43 165.73,120.43 165.83,120.34 165.83,120.25 UV1.W38
PEG_CTX_GRX_P3: length 6
  BOTTOM w0.102: CC25.2 161.91,121.96 162.27,121.96 163.09,121.14 163.71,121.14 163.72,121.15 164.54,121.15 164.6,121.21 165.41,121.21 165.45,121.17 165.47,121.17 165.51,121.13 165.87,121.13 165.94,121.21 166.18,121.21 166.29,121.1 166.71,121.1 166.86,120.95 UV1.V35
PLT_RST#: length 433.6
  TOP w0.102: R159.1 146.95,103.14 UC3.4 146.95,104.45 147.1,104.6 148.34,104.6 148.63,104.89 148.63,106.39 149.17,106.92 150.09,106.92 150.85,106.16 150.85,105.98 151.55,105.28 152.85,105.28 v4(153.53,105.96) 155.77,108.21 156.66,108.21 157.28,108.83 160.08,108.83 v1(160.11,108.79) ; v1(190.38,42.49) 188.94,41.06 188.94,39.25 187.99,38.3 UE1.13
  IN1 w0.127: v1(129.51,140.98) 125.5,144.98 115.48,144.98 114.07,146.39 105.05,146.39 104.74,146.7 v1(104.74,146.76)
  IN3 w0.127: v1(160.11,108.79) 159.48,109.43 159.48,110.17 157.5,112.14 156.19,112.14 155.47,112.87 155.47,114.25 159.22,118 159.22,124.25 156.62,126.85 153.76,126.85 146.93,133.68 131.6,133.68 130.18,135.1 130.18,140.31 v1(129.51,140.98) ; v1(190.38,42.49) 188.79,42.49 187.03,44.25 185.09,44.25 183.55,42.72 52.51,42.72 42.76,52.46 42.76,80.66 40.61,82.81 40.61,85.1 42.08,86.57 v1(43.51,86.57)
  BOTTOM w0.102: v1(160.11,108.79) 159.6,109.3 159.6,109.55 159.41,109.74 UV13.2 ; UL1.19 40.57,84.87 41.81,86.12 43.05,86.12 v1(43.51,86.57) 43.51,90.14 59.15,105.78 63.21,105.78 ; v1(190.38,42.49) 190.43,42.44 CE36.1 ; JMINI.22 104.9,146.92 v1(104.74,146.76) 103.98,146 85.63,146 84.8,145.17 84.8,141.56 83.98,140.74 83.98,139.89 83.1,139.01 83.1,138.63 82.64,138.17 82.64,137.55 81.88,136.79 81.88,134.31 82.2,134 82.86,134 83.52,133.34 83.52,133.34 84.78,133.34 85.3,132.82 85.3,131.58 86.2,130.67 86.2,126.87 84.67,125.35 84.29,125.35 82.93,123.99 77.21,123.99 76.36,123.14 68.1,123.14 66.32,121.36 62.96,121.36 60.75,119.15 60.75,110.1 63.21,107.64 CC30.1 63.21,105.78 ; 63.21,105.78 63.21,103.31 62.78,102.87 RC51.1
PM_APWROK_R: length 5.2
  TOP w0.089: v1(127.17,113.98) 127.67,113.49 127.87,113.49 128.66,112.7 v4(129.31,112.7) 130.03,112.7 130.39,112.34 RP50.6
  BOTTOM w0.089: v1(127.17,113.98) 127.64,113.51 UC1.AB5
PROC_OPI_RCOMP: length 6.5
  BOTTOM w0.076: 122.37,100.69 122.37,100.82 122.2,100.99 122.2,101.18 121.74,101.64 121.74,102.85 UC1.AY15
  BOTTOM w0.305: 122.37,100.69 122.37,98.13 v2(122.52,97.98) 123.35,97.15 RC134.1
PROJECT_ID: length 8.6
  TOP w0.089: v2(132.74,120.59) v1(132.74,120.09) 133.51,119.33 RC112.2 RC113.1
  IN1 w0.084: v1(127.85,118.76) 128.3,119.2 130.84,119.2 131.73,120.09 v1(132.74,120.09)
  BOTTOM w0.089: UC1.L5 127.64,118.97 v1(127.85,118.76)
PS_0: length 14.3
  TOP w0.102: RV201.1 CV335.1 RV243.2 156.87,110.39 157.42,110.94 161.19,110.94 162.35,109.78 163.16,109.78 163.55,109.39 v2(164.81,109.39) v1(165.66,109.39)
  BOTTOM w0.102: v1(165.66,109.39) 165.71,109.34 166.14,109.34 166.36,109.56 166.36,109.62 166.74,110 166.99,110 167.49,109.49 UV1.AM34
PS_1: length 28.8
  TOP w0.102: RV238.1 CV329.1 RV237.2 165.91,98.54 165.91,100.08 166.36,100.52 v2(166.94,100.52) v1(167.67,100.52)
  IN3 w0.102: v1(169.7,115.13) 169.7,114.94 168.78,114.02 166.69,114.02
  IN3 w0.127: v1(167.67,100.52) 168.24,101.1 168.24,102.78 162.52,108.5 162.52,109.29 163.63,110.4 163.63,112.22 164.44,113.03 165.69,113.03 166.69,114.02
  BOTTOM w0.102: UV1.AD31 170.06,115.49 v1(169.7,115.13)
PS_2: length 16
  TOP w0.102: v1(170.06,112.67) 169.68,113.05 v2(169.05,113.05) 168.41,113.05 166.07,110.7 166.07,109.15 165.7,108.78 163.84,108.78 163.09,109.52 162.03,109.52 161.05,110.51 CV331.1 160.37,110.51 160.05,110.19 RV240.1 RV239.2
  BOTTOM w0.102: UV1.AG31 170.06,113.29 v1(170.06,112.67)
PS_3: length 15.3
  TOP w0.102: RV242.1 CV333.1 159.59,111.45 160.63,111.45 RV241.2 161.61,111.62 v1(162.22,111.01) 162.49,110.74 v2(162.49,110.27)
  IN3 w0.102: 164.11,114.12 165.11,114.12 166.79,115.8 168.15,115.8 v1(168.83,115.12)
  IN3 w0.127: v1(162.22,111.01) 162.22,112.28 164.07,114.12 164.11,114.12
  BOTTOM w0.102: UV1.AD33 168.46,115.49 v1(168.83,115.12)
PS_ID: length 178.4
  TOP w0.102: v1(132.35,184.62) 132.35,184.38 v2(132.68,184.05) ; UE1.16 189.19,36.68 189.07,36.8 189.07,37.15 v1(189.46,37.55)
  TOP w0.254: v1(132.35,184.62) PR3.1 PR4.2
  IN2 w0.254: v1(132.35,184.62) 132.35,180.3 133.19,179.46 133.19,168.16 132.71,167.68 132.71,146.64 139.86,139.49 139.86,138.28 149.23,128.91 149.23,121.46 153.17,117.52 153.17,112.97 155.25,110.89 155.25,108.06 159.14,104.16 160.03,104.16 161.63,102.56 162.29,102.56 163.44,101.41 163.44,100.46 170.41,93.48 171.87,93.48 183.54,81.81 183.54,80.79 189.51,74.82 189.51,54.24 190.31,53.44 190.31,49.13 189.29,48.11 189.29,37.73 v1(189.46,37.55)
PSID: length 0.6
  TOP w0.102: v1(137.43,179.59) v2(138.07,179.59)
PSID-1: length 5.5
  TOP w0.102: v2(132.28,181.66) 132.5,181.88 PR6.1
  TOP w0.254: v1(133.38,183.46) 133.38,182.71 PR9.2 PR6.1
  BOTTOM w0.254: v1(133.38,183.46) 133.38,184.29 134.54,185.45 PQ5.2
PSID-2: length 4.9
  TOP w0.102: v2(131.55,188.08) 132.09,187.54 v1(132.48,187.54)
  TOP w0.254: v1(132.48,187.54) 132.55,187.46 PR8.2
  BOTTOM w0.254: PQ6.2 v1(132.48,187.54) 132.64,187.37 PQ5.1
PSID-3: length 3.4
  TOP w0.102: PR4.1 130.57,186.67 v2(130.49,186.74)
  TOP w0.254: v1(131.03,184.61) 130.57,185.06 PR4.1
  BOTTOM w0.254: PQ6.3 131.03,185.58 v1(131.03,184.61)
PWM1: length 49.4
  TOP w0.102: v1(115.41,138.95) v2(116.12,138.95)
  IN1 w0.254: v1(115.41,138.95) 115.41,144.6 113.95,146.06 88.55,146.06 85.14,142.66 85.14,140.02 84.42,139.3 83.69,139.3 83.43,139.04 83.43,138.42 83.91,137.93 v1(86.13,137.93)
  BOTTOM w0.203: PU501.6 86.22,138.02 v1(86.13,137.93) ; v1(115.41,138.95) 115.62,138.95 115.89,139.22 115.89,139.51 115.76,139.63 PU502.8
PWR_PWM_LED#: length 190.2
  TOP w0.102: v1(38.45,18.73) v2(35.74,16.03) 34.65,14.93 RD14.1 ; UE1.92 184.79,52.28 v1(185.18,52.68)
  IN1 w0.127: v1(38.45,18.73) 40.06,20.34 46.6,20.34 52.57,26.31 87.7,26.31 105.85,44.46 133.04,44.46 136.72,40.78 160.52,40.78 167.22,34.07 182.35,34.07 v1(182.81,34.53)
  IN2 w0.127: v1(182.81,34.53) 182.15,35.19 182.15,46.24 185.07,49.16 185.07,52.57 v1(185.18,52.68)
PWR_SRC_ON: length 4.1
  TOP w0.102: RX3.1 RX2.2 CX4.2 220.26,177.58 221.05,177.58 221.19,177.44 QX2.3
PXS_PWREN: length 356.5
  TOP w0.089: v1(133.38,116.15) 132.86,115.63 RP54.4
  TOP w0.102: v1(189.89,173.87) 190.28,174.25 v2(191.27,174.25)
  TOP w0.254: PR1103.1 v1(189.89,173.87) ; PR601.2 213.64,93.36 v1(211.99,95.01)
  IN1 w0.127: v1(174.82,93.17) 175.14,93.49 189.59,93.49 190.7,92.39 196.3,92.39 201.3,97.39 209.6,97.39 v1(211.99,95.01)
  IN2 w0.254: v1(190.59,164.35) 193.76,164.35 198.82,159.29 208.87,159.29 222.73,145.43 222.73,125.37 221.33,123.96 221.33,104.85 218.69,102.21 218.69,101.58 214.72,97.61 214.72,96.61 213.12,95.01 v1(211.99,95.01)
  IN3 w0.084: 137.82,115.96 137.57,115.71 133.82,115.71 v1(133.38,116.15)
  IN3 w0.127: 137.82,115.96 138.08,116.22 139.28,116.22 139.98,115.52 143.96,115.52 144.26,115.81 146.72,115.81 147.29,116.38 151.63,116.38 153.32,114.69 154.21,114.69 154.33,114.56 154.33,113.27 155.98,111.63 157.29,111.63 158.96,109.95 158.96,109.22 159.41,108.76 159.41,108.09 160.43,107.08 160.43,106.42 164.6,102.25 164.94,101.91 164.94,99.97 168.71,96.2 172.76,96.2 174.82,94.14 v1(174.82,93.17) 174.82,91.29 v1(175.92,90.18)
  IN3 w0.254: v1(211.99,95.01) 212.68,94.32 212.68,91.49 215.12,89.05 216.61,89.05 218.26,87.41 218.26,86.44 216.88,85.06 216.88,77.78 219.38,75.27 219.38,62.34 218.74,61.7 218.74,58.13 216.31,55.7 v1(210.53,55.7) ; v1(190.59,164.35) 190.97,164.73 190.97,172.79 v1(189.89,173.87) 189.89,174.06 191.8,175.97 191.8,187.27 191.35,187.72 v1(185.77,187.72)
  BOTTOM w0.076: UC1.P4 128.62,117.26 129.04,117.26 129.16,117.13 130.3,117.13 130.39,117.23 131.66,117.23 131.72,117.3
  BOTTOM w0.089: 131.72,117.3 131.78,117.36 133.59,117.36 133.95,116.99 133.95,116.47 133.63,116.15 v1(133.38,116.15)
  BOTTOM w0.102: v1(190.59,164.35) 190.7,164.24 190.7,159.78 190.33,159.41 RV105.2 ; QV24.2 176.83,89.27 v1(175.92,90.18) 174.82,89.08 QV25.2
  BOTTOM w0.254: PR1206.2 v1(185.77,187.72) ; PR803.1 210.21,56.02 v1(210.53,55.7) 210.53,53.22 209.11,51.8 206.27,51.8 205.98,51.52 205.98,49.94 205.78,49.73 201.49,49.73 201.4,49.82 200.53,49.82 197.26,53.09 197.26,59.23 196.69,59.8 196.69,60.75 196.82,60.87 196.82,61.92 199.48,64.59 199.48,65.57 199.06,65.99 PR1300.1
PXS_PWREN#: length 3.7
  BOTTOM w0.102: v2(174.22,93.73) RV109.2 174.36,92.45 QV25.1
QSA0: length 34.6
  TOP w0.102: 167.37,134.78 167.77,134.37 167.77,133.69 168.04,133.42 168.04,132.79 v1(168.17,132.67) ; 162.09,147.76 162.22,147.9 163.96,147.9 164.29,148.23 164.29,148.96 UV18.C7
  TOP w0.109: 167.37,134.78 167.02,135.13 167.02,135.28 168.12,136.39 168.12,136.74 167.79,137.07 167.44,137.07 166.35,135.98 166.17,135.98 165.96,136.19 165.96,136.37 166.81,137.22 166.81,137.57 166.48,137.9 166.12,137.9 165.28,137.05 165.1,137.05 164.89,137.26 164.89,137.44 165.74,138.29 165.74,138.64 165.41,138.97 165.05,138.97 v3(164.38,138.3) 164.21,138.12 164.03,138.12 163.82,138.33 163.82,138.51 164.67,139.36 164.67,139.71 164.34,140.04 163.98,140.04 163.13,139.19 162.96,139.19 160.41,141.74 160.41,146.08 162.09,147.76
  BOTTOM w0.102: v1(168.17,132.67) 168.17,132.65 167.86,132.35 UV1.C34
QSA1: length 35.7
  BOTTOM w0.102: 164.59,146.05 UV19.C7 ; 171.41,133.81 171.41,133.48 171.57,133.32 171.57,132.83 171.56,132.82 171.56,132.56 171.73,132.39 171.73,132.02 UV1.D29
  BOTTOM w0.109: 171.41,133.81 171.41,134.35 170.68,135.08 170.12,135.08 169.22,135.98 167.04,135.98 165.18,137.84 164.85,137.84 163.97,136.95 163.79,136.95 163.58,137.16 163.58,137.34 164.47,138.23 164.47,138.55 164.11,138.91 163.78,138.91 v3(163.3,138.43) 162.9,138.03 162.72,138.03 162.51,138.23 162.51,138.41 163.4,139.3 163.4,139.63 163.04,139.98 162.71,139.98 161.83,139.1 161.65,139.1 161.45,139.31 161.45,139.49 162.32,140.37 162.32,140.7 160.13,142.9 160.13,143.64 160.15,143.66 160.15,144.22 160.13,144.24 160.13,146.87 160.55,147.29 162.77,147.29 163.19,146.87 163.19,146.49 163.31,146.37 163.31,146.03 163.5,145.84 163.5,145.84 163.65,145.69 164.22,145.69 164.59,146.05
QSA2: length 36.2
  IN1 w0.102: v1(167.39,149.66) 167.22,149.49 167.02,149.49 166.7,149.17 166.7,148.05 166.62,147.97 165.05,147.97 164.8,147.72 164.8,145.41 164.7,145.31 164.32,145.31 164.09,145.07 164.09,144.58 164.32,144.35 164.7,144.35 164.8,144.25 164.8,143.57 164.78,143.55 164.78,143.53
  IN1 w0.14: 164.78,143.53 164.78,143.08 164.65,142.96 163.78,142.96 163.42,142.6 163.42,142.03 163.72,141.73 164.69,141.73 164.83,141.59 164.83,141.17 164.69,141.03 163.72,141.03 163.42,140.74 163.42,137.72 165.06,136.08 173.54,136.08 174.55,135.08 174.95,135.08 v1(175.1,134.94)
  BOTTOM w0.102: UV1.D25 175.06,131.73 174.97,131.64 174.72,131.64 174.59,131.76 174.59,131.9 174.77,132.08 174.77,132.53 174.76,132.54 174.76,132.9 174.78,132.92 174.78,133.29 174.66,133.41 174.66,133.63 174.68,133.64 174.68,133.74 ; UV19.F3 167.39,149.65 v1(167.39,149.66)
  BOTTOM w0.109: 174.68,133.74 174.68,134.8 174.81,134.94 v1(175.1,134.94)
QSA3: length 38.1
  TOP w0.102: v1(166.82,147.21) 166.43,146.83 166.43,146.4 166.78,146.05 166.99,146.05 UV18.F3
  IN3 w0.102: v1(166.82,147.21) 166.41,147.62 166.41,147.82 166.18,148.05 165.03,148.05 164.52,147.53 164.52,144.9 164.81,144.61 164.81,142.86
  IN3 w0.14: 164.81,142.86 164.81,139.04 165.14,138.72 165.89,138.72 166.19,139.02 166.19,140.24 166.32,140.36 166.83,140.36 166.95,140.24 166.95,138.95 167.19,138.72 171.28,138.72 171.4,138.6 171.4,138.38 v1(171.2,138.19)
  BOTTOM w0.102: 178.59,135.39 178.59,135.36 178.59,135.36 178.59,134.85 178.98,134.46 178.98,133.44 178.76,133.22 178.76,132.96 179.12,132.6 179.21,132.6 179.4,132.41 179.4,132.13 179.35,132.09 179.35,131.78 UV1.E20
  BOTTOM w0.109: v1(171.2,138.19) 171.4,138.38 171.4,138.61 171.7,138.9 172.09,138.9 172.97,138.02 177.41,138.02 178.61,136.82 178.61,136.13 178.59,136.11 178.59,135.39
QSA4: length 35.7
  IN1 w0.102: v1(181.85,131.21) 181.88,131.21 182.39,131.72 182.39,131.91 182.98,132.5 182.98,135.23 183.06,135.31 ; 194.1,142.86 194.2,142.96 194.2,146.89 193.62,147.46 191.91,147.46 191.28,146.83 191.28,146.32 191.18,146.23 190.99,146.23 v1(190.78,146.44)
  IN1 w0.14: 194.1,142.86 193.1,141.86 190.2,141.86 186.46,138.11 186.46,135.74 186.1,135.39 184.95,135.39 184.65,135.68 184.65,137.6 184.52,137.74 183.16,137.74 183.03,137.61 183.03,137.17 183.16,137.04 183.66,137.04 183.96,136.75 183.96,135.64 183.71,135.39 183.13,135.39 183.06,135.31
  BOTTOM w0.102: v1(181.85,131.21) 182.13,131.49 UV1.E16 ; v1(190.78,146.44) 191.16,146.05 UV21.F3
QSA5: length 35.9
  TOP w0.102: UV20.F3 191.39,149.26 191.73,148.91 191.73,148.48 v1(191.35,148.1)
  IN3 w0.102: v1(191.35,148.1) 191.35,148.22 191.59,148.46 191.69,148.46 191.85,148.3 191.85,147.51 192.14,147.22 193.36,147.22 193.36,147.22 193.53,147.22 193.54,147.21 193.57,147.21
  IN3 w0.14: 193.57,147.21 195.47,147.21 195.59,147.08 195.59,146.03 195.47,145.9 194.4,145.9 194.13,145.63 194.13,143.47 194.4,143.19 195.69,143.19 196.1,142.79 196.1,140.39 193.96,138.26 189.98,138.26 189.88,138.36 189.88,138.51 190.08,138.71 v1(190.09,138.71)
  BOTTOM w0.102: UV1.E12 185.4,131.49 185.27,131.62 185.27,131.84 185.33,131.91 185.75,131.91 185.81,131.97 185.81,132.63 185.97,132.78 185.97,133.4 185.71,133.66 185.71,134.16 186.32,134.77 186.32,135.3 186.32,135.3 186.32,135.36 186.33,135.36 186.33,135.39
  BOTTOM w0.109: 186.33,135.39 186.33,137.77 186.53,137.97 189.66,137.97 189.9,138.21 189.9,138.58 190.03,138.71 v1(190.09,138.71)
QSA6: length 36.5
  TOP w0.102: 191.11,135.24 191.1,135.22 191.09,135.22 191.05,135.18 191.04,135.18 190.49,134.63 189.77,134.63 188.74,133.59 188.74,130.71 187.78,129.75 187.78,129.34 187.26,128.83 187.26,128.53 186.86,128.13 v1(186.86,127.88) ; UV20.C7 193.74,146.21 193.74,147.01 194.19,147.46 196.45,147.46 196.46,147.46 196.48,147.46
  TOP w0.109: 191.11,135.24 194.24,138.36 194.24,138.69 193.56,139.36 193.56,139.51 193.8,139.75 193.95,139.75 194.62,139.07 194.95,139.07 195.31,139.43 195.31,139.76 194.63,140.43 194.63,140.59 194.87,140.82 195.02,140.82 195.69,140.15 196.02,140.15 196.38,140.5 196.38,140.83 195.71,141.5 195.71,141.66 195.94,141.89 196.09,141.89 196.76,141.22 197.09,141.22 197.45,141.57 197.45,142.03 196.69,142.78 196.69,142.89 197.45,143.64 197.45,146.56 196.54,147.46 196.48,147.46
  BOTTOM w0.102: UV1.J10 187.26,128.29 v1(186.86,127.88)
QSA7: length 34.2
  BOTTOM w0.102: UV1.D7 189.29,131.72 189.29,131.56 189.44,131.41 189.52,131.41 189.77,131.66 189.77,132.07 189.75,132.08 189.75,132.53 189.77,132.54 189.77,132.8 189.75,132.81 189.75,133.3 189.94,133.48 189.94,134.34 190.92,135.32 190.92,135.32 190.96,135.37 190.96,135.37 190.98,135.39
  BOTTOM w0.109: 190.98,135.39 191.18,135.59 193.3,135.59 198.89,141.18 v3(198.89,141.63) 198.89,142.12 199.12,142.35 199.84,142.35 199.96,142.48 199.96,142.77 199.84,142.9 199.12,142.9 198.89,143.13 198.89,143.63 199.12,143.86 199.96,143.86 200.09,143.99 200.09,144.28 199.96,144.41 199.12,144.41 198.89,144.64 198.89,145.15 199.14,145.4 199.98,145.4 200.09,145.51 200.09,145.8 199.96,145.92 199.12,145.92 198.89,146.16 198.89,147.64 198.7,147.82 194.28,147.82 193.89,148.21 193.89,148.94 UV21.C7
QSA#0: length 34.6
  TOP w0.102: v1(167.53,132.74) 167.84,133.05 167.84,133.34 167.57,133.61 167.57,134.28 167.28,134.57 ; 161.94,147.91 162.13,148.1 163.87,148.1 164.09,148.31 164.09,148.96 UV18.B7
  TOP w0.109: 161.94,147.91 160.2,146.17 160.2,141.65 162.87,138.98 163.22,138.98 164.07,139.83 164.25,139.83 164.46,139.62 164.46,139.44 163.61,138.6 163.61,138.24 163.94,137.91 164.32,137.91 164.56,138.15 164.56,138.15 164.74,138.33 164.74,138.36 165.14,138.76 165.32,138.76 165.53,138.55 165.53,138.37 164.68,137.53 164.68,137.17 165.01,136.84 165.36,136.84 166.21,137.69 166.39,137.69 166.6,137.48 166.6,137.3 165.75,136.46 165.75,136.1 166.08,135.77 166.43,135.77 167.53,136.86 167.7,136.86 167.91,136.66 167.91,136.48 166.81,135.37 166.81,135.04 167.28,134.57
  BOTTOM w0.102: UV1.A34 167.86,133.07 v1(167.53,132.74)
QSA#1: length 35.7
  BOTTOM w0.102: UV1.E30 171.3,131.49 171.53,131.72 171.53,132.31 171.35,132.48 171.35,132.9 171.37,132.91 171.37,133.23 171.21,133.39 171.21,133.72 171.21,133.73 171.21,133.79 171.2,133.79 171.2,133.81
  BOTTOM w0.109: UV19.B7 163.59,146.05 163.53,146.12 163.53,146.45 163.4,146.58 163.4,146.96 162.86,147.5 160.46,147.5 159.91,146.95 v3(159.91,143.94) 159.91,142.81 162.11,140.61 162.11,140.46 161.23,139.58 161.23,139.22 161.56,138.89 161.92,138.89 162.8,139.77 162.95,139.77 163.19,139.54 163.19,139.38 162.3,138.5 162.3,138.15 162.63,137.82 163.02,137.82 163.9,138.7 164.02,138.7 164.26,138.47 164.26,138.31 163.37,137.43 163.37,137.07 163.7,136.74 164.06,136.74 164.94,137.63 165.1,137.63 166.95,135.77 169.13,135.77 170.04,134.87 170.59,134.87 171.2,134.26 171.2,133.81
QSA#2: length 36.3
  IN1 w0.102: 165.04,143.53 165.04,143.55 165.02,143.57 165.02,144.34 164.79,144.58 164.41,144.58 164.31,144.68 164.31,144.98 164.41,145.08 164.79,145.08 165.02,145.32 165.02,147.63 165.14,147.75 166.72,147.75 166.93,147.96 166.93,149.08 167.12,149.27 167.55,149.27 167.67,149.15 167.67,148.99 167.55,148.87 v1(167.39,148.87)
  IN1 w0.14: v1(175.1,135.52) 174.92,135.34 174.65,135.34 173.65,136.34 165.17,136.34 163.69,137.83 163.69,140.63 163.83,140.77 164.79,140.77 165.09,141.07 165.09,141.7 164.79,141.99 163.83,141.99 163.69,142.13 163.69,142.49 163.89,142.69 164.76,142.69 165.04,142.97 165.04,143.53
  BOTTOM w0.102: v1(167.39,148.87) 167.77,149.25 UV19.G3 ; UV1.E26 174.26,131.86 174.57,132.16 174.57,132.47 174.55,132.48 174.55,132.98 174.58,133.01 174.58,133.21 174.46,133.32 174.46,133.72 174.47,133.72 174.47,133.74
  BOTTOM w0.109: v1(175.1,135.52) 174.47,134.89 174.47,133.74
QSA#3: length 37.9
  TOP w0.102: v1(166.83,146.56) 166.83,146.72 166.97,146.86 167.22,146.86 167.35,146.72 167.35,146.13 167.42,146.05 UV18.G3
  IN3 w0.102: v1(166.83,146.56) 166.83,146.66 166.38,147.1 166.38,147.34 166.19,147.53 166.19,147.73 166.09,147.83 165.12,147.83 164.73,147.44 164.73,144.99 165.03,144.7 165.03,142.97 165.05,142.96 165.05,142.89 165.07,142.87 165.07,142.86
  IN3 w0.14: 165.07,142.86 165.07,139.15 165.24,138.97 165.79,138.97 165.94,139.12 165.94,140.34 166.21,140.62 166.93,140.62 167.21,140.34 167.21,139.06 167.3,138.97 171.38,138.97 171.65,138.7 171.65,138.32 v1(171.79,138.19)
  BOTTOM w0.102: UV1.C20 179.06,131.89 178.94,131.77 178.69,131.77 178.57,131.9 178.57,132.28 178.8,132.51 178.8,132.64 178.55,132.88 178.55,133.3 178.78,133.52 178.78,134.37 178.38,134.76 178.38,135.36 178.38,135.36 178.38,135.39
  BOTTOM w0.109: 178.38,135.39 v3(178.38,136.41) 178.38,136.76 177.33,137.81 172.88,137.81 172,138.69 171.78,138.69 171.61,138.52 171.61,138.36 v1(171.79,138.19)
QSA#4: length 35.5
  IN1 w0.102: 193.73,142.86 193.97,143.1 193.97,146.8 193.53,147.24 192,147.24 191.5,146.74 191.5,146.23 191.28,146 190.91,146 190.78,145.88 v1(190.78,145.65) ; v1(181.95,131.91) 182.07,131.91 182.22,132.06 182.75,132.59 182.75,135.38 182.76,135.39
  IN1 w0.14: 193.73,142.86 192.99,142.12 190.09,142.12 186.2,138.22 186.2,135.85 185.99,135.65 185.06,135.65 184.92,135.79 184.92,137.71 184.62,138 183.05,138 182.77,137.72 182.77,137.06 183.05,136.78 183.55,136.78 183.69,136.64 183.69,135.75 183.6,135.65 183.02,135.65 182.76,135.39
  BOTTOM w0.102: v1(190.78,145.65) 190.78,145.86 190.59,146.05 UV21.G3 ; UV1.C16 182.39,132.29 182.52,132.16 182.52,132.01 182.41,131.91 v1(181.95,131.91)
QSA#5: length 35.8
  TOP w0.102: v1(191.34,148.75) 191.34,148.59 191.2,148.45 190.95,148.45 190.82,148.59 190.82,149.18 190.74,149.25 UV20.G3
  IN3 w0.102: v1(191.34,148.75) 191.41,148.68 191.78,148.68 192.06,148.39 192.06,147.6 192.23,147.44 193.46,147.44 193.47,147.44 193.53,147.44 193.55,147.46 193.57,147.46
  IN3 w0.14: 193.57,147.46 195.57,147.46 195.85,147.19 195.85,145.92 195.57,145.65 194.51,145.65 194.38,145.52 194.38,143.58 194.51,143.45 195.8,143.45 196.36,142.89 196.36,140.29 194.07,138 189.88,138 189.62,138.26 189.62,138.59 v1(189.5,138.71)
  BOTTOM w0.102: 186.12,135.39 186.12,134.86 185.51,134.25 185.51,133.58 185.77,133.31 185.77,132.97 185.46,132.66 UV1.C12
  BOTTOM w0.109: 186.12,135.39 186.12,137.86 186.44,138.18 189.57,138.18 189.69,138.3 189.69,138.52 v1(189.5,138.71)
QSA#6: length 36.4
  TOP w0.102: 196.46,147.25 196.45,147.26 194.28,147.26 193.94,146.92 193.94,145.85 194.01,145.78 194.29,145.78 194.38,145.88 UV20.B7 ; 196.48,142.86 196.48,142.98 196.54,143.04 ; 190.96,135.39 190.43,134.86 v3(190.07,134.86) 189.72,134.86 188.53,133.67 188.53,130.79 187.57,129.84 187.57,129.43 187.34,129.19 186.89,129.19 186.77,129.06 186.77,128.81 v1(186.88,128.69)
  TOP w0.109: 196.54,143.04 197.24,143.73 197.24,146.48 196.46,147.25 ; 196.48,142.86 196.48,142.69 197.24,141.94 197.24,141.66 197.01,141.43 196.85,141.43 196.18,142.1 195.85,142.1 195.49,141.74 195.49,141.41 196.17,140.74 196.17,140.59 195.93,140.36 195.78,140.36 195.11,141.03 194.78,141.03 194.42,140.67 194.42,140.34 195.1,139.67 195.1,139.52 194.86,139.29 194.71,139.29 194.04,139.96 193.71,139.96 193.35,139.6 193.35,139.27 194.03,138.6 194.03,138.45 190.96,135.39
  BOTTOM w0.102: UV1.J11 186.65,128.29 186.88,128.52 v1(186.88,128.69)
QSA#7: length 34.7
  BOTTOM w0.102: 191.13,135.24 191.11,135.22 191.11,135.22 190.14,134.26 190.14,133.4 189.96,133.22 189.96,132.89 189.97,132.88 189.97,132.46 189.96,132.44 189.96,132.17 189.97,132.15 189.97,131.58 189.6,131.21 189.43,131.21 189.31,131.21 188.86,130.76 UV1.F8
  BOTTOM w0.109: UV21.B7 194.1,148.98 194.1,148.3 194.37,148.04 198.79,148.04 199.1,147.73 199.1,146.24 199.21,146.14 200.05,146.14 200.3,145.88 200.3,145.42 200.05,145.17 v3(199.58,145.17) 199.21,145.17 199.1,145.06 199.1,144.73 199.21,144.62 200.05,144.62 200.3,144.37 200.3,143.9 200.05,143.65 199.21,143.65 199.1,143.54 199.1,143.22 199.21,143.11 199.92,143.11 200.17,142.86 200.17,142.39 199.92,142.14 199.21,142.14 199.12,142.05 199.12,141.11 193.39,135.38 191.27,135.38 191.13,135.24
QSB0: length 35.5
  TOP w0.102: 194.39,131.89 194.37,131.89 194.36,131.89 192.69,131.89 192.66,131.86 192,131.86 191.4,131.27 190.78,131.27 190.51,131.01 190.51,130.54 190.79,130.27 v1(190.79,130.26) ; UV22.C7 211.06,138 210.36,138 210,138.36 210,140.24 209.57,140.67
  TOP w0.109: 209.57,140.67 208.82,141.41 205.22,141.41 198.08,134.27 198.08,134.11 199.62,132.57 199.62,132.22 199.29,131.89 198.94,131.89 197.39,133.43 197.24,133.43 197.01,133.2 197.01,133.04 197.48,132.57 197.48,132.22 197.15,131.89 196.79,131.89 196.32,132.36 196.17,132.36 195.7,131.89 194.39,131.89
  BOTTOM w0.102: v1(190.79,130.26) 190.46,130.58 UV1.F6
QSB1: length 35.2
  BOTTOM w0.102: 205.38,140.67 204.96,140.24 ; UV1.K3 192.43,127.29 192.74,127.6 193.69,127.6 194.11,128.01 194.3,128.01 194.3,128.02 194.36,128.02 194.37,128.02 194.39,128.02 ; UV23.C7 208.33,137.88 209.06,137.88 209.39,138.21 209.39,139.64 208.36,140.67
  BOTTOM w0.109: 205.38,140.67 206.02,141.3 207.72,141.3 208.36,140.67 ; 204.96,140.24 204.09,139.38 204.09,135.96 203.93,135.8 203.65,135.8 203.54,135.91 203.54,137.62 203.29,137.87 202.83,137.87 202.58,137.62 202.58,135.91 202.47,135.8 202.21,135.8 202.19,135.82 201.63,135.82 201.61,135.8 200.52,135.8 197.74,133.03 197.59,133.03 197.11,133.51 196.75,133.51 196.42,133.18 196.42,132.83 v3(196.71,132.53) 196.9,132.34 196.9,132.19 196.42,131.71 196.42,129.88 194.57,128.02 194.39,128.02
QSB2: length 36.9
  TOP w0.102: UV22.F3 208.15,135.31 v1(208.55,135.7)
  IN3 w0.102: 204.96,137.2 205.01,137.2 205.05,137.24 209.5,137.24 209.86,136.88 209.86,135.74 209.49,135.37 208.7,135.37 208.55,135.53 v1(208.55,135.7)
  IN3 w0.14: v1(201.12,128.23) 200.95,128.4 200.95,128.68 200.78,128.86 200.78,133.75 201.47,134.45 201.67,134.45 203.17,132.96 203.56,132.96 204.02,133.42 204.02,133.81 202.53,135.31 202.53,135.5 202.82,135.8 203.02,135.8 203.35,135.47 203.74,135.47 204.21,135.93 204.21,136.32 203.87,136.65 203.87,136.85 204.22,137.2 204.96,137.2
  BOTTOM w0.102: 194.39,123.96 194.3,123.96 194.3,123.97 193.17,123.97 193.17,123.96 192.99,123.79 192.74,123.79 192.53,123.99 192.16,123.99 UV1.P3
  BOTTOM w0.109: v1(201.12,128.23) 200.95,128.06 200.95,127.62 197.29,123.96 v3(197.02,123.96) 194.39,123.96
QSB3: length 40.4
  IN1 w0.102: v1(193.39,120.98) 193.53,121.12 193.53,121.4 193.72,121.59 194.34,121.59 194.36,121.61 194.39,121.61 ; 206.83,137.32 206.85,137.32 206.86,137.3 210.1,137.3 210.36,137.04 210.36,136.48 210.1,136.22 209.94,136.22 209.82,136.1 209.82,135.71 209.94,135.59 211.36,135.59 211.62,135.33 211.62,135.04 v1(211.76,134.9)
  IN1 w0.14: 206.83,137.32 205.91,137.32 203.04,134.45 201.22,134.45 195.45,128.69 195.45,123.03 195.73,122.75 198.01,122.75 198.13,122.63 198.13,121.73 198.01,121.61 194.39,121.61
  BOTTOM w0.102: v1(211.76,134.9) 211.75,134.9 UV23.F3 ; v1(193.39,120.98) 192.96,120.55 192.74,120.55 192.62,120.68 192.3,120.68 192.21,120.59 191.57,120.59 UV1.V5
QSB4: length 36.9
  TOP w0.102: v1(210.2,111.45) 210.58,111.07 211.01,111.07 211.35,111.41 211.35,111.41 UV25.F3
  IN3 w0.102: 204.96,108.84 204.97,108.84 204.99,108.82 208.97,108.82 209.35,109.2 209.35,110.69 209.61,110.95 210.34,110.95 210.41,111.03 210.41,111.23 v1(210.2,111.45)
  IN3 w0.14: 204.96,108.84 204.65,109.15 204.24,109.15 203.02,107.93 202.84,107.93 202.52,108.24 202.52,108.42 203.75,109.65 203.75,110.05 203.3,110.5 202.89,110.5 201.67,109.28 201.49,109.28 201.18,109.59 201.18,109.77 202.4,110.99 202.4,111.4 199.23,114.57 199.23,114.73 v1(199.39,114.9)
  BOTTOM w0.102: UV1.AB5 191.21,117.64 191.21,117.45 191.34,117.32 192.14,117.32 192.25,117.44 192.68,117.44 192.74,117.37 193.19,117.37 193.69,117.87 193.7,117.87 193.71,117.89 194.26,117.89
  BOTTOM w0.109: 194.26,117.89 194.75,117.89 194.94,117.7 194.94,117.62 195.07,117.5 195.43,117.5 195.49,117.56 195.49,117.71 195.67,117.89 196.34,117.89 196.67,117.56 196.67,117.16 196.79,117.04 197.06,117.04 197.33,116.77 198.02,116.77 198.27,116.52 198.27,115.75 198.41,115.61 199.03,115.61 199.21,115.42 199.21,115.08 v1(199.39,114.9)
QSB5: length 35.2
  BOTTOM w0.102: 194.39,112.86 194.36,112.86 194.36,112.85 192.9,112.85 UV1.AH1 ; 209.82,106.26 209.99,106.42 209.99,106.42 210.13,106.56 210.13,108.65 210.38,108.89 211.15,108.89 211.25,108.79 211.49,108.79 211.61,108.92 211.61,109.09 211.49,109.22 UV24.C7
  BOTTOM w0.109: 209.82,106.26 208.61,105.05 v3(203.36,105.05) 202.08,105.05 200.09,107.04 200.09,111.11 199.86,111.34 196.74,111.34 196.61,111.47 196.61,111.76 196.74,111.89 198.36,111.89 198.38,111.87 198.94,111.87 198.96,111.89 199.84,111.89 200.09,112.14 200.09,112.61 199.84,112.86 194.39,112.86
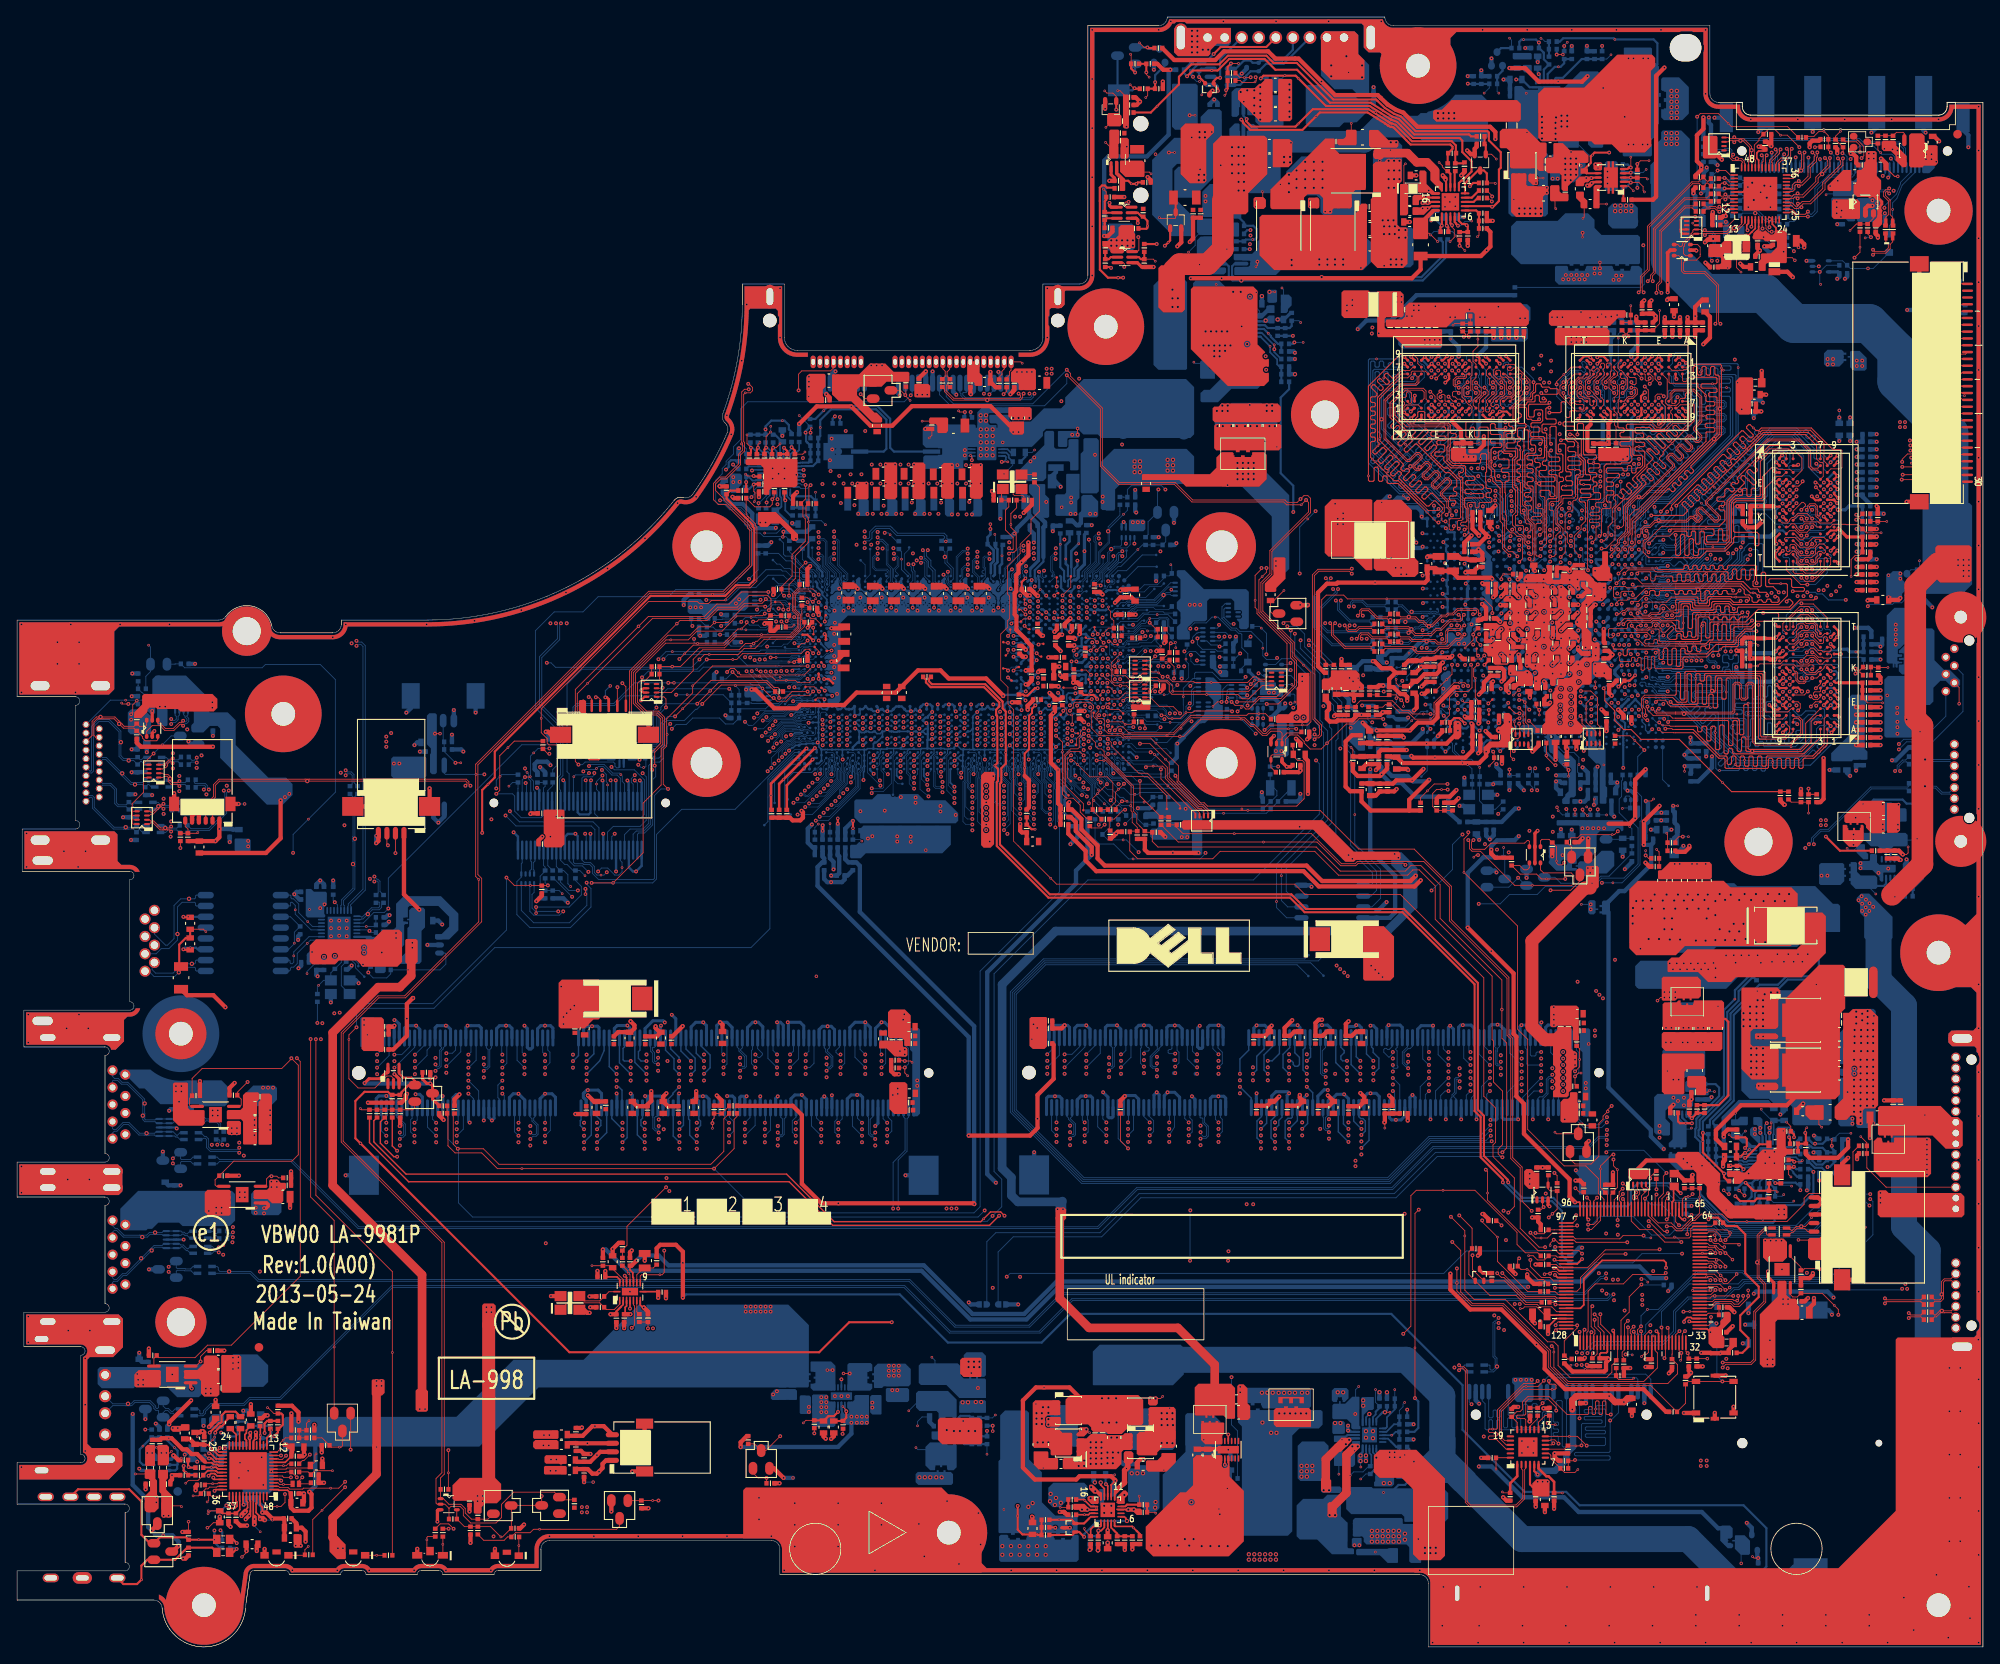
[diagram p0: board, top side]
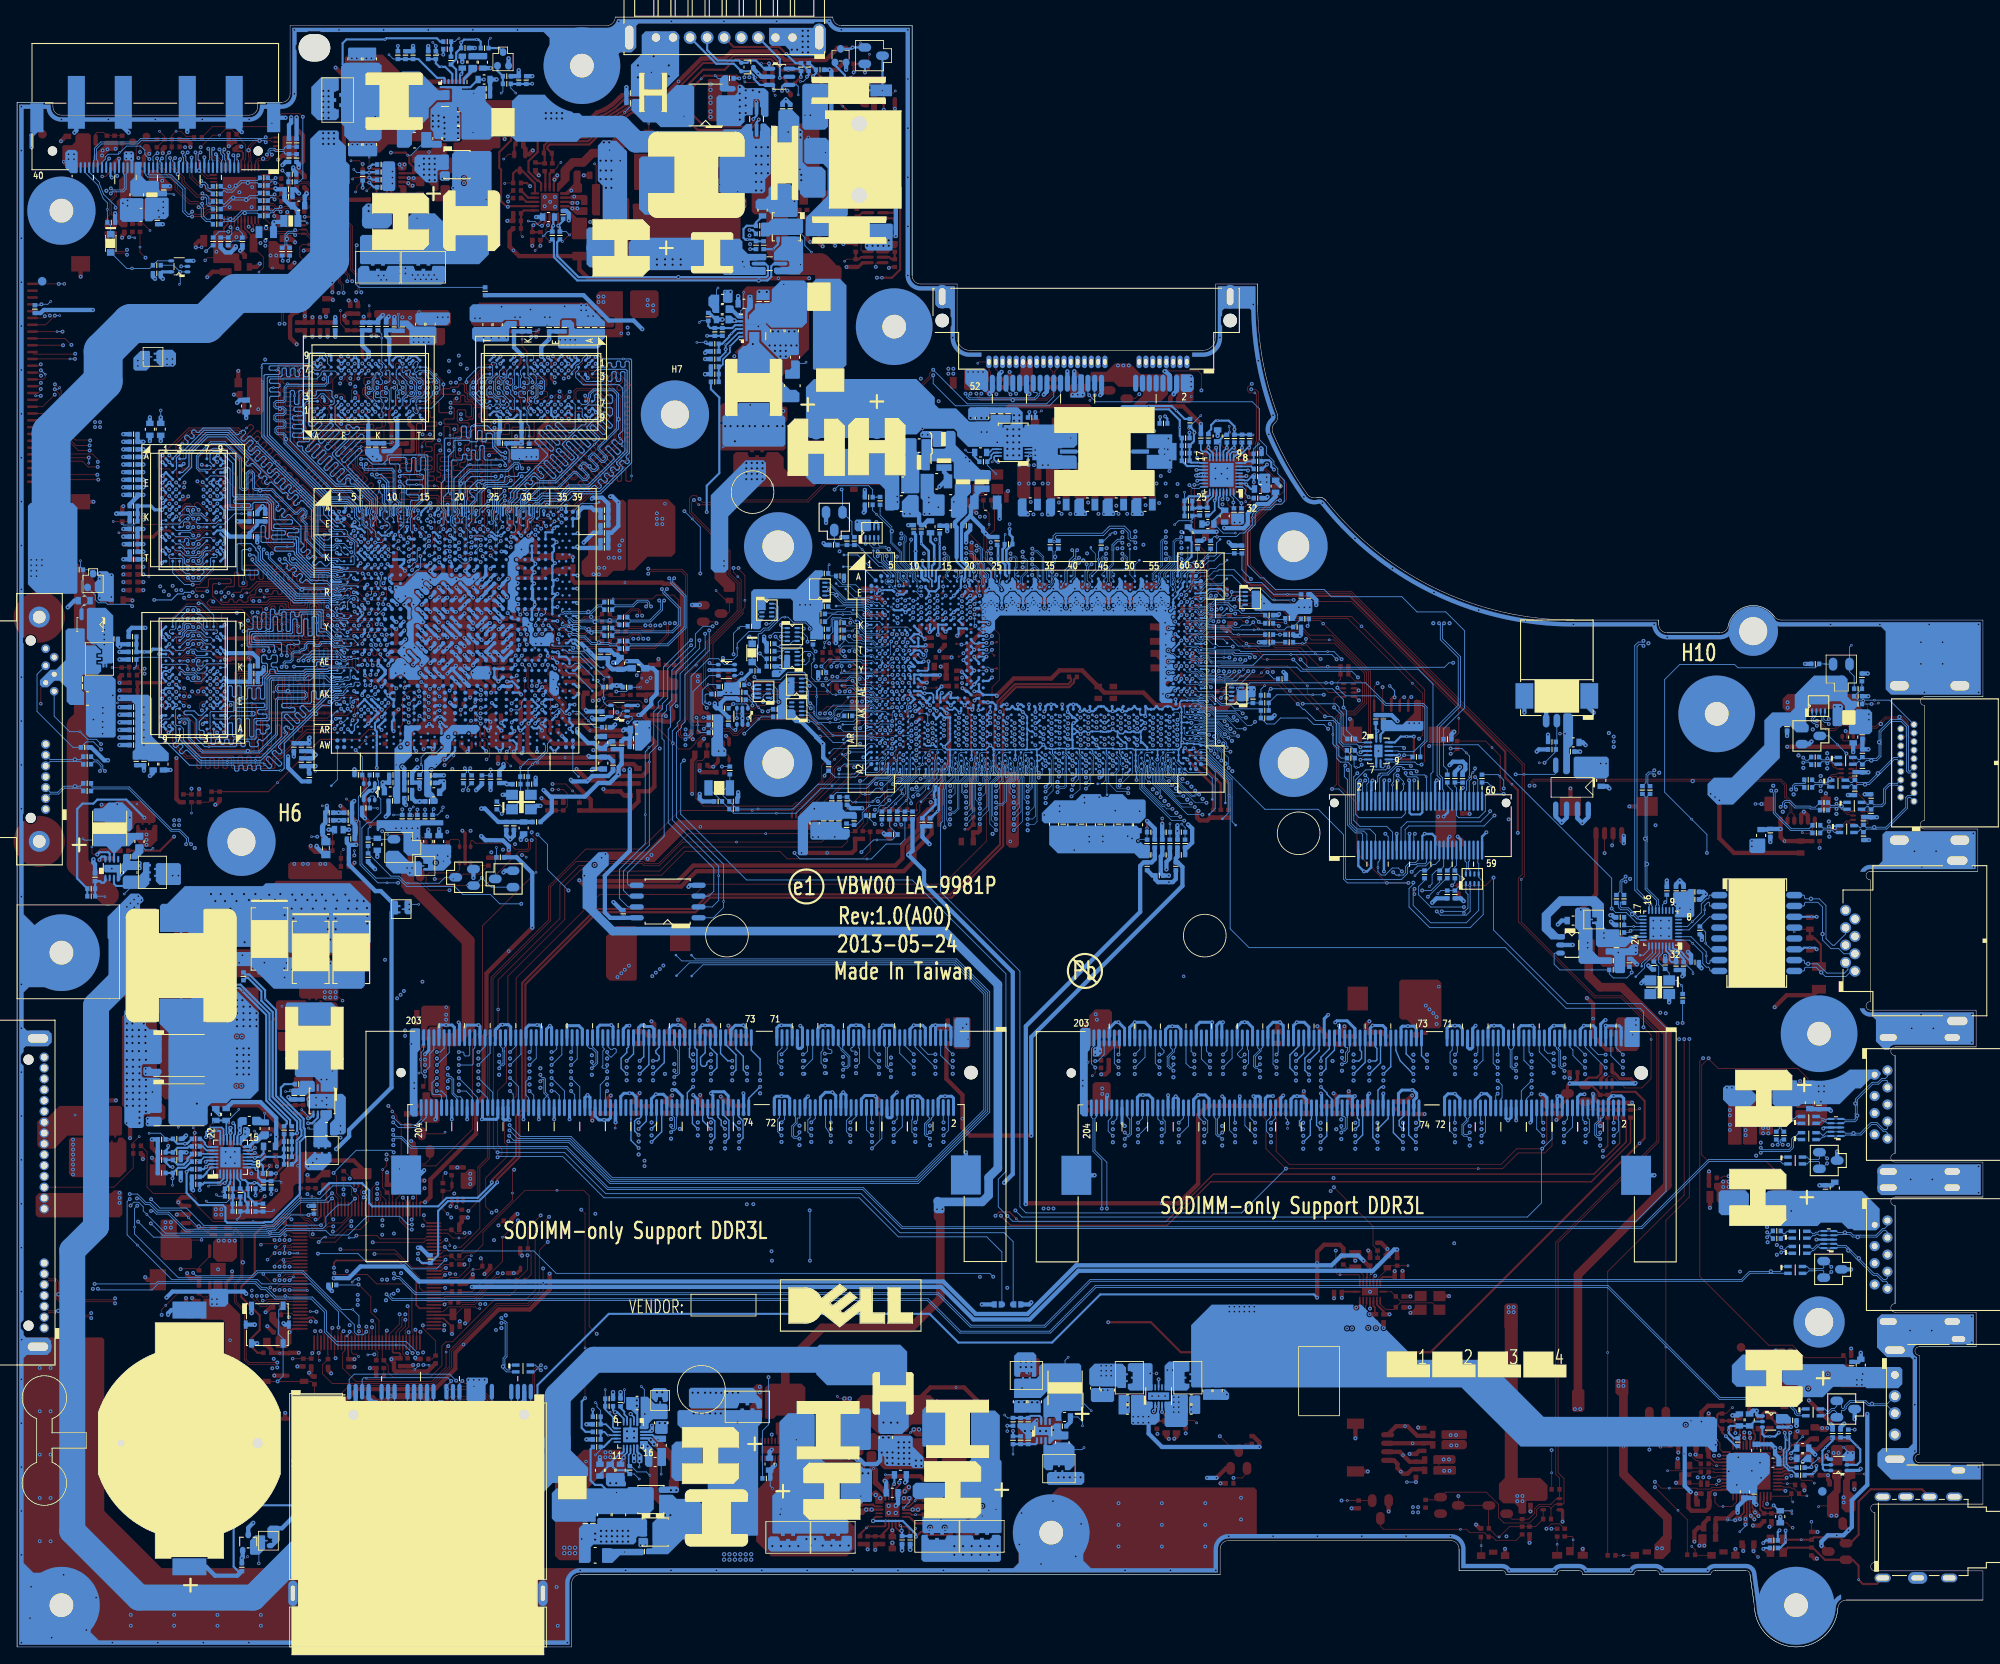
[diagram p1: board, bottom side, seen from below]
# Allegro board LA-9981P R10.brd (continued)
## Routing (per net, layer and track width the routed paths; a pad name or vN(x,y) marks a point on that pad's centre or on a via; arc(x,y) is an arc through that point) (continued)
QSB6: length 36.8
  IN1 w0.102: v1(208.54,112.02) 208.25,111.74 208.25,111.64 208.37,111.52 208.93,111.52 209.44,111.01 209.44,109.17 208.86,108.6 205.73,108.6 205.72,108.58 205.69,108.58 ; 194.39,112.56 194.36,112.56 194.34,112.57 190.25,112.57 189.67,112 188.64,112 188.43,111.79 v1(188.43,111.71)
  IN1 w0.14: 205.69,108.58 205.29,108.58 204.99,108.28 199.72,108.28 199.37,108.64 199.37,111.09 199.24,111.22 198.8,111.22 198.67,111.09 198.67,108.56 198.39,108.28 197.73,108.28 197.45,108.56 197.45,112.43 197.32,112.56 196.6,112.56 196.48,112.43 196.48,112.21 196.18,111.92 195.55,111.92 195.25,112.21 195.25,112.42 195.11,112.56 194.39,112.56
  BOTTOM w0.102: UV1.AJ9 188.43,111.72 v1(188.43,111.71) ; UV24.F3 208.15,111.64 v1(208.54,112.02)
QSB7: length 35.4
  TOP w0.102: UV25.C7 208.33,109.05 208.86,109.05 209.25,108.67 209.25,107.09 208.33,106.18 208.33,106.17 208.29,106.13 208.29,106.12 208.27,106.11 ; v1(191.66,110.01) 191.94,109.72 191.94,109.59 192.13,109.4 194.36,109.4 194.36,109.39 194.39,109.39
  TOP w0.109: 194.39,109.39 v3(195.37,109.39) 201.08,109.39 201.32,109.63 201.32,112.77 201.44,112.89 201.74,112.89 201.86,112.77 201.86,111.27 202.11,111.02 202.58,111.02 202.83,111.27 202.83,112.77 202.96,112.89 203.25,112.89 203.38,112.77 203.38,106.11 203.75,105.73 207.9,105.73 208.27,106.11
  BOTTOM w0.102: v1(191.66,110.01) 191.34,109.69 UV1.AM5
QSB#0: length 35.8
  TOP w0.102: v1(190.04,130.27) 190.31,130.54 190.31,131.09 190.7,131.47 191.32,131.47 191.94,132.09 v3(192.4,132.09) 194.36,132.09 194.37,132.1 194.39,132.1 ; UV22.B7 211.06,138.2 210.44,138.2 210.2,138.45 210.2,140.33 209.86,140.67
  TOP w0.109: 209.86,140.67 208.91,141.62 205.14,141.62 197.87,134.35 197.87,134.03 199.41,132.48 199.41,132.3 199.2,132.1 199.02,132.1 197.48,133.64 197.15,133.64 196.8,133.28 196.8,132.95 197.27,132.48 197.27,132.3 197.06,132.1 196.88,132.1 196.41,132.57 196.08,132.57 195.61,132.1 194.39,132.1
  BOTTOM w0.102: UV1.G7 190.03,130.26 190.03,130.27 v1(190.04,130.27)
QSB#1: length 34.8
  BOTTOM w0.102: 208.06,140.67 208.23,140.5 208.23,140.5 208.27,140.46 208.28,140.46 209.19,139.55 209.19,138.29 208.97,138.08 207.78,138.08 207.66,138.2 207.66,138.38 207.78,138.5 UV23.B7 ; 204.96,139.94 205.12,140.11 205.12,140.11 205.16,140.16 205.16,140.16 205.46,140.46 205.47,140.46 205.51,140.5 205.51,140.5 205.68,140.67 ; UV1.K1 192.96,127.39 193.77,127.39 194.19,127.81 194.39,127.81
  BOTTOM w0.109: 194.39,127.81 194.65,127.81 196.63,129.79 196.63,131.62 197.11,132.1 197.11,132.46 196.63,132.94 196.63,133.09 196.84,133.3 197.02,133.3 197.5,132.82 197.83,132.82 200.6,135.59 v3(201.91,135.59) 202.55,135.59 202.79,135.82 202.79,137.53 202.91,137.66 203.21,137.66 203.33,137.53 203.33,135.82 203.56,135.59 204.02,135.59 204.3,135.87 204.3,139.29 204.96,139.94 ; 208.06,140.67 207.64,141.09 206.1,141.09 205.68,140.67
QSB#2: length 36.6
  TOP w0.102: v1(208.55,134.9) 208.15,134.51 UV22.G3
  IN3 w0.102: v1(208.55,134.9) 208.71,135.06 208.8,135.16 209.58,135.16 210.07,135.65 210.07,136.97 209.59,137.46 204.96,137.46
  IN3 w0.14: 204.96,137.46 204.12,137.46 203.62,136.96 203.62,136.55 203.95,136.22 203.95,136.04 203.64,135.72 203.46,135.72 203.13,136.05 202.72,136.05 202.27,135.61 202.27,135.2 203.77,133.71 203.77,133.53 203.45,133.21 203.27,133.21 201.78,134.71 201.37,134.71 200.52,133.86 200.52,128.76 200.7,128.58 200.7,128.4 v1(200.53,128.23)
  BOTTOM w0.102: UV1.P1 192.94,124.17 194.36,124.17 194.37,124.18 194.39,124.18
  BOTTOM w0.109: 194.39,124.18 196.72,124.18 196.74,124.2 197.23,124.2 200.74,127.71 200.74,128.03 v1(200.53,128.23)
QSB#3: length 40.3
  IN1 w0.102: v1(210.97,134.9) 211.27,134.9 211.4,135.03 211.4,135.24 211.27,135.36 209.85,135.36 209.59,135.62 209.59,136.19 209.85,136.45 210.01,136.45 210.13,136.57 210.13,136.95 210.01,137.08 206.86,137.08 206.85,137.06 206.83,137.06 ; 194.39,121.35 194.36,121.35 194.34,121.37 193.81,121.37 193.75,121.3 193.75,121.16 v1(193.96,120.96)
  IN1 w0.14: 194.39,121.35 198.11,121.35 198.39,121.63 198.39,122.74 198.11,123.02 195.84,123.02 195.72,123.14 195.72,128.58 201.33,134.19 203.15,134.19 206.02,137.06 206.83,137.06
  BOTTOM w0.102: v1(193.96,120.96) 193.31,120.31 192.68,120.31 192.58,120.41 192.32,120.41 192.29,120.38 191.78,120.38 191.66,120.26 UV1.W4 ; v1(210.97,134.9) 211.35,134.52 UV23.G3
QSB#4: length 36.9
  TOP w0.102: UV25.G3 211.35,112.05 211.28,111.98 210.68,111.98 210.55,111.85 210.55,111.6 210.69,111.46 v1(210.85,111.46)
  IN3 w0.102: 204.96,108.58 204.97,108.58 204.99,108.6 209.06,108.6 209.56,109.11 209.56,110.6 209.7,110.74 210.43,110.74 210.63,110.94 210.63,111.24 v1(210.85,111.46)
  IN3 w0.14: v1(198.81,114.9) 198.97,114.73 198.97,114.46 202.14,111.3 202.14,111.1 200.92,109.88 200.92,109.49 201.38,109.02 201.78,109.02 203,110.24 203.19,110.24 203.49,109.95 203.49,109.75 202.27,108.53 202.27,108.14 202.73,107.68 203.12,107.68 204.34,108.9 204.54,108.9 204.86,108.58 204.96,108.58
  BOTTOM w0.102: 194.26,117.68 194.24,117.68 194.24,117.68 194.18,117.68 194.17,117.68 193.79,117.68 193.78,117.67 193.77,117.67 193.7,117.6 193.7,117.6 193.27,117.17 192.66,117.17 192.59,117.23 192.34,117.23 192.23,117.12 191.89,117.12 UV1.AC4
  BOTTOM w0.109: 194.26,117.68 194.67,117.68 194.73,117.61 194.73,117.54 194.98,117.29 195.51,117.29 195.7,117.47 195.7,117.62 195.76,117.68 196.25,117.68 196.46,117.47 196.46,117.07 196.7,116.83 196.98,116.83 197.24,116.56 197.93,116.56 198.06,116.43 198.06,115.66 198.32,115.4 198.94,115.4 199,115.33 199,115.09 v1(198.81,114.9)
QSB#5: length 35.4
  BOTTOM w0.102: UV24.B7 211.33,108.42 211.06,108.69 210.46,108.69 210.34,108.56 210.34,106.47 210.12,106.26 ; UV1.AH3 192.38,112.89 192.7,112.57 193,112.57 193.07,112.65 194.36,112.65 194.36,112.65 194.39,112.65
  BOTTOM w0.109: 194.39,112.65 199.75,112.65 199.88,112.52 199.88,112.23 199.75,112.1 v3(198.66,112.1) 196.65,112.1 196.4,111.85 196.4,111.38 196.65,111.13 199.77,111.13 199.88,111.02 199.88,106.95 201.99,104.84 203.05,104.84 203.08,104.81 203.64,104.81 203.66,104.84 208.7,104.84 210.12,106.26
QSB#6: length 36.5
  IN1 w0.102: v1(207.75,112.02) 208.03,111.74 208.03,111.54 208.27,111.3 208.84,111.3 209.21,110.92 209.21,109.27 208.77,108.83 205.73,108.83 205.72,108.84 205.69,108.84 ; 194.39,112.82 194.36,112.82 194.34,112.8 190.15,112.8 189.58,112.22 188.74,112.22 v1(188.42,112.54)
  IN1 w0.14: 205.69,108.84 205.18,108.84 204.88,108.55 199.83,108.55 199.63,108.75 199.63,111.2 199.35,111.48 198.69,111.48 198.41,111.2 198.41,108.67 198.28,108.55 197.84,108.55 197.71,108.67 197.71,112.54 197.43,112.82 196.49,112.82 196.21,112.54 196.21,112.32 196.07,112.18 195.66,112.18 195.52,112.32 195.52,112.52 195.22,112.82 194.39,112.82
  BOTTOM w0.102: v1(188.42,112.54) 188.86,112.09 UV1.AJ8 ; v1(207.75,112.02) 208.15,112.42 UV24.G3
QSB#7: length 34.7
  TOP w0.102: 194.39,109.61 194.36,109.61 194.36,109.6 192.21,109.6 192.14,109.67 192.14,109.87 192.28,110.01 v1(192.43,110.01) ; 208.12,106.26 209.04,107.18 209.04,108.58 208.78,108.84 208.27,108.84 208.15,108.73 UV25.B7
  TOP w0.109: 208.12,106.26 207.81,105.94 203.84,105.94 203.59,106.2 203.59,112.85 203.34,113.1 202.87,113.1 202.62,112.85 202.62,111.36 202.49,111.23 202.2,111.23 202.07,111.36 202.07,112.85 201.82,113.1 201.36,113.1 201.11,112.85 201.11,109.71 201,109.61 195.67,109.61 195.65,109.63 195.09,109.63 195.07,109.61 194.39,109.61
  BOTTOM w0.102: UV1.AM3 192.11,109.69 v1(192.43,110.01)
RASA0#: length 41.6
  TOP w0.102: 174.38,135.39 174.38,135.33 174.45,135.27 174.45,132.75 174.55,132.66 174.55,131.15 175.07,130.62 175.1,130.62 175.1,130.62 175.41,130.62 175.84,130.19 176.23,130.19 176.43,129.99 176.43,127.58 v1(176.05,127.2) ; UV18.J3 169.14,146.3 168.8,146.3 168.52,146.57 168.35,146.57 168.22,146.7 168.22,147.08 168.35,147.21 168.84,147.21 168.97,147.08 v1(168.97,147.02)
  TOP w0.127: v1(175.08,139.72) 175.08,139.82 174.96,139.94 174.26,139.94 174.13,140.07 174.13,140.1 174,140.22 173.72,140.22 173.6,140.1 173.6,139.4 173.72,139.27 v2(174.26,139.27) 174.72,139.27 174.85,139.15 174.85,138.34 174.72,138.22 174.08,138.22 173.96,138.09 173.96,137.84 174.08,137.71 174.72,137.71 174.85,137.58 174.85,136.82 174.7,136.67 174.51,136.67 174.38,136.54 174.38,135.39
  IN1 w0.102: 171.72,142.86 170.89,143.69 170.89,145.1 169.68,146.31 168.28,146.31 168.15,146.44 168.15,146.89 168.28,147.02 v1(168.97,147.02)
  IN1 w0.14: 171.72,142.86 173.93,140.66 177.01,140.66 177.13,140.53 177.13,139.84 177.01,139.72 v1(175.08,139.72)
  BOTTOM w0.102: UV19.J3 169.37,149.25 168.59,148.47 168.59,147.4 v1(168.97,147.02) ; v1(176.05,127.2) 176.34,127.49 UV1.K23
RASA1#: length 41.4
  TOP w0.102: UV20.J3 188.78,149.08 189.03,148.84 189.62,148.84 189.75,148.71 189.75,148.14 189.62,148.01 189.33,148.01 189.2,148.14 v1(189.2,148.29) ; v1(179.69,127.86) 180.12,127.86 180.35,128.1 180.35,130.31 180.86,130.82 180.86,131.17 180.35,131.68 180.35,133.64 180.79,134.07
  TOP w0.127: 180.79,134.07 180.96,134.24 180.96,134.89 181.08,135.02 182.18,135.02 182.31,135.14 182.31,135.51 182.18,135.63 181.13,135.63 181,135.76 181,136.01 181.13,136.14 v2(181.5,136.14) 182.18,136.14 182.31,136.27 182.31,136.61 182.18,136.73 181.63,136.73 181.5,136.86 181.5,137.15 181.63,137.28 182,137.28 182.13,137.4 182.13,137.66 182,137.78 181.63,137.78 181.5,137.91 181.5,140.94 181.37,141.06 180.76,141.06 180.64,140.94 180.64,140.42 180.76,140.29 v1(180.8,140.29)
  IN1 w0.102: v1(189.2,148.29) 188.99,148.29 188.75,148.05 188.75,146.62 187.92,145.79 187.92,143.1 187.68,142.86
  IN1 w0.14: 187.68,142.86 185.11,140.29 v1(180.8,140.29)
  BOTTOM w0.102: UV1.K19 180.05,127.49 v1(179.69,127.86) ; v1(189.2,148.29) 189.58,147.91 189.58,146.84 188.79,146.05 UV21.J3
RASB0#: length 41.6
  TOP w0.102: UV22.J3 208.15,133.17 209.18,134.2 209.36,134.2 209.59,133.97 209.59,133.79 v1(209.12,133.32) ; 194.39,124.12 190.86,124.12 189.7,122.96 v2(188.9,122.96) 188.67,122.73 187.75,122.73 187.49,122.47 v1(187.49,122.25)
  TOP w0.127: v1(201.13,123.86) 200.87,124.12 194.39,124.12
  IN1 w0.102: 204.96,130.57 206.4,132.01 207.81,132.01 v1(209.12,133.32)
  IN1 w0.14: 204.96,130.57 203.56,129.17 203.56,127.48 202.91,126.83 202.72,126.83 201.8,127.75 201.6,127.75 201.4,127.56 201.4,127.36 202.32,126.44 202.32,126.24 202.12,126.04 201.93,126.04 200.59,127.38 200.41,127.38 200.19,127.17 200.19,126.99 201.53,125.65 201.53,125.45 201.13,125.05 v1(201.13,123.86)
  BOTTOM w0.102: v1(209.12,133.32) 209.5,133.7 210.57,133.7 211.35,132.92 UV23.J3 ; UV1.T10 187.49,122.66 v1(187.49,122.25)
RASB1#: length 41.7
  TOP w0.102: UV25.J3 210.93,113.6 v1(210.39,113.6) ; v1(187.7,119.89) 188.36,120.56 191.34,120.56 191.55,120.76 193.02,120.76 193.21,120.57 194.12,120.57 194.39,120.85
  TOP w0.127: v1(201.2,121.7) 201.2,121.73 200.62,122.32 199,122.32 198.87,122.19 198.87,121.67 198.75,121.54 196.24,121.54 196.12,121.67 196.12,122.19 195.99,122.32 195.14,122.32 195.02,122.19 195.02,120.97 194.89,120.85 194.39,120.85
  IN1 w0.102: 204.96,115.11 205.2,114.88 207.89,114.88 208.72,114.04 210.15,114.04 210.39,113.81 v1(210.39,113.6)
  IN1 w0.14: 204.96,115.11 202.15,117.93 202.15,118.78 202.02,118.9 200.81,118.9 200.67,119.04 200.67,119.32 200.81,119.46 202.02,119.46 202.15,119.59 202.15,119.89 202.02,120.02 200.81,120.02 200.67,120.16 200.67,120.44 200.81,120.58 201.56,120.58 201.69,120.71 201.69,121.01 201.56,121.14 200.81,121.14 200.67,121.28 200.67,121.58 200.8,121.7 v1(201.2,121.7)
  BOTTOM w0.102: v1(210.39,113.6) 210.01,113.22 208.82,113.22 208.15,113.88 UV24.J3 ; v1(187.7,119.89) 187.26,119.46 UV1.Y10
REGN: length 16.6
  TOP w0.102: v2(169.69,163.72) 169.12,164.29 v1(169.07,164.29)
  TOP w0.254: v1(170.27,171.27) 170.65,171.65 PR713.1 ; v1(169.07,164.29) PR707.1
  IN1 w0.254: v1(165.45,170.76) 166.34,169.87 166.34,165.94 167.99,164.29 v1(169.07,164.29)
  IN3 w0.254: v1(170.27,171.27) 169.57,170.57 165.64,170.57 v1(165.45,170.76)
RF_+1.2VSP: length 3.3
  TOP w0.102: v1(189.13,173.45) v2(189.13,174.67)
  TOP w0.254: PU1100.5 188.73,173.29 188.9,173.45 v1(189.13,173.45)
  BOTTOM w0.254: v1(189.13,173.45) 188.78,173.81 PR1105.1
RING2: length 12.1
  TOP w0.102: v1(17.5,22.74) 17.9,22.74 v2(18.1,22.94)
  IN3 w1.016: 17.3,23.51 18.06,23.51 18.32,23.76 22.93,23.76 23.37,24.2 24.69,24.2 26.45,25.96 27.67,25.96
  vias: v1(16.92,22.74) v1(27.97,25.16) v1(27.97,24.5)
RING2_R: length 21.8
  TOP w0.102: v2(19.27,16.44) 19.17,16.55 18.14,16.55
  IN3 w1.016: 17.42,14.53 17.43,14.51 17.43,8.9 15.14,6.61 5.49,6.61 4.01,8.09 JHP.3
  vias: v1(17.17,15.39) v1(17.76,15.39)
RREF: length 4.6
  TOP w0.102: RR1.1 174.17,18.07 v2(174.07,18.17)
  TOP w0.305: RR1.1 175,19.19 175.82,20.01 UR1.1
RSVD_AL1: length 3.5
  BOTTOM w0.076: UC1.AL1 131.85,108.6 132.3,108.15
  BOTTOM w0.089: T136.1 132.3,108.15
RSVD_AM11: length 1.4
  TOP w0.089: v1(123.66,107.48) 124.03,107.12 T137.1
  BOTTOM w0.076: v1(123.66,107.48) 123.73,107.48 UC1.AM11
RSVD_AP7: length 15
  TOP w0.089: 133.1,101.44 132.49,102.06 129.98,102.06 127.41,104.63 127.41,104.98 127.09,105.29 126.71,105.29 126.39,105.61 126.39,106.03 v1(125.59,106.83)
  TOP w0.102: 133.1,101.44 134.75,99.79 T139.1
  BOTTOM w0.089: UC1.AP7 v1(125.59,106.83)
RSVD_AT2: length 6.1
  BOTTOM w0.076: T128.1 134.69,105.33 131.21,105.33 130.65,105.89 129.91,105.89 129.63,105.61 UC1.AT2
RSVD_AU10: length 10.3
  TOP w0.089: T141.1 124.97,98.88 122.88,100.97 122.88,104.45 123.41,104.98 124.55,104.98 v1(125,104.53)
  BOTTOM w0.076: v1(125,104.53) 124.64,104.88 UC1.AU10
RSVD_AU15: length 6
  TOP w0.089: v1(123.53,104.55) 123.09,104.11 123.09,101.92 T142.1
  BOTTOM w0.076: v1(123.53,104.55) 123.53,105 123.33,105.2 122,105.2 121.68,104.88 UC1.AU15
RSVD_AU44: length 5.1
  BOTTOM w0.076: T132.1 102.67,99.93 102.67,104.41 102.94,104.67 102.94,104.74 UC1.AU44
RSVD_AV44: length 3.8
  BOTTOM w0.076: T134.1 103.23,101.2 102.84,101.59 102.84,103.94 UC1.AV44
RSVD_AW14: length 5.7
  BOTTOM w0.076: 122.36,101.66 122.11,101.9 122.11,103.29 UC1.AW14
  BOTTOM w0.089: T144.1 124.46,99.11 123.05,100.52 123.05,100.97 122.92,101.1 122.97,101.05 122.36,101.66
RSVD_AY14: length 2.8
  BOTTOM w0.089: UC1.AY14 122.41,102.59 122.61,102.39 122.61,101.9 123.6,100.91 T145.1
RSVD_D15: length 1.6
  TOP w0.089: T135.1 v1(121.85,124.33)
  BOTTOM w0.076: v1(121.85,124.33) UC1.D15
RSVD_F22: length 1.3
  TOP w0.089: T138.1 118.08,122.4 v1(118.19,122.28)
  BOTTOM w0.089: v1(118.19,122.28) 117.97,122.5 UC1.F22
RSVD_H22: length 1.5
  TOP w0.089: T140.1 117.64,121.61 v1(118.19,121.06)
  BOTTOM w0.089: UC1.H22 118.11,120.98 v1(118.19,121.06)
RSVD_J21: length 1.6
  TOP w0.089: v1(118.09,119.72) 118.48,119.33 T143.1
  BOTTOM w0.076: UC1.J21 118.18,119.82 v1(118.09,119.72)
RSVD_N23: length 2.1
  TOP w0.089: v1(116.14,118.54) 116.4,118.8 T129.1
  BOTTOM w0.076: v1(116.14,118.54) 116.55,118.14 UC1.N23
RSVD_R23: length 1.8
  TOP w0.089: T130.1 115.67,117.73 v1(116.14,117.73)
  BOTTOM w0.076: v1(116.14,117.73) 116.55,117.32 UC1.R23
RSVD_T23: length 2
  TOP w0.089: v1(116.14,116.92) 116.14,116.51 T131.1
  BOTTOM w0.076: UC1.T23 116.55,116.51 v1(116.14,116.92)
RSVD_U10: length 2.6
  TOP w0.089: T133.1 124.1,117.08 v1(123.84,116.82)
  BOTTOM w0.089: UC1.U10 124.8,116.26 124.47,115.93 123.97,115.93 123.78,116.12 123.78,116.76 v1(123.84,116.82)
RTC_VOUT: length 4.8
  TOP w0.102: v2(67.38,44.7) RG2.2 69.56,44.7 CG6.1 69.8,44.32 71.03,43.09 UG1.14
RUNPWROK: length 231
  TOP w0.203: v1(195.37,38.11) 195.37,38.28 195.72,38.63 196.18,38.63 196.31,38.51 UE1.36
  TOP w0.254: v1(68.42,104.56) 68.42,104.35 68.14,104.07 67.1,104.07 66.69,104.48 v1(66.69,106.74)
  IN1 w0.254: v1(72.94,104.9) 72.34,104.9 72,104.56 v1(68.42,104.56) ; v1(192.5,59.71) 192.5,57.99 194.88,55.61 194.88,54.41 195.72,53.57 195.72,52.92 196.73,51.91 196.73,45.77 195.89,44.94 195.89,38.77 195.37,38.24 v1(195.37,38.11) ; v1(66.69,106.74) 70.31,106.74 v1(70.96,107.39)
  IN3 w0.254: v1(66.69,106.74) 66.57,106.62 66.57,106.11 64.95,104.49 64.95,102.85 65.56,102.24 65.56,100.59 66.58,99.58 66.58,96.47 65.92,95.81 65.92,91.81 65,90.89 65,88.74 65.68,88.06 65.68,78.36 70.45,73.59 70.45,72.34 72.82,69.97 72.82,55.49 75.4,52.91 103.92,52.91 105.14,54.12 113.73,54.12 114.52,54.91 116.26,54.91 117.77,53.41 174.74,53.41 176.47,55.14 176.47,55.35 177.82,56.7 180.24,56.7 186.13,62.6 189.61,62.6 v1(192.5,59.71)
  BOTTOM w0.254: UC4.10 v1(68.42,104.56) ; UC4.4 72.7,105.06 72.86,104.9 v1(72.94,104.9) ; UC4.1 71.1,107.24 v1(70.96,107.39) 71.16,107.59 CC29.1 ; v1(66.69,106.74) v2(67.55,106.74) 68.24,106.74 68.93,106.06 UC4.13
SATA_ACT#: length 195.9
  TOP w0.102: v1(35.02,71.26) 35.02,52.97 43.98,44 v2(43.98,34.52) RD15.1
  IN2 w0.089: 121.03,93.61 124.01,96.59 124.68,96.59 128.3,100.21 129.95,100.21 130.33,100.59 130.33,102.25 129.92,102.66 129.92,111.26 130.05,111.4 130.05,113.72 130.48,114.15 132.8,114.15 133.37,114.72 133.37,115.49 132.87,116 v1(132.87,116.77)
  IN2 w0.127: v1(35.02,71.26) 35.59,71.83 44.79,71.83 58.26,85.29 112.71,85.29 121.03,93.61
  BOTTOM w0.076: UC1.U3 129.23,115.8 129.75,115.8 129.99,116.04 129.99,116.21 130.16,116.38 130.4,116.38 130.53,116.26 131.18,116.26 132.04,117.12 132.52,117.12 v1(132.87,116.77)
SATA_IREF: length 5.4
  BOTTOM w0.254: UC1.A12 123.16,126.75
  BOTTOM w0.305: 123.16,126.75 122.91,127 v2(122.91,127.56) 122.91,129.19 123.35,129.62 RC126.1
SATA_PRX_DTX_N0: length 5.3
  TOP w0.102: CS109.1 224.72,40.48 225.45,40.48 225.77,40.8 225.77,41.06 225.78,41.08 225.78,41.61 225.77,41.62 225.77,42.76 225.95,42.94 226.76,42.94 JHDD.5
SATA_PRX_DTX_N0_C: length 147.5
  TOP w0.102: v1(218.91,40.29) 219.11,40.48 223.14,40.48 CS109.2
  IN1 w0.084: 137.92,121.49 137.88,121.53 135.52,121.53 134.7,120.72 131.94,120.72 131.57,120.34 127.5,120.34 v1(127.19,120.04)
  IN1 w0.127: 137.92,121.49 143.74,121.49 151.07,114.16 151.07,113.27 154.79,109.55 154.79,107.2 156.11,105.87 156.11,103.14 170.06,89.2 174.43,89.2 179.47,84.16 184.61,84.16 191.57,77.21 191.57,66.55 192.62,65.49 192.62,62.41 193.43,61.61 193.43,58.04 195.58,55.9 195.58,54.7 202.77,47.51 202.77,44.44 205.48,41.73 216.75,41.73 218.04,40.44 218.76,40.44 v1(218.91,40.29)
  BOTTOM w0.076: UC1.J5 127.57,120.34 127.27,120.04 v1(127.19,120.04)
SATA_PRX_DTX_N1: length 4.8
  BOTTOM w0.102: JODD.5 226.52,103.83 223.9,103.83 223.89,103.82 223.36,103.82 223.34,103.83 222.98,103.83 CS14.1
SATA_PRX_DTX_N1_C: length 124.2
  IN1 w0.084: 137.92,123.66 132.42,123.66 131.82,124.26 128.09,124.26 127.59,123.76 126.79,123.76 125.94,122.91 125.94,121.52 125.82,121.4 125.82,121.11 v1(125.37,120.66)
  IN1 w0.127: 137.92,123.66 143.82,123.66 152.86,114.63 152.86,113.77 156.6,110.02 156.6,108.56 157.05,108.11 157.05,107.15 159.59,104.61 159.59,103.4 162.47,100.51 162.47,99.29 170.49,91.27 177.16,91.27 177.95,90.48 182.14,90.48 182.57,90.05 185.41,90.05 185.63,90.27 208.51,90.27 213.96,95.72 213.96,97.21 214.49,97.74 215.63,97.74 218.91,101.02 219.29,101.02 220.49,102.22 220.49,102.5 v1(220.69,102.7)
  BOTTOM w0.089: v1(125.37,120.66) 125.69,120.34 UC1.J8
  BOTTOM w0.102: CS14.2 221.46,103.77 221.07,103.77 220.56,103.26 220.56,102.82 v1(220.69,102.7)
SATA_PRX_DTX_P0: length 5.4
  TOP w0.102: JHDD.6 226.63,43.15 225.86,43.15 225.56,42.85 v3(225.56,41.34) 225.56,40.89 225.36,40.69 224.72,40.69 CS108.1
SATA_PRX_DTX_P0_C: length 147.4
  TOP w0.102: v1(218.91,40.87) 219.09,40.69 223.14,40.69 CS108.2
  IN1 w0.084: 137.92,121.76 135.42,121.76 134.61,120.94 131.84,120.94 131.47,120.57 127.33,120.57 v1(127.22,120.69)
  IN1 w0.127: 137.92,121.76 143.85,121.76 151.34,114.27 151.34,113.38 155.06,109.66 155.06,107.31 156.38,105.98 156.38,103.26 170.17,89.47 174.54,89.47 179.58,84.44 184.72,84.44 191.84,77.32 191.84,66.66 192.9,65.6 192.9,62.53 193.7,61.72 193.7,58.15 195.85,56.01 195.85,54.81 203.04,47.62 203.04,44.56 205.59,42 216.86,42 218.15,40.71 218.76,40.71 v1(218.91,40.87)
  BOTTOM w0.076: UC1.H5 127.59,120.99 127.28,120.69 v1(127.22,120.69)
SATA_PRX_DTX_P1: length 4.8
  BOTTOM w0.102: CS15.1 222.98,104.05 v3(223.62,104.05) 226.53,104.05 JODD.6
SATA_PRX_DTX_P1_C: length 123.9
  IN1 w0.084: v1(125.37,121.32) 125.42,121.32 125.74,121.64 125.74,123.03 126.7,123.99 127.5,123.99 127.99,124.49 131.91,124.49 132.51,123.89 137.8,123.89 137.82,123.91 137.89,123.91 137.91,123.93 137.92,123.93
  IN1 w0.127: 137.92,123.93 143.94,123.93 153.13,114.74 153.13,113.88 156.87,110.13 156.87,108.67 157.32,108.23 157.32,107.27 159.87,104.72 159.87,103.51 162.75,100.63 162.75,99.4 170.61,91.54 177.28,91.54 178.06,90.75 182.25,90.75 182.68,90.32 185.29,90.32 185.51,90.54 208.4,90.54 213.69,95.83 213.69,97.32 214.38,98.01 215.51,98.01 218.8,101.29 219.18,101.29 220.22,102.33 220.22,102.58 v1(220.1,102.7)
  BOTTOM w0.089: UC1.H8 125.7,120.99 v1(125.37,121.32)
  BOTTOM w0.102: CS15.2 221.33,103.99 220.98,103.99 220.35,103.35 220.35,102.95 v1(220.1,102.7)
SATA_PTX_DRX_N0: length 3.4
  TOP w0.102: JHDD.3 226.69,39.41 v3(225.58,39.41) 225.34,39.41 224.85,38.92 224.72,38.92 CS106.1
SATA_PTX_DRX_N0_C: length 169.9
  TOP w0.102: v1(221.71,39.15) 221.94,38.92 223.14,38.92 CS106.2
  IN1 w0.084: v1(121.72,127.56) 121.52,127.75 120.32,127.75 119.31,126.74 119.31,125.56 119.87,125.01 124.61,125.01 124.97,124.65 124.97,120.45 125.17,120.25 125.85,120.25 127.25,121.65 133.63,121.65 134.89,122.91 137.89,122.91 137.91,122.94 137.92,122.94
  IN1 w0.127: 137.92,122.94 143.78,122.94 152.16,114.56 152.16,113.73 155.86,110.03 155.86,107.61 157.16,106.31 157.16,103.67 170.58,90.25 174.87,90.25 179.9,85.21 186.47,85.21 192.65,79.03 192.65,66.97 193.68,65.93 193.68,63.29 194.52,62.46 194.52,59.27 197.16,56.63 197.16,54.85 203.82,48.19 203.82,46.61 207.6,42.83 219,42.83 220.44,41.39 220.44,39.73 221.14,39.03 221.59,39.03 v1(221.71,39.15)
  BOTTOM w0.076: v1(121.72,127.56) 121.72,127.75 121.62,127.85 121.42,127.85 121.31,127.74 121.31,126.22 121.52,126.02 121.52,125.79 121.63,125.68 121.63,125.44 121.1,124.92 UC1.B15
SATA_PTX_DRX_N1: length 5.1
  BOTTOM w0.102: JODD.3 226.51,100.22 225.62,100.22 224.92,100.91 v3(223.61,100.91) 222.98,100.91 CS9.1
SATA_PTX_DRX_N1_C: length 127.6
  IN1 w0.084: v1(120.36,126.19) 120.17,126 120.17,125.77 120.26,125.68 134.36,125.68 135.28,124.76 137.81,124.76 137.83,124.78 137.89,124.78 137.91,124.8 137.92,124.8
  IN1 w0.127: 137.92,124.8 145.94,124.8 154.19,116.55 154.19,114.88 158.4,110.66 158.4,107.64 160.65,105.4 160.65,103.86 163.66,100.85 163.66,99.59 170.93,92.32 178.25,92.32 179.04,91.53 182.4,91.53 182.94,92.07 189.84,92.07 190.53,91.39 208.05,91.39 210.23,93.56 210.23,93.9 v1(210,94.12)
  BOTTOM w0.089: UC1.A17 120.5,125.41 120.38,125.37 120.3,125.41 120.2,125.51 120.2,126.03 v1(120.36,126.19)
  BOTTOM w0.102: CS9.2 221.73,100.95 221.6,100.82 217.23,100.82 212.27,95.86 211.33,95.86 210.32,94.84 210.32,94.43 v1(210,94.12)
SATA_PTX_DRX_P0: length 3.4
  TOP w0.102: CS105.1 224.72,38.7 224.94,38.7 225.42,39.18 225.87,39.18 225.89,39.19 226.69,39.19 JHDD.2
SATA_PTX_DRX_P0_C: length 169.6
  TOP w0.102: v1(221.71,38.56) 221.85,38.7 223.14,38.7 CS105.2
  IN1 w0.084: v1(121.72,128.21) 121.43,127.92 120.25,127.92 119.14,126.82 119.14,125.49 119.79,124.84 124.54,124.84 124.8,124.58 124.8,120.38 125.1,120.08 126.01,120.08 127.35,121.42 133.72,121.42 134.99,122.68 137.89,122.68 137.91,122.66 137.92,122.66
  IN1 w0.127: v1(221.71,38.56) 221.51,38.76 221.03,38.76 220.17,39.62 220.17,41.28 218.89,42.56 207.48,42.56 203.55,46.49 203.55,48.08 196.88,54.74 196.88,56.52 194.24,59.16 194.24,62.34 193.41,63.18 193.41,65.82 192.38,66.86 192.38,78.92 186.36,84.94 179.79,84.94 174.75,89.98 170.47,89.98 156.89,103.56 156.89,106.19 155.59,107.5 155.59,109.92 151.88,113.62 151.88,114.45 143.67,122.66 137.92,122.66
  BOTTOM w0.076: v1(121.72,128.21) 121.55,128.04 121.34,128.04 121.12,127.82 121.12,126.14 121.32,125.94 121.32,125.71 121.33,125.7 UC1.A15
SATA_PTX_DRX_P1: length 5.1
  BOTTOM w0.102: JODD.2 226.54,100 225.53,100 224.83,100.7 223.89,100.7 223.87,100.69 223.34,100.69 223.33,100.7 222.98,100.7 CS8.1
SATA_PTX_DRX_P1_C: length 127.6
  IN1 w0.084: 137.92,124.53 135.18,124.53 134.26,125.45 120.17,125.45 119.94,125.67 119.94,125.9 v1(119.78,126.06)
  IN1 w0.127: 137.92,124.53 145.83,124.53 153.91,116.44 153.91,114.77 158.13,110.55 158.13,107.53 160.37,105.29 160.37,103.75 163.38,100.74 163.38,99.48 170.82,92.05 178.14,92.05 178.93,91.26 182.51,91.26 183.05,91.8 189.73,91.8 190.42,91.12 208.17,91.12 210.5,93.45 210.5,94.03 v1(210.59,94.12)
  BOTTOM w0.089: v1(119.78,126.06) 119.98,125.86 119.98,125.45 120.18,125.25 120.2,125.24 120.28,125.19 120.32,125.07 UC1.B17
  BOTTOM w0.102: CS8.2 221.49,100.6 217.32,100.6 212.36,95.64 211.42,95.64 210.53,94.75 210.53,94.17 v1(210.59,94.12)
SATA_RCOMP: length 6.8
  BOTTOM w0.203: 123.56,126.59 123.56,125.42 123.18,125.05 123.18,124.39 UC1.C12
  BOTTOM w0.305: 124.43,129.36 123.56,128.49 123.56,126.59 ; 124.43,129.36 RC131.1 ; 124.43,129.36 v2(124.43,129.35)
SD_CD#: length 21
  TOP w0.102: UR1.13 178.32,26.36 179.09,27.13 CR9.1 179.58,26.42 v1(179.4,26.24) 179.58,26.06 v2(180.28,26.06)
  BOTTOM w0.102: v1(179.4,26.24) 179.4,25.59 179.27,25.46 173.92,25.46 173.79,25.59 173.79,26.5 173.66,26.63 173.51,26.63 173.38,26.5 173.38,25.59 173.26,25.46 173.05,25.46 172.93,25.59 172.93,26.52 172.8,26.64 172.62,26.64 172.49,26.52 172.49,25.59 172.37,25.46 172.18,25.46 172.05,25.59 172.05,28.52 171.72,28.86 JREAD.20
SD_CMD: length 26
  TOP w0.102: UR1.18 175.82,26.33 CR11.1 175.77,27.59 176.16,27.59 176.42,27.86 176.42,28.72 177.09,29.39 179.53,29.39 181.67,27.25 184.08,27.25 184.19,27.35 184.19,28.1 184.29,28.2 184.49,28.2 184.59,28.1 184.59,27.35 184.69,27.25 184.9,27.25 185,27.35 v2(185,27.89) 185,28.73 185.12,28.85 185.29,28.85 185.4,28.73 185.4,27.35 185.51,27.25 185.71,27.25 185.81,27.35 185.81,28.72 185.93,28.84 186.1,28.84 186.22,28.72 186.22,27.35 186.32,27.25 v1(186.78,27.25)
  BOTTOM w0.102: v1(186.78,27.25) 186.92,27.38 JREAD.6
SD_D0: length 24.2
  TOP w0.102: v1(180.66,23.84) 180.22,24.28 179.76,24.28 179.67,24.19 UR1.11
  BOTTOM w0.102: JREAD.18 174.76,27.23 174.88,27.1 176.4,27.1 176.53,27.23 176.53,28.34 176.65,28.47 176.89,28.47 177.02,28.34 177.02,26.97 177.14,26.85 177.44,26.85 177.56,26.97 177.56,28.4 177.69,28.52 178.03,28.52 178.16,28.4 178.16,26.05 178.29,25.92 178.64,25.92 178.76,26.05 178.76,27.44 178.89,27.57 179.91,27.57 180.03,27.44 180.03,26.46 180.13,26.36 180.56,26.36 180.66,26.26 180.66,26.06 180.56,25.96 180.13,25.96 180.03,25.86 180.03,25.65 180.13,25.55 180.56,25.55 180.66,25.45 180.66,25.25 180.56,25.14 180.13,25.14 180.03,25.04 180.03,24.84 180.13,24.74 180.56,24.74 180.64,24.66 180.64,23.86 v1(180.66,23.84)
SD_D1: length 24.7
  TOP w0.102: UR1.10 179.87,23.69 v1(180.05,23.87)
  BOTTOM w0.102: JREAD.19 172.48,27 172.6,26.87 172.87,26.87 172.99,27 172.99,27.67 173.09,27.77 173.3,27.77 173.4,27.67 173.4,27 173.53,26.87 173.68,26.87 173.8,27 173.8,27.67 173.91,27.77 174.11,27.77 174.21,27.67 174.21,25.82 174.34,25.69 174.56,25.69 174.69,25.82 174.69,26.74 174.82,26.87 175.06,26.87 175.19,26.74 175.19,25.82 175.31,25.69 175.57,25.69 175.7,25.82 175.7,26.74 175.82,26.87 176.1,26.87 176.23,26.74 176.23,25.82 176.36,25.69 178.86,25.69 178.99,25.82 178.99,27.21 179.12,27.34 179.68,27.34 179.8,27.21 179.8,24.12 v1(180.05,23.87)
SD_D2: length 26.1
  TOP w0.102: UR1.21 174.53,23.69 173.73,24.49 173.73,27.71 176.57,30.55 v2(176.85,30.55) 178.27,30.55 v1(178.94,31.22)
  BOTTOM w0.102: JREAD.1 191.48,31.39 190.88,31.98 179.7,31.98 v1(178.94,31.22)
SERIRQ: length 138.2
  TOP w0.102: UE1.3 183.99,36.9 184.13,37.04 184.13,41.74 184.95,42.56 188.25,42.56 189.35,43.66 193.03,43.66 v1(193.22,43.85)
  IN1 w0.127: v1(146.43,116.38) 148.16,114.65 148.16,113.54 149.36,112.34 149.92,112.34 153.9,108.36 153.9,105.57 154.97,104.49 154.97,102.67 169.58,88.05 173.96,88.05 178.99,83.02 183.01,83.02 190.06,75.97 190.06,65.94 191.13,64.86 191.13,57.83 192.62,56.33 192.62,55.31 193.8,54.13 193.8,53.96 194.06,53.7 194.06,50.61 193.86,50.41 193.86,44.46 193.24,43.85 v1(193.22,43.85)
  IN3 w0.084: 137.63,117.12 134.24,117.12 133.69,117.68 130.77,117.68 130.19,117.1 129.28,117.1 v1(128.65,116.48)
  IN3 w0.127: 137.63,117.12 139.28,117.12 139.67,116.73 141.31,116.73 142.2,115.84 143.92,115.84 144.33,116.25 146.29,116.25 v1(146.43,116.38)
  BOTTOM w0.076: UC1.T4 128.33,116.81 v1(128.65,116.48)
  BOTTOM w0.102: RC102.2 145.62,119.66 v2(145.82,119.45) 146.43,118.85 v1(146.43,116.38)
SIO_EXT_SCI#: length 5
  TOP w0.089: v1(127.28,118.69) 127.28,118.82 127.92,119.45 RC98.1 128.54,120.31 128.16,120.69 128.16,121.43 127.91,121.67 v2(127.91,121.94)
  BOTTOM w0.089: UC1.N5 127.64,118.33 v1(127.28,118.69)
SIO_SLP_S0#: length 104.5
  TOP w0.102: UE1.89 185.99,52.5 185.32,53.16 185.32,54.94 183.86,56.4 181.32,56.4 177.04,60.68 177.04,71.25 175.85,72.44 175.85,84.54 v2(169.57,90.82) 169.57,94.73 170.08,95.24 v1(170.08,95.52)
  IN3 w0.084: v1(133.38,112.02) 133.38,108.79 133.82,108.34 135.66,108.34 136.24,107.77 137.82,107.77
  IN3 w0.127: 137.82,107.77 138.2,107.77 138.65,108.21 149.44,108.21 149.63,108.41 152.49,108.41 154.9,106 159.15,106 164.29,100.86 164.29,99.9 168.51,95.68 169.92,95.68 v1(170.08,95.52)
  BOTTOM w0.076: v1(133.38,112.02) 133.28,112.12 133.28,112.12 132.95,112.46 132.54,112.46 132.12,112.04 130.62,112.04 130.47,111.89 130.16,111.89 129.99,111.72 129.99,111.54 129.75,111.3 129.23,111.3 UC1.AF3
SIO_SLP_S3#: length 126.1
  TOP w0.102: UE1.6 185.19,34.36 184.67,33.84 CE27.1 184.56,33.91 184.56,34.32 v1(184.69,34.45)
  IN1 w0.084: 137.92,104.89 137.81,104.77 135.83,104.77 134.19,106.41 129.1,106.41 v1(128.66,105.98)
  IN1 w0.127: 137.92,104.89 139.89,106.85 142.54,106.85 144.4,104.99 144.4,99.04 148.48,94.96 151.67,94.96 156.61,90.03 160.61,90.03 166.6,84.05 168.75,84.05 169.64,83.16 174.18,83.16 177.62,79.72 179.44,79.72 186.28,72.88 186.28,64.65 187.54,63.38 187.54,55.36 187,54.82 187,49.4 187.42,48.98 187.55,48.98 188.1,48.44 188.1,45.12 188.1,45.12 188.1,40.63 187.83,40.36 187.83,34.99 v1(188.52,34.3)
  IN3 w0.127: v1(184.69,34.45) 184.69,34.43 185.89,33.22 187.44,33.22 v1(188.52,34.3)
  BOTTOM w0.089: v1(128.66,105.98) 128.33,105.64 UC1.AT4
  BOTTOM w0.102: v1(188.52,34.3) 189.24,34.3 v2(189.29,34.24)
SIO_SLP_S4#: length 103.3
  TOP w0.089: T104.1 127.74,110.63 v1(127.27,110.16)
  TOP w0.102: UE1.84 187.99,52.15 187.79,52.34 187.79,52.7 v1(188.2,53.11)
  IN1 w0.084: v1(127.27,110.16) 127.57,109.87 127.61,109.87 127.68,109.8 129.62,109.8 129.82,109.6 134.43,109.6 135.18,108.85 136.86,108.85 136.97,108.96 137.89,108.96 137.92,108.93
  IN1 w0.127: v1(188.2,53.11) 188.32,53.11 188.79,53.58 188.79,56.57 188.56,56.8 188.56,63.81 187.4,64.96 187.4,73.57 184.33,76.65 184.33,77.16 180.49,80.99 178.15,80.99 174.47,84.67 172.42,84.67 171.78,85.32 167.12,85.32 160.73,91.71 160.73,94.18 153.19,101.72 153.19,101.87 148.76,106.3 148.76,107.81 147.2,109.37 144.32,109.37 144.23,109.27 141.91,109.27 141.74,109.11 138.51,109.11 138.33,108.93 137.92,108.93
  BOTTOM w0.089: v1(127.27,110.16) 126.99,109.88 UC1.AJ6
SIO_SLP_S5#: length 132.6
  TOP w0.089: v1(127.83,106.46) 128.24,106.06 128.24,105.67 131.47,102.44 132.49,102.44 133.48,101.44 133.49,101.44
  TOP w0.102: v1(188.79,38.24) 188.39,37.83 UE1.14 188.39,34.82 188.12,34.55 188.12,34.08 188.31,33.89 CE28.1 ; T103.1 136.3,98.63 133.49,101.44
  IN1 w0.084: 137.72,105.04 135.86,105.04 134.31,106.58 127.95,106.58 v1(127.83,106.46)
  IN1 w0.127: 137.72,105.04 139.78,107.1 142.64,107.1 144.66,105.09 144.66,99.15 148.59,95.21 151.83,95.21 156.68,90.36 160.64,90.36 166.7,84.3 168.86,84.3 169.75,83.41 174.29,83.41 177.73,79.97 179.55,79.97 186.53,72.98 186.53,64.75 187.8,63.49 187.8,55.26 187.25,54.71 187.25,52.16 189.75,49.66 189.75,39.2 v1(188.79,38.24)
  BOTTOM w0.076: v1(127.83,106.46) 127.46,106.83 UC1.AP5
SKIP#: length 1.8
  BOTTOM w0.203: PR535.1 85.74,138.42 PU501.7
SKIP#1: length 46.3
  TOP w0.102: v1(111.9,139.15) 111.9,139.55 v2(111.75,139.7)
  IN1 w0.254: v1(111.9,139.15) 114.77,139.15 115.03,139.41 115.03,144.44 113.79,145.68 88.71,145.68 85.53,142.5 85.53,139.86 84.29,138.63 v1(83.91,138.63)
  BOTTOM w0.203: PU502.1 v1(111.9,139.15)
  BOTTOM w0.254: PR535.2 84.42,138.12 v1(83.91,138.63)
SLATE_MODE_R: length 20.7
  IN3 w0.084: v1(128.63,108.97) 128.63,109.22 131.81,112.4 134.21,112.4 135.6,111.01 137.82,111.01
  IN3 w0.127: 137.82,111.01 138.84,111.01 139.72,110.13 142.61,110.13 v1(143.04,109.69)
  BOTTOM w0.076: v1(128.63,108.97) 128.33,108.67 UC1.AL4
  BOTTOM w0.102: v1(143.04,109.69) v2(143.47,110.12) 143.76,110.42 143.76,110.57 144.49,111.3 144.49,111.32 144.58,111.41 144.58,111.51 RC110.1
SLEWA_CPU: length 4.3
  TOP w0.102: v2(92.35,140.1) 92.09,139.85 PR513.2
  TOP w0.254: v1(90.77,140.66) 91.15,140.28 PR513.2
  BOTTOM w0.203: v1(90.77,140.66) 90.77,140.5 90.22,139.95 PU501.15
  BOTTOM w0.254: PR514.1 v1(90.77,140.66)
SM_RCOMP0: length 9.6
  TOP w0.305: v1(93.5,105.39) v2(89.85,101.74) 89.32,101.21 RC68.1
  BOTTOM w0.229: v1(93.5,105.39) 93.71,105.18 UC1.AU60
SM_RCOMP1: length 7.7
  TOP w0.305: RC69.1 90.21,101.02 v2(92.23,103.05) v1(93.24,104.05)
  BOTTOM w0.229: UC1.AV60 93.42,104.23 v1(93.24,104.05)
SM_RCOMP2: length 9.5
  TOP w0.305: v1(92.53,105.35) 92.5,105.35 88.36,101.22 v2(88.36,99.84) 88.36,98.22 RC70.1
  BOTTOM w0.229: UC1.AU61 92.72,105.16 v1(92.53,105.35)
SML0CLK: length 9.2
  BOTTOM w0.076: UC1.AN1 130.49,107.1 130.71,106.88 131.47,106.88
  BOTTOM w0.089: 137.92,109.24 137.64,109.24 136.61,108.21 136.11,108.21 v2(134.78,106.88) 131.47,106.88
  BOTTOM w0.102: RP49.1 137.92,109.24
SML0DATA: length 9.1
  BOTTOM w0.076: UC1.AK1 130.69,108.94 131.97,108.94 132.38,108.53 133.2,108.53
  BOTTOM w0.089: 133.2,108.53 133.89,108.53 134.01,108.41 v2(135.13,108.41) 136.54,108.41 137.87,109.74 137.92,109.74
  BOTTOM w0.102: RP49.2 137.92,109.74
SML1_SMBCLK: length 36
  IN3 w0.084: 137.82,112.68 v1(137.51,112.68) 137.03,113.16 133.2,113.16 132.5,113.86 131.51,113.86 129.82,112.17 129.82,111.99 129.35,111.52 128.81,111.52 127.88,110.59 126.46,110.59 126.33,110.46 126.33,109.79 126.19,109.65 126.19,108.54 126.33,108.4 126.33,105.81 126.78,105.35 v1(127.88,105.35)
  IN3 w0.127: 137.82,112.68 141.41,112.68 143.23,114.5 144.21,114.5 144.48,114.78 145.83,114.78 145.83,114.77 147.94,114.77 148.53,115.37 v1(149.25,115.37)
  BOTTOM w0.089: UC1.AU3 128.87,104.91 128.52,105.27 127.96,105.27 v1(127.88,105.35)
  BOTTOM w0.102: RP40.3 137.86,113.04 v1(137.51,112.68) ; QH1.1 149.06,115.18 v1(149.25,115.37)
SML1_SMBDATA: length 24.3
  IN3 w0.127: v1(143.98,113.74) 144.09,113.74 144.12,113.72 144.3,113.72 144.74,114.16 v1(145.49,114.16)
  BOTTOM w0.076: UC1.AH3 129.23,109.81 129.75,109.81 129.99,110.04 129.99,110.22 130.16,110.39 130.4,110.39 130.53,110.26 134.23,110.26 134.72,109.77 134.72,109.32 135.02,109.02 136.47,109.02 136.68,109.24 136.68,110.44
  BOTTOM w0.102: QH1.4 145.95,113.88 145.67,114.16 v1(145.49,114.16) ; 138.01,113.54 138.01,114.15 138.14,114.28 140.08,114.28 140.96,113.4 143.64,113.4 v1(143.98,113.74) ; 138.01,113.54 RP40.4 ; 138.01,113.54 137.81,113.54 136.68,112.41 v2(136.68,111.43) 136.68,110.44
SNB_1.05V: length 1.4
  BOTTOM w0.102: PC301.1 138.06,150.5 v2(137.92,150.64)
SNB_VDDCI: length 2.9
  BOTTOM w0.102: PR1207.2 184.23,174.9 v2(184.64,174.9)
SNUB_PCIE: length 1.3
  TOP w0.102: PC1304.1 198.11,65.03 v2(198.36,65.28)
SPK_L1-_CONN: length 5.4
  TOP w0.508: LA5.2 64.68,23.9 CA30.1 65.52,23.88 v4(66.84,23.88) JSPK.3
SPK_L2+_CONN: length 6.2
  TOP w0.508: LA6.2 64.62,24.76 CA29.1 66.3,24.76 67.42,25.89 v4(67.73,25.89) 68.76,25.89 JSPK.4
SPK_R1-_CONN: length 5.6
  TOP w0.508: v4(68.21,20.55) 68.21,20.57 ; 68.21,20.57 68.62,20.97 68.62,21.47 69.03,21.88 JSPK.1 ; 68.21,20.57 67.97,20.32 67.42,20.32 66.89,20.85 CA32.1 65.57,20.85 LA3.2
SPK_R2+_CONN: length 4.9
  TOP w0.508: JSPK.2 68.35,22.88 v4(67.96,22.49) 67.18,21.71 CA31.1 65.64,21.71 LA4.2
SRTCRST#: length 158.8
  TOP w0.089: v1(126.53,103.93) v2(127.38,103.93) 127.6,103.93 130.56,100.97 130.56,98.02 130.7,97.89 130.7,96.67 131.28,96.09 131.28,95.8
  TOP w0.102: 131.28,95.8 RC5.2 130.48,95.65 CC3.2 130.41,93.34 131.33,92.42 140.14,92.42 141,93.28 152.09,93.28 154.88,90.49 162.97,90.49 163.59,91.11 164.33,91.11 166.21,89.23 166.21,85.32 172.88,78.65 172.88,71.21 173.04,71.04 173.04,66.23 174.09,65.17 174.09,58.89 173.59,58.38 173.59,57.81 173.98,57.41 v1(174.08,57.41)
  BOTTOM w0.076: UC1.AV6 126.83,104.23 v1(126.53,103.93)
  BOTTOM w0.102: v1(174.08,57.41) 173.99,57.5 166.44,57.5 161.61,52.66 131.7,52.66 127.12,48.09 116.75,48.09 114.98,46.31 ME1.2
SUS_STAT#/LPCPD#: length 25.4
  IN3 w0.084: 137.82,112.29 135.4,112.29 134.77,112.92 131.28,112.92 129.44,111.08 129.16,111.08 128.58,110.5 v1(128.58,110.47)
  IN3 w0.127: v1(149.25,110.63) 148.81,111.07 143.92,111.07 142.7,112.29 137.82,112.29
  BOTTOM w0.076: UC1.AG4 128.33,110.73 128.58,110.47 v1(128.58,110.47)
  BOTTOM w0.102: v1(149.25,110.63) 149.61,110.63 v2(149.76,110.78) 149.76,111.61 149.65,111.72 RC29.2
SUSACK#: length 143.9
  TOP w0.102: RC35.2 136.1,94.37 v2(146.08,94.37) 152.36,94.37 155.13,91.6 156.91,91.6 157.17,91.87 162.55,91.87 162.72,91.7 v1(162.72,91.69) ; UE1.97 182.31,49.71 182.72,50.11 v1(182.72,50.62)
  IN1 w0.127: v1(149.95,108.98) 150.68,108.25 150.68,106.18 151.84,105.01 152.65,105.01 153.7,103.97 153.7,101.93 163.1,92.53 163.1,92.09 162.72,91.7 v1(162.72,91.69) 162.73,91.69 163.1,91.32 163.1,90.06 167.33,85.82 171.99,85.82 172.63,85.18 174.68,85.18 178.36,81.5 182.38,81.5 188.54,75.34 188.54,65.31 189.58,64.26 189.58,57.23 190.48,56.32 190.48,54.53 191.21,53.8 191.21,50.53 191.65,50.09 191.65,49.76 v1(191.23,49.34)
  IN3 w0.084: 137.92,108.16 136.35,108.16 135.73,108.78 v1(134.47,108.78)
  IN3 w0.127: 137.92,108.16 138.01,108.16 138.32,108.47 146.28,108.47 146.79,108.98 v1(149.95,108.98) ; v1(182.72,50.62) 182.89,50.79 188.12,50.79 189.58,49.34 v1(191.23,49.34)
  BOTTOM w0.089: RC37.1 133.63,109.17 134.02,108.78 v1(134.47,108.78)
  BOTTOM w0.102: RC28.2 v1(149.95,108.98)
SUSACK#_R: length 3.2
  BOTTOM w0.076: 131.78,109.25 131.28,109.25 130.9,109.64 130.16,109.64 129.86,109.35 UC1.AK2
  BOTTOM w0.089: 131.78,109.25 132.44,109.25 RC37.2
SUSCLK: length 1.2
  TOP w0.089: v1(127.3,112.04) 126.95,111.7 T102.1
  BOTTOM w0.076: UC1.AE6 126.99,111.74 v1(127.3,112.04)
SUSP: length 226.2
  TOP w0.102: v1(89.44,24.71) 87.75,23.02 Q8.1 86.43,23.81 R10.2 ; Q2308.2 148.59,120.2 v1(148.42,120.04) ; v1(186.88,63.43) 186.42,62.97 v4(186.42,62.78) 185.88,62.24 185.88,61.87 185.39,61.38 185.39,57.54 184.47,56.63 182.59,56.63 182.01,57.21 Q2307.2
  IN2 w0.127: v1(188.4,39.44) 188.55,39.59 188.55,44.66 187.16,46.05 187.16,54.32 188.05,55.21 188.05,62.26 v1(186.88,63.43) 187.28,63.83 187.28,75.5 182.95,79.83 182.54,79.83 162.36,100.01 162.36,100.86 161.74,101.48 158.31,101.48 153.67,106.13 153.67,108.69 153.55,108.81 153.55,109.49 154.17,110.11 154.17,110.44 152.09,112.52 152.09,114.75 148.42,118.42 v1(148.42,120.04)
  IN3 w0.127: v1(89.44,24.71) 89.44,27.57 100.8,38.94 171.58,38.94 172.19,39.55 173.65,39.55 174.33,38.86 182.71,38.86 183.29,39.44 v1(188.4,39.44)
SUSP#: length 259.3
  TOP w0.102: UE1.116 180.24,42.11 v1(180.23,42.1) ; v1(96.75,24.98) 96.8,25.03 R2313.1 ; R16.1 v1(87.84,19.82) 86.83,19.82 86.25,20.41 Q8.2 ; R2318.1 v1(93.44,25.04) ; v1(114.35,25.94) v4(114.35,25.3)
  IN1 w0.127: v1(87.84,19.82) 93.06,25.04 v1(93.44,25.04) 96.69,25.04 v1(96.75,24.98) ; v1(184.93,71.65) 184.93,70.01 184.24,69.33 184.24,66.59 185.01,65.83 185.01,64.24 186.83,62.42 186.83,58.63 186.61,58.42 186.09,58.42 185.84,58.17 185.84,57.82 186.36,57.3 186.36,54.32 186.49,54.2 186.49,49.19 186.96,48.73 186.96,48.18 187.74,47.4 187.74,43.18 v1(187.62,43.06)
  IN1 w0.254: v1(114.35,42.11) v1(114.35,25.94)
  IN3 w0.127: v1(114.35,42.11) 114.68,42.44 176.27,42.44 176.91,41.79 178.91,41.79 178.97,41.86 179.99,41.86 v1(180.23,42.1) 180.47,41.86 184.82,41.86 185.46,42.49 187.06,42.49 187.62,43.05 v1(187.62,43.06) ; v1(149.57,133.07) 149.57,131.76 153.97,127.35 156.85,127.35 159.74,124.46 159.74,117.78 156.88,114.93 156.88,113.53 159.03,111.39 159.41,111.39 161.2,109.59 161.2,107.24 162.25,106.19 163.46,106.19 166.47,103.18 166.47,99.95 169.44,96.98 173.03,96.98 176.51,93.49 176.51,92.96 181.92,87.56 181.92,82.62 187.15,77.39 187.15,73.87 v1(184.93,71.65)
  IN3 w0.254: v1(96.75,24.98) 105.64,24.98 106.6,25.94 v1(114.35,25.94)
  BOTTOM w0.254: PR401.2 v1(114.35,25.94) ; PR300.2 149.08,147.47 148.1,146.49 148.1,137.62 149.57,136.15 v1(149.57,133.07)
SW_1.35V: length 7
  TOP w1.016: 155.99,22.69 155.8,22.5 155.8,18.05 154.21,16.46
  vias: v2(156.77,23) v3(153.83,15.45) v3(154.47,15.45) v3(156.5,23.52) v3(157.13,23.52)
SW_+1.2VSP: length 2.7
  IN1 w0.762: 182.97,171.4 182.21,170.64 180.62,170.64
  vias: v1(179.29,171.08) v1(179.29,170.5) v1(183.91,172.22) v1(184.5,172.22) v2(175.43,169.71) v3(176.05,168.67) v3(176.05,168.03) v3(176.69,168.67) v3(176.69,168.03) v3(177.32,168.67) v3(177.32,168.03) v3(177.96,168.67) v3(177.96,168.03) v3(178.59,168.67) v3(178.59,168.03)
SW_CPU2: length 2
  TOP w0.102: v2(106.9,141.76) 107.22,142.07 PC520.1
  TOP w0.508: v1(106.44,142.81) PC520.1
SW_VGA_CORE: length 35.5
  TOP w0.508: PC815.1 208.56,62.94 v3(209.32,63.7)
  IN1 w1.016: 205.64,67.51 205.64,63.4 204.89,62.65
  BOTTOM w0.254: PR829.1 198.78,61.36 198.78,61.64 201.2,64.05 201.2,74.1 204.36,77.26 206.54,77.26 207.51,78.24 210.34,78.24 211.17,77.42 PL802.1
  vias: v1(204.31,60.86) v1(204.31,60.27) v2(203.95,76.9) v3(202.34,74.31) v3(202.34,73.54) v3(202.34,72.78) v3(203.1,75.07) v3(203.1,74.31) v3(203.1,73.54) v3(203.1,72.78) v3(203.23,70.18) v3(203.23,69.42) v3(203.23,68.65) v3(203.23,67.89) v3(203.23,67.13) v3(203.86,75.07) v3(203.86,74.31) v3(203.86,73.54) v3(203.86,72.78) v3(203.86,70.18) v3(203.86,69.42) v3(203.86,68.65) v3(203.86,67.89) v3(203.86,67.13) v3(203.99,75.83) v3(204.63,75.83) v3(204.63,75.07) v3(204.63,74.31) v3(204.63,73.54) v3(204.63,72.78) v3(204.63,70.18) v3(204.63,69.42) v3(204.63,68.65) v3(204.63,67.89) v3(204.63,67.13) v3(204.82,76.53) v3(205.55,76.74) v3(205.57,76.11) v3(206.32,76.74) v3(206.33,76.11)
SYS_PWROK: length 321.8
  TOP w0.089: RP50.1 132.81,111.34 133.9,110.25 135.51,110.25 v1(136.3,109.46)
  TOP w0.102: v1(173.98,49.43) 173.44,49.97 CE32.1 ; v1(188.18,53.73) 188.14,53.73 187.76,53.35 187.76,52.99 187.19,52.42 UE1.86 ; v1(62.21,89.29) 62.19,89.27 CC31.1 60.19,89.27 v2(60.16,89.29) 58.27,89.29 v1(57.36,90.21)
  IN1 w0.084: v1(136.3,109.46) 136.41,109.34 137.65,109.34 137.74,109.44 137.92,109.44
  IN1 w0.127: 137.92,109.44 138.12,109.44 138.3,109.62 141.5,109.62 142.1,110.22 143.5,110.22 143.85,109.88 147.41,109.88 149.27,108.02 149.27,106.51 151.83,103.94 v1(152.24,103.94)
  IN3 w0.127: v1(188.18,53.73) 184.44,53.73 183.55,52.84 179.57,52.84 178.37,51.64 177.3,51.64 175.09,49.43 v1(173.98,49.43) 140.79,49.43 140.33,48.97 116.19,48.97 115.11,50.05 114.82,50.05 v1(114.33,50.54)
  BOTTOM w0.102: v1(152.24,103.94) 152.62,103.56 152.62,97.65 144.9,89.93 125.5,89.93 114.51,78.93 114.51,55.74 115.4,54.84 115.4,51.61 v1(114.33,50.54) 113.7,49.91 40.67,49.91 37.15,53.43 37.15,72.58 40,75.42 48.72,75.42 57.36,84.06 v1(57.36,90.21) ; RC52.1 61.89,89.62 v1(62.21,89.29)
SYS_PWROK_R: length 4.5
  TOP w0.089: v1(131.37,110.85) 131.41,110.89 131.41,111.26 131.33,111.34 RP50.8 130.01,111.34 v4(129.63,110.96)
  BOTTOM w0.076: v1(131.37,110.85) 130.93,111.28 130.61,111.28 130.47,111.14 130.16,111.14 129.86,110.85 UC1.AG2
SYS_PWROK_XDP: length 7.5
  BOTTOM w0.102: v2(63.89,88.32) 63.53,88.68 RC64.1 CC16.1 61.31,89.27 61.31,90.37 61.89,90.95 RC52.2 61.89,91.44 61.7,91.63 JXDP1.47
SYS_RESET#: length 73.3
  TOP w0.102: RC26.2 62.21,104.72 v1(62.39,104.72)
  IN1 w0.084: 87.33,110.81 88.35,110.81 88.72,110.45 93.74,110.45 93.94,110.25 96.23,110.25 97.63,111.64 114.27,111.64 114.57,111.95 116.69,111.95 117.12,111.52 119.39,111.52 119.6,111.3 124.52,111.3 125,111.78 125,113.04 125.57,113.61 128.52,113.61 v1(128.66,113.47)
  IN1 w0.127: 87.33,110.81 82.67,110.81 81.48,109.62 75.67,109.62 74.01,107.96 70.46,107.96 69.82,107.31 65.63,107.31 63.04,104.72 v1(62.39,104.72)
  BOTTOM w0.089: v1(128.66,113.47) 128.98,113.16 UC1.AC3
SYSON: length 50
  TOP w0.102: v1(182.64,53.78) 183.09,53.34 CE26.1 183.61,52.93 183.59,52.91 183.59,52.61 UE1.95 ; v1(164.28,51.27) 163.83,50.82 v2(163.83,35.06) v1(163.83,29.18)
  IN3 w0.127: v1(164.28,51.27) 171.23,51.27 171.64,51.69 176.58,51.69 177.04,52.14 177.55,52.14 179.19,53.78 v1(182.64,53.78)
  BOTTOM w0.254: PR201.1 163.77,25.22 164.22,25.67 164.22,28.78 v1(163.83,29.18)
TDI_IREF: length 5.9
  BOTTOM w0.254: RC133.2 v2(122.27,129.29) 122.27,126.59 122.71,126.15 122.71,125.02 UC1.B12
TDI_XDP: length 20.1
  IN1 w0.127: v1(59.61,101.29) 59.72,101.29 60.46,102.04 63.33,102.04 63.79,102.5 64.25,102.5 65.71,103.96 71.47,103.96 72,103.43 v1(72.81,103.43)
  BOTTOM w0.102: RC45.1 73.63,104.21 RC44.2 73.7,104.14 73.7,103.24 73.57,103.12 v2(73.43,103.12) 73.13,103.12 v1(72.81,103.43) ; JXDP1.56 59.7,101.2 v1(59.61,101.29)
TDI_XDP_R: length 23.3
  TOP w0.089: 88.91,112.48 89.18,112.48 89.64,112.02 RC63.1
  TOP w0.102: v1(77.12,109.1) v2(78.01,110) 81.35,113.33 87.87,113.33 88.72,112.48 88.91,112.48
  BOTTOM w0.102: v1(77.12,109.1) 76.29,109.1 75.47,108.28 75.47,106.06 75.02,105.61 74.11,105.61 RC45.2 73.58,105.12 73.35,104.89 73.35,104.73 73.11,104.49 72.65,104.49 72.59,104.56 UC4.5
TDO_XDP: length 54.1
  IN1 w0.114: v1(62.39,105.35) 62.96,105.35 65.42,107.81 69.61,107.81 70.26,108.46 73.25,108.46 v1(74.93,110.14)
  IN3 w0.127: v1(86.72,121.63) 86.72,120.62 87.04,120.31 87.04,119.17 88.78,117.43 88.78,115.64 87.95,114.82 86.9,114.82 86.67,114.59 86.67,114.19 86.15,113.67 85.1,113.67 83.77,112.34 v1(83.47,112.34)
  BOTTOM w0.102: RP44.4 86.69,122.2 86.86,122.03 86.86,121.77 v1(86.72,121.63) ; UC4.2 73.17,106.06 RC43.2 74.6,107.49 74.6,109.81 v1(74.93,110.14) 74.93,111.05 76.23,112.34 v1(83.47,112.34) 83.71,112.1 RC62.1 ; v1(62.39,105.35) 61.07,105.35 v2(60.55,104.83) 60.16,104.44 60.16,101.88 60.53,101.51 60.53,100.48 60.7,100.31 JXDP1.52
TESTEN: length 2.3
  TOP w0.102: v1(171.96,116.24) v2(171.54,115.83) RV133.2
  BOTTOM w0.102: UV1.AD28 172.46,115.74 v1(171.96,116.24)
THERM_CPU: length 29.9
  TOP w0.102: v2(110.34,144.93) 110.48,144.79 v1(111.08,144.79)
  TOP w0.254: PR512.2 PC509.1 90.26,140.22 v1(89.88,140.6)
  IN3 w0.127: v1(111.08,144.79) 111.28,144.99 111.28,145.27 110.84,145.7 92.86,145.7 90.96,143.81 90.96,141.68 v1(89.88,140.6)
  BOTTOM w0.203: v1(89.88,140.6) 89.82,140.54 PU501.14
  BOTTOM w0.254: PH502.2 111.08,144.22 v1(111.08,144.79)
TL_BKOFF#: length 8.2
  BOTTOM w0.102: DX1.2 217.55,161.63 v4(216.93,161.63) 214.85,161.63 RX50.2 213.96,162.52 UX2.4
TL_BKOFF#_R: length 26.4
  TOP w0.102: UX4.44 203.72,174.32 203.61,174.43 203.61,176.1 204.15,176.64 204.15,176.84 RX33.1 205.25,177.94 206,177.94 v2(206.68,177.25) 207.47,177.25 v1(208.88,175.84)
  IN3 w0.127: v1(211.17,161.87) 211.17,164.25 207.64,167.78 207.64,174.6 v1(208.88,175.84)
  BOTTOM w0.102: v1(211.17,161.87) UX2.2
TL_ENVDD: length 17.9
  TOP w0.102: v1(217.28,165.29) 216.88,165.68 RX7.2 ; v1(205.64,165.94) 205.33,165.94 204.97,166.29 204.97,166.63 204.92,166.69 UX4.20
  IN1 w0.127: v1(217.28,165.29) 216.87,165.69 210.89,165.69 210.04,166.55 206.75,166.55 206.14,165.94 v1(205.64,165.94)
  BOTTOM w0.102: v1(217.28,165.29) 216.68,165.29 v2(216.6,165.21) ; v1(205.64,165.94) 206.73,165.94 RX51.2
TL_INVT_PWM: length 26.3
  TOP w0.102: UX4.19 204.52,166.35 v1(204.57,166.31)
  IN1 w0.127: v1(204.57,166.31) 205.15,166.89 210.15,166.89 211.04,166 215.99,166 218.72,168.73 v1(218.85,168.73)
  BOTTOM w0.102: RX49.2 205.13,164.84 204.4,164.84 RX26.1 203.99,165.73 v1(204.57,166.31) ; JLVDS.36 221.95,172.93 220.74,171.72 220.74,171.55 220.28,170.39 220.28,170.36 219.62,169.7 219.61,169.7 218.85,168.93 v1(218.85,168.73)
TMDS_L_TX0N: length 16.8
  BOTTOM w0.102: LX3.2 14.84,104.3 14.57,104.02 14.43,104.02 CX25.1 13.95,104.15 13.39,104.15 13.38,104.16 12.79,104.16 12.77,104.15 12.51,104.15 12.17,104.49 v3(12.17,106.08) 12.17,107.38 10.82,108.72 9.5,108.72 8.73,107.95 8.73,102.77 8.65,102.69 8.54,102.69 JHDMI.9
TMDS_L_TX0P: length 16.9
  BOTTOM w0.102: LX3.3 14.91,103.5 14.6,103.81 14.47,103.81 CX26.1 13.66,103.93 v3(13.08,103.93) 12.42,103.93 11.95,104.4 11.95,105.8 11.94,105.81 11.94,106.37 11.95,106.39 11.95,107.29 10.73,108.51 9.59,108.51 8.94,107.86 8.94,102.68 8.74,102.47 8.41,102.47 8.09,102.15 JHDMI.7
TMDS_L_TX1N: length 7.1
  BOTTOM w0.102: JHDMI.6 10.03,101.25 10.99,101.25 11.66,100.58 11.66,98.97 11.9,98.73 12.79,98.73 CX27.1 13.41,98.75 13.55,98.75 13.83,99.03 LX4.2
TMDS_L_TX1P: length 7.2
  BOTTOM w0.102: JHDMI.4 10.02,101.04 10.9,101.04 11.45,100.49 11.45,98.88 11.81,98.52 12.79,98.52 CX28.1 13.45,98.54 13.62,98.54 13.93,98.23 LX4.3
TMDS_L_TX2N: length 9.8
  BOTTOM w0.102: JHDMI.3 8.09,100.15 8.41,99.83 8.82,99.83 9.05,99.6 9.05,98.44 11.37,96.11 v3(12.74,96.11) 13.72,96.11 CX29.1 14.34,96.05 14.41,96.05 14.65,96.3 LX5.2
TMDS_L_TX2P: length 9.9
  BOTTOM w0.102: LX5.3 14.72,95.5 14.38,95.83 14.3,95.83 CX30.1 13.63,95.9 13.02,95.9 13,95.88 12.47,95.88 12.46,95.9 11.28,95.9 8.83,98.35 8.83,99.52 8.73,99.62 8.55,99.62 JHDMI.1
TMDS_L_TXCN: length 8.3
  BOTTOM w0.102: JHDMI.12 10,104.28 10.47,104.28 v3(12.32,102.42) 13.41,101.34 13.54,101.34 13.55,101.35 14.11,101.35 14.12,101.34 14.68,101.34 15.01,101.66 CX23.1 15.33,101.34 15.51,101.34 15.8,101.63 LX2.2
TMDS_L_TXCP: length 8.3
  BOTTOM w0.102: JHDMI.10 10.04,104.06 10.38,104.06 11.98,102.47 11.98,102.45 12.35,102.07 12.37,102.07 13.32,101.12 v3(13.82,101.12) 14.69,101.12 CX24.1 15.35,101.13 15.43,101.13 15.73,100.83 LX2.3
TMDS_TX0N: length 4.8
  TOP w0.102: RP59.4 17.08,103.44 17.23,103.3 17.33,103.3 17.43,103.4 17.43,103.63 17.78,103.99 18.04,103.99 v1(18.24,104.19)
  BOTTOM w0.102: LX3.1 17.47,104.3 17.68,104.09 18.14,104.09 v1(18.24,104.19) 18.42,104 18.87,104 CX14.1
TMDS_TX0P: length 4.9
  TOP w0.102: RP59.3 17.08,102.94 17.23,103.08 17.42,103.08 17.65,103.31 17.65,103.54 17.87,103.77 18.07,103.77 v1(18.24,103.6)
  BOTTOM w0.102: CX15.1 18.87,103.79 18.42,103.79 v1(18.24,103.6) 17.97,103.87 17.78,103.87 17.41,103.5 LX3.4
TMDS_TX1N: length 5.1
  TOP w0.102: v1(17.16,98.85) 17.02,98.72 16.93,98.72 16.84,98.72 16.84,98.71 16.7,98.71 v3(16.56,98.57) 15.83,97.84 15.71,97.84 15.57,97.98 RP58.4
  BOTTOM w0.102: CX16.1 17.84,98.67 17.34,98.67 v1(17.16,98.85) 17.04,98.73 16.81,98.73 16.52,99.03 LX4.1
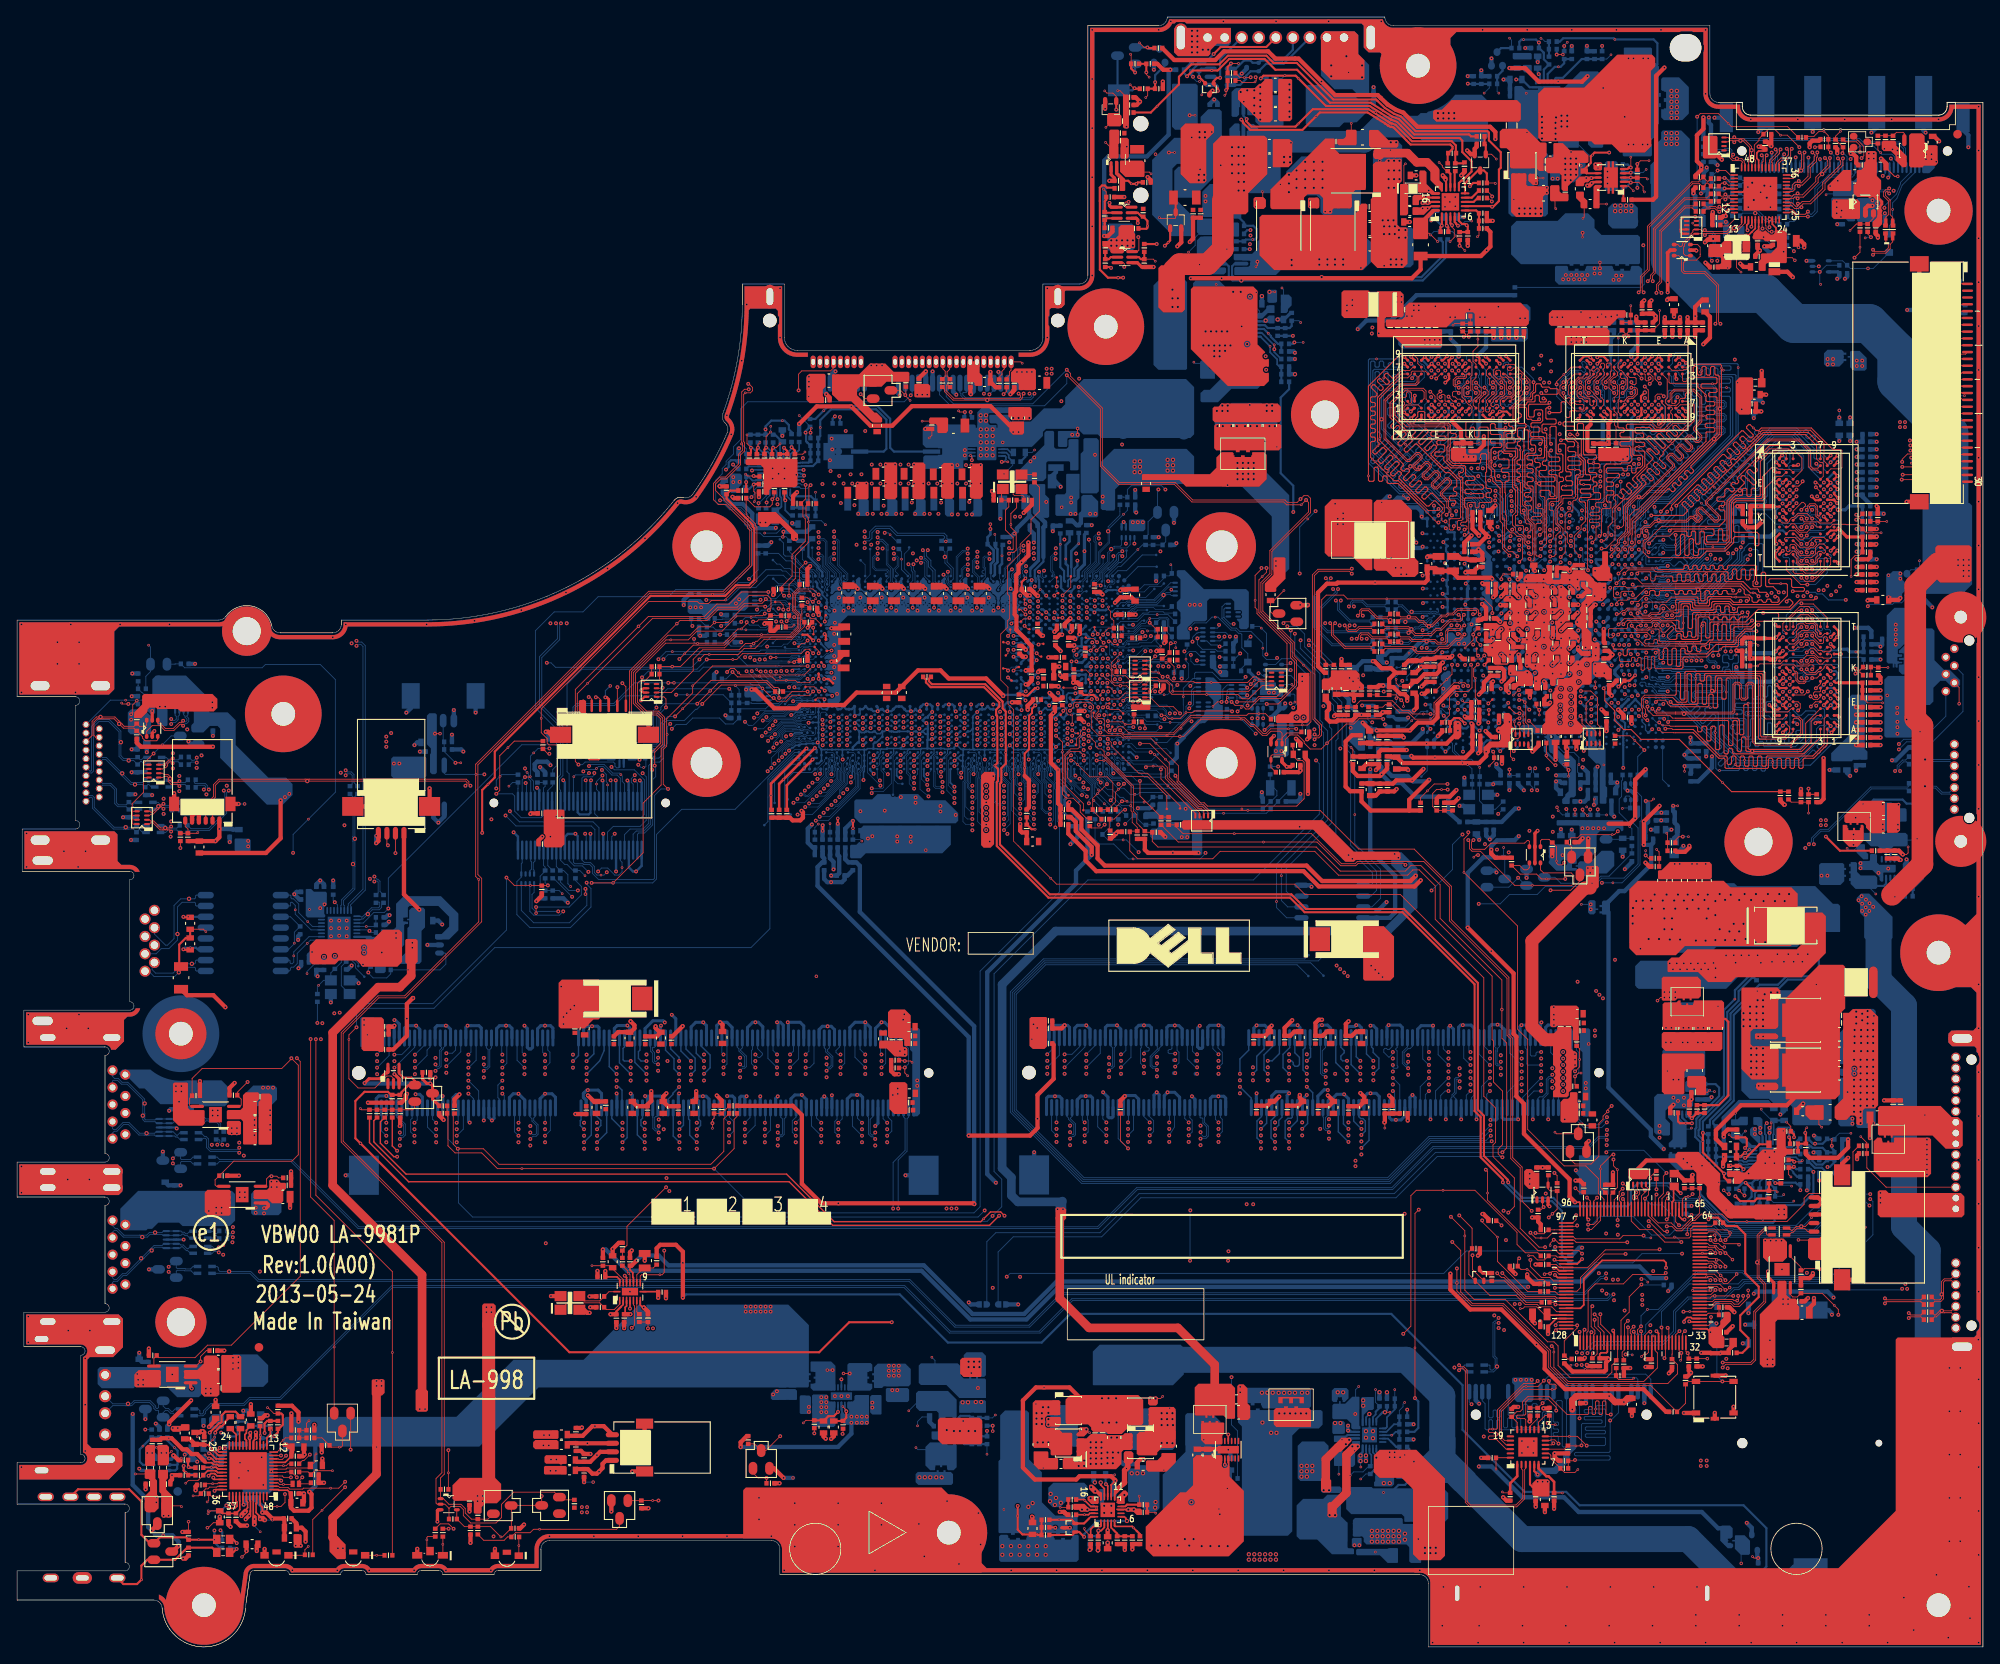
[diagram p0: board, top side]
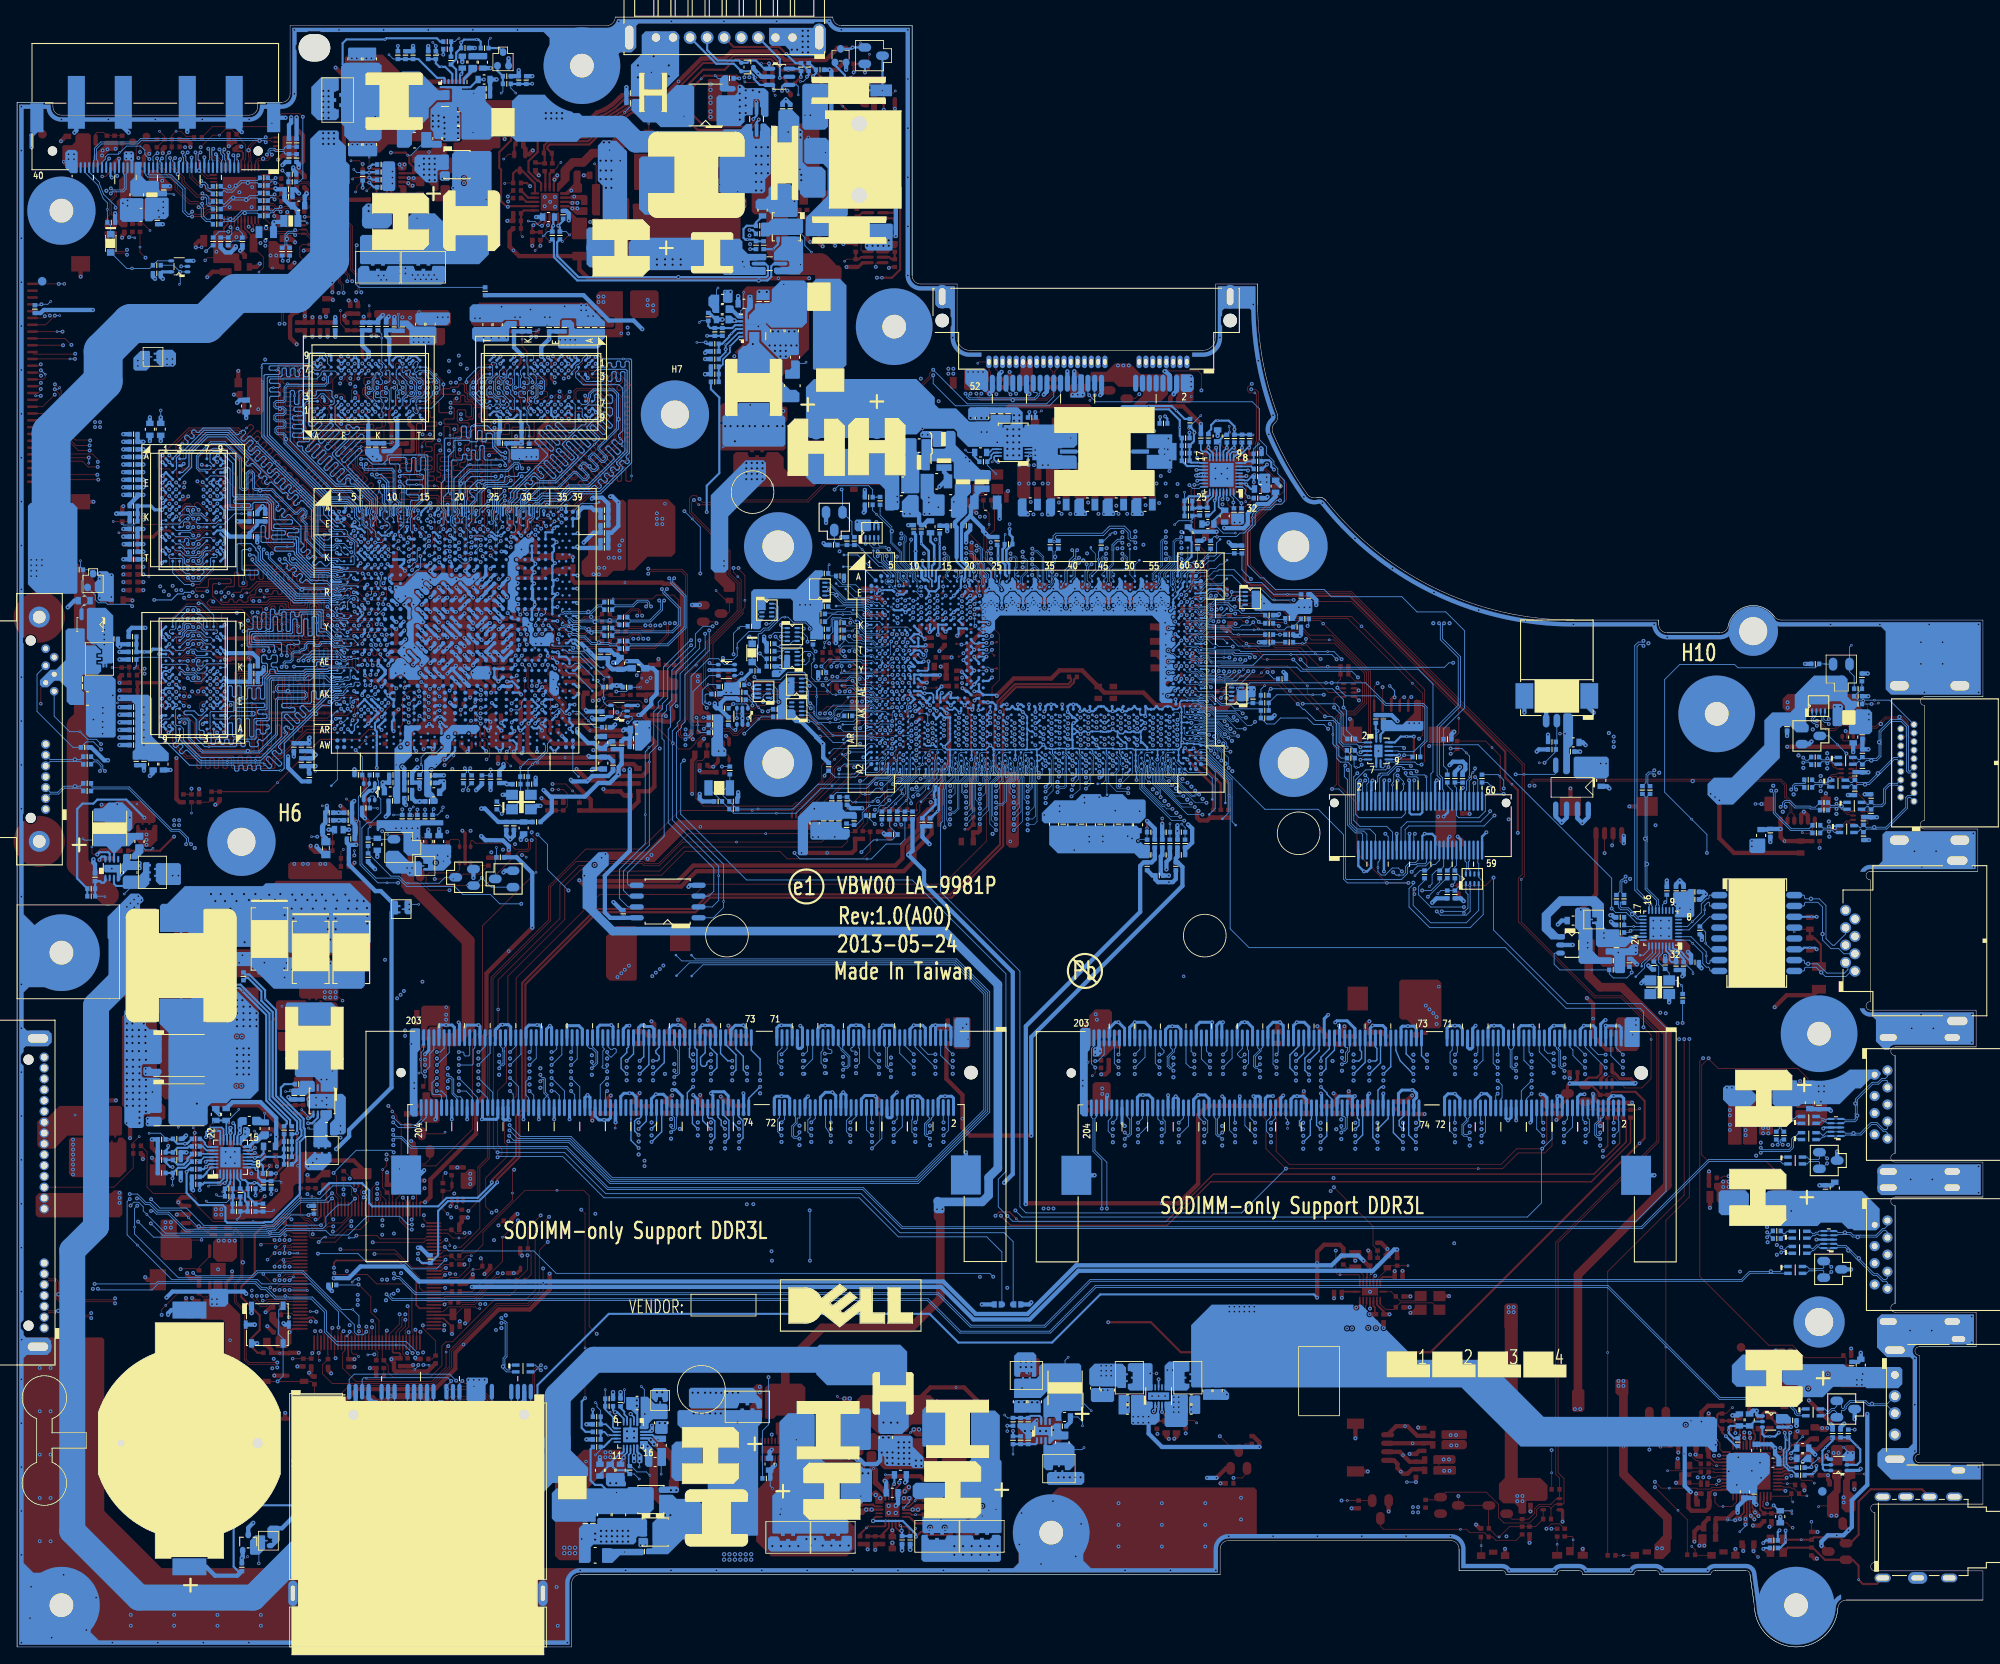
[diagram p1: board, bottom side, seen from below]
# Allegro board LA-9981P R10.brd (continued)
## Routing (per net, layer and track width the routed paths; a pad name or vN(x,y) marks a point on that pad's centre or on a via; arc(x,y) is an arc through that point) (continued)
TMDS_TX1P: length 5.2
  TOP w0.102: RP58.3 15.51,97.48 15.65,97.62 15.91,97.62 16.51,98.22 16.53,98.22 16.81,98.5 16.93,98.5 v1(17.16,98.27)
  BOTTOM w0.102: LX4.4 16.52,98.23 16.81,98.52 16.91,98.52 v1(17.16,98.27) 17.34,98.45 17.84,98.45 CX17.1
TMDS_TX2N: length 6
  TOP w0.102: RP58.2 15.51,96.98 15.65,96.84 16.02,96.84 16.84,96.02 v3(17.36,96.02) 17.89,96.02 v1(18.05,96.19)
  BOTTOM w0.102: LX5.1 17.41,96.3 17.7,96 17.87,96 v1(18.05,96.19) 18.24,96 18.73,96 CX18.1
TMDS_TX2P: length 6
  TOP w0.102: RP58.1 15.51,96.48 15.65,96.62 15.93,96.62 16.75,95.81 17.08,95.81 17.1,95.79 17.63,95.79 17.64,95.81 17.85,95.81 v1(18.05,95.6)
  BOTTOM w0.102: CX19.1 18.73,95.79 18.24,95.79 v1(18.05,95.6) 17.89,95.76 17.68,95.76 17.41,95.5 LX5.4
TMDS_TXCN: length 5.8
  TOP w0.102: v1(19.03,101.52) 18.86,101.36 18.16,101.36 17.94,101.59 v3(17.94,101.78) 17.94,102.04 17.68,102.3 17.23,102.3 17.08,102.44 RP59.2
  BOTTOM w0.102: LX2.1 18.08,101.38 18.89,101.38 v1(19.03,101.52) 19.21,101.34 19.68,101.34 CX12.1
TMDS_TXCP: length 5.9
  TOP w0.102: RP59.1 17.08,101.94 17.23,102.08 17.59,102.08 17.71,101.97 17.71,101.48 18.05,101.14 18.82,101.14 v1(19.03,100.94)
  BOTTOM w0.102: LX2.4 18.17,101.17 18.8,101.17 v1(19.03,100.94) 19.21,101.12 19.68,101.12 CX13.1
TMS_XDP: length 16
  TOP w0.102: v2(60.15,102.04) 60.1,101.99 v1(59.53,101.99)
  IN1 w0.114: v1(67.83,104.56) 65.96,104.56 64.15,102.75 63.69,102.75 63.23,102.28 59.82,102.28 v1(59.53,101.99)
  BOTTOM w0.102: RC46.2 67.05,104.56 v1(67.83,104.56) 68.34,104.06 UC4.9 ; JXDP1.58 59.2,101.66 v1(59.53,101.99)
TON_1.35V: length 3.5
  BOTTOM w0.102: PR208.2 162,23.13 v2(162.62,22.51)
  BOTTOM w0.203: PU200.9 160.67,24.43 161.01,24.09
  BOTTOM w0.254: PR208.2 161.66,23.44 161.01,24.09
TOUCH_PANEL_INTR#: length 18.2
  IN1 w0.084: 137.92,120.34 137.5,120.34 135.69,118.53 v1(132.88,118.53)
  IN1 w0.127: v1(142.59,119.95) 142.2,120.34 137.92,120.34
  BOTTOM w0.076: UC1.P3 129.23,117.3 129.75,117.3 129.99,117.54 129.99,117.71 130.16,117.88 131.26,117.88 131.4,118.03 132.38,118.03 v1(132.88,118.53)
  BOTTOM w0.102: v1(142.59,119.95) 142.19,119.95 141.45,120.69 141.45,120.72 141.44,120.72 141.44,121.68 141.58,121.82 RP43.7
TOUCH_RST: length 220
  TOP w0.102: v1(19.14,93.67) RX1.1 ; UE1.38 v1(195.3,39.31)
  IN3 w0.127: v1(195.3,39.31) 192.86,41.75 187.84,41.75 187.36,42.23 185.57,42.23 184.75,41.41 180.94,41.41 180.59,41.07 177.18,41.07 176.57,41.68 113.36,41.68 112.63,42.41 50.78,42.41 31.65,61.54 31.65,90.37 28.67,93.36 19.46,93.36 v1(19.14,93.67)
  BOTTOM w0.102: v1(195.3,39.31) 196.01,39.31 v2(196.04,39.34)
TOUCH_RST_N_GYRO_INT1: length 6.9
  BOTTOM w0.089: UC1.L1 130.87,119.09 131.78,120 132.21,120 132.38,120.17 132.38,120.27 132.7,120.59 133.74,120.59 133.88,120.72 134.77,120.72 134.99,120.51 134.99,119.68 RC76.2
TOUCH_RST_R: length 3.7
  TOP w0.102: RX24.2 20.03,95.9 19.71,96.22 JTOUCH.6 ; RX24.2 RX1.2 ; RX24.2 21.09,95.4 v2(21.18,95.5)
TOUCHPAD_INTR#: length 2.1
  TOP w0.089: RC74.2 125.48,116.83 v1(125.83,116.83) 126.18,117.18 v2(126.18,117.28)
  BOTTOM w0.089: UC1.U7 126.29,116.37 v1(125.83,116.83)
TP_CLK: length 189
  TOP w0.102: JTP.2 67.35,111.14 67.11,111.38 v1(67,111.38) ; v1(187.1,57.16) 187.1,56.42 v2(187.56,55.96) 187.56,53.87 187.04,53.35 RE9.2 186.79,53.02 UE1.87
  IN3 w0.127: v1(67,111.38) 67,110.58 63.7,107.28 63.7,102.53 64.43,101.8 64.43,98.99 65.13,98.29 65.13,96.72 64.16,95.75 64.16,92.13 63.57,91.54 63.57,87.28 64.85,86 64.85,78.02 69.61,73.26 69.61,57.46 74.99,52.08 104.27,52.08 105.48,53.3 116.71,53.3 117.43,52.58 176.34,52.58 176.66,52.91 177.24,52.91 179,54.66 180.59,54.66 183.08,57.16 v1(187.1,57.16)
TP_DATA: length 190.2
  TOP w0.102: v1(67.83,111.35) 68.09,111.35 68.35,111.09 JTP.3 ; v1(187.1,57.74) 186.93,57.74 185.58,56.38 v2(185.58,56.04) 185.58,53.86 186.15,53.29 RE10.2 186.39,53.04 UE1.88
  IN3 w0.127: v1(67.83,111.35) 67.83,110.82 63.96,106.95 63.96,102.63 64.69,101.89 64.69,99.09 65.39,98.39 65.39,96.62 64.42,95.64 64.42,92.03 63.83,91.44 63.83,87.38 65.11,86.1 65.11,78.12 69.87,73.37 69.87,72.1 71.37,70.59 71.37,56.12 75.16,52.33 104.16,52.33 105.38,53.55 116.82,53.55 117.53,52.84 176.23,52.84 176.55,53.16 177.13,53.16 178.9,54.93 180.48,54.93 183.07,57.51 186.87,57.51 v1(187.1,57.74)
TP_DC_TEST_B2: length 4.5
  BOTTOM w0.102: T167.1 131.37,126.66 UC1.B2
TRIP_+1.2VSP: length 4.4
  TOP w0.102: v2(190.73,170.59) 190.58,170.74 190.58,171.21 190.09,171.7 v1(189.13,171.7)
  TOP w0.254: PU1100.2 189.05,171.79 v1(189.13,171.7)
  BOTTOM w0.254: PR1102.2 188.57,171.14 v1(189.13,171.7)
TRST#_XDP: length 15.7
  IN1 w0.114: v1(67.83,105.4) 67.24,104.8 65.86,104.8 64.05,102.99 63.59,102.99 63.13,102.53 60.01,102.53 v1(59.53,103.01)
  BOTTOM w0.102: v1(59.53,103.01) 59.53,102.78 v2(59.77,102.54) 59.93,102.38 59.93,101.78 60.2,101.52 JXDP1.54 ; v1(67.83,105.4) 67.99,105.56 UC4.12
TS_FDO: length 14.1
  TOP w0.102: v2(174.91,102.33) v1(174.91,102.87)
  IN3 w0.102: 174.91,103.69 174.91,104.68 174.8,104.78 174.8,105.39 174.52,105.68 173.9,105.68 172.62,106.96 172.62,107.52 171.87,108.27 171.87,109.26 169.7,111.43 v1(169.7,111.57)
  IN3 w0.127: v1(174.91,102.87) 174.91,103.69
  BOTTOM w0.102: RV235.2 RV236.1 v1(174.91,102.87) ; v1(169.7,111.57) 169.26,111.14 UV1.AK32
UG_3V: length 12.1
  TOP w0.102: v2(134.26,29.38) 134.01,29.12 v3(133.44,29.12)
  IN1 w0.762: 130.39,18.36 131.38,19.34 132.17,19.34 133,20.17 133,27.98
  vias: v3(129.24,17.44) v3(129.77,17.82) v3(132.81,29.12)
UG_5V: length 11.3
  IN1 w0.762: 121.44,25.44 121.82,25.06 121.82,20.08 124.43,17.47 125.06,17.47
  BOTTOM w0.102: v3(125.82,17.44) 125.82,16.98 v2(126.52,16.28)
  vias: v3(120.87,26.71) v3(120.87,26.08) v3(126.46,17.44)
UG_+1.2VSP: length 7.3
  TOP w0.102: v1(178.02,172.22) v2(178.85,172.22)
  IN1 w0.762: 178.02,170.83 178.02,170.51 178.84,169.68 182.85,169.68 183.54,170.38
  vias: v1(178.02,171.64) v1(184.04,171.33) v1(184.55,171.63)
UG_VGA_CORE:
  vias: v1(203.67,60.72) v1(203.67,60.13) v1(204.05,71.58) v1(204.12,65.78) v1(204.64,71.58) v1(204.7,65.78)
USB3RN1_JUSB2: length 155.7
  IN1 w0.084: 88.91,113.59 88.93,113.59 88.95,113.61 91.33,113.61 92.06,112.88 96.31,112.88 96.68,113.26 114.36,113.26 115.07,113.96 115.07,119.32 116.18,120.43 117.98,120.43 118.35,120.06 118.92,120.06 119.22,120.36 119.22,120.85 119.28,120.91 119.28,121.68 119.09,121.88 118.77,121.88 v1(118.68,121.97)
  IN1 w0.127: v1(23.64,46.26) 23.78,46.4 25.21,46.4 26.89,48.08 26.89,51.2 25.45,52.63 25.45,59.25 24.22,60.48 24.22,68.04 33.71,77.53 33.71,85.51 38.1,89.89 38.1,91.93 56.71,110.54 70.96,110.54 73.32,112.9 75.52,112.9 76.21,113.59 88.91,113.59
  BOTTOM w0.076: v1(118.68,121.97) 119.01,121.64 UC1.G20
  BOTTOM w0.102: v1(23.64,46.26) 23.54,46.37 23.08,46.37 22.87,46.16 LI4.1
USB3RN1_JUSB2_R: length 12.3
  BOTTOM w0.102: LI4.2 20.3,46.16 19.99,46.47 19.84,46.47 19.4,46.91 19.24,46.91 19.09,46.76 DI4.10 DI4.1 17.11,46.76 17.01,46.86 16.15,46.86 15.77,46.49 ; 15.77,46.49 14.91,45.63 14.91,45.6 14.48,45.17 14.45,45.17 12.83,43.55 12.44,43.55 11.76,42.87 11.33,42.87 11.19,42.73 JUSB2.5 ; 15.77,46.49 v3(15.77,46.49)
USB3RN2_JUSB1: length 147.5
  IN1 w0.084: v1(119.66,122.62) 119.8,122.48 120.05,122.48 120.24,122.29 120.24,120.34 118.97,119.07 116.06,119.07 115.7,118.71 115.7,113.48 114.97,112.75 97.06,112.75 96.43,112.12 95.61,112.12 94.97,111.49 94.34,111.49 94.08,111.23 92.57,111.23 91.95,111.86 90.09,111.86 89.15,112.8 88.95,112.8 88.93,112.78 88.91,112.78
  IN1 w0.127: v1(26.04,57.94) 26.17,58.07 26.57,58.07 26.88,58.38 26.88,62.2 25.04,64.04 25.04,67.68 34.64,77.29 34.64,80.14 35.37,80.87 35.37,85.19 36.64,86.47 37.82,86.47 39.8,88.44 39.8,90.98 57.4,108.58 64.09,108.58 65.26,109.76 71.3,109.76 72.98,111.44 74.31,111.44 74.61,111.74 76.5,111.74 77.53,112.78 88.91,112.78
  BOTTOM w0.076: UC1.E18 119.99,122.94 v1(119.66,122.62)
  BOTTOM w0.102: LI1.1 21.66,59.49 21.81,59.64 22.06,59.64 22.2,59.5 22.2,58.54 22.66,58.09 25.89,58.09 v1(26.04,57.94)
USB3RN2_JUSB1_R: length 10.2
  BOTTOM w0.102: JUSB1.5 11.19,60.26 11.4,60.46 11.7,60.46 12.5,61.26 13.05,61.26 14.29,60.02 14.9,60.02 14.91,60.01 15.44,60.01 15.46,60.02 16.11,60.02 16.22,59.91 DI1.1 DI1.10 18.48,59.91 18.61,59.78 18.81,59.78 19.1,59.49 LI1.2
USB3RP1_JUSB2: length 155.3
  IN1 w0.084: 88.91,113.86 88.94,113.86 88.96,113.84 91.42,113.84 92.15,113.11 96.21,113.11 96.59,113.49 114.27,113.49 114.84,114.06 114.84,119.42 116.08,120.66 118.08,120.66 118.45,120.29 118.82,120.29 119.03,120.5 119.03,120.94 119.08,121 119.08,121.56 118.99,121.65 118.87,121.65 118.71,121.48 v1(118.71,121.32)
  IN1 w0.127: v1(23.64,46.85) 23.81,46.68 25.1,46.68 26.62,48.19 26.62,51.08 25.18,52.52 25.18,59.13 23.95,60.37 23.95,68.15 33.44,77.64 33.44,85.62 37.82,90.01 37.82,92.04 56.59,110.81 70.84,110.81 73.2,113.17 75.4,113.17 76.1,113.86 88.91,113.86
  BOTTOM w0.076: v1(118.71,121.32) 118.87,121.32 119.1,121.09 UC1.H20
  BOTTOM w0.102: LI4.4 22.87,46.96 23.24,46.58 23.37,46.58 v1(23.64,46.85)
USB3RP1_JUSB2_R: length 12.4
  BOTTOM w0.102: JUSB2.6 11.19,43.27 11.37,43.09 11.67,43.09 12.35,43.76 12.74,43.76 v3(14.54,45.56) 15.39,46.41 15.39,46.44 15.8,46.84 15.82,46.84 16.06,47.08 17,47.08 17.18,47.26 DI4.2 DI4.9 19.04,47.26 19.18,47.13 19.49,47.13 19.93,46.68 20.03,46.68 20.3,46.96 LI4.3
USB3RP2_JUSB1: length 147
  IN1 w0.084: 88.91,113.05 89.22,113.05 90.18,112.09 92.04,112.09 92.67,111.46 93.99,111.46 94.24,111.71 94.88,111.71 95.51,112.35 96.34,112.35 96.97,112.98 114.87,112.98 115.47,113.57 115.47,118.81 115.97,119.3 118.87,119.3 120.04,120.47 120.04,122.16 119.95,122.25 119.83,122.25 119.66,122.08 v1(119.66,121.97)
  IN1 w0.127: 88.91,113.05 77.42,113.05 76.38,112.01 74.5,112.01 74.19,111.71 72.86,111.71 71.18,110.03 65.15,110.03 63.97,108.85 57.29,108.85 39.53,91.09 39.53,88.55 37.71,86.74 36.53,86.74 35.09,85.31 35.09,80.99 34.36,80.26 34.36,77.4 24.76,67.8 24.76,63.93 26.61,62.08 26.61,58.49 26.46,58.34 26.22,58.34 v1(26.04,58.53)
  BOTTOM w0.076: UC1.F18 119.98,122.29 v1(119.66,121.97)
  BOTTOM w0.102: LI1.4 21.54,60.29 21.97,59.85 22.15,59.85 22.42,59.59 22.42,58.63 22.75,58.3 25.82,58.3 v1(26.04,58.53)
USB3RP2_JUSB1_R: length 10.4
  BOTTOM w0.102: LI1.3 19.1,60.29 18.81,60 18.7,60 18.29,60.41 DI1.9 DI1.2 16.29,60.41 16.12,60.23 v3(15.18,60.23) 14.38,60.23 13.14,61.48 12.41,61.48 11.61,60.68 11.29,60.68 11.19,60.78 JUSB1.6
USB3TN1_JUSB2: length 156.1
  IN1 w0.084: v1(111.41,128.2) 111.27,128.34 111.1,128.34 110.93,128.18 110.93,127.67 110.36,127.1 108.45,127.1 106.52,125.16 89.12,125.16 89.11,125.17 88.91,125.17
  IN1 w0.127: v1(25.29,48.04) 25.46,48.21 25.73,48.21 26.03,48.51 26.03,50.82 21.57,55.28 21.57,63.9 22.16,64.48 22.16,69.06 30.83,77.73 30.83,97.93 46.82,113.92 63.43,113.92 63.84,114.33 69.26,114.33 75.09,120.16 80.62,120.16 82.08,121.63 84.65,121.63 85.7,122.68 85.7,123.05 87.83,125.17 88.91,125.17
  BOTTOM w0.076: UC1.C33 110.49,124.2 110.29,124.2 110.21,124.28 110.21,124.39 110.28,124.46 110.28,124.71 110.26,124.73 110.26,127.75 110.9,128.39 111.22,128.39 v1(111.41,128.2)
  BOTTOM w0.102: v1(25.29,48.04) 25.12,48.21 24.94,48.21 CI10.2
USB3TN1_JUSB2_C: length 1.6
  BOTTOM w0.102: LI6.1 22.93,47.93 23.23,48.23 23.35,48.23 CI10.1
USB3TN1_JUSB2_R: length 10.9
  BOTTOM w0.102: LI6.2 20.24,47.93 19.95,48.23 19.69,48.23 19.51,48.4 19.35,48.4 19.21,48.26 DI4.7 DI4.4 17.09,48.26 16.98,48.37 16.47,48.37 16.45,48.35 15.91,48.35 15.89,48.37 15.59,48.37 15.27,48.05 v3(14.67,48.05) 12.45,48.05 11.66,48.84 11.4,48.84 11.19,48.64 JUSB2.8
USB3TN2_JUSB1: length 140.8
  IN1 w0.084: 88.91,124.16 89.62,124.16 89.93,124.47 106.71,124.47 108.89,126.65 111.19,126.65 111.43,126.41 v1(111.43,126.3)
  IN1 w0.127: 88.91,124.16 87.92,124.16 86.51,122.75 86.51,122.37 84.89,120.74 83.68,120.74 83.35,120.41 82.2,120.41 80.8,119.01 75.09,119.01 69.62,113.54 64.26,113.54 63.85,113.13 47.37,113.13 31.84,97.6 31.84,76.85 22.98,67.99 22.98,64.15 22.39,63.56 22.39,58.45 22.62,58.23 23.49,58.23 23.71,58.45 23.71,58.64 v1(23.47,58.88)
  BOTTOM w0.076: v1(111.43,126.3) 111.43,126.48 111.33,126.58 111.12,126.58 110.84,126.3 110.84,125.42 110.48,125.05 110.48,124.98 UC1.B33
  BOTTOM w0.102: v1(23.47,58.88) 23.77,59.18 23.77,59.4 23.66,59.5 CI3.2
USB3TN2_JUSB1_C: length 3.7
  BOTTOM w0.102: CI3.1 23.65,60.73 23.65,61.24 23.39,61.5 22.58,61.5 22.39,61.69 22.15,61.69 21.85,61.4 LI3.1
USB3TN2_JUSB1_R: length 12.9
  BOTTOM w0.102: JUSB1.8 11.19,66.35 11.27,66.43 11.78,66.43 12.22,65.99 12.89,65.99 14.74,64.15 14.74,64.03 14.72,64.01 14.72,63.45 14.74,63.44 v3(14.74,62.3) 14.74,61.82 14.98,61.58 16.18,61.58 16.35,61.41 DI1.4 DI1.7 18.25,61.41 18.42,61.58 18.6,61.58 18.72,61.71 18.85,61.71 19.16,61.4 LI3.2
USB3TP1_JUSB2: length 155.7
  IN1 w0.084: 88.91,125.44 88.93,125.44 88.95,125.42 89.02,125.42 89.04,125.4 89.21,125.4 89.21,125.39 106.42,125.39 108.36,127.33 110.26,127.33 110.7,127.76 110.7,128.27 111,128.57 111.21,128.57 v1(111.41,128.78)
  IN1 w0.127: v1(25.29,48.62) 25.43,48.48 25.61,48.48 25.76,48.62 25.76,50.71 21.3,55.17 21.3,64.01 21.89,64.59 21.89,69.17 30.55,77.84 30.55,98.04 46.7,114.19 63.32,114.19 63.73,114.6 69.15,114.6 74.98,120.43 80.51,120.43 81.97,121.9 84.54,121.9 85.43,122.79 85.43,123.16 87.71,125.44 88.91,125.44
  BOTTOM w0.076: v1(111.41,128.78) 111.22,128.58 110.82,128.58 110.07,127.83 110.07,124.67 UC1.B34
  BOTTOM w0.102: v1(25.29,48.62) 25.16,48.48 25.1,48.43 24.97,48.43 CI11.2
USB3TP1_JUSB2_C: length 1.6
  BOTTOM w0.102: LI6.4 22.93,48.73 23.23,48.44 23.37,48.44 CI11.1
USB3TP1_JUSB2_R: length 11
  BOTTOM w0.102: JUSB2.9 11.19,49.39 11.52,49.06 11.75,49.06 12.54,48.27 14.38,48.27 14.39,48.28 15.19,48.28 15.5,48.59 v3(16.18,48.59) 16.98,48.59 17.16,48.76 DI4.5 DI4.6 19.21,48.76 19.35,48.62 19.6,48.62 19.78,48.44 19.95,48.44 20.24,48.73 LI6.3
USB3TP2_JUSB1: length 140.9
  IN1 w0.084: 88.91,124.43 88.93,124.43 88.95,124.41 89.02,124.41 89.04,124.39 89.53,124.39 89.84,124.7 106.61,124.7 108.8,126.88 111.38,126.88 v1(111.43,126.93)
  IN1 w0.127: v1(24.05,58.88) 23.98,58.81 23.98,58.34 23.6,57.96 22.51,57.96 22.12,58.34 22.12,63.67 22.71,64.26 22.71,68.1 31.57,76.96 31.57,97.72 47.25,113.4 63.74,113.4 64.15,113.82 69.51,113.82 74.97,119.28 80.69,119.28 82.09,120.68 83.24,120.68 83.57,121.02 84.78,121.02 86.24,122.48 86.24,122.86 87.81,124.43 88.91,124.43
  BOTTOM w0.076: UC1.A33 110.65,125.66 110.65,126.38 111.04,126.77 111.27,126.77 v1(111.43,126.93)
  BOTTOM w0.102: CI4.2 23.98,59.26 23.98,58.95 v1(24.05,58.88)
USB3TP2_JUSB1_C: length 4
  BOTTOM w0.102: LI3.4 21.85,62.2 22.15,61.9 22.48,61.9 22.67,61.71 23.48,61.71 23.87,61.33 23.87,60.77 CI4.1
USB3TP2_JUSB1_R: length 12.8
  BOTTOM w0.102: LI3.3 19.16,62.2 18.89,61.92 18.63,61.92 18.51,61.8 18.36,61.8 18.25,61.91 DI1.6 DI1.5 16.28,61.91 16.17,61.8 15.07,61.8 14.95,61.91 14.95,62.01 14.97,62.03 14.97,62.57 14.95,62.59 v3(14.95,63.72) 14.95,64.24 12.98,66.2 12.31,66.2 11.87,66.65 11.43,66.65 11.19,66.89 JUSB1.9
USB20_CAM_N7: length 170.5
  TOP w0.102: RX21.1 219.02,165.69 LX6.1 219.02,164.75 219.31,164.46 219.31,164.04 218.91,163.63 217.7,163.63 v1(217.52,163.82)
  IN1 w0.127: v1(116.97,132.52) 117.14,132.68 117.14,133.28 117.54,133.68 128.11,133.68 129.21,132.58 136.96,132.58 138.28,133.89 152.88,133.89 158.87,139.88 158.87,149.52 155.46,152.93 155.46,154.41 156.57,155.52 164.47,155.52 165.96,157.01 212.76,157.01 216.25,160.5 216.25,163.21 216.69,163.65 217.35,163.65 v1(217.52,163.82)
  IN3 w0.084: v1(123.1,106.51) 123.1,106.63 122.76,106.97 122.58,106.97 122.46,106.85 122.46,105.91 122.9,105.48 123.64,105.48 124.06,105.9 124.06,109.65 124.61,110.2 124.61,110.67 124.28,111.01 123.41,111.01 122.88,111.54 122.88,115.14 121.14,116.88 120.93,116.88 119.03,118.79 119.03,118.8 118.82,119.01 117.96,119.01 117.42,119.55 117.42,120.4 116.87,120.95 116.87,122.12 115.85,123.14 115.85,126.5 116.68,127.33 116.68,130.2 117.15,130.67 117.15,131.01 117.15,131.01 117.15,131.08 117.12,131.1 117.12,131.11
  IN3 w0.127: 117.12,131.11 117.12,132.36 v1(116.97,132.52)
  BOTTOM w0.076: v1(123.1,106.51) 123.06,106.54 122.67,106.54 122.57,106.45 122.57,106.32 UC1.AR13
USB20_CAM_N7_R: length 9.4
  TOP w0.102: v1(219.41,171.01) 219.25,170.85 219,170.85 218.76,170.61 218.76,170.1 219.31,169.55 219.31,167.92 219.02,167.63 LX6.2 219.02,166.69 RX21.2
  BOTTOM w0.102: v1(219.41,171.01) 219.23,170.83 218.02,170.83 217.83,171.02 217.83,172.61 217.95,172.73 JLVDS.28
USB20_CAM_P7: length 170.8
  TOP w0.102: v1(217.52,163.23) 217.7,163.42 219,163.42 219.53,163.95 219.53,164.46 219.82,164.75 LX6.4 219.82,165.69 RX22.1
  IN1 w0.127: v1(217.52,163.23) 217.37,163.38 216.8,163.38 216.52,163.09 216.52,160.39 212.87,156.74 166.07,156.74 164.58,155.25 156.68,155.25 155.73,154.3 155.73,153.05 159.14,149.64 159.14,139.77 152.99,133.62 138.39,133.62 137.07,132.31 129.09,132.31 127.99,133.41 117.65,133.41 117.41,133.16 117.41,132.66 v1(117.55,132.52)
  IN3 w0.084: 117.38,131.11 117.38,131.1 117.36,131.08 117.36,130.59 116.89,130.12 116.89,127.24 116.06,126.42 116.06,123.22 117.08,122.21 117.08,121.04 117.63,120.49 117.63,119.63 118.05,119.22 118.91,119.22 119.24,118.89 119.24,118.88 121.02,117.09 121.22,117.09 123.09,115.22 123.09,111.63 123.5,111.22 124.37,111.22 124.81,110.78 124.81,110.09 124.27,109.56 124.27,105.81 123.73,105.26 122.81,105.26 122.25,105.82 122.25,106.94 122.47,107.16 v1(123.1,107.16)
  IN3 w0.127: 117.38,131.11 117.38,132.35 v1(117.55,132.52)
  BOTTOM w0.076: v1(123.1,107.16) 122.77,106.83 UC1.AP13
USB20_CAM_P7_R: length 9.4
  TOP w0.102: v1(219.41,170.43) 219.2,170.64 219.09,170.64 218.98,170.52 218.98,170.19 219.53,169.64 219.53,167.92 219.82,167.63 LX6.3 219.82,166.69 RX22.2
  BOTTOM w0.102: JLVDS.27 217.45,172.89 217.62,172.72 217.62,170.93 217.93,170.61 219.23,170.61 v1(219.41,170.43)
USB20_CR_N6: length 130.8
  IN1 w0.084: 131.57,100.4 131.56,100.4 131.54,100.42 131.47,100.42 131.35,100.54 126.78,100.54 123.93,103.4 123.93,106.17 123.85,106.25 123.63,106.25 v1(123.57,106.18)
  IN1 w0.127: v1(173.64,38.57) 173.88,38.33 175.05,38.33 177.33,36.05 184.47,36.05 185.17,36.75 185.17,37.33 186.07,38.23 186.07,39.25 182.58,42.74 182.58,48.7 181.9,49.38 181.9,57.86 181.7,58.06 181.7,60.5 180.01,62.19 180.01,62.69 177.92,64.78 177.92,71.46 176.89,72.49 176.89,72.98 171.97,77.91 161.4,77.91 150.52,88.78 148.96,88.78 140.72,97.02 136.75,97.02 133.36,100.4 131.57,100.4
  BOTTOM w0.076: v1(123.57,106.18) 123.57,106.25 123.83,106.51 UC1.AP11
  BOTTOM w0.102: LR2.1 172.56,33.05 172.62,32.99 172.62,32.59 172.74,32.47 172.96,32.47 173.22,32.73 173.22,33.14 173.23,33.16 173.23,33.77 172.98,34.02 172.98,38.02 173.16,38.21 173.28,38.21 173.64,38.56 v1(173.64,38.57)
USB20_CR_N6_R: length 29.1
  TOP w0.102: v1(169,33.03) 169.19,32.84 169.57,32.84 169.95,32.46 169.95,17.03 170.34,16.65 175.67,16.65 176.47,17.45 176.47,20.72 176.32,20.88 UR1.2
  BOTTOM w0.102: LR2.2 169.66,33.05 169.41,32.8 169.23,32.8 v1(169,33.03)
USB20_CR_P6: length 131
  IN1 w0.084: 131.57,100.67 131.56,100.67 131.46,100.77 126.88,100.77 124.16,103.49 124.16,106.27 123.66,106.76 v1(123.66,106.83)
  IN1 w0.127: 131.57,100.67 133.48,100.67 136.86,97.29 140.84,97.29 149.07,89.06 150.63,89.06 161.51,78.18 172.08,78.18 177.16,73.1 177.16,72.6 178.19,71.57 178.19,64.89 180.28,62.8 180.28,62.3 181.97,60.61 181.97,58.17 182.17,57.97 182.17,49.49 182.85,48.81 182.85,42.86 186.34,39.37 186.34,38.12 185.44,37.22 185.44,36.64 184.58,35.78 177.21,35.78 174.93,38.06 173.71,38.06 v1(173.64,37.99)
  BOTTOM w0.076: v1(123.66,106.83) 123.73,106.83 UC1.AN11
  BOTTOM w0.102: v1(173.64,37.99) 173.25,37.99 173.19,37.93 173.19,34.11 173.45,33.86 v3(173.45,32.88) 173.45,32.65 173.05,32.25 LR2.4
USB20_CR_P6_R: length 29.4
  TOP w0.102: v1(169,32.45) 169.18,32.62 169.48,32.62 169.74,32.37 169.74,16.94 170.25,16.43 175.76,16.43 176.69,17.36 176.69,20.81 176.82,20.94 UR1.3
  BOTTOM w0.102: v1(169,32.45) 169.14,32.59 169.45,32.59 169.78,32.25 LR2.3
USB20_JUSB1_N1: length 259.8
  IN1 w0.084: v1(126.93,106.46) 126.93,106.47 127.35,106.06 127.35,105.73 127.5,105.58 127.5,104.54 127.72,104.33 128.83,104.33 129.99,105.49 132.13,105.49 132.23,105.59 133.06,105.59 134.32,104.33 136.13,104.33 136.32,104.14
  IN1 w0.127: v1(186.31,60.04) 186.21,59.94 186.2,59.95 185.96,59.95 185.82,60.08 185.82,62.29 183.4,64.71 183.4,74.86 179.1,79.17 177.32,79.17 174.45,82.04 163.7,82.04 151.29,94.45 148.26,94.45 142.28,100.43 139.87,100.43 138.28,102.03 138.28,102.35 136.49,104.14 136.32,104.14
  BOTTOM w0.076: UC1.AR7 126.65,106.18 126.93,106.47 v1(126.93,106.46)
  BOTTOM w0.102: v1(186.31,60.04) 186.14,59.87 185.33,59.87 184.15,58.68 165.95,58.68 161.12,53.85 131.21,53.85 126.63,49.27 40.05,49.27 32.18,57.14 23.73,57.14 23.44,57.43 LI2.1
USB20_JUSB1_N1_R: length 15
  IN3 w0.127: v1(18.26,57.28) 18.09,57.11 16.91,57.11 14.95,59.07 14.95,62.69 13.94,63.7 13.59,63.7 JUSB1.2
  BOTTOM w0.102: v1(18.26,57.28) 18.98,58 DI2.2 19.17,57.24 19.27,57.14 20.33,57.14 20.62,57.43 LI2.2
USB20_JUSB1_P1: length 259.5
  IN1 w0.084: v1(126.93,105.81) 126.94,105.81 127.27,105.48 127.27,104.45 127.62,104.1 128.92,104.1 130.09,105.26 132.23,105.26 132.32,105.36 132.97,105.36 134.23,104.1 136.01,104.1 136.22,103.89 136.29,103.89 136.31,103.87 136.32,103.87
  IN1 w0.127: v1(186.31,59.45) 186.09,59.68 185.84,59.68 185.55,59.97 185.55,62.18 183.13,64.59 183.13,74.75 178.99,78.9 177.21,78.9 174.33,81.77 163.59,81.77 151.18,94.18 148.15,94.18 142.16,100.16 139.76,100.16 138.01,101.92 138.01,102.24 136.38,103.87 136.32,103.87
  BOTTOM w0.076: UC1.AT7 126.66,105.53 v1(126.93,105.81)
  BOTTOM w0.102: LI2.4 23.44,56.63 23.73,56.93 32.09,56.93 39.96,49.05 126.72,49.05 131.3,53.63 161.21,53.63 166.04,58.47 184.24,58.47 185.42,59.65 186.12,59.65 v1(186.31,59.45)
USB20_JUSB1_P1_R: length 15.2
  IN3 w0.127: v1(18.26,56.7) 18.1,56.86 16.8,56.86 14.7,58.96 14.7,62.58 13.83,63.45 13.11,63.45 12.69,63.03 JUSB1.3
  BOTTOM w0.102: LI2.3 20.62,56.63 20.33,56.93 19.27,56.93 19.17,56.82 DI2.3 18.89,56.07 v1(18.26,56.7)
USB20_JUSB2_N0: length 276.3
  IN1 w0.084: 136.63,102.47 136.62,102.48 136.62,102.51 136.57,102.56 136.57,102.59 135.53,103.63 133.96,103.63 133.44,104.15 132.1,104.15 131.44,104.82 130.56,104.82 129.45,103.71 127.29,103.71 126.92,104.07 126.92,104.99 126.36,105.55 126.36,107.53 126.03,107.86 125.82,107.86 125.58,107.61 v1(125.58,107.45)
  IN1 w0.127: v1(186.23,43.79) 186.39,43.64 186.58,43.64 186.72,43.78 186.72,44.99 185.53,46.18 185.53,48.9 185.71,49.08 185.71,53.73 185.46,53.98 185.46,57.04 185.03,57.47 185.03,58.76 184.77,59.02 184.77,61.85 181.9,64.72 181.9,74.76 178.76,77.91 177.06,77.91 174.1,80.87 162.98,80.87 150.78,93.06 148.13,93.06 141.82,99.37 139.37,99.37 137.06,101.69 137.06,102.04 136.63,102.47
  BOTTOM w0.089: v1(125.58,107.45) 125.68,107.45 UC1.AN8
  BOTTOM w0.102: v1(186.23,43.79) 185.87,43.43 185.56,43.43 183.66,41.53 122.39,41.53 118.58,37.72 110,37.72 104.63,43.09 28.31,43.09 27.38,44.02 v3(24.86,44.02) 23.77,44.02 23.59,44.21 23.59,44.46 23.44,44.61 LI5.1
USB20_JUSB2_N0_R: length 10.8
  IN3 w0.127: JUSB2.2 13.51,46.18 14.82,46.18 16.61,44.39 17.6,44.39 v1(17.77,44.56)
  BOTTOM w0.102: LI5.2 20.62,44.61 20.33,44.31 19.74,44.31 19.68,44.38 18.76,44.38 18.66,44.48 DI5.2 18.44,45.24 v1(17.77,44.56)
USB20_JUSB2_P0: length 276.5
  IN1 w0.084: 136.82,102.66 135.63,103.86 134.05,103.86 133.53,104.38 132.2,104.38 131.53,105.05 130.47,105.05 129.3,103.88 127.36,103.88 127.1,104.15 127.1,105.06 126.53,105.63 126.53,107.6 126.1,108.03 125.69,108.03 v1(125.57,108.15)
  IN1 w0.127: v1(186.23,43.21) 186.39,43.37 186.69,43.37 186.99,43.67 186.99,45.11 185.8,46.29 185.8,48.79 185.98,48.97 185.98,53.85 185.73,54.1 185.73,57.16 185.3,57.59 185.3,58.87 185.04,59.13 185.04,61.96 182.17,64.83 182.17,74.88 178.87,78.18 177.17,78.18 174.21,81.14 163.09,81.14 150.89,93.34 148.24,93.34 141.94,99.64 139.49,99.64 137.33,101.8 137.33,102.15 136.82,102.66
  BOTTOM w0.076: v1(125.57,108.15) 125.91,107.81 UC1.AM8
  BOTTOM w0.102: LI5.4 24.58,43.81 24.59,43.79 25.12,43.79 25.14,43.81 27.29,43.81 28.22,42.87 104.54,42.87 109.91,37.5 118.67,37.5 122.48,41.31 183.75,41.31 185.65,43.21 v1(186.23,43.21)
USB20_JUSB2_P0_R: length 10.9
  IN3 w0.127: JUSB2.3 13.61,45.92 14.72,45.92 16.5,44.14 17.61,44.14 v1(17.77,43.98)
  BOTTOM w0.102: LI5.3 20.69,43.81 20.39,44.1 19.65,44.1 19.59,44.16 18.76,44.16 18.66,44.06 DI5.3 18.44,43.3 v1(17.77,43.98)
USB20_JUSB3_N2: length 283.8
  IN1 w0.084: v1(125.76,105.43) 125.86,105.43 125.9,105.39 125.9,103.71 126.34,103.27 130.26,103.27 130.55,103.57 132.54,103.57 132.97,103.13 132.97,103.13 133.82,102.28 135.12,102.28 135.38,102.54 135.94,102.54 136.29,102.19 136.29,101.56 136.27,101.55 136.27,101.52 136.29,101.51 136.27,101.49
  IN1 w0.127: v1(186.27,41.41) 186.62,41.41 186.71,41.51 186.71,41.8 186.23,42.28 185.91,42.28 184.68,43.51 184.68,52.01 184.49,52.2 184.49,56.91 184.02,57.38 184.02,58.22 183.43,58.81 183.43,61.72 180.43,64.72 180.43,71.35 180.76,71.68 180.76,74.37 178.05,77.09 176.03,77.09 173.12,80 162.7,80 150.76,91.94 148.14,91.94 141.49,98.59 139.05,98.59 136.27,101.37 136.27,101.49
  BOTTOM w0.076: v1(125.76,105.43) 125.76,105.64 UC1.AR8
  BOTTOM w0.102: LI7.1 21.22,27.91 21.43,27.7 21.43,27.38 21.49,27.32 21.7,27.32 21.85,27.47 21.85,27.69 22.71,28.55 26.53,28.55 27.23,29.25 30.8,29.25 31.38,29.82 33.5,31.94 43.92,42.37 104.03,42.37 109.38,37.02 119.81,37.02 123.62,40.83 186.34,40.83 186.68,41.17 186.68,41.33 186.59,41.41 v1(186.27,41.41)
USB20_JUSB3_N2_R: length 11.4
  BOTTOM w0.102: LI7.2 18.53,27.91 18.23,27.61 18.08,27.61 17.74,27.96 17.41,27.96 17.12,28.25 DI7.2 16.79,28.86 16.59,28.66 16.59,28.08 16.46,27.96 16.34,27.96 16.25,28.05 16.25,28.24 15.62,28.87 13.72,28.87 13.35,28.51 v3(13.01,28.51) 11.21,28.51 JUSB3.2
USB20_JUSB3_P2: length 284
  IN1 w0.084: v1(125.58,106.18) 126.13,105.64 126.13,103.81 126.43,103.5 130.16,103.5 130.46,103.79 132.64,103.79 133.2,103.23 133.92,102.51 135.03,102.51 135.28,102.77 136.03,102.77 136.52,102.28 136.52,101.65 136.55,101.62
  IN1 w0.127: v1(187.1,41.35) 186.98,41.47 186.98,41.91 186.34,42.56 186.02,42.56 184.95,43.62 184.95,52.12 184.76,52.31 184.76,57.02 184.29,57.49 184.29,58.33 183.7,58.92 183.7,61.83 180.7,64.83 180.7,71.23 181.03,71.56 181.03,74.48 178.16,77.36 176.15,77.36 173.23,80.27 162.81,80.27 150.87,92.21 148.25,92.21 141.61,98.86 139.16,98.86 136.55,101.48 136.55,101.62
  BOTTOM w0.076: v1(125.58,106.18) 125.9,106.51 UC1.AP8
  BOTTOM w0.102: v1(187.1,41.35) 186.91,41.16 186.91,41.1 186.43,40.61 123.71,40.61 119.9,36.8 109.29,36.8 103.94,42.15 44.01,42.15 33.65,31.79 31.53,29.67 30.89,29.03 27.32,29.03 26.62,28.33 22.79,28.33 22.27,27.81 22.07,27.6 22.07,27.38 21.79,27.11 LI7.4
USB20_JUSB3_P2_R: length 11.4
  BOTTOM w0.102: JUSB3.3 11.21,28.29 12.73,28.29 12.74,28.28 13.27,28.28 13.28,28.29 13.44,28.29 13.81,28.66 15.53,28.66 16.03,28.15 16.03,27.96 16.25,27.74 16.52,27.74 16.59,27.68 16.59,27.07 16.73,26.93 DI7.3 17.12,27.47 17.39,27.74 17.65,27.74 17.99,27.4 18.3,27.4 18.59,27.11 LI7.3
USB20_MINI1_N4: length 58.4
  IN3 w0.084: v1(121.76,107.48) 121.89,107.61 122.13,107.61 122.53,108.01 122.53,109.29 121.63,110.18 121.63,113.61 120.16,115.08 119.55,115.08 118.97,115.66 118.97,117.63 117.19,119.41 117.19,120.17 116.49,120.87 116.49,121.92 115.28,123.12 115.28,126.95 115.6,127.26 115.6,129.74 116.18,130.33 116.18,130.65 116.21,130.68
  IN3 w0.127: v1(119.24,146.95) 119.15,146.87 119.15,146.61 119.3,146.47 119.78,146.47 121.5,144.74 121.5,138.55 116.21,133.26 116.21,130.68
  BOTTOM w0.076: v1(121.76,107.48) 122.09,107.81 UC1.AM15
  BOTTOM w0.102: v1(119.24,146.95) 119.09,146.8 119.09,146.52 118.81,146.24 111.09,146.24 110.62,146.71 110.62,146.96 110.5,147.08 JMINI.36
USB20_MINI1_P4: length 58.1
  IN3 w0.084: 115.95,130.75 115.95,130.74 115.97,130.72 115.97,130.41 115.39,129.83 115.39,127.35 115.07,127.04 115.07,123.03 116.28,121.83 116.28,120.78 116.98,120.08 116.98,119.32 118.76,117.54 118.76,115.57 119.46,114.87 120.07,114.87 121.42,113.52 121.42,110.09 122.32,109.2 122.32,108.1 122.04,107.82 121.92,107.82 121.76,107.98 v1(121.76,108.13)
  IN3 w0.127: 115.95,130.75 115.95,133.36 121.25,138.66 121.25,144.64 119.67,146.21 119.19,146.21 118.9,146.51 118.9,146.7 118.65,146.95 v1(118.65,146.95)
  BOTTOM w0.076: UC1.AL15 122.14,108.28 122,108.13 v1(121.76,108.13)
  BOTTOM w0.102: JMINI.38 111.3,147.14 111.24,147.08 110.9,147.08 110.84,147.01 110.84,146.8 111.18,146.45 118.72,146.45 118.88,146.61 118.88,146.76 118.69,146.95 v1(118.65,146.95)
USB20_TOUCH_N5: length 113.6
  TOP w0.102: v1(52.55,100.98) 52.73,101.16 52.73,101.37 52.58,101.52 v3(34.01,101.52) 23.74,101.52 23.23,101.01 23.23,99.62 22.62,99 22.62,97.82 22.91,97.53 JTOUCH.2
  IN1 w0.084: 86.08,110.24 86.16,110.24 86.18,110.22 88.49,110.22 88.49,110.22 90.46,110.22 90.65,110.03 96.35,110.03 97.62,111.3 115.24,111.3 116.26,110.28 117.13,110.28 117.44,110.59 118.44,110.59 118.9,111.05 121.47,111.05 122.11,110.4 122.11,109.71 122.42,109.4 122.42,108.42 122.66,108.18 122.95,108.18 v1(123.14,108.37)
  IN1 w0.127: v1(52.55,100.98) 52.7,101.13 52.7,101.71 55.07,104.08 64.04,104.08 65.53,105.57 66.47,105.57 67.07,106.17 72.23,106.17 73.04,106.97 76.83,106.97 78.59,108.74 83.4,108.74 84.91,110.24 86.08,110.24
  BOTTOM w0.089: UC1.AM13 122.9,108.13 v1(123.14,108.37)
USB20_TOUCH_P5: length 113.9
  TOP w0.102: v1(53.13,100.98) 52.95,101.16 52.95,101.46 52.67,101.74 34.29,101.74 34.28,101.75 33.75,101.75 33.74,101.74 23.65,101.74 23.02,101.1 23.02,99.71 22.4,99.09 22.4,97.82 22.11,97.53 JTOUCH.3
  IN1 w0.084: 86.08,109.97 86.1,109.99 88.39,109.99 88.39,109.99 90.36,109.99 90.55,109.8 96.45,109.8 97.72,111.07 115.15,111.07 116.16,110.06 117.23,110.06 117.54,110.37 118.54,110.37 118.99,110.82 121.38,110.82 121.89,110.31 121.89,109.61 122.2,109.3 122.2,108.32 122.57,107.95 122.9,107.95 v1(123.13,107.72)
  IN1 w0.127: 86.08,109.97 85.02,109.97 83.51,108.46 78.7,108.46 76.94,106.7 73.15,106.7 72.35,105.9 67.18,105.9 66.58,105.3 65.65,105.3 64.15,103.81 55.19,103.81 52.98,101.6 52.98,101.13 v1(53.13,100.98)
  BOTTOM w0.076: v1(123.13,107.72) 122.93,107.72 UC1.AN13
USB20_USBDB_N3: length 147.4
  TOP w0.102: LI10.1 204.77,49.12 203.94,48.28 v3(203.94,45.1) 203.94,43.27 204.73,42.48 204.73,40.51 203.55,39.33 203.55,33.73 203.17,33.35 v1(199.9,33.35)
  IN1 w0.084: 134.91,101.45 134.91,101.48 134.86,101.53 134.75,101.64 134.72,101.64 134.67,101.69 134.64,101.69 134.33,102 133.63,102 132.87,102.75 130.14,102.75 129.86,103.03 126.24,103.03 125.66,103.61 125.66,104.83 125.38,105.12 125.38,105.32 125.01,105.68 v1(125.01,105.81)
  IN1 w0.127: 134.91,101.45 135.44,100.92 135.92,100.92 138.77,98.08 141.28,98.08 148.76,90.6 151.21,90.6 162.67,79.14 172.23,79.14 177.97,73.4 177.97,72.93 179.48,71.43 179.48,64.87 182.92,61.43 182.92,58.49 183.49,57.92 183.49,52.31 183.63,52.17 183.63,48.83 184.15,48.32 184.15,42.74 187.14,39.75 187.14,37.79 186.63,37.28 186.63,34.93 187.49,34.07 187.49,33.21 188.47,32.23 192.41,32.23 193.81,33.63 198.38,33.63 198.75,33.26 199.81,33.26 v1(199.9,33.35)
  BOTTOM w0.076: v1(125.01,105.81) 124.78,105.81 124.62,105.97 UC1.AR10
USB20_USBDB_N3_R: length 3.7
  TOP w0.102: JDB.5 209.99,49.7 209.59,49.31 v3(209.11,49.31) 208.52,49.31 208.04,48.82 207.95,48.82 207.65,49.12 LI10.2
USB20_USBDB_P3: length 147.6
  TOP w0.102: LI10.4 205.13,48.31 205.04,48.4 205.04,48.83 204.98,48.9 204.86,48.9 204.16,48.19 204.16,45.37 204.17,45.36 204.17,44.83 204.16,44.82 204.16,43.36 204.94,42.57 204.94,40.42 203.76,39.24 203.76,33.64 203.26,33.14 200.27,33.14 v1(199.9,32.77)
  IN1 w0.084: 134.57,101.44 134.24,101.77 133.53,101.77 132.78,102.52 130.05,102.52 129.77,102.8 126.15,102.8 125.43,103.52 125.43,104.74 v1(125.01,105.16)
  IN1 w0.127: v1(199.9,32.77) 199.68,32.99 198.63,32.99 198.26,33.36 193.92,33.36 192.52,31.96 188.35,31.96 187.22,33.1 187.22,33.95 186.36,34.81 186.36,37.39 186.87,37.91 186.87,39.63 183.87,42.63 183.87,48.2 183.36,48.72 183.36,52.06 183.22,52.2 183.22,57.81 182.65,58.38 182.65,61.31 179.21,64.76 179.21,71.31 177.7,72.82 177.7,73.29 172.12,78.87 162.56,78.87 151.1,90.33 148.64,90.33 141.17,97.81 138.65,97.81 135.81,100.65 135.33,100.65 134.64,101.34 134.64,101.37 134.59,101.42 134.57,101.44
  BOTTOM w0.076: v1(125.01,105.16) 124.64,105.53 UC1.AT10
USB20_USBDB_P3_R: length 3.7
  TOP w0.102: LI10.3 207.67,48.31 207.97,48.61 208.14,48.61 208.61,49.08 209.51,49.08 209.88,48.7 JDB.4
USB_EN#: length 265
  TOP w0.102: v1(27.02,66.24) 25.81,65.03 CI13.1 26.27,64.23 26.27,63.55 26.1,63.38 UI3.4 ; UI5.4 207.82,41.33 208.12,41.03 208.64,41.03 CI25.1 211.56,41.46 v2(212.97,40.05) 213.45,39.57 v1(213.45,38.94) ; CI26.1 30.64,55 30.45,55.19 v1(29.81,55.19) 29.56,55.19 29.24,54.87 29.24,54.24 29.01,54.01 UI2.4 ; UE1.26 193.19,33.97 v1(193.07,33.86) ; CI16.1 22.19,34.75 21.51,34.06 v1(21.51,33.48) 20.96,32.93 UI4.4
  IN1 w0.127: v1(61.97,47.33) 58.65,44.02 v1(28.46,44.02) ; v1(187.58,49.41) 189.5,47.5 189.5,40.65 188.93,40.08 188.93,39.2 188.14,38.42 188.14,35.74 189.64,34.24 192.69,34.24 v1(193.07,33.86)
  IN3 w0.127: v1(213.45,38.94) 212.98,38.47 202.63,38.47 199.67,35.51 197.7,35.51 196.85,34.66 196.85,34.01 196.16,33.32 194.05,33.32 193.51,33.86 v1(193.07,33.86) ; v1(21.51,33.48) 22.32,33.48 28.46,39.62 v1(28.46,44.02) 28.46,53.85 v1(29.81,55.19) 29.81,57.61 28.98,58.43 28.98,64.27 v1(27.02,66.24) ; v1(61.97,47.33) 62.16,47.14 114.78,47.14 115.24,46.68 141.47,46.68 141.6,46.81 168.61,46.81 168.82,47.03 177.83,47.03 179.01,48.21 185.18,48.21 186.38,49.41 v1(187.58,49.41)
USB_OC0#: length 178.6
  TOP w0.089: v1(131.6,105.9) 132.77,105.9 v2(134.59,104.09) 135.03,103.64 135.03,102.01 135.59,101.44
  TOP w0.102: UI2.5 23.37,54.01 23.21,54.18 23.21,54.76 CI17.1 25.4,56.96 32.21,56.96 32.96,57.71 32.96,68.21 v1(32.15,69.02) 32.15,68.95 31.02,67.82 21.68,67.82 20.51,66.65 CI15.1 20.22,64.34 20.22,63.54 20.38,63.38 UI3.5 ; 135.59,101.44 138.52,98.51 138.95,98.51 139.59,97.88 RP55.1
  IN2 w0.089: v1(131.6,107.72) v1(131.6,105.9) 131.6,105.23 131.82,105.01 131.82,102.91 132.01,102.73 132.01,101.56
  IN2 w0.127: 132.01,101.56 132.01,97.91 130.11,96.01 127.02,96.01 126.9,95.89 124.39,95.89 113.03,84.53 59.46,84.53 45.49,70.56 33.68,70.56 v1(32.15,69.02)
  BOTTOM w0.076: UC1.AL3 129.19,108.56 129.44,108.31 131.01,108.31 v1(131.6,107.72)
USB_OC1#: length 322
  TOP w0.089: v1(132.86,104.9) 133.04,104.9 v2(133.3,104.64) 134.8,103.14 134.8,101.91 135.27,101.44
  TOP w0.102: UI5.5 207.82,45.77 209.07,44.52 CI32.1 209.3,44.16 209.5,44.36 211.17,44.36 v1(211.23,44.3) ; RP55.2 139.09,98 138.8,98.28 138.43,98.28 135.27,101.44 ; v1(32.79,69.04) 33.19,68.64 33.19,43.46 25.11,35.38 22.32,35.38 20.86,33.92 16.62,33.92 CI24.1 16.04,33.85 UI4.5
  IN2 w0.089: 132.26,101.44 132.26,102.32 132.76,102.82 132.76,104.8 v1(132.86,104.9)
  IN2 w0.127: v1(32.79,69.04) 33.81,70.05 45.7,70.05 59.67,84.02 113.24,84.02 121.43,92.21 127.47,92.21 132.26,97 132.26,101.44 ; v1(132.86,104.9) 132.91,104.95 133.45,104.95 134.51,103.9 134.51,102.45 140.17,96.78 140.17,75.15 142.21,73.12 142.21,46.62 v1(141.98,46.39)
  IN3 w0.127: v1(141.98,46.39) 142.16,46.21 168.49,46.21 168.87,46.59 177.77,46.59 178.76,47.58 179.66,47.58 179.93,47.32 180.5,47.32 182.89,44.93 184.28,44.93 184.85,45.5 186.97,45.5 188.23,46.76 190.01,46.76 190.68,46.1 193.42,46.1 194.35,45.16 197.12,45.16 198.32,43.96 204.53,43.96 205.02,44.45 206.07,44.45 206.67,43.85 207.02,43.85 207.62,44.45 211.07,44.45 v1(211.23,44.3)
  BOTTOM w0.076: UC1.AT1 130.43,105.56 131.06,104.93 132.83,104.93 v1(132.86,104.9)
USB_OC2#: length 24.1
  TOP w0.089: v1(132.3,103.15) 132.43,103.27 v2(133.15,103.27) 134.26,103.27 134.57,102.96 134.57,101.83 134.95,101.44
  TOP w0.102: RP55.3 138.59,97.8 134.95,101.44 134.95,101.44
  IN2 w0.089: v1(135.71,109.46) 135.71,108.58 132.24,105.1 132.24,103.21 v1(132.3,103.15)
  BOTTOM w0.076: UC1.AH2 130.07,110.54 130.08,110.54 130.09,110.56 130.47,110.56 130.59,110.43 134.74,110.43 v1(135.71,109.46)
USB_OC3#: length 12.8
  TOP w0.089: 134.39,101.44 134.06,101.77 134.06,102.9 v1(134.06,102.9)
  TOP w0.102: RP55.4 138.09,97.74 v2(134.88,100.95) 134.39,101.44
  BOTTOM w0.076: 133.19,103.52 130.84,103.52 130.44,103.91 130.14,103.91 130.13,103.92 129.48,103.92 129.15,104.25 UC1.AV3
  BOTTOM w0.089: v1(134.06,102.9) 134.06,102.9 134.06,102.91 133.46,103.52 133.19,103.52
USBRBIAS: length 5.1
  TOP w0.076: v1(123.66,108.15) 123.66,109.19 v2(123.57,109.28) 123.22,109.28 123.03,109.47 123.03,109.89 RC90.1
  BOTTOM w0.076: UC1.AJ11 UC1.AJ10
  BOTTOM w0.089: v1(123.66,108.15) 123.66,109.29 UC1.AJ11
VCIN0_PH: length 133.6
  TOP w0.203: UE1.109 182.85,44.91 v1(183.42,45.48)
  TOP w0.254: v1(174.13,54.48) 174.13,54.81 171.53,57.41 171.53,62.12 170.82,62.83 170.82,77.7 162.38,86.14 150.9,86.14 149.19,87.86 120.88,87.86 114.82,93.91 114.82,101.41 114.96,101.55 114.96,102.94 v2(114.6,103.31) 114.6,103.34 114.89,103.63 114.89,107.21 114.87,107.22 114.87,109.13 114.75,109.26 114.75,109.9 115.12,110.28 115.12,110.74 113.33,112.53 107.08,112.53 106.52,113.09 106.52,113.41 PH1.1
  BOTTOM w0.254: v1(183.42,45.48) 182.96,45.02 PR24.1 181.05,45.92 181.05,51.11 179.89,52.27 176.26,52.27 174.13,54.4 v1(174.13,54.48)
VCIN1_PH: length 165.8
  TOP w0.102: v2(128.99,182.47) 129.26,182.47 129.94,181.79 PR26.2 ; UE1.102 182.46,47.71 182.72,47.45 v1(188.71,47.45)
  IN2 w0.254: v1(188.71,47.45) 188.71,48.97 189.13,49.38 189.13,65.31 187.98,66.46 187.98,75.82 183.14,80.66 182.7,80.66 163.06,100.3 163.06,101.15 162.03,102.18 161.47,102.18 159.87,103.78 158.98,103.78 154.86,107.9 154.86,110.73 152.78,112.81 152.78,117.36 148.85,121.3 148.85,128.75 139.47,138.12 139.47,139.33 132.32,146.48 132.32,166.69 129.2,169.81 129.2,177.43 v1(130.03,178.26)
VCOUT0_PH#: length 102.3
  TOP w0.102: UE1.104 181.55,46.9 v1(180.26,46.9)
  TOP w0.254: v1(117.28,16.53) v2(117.28,15.35) 117.28,13.75 117.83,13.19 PC100.1 119.6,13.19 119.66,13.13 PR100.2 PR102.2 PR101.2
  IN1 w0.102: v1(115.99,43.41) 115.71,43.13 115.71,18.1 v1(117.28,16.53)
  BOTTOM w0.102: v1(180.26,46.9) 179.8,46.43 169.84,46.43 167.21,43.8 116.39,43.8 v1(115.99,43.41)
VCOUT1_PH: length 175.3
  TOP w0.102: RE47.2 178.6,51.27 v1(178.91,51.57) 178.78,51.7 UE2.2 ; v2(179.68,47.06) 179.68,47.32 v1(180.1,47.74) 180.26,47.74 180.7,47.31 UE1.103
  TOP w0.254: PR30.1 128.11,161.8 v1(128.22,161.69)
  IN1 w0.127: v1(184.93,72.28) 185.45,71.76 185.45,69.64 184.5,68.69 184.5,66.98 185.53,65.95 185.53,64.09 187.08,62.53 187.08,58.53 186.68,58.12 186.68,57.43 186.62,57.36 186.62,54.43 186.74,54.3 186.74,49.3 187.61,48.44 v1(187.61,48.33) ; v1(180.1,47.74) 179.78,48.06 179.75,48.06 178.91,48.91 v1(178.91,51.57)
  IN3 w0.127: v1(180.1,47.74) 187.01,47.74 v1(187.61,48.33) ; v1(128.22,161.69) 128.22,160.42 130.44,158.2 130.44,135.21 131.71,133.94 147.03,133.94 153.87,127.1 156.73,127.1 159.48,124.35 159.48,117.89 155.73,114.14 155.73,112.98 156.3,112.41 157.61,112.41 158.89,111.12 159.3,111.12 160.94,109.48 160.94,107.13 162.14,105.93 163.37,105.93 166.21,103.09 166.21,99.84 169.33,96.71 172.93,96.71 176.26,93.39 176.26,92.86 181.6,87.52 181.6,82.56 186.85,77.31 186.85,74.2 v1(184.93,72.28)
VGA_CLKREQ#_R: length 23.2
  TOP w0.102: QV28.3 182.2,93.79 RV199.2 182.13,94.87 182.91,94.87 183.28,95.24 v2(186.96,95.24) 187.21,95.24 v1(187.61,95.63)
  IN3 w0.102: v1(184.49,108.4) 184.93,107.97 184.93,106.33 185.32,105.94 185.32,104.21 185.84,103.69
  IN3 w0.127: v1(187.61,95.63) 187.61,98.35 185.93,100.03 185.93,103.6 185.84,103.69
  BOTTOM w0.102: v1(184.49,108.4) 184.79,108.69 UV1.AN13
VGA_SMB_CK2: length 19.4
  TOP w0.102: QV15.1 178.54,94.51 178.71,94.68 179.55,94.68 RV90.2 180.43,93.81 v2(180.43,92.13) 180.43,91.9 180.63,91.7 181.07,91.7 v1(181.32,91.95)
  IN3 w0.127: v1(178.16,100.44) 178.02,100.3 178.02,98.17 179.41,96.78 179.41,95.32 180.62,94.11 180.62,91.36 181.08,90.9 181.38,90.9 181.51,91.03 181.51,91.76 v1(181.32,91.95)
  BOTTOM w0.102: v1(178.16,100.44) 177.86,100.74 177.86,101.06 RV252.1
VGA_SMB_CK2_R: length 11.5
  IN3 w0.102: v1(176.06,111.61) 175.65,111.2 175.65,108.04 176.09,107.6
  IN3 w0.127: v1(177.92,103.03) 177.71,103.24 177.71,104.24 177.19,104.76 177.19,106.53 176.12,107.6 176.09,107.6
  BOTTOM w0.102: v1(176.06,111.61) 176.34,111.89 UV1.AJ23 ; v1(177.92,103.03) 177.72,102.82 177.72,102.55 RV252.2
VGA_SMB_DA2: length 23.2
  TOP w0.102: v1(181.45,90.05) v2(179.27,90.05) 178.65,90.05 178.08,90.62 176.16,90.62 RV91.2 176.11,91.62 176.61,91.13 177,91.13 177.24,91.37 QV15.4
  IN3 w0.127: v1(177.52,100.44) 177.76,100.2 177.76,98.07 179.16,96.67 179.16,95.21 180.37,94.01 180.37,91.25 180.97,90.65 181.29,90.65 181.45,90.49 v1(181.45,90.05)
  BOTTOM w0.102: v1(177.52,100.44) 177.64,100.56 177.64,100.77 RV251.1
VGA_SMB_DA2_R: length 13
  TOP w0.102: v2(175.36,111.59) 175.97,112.2 v1(176.02,112.2)
  IN3 w0.102: v1(176.02,112.2) 175.42,111.6 175.42,107.94 175.99,107.37
  IN3 w0.127: 175.99,107.37 176.94,106.42 176.94,104.65 177.46,104.13 177.46,103.2 v1(177.29,103.03)
  BOTTOM w0.102: RV251.2 177.49,102.55 177.49,102.82 v1(177.29,103.03) ; v1(176.02,112.2) 176.02,112.25 UV1.AH23
VGA_X1_R: length 2.4
  TOP w0.102: RG4.1 71.57,44.08 71.57,43.91 v2(71.69,43.79) 71.83,43.65 UG1.12
VL: length 3.7
  TOP w0.203: v1(127.61,19.09) 127.83,18.87 PU100.13
  BOTTOM w0.102: v2(128.64,20.18) PC106.1
  BOTTOM w0.254: v1(127.61,19.09) 127.58,19.13 PC106.1
VR12.5_VR_ON_R: length 2.6
  TOP w0.089: v2(93.61,122.91) 93.26,122.57 v1(93.26,122.55) 93.13,122.55 92.66,123.02 R250.2
  BOTTOM w0.076: v1(93.26,122.55) 93.26,122.54 93.6,122.2 UC1.F60
VR_ENABLE: length 4.1
  BOTTOM w0.102: v2(84.9,141.05) 85.46,140.49 PC522.1
  BOTTOM w0.203: PC522.1 PR522.1 86.26,139.01 86.46,138.82 PU501.8
VR_HOT#: length 222.3
  TOP w0.102: v1(64.9,105.63) 64.76,105.76 62.35,105.76 62.13,105.98 62.13,106.5 61.43,107.2 v2(61.43,108.88) 61.43,109.99 74.01,122.57 79.75,122.57 79.96,122.35 81.03,122.35 81.37,122.69 82.88,122.69 84.36,124.18 85.91,124.18 86.71,124.98 86.71,131.29 86.52,131.48 86.52,131.7 85.45,132.76 PR533.1 86.47,133.68 88.22,133.68 88.51,133.97 v1(88.51,134.57) 88.74,134.79 PC506.2 ; RE44.1 180.5,55.26 v1(180.18,55.57)
  IN3 w0.127: v1(180.18,55.57) 179.18,55.57 177.03,53.41 176.24,53.41 175.92,53.09 117.64,53.09 116.92,53.81 105.27,53.81 104.05,52.59 75.27,52.59 72.5,55.36 72.5,69.82 70.13,72.19 70.13,73.46 65.36,78.23 65.36,87.05 64.17,88.23 64.17,91.42 64.68,91.92 64.68,95.54 65.65,96.51 65.65,98.49 64.95,99.2 64.95,102 64.21,102.73 64.21,104.94 v1(64.9,105.63)
  BOTTOM w0.102: v1(88.51,134.57) 88.62,134.67 PU501.30
VR_ON: length 276
  TOP w0.089: 86.76,117.34 87.56,118.15 90.79,118.15 92.27,119.62 C80.1 91.98,120.44 91.98,121.14 91.98,121.14 R250.1 92.55,122.11 RE1.2
  TOP w0.102: v1(170.58,45.92) 170.58,44.25 DE1.3 CE34.1 174.35,42.92 176.86,40.41 RE12.2 ; v1(79.98,115.78) 80.56,116.36 v2(81.12,116.36) 84.51,116.36 85.23,117.08 86.49,117.08 86.76,117.34
  IN3 w0.127: v1(170.58,45.92) 170.36,45.71 111.61,45.71 111.27,46.05 62.57,46.05 56.35,52.27 56.35,92.66 50.77,98.25 50.77,104.06 v1(62.09,115.39) 70.48,123.78 80.87,123.78 84.06,126.97 84.06,130.38 81.94,132.5 81.94,134.88 83.09,136.03 v1(83.09,138.04)
  BOTTOM w0.102: v1(79.98,115.78) 79.06,114.86 63.11,114.86 62.58,115.39 v1(62.09,115.39)
  BOTTOM w0.254: PR522.2 84.29,139.01 84.17,139.14 83.66,139.14 83.4,138.89 83.4,138.36 v1(83.09,138.04)
VR_ON_EC: length 2.1
  TOP w0.102: RE12.1 180.05,40.41 v1(180.3,40.16) 180.35,40.11 UE1.121
VR_READY_R: length 6.6
  BOTTOM w0.076: 92.53,126.34 93.36,126.34 93.88,125.82 93.88,125.14 94.09,124.93 94.09,124.79 94.25,124.63 94.25,124.39 UC1.C59
  BOTTOM w0.089: 92.53,126.34 91.57,127.3 91.57,127.37
  BOTTOM w0.102: 91.57,127.37 90.52,128.42 R251.2
VR_SVID_ALRT#: length 22.6
  IN3 w0.127: v1(82.39,118.69) 83.11,119.41 83.11,122.05 85.07,124.01 86.24,124.01 86.97,124.75 86.97,128.13 85.88,129.22 85.88,132.54 86.9,133.55 v1(86.9,134.11)
  BOTTOM w0.102: R252.2 v1(82.39,118.69) R254.2 ; PU501.32 87.82,134.98 86.95,134.11 v1(86.9,134.11) PR528.2
VR_SVID_CLK: length 27
  IN3 w0.127: v1(79.34,118.18) 79.42,118.1 82.82,118.1 83.95,119.23 83.95,121.4 85.93,123.38 86.44,123.38 87.66,124.6 87.66,128.28 86.47,129.47 86.47,132.29 87.49,133.31 87.49,133.83 v1(87.85,134.19)
  BOTTOM w0.102: PU501.31 88.22,135 87.85,134.63 v1(87.85,134.19) 87.85,133.56 PR526.2 ; R248.1 80.71,117.66 v2(79.76,117.66) 79.49,117.66 79.34,117.81 v1(79.34,118.18)
VR_SVID_DAT: length 23.5
  IN3 w0.127: v1(79.15,119.71) 79.94,119.71 84.83,124.6 86,124.6 86.39,124.99 86.39,127.88 85.29,128.97 85.29,132.78 86.07,133.56 v1(86.07,134.82)
  BOTTOM w0.102: v1(79.15,119.71) 79.01,119.85 R257.2 ; PR530.2 85.94,134.69 v1(86.07,134.82) 86.45,135.2 86.45,135.71 86.76,136.02 PU501.1
VREF_CPU: length 54.8
  TOP w0.203: v1(90.03,134.44) 89.94,134.53 PC507.1
  IN3 w0.254: v1(111.76,144.79) 111.66,144.89 111.66,145.43 111.07,146.02 92.64,146.02 90.58,143.97 90.58,141.84 89.98,141.23 88.17,141.23 88.17,141.3 87.72,141.74 v1(87.72,142.76) 85.88,142.76 85.37,142.25 85.37,140.16 87.15,138.38 87.15,136.6 87.72,136.03 89.31,136.03 90.03,135.3 v1(90.03,134.44)
  BOTTOM w0.203: PU501.27 89.82,134.98 89.91,134.89 89.91,134.57 v1(90.03,134.44) 90.03,133.26 90.63,132.66 PR531.1
  BOTTOM w0.254: v1(111.76,144.79) 111.76,144.32 PH502.1 ; PR514.2 90.77,142.44 90.45,142.76 90.45,143.27 89.94,143.78 v2(89.69,143.78) 88.39,143.78 87.72,143.11 v1(87.72,142.76) PR507.2 PR504.2 PR502.2
VREFC_A1: length 7.9
  TOP w0.254: UV18.M8 171.79,150.12 171.39,150.52 171.39,151.12 v1(171.15,151.36)
  BOTTOM w0.102: v2(169.23,154.47) 169.45,154.25 CV227.1
  BOTTOM w0.508: CV227.1 RV167.1 RV157.2 172.16,152.38 v1(171.15,151.36)
VREFC_A1_B: length 10.3
  TOP w0.102: v2(214.95,125.51) 214.95,127.49 215.42,127.96 215.88,127.96 RV183.2
  TOP w0.254: v1(213.46,131.14) 213.22,130.9 212.55,130.9 UV22.M8
  TOP w0.381: v1(213.46,131.14) 214.46,130.14 CV275.1 RV191.1 RV183.2
VREFC_A2: length 8.3
  BOTTOM w0.102: RV158.2 173.04,140.63 172.72,140.31 v2(172.72,139.01)
  BOTTOM w0.254: UV19.M8 171.79,145.25 171.39,144.85 171.39,143.59
  BOTTOM w0.508: 171.39,143.59 171.27,143.48 171.27,142.41 171.27,142.41 CV228.1 RV168.1 173.03,141.13 RV158.2
VREFC_A2_B: length 7.8
  BOTTOM w0.254: UV23.M8 206.95,130.9 206.2,130.9
  BOTTOM w0.381: RV184.2 202.25,131.53 v2(202.7,131.08) 203.16,130.61
  BOTTOM w0.508: 203.16,130.61 CV276.1 205.49,130.19 206.2,130.9 ; RV184.2 201.32,131.97 RV192.1
VREFC_A3: length 6.3
  TOP w0.254: 186.78,143.71 186.78,144.85 UV20.M8
  TOP w0.508: 186.78,143.71 186.51,143.44 v2(186.51,141.98) CV230.1 RV170.1 184.79,141.08 RV160.2
VREFC_A3_B: length 6.4
  BOTTOM w0.203: 213.5,116.98 213.36,116.84 212.58,116.84 UV24.M8
  BOTTOM w0.381: RV186.2 RV194.1 CV278.1 v2(215.5,116.67) 214.82,116.67 214.5,116.98 213.5,116.98
VREFC_A4: length 8.7
  BOTTOM w0.102: RV162.2 185.72,154.78 v2(185.72,156.27)
  BOTTOM w0.254: 186.78,151.45 186.78,150.45 UV21.M8
  BOTTOM w0.508: RV162.2 CV232.1 186.25,154.37 RV172.1 187.15,153.73 186.78,153.36 186.78,151.45
VREFC_A4_B: length 7.4
  TOP w0.102: RV188.2 203.79,117.68 v2(204.04,117.43)
  TOP w0.254: UV25.M8 206.95,116.02 206.29,116.02 v1(206.05,115.78)
  TOP w0.508: v1(206.05,115.78) 205.43,115.78 205.31,115.9 CV280.1 RV196.1 RV188.2
VREFD_Q1: length 6.8
  TOP w0.102: v2(171.35,141.13) RV156.2
  TOP w0.254: 168.17,143.7 168.17,144.04 UV18.H1
  TOP w0.508: RV166.1 RV156.2 ; RV166.1 CV226.1 ; RV166.1 169.49,141.46 169.23,141.73 169.23,142.65 168.17,143.7
VREFD_Q1_B: length 5.2
  TOP w0.254: 205.88,133.75 205.92,133.7 UV22.H1
  TOP w0.508: 205.88,133.75 v2(204.07,133.75) CV274.1 RV190.1 RV182.2
VREFD_Q2: length 5.7
  BOTTOM w0.254: v3(168.96,151.31) 168.59,150.94 UV19.H1
  BOTTOM w0.508: RV159.2 RV169.1 CV229.1 v2(168.03,153.34) 168.96,152.41 v3(168.96,151.31)
VREFD_Q2_B: length 7.5
  BOTTOM w0.102: v2(218.1,131.71) 217.93,131.54 216.74,131.54 CV277.1
  BOTTOM w0.254: v3(213.41,133.33) 213.03,133.7 UV23.H1
  BOTTOM w0.381: v3(213.41,133.33) 214.26,133.33 214.71,133.77 RV185.2 RV193.1 CV277.1
VREFD_Q3: length 8.1
  TOP w0.102: RV161.2 192.5,155.15 v2(192.5,156.69)
  TOP w0.254: 189.94,151.65 189.94,151.22 UV20.H1
  TOP w0.381: RV161.2 RV171.1 CV231.1 189.94,151.65
VREFD_Q3_B: length 6.7
  BOTTOM w0.102: RV187.2 203.1,115.79 v2(203.29,115.99)
  BOTTOM w0.254: v3(206.1,113.59) 206.47,113.22 UV24.H1
  BOTTOM w0.508: v3(206.1,113.59) 205.68,113.17 CV279.1 RV195.1 RV187.2
VREFD_Q4: length 6.4
  BOTTOM w0.102: v2(186.38,141.26) 186.51,141.13 RV163.2
  BOTTOM w0.254: UV21.H1 189.2,144.08 189.2,143.31 189.24,143.27
  BOTTOM w0.508: 189.24,143.27 CV233.1 RV173.1 RV163.2
VREFD_Q4_B: length 7.8
  TOP w0.102: v2(218.65,110.69) 216.86,110.69 RV189.2
  TOP w0.254: UV25.H1 213.13,113.05 213.5,113.05
  TOP w0.381: 213.5,113.05 CV281.1 RV197.1 RV189.2
VTTREF_1.35V: length 4.3
  BOTTOM w0.102: v2(159.21,30.17) 159.21,28.68 PC210.1
  BOTTOM w0.203: 159.23,27.58 159.23,27.26 158.91,26.94 PU200.4
  BOTTOM w0.254: 159.23,27.58 159.67,28.03 PC210.1
WEA0#: length 40.6
  TOP w0.102: v1(174.91,127.96) 174.08,128.79 174.08,131.72 173.81,131.99 173.81,135.39 ; UV18.L3 170.99,146.16 171.6,146.77 171.6,147.63 v1(170.99,148.24) ; v1(174.45,143.59) 174.38,143.65 172.54,143.65
  TOP w0.127: 172.54,143.65 169.88,143.65 169.8,143.57 169.8,141.96 169.92,141.84 170.18,141.84 170.3,141.96 170.3,142.89 170.43,143.02 170.69,143.02 170.81,142.89 170.81,141.96 170.94,141.84 171.19,141.84 171.32,141.96 171.32,142.89 171.45,143.02 172.29,143.02 172.42,142.89 172.42,140.12 172.5,140.03 172.5,138.27 172.78,137.99 172.78,137.19 172.95,137.02 172.95,136.7 173.81,135.84 173.81,135.39
  IN1 w0.102: v1(170.99,148.24) 171.57,147.66 171.57,146.87 173.37,145.07 173.37,143.72 173.5,143.59 v1(174.45,143.59)
  BOTTOM w0.102: v1(170.99,148.24) 170.99,148.11 170.91,148.03 170.52,148.03 170.39,148.15 170.39,148.67 170.52,148.8 170.86,148.8 170.99,148.92 UV19.L3 ; UV1.K26 174.44,127.49 v1(174.91,127.96)
WEA1#: length 41.3
  TOP w0.102: v1(187.18,147.02) 186.57,147.63 186.57,148.54 187.18,149.15 UV20.L3 ; 184.61,134.55 184.19,134.55 184.07,134.42 184.07,126.3 v1(184.12,126.25)
  TOP w0.127: 184.61,134.55 185.46,134.55 185.59,134.68 185.59,135.21 185.46,135.34 184.86,135.34 184.73,135.46 184.73,135.97 184.86,136.09 185.04,136.09 185.17,136.22 185.17,136.48 185.04,136.6 184.8,136.6 184.67,136.73 184.67,137.05 184.8,137.18 185.02,137.18 185.14,137.3 185.14,137.56 185.02,137.68 184.34,137.68 184.21,137.81 184.21,138.11 184.34,138.24 185.37,138.24 185.5,138.37 185.5,138.62 185.37,138.75 v2(184.73,138.75) 184.19,138.75 184.07,138.87 184.07,139.13 184.19,139.25 184.99,139.25 185.12,139.38 185.12,139.64 184.99,139.76 183.71,139.76 183.59,139.89 183.59,143.34 183.46,143.46 183,143.46 182.87,143.34 v1(182.87,142.17)
  IN1 w0.102: 184.77,142.86 185.56,143.65 185.56,145.37 187.18,146.99 v1(187.18,147.02)
  IN1 w0.14: v1(182.87,142.17) 184.08,142.17 184.77,142.86
  BOTTOM w0.102: UV1.L15 183.67,126.69 v1(184.12,126.25) ; v1(187.18,147.02) 187.18,147.17 187.31,147.3 187.65,147.3 187.78,147.17 187.78,146.64 187.65,146.51 187.1,146.51 186.98,146.38 186.98,146.18 187.1,146.05 UV21.L3
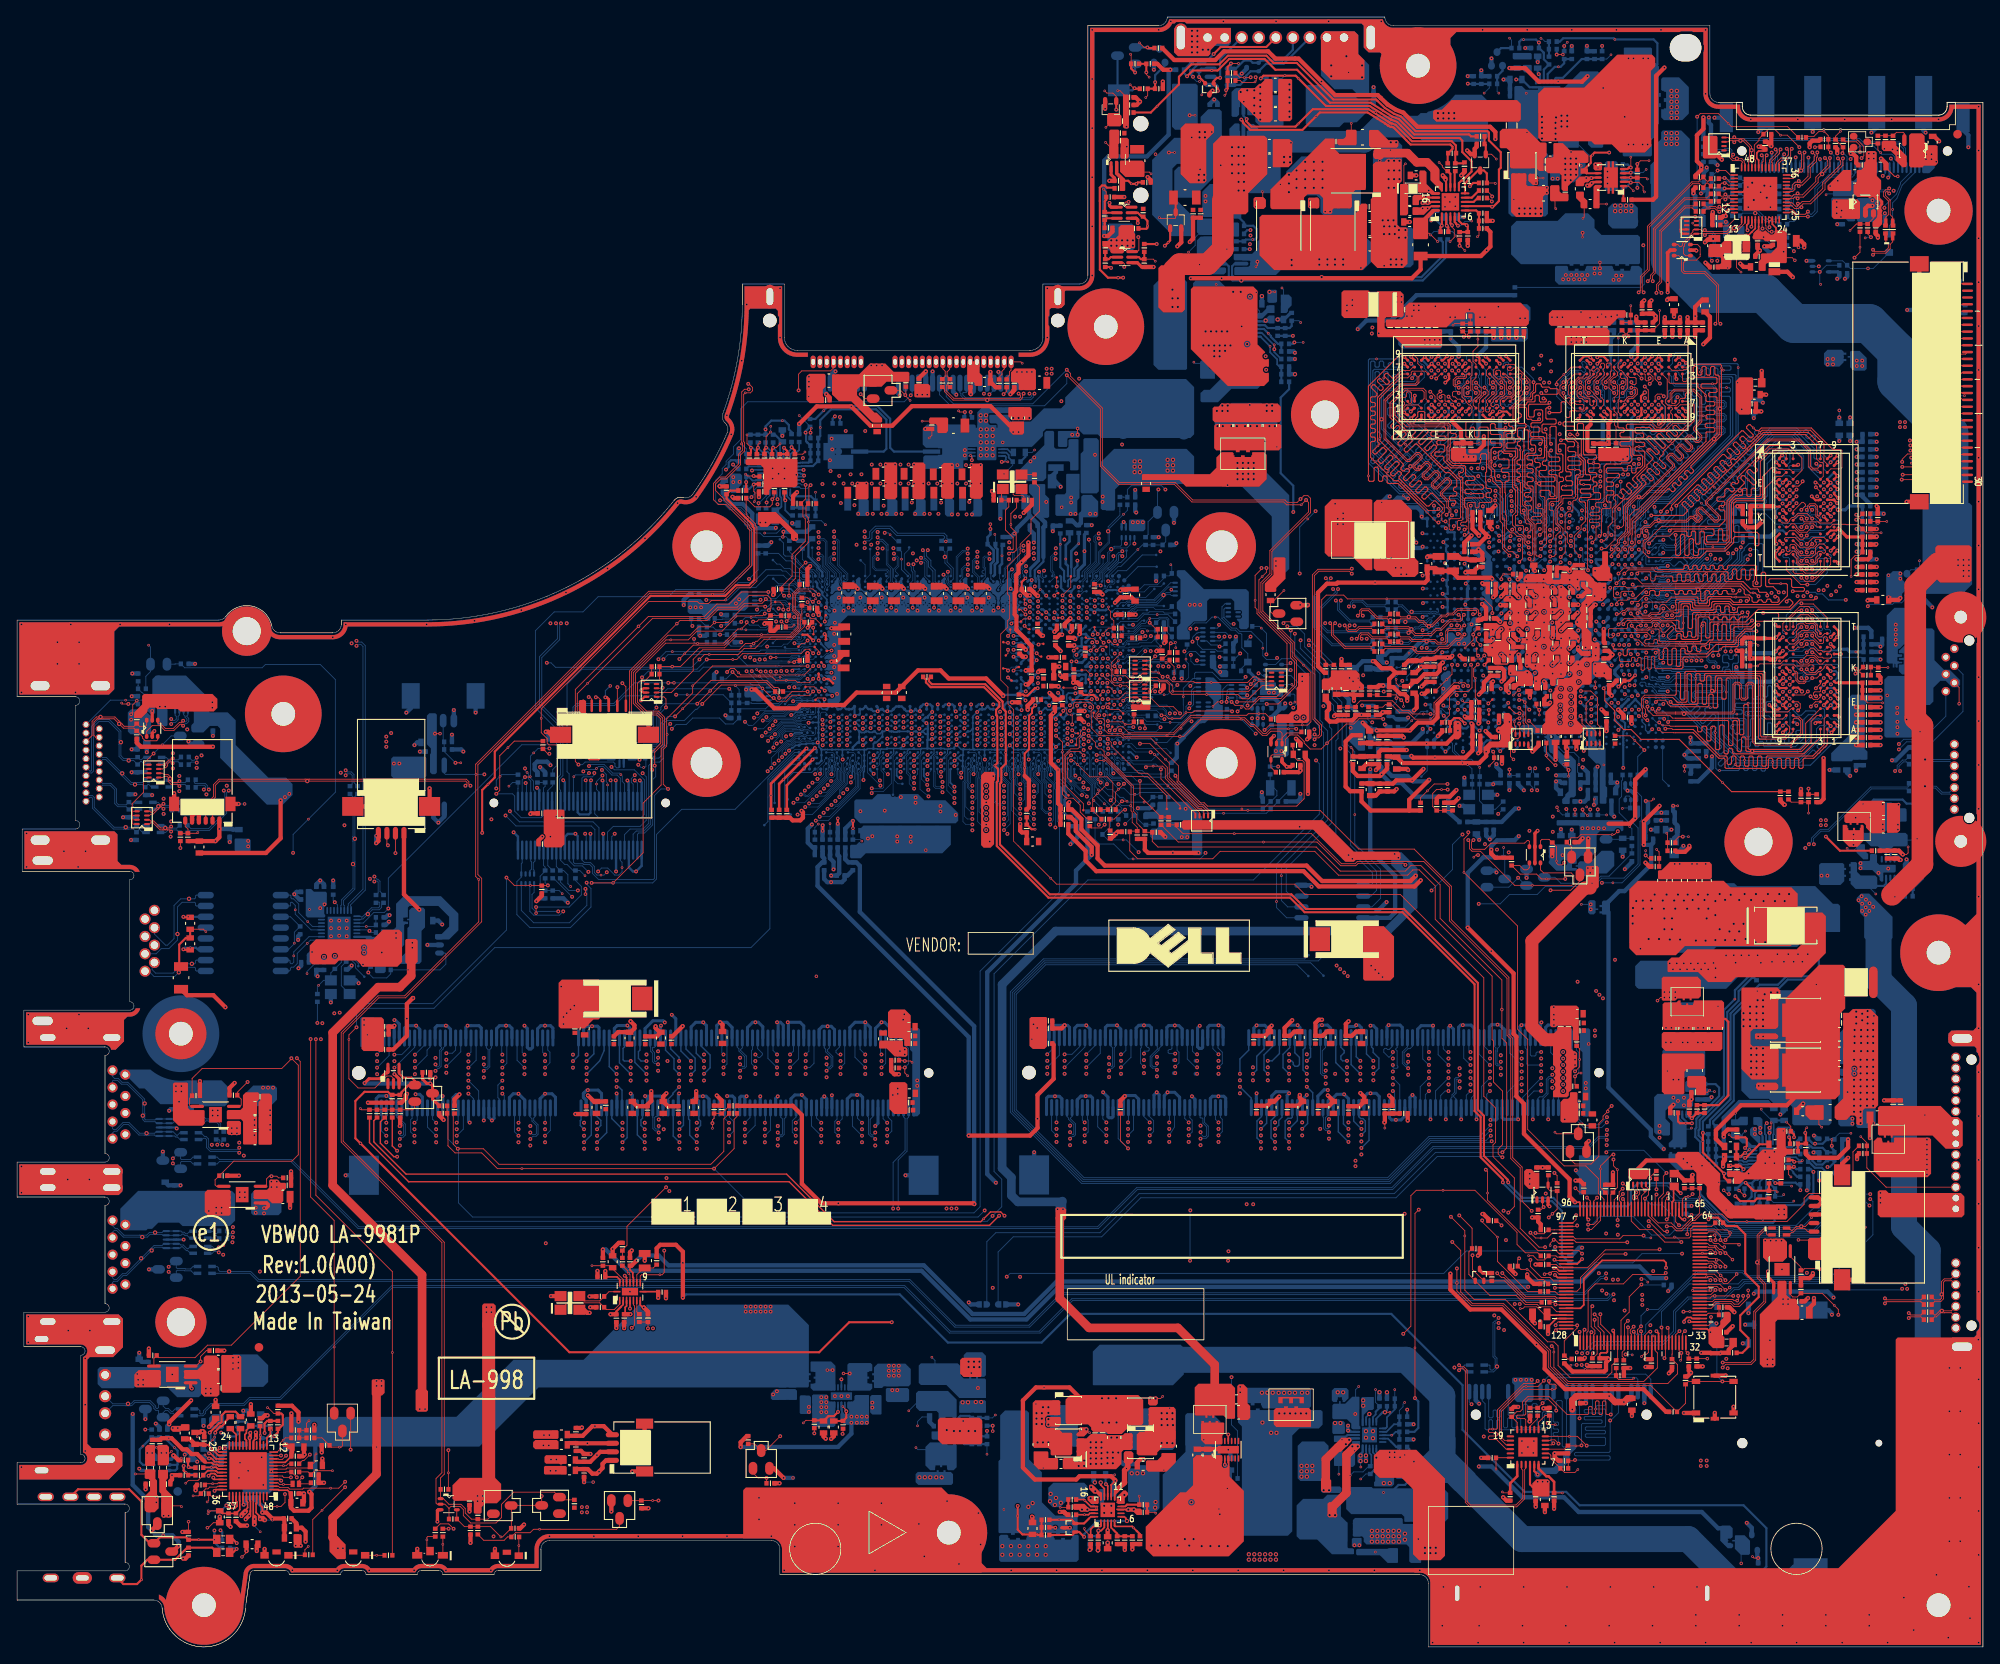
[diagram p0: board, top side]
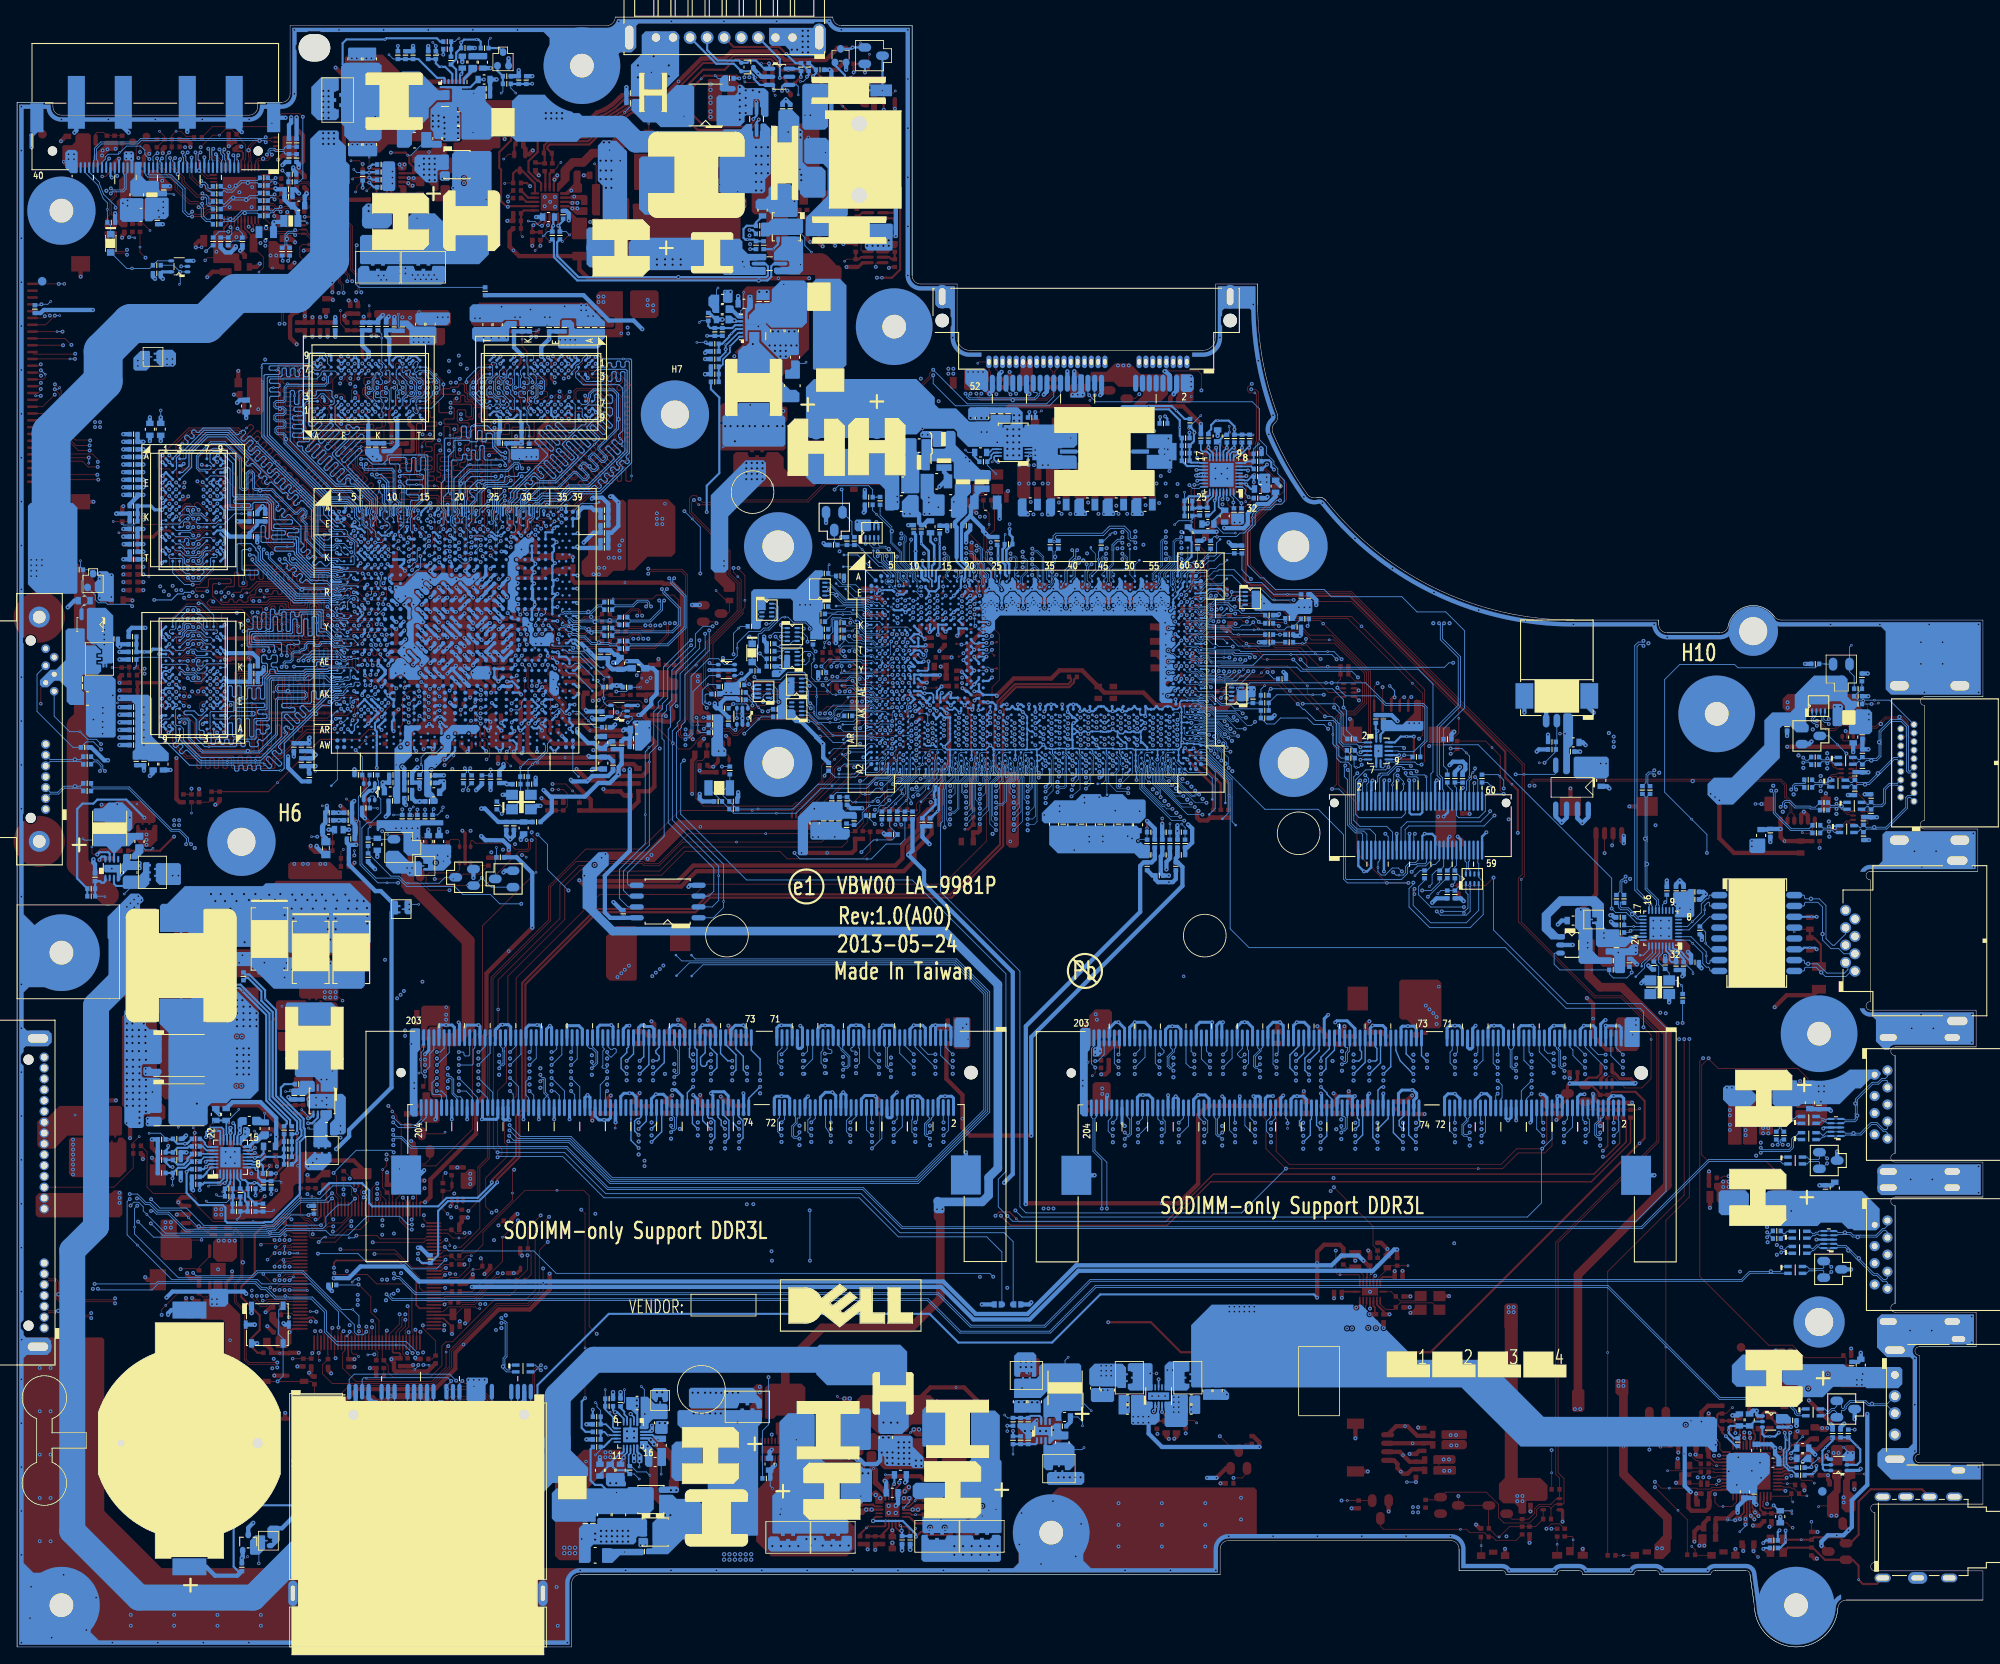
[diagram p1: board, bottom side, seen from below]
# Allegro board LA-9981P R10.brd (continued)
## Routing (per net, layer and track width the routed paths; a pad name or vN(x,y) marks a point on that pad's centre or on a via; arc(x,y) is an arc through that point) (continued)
WEB0#: length 40.9
  TOP w0.102: UV22.L3 208.25,131.3 208.86,130.69 209.78,130.69 v1(210.39,131.3) ; 194.39,124.64 190.48,124.64 189.88,125.24 187.98,125.24 v1(187.45,124.71)
  TOP w0.127: v1(204.1,123.19) 203.7,123.59 v2(203.47,123.59) 203.14,123.59 202.08,124.64 194.39,124.64
  IN1 w0.102: v1(210.39,131.3) 209.8,130.72 208.97,130.72 207.17,128.92 206.08,128.92 205.38,128.22 205.38,126.87 204.96,126.45
  IN1 w0.14: 204.96,126.45 204.3,125.79 204.3,124.1 203.56,123.36 203.56,120.86 203.68,120.73 203.98,120.73 204.1,120.86 v1(204.1,123.19)
  BOTTOM w0.102: v1(210.39,131.3) 210.25,131.3 210.13,131.43 210.13,131.77 210.25,131.9 210.77,131.9 210.9,131.77 210.9,131.43 211.02,131.3 UV23.L3 ; UV1.N10 187.26,124.9 v1(187.45,124.71)
WEB1#: length 44
  TOP w0.102: v1(209.12,115.62) 209.73,116.23 210.64,116.23 211.25,115.62 UV25.L3
  TOP w0.127: v1(204.08,119.84) 203.79,119.84 203.3,119.35 202.48,119.35 201.48,118.34 201.48,117.75 201.27,117.54 199.13,117.54 198.02,116.43 195.61,116.43 195.49,116.56 195.49,116.97 195.36,117.09 195.11,117.09 194.98,116.97 194.98,115.08 194.85,114.96 194.6,114.96 194.47,115.08 194.47,116.97 194.34,117.09 194.09,117.09 193.96,116.97 193.96,115.27 193.84,115.14 193.58,115.14 193.45,115.27 193.45,116.97 193.33,117.09 193.07,117.09 192.95,116.97 v2(192.95,116.6) 192.95,115.91 192.82,115.78 192.57,115.78 192.44,115.91 192.44,116.86 192.31,116.99 188.8,116.99 188.71,116.9 188.71,116.35 188.59,116.22 188.35,116.22 188.23,116.35 188.23,116.93 188.16,116.99 187.19,116.99 187.07,117.12 v1(187.07,117.47)
  IN1 w0.102: v1(209.12,115.62) 209.09,115.62 207.47,117.24 205.75,117.24 204.96,118.03
  IN1 w0.14: v1(204.08,119.84) 204.3,119.63 204.3,118.69 204.96,118.03
  BOTTOM w0.102: UV1.AB11 186.85,117.69 v1(187.07,117.47) ; UV24.L3 208.48,115.62 208.61,115.49 208.61,115.15 208.74,115.02 209.25,115.02 209.38,115.15 209.38,115.49 209.25,115.62 v1(209.12,115.62)
WL_BT_LED: length 125
  TOP w0.102: v1(75.17,17.17) v2(74.49,17.17) RD50.1 73.16,17.16 QD20.2 ; v1(183.12,36.94) 183.19,36.88 UE1.1
  IN3 w0.127: v1(183.12,36.94) 181.97,36.94 180.31,38.61 174.23,38.61 173.54,39.29 172.34,39.29 171.73,38.68 100.91,38.68 90.06,27.83 90.06,24.33 82.9,17.17 v1(75.17,17.17)
WL_BT_LED#: length 18.5
  TOP w0.102: RD51.2 54.69,12.51 57.09,12.51 57.48,12.9 RD18.1 58.42,13.4 60.13,13.4 60.52,13.79 v2(61.24,13.79) 70.25,13.79 70.62,14.16 QD20.1
WL_BT_LED#_EC: length 180.3
  TOP w0.102: v1(195.75,48.4) 195.75,49.11 196.35,49.71 UE1.64 ; UD1.4 RD49.2 52.43,14.11 RD52.1 RD51.1 55.49,14.11 v2(56.7,12.9) 56.9,12.9 RD46.2 57.93,13.93 57.93,16.56 QD18.1 57.92,16.6 QD19.1 v1(61.48,17.69)
  IN2 w0.127: v1(190.48,40.1) 193.16,40.1 195.75,42.7 v1(195.75,48.4)
  IN3 w0.127: v1(61.48,17.69) 61.24,17.93 61.24,34.68 62.68,36.12 90.85,36.12 93.93,39.2 171.48,39.2 172.08,39.8 173.75,39.8 174.44,39.11 182.6,39.11 183.91,40.42 185,40.42 185.73,39.7 187.59,39.7 188,40.1 v1(190.48,40.1)
WL_BT_LED#_EC2: length 170.1
  TOP w0.102: UE1.74 191.99,52.89 v1(192.14,53.05) ; v1(50.55,23.07) v2(50.55,20.42) RD48.2
  IN2 w0.127: v1(192.14,53.05) 192.14,47.98 190.92,46.76 190.92,41.15 v1(190.47,40.69)
  IN3 w0.127: v1(50.55,23.07) 50.55,27.06 59.86,36.37 90.74,36.37 93.83,39.46 171.34,39.46 171.95,40.07 173.84,40.07 174.54,39.37 182.49,39.37 183.8,40.68 185.11,40.68 185.83,39.95 187.49,39.95 188.23,40.69 v1(190.47,40.69)
WL_LED#: length 204.8
  TOP w0.102: QD18.3 55.19,14.98 RD45.2 53.25,14.98 52.53,15.71 52.53,16.22 52.02,16.72 50.63,16.72 49.96,17.39 UD1.1 49.63,17.39 RD48.1 49.63,19.82 50.07,20.26 50.07,47.45 38.22,59.3 38.22,71.94 42.39,76.11 45.53,76.11 54.45,85.03 54.45,90.12 54,90.56 54,103.43 74.12,123.54 82.86,123.54 86.1,126.77 86.1,131.04 85.88,131.25 85.88,131.47 83.41,133.94 82.85,134.5 82.85,134.61 81.85,135.6 81.85,136.34 82.46,136.94 83.12,136.94 84.78,138.6 84.78,139.74 85.25,140.21 85.25,141.24 85.16,141.33 85.16,146.86 v2(85.33,147.04) 85.94,147.04 86.2,147.29 86.2,147.67 85.78,148.09 v1(85.69,148.09)
  IN3 w0.127: v1(85.69,148.09) 91.79,148.09 92.57,147.31 112.94,147.31 v1(113.31,146.93)
  BOTTOM w0.102: v1(113.31,146.93) 113.31,146.94 113.32,146.94 113.7,147.32 JMINI.44
WL_OFF#: length 80.2
  TOP w0.089: v1(132.82,115.01) 132.7,115.13 RP54.3 ; v1(127.87,104.7) v2(128.71,104.7)
  TOP w0.102: QM30.3 99.39,146.37 v1(98.87,146.89)
  IN2 w0.089: v1(127.87,104.7) 127.35,105.22 127.35,108.66 128.24,109.55 128.24,110.29 128.2,110.32 128.2,110.63 128.42,110.85 128.71,110.85 129.7,111.83 129.7,113.72 129.7,113.87 130.33,114.5 132.31,114.5 v1(132.82,115.01) 132.82,115.19 131.41,116.6 131.41,117.61 129.91,119.11 129.91,124.68 124.97,129.62 124.97,133.14
  IN2 w0.127: 124.97,133.14 125.63,133.8 125.63,144.79 122.52,147.9 116.55,147.9 116.49,147.97 99.95,147.97 v1(98.87,146.89)
  BOTTOM w0.089: v1(127.87,104.7) 127.38,105.19 UC1.AT5
WLAN_CLKREQ#: length 107.9
  TOP w0.089: v1(127.82,114.94) 128.25,114.51 128.25,113.36 128.56,113.05 130,113.05 130.07,113.11 131.51,113.11 131.51,113.11 131.82,113.11 132.04,113.33 132.04,113.42 132.3,113.68 133.62,113.68 133.96,113.34 134.78,113.34 135.45,112.67 v2(135.45,112.05) 137.92,112.05
  TOP w0.102: 137.92,112.05 144.33,112.05 145.52,113.24 RP42.7 ; v1(91.6,147.33) 91.6,149.24 91.98,149.62 95.34,149.62 95.7,149.97 JMINI.7
  IN1 w0.084: v1(131.89,119) 131.28,118.39 131.28,116.34 130.46,115.52 128.4,115.52 v1(127.82,114.94)
  IN2 w0.089: 124.72,133.14 124.72,133.04 124.72,129.62 124.9,129.44 125.76,128.58 125.76,120.5 125.11,119.85 125.11,115.01 125.62,114.5 127.38,114.5 v1(127.82,114.94)
  IN2 w0.127: 124.72,133.14 124.72,133.25 125.38,133.91 125.38,144.69 122.44,147.62 100.49,147.62 99.33,146.47 96.59,146.47 95.72,147.33 v1(91.6,147.33)
  BOTTOM w0.089: UC1.N1 131,118.34 131.35,118.7 131.6,118.7 v1(131.89,119)
WLAN_RADIO_DIS#_R: length 5.2
  TOP w0.102: v2(104.66,146.16) 104.1,146.72 v1(104.1,146.78) ; v1(104.1,146.78) 103.55,147.33 QM30.1 ; v1(104.1,146.78) 104.17,146.85 RM110.2
  BOTTOM w0.102: JMINI.20 v1(104.1,146.78)
WOL_EN: length 208.3
  TOP w0.102: v1(182.85,49.41) 182.74,49.31 UE1.98
  IN1 w0.127: v1(41.16,79.08) 41.16,79.96 41.38,80.18 41.38,83.13 42.41,84.16 42.41,86.08 53.37,97.04 v1(55.59,97.04)
  IN3 w0.127: v1(55.59,97.04) 55.59,95.82 59.04,92.38 59.04,74.63 61.18,72.49 61.18,56.99 69.58,48.59 114.78,48.59 115.66,47.7 140.86,47.7 141.31,48.16 176.67,48.16 176.75,48.08 178.15,48.08 178.84,48.77 182.2,48.77 v1(182.85,49.41)
  BOTTOM w0.102: RL38.1 41.16,79.49 v1(41.16,79.08) 41.16,79.01 41.73,78.44 43.32,78.44 43.79,78.92 RL27.2 v2(45.82,79.39) 49.58,79.39 50.25,80.06 50.25,81.25 50.15,81.36 UL2.3
XDP_DBRESET#: length 23.1
  TOP w0.102: RC26.1 58.29,106.21 v2(57.53,105.45) 56.57,104.49 56.57,100.43 v1(56.16,100.02)
  BOTTOM w0.102: RC362.2 61.42,101.34 61.44,101.36 CC17.1 61.89,100.91 61.7,100.72 JXDP1.48 61.7,97.5 61.43,97.23 59.08,97.23 58.32,97.99 58.32,99.77 58.07,100.02 v1(56.16,100.02)
XDP_OBS0_R: length 67.1
  IN3 w0.127: v1(84.88,120.19) 84.88,119.32 83.07,117.51 79.15,117.51 78.41,118.25 68.72,118.25 57.77,107.29 57.77,97.98 v1(57.76,97.99)
  BOTTOM w0.076: UC1.J60 93.31,120.3 92.83,120.3 92.79,120.34 92,120.34 91.84,120.17 91.34,120.17 91.34,120.17 90.86,120.17 90.56,120.47 90.56,120.47 90.37,120.67 88.37,120.67
  BOTTOM w0.102: v1(57.76,97.99) 57.76,97.86 58.88,96.74 67.51,96.74 68.2,96.05 JXDP1.21 ; 88.37,120.67 86.69,120.67 86.65,120.7 v2(86.03,120.7) 85.35,120.7 84.88,120.23 v1(84.88,120.19) 84.71,120.03 RC141.1
XDP_OBS1_R: length 67.6
  IN1 w0.127: v1(82.52,119.71) 82.81,119.42 90.35,119.42 91.53,120.6 92.93,120.6 v1(93.31,120.98)
  IN3 w0.127: v1(57.25,97.48) 57.25,107.5 69.73,119.99 78.03,119.99 78.9,119.11 81.92,119.11 v1(82.52,119.71)
  BOTTOM w0.089: UC1.H60 93.6,121.27 v1(93.31,120.98)
  BOTTOM w0.102: v1(57.25,97.48) 58.48,96.26 67.3,96.26 67.72,95.83 67.72,93.45 JXDP1.23 ; RC141.2 83.01,119.84 82.64,119.84 v1(82.52,119.71)
XDP_PRDY#: length 48.3
  TOP w0.102: v1(87.63,121.16) 87.39,120.91 86.55,120.91 86.52,120.88 84.39,120.88 82.61,119.1 79.68,119.1 78.66,118.08 v2(76.61,118.08) 76.07,118.08 72.23,114.23 72.23,110.62 73.58,109.27 74.98,109.27 75.43,108.81 75.43,105.93 74.27,104.77 74.27,103 v1(74.44,102.83)
  BOTTOM w0.076: UC1.J62 92.06,120.63 91.77,120.34 91.27,120.34 91.27,120.34 90.93,120.34 90.73,120.54 90.73,120.54 90.44,120.83 90.43,120.83 90.38,120.89 88.96,120.89
  BOTTOM w0.102: JXDP1.5 72.2,95.3 72.57,95.67 73.45,95.67 74.26,96.47 74.26,102.65 v1(74.44,102.83)
  BOTTOM w0.109: v1(87.63,121.16) 87.72,121.16 87.73,121.15 88.69,121.15 88.96,120.89
XDP_PREQ#: length 52.2
  TOP w0.102: v1(74.73,103.34) 74.73,104.9 75.66,105.83 75.66,108.91 75.07,109.5 73.68,109.5 72.47,110.7 72.47,114.15 76.01,117.69 82.82,117.69 84.49,119.36 v2(84.9,119.36) 84.9,119.37 85.47,119.94 85.47,120.11 v1(85.51,120.15)
  IN3 w0.127: v1(87.14,122.77) 86.16,122.77 85.51,122.12 v1(85.51,120.15)
  BOTTOM w0.076: UC1.K62 91.85,119.43 91.85,119.43 91.84,119.42 91.35,119.42 91.09,119.67 90.66,119.67 90.62,119.71 87.95,119.71 87.75,119.51 87.16,119.51 86.86,119.81
  BOTTOM w0.102: RP44.3 87.06,122.7 v1(87.14,122.77) ; 86.86,119.81 85.86,119.81 v1(85.51,120.15) ; JXDP1.3 72.7,95.28 72.86,95.44 73.55,95.44 74.49,96.38 74.49,101.7 74.84,102.06 74.84,103.22 v1(74.73,103.34)
XDP_RST#_R: length 2.4
  BOTTOM w0.102: JXDP1.46 62.2,100.41 62.78,100.99 RC51.2
XDP_TCK: length 28
  TOP w0.089: 86.76,117.91 87.17,118.32 90.72,118.32 91.8,119.41 91.8,121.06 91.23,121.64 91.23,123.34 91.68,123.8 92.91,123.8 v1(93.37,123.34)
  TOP w0.102: RP45.2 76.68,111.9 79.24,114.47 79.24,115.8 80.36,116.92 84.63,116.92 85.36,117.64 v4(86.32,117.64) 86.59,117.91 86.76,117.91
  BOTTOM w0.076: v1(93.37,123.34) 93.6,123.1 UC1.E60
XDP_TCLK: length 56.7
  IN3 w0.127: v1(66.76,89.61) 66.51,89.85 66.51,91.77 67.88,93.14 67.88,96.93 70.85,99.89 70.85,102.25 71.6,103 71.6,106.98 71.75,107.12 71.75,108.07 73.34,109.66 73.5,109.66 75.33,111.49 76.48,111.49 76.64,111.64 v1(77.24,111.64)
  BOTTOM w0.102: JXDP1.57 59.2,91.94 59.1,91.83 RP46.5 59.1,90.26 58.58,89.74 58.58,85.86 60.1,84.34 64.85,84.34 67.26,86.75 67.26,88.93 66.76,89.43 v1(66.76,89.61) ; RC65.1 RC59.2 82.76,111.64 v2(78.54,111.64) v1(77.24,111.64)
XDP_TDI: length 37
  TOP w0.102: v1(72.96,104.02) 71.77,105.2 71.77,114.42 77.33,119.98 ; v4(77.33,119.98) 77.33,119.98 ; 77.33,119.98 77.69,120.34 80.87,120.34 82.2,121.68 84.54,121.68 85.24,122.37 87.31,122.37 87.76,122.82 v1(87.76,122.86)
  BOTTOM w0.076: 88.91,122.66 90.1,122.66 90.41,122.35 90.66,122.35 91.01,122 91.52,122 UC1.F63
  BOTTOM w0.102: v1(72.96,104.02) 72.92,104.06 UC4.6
  BOTTOM w0.109: RP44.2 87.42,123.2 87.76,122.86 v1(87.76,122.86) 87.76,122.85 87.94,122.66 88.91,122.66
XDP_TDO: length 43.4
  TOP w0.102: v1(87.68,121.97) 87.6,122.05 85.24,122.05 83.31,120.11 v4(81.74,120.11) 81.24,119.61 79.87,119.61 78.88,118.62 76.29,118.62 72,114.33 72,106.44 v1(72.96,105.48) ; v1(76.05,110.16) 76.05,111.15 75.8,111.4 RP45.1
  BOTTOM w0.076: 88.91,122.43 90.01,122.43 90.25,122.18 90.6,122.18 90.94,121.84 91.77,121.84 92.06,122.13 UC1.F62
  BOTTOM w0.102: v1(76.05,110.16) 76.05,110.15 75.24,109.33 75.24,106.15 74.94,105.85 73.38,105.85 73.02,105.48 v1(72.96,105.48) 72.88,105.56 UC4.3
  BOTTOM w0.109: v1(87.68,121.97) 87.99,121.97 88.45,122.43 88.91,122.43
XDP_TMS: length 49.9
  TOP w0.102: v1(65.79,103.45) 65.43,103.82 65.43,112.27 v4(72.83,119.67) 73.99,120.83 80.57,120.83 82.02,122.27 83.47,122.27 84.89,123.7 v1(88.05,123.7)
  BOTTOM w0.076: 89.41,123.36 89.79,123.74 90.55,123.74 91.03,123.25 91.79,123.25 91.85,123.19 92.4,123.19 92.67,122.91 UC1.E61
  BOTTOM w0.089: 88.91,122.9 88.94,122.9 89.41,123.36
  BOTTOM w0.102: RP44.1 v1(88.05,123.7) 88.05,123.25 88.41,122.9 88.91,122.9 ; v1(65.79,103.45) 66.27,103.45 66.57,103.75 69.9,103.75 70.07,103.58 70.07,103.26 70.26,103.07 70.45,103.07 70.6,103.22 UC4.8
XDP_TRST#: length 49.7
  TOP w0.089: 86.76,118.44 86.96,118.44 87.02,118.5 90.64,118.5 91.62,119.48 91.62,120.99 91.05,121.56 91.05,123.41 91.69,124.05 93.28,124.05 v1(93.95,123.38)
  TOP w0.102: 86.76,118.44 84.21,118.44 82.92,117.15 79.95,117.15 77.75,114.95 v4(76.78,114.95) RC57.1 R2341.1 75.29,113.49 75.66,113.12 v1(75.66,112.47) 75.59,112.4 RP45.3
  BOTTOM w0.076: v1(93.95,123.38) 94.25,123.08 UC1.E59
  BOTTOM w0.102: v1(75.66,112.47) 74.7,111.52 71.15,111.52 70.04,110.4 65.69,110.4 65.4,110.11 65.4,106.28 66.7,104.98 68.47,104.98 68.55,105.06 UC4.11
XTAL24_IN: length 18.1
  TOP w0.102: RG6.2 YC2.3 116.74,136.48 116.74,135.14 116.89,134.99 117.88,134.99 118.01,134.87 CC6.2 RC12.2 117.15,133.56 116.48,132.89 v2(116.48,131.61) 116.48,131.28 117.1,130.66 117.1,128.6 116.82,128.32 116.39,128.32 v1(116.26,128.19)
  BOTTOM w0.076: UC1.A25 115.69,125.69 115.69,126.45 116.69,127.45 116.69,128.31 116.55,128.44 116.51,128.44 v1(116.26,128.19)
XTAL24_OUT: length 13.9
  TOP w0.102: v1(116.26,128.83) 116.42,128.66 116.68,128.66 116.74,128.73 116.74,130.07 115.85,130.96 115.85,133.3 116.23,133.68 RC12.1 CC7.2 115.37,135.61 YC2.1
  BOTTOM w0.076: UC1.B25 115.56,125.15 115.86,125.44 115.86,126.38 116.85,127.37 116.85,128.38 116.62,128.61 116.48,128.61 v1(116.26,128.83)
XTALIN: length 12.1
  BOTTOM w0.102: RG7.2 173.26,98.21 YV1.1 171.4,99.2 CV95.1 171.43,101.18 RV97.1 v2(171.43,103.11) 170.46,104.08 169.47,104.08 168.47,105.08 168.47,105.69 UV1.AV33
XTALIN_R: length 167.3
  TOP w0.102: v1(76.06,53.9) 71.48,49.31 71.48,47.09 70.95,46.56 CG11.1 RG4.2
  IN3 w0.127: v1(76.06,53.9) 81.89,53.9 82.58,54.58 104.5,54.58 105.53,55.61 117.3,55.61 118.7,54.22 172.89,54.22 174.1,55.43 174.81,55.43 177,57.62 179.85,57.62 187.87,65.64 187.87,77.62 182.59,82.9 182.59,87.78 177.57,92.8 177.57,94.14 175.73,95.98 175.24,95.98 173.59,97.64 v1(173.59,97.67)
  BOTTOM w0.102: RG7.1 174.12,98.21 v1(173.59,97.67)
XTALOUT: length 7.8
  BOTTOM w0.102: YV1.3 170.54,100.26 CV94.1 170.54,102.02 RV97.2 170.51,102.96 v2(169.99,103.48) 169.62,103.85 169.38,103.85 168.24,104.99 168.24,105.92 UV1.AU34
XTLI: length 7.5
  BOTTOM w0.102: RG8.2 35.2,77.43 v2(35.34,77.58) 35.92,78.15 YL2.1 36.77,79.03 CL36.2 38,80.26 38,80.88 37.55,81.34 UL1.29
XTLI_R: length 69.7
  TOP w0.102: RG5.2 CG7.1 v1(73.94,37.35)
  IN1 w0.127: v1(35.2,73.16) 35.2,73.06 36.13,72.12 36.13,60.04 43.65,52.53 63.26,52.53 64.8,50.98 64.8,44.34 68.86,40.28 68.86,38.81 69.68,38 73.3,38 v1(73.94,37.35)
  BOTTOM w0.102: v1(35.2,73.16) RG8.1
XTLO: length 6.5
  BOTTOM w0.102: UL1.28 37.95,81.29 38.57,80.67 CL37.2 38,79.78 38,77.53 YL2.3
N60378: length 4.4
  BOTTOM w0.102: UV19.L8 170.64,144.91 170.64,143.4 170.38,143.15 v2(170.38,141.99) RV151.1
N60382: length 4.5
  TOP w0.102: RV152.1 187.4,143.09 187.21,143.28 187.21,143.72 187.53,144.03 187.53,144.56 187.18,144.91 UV20.L8
N60386: length 4.7
  BOTTOM w0.102: RV153.1 187.66,153.93 v2(187.66,153.46) 187.66,150.7 187.18,150.23 UV21.L8
N60390: length 4.6
  TOP w0.102: RV150.1 v2(171.21,153.34) 171.21,152.48 170.64,151.91 170.64,150.75 170.99,150.4 UV18.L8
N60394: length 3
  TOP w0.102: v2(189.13,157.26) CV234.1 189.13,155.36 RV165.2 RV164.2
N60402: length 3
  TOP w0.102: CV225.1 170.32,156.02 RV155.2 RV154.2 168.47,155.16 v2(168.29,154.98)
N65637: length 4.8
  BOTTOM w0.102: UV23.L8 207.18,131.3 206.83,131.65 206.13,131.65 204.93,132.86 v2(204.07,132.86) RV177.1
N65641: length 5.7
  BOTTOM w0.102: v2(216.68,114.73) 216.41,115 RV178.1 216.15,116.03 212.57,116.03 UV24.L8
N65645: length 4.5
  TOP w0.102: RV179.1 v2(204,115.02) 204.25,115.27 206.66,115.27 207.01,115.62 UV25.L8
N65649: length 6.9
  TOP w0.102: v2(218.47,130.63) 217.53,130.63 217.52,130.62 216.74,130.62 RV176.1 215.78,131.58 214.37,131.58 214.33,131.63 212.82,131.63 212.5,131.3 UV22.L8
N65653: length 3
  TOP w0.102: v2(219.26,114.84) CV273.1 217.71,114.84 217.66,114.89 RV180.2 RV181.2
N65661: length 2.8
  TOP w0.102: RV175.2 RV174.2 217.61,131.97 217.62,131.96 CV272.1 v2(219.13,131.96)
N14128350: length 3
  TOP w0.102: PU1100.1 188.87,171.29 v2(189.42,170.73)
  TOP w0.254: PU1100.1 188.26,169.72 PR1110.2
N16988653: length 4
  BOTTOM w0.102: PC605.1 217.14,88.99 v2(217.84,88.28)
  BOTTOM w0.254: PU600.3 219.04,89.49 218.79,89.23 217.83,89.23
N16988706: length 1.8
  BOTTOM w0.102: PR605.2 215.63,93.74 215.34,93.45 214.67,93.45 v2(214.48,93.64)
N17002462: length 8
  BOTTOM w0.102: PR1206.1 186.31,186.18 v2(186.81,186.68)
  BOTTOM w0.254: PU1200.1 180.29,183.89 180.37,183.97 181.17,183.97 183.38,186.18 PC1200.1 PR1201.1 PR1206.1
N17002482: length 8.6
  BOTTOM w0.254: PU1200.4 178.94,184.94 PR1209.1 178.94,186.15 178.94,186.89 178.92,186.91 178.92,186.94 178.39,187.47 PR1204.1 v1(178.36,188.12) 178.02,188.46 v2(176.56,188.46) 176.31,188.46 176.06,188.21 PR1211.1
N17002518: length 2.9
  BOTTOM w0.102: PR1208.2 179.08,188.22 178.77,188.54 178.66,188.54 v2(178.6,188.6)
  BOTTOM w0.254: PR1209.2 179.54,187.32 PR1210.1 PR1208.2
N17045846: length 1.1
  BOTTOM w0.102: PR802.2 v2(201.39,62.57)
N17045965: length 2.2
  BOTTOM w0.203: PU800.28 207.67,56.21 208.18,55.7 208.18,55.57
  BOTTOM w0.254: PR842.1 208.63,55.13 208.18,55.57
N17045986: length 12.4
  TOP w0.102: v2(206.29,53.35) 206.15,53.49 PR820.1
  TOP w0.254: PC813.2 PR820.1 203.52,53.49 v1(202.59,54.42)
  BOTTOM w0.203: PU800.7 204.19,54.94 203.99,54.75 203.67,54.75
  BOTTOM w0.254: PC817.2 202.44,51.97 PR813.2 203.29,52.79 203.29,53.66 PR846.1 203.37,54.29 203.29,54.37 ; 203.29,54.37 202.64,54.37 v1(202.59,54.42) 202.25,54.42 201.55,53.72 PC809.2 ; 203.29,54.37 203.67,54.75
N17046050: length 4.5
  TOP w0.102: v2(200.65,60.06) 200.96,59.75 PR824.2
  TOP w0.254: PR824.2 202.55,59.75 202.72,59.58 202.72,58.71 v1(202.52,58.51)
  BOTTOM w0.203: PU800.13 202.87,58.21 202.58,58.51 v1(202.52,58.51)
N17046121: length 7.6
  TOP w0.102: v1(205.39,60.86) 205.58,61.05 v2(205.58,61.45)
  IN3 w1.016: 206.28,60.65 206.59,60.65 207.55,61.61 212.82,61.61
  vias: v1(205.39,60.27) v1(215.1,61.94) v1(215.1,61.35) v1(215.33,67.8) v1(215.33,67.22)
N17046167: length 7
  TOP w0.254: PR833.1 PC816.2 201.95,56.41 v1(202.34,56.02)
  BOTTOM w0.102: v2(199.44,54.47) 199.6,54.63 PR845.1
  BOTTOM w0.203: v1(202.34,56.02) 202.54,56.21 PU800.8
  BOTTOM w0.254: PR845.1 PC809.1 201.72,54.63 202.15,55.07 202.15,55.83 v1(202.34,56.02)
N17159315: length 13.1
  IN3 w0.102: v1(165.21,117.13) 164.73,116.65 164.36,116.65
  IN3 w0.127: v1(160.17,112.02) 160.68,112.53 160.68,112.97 164.36,116.65
  BOTTOM w0.102: UV1.AB34 167.52,117.34 165.43,117.34 v1(165.21,117.13) ; v2(157.35,112.53) RV84.1 159.02,112.02 v1(160.17,112.02)
N17216117: length 10.2
  TOP w0.102: RV89.2 181.64,103.01 v1(181.83,102.82) v2(181.83,102.09)
  IN3 w0.102: v1(180.87,109.81) 180.62,109.81 180.39,109.58 180.39,105.74 181.83,104.3 181.83,103.86
  IN3 w0.127: 181.83,103.86 v1(181.83,102.82)
  BOTTOM w0.102: v1(180.87,109.81) 180.91,109.85 181.11,109.85 UV1.AM17
N17407779: length 3.3
  TOP w0.102: R2354.1 187.42,31.84 CE12.1 187.4,31.65 187.71,31.35 189.32,31.35 v2(189.48,31.51)
N17434554: length 4.9
  TOP w0.102: UE1.107 180.5,45.71 180.35,45.86 RE36.2 179.01,45.38 178.18,45.38 177.69,45.87 v2(177.16,45.87)
N17434577: length 8.3
  TOP w0.102: RE7.2 192.12,53.67 192.13,53.66 v1(192.14,53.66) ; UE1.66 195.19,52.51 195.5,52.82 v2(195.85,52.82) 196.1,52.82 v1(196.37,53.1)
  IN3 w0.127: v1(192.14,53.66) 195.81,53.66 v1(196.37,53.1)
N17438484: length 4.2
  TOP w0.102: R2355.2 34.12,20.52 CA21.1 34.89,20.66 v2(36.96,20.66)
N17494823: length 6.2
  BOTTOM w0.254: RA3.2 29.19,24.47 29.79,25.08 v2(29.79,25.42) 29.79,25.76 29.64,25.92 CA1.1 CA2.1 26.83,26.43 QA5.2
N17607640: length 6.6
  BOTTOM w0.203: PU300.1 145.72,153.63 v2(146.85,152.49) 146.85,151.8 147.68,150.97 147.68,150.38 147.95,150.12 PC300.1
  BOTTOM w0.254: PR300.1 PR301.1 PC300.1
N17607660: length 5.8
  BOTTOM w0.102: v2(150.44,155.29) 150.23,155.5 PR307.1
  BOTTOM w0.254: PR307.1 149.39,154.88 149.15,154.64 PR305.2 PC307.2 146.58,154.64 146.24,154.98 PU300.4
N17608587: length 1.4
  BOTTOM w0.102: PC302.1 148.43,159.15 v2(148.25,159.34)
N17777752: length 31.9
  TOP w0.102: RV244.1 RV245.1 153.38,115.58 152.9,116.06 152.9,122.79 153.44,123.33 155.48,123.33 155.92,122.88 v2(160.54,122.88) 171.92,122.88 172.91,121.9 v1(172.91,121.22)
  BOTTOM w0.102: UV1.W29 172.26,120.49 UV1.V28 172.46,120.78 v1(172.91,121.22)
N17839157: length 5.8
  TOP w0.102: v1(171.2,115.2) 170.71,114.71 170.71,113.77 v2(170.91,113.58) 170.91,111.32 171.36,110.86 RV246.1
  BOTTOM w0.102: UV1.AF30 170.86,114.86 v1(171.2,115.2)
N17841799: length 10
  TOP w0.102: v1(170.4,115.16) 170.51,115.05 170.51,112.47 170.07,112.03 168.54,112.03 167.87,111.36 v2(167.87,110.01) 167.87,109.25 RV247.1
  BOTTOM w0.102: UV1.AF31 170.06,114.82 v1(170.4,115.16)
N18009245: length 5
  TOP w0.254: PU701.1 166.99,166.64 v1(166.98,166.64) 166.83,166.49 PC717.2
  BOTTOM w0.102: PR704.1 166.05,165.95 v2(165.65,165.55)
  BOTTOM w0.254: PC708.1 166.4,167.21 v1(166.98,166.64) 166.78,166.44 PR704.1
N18009258: length 32.2
  TOP w0.254: PC719.1 169.52,173.95 PR710.2 168.56,175.05 PC722.2 168.62,175.17 168.62,176.06 168.14,176.54 163.48,176.54 163.29,176.73 161.54,178.48 161.13,178.64 161.05,178.62 160.84,178.75 160.83,178.76 160.7,178.84 159.65,179.5 159.65,179.5 158.93,179.96 158.4,180.3 151.87,180.3 v2(150.13,178.56) 149.83,178.26 144.68,178.26 144.05,178.89 144.05,179.08 v1(144.11,179.14)
  BOTTOM w0.254: PR716.3 143.73,179.53 v1(144.11,179.14)
N18009264: length 0.7
  TOP w0.102: v1(145.37,162.42) 145.37,162 v2(145.19,161.82)
N18009271: length 5
  TOP w0.254: PU701.2 167.49,166.71 v1(167.56,166.63) 167.75,166.45 PC717.1
  BOTTOM w0.102: v2(168.73,165.42) 168.21,165.95 PR717.1
  BOTTOM w0.254: PR717.1 167.67,166.52 v1(167.56,166.63) 167.56,167.5 PC707.1
N18009295: length 31.2
  TOP w0.254: v1(143.48,179.08) 143.67,178.89 143.67,178.73 144.52,177.87 150.65,177.87 v2(152.24,179.46) 152.7,179.92 158.29,179.92 159.43,179.19 160.34,178.61 160.6,178.45 160.69,178.36 160.73,178.36 160.79,178.33 160.98,178.21 161.1,178.24 161.33,178.15 162.83,176.65 163.32,176.16 167.98,176.16 168.24,175.9 168.24,175.65 PC722.1 167.67,175.08 PR708.2
  BOTTOM w0.254: v1(143.48,179.08) 143.48,179.02 143.73,178.76 PR716.2
N18009369: length 2
  TOP w0.254: PU701.9 170.5,169.93 171.34,170.76 PR714.2
N18009411: length 1.4
  BOTTOM w0.102: PR706.1 148.24,183.91 v2(148.58,184.24)
N18009417: length 2
  TOP w0.102: v2(156.37,178.64) PR722.1 156.37,176.6
N18009452: length 3.6
  TOP w0.102: PQ708.2 172.81,175.01 v2(173.37,174.45)
  TOP w0.254: PQ708.2 172.13,176.09 PR724.2 PC723.1
N18009461: length 1.8
  TOP w0.254: PR715.2 171.16,169.87 170.72,169.43 PU701.8
N18107051: length 4.2
  BOTTOM w0.102: RV127.1 162.68,107.83 v2(163.45,108.6) 164.55,109.69 UV1.AM39
N18262754: length 4.7
  TOP w0.102: v1(168.17,115.15) 168.17,114.04 v2(167.56,113.42) RV207.1
  BOTTOM w0.102: UV1.AF33 168.17,114.78 v1(168.17,115.15)
N18284053: length 0.7
  TOP w0.102: v1(134.99,175.22) v2(135.65,175.22)
N18923200: length 2.3
  TOP w0.102: v1(204.05,10.42) 203.56,10.42 v2(203.39,10.6)
  BOTTOM w0.508: RC10.1 v1(204.05,10.42) 203.96,10.52 DC1.2
N19505504: length 1.6
  TOP w0.089: v1(128.63,111.97) 128.05,112.55 T117.1
  BOTTOM w0.076: v1(128.63,111.97) 128.33,112.27 UC1.AD4
N19607621: length 5.4
  BOTTOM w0.102: RX15.1 15.09,113.8 15.64,114.35 QX5.2 15.64,117.23 v2(15.42,117.45)
N19636367: length 6
  BOTTOM w0.254: QA6.2 14.76,21.35 14.38,21.73 14.38,23.18 v2(14.76,23.55) RA6.2 RA7.2
N19794620: length 6.1
  BOTTOM w0.254: 18.76,21.35 18.81,21.4 18.81,23.01 v2(18.45,23.37) 17.62,24.2 RA5.2 ; 18.76,21.35 QA6.5 ; 18.76,21.35 18.76,20.9 18.56,20.7 QA6.6
N21178712: length 1.7
  TOP w0.102: PR5.2 132.7,172.92 v2(132.91,172.71)
N21178859: length 4.5
  TOP w0.254: PC1302.1 194.67,61.62 194.89,61.4 v2(195.58,61.4) v1(196.29,61.4)
  BOTTOM w0.254: PU1300.7 195.16,62.06 195.81,61.4 v1(196.29,61.4)
N21219517: length 17.3
  TOP w0.102: v1(180.31,103.39) 180.18,103.39 179.24,104.33 v4(179.24,104.53) RV64.2
  IN3 w0.102: v1(183.03,113.13) 180.14,113.13 179.22,112.21 179.22,110.62 179.71,110.13 179.71,104.6 179.93,104.38 179.93,103.77 180.01,103.69
  IN3 w0.127: v1(180.31,103.39) 180.01,103.69
  BOTTOM w0.102: v1(183.03,113.13) 182.91,113.13 UV1.AH16
N21220354: length 31.7
  TOP w0.102: v1(167.64,101.18) 166.1,101.18 v2(165.29,100.37) 164.49,99.58 RV203.1
  IN3 w0.102: v1(171.35,118.74) 171.92,118.17 171.92,117.22 171.48,116.78 171.03,116.78 170.05,115.8 169.55,115.8 169.25,115.51 169.25,114.97 168.59,114.3 166.21,114.3 165.44,113.54 164.3,113.54 164.11,113.35
  IN3 w0.127: 164.11,113.35 163.38,112.62 163.38,110.5 162.27,109.39 162.27,108.39 167.64,103.02 v1(167.64,101.18)
  BOTTOM w0.102: UV1.Y29 171.66,119.05 v1(171.35,118.74)
N21246320: length 3.2
  BOTTOM w0.102: PR1211.2 175.15,188.39 v2(174.92,188.62)
  BOTTOM w0.254: PQ1201.1 173.92,187.46 PR1211.2
N21246524: length 3.6
  BOTTOM w0.102: v2(173.66,182.19) 173.46,182.39 PR1212.2
  BOTTOM w0.254: PR1212.2 PC1214.1 174.1,184.8 PQ1201.2
N21747034: length 3.2
  TOP w0.254: PD2.3 139.24,183.37 v1(138.54,184.07)
  BOTTOM w0.254: v1(138.54,184.07) 138.52,184.08 PR17.1 138.79,185.05 PD1.6
N22321388: length 90.9
  TOP w0.089: RE37.2 128.76,98.41 v1(129.51,99.16) v2(130.09,99.16)
  TOP w0.102: v1(188.19,54.34) 188.26,54.34 188.79,53.81 UE1.82
  IN1 w0.084: v1(129.51,99.16) 129.51,99.1 131,97.6 131.57,97.6
  IN1 w0.127: 131.57,97.6 132.54,97.6 136.02,94.12 139.38,94.12 147.62,85.87 149.64,85.87 159.86,75.66 169.49,75.66 174.32,70.82 174.32,64.42 174.87,63.88 174.87,60.74 177.41,58.2 177.41,56.87 177.87,56.41 177.87,54.46 v1(179.16,53.16)
  IN3 w0.127: v1(179.16,53.16) 179.36,53.36 183.34,53.36 184.32,54.34 v1(188.19,54.34)
N22702729: length 2.3
  TOP w0.102: RD15.2 v2(42.14,10.74) LED2.1
N22702890: length 2.2
  TOP w0.102: LED3.2 49.9,10.74 v2(49.9,12.04) RD16.2
N22702897: length 2.8
  TOP w0.102: RD17.2 48.13,12.94 48.03,12.84 v2(48.03,12.55) 48.03,11.61 LED3.3
N22703004: length 3.1
  TOP w0.102: v2(34.13,11.79) 33.73,11.4 RD14.2 33.67,10.74 LED1.1
N22795339: length 2.2
  TOP w0.102: RD18.2 58.81,12.87 v2(58.81,11.88) LED4.1
N26889205: length 3.6
  TOP w0.102: RV198.1 170.66,118.88 v1(170.66,118.7) 170.66,118.08 v2(169.71,117.13)
  BOTTOM w0.102: UV1.Y30 170.86,118.9 v1(170.66,118.7)
N32320781:
  vias: v2(138.59,162.08)
N32936693: length 4.5
  TOP w0.102: v2(133.88,167.58) 133.99,167.48 135.7,167.48 135.79,167.57 PQ706.1
  TOP w0.254: PQ706.1 135.79,169.68 PR720.2
N39186606: length 2.1
  TOP w0.102: RV125.1 178.07,110.2 v1(178.4,109.87) v2(178.4,109.27)
  BOTTOM w0.102: v1(178.4,109.87) 178.34,109.87 177.91,110.29 UV1.AL21
N39195318: length 2.6
  TOP w0.102: v1(173,104.97) 173.11,104.85 RV123.1 173.11,103.87 v2(172.53,103.29)
  BOTTOM w0.102: v1(173,104.97) 172.66,105.31 UV1.AW28
N39348342: length 5.1
  BOTTOM w0.102: UV1.AW18 181.28,104.88 182.47,104.88 183.05,104.3 v2(183.05,103.46) 183.05,103.45 182.9,103.3 182.9,102.58 RV122.1
N39890903: length 23
  TOP w0.102: v1(195.23,95) 194.77,95 194.35,94.58 CV218.1
  IN3 w0.102: 189.47,103.69 189.47,105.16 187.2,107.43 187.2,110.24 v1(187.65,110.69)
  IN3 w0.127: 189.47,103.69 189.47,101.63 190.06,101.04 190.06,98.07 193.13,95 v1(195.23,95)
  BOTTOM w0.102: UV1.AK10 187.26,111.08 v1(187.65,110.69) ; v1(195.23,95) v2(195.88,95)
N39890907: length 2.1
  TOP w0.102: v2(192.15,93.5) 192.44,93.21 CV219.2 RV137.1
N39890909: length 2.1
  TOP w0.102: v2(193.35,95.41) 193.43,95.32 CV218.2 RV136.1
N39890911: length 3.8
  TOP w0.102: v2(209.96,97.77) RV143.2 CV222.1 207.93,99.05 RV144.1
N39890927: length 22.1
  TOP w0.102: CV219.1 191.22,92.46 v1(190.87,92.81)
  IN3 w0.102: v1(186.88,110.7) 187,110.58 187,107.35 189.19,105.15 189.19,103.69
  IN3 w0.127: 189.19,103.69 189.19,101.46 189.8,100.85 189.8,97.97 191.03,96.74 191.03,95.64 191.67,95.01 191.67,93.61 v1(190.87,92.81)
  BOTTOM w0.102: v1(190.87,92.81) v2(190.87,93.36) ; UV1.AL10 187.26,110.32 186.89,110.7 v1(186.88,110.7)
N39986171: length 12.9
  BOTTOM w0.102: RV108.1 RV107.2 186.58,90.37 185.63,90.37 184.8,89.55 v2(184.59,89.55) 180.93,89.55 180.24,90.24 QV24.1
N39986181: length 4.5
  BOTTOM w0.102: v2(189,96.18) 189.26,95.93 RV108.2 189.24,94.81 CV103.1 188.06,94.69 QV22.2
N40812716: length 5.2
  TOP w0.102: CR3.2 v2(181.12,18.06)
  TOP w0.305: UR1.6 178.32,20.92 179.23,20.01 179.48,20.01 180.14,19.35 CR3.2
N45520480: length 2.6
  TOP w0.102: RV206.2 v2(174.24,125.78) 173.96,125.5 v1(173.96,125.19)
  BOTTOM w0.102: UV1.M27 173.46,125.51 173.78,125.19 v1(173.96,125.19)
N46608735: length 2.5
  BOTTOM w0.254: PQ701.2 141.21,164.47 v2(141.79,163.89) PR701.1
N46608740: length 4.7
  BOTTOM w0.102: v2(137.3,163.54) 138.07,164.32 138.07,165.26 139.33,166.51 PQ701.4
N46608753: length 6.6
  BOTTOM w0.254: PC701.2 143.81,167 PC702.1 144.88,166.63 145.26,166.25 145.26,165.22 145.05,165.01 v2(144.82,165.01) 144,165.01 PR703.1 PR701.2
N46612327: length 3.5
  TOP w0.102: v2(166.66,174.06) 167.04,173.68 167.04,173.52 167.53,173.04 PR708.1
  TOP w0.254: PU701.13 167.99,172.72 PR708.1
N46612330: length 1.9
  TOP w0.254: PR710.1 168.49,172.96 PU701.12
N46660696: length 1.1
  TOP w0.102: PC520.2 v2(106.08,143.72)
N46662317: length 2.6
  TOP w0.102: v1(86.33,137.3) 85.59,137.3 v2(85.38,137.51)
  TOP w0.254: PR510.1 86.39,137.23 v1(86.33,137.3)
  BOTTOM w0.203: PU501.4 86.4,137.22 v1(86.33,137.3)
N46663656: length 4.8
  TOP w0.102: v1(86.34,136.3) 86.34,135.5 86.49,135.35 86.49,134.37 v2(86.4,134.28)
  TOP w0.254: v1(86.34,136.3) 86.38,136.35 PC504.1
  BOTTOM w0.203: PU501.2 86.45,136.42 v1(86.34,136.3)
  BOTTOM w0.254: v1(86.34,136.3) 85.81,135.77 PR516.2
N46665785: length 3.6
  BOTTOM w0.102: PR529.1 92.66,132.2 92.81,132.05 94.27,132.05 v2(94.74,131.58)
  BOTTOM w0.254: PR529.1 92.36,132.6 92.29,132.66 PC514.1
N46673636: length 6.6
  TOP w0.102: v1(93,142.38) 93,142.8 v2(93.08,142.88)
  IN1 w0.254: v1(93,142.38) 92.89,142.48 92.89,142.82 93.85,143.77 96.1,143.77 96.43,144.1 v1(96.43,144.21)
  BOTTOM w0.254: v1(96.43,144.21) 96.43,143.52 PH501.2 ; PR515.1 92.99,141.76 92.99,142.38 v1(93,142.38)
N46674251: length 19.1
  BOTTOM w0.254: PR518.2 93.56,143.98 v2(94.53,144.95) 95.07,145.49 100.83,145.49 102.33,144 102.33,140.6 102.77,140.16 PL502.2
N46860163: length 6.6
  TOP w0.102: v2(173.25,171.58) 173.18,171.65 PR713.2
  TOP w0.254: PU701.10 169.7,170.44 169.7,171.59 170.02,171.91 170.02,171.91 171.23,173.11 PQ708.1 171.91,173.11 172.25,172.77 PR713.2
N46975913: length 2.5
  BOTTOM w0.102: PR536.2 118.97,140.05 v2(119.25,140.34)
  BOTTOM w0.254: PR536.2 118.16,139.53 PC501.1
N46975982: length 1.5
  BOTTOM w0.203: PU502.6 116.07,140.43 116.45,140.05 PR536.1
N46976065: length 3.8
  BOTTOM w0.102: PC501.2 116.69,138.56 v2(115.67,137.54)
  BOTTOM w0.203: PU502.7 115.94,140.03 116.22,139.75 116.22,139.44 PC501.2
N47007806: length 2.4
  TOP w0.254: PQ2.3 127.66,167.51 PC16.1 127.47,166.89 127.46,166.88 PR28.2
N47007810: length 4.3
  TOP w0.102: v2(127.33,170.92) 127.65,170.6 PR29.1
  TOP w0.254: PQ2.2 127.55,168.16 PC16.2 127.47,169.49 127.65,169.67 PR29.1
N47007850: length 4.2
  TOP w0.254: PQ2.5 131.35,168.16 131.8,167.7 PR31.1 132.48,167.21 v2(132.48,166.62) 132.48,166.4 132.35,166.27 131.47,166.27 PR33.2
N47007898: length 3.8
  TOP w0.102: PR32.1 133.17,162.71 v2(133.4,162.48)
  TOP w0.254: PC14.2 PR32.1 131.72,162.71 131.47,162.95 PQ3.5
N47008006: length 1.4
  TOP w0.102: v2(127.57,176.41) 128.22,175.76 PQ1.6
N47008110: length 2.4
  TOP w0.254: PC15.1 PR30.2 127.94,162.71 128.18,162.95 PQ3.2
N47008134: length 7.4
  TOP w0.102: v2(130.45,183.16) 130.85,182.76 v1(130.97,182.76)
  TOP w0.254: v1(130.97,182.76) 131.03,182.7 PR6.2
  BOTTOM w0.254: v1(130.97,182.76) 130.71,182.51 PL2.2 128.97,182.66 PQ6.1
N47008301: length 1.4
  TOP w0.102: v2(127.61,178.17) 128.17,178.73 PQ4.1
N47305899: length 1.9
  TOP w0.102: v2(211.51,60.94) 211.17,61.28 PR805.1
N47415217: length 1.9
  TOP w0.102: v2(133.45,15.68) 133.35,15.79 PC104.2
  TOP w0.254: PR103.1 PC104.2
N47415258:
  vias: v2(134.4,20.73)
N47415272:
  vias: v2(120.27,20.97)
N47415370: length 1.9
  TOP w0.102: PC110.1 123.18,16.37 v2(122.25,16.37)
  TOP w0.254: PR111.2 PC110.1
N47417471: length 2.6
  BOTTOM w0.102: v2(105.35,23.37) 105.59,23.13 PC405.1
N47417524: length 3.4
  BOTTOM w0.102: PR405.2 106.07,26.97 105.54,26.43 v2(105.54,25.92)
  BOTTOM w0.508: PC401.1 106.94,26.38 PR405.2
N47420895:
  vias: v2(159.2,11.13)
N47445410: length 2.2
  TOP w0.203: PU100.19 125.73,15.67 125.57,15.5 v2(125.1,15.5) PR114.1
N47894294: length 2
  BOTTOM w0.089: v2(99.01,94.49) 98.84,94.65 RC23.1 97.97,94.67 CC8.2
N47894380: length 2
  BOTTOM w0.089: RC24.1 93.51,95.52 CC9.2 93.5,96.07 v2(93.91,96.48)
N47894401: length 1.9
  BOTTOM w0.089: RC25.1 95.28,94.67 CC10.2 v2(95.28,96.53)
N47938591: length 9.5
  TOP w0.089: T118.1 122.7,100.37 122.7,104.53 123.48,105.3 124.32,105.3 124.49,105.46 124.49,106.5 125.04,107.06 v1(125.05,107.06)
  BOTTOM w0.089: UC1.AN10 124.62,107.48 v1(125.05,107.06)
N47938593: length 3
  TOP w0.089: v1(125.06,107.71) 125,107.71 124.65,107.36 124.65,106.96 124.17,106.48 124.17,105.8 T119.1
  BOTTOM w0.076: UC1.AM10 124.63,108.13 v1(125.06,107.71)
N47938689: length 1.1
  TOP w0.089: v1(121.56,123.27) 121.85,123.55 T120.1
  BOTTOM w0.089: v1(121.56,123.27) 121.89,122.94 UC1.E15
N47938710: length 3.2
  TOP w0.089: T121.1 123.5,124.25 v1(122.53,123.29)
  BOTTOM w0.089: UC1.E13 122.88,122.94 v1(122.53,123.29)
N47964855: length 5.3
  BOTTOM w0.076: T153.1 90.73,119.01 91.06,118.67 91.84,118.67 92,118.84 92.78,118.84 92.83,118.79 93.3,118.79 UC1.L60
N47964866: length 2.1
  TOP w0.254: T154.1 92.63,118.67 93.3,118.01 v1(93.3,118.01)
  BOTTOM w0.254: UC1.N60 93.6,118.31 v1(93.3,118.01)
N47964871: length 1.8
  TOP w0.109: v1(116.14,114.48) 115.89,114.73 T155.1
  BOTTOM w0.076: v1(116.14,114.48) 116.55,114.88 UC1.W23
N47964873: length 1.7
  TOP w0.089: T156.1 117.21,114.89 v1(116.79,114.48)
  BOTTOM w0.076: UC1.Y22 v1(116.79,114.48)
N47964879: length 7.3
  BOTTOM w0.076: UC1.AV62 91.95,103.9 91,103.9
  BOTTOM w0.102: T157.1 88.79,101.69 91,103.9
N47964884: length 6.6
  BOTTOM w0.076: T158.1 93.18,127.76 94.19,126.76 94.19,126.56 94.81,125.94 94.81,125.41 94.67,125.27 94.67,124.97 94.71,124.93 94.71,124.78 94.64,124.72 94.64,124.44 94.73,124.35 94.73,124.17 94.63,124.07 94.63,123.78 94.94,123.47 UC1.D58
N47965485: length 9.1
  BOTTOM w0.102: UC1.AV63 91.21,104.23 91.08,104.09 90.92,104.09 88.46,101.63 88.46,97.77 T146.1
N47965487: length 10.5
  BOTTOM w0.089: 88,99.65 88,101.74
  BOTTOM w0.102: UC1.AU63 91.14,104.89 88,101.74 ; T147.1 88,96.77 88,99.65
N47965489: length 1.3
  TOP w0.089: v1(119.71,117.53) 119.8,117.61 T160.1
  BOTTOM w0.076: UC1.P20 119.3,117.53 v1(119.71,117.53)
N47965491: length 1.3
  TOP w0.089: v1(119.49,116.51) 119.88,116.12 T162.1
  BOTTOM w0.076: v1(119.49,116.51) 119.1,116.9 UC1.R20
N47965493: length 4.1
  BOTTOM w0.102: UC1.A5 127.72,125.72 129.14,127.14 129.35,127.14 130.03,127.81 T159.1
N47965495: length 3.4
  BOTTOM w0.102: UC1.C63 91.56,124.25 91.17,124.64 89.23,124.64 T148.1
N47965502: length 3.4
  BOTTOM w0.076: UC1.E1 132.28,123.04 T161.1
N47965509: length 4.3
  BOTTOM w0.076: UC1.C62 92.04,123.92 91.51,123.92 90.99,124.44 89.94,124.44
  BOTTOM w0.089: 89.94,124.44 89,124.44 88.91,124.35
  BOTTOM w0.102: T149.1 88.91,124.35
N47965511: length 4.5
  BOTTOM w0.076: UC1.D1 132.1,123.7 132.76,124.36 134.08,124.36 T163.1
N47965522: length 4.7
  BOTTOM w0.076: UC1.B43 104.41,125.15 104.7,125.44 104.7,125.68 103.98,126.4 103.98,128.14 104.54,128.7
  BOTTOM w0.102: T150.1 104.54,128.9 104.54,128.7
N47965524: length 1.8
  TOP w0.089: T164.1 117.95,120.53 118.53,120.53 v1(118.66,120.66)
  BOTTOM w0.089: v1(118.66,120.66) 118.78,120.66 UC1.J20
N47965529: length 2.1
  BOTTOM w0.076: UC1.A51 99.39,126.88 T151.1
N47965534: length 4.1
  BOTTOM w0.076: T152.1 99.98,125.73 99.39,125.15 UC1.B51
N47965536: length 1.1
  TOP w0.089: T165.1 119.87,121.32 v1(119.66,121.32)
  BOTTOM w0.076: v1(119.66,121.32) 119.98,120.99 UC1.H18
N48037563: length 4.9
  TOP w0.102: v2(104.89,68.55) 104.74,68.7 v1(104.04,68.7) 103.96,68.78 RD6.2
  BOTTOM w0.102: JDIMM1.197 103,69.44 103.74,68.7 v1(104.04,68.7)
N48037565: length 5.6
  TOP w0.102: v2(104.38,66.97) 104.04,67.31 v1(104.04,67.94) 104,67.89 RD7.2
  BOTTOM w0.102: v1(104.04,67.94) 104.49,68.38 104.49,70.18 104.2,70.46 JDIMM1.201
N48039107: length 5.8
  TOP w0.102: RD4.1 83.46,63.42 CD22.1 CD21.1 81.69,61.99 81.5,61.8 v1(81.5,61.42) v2(81.5,60.81)
  BOTTOM w0.102: v1(81.5,61.42) 81.5,61.8 81.7,62 JDIMM1.126
N48051997: length 5.3
  TOP w0.102: 160.3,61.55 v2(160.3,60.84)
  TOP w0.508: v1(160.25,61.5) 160.3,61.55 CD52.1 CD53.1 162.06,62.55 RD10.1
  BOTTOM w0.356: v1(160.25,61.5) JDIMM2.126
N48052813: length 7.8
  TOP w0.102: RD13.1 183.13,70.13 v2(183.13,68.88) 183.13,68.02 v1(182.59,67.48)
  BOTTOM w0.102: v1(182.59,67.48) 182.03,68.04 182.03,69.56 181.55,70.04 JDIMM2.197
N48052822: length 7
  TOP w0.102: RD12.1 182.59,65.94 v1(182.59,66.9) 182.98,67.29 v2(183.3,67.29)
  BOTTOM w0.102: v1(182.59,66.9) 183.04,67.34 183.04,69.71 182.75,70 JDIMM2.201
N48120577: length 2.8
  TOP w0.102: UX4.12 201.27,167.38 200.5,166.61 199.74,166.61 RX5.2
N55155843: length 2.5
  TOP w0.102: v2(218.42,175.2) 218.09,175.53 RX3.2 217.04,176.27 QX1.1
N55200533: length 18
  TOP w0.102: 14.82,102.44 14.82,102.94 ; 14.82,102.44 14.82,101.94 ; 14.82,102.44 RP59.7 ; 14.82,102.94 14.82,103.44 ; 14.82,102.94 RP59.6 ; 14.82,103.44 14.82,103.58 v1(16,104.75) ; 14.82,103.44 RP59.5 ; RP59.8 14.82,101.94 ; 14.82,101.94 14.82,100.21 13.5,98.88 13.5,97.98 ; RP58.8 13.61,96.48 13.5,96.59 13.5,96.98 ; RP58.5 13.5,97.98 ; 13.5,97.98 13.5,97.48 ; 13.5,96.98 RP58.7 ; 13.5,96.98 13.5,97.48 ; 13.5,97.48 RP58.6
  BOTTOM w0.102: v1(16,104.75) v2(17.02,105.77) 18.06,106.82 QX3.1
N55201771: length 11.3
  TOP w0.102: v2(12.26,110.67) 12.36,110.56 v1(13.05,110.56)
  IN3 w0.127: v1(13.05,110.56) 9.87,110.56 8.73,109.42 8.73,105.8 JHDMI.13
  BOTTOM w0.102: v1(13.05,110.56) 13.06,110.55 RX12.2
N56393123: length 4.8
  BOTTOM w0.102: RL31.2 35.07,80.29 33.98,79.2 v2(33.98,78.95)
  BOTTOM w0.203: 36.5,81.53 36.75,81.78 UL1.31
  BOTTOM w0.254: 36.5,81.53 36.39,81.42 35.76,81.42 35.46,81.12 35.46,81.03 35.08,80.65 RL31.2
N56393790: length 4.6
  BOTTOM w0.102: UL1.27 38.35,81.38 39.67,80.06 39.67,79.61 T94.1
N56393809: length 1.7
  BOTTOM w0.102: UL1.25 39.15,81.76 39.8,81.11 T95.1
N56393828: length 2.9
  BOTTOM w0.102: UL1.26 38.75,81.37 40,80.12 T96.1
N56394014: length 7.2
  TOP w0.102: RL19.2 21.85,84.15 v2(22.12,83.87)
  TOP w0.254: CL33.1 19,80 19,82.36 19.78,83.13 RL20.2 RL19.2
N56394031: length 6.9
  BOTTOM w0.102: TL1.6 31.84,81.8 32.5,82.46 v2(32.5,82.52) 32.5,83.8 CL41.2 32.05,85.61 TL1.3
N60531222: length 72.9
  TOP w0.102: v1(142.34,110.8) 142.75,110.4 143.58,110.4 144.01,109.97 144.38,109.97 145.61,111.2 148.11,111.2 149.72,112.81 149.72,115.52 149.23,116.02 149.23,117.58 145.55,121.26 145.55,125.11 v2(145.92,125.49) 146.43,126 v1(146.43,126.5)
  IN1 w0.084: 136.53,125.81 135.66,125.81 135.28,126.19 123.37,126.19 122.71,126.85 122.71,128.51 120.97,130.25 116.36,130.25 114.9,128.79 112.3,128.79 112.11,128.6 112.11,125.55 111.6,125.04 109.25,125.04 v1(108.57,125.72)
  IN1 w0.127: 136.53,125.81 137.89,125.81 138.17,125.54 145.47,125.54 146.43,126.49 v1(146.43,126.5)
  BOTTOM w0.076: 108.74,125.68 108.87,125.55 108.96,125.45 109.02,125.29 109.02,125.18 108.98,125.06 108.96,125.03 108.96,124.84 109.01,124.69 109.11,124.54 UC1.C35
  BOTTOM w0.089: v1(108.57,125.72) 108.7,125.72 108.74,125.68
  BOTTOM w0.102: v1(142.34,110.8) 142.34,110.8 142.01,111.12 142.01,111.23 142.08,111.29 RP41.1
N60531228: length 70.6
  TOP w0.102: v1(142.97,110.8) 144.89,110.8 145.52,111.43 147.64,111.43 148.84,112.63 148.84,117.64 145.32,121.17 145.32,121.65 145.1,121.87 v2(145.1,122.72) 145.1,125.63 145.84,126.38 v1(145.84,126.5)
  IN1 w0.084: v1(109.09,126.06) 109.94,125.21 111.53,125.21 111.93,125.62 111.93,128.67 112.23,128.96 114.83,128.96 116.29,130.42 121.05,130.42 122.88,128.59 122.88,126.92 123.44,126.36 135.54,126.36 135.83,126.07 136.69,126.07
  IN1 w0.127: 136.69,126.07 138,126.07 138.27,125.79 145.13,125.79 v1(145.84,126.5)
  BOTTOM w0.076: UC1.C34 109.71,124.38 109.54,124.55 109.37,124.55 109.16,124.76 109.13,124.86 109.13,125 109.15,125.05 109.16,125.07 109.19,125.15 109.19,125.32 109.11,125.54 109.11,125.56
  BOTTOM w0.089: v1(109.09,126.06) 109.11,126.04 109.11,125.56
  BOTTOM w0.102: v1(142.97,110.8) 142.97,111.45 142.63,111.79 RP41.2
N60531230: length 21.2
  TOP w0.102: v1(141.76,110.8) 141.76,111.23 v2(141.86,111.33)
  IN1 w0.084: 136.41,110 134.88,110 134.65,109.78 130.6,109.78 129.34,111.03 128.51,111.03 128.17,110.69 126.3,110.69 v1(125.78,110.18)
  IN1 w0.127: 136.41,110 136.75,109.66 137.54,109.66 138.01,110.13 141.09,110.13 141.76,110.79 v1(141.76,110.8)
  BOTTOM w0.089: UC1.AK8 125.99,109.12 125.99,109.95 125.78,110.16 v1(125.78,110.18)
  BOTTOM w0.102: RP41.3 141.96,112.29 141.82,112.15 141.82,111.78 141.76,111.71 v1(141.76,110.8)
N60531232: length 25.1
  TOP w0.102: v2(140.15,110.28) 140.67,110.8 v1(141.17,110.8)
  IN1 w0.084: v1(125.47,109.16) 125.07,109.16 124.74,109.48 124.74,109.55 124.74,109.56 124.74,110.1 124.78,110.15 124.78,110.92 125.45,111.59 129.03,111.59 130.67,109.95 134.58,109.95 134.81,110.17 136.3,110.17 137.14,111.01 137.61,111.01
  IN1 w0.127: 137.61,111.01 140.96,111.01 v1(141.17,110.8)
  BOTTOM w0.089: UC1.AL8 125.97,108.65 v1(125.47,109.16)
  BOTTOM w0.102: v1(141.17,110.8) 141.32,110.95 141.32,112.28 141.83,112.79 RP41.4
N60754677: length 5.5
  TOP w0.089: 88.91,122.52 89.42,122.52 89.79,122.15 89.79,121.64 v1(89.8,121.63)
  TOP w0.102: T111.1 88.91,122.52
  BOTTOM w0.076: v1(89.8,121.63) 90.19,121.23 90.72,121.23 90.8,121.31 91.3,121.31 91.38,121.23 91.53,121.09 91.77,121.09 91.94,121.26 91.94,121.43 92.18,121.67 92.7,121.67 UC1.H61
N60754679: length 4.3
  BOTTOM w0.076: 89.05,121.29 89.28,121.07 90.83,121.07 90.91,121.14 91.24,121.14 91.31,121.07 91.46,120.92 91.84,120.92 91.85,120.93 91.85,120.93 UC1.H62
  BOTTOM w0.089: 88.91,121.43 89.05,121.29
  BOTTOM w0.102: 88.91,121.43 88.61,121.73 T112.1
N60754681: length 1.3
  TOP w0.089: v1(94.67,120.23) 94.67,120.85 T113.1
  BOTTOM w0.076: v1(94.67,120.23) 94.35,119.92 UC1.K59
N60754683: length 2.1
  TOP w0.089: T114.1 90.52,121.76 v1(90.39,121.64)
  BOTTOM w0.076: UC1.H63 91.55,121.48 90.55,121.48 v1(90.39,121.64)
N60754685: length 1.3
  TOP w0.089: T115.1 93.34,119.47 v1(93.3,119.5)
  BOTTOM w0.076: UC1.K60 93.6,119.8 v1(93.3,119.5)
N60754687: length 2.7
  TOP w0.089: T116.1 94.2,119.91 93.51,120.6 93.06,120.6 v1(92.65,121)
  BOTTOM w0.076: UC1.J61 92.95,120.7 v1(92.65,121)
N60931942: length 4.6
  BOTTOM w0.076: UC1.AF2 130.07,112.04 130.08,112.04 130.09,112.05 130.4,112.05 130.55,112.2 131.91,112.2 132.43,112.72 T97.1
N60931944: length 5
  BOTTOM w0.076: T99.1 132.91,111.45 130.54,111.45 130.4,111.3 130.09,111.3 129.92,111.14 129.14,111.14 129.04,111.23 128.65,111.23 UC1.AF4
N60931946: length 6.7
  BOTTOM w0.076: UC1.AD2 129.86,112.35 130.33,112.81 131.51,112.81 132.03,113.33 132.03,113.54 132.16,113.66 132.73,113.66 133.19,113.21 134.93,113.21 T98.1
N61580896: length 5.7
  TOP w0.102: R2314.2 183.8,61.1 183.48,61.42 183.16,61.42 182.97,61.22 Q2307.1 180.42,60.17 v2(180.24,60.35)
N61580898: length 4.4
  TOP w0.102: v2(148.48,123.87) 147.3,122.69 R2315.2 146.9,121.4 147.13,121.17 Q2308.1
N63469417: length 3.8
  TOP w0.102: v2(34.21,26.52) 33.93,26.23 RA81.2 CA69.1 CA65.2 RA79.1
N63469524: length 10.6
  TOP w0.254: CA68.2 25.61,27.58 24.41,27.58 23.97,27.14 23.97,26.38 23.82,26.24 23.67,26.24 22.71,25.27 22.71,25.26 v1(22.58,25.13)
  BOTTOM w0.203: v1(22.58,25.13) 22.7,25.02 22.7,23.2 v2(22.93,22.97) 23.03,22.87 23.03,21.45 22.61,21.03 RA82.1
N63469526: length 8.6
  TOP w0.254: v1(23.23,25.11) 23.23,25.26 23.83,25.86 23.98,25.86 24.35,26.23 24.35,26.38 24.97,27 CA67.2
  BOTTOM w0.203: v1(23.23,25.11) 23.15,25.03 v2(23.15,24.6) 23.15,23.29 23.36,23.09 23.36,21.31 22.75,20.7 22.38,20.7 RA80.1
N63469613: length 3.2
  TOP w0.102: UA1.12 30.47,22.85 30.83,23.2 30.83,23.89 v2(31.18,24.24) 31.46,24.52 CA65.1
N63469617: length 2.1
  TOP w0.203: RA51.1 29.68,24.9 29.28,24.5 UA1.13
N63469687: length 3.1
  TOP w0.102: v1(22.51,22.11) 22.42,22.11 v2(22.02,22.51)
  TOP w0.203: UA1.28 23.71,21.65 23.64,21.72 23.17,21.72 22.78,22.11 v1(22.51,22.11)
  BOTTOM w0.254: v1(22.51,22.11) CA23.2
N63469697: length 2.3
  TOP w0.203: RA153.2 28.51,25.88 v2(28.51,24.83) 28.51,24.38 28.48,24.36 UA1.15
N63469703: length 3.6
  TOP w0.102: v2(22.28,17) 22.46,17.18 CA24.1 22.77,17.67 UA1.37
N63469709: length 3.9
  TOP w0.102: UA1.35 23.5,18.85 23.4,18.74 22.57,18.74 22.37,18.54 22.1,18.54 CA24.2 21.28,17.71 v2(20.63,17.71)
N63469711: length 2.2
  TOP w0.102: UA1.34 23.58,19.25 23.47,19.14 v2(22.93,19.14) 22.15,19.14 CA25.2
N63469717: length 4.4
  TOP w0.203: UA1.27 23.32,22.05 22.66,22.71 v1(22.5,22.71)
  BOTTOM w0.102: CA62.2 21.81,23.97 v2(21.12,24.65)
  BOTTOM w0.254: v1(22.5,22.71) 21.89,23.32 CA62.2
N63469723: length 5.1
  TOP w0.203: UA1.39 25.68,17.09 25.78,17 25.78,16.51 25.52,16.26 24.86,16.26 v1(24.53,16.6)
  BOTTOM w0.102: v2(22.41,15.96) CA63.2
  BOTTOM w0.203: v1(24.53,16.6) 23.89,15.96 CA63.2
N63469729: length 6.2
  TOP w0.102: UA1.7 31.52,20.85 31.65,20.98 34.08,20.98 CA64.2 34.47,21.28 34.91,21.72 34.91,22.51 v2(35.04,22.64)
N63469750: length 2.2
  TOP w0.102: UA1.8 v2(31.22,21.25) 31.55,21.25 31.78,21.47 RA130.2
N63642793: length 44.2
  TOP w0.089: 136.24,101.45 136.13,101.55 136.13,103.3 v2(133.47,105.97) 132.87,106.56 129.63,106.56 129.36,106.84 127.24,106.84 127.24,106.84 126.81,106.84 125.95,107.7 125.95,108.94 125.87,109.01 125.87,109.74 126.16,110.02 126.16,110.36 125.75,110.76 123.99,110.76 123.79,110.56 123.79,110.17 v1(123.39,109.77)
  TOP w0.102: C51.1 149.5,105.37 149.57,105.29 R264.2 149.57,104.46 150.09,103.93 150.65,103.93 150.84,103.74 150.84,99.45 149.97,98.58 139.53,98.58 139.14,98.97 138.71,98.97 136.24,101.45
  BOTTOM w0.089: v1(123.39,109.77) 123.71,110.09 UC1.AH11
N63643467: length 1
  TOP w0.089: v1(122.52,120.67) 122.02,120.67 T53.1
  BOTTOM w0.089: v1(122.52,120.67) 122.59,120.67 UC1.J13
N63643476: length 1.1
  TOP w0.089: T55.1 122.62,109.61 v1(122.62,109.76)
  BOTTOM w0.254: v1(122.62,109.76) 122.94,110.09 UC1.AH13
N63643505: length 1.9
  TOP w0.089: T56.1 125.31,114.54 v1(125.87,113.98)
  BOTTOM w0.254: v1(125.87,113.98) 125.69,113.81 UC1.AB8
N63643514: length 2.2
  TOP w0.089: T58.1 122.68,112.44 v1(124.03,112.44)
  BOTTOM w0.089: UC1.AD10 124.15,112.56 v1(124.03,112.44)
N63643523: length 1.1
  TOP w0.089: T59.1 125.57,113.36 v1(125.89,113.04)
  BOTTOM w0.089: v1(125.89,113.04) 125.69,112.84 UC1.AD8
N63656577: length 1.8
  TOP w0.089: v1(116.14,113.67) 116.5,113.31 T38.1
  BOTTOM w0.254: UC1.AB23 116.55,113.26 116.14,113.67 v1(116.14,113.67)
N63657072: length 3.9
  BOTTOM w0.076: T39.1 90.15,117.05 91.4,117.05 91.53,117.17 91.84,117.17 92,117.34 92.79,117.34 92.83,117.3 93.31,117.3 UC1.P60
N63657081: length 1.9
  TOP w0.089: T40.1 91.94,117.66 92.3,117.66 v1(92.65,118.01)
  BOTTOM w0.089: UC1.P61 92.95,117.71 v1(92.65,118.01)
N63657090: length 1.2
  TOP w0.254: T41.1 94.78,118.62 v1(94.64,118.76)
  BOTTOM w0.254: UC1.N59 94.31,118.42 v1(94.64,118.76)
N63657099: length 5.2
  BOTTOM w0.076: T42.1 89.06,118.18 90.14,118.18 90.27,118.32 91.3,118.32 91.5,118.11 91.53,118.09 91.77,118.09 91.94,118.26 91.94,118.44 92.18,118.67 92.7,118.67 UC1.N61
N63657120: length 1.5
  TOP w0.089: v1(93.95,116.51) 93.95,116.76 T43.1
  BOTTOM w0.089: v1(93.95,116.51) 94.25,116.81 UC1.T59
N63657126: length 2.4
  TOP w0.089: T44.1 93.43,112.57 v1(93.99,112.02)
  BOTTOM w0.254: v1(93.99,112.02) 93.6,112.4 UC1.AD60
N63657135: length 1.1
  TOP w0.089: v1(94.67,112.13) 94.33,112.47 T45.1
  BOTTOM w0.254: v1(94.67,112.13) 94.37,112.42 UC1.AD59
N63657146: length 1.8
  TOP w0.254: v1(94.58,113.49) 95.13,113.49 T46.1
  BOTTOM w0.254: UC1.AA59 94.58,113.59 v1(94.58,113.49)
N63657155: length 4.1
  BOTTOM w0.076: UC1.AE60 93.25,111.25 91.91,111.25 91.8,111.2 91.75,111.18 91.39,111.18 91.3,111.26 90.71,111.26 T47.1
N63657164: length 1.1
  TOP w0.254: v1(93.95,113.51) 93.95,114.11 T48.1
  BOTTOM w0.254: UC1.AC59 93.95,113.4 v1(93.95,113.51)
N63657173: length 1.8
  TOP w0.089: T49.1 93.8,111.26 94.48,111.26 v1(94.64,111.11)
  BOTTOM w0.254: UC1.AG58 94.59,111.06 v1(94.64,111.11)
N63657182: length 2.1
  TOP w0.089: T50.1 94.96,116.83 v1(95.46,116.83)
  BOTTOM w0.076: UC1.U59 94.46,116.09 94.87,116.5 95.13,116.5 v1(95.46,116.83)
N63657191: length 1.1
  TOP w0.089: v1(94.58,115.01) 94.58,115.14 T51.1
  BOTTOM w0.089: UC1.V59 94.25,115.34 v1(94.58,115.01)
N64564173: length 1.7
  TOP w0.102: v2(183.52,167.5) 183.67,167.66 PR1101.2
N64564191: length 1.9
  TOP w0.102: PR1104.2 180.24,168.72 v2(180.34,168.62)
N64734520: length 3.8
  TOP w0.089: v1(125.96,111.13) 125.92,111.09 123.75,111.09 T107.1
  BOTTOM w0.089: v1(125.96,111.13) 126,111.09 126,110.51 126.17,110.34 126.17,109.87 UC1.AJ7
N64734538: length 1.2
  TOP w0.089: v1(127.42,109.27) 128.06,109.27 T105.1
  BOTTOM w0.089: v1(127.42,109.27) 127.42,108.83 UC1.AL5
N64734540: length 5.6
  BOTTOM w0.076: T106.1 133.25,106.71 130.65,106.71 130.55,106.81 130.09,106.81 129.92,106.64 129.14,106.64 129.1,106.68 128.86,106.68 128.56,106.39 UC1.AP4

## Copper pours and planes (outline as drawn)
1.35V_B+ on BOTTOM (solid shape): 158.91,18.6 167.18,18.6 167.73,18.04 167.73,15.06 167.35,14.68 162.65,14.68 162.59,14.74 162.59,15.25 162.27,15.57 156.37,15.57 155.79,16.14 155.79,18.55 156,18.76 158.75,18.76
3/5V_B+ on TOP (solid shape): 131.98,28.97 131.98,26.2 131.79,26.01 130.53,26.01 129.96,25.44 129.95,25.44 129.48,24.97 127.85,24.97 127.6,25.22 126.14,25.22 125.89,25.47 125.89,25.73 125.53,26.08 123.09,26.08 122.89,26.29 122.89,29.02 123.41,29.54 131.41,29.54
3/5V_B+ on BOTTOM (solid shape): 129.47,29.26 129.47,25.25 129.19,24.97 126.66,24.97 125.9,25.73 125.9,29.36 126.08,29.54 129.19,29.54
3VALW_PCH on TOP (solid shape): 141.48,26.24 141.48,25 141.25,24.78 141.25,23.82 141.19,23.76 139.25,23.76 138.74,24.27 138.74,26.13 138.94,26.32 141.4,26.32
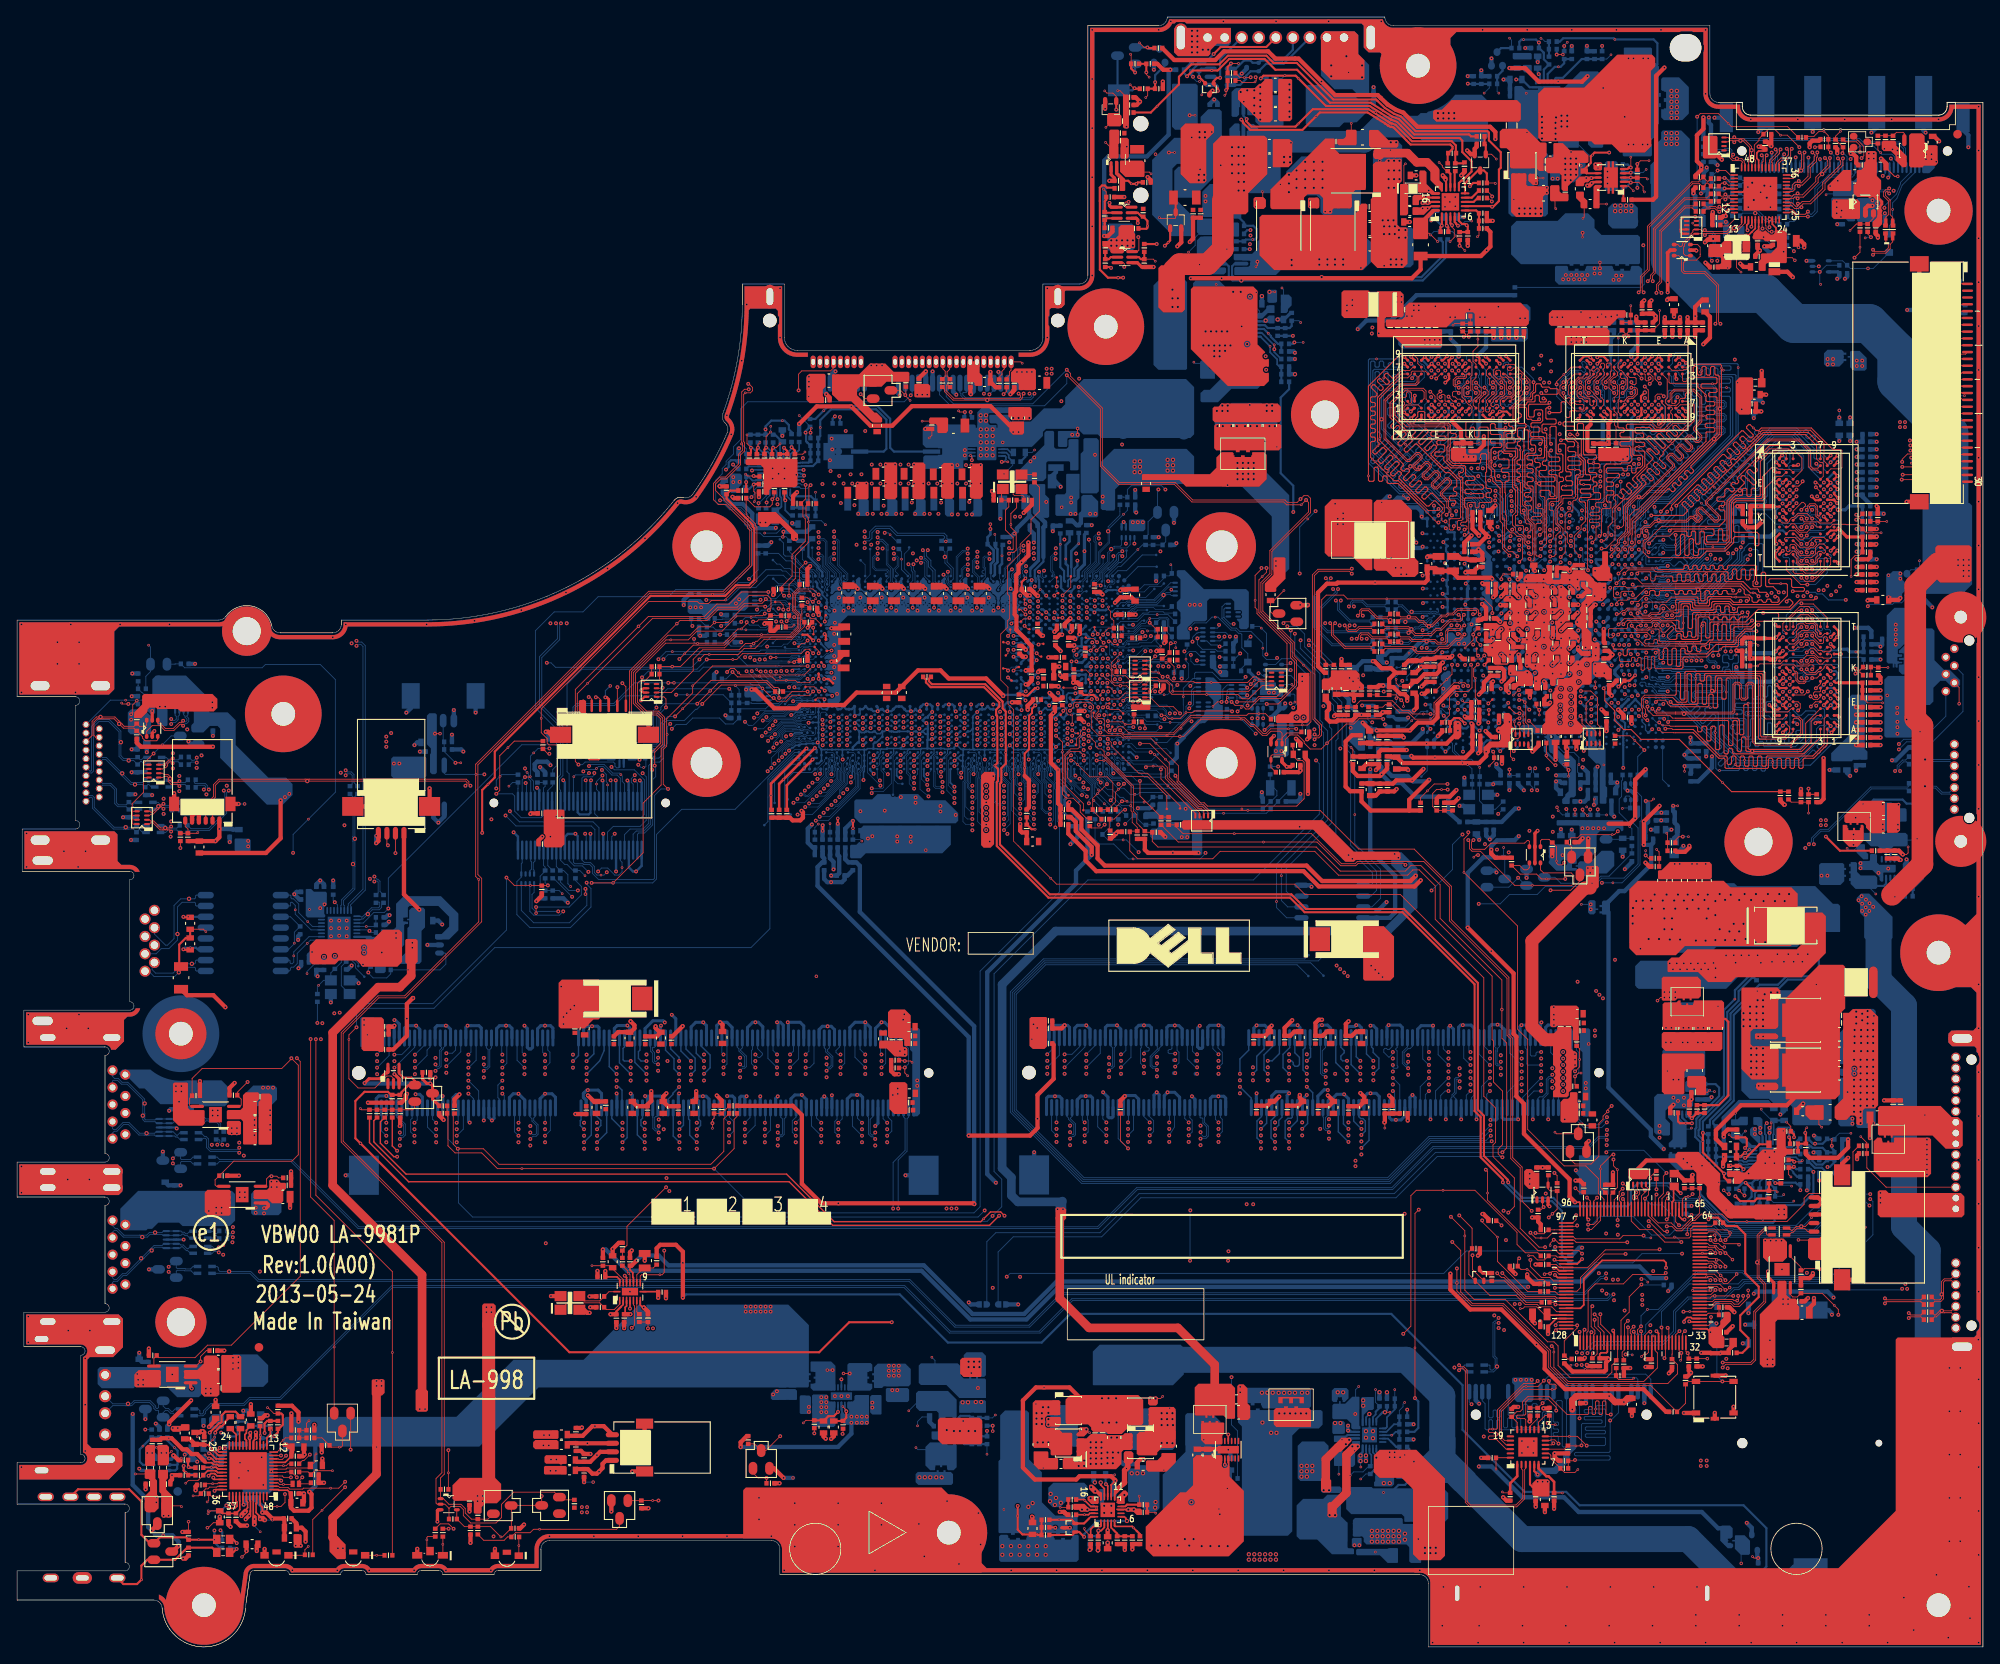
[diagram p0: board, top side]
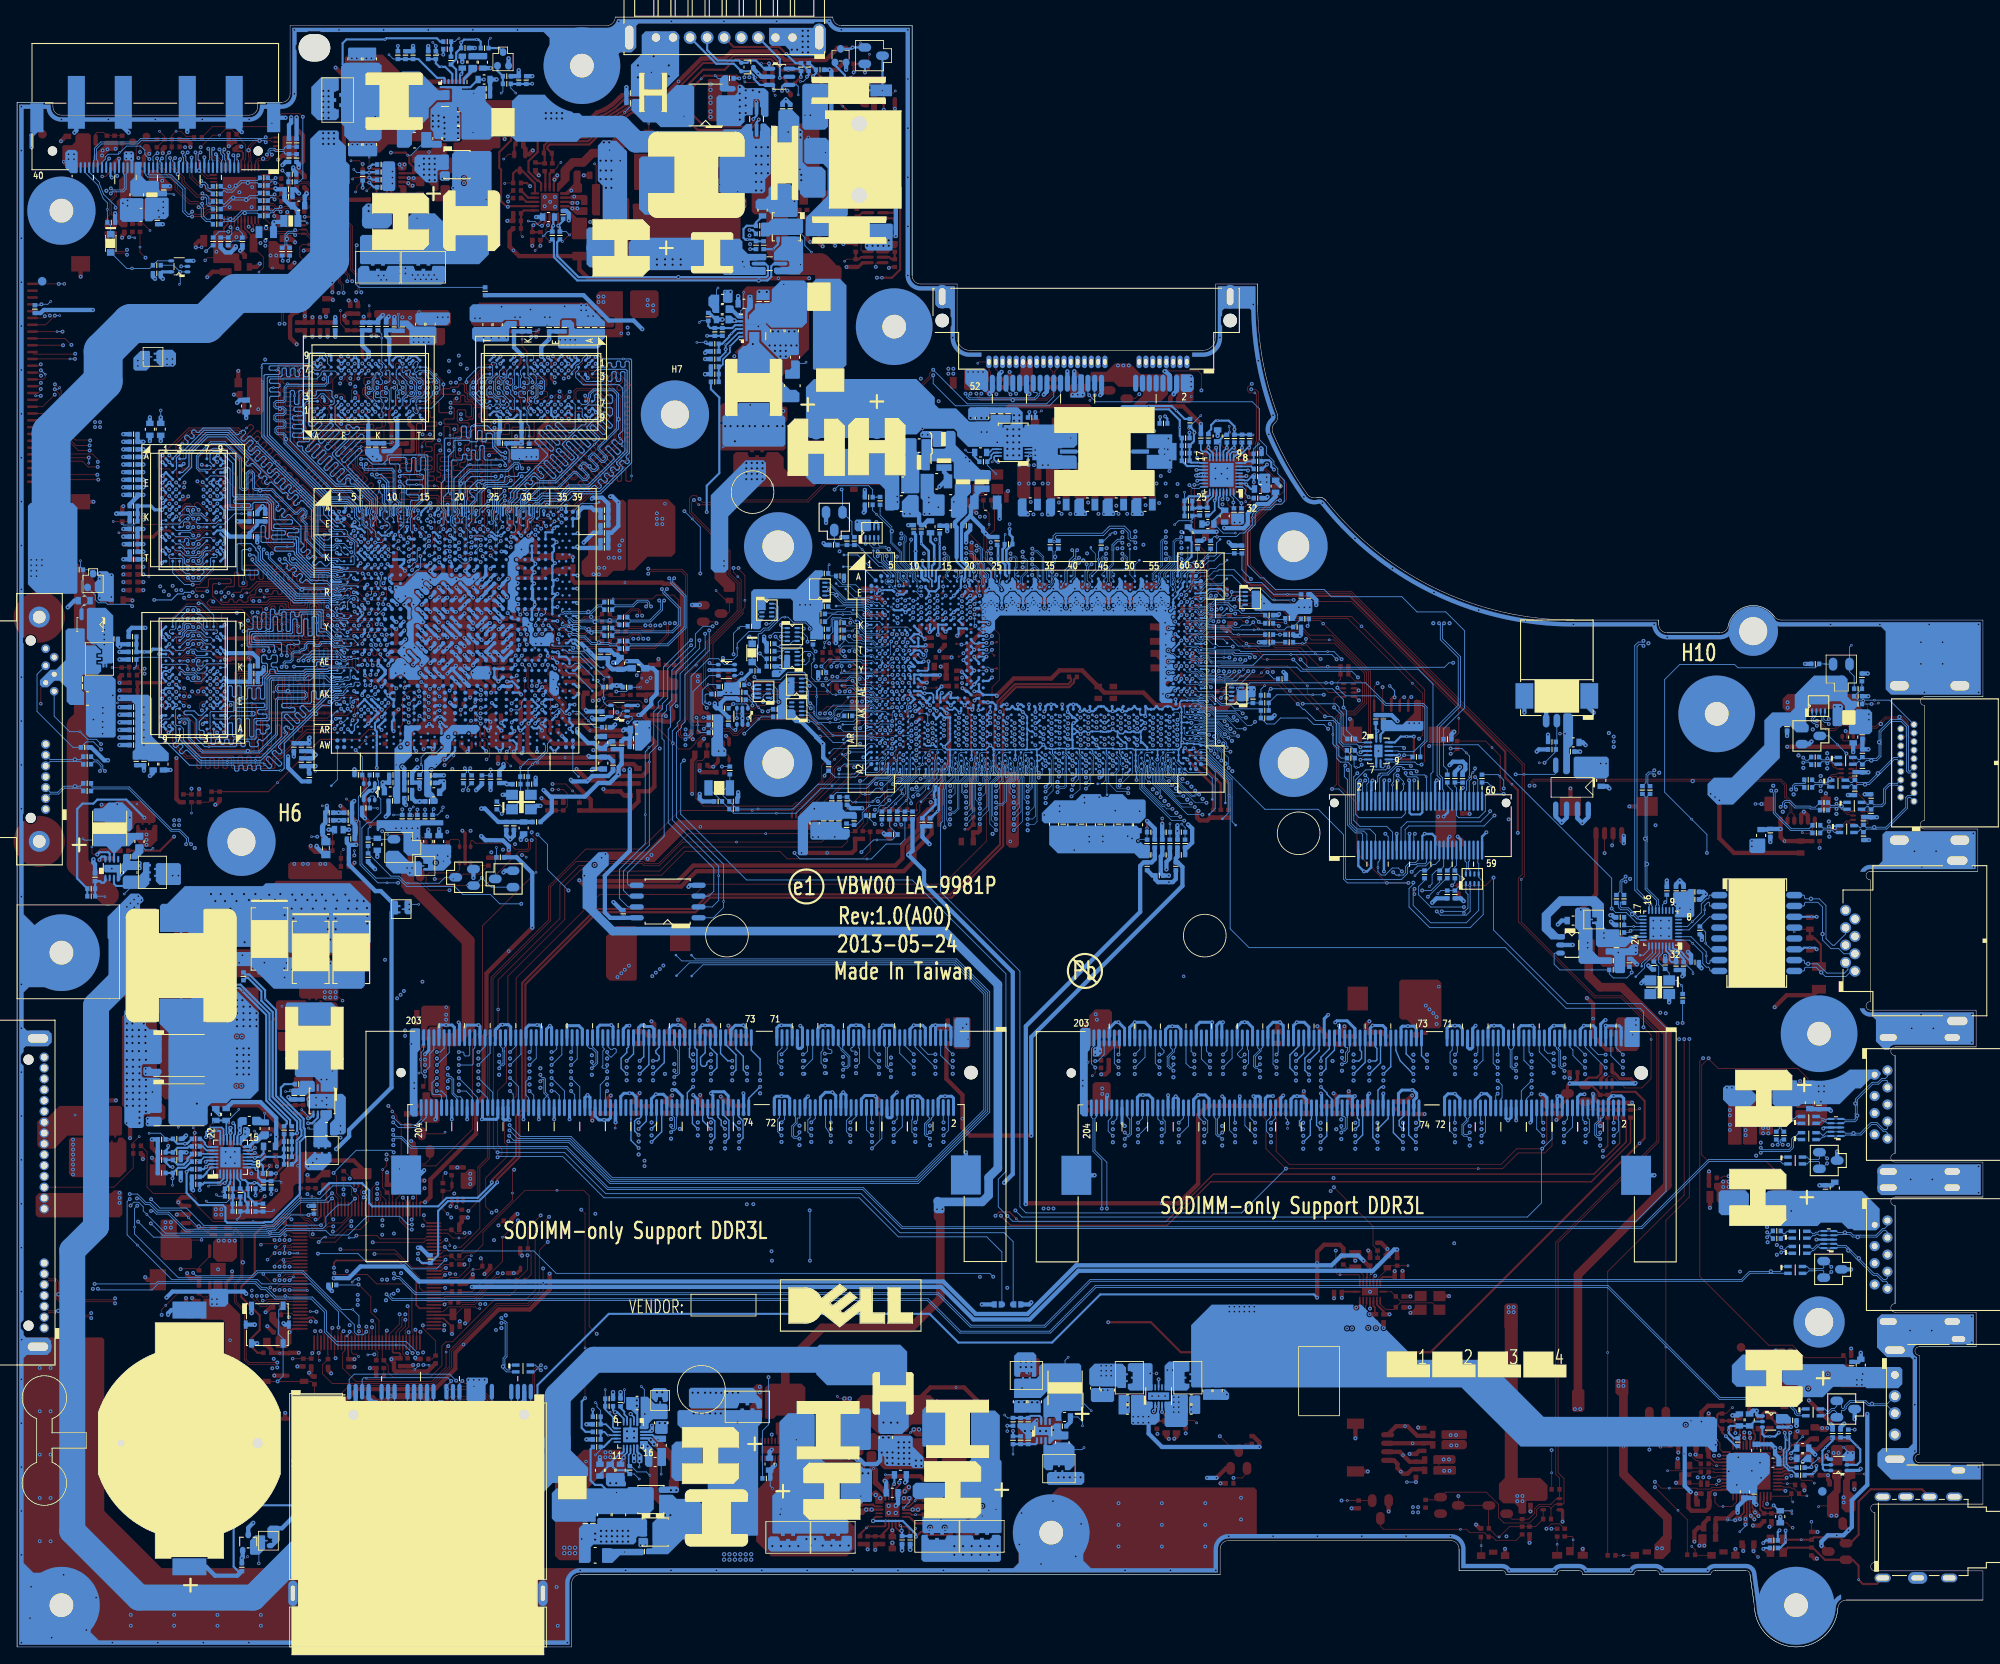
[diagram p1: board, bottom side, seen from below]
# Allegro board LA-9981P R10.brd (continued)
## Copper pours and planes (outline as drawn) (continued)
3VS on BOTTOM (solid shape): 95.91,32.97 95.91,30.11 95.85,30.05 93.31,30.05 92.99,30.36 92.99,30.87 93.5,30.87 93.56,30.94 93.56,32.27 93.06,32.27 92.99,32.33 92.99,33.41 93.06,33.48 95.41,33.48
5VS on BOTTOM (solid shape): 100.23,33.09 100.23,32.4 100.17,32.33 99.72,32.33 99.66,32.27 99.66,30.94 99.72,30.87 100.17,30.87 100.23,30.81 100.23,30.3 99.98,30.05 97.44,30.05 97.31,30.17 97.31,33.09 97.5,33.28 100.04,33.28
+0.675VS on BOTTOM (solid shape): 184.38,72.34 184.38,62.49 184.06,62.17 183.54,62.17 183.46,62.26 183.46,69.72 183.16,70.03 183.16,72.42 183.27,72.53 184.2,72.53
+0.675VS on BOTTOM (solid shape): 105.83,72.38 105.83,62.53 105.51,62.21 104.99,62.21 104.91,62.29 104.91,69.76 104.66,70.01 104.66,70.25 104.61,70.31 104.61,72.46 104.72,72.57 105.65,72.57
+0.675VS on BOTTOM (solid shape): 156.05,30.11 156.05,29.16 155.6,28.71 155.35,28.71 155.35,29.22 155.29,29.28 154.78,29.28 154.71,29.22 154.71,28.78 154.65,28.71 154.27,28.71 154.09,28.9 154.09,30.06 154.39,30.36 155.79,30.36
+0.675VS on IN2 (solid shape): 155.84,32.38 155.84,29.62 155.51,29.3 154.5,29.3 154.19,29.61 154.19,32.27 154.47,32.55 155.68,32.55
+0.675VS on IN2 (solid shape): 157.36,57.09 157.36,54.33 157.03,54 156.02,54 155.71,54.31 155.71,56.97 155.98,57.25 157.19,57.25
+0.675VS on IN3 (solid shape): 106.11,66.56 106.11,64.31 106.02,64.22 105.07,64.22 104.9,64.38 104.9,66.45 105.15,66.7 105.97,66.7
+0.675VS on IN3 (solid shape): 184.56,66.05 184.56,64.63 183.89,63.96 183.1,63.96 182.97,64.08 182.97,66.18 183.16,66.37 184.24,66.37
+0.675VS on IN3 (solid shape): 158.05,57.01 158.05,56.17 157.91,56.03 155.59,56.03 155.5,56.12 155.5,57.12 155.63,57.25 157.8,57.25
+0.675VS on TOP: 104.83,62.15 104.66,62.32 104.66,70.32 104.75,70.32 104.87,70.44 104.87,73.22 105.82,73.22 105.93,73.12 105.93,62.4 105.68,62.15
+0.675VS on TOP: 184.23,62.11 183.38,62.11 183.21,62.28 183.21,67.85 183.21,67.85 183.21,70.3 183.21,70.31 183.21,74.67 183.23,74.69 184.12,74.69 184.48,74.32 184.48,64.65 185.26,63.87 185.26,62.3 185.08,62.12 184.24,62.12
+0.675VSP on BOTTOM (solid shape): 157.32,29.28 157.32,25.93 157.44,25.81 157.44,25.6 157.38,25.54 156.49,25.54 156.37,25.66 156.37,26.19 155.86,26.69 154.28,26.69 154.15,26.82 154.15,28.34 154.33,28.52 155.66,28.52 155.68,28.53 156.49,29.35 157.26,29.35
+1.2VSP_B+ on TOP (solid shape): 178.52,176.39 179.15,176.39 179.25,176.29 179.25,174.85 178.91,174.51 178.91,173.11 178.84,173.05 178.39,173.05 178.07,173.37 175.11,173.37 174.97,173.51 174.97,175.33 174.59,175.72 173.89,175.72 173.76,175.84 173.76,177.68 174.08,178 176.92,178
+1.5VS on TOP (solid shape): 113.03,33.82 113.03,31.75 112.93,31.65 110.93,31.65 110.52,32.05 110.52,33.65 110.78,33.9 112.95,33.9
+1.05VS on TOP (solid shape): 148.67,127.63 148.67,125.24 147.59,124.17 147.59,123.81 147.47,123.69 146.38,123.69 146.23,123.84 146.23,124.69 147.24,125.69 147.24,127.62 147.38,127.76 148.53,127.76
+1.05VS on TOP (solid shape): 91.53,130.46 91.53,129.87 91.34,129.68 90.92,129.68 90.7,129.9 90.7,130.44 89.44,131.71 88.35,131.71 87.96,131.32 87.15,131.32 86.82,131.65 86.82,132.99 86.9,133.07 88.93,133.07
+1.05VS on TOP (solid shape): 64.16,98.05 64.16,94.12 63.79,93.74 61.95,93.74 61.72,93.97 61.72,94.63 61.83,94.74 61.94,95.07 61.72,95.35 61.72,98.09 61.81,98.18 64.04,98.18
+1.05VS on TOP (solid shape): 142.59,139.96 142.59,139.58 142.65,139.52 144.68,139.52 144.75,139.58 144.75,140.03 144.81,140.09 146.14,140.09 146.46,139.77 146.46,136.92 145.57,136.03 141.25,136.03 141.24,136.04 136.99,136.04 136.23,136.81 131.87,136.81 131.84,136.85 131.84,137.41 131.93,137.51 139.79,137.51 140.55,138.27 140.55,139.46 141.19,140.09 142.46,140.09
+1.05VS on BOTTOM (solid shape): 88.1,132.85 88.1,131.71 87.98,131.58 86.77,131.58 86.58,131.77 86.58,132.85 86.64,132.92 88.04,132.92
+1.05VS on BOTTOM (solid shape): 149.1,135.03 149.1,126.4 148.68,125.98 147.43,125.98 147.05,126.36 147.05,132.55 142.62,136.98 142.62,138.83 142.92,139.13 145,139.13
+1.5VS on BOTTOM (solid shape): 113.55,34.13 113.55,31.86 113.36,31.67 112.85,31.67 112.85,32.24 111.45,32.24 111.45,31.67 111.07,31.67 110.94,31.79 110.94,34.22 111.27,34.55 113.13,34.55
+1.05VS on BOTTOM (solid shape): 86.05,112.62 86.29,112.62 86.37,112.53 86.37,112.37 86.56,112.19 87.42,112.19 87.47,112.13 87.47,111.01 87.35,110.89 86.11,110.89 86.04,110.96 86.04,111.23 85.93,111.34 85.41,111.34 85.25,111.51 85.25,112.55 85.37,112.68 85.99,112.68
+1.05VS on BOTTOM (solid shape): 85.72,123.78 85.72,121.91 85.29,121.48 81.79,121.48 81.26,120.96 81.26,120.38 81.18,120.29 80.85,120.29 80.46,120.68 80.46,120.86 80.21,121.11 78.83,121.11 78.58,121.35 78.58,122.66 78.8,122.87 80.1,122.87 80.64,122.33 83.33,122.33 84.84,123.85 85.65,123.85
+1.05VS on BOTTOM (solid shape): 121.54,142.46 121.54,140.68 121.73,140.49 123,140.49 123.22,140.71 123.22,141.48 123.36,141.62 124.34,141.62 124.41,141.54 124.41,138.07 124.29,137.96 123.47,137.96 123.42,138.01 123.42,138.89 123.29,139.01 120.79,139.01 120.62,138.84 120.62,137.06 120.26,136.69 116.37,136.69 116.26,136.8 116.26,137.83 116.42,138 117.47,138 120.4,140.92 120.4,142.36 120.62,142.58 121.42,142.58
+1.5VS on IN1 (solid shape): 113.06,34.39 113.06,32.39 112.93,32.25 109.86,32.25 109.53,32.58 109.53,34.68 109.69,34.84 112.61,34.84
+1.5VS on IN2 (solid shape): outline of 83 points within 95.01,148.67 115.49,149.86
+1.05VS on IN2 (solid shape): outline of 3123 points within 62.88,96.79 87.97,135.68
+1.05VS on TOP: outline of 82 points within 119.04,93.77 121.19,113.9
+1.05VS on VCC: 126.37,108.91 125.23,110.06 117.48,110.06 116.93,110.61 116.93,139.48 119.7,142.25 125.4,142.25 128.26,139.39 145.02,139.39 146.08,138.34 146.08,128.89 142.48,125.3 138.48,125.3 132.81,119.62 132.81,108.91
+1.05VS_APLLOPI on BOTTOM (solid shape): 126.78,141.5 126.78,135.49 126.54,135.25 124.79,135.25 124.65,135.39 124.65,139.9 124.97,140.23 124.97,141.58 125.12,141.73 126.55,141.73
+1.05VS_ASATA3PLL on BOTTOM (solid shape): 126.71,134.32 126.71,132.61 126.55,132.45 124.89,132.45 124.72,132.62 124.72,134.86 124.93,135.08 125.95,135.08
+1.05VS_ASATA3PLL on BOTTOM (solid shape): 124.55,142.31 124.55,141.92 124.4,141.77 123.22,141.77 123.09,141.64 123.09,140.83 122.97,140.7 122.08,140.7 121.98,140.8 121.98,142.5 122.05,142.57 124.3,142.57
+1.05VS_ASATA3PLL on IN3 (solid shape): 125.37,142.23 125.37,141.21 125.3,141.14 123.62,141.14 123.44,141.32 123.44,142.23 123.54,142.33 125.26,142.33
+1.05VS_ASATA3PLL on IN3 (solid shape): outline of 96 points within 124.64,128.1 126.66,135.93
+1.05VS_AUSB3PLL on BOTTOM (solid shape): 120.5,136.27 120.5,135.11 120.96,134.65 120.96,132.53 120.81,132.38 119.57,132.38 119.04,132.92 119.04,134.87 118.59,135.32 118.59,136.22 118.71,136.35 120.42,136.35
+1.05VS_AXCK_DCB on TOP: 118.75,119.69 118.69,119.75 118.69,120.23 119.45,120.98 119.53,120.98 119.54,120.98 119.96,121.13 119.91,121.57 119.88,121.64 120.02,121.97 119.88,122.29 119.91,122.36 120.02,122.62 119.9,122.88 119.88,122.91 119.87,122.96 119.97,123.08 120,123.24 120,124.66 119.78,124.89 119.78,125.71 119.98,125.77 120.11,125.94 120.71,126.26 120.03,126.31 119.91,126.39 119.78,126.42 119.78,131.65 121.37,133.25 121.37,136.26 121.66,136.55 122.72,136.55 123.19,136.08 123.19,134.87 123.18,134.77 123.19,134.67 123.19,134.28 123.18,134.19 123.19,134.09 123.19,133.05 122.29,132.14 122.29,126.19 121.37,125.28 121.37,123.54 121.23,123.27 121.37,123 121.37,121.55 121.27,121.31 121.37,121.06 121.37,120.92 121.2,120.63 121.37,120.34 121.37,119.97 121.09,119.69
+1.05VSP on TOP (solid shape): 148.17,143.2 148.17,140.6 147.86,140.28 140.55,140.28 140.3,140.54 140.3,143.2 140.49,143.39 147.98,143.39
+1.5VSP on BOTTOM (solid shape): 110.63,32.87 110.63,31.79 110.94,31.47 113.42,31.47 113.55,31.35 113.55,29.19 110.44,29.19 108.91,30.71 105.93,30.71 105.67,30.97 105.67,33 105.93,33.25 110.25,33.25
+1.05VSP on BOTTOM (solid shape): 145.89,145.73 145.89,144.66 146.08,144.47 147.49,144.47 147.73,144.24 147.73,141.01 147.44,140.73 140.62,140.73 140.36,140.98 140.36,144.16 140.68,144.47 142.08,144.47 142.27,144.66 142.27,145.8 142.33,145.86 145.76,145.86
+1.8VGS on BOTTOM (solid shape): 186.69,87.4 186.69,85.96 186.59,85.86 185.81,85.86 185.75,85.93 185.75,87.36 185.91,87.52 186.58,87.52
+1.8VS on TOP (solid shape): 214.53,96.28 214.53,95.9 214.66,95.77 215.99,95.77 216.06,95.83 216.06,96.4 216.31,96.4 216.44,96.28 216.44,94.56 215.68,93.81 214.72,93.81 213.96,94.56 213.96,96.34 214.02,96.4 214.4,96.4
+1.8VS on BOTTOM (solid shape): 185.01,87.4 185.01,86.11 184.79,85.89 184.34,85.89 184.12,86.12 184.12,87.36 184.31,87.55 184.86,87.55
+1.8VS on IN1 (solid shape): 185.86,87.13 185.86,86.78 185.32,86.24 184.18,86.24 184.12,86.31 184.12,87.2 184.24,87.32 185.67,87.32
+1.8VS on IN1 (solid shape): 215.55,95.32 215.55,93.95 215.21,93.61 214.21,93.61 213.96,93.86 213.96,94.53 214.91,95.48 215.39,95.48
+1.8VSP on TOP (solid shape): 218.91,99.01 218.91,95.6 218.72,95.41 217.34,95.41 216.69,96.06 216.69,96.34 216.44,96.59 214.34,96.59 214.15,96.78 214.15,97.48 215.88,99.21 218.71,99.21
+1.8VSP on BOTTOM (solid shape): 220.37,98.34 221.3,98.34 221.45,98.19 221.45,96.84 221.39,96.78 220.18,96.78 220.14,96.75 219.02,95.62 217.22,95.62 216.9,95.94 216.9,97.9 218.02,99.02 219.69,99.02
+1.35V on BOTTOM (solid shape): 151.66,30.17 151.66,28.21 151.41,27.96 146.07,27.96 145.89,28.14 145.89,28.53 145.84,28.59 143.86,28.59 143.74,28.46 143.74,28.02 143.67,27.95 143.22,27.95 143.09,28.08 143.09,28.96 143.74,29.6 143.74,29.95 144.17,30.39 151.44,30.39
+1.35V on BOTTOM (solid shape): 102.3,99.99 102.37,99.97 102.4,99.9 102.55,99.68 102.81,99.71 102.88,99.74 102.94,99.71 103.2,99.68 103.35,99.9 103.38,99.97 103.45,99.99 105.61,99.99 106.33,99.27 108.8,99.27 110.3,97.77 110.3,96.87 110,96.57 98.82,96.57 98.12,97.26 98.12,99.18 98.31,99.38 100.22,99.38 100.84,99.99
+1.35V on TOP: outline of 190 points within 64.44,28.2 169.17,111.54 ; 1 cut-out
+1.35V_MEM_GFX on TOP (solid shape): 186.64,154.32 186.64,152.86 186.39,152.61 180.48,152.61 180.23,152.86 180.23,154.51 180.35,154.64 186.32,154.64
+1.35V_MEM_GFX on TOP (solid shape): 186.46,128.41 186.46,126.76 186.72,126.5 186.72,125.99 186.97,125.74 186.97,125.11 186.85,124.98 185.26,124.98 184.62,125.61 184.62,126.5 184.75,126.63 185.45,126.63 185.77,126.95 185.77,128.41 185.83,128.47 186.4,128.47
+1.35V_MEM_GFX on TOP (solid shape): 162.51,158.58 162.51,156.1 162.32,155.91 160.48,155.91 160.29,155.72 160.29,154.7 160.48,154.51 166.95,154.51 167.02,154.45 167.02,152.54 166.83,152.35 162.7,152.35 161.49,153.56 159.53,153.56 159.4,153.69 159.4,158.89 159.46,158.96 162.13,158.96
+1.35V_MEM_GFX on BOTTOM (solid shape): 214.08,151.86 214.08,150.62 213.58,150.12 212.04,150.12 211.77,150.39 211.77,151.68 212.18,152.1 213.84,152.1
+1.35V_MEM_GFX on BOTTOM (solid shape): 173.75,154.77 176.86,154.77 177.07,154.55 177.07,153.4 176.72,153.05 172.86,153.05 172.73,153.18 172.73,154.51 172.48,154.77 171.97,154.77 171.84,154.89 171.84,155.4 171.91,155.46 173.05,155.46
+1.35V_MEM_GFX on BOTTOM (solid shape): 185.53,155.49 185.53,154.92 185.44,154.83 184.93,154.83 184.42,154.32 184.42,152.86 184.23,152.67 181.5,152.67 181.24,152.92 181.24,154.64 181.43,154.83 183.85,154.83 184.54,155.53 185.5,155.53
+1.35V_MEM_GFX on BOTTOM (solid shape): 218.64,111.52 218.64,111.01 218.52,110.89 216.99,110.89 216.55,110.44 216.55,105.3 216.87,104.98 216.87,104.09 216.8,104.03 215.21,104.03 215.02,103.84 212.74,103.84 212.61,103.97 212.61,104.79 214.58,106.76 214.58,111.21 215.02,111.65 218.52,111.65
+1.35V_MEM_GFX on BOTTOM (solid shape): 166.57,155.46 166.57,154.77 166.51,154.7 165.81,154.7 165.75,154.64 165.75,153.88 165.88,153.75 166.83,153.75 167.02,153.56 167.02,152.42 166.83,152.23 162.32,152.23 161.87,152.67 161.87,153.12 161.49,153.5 161.49,154.45 161.62,154.58 164.99,154.58 165.11,154.7 165.11,155.21 165.49,155.59 166.45,155.59
+1.35V_MEM_GFX on IN2 (solid shape): outline of 5255 points within 158.83,103.9 217.2,158.66
+1.35V_MEM_GFX on VCC: 193.43,101.17 189.51,105.08 189.51,108.89 186.21,112.19 186.21,124.77 185.05,125.93 183.97,125.93 182.82,127.07 173.11,127.07 162.02,138.16 162.02,154.34 167.58,159.9 179.73,159.9 181.83,162 196.14,162 217.26,140.88 217.26,106.22 212.2,101.17
+1.35VGPUP on BOTTOM (solid shape): 184.88,167.33 184.88,166.38 185.7,165.56 189.96,165.56 190.21,165.3 190.21,162.25 190.08,162.13 176.24,162.13 175.1,163.27 175.1,166.57 175.73,167.21 180.56,167.21 181.45,168.1 184.12,168.1
+1.35VP on TOP (solid shape): 151.67,27.76 151.67,25.86 151.58,25.77 147.58,25.77 147.29,26.06 147.29,27.76 147.54,28.01 151.41,28.01
+1.35VP on BOTTOM (solid shape): 156.18,26.11 156.18,25.6 156.43,25.35 157.32,25.35 157.38,25.28 157.38,25.16 157.33,25.11 155.97,25.11 155.74,25.34 155.74,26.05 155.86,26.17 156.11,26.17
+1.35VP on BOTTOM (solid shape): 153.01,27.58 153.01,26.06 152.56,25.61 150.28,25.61 149.45,24.79 149.45,13.55 148.94,13.04 143.67,13.04 143.55,13.17 143.55,25.86 143.09,26.31 143.09,27.63 143.23,27.77 152.82,27.77
+1.35VP on IN2 (solid shape): 148.81,25.66 148.81,24.97 148.68,24.84 146.84,24.84 146.65,25.03 146.65,25.41 146.97,25.73 148.75,25.73
+1.35VP on IN2 (solid shape): 156.24,26.05 156.24,25.28 155.92,24.97 154.52,24.97 154.27,25.22 154.27,25.66 154.4,25.79 155.54,25.79 155.92,26.17 156.11,26.17
+1.35VS_VGA on BOTTOM (solid shape): 216.78,151.13 216.78,149.86 216.56,149.64 215.24,149.64 214.82,150.05 214.82,151.86 214.92,151.96 215.95,151.96
+1.35VS_VGA on BOTTOM (solid shape): 181.77,161.81 181.77,161.43 181.83,161.36 183.73,161.36 183.86,161.49 183.86,161.81 183.99,161.94 186.91,161.94 187.04,161.81 187.04,161.43 187.1,161.36 189.07,161.36 189.13,161.43 189.13,161.81 189.26,161.94 190.08,161.94 190.47,161.55 190.47,159.97 190.21,159.71 180.69,159.71 180.24,160.16 180.24,161.81 180.37,161.94 181.64,161.94
+1.35VS_VGA on IN2 (solid shape): 198.71,159.04 208.62,159.04 216.95,150.72 216.95,149.97 216.22,149.24 215.2,149.24 207.91,156.54 197.67,156.54 196.91,157.3 196.81,157.3 193.48,160.64 189.64,160.64 188.97,159.97 180.88,159.97 180.56,160.28 180.56,162.06 181.21,162.71 195.04,162.71
+3V_WLAN on TOP (solid shape): 107.02,147.87 107.02,146.54 106.98,146.51 105.27,146.51 105.15,146.63 105.15,147.98 105.25,148.09 106.8,148.09
+3V_WLAN on TOP (solid shape): 94.75,149.15 94.75,147.76 94.44,147.46 94.44,146.66 94.59,146.52 94.59,145.9 94.52,145.84 92.89,145.84 92.52,146.21 92.52,148.95 92.84,149.27 94.63,149.27
+3V_WLAN on TOP (solid shape): 112.81,150.68 112.81,149.38 113.12,149.07 113.12,147.97 113.02,147.87 112.31,147.87 112.22,147.96 112.22,148.17 112.09,148.3 111.45,148.3 111.35,148.39 111.35,150.7 111.4,150.75 112.74,150.75
+3V_WLAN on TOP (solid shape): 119.22,149.9 119.41,149.71 119.41,147.52 119.23,147.34 118.16,147.34 118.15,147.34 117.97,147.38 117.79,147.34 117.78,147.34 117.57,147.34 117.49,147.37 117.38,147.48 117.38,148.09 117.2,148.28 116.61,148.28 116.48,148.41 116.48,149.04 116.48,149.04 116.48,149.44 116.68,149.64 116.68,149.64 116.94,149.9 118.86,149.9
+3V_WLAN on BOTTOM (solid shape): 94.01,149.15 94.01,147.39 93.76,147.14 92.8,147.14 92.48,147.46 92.48,148.86 92.83,149.2 93.96,149.2
+3V_WLAN on BOTTOM (solid shape): 119.28,149.68 119.28,148.19 118.49,147.4 117.32,147.4 117.08,147.16 116.83,147.16 116.58,147.41 116.58,149.52 116.85,149.78 119.18,149.78
+3V_WLAN on BOTTOM (solid shape): 106.01,149.15 106.01,147.25 106.2,147.06 106.38,147.06 106.38,147.06 106.51,147.04 106.63,147.06 106.64,147.06 106.8,147.06 106.94,146.92 106.94,146.54 106.89,146.48 105.46,146.48 105.22,146.72 105.22,147.05 105.36,147.19 105.36,149.09 105.47,149.2 105.96,149.2
+3V_WLAN on IN1 (solid shape): 112.83,150.69 112.83,149.96 112.83,149.96 112.83,149.47 113.25,149.05 115.22,149.05 115.93,149.76 119.38,149.76 119.76,149.38 119.76,147.68 119.47,147.39 117.19,147.39 117.06,147.27 113.44,147.27 113.31,147.29 113.19,147.27 108.25,147.27 107.75,146.76 107.59,146.6 105.3,146.6 105.09,146.81 105.03,146.97 104.9,147.08 104.58,147.39 92.49,147.39 92.17,147.71 92.17,149.59 92.35,149.77 95.47,149.77 95.55,149.73 95.57,149.64 95.91,149.2 96.26,149.64 96.28,149.73 96.36,149.77 105.76,149.77 106.25,149.27 106.28,149.27 106.57,149.2 106.81,149.38 106.9,149.43 106.99,149.38 107.43,149.22 107.65,149.64 107.66,149.73 107.74,149.77 111.15,149.77 111.35,149.96 111.35,150.71 111.39,150.75 112.76,150.75
+3VALW on TOP (solid shape): 46.96,82.81 46.96,80.34 46.64,80.02 45.75,80.02 45.49,80.27 45.49,82.88 45.62,83.01 46.76,83.01
+3VALW on TOP (solid shape): 48.16,29.98 48.16,27.76 47.97,27.57 46.96,27.57 46.7,27.82 46.7,30.05 46.89,30.24 47.91,30.24
+3VALW on TOP (solid shape): 207.48,51.64 207.48,50.3 207.29,50.11 203.74,50.11 203.36,50.49 203.36,51.51 203.74,51.89 207.23,51.89
+3VALW on TOP (solid shape): 199.61,55.51 199.61,54.18 199.23,53.8 198.21,53.8 197.7,54.3 197.01,54.3 196.82,54.49 196.82,55.57 196.43,55.95 195.29,55.95 194.34,56.91 194.34,57.73 194.66,58.05 197.07,58.05
+3VALW on TOP (solid shape): 191.3,55.85 191.3,55.26 191.13,55.15 191.05,54.96 191.05,54.94 190.94,54.83 188.98,54.83 188.85,54.96 188.85,56.06 188.94,56.14 191.01,56.14
+3VALW on TOP (solid shape): 200.85,39.11 200.85,38.22 199.92,37.29 199.92,36.5 200.1,36.32 200.1,35.18 199.95,35.04 198.76,35.04 198.23,35.57 198.23,37.24 198.53,37.54 199.36,37.54 199.61,37.79 199.61,38.21 200.04,38.64 200.04,39.21 200.12,39.29 200.67,39.29
+3VALW on TOP (solid shape): outline of 95 points within 132.28,10.62 143.78,22.49
+3VALW on BOTTOM (solid shape): 214.14,91.74 214.14,89.78 213.71,89.34 211.35,89.34 211.19,89.5 211.19,91.7 211.41,91.91 213.97,91.91
+3VALW on BOTTOM (solid shape): 109.69,20.27 109.69,19.19 109.5,19 105.63,19 105.31,19.31 105.31,20.27 105.57,20.52 109.44,20.52
+3VALW on BOTTOM (solid shape): 195.81,57.76 196.69,56.88 196.69,56.27 196.31,55.89 194.56,55.89 193.54,56.91 193.54,57.76 193.63,57.85 195.72,57.85
+3VALW on BOTTOM (solid shape): 144.83,158.43 144.83,157.1 145.07,156.86 145.07,155.23 144.79,155.23 144.79,156.36 144.18,156.97 144.18,158.45 144.29,158.56 144.7,158.56
+3VALW on BOTTOM (solid shape): 47.81,86.47 47.81,84.37 47.4,83.96 47.4,80.34 47.15,80.08 43.54,80.08 43.47,80.15 43.47,80.78 43.57,80.88 45.01,80.88 45.75,81.62 45.75,84.29 45.95,84.49 45.95,86.38 46.26,86.69 47.59,86.69
+3VALW on BOTTOM (solid shape): 133.76,12.96 133.76,12.46 135.79,12.46 135.86,12.52 135.86,12.9 135.98,13.03 138.9,13.03 139.03,12.9 139.03,12.46 141.06,12.46 141.06,12.77 141.25,12.96 142.14,12.96 142.4,12.71 142.4,11.5 142.08,11.19 132.87,11.19 132.55,11.5 132.55,12.9 132.68,13.03 133.7,13.03
+3VALW on BOTTOM (solid shape): 95.09,29.41 95.09,28.9 95.22,28.78 95.85,28.78 95.91,28.71 95.91,27.74 95.86,27.55 95.91,27.36 95.91,25.98 95.72,25.79 93.44,25.79 93.18,26.05 93.18,27.39 93.18,29.34 93.18,29.47 93.31,29.6 94.9,29.6
+3VALW on IN2 (solid shape): 208.82,51.51 208.82,49.79 208.31,49.29 204.44,49.29 203.67,50.05 203.67,51.26 204.18,51.76 208.56,51.76
+3VALW on IN2 (solid shape): 212.5,90.56 212.5,88.99 212.25,88.74 211.51,88.74 211.29,88.96 211.29,90.55 211.47,90.73 212.33,90.73
+3VALW on IN2 (solid shape): 198.55,24.44 198.55,20.85 198.28,20.58 196.56,20.58 196.18,20.97 196.18,24.27 196.69,24.78 198.21,24.78
+3VALW on VCC: 176.79,8.84 168.47,17.16 157.91,17.16 155.44,14.68 145.21,14.68 141.97,11.44 132.85,11.44 129.61,14.68 124.59,14.68 119.83,19.44 40.46,19.44 39.27,20.63 39.27,28.39 92.53,28.33 93.73,29.54 97.15,29.54 98.48,28.27 172.83,28.39 178.87,22.36 205.54,22.36 207.29,20.61 207.29,8.94 207.19,8.84
+3VALW_PCH on TOP (solid shape): 122.96,51.29 122.96,50.23 122.7,49.98 121.88,49.98 121.7,50.16 121.7,51.41 121.81,51.52 122.73,51.52
+3VALW_PCH on TOP (solid shape): 132.83,110.96 132.83,109.96 132.74,109.87 130.69,109.87 130.53,110.03 130.53,110.43 130.62,110.51 131.61,110.51 131.71,110.61 131.71,110.98 131.81,111.09 132.71,111.09
+3VALW_PCH on TOP (solid shape): 142.76,30.37 142.76,26.87 142.64,26.75 141.75,26.75 141.38,27.13 138.14,27.13 138.01,27.25 138.01,30.43 138.46,30.87 142.25,30.87
+3VALW_PCH on TOP (solid shape): 156.65,93.26 161.92,93.26 162.14,93.04 162.14,92.4 162.02,92.28 156.91,92.28 156.68,92.05 155.68,92.05 151.9,95.82 136.72,95.82 136.45,96.09 136.45,96.69 136.7,96.94 152.97,96.94
+3VALW_PCH on TOP (solid shape): outline of 107 points within 147.54,108.34 151.46,114.21
+3VALW_PCH on BOTTOM (solid shape): 122.97,52.15 122.97,51.1 122.72,50.84 121.89,50.84 121.71,51.03 121.71,52.27 121.82,52.38 122.74,52.38
+3VALW_PCH on BOTTOM (solid shape): 147.54,113.03 147.54,112.34 147.81,112.08 148.3,112.08 148.39,111.99 148.39,111.47 148.36,111.44 147.79,111.44 147.62,111.62 145.75,111.62 145.7,111.67 145.7,113 145.8,113.1 147.47,113.1
+3VALW_PCH on BOTTOM (solid shape): 148.81,109.29 148.81,106.74 149.04,106.51 149.04,104.6 148.85,104.4 147.55,104.4 147.55,104.41 147.37,104.41 147.27,104.51 147.27,105.24 147.67,105.64 147.67,106.75 147.67,106.82 147.67,106.9 147.67,109.06 147.96,109.36 148.75,109.36
+3VALW_PCH on BOTTOM (solid shape): 141.14,112.75 141.14,111.2 141.09,111.15 140.82,110.74 141.21,110.45 141.28,110.42 141.32,110.35 141.32,108.91 141.19,108.79 139.69,108.79 139.22,108.32 138.92,108.32 138.6,108.63 138.6,108.81 139.16,109.36 139.16,109.71 139.39,109.94 140.07,109.94 140.2,110.08 140.2,110.99 139.28,111.91 139.28,113.63 139.32,113.67 140.22,113.67
+3VALW_PCH on BOTTOM (solid shape): 164.13,91.31 164.13,86.64 163.99,86.5 162.59,86.5 162.44,86.64 162.44,90.27 161.05,91.67 161.05,91.69 162.36,91.69 162.36,91.64 162.38,91.59 162.39,91.54 162.42,91.49 162.45,91.45 162.49,91.41 162.54,91.38 162.59,91.36 162.64,91.34 162.69,91.34 162.74,91.34 162.8,91.34 162.85,91.36 162.89,91.38 162.94,91.41 162.98,91.45 163.01,91.49 163.04,91.54 163.06,91.59 163.07,91.64 163.07,91.69 163.07,91.74 163.06,91.8 163.04,91.85 163.01,91.89 162.98,91.93 162.94,91.97 162.89,92 162.85,92.02 162.8,92.04 162.74,92.05 162.69,92.05 162.64,92.04 162.59,92.02 162.54,92 162.49,91.97 162.45,91.93 162.42,91.89 162.39,91.85 162.38,91.8 162.36,91.74 162.36,91.69 161.05,91.69 161.05,92.92 161.32,93.19 162.25,93.19
+3VALW_PCH on IN1 (solid shape): outline of 203 points within 131.72,110.63 147.54,114.98
+3VALW_PCH on IN1 (solid shape): outline of 265 points within 135.35,91.13 157.21,108.13
+3VALW_PCH on IN2 (solid shape): 148.14,111.89 148.14,110.06 148.97,109.22 148.97,106.3 152.3,102.97 152.3,99.77 152.19,99.66 150.94,99.66 150.87,99.74 150.87,102.95 149.62,104.2 147.66,104.2 146.96,104.89 146.96,106.44 147.02,106.53 147.12,106.53 147.67,106.82 147.12,107.12 147.02,107.11 146.96,107.2 146.96,110.77 146.04,111.7 146.04,112.69 146.29,112.94 147.08,112.94
+3VALW_PCH on IN3 (solid shape): 151.29,114.26 151.29,112.51 150.24,111.47 146.54,111.47 146.38,111.63 146.38,112.9 146.84,113.36 147.73,113.36 149.15,114.78 150.77,114.78
+3VALWP on BOTTOM (solid shape): 141.06,26.39 141.06,18.55 141.89,17.73 141.89,13.41 141.76,13.28 133.12,13.28 132.97,13.44 132.97,14.77 134.27,16.08 134.27,20.2 136.93,22.87 136.93,27.22 137.13,27.41 140.05,27.41
+3VGS on TOP (solid shape): 175.62,115.08 175.62,114.52 175.73,114.4 176.64,114.4 176.76,114.52 177.18,114.52 177.52,114.19 177.52,114.17 177.56,114.02 177.65,113.9 177.65,113.32 177.64,113.22 177.67,113.11 177.67,112.84 177.48,112.66 175.99,112.66 175.87,112.53 175.73,112.42 175.66,112.26 175.64,112.23 175.61,112.22 175.2,112.22 175.13,112.3 175.13,112.84 175.31,113.03 175.64,113.03 175.9,113.29 175.9,113.8 175.81,113.89 174.88,113.89 174.74,114.02 174.74,114.95 174.95,115.16 175.54,115.16
+3VGS on BOTTOM (solid shape): 176.56,115 176.59,114.99 176.61,114.96 176.71,114.82 176.86,114.73 176.88,114.73 177.24,114.37 177.24,114.03 177.24,114.01 177.22,113.99 177.11,113.83 177.08,113.64 177.08,113.62 177.07,113.6 176.91,113.43 175.1,113.43 174.95,113.59 174.95,114.8 175.14,115
+3VGS on BOTTOM (solid shape): outline of 126 points within 179.51,91.01 188.27,96.94
+3VGS on TOP: 175.6,94.55 175.22,94.93 175.22,98.97 175.57,99.32 175.57,103.41 175.82,103.66 175.82,105.23 175.41,105.64 175.41,106.18 175.52,106.29 176.67,106.29 176.77,106.19 176.77,105.02 177.9,103.89 179.25,103.89 179.6,103.54 179.6,101.5 179.96,101.14 180.27,101.14 180.37,101.13 180.47,101.14 183.23,101.14 183.94,101.86 183.94,105 183.95,105.05 183.94,105.11 183.94,105.35 183.77,105.52 183.77,106.17 183.87,106.26 184.17,106.26 184.25,106.23 184.27,106.15 184.27,106.13 184.27,105.72 184.5,105.49 184.73,105.72 184.73,106.13 184.73,106.15 184.75,106.23 184.83,106.26 187.59,106.26 187.67,106.18 187.67,103.45 186.82,102.6 186.82,95.79 186.53,95.51 182.96,95.51 182.91,95.46 182.89,95.46 182.56,95.12 182.04,95.12 181.89,94.97 176.99,94.97 176.57,94.55
+3VLP on BOTTOM (solid shape): 201.07,13.92 201.07,12.9 200.94,12.77 200.56,12.77 200.5,12.71 200.5,12.2 200.56,12.14 201.01,12.14 201.13,12.01 201.13,11.76 200.94,11.57 200.5,11.57 199.61,12.46 199.61,14.04 199.8,14.23 200.75,14.23
+3VS on TOP (solid shape): 56.1,40.02 56.1,37.48 55.97,37.35 54.64,37.35 54.51,37.48 54.51,40.08 54.7,40.27 55.85,40.27
+3VS on TOP (solid shape): 185.39,91.39 185.39,89.1 185.19,88.91 184.12,88.91 183.86,89.16 183.86,91.45 183.99,91.58 185.19,91.58
+3VS on TOP (solid shape): 179.61,19.44 179.61,17.75 179.51,17.65 177.82,17.65 177.58,17.88 177.58,19.18 178.06,19.66 179.39,19.66
+3VS on TOP (solid shape): 66.69,110.89 66.69,109.48 67.6,108.58 67.6,108.12 67.49,108.02 65.97,108.02 65.84,108.15 65.84,110.91 65.95,111.03 66.55,111.03
+3VS on TOP (solid shape): 219.35,53.23 227.81,53.23 228.22,52.81 228.22,50.68 227.92,50.37 218.38,50.37 218.06,50.69 218.06,53.37 218.23,53.54 219.03,53.54
+3VS on TOP (solid shape): 177.89,55.62 178.37,55.62 178.41,55.58 178.41,53.84 178.26,53.69 178.05,53.69 178.04,53.7 177.18,53.7 176.63,54.24 176.63,55.79 176.87,56.03 177.48,56.03
+3VS on TOP (solid shape): 103.82,70.99 103.82,70.39 103.9,70.32 104.18,70.32 104.36,70.13 104.36,69.4 104.18,69.22 102.86,69.22 101.92,70.16 101.1,70.16 101.04,70.22 101.04,70.97 101.17,71.1 103.71,71.1
+3VS on TOP (solid shape): 56.73,19.12 56.73,17.35 56.23,16.84 54.89,16.84 54.45,16.39 54.45,15.76 54.32,15.63 53.62,15.63 53.53,15.73 53.53,17.01 53.41,17.13 51.26,17.13 51.03,17.36 51.03,18.97 51.88,19.82 56.04,19.82
+3VS on TOP (solid shape): 102.72,149.51 104.45,149.51 104.59,149.37 104.59,148.43 104.49,148.34 101.9,148.34 101.31,147.75 98.79,147.75 98.45,147.41 98.45,146.77 100.49,144.73 100.73,144.73 101.39,144.08 101.39,143.64 101.32,143.57 100.25,143.57 97.77,146.05 96.32,146.05 95.51,146.86 95.51,149.13 95.6,149.22 95.8,149.22 95.8,149.21 95.91,149.2 96.02,149.21 96.03,149.22 98.69,149.22 99.96,150.49 101.74,150.49
+3VS on TOP (solid shape): 217.96,175.21 217.96,172.48 218.47,171.97 218.47,170.93 218.33,170.79 218.33,169.92 218.72,169.53 218.72,169.06 218.69,169.05 218.5,168.78 218.61,168.46 218.65,168.39 218.63,168.32 218.54,168.11 218.61,167.89 218.63,167.86 218.59,167.81 218.59,167.03 218.57,167.03 218.57,166.8 218.21,166.44 217.58,166.44 217.45,166.57 217.45,167.08 217.96,167.59 217.96,167.66 217.97,167.67 218,167.77 218.01,167.86 218.01,168.29 218,168.39 217.97,168.48 217.96,168.49 217.96,168.86 217.98,168.9 218.01,168.91 218.35,169.31 217.92,169.62 217.84,169.63 217.8,169.69 217.56,169.95 217.21,169.87 217.14,169.84 217.07,169.87 216.94,170 215.67,170 215.23,170.44 215.23,171.4 215.61,171.78 215.61,173.08 215.71,173.18 216.13,173.18 216.44,173.49 216.44,174 216.65,174.21 216.65,174.59 216.66,174.6 216.66,175.18 216.88,175.4 217.77,175.4
+3VS on TOP (solid shape): outline of 392 points within 180.01,64.44 182.85,72.72
+3VS on BOTTOM (solid shape): 132.24,132 132.24,131.04 132,130.81 130.48,130.81 130.31,130.98 130.31,132.08 130.42,132.2 132.04,132.2
+3VS on BOTTOM (solid shape): 84.97,137.36 84.97,136.35 84.97,136.35 84.93,136.35 84.93,136.31 84.61,135.99 84.61,135.41 84.54,135.33 83.67,135.33 83.53,135.48 83.53,137.48 83.62,137.58 84.75,137.58
+3VS on BOTTOM (solid shape): 187.19,93.07 187.19,91.57 186.3,90.68 184.81,90.68 184.5,90.37 183.16,90.37 182.93,90.6 182.93,91.88 183.16,92.11 184.47,92.11 185.71,93.36 186.91,93.36
+3VS on BOTTOM (solid shape): 70.58,108.62 70.58,107.58 70.37,107.37 65.8,107.37 65.58,107.59 65.58,108.46 65.67,108.56 67.62,108.56 68.01,108.17 68.76,108.17 68.88,108.29 69.27,108.68 70.52,108.68
+3VS on BOTTOM (solid shape): 140.49,116.25 140.49,115.65 140.55,115.59 140.55,114.82 140.81,114.56 141.76,114.56 141.95,114.37 141.95,113.8 141.85,113.7 141.09,113.7 140.11,114.68 139.94,114.68 139.79,114.83 139.79,116.22 139.92,116.34 140.4,116.34
+3VS on BOTTOM (solid shape): 103.79,72.34 103.79,70.5 104,70.29 104.09,70.29 104.13,70.28 104.31,70.1 104.31,69.26 104.28,69.23 103.67,69.23 103.24,69.66 103.24,70.15 103.39,70.29 103.39,72.31 103.51,72.42 103.71,72.42
+3VS on BOTTOM (solid shape): 217.86,175.21 217.86,174.42 217.74,174.3 217.19,174.3 217.11,174.22 217.11,172.86 217.02,172.78 216.87,172.78 216.76,172.88 216.76,174.01 216.77,174.02 216.77,174.24 216.7,174.31 216.7,175.15 216.88,175.33 217.73,175.33
+3VS on BOTTOM (solid shape): 22.06,111.63 22.06,110.09 22.58,109.58 24.69,109.58 25.62,108.65 25.62,105.75 29.45,101.93 31.52,101.93 32.29,101.17 32.29,99.9 31.14,98.75 29.28,98.75 23.8,104.23 23.8,107.68 23.49,107.99 22.6,107.99 21.83,107.22 20.6,107.22 20.43,107.39 20.43,108.07 20.71,108.36 20.71,109.97 20.18,110.5 18.22,110.5 17.86,110.87 16.68,110.87 16.18,110.37 16.18,109.52 16.09,109.42 15.58,109.42 15.44,109.56 15.44,109.56 14.74,110.26 14.74,110.81 14.86,110.94 15.39,110.94 15.86,111.4 15.86,113.48 16.27,113.9 19.79,113.9
+3VS on BOTTOM (solid shape): 139.09,124.03 144.05,124.03 144.36,123.71 144.36,119.58 144.11,119.33 143.41,119.33 143.22,119.52 143.22,120.15 142.99,120.39 142.96,120.5 143.06,120.56 143.31,120.56 143.55,120.72 143.49,120.99 143.46,121.07 143.49,121.14 143.55,121.41 143.31,121.57 142.9,121.57 142.85,121.56 142.8,121.54 142.7,121.55 142.65,121.64 142.65,122.57 142.3,122.91 139.76,122.91 139.47,122.63 139.47,120.47 139.25,120.25 137.92,120.25 137.8,120.12 137.77,120.09 137.38,119.7 137.37,119.69 137.18,119.37 137.41,119.08 137.44,119.06 137.44,118.18 137.38,118.12 136.05,118.12 135.92,118.25 135.92,119.58 136.36,120.03 136.36,121.3 135.92,121.74 135.92,122.5 136.35,122.93 136.35,125.18 136.34,125.18 135.92,125.6 135.92,126.13 136.03,126.24 136.88,126.24
+3VS on BOTTOM (solid shape): outline of 326 points within 31.17,22.84 92.8,40.14
+3VS on IN2 (solid shape): 105.55,70.6 105.55,69.44 105.3,69.19 103.14,69.19 102.89,69.44 102.89,70.68 103.11,70.9 105.25,70.9
+3VS on IN2 (solid shape): 110.36,53.47 110.36,51.3 110.12,51.06 108.88,51.06 108.65,51.28 108.65,53.41 108.96,53.71 110.12,53.71
+3VS on IN2 (solid shape): 214.28,100.15 214.28,96.53 213.2,95.45 211.29,95.45 211.04,95.71 211.04,99.96 211.61,100.53 213.9,100.53
+3VS on IN2 (solid shape): outline of 557 points within 176.58,54.02 184.37,71.63
+3VS on IN3 (solid shape): outline of 87 points within 177.19,18.87 228.31,53.18
+3VS on TOP: 62.77,16.39 62.77,15 63.08,14.68 66.89,14.68 67.47,15.25 67.47,16.46 67.28,16.65 63.02,16.65
+3VS on TOP: outline of 247 points within 120.05,112.55 148.66,150.09
+3VS on BOTTOM: 202.19,164.05 201.14,164.05 201.06,164.13 201.06,164.93 201.28,165.14 201.37,165.14 201.48,165.26 201.48,166.46 201.65,166.63 202.41,166.63 202.46,166.58 202.46,164.32
+3VS on IN1: 67.08,15.44 67.15,15.5 67.15,16.77 66.89,17.03 65.05,17.03 64.93,16.9 64.93,15.7 65.18,15.44
+3VS on IN1: 55.91,17.98 53.69,17.98 53.5,17.79 53.5,16.71 53.88,16.33 56.04,16.33 56.16,16.46 56.16,17.73
+3VS on VCC: 48.01,38.94 36.35,50.6 36.35,63.04 32.99,66.41 32.99,96.45 27.91,101.53 27.91,114.03 26.49,115.45 22,115.45 22,119.13 23.65,119.13 24.69,119.39 25.5,120.1 27.27,120.79 28.61,119.45 29.4,118.14 30.84,117.63 37,117.63 38.31,118.04 39.14,119.13 48,119.13 64.58,122.91 77.89,133.5 79.18,133.61 80.2,134.41 82.5,138.03 84.4,141.87 84.55,143.16 83.97,144.32 85.69,150.76 86.27,157.4 86.27,158.53 88.66,158.53 88.66,153.52 89.47,151.56 91.43,150.75 118.73,150.75 120.69,151.56 121.5,153.52 121.5,158.53 124.5,158.53 126.11,159.19 126.77,160.8 126.77,188.83 133.8,188.83 134.87,189.09 135.68,189.83 159.42,189.83 160.23,189.09 161.3,188.83 197.13,188.83 197.13,182.1 197.79,180.49 199.4,179.83 201.06,179.83 201.89,178.74 203.2,178.33 225.2,178.33 226.5,178.74 227.34,179.83 229.13,179.83 229.13,121.42 220.33,121.42 219.36,120.45 219.36,114.9 221.77,112.49 221.77,89.14 219.74,87.11 219.74,43.04 216.14,39.44 194.93,39.44 194.42,38.94 186.66,38.94 185.64,37.92 184.81,37.92 183.8,38.94 176.11,38.94 175.35,39.7 172.49,39.7 171.73,38.94 ; 2 cut-outs
+3VS on IN2: 220.55,125.27 220.36,124.95 220.55,124.64 220.55,122.49 220.38,122.19 220.55,121.89 220.55,121.17 219.91,120.54 217.82,120.54 217.33,121.03 217.33,123.25 216.8,123.77 216.81,142.3 218.47,143.97 221.2,143.97 221.45,143.71 221.45,142 220.55,141.09 220.55,136.99 220.55,136.98 220.53,136.87 220.55,136.75 220.55,136.74
+3VS_RT on IN1: 193.14,158.92 193.14,160.93 195.73,163.52 195.73,173.03 196.68,173.97 197.8,173.97 199.72,172.05 199.72,167.97 200.5,167.19 200.5,166.77 199.44,165.71 199.44,162.97 199.41,162.9 199.33,162.87 199.16,162.86 199.01,162.77 198.94,162.75 198.88,162.78 198.28,162.52 198.88,162.26 198.94,162.29 199.01,162.27 199.16,162.18 199.33,162.17 199.41,162.14 199.44,162.07 199.44,161.87 199.92,161.39 210.83,161.39 210.9,161.36 210.93,161.27 211.28,160.87 211.63,161.27 211.65,161.36 211.73,161.39 213.08,161.39 213.78,160.69 213.78,159.01 212.89,158.11 193.42,158.11 193.14,158.39 193.14,158.61 193.14,158.62 193.16,158.76 193.14,158.9
+5V_HDD on TOP (solid shape): 226.75,62.13 227.22,62.12 227.49,62.13 228.03,61.58 228.03,58.79 227.66,58.42 226.03,58.42 224.49,59.95 218.25,59.95 218.09,60.12 218.09,63.22 218.3,63.43 225.44,63.43
+5V_USB_PWR1 on TOP (solid shape): 20.02,66.07 20.02,63.2 20.29,62.94 21.9,62.94 21.99,62.85 21.99,61.35 21.75,61.11 18.93,61.11 18.27,61.77 18.27,66.01 18.43,66.18 19.92,66.18
+5V_USB_PWR1 on BOTTOM (solid shape): 15.62,67.7 17.64,66.61 19.92,66.43 19.93,66.43 21.08,66.43 21.43,65.99 21.77,66.43 23.97,66.43 24.67,65.73 24.67,63.7 24.35,63.38 21.56,63.38 21.3,63.64 16.79,63.64 14.95,65.48 14.32,65.48 13.16,66.64 12.49,66.64 12.05,67.08 11.97,67.08 11.97,67.32 12.35,67.7
+5V_USB_PWR2 on TOP (solid shape): 25.05,53.41 25.05,50.75 24.86,50.56 22.44,50.56 22,51 22,53.29 22.32,53.6 24.86,53.6
+5V_USB_PWR2 on BOTTOM (solid shape): 25.56,53.1 25.56,49.99 24.92,49.35 19.38,49.35 18.99,49.75 16.56,49.75 15.83,49.02 15.32,49.02 15.14,48.84 12.54,48.84 12.09,49.29 12.09,51.38 14.19,53.48 25.17,53.48
+5V_USB_PWR3 on TOP (solid shape): 16.86,32.27 16.86,30.68 16.6,30.43 13.94,30.43 13.74,30.62 13.74,31.95 14.25,32.46 16.67,32.46
+5V_USB_PWR3 on BOTTOM (solid shape): outline of 116 points within 9.44,29.28 23.52,33.16
+5V_USB_PWR4 on TOP (solid shape): 213.58,49.99 213.58,45.79 213.13,45.35 210.21,45.35 209.9,45.67 209.9,47.76 210.09,47.95 211.23,47.95 211.67,48.4 211.67,49.99 211.8,50.11 213.45,50.11
+5V_USB_PWR4 on TOP (solid shape): 204.91,47.88 205.68,47.88 205.72,47.88 205.76,47.89 207.04,47.89 207.44,47.49 207.44,45.65 206.94,45.16 205.13,45.16 204.63,45.67 204.63,47.76 204.75,47.89 204.9,47.89
+5V_USB_PWR4 on IN2 (solid shape): 208.88,47.83 208.88,46.49 208.5,46.11 205.01,46.11 204.63,46.49 204.63,48.27 204.88,48.52 208.18,48.52
+5V_USB_PWR4 on IN2 (solid shape): 213.33,49.86 213.33,47.89 212.94,47.51 210.53,47.51 210.15,47.89 210.15,49.73 210.47,50.05 213.13,50.05
+5VALW on TOP (solid shape): 30.89,54.43 31.4,54.43 31.52,54.3 31.52,53.73 31.21,53.41 31.21,52.27 30.95,52.02 29.87,52.02 29.37,52.53 27.84,52.53 27.71,52.65 27.71,53.41 27.91,53.6 29.3,53.6 29.56,53.86 29.56,54.68 29.68,54.81 30.51,54.81
+5VALW on TOP (solid shape): 23.71,33.79 23.71,29.6 23.46,29.35 21.94,29.35 21.56,29.73 21.56,31.19 21.3,31.44 19.65,31.44 19.59,31.51 19.59,32.27 19.78,32.46 21.11,32.46 21.87,33.22 21.87,33.92 22.13,34.17 23.33,34.17
+5VALW on TOP (solid shape): 167.35,19.76 167.35,10.68 166.84,10.17 164.3,10.17 163.6,10.87 163.6,18.49 162.27,19.82 159.67,19.82 159.01,20.48 159.01,22.45 159.18,22.62 159.68,23.12 163.99,23.12
+5VALW on TOP (solid shape): 207.36,42.81 207.36,41.29 207.8,40.84 208.44,40.84 208.63,40.65 208.63,40.14 208.88,39.89 208.88,38.43 208.82,38.36 206.34,38.36 206.09,38.11 206.09,33.03 205.83,32.78 204.63,32.78 204.24,33.16 204.24,39 206.34,41.1 206.34,42.81 206.47,42.94 207.23,42.94
+5VALW on TOP (solid shape): 28.35,64.91 28.35,64.18 28.13,63.97 28.13,59.04 27.99,58.9 26.56,58.9 26.48,58.98 26.48,61.62 26.23,61.87 24.64,61.87 24.58,61.94 24.58,62.82 24.71,62.95 26.17,62.95 26.47,63.26 26.47,64.69 26.81,65.03 28.22,65.03
+5VALW on BOTTOM (solid shape): 207.86,41.73 207.86,40.08 207.67,39.89 206.02,39.89 205.64,40.27 205.64,41.73 205.9,41.98 207.61,41.98
+5VALW on BOTTOM (solid shape): 116.17,13.03 116.17,12.65 116.23,12.58 118.33,12.58 118.33,12.96 118.46,13.09 121.38,13.09 121.5,12.96 121.5,12.65 121.57,12.58 123.54,12.58 123.66,12.71 123.66,13.09 123.73,13.16 124.3,13.16 124.43,13.03 124.43,10.23 124.17,9.98 115.28,9.98 115.09,10.17 115.09,12.96 115.28,13.16 116.04,13.16
+5VALW on BOTTOM (solid shape): 99.85,29.47 99.85,26.24 99.66,26.05 96.99,26.05 96.49,26.55 96.49,27.32 96.57,27.55 96.49,27.78 96.49,28.71 96.55,28.78 96.68,28.78 96.74,28.71 96.74,28.01 96.78,27.97 96.78,27.71 96.8,27.69 96.8,27.57 96.84,27.53 96.85,27.52 97.36,27.33 97.45,27.87 97.44,27.89 97.31,28.01 97.31,28.65 97.44,28.78 97.95,28.78 98.14,28.97 98.14,29.41 98.26,29.54 99.79,29.54
+5VALW on IN1 (solid shape): 104.22,26.19 106.9,26.19 120.57,12.52 124.04,12.52 125.76,10.81 131.09,10.81 131.66,11.38 147.54,11.38 147.86,11.06 147.86,10 147.6,9.75 116.01,9.75 114.65,11.11 114.65,14.46 106.03,23.07 99.66,23.07 97.37,25.36 97.37,27.03 97.73,27.39 103.02,27.39
+5VALW on IN2 (solid shape): 125.63,10.93 131.28,10.93 131.73,11.38 147.54,11.38 147.86,11.06 147.86,10 147.6,9.75 115.38,9.75 114.65,10.49 114.65,11.76 115.41,12.52 124.04,12.52
+5VALW on IN3 (solid shape): outline of 380 points within 158.78,21.73 206.2,37.92
+5VALW on VCC: 166.67,1.27 166.67,7.48 166.01,9.09 164.4,9.75 90.67,9.75 90.67,11.48 90.01,13.09 88.4,13.75 62.4,13.75 60.79,13.09 60.13,11.48 60.13,10.25 56.4,10.25 55.73,10.12 55.17,9.75 50.63,9.75 50.07,10.12 49.4,10.25 47.4,10.25 46.73,10.12 46.17,9.75 41.63,9.75 41.07,10.12 40.4,10.25 38.4,10.25 37.73,10.12 37.17,9.75 32.63,9.75 32.07,10.12 31.4,10.25 27.84,10.25 27.84,12.56 27.31,13.09 26.3,13.09 25.68,13.7 25.68,15.27 26.57,16.16 26.57,18.4 26.3,18.68 25.2,18.68 24.86,18.34 24.86,17.39 24.75,17.28 20.64,17.28 20.48,17.45 20.48,19.02 20.64,19.19 24.71,19.19 25.05,19.53 25.05,22.68 29.47,22.68 29.79,23 31.52,23 31.52,28.27 23.55,28.27 21.7,26.43 21.05,26.43 21.05,63.57 29.71,63.57 30.32,62.96 30.32,55.09 30.76,54.64 30.76,42.01 38.76,34 38.76,20.42 40.25,18.93 119.62,18.93 124.38,14.17 129.4,14.17 132.64,10.93 142.18,10.93 145.42,14.17 155.65,14.17 158.12,16.65 168.26,16.65 176.58,8.33 207.19,8.33 208.82,6.7 208.82,1.27
+5VALWP on BOTTOM (solid shape): outline of 195 points within 115.02,13.35 124.3,27.73
+5VS on TOP (solid shape): 38.51,12.01 38.51,10.36 38.45,10.3 37.49,10.3 36.6,11.19 36.6,12.84 36.8,13.03 37.49,13.03
+5VS on TOP (solid shape): 43.08,31.25 43.08,29.79 42.76,29.47 41.68,29.47 41.56,29.6 41.56,31.25 41.68,31.38 42.95,31.38
+5VS on TOP (solid shape): 33.37,13.09 33.37,12.08 33.49,11.95 33.49,11.76 33.37,11.63 32.54,11.63 32.41,11.76 32.41,13.09 32.54,13.22 33.24,13.22
+5VS on TOP (solid shape): 20.22,26.05 20.22,25.47 20.09,25.35 19.98,25.35 19.27,25.35 19.21,25.35 19.08,25.22 18.25,25.22 18,25.47 18,25.73 18.19,25.92 19.14,25.92 19.33,26.11 20.16,26.11
+5VS on TOP (solid shape): 218.58,59.59 218.58,59.21 218.63,59.15 219.95,59.15 219.99,59.19 219.99,59.51 219.98,59.52 219.98,59.65 220.06,59.73 224.11,59.73 224.32,59.51 224.32,55.48 223.92,55.08 218.34,55.08 217.59,55.83 217.59,59.29 218.02,59.73 218.44,59.73
+5VS on TOP (solid shape): 23.49,111.15 23.49,110.1 23.05,109.67 19.15,109.67 18.85,109.97 16.44,109.97 16.28,110.12 15.52,110.12 15.28,109.88 15.28,109.62 14.56,108.9 13.76,108.9 13.73,108.93 13.73,109.58 14.65,110.5 14.65,111.51 14.88,111.74 22.9,111.74
+5VS on BOTTOM (solid shape): 17.61,110.47 17.61,108.07 17.5,107.97 16.62,107.97 16.41,108.17 16.41,110.37 16.62,110.57 17.51,110.57
+5VS on BOTTOM (solid shape): 27.38,94.59 27.38,93.29 27.16,93.08 25.68,93.08 25.5,93.26 25.5,94.71 25.57,94.78 27.19,94.78
+5VS on BOTTOM (solid shape): 47.97,104.21 47.97,102.12 47.65,101.8 44.16,101.8 43.84,102.12 43.84,104.15 44.08,104.39 47.79,104.39
+5VS on BOTTOM (solid shape): 104.74,32.59 104.74,30.81 104.49,30.55 101.57,30.55 101.37,30.36 100.49,30.36 100.42,30.43 100.42,32.78 100.87,33.22 104.11,33.22
+5VS on BOTTOM (solid shape): 222.22,121.68 222.22,118.18 221.58,117.55 221.14,117.55 220.64,117.04 220.54,117.04 220.43,116.93 220.43,116.48 220.43,116.38 220.91,116.38 220.95,116.34 220.95,116.15 220.89,116.09 220.51,116.09 220.51,116.09 220.44,116.09 220.43,116.08 220.37,116.03 220.37,115.58 220.44,115.52 220.95,115.52 220.95,115.39 220.88,115.33 220.44,115.33 220.41,115.3 220.41,115.21 220.41,114.84 220.4,114.82 220.21,114.82 220.14,114.9 220.14,115.23 220.07,115.3 219.3,115.3 219.11,115.49 219.11,118.4 219.12,118.42 219.12,120.93 220.02,121.84 222.06,121.84
+5VS on IN1 (solid shape): 33.43,11.95 33.43,10.81 33.3,10.68 32.54,10.68 32.41,10.81 32.41,12.08 32.48,12.14 33.24,12.14
+5VS on IN1 (solid shape): 38.45,11.63 38.45,10.74 38.26,10.55 36.92,10.55 36.73,10.74 36.73,11.44 37.05,11.76 38.32,11.76
+5VS on IN1 (solid shape): 19.59,26.66 19.59,25.83 19.09,25.33 18.16,25.33 18.02,25.47 18.02,25.78 18.48,26.24 18.48,26.83 18.52,26.87 19.37,26.87
+5VS on IN1 (solid shape): 43.02,31.32 43.02,30.55 42.86,30.4 42.29,30.4 42.26,30.36 40.8,30.36 40.73,30.43 40.73,31.19 40.99,31.44 42.89,31.44
+5VS on IN2 (solid shape): 27.79,96.29 27.79,93.74 27.54,93.49 26.82,93.49 26.5,93.8 26.5,96.19 26.83,96.52 27.55,96.52
+5VS on IN2 (solid shape): 45.34,103.99 45.34,103.26 45.11,103.03 42.55,103.03 42.3,103.28 42.3,104 42.62,104.32 45.01,104.32
+5VS on BOTTOM: 89.37,132.34 88.42,132.34 88.29,132.22 88.29,131.25 88.58,130.96 89.3,130.96 89.5,131.16 89.5,132.22
+5VS on IN1: 218.38,143.7 218.12,143.99 218.09,144 218.09,152.92 220.31,155.14 220.31,156.22 221.07,156.98 221.96,156.98 222.47,156.47 222.47,154.44 219.99,151.97 219.99,122.49 220.83,121.66 220.83,117.14 220.63,116.94 220.09,116.94 218.09,118.95 218.09,133.26 218.09,133.27 218.09,133.58 218.09,133.59 218.09,137.33 218.09,137.34 218.09,137.64 218.09,137.65 218.09,142.71 218.25,142.94 218.19,143.21 218.18,143.29 218.22,143.35
+5VS on VCC: 209.32,1.27 209.32,6.91 207.65,8.58 207.8,8.73 207.8,20.82 205.75,22.87 179.08,22.87 173.04,28.9 98.68,28.78 97.35,30.05 93.52,30.05 92.32,28.84 39.27,28.9 39.27,34.22 31.27,42.22 31.27,54.85 30.83,55.3 30.83,63.17 29.92,64.08 21.05,64.08 21.05,76.72 27.19,76.72 27.33,76.87 27.33,90.88 22,90.88 22,114.95 26.28,114.95 27.4,113.82 27.4,101.31 32.48,96.23 32.48,66.2 35.84,62.83 35.84,50.39 47.8,38.43 171.99,38.43 172.75,39.19 175.16,39.19 175.92,38.43 183.54,38.43 184.56,37.41 185.89,37.41 186.91,38.43 194.63,38.43 195.14,38.94 216.35,38.94 220.25,42.83 220.25,86.9 222.28,88.93 222.28,112.7 219.87,115.11 219.87,120.24 220.54,120.91 229.13,120.91 229.13,1.27
+5VS_ODD on BOTTOM (solid shape): 224.72,119.16 224.72,115.7 225.84,114.58 226.5,114.58 227.72,113.35 227.72,112.79 227.44,112.51 226.79,112.51 226.02,113.28 225.41,113.28 224.6,112.46 224.6,110.85 224.18,110.44 222.6,110.44 222.53,110.5 222.53,111.9 222.81,112.17 222.81,113.86 222.8,113.86 222.65,114.02 220.92,114.02 220.54,114.4 220.54,115.15 220.57,115.18 221.08,115.18 221.11,115.21 221.11,115.69 221.08,115.72 220.56,115.72 220.55,115.73 220.55,115.95 220.56,115.96 221.03,115.96 221.09,115.96 221.11,115.98 221.11,116.5 221.09,116.52 220.55,116.52 220.55,116.85 220.56,116.86 220.64,116.86 221.19,117.42 222.27,117.42 222.47,117.62 222.47,119.32 222.57,119.42 224.45,119.42
+DVCC33 on TOP (solid shape): 199.29,177.05 199.29,174.76 199.04,174.51 197.7,174.51 197.58,174.64 197.58,177.05 197.7,177.18 199.16,177.18
+DVCC33 on TOP (solid shape): 204.28,166.1 204.56,165.95 204.85,166.08 204.86,166.1 204.91,166.1 205.25,165.76 205.33,165.76 205.76,165.6 205.99,165.99 206.02,166.07 206.1,166.1 207.27,166.1 207.41,165.96 207.41,162.35 207.32,162.25 205.1,162.25 204.94,162.09 204.94,161.41 204.89,161.35 204.18,161.35 204.1,161.43 204.1,162.46 204.36,162.71 204.36,163.27 204.48,163.4 205.56,163.4 206.25,164.09 206.25,164.76 206.21,164.81 204.88,164.81 204.66,165.02 203.56,165.02 203.38,165.19 203.38,165.36 203.39,165.37 203.47,165.54 203.48,165.73 203.48,165.75 203.83,166.1
+DVCC33 on IN3: 201.63,163.27 201.4,163.5 199.27,163.5 198.16,164.6 198.07,164.94 197.73,165.04 196.37,166.39 196.37,167.63 196.38,167.64 196.38,170.84 196.88,171.33 198.97,171.33 199.8,172.16 199.8,173.94 199.55,174.19 199.55,174.51 199.67,174.64 200.05,174.64 200.88,173.81 200.88,169.3 201.93,168.25 206.83,168.25 207.8,167.28 207.8,163.62 207.48,163.3 206.32,163.3 206.15,163.47 206.15,166.67 205.97,166.85 204.4,166.85 204.12,166.57 204.12,166.06 204.44,165.75 204.82,165.75 204.97,165.59 204.97,165.16 204.73,164.92 204.21,164.92 202.56,163.27
+VCC_PWR_SRC on TOP (solid shape): 118.02,142.33 117.81,142.12 116.74,142.12 116.29,142.58 116.29,143.53 116.41,143.66 118.02,143.66
+VCC_PWR_SRC on BOTTOM (solid shape): 137.95,147.71 137.95,142.19 137.51,141.74 127.08,141.74 126.66,142.16 124.96,142.16 124.3,142.82 120.59,142.82 120.23,142.47 120.23,142 118.95,140.71 114.96,140.71 114.91,140.76 114.91,143.3 114.75,143.46 114.1,143.46 113.96,143.6 113.96,144.42 114.01,144.47 116.23,144.47 116.3,144.4 116.3,143.88 116.51,143.67 118.8,143.67 120.35,145.22 122.36,145.22 122.84,145.71 122.84,146.51 125,148.66 137,148.66
+VDD_MEM15_REFDA on IN3 (solid shape): outline of 342 points within 172.82,124.49 181.21,127.47
+VDD_MEM15_REFDB on IN3 (solid shape): outline of 780 points within 183.63,102.82 195.96,120.63
+VDDCI on TOP (solid shape): outline of 915 points within 176.55,107.02 186.28,126.86
+VDDCI on BOTTOM (solid shape): 195.93,182.89 195.93,179.78 195.16,179.02 193.01,179.02 192.69,179.33 192.69,180.29 193.2,180.29 193.26,180.35 193.26,182.32 193.13,182.45 192.81,182.45 192.69,182.57 192.69,183.84 192.88,184.03 194.78,184.03
+VDDCI on BOTTOM (solid shape): outline of 300 points within 176.19,114.9 186.24,126.03
+VDDCI on IN1 (solid shape): outline of 592 points within 176.62,114.68 186.42,125.8
+VDDCI on VCC: 183.52,112.34 182.59,113.27 182.59,121.85 181.93,122.5 165.42,122.5 156.75,131.18 156.75,164.88 160.92,169.05 182.89,169.05 184.94,171.1 184.94,180.69 187.08,182.83 194.78,182.83 195.04,182.57 195.04,181.07 195.05,181.06 195.05,178.82 195.99,177.87 195.99,162.57 181.7,162.57 179.54,160.41 167.37,160.41 161.51,154.55 161.51,137.95 172.9,126.57 182.61,126.57 183.76,125.42 184.84,125.42 185.7,124.56 185.7,112.34
+VDDCIP on BOTTOM (solid shape): 192.43,185.3 192.43,178.64 192.05,178.26 192.05,177.18 191.42,176.54 187.99,176.54 187.67,176.86 187.67,185.43 187.99,185.75 191.99,185.75
+VDDR4 on TOP (solid shape): 186.55,114.96 186.55,114.95 186.63,114.83 186.75,114.75 186.84,114.72 186.91,114.66 186.91,113.48 186.84,113.41 186.27,113.41 186,113.69 185.07,113.69 184.68,114.08 184.68,115.27 184.85,115.44 186.07,115.44
+VDDR4 on BOTTOM (solid shape): 186.08,115.64 186.09,115.63 186.16,115.46 186.31,115.34 186.32,115.34 186.52,115.14 186.52,115.11 186.57,114.91 186.72,114.76 186.73,114.76 186.75,114.73 186.75,113.63 186.63,113.51 186.23,113.51 185.84,113.91 185.73,113.91 185.71,113.91 185.7,113.92 185.46,114.02 185.23,113.92 185.2,113.91 185.16,113.91 184.63,113.38 183.33,113.38 183.31,113.38 183.3,113.39 183.21,113.46 183.11,113.49 183.11,113.5 183.11,113.75 183.12,113.77 183.13,113.79 183.15,113.81 183.16,113.81 183.49,114.19 183.16,114.57 183.13,114.59 183.11,114.62 183.11,114.82 183.13,114.84 183.14,114.85 183.26,114.95 183.34,115.08 183.35,115.11 183.38,115.12 183.62,115.12 183.63,115.11 183.63,115.08 183.99,114.82 184.34,115.09 184.34,115.11 184.56,115.32 184.57,115.33 184.73,115.42 184.83,115.58 184.83,115.59 185.09,115.85 185.11,115.86 185.2,115.9 185.28,115.95 185.77,115.95
GND on TOP (solid shape): 26.24,61.49 26.24,60.16 26.11,60.03 24.78,60.03 24.59,60.22 24.59,61.55 24.72,61.68 26.05,61.68
GND on TOP (solid shape): 99.79,136.47 99.79,134.69 99.66,134.57 98.39,134.57 98.26,134.69 98.26,136.47 98.39,136.6 99.66,136.6
GND on TOP (solid shape): 103.15,138.76 103.15,134.82 102.9,134.57 101.82,134.57 101.63,134.76 101.63,138.82 101.69,138.89 103.03,138.89
GND on TOP (solid shape): 104.35,65.95 104.35,62.59 104.25,62.49 102.8,62.49 102.22,63.07 102.22,65.99 102.45,66.22 104.08,66.22
GND on TOP (solid shape): 106.45,138.63 106.45,134.76 106.26,134.57 105.12,134.57 104.93,134.76 104.93,138.76 105.06,138.89 106.2,138.89
GND on TOP (solid shape): 109.82,138.63 109.82,134.82 109.63,134.63 108.49,134.63 108.3,134.82 108.3,138.5 108.61,138.82 109.63,138.82
GND on TOP (solid shape): 113.12,26.55 113.12,23.95 112.93,23.76 108.42,23.76 107.92,24.27 107.92,26.62 108.17,26.87 112.8,26.87
GND on TOP (solid shape): 113.19,138.63 113.19,134.88 112.93,134.63 111.85,134.63 111.66,134.82 111.66,138.69 111.73,138.76 113.06,138.76
GND on TOP (solid shape): 118.9,145.17 118.9,144.03 118.71,143.84 116.61,143.84 116.17,144.28 116.17,145.3 116.23,145.36 118.71,145.36
GND on TOP (solid shape): 130.3,176.76 130.3,174.69 130.1,174.49 129.44,174.49 129.33,174.59 129.33,176.84 129.44,176.95 130.11,176.95
GND on TOP (solid shape): 149.44,183.72 149.44,179.14 149.19,178.89 147.98,178.89 147.79,179.08 147.79,183.78 147.86,183.84 149.32,183.84
GND on TOP (solid shape): 158.55,158.88 158.55,156.16 158.2,155.81 155.53,155.81 155.21,156.13 155.21,158.8 155.48,159.06 158.37,159.06
GND on TOP (solid shape): 214.98,173.11 214.98,170.83 214.85,170.7 212.37,170.7 212.18,170.89 212.18,171.33 214.02,173.18 214.91,173.18
GND on TOP (solid shape): 220.69,98.82 220.69,95.77 220.37,95.45 219.23,95.45 219.14,95.55 219.14,98.91 219.17,98.94 220.56,98.94
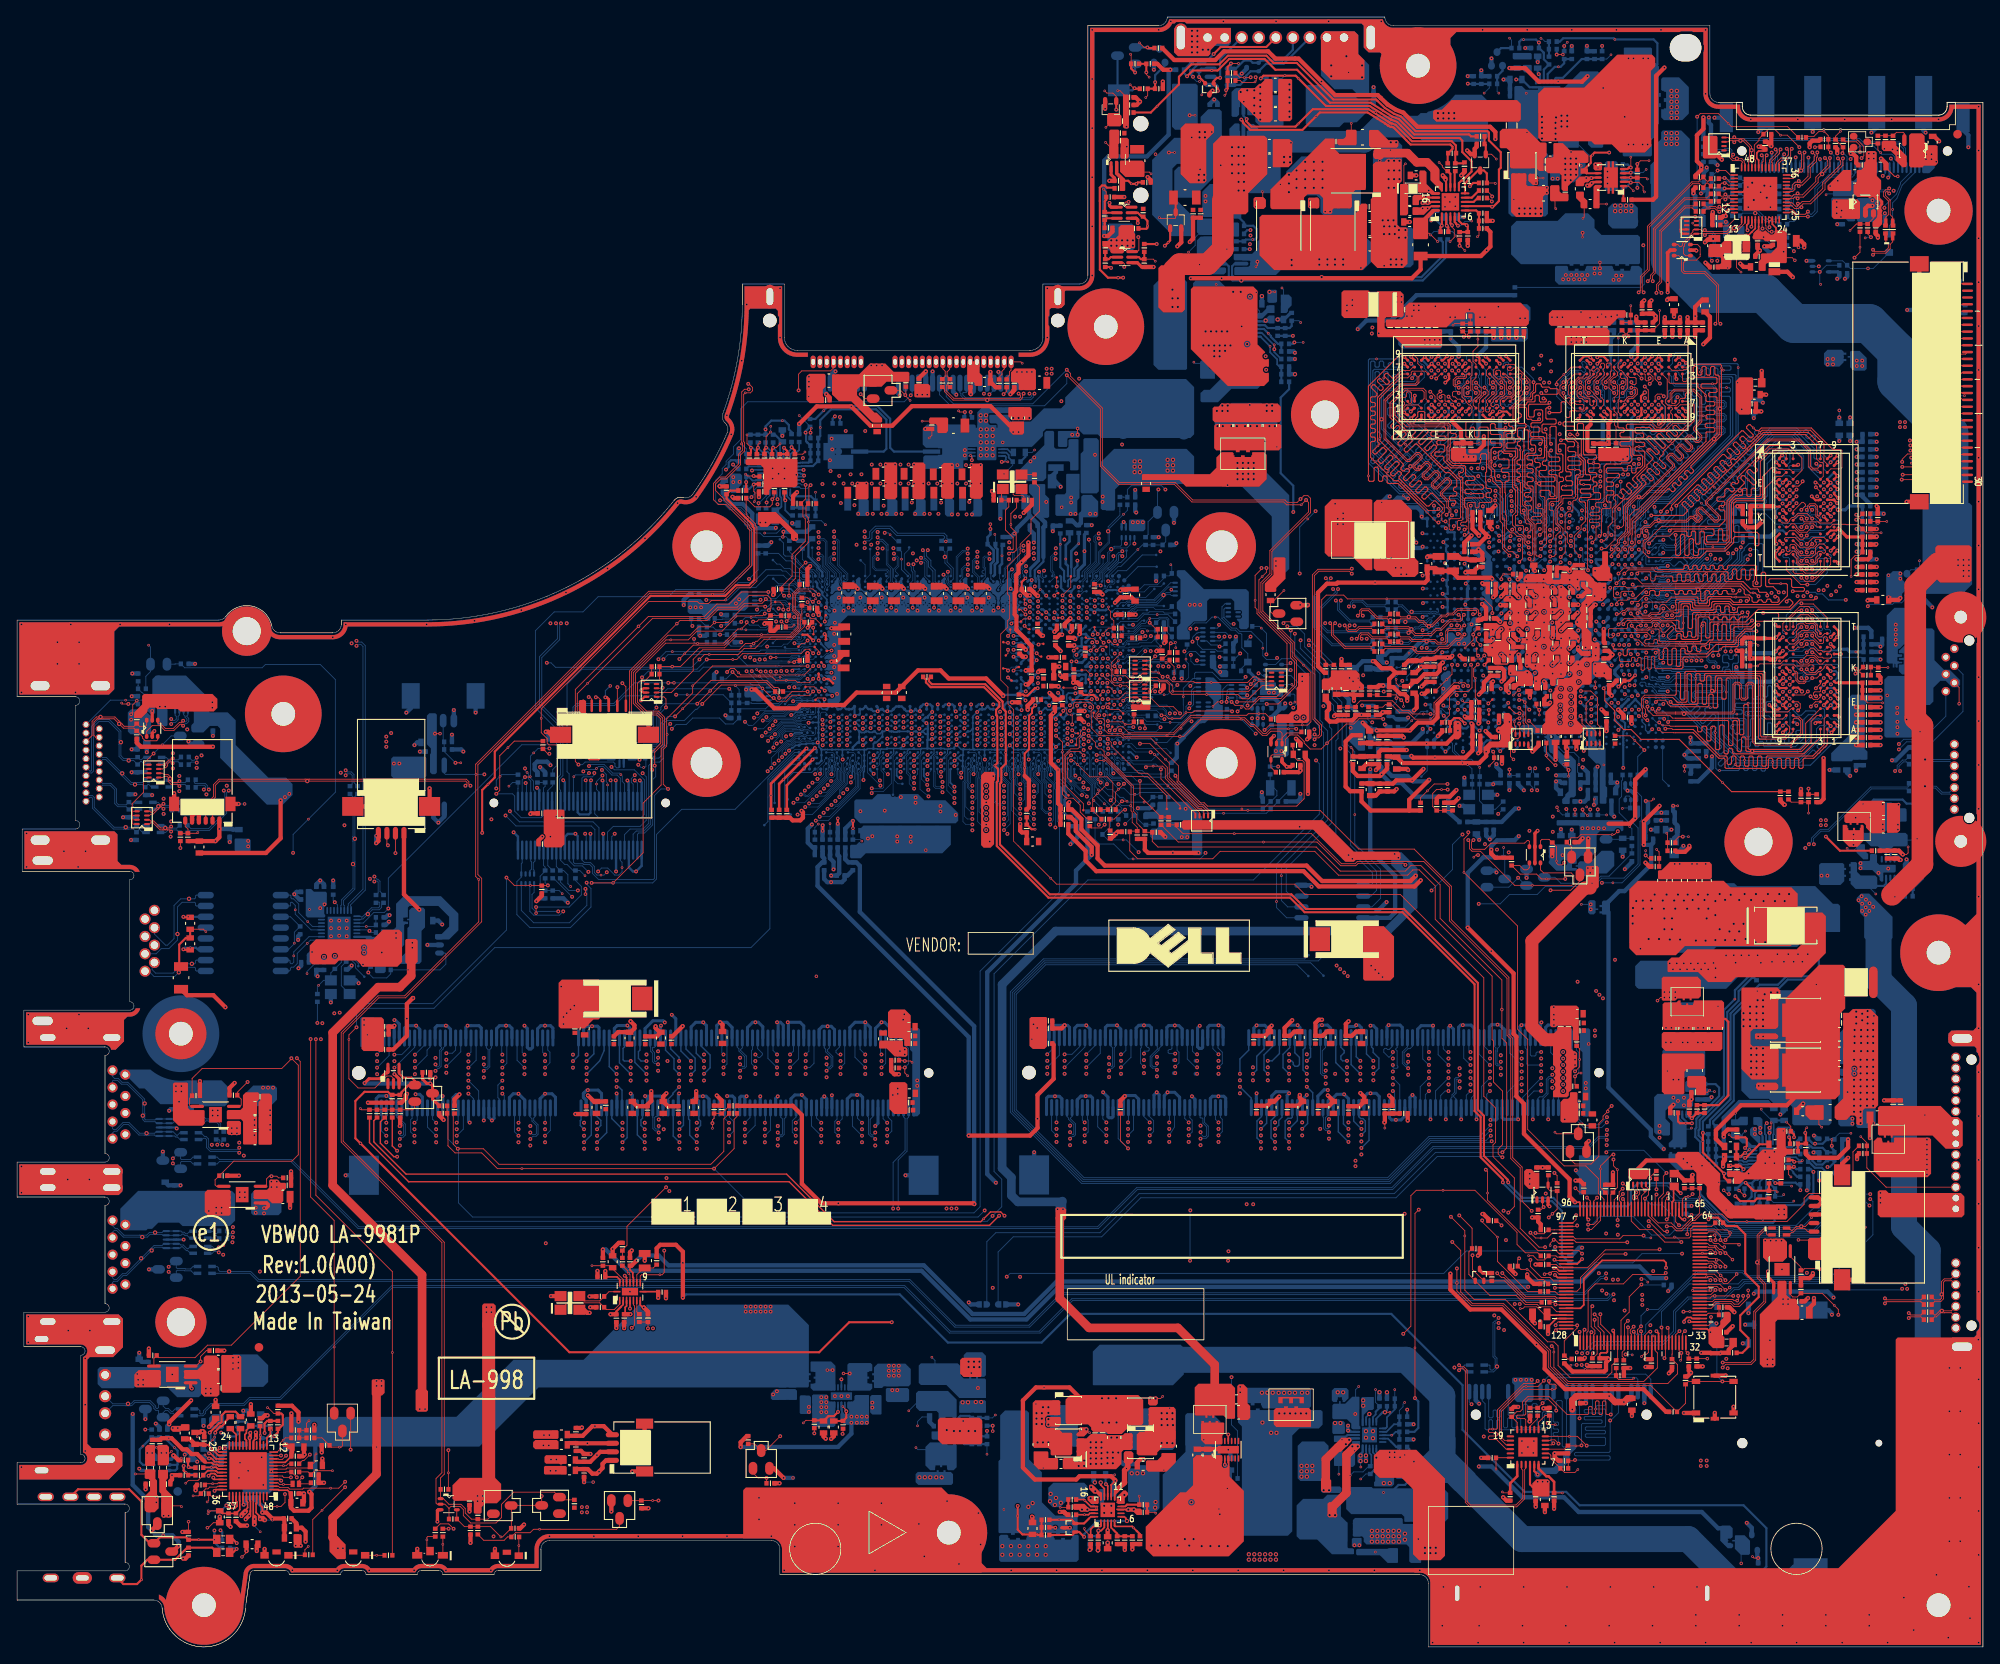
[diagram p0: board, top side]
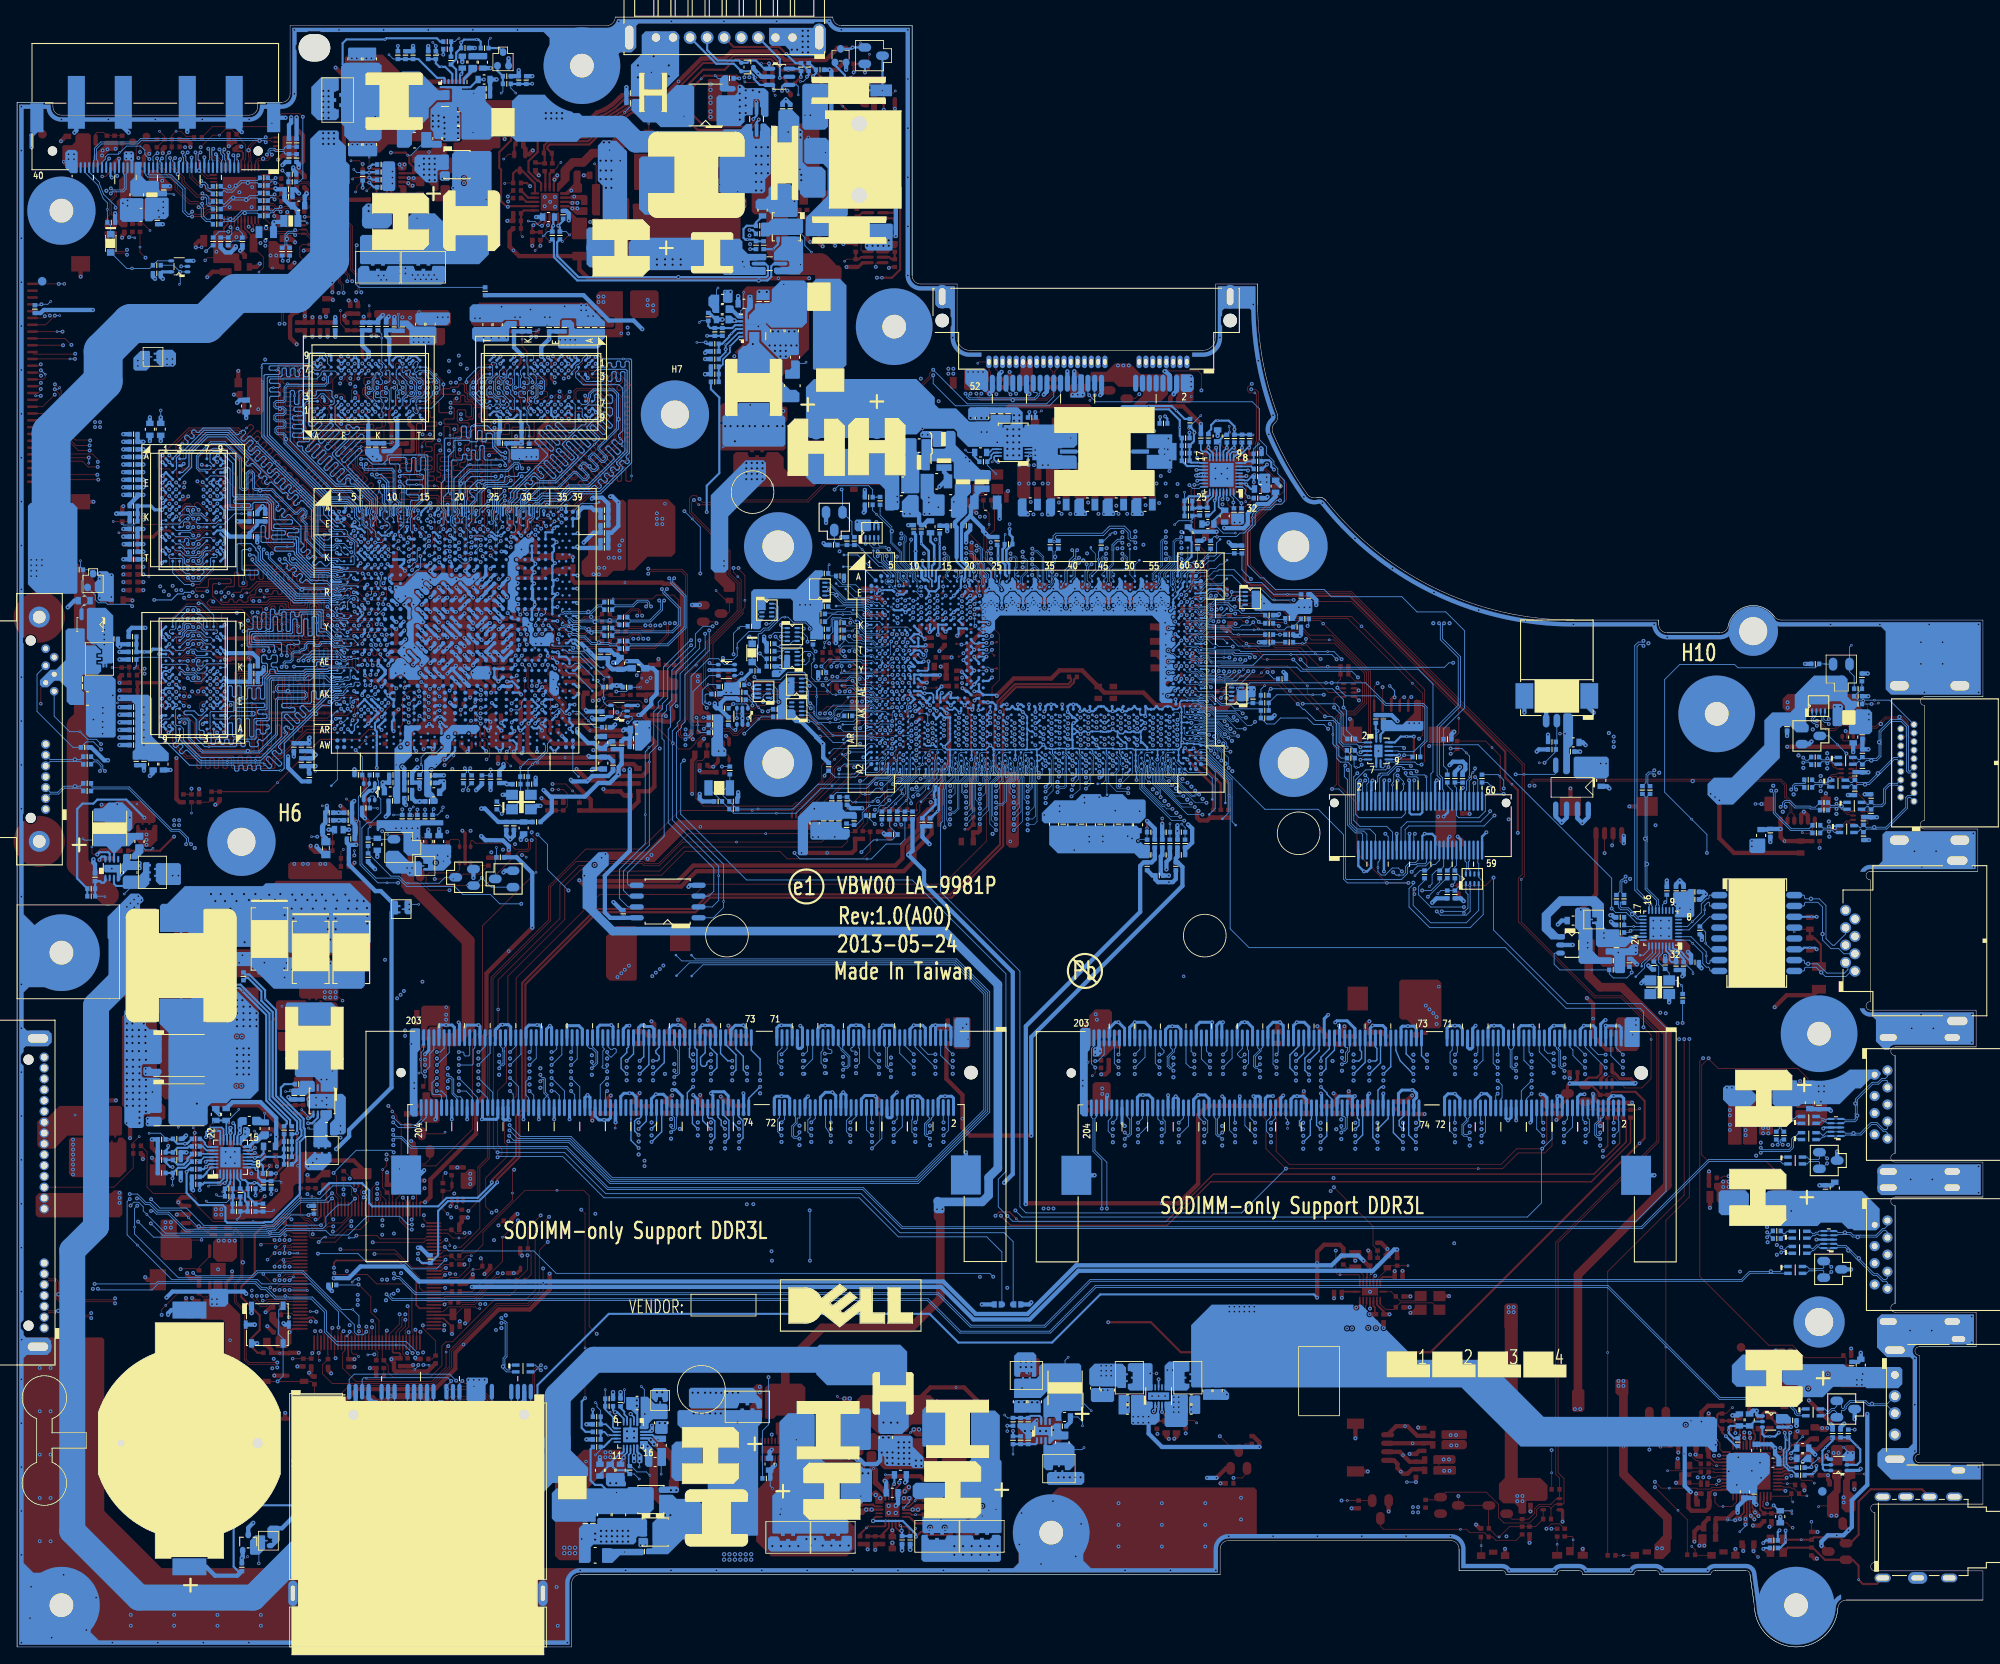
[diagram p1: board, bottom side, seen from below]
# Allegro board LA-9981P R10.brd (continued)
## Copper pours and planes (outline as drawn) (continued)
GND on TOP (solid shape): 26.29,34.01 26.29,30.01 26.08,29.81 24.07,29.81 23.91,29.97 23.91,34.12 24.03,34.24 26.06,34.24
GND on TOP (solid shape): 144.21,30.34 144.21,28.57 144.52,28.25 144.52,26.86 144.27,26.61 143.32,26.61 143.01,26.93 143.01,30.6 143.21,30.81 143.73,30.81
GND on TOP (solid shape): 158.84,134.43 158.84,126.31 158.78,126.24 158.08,126.24 156.49,127.83 153.7,127.83 153.25,128.27 153.25,133.73 154.08,134.56 158.71,134.56
GND on TOP (solid shape): 161.38,83.3 161.38,78.56 160.94,78.12 157.95,78.12 157.76,78.31 157.76,84.39 157.89,84.52 160.16,84.52
GND on TOP (solid shape): 188.54,156.61 188.54,155.97 188.42,155.85 187.66,155.85 186.7,154.89 179.78,154.89 179.53,155.15 179.53,156.35 179.91,156.73 188.42,156.73
GND on TOP (solid shape): 188.93,140.54 188.93,139.21 188.74,139.02 185.43,139.02 185.31,139.15 185.31,140.48 185.43,140.61 188.86,140.61
GND on TOP (solid shape): 198.63,91.76 198.63,90.2 198.43,90 192.42,90 192.31,90.11 192.31,90.97 192.4,91.06 192.73,91.06 193.71,92.04 198.35,92.04
GND on TOP (solid shape): 199.86,72.02 199.86,70.13 199.62,69.88 193.18,69.88 192.75,70.31 192.75,71.89 192.94,72.08 199.8,72.08
GND on TOP (solid shape): 148.11,145.43 148.11,143.77 147.92,143.58 140.36,143.58 140.11,143.84 140.11,145.24 140.3,145.43 140.81,145.43 141.19,145.81 147.73,145.81
GND on TOP (solid shape): 149.44,176.48 149.44,173.94 149,173.49 147.22,173.49 147.16,173.56 147.16,176.67 147.29,176.79 149.13,176.79
GND on TOP (solid shape): 29.87,64.63 29.87,58.98 29.77,58.88 28.34,58.88 28.31,58.92 28.31,63.89 28.55,64.14 28.55,64.77 28.67,64.88 29.62,64.88
GND on TOP (solid shape): 104.74,74.05 104.74,70.5 104.69,70.45 104.06,70.45 103.98,70.53 103.98,71.13 103.72,71.38 102.26,71.38 102.07,71.58 102.07,74.43 102.39,74.75 104.04,74.75
GND on TOP (solid shape): 160.72,176.67 161.76,176.67 161.89,176.54 161.89,175.97 161.7,175.78 158.67,175.78 158.44,176.01 158.44,177.77 158.54,177.86 159.53,177.86
GND on TOP (solid shape): 169.81,140.48 169.81,139.97 170,139.78 171.02,139.78 171.08,139.72 171.08,139.08 170.96,138.95 168.35,138.95 168.03,139.27 168.03,140.48 168.16,140.61 169.69,140.61
GND on TOP (solid shape): 68.42,77.99 68.42,73.84 68.14,73.56 67.54,73.56 66.51,72.52 63.71,72.52 63.47,72.77 63.47,77.86 63.85,78.24 68.16,78.24
GND on TOP (solid shape): 142.27,188.22 142.01,187.97 140.62,187.97 139.86,187.21 139.86,186.76 139.6,186.51 136.05,186.51 135.6,186.95 135.6,189.72 135.64,189.77 135.68,189.83 142.27,189.83
GND on TOP (solid shape): 167.67,172.29 167.67,171.97 167.61,171.91 167.61,170.7 167.54,170.64 167.41,170.64 167.35,170.7 167.35,171.78 167.16,171.97 167.16,172.03 166.84,172.35 166.84,172.67 166.97,172.79 167.16,172.79
GND on TOP (solid shape): 182.89,64.93 182.89,63.83 182.98,63.73 182.98,61.78 182.68,61.47 181.08,61.47 180.88,61.67 180.88,63.89 181.27,64.28 181.79,64.28 181.99,64.49 181.99,64.98 182.06,65.04 182.78,65.04
GND on TOP (solid shape): 91.47,139.2 91.47,136.22 91.21,135.96 88.48,135.96 88.17,135.65 88.17,135.14 88.1,135.08 87.6,135.08 87.47,135.2 87.47,138.25 87.15,138.57 85.5,138.57 85.37,138.69 85.37,139.14 85.56,139.33 91.34,139.33
GND on TOP (solid shape): 183.04,74.94 183.04,71.16 182.97,71.1 182.43,71.1 182.34,71.19 182.34,72.65 182.15,72.85 182.07,72.85 180.51,72.85 180.5,72.85 180.31,72.65 179.86,72.65 179.67,72.85 179.67,75.07 179.8,75.19 182.78,75.19
GND on TOP (solid shape): 191.99,186.32 191.99,185.3 191.48,184.8 191.48,176.92 191.54,176.86 191.54,175.97 190.78,175.21 187.86,175.21 186.91,176.16 184.88,176.16 184.51,176.53 178.71,176.53 178.27,176.97 178.27,182.13 178.97,182.83 183.67,182.83 187.54,186.7 191.61,186.7
GND on TOP (solid shape): 162.27,174.38 162.27,171.84 161.76,171.33 161.76,166.76 162.08,166.44 162.78,166.44 162.97,166.25 162.97,162.19 162.46,161.68 159.41,161.68 158.65,162.44 158.65,169.75 158.91,170 158.91,173.81 159.22,174.13 160.24,174.13 160.56,174.45 162.21,174.45
GND on TOP (solid shape): 12.35,56.06 12.35,53.41 11.91,52.98 10.49,52.98 10.4,53 10.3,53 0.3,53 0.27,53.02 0.25,53.05 0.25,56.55 0.27,56.58 0.3,56.6 11.81,56.6
GND on TOP (solid shape): 211.99,85.67 211.99,81.35 209.16,78.52 201.45,78.52 200.89,77.96 198.18,77.96 197.01,79.13 193.52,79.13 193.42,79.23 193.42,80.37 193.89,80.85 194.78,80.85 195.74,81.8 208.56,81.8 209.32,82.56 209.32,85.8 209.64,86.12 211.55,86.12
GND on TOP (solid shape): 177.18,156.67 177.18,155.15 176.86,154.83 170.96,154.83 170.83,154.96 170.83,156.29 170.64,156.48 169.88,156.48 169.75,156.35 169.75,155.72 169.69,155.66 168.48,155.66 167.53,154.7 160.6,154.7 160.41,154.89 160.41,155.53 160.54,155.66 162.32,155.66 162.7,156.04 162.7,157.18 163.14,157.62 176.23,157.62
GND on TOP (solid shape): 130.91,166.62 130.91,165.8 131.05,165.66 131.05,164.14 130.92,164.01 129.86,164.01 129.74,163.89 129.74,163.54 129.59,163.39 128.3,163.39 128.12,163.57 128.12,163.8 127.93,163.99 127.42,163.99 127.18,164.23 127.18,164.81 127.22,164.85 127.83,164.85 128.17,165.19 128.76,165.19 129.08,165.5 129.08,166.42 129.37,166.71 130.81,166.71
GND on TOP (solid shape): 182.02,175.46 183.59,175.46 184.18,174.87 184.18,174.87 184.18,174.13 184.05,174 183.23,174 182.97,173.75 182.97,172.48 181.77,171.27 181.77,170.76 181.7,170.7 181.19,170.7 181,170.89 181,172.54 180.75,172.79 179.42,172.79 179.16,173.05 179.16,174.45 179.35,174.64 179.92,174.64 180.05,174.76 180.05,176.22 180.15,176.32 181.16,176.32
GND on TOP (solid shape): 113.04,13.99 113.04,8.73 89.65,8.73 89.65,11.48 89.28,12.36 88.4,12.73 85.1,12.73 85.1,18.39 85.41,18.7 108.34,18.7
GND on TOP (solid shape): 130.76,24.94 130.76,23.29 130.56,23.09 129.7,23.09 129.43,22.82 129.43,21.46 128.81,20.84 122.69,20.84 122.56,20.97 122.56,22.02 122.71,22.17 123.98,22.17 124.17,22.36 124.17,24.33 124.3,24.46 125.35,24.46 125.86,24.97 127.6,24.97 127.73,24.84 129.59,24.84 129.82,25.07 130.64,25.07
GND on TOP (solid shape): 230.14,0.25 165.65,0.25 165.65,7.48 165.28,8.36 164.4,8.73 163.77,8.73 163.77,9.24 213.46,9.24 220.18,15.96 220.18,36.05 220.42,36.29 230.14,36.29
GND on TOP (solid shape): 207.29,60.78 207.29,58.56 207.42,58.43 208.05,58.43 208.12,58.37 208.12,57.8 208.05,57.73 207.42,57.73 207.06,57.38 207.06,54.9 206.98,54.81 202.47,54.81 201.96,54.3 201.26,54.3 201.2,54.37 201.2,55 201.13,55.07 200.56,55.07 200.43,55.19 200.43,55.76 200.5,55.83 201.9,55.83 202.09,55.64 202.53,55.64 203.87,56.98 203.87,57.62 204.58,58.33 205.9,58.33 206.22,58.65 206.22,60.72 206.34,60.84 207.23,60.84
GND on TOP (solid shape): 11.78,95.26 11.78,92.15 12.22,91.7 13.2,91.7 13.92,91.48 14.38,90.88 13.81,90.88 13.54,91.11 13.2,91.19 0.9,91.19 0.87,91.21 0.85,91.24 0.85,95.6 0.87,95.63 0.9,95.65 11.39,95.65
GND on TOP (solid shape): 14.43,74.88 13.99,74.17 13.2,73.9 12.92,73.9 12.54,73.52 12.54,71 11.55,70.02 11.04,70.02 10.77,70.44 10.3,70.6 1.1,70.6 1.07,70.62 1.05,70.65 1.05,74.36 1.07,74.39 1.1,74.41 13.2,74.41 13.62,74.54 13.9,74.88
GND on TOP (solid shape): outline of 91 points within 213.01,61.19 218.12,74.79
GND on TOP (solid shape): 12.41,38.49 12.41,35.13 11.27,33.98 8.52,33.98 8.48,33.94 8.36,33.81 8.23,33.69 8.23,23.82 8.74,23.32 11.78,23.32 12.35,22.74 12.35,21.22 10.76,19.63 0.25,19.63 0.25,21.3 0.27,21.33 0.3,21.35 7.47,21.35 8.21,21.95 7.76,22.8 7.73,22.82 7.72,22.85 7.72,33.96 7.73,33.98 7.76,34 8.21,34.85 7.47,35.45 1.1,35.45 1.07,35.47 1.05,35.5 1.05,38.95 1.07,38.98 1.1,39 11.91,39
GND on TOP (solid shape): outline of 183 points within 137.57,147.84 146.71,159.52
GND on TOP (solid shape): outline of 265 points within 112.98,93.71 114.63,102.6
GND on TOP (solid shape): outline of 90 points within 0.25,111.65 92.68,159.55
GND on TOP (solid shape): outline of 249 points within 16.62,0.25 230.15,190.85
GND on BOTTOM (solid shape): 113.55,28.81 113.55,27.47 110.44,27.47 110.44,28.74 110.63,28.93 113.42,28.93
GND on BOTTOM (solid shape): 109.82,134.44 109.82,132.66 109.69,132.54 108.99,132.54 108.74,132.79 108.74,134.63 109.63,134.63
GND on BOTTOM (solid shape): 30.99,53.26 30.99,50.97 30.64,50.62 27.66,50.62 27.43,50.86 27.43,53.13 27.84,53.54 30.7,53.54
GND on BOTTOM (solid shape): 101.31,29.47 101.31,27.32 101.25,27.25 100.23,27.25 99.98,27.51 99.98,29.35 100.17,29.54 101.25,29.54
GND on BOTTOM (solid shape): 104.55,30.17 104.55,28.9 104.36,28.71 102.01,28.71 101.82,28.9 101.82,30.24 101.95,30.36 104.36,30.36
GND on BOTTOM (solid shape): 131.03,166.51 131.03,164.03 130.71,163.71 127.92,163.71 127.79,163.84 127.79,166.76 127.92,166.89 130.65,166.89
GND on BOTTOM (solid shape): 143.74,158.94 143.74,157.93 142.21,157.93 142.21,159.01 142.34,159.13 143.54,159.13
GND on BOTTOM (solid shape): 153.71,23.58 153.71,19.9 153.26,19.45 150.4,19.45 150.09,19.77 150.09,23.58 150.59,24.09 153.2,24.09
GND on BOTTOM (solid shape): 155.61,26.31 155.61,25.18 155.41,24.98 154.28,24.98 154.15,25.11 154.15,26.31 154.34,26.5 155.42,26.5
GND on BOTTOM (solid shape): 191.61,187.4 191.61,186.13 191.48,186 188.5,186 188.31,186.19 188.31,187.46 188.37,187.53 191.48,187.53
GND on BOTTOM (solid shape): 191.61,176.16 191.61,174.89 191.48,174.76 188.31,174.76 188.18,174.89 188.18,176.22 188.31,176.35 191.42,176.35
GND on BOTTOM (solid shape): 218.34,169.68 218.34,167.4 218.02,167.08 215.8,167.08 215.61,167.27 215.61,169.75 215.74,169.87 218.15,169.87
GND on BOTTOM (solid shape): 103.18,134.38 103.18,132.73 103.06,132.6 101.82,132.6 101.69,132.73 101.69,133.04 102.01,133.36 102.01,134.63 102.93,134.63
GND on BOTTOM (solid shape): 106.49,134.41 106.49,132.73 106.36,132.6 105.12,132.6 104.99,132.73 104.99,133.04 105.38,133.42 105.38,134.63 106.26,134.63
GND on BOTTOM (solid shape): 187.61,174 187.61,170.89 187.42,170.7 186.27,170.7 186.08,170.89 186.08,174 186.27,174.19 187.42,174.19
GND on BOTTOM (solid shape): 30.06,22.43 30.06,18.49 29.56,17.98 26.64,17.98 26.44,18.17 26.44,18.87 24.98,20.33 24.98,22.36 25.37,22.74 29.75,22.74
GND on BOTTOM (solid shape): 99.82,134.41 99.82,132.73 99.69,132.6 98.45,132.6 98.33,132.73 98.33,132.98 98.64,133.3 98.64,134.63 98.71,134.69 99.53,134.69
GND on BOTTOM (solid shape): 113.12,134.44 113.12,132.73 112.93,132.54 111.85,132.54 111.69,132.69 111.69,132.88 112.11,133.3 112.11,134.57 112.17,134.63 112.93,134.63
GND on BOTTOM (solid shape): 177.73,31.47 177.73,28.97 177.46,28.7 175.8,28.7 175.48,29.02 175.48,30.7 175.21,30.97 175.21,31.47 175.32,31.58 177.62,31.58
GND on BOTTOM (solid shape): 183.72,156.23 183.72,155.34 183.34,154.96 181.38,154.96 181.38,154.96 180.04,154.96 179.65,155.34 179.65,156.35 179.78,156.48 183.46,156.48
GND on BOTTOM (solid shape): 189.96,168.73 189.96,166.63 189.64,166.32 186.97,166.32 186.46,166.83 186.46,168.73 186.97,169.24 189.45,169.24
GND on BOTTOM (solid shape): 29.43,33.03 29.43,31.06 28.86,30.49 25.56,30.49 25.05,31 25.05,34.05 25.3,34.3 28.16,34.3
GND on BOTTOM (solid shape): 30.46,65.54 30.46,64.16 29.75,63.45 29.7,63.4 27.23,63.4 26.61,64.03 26.61,64.75 27.68,65.83 30.18,65.83
GND on BOTTOM (solid shape): 91.41,30.05 91.41,29.03 91.34,28.97 89.31,28.97 89.3,28.96 88.52,28.96 88.34,29.14 88.34,29.73 88.84,30.24 91.21,30.24
GND on BOTTOM (solid shape): 93.06,29.28 93.06,28.46 93.06,28.34 93.06,27.44 92.93,27.32 91.85,27.32 91.72,27.44 91.72,29.35 91.85,29.47 92.87,29.47
GND on BOTTOM (solid shape): 125.44,18.87 125.44,17.69 125.08,17.33 123.2,17.33 122.27,16.39 121.36,16.39 120.86,16.9 120.86,18.67 121.44,19.25 125.06,19.25
GND on BOTTOM (solid shape): 158.21,23.7 158.21,22.69 158.34,22.57 158.34,21.68 158.21,21.55 157.96,21.55 157.83,21.68 157.83,22.57 158.02,22.76 158.02,23.7 158.08,23.76 158.15,23.76
GND on BOTTOM (solid shape): 172.54,140.42 172.54,139.34 172.35,139.15 169.37,139.15 169.24,139.27 169.24,140.35 169.37,140.48 172.48,140.48
GND on BOTTOM (solid shape): 189.62,140.42 189.62,139.84 188.74,138.95 187.72,138.95 187.59,139.08 187.59,139.59 187.97,139.97 187.97,140.42 188.1,140.54 189.5,140.54
GND on BOTTOM (solid shape): 142.27,188.03 141.95,187.72 140.36,187.72 139.86,187.21 139.86,186.76 139.6,186.51 136.05,186.51 135.6,186.95 135.6,189.72 135.64,189.77 135.68,189.83 142.27,189.83
GND on BOTTOM (solid shape): 158.27,108.46 158.27,108.28 157.98,107.99 157.98,105.15 157.91,105.08 157.22,105.08 156.11,106.19 156.11,108.53 156.22,108.64 158.09,108.64
GND on BOTTOM (solid shape): 137.95,139.58 137.95,137.17 137.13,136.35 129.31,136.35 128.69,135.72 128.69,133.44 128.55,133.3 127.19,133.3 127,133.49 127,138.9 128.57,140.47 137.06,140.47
GND on BOTTOM (solid shape): 158.99,29.28 158.99,27.92 158.85,27.77 158.4,27.77 157.83,27.2 157.83,25.93 157.77,25.87 157.64,25.87 157.58,25.93 157.58,28.03 157.52,28.09 157.52,29.17 157.64,29.3 158.98,29.3
GND on BOTTOM (solid shape): 222.55,113.79 222.55,112.22 222.34,112.01 222.34,107.01 221.96,106.62 219.02,106.62 218.84,106.8 218.84,113.42 219.27,113.85 222.49,113.85
GND on BOTTOM (solid shape): 183.83,174.6 183.83,173.08 182.46,171.71 181.26,171.71 181.13,171.84 181.13,172.98 180.94,173.18 179.92,173.18 179.8,173.3 179.8,174.83 179.92,174.95 183.48,174.95
GND on BOTTOM (solid shape): 129.49,24.52 129.49,22.79 129.19,22.49 129,22.49 128.74,22.24 128.74,21.47 128.49,21.22 125.63,21.22 125.38,20.97 124.3,20.97 124.17,21.09 124.17,22.25 125.43,23.51 125.43,24.55 125.65,24.78 129.24,24.78
GND on BOTTOM (solid shape): 137.43,96.47 137.43,94.83 137.25,94.64 133.17,94.64 132.81,95.01 132.81,95.77 133,95.96 133.57,95.96 133.76,96.15 133.76,96.66 133.82,96.72 137.18,96.72
GND on BOTTOM (solid shape): 161.39,20.28 161.39,19.07 161.13,18.82 159.1,18.82 159.04,18.88 159.04,19.33 159.17,19.45 159.17,20.03 159.23,20.09 159.23,20.41 161.26,20.41
GND on BOTTOM (solid shape): 196.43,64.4 196.43,63.45 196.12,63.13 193.45,63.13 193.2,62.88 193.2,61.92 193.7,61.42 193.7,60.08 193.58,59.95 192.88,59.95 192.75,60.08 192.12,60.08 191.86,60.34 191.86,64.46 192.24,64.84 195.99,64.84
GND on BOTTOM (solid shape): 133.89,20.68 133.89,16.26 133.48,15.85 132.38,15.85 131.23,16.99 131.14,16.99 131.13,16.98 130.93,16.98 130.92,16.99 130.33,16.99 130.2,17.12 130.2,20.74 130.4,20.93 131.17,20.93 131.55,21.31 133.25,21.31
GND on BOTTOM (solid shape): 158.59,26.82 158.59,25.87 158.72,25.74 159.36,25.74 159.36,24.03 157.64,24.03 157.64,25.74 158.34,25.74 158.4,25.8 158.4,26.82 158.47,26.88 158.53,26.88
GND on BOTTOM (solid shape): 124.52,137.51 124.52,134.7 124.26,134.45 124.26,132.7 124.18,132.61 121.83,132.61 121.68,132.76 121.68,135 121.82,135.14 122.75,135.14 122.95,135.34 122.95,137.47 123.03,137.55 124.48,137.55
GND on BOTTOM (solid shape): 220.95,125.94 220.95,125.15 221.3,124.8 221.3,123.86 220.93,123.49 220.93,122.77 220.76,122.6 219.91,122.6 219.9,122.6 219.77,122.6 219.71,122.54 219.14,122.54 219.06,122.62 219.06,125.73 219.21,125.87 219.57,125.87 219.83,126.13 220.75,126.13
GND on BOTTOM (solid shape): 162.33,176.03 162.33,171.91 161.76,171.33 161.76,166.76 162.08,166.44 163.41,166.44 163.67,166.19 163.67,162.13 163.29,161.75 160.37,161.75 159.16,162.95 159.16,165.43 158.91,165.68 158.91,175.33 160.18,176.6 161.76,176.6
GND on BOTTOM (solid shape): 210.17,81.35 210.17,80.59 209.42,79.83 202.97,79.83 200.31,77.16 190.02,77.16 189.64,77.54 189.64,79.83 190.27,80.47 197.26,80.47 197.64,80.85 198.91,80.85 199.55,81.48 210.04,81.48
GND on BOTTOM (solid shape): 12.35,56.06 12.35,53.41 11.91,52.98 10.49,52.98 10.4,53 10.3,53 0.3,53 0.27,53.02 0.25,53.05 0.25,56.55 0.27,56.58 0.3,56.6 11.81,56.6
GND on BOTTOM (solid shape): 41.61,81.93 41.82,81.93 41.82,81.92 44.16,81.92 44.22,81.86 44.22,81.23 44.16,81.16 43.47,81.16 43.41,81.1 43.34,81.1 43.21,80.97 43.21,79.2 43.02,79 42.07,79 41.94,79.13 41.94,81.04 41.88,81.1 40.58,81.1 40.39,81.29 40.39,82.25 40.52,82.38 41.16,82.38
GND on BOTTOM (solid shape): 162.4,14.98 162.4,14.49 162.47,14.43 164.05,14.43 164.56,13.92 164.56,9.92 164.49,9.85 163.35,9.85 163.16,10.04 163.16,11.69 162.84,12.01 158.14,12.01 157.83,12.33 157.83,12.77 157.64,12.96 156.62,12.96 156.56,13.03 156.56,14.87 156.81,15.12 162.27,15.12
GND on BOTTOM (solid shape): 180.88,182.95 180.88,182.83 180.81,182.76 179.54,182.76 179.42,182.64 179.42,181.18 179.48,181.11 181.13,181.11 181.94,180.31 181.94,177.95 181.58,177.58 181.58,176.99 181.38,176.79 180.66,176.79 180.41,176.54 178.64,176.54 178.46,176.72 178.46,179.72 178.84,180.1 178.84,183.02 180.81,183.02
GND on BOTTOM (solid shape): 145.04,153.1 144.79,153.1 144.79,154.37 143.16,154.37 143.16,153.1 141.08,151.01 140.17,151.01 139.73,151.46 138.9,151.46 138.78,151.59 138.78,152.84 138.78,152.85 138.78,154.26 139.03,154.51 142.06,154.51 142.59,155.03 145.04,155.03
GND on BOTTOM (solid shape): 217.99,92.86 217.99,91.96 218.24,91.7 220.12,91.7 220.18,91.64 220.18,90.94 220.06,90.82 218.79,90.82 218.72,90.75 218.72,89.8 218.66,89.74 218.47,89.74 218.28,89.93 218.28,90.24 217.43,91.09 215.89,91.09 215.81,91.16 215.81,92.01 215.96,92.16 217.07,92.16 217.17,92.26 217.17,92.9 217.26,93 217.85,93
GND on BOTTOM (solid shape): 177.37,157.05 177.37,155.57 177.12,155.32 173.56,155.32 173.29,155.59 171.65,155.59 171.53,155.46 171.53,154.96 171.4,154.83 166.83,154.83 166.76,154.89 166.76,155.53 166.51,155.78 164.99,155.78 164.86,155.66 164.86,154.96 164.73,154.83 161.56,154.83 161.49,154.89 161.49,155.34 163.59,157.43 176.99,157.43
GND on BOTTOM (solid shape): 111.55,26.24 113.07,26.24 113.17,26.14 113.17,25.76 113.04,25.63 112.98,25.63 112.21,24.87 112.21,24.43 112.15,24.36 111.64,24.36 111.29,24.71 111.28,24.71 111.15,24.84 109.63,24.84 109.5,24.71 109.5,23.85 109.47,23.82 109.33,23.82 108.85,24.3 107.33,24.3 107.2,24.43 107.2,25.25 107.9,25.25 108.09,25.44 108.09,26.2 108.79,26.2 109.2,25.79 110.75,25.79 110.75,26.71 110.82,26.78 111.01,26.78
GND on BOTTOM (solid shape): 118.93,145.13 118.93,143.99 118.78,143.84 116.59,143.84 116.46,143.96 116.46,144.54 116.34,144.66 113.95,144.66 113.82,144.54 113.82,143.47 114.03,143.27 114.75,143.27 114.77,143.25 114.77,139.21 114.69,139.14 112.62,139.14 112.54,139.22 112.54,144.78 113.11,145.35 118.71,145.35
GND on BOTTOM (solid shape): 217.83,74.56 217.83,61.42 217.26,60.84 215.74,60.84 215.55,61.03 215.55,62.37 215.42,62.49 214.85,62.49 214.72,62.62 213.58,62.62 213.45,62.75 213.45,66.5 213.71,66.75 215.61,66.75 215.8,66.94 215.8,68.15 215.61,68.34 213.67,68.34 213.44,68.57 213.44,71.84 214,72.4 214.85,72.4 215.29,72.85 215.29,74.69 215.42,74.81 217.58,74.81
GND on BOTTOM (solid shape): 11.78,95.26 11.78,92.15 12.22,91.7 13.2,91.7 13.92,91.48 14.38,90.88 13.81,90.88 13.54,91.11 13.2,91.19 0.9,91.19 0.87,91.21 0.85,91.24 0.85,95.6 0.87,95.63 0.9,95.65 11.39,95.65
GND on BOTTOM (solid shape): 109.44,96.29 109.44,94.05 108.43,93.05 99.47,93.05 98.89,92.47 97.76,92.47 97.63,92.59 97.63,93.93 97.76,94.05 98.36,94.05 98.65,94.35 98.73,94.38 98.81,94.33 99.24,94.38 98.99,94.74 98.97,94.74 98.91,94.8 98.81,94.8 98.81,95.92 99.2,96.31 109.41,96.31
GND on BOTTOM (solid shape): 14.43,74.88 13.99,74.17 13.2,73.9 12.92,73.9 12.54,73.52 12.54,71 11.55,70.02 11.04,70.02 10.77,70.44 10.3,70.6 1.1,70.6 1.07,70.62 1.05,70.65 1.05,74.36 1.07,74.39 1.1,74.41 13.2,74.41 13.62,74.54 13.9,74.88
GND on BOTTOM (solid shape): 12.41,38.49 12.41,35.13 11.27,33.98 8.52,33.98 8.48,33.94 8.36,33.81 8.23,33.69 8.23,23.82 8.74,23.32 11.78,23.32 12.35,22.74 12.35,21.22 10.76,19.63 0.25,19.63 0.25,21.3 0.27,21.33 0.3,21.35 7.47,21.35 8.21,21.95 7.76,22.8 7.73,22.82 7.72,22.85 7.72,33.96 7.73,33.98 7.76,34 8.21,34.85 7.47,35.45 1.1,35.45 1.07,35.47 1.05,35.5 1.05,38.95 1.07,38.98 1.1,39 11.91,39
GND on BOTTOM (solid shape): outline of 90 points within 0.25,111.65 92.68,159.55
GND on BOTTOM (solid shape): outline of 249 points within 16.62,0.25 230.15,190.85
GND on BOTTOM (solid shape): outline of 441 points within 95.31,122.73 117.08,125.42
GND on IN1 (solid shape): 114.65,144.22 114.65,139.65 114.46,139.46 112.42,139.46 112.04,139.84 112.04,144.35 112.68,144.98 113.88,144.98
GND on IN1 (solid shape): 163.73,167.21 163.73,162.13 163.41,161.81 159.29,161.81 158.84,162.25 158.84,166.95 159.48,167.59 163.35,167.59
GND on IN1 (solid shape): 12.35,56.06 12.35,53.41 11.91,52.98 10.49,52.98 10.4,53 10.3,53 0.3,53 0.27,53.02 0.25,53.05 0.25,56.55 0.27,56.58 0.3,56.6 11.81,56.6
GND on IN1 (solid shape): 218.21,75.96 218.21,61.92 217.2,60.91 215.99,60.91 215.74,61.16 215.74,62.11 215.55,62.3 214.66,62.3 214.47,62.49 214.47,66.43 214.79,66.75 215.48,66.75 215.74,67 215.74,68.08 215.55,68.27 214.53,68.27 214.4,68.4 214.4,76.34 214.66,76.59 217.58,76.59
GND on IN1 (solid shape): 113.04,13.99 113.04,8.73 89.65,8.73 89.65,11.48 89.28,12.36 88.4,12.73 85.1,12.73 85.1,18.39 85.41,18.7 108.34,18.7
GND on IN1 (solid shape): 230.14,0.25 165.65,0.25 165.65,7.48 165.28,8.36 164.4,8.73 163.77,8.73 163.77,9.24 213.46,9.24 220.18,15.96 220.18,36.05 220.42,36.29 230.14,36.29
GND on IN1 (solid shape): 11.78,95.26 11.78,92.15 12.22,91.7 13.2,91.7 13.92,91.48 14.38,90.88 13.81,90.88 13.54,91.11 13.2,91.19 0.9,91.19 0.87,91.21 0.85,91.24 0.85,95.6 0.87,95.63 0.9,95.65 11.39,95.65
GND on IN1 (solid shape): 14.43,74.88 13.99,74.17 13.2,73.9 12.92,73.9 12.54,73.52 12.54,71 11.55,70.02 11.04,70.02 10.77,70.44 10.3,70.6 1.1,70.6 1.07,70.62 1.05,70.65 1.05,74.36 1.07,74.39 1.1,74.41 13.2,74.41 13.62,74.54 13.9,74.88
GND on IN1 (solid shape): 12.41,38.49 12.41,35.13 11.27,33.98 8.52,33.98 8.48,33.94 8.36,33.81 8.23,33.69 8.23,23.82 8.74,23.32 11.78,23.32 12.35,22.74 12.35,21.22 10.76,19.63 0.25,19.63 0.25,21.3 0.27,21.33 0.3,21.35 7.47,21.35 8.21,21.95 7.76,22.8 7.73,22.82 7.72,22.85 7.72,33.96 7.73,33.98 7.76,34 8.21,34.85 7.47,35.45 1.1,35.45 1.07,35.47 1.05,35.5 1.05,38.95 1.07,38.98 1.1,39 11.91,39
GND on IN1 (solid shape): outline of 151 points within 137.57,147.84 146.71,159.52
GND on IN1 (solid shape): outline of 90 points within 0.25,111.65 92.68,159.55
GND on IN1 (solid shape): outline of 822 points within 145.13,170.44 162.72,177.87
GND on IN1 (solid shape): outline of 241 points within 16.62,0.25 230.15,190.85
GND on IN2 (solid shape): 183.99,181.43 183.99,177.49 183.01,176.51 175.64,176.51 174.84,177.3 174.84,181.3 175.8,182.26 183.16,182.26
GND on IN2 (solid shape): 12.35,56.06 12.35,53.41 11.91,52.98 10.49,52.98 10.4,53 10.3,53 0.3,53 0.27,53.02 0.25,53.05 0.25,56.55 0.27,56.58 0.3,56.6 11.81,56.6
GND on IN2 (solid shape): 113.04,13.99 113.04,8.73 89.65,8.73 89.65,11.48 89.28,12.36 88.4,12.73 85.1,12.73 85.1,18.39 85.41,18.7 108.34,18.7
GND on IN2 (solid shape): 230.14,0.25 165.65,0.25 165.65,7.48 165.28,8.36 164.4,8.73 163.77,8.73 163.77,9.24 213.46,9.24 220.18,15.96 220.18,36.04 220.43,36.29 230.14,36.29
GND on IN2 (solid shape): 11.78,95.26 11.78,92.15 12.22,91.7 13.2,91.7 13.92,91.48 14.38,90.88 13.81,90.88 13.54,91.11 13.2,91.19 0.9,91.19 0.87,91.21 0.85,91.24 0.85,95.6 0.87,95.63 0.9,95.65 11.39,95.65
GND on IN2 (solid shape): 14.43,74.88 13.99,74.17 13.2,73.9 12.92,73.9 12.54,73.52 12.54,71 11.55,70.02 11.04,70.02 10.77,70.44 10.3,70.6 1.1,70.6 1.07,70.62 1.05,70.65 1.05,74.36 1.07,74.39 1.1,74.41 13.2,74.41 13.62,74.54 13.9,74.88
GND on IN2 (solid shape): outline of 85 points within 112.42,139.14 119.41,145.35
GND on IN2 (solid shape): 12.41,38.49 12.41,35.13 11.27,33.98 8.52,33.98 8.48,33.94 8.36,33.81 8.23,33.69 8.23,23.82 8.74,23.32 11.78,23.32 12.35,22.74 12.35,21.22 10.76,19.63 0.25,19.63 0.25,21.3 0.27,21.33 0.3,21.35 7.47,21.35 8.21,21.95 7.76,22.8 7.73,22.82 7.72,22.85 7.72,33.96 7.73,33.98 7.76,34 8.21,34.85 7.47,35.45 1.1,35.45 1.07,35.47 1.05,35.5 1.05,38.95 1.07,38.98 1.1,39 11.91,39
GND on IN2 (solid shape): outline of 109 points within 151.16,10.49 164.43,19.76
GND on IN2 (solid shape): outline of 183 points within 137.57,147.84 146.71,159.52
GND on IN2 (solid shape): outline of 217 points within 174.53,169.27 184.37,175.05
GND on IN2 (solid shape): outline of 90 points within 0.25,111.65 92.68,159.55
GND on IN2 (solid shape): outline of 752 points within 117.82,20.9 136.24,29.79
GND on IN2 (solid shape): outline of 243 points within 16.62,0.25 230.15,190.85
GND on IN2 (solid shape): outline of 1010 points within 145.19,161.68 162.97,178.13
GND on IN3 (solid shape): 12.35,56.06 12.35,53.41 11.91,52.98 10.49,52.98 10.4,53 10.3,53 0.3,53 0.27,53.02 0.25,53.05 0.25,56.55 0.27,56.58 0.3,56.6 11.81,56.6
GND on IN3 (solid shape): 217.77,75.58 217.77,61.99 216.69,60.91 215.93,60.91 215.74,61.1 215.74,62.11 215.55,62.3 215.23,62.3 215.04,62.49 215.04,66.62 215.17,66.75 215.61,66.75 215.8,66.94 215.8,68.34 215.61,68.53 214.85,68.53 214.4,68.97 214.4,76.34 214.66,76.59 216.75,76.59
GND on IN3 (solid shape): 113.04,13.99 113.04,8.73 89.65,8.73 89.65,11.48 89.28,12.36 88.4,12.73 85.1,12.73 85.1,18.39 85.41,18.7 108.34,18.7
GND on IN3 (solid shape): 230.14,0.25 165.65,0.25 165.65,7.48 165.28,8.36 164.4,8.73 163.77,8.73 163.77,9.24 213.46,9.24 220.18,15.96 220.18,36.06 220.41,36.29 230.14,36.29
GND on IN3 (solid shape): 11.78,95.26 11.78,92.15 12.22,91.7 13.2,91.7 13.92,91.48 14.38,90.88 13.81,90.88 13.54,91.11 13.2,91.19 0.9,91.19 0.87,91.21 0.85,91.24 0.85,95.6 0.87,95.63 0.9,95.65 11.39,95.65
GND on IN3 (solid shape): 14.43,74.88 13.99,74.17 13.2,73.9 12.92,73.9 12.54,73.52 12.54,71 11.55,70.02 11.04,70.02 10.77,70.44 10.3,70.6 1.1,70.6 1.07,70.62 1.05,70.65 1.05,74.36 1.07,74.39 1.1,74.41 13.2,74.41 13.62,74.54 13.9,74.88
GND on IN3 (solid shape): outline of 85 points within 112.42,139.33 118.87,144.79
GND on IN3 (solid shape): 12.41,38.49 12.41,35.13 11.27,33.98 8.52,33.98 8.48,33.94 8.36,33.81 8.23,33.69 8.23,23.82 8.74,23.32 11.78,23.32 12.35,22.74 12.35,21.22 10.76,19.63 0.25,19.63 0.25,21.3 0.27,21.33 0.3,21.35 7.47,21.35 8.21,21.95 7.76,22.8 7.73,22.82 7.72,22.85 7.72,33.96 7.73,33.98 7.76,34 8.21,34.85 7.47,35.45 1.1,35.45 1.07,35.47 1.05,35.5 1.05,38.95 1.07,38.98 1.1,39 11.91,39
GND on IN3 (solid shape): outline of 142 points within 137.57,147.84 146.71,159.27
GND on IN3 (solid shape): outline of 90 points within 0.25,111.65 92.68,159.55
GND on IN3 (solid shape): outline of 241 points within 16.62,0.25 230.15,190.85
GND on IN3 (solid shape): outline of 1027 points within 145.13,164.98 163.29,177.05
GND on TOP: 113.76,144.79 116.81,141.74 116.81,138.89 116.36,138.44 114.27,138.44 113.38,139.33 112.74,139.33 112.36,139.71 112.36,141.23 112.04,141.55 110.65,141.55 110.58,141.62 110.58,144.03 110.71,144.16 111.92,144.16 112.55,144.79
GND on GND1: outline of 167 points within 0.25,0.25 230.15,190.85 ; 3 cut-outs
GND on VCC: 14.92,90.88 14.29,91.84 13.2,92.21 1.87,92.21 1.87,94.63 6.85,94.63 8.48,95.71 8.12,97.63 8.12,109.67 8.48,111.59 6.85,112.67 1.27,112.67 1.27,119.13 21.49,119.13 21.49,90.88
GND on VCC: 45.41,55.64 42.32,58.73 42.32,62.11 40.75,63.68 40.75,65.5 40.73,65.52 40.73,81.95 47.25,88.47 48.71,88.47 56.12,95.87 56.12,97.97 58.37,100.23 59.97,100.23 60.73,100.99 61.38,100.99 64.14,103.71 70.85,103.71 71.49,103.07 74.31,103.07 79.01,107.77 84.08,107.77 86.05,109.74 88,109.74 88.13,109.61 111.64,109.61 112.28,110.25 116.57,110.25 117.27,109.55 125.02,109.55 126.16,108.41 132.96,108.41 140.2,101.17 171.29,101.23 171.29,90.12 171.29,90.01 183.86,77.44 183.86,71.72 184.18,71.41 184.18,66.98 183.86,66.66 183.86,59.36 180.14,55.64
GND on VCC: 1.27,19.63 1.27,20.33 7.47,20.33 9.1,21.41 8.74,23.33 8.74,33.47 9.1,35.39 7.47,36.47 2.07,36.47 2.07,37.98 10.3,37.98 11.93,39.06 11.57,40.98 11.57,51.02 11.93,52.94 10.3,54.02 1.27,54.02 1.27,55.58 10.3,55.58 11.93,56.66 11.57,58.58 11.57,68.62 11.93,70.54 10.3,71.62 2.07,71.62 2.07,73.39 13.2,73.39 14.35,73.81 14.95,74.88 16.71,74.88 18.55,76.72 20.54,76.72 20.54,26.34 19.42,25.22 13.58,25.22 12.54,24.18 12.54,21.26 10.91,19.63
GND on IN2: 215.93,60.91 215.58,61.26 215.58,62.11 215.42,62.27 215.22,62.27 215.21,62.27 215.1,62.29 214.99,62.27 214.99,62.27 212.98,62.27 211.8,63.45 209.78,63.45 209.7,63.49 209.69,63.58 209.32,64.08 208.96,63.58 208.95,63.49 208.87,63.45 201.96,63.45 200.63,64.78 200.63,78.08 201.69,79.14 217.02,79.14 218.21,77.95 218.21,61.92 217.2,60.91 ; 1 cut-out
GND on GND2: outline of 167 points within 0.25,0.25 230.15,190.85 ; 3 cut-outs
GNDA on GND1, GND2: 21.88,0.25 17.25,4.58 16.85,5.41 16,5.75 0.25,5.75 0.25,8.67 12.66,8.67 13.4,9.29 12.91,10.13 12.91,15.54 13.4,16.38 12.66,17 0.25,17 0.25,19.12 11.12,19.12 13.05,21.05 13.05,23.97 13.79,24.71 19.63,24.71 20.84,25.92 21.91,25.92 23.76,27.76 31.02,27.76 31.02,23.51 29.58,23.51 29.26,23.19 24.75,23.19 24.54,22.98 24.54,19.74 24.5,19.7 20.43,19.7 19.97,19.23 19.97,17.24 20.43,16.77 24.96,16.77 25.37,17.18 25.37,18.11 26.06,18.11 26.06,16.37 25.17,15.48 25.17,13.49 26.09,12.58 27.1,12.58 27.33,12.35 27.33,9.07 27.13,8.81 27.05,8.5 26.6,5.25 26.55,4.91 26.52,4.57
GNDA on VCC: 21.88,1.27 18.27,4.65 17.55,6.16 16,6.77 1.27,6.77 1.27,7.65 12.66,7.65 14.29,8.73 13.93,10.65 13.93,15.02 14.29,16.94 12.66,18.02 1.27,18.02 1.27,19.12 11.12,19.12 13.05,21.05 13.05,23.97 13.79,24.71 19.63,24.71 20.84,25.92 21.91,25.92 23.76,27.76 31.02,27.76 31.02,23.51 29.58,23.51 29.26,23.19 24.75,23.19 24.54,22.98 24.54,19.74 24.5,19.7 20.43,19.7 19.97,19.23 19.97,17.24 20.43,16.77 24.96,16.77 25.37,17.18 25.37,18.13 25.41,18.17 26.06,18.17 26.06,16.37 25.17,15.48 25.17,13.49 26.09,12.58 27.1,12.58 27.33,12.35 27.33,10.19 26.43,9.6 26.03,8.6 25.59,5.39 25.54,5.02 25.51,4.64
VCC on TOP (solid shape): 166.72,168.48 166.72,168.35 166.65,168.29 166.21,168.29 165.38,167.46 165.38,165.17 165.26,165.05 163.73,165.05 163.6,165.17 163.6,167.52 163.67,167.59 164.81,167.59 165.83,168.6 166.59,168.6
VIN on BOTTOM (solid shape): 142.33,171.02 142.33,170.19 142.71,169.81 143.54,169.81 143.86,169.49 143.86,168.73 143.6,168.48 142.52,168.48 141.7,167.65 139.09,167.65 138.9,167.84 138.9,170.64 139.79,171.52 141.82,171.52
VIN on TOP: 139.64,170.89 139.64,168.58 139.22,168.16 137.44,168.16 136.81,168.79 136.81,170.57 136.36,171.02 134.9,171.02 133.95,170.06 133.95,168.81 133.44,168.3 131.73,168.3 131.65,168.39 131.65,168.84 131.75,168.94 132.66,168.94 133.07,169.35 133.07,173.97 132.24,174.81 130.52,174.81 130.43,174.9 130.43,176.81 130.15,177.09 129.52,177.09 129.47,177.15 129.47,177.77 129.51,177.82 130.65,177.82 132.23,176.23 132.74,176.23 134.33,174.65 134.33,174.13 137.38,171.08 139.45,171.08
+CHGRTC on BOTTOM (solid shape): 203.1,12.46 203.1,10.93 202.97,10.81 202.02,10.81 201.32,11.5 201.32,13.03 201.39,13.09 202.47,13.09
+CPU_CORE on BOTTOM (solid shape): outline of 1962 points within 94.62,110.67 117.56,123.71
+CPU_CORE on IN1 (solid shape): outline of 295 points within 95.02,113.36 115.85,121.75
+CPU_CORE on IN1 (solid shape): outline of 535 points within 94.01,135.46 111.47,143.01
+CPU_CORE on TOP: outline of 146 points within 93.43,110.82 116.08,142.82
+CPU_CORE on BOTTOM: 100.41,131.84 99.91,131.34 99.71,131.14 99.42,131.14 99.34,131.15 99.25,131.14 95.98,131.14 94.14,132.98 94.14,137.87 94.58,138.31 94.58,142.31 95.09,142.82 99.66,142.82 100.04,142.44 100.04,140.85 99.85,140.66 97.56,140.66 97.44,140.54 97.44,139.84 97.63,139.65 105.25,139.65 105.76,139.14 105.76,138.19 106.14,137.81 109.31,137.81 109.38,137.87 109.38,138.12 109.41,138.2 109.49,138.22 109.63,138.22 109.75,138.26 109.88,138.4 109.92,138.59 109.92,138.64 109.9,138.69 109.92,138.78 110,138.82 111.28,138.82 111.47,138.63 111.47,138.25 111.66,138.06 113.38,138.06 113.88,137.55 113.88,131.96 113.06,131.14 103.25,131.14 102.46,131.93 100.51,131.93 100.42,131.84
+CPU_CORE on VCC: 88.36,110.12 88.36,111.6 89.12,112.36 89.12,114.86 88.93,115.05 88.93,133.83 89.5,134.4 89.5,135.1 94.26,139.86 94.26,141.83 95.38,142.95 112.95,142.95 116.42,139.48 116.42,110.75 112.06,110.75 111.43,110.12
+CPU_CORE on IN2: outline of 107 points within 90.52,111.39 115.99,143.33
+CPU_CORE on IN3: outline of 112 points within 90.52,111.39 115.99,143.33
+DIMM1_VREF_DQ on TOP (solid shape): 42.99,73.57 42.99,69.87 42.89,69.77 42.41,69.77 42.32,69.87 40.61,69.87 40.36,70.12 40.36,73.67 40.52,73.83 42.74,73.83
+DIMM1_VREF_DQ on BOTTOM (solid shape): 42,73.58 42,70.41 41.94,70.34 40.29,70.34 40.22,70.41 40.22,73.71 40.35,73.84 41.75,73.84
+DIMM2_VREF_DQ on TOP (solid shape): 120.71,73.77 120.71,70.4 120.42,70.11 119.03,70.11 118.65,70.5 118.65,73.67 118.84,73.86 120.62,73.86
+DIMM2_VREF_DQ on BOTTOM (solid shape): 120.55,73.54 120.55,70.37 120.49,70.31 118.84,70.31 118.77,70.37 118.77,73.67 118.9,73.8 120.3,73.8
+DPAB_VDD10 on TOP (solid shape): 169.27,108.32 169.27,106.74 168.93,106.4 168.55,106.4 168.34,106.61 168.34,108.43 168.51,108.59 169,108.59
+DPAB_VDD18 on TOP (solid shape): 175.22,109.16 175.22,107.98 175.47,107.73 175.47,107.43 175.01,106.97 175.01,105.63 174.82,105.45 172.8,105.45 172.62,105.27 172.62,105.03 172.62,104.97 172.62,104.88 172.43,104.68 171.98,104.68 171.86,104.81 171.86,105.46 172.57,106.17 173.68,106.17 173.9,106.4 173.9,106.94 173.69,107.14 173.53,107.14 173.31,107.36 173.31,107.64 173.58,107.91 173.87,107.91 174.23,108.27 174.23,109.46 174.28,109.51 174.86,109.51
+DPCD_VDD10 on BOTTOM (solid shape): outline of 159 points within 183.05,98.87 186.36,108.08
+DPCD_VDD18 on BOTTOM (solid shape): outline of 246 points within 176.17,98.83 182.69,108.11
+DPEF_VDD10 on IN1 (solid shape): 169.37,110.9 169.37,110.11 169.3,109.89 169.37,109.67 169.37,109.31 169.09,109.03 168.43,109.03 167.97,109.5 167.97,110.81 168.27,111.12 169.15,111.12
+DPEF_VDD18 on BOTTOM (solid shape): 168.03,114.31 168.03,112 167.54,111.51 167.12,111.51 166.89,111.73 166.89,112.51 167.08,112.69 167.08,112.71 167.09,112.72 167.14,112.9 167.08,113.07 167.08,113.2 166.86,113.41 166.86,113.92 167.24,114.29 167.46,114.29 167.52,114.36 167.58,114.4 167.63,114.45 167.65,114.46 167.67,114.46 167.87,114.46
+FAN_POWER on BOTTOM (solid shape): 49.2,109.31 49.2,102.51 49.01,102.33 48.62,102.33 48.4,102.55 48.4,104.67 48.5,104.77 48.5,105.35 48.03,105.81 48.03,109.19 48.32,109.47 49.03,109.47
+INV_PWR_SRC on TOP (solid shape): 223.57,177.16 223.57,176.49 223.99,176.07 224.97,176.07 225.1,175.94 225.1,173.93 224.83,173.67 223.49,173.67 223.29,173.47 221.92,173.47 221.75,173.64 221.75,177.24 221.97,177.47 223.26,177.47
+INV_PWR_SRC on BOTTOM (solid shape): 224.76,175.21 224.76,173.43 224.12,172.79 223.42,172.79 223.29,172.92 223.29,175.27 223.55,175.52 224.44,175.52
+LAN_IO on TOP (solid shape): outline of 182 points within 34.29,79.75 45.12,84.08
+LAN_IO on BOTTOM (solid shape): 51.72,85.99 51.72,84.02 50.64,82.94 49.11,82.94 48.99,83.07 48.99,83.51 49.05,83.58 49.75,83.58 50.64,84.47 50.64,85.61 49.37,86.88 45.98,86.88 45.8,86.7 45.8,85.54 45.3,85.54 45.29,85.55 45.26,85.52 45.26,85.08 45.3,85.04 45.81,85.04 45.82,85.02 45.82,84.78 45.79,84.76 45.49,84.76 45.37,84.63 45.37,82.31 45.11,82.05 41.88,82.05 40.8,83.13 39.46,83.13 39.4,83.2 39.4,83.32 39.46,83.39 41.49,83.39 41.62,83.26 42.45,83.26 42.64,83.45 42.64,84.08 42.7,84.15 44.16,84.15 44.42,84.41 44.42,87.13 45.3,88.02 49.69,88.02
+LAN_VDD on BOTTOM (solid shape): 34.78,88.55 36.15,88.55 36.3,88.4 36.3,87.05 36,86.75 36,85.94 36.12,85.82 36.12,85.64 36.01,85.53 34.05,85.53 33.83,85.75 33.83,88.8 33.91,88.88 34.46,88.88
+LAN_VDD on IN2 (solid shape): 36.29,87.13 36.29,85.99 36.16,85.86 35.46,85.86 35.27,86.05 35.27,87.01 35.53,87.26 36.16,87.26
+LAN_VDD on IN2 (solid shape): 36.35,81.86 36.35,80.85 36.16,80.66 35.72,80.66 35.27,81.1 35.27,81.93 35.46,82.12 36.1,82.12
+LCDVDD on TOP (solid shape): 215.99,169.43 215.99,167.52 215.9,167.43 212.91,167.43 212.69,167.65 212.69,169.56 212.88,169.75 215.67,169.75
+LCDVDD on BOTTOM (solid shape): 215.42,169.81 215.42,167.27 215.29,167.14 214.6,167.14 214.34,167.4 213.01,167.4 212.63,167.78 212.63,169.81 212.75,169.94 215.29,169.94
+LCDVDD_CONN on BOTTOM (solid shape): 216.63,174 216.63,172.35 217.14,171.84 217.14,170.38 216.82,170.06 212.88,170.06 212.82,170.13 212.82,170.64 212.88,170.7 213.58,170.7 213.77,170.89 213.77,171.71 213.96,171.9 215.27,171.9 215.36,172 215.88,172.52 215.88,173.45 215.86,173.58 215.8,173.7 215.8,174.06 215.87,174.13 216.5,174.13
+MPV18 on TOP (solid shape): 203.47,148.73 203.47,146.38 203.21,146.13 203.21,144.67 203.02,144.48 201.88,144.48 201.44,144.92 201.44,148.42 201.88,148.86 203.34,148.86
+MPV18 on IN1 (solid shape): outline of 127 points within 188.93,127.78 192.35,129.18
+PCIE_VDDR on TOP (solid shape): 157.36,114.07 157.36,113.28 157.86,112.78 157.86,112.31 157.72,112.17 153.1,112.17 152.91,112.36 152.91,113.36 153.11,113.57 153.75,113.57 153.98,113.8 153.98,114.44 154.04,114.51 156.92,114.51
+PCIE_VDDR on BOTTOM (solid shape): 171.19,120.67 171.19,119.65 171.15,119.61 171.11,119.59 171.08,119.6 170.61,119.58 170.52,119.11 170.53,119.09 170.31,118.86 170.37,118.54 170.37,117.76 170.34,117.72 170.32,117.68 169.97,117.33 168.04,117.33 167.96,117.37 167.94,117.45 167.83,117.72 167.53,117.74 167.52,117.73 167.49,117.74 167.46,117.77 167.46,117.97 167.53,118.18 167.46,118.39 167.46,118.68 167.73,118.95 168.26,118.95 168.5,118.71 168.5,118.69 168.72,118.43 169.05,118.45 169.28,118.45 169.42,118.37 169.59,118.35 169.97,118.57 169.86,119.01 169.85,119.03 169.84,119.05 169.84,119.46 169.85,119.48 169.86,119.5 169.98,119.72 169.93,119.97 169.92,119.98 169.93,120.02 170.01,120.09 170.02,120.11 170.04,120.11 170.33,120.22 170.44,120.51 170.63,120.72 170.79,120.72 170.92,120.77 170.93,120.78 171.08,120.78
+PCIE_VDDR on IN2 (solid shape): outline of 524 points within 155.07,112.96 170.72,121.55
+RTCVCC on BOTTOM (solid shape): 138.9,97.32 138.9,92.97 138.75,92.82 137.89,92.82 137.7,93.01 137.7,96.53 137.32,96.91 133.76,96.91 133.57,97.1 131.98,97.1 131.98,97.74 132.17,97.93 133.32,97.93 133.63,98.25 133.63,98.98 133.76,99.1 137.12,99.1
+SWR_V12 on TOP (solid shape): 200.92,164.81 200.92,161.76 200.69,161.53 199.16,161.53 199.08,161.62 199.08,162.09 199.1,162.11 199.56,162.11 199.71,162.27 199.71,162.81 199.55,162.97 198.35,162.97 198.24,163.07 198.24,164 198.25,164.03 198.25,164.35 198.39,164.49 199.69,164.49 200.04,164.84 200.88,164.84
+SWR_V12 on IN1: 202.9,166.52 203.23,166.17 203.26,166.15 203.27,166.11 203.27,163.59 202.41,162.72 199.8,162.72 199.71,162.81 199.71,165.67 200.68,166.64 200.68,167.23 199.92,167.99 199.92,169.99 199.97,170.08 200.07,170.08 200.55,170.21 200.45,170.68 200.4,170.75 200.42,170.82 200.41,171.22 200.05,171.37 199.96,171.39 199.92,171.46 199.92,173.87 200.63,174.57 202.72,174.57 203.1,174.95 203.1,175.69 203.55,176.14 204.24,176.14 204.98,175.4 205.01,175.3 204.94,175.23 204.88,175.2 204.83,175.17 204.76,175.14 204.7,175.17 204.12,174.89 204.7,174.62 204.76,174.64 204.83,174.62 205.19,174.56 205.41,174.85 205.44,174.89 205.48,174.89 205.5,174.88 206.33,174.05 206.33,170.96 203.27,167.91 203.27,166.93 203.26,166.89 203.23,166.87
+VCHGR on TOP (solid shape): 147.16,183.72 147.16,179.08 146.84,178.76 145.76,178.76 143.09,181.43 143.09,182.38 143.48,182.76 145.06,182.76 145.57,183.27 145.76,183.27 146.33,183.84 147.03,183.84
+VCHGR on BOTTOM (solid shape): 145.95,182.95 145.95,182.26 146.27,181.94 148.17,181.94 148.43,181.68 148.43,178.45 148.3,178.32 145.63,178.32 145.13,178.83 145.13,179.46 145,179.59 144.24,179.59 144.17,179.65 144.17,181.3 143.98,181.49 143.54,181.49 143.22,181.18 143.22,179.65 142.97,179.4 142.46,179.4 142.33,179.53 142.33,182.32 142.74,182.73 145.03,182.73 145.44,183.14 145.76,183.14
+VCHGR on IN1 (solid shape): 147.16,183.72 147.16,179.08 146.84,178.76 145.76,178.76 143.09,181.43 143.09,182.38 143.48,182.76 145.06,182.76 145.57,183.27 145.76,183.27 146.33,183.84 147.03,183.84
+VCHGR on IN2 (solid shape): 147.16,183.72 147.16,179.08 146.84,178.76 145.76,178.76 143.09,181.43 143.09,182.38 143.48,182.76 145.06,182.76 145.57,183.27 145.76,183.27 146.33,183.84 147.03,183.84
+VCHGR on IN3 (solid shape): 147.16,183.72 147.16,179.08 146.84,178.76 145.76,178.76 143.09,181.43 143.09,182.38 143.48,182.76 145.06,182.76 145.57,183.27 145.76,183.27 146.33,183.84 147.03,183.84
+VDISPLAY_VCC on BOTTOM (solid shape): 15.71,109.1 15.71,107.14 15.59,107.01 13.3,107.01 12.98,107.33 12.98,109.57 13.34,109.93 14.89,109.93
+VDISPLAY_VCC on IN3 (solid shape): 13.62,109.48 13.62,107.89 12.97,107.24 9.39,107.24 9.17,107.45 9.17,108.98 9.87,109.68 13.43,109.68
+VGA_CORE on TOP (solid shape): 163.48,133.29 163.48,128.03 164.24,127.26 164.24,125.87 163.83,125.45 161.22,125.45 160.49,126.18 159.28,126.18 159,126.46 159,134.15 159.35,134.5 162.27,134.5
+VGA_CORE on TOP (solid shape): 200.78,89.08 207.93,89.08 208.67,88.34 208.69,88.34 208.69,83.01 207.86,82.18 195.48,82.18 194.4,81.1 189.77,81.1 188.94,81.93 188.94,88.82 189.96,89.83 200.02,89.83
+VGA_CORE on TOP (solid shape): outline of 1073 points within 171.87,112.12 183.13,124.72
+VGA_CORE on BOTTOM (solid shape): 201.59,89.21 210.74,89.21 212.82,87.13 213.41,87.13 213.66,86.89 213.66,83.83 210.38,83.83 208.63,82.08 199.16,82.08 198.47,81.4 190.17,81.4 188.94,82.62 188.94,87.13 191.35,89.55 201.26,89.55
+VGA_CORE on IN1 (solid shape): outline of 3192 points within 158.28,111.89 183.65,131.51
+VGA_CORE on IN3 (solid shape): 201.26,89.23 209.77,89.23 211.1,87.89 211.1,82.75 210.16,81.81 190.09,81.81 189,82.89 189,88.21 191.23,90.43 200.05,90.43
+VGA_CORE on IN3 (solid shape): outline of 1021 points within 172.62,113.01 183.77,124.39
+VGA_CORE on VCC: 184.16,77.86 171.8,90.22 171.86,121.93 171.92,121.99 181.72,121.99 182.08,121.63 182.08,113.06 183.31,111.83 185.85,111.83 189,108.68 189,104.87 193.22,100.66 209.83,100.66 209.83,84.06 203.63,77.86
+VGA_PCIE on TOP (solid shape): 197.35,78.18 197.35,76.3 197.07,76.02 194.59,76.02 194.34,75.77 192.88,75.77 192.75,75.89 192.75,78.4 192.94,78.59 196.94,78.59
+VGA_PCIE on BOTTOM (solid shape): outline of 123 points within 169.81,121.28 172.91,130.12
+VGA_PCIE on IN2 (solid shape): outline of 3103 points within 169.83,75 195.16,129.01
+VGA_PCIE on IN3 (solid shape): outline of 373 points within 161.86,121.05 172.2,125.11
+VGA_PCIEP on TOP (solid shape): 194.97,75.32 195.04,75.26 196.43,75.26 196.5,75.32 196.5,75.75 196.56,75.82 199.8,75.82 200.06,75.55 200.06,72.6 199.8,72.34 193.07,72.34 192.85,72.56 192.85,75.36 193.07,75.58 194.48,75.58 194.72,75.82 194.97,75.82
+VGA_PCIEP on BOTTOM (solid shape): 198.91,75.39 198.91,73.1 198.91,73.1 198.91,72.46 198.78,72.34 193.2,72.34 193.01,72.53 193.01,75.07 193.51,75.58 198.72,75.58
ADPIN on TOP (solid shape): 140.29,178.23 140.29,177.58 139.39,176.68 139.39,171.87 139.13,171.61 137.44,171.61 136.36,172.68 136.36,178.06 136.93,178.64 139.88,178.64
ADPIN on BOTTOM (solid shape): 141.19,180.03 141.19,174.25 141.19,174.25 141.19,173.24 138.64,170.7 138.64,170.39 138.19,169.94 135.87,169.94 135.62,170.19 135.62,173.07 136.11,173.56 137.76,173.56 138.33,174.13 138.33,177.75 138.71,178.13 138.71,179.4 139.6,180.29 140.94,180.29
B+ on TOP (solid shape): 136.87,161.36 136.87,156.79 136.55,156.47 134.33,156.47 133.76,157.05 133.76,161.68 134.08,162 136.24,162
B+ on TOP (solid shape): 176.24,180.92 176.24,179.08 175.99,178.83 166.34,178.83 165.95,179.21 165.95,180.03 166.14,180.22 166.97,180.22 168.11,181.37 175.8,181.37
B+ on TOP (solid shape): 229.07,128.92 229.07,125.04 228.82,124.79 225.39,124.79 224.82,125.36 224.82,128.92 225.07,129.17 228.82,129.17
B+ on TOP (solid shape): 146.52,176.86 146.52,172.67 144.3,170.44 144.3,168.29 143.98,167.97 140.62,167.97 140.17,168.41 140.17,176.25 141.1,177.18 146.21,177.18
B+ on TOP (solid shape): 220.24,176.42 220.24,176.05 221.45,174.84 221.45,173.61 221.33,173.49 220.95,173.49 220.14,174.3 220.14,174.86 219.62,175.38 218.78,175.38 218.53,175.64 218.53,176.45 218.69,176.6 220.05,176.6
B+ on BOTTOM (solid shape): 136.74,35.06 136.74,31.95 135.47,30.68 126.14,30.68 126.08,30.74 126.08,34.63 126.88,35.44 136.37,35.44
B+ on BOTTOM (solid shape): 137.13,160.03 137.13,149.87 137,149.74 133.76,149.74 133.19,150.32 133.19,159.65 133.95,160.41 136.74,160.41
B+ on BOTTOM (solid shape): 196.05,176.79 196.05,171.14 195.74,170.83 192.18,170.83 191.42,171.59 191.42,173.75 191.86,174.19 191.86,175.97 192.69,176.79 192.69,177.62 192.88,177.81 195.04,177.81
B+ on BOTTOM (solid shape): 229.13,133.81 229.13,124.59 228.02,123.47 223.49,123.47 223.32,123.64 223.32,133.58 223.87,134.12 228.82,134.12
B+ on BOTTOM (solid shape): 219.8,85.61 219.8,83.13 219.1,82.43 217.2,82.43 216.48,83.15 216.48,85.56 215.99,86.05 215.99,87.07 215.61,87.45 215.61,87.83 216.12,88.34 217.07,88.34
B+ on BOTTOM (solid shape): 168.59,24.55 168.59,22.65 170.91,20.33 170.91,19.63 169.57,18.3 168.56,18.3 167.64,19.22 164.34,19.22 163.48,20.08 163.48,21.03 165.51,23.06 165.51,24.65 165.83,24.97 168.18,24.97
B+ on BOTTOM (solid shape): 143.28,178.51 143.28,176.99 143.48,176.79 143.92,176.79 144.24,177.11 144.24,178.57 144.94,178.57 145.57,177.94 147.54,177.94 148.05,177.43 148.05,170.64 147.86,170.44 142.97,170.44 142.71,170.7 142.71,172.1 142.08,172.73 142.08,178 142.71,178.64 143.16,178.64
B+ on BOTTOM (solid shape): 172.4,181.24 172.4,177.02 171.86,176.48 164.81,176.48 164.11,177.18 164.11,179.46 164.49,179.84 165.19,179.84 165.36,180.01 165.38,180.01 167.13,180.73 168.54,182 171.64,182
B+ on IN1 (solid shape): 144.33,176.64 144.33,170.48 143.73,169.87 141.32,169.87 140.68,170.51 140.68,176.48 141.38,177.18 143.79,177.18
B+ on IN1 (solid shape): 219.05,88.9 219.05,87.77 216.83,85.55 216.63,85.55 214.65,87.52 214.65,87.9 216.91,90.16 217.8,90.16
B+ on IN1 (solid shape): 228.95,128.98 228.95,125.42 227.89,124.37 225.81,124.37 224.82,125.36 224.82,125.37 224.22,125.98 224.22,126.36 227.02,129.17 228.76,129.17
B+ on IN1 (solid shape): outline of 443 points within 166.11,174.27 220.88,183.69
B+ on IN2 (solid shape): 144.33,176.64 144.33,170.48 143.73,169.87 141.32,169.87 140.68,170.51 140.68,176.48 141.38,177.18 143.79,177.18
B+ on IN3 (solid shape): 146.21,177.11 146.21,172.67 144.05,170.51 142.84,170.51 142.08,171.27 142.08,176.99 142.84,177.75 145.57,177.75
B+ on IN3 (solid shape): 168.88,179.84 168.88,178.26 168.3,177.68 163.6,177.68 163.03,178.26 163.03,179.97 163.48,180.41 168.3,180.41
B+ on TOP: 218.14,84.63 218.14,76.19 217.99,76.03 215.48,76.03 215.08,76.44 215.08,87.88 216.49,89.29 220.42,89.29 221.15,88.57 221.15,87.64
B+_1.05V on BOTTOM (solid shape): 141.96,159.14 141.96,157.8 142.21,157.55 143.8,157.55 143.93,157.42 143.93,156.83 144.61,156.15 144.61,155.23 142.55,155.23 142.01,154.7 138.4,154.7 137.82,155.27 137.82,159.9 138.14,160.22 140.87,160.22
B+_VDDCI on BOTTOM (solid shape): 176.81,182.57 178.59,182.57 178.65,182.51 178.65,180.22 178.34,179.91 178.34,176.86 178.21,176.73 175.03,176.73 174.72,177.05 174.72,180.48 175.48,181.24 175.48,182.89 175.61,183.02 176.37,183.02
BATT+ on BOTTOM (solid shape): 154.4,181.87 156.75,181.87 157.13,181.49 158.21,181.49 158.4,181.3 158.4,180.16 157,178.76 155.54,178.76 154.97,178.19 151.41,178.19 151.03,178.57 151.03,182.89 151.29,183.14 153.13,183.14
BATT++ on TOP (solid shape): 157.19,188.99 157.19,186.76 157.92,186.03 157.92,183.87 157.79,183.75 153.98,183.75 152.81,184.92 152.81,188.99 153.25,189.43 156.75,189.43
BATT++ on BOTTOM (solid shape): 157.19,188.99 157.19,186.76 158.46,185.49 158.46,181.87 158.4,181.81 157.32,181.81 156.49,182.64 154.4,182.64 152.81,184.22 152.81,188.99 153.25,189.43 156.75,189.43
BATT++ on IN1 (solid shape): 157.19,188.99 157.19,186.76 157.92,186.03 157.92,183.87 157.79,183.75 153.98,183.75 152.81,184.92 152.81,188.99 153.25,189.43 156.75,189.43
BATT++ on IN2 (solid shape): 157.19,188.99 157.19,186.76 157.92,186.03 157.92,183.87 157.79,183.75 153.98,183.75 152.81,184.92 152.81,188.99 153.25,189.43 156.75,189.43
BATT++ on IN3 (solid shape): 157.19,188.99 157.19,186.76 157.92,186.03 157.92,183.87 157.79,183.75 153.98,183.75 152.81,184.92 152.81,188.99 153.25,189.43 156.75,189.43
BOOT_1.35V on BOTTOM (solid shape): 157.38,24.9 157.38,24.79 157.32,24.72 155.99,24.72 155.29,24.03 154.4,24.03 154.33,24.1 154.33,24.72 154.4,24.79 155.67,24.79 155.86,24.98 157.31,24.98
BST on TOP (solid shape): 165.64,170.06 166.72,170.06 166.78,170 166.78,169.87 166.72,169.81 165.57,169.81 165.45,169.68 164.43,169.68 164.3,169.56 164.3,169.11 164.24,169.05 163.6,169.05 163.54,169.11 163.54,170.06 163.73,170.25 165.45,170.25
BST_1.05V on BOTTOM (solid shape): 147.35,157.25 147.35,156.42 147.33,156.4 146.59,156.4 146.21,156.02 146.21,156.01 145.96,155.76 145.41,155.76 145.34,155.83 145.34,156.31 145.44,156.42 145.91,156.42 146.4,156.91 146.4,157.16 146.53,157.29 147.31,157.29
BST_1.35V on BOTTOM (solid shape): 155.36,23.26 155.36,21.29 155.29,21.22 154.4,21.22 154.34,21.28 154.34,23.26 154.4,23.33 155.29,23.33
BST_+1.2VSP on TOP (solid shape): 185.7,171.33 185.7,171.21 185.48,170.98 185.48,168.76 185.39,168.67 184.81,168.67 184.75,168.73 184.75,171.21 184.94,171.4 185.64,171.4
BST_CHGA on TOP (solid shape): 163.03,171.4 163.03,168.03 162.84,167.84 162.14,167.84 162.08,167.9 162.08,171.46 162.14,171.52 162.91,171.52
BST_VDDCI on BOTTOM (solid shape): 177.51,185.43 177.51,184.61 178.15,183.97 178.15,183.27 178.08,183.21 177.96,183.21 177.89,183.27 177.89,183.72 177,184.61 176.69,184.61 176.5,184.8 176.5,185.43 176.56,185.49 177.45,185.49
BST_VGA_CORE on BOTTOM (solid shape): 201.9,60.34 201.9,60.27 203.32,58.84 203.77,58.84 203.93,58.68 203.93,58.56 203.86,58.49 202.97,58.49 202.88,58.59 202.88,58.72 202.56,59.03 202.18,59.03 201.7,59.51 201.13,59.51 200.88,59.76 200.88,60.4 200.94,60.46 201.77,60.46
CHG_B+ on TOP (solid shape): 158.21,169.11 158.21,162 157.64,161.43 147.34,161.43 145.61,163.16 145.61,167.62 145.89,167.9 156.68,167.9 157.25,168.48 157.25,168.92 157.57,169.24 158.08,169.24
CHG_B+ on BOTTOM (solid shape): 158.72,164.67 158.72,162.38 157.76,161.43 149.44,161.43 148.81,162.06 148.81,164.86 149.19,165.24 158.14,165.24
DH_1.35V on TOP (solid shape): 154.02,19.52 154.02,18.31 153.83,18.12 153.07,18.12 152.82,18.37 152.82,19.71 152.94,19.84 153.71,19.84
DH_1.35V on TOP (solid shape): 156.37,24.34 156.37,24.09 155.17,22.88 154.85,22.88 154.34,23.39 154.34,23.65 155.23,24.53 156.18,24.53
DH_1.35V on BOTTOM (solid shape): 155.23,18.63 155.23,18.25 155.04,18.06 153.01,18.06 152.82,18.25 152.82,18.57 153.07,18.82 155.04,18.82
DH_1.35V on BOTTOM (solid shape): 156.61,24.6 157.32,24.6 157.39,24.53 157.39,24.39 157.34,24.34 156.56,24.34 155.99,23.77 155.99,23.65 155.86,23.52 155.61,23.52 155.48,23.65 155.48,23.96 156.12,24.6 156.6,24.6
DH_CHG on TOP (solid shape): 146.36,169.68 146.36,168.86 146.11,168.6 145.16,168.6 144.9,168.86 144.9,169.81 145.09,170 146.05,170
